<?xml version="1.0" encoding="utf-8"?>
<device xmlns:xs="http://www.w3.org/2001/XMLSchema-instance" schemaVersion="1.3" xs:noNamespaceSchemaLocation="CMSIS-SVD.xsd">
    <vendor>Renesas Electronics Corporation</vendor>
    <vendorID>Renesas</vendorID>
    <name>R7FA8D1BH</name>
    <series>RA8</series>
    <version>1.20.02</version>
    <description>Arm Cortex-M85 based Microcontroller RA8M1group</description>
    <licenseText>This software is supplied by Renesas Electronics Corporation and is only intended for \n
use with Renesas products. No other uses are authorized. This software is owned by \n
Renesas Electronics Corporation and is protected under all applicable laws, including \n
copyright laws. \n
\n
THIS SOFTWARE IS PROVIDED "AS IS" AND RENESAS MAKES NO WARRANTIES REGARDING \n
THIS SOFTWARE, WHETHER EXPRESS, IMPLIED OR STATUTORY, INCLUDING BUT NOT LIMITED TO \n
WARRANTIES OF MERCHANTABILITY, FITNESS FOR A PARTICULAR PURPOSE AND NON-INFRINGEMENT. \n
ALL SUCH WARRANTIES ARE EXPRESSLY DISCLAIMED. TO THE MAXIMUM EXTENT PERMITTED NOT \n
PROHIBITED BY LAW, NEITHER RENESAS ELECTRONICS CORPORATION NOR ANY OF ITS AFFILIATED \n
COMPANIES SHALL BE LIABLE FOR ANY DIRECT, INDIRECT, SPECIAL, INCIDENTAL OR CONSEQUENTIAL \n
DAMAGES FOR ANY REASON RELATED TO THIS SOFTWARE, EVEN IF RENESAS OR ITS AFFILIATES HAVE \n
BEEN ADVISED OF THE POSSIBILITY OF SUCH DAMAGES. \n
\n
Renesas reserves the right, without notice, to make changes to this software and to \n
discontinue the availability of this software. By using this software, you agree to \n
the additional terms and conditions found by accessing the following link: \n
http://www.renesas.com/disclaimer \n
\n</licenseText>
    <cpu>
        <name>CM85</name>
        <revision>r0p2</revision>
        <endian>little</endian>
        <mpuPresent>true</mpuPresent>
        <fpuPresent>true</fpuPresent>
        <vtorPresent>true</vtorPresent>
        <nvicPrioBits>4</nvicPrioBits>
        <vendorSystickConfig>false</vendorSystickConfig>
        <deviceNumInterrupts>96</deviceNumInterrupts>
    </cpu>
    <headerSystemFilename>system_RA8</headerSystemFilename>
    <addressUnitBits>8</addressUnitBits>
    <width>32</width>
    <size>32</size>
    <access>read-write</access>
    <resetValue>0</resetValue>
    <resetMask>0xffffffff</resetMask>
    <peripherals>
        <peripheral>
            <name>RMPU</name>
            <description>Renesas Memory Protection Unit</description>
            <baseAddress>0x40000000</baseAddress>
            <addressBlock>
                <offset>0x00</offset>
                <size>2</size>
                <usage>registers</usage>
            </addressBlock>
            <addressBlock>
                <offset>0x04</offset>
                <size>2</size>
                <usage>registers</usage>
            </addressBlock>
            <addressBlock>
                <offset>0x100</offset>
                <size>2</size>
                <usage>registers</usage>
            </addressBlock>
            <addressBlock>
                <offset>0x104</offset>
                <size>2</size>
                <usage>registers</usage>
            </addressBlock>
            <addressBlock>
                <offset>0x10C</offset>
                <size>2</size>
                <usage>registers</usage>
            </addressBlock>
            <addressBlock>
                <offset>0x200</offset>
                <size>136</size>
                <usage>registers</usage>
            </addressBlock>
            <addressBlock>
                <offset>0x500</offset>
                <size>2</size>
                <usage>registers</usage>
            </addressBlock>
            <addressBlock>
                <offset>0x504</offset>
                <size>2</size>
                <usage>registers</usage>
            </addressBlock>
            <addressBlock>
                <offset>0x508</offset>
                <size>2</size>
                <usage>registers</usage>
            </addressBlock>
            <addressBlock>
                <offset>0x600</offset>
                <size>72</size>
                <usage>registers</usage>
            </addressBlock>
            <addressBlock>
                <offset>0x700</offset>
                <size>2</size>
                <usage>registers</usage>
            </addressBlock>
            <addressBlock>
                <offset>0x704</offset>
                <size>2</size>
                <usage>registers</usage>
            </addressBlock>
            <addressBlock>
                <offset>0x708</offset>
                <size>2</size>
                <usage>registers</usage>
            </addressBlock>
            <addressBlock>
                <offset>0x800</offset>
                <size>40</size>
                <usage>registers</usage>
            </addressBlock>
            <addressBlock>
                <offset>0x900</offset>
                <size>2</size>
                <usage>registers</usage>
            </addressBlock>
            <addressBlock>
                <offset>0x904</offset>
                <size>2</size>
                <usage>registers</usage>
            </addressBlock>
            <addressBlock>
                <offset>0x908</offset>
                <size>2</size>
                <usage>registers</usage>
            </addressBlock>
            <addressBlock>
                <offset>0xA00</offset>
                <size>56</size>
                <usage>registers</usage>
            </addressBlock>
            <addressBlock>
                <offset>0xB00</offset>
                <size>2</size>
                <usage>registers</usage>
            </addressBlock>
            <addressBlock>
                <offset>0xB04</offset>
                <size>2</size>
                <usage>registers</usage>
            </addressBlock>
            <addressBlock>
                <offset>0xB08</offset>
                <size>2</size>
                <usage>registers</usage>
            </addressBlock>
            <addressBlock>
                <offset>0xC00</offset>
                <size>2</size>
                <usage>registers</usage>
            </addressBlock>
            <addressBlock>
                <offset>0xC04</offset>
                <size>8</size>
                <usage>registers</usage>
            </addressBlock>
            <addressBlock>
                <offset>0xD00</offset>
                <size>2</size>
                <usage>registers</usage>
            </addressBlock>
            <addressBlock>
                <offset>0xD04</offset>
                <size>2</size>
                <usage>registers</usage>
            </addressBlock>
            <addressBlock>
                <offset>0xD08</offset>
                <size>2</size>
                <usage>registers</usage>
            </addressBlock>
            <addressBlock>
                <offset>0xE00</offset>
                <size>40</size>
                <usage>registers</usage>
            </addressBlock>
            <registers>
                <register>
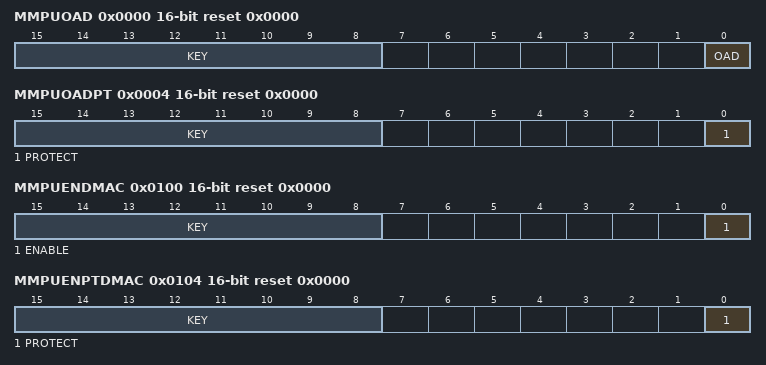
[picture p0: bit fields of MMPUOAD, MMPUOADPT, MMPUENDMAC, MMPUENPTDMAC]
                    <name>MMPUOAD</name>
                    <description>MMPU Operation After Detection Register</description>
                    <addressOffset>0x0000</addressOffset>
                    <size>16</size>
                    <access>read-write</access>
                    <resetValue>0x0000</resetValue>
                    <resetMask>0xffff</resetMask>
                    <fields>
                        <field>
                            <name>OAD</name>
                            <description>Operation after detection</description>
                            <lsb>0</lsb>
                            <msb>0</msb>
                            <access>read-write</access>
                            <enumeratedValues>
                                <enumeratedValue>
                                    <name>0</name>
                                    <description>NMI</description>
                                    <value>#0</value>
                                </enumeratedValue>
                                <enumeratedValue>
                                    <name>1</name>
                                    <description>Reset</description>
                                    <value>#1</value>
                                </enumeratedValue>
                            </enumeratedValues>
                        </field>
                        <field>
                            <name>KEY</name>
                            <description>Key Code</description>
                            <lsb>8</lsb>
                            <msb>15</msb>
                            <access>read-write</access>
                        </field>
                    </fields>
                </register>
                <register>
                    <name>MMPUOADPT</name>
                    <description>MMPU Operation After Detection Protect Register</description>
                    <addressOffset>0x0004</addressOffset>
                    <size>16</size>
                    <access>read-write</access>
                    <resetValue>0x0000</resetValue>
                    <resetMask>0xffff</resetMask>
                    <fields>
                        <field>
                            <name>PROTECT</name>
                            <description>Protection of register</description>
                            <lsb>0</lsb>
                            <msb>0</msb>
                            <access>read-write</access>
                            <enumeratedValues>
                                <enumeratedValue>
                                    <name>0</name>
                                    <description>MMPUOAD register writing is possible.</description>
                                    <value>#0</value>
                                </enumeratedValue>
                                <enumeratedValue>
                                    <name>1</name>
                                    <description>MMPUOAD register writing is protected. Read is possible.</description>
                                    <value>#1</value>
                                </enumeratedValue>
                            </enumeratedValues>
                        </field>
                        <field>
                            <name>KEY</name>
                            <description>Key Code</description>
                            <lsb>8</lsb>
                            <msb>15</msb>
                            <access>write-only</access>
                        </field>
                    </fields>
                </register>
                <register>
                    <name>MMPUENDMAC</name>
                    <description>MMPU Enable Register for DMAC</description>
                    <addressOffset>0x0100</addressOffset>
                    <size>16</size>
                    <access>read-write</access>
                    <resetValue>0x0000</resetValue>
                    <resetMask>0xffff</resetMask>
                    <fields>
                        <field>
                            <name>ENABLE</name>
                            <description>Bus master MPU of DMAC Enable</description>
                            <lsb>0</lsb>
                            <msb>0</msb>
                            <access>read-write</access>
                            <enumeratedValues>
                                <enumeratedValue>
                                    <name>0</name>
                                    <description>Bus master MPU of DMAC is disabled.</description>
                                    <value>#0</value>
                                </enumeratedValue>
                                <enumeratedValue>
                                    <name>1</name>
                                    <description>Bus master MPU of DMAC is enabled.</description>
                                    <value>#1</value>
                                </enumeratedValue>
                            </enumeratedValues>
                        </field>
                        <field>
                            <name>KEY</name>
                            <description>Key Code</description>
                            <lsb>8</lsb>
                            <msb>15</msb>
                            <access>write-only</access>
                        </field>
                    </fields>
                </register>
                <register>
                    <name>MMPUENPTDMAC</name>
                    <description>MMPU Enable Protect Register for DMAC</description>
                    <addressOffset>0x0104</addressOffset>
                    <size>16</size>
                    <access>read-write</access>
                    <resetValue>0x0000</resetValue>
                    <resetMask>0xffff</resetMask>
                    <fields>
                        <field>
                            <name>PROTECT</name>
                            <description>Protection of register</description>
                            <lsb>0</lsb>
                            <msb>0</msb>
                            <access>read-write</access>
                            <enumeratedValues>
                                <enumeratedValue>
                                    <name>0</name>
                                    <description>MMPUENDMAC register write is possible.</description>
                                    <value>#0</value>
                                </enumeratedValue>
                                <enumeratedValue>
                                    <name>1</name>
                                    <description>MMPUENDMAC register write is protected. Read is possible.</description>
                                    <value>#1</value>
                                </enumeratedValue>
                            </enumeratedValues>
                        </field>
                        <field>
                            <name>KEY</name>
                            <description>Key Code</description>
                            <lsb>8</lsb>
                            <msb>15</msb>
                            <access>write-only</access>
                        </field>
                    </fields>
                </register>
                <register>
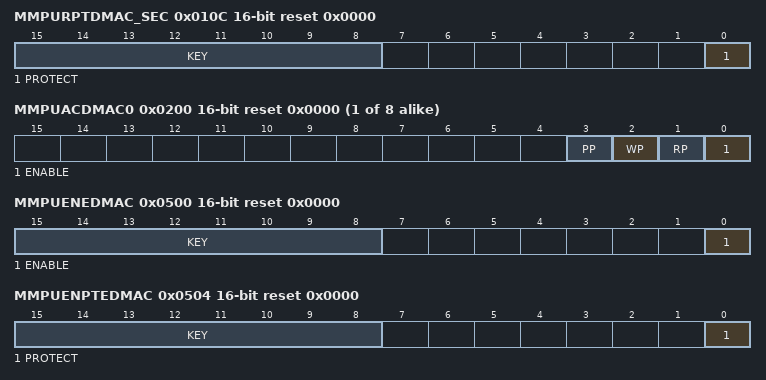
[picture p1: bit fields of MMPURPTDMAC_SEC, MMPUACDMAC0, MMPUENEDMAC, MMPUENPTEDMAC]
                    <name>MMPURPTDMAC_SEC</name>
                    <description>MMPU Regions Protect register for DMAC Secure</description>
                    <addressOffset>0x010C</addressOffset>
                    <size>16</size>
                    <access>read-write</access>
                    <resetValue>0x0000</resetValue>
                    <resetMask>0xffff</resetMask>
                    <fields>
                        <field>
                            <name>PROTECT</name>
                            <description>Protection of register</description>
                            <lsb>0</lsb>
                            <msb>0</msb>
                            <access>read-write</access>
                            <enumeratedValues>
                                <enumeratedValue>
                                    <name>0</name>
                                    <description>Bus master MPU register for DMAC Secure write is possible.</description>
                                    <value>#0</value>
                                </enumeratedValue>
                                <enumeratedValue>
                                    <name>1</name>
                                    <description>Bus master MPU register for DMAC Secure write is protected. Read is possible.</description>
                                    <value>#1</value>
                                </enumeratedValue>
                            </enumeratedValues>
                        </field>
                        <field>
                            <name>KEY</name>
                            <description>Key Code</description>
                            <lsb>8</lsb>
                            <msb>15</msb>
                            <access>write-only</access>
                        </field>
                    </fields>
                </register>
                <register>
                    <dim>8</dim>
                    <dimIncrement>0x010</dimIncrement>
                    <dimIndex>0-7</dimIndex>
                    <name>MMPUACDMAC%s</name>
                    <description>MMPU Access Control Register for DMAC (n = 0 to 7)</description>
                    <addressOffset>0x0200</addressOffset>
                    <size>16</size>
                    <access>read-write</access>
                    <resetValue>0x0000</resetValue>
                    <resetMask>0xffff</resetMask>
                    <fields>
                        <field>
                            <name>ENABLE</name>
                            <description>Region Enable</description>
                            <lsb>0</lsb>
                            <msb>0</msb>
                            <access>read-write</access>
                            <enumeratedValues>
                                <enumeratedValue>
                                    <name>0</name>
                                    <description>DMAC region n unit is disabled.</description>
                                    <value>#0</value>
                                </enumeratedValue>
                                <enumeratedValue>
                                    <name>1</name>
                                    <description>DMAC region n unit is enabled.</description>
                                    <value>#1</value>
                                </enumeratedValue>
                            </enumeratedValues>
                        </field>
                        <field>
                            <name>RP</name>
                            <description>Read protection</description>
                            <lsb>1</lsb>
                            <msb>1</msb>
                            <access>read-write</access>
                            <enumeratedValues>
                                <enumeratedValue>
                                    <name>0</name>
                                    <description>Read permission</description>
                                    <value>#0</value>
                                </enumeratedValue>
                                <enumeratedValue>
                                    <name>1</name>
                                    <description>Read protection</description>
                                    <value>#1</value>
                                </enumeratedValue>
                            </enumeratedValues>
                        </field>
                        <field>
                            <name>WP</name>
                            <description>Write protection</description>
                            <lsb>2</lsb>
                            <msb>2</msb>
                            <access>read-write</access>
                            <enumeratedValues>
                                <enumeratedValue>
                                    <name>0</name>
                                    <description>Write permission</description>
                                    <value>#0</value>
                                </enumeratedValue>
                                <enumeratedValue>
                                    <name>1</name>
                                    <description>Write protection</description>
                                    <value>#1</value>
                                </enumeratedValue>
                            </enumeratedValues>
                        </field>
                        <field>
                            <name>PP</name>
                            <description>Privilege protection</description>
                            <lsb>3</lsb>
                            <msb>3</msb>
                            <access>read-write</access>
                            <enumeratedValues>
                                <enumeratedValue>
                                    <name>0</name>
                                    <description>Unprivileged access permission</description>
                                    <value>#0</value>
                                </enumeratedValue>
                                <enumeratedValue>
                                    <name>1</name>
                                    <description>Unprivileged access protection</description>
                                    <value>#1</value>
                                </enumeratedValue>
                            </enumeratedValues>
                        </field>
                    </fields>
                </register>
                <register>
                    <dim>8</dim>
                    <dimIncrement>0x010</dimIncrement>
                    <dimIndex>0-7</dimIndex>
                    <name>MMPUSDMAC%s</name>
                    <description>MMPU Start Address Register for DMAC (n = 0 to 7)</description>
                    <addressOffset>0x0204</addressOffset>
                    <size>32</size>
                    <access>read-write</access>
                    <resetValue>0x00000000</resetValue>
                    <resetMask>0x0000001f</resetMask>
                </register>
                <register>
                    <dim>8</dim>
                    <dimIncrement>0x010</dimIncrement>
                    <dimIndex>0-7</dimIndex>
                    <name>MMPUEDMAC%s</name>
                    <description>MMPU End Address Register for DMAC (n = 0 to 7)</description>
                    <addressOffset>0x0208</addressOffset>
                    <size>32</size>
                    <access>read-write</access>
                    <resetValue>0x0000001f</resetValue>
                    <resetMask>0x0000001f</resetMask>
                </register>
                <register>
                    <name>MMPUENEDMAC</name>
                    <description>MMPU Enable Register for EDMAC</description>
                    <addressOffset>0x0500</addressOffset>
                    <size>16</size>
                    <access>read-write</access>
                    <resetValue>0x0000</resetValue>
                    <resetMask>0xffff</resetMask>
                    <fields>
                        <field>
                            <name>ENABLE</name>
                            <description>Bus master MPU of EDMAC Enable</description>
                            <lsb>0</lsb>
                            <msb>0</msb>
                            <access>read-write</access>
                            <enumeratedValues>
                                <enumeratedValue>
                                    <name>0</name>
                                    <description>Bus master MPU of EDMAC is disabled.</description>
                                    <value>#0</value>
                                </enumeratedValue>
                                <enumeratedValue>
                                    <name>1</name>
                                    <description>Bus master MPU of EDMAC is enabled.</description>
                                    <value>#1</value>
                                </enumeratedValue>
                            </enumeratedValues>
                        </field>
                        <field>
                            <name>KEY</name>
                            <description>Key Code</description>
                            <lsb>8</lsb>
                            <msb>15</msb>
                            <access>write-only</access>
                        </field>
                    </fields>
                </register>
                <register>
                    <name>MMPUENPTEDMAC</name>
                    <description>MMPU Enable Protect Register for EDMAC</description>
                    <addressOffset>0x0504</addressOffset>
                    <size>16</size>
                    <access>read-write</access>
                    <resetValue>0x0000</resetValue>
                    <resetMask>0xffff</resetMask>
                    <fields>
                        <field>
                            <name>PROTECT</name>
                            <description>Protection of register</description>
                            <lsb>0</lsb>
                            <msb>0</msb>
                            <access>read-write</access>
                            <enumeratedValues>
                                <enumeratedValue>
                                    <name>0</name>
                                    <description>MMPUENEDMAC register write is possible.</description>
                                    <value>#0</value>
                                </enumeratedValue>
                                <enumeratedValue>
                                    <name>1</name>
                                    <description>MMPUENEDMAC register write is protected. Read is possible.</description>
                                    <value>#1</value>
                                </enumeratedValue>
                            </enumeratedValues>
                        </field>
                        <field>
                            <name>KEY</name>
                            <description>Key Code</description>
                            <lsb>8</lsb>
                            <msb>15</msb>
                            <access>write-only</access>
                        </field>
                    </fields>
                </register>
                <register>
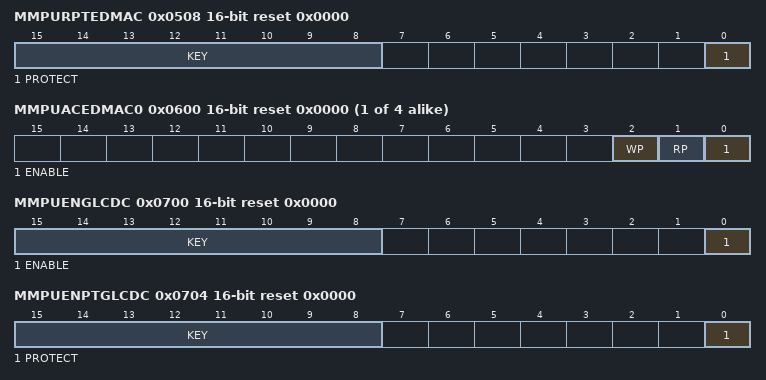
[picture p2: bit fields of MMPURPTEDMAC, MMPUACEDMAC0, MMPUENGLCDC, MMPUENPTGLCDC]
                    <name>MMPURPTEDMAC</name>
                    <description>MMPU Regions Protect Register for EDMAC</description>
                    <addressOffset>0x0508</addressOffset>
                    <size>16</size>
                    <access>read-write</access>
                    <resetValue>0x0000</resetValue>
                    <resetMask>0xffff</resetMask>
                    <fields>
                        <field>
                            <name>PROTECT</name>
                            <description>Protection of register</description>
                            <lsb>0</lsb>
                            <msb>0</msb>
                            <access>read-write</access>
                            <enumeratedValues>
                                <enumeratedValue>
                                    <name>0</name>
                                    <description>Bus master MPU register for EDMAC write is possible.</description>
                                    <value>#0</value>
                                </enumeratedValue>
                                <enumeratedValue>
                                    <name>1</name>
                                    <description>Bus master MPU register for EDMAC write is protected. Read is possible.</description>
                                    <value>#1</value>
                                </enumeratedValue>
                            </enumeratedValues>
                        </field>
                        <field>
                            <name>KEY</name>
                            <description>Key Code</description>
                            <lsb>8</lsb>
                            <msb>15</msb>
                            <access>write-only</access>
                        </field>
                    </fields>
                </register>
                <register>
                    <dim>4</dim>
                    <dimIncrement>0x010</dimIncrement>
                    <dimIndex>0-3</dimIndex>
                    <name>MMPUACEDMAC%s</name>
                    <description>MMPU Access Control Register for EDMAC (n = 0 to 3)</description>
                    <addressOffset>0x0600</addressOffset>
                    <size>16</size>
                    <access>read-write</access>
                    <resetValue>0x0000</resetValue>
                    <resetMask>0xffff</resetMask>
                    <fields>
                        <field>
                            <name>ENABLE</name>
                            <description>Region Enable</description>
                            <lsb>0</lsb>
                            <msb>0</msb>
                            <access>read-write</access>
                            <enumeratedValues>
                                <enumeratedValue>
                                    <name>0</name>
                                    <description>EDMAC region n unit is disabled.</description>
                                    <value>#0</value>
                                </enumeratedValue>
                                <enumeratedValue>
                                    <name>1</name>
                                    <description>EDMAC region n unit is enabled.</description>
                                    <value>#1</value>
                                </enumeratedValue>
                            </enumeratedValues>
                        </field>
                        <field>
                            <name>RP</name>
                            <description>Read protection</description>
                            <lsb>1</lsb>
                            <msb>1</msb>
                            <access>read-write</access>
                            <enumeratedValues>
                                <enumeratedValue>
                                    <name>0</name>
                                    <description>Read permission</description>
                                    <value>#0</value>
                                </enumeratedValue>
                                <enumeratedValue>
                                    <name>1</name>
                                    <description>Read protection</description>
                                    <value>#1</value>
                                </enumeratedValue>
                            </enumeratedValues>
                        </field>
                        <field>
                            <name>WP</name>
                            <description>Write protection</description>
                            <lsb>2</lsb>
                            <msb>2</msb>
                            <access>read-write</access>
                            <enumeratedValues>
                                <enumeratedValue>
                                    <name>0</name>
                                    <description>Write permission</description>
                                    <value>#0</value>
                                </enumeratedValue>
                                <enumeratedValue>
                                    <name>1</name>
                                    <description>Write protection</description>
                                    <value>#1</value>
                                </enumeratedValue>
                            </enumeratedValues>
                        </field>
                    </fields>
                </register>
                <register>
                    <dim>4</dim>
                    <dimIncrement>0x010</dimIncrement>
                    <dimIndex>0-3</dimIndex>
                    <name>MMPUSEDMAC%s</name>
                    <description>MMPU Start Address Register for EDMAC (n = 0 to 3)</description>
                    <addressOffset>0x0604</addressOffset>
                    <size>32</size>
                    <access>read-write</access>
                    <resetValue>0x00000000</resetValue>
                    <resetMask>0x0000001f</resetMask>
                </register>
                <register>
                    <dim>4</dim>
                    <dimIncrement>0x010</dimIncrement>
                    <dimIndex>0-3</dimIndex>
                    <name>MMPUEEDMAC%s</name>
                    <description>MMPU End Address Register for EDMAC (n = 0 to 3)</description>
                    <addressOffset>0x0608</addressOffset>
                    <size>32</size>
                    <access>read-write</access>
                    <resetValue>0x0000001f</resetValue>
                    <resetMask>0x0000001f</resetMask>
                </register>
                <register>
                    <name>MMPUENGLCDC</name>
                    <description>MMPU Enable Register for GLCDC</description>
                    <addressOffset>0x0700</addressOffset>
                    <size>16</size>
                    <access>read-write</access>
                    <resetValue>0x0000</resetValue>
                    <resetMask>0xffff</resetMask>
                    <fields>
                        <field>
                            <name>ENABLE</name>
                            <description>Bus master MPU of GLCDC Enable</description>
                            <lsb>0</lsb>
                            <msb>0</msb>
                            <access>read-write</access>
                            <enumeratedValues>
                                <enumeratedValue>
                                    <name>0</name>
                                    <description>Bus master MPU of GLCDC is disabled.</description>
                                    <value>#0</value>
                                </enumeratedValue>
                                <enumeratedValue>
                                    <name>1</name>
                                    <description>Bus master MPU of GLCDC is enabled.</description>
                                    <value>#1</value>
                                </enumeratedValue>
                            </enumeratedValues>
                        </field>
                        <field>
                            <name>KEY</name>
                            <description>Key Code</description>
                            <lsb>8</lsb>
                            <msb>15</msb>
                            <access>write-only</access>
                        </field>
                    </fields>
                </register>
                <register>
                    <name>MMPUENPTGLCDC</name>
                    <description>MMPU Enable Protect Register for GLCDC</description>
                    <addressOffset>0x0704</addressOffset>
                    <size>16</size>
                    <access>read-write</access>
                    <resetValue>0x0000</resetValue>
                    <resetMask>0xffff</resetMask>
                    <fields>
                        <field>
                            <name>PROTECT</name>
                            <description>Protection of register</description>
                            <lsb>0</lsb>
                            <msb>0</msb>
                            <access>read-write</access>
                            <enumeratedValues>
                                <enumeratedValue>
                                    <name>0</name>
                                    <description>MMPUENGLCDC register write is possible.</description>
                                    <value>#0</value>
                                </enumeratedValue>
                                <enumeratedValue>
                                    <name>1</name>
                                    <description>MMPUENGLCDC register write is protected. Read is possible.</description>
                                    <value>#1</value>
                                </enumeratedValue>
                            </enumeratedValues>
                        </field>
                        <field>
                            <name>KEY</name>
                            <description>Key Code</description>
                            <lsb>8</lsb>
                            <msb>15</msb>
                            <access>write-only</access>
                        </field>
                    </fields>
                </register>
                <register>
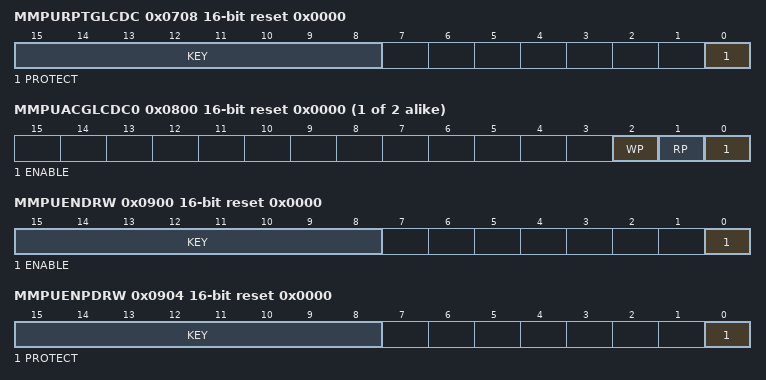
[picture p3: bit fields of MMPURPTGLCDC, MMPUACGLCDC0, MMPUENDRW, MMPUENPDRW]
                    <name>MMPURPTGLCDC</name>
                    <description>MMPU Regions Protect Register for GLCDC</description>
                    <addressOffset>0x0708</addressOffset>
                    <size>16</size>
                    <access>read-write</access>
                    <resetValue>0x0000</resetValue>
                    <resetMask>0xffff</resetMask>
                    <fields>
                        <field>
                            <name>PROTECT</name>
                            <description>Protection of register</description>
                            <lsb>0</lsb>
                            <msb>0</msb>
                            <access>read-write</access>
                            <enumeratedValues>
                                <enumeratedValue>
                                    <name>0</name>
                                    <description>Bus master MPU register for GLCDC write is possible.</description>
                                    <value>#0</value>
                                </enumeratedValue>
                                <enumeratedValue>
                                    <name>1</name>
                                    <description>Bus master MPU register for GLCDC write is protected. Read is possible.</description>
                                    <value>#1</value>
                                </enumeratedValue>
                            </enumeratedValues>
                        </field>
                        <field>
                            <name>KEY</name>
                            <description>Key Code</description>
                            <lsb>8</lsb>
                            <msb>15</msb>
                            <access>write-only</access>
                        </field>
                    </fields>
                </register>
                <register>
                    <dim>2</dim>
                    <dimIncrement>0x010</dimIncrement>
                    <dimIndex>0-1</dimIndex>
                    <name>MMPUACGLCDC%s</name>
                    <description>MMPU Access Control Register for GLCDC (n = 0, 1)</description>
                    <addressOffset>0x0800</addressOffset>
                    <size>16</size>
                    <access>read-write</access>
                    <resetValue>0x0000</resetValue>
                    <resetMask>0xffff</resetMask>
                    <fields>
                        <field>
                            <name>ENABLE</name>
                            <description>Region Enable</description>
                            <lsb>0</lsb>
                            <msb>0</msb>
                            <access>read-write</access>
                            <enumeratedValues>
                                <enumeratedValue>
                                    <name>0</name>
                                    <description>GLCDC region n unit is disabled.</description>
                                    <value>#0</value>
                                </enumeratedValue>
                                <enumeratedValue>
                                    <name>1</name>
                                    <description>GLCDC region n unit is enabled.</description>
                                    <value>#1</value>
                                </enumeratedValue>
                            </enumeratedValues>
                        </field>
                        <field>
                            <name>RP</name>
                            <description>Read protection</description>
                            <lsb>1</lsb>
                            <msb>1</msb>
                            <access>read-write</access>
                            <enumeratedValues>
                                <enumeratedValue>
                                    <name>0</name>
                                    <description>Read permission</description>
                                    <value>#0</value>
                                </enumeratedValue>
                                <enumeratedValue>
                                    <name>1</name>
                                    <description>Read protection</description>
                                    <value>#1</value>
                                </enumeratedValue>
                            </enumeratedValues>
                        </field>
                        <field>
                            <name>WP</name>
                            <description>Write protection</description>
                            <lsb>2</lsb>
                            <msb>2</msb>
                            <access>read-write</access>
                            <enumeratedValues>
                                <enumeratedValue>
                                    <name>0</name>
                                    <description>Write permission</description>
                                    <value>#0</value>
                                </enumeratedValue>
                                <enumeratedValue>
                                    <name>1</name>
                                    <description>Write protection</description>
                                    <value>#1</value>
                                </enumeratedValue>
                            </enumeratedValues>
                        </field>
                    </fields>
                </register>
                <register>
                    <dim>2</dim>
                    <dimIncrement>0x010</dimIncrement>
                    <dimIndex>0-1</dimIndex>
                    <name>MMPUSGLCDC%s</name>
                    <description>MMPU Start Address Register for GLCDC (n = 0, 1)</description>
                    <addressOffset>0x0804</addressOffset>
                    <size>32</size>
                    <access>read-write</access>
                    <resetValue>0x00000000</resetValue>
                    <resetMask>0x000001ff</resetMask>
                </register>
                <register>
                    <dim>2</dim>
                    <dimIncrement>0x010</dimIncrement>
                    <dimIndex>0-1</dimIndex>
                    <name>MMPUEGLCDC%s</name>
                    <description>MMPU End Address Register for GLCDC (n = 0 to 1)</description>
                    <addressOffset>0x0808</addressOffset>
                    <size>32</size>
                    <access>read-write</access>
                    <resetValue>0x000003ff</resetValue>
                    <resetMask>0x000003ff</resetMask>
                </register>
                <register>
                    <name>MMPUENDRW</name>
                    <description>MMPU Enable Register for DRW</description>
                    <addressOffset>0x0900</addressOffset>
                    <size>16</size>
                    <access>read-write</access>
                    <resetValue>0x0000</resetValue>
                    <resetMask>0xffff</resetMask>
                    <fields>
                        <field>
                            <name>ENABLE</name>
                            <description>Bus master MPU of DRW Enable</description>
                            <lsb>0</lsb>
                            <msb>0</msb>
                            <access>read-write</access>
                            <enumeratedValues>
                                <enumeratedValue>
                                    <name>0</name>
                                    <description>Bus master MPU of DRW is disabled.</description>
                                    <value>#0</value>
                                </enumeratedValue>
                                <enumeratedValue>
                                    <name>1</name>
                                    <description>Bus master MPU of DRW is enabled.</description>
                                    <value>#1</value>
                                </enumeratedValue>
                            </enumeratedValues>
                        </field>
                        <field>
                            <name>KEY</name>
                            <description>Key Code</description>
                            <lsb>8</lsb>
                            <msb>15</msb>
                            <access>write-only</access>
                        </field>
                    </fields>
                </register>
                <register>
                    <name>MMPUENPDRW</name>
                    <description>MMPU Enable Protect Register for DRW</description>
                    <addressOffset>0x0904</addressOffset>
                    <size>16</size>
                    <access>read-write</access>
                    <resetValue>0x0000</resetValue>
                    <resetMask>0xffff</resetMask>
                    <fields>
                        <field>
                            <name>PROTECT</name>
                            <description>Protection of register</description>
                            <lsb>0</lsb>
                            <msb>0</msb>
                            <access>read-write</access>
                            <enumeratedValues>
                                <enumeratedValue>
                                    <name>0</name>
                                    <description>MMPUENDRW register write is possible.</description>
                                    <value>#0</value>
                                </enumeratedValue>
                                <enumeratedValue>
                                    <name>1</name>
                                    <description>MMPUENDRW register write is protected. Read is possible.</description>
                                    <value>#1</value>
                                </enumeratedValue>
                            </enumeratedValues>
                        </field>
                        <field>
                            <name>KEY</name>
                            <description>Key Code</description>
                            <lsb>8</lsb>
                            <msb>15</msb>
                            <access>write-only</access>
                        </field>
                    </fields>
                </register>
                <register>
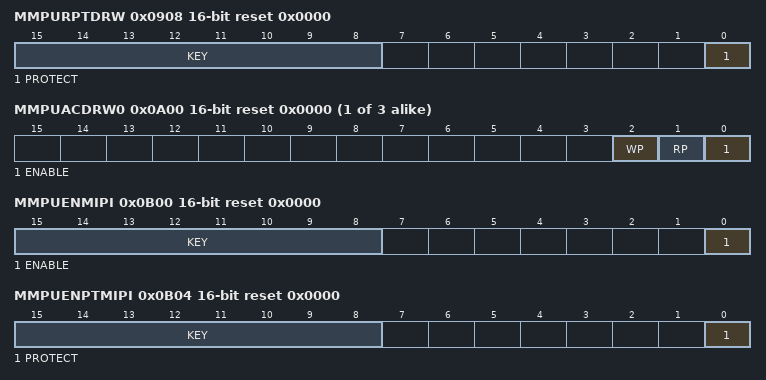
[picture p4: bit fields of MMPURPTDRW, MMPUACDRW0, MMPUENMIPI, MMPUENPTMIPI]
                    <name>MMPURPTDRW</name>
                    <description>MMPU Regions Protect Register for DRW</description>
                    <addressOffset>0x0908</addressOffset>
                    <size>16</size>
                    <access>read-write</access>
                    <resetValue>0x0000</resetValue>
                    <resetMask>0xffff</resetMask>
                    <fields>
                        <field>
                            <name>PROTECT</name>
                            <description>Protection of register</description>
                            <lsb>0</lsb>
                            <msb>0</msb>
                            <access>read-write</access>
                            <enumeratedValues>
                                <enumeratedValue>
                                    <name>0</name>
                                    <description>Bus master MPU register for DRW write is possible.</description>
                                    <value>#0</value>
                                </enumeratedValue>
                                <enumeratedValue>
                                    <name>1</name>
                                    <description>Bus master MPU register for DRW write is protected. Read is possible.</description>
                                    <value>#1</value>
                                </enumeratedValue>
                            </enumeratedValues>
                        </field>
                        <field>
                            <name>KEY</name>
                            <description>Key Code</description>
                            <lsb>8</lsb>
                            <msb>15</msb>
                            <access>write-only</access>
                        </field>
                    </fields>
                </register>
                <register>
                    <dim>3</dim>
                    <dimIncrement>0x010</dimIncrement>
                    <dimIndex>0-2</dimIndex>
                    <name>MMPUACDRW%s</name>
                    <description>MMPU Access Control Register for DRW (n = 0 to 2)</description>
                    <addressOffset>0x0A00</addressOffset>
                    <size>16</size>
                    <access>read-write</access>
                    <resetValue>0x0000</resetValue>
                    <resetMask>0xffff</resetMask>
                    <fields>
                        <field>
                            <name>ENABLE</name>
                            <description>Region Enable</description>
                            <lsb>0</lsb>
                            <msb>0</msb>
                            <access>read-write</access>
                            <enumeratedValues>
                                <enumeratedValue>
                                    <name>0</name>
                                    <description>DRW region n unit is disabled.</description>
                                    <value>#0</value>
                                </enumeratedValue>
                                <enumeratedValue>
                                    <name>1</name>
                                    <description>DRW region n unit is enabled.</description>
                                    <value>#1</value>
                                </enumeratedValue>
                            </enumeratedValues>
                        </field>
                        <field>
                            <name>RP</name>
                            <description>Read protection</description>
                            <lsb>1</lsb>
                            <msb>1</msb>
                            <access>read-write</access>
                            <enumeratedValues>
                                <enumeratedValue>
                                    <name>0</name>
                                    <description>Read permission</description>
                                    <value>#0</value>
                                </enumeratedValue>
                                <enumeratedValue>
                                    <name>1</name>
                                    <description>Read protection</description>
                                    <value>#1</value>
                                </enumeratedValue>
                            </enumeratedValues>
                        </field>
                        <field>
                            <name>WP</name>
                            <description>Write protection</description>
                            <lsb>2</lsb>
                            <msb>2</msb>
                            <access>read-write</access>
                            <enumeratedValues>
                                <enumeratedValue>
                                    <name>0</name>
                                    <description>Write permission</description>
                                    <value>#0</value>
                                </enumeratedValue>
                                <enumeratedValue>
                                    <name>1</name>
                                    <description>Write protection</description>
                                    <value>#1</value>
                                </enumeratedValue>
                            </enumeratedValues>
                        </field>
                    </fields>
                </register>
                <register>
                    <dim>3</dim>
                    <dimIncrement>0x010</dimIncrement>
                    <dimIndex>0-2</dimIndex>
                    <name>MMPUSDRW%s</name>
                    <description>MMPU Start Address Register for DRW (n = 0 to 2)</description>
                    <addressOffset>0x0A04</addressOffset>
                    <size>32</size>
                    <access>read-write</access>
                    <resetValue>0x00000000</resetValue>
                    <resetMask>0x000003ff</resetMask>
                </register>
                <register>
                    <dim>3</dim>
                    <dimIncrement>0x010</dimIncrement>
                    <dimIndex>0-2</dimIndex>
                    <name>MMPUEDRW%s</name>
                    <description>MMPU End Address Register for DRW (n = 0 to 2)</description>
                    <addressOffset>0x0A08</addressOffset>
                    <size>32</size>
                    <access>read-write</access>
                    <resetValue>0x000003ff</resetValue>
                    <resetMask>0x000003ff</resetMask>
                </register>
                <register>
                    <name>MMPUENMIPI</name>
                    <description>MMPU Enable Register for MIPI DSI</description>
                    <addressOffset>0x0B00</addressOffset>
                    <size>16</size>
                    <access>read-write</access>
                    <resetValue>0x0000</resetValue>
                    <resetMask>0xffff</resetMask>
                    <fields>
                        <field>
                            <name>ENABLE</name>
                            <description>Bus master MPU of MIPI DSI Enable</description>
                            <lsb>0</lsb>
                            <msb>0</msb>
                            <access>read-write</access>
                            <enumeratedValues>
                                <enumeratedValue>
                                    <name>0</name>
                                    <description>Bus master MPU of MIPI DSI is disabled.</description>
                                    <value>#0</value>
                                </enumeratedValue>
                                <enumeratedValue>
                                    <name>1</name>
                                    <description>Bus master MPU of MIPI DSI is enabled.</description>
                                    <value>#1</value>
                                </enumeratedValue>
                            </enumeratedValues>
                        </field>
                        <field>
                            <name>KEY</name>
                            <description>Key Code</description>
                            <lsb>8</lsb>
                            <msb>15</msb>
                            <access>write-only</access>
                        </field>
                    </fields>
                </register>
                <register>
                    <name>MMPUENPTMIPI</name>
                    <description>MMPU Enable Protect Register for MIPI DSI</description>
                    <addressOffset>0x0B04</addressOffset>
                    <size>16</size>
                    <access>read-write</access>
                    <resetValue>0x0000</resetValue>
                    <resetMask>0xffff</resetMask>
                    <fields>
                        <field>
                            <name>PROTECT</name>
                            <description>Protection of register</description>
                            <lsb>0</lsb>
                            <msb>0</msb>
                            <access>read-write</access>
                            <enumeratedValues>
                                <enumeratedValue>
                                    <name>0</name>
                                    <description>MMPUENMIPI register write is possible.</description>
                                    <value>#0</value>
                                </enumeratedValue>
                                <enumeratedValue>
                                    <name>1</name>
                                    <description>MMPUENMIPI register write is protected. Read is possible.</description>
                                    <value>#1</value>
                                </enumeratedValue>
                            </enumeratedValues>
                        </field>
                        <field>
                            <name>KEY</name>
                            <description>Key Code</description>
                            <lsb>8</lsb>
                            <msb>15</msb>
                            <access>write-only</access>
                        </field>
                    </fields>
                </register>
                <register>
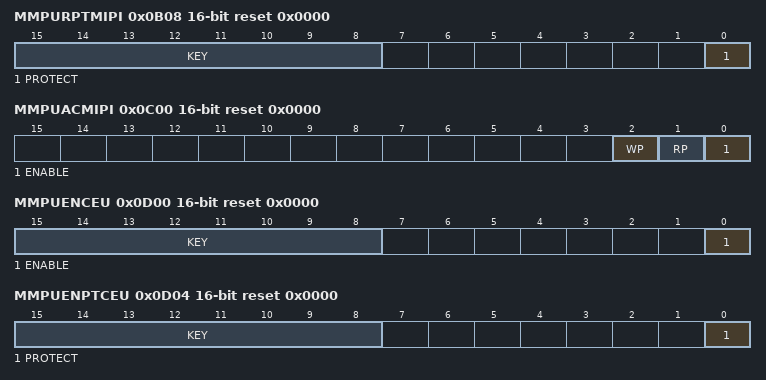
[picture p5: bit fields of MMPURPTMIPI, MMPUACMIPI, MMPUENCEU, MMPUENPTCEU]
                    <name>MMPURPTMIPI</name>
                    <description>MMPU Regions Protect Register for MIPI DSI</description>
                    <addressOffset>0x0B08</addressOffset>
                    <size>16</size>
                    <access>read-write</access>
                    <resetValue>0x0000</resetValue>
                    <resetMask>0xffff</resetMask>
                    <fields>
                        <field>
                            <name>PROTECT</name>
                            <description>Protection of register</description>
                            <lsb>0</lsb>
                            <msb>0</msb>
                            <access>read-write</access>
                            <enumeratedValues>
                                <enumeratedValue>
                                    <name>0</name>
                                    <description>Bus master MPU register for MIPI DSI write is possible.</description>
                                    <value>#0</value>
                                </enumeratedValue>
                                <enumeratedValue>
                                    <name>1</name>
                                    <description>Bus master MPU register for MIPI DSI write is protected. Read is possible.</description>
                                    <value>#1</value>
                                </enumeratedValue>
                            </enumeratedValues>
                        </field>
                        <field>
                            <name>KEY</name>
                            <description>Key Code</description>
                            <lsb>8</lsb>
                            <msb>15</msb>
                            <access>write-only</access>
                        </field>
                    </fields>
                </register>
                <register>
                    <name>MMPUACMIPI</name>
                    <description>MMPU Access Control Register for MIPI DSI</description>
                    <addressOffset>0x0C00</addressOffset>
                    <size>16</size>
                    <access>read-write</access>
                    <resetValue>0x0000</resetValue>
                    <resetMask>0xffff</resetMask>
                    <fields>
                        <field>
                            <name>ENABLE</name>
                            <description>Region Enable</description>
                            <lsb>0</lsb>
                            <msb>0</msb>
                            <access>read-write</access>
                            <enumeratedValues>
                                <enumeratedValue>
                                    <name>0</name>
                                    <description>MIPI DSI region unit is disabled.</description>
                                    <value>#0</value>
                                </enumeratedValue>
                                <enumeratedValue>
                                    <name>1</name>
                                    <description>MIPI DSI region unit is enabled.</description>
                                    <value>#1</value>
                                </enumeratedValue>
                            </enumeratedValues>
                        </field>
                        <field>
                            <name>RP</name>
                            <description>Read protection</description>
                            <lsb>1</lsb>
                            <msb>1</msb>
                            <access>read-write</access>
                            <enumeratedValues>
                                <enumeratedValue>
                                    <name>0</name>
                                    <description>Read permission</description>
                                    <value>#0</value>
                                </enumeratedValue>
                                <enumeratedValue>
                                    <name>1</name>
                                    <description>Read protection</description>
                                    <value>#1</value>
                                </enumeratedValue>
                            </enumeratedValues>
                        </field>
                        <field>
                            <name>WP</name>
                            <description>Write protection</description>
                            <lsb>2</lsb>
                            <msb>2</msb>
                            <access>read-write</access>
                            <enumeratedValues>
                                <enumeratedValue>
                                    <name>0</name>
                                    <description>Write permission</description>
                                    <value>#0</value>
                                </enumeratedValue>
                                <enumeratedValue>
                                    <name>1</name>
                                    <description>Write protection</description>
                                    <value>#1</value>
                                </enumeratedValue>
                            </enumeratedValues>
                        </field>
                    </fields>
                </register>
                <register>
                    <name>MMPUSMIPI</name>
                    <description>MMPU Start Address Register for MIPI DSI</description>
                    <addressOffset>0x0C04</addressOffset>
                    <size>32</size>
                    <access>read-write</access>
                    <resetValue>0x00000000</resetValue>
                    <resetMask>0x00000fff</resetMask>
                </register>
                <register>
                    <name>MMPUEMIPI</name>
                    <description>MMPU End Address Register for MIPI DSI</description>
                    <addressOffset>0x0C08</addressOffset>
                    <size>32</size>
                    <access>read-write</access>
                    <resetValue>0x00000fff</resetValue>
                    <resetMask>0x00000fff</resetMask>
                </register>
                <register>
                    <name>MMPUENCEU</name>
                    <description>MMPU Enable Register for CEU</description>
                    <addressOffset>0x0D00</addressOffset>
                    <size>16</size>
                    <access>read-write</access>
                    <resetValue>0x0000</resetValue>
                    <resetMask>0xffff</resetMask>
                    <fields>
                        <field>
                            <name>ENABLE</name>
                            <description>Bus master MPU of CEU Enable</description>
                            <lsb>0</lsb>
                            <msb>0</msb>
                            <access>read-write</access>
                            <enumeratedValues>
                                <enumeratedValue>
                                    <name>0</name>
                                    <description>Bus master MPU of CEU is disabled.</description>
                                    <value>#0</value>
                                </enumeratedValue>
                                <enumeratedValue>
                                    <name>1</name>
                                    <description>Bus master MPU of CEU is enabled.</description>
                                    <value>#1</value>
                                </enumeratedValue>
                            </enumeratedValues>
                        </field>
                        <field>
                            <name>KEY</name>
                            <description>Key Code</description>
                            <lsb>8</lsb>
                            <msb>15</msb>
                            <access>write-only</access>
                        </field>
                    </fields>
                </register>
                <register>
                    <name>MMPUENPTCEU</name>
                    <description>MMPU Enable Protect Register for CEU</description>
                    <addressOffset>0x0D04</addressOffset>
                    <size>16</size>
                    <access>read-write</access>
                    <resetValue>0x0000</resetValue>
                    <resetMask>0xffff</resetMask>
                    <fields>
                        <field>
                            <name>PROTECT</name>
                            <description>Protection of register</description>
                            <lsb>0</lsb>
                            <msb>0</msb>
                            <access>read-write</access>
                            <enumeratedValues>
                                <enumeratedValue>
                                    <name>0</name>
                                    <description>MMPUENCEU register write is possible.</description>
                                    <value>#0</value>
                                </enumeratedValue>
                                <enumeratedValue>
                                    <name>1</name>
                                    <description>MMPUENCEU register write is protected. Read is possible.</description>
                                    <value>#1</value>
                                </enumeratedValue>
                            </enumeratedValues>
                        </field>
                        <field>
                            <name>KEY</name>
                            <description>Key Code</description>
                            <lsb>8</lsb>
                            <msb>15</msb>
                            <access>write-only</access>
                        </field>
                    </fields>
                </register>
                <register>
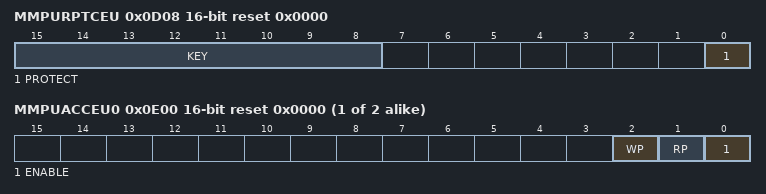
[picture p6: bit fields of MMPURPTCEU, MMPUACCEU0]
                    <name>MMPURPTCEU</name>
                    <description>MMPU Regions Protect Register for CEU</description>
                    <addressOffset>0x0D08</addressOffset>
                    <size>16</size>
                    <access>read-write</access>
                    <resetValue>0x0000</resetValue>
                    <resetMask>0xffff</resetMask>
                    <fields>
                        <field>
                            <name>PROTECT</name>
                            <description>Protection of register</description>
                            <lsb>0</lsb>
                            <msb>0</msb>
                            <access>read-write</access>
                            <enumeratedValues>
                                <enumeratedValue>
                                    <name>0</name>
                                    <description>Bus master MPU register for CEU write is possible.</description>
                                    <value>#0</value>
                                </enumeratedValue>
                                <enumeratedValue>
                                    <name>1</name>
                                    <description>Bus master MPU register for CEU write is protected. Read is possible.</description>
                                    <value>#1</value>
                                </enumeratedValue>
                            </enumeratedValues>
                        </field>
                        <field>
                            <name>KEY</name>
                            <description>Key Code</description>
                            <lsb>8</lsb>
                            <msb>15</msb>
                            <access>write-only</access>
                        </field>
                    </fields>
                </register>
                <register>
                    <dim>2</dim>
                    <dimIncrement>0x010</dimIncrement>
                    <dimIndex>0-1</dimIndex>
                    <name>MMPUACCEU%s</name>
                    <description>MMPU Access Control Register for CEU (n = 0, 1)</description>
                    <addressOffset>0x0E00</addressOffset>
                    <size>16</size>
                    <access>read-write</access>
                    <resetValue>0x0000</resetValue>
                    <resetMask>0xffff</resetMask>
                    <fields>
                        <field>
                            <name>ENABLE</name>
                            <description>Region Enable</description>
                            <lsb>0</lsb>
                            <msb>0</msb>
                            <access>read-write</access>
                            <enumeratedValues>
                                <enumeratedValue>
                                    <name>0</name>
                                    <description>CEU region n unit is disabled.</description>
                                    <value>#0</value>
                                </enumeratedValue>
                                <enumeratedValue>
                                    <name>1</name>
                                    <description>CEU region n unit is enabled.</description>
                                    <value>#1</value>
                                </enumeratedValue>
                            </enumeratedValues>
                        </field>
                        <field>
                            <name>RP</name>
                            <description>Read protection</description>
                            <lsb>1</lsb>
                            <msb>1</msb>
                            <access>read-write</access>
                            <enumeratedValues>
                                <enumeratedValue>
                                    <name>0</name>
                                    <description>Read permission</description>
                                    <value>#0</value>
                                </enumeratedValue>
                                <enumeratedValue>
                                    <name>1</name>
                                    <description>Read protection</description>
                                    <value>#1</value>
                                </enumeratedValue>
                            </enumeratedValues>
                        </field>
                        <field>
                            <name>WP</name>
                            <description>Write protection</description>
                            <lsb>2</lsb>
                            <msb>2</msb>
                            <access>read-write</access>
                            <enumeratedValues>
                                <enumeratedValue>
                                    <name>0</name>
                                    <description>Write permission</description>
                                    <value>#0</value>
                                </enumeratedValue>
                                <enumeratedValue>
                                    <name>1</name>
                                    <description>Write protection</description>
                                    <value>#1</value>
                                </enumeratedValue>
                            </enumeratedValues>
                        </field>
                    </fields>
                </register>
                <register>
                    <dim>2</dim>
                    <dimIncrement>0x010</dimIncrement>
                    <dimIndex>0-1</dimIndex>
                    <name>MMPUSCEU%s</name>
                    <description>MMPU Start Address Register for CEU (n = 0 to 1)</description>
                    <addressOffset>0x0E04</addressOffset>
                    <size>32</size>
                    <access>read-write</access>
                    <resetValue>0x00000000</resetValue>
                    <resetMask>0x00000fff</resetMask>
                </register>
                <register>
                    <dim>2</dim>
                    <dimIncrement>0x010</dimIncrement>
                    <dimIndex>0-1</dimIndex>
                    <name>MMPUECEU%s</name>
                    <description>MMPU End Address Register for CEU (n = 0 to 1)</description>
                    <addressOffset>0x0E08</addressOffset>
                    <size>32</size>
                    <access>read-write</access>
                    <resetValue>0x00000fff</resetValue>
                    <resetMask>0x00000fff</resetMask>
                </register>
            </registers>
        </peripheral>
        <peripheral>
            <name>SRAM</name>
            <description>SRAM Control</description>
            <baseAddress>0x40002000</baseAddress>
            <addressBlock>
                <offset>0x00</offset>
                <size>2</size>
                <usage>registers</usage>
            </addressBlock>
            <addressBlock>
                <offset>0x08</offset>
                <size>1</size>
                <usage>registers</usage>
            </addressBlock>
            <addressBlock>
                <offset>0x10</offset>
                <size>1</size>
                <usage>registers</usage>
            </addressBlock>
            <addressBlock>
                <offset>0x14</offset>
                <size>1</size>
                <usage>registers</usage>
            </addressBlock>
            <addressBlock>
                <offset>0x30</offset>
                <size>1</size>
                <usage>registers</usage>
            </addressBlock>
            <addressBlock>
                <offset>0x40</offset>
                <size>2</size>
                <usage>registers</usage>
            </addressBlock>
            <addressBlock>
                <offset>0x48</offset>
                <size>2</size>
                <usage>registers</usage>
            </addressBlock>
            <addressBlock>
                <offset>0x50</offset>
                <size>12</size>
                <usage>registers</usage>
            </addressBlock>
            <addressBlock>
                <offset>0x110</offset>
                <size>1</size>
                <usage>registers</usage>
            </addressBlock>
            <addressBlock>
                <offset>0x150</offset>
                <size>4</size>
                <usage>registers</usage>
            </addressBlock>
            <registers>
                <register>
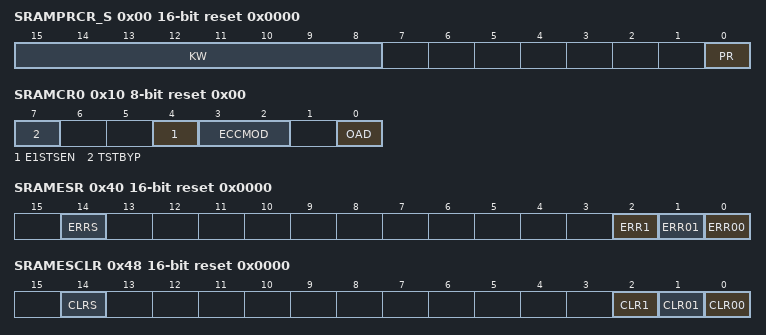
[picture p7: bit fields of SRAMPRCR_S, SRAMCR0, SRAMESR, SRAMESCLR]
                    <name>SRAMPRCR_S</name>
                    <description>SRAM Protection Control Register for Secure</description>
                    <addressOffset>0x00</addressOffset>
                    <size>16</size>
                    <access>read-write</access>
                    <resetValue>0x0000</resetValue>
                    <resetMask>0xffff</resetMask>
                    <fields>
                        <field>
                            <name>PR</name>
                            <description>Register Write Control</description>
                            <lsb>0</lsb>
                            <msb>0</msb>
                            <access>read-write</access>
                            <enumeratedValues>
                                <enumeratedValue>
                                    <name>0</name>
                                    <description>Writing to registers are disabled</description>
                                    <value>#0</value>
                                </enumeratedValue>
                                <enumeratedValue>
                                    <name>1</name>
                                    <description>Writing to registers are enabled</description>
                                    <value>#1</value>
                                </enumeratedValue>
                            </enumeratedValues>
                        </field>
                        <field>
                            <name>KW</name>
                            <description>Write Key Code</description>
                            <lsb>8</lsb>
                            <msb>15</msb>
                            <access>read-write</access>
                        </field>
                    </fields>
                </register>
                <register>
                    <name>SRAMWTSC</name>
                    <description>SRAM Wait State Control Register</description>
                    <addressOffset>0x08</addressOffset>
                    <size>8</size>
                    <access>read-write</access>
                    <resetValue>0x01</resetValue>
                    <resetMask>0xff</resetMask>
                    <fields>
                        <field>
                            <name>WTEN</name>
                            <description>SRAM Wait Enable</description>
                            <lsb>0</lsb>
                            <msb>0</msb>
                            <access>read-write</access>
                            <enumeratedValues>
                                <enumeratedValue>
                                    <name>0</name>
                                    <description>No wait</description>
                                    <value>#0</value>
                                </enumeratedValue>
                                <enumeratedValue>
                                    <name>1</name>
                                    <description>Add wait state in read access cycle to SRAMs</description>
                                    <value>#1</value>
                                </enumeratedValue>
                            </enumeratedValues>
                        </field>
                    </fields>
                </register>
                <register>
                    <name>SRAMCR0</name>
                    <description>SRAM Control Register 0</description>
                    <addressOffset>0x10</addressOffset>
                    <size>8</size>
                    <access>read-write</access>
                    <resetValue>0x00</resetValue>
                    <resetMask>0xff</resetMask>
                    <fields>
                        <field>
                            <name>OAD</name>
                            <description>Operation after Detection for ECC Error Detection</description>
                            <lsb>0</lsb>
                            <msb>0</msb>
                            <access>read-write</access>
                            <enumeratedValues>
                                <enumeratedValue>
                                    <name>0</name>
                                    <description>Non-maskable interrupt</description>
                                    <value>#0</value>
                                </enumeratedValue>
                                <enumeratedValue>
                                    <name>1</name>
                                    <description>Reset.</description>
                                    <value>#1</value>
                                </enumeratedValue>
                            </enumeratedValues>
                        </field>
                        <field>
                            <name>ECCMOD</name>
                            <description>ECC Operating Mode Select</description>
                            <lsb>2</lsb>
                            <msb>3</msb>
                            <access>read-write</access>
                            <enumeratedValues>
                                <enumeratedValue>
                                    <name>00</name>
                                    <description>Disable ECC function</description>
                                    <value>#00</value>
                                </enumeratedValue>
                                <enumeratedValue>
                                    <name>01</name>
                                    <description>Setting prohibited</description>
                                    <value>#01</value>
                                </enumeratedValue>
                                <enumeratedValue>
                                    <name>10</name>
                                    <description>Enable ECC function without error checking</description>
                                    <value>#10</value>
                                </enumeratedValue>
                                <enumeratedValue>
                                    <name>11</name>
                                    <description>Enable ECC function with error checking</description>
                                    <value>#11</value>
                                </enumeratedValue>
                            </enumeratedValues>
                        </field>
                        <field>
                            <name>E1STSEN</name>
                            <description>ECC 1-Bit Error Information Update Enable</description>
                            <lsb>4</lsb>
                            <msb>4</msb>
                            <access>read-write</access>
                            <enumeratedValues>
                                <enumeratedValue>
                                    <name>0</name>
                                    <description>Disable updating of 1-bit ECC error information</description>
                                    <value>#0</value>
                                </enumeratedValue>
                                <enumeratedValue>
                                    <name>1</name>
                                    <description>Enable updating of 1-bit ECC error information</description>
                                    <value>#1</value>
                                </enumeratedValue>
                            </enumeratedValues>
                        </field>
                        <field>
                            <name>TSTBYP</name>
                            <description>ECC Bypass Select</description>
                            <lsb>7</lsb>
                            <msb>7</msb>
                            <access>read-write</access>
                            <enumeratedValues>
                                <enumeratedValue>
                                    <name>0</name>
                                    <description>Disable ECC bypass</description>
                                    <value>#0</value>
                                </enumeratedValue>
                                <enumeratedValue>
                                    <name>1</name>
                                    <description>Enable ECC bypass</description>
                                    <value>#1</value>
                                </enumeratedValue>
                            </enumeratedValues>
                        </field>
                    </fields>
                </register>
                <register>
                    <name>SRAMCR1</name>
                    <description>SRAM Control Register 1</description>
                    <addressOffset>0x14</addressOffset>
                    <size>8</size>
                    <access>read-write</access>
                    <resetValue>0x00</resetValue>
                    <resetMask>0xff</resetMask>
                    <fields>
                        <field>
                            <name>OAD</name>
                            <description>Operation after Detection for Parity Error Detection</description>
                            <lsb>0</lsb>
                            <msb>0</msb>
                            <access>read-write</access>
                            <enumeratedValues>
                                <enumeratedValue>
                                    <name>0</name>
                                    <description>Non-maskable interrupt</description>
                                    <value>#0</value>
                                </enumeratedValue>
                                <enumeratedValue>
                                    <name>1</name>
                                    <description>Reset.</description>
                                    <value>#1</value>
                                </enumeratedValue>
                            </enumeratedValues>
                        </field>
                    </fields>
                </register>
                <register>
                    <name>SRAMECCRGN0</name>
                    <description>SRAM0 ECC Region Control Register</description>
                    <addressOffset>0x30</addressOffset>
                    <size>8</size>
                    <access>read-write</access>
                    <resetValue>0xff</resetValue>
                    <resetMask>0xff</resetMask>
                    <fields>
                        <field>
                            <name>ECCRGN</name>
                            <description>ECC Region Control</description>
                            <lsb>0</lsb>
                            <msb>1</msb>
                            <access>read-write</access>
                            <enumeratedValues>
                                <enumeratedValue>
                                    <name>00</name>
                                    <description>No ECC Region</description>
                                    <value>#00</value>
                                </enumeratedValue>
                                <enumeratedValue>
                                    <name>01</name>
                                    <description>0x2200_0000 – 0x2201_FFFF / 0x3200_0000 – 0x3201_FFFF (128 KB)</description>
                                    <value>#01</value>
                                </enumeratedValue>
                                <enumeratedValue>
                                    <name>10</name>
                                    <description>0x2200_0000 – 0x2203_FFFF / 0x3200_0000 – 0x3203_FFFF (256 KB)</description>
                                    <value>#10</value>
                                </enumeratedValue>
                                <enumeratedValue>
                                    <name>11</name>
                                    <description>0x2200_0000 – 0x2205_FFFF / 0x3200_0000 – 0x3205_FFFF (384 KB)</description>
                                    <value>#11</value>
                                </enumeratedValue>
                            </enumeratedValues>
                        </field>
                    </fields>
                </register>
                <register>
                    <name>SRAMESR</name>
                    <description>SRAM Error Status Register</description>
                    <addressOffset>0x40</addressOffset>
                    <size>16</size>
                    <access>read-only</access>
                    <resetValue>0x0000</resetValue>
                    <resetMask>0xffff</resetMask>
                    <fields>
                        <field>
                            <name>ERR00</name>
                            <description>SRAM0 1-bit ECC Error Status</description>
                            <lsb>0</lsb>
                            <msb>0</msb>
                            <access>read-only</access>
                            <enumeratedValues>
                                <enumeratedValue>
                                    <name>0</name>
                                    <description>1-bit ECC error has not occurred.</description>
                                    <value>#0</value>
                                </enumeratedValue>
                                <enumeratedValue>
                                    <name>1</name>
                                    <description>1-bit ECC error has occurred.</description>
                                    <value>#1</value>
                                </enumeratedValue>
                            </enumeratedValues>
                        </field>
                        <field>
                            <name>ERR01</name>
                            <description>SRAM0 2-bit ECC Error Status</description>
                            <lsb>1</lsb>
                            <msb>1</msb>
                            <access>read-only</access>
                            <enumeratedValues>
                                <enumeratedValue>
                                    <name>0</name>
                                    <description>2-bit ECC error has not occurred.</description>
                                    <value>#0</value>
                                </enumeratedValue>
                                <enumeratedValue>
                                    <name>1</name>
                                    <description>2-bit ECC error has occurred.</description>
                                    <value>#1</value>
                                </enumeratedValue>
                            </enumeratedValues>
                        </field>
                        <field>
                            <name>ERR1</name>
                            <description>SRAM1 Parity Error Status</description>
                            <lsb>2</lsb>
                            <msb>2</msb>
                            <access>read-only</access>
                            <enumeratedValues>
                                <enumeratedValue>
                                    <name>0</name>
                                    <description>Parity error has not occurred.</description>
                                    <value>#0</value>
                                </enumeratedValue>
                                <enumeratedValue>
                                    <name>1</name>
                                    <description>Parity error has occurred.</description>
                                    <value>#1</value>
                                </enumeratedValue>
                            </enumeratedValues>
                        </field>
                        <field>
                            <name>ERRS</name>
                            <description>Standby SRAM Parity Error status</description>
                            <lsb>14</lsb>
                            <msb>14</msb>
                            <access>read-only</access>
                            <enumeratedValues>
                                <enumeratedValue>
                                    <name>0</name>
                                    <description>Parity error has not occurred.</description>
                                    <value>#0</value>
                                </enumeratedValue>
                                <enumeratedValue>
                                    <name>1</name>
                                    <description>Parity error has occurred.</description>
                                    <value>#1</value>
                                </enumeratedValue>
                            </enumeratedValues>
                        </field>
                    </fields>
                </register>
                <register>
                    <name>SRAMESCLR</name>
                    <description>SRAM Error Status Clear Register</description>
                    <addressOffset>0x48</addressOffset>
                    <size>16</size>
                    <access>read-write</access>
                    <resetValue>0x0000</resetValue>
                    <resetMask>0xffff</resetMask>
                    <fields>
                        <field>
                            <name>CLR00</name>
                            <description>SRAM0 1-bit ECC Error Status Clear</description>
                            <lsb>0</lsb>
                            <msb>0</msb>
                            <access>read-write</access>
                            <enumeratedValues>
                                <enumeratedValue>
                                    <name>1</name>
                                    <description>Clear 1-bit ECC error.</description>
                                    <value>#1</value>
                                </enumeratedValue>
                            </enumeratedValues>
                        </field>
                        <field>
                            <name>CLR01</name>
                            <description>SRAM0 2-bit ECC Error Status Clear</description>
                            <lsb>1</lsb>
                            <msb>1</msb>
                            <access>read-write</access>
                            <enumeratedValues>
                                <enumeratedValue>
                                    <name>1</name>
                                    <description>Clear 2-bit ECC error.</description>
                                    <value>#1</value>
                                </enumeratedValue>
                            </enumeratedValues>
                        </field>
                        <field>
                            <name>CLR1</name>
                            <description>SRAM1 Parity Error Status Clear</description>
                            <lsb>2</lsb>
                            <msb>2</msb>
                            <access>read-write</access>
                            <enumeratedValues>
                                <enumeratedValue>
                                    <name>1</name>
                                    <description>Clear Parity error.</description>
                                    <value>#1</value>
                                </enumeratedValue>
                            </enumeratedValues>
                        </field>
                        <field>
                            <name>CLRS</name>
                            <description>Standby SRAM Parity Error Status Clear</description>
                            <lsb>14</lsb>
                            <msb>14</msb>
                            <access>read-write</access>
                            <enumeratedValues>
                                <enumeratedValue>
                                    <name>1</name>
                                    <description>Clear Parity error.</description>
                                    <value>#1</value>
                                </enumeratedValue>
                            </enumeratedValues>
                        </field>
                    </fields>
                </register>
                <register>
                    <dim>3</dim>
                    <dimIncrement>0x04</dimIncrement>
                    <dimIndex>0-2</dimIndex>
                    <name>SRAMEAR%s</name>
                    <description>SRAM Error Address Register (n = 0 to 2)</description>
                    <addressOffset>0x50</addressOffset>
                    <size>32</size>
                    <access>read-only</access>
                    <resetValue>0x00000000</resetValue>
                    <resetMask>0xffffffff</resetMask>
                </register>
                <register>
                    <name>STBRAMCR</name>
                    <description>Standby SRAM Control Register</description>
                    <addressOffset>0x110</addressOffset>
                    <size>8</size>
                    <access>read-write</access>
                    <resetValue>0x00</resetValue>
                    <resetMask>0xff</resetMask>
                    <fields>
                        <field>
                            <name>OAD</name>
                            <description>Operation after detection</description>
                            <lsb>0</lsb>
                            <msb>0</msb>
                            <access>read-write</access>
                            <enumeratedValues>
                                <enumeratedValue>
                                    <name>0</name>
                                    <description>Non-maskable interrupt.</description>
                                    <value>#0</value>
                                </enumeratedValue>
                                <enumeratedValue>
                                    <name>1</name>
                                    <description>Reset.</description>
                                    <value>#1</value>
                                </enumeratedValue>
                            </enumeratedValues>
                        </field>
                    </fields>
                </register>
                <register>
                    <name>STBRAMEAR</name>
                    <description>Standby SRAM Error Address Register</description>
                    <addressOffset>0x150</addressOffset>
                    <size>32</size>
                    <access>read-only</access>
                    <resetValue>0x00000000</resetValue>
                    <resetMask>0xffffffff</resetMask>
                </register>
            </registers>
        </peripheral>
        <peripheral>
            <name>BUS</name>
            <description>Bus Control</description>
            <baseAddress>0x40003000</baseAddress>
            <addressBlock>
                <offset>0x02</offset>
                <size>134</size>
                <usage>registers</usage>
            </addressBlock>
            <addressBlock>
                <offset>0x802</offset>
                <size>2</size>
                <usage>registers</usage>
            </addressBlock>
            <addressBlock>
                <offset>0x80A</offset>
                <size>128</size>
                <usage>registers</usage>
            </addressBlock>
            <addressBlock>
                <offset>0xC00</offset>
                <size>3</size>
                <usage>registers</usage>
            </addressBlock>
            <addressBlock>
                <offset>0xC10</offset>
                <size>1</size>
                <usage>registers</usage>
            </addressBlock>
            <addressBlock>
                <offset>0xC14</offset>
                <size>3</size>
                <usage>registers</usage>
            </addressBlock>
            <addressBlock>
                <offset>0xC20</offset>
                <size>1</size>
                <usage>registers</usage>
            </addressBlock>
            <addressBlock>
                <offset>0xC24</offset>
                <size>2</size>
                <usage>registers</usage>
            </addressBlock>
            <addressBlock>
                <offset>0xC40</offset>
                <size>1</size>
                <usage>registers</usage>
            </addressBlock>
            <addressBlock>
                <offset>0xC44</offset>
                <size>6</size>
                <usage>registers</usage>
            </addressBlock>
            <addressBlock>
                <offset>0xC50</offset>
                <size>1</size>
                <usage>registers</usage>
            </addressBlock>
            <addressBlock>
                <offset>0x1000</offset>
                <size>2</size>
                <usage>registers</usage>
            </addressBlock>
            <addressBlock>
                <offset>0x1004</offset>
                <size>2</size>
                <usage>registers</usage>
            </addressBlock>
            <addressBlock>
                <offset>0x1010</offset>
                <size>2</size>
                <usage>registers</usage>
            </addressBlock>
            <addressBlock>
                <offset>0x1014</offset>
                <size>2</size>
                <usage>registers</usage>
            </addressBlock>
            <addressBlock>
                <offset>0x1100</offset>
                <size>4</size>
                <usage>registers</usage>
            </addressBlock>
            <addressBlock>
                <offset>0x1200</offset>
                <size>4</size>
                <usage>registers</usage>
            </addressBlock>
            <addressBlock>
                <offset>0x1210</offset>
                <size>4</size>
                <usage>registers</usage>
            </addressBlock>
            <addressBlock>
                <offset>0x1218</offset>
                <size>4</size>
                <usage>registers</usage>
            </addressBlock>
            <addressBlock>
                <offset>0x1220</offset>
                <size>4</size>
                <usage>registers</usage>
            </addressBlock>
            <addressBlock>
                <offset>0x1248</offset>
                <size>4</size>
                <usage>registers</usage>
            </addressBlock>
            <addressBlock>
                <offset>0x1250</offset>
                <size>4</size>
                <usage>registers</usage>
            </addressBlock>
            <addressBlock>
                <offset>0x1258</offset>
                <size>4</size>
                <usage>registers</usage>
            </addressBlock>
            <addressBlock>
                <offset>0x1260</offset>
                <size>4</size>
                <usage>registers</usage>
            </addressBlock>
            <addressBlock>
                <offset>0x1268</offset>
                <size>4</size>
                <usage>registers</usage>
            </addressBlock>
            <addressBlock>
                <offset>0x1270</offset>
                <size>4</size>
                <usage>registers</usage>
            </addressBlock>
            <addressBlock>
                <offset>0x1278</offset>
                <size>4</size>
                <usage>registers</usage>
            </addressBlock>
            <addressBlock>
                <offset>0x1300</offset>
                <size>4</size>
                <usage>registers</usage>
            </addressBlock>
            <addressBlock>
                <offset>0x1800</offset>
                <size>100</size>
                <usage>registers</usage>
            </addressBlock>
            <addressBlock>
                <offset>0x1900</offset>
                <size>100</size>
                <usage>registers</usage>
            </addressBlock>
            <addressBlock>
                <offset>0x1A00</offset>
                <size>200</size>
                <usage>registers</usage>
            </addressBlock>
            <addressBlock>
                <offset>0x1B00</offset>
                <size>4</size>
                <usage>registers</usage>
            </addressBlock>
            <addressBlock>
                <offset>0x1B08</offset>
                <size>4</size>
                <usage>registers</usage>
            </addressBlock>
            <addressBlock>
                <offset>0x1B20</offset>
                <size>4</size>
                <usage>registers</usage>
            </addressBlock>
            <addressBlock>
                <offset>0x1B28</offset>
                <size>4</size>
                <usage>registers</usage>
            </addressBlock>
            <registers>
                <register>
                    <dim>8</dim>
                    <dimIncrement>0x10</dimIncrement>
                    <dimIndex>0-7</dimIndex>
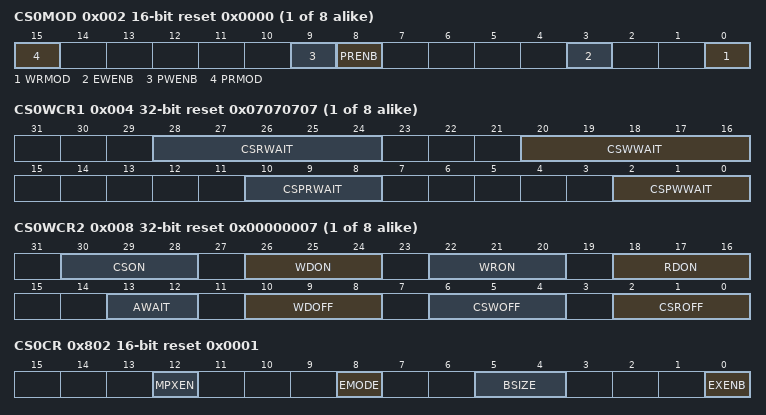
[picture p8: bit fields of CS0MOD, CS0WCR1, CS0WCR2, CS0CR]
                    <name>CS%sMOD</name>
                    <description>CS%s Mode Register (n = 0 to 7)</description>
                    <addressOffset>0x002</addressOffset>
                    <size>16</size>
                    <access>read-write</access>
                    <resetValue>0x0000</resetValue>
                    <resetMask>0xffff</resetMask>
                    <fields>
                        <field>
                            <name>WRMOD</name>
                            <description>Write Access Mode Select</description>
                            <lsb>0</lsb>
                            <msb>0</msb>
                            <access>read-write</access>
                            <enumeratedValues>
                                <enumeratedValue>
                                    <name>0</name>
                                    <description>Byte strobe mode</description>
                                    <value>#0</value>
                                </enumeratedValue>
                                <enumeratedValue>
                                    <name>1</name>
                                    <description>Single-write strobe mode</description>
                                    <value>#1</value>
                                </enumeratedValue>
                            </enumeratedValues>
                        </field>
                        <field>
                            <name>EWENB</name>
                            <description>External Wait Enable</description>
                            <lsb>3</lsb>
                            <msb>3</msb>
                            <access>read-write</access>
                            <enumeratedValues>
                                <enumeratedValue>
                                    <name>0</name>
                                    <description>Disabled</description>
                                    <value>#0</value>
                                </enumeratedValue>
                                <enumeratedValue>
                                    <name>1</name>
                                    <description>Enabled</description>
                                    <value>#1</value>
                                </enumeratedValue>
                            </enumeratedValues>
                        </field>
                        <field>
                            <name>PRENB</name>
                            <description>Page Read Access Enable</description>
                            <lsb>8</lsb>
                            <msb>8</msb>
                            <access>read-write</access>
                            <enumeratedValues>
                                <enumeratedValue>
                                    <name>0</name>
                                    <description>Disabled</description>
                                    <value>#0</value>
                                </enumeratedValue>
                                <enumeratedValue>
                                    <name>1</name>
                                    <description>Enabled</description>
                                    <value>#1</value>
                                </enumeratedValue>
                            </enumeratedValues>
                        </field>
                        <field>
                            <name>PWENB</name>
                            <description>Page Write Access Enable</description>
                            <lsb>9</lsb>
                            <msb>9</msb>
                            <access>read-write</access>
                            <enumeratedValues>
                                <enumeratedValue>
                                    <name>0</name>
                                    <description>Disabled</description>
                                    <value>#0</value>
                                </enumeratedValue>
                                <enumeratedValue>
                                    <name>1</name>
                                    <description>Enabled</description>
                                    <value>#1</value>
                                </enumeratedValue>
                            </enumeratedValues>
                        </field>
                        <field>
                            <name>PRMOD</name>
                            <description>Page Read Access Mode Select</description>
                            <lsb>15</lsb>
                            <msb>15</msb>
                            <access>read-write</access>
                            <enumeratedValues>
                                <enumeratedValue>
                                    <name>0</name>
                                    <description>Normal access compatible mode</description>
                                    <value>#0</value>
                                </enumeratedValue>
                                <enumeratedValue>
                                    <name>1</name>
                                    <description>External data read continuous assertion mode</description>
                                    <value>#1</value>
                                </enumeratedValue>
                            </enumeratedValues>
                        </field>
                    </fields>
                </register>
                <register>
                    <dim>8</dim>
                    <dimIncrement>0x10</dimIncrement>
                    <dimIndex>0-7</dimIndex>
                    <name>CS%sWCR1</name>
                    <description>CS%s Wait Control Register 1 (n = 0 to 7)</description>
                    <addressOffset>0x004</addressOffset>
                    <size>32</size>
                    <access>read-write</access>
                    <resetValue>0x07070707</resetValue>
                    <resetMask>0xffffffff</resetMask>
                    <fields>
                        <field>
                            <name>CSPWWAIT</name>
                            <description>Page Write Cycle Wait Select</description>
                            <lsb>0</lsb>
                            <msb>2</msb>
                            <access>read-write</access>
                        </field>
                        <field>
                            <name>CSPRWAIT</name>
                            <description>Page Read Cycle Wait Select</description>
                            <lsb>8</lsb>
                            <msb>10</msb>
                            <access>read-write</access>
                        </field>
                        <field>
                            <name>CSWWAIT</name>
                            <description>Normal Write Cycle Wait Select</description>
                            <lsb>16</lsb>
                            <msb>20</msb>
                            <access>read-write</access>
                        </field>
                        <field>
                            <name>CSRWAIT</name>
                            <description>Normal Read Cycle Wait Select</description>
                            <lsb>24</lsb>
                            <msb>28</msb>
                            <access>read-write</access>
                        </field>
                    </fields>
                </register>
                <register>
                    <dim>8</dim>
                    <dimIncrement>0x10</dimIncrement>
                    <dimIndex>0-7</dimIndex>
                    <name>CS%sWCR2</name>
                    <description>CS%s Wait Control Register 2 (n = 0 to 7)</description>
                    <addressOffset>0x008</addressOffset>
                    <size>32</size>
                    <access>read-write</access>
                    <resetValue>0x00000007</resetValue>
                    <resetMask>0xffffffff</resetMask>
                    <fields>
                        <field>
                            <name>CSROFF</name>
                            <description>Read Access CS Extension Cycle Select</description>
                            <lsb>0</lsb>
                            <msb>2</msb>
                            <access>read-write</access>
                        </field>
                        <field>
                            <name>CSWOFF</name>
                            <description>Write Access CS Extension Cycle Select</description>
                            <lsb>4</lsb>
                            <msb>6</msb>
                            <access>read-write</access>
                        </field>
                        <field>
                            <name>WDOFF</name>
                            <description>Write Data Output Extension Cycle Select</description>
                            <lsb>8</lsb>
                            <msb>10</msb>
                            <access>read-write</access>
                        </field>
                        <field>
                            <name>AWAIT</name>
                            <description>Address Cycle Wait Select</description>
                            <lsb>12</lsb>
                            <msb>13</msb>
                            <access>read-write</access>
                        </field>
                        <field>
                            <name>RDON</name>
                            <description>RD Assert Wait Select</description>
                            <lsb>16</lsb>
                            <msb>18</msb>
                            <access>read-write</access>
                        </field>
                        <field>
                            <name>WRON</name>
                            <description>WR Assert Wait Select</description>
                            <lsb>20</lsb>
                            <msb>22</msb>
                            <access>read-write</access>
                        </field>
                        <field>
                            <name>WDON</name>
                            <description>Write Data Output Wait Select</description>
                            <lsb>24</lsb>
                            <msb>26</msb>
                            <access>read-write</access>
                        </field>
                        <field>
                            <name>CSON</name>
                            <description>CS Assert Wait Select</description>
                            <lsb>28</lsb>
                            <msb>30</msb>
                            <access>read-write</access>
                        </field>
                    </fields>
                </register>
                <register>
                    <name>CS0CR</name>
                    <description>CS0 Control Register</description>
                    <addressOffset>0x802</addressOffset>
                    <size>16</size>
                    <access>read-write</access>
                    <resetValue>0x0001</resetValue>
                    <resetMask>0xffff</resetMask>
                    <fields>
                        <field>
                            <name>EXENB</name>
                            <description>Operation Enable</description>
                            <lsb>0</lsb>
                            <msb>0</msb>
                            <access>read-write</access>
                            <enumeratedValues>
                                <enumeratedValue>
                                    <name>0</name>
                                    <description>Disable operation</description>
                                    <value>#0</value>
                                </enumeratedValue>
                                <enumeratedValue>
                                    <name>1</name>
                                    <description>Enable operation</description>
                                    <value>#1</value>
                                </enumeratedValue>
                            </enumeratedValues>
                        </field>
                        <field>
                            <name>BSIZE</name>
                            <description>External Bus Width Select</description>
                            <lsb>4</lsb>
                            <msb>5</msb>
                            <access>read-write</access>
                            <enumeratedValues>
                                <enumeratedValue>
                                    <name>00</name>
                                    <description>16-bit bus space</description>
                                    <value>#00</value>
                                </enumeratedValue>
                                <enumeratedValue>
                                    <name>01</name>
                                    <description>32-bit bus space</description>
                                    <value>#01</value>
                                </enumeratedValue>
                                <enumeratedValue>
                                    <name>10</name>
                                    <description>8-bit bus space</description>
                                    <value>#10</value>
                                </enumeratedValue>
                                <enumeratedValue>
                                    <name>Others</name>
                                    <description>Setting prohibited</description>
                                    <isDefault>true</isDefault>
                                </enumeratedValue>
                            </enumeratedValues>
                        </field>
                        <field>
                            <name>EMODE</name>
                            <description>Endian Mode</description>
                            <lsb>8</lsb>
                            <msb>8</msb>
                            <access>read-write</access>
                            <enumeratedValues>
                                <enumeratedValue>
                                    <name>0</name>
                                    <description>Little endian</description>
                                    <value>#0</value>
                                </enumeratedValue>
                                <enumeratedValue>
                                    <name>1</name>
                                    <description>Big endian</description>
                                    <value>#1</value>
                                </enumeratedValue>
                            </enumeratedValues>
                        </field>
                        <field>
                            <name>MPXEN</name>
                            <description>Address/Data Multiplexed I/O Interface Select</description>
                            <lsb>12</lsb>
                            <msb>12</msb>
                            <access>read-write</access>
                            <enumeratedValues>
                                <enumeratedValue>
                                    <name>0</name>
                                    <description>Separate bus interface is selected for area n.</description>
                                    <value>#0</value>
                                </enumeratedValue>
                                <enumeratedValue>
                                    <name>1</name>
                                    <description>Address/data multiplexed I/O interface is selected for area n.</description>
                                    <value>#1</value>
                                </enumeratedValue>
                            </enumeratedValues>
                        </field>
                    </fields>
                </register>
                <register>
                    <dim>8</dim>
                    <dimIncrement>0x10</dimIncrement>
                    <dimIndex>0-7</dimIndex>
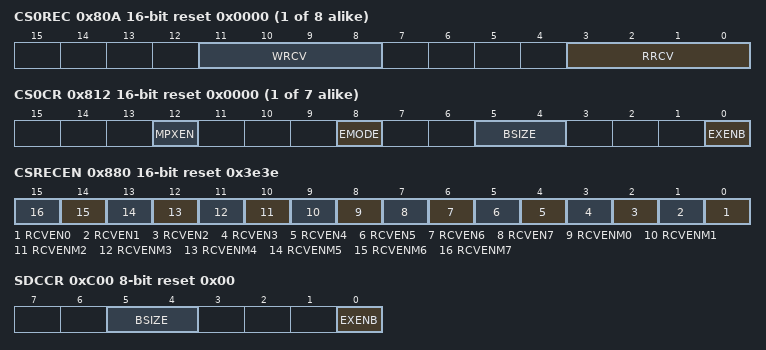
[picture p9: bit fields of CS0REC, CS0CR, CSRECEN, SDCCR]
                    <name>CS%sREC</name>
                    <description>CS%s Recovery Cycle Register (n = 0 to 7)</description>
                    <addressOffset>0x80A</addressOffset>
                    <size>16</size>
                    <access>read-write</access>
                    <resetValue>0x0000</resetValue>
                    <resetMask>0xffff</resetMask>
                    <fields>
                        <field>
                            <name>RRCV</name>
                            <description>Read Recovery</description>
                            <lsb>0</lsb>
                            <msb>3</msb>
                            <access>read-write</access>
                        </field>
                        <field>
                            <name>WRCV</name>
                            <description>Write Recovery</description>
                            <lsb>8</lsb>
                            <msb>11</msb>
                            <access>read-write</access>
                        </field>
                    </fields>
                </register>
                <register>
                    <dim>7</dim>
                    <dimIncrement>0x10</dimIncrement>
                    <dimIndex>1-7</dimIndex>
                    <name>CS%sCR</name>
                    <description>CS%s Control Register</description>
                    <addressOffset>0x812</addressOffset>
                    <size>16</size>
                    <access>read-write</access>
                    <resetValue>0x0000</resetValue>
                    <resetMask>0xffff</resetMask>
                    <fields>
                        <field>
                            <name>EXENB</name>
                            <description>Operation Enable</description>
                            <lsb>0</lsb>
                            <msb>0</msb>
                            <access>read-write</access>
                            <enumeratedValues>
                                <enumeratedValue>
                                    <name>0</name>
                                    <description>Disable operation</description>
                                    <value>#0</value>
                                </enumeratedValue>
                                <enumeratedValue>
                                    <name>1</name>
                                    <description>Enable operation</description>
                                    <value>#1</value>
                                </enumeratedValue>
                            </enumeratedValues>
                        </field>
                        <field>
                            <name>BSIZE</name>
                            <description>External Bus Width Select</description>
                            <lsb>4</lsb>
                            <msb>5</msb>
                            <access>read-write</access>
                            <enumeratedValues>
                                <enumeratedValue>
                                    <name>00</name>
                                    <description>16-bit bus space</description>
                                    <value>#00</value>
                                </enumeratedValue>
                                <enumeratedValue>
                                    <name>01</name>
                                    <description>32-bit bus space</description>
                                    <value>#01</value>
                                </enumeratedValue>
                                <enumeratedValue>
                                    <name>10</name>
                                    <description>8-bit bus space</description>
                                    <value>#10</value>
                                </enumeratedValue>
                                <enumeratedValue>
                                    <name>Others</name>
                                    <description>Setting prohibited</description>
                                    <isDefault>true</isDefault>
                                </enumeratedValue>
                            </enumeratedValues>
                        </field>
                        <field>
                            <name>EMODE</name>
                            <description>Endian Mode</description>
                            <lsb>8</lsb>
                            <msb>8</msb>
                            <access>read-write</access>
                            <enumeratedValues>
                                <enumeratedValue>
                                    <name>0</name>
                                    <description>Little endian</description>
                                    <value>#0</value>
                                </enumeratedValue>
                                <enumeratedValue>
                                    <name>1</name>
                                    <description>Big endian</description>
                                    <value>#1</value>
                                </enumeratedValue>
                            </enumeratedValues>
                        </field>
                        <field>
                            <name>MPXEN</name>
                            <description>Address/Data Multiplexed I/O Interface Select</description>
                            <lsb>12</lsb>
                            <msb>12</msb>
                            <access>read-write</access>
                            <enumeratedValues>
                                <enumeratedValue>
                                    <name>0</name>
                                    <description>Separate bus interface is selected for area n.</description>
                                    <value>#0</value>
                                </enumeratedValue>
                                <enumeratedValue>
                                    <name>1</name>
                                    <description>Address/data multiplexed I/O interface is selected for area n.</description>
                                    <value>#1</value>
                                </enumeratedValue>
                            </enumeratedValues>
                        </field>
                    </fields>
                </register>
                <register>
                    <name>CSRECEN</name>
                    <description>CS Recovery Cycle Insertion Enable Register</description>
                    <addressOffset>0x880</addressOffset>
                    <size>16</size>
                    <access>read-write</access>
                    <resetValue>0x3e3e</resetValue>
                    <resetMask>0xffff</resetMask>
                    <fields>
                        <field>
                            <name>RCVEN0</name>
                            <description>Separate Bus Recovery Cycle Insertion Enable 0</description>
                            <lsb>0</lsb>
                            <msb>0</msb>
                            <access>read-write</access>
                            <enumeratedValues>
                                <enumeratedValue>
                                    <name>0</name>
                                    <description>Disabled</description>
                                    <value>#0</value>
                                </enumeratedValue>
                                <enumeratedValue>
                                    <name>1</name>
                                    <description>Enabled</description>
                                    <value>#1</value>
                                </enumeratedValue>
                            </enumeratedValues>
                        </field>
                        <field>
                            <name>RCVEN1</name>
                            <description>Separate Bus Recovery Cycle Insertion Enable 1</description>
                            <lsb>1</lsb>
                            <msb>1</msb>
                            <access>read-write</access>
                            <enumeratedValues>
                                <enumeratedValue>
                                    <name>0</name>
                                    <description>Disabled</description>
                                    <value>#0</value>
                                </enumeratedValue>
                                <enumeratedValue>
                                    <name>1</name>
                                    <description>Enabled</description>
                                    <value>#1</value>
                                </enumeratedValue>
                            </enumeratedValues>
                        </field>
                        <field>
                            <name>RCVEN2</name>
                            <description>Separate Bus Recovery Cycle Insertion Enable 2</description>
                            <lsb>2</lsb>
                            <msb>2</msb>
                            <access>read-write</access>
                            <enumeratedValues>
                                <enumeratedValue>
                                    <name>0</name>
                                    <description>Disabled</description>
                                    <value>#0</value>
                                </enumeratedValue>
                                <enumeratedValue>
                                    <name>1</name>
                                    <description>Enabled</description>
                                    <value>#1</value>
                                </enumeratedValue>
                            </enumeratedValues>
                        </field>
                        <field>
                            <name>RCVEN3</name>
                            <description>Separate Bus Recovery Cycle Insertion Enable 3</description>
                            <lsb>3</lsb>
                            <msb>3</msb>
                            <access>read-write</access>
                            <enumeratedValues>
                                <enumeratedValue>
                                    <name>0</name>
                                    <description>Disabled</description>
                                    <value>#0</value>
                                </enumeratedValue>
                                <enumeratedValue>
                                    <name>1</name>
                                    <description>Enabled</description>
                                    <value>#1</value>
                                </enumeratedValue>
                            </enumeratedValues>
                        </field>
                        <field>
                            <name>RCVEN4</name>
                            <description>Separate Bus Recovery Cycle Insertion Enable 4</description>
                            <lsb>4</lsb>
                            <msb>4</msb>
                            <access>read-write</access>
                            <enumeratedValues>
                                <enumeratedValue>
                                    <name>0</name>
                                    <description>Disabled</description>
                                    <value>#0</value>
                                </enumeratedValue>
                                <enumeratedValue>
                                    <name>1</name>
                                    <description>Enabled</description>
                                    <value>#1</value>
                                </enumeratedValue>
                            </enumeratedValues>
                        </field>
                        <field>
                            <name>RCVEN5</name>
                            <description>Separate Bus Recovery Cycle Insertion Enable 5</description>
                            <lsb>5</lsb>
                            <msb>5</msb>
                            <access>read-write</access>
                            <enumeratedValues>
                                <enumeratedValue>
                                    <name>0</name>
                                    <description>Disabled</description>
                                    <value>#0</value>
                                </enumeratedValue>
                                <enumeratedValue>
                                    <name>1</name>
                                    <description>Enabled</description>
                                    <value>#1</value>
                                </enumeratedValue>
                            </enumeratedValues>
                        </field>
                        <field>
                            <name>RCVEN6</name>
                            <description>Separate Bus Recovery Cycle Insertion Enable 6</description>
                            <lsb>6</lsb>
                            <msb>6</msb>
                            <access>read-write</access>
                            <enumeratedValues>
                                <enumeratedValue>
                                    <name>0</name>
                                    <description>Disabled</description>
                                    <value>#0</value>
                                </enumeratedValue>
                                <enumeratedValue>
                                    <name>1</name>
                                    <description>Enabled</description>
                                    <value>#1</value>
                                </enumeratedValue>
                            </enumeratedValues>
                        </field>
                        <field>
                            <name>RCVEN7</name>
                            <description>Separate Bus Recovery Cycle Insertion Enable 7</description>
                            <lsb>7</lsb>
                            <msb>7</msb>
                            <access>read-write</access>
                            <enumeratedValues>
                                <enumeratedValue>
                                    <name>0</name>
                                    <description>Disabled</description>
                                    <value>#0</value>
                                </enumeratedValue>
                                <enumeratedValue>
                                    <name>1</name>
                                    <description>Enabled</description>
                                    <value>#1</value>
                                </enumeratedValue>
                            </enumeratedValues>
                        </field>
                        <field>
                            <name>RCVENM0</name>
                            <description>Multiplexed Bus Recovery Cycle Insertion Enable 0</description>
                            <lsb>8</lsb>
                            <msb>8</msb>
                            <access>read-write</access>
                            <enumeratedValues>
                                <enumeratedValue>
                                    <name>0</name>
                                    <description>Disabled</description>
                                    <value>#0</value>
                                </enumeratedValue>
                                <enumeratedValue>
                                    <name>1</name>
                                    <description>Enabled</description>
                                    <value>#1</value>
                                </enumeratedValue>
                            </enumeratedValues>
                        </field>
                        <field>
                            <name>RCVENM1</name>
                            <description>Multiplexed Bus Recovery Cycle Insertion Enable 1</description>
                            <lsb>9</lsb>
                            <msb>9</msb>
                            <access>read-write</access>
                            <enumeratedValues>
                                <enumeratedValue>
                                    <name>0</name>
                                    <description>Disabled</description>
                                    <value>#0</value>
                                </enumeratedValue>
                                <enumeratedValue>
                                    <name>1</name>
                                    <description>Enabled</description>
                                    <value>#1</value>
                                </enumeratedValue>
                            </enumeratedValues>
                        </field>
                        <field>
                            <name>RCVENM2</name>
                            <description>Multiplexed Bus Recovery Cycle Insertion Enable 2</description>
                            <lsb>10</lsb>
                            <msb>10</msb>
                            <access>read-write</access>
                            <enumeratedValues>
                                <enumeratedValue>
                                    <name>0</name>
                                    <description>Disabled</description>
                                    <value>#0</value>
                                </enumeratedValue>
                                <enumeratedValue>
                                    <name>1</name>
                                    <description>Enabled</description>
                                    <value>#1</value>
                                </enumeratedValue>
                            </enumeratedValues>
                        </field>
                        <field>
                            <name>RCVENM3</name>
                            <description>Multiplexed Bus Recovery Cycle Insertion Enable 3</description>
                            <lsb>11</lsb>
                            <msb>11</msb>
                            <access>read-write</access>
                            <enumeratedValues>
                                <enumeratedValue>
                                    <name>0</name>
                                    <description>Disabled</description>
                                    <value>#0</value>
                                </enumeratedValue>
                                <enumeratedValue>
                                    <name>1</name>
                                    <description>Enabled</description>
                                    <value>#1</value>
                                </enumeratedValue>
                            </enumeratedValues>
                        </field>
                        <field>
                            <name>RCVENM4</name>
                            <description>Multiplexed Bus Recovery Cycle Insertion Enable 4</description>
                            <lsb>12</lsb>
                            <msb>12</msb>
                            <access>read-write</access>
                            <enumeratedValues>
                                <enumeratedValue>
                                    <name>0</name>
                                    <description>Disabled</description>
                                    <value>#0</value>
                                </enumeratedValue>
                                <enumeratedValue>
                                    <name>1</name>
                                    <description>Enabled</description>
                                    <value>#1</value>
                                </enumeratedValue>
                            </enumeratedValues>
                        </field>
                        <field>
                            <name>RCVENM5</name>
                            <description>Multiplexed Bus Recovery Cycle Insertion Enable 5</description>
                            <lsb>13</lsb>
                            <msb>13</msb>
                            <access>read-write</access>
                            <enumeratedValues>
                                <enumeratedValue>
                                    <name>0</name>
                                    <description>Disabled</description>
                                    <value>#0</value>
                                </enumeratedValue>
                                <enumeratedValue>
                                    <name>1</name>
                                    <description>Enabled</description>
                                    <value>#1</value>
                                </enumeratedValue>
                            </enumeratedValues>
                        </field>
                        <field>
                            <name>RCVENM6</name>
                            <description>Multiplexed Bus Recovery Cycle Insertion Enable 6</description>
                            <lsb>14</lsb>
                            <msb>14</msb>
                            <access>read-write</access>
                            <enumeratedValues>
                                <enumeratedValue>
                                    <name>0</name>
                                    <description>Disabled</description>
                                    <value>#0</value>
                                </enumeratedValue>
                                <enumeratedValue>
                                    <name>1</name>
                                    <description>Enabled</description>
                                    <value>#1</value>
                                </enumeratedValue>
                            </enumeratedValues>
                        </field>
                        <field>
                            <name>RCVENM7</name>
                            <description>Multiplexed Bus Recovery Cycle Insertion Enable 7</description>
                            <lsb>15</lsb>
                            <msb>15</msb>
                            <access>read-write</access>
                            <enumeratedValues>
                                <enumeratedValue>
                                    <name>0</name>
                                    <description>Disabled</description>
                                    <value>#0</value>
                                </enumeratedValue>
                                <enumeratedValue>
                                    <name>1</name>
                                    <description>Enabled</description>
                                    <value>#1</value>
                                </enumeratedValue>
                            </enumeratedValues>
                        </field>
                    </fields>
                </register>
                <register>
                    <name>SDCCR</name>
                    <description>SDC Control Register</description>
                    <addressOffset>0xC00</addressOffset>
                    <size>8</size>
                    <access>read-write</access>
                    <resetValue>0x00</resetValue>
                    <resetMask>0xff</resetMask>
                    <fields>
                        <field>
                            <name>EXENB</name>
                            <description>Operation Enable</description>
                            <lsb>0</lsb>
                            <msb>0</msb>
                            <access>read-write</access>
                            <enumeratedValues>
                                <enumeratedValue>
                                    <name>0</name>
                                    <description>Disable</description>
                                    <value>#0</value>
                                </enumeratedValue>
                                <enumeratedValue>
                                    <name>1</name>
                                    <description>Enable</description>
                                    <value>#1</value>
                                </enumeratedValue>
                            </enumeratedValues>
                        </field>
                        <field>
                            <name>BSIZE</name>
                            <description>SDRAM Bus Width Select</description>
                            <lsb>4</lsb>
                            <msb>5</msb>
                            <access>read-write</access>
                            <enumeratedValues>
                                <enumeratedValue>
                                    <name>00</name>
                                    <description>16-bit bus space</description>
                                    <value>#00</value>
                                </enumeratedValue>
                                <enumeratedValue>
                                    <name>01</name>
                                    <description>32-bit bus space</description>
                                    <value>#01</value>
                                </enumeratedValue>
                                <enumeratedValue>
                                    <name>10</name>
                                    <description>8-bit bus space</description>
                                    <value>#10</value>
                                </enumeratedValue>
                                <enumeratedValue>
                                    <name>Others</name>
                                    <description>Setting prohibited</description>
                                    <isDefault>true</isDefault>
                                </enumeratedValue>
                            </enumeratedValues>
                        </field>
                    </fields>
                </register>
                <register>
                    <name>SDCMOD</name>
                    <description>SDC Mode Register</description>
                    <addressOffset>0xC01</addressOffset>
                    <size>8</size>
                    <access>read-write</access>
                    <resetValue>0x00</resetValue>
                    <resetMask>0xff</resetMask>
                    <fields>
                        <field>
                            <name>EMODE</name>
                            <description>Endian Mode</description>
                            <lsb>0</lsb>
                            <msb>0</msb>
                            <access>read-write</access>
                            <enumeratedValues>
                                <enumeratedValue>
                                    <name>0</name>
                                    <description>Endian order of SDRAM address space is the same as the endian order of the operating mode.</description>
                                    <value>#0</value>
                                </enumeratedValue>
                                <enumeratedValue>
                                    <name>1</name>
                                    <description>Endian order of SDRAM address space is not the endian order of the operating mode.</description>
                                    <value>#1</value>
                                </enumeratedValue>
                            </enumeratedValues>
                        </field>
                    </fields>
                </register>
                <register>
                    <name>SDAMOD</name>
                    <description>SDRAM Access Mode Register</description>
                    <addressOffset>0xC02</addressOffset>
                    <size>8</size>
                    <access>read-write</access>
                    <resetValue>0x00</resetValue>
                    <resetMask>0xff</resetMask>
                    <fields>
                        <field>
                            <name>BE</name>
                            <description>Continuous Access Enable</description>
                            <lsb>0</lsb>
                            <msb>0</msb>
                            <access>read-write</access>
                            <enumeratedValues>
                                <enumeratedValue>
                                    <name>0</name>
                                    <description>Continuous access is disabled</description>
                                    <value>#0</value>
                                </enumeratedValue>
                                <enumeratedValue>
                                    <name>1</name>
                                    <description>Continuous access is enabled</description>
                                    <value>#1</value>
                                </enumeratedValue>
                            </enumeratedValues>
                        </field>
                    </fields>
                </register>
                <register>
                    <name>SDSELF</name>
                    <description>SDRAM Self-Refresh Control Register</description>
                    <addressOffset>0xC10</addressOffset>
                    <size>8</size>
                    <access>read-write</access>
                    <resetValue>0x00</resetValue>
                    <resetMask>0xff</resetMask>
                    <fields>
                        <field>
                            <name>SFEN</name>
                            <description>SDRAM Self-Refresh Enable</description>
                            <lsb>0</lsb>
                            <msb>0</msb>
                            <access>read-write</access>
                            <enumeratedValues>
                                <enumeratedValue>
                                    <name>0</name>
                                    <description>Disable</description>
                                    <value>#0</value>
                                </enumeratedValue>
                                <enumeratedValue>
                                    <name>1</name>
                                    <description>Enable</description>
                                    <value>#1</value>
                                </enumeratedValue>
                            </enumeratedValues>
                        </field>
                    </fields>
                </register>
                <register>
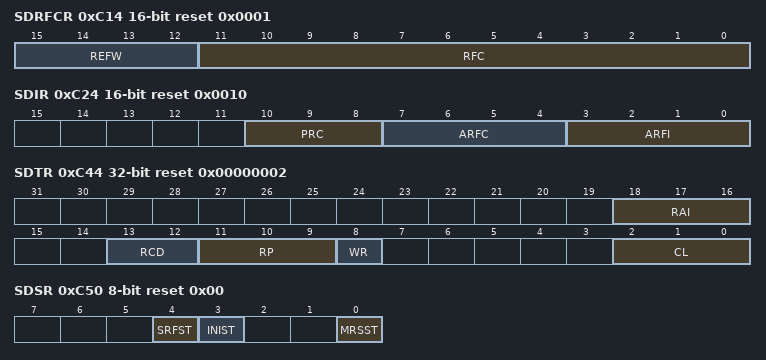
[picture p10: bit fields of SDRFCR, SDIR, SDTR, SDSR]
                    <name>SDRFCR</name>
                    <description>SDRAM Refresh Control Register</description>
                    <addressOffset>0xC14</addressOffset>
                    <size>16</size>
                    <access>read-write</access>
                    <resetValue>0x0001</resetValue>
                    <resetMask>0xffff</resetMask>
                    <fields>
                        <field>
                            <name>RFC</name>
                            <description>Auto-Refresh Request Interval Setting</description>
                            <lsb>0</lsb>
                            <msb>11</msb>
                            <access>read-write</access>
                        </field>
                        <field>
                            <name>REFW</name>
                            <description>Auto-Refresh Cycle/Self-Refresh Clearing Cycle Count Setting</description>
                            <lsb>12</lsb>
                            <msb>15</msb>
                            <access>read-write</access>
                        </field>
                    </fields>
                </register>
                <register>
                    <name>SDRFEN</name>
                    <description>SDRAM Auto-Refresh Control Register</description>
                    <addressOffset>0xC16</addressOffset>
                    <size>8</size>
                    <access>read-write</access>
                    <resetValue>0x00</resetValue>
                    <resetMask>0xff</resetMask>
                    <fields>
                        <field>
                            <name>RFEN</name>
                            <description>Auto-Refresh Operation Enable</description>
                            <lsb>0</lsb>
                            <msb>0</msb>
                            <access>read-write</access>
                            <enumeratedValues>
                                <enumeratedValue>
                                    <name>0</name>
                                    <description>Disable</description>
                                    <value>#0</value>
                                </enumeratedValue>
                                <enumeratedValue>
                                    <name>1</name>
                                    <description>Enable</description>
                                    <value>#1</value>
                                </enumeratedValue>
                            </enumeratedValues>
                        </field>
                    </fields>
                </register>
                <register>
                    <name>SDICR</name>
                    <description>SDRAM Initialization Sequence Control Register</description>
                    <addressOffset>0xC20</addressOffset>
                    <size>8</size>
                    <access>read-write</access>
                    <resetValue>0x00</resetValue>
                    <resetMask>0xff</resetMask>
                    <fields>
                        <field>
                            <name>INIRQ</name>
                            <description>Initialization Sequence Start</description>
                            <lsb>0</lsb>
                            <msb>0</msb>
                            <access>read-write</access>
                            <enumeratedValues>
                                <enumeratedValue>
                                    <name>0</name>
                                    <description>Invalid</description>
                                    <value>#0</value>
                                </enumeratedValue>
                                <enumeratedValue>
                                    <name>1</name>
                                    <description>Start initialization sequence</description>
                                    <value>#1</value>
                                </enumeratedValue>
                            </enumeratedValues>
                        </field>
                    </fields>
                </register>
                <register>
                    <name>SDIR</name>
                    <description>SDRAM Initialization Register</description>
                    <addressOffset>0xC24</addressOffset>
                    <size>16</size>
                    <access>read-write</access>
                    <resetValue>0x0010</resetValue>
                    <resetMask>0xffff</resetMask>
                    <fields>
                        <field>
                            <name>ARFI</name>
                            <description>Initialization Auto-Refresh Interval</description>
                            <lsb>0</lsb>
                            <msb>3</msb>
                            <access>read-write</access>
                        </field>
                        <field>
                            <name>ARFC</name>
                            <description>Initialization Auto-Refresh Count</description>
                            <lsb>4</lsb>
                            <msb>7</msb>
                            <access>read-write</access>
                        </field>
                        <field>
                            <name>PRC</name>
                            <description>Initialization Precharge Cycle Count</description>
                            <lsb>8</lsb>
                            <msb>10</msb>
                            <access>read-write</access>
                        </field>
                    </fields>
                </register>
                <register>
                    <name>SDADR</name>
                    <description>SDRAM Address Register</description>
                    <addressOffset>0xC40</addressOffset>
                    <size>8</size>
                    <access>read-write</access>
                    <resetValue>0x00</resetValue>
                    <resetMask>0xff</resetMask>
                    <fields>
                        <field>
                            <name>MXC</name>
                            <description>Address Multiplex Select</description>
                            <lsb>0</lsb>
                            <msb>1</msb>
                            <access>read-write</access>
                            <enumeratedValues>
                                <enumeratedValue>
                                    <name>00</name>
                                    <description>8-bit shift</description>
                                    <value>#00</value>
                                </enumeratedValue>
                                <enumeratedValue>
                                    <name>01</name>
                                    <description>9-bit shift</description>
                                    <value>#01</value>
                                </enumeratedValue>
                                <enumeratedValue>
                                    <name>10</name>
                                    <description>10-bit shift</description>
                                    <value>#10</value>
                                </enumeratedValue>
                                <enumeratedValue>
                                    <name>11</name>
                                    <description>11-bit shift</description>
                                    <value>#11</value>
                                </enumeratedValue>
                            </enumeratedValues>
                        </field>
                    </fields>
                </register>
                <register>
                    <name>SDTR</name>
                    <description>SDRAM Timing Register</description>
                    <addressOffset>0xC44</addressOffset>
                    <size>32</size>
                    <access>read-write</access>
                    <resetValue>0x00000002</resetValue>
                    <resetMask>0xffffffff</resetMask>
                    <fields>
                        <field>
                            <name>CL</name>
                            <description>SDRAMC Column Latency</description>
                            <lsb>0</lsb>
                            <msb>2</msb>
                            <access>read-write</access>
                        </field>
                        <field>
                            <name>WR</name>
                            <description>Write Recovery Interval</description>
                            <lsb>8</lsb>
                            <msb>8</msb>
                            <access>read-write</access>
                            <enumeratedValues>
                                <enumeratedValue>
                                    <name>0</name>
                                    <description>1 cycle</description>
                                    <value>#0</value>
                                </enumeratedValue>
                                <enumeratedValue>
                                    <name>1</name>
                                    <description>2 cycles</description>
                                    <value>#1</value>
                                </enumeratedValue>
                            </enumeratedValues>
                        </field>
                        <field>
                            <name>RP</name>
                            <description>Row Precharge Interval</description>
                            <lsb>9</lsb>
                            <msb>11</msb>
                            <access>read-write</access>
                        </field>
                        <field>
                            <name>RCD</name>
                            <description>Row Column Latency</description>
                            <lsb>12</lsb>
                            <msb>13</msb>
                            <access>read-write</access>
                            <enumeratedValues>
                                <enumeratedValue>
                                    <name>00</name>
                                    <description>1 cycle</description>
                                    <value>#00</value>
                                </enumeratedValue>
                                <enumeratedValue>
                                    <name>01</name>
                                    <description>2 cycles</description>
                                    <value>#01</value>
                                </enumeratedValue>
                                <enumeratedValue>
                                    <name>10</name>
                                    <description>3 cycles</description>
                                    <value>#10</value>
                                </enumeratedValue>
                                <enumeratedValue>
                                    <name>11</name>
                                    <description>4 cycles</description>
                                    <value>#11</value>
                                </enumeratedValue>
                            </enumeratedValues>
                        </field>
                        <field>
                            <name>RAI</name>
                            <description>Row Active Interval</description>
                            <lsb>16</lsb>
                            <msb>18</msb>
                            <access>read-write</access>
                        </field>
                    </fields>
                </register>
                <register>
                    <name>SDMOD</name>
                    <description>SDRAM Mode Register</description>
                    <addressOffset>0xC48</addressOffset>
                    <size>16</size>
                    <access>read-write</access>
                    <resetValue>0x0000</resetValue>
                    <resetMask>0xffff</resetMask>
                    <fields>
                        <field>
                            <name>MR</name>
                            <description>Mode Register Setting</description>
                            <lsb>0</lsb>
                            <msb>14</msb>
                            <access>read-write</access>
                        </field>
                    </fields>
                </register>
                <register>
                    <name>SDSR</name>
                    <description>SDRAM Status Register</description>
                    <addressOffset>0xC50</addressOffset>
                    <size>8</size>
                    <access>read-only</access>
                    <resetValue>0x00</resetValue>
                    <resetMask>0xff</resetMask>
                    <fields>
                        <field>
                            <name>MRSST</name>
                            <description>Mode Register Setting Status</description>
                            <lsb>0</lsb>
                            <msb>0</msb>
                            <access>read-only</access>
                            <enumeratedValues>
                                <enumeratedValue>
                                    <name>0</name>
                                    <description>Mode register setting not in progress</description>
                                    <value>#0</value>
                                </enumeratedValue>
                                <enumeratedValue>
                                    <name>1</name>
                                    <description>Mode register setting in progress</description>
                                    <value>#1</value>
                                </enumeratedValue>
                            </enumeratedValues>
                        </field>
                        <field>
                            <name>INIST</name>
                            <description>Initialization Status</description>
                            <lsb>3</lsb>
                            <msb>3</msb>
                            <access>read-only</access>
                            <enumeratedValues>
                                <enumeratedValue>
                                    <name>0</name>
                                    <description>Initialization sequence not in progress</description>
                                    <value>#0</value>
                                </enumeratedValue>
                                <enumeratedValue>
                                    <name>1</name>
                                    <description>Initialization sequence in progress</description>
                                    <value>#1</value>
                                </enumeratedValue>
                            </enumeratedValues>
                        </field>
                        <field>
                            <name>SRFST</name>
                            <description>Self-Refresh Transition/Recovery Status</description>
                            <lsb>4</lsb>
                            <msb>4</msb>
                            <access>read-only</access>
                            <enumeratedValues>
                                <enumeratedValue>
                                    <name>0</name>
                                    <description>Transition/recovery not in progress</description>
                                    <value>#0</value>
                                </enumeratedValue>
                                <enumeratedValue>
                                    <name>1</name>
                                    <description>Transition/recovery in progress</description>
                                    <value>#1</value>
                                </enumeratedValue>
                            </enumeratedValues>
                        </field>
                    </fields>
                </register>
                <register>
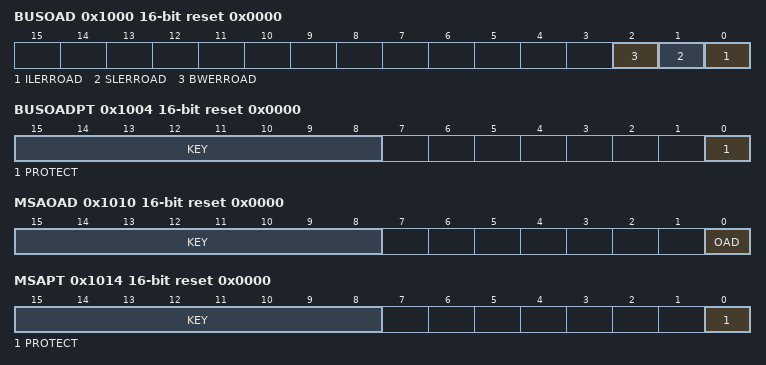
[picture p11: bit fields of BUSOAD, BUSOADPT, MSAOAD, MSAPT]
                    <name>BUSOAD</name>
                    <description>BUS Operation After Detection Register</description>
                    <addressOffset>0x1000</addressOffset>
                    <size>16</size>
                    <access>read-write</access>
                    <resetValue>0x0000</resetValue>
                    <resetMask>0xffff</resetMask>
                    <fields>
                        <field>
                            <name>ILERROAD</name>
                            <description>Illegal address access error operation after detection</description>
                            <lsb>0</lsb>
                            <msb>0</msb>
                            <access>read-write</access>
                        </field>
                        <field>
                            <name>SLERROAD</name>
                            <description>Slave bus error operation after detection</description>
                            <lsb>1</lsb>
                            <msb>1</msb>
                            <access>read-write</access>
                        </field>
                        <field>
                            <name>BWERROAD</name>
                            <description>Bufferable write error operation after detection</description>
                            <lsb>2</lsb>
                            <msb>2</msb>
                            <access>read-write</access>
                        </field>
                    </fields>
                </register>
                <register>
                    <name>BUSOADPT</name>
                    <description>BUS Operation After Detection Protect Register</description>
                    <addressOffset>0x1004</addressOffset>
                    <size>16</size>
                    <access>read-write</access>
                    <resetValue>0x0000</resetValue>
                    <resetMask>0xffff</resetMask>
                    <fields>
                        <field>
                            <name>PROTECT</name>
                            <description>Protection of register</description>
                            <lsb>0</lsb>
                            <msb>0</msb>
                            <access>read-write</access>
                            <enumeratedValues>
                                <enumeratedValue>
                                    <name>0</name>
                                    <description>BUSOAD register writing is possible.</description>
                                    <value>#0</value>
                                </enumeratedValue>
                                <enumeratedValue>
                                    <name>1</name>
                                    <description>BUSOAD register writing is protected. Read is possible.</description>
                                    <value>#1</value>
                                </enumeratedValue>
                            </enumeratedValues>
                        </field>
                        <field>
                            <name>KEY</name>
                            <description>Key code</description>
                            <lsb>8</lsb>
                            <msb>15</msb>
                            <access>write-only</access>
                        </field>
                    </fields>
                </register>
                <register>
                    <name>MSAOAD</name>
                    <description>Master Security Attribution Operation After Detection Register</description>
                    <addressOffset>0x1010</addressOffset>
                    <size>16</size>
                    <access>read-write</access>
                    <resetValue>0x0000</resetValue>
                    <resetMask>0xffff</resetMask>
                    <fields>
                        <field>
                            <name>OAD</name>
                            <description>Operation after detection</description>
                            <lsb>0</lsb>
                            <msb>0</msb>
                            <access>read-write</access>
                            <enumeratedValues>
                                <enumeratedValue>
                                    <name>0</name>
                                    <description>NMI</description>
                                    <value>#0</value>
                                </enumeratedValue>
                                <enumeratedValue>
                                    <name>1</name>
                                    <description>Reset</description>
                                    <value>#1</value>
                                </enumeratedValue>
                            </enumeratedValues>
                        </field>
                        <field>
                            <name>KEY</name>
                            <description>Key Code</description>
                            <lsb>8</lsb>
                            <msb>15</msb>
                            <access>write-only</access>
                        </field>
                    </fields>
                </register>
                <register>
                    <name>MSAPT</name>
                    <description>Master Security Attribution Protect Register</description>
                    <addressOffset>0x1014</addressOffset>
                    <size>16</size>
                    <access>read-write</access>
                    <resetValue>0x0000</resetValue>
                    <resetMask>0xffff</resetMask>
                    <fields>
                        <field>
                            <name>PROTECT</name>
                            <description>Protection of register</description>
                            <lsb>0</lsb>
                            <msb>0</msb>
                            <access>read-write</access>
                            <enumeratedValues>
                                <enumeratedValue>
                                    <name>0</name>
                                    <description>MSAOAD register writing is possible.</description>
                                    <value>#0</value>
                                </enumeratedValue>
                                <enumeratedValue>
                                    <name>1</name>
                                    <description>MSAOAD register writing is protected. Read is possible.</description>
                                    <value>#1</value>
                                </enumeratedValue>
                            </enumeratedValues>
                        </field>
                        <field>
                            <name>KEY</name>
                            <description>Key Code</description>
                            <lsb>8</lsb>
                            <msb>15</msb>
                            <access>write-only</access>
                        </field>
                    </fields>
                </register>
                <register>
                    <name>BUSMABT</name>
                    <description>Bus Master Arbitration Control Register</description>
                    <addressOffset>0x1100</addressOffset>
                    <size>32</size>
                    <access>read-write</access>
                    <resetValue>0x00000000</resetValue>
                    <resetMask>0xffffffff</resetMask>
                    <fields>
                        <field>
                            <name>ARBS</name>
                            <description>Arbitration Select for GDSSBI</description>
                            <lsb>0</lsb>
                            <msb>0</msb>
                            <access>read-write</access>
                            <enumeratedValues>
                                <enumeratedValue>
                                    <name>0</name>
                                    <description>Fixed priority</description>
                                    <value>#0</value>
                                </enumeratedValue>
                                <enumeratedValue>
                                    <name>1</name>
                                    <description>Round-robin</description>
                                    <value>#1</value>
                                </enumeratedValue>
                            </enumeratedValues>
                        </field>
                    </fields>
                </register>
                <register>
                    <name>BUSSABT1FHBI</name>
                    <description>Bus Slave Arbitration Control Register 1(x = FHBI, S0BI, S1BI)</description>
                    <addressOffset>0x1200</addressOffset>
                    <size>32</size>
                    <access>read-write</access>
                    <resetValue>0x00000000</resetValue>
                    <resetMask>0xffffffff</resetMask>
                    <fields>
                        <field>
                            <name>ARBS</name>
                            <description>Arbitration Select for &lt;slave&gt;</description>
                            <lsb>0</lsb>
                            <msb>1</msb>
                            <access>read-write</access>
                            <enumeratedValues>
                                <enumeratedValue>
                                    <name>00</name>
                                    <description>Fixed priority</description>
                                    <value>#00</value>
                                </enumeratedValue>
                                <enumeratedValue>
                                    <name>01</name>
                                    <description>Setting prohibited</description>
                                    <value>#01</value>
                                </enumeratedValue>
                                <enumeratedValue>
                                    <name>10</name>
                                    <description>Combination of round-robin and fixed priority</description>
                                    <value>#10</value>
                                </enumeratedValue>
                                <enumeratedValue>
                                    <name>11</name>
                                    <description>Round-robin</description>
                                    <value>#11</value>
                                </enumeratedValue>
                            </enumeratedValues>
                        </field>
                    </fields>
                </register>
                <register>
                    <name>BUSSABT0FLBI</name>
                    <description>Bus Slave Arbitration Control Register 0</description>
                    <addressOffset>0x1210</addressOffset>
                    <size>32</size>
                    <access>read-write</access>
                    <resetValue>0x00000000</resetValue>
                    <resetMask>0xffffffff</resetMask>
                    <fields>
                        <field>
                            <name>ARBS</name>
                            <description>Arbitration Select for &lt;slave&gt;</description>
                            <lsb>0</lsb>
                            <msb>0</msb>
                            <access>read-write</access>
                            <enumeratedValues>
                                <enumeratedValue>
                                    <name>0</name>
                                    <description>Fixed priority</description>
                                    <value>#0</value>
                                </enumeratedValue>
                                <enumeratedValue>
                                    <name>1</name>
                                    <description>Round-robin</description>
                                    <value>#1</value>
                                </enumeratedValue>
                            </enumeratedValues>
                        </field>
                    </fields>
                </register>
                <register>
                    <name>BUSSABT1S0BI</name>
                    <description>Bus Slave Arbitration Control Register 1(x = FHBI, S0BI, S1BI)</description>
                    <addressOffset>0x1218</addressOffset>
                    <size>32</size>
                    <access>read-write</access>
                    <resetValue>0x00000000</resetValue>
                    <resetMask>0xffffffff</resetMask>
                    <fields>
                        <field>
                            <name>ARBS</name>
                            <description>Arbitration Select for &lt;slave&gt;</description>
                            <lsb>0</lsb>
                            <msb>1</msb>
                            <access>read-write</access>
                            <enumeratedValues>
                                <enumeratedValue>
                                    <name>00</name>
                                    <description>Fixed priority</description>
                                    <value>#00</value>
                                </enumeratedValue>
                                <enumeratedValue>
                                    <name>01</name>
                                    <description>Setting prohibited</description>
                                    <value>#01</value>
                                </enumeratedValue>
                                <enumeratedValue>
                                    <name>10</name>
                                    <description>Combination of round-robin and fixed priority</description>
                                    <value>#10</value>
                                </enumeratedValue>
                                <enumeratedValue>
                                    <name>11</name>
                                    <description>Round-robin</description>
                                    <value>#11</value>
                                </enumeratedValue>
                            </enumeratedValues>
                        </field>
                    </fields>
                </register>
                <register>
                    <name>BUSSABT1S1BI</name>
                    <description>Bus Slave Arbitration Control Register 1(x = FHBI, S0BI, S1BI)</description>
                    <addressOffset>0x1220</addressOffset>
                    <size>32</size>
                    <access>read-write</access>
                    <resetValue>0x00000000</resetValue>
                    <resetMask>0xffffffff</resetMask>
                    <fields>
                        <field>
                            <name>ARBS</name>
                            <description>Arbitration Select for &lt;slave&gt;</description>
                            <lsb>0</lsb>
                            <msb>1</msb>
                            <access>read-write</access>
                            <enumeratedValues>
                                <enumeratedValue>
                                    <name>00</name>
                                    <description>Fixed priority</description>
                                    <value>#00</value>
                                </enumeratedValue>
                                <enumeratedValue>
                                    <name>01</name>
                                    <description>Setting prohibited</description>
                                    <value>#01</value>
                                </enumeratedValue>
                                <enumeratedValue>
                                    <name>10</name>
                                    <description>Combination of round-robin and fixed priority</description>
                                    <value>#10</value>
                                </enumeratedValue>
                                <enumeratedValue>
                                    <name>11</name>
                                    <description>Round-robin</description>
                                    <value>#11</value>
                                </enumeratedValue>
                            </enumeratedValues>
                        </field>
                    </fields>
                </register>
                <register>
                    <name>BUSSABT0STBYSBI</name>
                    <description>Bus Slave Arbitration Control Register 0</description>
                    <addressOffset>0x1248</addressOffset>
                    <size>32</size>
                    <access>read-write</access>
                    <resetValue>0x00000000</resetValue>
                    <resetMask>0xffffffff</resetMask>
                    <fields>
                        <field>
                            <name>ARBS</name>
                            <description>Arbitration Select for &lt;slave&gt;</description>
                            <lsb>0</lsb>
                            <msb>0</msb>
                            <access>read-write</access>
                            <enumeratedValues>
                                <enumeratedValue>
                                    <name>0</name>
                                    <description>Fixed priority</description>
                                    <value>#0</value>
                                </enumeratedValue>
                                <enumeratedValue>
                                    <name>1</name>
                                    <description>Round-robin</description>
                                    <value>#1</value>
                                </enumeratedValue>
                            </enumeratedValues>
                        </field>
                    </fields>
                </register>
                <register>
                    <name>BUSSABT0ECBI</name>
                    <description>Bus Slave Arbitration Control Register 0</description>
                    <addressOffset>0x1250</addressOffset>
                    <size>32</size>
                    <access>read-write</access>
                    <resetValue>0x00000000</resetValue>
                    <resetMask>0xffffffff</resetMask>
                    <fields>
                        <field>
                            <name>ARBS</name>
                            <description>Arbitration Select for &lt;slave&gt;</description>
                            <lsb>0</lsb>
                            <msb>0</msb>
                            <access>read-write</access>
                            <enumeratedValues>
                                <enumeratedValue>
                                    <name>0</name>
                                    <description>Fixed priority</description>
                                    <value>#0</value>
                                </enumeratedValue>
                                <enumeratedValue>
                                    <name>1</name>
                                    <description>Round-robin</description>
                                    <value>#1</value>
                                </enumeratedValue>
                            </enumeratedValues>
                        </field>
                    </fields>
                </register>
                <register>
                    <name>BUSSABT0EOBI</name>
                    <description>Bus Slave Arbitration Control Register 0</description>
                    <addressOffset>0x1258</addressOffset>
                    <size>32</size>
                    <access>read-write</access>
                    <resetValue>0x00000000</resetValue>
                    <resetMask>0xffffffff</resetMask>
                    <fields>
                        <field>
                            <name>ARBS</name>
                            <description>Arbitration Select for &lt;slave&gt;</description>
                            <lsb>0</lsb>
                            <msb>0</msb>
                            <access>read-write</access>
                            <enumeratedValues>
                                <enumeratedValue>
                                    <name>0</name>
                                    <description>Fixed priority</description>
                                    <value>#0</value>
                                </enumeratedValue>
                                <enumeratedValue>
                                    <name>1</name>
                                    <description>Round-robin</description>
                                    <value>#1</value>
                                </enumeratedValue>
                            </enumeratedValues>
                        </field>
                    </fields>
                </register>
                <register>
                    <name>BUSSABT0PBBI</name>
                    <description>Bus Slave Arbitration Control Register 0</description>
                    <addressOffset>0x1260</addressOffset>
                    <size>32</size>
                    <access>read-write</access>
                    <resetValue>0x00000000</resetValue>
                    <resetMask>0xffffffff</resetMask>
                    <fields>
                        <field>
                            <name>ARBS</name>
                            <description>Arbitration Select for &lt;slave&gt;</description>
                            <lsb>0</lsb>
                            <msb>0</msb>
                            <access>read-write</access>
                            <enumeratedValues>
                                <enumeratedValue>
                                    <name>0</name>
                                    <description>Fixed priority</description>
                                    <value>#0</value>
                                </enumeratedValue>
                                <enumeratedValue>
                                    <name>1</name>
                                    <description>Round-robin</description>
                                    <value>#1</value>
                                </enumeratedValue>
                            </enumeratedValues>
                        </field>
                    </fields>
                </register>
                <register>
                    <name>BUSSABT0PABI</name>
                    <description>Bus Slave Arbitration Control Register 0</description>
                    <addressOffset>0x1268</addressOffset>
                    <size>32</size>
                    <access>read-write</access>
                    <resetValue>0x00000000</resetValue>
                    <resetMask>0xffffffff</resetMask>
                    <fields>
                        <field>
                            <name>ARBS</name>
                            <description>Arbitration Select for &lt;slave&gt;</description>
                            <lsb>0</lsb>
                            <msb>0</msb>
                            <access>read-write</access>
                            <enumeratedValues>
                                <enumeratedValue>
                                    <name>0</name>
                                    <description>Fixed priority</description>
                                    <value>#0</value>
                                </enumeratedValue>
                                <enumeratedValue>
                                    <name>1</name>
                                    <description>Round-robin</description>
                                    <value>#1</value>
                                </enumeratedValue>
                            </enumeratedValues>
                        </field>
                    </fields>
                </register>
                <register>
                    <name>BUSSABT0PIBI</name>
                    <description>Bus Slave Arbitration Control Register 0</description>
                    <addressOffset>0x1270</addressOffset>
                    <size>32</size>
                    <access>read-write</access>
                    <resetValue>0x00000000</resetValue>
                    <resetMask>0xffffffff</resetMask>
                    <fields>
                        <field>
                            <name>ARBS</name>
                            <description>Arbitration Select for &lt;slave&gt;</description>
                            <lsb>0</lsb>
                            <msb>0</msb>
                            <access>read-write</access>
                            <enumeratedValues>
                                <enumeratedValue>
                                    <name>0</name>
                                    <description>Fixed priority</description>
                                    <value>#0</value>
                                </enumeratedValue>
                                <enumeratedValue>
                                    <name>1</name>
                                    <description>Round-robin</description>
                                    <value>#1</value>
                                </enumeratedValue>
                            </enumeratedValues>
                        </field>
                    </fields>
                </register>
                <register>
                    <name>BUSSABT0PSBI</name>
                    <description>Bus Slave Arbitration Control Register 0</description>
                    <addressOffset>0x1278</addressOffset>
                    <size>32</size>
                    <access>read-write</access>
                    <resetValue>0x00000000</resetValue>
                    <resetMask>0xffffffff</resetMask>
                    <fields>
                        <field>
                            <name>ARBS</name>
                            <description>Arbitration Select for &lt;slave&gt;</description>
                            <lsb>0</lsb>
                            <msb>0</msb>
                            <access>read-write</access>
                            <enumeratedValues>
                                <enumeratedValue>
                                    <name>0</name>
                                    <description>Fixed priority</description>
                                    <value>#0</value>
                                </enumeratedValue>
                                <enumeratedValue>
                                    <name>1</name>
                                    <description>Round-robin</description>
                                    <value>#1</value>
                                </enumeratedValue>
                            </enumeratedValues>
                        </field>
                    </fields>
                </register>
                <register>
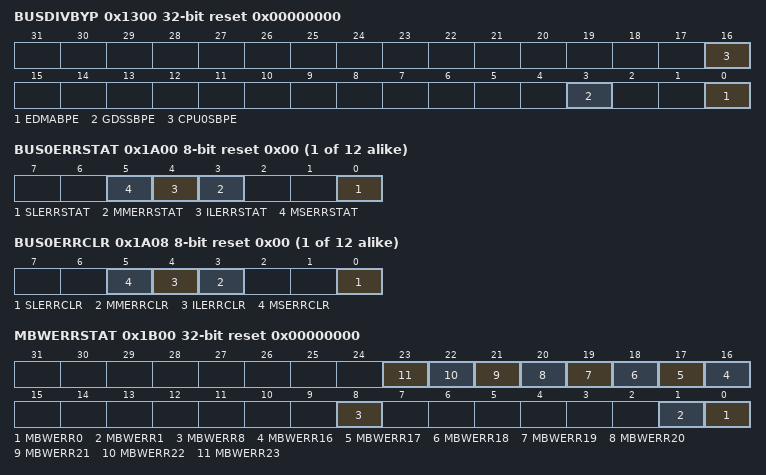
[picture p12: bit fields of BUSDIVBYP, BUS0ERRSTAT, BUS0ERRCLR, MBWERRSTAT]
                    <name>BUSDIVBYP</name>
                    <description>Bus Divider Bypass Register</description>
                    <addressOffset>0x1300</addressOffset>
                    <size>32</size>
                    <access>read-write</access>
                    <resetValue>0x00000000</resetValue>
                    <resetMask>0xffffffff</resetMask>
                    <fields>
                        <field>
                            <name>EDMABPE</name>
                            <description>Divider for EDMACBI bypass enable</description>
                            <lsb>0</lsb>
                            <msb>0</msb>
                            <access>read-write</access>
                            <enumeratedValues>
                                <enumeratedValue>
                                    <name>0</name>
                                    <description>Disable</description>
                                    <value>#0</value>
                                </enumeratedValue>
                                <enumeratedValue>
                                    <name>1</name>
                                    <description>Enable</description>
                                    <value>#1</value>
                                </enumeratedValue>
                            </enumeratedValues>
                        </field>
                        <field>
                            <name>GDSSBPE</name>
                            <description>Divider for GDSSBI bypass enable</description>
                            <lsb>3</lsb>
                            <msb>3</msb>
                            <access>read-write</access>
                            <enumeratedValues>
                                <enumeratedValue>
                                    <name>0</name>
                                    <description>Disable</description>
                                    <value>#0</value>
                                </enumeratedValue>
                                <enumeratedValue>
                                    <name>1</name>
                                    <description>Enable</description>
                                    <value>#1</value>
                                </enumeratedValue>
                            </enumeratedValues>
                        </field>
                        <field>
                            <name>CPU0SBPE</name>
                            <description>Divider for CPUSAHBI bypass enable</description>
                            <lsb>16</lsb>
                            <msb>16</msb>
                            <access>read-write</access>
                            <enumeratedValues>
                                <enumeratedValue>
                                    <name>0</name>
                                    <description>Disable</description>
                                    <value>#0</value>
                                </enumeratedValue>
                                <enumeratedValue>
                                    <name>1</name>
                                    <description>Enable</description>
                                    <value>#1</value>
                                </enumeratedValue>
                            </enumeratedValues>
                        </field>
                    </fields>
                </register>
                <register>
                    <dim>6</dim>
                    <dimIncrement>0x10</dimIncrement>
                    <dimIndex>4-9</dimIndex>
                    <name>BUS%sERRADD</name>
                    <description>BUS Error Address Register (n = 4 to 9 )</description>
                    <addressOffset>0x1800</addressOffset>
                    <size>32</size>
                    <access>read-only</access>
                    <resetValue>0x00000000</resetValue>
                    <resetMask>0xffffffff</resetMask>
                    <fields>
                        <field>
                            <name>BERAD</name>
                            <description>Bus Error Address</description>
                            <lsb>0</lsb>
                            <msb>31</msb>
                            <access>read-only</access>
                        </field>
                    </fields>
                </register>
                <register>
                    <dim>6</dim>
                    <dimIncrement>0x10</dimIncrement>
                    <dimIndex>4-9</dimIndex>
                    <name>BUS%sERRRW</name>
                    <description>BUS Error Read Write (n = 4 to 9)</description>
                    <addressOffset>0x1804</addressOffset>
                    <size>8</size>
                    <access>read-only</access>
                    <resetValue>0x00</resetValue>
                    <resetMask>0xff</resetMask>
                    <fields>
                        <field>
                            <name>RWSTAT</name>
                            <description>Error access Read/Write Status</description>
                            <lsb>0</lsb>
                            <msb>0</msb>
                            <access>read-only</access>
                            <enumeratedValues>
                                <enumeratedValue>
                                    <name>0</name>
                                    <description>Read access</description>
                                    <value>#0</value>
                                </enumeratedValue>
                                <enumeratedValue>
                                    <name>1</name>
                                    <description>Write access</description>
                                    <value>#1</value>
                                </enumeratedValue>
                            </enumeratedValues>
                        </field>
                    </fields>
                </register>
                <register>
                    <dim>6</dim>
                    <dimIncrement>0x10</dimIncrement>
                    <dimIndex>4-9</dimIndex>
                    <name>BMSA%sERRADD</name>
                    <description>Bus Master Security Attribution Unit Error Address (n = 4 to 9)</description>
                    <addressOffset>0x1900</addressOffset>
                    <size>32</size>
                    <access>read-only</access>
                    <resetValue>0x00000000</resetValue>
                    <resetMask>0xffffffff</resetMask>
                    <fields>
                        <field>
                            <name>MSERAD</name>
                            <description>Bus Master Security Attribution Unit Error Address</description>
                            <lsb>0</lsb>
                            <msb>31</msb>
                            <access>read-only</access>
                        </field>
                    </fields>
                </register>
                <register>
                    <dim>6</dim>
                    <dimIncrement>0x10</dimIncrement>
                    <dimIndex>4-9</dimIndex>
                    <name>BMSA%sERRRW</name>
                    <description>BUS Master Security Attribution Unit Error Read Write (n = 4 to 9)</description>
                    <addressOffset>0x1904</addressOffset>
                    <size>8</size>
                    <access>read-only</access>
                    <resetValue>0x00</resetValue>
                    <resetMask>0xff</resetMask>
                    <fields>
                        <field>
                            <name>MSARWSTAT</name>
                            <description>Master Security Attribution Unit error access Read/Write Status</description>
                            <lsb>0</lsb>
                            <msb>0</msb>
                            <access>read-only</access>
                            <enumeratedValues>
                                <enumeratedValue>
                                    <name>0</name>
                                    <description>Read access</description>
                                    <value>#0</value>
                                </enumeratedValue>
                                <enumeratedValue>
                                    <name>1</name>
                                    <description>Write access</description>
                                    <value>#1</value>
                                </enumeratedValue>
                            </enumeratedValues>
                        </field>
                    </fields>
                </register>
                <register>
                    <dim>12</dim>
                    <dimIncrement>0x10</dimIncrement>
                    <dimIndex>1-12</dimIndex>
                    <name>BUS%sERRSTAT</name>
                    <description>BUS Error Status Register</description>
                    <addressOffset>0x1A00</addressOffset>
                    <size>8</size>
                    <access>read-only</access>
                    <resetValue>0x00</resetValue>
                    <resetMask>0xff</resetMask>
                    <fields>
                        <field>
                            <name>SLERRSTAT</name>
                            <description>Slave Bus Error Status</description>
                            <lsb>0</lsb>
                            <msb>0</msb>
                            <access>read-only</access>
                            <enumeratedValues>
                                <enumeratedValue>
                                    <name>0</name>
                                    <description>No error occurred</description>
                                    <value>#0</value>
                                </enumeratedValue>
                                <enumeratedValue>
                                    <name>1</name>
                                    <description>Error occurred</description>
                                    <value>#1</value>
                                </enumeratedValue>
                            </enumeratedValues>
                        </field>
                        <field>
                            <name>MMERRSTAT</name>
                            <description>Master MPU Error Status</description>
                            <lsb>3</lsb>
                            <msb>3</msb>
                            <access>read-only</access>
                            <enumeratedValues>
                                <enumeratedValue>
                                    <name>0</name>
                                    <description>No error occurred</description>
                                    <value>#0</value>
                                </enumeratedValue>
                                <enumeratedValue>
                                    <name>1</name>
                                    <description>Error occurred</description>
                                    <value>#1</value>
                                </enumeratedValue>
                            </enumeratedValues>
                        </field>
                        <field>
                            <name>ILERRSTAT</name>
                            <description>Illegal Address Access Error Status</description>
                            <lsb>4</lsb>
                            <msb>4</msb>
                            <access>read-only</access>
                            <enumeratedValues>
                                <enumeratedValue>
                                    <name>0</name>
                                    <description>No error occurred</description>
                                    <value>#0</value>
                                </enumeratedValue>
                                <enumeratedValue>
                                    <name>1</name>
                                    <description>Error occurred</description>
                                    <value>#1</value>
                                </enumeratedValue>
                            </enumeratedValues>
                        </field>
                        <field>
                            <name>MSERRSTAT</name>
                            <description>Master Security Attribution Unit Error Status</description>
                            <lsb>5</lsb>
                            <msb>5</msb>
                            <access>read-only</access>
                            <enumeratedValues>
                                <enumeratedValue>
                                    <name>0</name>
                                    <description>No error occurred</description>
                                    <value>#0</value>
                                </enumeratedValue>
                                <enumeratedValue>
                                    <name>1</name>
                                    <description>Error occurred</description>
                                    <value>#1</value>
                                </enumeratedValue>
                            </enumeratedValues>
                        </field>
                    </fields>
                </register>
                <register>
                    <dim>12</dim>
                    <dimIncrement>0x10</dimIncrement>
                    <dimIndex>1-12</dimIndex>
                    <name>BUS%sERRCLR</name>
                    <description>BUS Error Clear Register</description>
                    <addressOffset>0x1A08</addressOffset>
                    <size>8</size>
                    <access>read-write</access>
                    <resetValue>0x00</resetValue>
                    <resetMask>0xff</resetMask>
                    <fields>
                        <field>
                            <name>SLERRCLR</name>
                            <description>Slave Bus Error Clear</description>
                            <lsb>0</lsb>
                            <msb>0</msb>
                            <access>read-write</access>
                        </field>
                        <field>
                            <name>MMERRCLR</name>
                            <description>Master MPU Error Clear</description>
                            <lsb>3</lsb>
                            <msb>3</msb>
                            <access>read-write</access>
                        </field>
                        <field>
                            <name>ILERRCLR</name>
                            <description>Illegal Address Access Error Clear</description>
                            <lsb>4</lsb>
                            <msb>4</msb>
                            <access>read-write</access>
                        </field>
                        <field>
                            <name>MSERRCLR</name>
                            <description>Master Security Attribution Unit Error Clear</description>
                            <lsb>5</lsb>
                            <msb>5</msb>
                            <access>read-write</access>
                        </field>
                    </fields>
                </register>
                <register>
                    <name>MBWERRSTAT</name>
                    <description>Master Bufferable Write Error Status Register</description>
                    <addressOffset>0x1B00</addressOffset>
                    <size>32</size>
                    <access>read-only</access>
                    <resetValue>0x00000000</resetValue>
                    <resetMask>0xffffffff</resetMask>
                    <fields>
                        <field>
                            <name>MBWERR0</name>
                            <description>Master Bufferable Write Error</description>
                            <lsb>0</lsb>
                            <msb>0</msb>
                            <access>read-only</access>
                            <enumeratedValues>
                                <enumeratedValue>
                                    <name>0</name>
                                    <description>No bufferable write error in Master #0</description>
                                    <value>#0</value>
                                </enumeratedValue>
                                <enumeratedValue>
                                    <name>1</name>
                                    <description>Bufferable write error occurs in Master #0</description>
                                    <value>#1</value>
                                </enumeratedValue>
                            </enumeratedValues>
                        </field>
                        <field>
                            <name>MBWERR1</name>
                            <description>Master Bufferable Write Error</description>
                            <lsb>1</lsb>
                            <msb>1</msb>
                            <access>read-only</access>
                            <enumeratedValues>
                                <enumeratedValue>
                                    <name>0</name>
                                    <description>No bufferable write error in Master #1</description>
                                    <value>#0</value>
                                </enumeratedValue>
                                <enumeratedValue>
                                    <name>1</name>
                                    <description>Bufferable write error occurs in Master #1</description>
                                    <value>#1</value>
                                </enumeratedValue>
                            </enumeratedValues>
                        </field>
                        <field>
                            <name>MBWERR8</name>
                            <description>Master Bufferable Write Error</description>
                            <lsb>8</lsb>
                            <msb>8</msb>
                            <access>read-only</access>
                            <enumeratedValues>
                                <enumeratedValue>
                                    <name>0</name>
                                    <description>No bufferable write error in Master #8</description>
                                    <value>#0</value>
                                </enumeratedValue>
                                <enumeratedValue>
                                    <name>1</name>
                                    <description>Bufferable write error occurs in Master #8</description>
                                    <value>#1</value>
                                </enumeratedValue>
                            </enumeratedValues>
                        </field>
                        <field>
                            <name>MBWERR16</name>
                            <description>Master Bufferable Write Error</description>
                            <lsb>16</lsb>
                            <msb>16</msb>
                            <access>read-only</access>
                            <enumeratedValues>
                                <enumeratedValue>
                                    <name>0</name>
                                    <description>No bufferable write error in Master #16</description>
                                    <value>#0</value>
                                </enumeratedValue>
                                <enumeratedValue>
                                    <name>1</name>
                                    <description>Bufferable write error occurs in Master #16</description>
                                    <value>#1</value>
                                </enumeratedValue>
                            </enumeratedValues>
                        </field>
                        <field>
                            <name>MBWERR17</name>
                            <description>Master Bufferable Write Error</description>
                            <lsb>17</lsb>
                            <msb>17</msb>
                            <access>read-only</access>
                            <enumeratedValues>
                                <enumeratedValue>
                                    <name>0</name>
                                    <description>No bufferable write error in Master #17</description>
                                    <value>#0</value>
                                </enumeratedValue>
                                <enumeratedValue>
                                    <name>1</name>
                                    <description>Bufferable write error occurs in Master #17</description>
                                    <value>#1</value>
                                </enumeratedValue>
                            </enumeratedValues>
                        </field>
                        <field>
                            <name>MBWERR18</name>
                            <description>Master Bufferable Write Error</description>
                            <lsb>18</lsb>
                            <msb>18</msb>
                            <access>read-only</access>
                            <enumeratedValues>
                                <enumeratedValue>
                                    <name>0</name>
                                    <description>No bufferable write error in Master #18</description>
                                    <value>#0</value>
                                </enumeratedValue>
                                <enumeratedValue>
                                    <name>1</name>
                                    <description>Bufferable write error occurs in Master #18</description>
                                    <value>#1</value>
                                </enumeratedValue>
                            </enumeratedValues>
                        </field>
                        <field>
                            <name>MBWERR19</name>
                            <description>Master Bufferable Write Error</description>
                            <lsb>19</lsb>
                            <msb>19</msb>
                            <access>read-only</access>
                            <enumeratedValues>
                                <enumeratedValue>
                                    <name>0</name>
                                    <description>No bufferable write error in Master #19</description>
                                    <value>#0</value>
                                </enumeratedValue>
                                <enumeratedValue>
                                    <name>1</name>
                                    <description>Bufferable write error occurs in Master #19</description>
                                    <value>#1</value>
                                </enumeratedValue>
                            </enumeratedValues>
                        </field>
                        <field>
                            <name>MBWERR20</name>
                            <description>Master Bufferable Write Error</description>
                            <lsb>20</lsb>
                            <msb>20</msb>
                            <access>read-only</access>
                            <enumeratedValues>
                                <enumeratedValue>
                                    <name>0</name>
                                    <description>No bufferable write error in Master #20</description>
                                    <value>#0</value>
                                </enumeratedValue>
                                <enumeratedValue>
                                    <name>1</name>
                                    <description>Bufferable write error occurs in Master #20</description>
                                    <value>#1</value>
                                </enumeratedValue>
                            </enumeratedValues>
                        </field>
                        <field>
                            <name>MBWERR21</name>
                            <description>Master Bufferable Write Error</description>
                            <lsb>21</lsb>
                            <msb>21</msb>
                            <access>read-only</access>
                            <enumeratedValues>
                                <enumeratedValue>
                                    <name>0</name>
                                    <description>No bufferable write error in Master #21</description>
                                    <value>#0</value>
                                </enumeratedValue>
                                <enumeratedValue>
                                    <name>1</name>
                                    <description>Bufferable write error occurs in Master #21</description>
                                    <value>#1</value>
                                </enumeratedValue>
                            </enumeratedValues>
                        </field>
                        <field>
                            <name>MBWERR22</name>
                            <description>Master Bufferable Write Error</description>
                            <lsb>22</lsb>
                            <msb>22</msb>
                            <access>read-only</access>
                            <enumeratedValues>
                                <enumeratedValue>
                                    <name>0</name>
                                    <description>No bufferable write error in Master #22</description>
                                    <value>#0</value>
                                </enumeratedValue>
                                <enumeratedValue>
                                    <name>1</name>
                                    <description>Bufferable write error occurs in Master #22</description>
                                    <value>#1</value>
                                </enumeratedValue>
                            </enumeratedValues>
                        </field>
                        <field>
                            <name>MBWERR23</name>
                            <description>Master Bufferable Write Error</description>
                            <lsb>23</lsb>
                            <msb>23</msb>
                            <access>read-only</access>
                            <enumeratedValues>
                                <enumeratedValue>
                                    <name>0</name>
                                    <description>No bufferable write error in Master #23</description>
                                    <value>#0</value>
                                </enumeratedValue>
                                <enumeratedValue>
                                    <name>1</name>
                                    <description>Bufferable write error occurs in Master #23</description>
                                    <value>#1</value>
                                </enumeratedValue>
                            </enumeratedValues>
                        </field>
                    </fields>
                </register>
                <register>
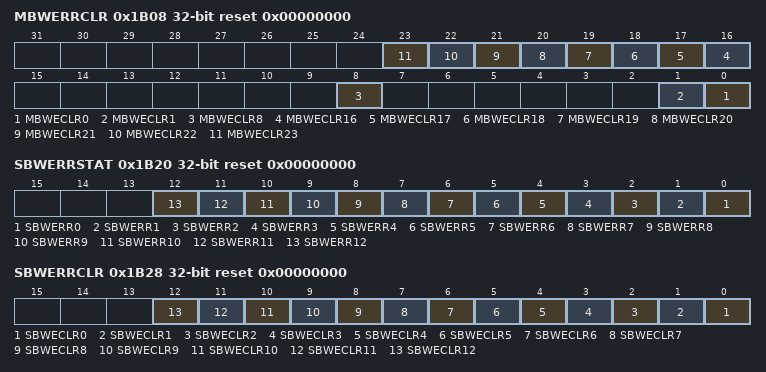
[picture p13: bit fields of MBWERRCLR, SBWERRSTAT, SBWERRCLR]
                    <name>MBWERRCLR</name>
                    <description>Master Bufferable Write Error Clear Register</description>
                    <addressOffset>0x1B08</addressOffset>
                    <size>32</size>
                    <access>read-write</access>
                    <resetValue>0x00000000</resetValue>
                    <resetMask>0xffffffff</resetMask>
                    <fields>
                        <field>
                            <name>MBWECLR0</name>
                            <description>Master Bufferable Write Error Clear</description>
                            <lsb>0</lsb>
                            <msb>0</msb>
                            <access>read-write</access>
                        </field>
                        <field>
                            <name>MBWECLR1</name>
                            <description>Master Bufferable Write Error Clear</description>
                            <lsb>1</lsb>
                            <msb>1</msb>
                            <access>read-write</access>
                        </field>
                        <field>
                            <name>MBWECLR8</name>
                            <description>Master Bufferable Write Error Clear</description>
                            <lsb>8</lsb>
                            <msb>8</msb>
                            <access>read-write</access>
                        </field>
                        <field>
                            <name>MBWECLR16</name>
                            <description>Master Bufferable Write Error Clear</description>
                            <lsb>16</lsb>
                            <msb>16</msb>
                            <access>read-write</access>
                        </field>
                        <field>
                            <name>MBWECLR17</name>
                            <description>Master Bufferable Write Error Clear</description>
                            <lsb>17</lsb>
                            <msb>17</msb>
                            <access>read-write</access>
                        </field>
                        <field>
                            <name>MBWECLR18</name>
                            <description>Master Bufferable Write Error Clear</description>
                            <lsb>18</lsb>
                            <msb>18</msb>
                            <access>read-write</access>
                        </field>
                        <field>
                            <name>MBWECLR19</name>
                            <description>Master Bufferable Write Error Clear</description>
                            <lsb>19</lsb>
                            <msb>19</msb>
                            <access>read-write</access>
                        </field>
                        <field>
                            <name>MBWECLR20</name>
                            <description>Master Bufferable Write Error Clear</description>
                            <lsb>20</lsb>
                            <msb>20</msb>
                            <access>read-write</access>
                        </field>
                        <field>
                            <name>MBWECLR21</name>
                            <description>Master Bufferable Write Error Clear</description>
                            <lsb>21</lsb>
                            <msb>21</msb>
                            <access>read-write</access>
                        </field>
                        <field>
                            <name>MBWECLR22</name>
                            <description>Master Bufferable Write Error Clear</description>
                            <lsb>22</lsb>
                            <msb>22</msb>
                            <access>read-write</access>
                        </field>
                        <field>
                            <name>MBWECLR23</name>
                            <description>Master Bufferable Write Error Clear</description>
                            <lsb>23</lsb>
                            <msb>23</msb>
                            <access>read-write</access>
                        </field>
                    </fields>
                </register>
                <register>
                    <name>SBWERRSTAT</name>
                    <description>Slave Bufferable Write Error Status Register</description>
                    <addressOffset>0x1B20</addressOffset>
                    <size>32</size>
                    <access>read-only</access>
                    <resetValue>0x00000000</resetValue>
                    <resetMask>0xffffffff</resetMask>
                    <fields>
                        <field>
                            <name>SBWERR0</name>
                            <description>Slave Bufferable Write Error</description>
                            <lsb>0</lsb>
                            <msb>0</msb>
                            <access>read-only</access>
                            <enumeratedValues>
                                <enumeratedValue>
                                    <name>0</name>
                                    <description>No bufferable write error in Slave #0</description>
                                    <value>#0</value>
                                </enumeratedValue>
                                <enumeratedValue>
                                    <name>1</name>
                                    <description>Bufferable write error occurs in Slave #0</description>
                                    <value>#1</value>
                                </enumeratedValue>
                            </enumeratedValues>
                        </field>
                        <field>
                            <name>SBWERR1</name>
                            <description>Slave Bufferable Write Error</description>
                            <lsb>1</lsb>
                            <msb>1</msb>
                            <access>read-only</access>
                            <enumeratedValues>
                                <enumeratedValue>
                                    <name>0</name>
                                    <description>No bufferable write error in Slave #1</description>
                                    <value>#0</value>
                                </enumeratedValue>
                                <enumeratedValue>
                                    <name>1</name>
                                    <description>Bufferable write error occurs in Slave #1</description>
                                    <value>#1</value>
                                </enumeratedValue>
                            </enumeratedValues>
                        </field>
                        <field>
                            <name>SBWERR2</name>
                            <description>Slave Bufferable Write Error</description>
                            <lsb>2</lsb>
                            <msb>2</msb>
                            <access>read-only</access>
                            <enumeratedValues>
                                <enumeratedValue>
                                    <name>0</name>
                                    <description>No bufferable write error in Slave #2</description>
                                    <value>#0</value>
                                </enumeratedValue>
                                <enumeratedValue>
                                    <name>1</name>
                                    <description>Bufferable write error occurs in Slave #2</description>
                                    <value>#1</value>
                                </enumeratedValue>
                            </enumeratedValues>
                        </field>
                        <field>
                            <name>SBWERR3</name>
                            <description>Slave Bufferable Write Error</description>
                            <lsb>3</lsb>
                            <msb>3</msb>
                            <access>read-only</access>
                            <enumeratedValues>
                                <enumeratedValue>
                                    <name>0</name>
                                    <description>No bufferable write error in Slave #3</description>
                                    <value>#0</value>
                                </enumeratedValue>
                                <enumeratedValue>
                                    <name>1</name>
                                    <description>Bufferable write error occurs in Slave #3</description>
                                    <value>#1</value>
                                </enumeratedValue>
                            </enumeratedValues>
                        </field>
                        <field>
                            <name>SBWERR4</name>
                            <description>Slave Bufferable Write Error</description>
                            <lsb>4</lsb>
                            <msb>4</msb>
                            <access>read-only</access>
                            <enumeratedValues>
                                <enumeratedValue>
                                    <name>0</name>
                                    <description>No bufferable write error in Slave #4</description>
                                    <value>#0</value>
                                </enumeratedValue>
                                <enumeratedValue>
                                    <name>1</name>
                                    <description>Bufferable write error occurs in Slave #4</description>
                                    <value>#1</value>
                                </enumeratedValue>
                            </enumeratedValues>
                        </field>
                        <field>
                            <name>SBWERR5</name>
                            <description>Slave Bufferable Write Error</description>
                            <lsb>5</lsb>
                            <msb>5</msb>
                            <access>read-only</access>
                            <enumeratedValues>
                                <enumeratedValue>
                                    <name>0</name>
                                    <description>No bufferable write error in Slave #5</description>
                                    <value>#0</value>
                                </enumeratedValue>
                                <enumeratedValue>
                                    <name>1</name>
                                    <description>Bufferable write error occurs in Slave #5</description>
                                    <value>#1</value>
                                </enumeratedValue>
                            </enumeratedValues>
                        </field>
                        <field>
                            <name>SBWERR6</name>
                            <description>Slave Bufferable Write Error</description>
                            <lsb>6</lsb>
                            <msb>6</msb>
                            <access>read-only</access>
                            <enumeratedValues>
                                <enumeratedValue>
                                    <name>0</name>
                                    <description>No bufferable write error in Slave #6</description>
                                    <value>#0</value>
                                </enumeratedValue>
                                <enumeratedValue>
                                    <name>1</name>
                                    <description>Bufferable write error occurs in Slave #6</description>
                                    <value>#1</value>
                                </enumeratedValue>
                            </enumeratedValues>
                        </field>
                        <field>
                            <name>SBWERR7</name>
                            <description>Slave Bufferable Write Error</description>
                            <lsb>7</lsb>
                            <msb>7</msb>
                            <access>read-only</access>
                            <enumeratedValues>
                                <enumeratedValue>
                                    <name>0</name>
                                    <description>No bufferable write error in Slave #7</description>
                                    <value>#0</value>
                                </enumeratedValue>
                                <enumeratedValue>
                                    <name>1</name>
                                    <description>Bufferable write error occurs in Slave #7</description>
                                    <value>#1</value>
                                </enumeratedValue>
                            </enumeratedValues>
                        </field>
                        <field>
                            <name>SBWERR8</name>
                            <description>Slave Bufferable Write Error</description>
                            <lsb>8</lsb>
                            <msb>8</msb>
                            <access>read-only</access>
                            <enumeratedValues>
                                <enumeratedValue>
                                    <name>0</name>
                                    <description>No bufferable write error in Slave #8</description>
                                    <value>#0</value>
                                </enumeratedValue>
                                <enumeratedValue>
                                    <name>1</name>
                                    <description>Bufferable write error occurs in Slave #8</description>
                                    <value>#1</value>
                                </enumeratedValue>
                            </enumeratedValues>
                        </field>
                        <field>
                            <name>SBWERR9</name>
                            <description>Slave Bufferable Write Error</description>
                            <lsb>9</lsb>
                            <msb>9</msb>
                            <access>read-only</access>
                            <enumeratedValues>
                                <enumeratedValue>
                                    <name>0</name>
                                    <description>No bufferable write error in Slave #9</description>
                                    <value>#0</value>
                                </enumeratedValue>
                                <enumeratedValue>
                                    <name>1</name>
                                    <description>Bufferable write error occurs in Slave #9</description>
                                    <value>#1</value>
                                </enumeratedValue>
                            </enumeratedValues>
                        </field>
                        <field>
                            <name>SBWERR10</name>
                            <description>Slave Bufferable Write Error</description>
                            <lsb>10</lsb>
                            <msb>10</msb>
                            <access>read-only</access>
                            <enumeratedValues>
                                <enumeratedValue>
                                    <name>0</name>
                                    <description>No bufferable write error in Slave #10</description>
                                    <value>#0</value>
                                </enumeratedValue>
                                <enumeratedValue>
                                    <name>1</name>
                                    <description>Bufferable write error occurs in Slave #10</description>
                                    <value>#1</value>
                                </enumeratedValue>
                            </enumeratedValues>
                        </field>
                        <field>
                            <name>SBWERR11</name>
                            <description>Slave Bufferable Write Error</description>
                            <lsb>11</lsb>
                            <msb>11</msb>
                            <access>read-only</access>
                            <enumeratedValues>
                                <enumeratedValue>
                                    <name>0</name>
                                    <description>No bufferable write error in Slave #11</description>
                                    <value>#0</value>
                                </enumeratedValue>
                                <enumeratedValue>
                                    <name>1</name>
                                    <description>Bufferable write error occurs in Slave #11</description>
                                    <value>#1</value>
                                </enumeratedValue>
                            </enumeratedValues>
                        </field>
                        <field>
                            <name>SBWERR12</name>
                            <description>Slave Bufferable Write Error</description>
                            <lsb>12</lsb>
                            <msb>12</msb>
                            <access>read-only</access>
                            <enumeratedValues>
                                <enumeratedValue>
                                    <name>0</name>
                                    <description>No bufferable write error in Slave #12</description>
                                    <value>#0</value>
                                </enumeratedValue>
                                <enumeratedValue>
                                    <name>1</name>
                                    <description>Bufferable write error occurs in Slave #12</description>
                                    <value>#1</value>
                                </enumeratedValue>
                            </enumeratedValues>
                        </field>
                    </fields>
                </register>
                <register>
                    <name>SBWERRCLR</name>
                    <description>Slave Bufferable Write Error Clear Register</description>
                    <addressOffset>0x1B28</addressOffset>
                    <size>32</size>
                    <access>read-write</access>
                    <resetValue>0x00000000</resetValue>
                    <resetMask>0xffffffff</resetMask>
                    <fields>
                        <field>
                            <name>SBWECLR0</name>
                            <description>Slave Bufferable Write Error Clear</description>
                            <lsb>0</lsb>
                            <msb>0</msb>
                            <access>read-write</access>
                        </field>
                        <field>
                            <name>SBWECLR1</name>
                            <description>Slave Bufferable Write Error Clear</description>
                            <lsb>1</lsb>
                            <msb>1</msb>
                            <access>read-write</access>
                        </field>
                        <field>
                            <name>SBWECLR2</name>
                            <description>Slave Bufferable Write Error Clear</description>
                            <lsb>2</lsb>
                            <msb>2</msb>
                            <access>read-write</access>
                        </field>
                        <field>
                            <name>SBWECLR3</name>
                            <description>Slave Bufferable Write Error Clear</description>
                            <lsb>3</lsb>
                            <msb>3</msb>
                            <access>read-write</access>
                        </field>
                        <field>
                            <name>SBWECLR4</name>
                            <description>Slave Bufferable Write Error Clear</description>
                            <lsb>4</lsb>
                            <msb>4</msb>
                            <access>read-write</access>
                        </field>
                        <field>
                            <name>SBWECLR5</name>
                            <description>Slave Bufferable Write Error Clear</description>
                            <lsb>5</lsb>
                            <msb>5</msb>
                            <access>read-write</access>
                        </field>
                        <field>
                            <name>SBWECLR6</name>
                            <description>Slave Bufferable Write Error Clear</description>
                            <lsb>6</lsb>
                            <msb>6</msb>
                            <access>read-write</access>
                        </field>
                        <field>
                            <name>SBWECLR7</name>
                            <description>Slave Bufferable Write Error Clear</description>
                            <lsb>7</lsb>
                            <msb>7</msb>
                            <access>read-write</access>
                        </field>
                        <field>
                            <name>SBWECLR8</name>
                            <description>Slave Bufferable Write Error Clear</description>
                            <lsb>8</lsb>
                            <msb>8</msb>
                            <access>read-write</access>
                        </field>
                        <field>
                            <name>SBWECLR9</name>
                            <description>Slave Bufferable Write Error Clear</description>
                            <lsb>9</lsb>
                            <msb>9</msb>
                            <access>read-write</access>
                        </field>
                        <field>
                            <name>SBWECLR10</name>
                            <description>Slave Bufferable Write Error Clear</description>
                            <lsb>10</lsb>
                            <msb>10</msb>
                            <access>read-write</access>
                        </field>
                        <field>
                            <name>SBWECLR11</name>
                            <description>Slave Bufferable Write Error Clear</description>
                            <lsb>11</lsb>
                            <msb>11</msb>
                            <access>read-write</access>
                        </field>
                        <field>
                            <name>SBWECLR12</name>
                            <description>Slave Bufferable Write Error Clear</description>
                            <lsb>12</lsb>
                            <msb>12</msb>
                            <access>read-write</access>
                        </field>
                    </fields>
                </register>
            </registers>
        </peripheral>
        <peripheral>
            <name>ICU_COMMON</name>
            <description>Interrupt Controller</description>
            <baseAddress>0x40006000</baseAddress>
            <addressBlock>
                <offset>0x00</offset>
                <size>17</size>
                <usage>registers</usage>
            </addressBlock>
            <registers>
                <register>
                    <dim>16</dim>
                    <dimIncrement>0x1</dimIncrement>
                    <dimIndex>0-15</dimIndex>
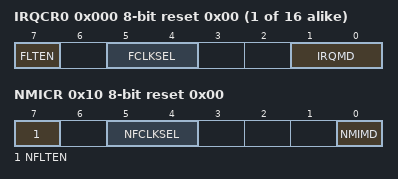
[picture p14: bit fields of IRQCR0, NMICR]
                    <name>IRQCR%s</name>
                    <description>IRQ Control Register %s</description>
                    <addressOffset>0x000</addressOffset>
                    <size>8</size>
                    <access>read-write</access>
                    <resetValue>0x00</resetValue>
                    <resetMask>0xff</resetMask>
                    <fields>
                        <field>
                            <name>IRQMD</name>
                            <description>IRQi Detection Sense Select</description>
                            <lsb>0</lsb>
                            <msb>1</msb>
                            <access>read-write</access>
                            <enumeratedValues>
                                <enumeratedValue>
                                    <name>00</name>
                                    <description>Falling edge</description>
                                    <value>#00</value>
                                </enumeratedValue>
                                <enumeratedValue>
                                    <name>01</name>
                                    <description>Rising edge</description>
                                    <value>#01</value>
                                </enumeratedValue>
                                <enumeratedValue>
                                    <name>10</name>
                                    <description>Rising and falling edges</description>
                                    <value>#10</value>
                                </enumeratedValue>
                                <enumeratedValue>
                                    <name>11</name>
                                    <description>Low level</description>
                                    <value>#11</value>
                                </enumeratedValue>
                            </enumeratedValues>
                        </field>
                        <field>
                            <name>FCLKSEL</name>
                            <description>IRQi Digital Filter Sampling Clock Select</description>
                            <lsb>4</lsb>
                            <msb>5</msb>
                            <access>read-write</access>
                            <enumeratedValues>
                                <enumeratedValue>
                                    <name>00</name>
                                    <description>PCLKB</description>
                                    <value>#00</value>
                                </enumeratedValue>
                                <enumeratedValue>
                                    <name>01</name>
                                    <description>PCLKB/8</description>
                                    <value>#01</value>
                                </enumeratedValue>
                                <enumeratedValue>
                                    <name>10</name>
                                    <description>PCLKB/32</description>
                                    <value>#10</value>
                                </enumeratedValue>
                                <enumeratedValue>
                                    <name>11</name>
                                    <description>PCLKB/64</description>
                                    <value>#11</value>
                                </enumeratedValue>
                            </enumeratedValues>
                        </field>
                        <field>
                            <name>FLTEN</name>
                            <description>IRQi Digital Filter Enable</description>
                            <lsb>7</lsb>
                            <msb>7</msb>
                            <access>read-write</access>
                            <enumeratedValues>
                                <enumeratedValue>
                                    <name>0</name>
                                    <description>Digital filter is disabled</description>
                                    <value>#0</value>
                                </enumeratedValue>
                                <enumeratedValue>
                                    <name>1</name>
                                    <description>Digital filter is enabled.</description>
                                    <value>#1</value>
                                </enumeratedValue>
                            </enumeratedValues>
                        </field>
                    </fields>
                </register>
                <register>
                    <name>NMICR</name>
                    <description>NMI Pin Interrupt Control Register</description>
                    <addressOffset>0x10</addressOffset>
                    <size>8</size>
                    <access>read-write</access>
                    <resetValue>0x00</resetValue>
                    <resetMask>0xff</resetMask>
                    <fields>
                        <field>
                            <name>NMIMD</name>
                            <description>NMI Detection Set</description>
                            <lsb>0</lsb>
                            <msb>0</msb>
                            <access>read-write</access>
                            <enumeratedValues>
                                <enumeratedValue>
                                    <name>0</name>
                                    <description>Falling edge</description>
                                    <value>#0</value>
                                </enumeratedValue>
                                <enumeratedValue>
                                    <name>1</name>
                                    <description>Rising edge</description>
                                    <value>#1</value>
                                </enumeratedValue>
                            </enumeratedValues>
                        </field>
                        <field>
                            <name>NFCLKSEL</name>
                            <description>NMI Digital Filter Sampling Clock Select</description>
                            <lsb>4</lsb>
                            <msb>5</msb>
                            <access>read-write</access>
                            <enumeratedValues>
                                <enumeratedValue>
                                    <name>00</name>
                                    <description>PCLKB</description>
                                    <value>#00</value>
                                </enumeratedValue>
                                <enumeratedValue>
                                    <name>01</name>
                                    <description>PCLKB/8</description>
                                    <value>#01</value>
                                </enumeratedValue>
                                <enumeratedValue>
                                    <name>10</name>
                                    <description>PCLKB/32</description>
                                    <value>#10</value>
                                </enumeratedValue>
                                <enumeratedValue>
                                    <name>11</name>
                                    <description>PCLKB/64</description>
                                    <value>#11</value>
                                </enumeratedValue>
                            </enumeratedValues>
                        </field>
                        <field>
                            <name>NFLTEN</name>
                            <description>NMI Digital Filter Enable</description>
                            <lsb>7</lsb>
                            <msb>7</msb>
                            <access>read-write</access>
                            <enumeratedValues>
                                <enumeratedValue>
                                    <name>0</name>
                                    <description>Disabled</description>
                                    <value>#0</value>
                                </enumeratedValue>
                                <enumeratedValue>
                                    <name>1</name>
                                    <description>Enabled</description>
                                    <value>#1</value>
                                </enumeratedValue>
                            </enumeratedValues>
                        </field>
                    </fields>
                </register>
            </registers>
        </peripheral>
        <peripheral>
            <name>CPSCU</name>
            <description>CPU System Security Control Unit</description>
            <baseAddress>0x40008000</baseAddress>
            <addressBlock>
                <offset>0x10</offset>
                <size>4</size>
                <usage>registers</usage>
            </addressBlock>
            <addressBlock>
                <offset>0x30</offset>
                <size>8</size>
                <usage>registers</usage>
            </addressBlock>
            <addressBlock>
                <offset>0x40</offset>
                <size>8</size>
                <usage>registers</usage>
            </addressBlock>
            <addressBlock>
                <offset>0x50</offset>
                <size>8</size>
                <usage>registers</usage>
            </addressBlock>
            <addressBlock>
                <offset>0x70</offset>
                <size>12</size>
                <usage>registers</usage>
            </addressBlock>
            <addressBlock>
                <offset>0x100</offset>
                <size>8</size>
                <usage>registers</usage>
            </addressBlock>
            <addressBlock>
                <offset>0x110</offset>
                <size>8</size>
                <usage>registers</usage>
            </addressBlock>
            <addressBlock>
                <offset>0x130</offset>
                <size>8</size>
                <usage>registers</usage>
            </addressBlock>
            <addressBlock>
                <offset>0x170</offset>
                <size>4</size>
                <usage>registers</usage>
            </addressBlock>
            <addressBlock>
                <offset>0x180</offset>
                <size>4</size>
                <usage>registers</usage>
            </addressBlock>
            <addressBlock>
                <offset>0x1A0</offset>
                <size>4</size>
                <usage>registers</usage>
            </addressBlock>
            <addressBlock>
                <offset>0x1F0</offset>
                <size>4</size>
                <usage>registers</usage>
            </addressBlock>
            <addressBlock>
                <offset>0x400</offset>
                <size>8</size>
                <usage>registers</usage>
            </addressBlock>
            <addressBlock>
                <offset>0x420</offset>
                <size>4</size>
                <usage>registers</usage>
            </addressBlock>
            <addressBlock>
                <offset>0x494</offset>
                <size>4</size>
                <usage>registers</usage>
            </addressBlock>
            <addressBlock>
                <offset>0x600</offset>
                <size>4</size>
                <usage>registers</usage>
            </addressBlock>
            <registers>
                <register>
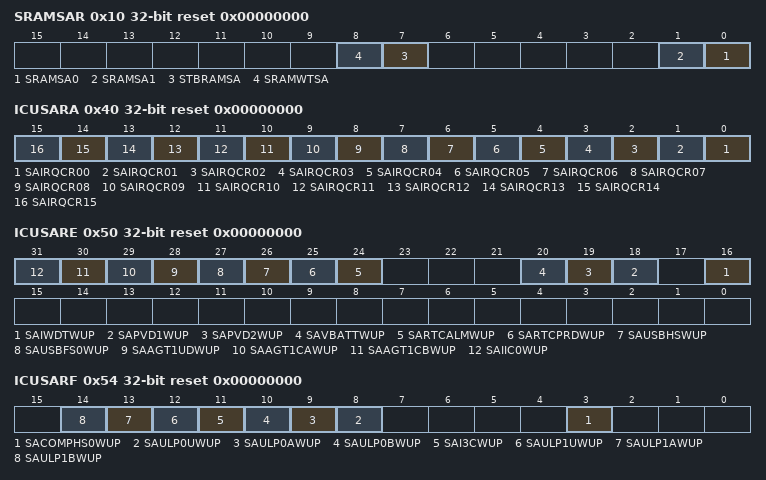
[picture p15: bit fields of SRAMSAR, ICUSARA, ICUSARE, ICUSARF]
                    <name>SRAMSAR</name>
                    <description>SRAM Security Attribution Register</description>
                    <addressOffset>0x10</addressOffset>
                    <size>32</size>
                    <access>read-write</access>
                    <resetValue>0x00000000</resetValue>
                    <resetMask>0xffffffff</resetMask>
                    <fields>
                        <field>
                            <name>SRAMSA0</name>
                            <description>SRAM0 Register Security Attribution</description>
                            <lsb>0</lsb>
                            <msb>0</msb>
                            <access>read-write</access>
                            <enumeratedValues>
                                <enumeratedValue>
                                    <name>0</name>
                                    <description>Secure</description>
                                    <value>#0</value>
                                </enumeratedValue>
                                <enumeratedValue>
                                    <name>1</name>
                                    <description>Non-secure</description>
                                    <value>#1</value>
                                </enumeratedValue>
                            </enumeratedValues>
                        </field>
                        <field>
                            <name>SRAMSA1</name>
                            <description>SRAM1 Register Security Attribution</description>
                            <lsb>1</lsb>
                            <msb>1</msb>
                            <access>read-write</access>
                            <enumeratedValues>
                                <enumeratedValue>
                                    <name>0</name>
                                    <description>Secure</description>
                                    <value>#0</value>
                                </enumeratedValue>
                                <enumeratedValue>
                                    <name>1</name>
                                    <description>Non-secure</description>
                                    <value>#1</value>
                                </enumeratedValue>
                            </enumeratedValues>
                        </field>
                        <field>
                            <name>STBRAMSA</name>
                            <description>Standby SRAM Register Security Attribution</description>
                            <lsb>7</lsb>
                            <msb>7</msb>
                            <access>read-write</access>
                            <enumeratedValues>
                                <enumeratedValue>
                                    <name>0</name>
                                    <description>Secure</description>
                                    <value>#0</value>
                                </enumeratedValue>
                                <enumeratedValue>
                                    <name>1</name>
                                    <description>Non-secure</description>
                                    <value>#1</value>
                                </enumeratedValue>
                            </enumeratedValues>
                        </field>
                        <field>
                            <name>SRAMWTSA</name>
                            <description>SRAMWTSC Security Attribution</description>
                            <lsb>8</lsb>
                            <msb>8</msb>
                            <access>read-write</access>
                            <enumeratedValues>
                                <enumeratedValue>
                                    <name>0</name>
                                    <description>Secure</description>
                                    <value>#0</value>
                                </enumeratedValue>
                                <enumeratedValue>
                                    <name>1</name>
                                    <description>Non-secure</description>
                                    <value>#1</value>
                                </enumeratedValue>
                            </enumeratedValues>
                        </field>
                    </fields>
                </register>
                <register>
                    <name>DTCSAR</name>
                    <description>DTC Controller Security Attribution Register</description>
                    <addressOffset>0x30</addressOffset>
                    <size>32</size>
                    <access>read-write</access>
                    <resetValue>0x00000000</resetValue>
                    <resetMask>0xffffffff</resetMask>
                    <fields>
                        <field>
                            <name>DTCSTSA</name>
                            <description>DTC Security Attribution</description>
                            <lsb>0</lsb>
                            <msb>0</msb>
                            <access>read-write</access>
                            <enumeratedValues>
                                <enumeratedValue>
                                    <name>0</name>
                                    <description>Secure.</description>
                                    <value>#0</value>
                                </enumeratedValue>
                                <enumeratedValue>
                                    <name>1</name>
                                    <description>Non-secure.</description>
                                    <value>#1</value>
                                </enumeratedValue>
                            </enumeratedValues>
                        </field>
                    </fields>
                </register>
                <register>
                    <name>DMACSAR</name>
                    <description>DMAC Controller Security Attribution Register</description>
                    <addressOffset>0x34</addressOffset>
                    <size>32</size>
                    <access>read-write</access>
                    <resetValue>0x00000000</resetValue>
                    <resetMask>0xffffffff</resetMask>
                    <fields>
                        <field>
                            <name>DMASTSA</name>
                            <description>DMAST Security Attribution</description>
                            <lsb>0</lsb>
                            <msb>0</msb>
                            <access>read-write</access>
                            <enumeratedValues>
                                <enumeratedValue>
                                    <name>0</name>
                                    <description>Secure</description>
                                    <value>#0</value>
                                </enumeratedValue>
                                <enumeratedValue>
                                    <name>1</name>
                                    <description>Non-secure</description>
                                    <value>#1</value>
                                </enumeratedValue>
                            </enumeratedValues>
                        </field>
                    </fields>
                </register>
                <register>
                    <name>ICUSARA</name>
                    <description>Interrupt Controller Unit Security Attribution Register A</description>
                    <addressOffset>0x40</addressOffset>
                    <size>32</size>
                    <access>read-write</access>
                    <resetValue>0x00000000</resetValue>
                    <resetMask>0xffffffff</resetMask>
                    <fields>
                        <field>
                            <name>SAIRQCR00</name>
                            <description>Security attributes of registers for the IRQCRn register</description>
                            <lsb>0</lsb>
                            <msb>0</msb>
                            <access>read-write</access>
                            <enumeratedValues>
                                <enumeratedValue>
                                    <name>0</name>
                                    <description>Secure</description>
                                    <value>#0</value>
                                </enumeratedValue>
                                <enumeratedValue>
                                    <name>1</name>
                                    <description>Non-secure</description>
                                    <value>#1</value>
                                </enumeratedValue>
                            </enumeratedValues>
                        </field>
                        <field>
                            <name>SAIRQCR01</name>
                            <description>Security attributes of registers for the IRQCRn register</description>
                            <lsb>1</lsb>
                            <msb>1</msb>
                            <access>read-write</access>
                            <enumeratedValues>
                                <enumeratedValue>
                                    <name>0</name>
                                    <description>Secure</description>
                                    <value>#0</value>
                                </enumeratedValue>
                                <enumeratedValue>
                                    <name>1</name>
                                    <description>Non-secure</description>
                                    <value>#1</value>
                                </enumeratedValue>
                            </enumeratedValues>
                        </field>
                        <field>
                            <name>SAIRQCR02</name>
                            <description>Security attributes of registers for the IRQCRn register</description>
                            <lsb>2</lsb>
                            <msb>2</msb>
                            <access>read-write</access>
                            <enumeratedValues>
                                <enumeratedValue>
                                    <name>0</name>
                                    <description>Secure</description>
                                    <value>#0</value>
                                </enumeratedValue>
                                <enumeratedValue>
                                    <name>1</name>
                                    <description>Non-secure</description>
                                    <value>#1</value>
                                </enumeratedValue>
                            </enumeratedValues>
                        </field>
                        <field>
                            <name>SAIRQCR03</name>
                            <description>Security attributes of registers for the IRQCRn register</description>
                            <lsb>3</lsb>
                            <msb>3</msb>
                            <access>read-write</access>
                            <enumeratedValues>
                                <enumeratedValue>
                                    <name>0</name>
                                    <description>Secure</description>
                                    <value>#0</value>
                                </enumeratedValue>
                                <enumeratedValue>
                                    <name>1</name>
                                    <description>Non-secure</description>
                                    <value>#1</value>
                                </enumeratedValue>
                            </enumeratedValues>
                        </field>
                        <field>
                            <name>SAIRQCR04</name>
                            <description>Security attributes of registers for the IRQCRn register</description>
                            <lsb>4</lsb>
                            <msb>4</msb>
                            <access>read-write</access>
                            <enumeratedValues>
                                <enumeratedValue>
                                    <name>0</name>
                                    <description>Secure</description>
                                    <value>#0</value>
                                </enumeratedValue>
                                <enumeratedValue>
                                    <name>1</name>
                                    <description>Non-secure</description>
                                    <value>#1</value>
                                </enumeratedValue>
                            </enumeratedValues>
                        </field>
                        <field>
                            <name>SAIRQCR05</name>
                            <description>Security attributes of registers for the IRQCRn register</description>
                            <lsb>5</lsb>
                            <msb>5</msb>
                            <access>read-write</access>
                            <enumeratedValues>
                                <enumeratedValue>
                                    <name>0</name>
                                    <description>Secure</description>
                                    <value>#0</value>
                                </enumeratedValue>
                                <enumeratedValue>
                                    <name>1</name>
                                    <description>Non-secure</description>
                                    <value>#1</value>
                                </enumeratedValue>
                            </enumeratedValues>
                        </field>
                        <field>
                            <name>SAIRQCR06</name>
                            <description>Security attributes of registers for the IRQCRn register</description>
                            <lsb>6</lsb>
                            <msb>6</msb>
                            <access>read-write</access>
                            <enumeratedValues>
                                <enumeratedValue>
                                    <name>0</name>
                                    <description>Secure</description>
                                    <value>#0</value>
                                </enumeratedValue>
                                <enumeratedValue>
                                    <name>1</name>
                                    <description>Non-secure</description>
                                    <value>#1</value>
                                </enumeratedValue>
                            </enumeratedValues>
                        </field>
                        <field>
                            <name>SAIRQCR07</name>
                            <description>Security attributes of registers for the IRQCRn register</description>
                            <lsb>7</lsb>
                            <msb>7</msb>
                            <access>read-write</access>
                            <enumeratedValues>
                                <enumeratedValue>
                                    <name>0</name>
                                    <description>Secure</description>
                                    <value>#0</value>
                                </enumeratedValue>
                                <enumeratedValue>
                                    <name>1</name>
                                    <description>Non-secure</description>
                                    <value>#1</value>
                                </enumeratedValue>
                            </enumeratedValues>
                        </field>
                        <field>
                            <name>SAIRQCR08</name>
                            <description>Security attributes of registers for the IRQCRn register</description>
                            <lsb>8</lsb>
                            <msb>8</msb>
                            <access>read-write</access>
                            <enumeratedValues>
                                <enumeratedValue>
                                    <name>0</name>
                                    <description>Secure</description>
                                    <value>#0</value>
                                </enumeratedValue>
                                <enumeratedValue>
                                    <name>1</name>
                                    <description>Non-secure</description>
                                    <value>#1</value>
                                </enumeratedValue>
                            </enumeratedValues>
                        </field>
                        <field>
                            <name>SAIRQCR09</name>
                            <description>Security attributes of registers for the IRQCRn register</description>
                            <lsb>9</lsb>
                            <msb>9</msb>
                            <access>read-write</access>
                            <enumeratedValues>
                                <enumeratedValue>
                                    <name>0</name>
                                    <description>Secure</description>
                                    <value>#0</value>
                                </enumeratedValue>
                                <enumeratedValue>
                                    <name>1</name>
                                    <description>Non-secure</description>
                                    <value>#1</value>
                                </enumeratedValue>
                            </enumeratedValues>
                        </field>
                        <field>
                            <name>SAIRQCR10</name>
                            <description>Security attributes of registers for the IRQCRn register</description>
                            <lsb>10</lsb>
                            <msb>10</msb>
                            <access>read-write</access>
                            <enumeratedValues>
                                <enumeratedValue>
                                    <name>0</name>
                                    <description>Secure</description>
                                    <value>#0</value>
                                </enumeratedValue>
                                <enumeratedValue>
                                    <name>1</name>
                                    <description>Non-secure</description>
                                    <value>#1</value>
                                </enumeratedValue>
                            </enumeratedValues>
                        </field>
                        <field>
                            <name>SAIRQCR11</name>
                            <description>Security attributes of registers for the IRQCRn register</description>
                            <lsb>11</lsb>
                            <msb>11</msb>
                            <access>read-write</access>
                            <enumeratedValues>
                                <enumeratedValue>
                                    <name>0</name>
                                    <description>Secure</description>
                                    <value>#0</value>
                                </enumeratedValue>
                                <enumeratedValue>
                                    <name>1</name>
                                    <description>Non-secure</description>
                                    <value>#1</value>
                                </enumeratedValue>
                            </enumeratedValues>
                        </field>
                        <field>
                            <name>SAIRQCR12</name>
                            <description>Security attributes of registers for the IRQCRn register</description>
                            <lsb>12</lsb>
                            <msb>12</msb>
                            <access>read-write</access>
                            <enumeratedValues>
                                <enumeratedValue>
                                    <name>0</name>
                                    <description>Secure</description>
                                    <value>#0</value>
                                </enumeratedValue>
                                <enumeratedValue>
                                    <name>1</name>
                                    <description>Non-secure</description>
                                    <value>#1</value>
                                </enumeratedValue>
                            </enumeratedValues>
                        </field>
                        <field>
                            <name>SAIRQCR13</name>
                            <description>Security attributes of registers for the IRQCRn register</description>
                            <lsb>13</lsb>
                            <msb>13</msb>
                            <access>read-write</access>
                            <enumeratedValues>
                                <enumeratedValue>
                                    <name>0</name>
                                    <description>Secure</description>
                                    <value>#0</value>
                                </enumeratedValue>
                                <enumeratedValue>
                                    <name>1</name>
                                    <description>Non-secure</description>
                                    <value>#1</value>
                                </enumeratedValue>
                            </enumeratedValues>
                        </field>
                        <field>
                            <name>SAIRQCR14</name>
                            <description>Security attributes of registers for the IRQCRn register</description>
                            <lsb>14</lsb>
                            <msb>14</msb>
                            <access>read-write</access>
                            <enumeratedValues>
                                <enumeratedValue>
                                    <name>0</name>
                                    <description>Secure</description>
                                    <value>#0</value>
                                </enumeratedValue>
                                <enumeratedValue>
                                    <name>1</name>
                                    <description>Non-secure</description>
                                    <value>#1</value>
                                </enumeratedValue>
                            </enumeratedValues>
                        </field>
                        <field>
                            <name>SAIRQCR15</name>
                            <description>Security attributes of registers for the IRQCRn register</description>
                            <lsb>15</lsb>
                            <msb>15</msb>
                            <access>read-write</access>
                            <enumeratedValues>
                                <enumeratedValue>
                                    <name>0</name>
                                    <description>Secure</description>
                                    <value>#0</value>
                                </enumeratedValue>
                                <enumeratedValue>
                                    <name>1</name>
                                    <description>Non-secure</description>
                                    <value>#1</value>
                                </enumeratedValue>
                            </enumeratedValues>
                        </field>
                    </fields>
                </register>
                <register>
                    <name>ICUSARB</name>
                    <description>Interrupt Controller Unit Security Attribution Register B</description>
                    <addressOffset>0x44</addressOffset>
                    <size>32</size>
                    <access>read-write</access>
                    <resetValue>0x00000000</resetValue>
                    <resetMask>0xffffffff</resetMask>
                    <fields>
                        <field>
                            <name>SANMI</name>
                            <description>Security attributes of registers for nonmaskable interrupt</description>
                            <lsb>0</lsb>
                            <msb>0</msb>
                            <access>read-write</access>
                            <enumeratedValues>
                                <enumeratedValue>
                                    <name>0</name>
                                    <description>Secure</description>
                                    <value>#0</value>
                                </enumeratedValue>
                                <enumeratedValue>
                                    <name>1</name>
                                    <description>Non-secure</description>
                                    <value>#1</value>
                                </enumeratedValue>
                            </enumeratedValues>
                        </field>
                    </fields>
                </register>
                <register>
                    <name>ICUSARE</name>
                    <description>Interrupt Controller Unit Security Attribution Register E</description>
                    <addressOffset>0x50</addressOffset>
                    <size>32</size>
                    <access>read-write</access>
                    <resetValue>0x00000000</resetValue>
                    <resetMask>0xffffffff</resetMask>
                    <fields>
                        <field>
                            <name>SAIWDTWUP</name>
                            <description>Security attributes of registers for WUPEN0.b16</description>
                            <lsb>16</lsb>
                            <msb>16</msb>
                            <access>read-write</access>
                            <enumeratedValues>
                                <enumeratedValue>
                                    <name>0</name>
                                    <description>Secure</description>
                                    <value>#0</value>
                                </enumeratedValue>
                                <enumeratedValue>
                                    <name>1</name>
                                    <description>Non-secure</description>
                                    <value>#1</value>
                                </enumeratedValue>
                            </enumeratedValues>
                        </field>
                        <field>
                            <name>SAPVD1WUP</name>
                            <description>Security attributes of registers for WUPEN0.b18</description>
                            <lsb>18</lsb>
                            <msb>18</msb>
                            <access>read-write</access>
                            <enumeratedValues>
                                <enumeratedValue>
                                    <name>0</name>
                                    <description>Secure</description>
                                    <value>#0</value>
                                </enumeratedValue>
                                <enumeratedValue>
                                    <name>1</name>
                                    <description>Non-secure</description>
                                    <value>#1</value>
                                </enumeratedValue>
                            </enumeratedValues>
                        </field>
                        <field>
                            <name>SAPVD2WUP</name>
                            <description>Security attributes of registers for WUPEN0.b19</description>
                            <lsb>19</lsb>
                            <msb>19</msb>
                            <access>read-write</access>
                            <enumeratedValues>
                                <enumeratedValue>
                                    <name>0</name>
                                    <description>Secure</description>
                                    <value>#0</value>
                                </enumeratedValue>
                                <enumeratedValue>
                                    <name>1</name>
                                    <description>Non-secure</description>
                                    <value>#1</value>
                                </enumeratedValue>
                            </enumeratedValues>
                        </field>
                        <field>
                            <name>SAVBATTWUP</name>
                            <description>Security attributes of registers for WUPEN0.b20</description>
                            <lsb>20</lsb>
                            <msb>20</msb>
                            <access>read-write</access>
                            <enumeratedValues>
                                <enumeratedValue>
                                    <name>0</name>
                                    <description>Secure</description>
                                    <value>#0</value>
                                </enumeratedValue>
                                <enumeratedValue>
                                    <name>1</name>
                                    <description>Non-secure</description>
                                    <value>#1</value>
                                </enumeratedValue>
                            </enumeratedValues>
                        </field>
                        <field>
                            <name>SARTCALMWUP</name>
                            <description>Security attributes of registers for WUPEN0.b24</description>
                            <lsb>24</lsb>
                            <msb>24</msb>
                            <access>read-write</access>
                            <enumeratedValues>
                                <enumeratedValue>
                                    <name>0</name>
                                    <description>Secure</description>
                                    <value>#0</value>
                                </enumeratedValue>
                                <enumeratedValue>
                                    <name>1</name>
                                    <description>Non-secure</description>
                                    <value>#1</value>
                                </enumeratedValue>
                            </enumeratedValues>
                        </field>
                        <field>
                            <name>SARTCPRDWUP</name>
                            <description>Security attributes of registers for WUPEN0.b25</description>
                            <lsb>25</lsb>
                            <msb>25</msb>
                            <access>read-write</access>
                            <enumeratedValues>
                                <enumeratedValue>
                                    <name>0</name>
                                    <description>Secure</description>
                                    <value>#0</value>
                                </enumeratedValue>
                                <enumeratedValue>
                                    <name>1</name>
                                    <description>Non-secure</description>
                                    <value>#1</value>
                                </enumeratedValue>
                            </enumeratedValues>
                        </field>
                        <field>
                            <name>SAUSBHSWUP</name>
                            <description>Security attributes of registers for WUPEN0.b26</description>
                            <lsb>26</lsb>
                            <msb>26</msb>
                            <access>read-write</access>
                            <enumeratedValues>
                                <enumeratedValue>
                                    <name>0</name>
                                    <description>Secure</description>
                                    <value>#0</value>
                                </enumeratedValue>
                                <enumeratedValue>
                                    <name>1</name>
                                    <description>Non-secure</description>
                                    <value>#1</value>
                                </enumeratedValue>
                            </enumeratedValues>
                        </field>
                        <field>
                            <name>SAUSBFS0WUP</name>
                            <description>Security attributes of registers for WUPEN0.b27</description>
                            <lsb>27</lsb>
                            <msb>27</msb>
                            <access>read-write</access>
                            <enumeratedValues>
                                <enumeratedValue>
                                    <name>0</name>
                                    <description>Secure</description>
                                    <value>#0</value>
                                </enumeratedValue>
                                <enumeratedValue>
                                    <name>1</name>
                                    <description>Non-secure</description>
                                    <value>#1</value>
                                </enumeratedValue>
                            </enumeratedValues>
                        </field>
                        <field>
                            <name>SAAGT1UDWUP</name>
                            <description>Security attributes of registers for WUPEN0.b28</description>
                            <lsb>28</lsb>
                            <msb>28</msb>
                            <access>read-write</access>
                            <enumeratedValues>
                                <enumeratedValue>
                                    <name>0</name>
                                    <description>Secure</description>
                                    <value>#0</value>
                                </enumeratedValue>
                                <enumeratedValue>
                                    <name>1</name>
                                    <description>Non-secure</description>
                                    <value>#1</value>
                                </enumeratedValue>
                            </enumeratedValues>
                        </field>
                        <field>
                            <name>SAAGT1CAWUP</name>
                            <description>Security attributes of registers for WUPEN0.b29</description>
                            <lsb>29</lsb>
                            <msb>29</msb>
                            <access>read-write</access>
                            <enumeratedValues>
                                <enumeratedValue>
                                    <name>0</name>
                                    <description>Secure</description>
                                    <value>#0</value>
                                </enumeratedValue>
                                <enumeratedValue>
                                    <name>1</name>
                                    <description>Non-secure</description>
                                    <value>#1</value>
                                </enumeratedValue>
                            </enumeratedValues>
                        </field>
                        <field>
                            <name>SAAGT1CBWUP</name>
                            <description>Security attributes of registers for WUPEN0.b30</description>
                            <lsb>30</lsb>
                            <msb>30</msb>
                            <access>read-write</access>
                            <enumeratedValues>
                                <enumeratedValue>
                                    <name>0</name>
                                    <description>Secure</description>
                                    <value>#0</value>
                                </enumeratedValue>
                                <enumeratedValue>
                                    <name>1</name>
                                    <description>Non-secure</description>
                                    <value>#1</value>
                                </enumeratedValue>
                            </enumeratedValues>
                        </field>
                        <field>
                            <name>SAIIC0WUP</name>
                            <description>Security attributes of registers for WUPEN0.b31</description>
                            <lsb>31</lsb>
                            <msb>31</msb>
                            <access>read-write</access>
                            <enumeratedValues>
                                <enumeratedValue>
                                    <name>0</name>
                                    <description>Secure</description>
                                    <value>#0</value>
                                </enumeratedValue>
                                <enumeratedValue>
                                    <name>1</name>
                                    <description>Non-secure</description>
                                    <value>#1</value>
                                </enumeratedValue>
                            </enumeratedValues>
                        </field>
                    </fields>
                </register>
                <register>
                    <name>ICUSARF</name>
                    <description>Interrupt Controller Unit Security Attribution Register F</description>
                    <addressOffset>0x54</addressOffset>
                    <size>32</size>
                    <access>read-write</access>
                    <resetValue>0x00000000</resetValue>
                    <resetMask>0xffffffff</resetMask>
                    <fields>
                        <field>
                            <name>SACOMPHS0WUP</name>
                            <description>Security attributes of registers for WUPEN1.b3</description>
                            <lsb>3</lsb>
                            <msb>3</msb>
                            <access>read-write</access>
                            <enumeratedValues>
                                <enumeratedValue>
                                    <name>0</name>
                                    <description>Secure</description>
                                    <value>#0</value>
                                </enumeratedValue>
                                <enumeratedValue>
                                    <name>1</name>
                                    <description>Non-secure</description>
                                    <value>#1</value>
                                </enumeratedValue>
                            </enumeratedValues>
                        </field>
                        <field>
                            <name>SAULP0UWUP</name>
                            <description>Security attributes of registers for WUPEN1.b8</description>
                            <lsb>8</lsb>
                            <msb>8</msb>
                            <access>read-write</access>
                            <enumeratedValues>
                                <enumeratedValue>
                                    <name>0</name>
                                    <description>Secure</description>
                                    <value>#0</value>
                                </enumeratedValue>
                                <enumeratedValue>
                                    <name>1</name>
                                    <description>Non-secure</description>
                                    <value>#1</value>
                                </enumeratedValue>
                            </enumeratedValues>
                        </field>
                        <field>
                            <name>SAULP0AWUP</name>
                            <description>Security attributes of registers for WUPEN1.b9</description>
                            <lsb>9</lsb>
                            <msb>9</msb>
                            <access>read-write</access>
                            <enumeratedValues>
                                <enumeratedValue>
                                    <name>0</name>
                                    <description>Secure</description>
                                    <value>#0</value>
                                </enumeratedValue>
                                <enumeratedValue>
                                    <name>1</name>
                                    <description>Non-secure</description>
                                    <value>#1</value>
                                </enumeratedValue>
                            </enumeratedValues>
                        </field>
                        <field>
                            <name>SAULP0BWUP</name>
                            <description>Security attributes of registers for WUPEN1.b10</description>
                            <lsb>10</lsb>
                            <msb>10</msb>
                            <access>read-write</access>
                            <enumeratedValues>
                                <enumeratedValue>
                                    <name>0</name>
                                    <description>Secure</description>
                                    <value>#0</value>
                                </enumeratedValue>
                                <enumeratedValue>
                                    <name>1</name>
                                    <description>Non-secure</description>
                                    <value>#1</value>
                                </enumeratedValue>
                            </enumeratedValues>
                        </field>
                        <field>
                            <name>SAI3CWUP</name>
                            <description>Security attributes of registers for WUPEN1.b11</description>
                            <lsb>11</lsb>
                            <msb>11</msb>
                            <access>read-write</access>
                            <enumeratedValues>
                                <enumeratedValue>
                                    <name>0</name>
                                    <description>Secure</description>
                                    <value>#0</value>
                                </enumeratedValue>
                                <enumeratedValue>
                                    <name>1</name>
                                    <description>Non-secure</description>
                                    <value>#1</value>
                                </enumeratedValue>
                            </enumeratedValues>
                        </field>
                        <field>
                            <name>SAULP1UWUP</name>
                            <description>Security attributes of registers for WUPEN1.b12</description>
                            <lsb>12</lsb>
                            <msb>12</msb>
                            <access>read-write</access>
                            <enumeratedValues>
                                <enumeratedValue>
                                    <name>0</name>
                                    <description>Secure</description>
                                    <value>#0</value>
                                </enumeratedValue>
                                <enumeratedValue>
                                    <name>1</name>
                                    <description>Non-secure</description>
                                    <value>#1</value>
                                </enumeratedValue>
                            </enumeratedValues>
                        </field>
                        <field>
                            <name>SAULP1AWUP</name>
                            <description>Security attributes of registers for WUPEN1.b13</description>
                            <lsb>13</lsb>
                            <msb>13</msb>
                            <access>read-write</access>
                            <enumeratedValues>
                                <enumeratedValue>
                                    <name>0</name>
                                    <description>Secure</description>
                                    <value>#0</value>
                                </enumeratedValue>
                                <enumeratedValue>
                                    <name>1</name>
                                    <description>Non-secure</description>
                                    <value>#1</value>
                                </enumeratedValue>
                            </enumeratedValues>
                        </field>
                        <field>
                            <name>SAULP1BWUP</name>
                            <description>Security attributes of registers for WUPEN1.b14</description>
                            <lsb>14</lsb>
                            <msb>14</msb>
                            <access>read-write</access>
                            <enumeratedValues>
                                <enumeratedValue>
                                    <name>0</name>
                                    <description>Secure</description>
                                    <value>#0</value>
                                </enumeratedValue>
                                <enumeratedValue>
                                    <name>1</name>
                                    <description>Non-secure</description>
                                    <value>#1</value>
                                </enumeratedValue>
                            </enumeratedValues>
                        </field>
                    </fields>
                </register>
                <register>
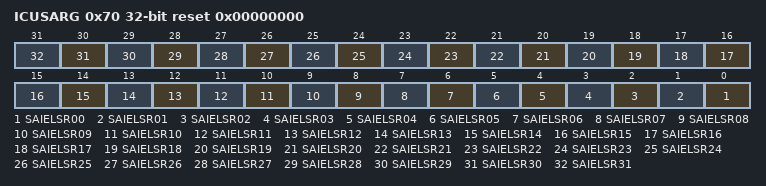
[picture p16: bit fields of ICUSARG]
                    <name>ICUSARG</name>
                    <description>Interrupt Controller Unit Security Attribution Register G</description>
                    <addressOffset>0x70</addressOffset>
                    <size>32</size>
                    <access>read-write</access>
                    <resetValue>0x00000000</resetValue>
                    <resetMask>0xffffffff</resetMask>
                    <fields>
                        <field>
                            <name>SAIELSR00</name>
                            <description>Security attributes of registers for IELSR31 to IELSR0</description>
                            <lsb>0</lsb>
                            <msb>0</msb>
                            <access>read-write</access>
                            <enumeratedValues>
                                <enumeratedValue>
                                    <name>0</name>
                                    <description>Secure</description>
                                    <value>#0</value>
                                </enumeratedValue>
                                <enumeratedValue>
                                    <name>1</name>
                                    <description>Non-secure</description>
                                    <value>#1</value>
                                </enumeratedValue>
                            </enumeratedValues>
                        </field>
                        <field>
                            <name>SAIELSR01</name>
                            <description>Security attributes of registers for IELSR31 to IELSR0</description>
                            <lsb>1</lsb>
                            <msb>1</msb>
                            <access>read-write</access>
                            <enumeratedValues>
                                <enumeratedValue>
                                    <name>0</name>
                                    <description>Secure</description>
                                    <value>#0</value>
                                </enumeratedValue>
                                <enumeratedValue>
                                    <name>1</name>
                                    <description>Non-secure</description>
                                    <value>#1</value>
                                </enumeratedValue>
                            </enumeratedValues>
                        </field>
                        <field>
                            <name>SAIELSR02</name>
                            <description>Security attributes of registers for IELSR31 to IELSR0</description>
                            <lsb>2</lsb>
                            <msb>2</msb>
                            <access>read-write</access>
                            <enumeratedValues>
                                <enumeratedValue>
                                    <name>0</name>
                                    <description>Secure</description>
                                    <value>#0</value>
                                </enumeratedValue>
                                <enumeratedValue>
                                    <name>1</name>
                                    <description>Non-secure</description>
                                    <value>#1</value>
                                </enumeratedValue>
                            </enumeratedValues>
                        </field>
                        <field>
                            <name>SAIELSR03</name>
                            <description>Security attributes of registers for IELSR31 to IELSR0</description>
                            <lsb>3</lsb>
                            <msb>3</msb>
                            <access>read-write</access>
                            <enumeratedValues>
                                <enumeratedValue>
                                    <name>0</name>
                                    <description>Secure</description>
                                    <value>#0</value>
                                </enumeratedValue>
                                <enumeratedValue>
                                    <name>1</name>
                                    <description>Non-secure</description>
                                    <value>#1</value>
                                </enumeratedValue>
                            </enumeratedValues>
                        </field>
                        <field>
                            <name>SAIELSR04</name>
                            <description>Security attributes of registers for IELSR31 to IELSR0</description>
                            <lsb>4</lsb>
                            <msb>4</msb>
                            <access>read-write</access>
                            <enumeratedValues>
                                <enumeratedValue>
                                    <name>0</name>
                                    <description>Secure</description>
                                    <value>#0</value>
                                </enumeratedValue>
                                <enumeratedValue>
                                    <name>1</name>
                                    <description>Non-secure</description>
                                    <value>#1</value>
                                </enumeratedValue>
                            </enumeratedValues>
                        </field>
                        <field>
                            <name>SAIELSR05</name>
                            <description>Security attributes of registers for IELSR31 to IELSR0</description>
                            <lsb>5</lsb>
                            <msb>5</msb>
                            <access>read-write</access>
                            <enumeratedValues>
                                <enumeratedValue>
                                    <name>0</name>
                                    <description>Secure</description>
                                    <value>#0</value>
                                </enumeratedValue>
                                <enumeratedValue>
                                    <name>1</name>
                                    <description>Non-secure</description>
                                    <value>#1</value>
                                </enumeratedValue>
                            </enumeratedValues>
                        </field>
                        <field>
                            <name>SAIELSR06</name>
                            <description>Security attributes of registers for IELSR31 to IELSR0</description>
                            <lsb>6</lsb>
                            <msb>6</msb>
                            <access>read-write</access>
                            <enumeratedValues>
                                <enumeratedValue>
                                    <name>0</name>
                                    <description>Secure</description>
                                    <value>#0</value>
                                </enumeratedValue>
                                <enumeratedValue>
                                    <name>1</name>
                                    <description>Non-secure</description>
                                    <value>#1</value>
                                </enumeratedValue>
                            </enumeratedValues>
                        </field>
                        <field>
                            <name>SAIELSR07</name>
                            <description>Security attributes of registers for IELSR31 to IELSR0</description>
                            <lsb>7</lsb>
                            <msb>7</msb>
                            <access>read-write</access>
                            <enumeratedValues>
                                <enumeratedValue>
                                    <name>0</name>
                                    <description>Secure</description>
                                    <value>#0</value>
                                </enumeratedValue>
                                <enumeratedValue>
                                    <name>1</name>
                                    <description>Non-secure</description>
                                    <value>#1</value>
                                </enumeratedValue>
                            </enumeratedValues>
                        </field>
                        <field>
                            <name>SAIELSR08</name>
                            <description>Security attributes of registers for IELSR31 to IELSR0</description>
                            <lsb>8</lsb>
                            <msb>8</msb>
                            <access>read-write</access>
                            <enumeratedValues>
                                <enumeratedValue>
                                    <name>0</name>
                                    <description>Secure</description>
                                    <value>#0</value>
                                </enumeratedValue>
                                <enumeratedValue>
                                    <name>1</name>
                                    <description>Non-secure</description>
                                    <value>#1</value>
                                </enumeratedValue>
                            </enumeratedValues>
                        </field>
                        <field>
                            <name>SAIELSR09</name>
                            <description>Security attributes of registers for IELSR31 to IELSR0</description>
                            <lsb>9</lsb>
                            <msb>9</msb>
                            <access>read-write</access>
                            <enumeratedValues>
                                <enumeratedValue>
                                    <name>0</name>
                                    <description>Secure</description>
                                    <value>#0</value>
                                </enumeratedValue>
                                <enumeratedValue>
                                    <name>1</name>
                                    <description>Non-secure</description>
                                    <value>#1</value>
                                </enumeratedValue>
                            </enumeratedValues>
                        </field>
                        <field>
                            <name>SAIELSR10</name>
                            <description>Security attributes of registers for IELSR31 to IELSR0</description>
                            <lsb>10</lsb>
                            <msb>10</msb>
                            <access>read-write</access>
                            <enumeratedValues>
                                <enumeratedValue>
                                    <name>0</name>
                                    <description>Secure</description>
                                    <value>#0</value>
                                </enumeratedValue>
                                <enumeratedValue>
                                    <name>1</name>
                                    <description>Non-secure</description>
                                    <value>#1</value>
                                </enumeratedValue>
                            </enumeratedValues>
                        </field>
                        <field>
                            <name>SAIELSR11</name>
                            <description>Security attributes of registers for IELSR31 to IELSR0</description>
                            <lsb>11</lsb>
                            <msb>11</msb>
                            <access>read-write</access>
                            <enumeratedValues>
                                <enumeratedValue>
                                    <name>0</name>
                                    <description>Secure</description>
                                    <value>#0</value>
                                </enumeratedValue>
                                <enumeratedValue>
                                    <name>1</name>
                                    <description>Non-secure</description>
                                    <value>#1</value>
                                </enumeratedValue>
                            </enumeratedValues>
                        </field>
                        <field>
                            <name>SAIELSR12</name>
                            <description>Security attributes of registers for IELSR31 to IELSR0</description>
                            <lsb>12</lsb>
                            <msb>12</msb>
                            <access>read-write</access>
                            <enumeratedValues>
                                <enumeratedValue>
                                    <name>0</name>
                                    <description>Secure</description>
                                    <value>#0</value>
                                </enumeratedValue>
                                <enumeratedValue>
                                    <name>1</name>
                                    <description>Non-secure</description>
                                    <value>#1</value>
                                </enumeratedValue>
                            </enumeratedValues>
                        </field>
                        <field>
                            <name>SAIELSR13</name>
                            <description>Security attributes of registers for IELSR31 to IELSR0</description>
                            <lsb>13</lsb>
                            <msb>13</msb>
                            <access>read-write</access>
                            <enumeratedValues>
                                <enumeratedValue>
                                    <name>0</name>
                                    <description>Secure</description>
                                    <value>#0</value>
                                </enumeratedValue>
                                <enumeratedValue>
                                    <name>1</name>
                                    <description>Non-secure</description>
                                    <value>#1</value>
                                </enumeratedValue>
                            </enumeratedValues>
                        </field>
                        <field>
                            <name>SAIELSR14</name>
                            <description>Security attributes of registers for IELSR31 to IELSR0</description>
                            <lsb>14</lsb>
                            <msb>14</msb>
                            <access>read-write</access>
                            <enumeratedValues>
                                <enumeratedValue>
                                    <name>0</name>
                                    <description>Secure</description>
                                    <value>#0</value>
                                </enumeratedValue>
                                <enumeratedValue>
                                    <name>1</name>
                                    <description>Non-secure</description>
                                    <value>#1</value>
                                </enumeratedValue>
                            </enumeratedValues>
                        </field>
                        <field>
                            <name>SAIELSR15</name>
                            <description>Security attributes of registers for IELSR31 to IELSR0</description>
                            <lsb>15</lsb>
                            <msb>15</msb>
                            <access>read-write</access>
                            <enumeratedValues>
                                <enumeratedValue>
                                    <name>0</name>
                                    <description>Secure</description>
                                    <value>#0</value>
                                </enumeratedValue>
                                <enumeratedValue>
                                    <name>1</name>
                                    <description>Non-secure</description>
                                    <value>#1</value>
                                </enumeratedValue>
                            </enumeratedValues>
                        </field>
                        <field>
                            <name>SAIELSR16</name>
                            <description>Security attributes of registers for IELSR31 to IELSR0</description>
                            <lsb>16</lsb>
                            <msb>16</msb>
                            <access>read-write</access>
                            <enumeratedValues>
                                <enumeratedValue>
                                    <name>0</name>
                                    <description>Secure</description>
                                    <value>#0</value>
                                </enumeratedValue>
                                <enumeratedValue>
                                    <name>1</name>
                                    <description>Non-secure</description>
                                    <value>#1</value>
                                </enumeratedValue>
                            </enumeratedValues>
                        </field>
                        <field>
                            <name>SAIELSR17</name>
                            <description>Security attributes of registers for IELSR31 to IELSR0</description>
                            <lsb>17</lsb>
                            <msb>17</msb>
                            <access>read-write</access>
                            <enumeratedValues>
                                <enumeratedValue>
                                    <name>0</name>
                                    <description>Secure</description>
                                    <value>#0</value>
                                </enumeratedValue>
                                <enumeratedValue>
                                    <name>1</name>
                                    <description>Non-secure</description>
                                    <value>#1</value>
                                </enumeratedValue>
                            </enumeratedValues>
                        </field>
                        <field>
                            <name>SAIELSR18</name>
                            <description>Security attributes of registers for IELSR31 to IELSR0</description>
                            <lsb>18</lsb>
                            <msb>18</msb>
                            <access>read-write</access>
                            <enumeratedValues>
                                <enumeratedValue>
                                    <name>0</name>
                                    <description>Secure</description>
                                    <value>#0</value>
                                </enumeratedValue>
                                <enumeratedValue>
                                    <name>1</name>
                                    <description>Non-secure</description>
                                    <value>#1</value>
                                </enumeratedValue>
                            </enumeratedValues>
                        </field>
                        <field>
                            <name>SAIELSR19</name>
                            <description>Security attributes of registers for IELSR31 to IELSR0</description>
                            <lsb>19</lsb>
                            <msb>19</msb>
                            <access>read-write</access>
                            <enumeratedValues>
                                <enumeratedValue>
                                    <name>0</name>
                                    <description>Secure</description>
                                    <value>#0</value>
                                </enumeratedValue>
                                <enumeratedValue>
                                    <name>1</name>
                                    <description>Non-secure</description>
                                    <value>#1</value>
                                </enumeratedValue>
                            </enumeratedValues>
                        </field>
                        <field>
                            <name>SAIELSR20</name>
                            <description>Security attributes of registers for IELSR31 to IELSR0</description>
                            <lsb>20</lsb>
                            <msb>20</msb>
                            <access>read-write</access>
                            <enumeratedValues>
                                <enumeratedValue>
                                    <name>0</name>
                                    <description>Secure</description>
                                    <value>#0</value>
                                </enumeratedValue>
                                <enumeratedValue>
                                    <name>1</name>
                                    <description>Non-secure</description>
                                    <value>#1</value>
                                </enumeratedValue>
                            </enumeratedValues>
                        </field>
                        <field>
                            <name>SAIELSR21</name>
                            <description>Security attributes of registers for IELSR31 to IELSR0</description>
                            <lsb>21</lsb>
                            <msb>21</msb>
                            <access>read-write</access>
                            <enumeratedValues>
                                <enumeratedValue>
                                    <name>0</name>
                                    <description>Secure</description>
                                    <value>#0</value>
                                </enumeratedValue>
                                <enumeratedValue>
                                    <name>1</name>
                                    <description>Non-secure</description>
                                    <value>#1</value>
                                </enumeratedValue>
                            </enumeratedValues>
                        </field>
                        <field>
                            <name>SAIELSR22</name>
                            <description>Security attributes of registers for IELSR31 to IELSR0</description>
                            <lsb>22</lsb>
                            <msb>22</msb>
                            <access>read-write</access>
                            <enumeratedValues>
                                <enumeratedValue>
                                    <name>0</name>
                                    <description>Secure</description>
                                    <value>#0</value>
                                </enumeratedValue>
                                <enumeratedValue>
                                    <name>1</name>
                                    <description>Non-secure</description>
                                    <value>#1</value>
                                </enumeratedValue>
                            </enumeratedValues>
                        </field>
                        <field>
                            <name>SAIELSR23</name>
                            <description>Security attributes of registers for IELSR31 to IELSR0</description>
                            <lsb>23</lsb>
                            <msb>23</msb>
                            <access>read-write</access>
                            <enumeratedValues>
                                <enumeratedValue>
                                    <name>0</name>
                                    <description>Secure</description>
                                    <value>#0</value>
                                </enumeratedValue>
                                <enumeratedValue>
                                    <name>1</name>
                                    <description>Non-secure</description>
                                    <value>#1</value>
                                </enumeratedValue>
                            </enumeratedValues>
                        </field>
                        <field>
                            <name>SAIELSR24</name>
                            <description>Security attributes of registers for IELSR31 to IELSR0</description>
                            <lsb>24</lsb>
                            <msb>24</msb>
                            <access>read-write</access>
                            <enumeratedValues>
                                <enumeratedValue>
                                    <name>0</name>
                                    <description>Secure</description>
                                    <value>#0</value>
                                </enumeratedValue>
                                <enumeratedValue>
                                    <name>1</name>
                                    <description>Non-secure</description>
                                    <value>#1</value>
                                </enumeratedValue>
                            </enumeratedValues>
                        </field>
                        <field>
                            <name>SAIELSR25</name>
                            <description>Security attributes of registers for IELSR31 to IELSR0</description>
                            <lsb>25</lsb>
                            <msb>25</msb>
                            <access>read-write</access>
                            <enumeratedValues>
                                <enumeratedValue>
                                    <name>0</name>
                                    <description>Secure</description>
                                    <value>#0</value>
                                </enumeratedValue>
                                <enumeratedValue>
                                    <name>1</name>
                                    <description>Non-secure</description>
                                    <value>#1</value>
                                </enumeratedValue>
                            </enumeratedValues>
                        </field>
                        <field>
                            <name>SAIELSR26</name>
                            <description>Security attributes of registers for IELSR31 to IELSR0</description>
                            <lsb>26</lsb>
                            <msb>26</msb>
                            <access>read-write</access>
                            <enumeratedValues>
                                <enumeratedValue>
                                    <name>0</name>
                                    <description>Secure</description>
                                    <value>#0</value>
                                </enumeratedValue>
                                <enumeratedValue>
                                    <name>1</name>
                                    <description>Non-secure</description>
                                    <value>#1</value>
                                </enumeratedValue>
                            </enumeratedValues>
                        </field>
                        <field>
                            <name>SAIELSR27</name>
                            <description>Security attributes of registers for IELSR31 to IELSR0</description>
                            <lsb>27</lsb>
                            <msb>27</msb>
                            <access>read-write</access>
                            <enumeratedValues>
                                <enumeratedValue>
                                    <name>0</name>
                                    <description>Secure</description>
                                    <value>#0</value>
                                </enumeratedValue>
                                <enumeratedValue>
                                    <name>1</name>
                                    <description>Non-secure</description>
                                    <value>#1</value>
                                </enumeratedValue>
                            </enumeratedValues>
                        </field>
                        <field>
                            <name>SAIELSR28</name>
                            <description>Security attributes of registers for IELSR31 to IELSR0</description>
                            <lsb>28</lsb>
                            <msb>28</msb>
                            <access>read-write</access>
                            <enumeratedValues>
                                <enumeratedValue>
                                    <name>0</name>
                                    <description>Secure</description>
                                    <value>#0</value>
                                </enumeratedValue>
                                <enumeratedValue>
                                    <name>1</name>
                                    <description>Non-secure</description>
                                    <value>#1</value>
                                </enumeratedValue>
                            </enumeratedValues>
                        </field>
                        <field>
                            <name>SAIELSR29</name>
                            <description>Security attributes of registers for IELSR31 to IELSR0</description>
                            <lsb>29</lsb>
                            <msb>29</msb>
                            <access>read-write</access>
                            <enumeratedValues>
                                <enumeratedValue>
                                    <name>0</name>
                                    <description>Secure</description>
                                    <value>#0</value>
                                </enumeratedValue>
                                <enumeratedValue>
                                    <name>1</name>
                                    <description>Non-secure</description>
                                    <value>#1</value>
                                </enumeratedValue>
                            </enumeratedValues>
                        </field>
                        <field>
                            <name>SAIELSR30</name>
                            <description>Security attributes of registers for IELSR31 to IELSR0</description>
                            <lsb>30</lsb>
                            <msb>30</msb>
                            <access>read-write</access>
                            <enumeratedValues>
                                <enumeratedValue>
                                    <name>0</name>
                                    <description>Secure</description>
                                    <value>#0</value>
                                </enumeratedValue>
                                <enumeratedValue>
                                    <name>1</name>
                                    <description>Non-secure</description>
                                    <value>#1</value>
                                </enumeratedValue>
                            </enumeratedValues>
                        </field>
                        <field>
                            <name>SAIELSR31</name>
                            <description>Security attributes of registers for IELSR31 to IELSR0</description>
                            <lsb>31</lsb>
                            <msb>31</msb>
                            <access>read-write</access>
                            <enumeratedValues>
                                <enumeratedValue>
                                    <name>0</name>
                                    <description>Secure</description>
                                    <value>#0</value>
                                </enumeratedValue>
                                <enumeratedValue>
                                    <name>1</name>
                                    <description>Non-secure</description>
                                    <value>#1</value>
                                </enumeratedValue>
                            </enumeratedValues>
                        </field>
                    </fields>
                </register>
                <register>
                    <name>ICUSARH</name>
                    <description>Interrupt Controller Unit Security Attribution Register H</description>
                    <addressOffset>0x74</addressOffset>
                    <size>32</size>
                    <access>read-write</access>
                    <resetValue>0x00000000</resetValue>
                    <resetMask>0xffffffff</resetMask>
                    <fields>
                        <field>
                            <name>SAIELSR32</name>
                            <description>Security attributes of registers for IELSR63 to IELSR32</description>
                            <lsb>0</lsb>
                            <msb>0</msb>
                            <access>read-write</access>
                            <enumeratedValues>
                                <enumeratedValue>
                                    <name>0</name>
                                    <description>Secure</description>
                                    <value>#0</value>
                                </enumeratedValue>
                                <enumeratedValue>
                                    <name>1</name>
                                    <description>Non-secure</description>
                                    <value>#1</value>
                                </enumeratedValue>
                            </enumeratedValues>
                        </field>
                        <field>
                            <name>SAIELSR33</name>
                            <description>Security attributes of registers for IELSR63 to IELSR32</description>
                            <lsb>1</lsb>
                            <msb>1</msb>
                            <access>read-write</access>
                            <enumeratedValues>
                                <enumeratedValue>
                                    <name>0</name>
                                    <description>Secure</description>
                                    <value>#0</value>
                                </enumeratedValue>
                                <enumeratedValue>
                                    <name>1</name>
                                    <description>Non-secure</description>
                                    <value>#1</value>
                                </enumeratedValue>
                            </enumeratedValues>
                        </field>
                        <field>
                            <name>SAIELSR34</name>
                            <description>Security attributes of registers for IELSR63 to IELSR32</description>
                            <lsb>2</lsb>
                            <msb>2</msb>
                            <access>read-write</access>
                            <enumeratedValues>
                                <enumeratedValue>
                                    <name>0</name>
                                    <description>Secure</description>
                                    <value>#0</value>
                                </enumeratedValue>
                                <enumeratedValue>
                                    <name>1</name>
                                    <description>Non-secure</description>
                                    <value>#1</value>
                                </enumeratedValue>
                            </enumeratedValues>
                        </field>
                        <field>
                            <name>SAIELSR35</name>
                            <description>Security attributes of registers for IELSR63 to IELSR32</description>
                            <lsb>3</lsb>
                            <msb>3</msb>
                            <access>read-write</access>
                            <enumeratedValues>
                                <enumeratedValue>
                                    <name>0</name>
                                    <description>Secure</description>
                                    <value>#0</value>
                                </enumeratedValue>
                                <enumeratedValue>
                                    <name>1</name>
                                    <description>Non-secure</description>
                                    <value>#1</value>
                                </enumeratedValue>
                            </enumeratedValues>
                        </field>
                        <field>
                            <name>SAIELSR36</name>
                            <description>Security attributes of registers for IELSR63 to IELSR32</description>
                            <lsb>4</lsb>
                            <msb>4</msb>
                            <access>read-write</access>
                            <enumeratedValues>
                                <enumeratedValue>
                                    <name>0</name>
                                    <description>Secure</description>
                                    <value>#0</value>
                                </enumeratedValue>
                                <enumeratedValue>
                                    <name>1</name>
                                    <description>Non-secure</description>
                                    <value>#1</value>
                                </enumeratedValue>
                            </enumeratedValues>
                        </field>
                        <field>
                            <name>SAIELSR37</name>
                            <description>Security attributes of registers for IELSR63 to IELSR32</description>
                            <lsb>5</lsb>
                            <msb>5</msb>
                            <access>read-write</access>
                            <enumeratedValues>
                                <enumeratedValue>
                                    <name>0</name>
                                    <description>Secure</description>
                                    <value>#0</value>
                                </enumeratedValue>
                                <enumeratedValue>
                                    <name>1</name>
                                    <description>Non-secure</description>
                                    <value>#1</value>
                                </enumeratedValue>
                            </enumeratedValues>
                        </field>
                        <field>
                            <name>SAIELSR38</name>
                            <description>Security attributes of registers for IELSR63 to IELSR32</description>
                            <lsb>6</lsb>
                            <msb>6</msb>
                            <access>read-write</access>
                            <enumeratedValues>
                                <enumeratedValue>
                                    <name>0</name>
                                    <description>Secure</description>
                                    <value>#0</value>
                                </enumeratedValue>
                                <enumeratedValue>
                                    <name>1</name>
                                    <description>Non-secure</description>
                                    <value>#1</value>
                                </enumeratedValue>
                            </enumeratedValues>
                        </field>
                        <field>
                            <name>SAIELSR39</name>
                            <description>Security attributes of registers for IELSR63 to IELSR32</description>
                            <lsb>7</lsb>
                            <msb>7</msb>
                            <access>read-write</access>
                            <enumeratedValues>
                                <enumeratedValue>
                                    <name>0</name>
                                    <description>Secure</description>
                                    <value>#0</value>
                                </enumeratedValue>
                                <enumeratedValue>
                                    <name>1</name>
                                    <description>Non-secure</description>
                                    <value>#1</value>
                                </enumeratedValue>
                            </enumeratedValues>
                        </field>
                        <field>
                            <name>SAIELSR40</name>
                            <description>Security attributes of registers for IELSR63 to IELSR32</description>
                            <lsb>8</lsb>
                            <msb>8</msb>
                            <access>read-write</access>
                            <enumeratedValues>
                                <enumeratedValue>
                                    <name>0</name>
                                    <description>Secure</description>
                                    <value>#0</value>
                                </enumeratedValue>
                                <enumeratedValue>
                                    <name>1</name>
                                    <description>Non-secure</description>
                                    <value>#1</value>
                                </enumeratedValue>
                            </enumeratedValues>
                        </field>
                        <field>
                            <name>SAIELSR41</name>
                            <description>Security attributes of registers for IELSR63 to IELSR32</description>
                            <lsb>9</lsb>
                            <msb>9</msb>
                            <access>read-write</access>
                            <enumeratedValues>
                                <enumeratedValue>
                                    <name>0</name>
                                    <description>Secure</description>
                                    <value>#0</value>
                                </enumeratedValue>
                                <enumeratedValue>
                                    <name>1</name>
                                    <description>Non-secure</description>
                                    <value>#1</value>
                                </enumeratedValue>
                            </enumeratedValues>
                        </field>
                        <field>
                            <name>SAIELSR42</name>
                            <description>Security attributes of registers for IELSR63 to IELSR32</description>
                            <lsb>10</lsb>
                            <msb>10</msb>
                            <access>read-write</access>
                            <enumeratedValues>
                                <enumeratedValue>
                                    <name>0</name>
                                    <description>Secure</description>
                                    <value>#0</value>
                                </enumeratedValue>
                                <enumeratedValue>
                                    <name>1</name>
                                    <description>Non-secure</description>
                                    <value>#1</value>
                                </enumeratedValue>
                            </enumeratedValues>
                        </field>
                        <field>
                            <name>SAIELSR43</name>
                            <description>Security attributes of registers for IELSR63 to IELSR32</description>
                            <lsb>11</lsb>
                            <msb>11</msb>
                            <access>read-write</access>
                            <enumeratedValues>
                                <enumeratedValue>
                                    <name>0</name>
                                    <description>Secure</description>
                                    <value>#0</value>
                                </enumeratedValue>
                                <enumeratedValue>
                                    <name>1</name>
                                    <description>Non-secure</description>
                                    <value>#1</value>
                                </enumeratedValue>
                            </enumeratedValues>
                        </field>
                        <field>
                            <name>SAIELSR44</name>
                            <description>Security attributes of registers for IELSR63 to IELSR32</description>
                            <lsb>12</lsb>
                            <msb>12</msb>
                            <access>read-write</access>
                            <enumeratedValues>
                                <enumeratedValue>
                                    <name>0</name>
                                    <description>Secure</description>
                                    <value>#0</value>
                                </enumeratedValue>
                                <enumeratedValue>
                                    <name>1</name>
                                    <description>Non-secure</description>
                                    <value>#1</value>
                                </enumeratedValue>
                            </enumeratedValues>
                        </field>
                        <field>
                            <name>SAIELSR45</name>
                            <description>Security attributes of registers for IELSR63 to IELSR32</description>
                            <lsb>13</lsb>
                            <msb>13</msb>
                            <access>read-write</access>
                            <enumeratedValues>
                                <enumeratedValue>
                                    <name>0</name>
                                    <description>Secure</description>
                                    <value>#0</value>
                                </enumeratedValue>
                                <enumeratedValue>
                                    <name>1</name>
                                    <description>Non-secure</description>
                                    <value>#1</value>
                                </enumeratedValue>
                            </enumeratedValues>
                        </field>
                        <field>
                            <name>SAIELSR46</name>
                            <description>Security attributes of registers for IELSR63 to IELSR32</description>
                            <lsb>14</lsb>
                            <msb>14</msb>
                            <access>read-write</access>
                            <enumeratedValues>
                                <enumeratedValue>
                                    <name>0</name>
                                    <description>Secure</description>
                                    <value>#0</value>
                                </enumeratedValue>
                                <enumeratedValue>
                                    <name>1</name>
                                    <description>Non-secure</description>
                                    <value>#1</value>
                                </enumeratedValue>
                            </enumeratedValues>
                        </field>
                        <field>
                            <name>SAIELSR47</name>
                            <description>Security attributes of registers for IELSR63 to IELSR32</description>
                            <lsb>15</lsb>
                            <msb>15</msb>
                            <access>read-write</access>
                            <enumeratedValues>
                                <enumeratedValue>
                                    <name>0</name>
                                    <description>Secure</description>
                                    <value>#0</value>
                                </enumeratedValue>
                                <enumeratedValue>
                                    <name>1</name>
                                    <description>Non-secure</description>
                                    <value>#1</value>
                                </enumeratedValue>
                            </enumeratedValues>
                        </field>
                        <field>
                            <name>SAIELSR48</name>
                            <description>Security attributes of registers for IELSR63 to IELSR32</description>
                            <lsb>16</lsb>
                            <msb>16</msb>
                            <access>read-write</access>
                            <enumeratedValues>
                                <enumeratedValue>
                                    <name>0</name>
                                    <description>Secure</description>
                                    <value>#0</value>
                                </enumeratedValue>
                                <enumeratedValue>
                                    <name>1</name>
                                    <description>Non-secure</description>
                                    <value>#1</value>
                                </enumeratedValue>
                            </enumeratedValues>
                        </field>
                        <field>
                            <name>SAIELSR49</name>
                            <description>Security attributes of registers for IELSR63 to IELSR32</description>
                            <lsb>17</lsb>
                            <msb>17</msb>
                            <access>read-write</access>
                            <enumeratedValues>
                                <enumeratedValue>
                                    <name>0</name>
                                    <description>Secure</description>
                                    <value>#0</value>
                                </enumeratedValue>
                                <enumeratedValue>
                                    <name>1</name>
                                    <description>Non-secure</description>
                                    <value>#1</value>
                                </enumeratedValue>
                            </enumeratedValues>
                        </field>
                        <field>
                            <name>SAIELSR50</name>
                            <description>Security attributes of registers for IELSR63 to IELSR32</description>
                            <lsb>18</lsb>
                            <msb>18</msb>
                            <access>read-write</access>
                            <enumeratedValues>
                                <enumeratedValue>
                                    <name>0</name>
                                    <description>Secure</description>
                                    <value>#0</value>
                                </enumeratedValue>
                                <enumeratedValue>
                                    <name>1</name>
                                    <description>Non-secure</description>
                                    <value>#1</value>
                                </enumeratedValue>
                            </enumeratedValues>
                        </field>
                        <field>
                            <name>SAIELSR51</name>
                            <description>Security attributes of registers for IELSR63 to IELSR32</description>
                            <lsb>19</lsb>
                            <msb>19</msb>
                            <access>read-write</access>
                            <enumeratedValues>
                                <enumeratedValue>
                                    <name>0</name>
                                    <description>Secure</description>
                                    <value>#0</value>
                                </enumeratedValue>
                                <enumeratedValue>
                                    <name>1</name>
                                    <description>Non-secure</description>
                                    <value>#1</value>
                                </enumeratedValue>
                            </enumeratedValues>
                        </field>
                        <field>
                            <name>SAIELSR52</name>
                            <description>Security attributes of registers for IELSR63 to IELSR32</description>
                            <lsb>20</lsb>
                            <msb>20</msb>
                            <access>read-write</access>
                            <enumeratedValues>
                                <enumeratedValue>
                                    <name>0</name>
                                    <description>Secure</description>
                                    <value>#0</value>
                                </enumeratedValue>
                                <enumeratedValue>
                                    <name>1</name>
                                    <description>Non-secure</description>
                                    <value>#1</value>
                                </enumeratedValue>
                            </enumeratedValues>
                        </field>
                        <field>
                            <name>SAIELSR53</name>
                            <description>Security attributes of registers for IELSR63 to IELSR32</description>
                            <lsb>21</lsb>
                            <msb>21</msb>
                            <access>read-write</access>
                            <enumeratedValues>
                                <enumeratedValue>
                                    <name>0</name>
                                    <description>Secure</description>
                                    <value>#0</value>
                                </enumeratedValue>
                                <enumeratedValue>
                                    <name>1</name>
                                    <description>Non-secure</description>
                                    <value>#1</value>
                                </enumeratedValue>
                            </enumeratedValues>
                        </field>
                        <field>
                            <name>SAIELSR54</name>
                            <description>Security attributes of registers for IELSR63 to IELSR32</description>
                            <lsb>22</lsb>
                            <msb>22</msb>
                            <access>read-write</access>
                            <enumeratedValues>
                                <enumeratedValue>
                                    <name>0</name>
                                    <description>Secure</description>
                                    <value>#0</value>
                                </enumeratedValue>
                                <enumeratedValue>
                                    <name>1</name>
                                    <description>Non-secure</description>
                                    <value>#1</value>
                                </enumeratedValue>
                            </enumeratedValues>
                        </field>
                        <field>
                            <name>SAIELSR55</name>
                            <description>Security attributes of registers for IELSR63 to IELSR32</description>
                            <lsb>23</lsb>
                            <msb>23</msb>
                            <access>read-write</access>
                            <enumeratedValues>
                                <enumeratedValue>
                                    <name>0</name>
                                    <description>Secure</description>
                                    <value>#0</value>
                                </enumeratedValue>
                                <enumeratedValue>
                                    <name>1</name>
                                    <description>Non-secure</description>
                                    <value>#1</value>
                                </enumeratedValue>
                            </enumeratedValues>
                        </field>
                        <field>
                            <name>SAIELSR56</name>
                            <description>Security attributes of registers for IELSR63 to IELSR32</description>
                            <lsb>24</lsb>
                            <msb>24</msb>
                            <access>read-write</access>
                            <enumeratedValues>
                                <enumeratedValue>
                                    <name>0</name>
                                    <description>Secure</description>
                                    <value>#0</value>
                                </enumeratedValue>
                                <enumeratedValue>
                                    <name>1</name>
                                    <description>Non-secure</description>
                                    <value>#1</value>
                                </enumeratedValue>
                            </enumeratedValues>
                        </field>
                        <field>
                            <name>SAIELSR57</name>
                            <description>Security attributes of registers for IELSR63 to IELSR32</description>
                            <lsb>25</lsb>
                            <msb>25</msb>
                            <access>read-write</access>
                            <enumeratedValues>
                                <enumeratedValue>
                                    <name>0</name>
                                    <description>Secure</description>
                                    <value>#0</value>
                                </enumeratedValue>
                                <enumeratedValue>
                                    <name>1</name>
                                    <description>Non-secure</description>
                                    <value>#1</value>
                                </enumeratedValue>
                            </enumeratedValues>
                        </field>
                        <field>
                            <name>SAIELSR58</name>
                            <description>Security attributes of registers for IELSR63 to IELSR32</description>
                            <lsb>26</lsb>
                            <msb>26</msb>
                            <access>read-write</access>
                            <enumeratedValues>
                                <enumeratedValue>
                                    <name>0</name>
                                    <description>Secure</description>
                                    <value>#0</value>
                                </enumeratedValue>
                                <enumeratedValue>
                                    <name>1</name>
                                    <description>Non-secure</description>
                                    <value>#1</value>
                                </enumeratedValue>
                            </enumeratedValues>
                        </field>
                        <field>
                            <name>SAIELSR59</name>
                            <description>Security attributes of registers for IELSR63 to IELSR32</description>
                            <lsb>27</lsb>
                            <msb>27</msb>
                            <access>read-write</access>
                            <enumeratedValues>
                                <enumeratedValue>
                                    <name>0</name>
                                    <description>Secure</description>
                                    <value>#0</value>
                                </enumeratedValue>
                                <enumeratedValue>
                                    <name>1</name>
                                    <description>Non-secure</description>
                                    <value>#1</value>
                                </enumeratedValue>
                            </enumeratedValues>
                        </field>
                        <field>
                            <name>SAIELSR60</name>
                            <description>Security attributes of registers for IELSR63 to IELSR32</description>
                            <lsb>28</lsb>
                            <msb>28</msb>
                            <access>read-write</access>
                            <enumeratedValues>
                                <enumeratedValue>
                                    <name>0</name>
                                    <description>Secure</description>
                                    <value>#0</value>
                                </enumeratedValue>
                                <enumeratedValue>
                                    <name>1</name>
                                    <description>Non-secure</description>
                                    <value>#1</value>
                                </enumeratedValue>
                            </enumeratedValues>
                        </field>
                        <field>
                            <name>SAIELSR61</name>
                            <description>Security attributes of registers for IELSR63 to IELSR32</description>
                            <lsb>29</lsb>
                            <msb>29</msb>
                            <access>read-write</access>
                            <enumeratedValues>
                                <enumeratedValue>
                                    <name>0</name>
                                    <description>Secure</description>
                                    <value>#0</value>
                                </enumeratedValue>
                                <enumeratedValue>
                                    <name>1</name>
                                    <description>Non-secure</description>
                                    <value>#1</value>
                                </enumeratedValue>
                            </enumeratedValues>
                        </field>
                        <field>
                            <name>SAIELSR62</name>
                            <description>Security attributes of registers for IELSR63 to IELSR32</description>
                            <lsb>30</lsb>
                            <msb>30</msb>
                            <access>read-write</access>
                            <enumeratedValues>
                                <enumeratedValue>
                                    <name>0</name>
                                    <description>Secure</description>
                                    <value>#0</value>
                                </enumeratedValue>
                                <enumeratedValue>
                                    <name>1</name>
                                    <description>Non-secure</description>
                                    <value>#1</value>
                                </enumeratedValue>
                            </enumeratedValues>
                        </field>
                        <field>
                            <name>SAIELSR63</name>
                            <description>Security attributes of registers for IELSR63 to IELSR32</description>
                            <lsb>31</lsb>
                            <msb>31</msb>
                            <access>read-write</access>
                            <enumeratedValues>
                                <enumeratedValue>
                                    <name>0</name>
                                    <description>Secure</description>
                                    <value>#0</value>
                                </enumeratedValue>
                                <enumeratedValue>
                                    <name>1</name>
                                    <description>Non-secure</description>
                                    <value>#1</value>
                                </enumeratedValue>
                            </enumeratedValues>
                        </field>
                    </fields>
                </register>
                <register>
                    <name>ICUSARI</name>
                    <description>Interrupt Controller Unit Security Attribution Register I</description>
                    <addressOffset>0x78</addressOffset>
                    <size>32</size>
                    <access>read-write</access>
                    <resetValue>0x00000000</resetValue>
                    <resetMask>0xffffffff</resetMask>
                    <fields>
                        <field>
                            <name>SAIELSR64</name>
                            <description>Security attributes of registers for IELSR95 to IELSR64</description>
                            <lsb>0</lsb>
                            <msb>0</msb>
                            <access>read-write</access>
                            <enumeratedValues>
                                <enumeratedValue>
                                    <name>0</name>
                                    <description>Secure</description>
                                    <value>#0</value>
                                </enumeratedValue>
                                <enumeratedValue>
                                    <name>1</name>
                                    <description>Non-secure</description>
                                    <value>#1</value>
                                </enumeratedValue>
                            </enumeratedValues>
                        </field>
                        <field>
                            <name>SAIELSR65</name>
                            <description>Security attributes of registers for IELSR95 to IELSR64</description>
                            <lsb>1</lsb>
                            <msb>1</msb>
                            <access>read-write</access>
                            <enumeratedValues>
                                <enumeratedValue>
                                    <name>0</name>
                                    <description>Secure</description>
                                    <value>#0</value>
                                </enumeratedValue>
                                <enumeratedValue>
                                    <name>1</name>
                                    <description>Non-secure</description>
                                    <value>#1</value>
                                </enumeratedValue>
                            </enumeratedValues>
                        </field>
                        <field>
                            <name>SAIELSR66</name>
                            <description>Security attributes of registers for IELSR95 to IELSR64</description>
                            <lsb>2</lsb>
                            <msb>2</msb>
                            <access>read-write</access>
                            <enumeratedValues>
                                <enumeratedValue>
                                    <name>0</name>
                                    <description>Secure</description>
                                    <value>#0</value>
                                </enumeratedValue>
                                <enumeratedValue>
                                    <name>1</name>
                                    <description>Non-secure</description>
                                    <value>#1</value>
                                </enumeratedValue>
                            </enumeratedValues>
                        </field>
                        <field>
                            <name>SAIELSR67</name>
                            <description>Security attributes of registers for IELSR95 to IELSR64</description>
                            <lsb>3</lsb>
                            <msb>3</msb>
                            <access>read-write</access>
                            <enumeratedValues>
                                <enumeratedValue>
                                    <name>0</name>
                                    <description>Secure</description>
                                    <value>#0</value>
                                </enumeratedValue>
                                <enumeratedValue>
                                    <name>1</name>
                                    <description>Non-secure</description>
                                    <value>#1</value>
                                </enumeratedValue>
                            </enumeratedValues>
                        </field>
                        <field>
                            <name>SAIELSR68</name>
                            <description>Security attributes of registers for IELSR95 to IELSR64</description>
                            <lsb>4</lsb>
                            <msb>4</msb>
                            <access>read-write</access>
                            <enumeratedValues>
                                <enumeratedValue>
                                    <name>0</name>
                                    <description>Secure</description>
                                    <value>#0</value>
                                </enumeratedValue>
                                <enumeratedValue>
                                    <name>1</name>
                                    <description>Non-secure</description>
                                    <value>#1</value>
                                </enumeratedValue>
                            </enumeratedValues>
                        </field>
                        <field>
                            <name>SAIELSR69</name>
                            <description>Security attributes of registers for IELSR95 to IELSR64</description>
                            <lsb>5</lsb>
                            <msb>5</msb>
                            <access>read-write</access>
                            <enumeratedValues>
                                <enumeratedValue>
                                    <name>0</name>
                                    <description>Secure</description>
                                    <value>#0</value>
                                </enumeratedValue>
                                <enumeratedValue>
                                    <name>1</name>
                                    <description>Non-secure</description>
                                    <value>#1</value>
                                </enumeratedValue>
                            </enumeratedValues>
                        </field>
                        <field>
                            <name>SAIELSR70</name>
                            <description>Security attributes of registers for IELSR95 to IELSR64</description>
                            <lsb>6</lsb>
                            <msb>6</msb>
                            <access>read-write</access>
                            <enumeratedValues>
                                <enumeratedValue>
                                    <name>0</name>
                                    <description>Secure</description>
                                    <value>#0</value>
                                </enumeratedValue>
                                <enumeratedValue>
                                    <name>1</name>
                                    <description>Non-secure</description>
                                    <value>#1</value>
                                </enumeratedValue>
                            </enumeratedValues>
                        </field>
                        <field>
                            <name>SAIELSR71</name>
                            <description>Security attributes of registers for IELSR95 to IELSR64</description>
                            <lsb>7</lsb>
                            <msb>7</msb>
                            <access>read-write</access>
                            <enumeratedValues>
                                <enumeratedValue>
                                    <name>0</name>
                                    <description>Secure</description>
                                    <value>#0</value>
                                </enumeratedValue>
                                <enumeratedValue>
                                    <name>1</name>
                                    <description>Non-secure</description>
                                    <value>#1</value>
                                </enumeratedValue>
                            </enumeratedValues>
                        </field>
                        <field>
                            <name>SAIELSR72</name>
                            <description>Security attributes of registers for IELSR95 to IELSR64</description>
                            <lsb>8</lsb>
                            <msb>8</msb>
                            <access>read-write</access>
                            <enumeratedValues>
                                <enumeratedValue>
                                    <name>0</name>
                                    <description>Secure</description>
                                    <value>#0</value>
                                </enumeratedValue>
                                <enumeratedValue>
                                    <name>1</name>
                                    <description>Non-secure</description>
                                    <value>#1</value>
                                </enumeratedValue>
                            </enumeratedValues>
                        </field>
                        <field>
                            <name>SAIELSR73</name>
                            <description>Security attributes of registers for IELSR95 to IELSR64</description>
                            <lsb>9</lsb>
                            <msb>9</msb>
                            <access>read-write</access>
                            <enumeratedValues>
                                <enumeratedValue>
                                    <name>0</name>
                                    <description>Secure</description>
                                    <value>#0</value>
                                </enumeratedValue>
                                <enumeratedValue>
                                    <name>1</name>
                                    <description>Non-secure</description>
                                    <value>#1</value>
                                </enumeratedValue>
                            </enumeratedValues>
                        </field>
                        <field>
                            <name>SAIELSR74</name>
                            <description>Security attributes of registers for IELSR95 to IELSR64</description>
                            <lsb>10</lsb>
                            <msb>10</msb>
                            <access>read-write</access>
                            <enumeratedValues>
                                <enumeratedValue>
                                    <name>0</name>
                                    <description>Secure</description>
                                    <value>#0</value>
                                </enumeratedValue>
                                <enumeratedValue>
                                    <name>1</name>
                                    <description>Non-secure</description>
                                    <value>#1</value>
                                </enumeratedValue>
                            </enumeratedValues>
                        </field>
                        <field>
                            <name>SAIELSR75</name>
                            <description>Security attributes of registers for IELSR95 to IELSR64</description>
                            <lsb>11</lsb>
                            <msb>11</msb>
                            <access>read-write</access>
                            <enumeratedValues>
                                <enumeratedValue>
                                    <name>0</name>
                                    <description>Secure</description>
                                    <value>#0</value>
                                </enumeratedValue>
                                <enumeratedValue>
                                    <name>1</name>
                                    <description>Non-secure</description>
                                    <value>#1</value>
                                </enumeratedValue>
                            </enumeratedValues>
                        </field>
                        <field>
                            <name>SAIELSR76</name>
                            <description>Security attributes of registers for IELSR95 to IELSR64</description>
                            <lsb>12</lsb>
                            <msb>12</msb>
                            <access>read-write</access>
                            <enumeratedValues>
                                <enumeratedValue>
                                    <name>0</name>
                                    <description>Secure</description>
                                    <value>#0</value>
                                </enumeratedValue>
                                <enumeratedValue>
                                    <name>1</name>
                                    <description>Non-secure</description>
                                    <value>#1</value>
                                </enumeratedValue>
                            </enumeratedValues>
                        </field>
                        <field>
                            <name>SAIELSR77</name>
                            <description>Security attributes of registers for IELSR95 to IELSR64</description>
                            <lsb>13</lsb>
                            <msb>13</msb>
                            <access>read-write</access>
                            <enumeratedValues>
                                <enumeratedValue>
                                    <name>0</name>
                                    <description>Secure</description>
                                    <value>#0</value>
                                </enumeratedValue>
                                <enumeratedValue>
                                    <name>1</name>
                                    <description>Non-secure</description>
                                    <value>#1</value>
                                </enumeratedValue>
                            </enumeratedValues>
                        </field>
                        <field>
                            <name>SAIELSR78</name>
                            <description>Security attributes of registers for IELSR95 to IELSR64</description>
                            <lsb>14</lsb>
                            <msb>14</msb>
                            <access>read-write</access>
                            <enumeratedValues>
                                <enumeratedValue>
                                    <name>0</name>
                                    <description>Secure</description>
                                    <value>#0</value>
                                </enumeratedValue>
                                <enumeratedValue>
                                    <name>1</name>
                                    <description>Non-secure</description>
                                    <value>#1</value>
                                </enumeratedValue>
                            </enumeratedValues>
                        </field>
                        <field>
                            <name>SAIELSR79</name>
                            <description>Security attributes of registers for IELSR95 to IELSR64</description>
                            <lsb>15</lsb>
                            <msb>15</msb>
                            <access>read-write</access>
                            <enumeratedValues>
                                <enumeratedValue>
                                    <name>0</name>
                                    <description>Secure</description>
                                    <value>#0</value>
                                </enumeratedValue>
                                <enumeratedValue>
                                    <name>1</name>
                                    <description>Non-secure</description>
                                    <value>#1</value>
                                </enumeratedValue>
                            </enumeratedValues>
                        </field>
                        <field>
                            <name>SAIELSR80</name>
                            <description>Security attributes of registers for IELSR95 to IELSR64</description>
                            <lsb>16</lsb>
                            <msb>16</msb>
                            <access>read-write</access>
                            <enumeratedValues>
                                <enumeratedValue>
                                    <name>0</name>
                                    <description>Secure</description>
                                    <value>#0</value>
                                </enumeratedValue>
                                <enumeratedValue>
                                    <name>1</name>
                                    <description>Non-secure</description>
                                    <value>#1</value>
                                </enumeratedValue>
                            </enumeratedValues>
                        </field>
                        <field>
                            <name>SAIELSR81</name>
                            <description>Security attributes of registers for IELSR95 to IELSR64</description>
                            <lsb>17</lsb>
                            <msb>17</msb>
                            <access>read-write</access>
                            <enumeratedValues>
                                <enumeratedValue>
                                    <name>0</name>
                                    <description>Secure</description>
                                    <value>#0</value>
                                </enumeratedValue>
                                <enumeratedValue>
                                    <name>1</name>
                                    <description>Non-secure</description>
                                    <value>#1</value>
                                </enumeratedValue>
                            </enumeratedValues>
                        </field>
                        <field>
                            <name>SAIELSR82</name>
                            <description>Security attributes of registers for IELSR95 to IELSR64</description>
                            <lsb>18</lsb>
                            <msb>18</msb>
                            <access>read-write</access>
                            <enumeratedValues>
                                <enumeratedValue>
                                    <name>0</name>
                                    <description>Secure</description>
                                    <value>#0</value>
                                </enumeratedValue>
                                <enumeratedValue>
                                    <name>1</name>
                                    <description>Non-secure</description>
                                    <value>#1</value>
                                </enumeratedValue>
                            </enumeratedValues>
                        </field>
                        <field>
                            <name>SAIELSR83</name>
                            <description>Security attributes of registers for IELSR95 to IELSR64</description>
                            <lsb>19</lsb>
                            <msb>19</msb>
                            <access>read-write</access>
                            <enumeratedValues>
                                <enumeratedValue>
                                    <name>0</name>
                                    <description>Secure</description>
                                    <value>#0</value>
                                </enumeratedValue>
                                <enumeratedValue>
                                    <name>1</name>
                                    <description>Non-secure</description>
                                    <value>#1</value>
                                </enumeratedValue>
                            </enumeratedValues>
                        </field>
                        <field>
                            <name>SAIELSR84</name>
                            <description>Security attributes of registers for IELSR95 to IELSR64</description>
                            <lsb>20</lsb>
                            <msb>20</msb>
                            <access>read-write</access>
                            <enumeratedValues>
                                <enumeratedValue>
                                    <name>0</name>
                                    <description>Secure</description>
                                    <value>#0</value>
                                </enumeratedValue>
                                <enumeratedValue>
                                    <name>1</name>
                                    <description>Non-secure</description>
                                    <value>#1</value>
                                </enumeratedValue>
                            </enumeratedValues>
                        </field>
                        <field>
                            <name>SAIELSR85</name>
                            <description>Security attributes of registers for IELSR95 to IELSR64</description>
                            <lsb>21</lsb>
                            <msb>21</msb>
                            <access>read-write</access>
                            <enumeratedValues>
                                <enumeratedValue>
                                    <name>0</name>
                                    <description>Secure</description>
                                    <value>#0</value>
                                </enumeratedValue>
                                <enumeratedValue>
                                    <name>1</name>
                                    <description>Non-secure</description>
                                    <value>#1</value>
                                </enumeratedValue>
                            </enumeratedValues>
                        </field>
                        <field>
                            <name>SAIELSR86</name>
                            <description>Security attributes of registers for IELSR95 to IELSR64</description>
                            <lsb>22</lsb>
                            <msb>22</msb>
                            <access>read-write</access>
                            <enumeratedValues>
                                <enumeratedValue>
                                    <name>0</name>
                                    <description>Secure</description>
                                    <value>#0</value>
                                </enumeratedValue>
                                <enumeratedValue>
                                    <name>1</name>
                                    <description>Non-secure</description>
                                    <value>#1</value>
                                </enumeratedValue>
                            </enumeratedValues>
                        </field>
                        <field>
                            <name>SAIELSR87</name>
                            <description>Security attributes of registers for IELSR95 to IELSR64</description>
                            <lsb>23</lsb>
                            <msb>23</msb>
                            <access>read-write</access>
                            <enumeratedValues>
                                <enumeratedValue>
                                    <name>0</name>
                                    <description>Secure</description>
                                    <value>#0</value>
                                </enumeratedValue>
                                <enumeratedValue>
                                    <name>1</name>
                                    <description>Non-secure</description>
                                    <value>#1</value>
                                </enumeratedValue>
                            </enumeratedValues>
                        </field>
                        <field>
                            <name>SAIELSR88</name>
                            <description>Security attributes of registers for IELSR95 to IELSR64</description>
                            <lsb>24</lsb>
                            <msb>24</msb>
                            <access>read-write</access>
                            <enumeratedValues>
                                <enumeratedValue>
                                    <name>0</name>
                                    <description>Secure</description>
                                    <value>#0</value>
                                </enumeratedValue>
                                <enumeratedValue>
                                    <name>1</name>
                                    <description>Non-secure</description>
                                    <value>#1</value>
                                </enumeratedValue>
                            </enumeratedValues>
                        </field>
                        <field>
                            <name>SAIELSR89</name>
                            <description>Security attributes of registers for IELSR95 to IELSR64</description>
                            <lsb>25</lsb>
                            <msb>25</msb>
                            <access>read-write</access>
                            <enumeratedValues>
                                <enumeratedValue>
                                    <name>0</name>
                                    <description>Secure</description>
                                    <value>#0</value>
                                </enumeratedValue>
                                <enumeratedValue>
                                    <name>1</name>
                                    <description>Non-secure</description>
                                    <value>#1</value>
                                </enumeratedValue>
                            </enumeratedValues>
                        </field>
                        <field>
                            <name>SAIELSR90</name>
                            <description>Security attributes of registers for IELSR95 to IELSR64</description>
                            <lsb>26</lsb>
                            <msb>26</msb>
                            <access>read-write</access>
                            <enumeratedValues>
                                <enumeratedValue>
                                    <name>0</name>
                                    <description>Secure</description>
                                    <value>#0</value>
                                </enumeratedValue>
                                <enumeratedValue>
                                    <name>1</name>
                                    <description>Non-secure</description>
                                    <value>#1</value>
                                </enumeratedValue>
                            </enumeratedValues>
                        </field>
                        <field>
                            <name>SAIELSR91</name>
                            <description>Security attributes of registers for IELSR95 to IELSR64</description>
                            <lsb>27</lsb>
                            <msb>27</msb>
                            <access>read-write</access>
                            <enumeratedValues>
                                <enumeratedValue>
                                    <name>0</name>
                                    <description>Secure</description>
                                    <value>#0</value>
                                </enumeratedValue>
                                <enumeratedValue>
                                    <name>1</name>
                                    <description>Non-secure</description>
                                    <value>#1</value>
                                </enumeratedValue>
                            </enumeratedValues>
                        </field>
                        <field>
                            <name>SAIELSR92</name>
                            <description>Security attributes of registers for IELSR95 to IELSR64</description>
                            <lsb>28</lsb>
                            <msb>28</msb>
                            <access>read-write</access>
                            <enumeratedValues>
                                <enumeratedValue>
                                    <name>0</name>
                                    <description>Secure</description>
                                    <value>#0</value>
                                </enumeratedValue>
                                <enumeratedValue>
                                    <name>1</name>
                                    <description>Non-secure</description>
                                    <value>#1</value>
                                </enumeratedValue>
                            </enumeratedValues>
                        </field>
                        <field>
                            <name>SAIELSR93</name>
                            <description>Security attributes of registers for IELSR95 to IELSR64</description>
                            <lsb>29</lsb>
                            <msb>29</msb>
                            <access>read-write</access>
                            <enumeratedValues>
                                <enumeratedValue>
                                    <name>0</name>
                                    <description>Secure</description>
                                    <value>#0</value>
                                </enumeratedValue>
                                <enumeratedValue>
                                    <name>1</name>
                                    <description>Non-secure</description>
                                    <value>#1</value>
                                </enumeratedValue>
                            </enumeratedValues>
                        </field>
                        <field>
                            <name>SAIELSR94</name>
                            <description>Security attributes of registers for IELSR95 to IELSR64</description>
                            <lsb>30</lsb>
                            <msb>30</msb>
                            <access>read-write</access>
                            <enumeratedValues>
                                <enumeratedValue>
                                    <name>0</name>
                                    <description>Secure</description>
                                    <value>#0</value>
                                </enumeratedValue>
                                <enumeratedValue>
                                    <name>1</name>
                                    <description>Non-secure</description>
                                    <value>#1</value>
                                </enumeratedValue>
                            </enumeratedValues>
                        </field>
                        <field>
                            <name>SAIELSR95</name>
                            <description>Security attributes of registers for IELSR95 to IELSR64</description>
                            <lsb>31</lsb>
                            <msb>31</msb>
                            <access>read-write</access>
                            <enumeratedValues>
                                <enumeratedValue>
                                    <name>0</name>
                                    <description>Secure</description>
                                    <value>#0</value>
                                </enumeratedValue>
                                <enumeratedValue>
                                    <name>1</name>
                                    <description>Non-secure</description>
                                    <value>#1</value>
                                </enumeratedValue>
                            </enumeratedValues>
                        </field>
                    </fields>
                </register>
                <register>
                    <name>BUSSARA</name>
                    <description>Bus Security Attribution Register A</description>
                    <addressOffset>0x100</addressOffset>
                    <size>32</size>
                    <access>read-write</access>
                    <resetValue>0x00000000</resetValue>
                    <resetMask>0xffffffff</resetMask>
                    <fields>
                        <field>
                            <name>BUSSA0</name>
                            <description>Bus Security Attribution A0</description>
                            <lsb>0</lsb>
                            <msb>0</msb>
                            <access>read-write</access>
                            <enumeratedValues>
                                <enumeratedValue>
                                    <name>0</name>
                                    <description>Secure</description>
                                    <value>#0</value>
                                </enumeratedValue>
                                <enumeratedValue>
                                    <name>1</name>
                                    <description>Non-secure</description>
                                    <value>#1</value>
                                </enumeratedValue>
                            </enumeratedValues>
                        </field>
                    </fields>
                </register>
                <register>
                    <name>BUSSARB</name>
                    <description>Bus Security Attribution Register B</description>
                    <addressOffset>0x104</addressOffset>
                    <size>32</size>
                    <access>read-write</access>
                    <resetValue>0x00000000</resetValue>
                    <resetMask>0xffffffff</resetMask>
                    <fields>
                        <field>
                            <name>BUSSB0</name>
                            <description>Bus Security Attribution B0</description>
                            <lsb>0</lsb>
                            <msb>0</msb>
                            <access>read-write</access>
                            <enumeratedValues>
                                <enumeratedValue>
                                    <name>0</name>
                                    <description>Secure</description>
                                    <value>#0</value>
                                </enumeratedValue>
                                <enumeratedValue>
                                    <name>1</name>
                                    <description>Non-secure</description>
                                    <value>#1</value>
                                </enumeratedValue>
                            </enumeratedValues>
                        </field>
                    </fields>
                </register>
                <register>
                    <name>BUSSARC</name>
                    <description>Bus Security Attribution Register C</description>
                    <addressOffset>0x110</addressOffset>
                    <size>32</size>
                    <access>read-write</access>
                    <resetValue>0x00000000</resetValue>
                    <resetMask>0xffffffff</resetMask>
                    <fields>
                        <field>
                            <name>BUSSC0</name>
                            <description>Bus Security Attribution C0</description>
                            <lsb>0</lsb>
                            <msb>0</msb>
                            <access>read-write</access>
                            <enumeratedValues>
                                <enumeratedValue>
                                    <name>0</name>
                                    <description>Secure</description>
                                    <value>#0</value>
                                </enumeratedValue>
                                <enumeratedValue>
                                    <name>1</name>
                                    <description>Non-secure</description>
                                    <value>#1</value>
                                </enumeratedValue>
                            </enumeratedValues>
                        </field>
                    </fields>
                </register>
                <register>
                    <name>BUSPARC</name>
                    <description>Bus Privileged Attribution Register C</description>
                    <addressOffset>0x114</addressOffset>
                    <size>32</size>
                    <access>read-write</access>
                    <resetValue>0xffffffff</resetValue>
                    <resetMask>0xffffffff</resetMask>
                    <fields>
                        <field>
                            <name>BUSPA0</name>
                            <description>External bus controller privilege attribution</description>
                            <lsb>0</lsb>
                            <msb>0</msb>
                            <access>read-write</access>
                            <enumeratedValues>
                                <enumeratedValue>
                                    <name>0</name>
                                    <description>Privileged</description>
                                    <value>#0</value>
                                </enumeratedValue>
                                <enumeratedValue>
                                    <name>1</name>
                                    <description>Unprivileged </description>
                                    <value>#1</value>
                                </enumeratedValue>
                            </enumeratedValues>
                        </field>
                    </fields>
                </register>
                <register>
                    <name>MMPUSARA</name>
                    <description>Master Memory Protection Unit Security Attribution Register A</description>
                    <addressOffset>0x130</addressOffset>
                    <size>32</size>
                    <access>read-write</access>
                    <resetValue>0x00000000</resetValue>
                    <resetMask>0xffffffff</resetMask>
                    <fields>
                        <field>
                            <name>MMPUASAn</name>
                            <description>MMPUA Security Attribution n (n = 0 to 7)</description>
                            <lsb>0</lsb>
                            <msb>7</msb>
                            <access>read-write</access>
                            <enumeratedValues>
                                <enumeratedValue>
                                    <name>0</name>
                                    <description>Secure</description>
                                    <value>#0</value>
                                </enumeratedValue>
                                <enumeratedValue>
                                    <name>1</name>
                                    <description>Non-secure</description>
                                    <value>#1</value>
                                </enumeratedValue>
                            </enumeratedValues>
                        </field>
                    </fields>
                </register>
                <register>
                    <name>MMPUSARB</name>
                    <description>Master Memory Protection Unit Security Attribution Register B</description>
                    <addressOffset>0x134</addressOffset>
                    <size>32</size>
                    <access>read-write</access>
                    <resetValue>0x00000000</resetValue>
                    <resetMask>0xffffffff</resetMask>
                    <fields>
                        <field>
                            <name>MMPUBSA0</name>
                            <description>MMPUB Security Attribution 0</description>
                            <lsb>0</lsb>
                            <msb>0</msb>
                            <access>read-write</access>
                            <enumeratedValues>
                                <enumeratedValue>
                                    <name>0</name>
                                    <description>Secure</description>
                                    <value>#0</value>
                                </enumeratedValue>
                                <enumeratedValue>
                                    <name>1</name>
                                    <description>Non-secure</description>
                                    <value>#1</value>
                                </enumeratedValue>
                            </enumeratedValues>
                        </field>
                        <field>
                            <name>MMPUBSA8</name>
                            <description>MMPUB Security Attribution 8</description>
                            <lsb>8</lsb>
                            <msb>8</msb>
                            <access>read-write</access>
                            <enumeratedValues>
                                <enumeratedValue>
                                    <name>0</name>
                                    <description>Secure</description>
                                    <value>#0</value>
                                </enumeratedValue>
                                <enumeratedValue>
                                    <name>1</name>
                                    <description>Non-secure</description>
                                    <value>#1</value>
                                </enumeratedValue>
                            </enumeratedValues>
                        </field>
                    </fields>
                </register>
                <register>
                    <name>CPUSAR</name>
                    <description>CPU Security Attribution Register</description>
                    <addressOffset>0x170</addressOffset>
                    <size>32</size>
                    <access>read-write</access>
                    <resetValue>0x00000000</resetValue>
                    <resetMask>0xffffffff</resetMask>
                    <fields>
                        <field>
                            <name>CPUSA0</name>
                            <description>CPU Control Registers Security Attribution</description>
                            <lsb>0</lsb>
                            <msb>0</msb>
                            <access>read-write</access>
                            <enumeratedValues>
                                <enumeratedValue>
                                    <name>0</name>
                                    <description>Secure</description>
                                    <value>#0</value>
                                </enumeratedValue>
                                <enumeratedValue>
                                    <name>1</name>
                                    <description>Non-secure</description>
                                    <value>#1</value>
                                </enumeratedValue>
                            </enumeratedValues>
                        </field>
                    </fields>
                </register>
                <register>
                    <name>DEBUGSAR</name>
                    <description>Debug Security Attribution Register</description>
                    <addressOffset>0x180</addressOffset>
                    <size>32</size>
                    <access>read-write</access>
                    <resetValue>0x00000000</resetValue>
                    <resetMask>0xffffffff</resetMask>
                    <fields>
                        <field>
                            <name>DBGSA0</name>
                            <description>Debug Resources Security Attribution 0</description>
                            <lsb>0</lsb>
                            <msb>0</msb>
                            <access>read-write</access>
                            <enumeratedValues>
                                <enumeratedValue>
                                    <name>0</name>
                                    <description>Secure</description>
                                    <value>#0</value>
                                </enumeratedValue>
                                <enumeratedValue>
                                    <name>1</name>
                                    <description>Non-secure</description>
                                    <value>#1</value>
                                </enumeratedValue>
                            </enumeratedValues>
                        </field>
                    </fields>
                </register>
                <register>
                    <name>DMACCHSAR</name>
                    <description>DMA channel Security Attribution Register</description>
                    <addressOffset>0x1A0</addressOffset>
                    <size>32</size>
                    <access>read-write</access>
                    <resetValue>0x00000000</resetValue>
                    <resetMask>0xffffffff</resetMask>
                    <fields>
                        <field>
                            <name>SADMAC0</name>
                            <description>Security attributes of output and registers for DMAC channel</description>
                            <lsb>0</lsb>
                            <msb>0</msb>
                            <access>read-write</access>
                            <enumeratedValues>
                                <enumeratedValue>
                                    <name>0</name>
                                    <description>Secure</description>
                                    <value>#0</value>
                                </enumeratedValue>
                                <enumeratedValue>
                                    <name>1</name>
                                    <description>Non-secure</description>
                                    <value>#1</value>
                                </enumeratedValue>
                            </enumeratedValues>
                        </field>
                        <field>
                            <name>SADMAC1</name>
                            <description>Security attributes of output and registers for DMAC channel</description>
                            <lsb>1</lsb>
                            <msb>1</msb>
                            <access>read-write</access>
                            <enumeratedValues>
                                <enumeratedValue>
                                    <name>0</name>
                                    <description>Secure</description>
                                    <value>#0</value>
                                </enumeratedValue>
                                <enumeratedValue>
                                    <name>1</name>
                                    <description>Non-secure</description>
                                    <value>#1</value>
                                </enumeratedValue>
                            </enumeratedValues>
                        </field>
                        <field>
                            <name>SADMAC2</name>
                            <description>Security attributes of output and registers for DMAC channel</description>
                            <lsb>2</lsb>
                            <msb>2</msb>
                            <access>read-write</access>
                            <enumeratedValues>
                                <enumeratedValue>
                                    <name>0</name>
                                    <description>Secure</description>
                                    <value>#0</value>
                                </enumeratedValue>
                                <enumeratedValue>
                                    <name>1</name>
                                    <description>Non-secure</description>
                                    <value>#1</value>
                                </enumeratedValue>
                            </enumeratedValues>
                        </field>
                        <field>
                            <name>SADMAC3</name>
                            <description>Security attributes of output and registers for DMAC channel</description>
                            <lsb>3</lsb>
                            <msb>3</msb>
                            <access>read-write</access>
                            <enumeratedValues>
                                <enumeratedValue>
                                    <name>0</name>
                                    <description>Secure</description>
                                    <value>#0</value>
                                </enumeratedValue>
                                <enumeratedValue>
                                    <name>1</name>
                                    <description>Non-secure</description>
                                    <value>#1</value>
                                </enumeratedValue>
                            </enumeratedValues>
                        </field>
                        <field>
                            <name>SADMAC4</name>
                            <description>Security attributes of output and registers for DMAC channel</description>
                            <lsb>4</lsb>
                            <msb>4</msb>
                            <access>read-write</access>
                            <enumeratedValues>
                                <enumeratedValue>
                                    <name>0</name>
                                    <description>Secure</description>
                                    <value>#0</value>
                                </enumeratedValue>
                                <enumeratedValue>
                                    <name>1</name>
                                    <description>Non-secure</description>
                                    <value>#1</value>
                                </enumeratedValue>
                            </enumeratedValues>
                        </field>
                        <field>
                            <name>SADMAC5</name>
                            <description>Security attributes of output and registers for DMAC channel</description>
                            <lsb>5</lsb>
                            <msb>5</msb>
                            <access>read-write</access>
                            <enumeratedValues>
                                <enumeratedValue>
                                    <name>0</name>
                                    <description>Secure</description>
                                    <value>#0</value>
                                </enumeratedValue>
                                <enumeratedValue>
                                    <name>1</name>
                                    <description>Non-secure</description>
                                    <value>#1</value>
                                </enumeratedValue>
                            </enumeratedValues>
                        </field>
                        <field>
                            <name>SADMAC6</name>
                            <description>Security attributes of output and registers for DMAC channel</description>
                            <lsb>6</lsb>
                            <msb>6</msb>
                            <access>read-write</access>
                            <enumeratedValues>
                                <enumeratedValue>
                                    <name>0</name>
                                    <description>Secure</description>
                                    <value>#0</value>
                                </enumeratedValue>
                                <enumeratedValue>
                                    <name>1</name>
                                    <description>Non-secure</description>
                                    <value>#1</value>
                                </enumeratedValue>
                            </enumeratedValues>
                        </field>
                        <field>
                            <name>SADMAC7</name>
                            <description>Security attributes of output and registers for DMAC channel</description>
                            <lsb>7</lsb>
                            <msb>7</msb>
                            <access>read-write</access>
                            <enumeratedValues>
                                <enumeratedValue>
                                    <name>0</name>
                                    <description>Secure</description>
                                    <value>#0</value>
                                </enumeratedValue>
                                <enumeratedValue>
                                    <name>1</name>
                                    <description>Non-secure</description>
                                    <value>#1</value>
                                </enumeratedValue>
                            </enumeratedValues>
                        </field>
                    </fields>
                </register>
                <register>
                    <name>DMACCHPAR</name>
                    <description>DMA channel Privilege Attribution Register</description>
                    <addressOffset>0x1F0</addressOffset>
                    <size>32</size>
                    <access>read-write</access>
                    <resetValue>0xffffffff</resetValue>
                    <resetMask>0xffffffff</resetMask>
                    <fields>
                        <field>
                            <name>PADMAC0</name>
                            <description>Privilege attributes of outputs and registers for DMAC channel</description>
                            <lsb>0</lsb>
                            <msb>0</msb>
                            <access>read-write</access>
                            <enumeratedValues>
                                <enumeratedValue>
                                    <name>0</name>
                                    <description>Privileged.</description>
                                    <value>#0</value>
                                </enumeratedValue>
                                <enumeratedValue>
                                    <name>1</name>
                                    <description>Unprivileged.</description>
                                    <value>#1</value>
                                </enumeratedValue>
                            </enumeratedValues>
                        </field>
                        <field>
                            <name>PADMAC1</name>
                            <description>Privilege attributes of outputs and registers for DMAC channel</description>
                            <lsb>1</lsb>
                            <msb>1</msb>
                            <access>read-write</access>
                            <enumeratedValues>
                                <enumeratedValue>
                                    <name>0</name>
                                    <description>Privileged.</description>
                                    <value>#0</value>
                                </enumeratedValue>
                                <enumeratedValue>
                                    <name>1</name>
                                    <description>Unprivileged.</description>
                                    <value>#1</value>
                                </enumeratedValue>
                            </enumeratedValues>
                        </field>
                        <field>
                            <name>PADMAC2</name>
                            <description>Privilege attributes of outputs and registers for DMAC channel</description>
                            <lsb>2</lsb>
                            <msb>2</msb>
                            <access>read-write</access>
                            <enumeratedValues>
                                <enumeratedValue>
                                    <name>0</name>
                                    <description>Privileged.</description>
                                    <value>#0</value>
                                </enumeratedValue>
                                <enumeratedValue>
                                    <name>1</name>
                                    <description>Unprivileged.</description>
                                    <value>#1</value>
                                </enumeratedValue>
                            </enumeratedValues>
                        </field>
                        <field>
                            <name>PADMAC3</name>
                            <description>Privilege attributes of outputs and registers for DMAC channel</description>
                            <lsb>3</lsb>
                            <msb>3</msb>
                            <access>read-write</access>
                            <enumeratedValues>
                                <enumeratedValue>
                                    <name>0</name>
                                    <description>Privileged.</description>
                                    <value>#0</value>
                                </enumeratedValue>
                                <enumeratedValue>
                                    <name>1</name>
                                    <description>Unprivileged.</description>
                                    <value>#1</value>
                                </enumeratedValue>
                            </enumeratedValues>
                        </field>
                        <field>
                            <name>PADMAC4</name>
                            <description>Privilege attributes of outputs and registers for DMAC channel</description>
                            <lsb>4</lsb>
                            <msb>4</msb>
                            <access>read-write</access>
                            <enumeratedValues>
                                <enumeratedValue>
                                    <name>0</name>
                                    <description>Privileged.</description>
                                    <value>#0</value>
                                </enumeratedValue>
                                <enumeratedValue>
                                    <name>1</name>
                                    <description>Unprivileged.</description>
                                    <value>#1</value>
                                </enumeratedValue>
                            </enumeratedValues>
                        </field>
                        <field>
                            <name>PADMAC5</name>
                            <description>Privilege attributes of outputs and registers for DMAC channel</description>
                            <lsb>5</lsb>
                            <msb>5</msb>
                            <access>read-write</access>
                            <enumeratedValues>
                                <enumeratedValue>
                                    <name>0</name>
                                    <description>Privileged.</description>
                                    <value>#0</value>
                                </enumeratedValue>
                                <enumeratedValue>
                                    <name>1</name>
                                    <description>Unprivileged.</description>
                                    <value>#1</value>
                                </enumeratedValue>
                            </enumeratedValues>
                        </field>
                        <field>
                            <name>PADMAC6</name>
                            <description>Privilege attributes of outputs and registers for DMAC channel</description>
                            <lsb>6</lsb>
                            <msb>6</msb>
                            <access>read-write</access>
                            <enumeratedValues>
                                <enumeratedValue>
                                    <name>0</name>
                                    <description>Privileged.</description>
                                    <value>#0</value>
                                </enumeratedValue>
                                <enumeratedValue>
                                    <name>1</name>
                                    <description>Unprivileged.</description>
                                    <value>#1</value>
                                </enumeratedValue>
                            </enumeratedValues>
                        </field>
                        <field>
                            <name>PADMAC7</name>
                            <description>Privilege attributes of outputs and registers for DMAC channel</description>
                            <lsb>7</lsb>
                            <msb>7</msb>
                            <access>read-write</access>
                            <enumeratedValues>
                                <enumeratedValue>
                                    <name>0</name>
                                    <description>Privileged.</description>
                                    <value>#0</value>
                                </enumeratedValue>
                                <enumeratedValue>
                                    <name>1</name>
                                    <description>Unprivileged.</description>
                                    <value>#1</value>
                                </enumeratedValue>
                            </enumeratedValues>
                        </field>
                    </fields>
                </register>
                <register>
                    <dim>2</dim>
                    <dimIncrement>0x04</dimIncrement>
                    <dimIndex>0-1</dimIndex>
                    <name>SRAMSABAR%s</name>
                    <description>SRAM Security Attribute Boundary Address Register (n = 0, 1)</description>
                    <addressOffset>0x400</addressOffset>
                    <size>32</size>
                    <access>read-write</access>
                    <resetValue>0x001fe000</resetValue>
                    <resetMask>0xffffffff</resetMask>
                </register>
                <register>
                    <name>STBRAMSABAR</name>
                    <description>Standby SRAM Security Attribute Boundary Address Register</description>
                    <addressOffset>0x420</addressOffset>
                    <size>32</size>
                    <access>read-write</access>
                    <resetValue>0x00007f80</resetValue>
                    <resetMask>0xffffffff</resetMask>
                </register>
                <register>
                    <name>STBRAMPABAR_S</name>
                    <description>Standby SRAM Privilege Attribute Boundary Address Register for Secure</description>
                    <addressOffset>0x494</addressOffset>
                    <size>32</size>
                    <access>read-write</access>
                    <resetValue>0x00000000</resetValue>
                    <resetMask>0xffffffff</resetMask>
                </register>
                <register>
                    <name>TEVTRCR</name>
                    <description>Trusted Event Route Control Register</description>
                    <addressOffset>0x600</addressOffset>
                    <size>32</size>
                    <access>read-write</access>
                    <resetValue>0x00000000</resetValue>
                    <resetMask>0xffffffff</resetMask>
                    <fields>
                        <field>
                            <name>TEVTE</name>
                            <description>Trusted Event Route Control Register for IELSRn, DELSRn and ELCSRn</description>
                            <lsb>0</lsb>
                            <msb>0</msb>
                            <access>read-write</access>
                            <enumeratedValues>
                                <enumeratedValue>
                                    <name>0</name>
                                    <description>Disable</description>
                                    <value>#0</value>
                                </enumeratedValue>
                                <enumeratedValue>
                                    <name>1</name>
                                    <description>Enable</description>
                                    <value>#1</value>
                                </enumeratedValue>
                            </enumeratedValues>
                        </field>
                    </fields>
                </register>
            </registers>
        </peripheral>
        <peripheral>
            <name>DMAC00</name>
            <description>Direct memory access controller 0</description>
            <baseAddress>0x4000A000</baseAddress>
            <addressBlock>
                <offset>0x00</offset>
                <size>18</size>
                <usage>registers</usage>
            </addressBlock>
            <addressBlock>
                <offset>0x13</offset>
                <size>3</size>
                <usage>registers</usage>
            </addressBlock>
            <addressBlock>
                <offset>0x18</offset>
                <size>7</size>
                <usage>registers</usage>
            </addressBlock>
            <addressBlock>
                <offset>0x20</offset>
                <size>17</size>
                <usage>registers</usage>
            </addressBlock>
            <registers>
                <register>
                    <name>DMSAR</name>
                    <description>DMA Source Address Register</description>
                    <addressOffset>0x00</addressOffset>
                    <size>32</size>
                    <access>read-write</access>
                    <resetValue>0x00000000</resetValue>
                    <resetMask>0xffffffff</resetMask>
                </register>
                <register>
                    <name>DMDAR</name>
                    <description>DMA Destination Address Register</description>
                    <addressOffset>0x04</addressOffset>
                    <size>32</size>
                    <access>read-write</access>
                    <resetValue>0x00000000</resetValue>
                    <resetMask>0xffffffff</resetMask>
                </register>
                <register>
                    <name>DMCRA</name>
                    <description>DMA Transfer Count Register</description>
                    <addressOffset>0x08</addressOffset>
                    <size>32</size>
                    <access>read-write</access>
                    <resetValue>0x00000000</resetValue>
                    <resetMask>0xffffffff</resetMask>
                    <fields>
                        <field>
                            <name>DMCRAL</name>
                            <description>Lower bits of transfer count</description>
                            <lsb>0</lsb>
                            <msb>15</msb>
                            <access>read-write</access>
                        </field>
                        <field>
                            <name>DMCRAH</name>
                            <description>Upper bits of transfer count</description>
                            <lsb>16</lsb>
                            <msb>25</msb>
                            <access>read-write</access>
                        </field>
                    </fields>
                </register>
                <register>
                    <name>DMCRB</name>
                    <description>DMA Block Transfer Count Register</description>
                    <addressOffset>0x0C</addressOffset>
                    <size>32</size>
                    <access>read-write</access>
                    <resetValue>0x00000000</resetValue>
                    <resetMask>0xffffffff</resetMask>
                    <fields>
                        <field>
                            <name>DMCRBL</name>
                            <description>Functions as a number of block, repeat or repeat-block transfer counter.</description>
                            <lsb>0</lsb>
                            <msb>15</msb>
                            <access>read-write</access>
                        </field>
                        <field>
                            <name>DMCRBH</name>
                            <description>Specifies the number of block, repeat or repeat-block transfer operations.</description>
                            <lsb>16</lsb>
                            <msb>31</msb>
                            <access>read-write</access>
                        </field>
                    </fields>
                </register>
                <register>
                    <name>DMTMD</name>
                    <description>DMA Transfer Mode Register</description>
                    <addressOffset>0x10</addressOffset>
                    <size>16</size>
                    <access>read-write</access>
                    <resetValue>0x0000</resetValue>
                    <resetMask>0xffff</resetMask>
                    <fields>
                        <field>
                            <name>DCTG</name>
                            <description>Transfer Request Source Select</description>
                            <lsb>0</lsb>
                            <msb>1</msb>
                            <access>read-write</access>
                            <enumeratedValues>
                                <enumeratedValue>
                                    <name>00</name>
                                    <description>Software request</description>
                                    <value>#00</value>
                                </enumeratedValue>
                                <enumeratedValue>
                                    <name>01</name>
                                    <description>Hardware request</description>
                                    <value>#01</value>
                                </enumeratedValue>
                                <enumeratedValue>
                                    <name>10</name>
                                    <description>Setting prohibited</description>
                                    <value>#10</value>
                                </enumeratedValue>
                                <enumeratedValue>
                                    <name>11</name>
                                    <description>Setting prohibited</description>
                                    <value>#11</value>
                                </enumeratedValue>
                            </enumeratedValues>
                        </field>
                        <field>
                            <name>SZ</name>
                            <description>Transfer Data Size Select</description>
                            <lsb>8</lsb>
                            <msb>9</msb>
                            <access>read-write</access>
                            <enumeratedValues>
                                <enumeratedValue>
                                    <name>00</name>
                                    <description>8 bits</description>
                                    <value>#00</value>
                                </enumeratedValue>
                                <enumeratedValue>
                                    <name>01</name>
                                    <description>16 bits</description>
                                    <value>#01</value>
                                </enumeratedValue>
                                <enumeratedValue>
                                    <name>10</name>
                                    <description>32 bits</description>
                                    <value>#10</value>
                                </enumeratedValue>
                                <enumeratedValue>
                                    <name>11</name>
                                    <description>Setting prohibited</description>
                                    <value>#11</value>
                                </enumeratedValue>
                            </enumeratedValues>
                        </field>
                        <field>
                            <name>TKP</name>
                            <description>Transfer Keeping</description>
                            <lsb>10</lsb>
                            <msb>10</msb>
                            <access>read-write</access>
                            <enumeratedValues>
                                <enumeratedValue>
                                    <name>0</name>
                                    <description>Transfer is stopped by completion of specified total number of transfer operations.</description>
                                    <value>#0</value>
                                </enumeratedValue>
                                <enumeratedValue>
                                    <name>1</name>
                                    <description>Transfer is not stopped by completion of specified total number of transfer operations (free-running).</description>
                                    <value>#1</value>
                                </enumeratedValue>
                            </enumeratedValues>
                        </field>
                        <field>
                            <name>DTS</name>
                            <description>Repeat Area Select</description>
                            <lsb>12</lsb>
                            <msb>13</msb>
                            <access>read-write</access>
                            <enumeratedValues>
                                <enumeratedValue>
                                    <name>00</name>
                                    <description>The destination is specified as the repeat area or block area.</description>
                                    <value>#00</value>
                                </enumeratedValue>
                                <enumeratedValue>
                                    <name>01</name>
                                    <description>The source is specified as the repeat area or block area.</description>
                                    <value>#01</value>
                                </enumeratedValue>
                                <enumeratedValue>
                                    <name>10</name>
                                    <description>The repeat area or block area is not specified.</description>
                                    <value>#10</value>
                                </enumeratedValue>
                                <enumeratedValue>
                                    <name>11</name>
                                    <description>Setting prohibited.</description>
                                    <value>#11</value>
                                </enumeratedValue>
                            </enumeratedValues>
                        </field>
                        <field>
                            <name>MD</name>
                            <description>Transfer Mode Select</description>
                            <lsb>14</lsb>
                            <msb>15</msb>
                            <access>read-write</access>
                            <enumeratedValues>
                                <enumeratedValue>
                                    <name>00</name>
                                    <description>Normal transfer</description>
                                    <value>#00</value>
                                </enumeratedValue>
                                <enumeratedValue>
                                    <name>01</name>
                                    <description>Repeat transfer</description>
                                    <value>#01</value>
                                </enumeratedValue>
                                <enumeratedValue>
                                    <name>10</name>
                                    <description>Block transfer</description>
                                    <value>#10</value>
                                </enumeratedValue>
                                <enumeratedValue>
                                    <name>11</name>
                                    <description>Repeat-block transfer</description>
                                    <value>#11</value>
                                </enumeratedValue>
                            </enumeratedValues>
                        </field>
                    </fields>
                </register>
                <register>
                    <name>DMINT</name>
                    <description>DMA Interrupt Setting Register</description>
                    <addressOffset>0x13</addressOffset>
                    <size>8</size>
                    <access>read-write</access>
                    <resetValue>0x00</resetValue>
                    <resetMask>0xff</resetMask>
                    <fields>
                        <field>
                            <name>DARIE</name>
                            <description>Destination Address Extended Repeat Area Overflow Interrupt Enable</description>
                            <lsb>0</lsb>
                            <msb>0</msb>
                            <access>read-write</access>
                            <enumeratedValues>
                                <enumeratedValue>
                                    <name>0</name>
                                    <description>Disables an interrupt request for an extended repeat area overflow on the destination address.</description>
                                    <value>#0</value>
                                </enumeratedValue>
                                <enumeratedValue>
                                    <name>1</name>
                                    <description>Enables an interrupt request for an extended repeat area overflow on the destination address.</description>
                                    <value>#1</value>
                                </enumeratedValue>
                            </enumeratedValues>
                        </field>
                        <field>
                            <name>SARIE</name>
                            <description>Source Address Extended Repeat Area Overflow Interrupt Enable</description>
                            <lsb>1</lsb>
                            <msb>1</msb>
                            <access>read-write</access>
                            <enumeratedValues>
                                <enumeratedValue>
                                    <name>0</name>
                                    <description>Disables an interrupt request for an extended repeat area overflow on the source address.</description>
                                    <value>#0</value>
                                </enumeratedValue>
                                <enumeratedValue>
                                    <name>1</name>
                                    <description>Enables an interrupt request for an extended repeat area overflow on the source address.</description>
                                    <value>#1</value>
                                </enumeratedValue>
                            </enumeratedValues>
                        </field>
                        <field>
                            <name>RPTIE</name>
                            <description>Repeat Size End Interrupt Enable</description>
                            <lsb>2</lsb>
                            <msb>2</msb>
                            <access>read-write</access>
                            <enumeratedValues>
                                <enumeratedValue>
                                    <name>0</name>
                                    <description>Disables the repeat size end interrupt request.</description>
                                    <value>#0</value>
                                </enumeratedValue>
                                <enumeratedValue>
                                    <name>1</name>
                                    <description>Enables the repeat size end interrupt request.</description>
                                    <value>#1</value>
                                </enumeratedValue>
                            </enumeratedValues>
                        </field>
                        <field>
                            <name>ESIE</name>
                            <description>Transfer Escape End Interrupt Enable</description>
                            <lsb>3</lsb>
                            <msb>3</msb>
                            <access>read-write</access>
                            <enumeratedValues>
                                <enumeratedValue>
                                    <name>0</name>
                                    <description>Disables the transfer escape end interrupt request.</description>
                                    <value>#0</value>
                                </enumeratedValue>
                                <enumeratedValue>
                                    <name>1</name>
                                    <description>Enables the transfer escape end interrupt request.</description>
                                    <value>#1</value>
                                </enumeratedValue>
                            </enumeratedValues>
                        </field>
                        <field>
                            <name>DTIE</name>
                            <description>Transfer End Interrupt Enable</description>
                            <lsb>4</lsb>
                            <msb>4</msb>
                            <access>read-write</access>
                            <enumeratedValues>
                                <enumeratedValue>
                                    <name>0</name>
                                    <description>Disables the transfer end interrupt request.</description>
                                    <value>#0</value>
                                </enumeratedValue>
                                <enumeratedValue>
                                    <name>1</name>
                                    <description>Enables the transfer end interrupt request.</description>
                                    <value>#1</value>
                                </enumeratedValue>
                            </enumeratedValues>
                        </field>
                    </fields>
                </register>
                <register>
                    <name>DMAMD</name>
                    <description>DMA Address Mode Register</description>
                    <addressOffset>0x14</addressOffset>
                    <size>16</size>
                    <access>read-write</access>
                    <resetValue>0x0000</resetValue>
                    <resetMask>0xffff</resetMask>
                    <fields>
                        <field>
                            <name>DARA</name>
                            <description>Destination Address Extended Repeat Area</description>
                            <lsb>0</lsb>
                            <msb>4</msb>
                            <access>read-write</access>
                        </field>
                        <field>
                            <name>DADR</name>
                            <description>Destination Address Update Select After Reload</description>
                            <lsb>5</lsb>
                            <msb>5</msb>
                            <access>read-write</access>
                            <enumeratedValues>
                                <enumeratedValue>
                                    <name>0</name>
                                    <description>Only reloading.</description>
                                    <value>#0</value>
                                </enumeratedValue>
                                <enumeratedValue>
                                    <name>1</name>
                                    <description>Add index after reloading.</description>
                                    <value>#1</value>
                                </enumeratedValue>
                            </enumeratedValues>
                        </field>
                        <field>
                            <name>DM</name>
                            <description>Destination Address Update Mode</description>
                            <lsb>6</lsb>
                            <msb>7</msb>
                            <access>read-write</access>
                            <enumeratedValues>
                                <enumeratedValue>
                                    <name>00</name>
                                    <description>Destination address is fixed.</description>
                                    <value>#00</value>
                                </enumeratedValue>
                                <enumeratedValue>
                                    <name>01</name>
                                    <description>Offset addition.</description>
                                    <value>#01</value>
                                </enumeratedValue>
                                <enumeratedValue>
                                    <name>10</name>
                                    <description>Destination address is incremented.</description>
                                    <value>#10</value>
                                </enumeratedValue>
                                <enumeratedValue>
                                    <name>11</name>
                                    <description>Destination address is decremented.</description>
                                    <value>#11</value>
                                </enumeratedValue>
                            </enumeratedValues>
                        </field>
                        <field>
                            <name>SARA</name>
                            <description>Source Address Extended Repeat Area</description>
                            <lsb>8</lsb>
                            <msb>12</msb>
                            <access>read-write</access>
                        </field>
                        <field>
                            <name>SADR</name>
                            <description>Source Address Update Select After Reload</description>
                            <lsb>13</lsb>
                            <msb>13</msb>
                            <access>read-write</access>
                            <enumeratedValues>
                                <enumeratedValue>
                                    <name>0</name>
                                    <description>Only reloading.</description>
                                    <value>#0</value>
                                </enumeratedValue>
                                <enumeratedValue>
                                    <name>1</name>
                                    <description>Add index after reloading.</description>
                                    <value>#1</value>
                                </enumeratedValue>
                            </enumeratedValues>
                        </field>
                        <field>
                            <name>SM</name>
                            <description>Source Address Update Mode</description>
                            <lsb>14</lsb>
                            <msb>15</msb>
                            <access>read-write</access>
                            <enumeratedValues>
                                <enumeratedValue>
                                    <name>00</name>
                                    <description>Source address is fixed.</description>
                                    <value>#00</value>
                                </enumeratedValue>
                                <enumeratedValue>
                                    <name>01</name>
                                    <description>Offset addition.</description>
                                    <value>#01</value>
                                </enumeratedValue>
                                <enumeratedValue>
                                    <name>10</name>
                                    <description>Source address is incremented.</description>
                                    <value>#10</value>
                                </enumeratedValue>
                                <enumeratedValue>
                                    <name>11</name>
                                    <description>Source address is decremented.</description>
                                    <value>#11</value>
                                </enumeratedValue>
                            </enumeratedValues>
                        </field>
                    </fields>
                </register>
                <register>
                    <name>DMOFR</name>
                    <description>DMA Offset Register</description>
                    <addressOffset>0x18</addressOffset>
                    <size>32</size>
                    <access>read-write</access>
                    <resetValue>0x00000000</resetValue>
                    <resetMask>0xffffffff</resetMask>
                </register>
                <register>
                    <name>DMCNT</name>
                    <description>DMA Transfer Enable Register</description>
                    <addressOffset>0x1C</addressOffset>
                    <size>8</size>
                    <access>read-write</access>
                    <resetValue>0x00</resetValue>
                    <resetMask>0xff</resetMask>
                    <fields>
                        <field>
                            <name>DTE</name>
                            <description>DMA Transfer Enable</description>
                            <lsb>0</lsb>
                            <msb>0</msb>
                            <access>read-write</access>
                            <enumeratedValues>
                                <enumeratedValue>
                                    <name>0</name>
                                    <description>Disables DMA transfer.</description>
                                    <value>#0</value>
                                </enumeratedValue>
                                <enumeratedValue>
                                    <name>1</name>
                                    <description>Enables DMA transfer.</description>
                                    <value>#1</value>
                                </enumeratedValue>
                            </enumeratedValues>
                        </field>
                    </fields>
                </register>
                <register>
                    <name>DMREQ</name>
                    <description>DMA Software Start Register</description>
                    <addressOffset>0x1D</addressOffset>
                    <size>8</size>
                    <access>read-write</access>
                    <resetValue>0x00</resetValue>
                    <resetMask>0xff</resetMask>
                    <fields>
                        <field>
                            <name>SWREQ</name>
                            <description>DMA Software Start</description>
                            <lsb>0</lsb>
                            <msb>0</msb>
                            <access>read-write</access>
                            <enumeratedValues>
                                <enumeratedValue>
                                    <name>0</name>
                                    <description>DMA transfer is not requested.</description>
                                    <value>#0</value>
                                </enumeratedValue>
                                <enumeratedValue>
                                    <name>1</name>
                                    <description>DMA transfer is requested.</description>
                                    <value>#1</value>
                                </enumeratedValue>
                            </enumeratedValues>
                        </field>
                        <field>
                            <name>CLRS</name>
                            <description>DMA Software Start Bit Auto Clear Select</description>
                            <lsb>4</lsb>
                            <msb>4</msb>
                            <access>read-write</access>
                            <enumeratedValues>
                                <enumeratedValue>
                                    <name>0</name>
                                    <description>SWREQ bit is cleared after DMA transfer is started by software.</description>
                                    <value>#0</value>
                                </enumeratedValue>
                                <enumeratedValue>
                                    <name>1</name>
                                    <description>SWREQ bit is not cleared after DMA transfer is started by software.</description>
                                    <value>#1</value>
                                </enumeratedValue>
                            </enumeratedValues>
                        </field>
                    </fields>
                </register>
                <register>
                    <name>DMSTS</name>
                    <description>DMA Status Register</description>
                    <addressOffset>0x1E</addressOffset>
                    <size>8</size>
                    <access>read-write</access>
                    <resetValue>0x00</resetValue>
                    <resetMask>0xff</resetMask>
                    <fields>
                        <field>
                            <name>ESIF</name>
                            <description>Transfer Escape End Interrupt Flag</description>
                            <lsb>0</lsb>
                            <msb>0</msb>
                            <access>read-write</access>
                            <enumeratedValues>
                                <enumeratedValue>
                                    <name>0</name>
                                    <description>A transfer escape end interrupt has not been generated.</description>
                                    <value>#0</value>
                                </enumeratedValue>
                                <enumeratedValue>
                                    <name>1</name>
                                    <description>A transfer escape end interrupt has been generated.</description>
                                    <value>#1</value>
                                </enumeratedValue>
                            </enumeratedValues>
                        </field>
                        <field>
                            <name>DTIF</name>
                            <description>Transfer End Interrupt Flag</description>
                            <lsb>4</lsb>
                            <msb>4</msb>
                            <access>read-write</access>
                            <enumeratedValues>
                                <enumeratedValue>
                                    <name>0</name>
                                    <description>A transfer end interrupt has not been generated.</description>
                                    <value>#0</value>
                                </enumeratedValue>
                                <enumeratedValue>
                                    <name>1</name>
                                    <description>A transfer end interrupt has been generated.</description>
                                    <value>#1</value>
                                </enumeratedValue>
                            </enumeratedValues>
                        </field>
                        <field>
                            <name>ACT</name>
                            <description>DMAC Active Flag</description>
                            <lsb>7</lsb>
                            <msb>7</msb>
                            <access>read-only</access>
                            <enumeratedValues>
                                <enumeratedValue>
                                    <name>0</name>
                                    <description>DMAC is in the idle state.</description>
                                    <value>#0</value>
                                </enumeratedValue>
                                <enumeratedValue>
                                    <name>1</name>
                                    <description>DMAC is operating.</description>
                                    <value>#1</value>
                                </enumeratedValue>
                            </enumeratedValues>
                        </field>
                    </fields>
                </register>
                <register>
                    <name>DMSRR</name>
                    <description>DMA Source Reload Address Register</description>
                    <addressOffset>0x20</addressOffset>
                    <size>32</size>
                    <access>read-write</access>
                    <resetValue>0x00000000</resetValue>
                    <resetMask>0xffffffff</resetMask>
                </register>
                <register>
                    <name>DMDRR</name>
                    <description>DMA Destination Reload Address Register</description>
                    <addressOffset>0x24</addressOffset>
                    <size>32</size>
                    <access>read-write</access>
                    <resetValue>0x00000000</resetValue>
                    <resetMask>0xffffffff</resetMask>
                </register>
                <register>
                    <name>DMSBS</name>
                    <description>DMA Source Buffer Size Register</description>
                    <addressOffset>0x28</addressOffset>
                    <size>32</size>
                    <access>read-write</access>
                    <resetValue>0x00000000</resetValue>
                    <resetMask>0xffffffff</resetMask>
                    <fields>
                        <field>
                            <name>DMSBSL</name>
                            <description>Functions as data transfer counter in repeat-block transfer mode</description>
                            <lsb>0</lsb>
                            <msb>15</msb>
                            <access>read-write</access>
                        </field>
                        <field>
                            <name>DMSBSH</name>
                            <description>Specifies the repeat-area size in repeat-block transfer mode</description>
                            <lsb>16</lsb>
                            <msb>31</msb>
                            <access>read-write</access>
                        </field>
                    </fields>
                </register>
                <register>
                    <name>DMDBS</name>
                    <description>DMA Destination Buffer Size Register</description>
                    <addressOffset>0x2C</addressOffset>
                    <size>32</size>
                    <access>read-write</access>
                    <resetValue>0x00000000</resetValue>
                    <resetMask>0xffffffff</resetMask>
                    <fields>
                        <field>
                            <name>DMDBSL</name>
                            <description>Functions as data transfer counter in repeat-block transfer mode.</description>
                            <lsb>0</lsb>
                            <msb>15</msb>
                            <access>read-write</access>
                        </field>
                        <field>
                            <name>DMDBSH</name>
                            <description>Specifies the repeat-area size in repeat-block transfer mode.</description>
                            <lsb>16</lsb>
                            <msb>31</msb>
                            <access>read-write</access>
                        </field>
                    </fields>
                </register>
                <register>
                    <name>DMBWR</name>
                    <description>DMA Bufferable Write Enable Register</description>
                    <addressOffset>0x30</addressOffset>
                    <size>8</size>
                    <access>read-write</access>
                    <resetValue>0x00</resetValue>
                    <resetMask>0xff</resetMask>
                    <fields>
                        <field>
                            <name>BWE</name>
                            <description>Bufferable Write Enable</description>
                            <lsb>0</lsb>
                            <msb>0</msb>
                            <access>read-write</access>
                            <enumeratedValues>
                                <enumeratedValue>
                                    <name>0</name>
                                    <description>Disables Bufferable Write</description>
                                    <value>#0</value>
                                </enumeratedValue>
                                <enumeratedValue>
                                    <name>1</name>
                                    <description>Enables Bufferable Write</description>
                                    <value>#1</value>
                                </enumeratedValue>
                            </enumeratedValues>
                        </field>
                    </fields>
                </register>
            </registers>
        </peripheral>
        <peripheral derivedFrom="DMAC00">
            <name>DMAC01</name>
            <description>Direct memory access controller 1</description>
            <baseAddress>0x4000A040</baseAddress>
        </peripheral>
        <peripheral derivedFrom="DMAC00">
            <name>DMAC02</name>
            <description>Direct memory access controller 2</description>
            <baseAddress>0x4000A080</baseAddress>
        </peripheral>
        <peripheral derivedFrom="DMAC00">
            <name>DMAC03</name>
            <description>Direct memory access controller 3</description>
            <baseAddress>0x4000A0C0</baseAddress>
        </peripheral>
        <peripheral derivedFrom="DMAC00">
            <name>DMAC04</name>
            <description>Direct memory access controller 4</description>
            <baseAddress>0x4000A100</baseAddress>
        </peripheral>
        <peripheral derivedFrom="DMAC00">
            <name>DMAC05</name>
            <description>Direct memory access controller 5</description>
            <baseAddress>0x4000A140</baseAddress>
        </peripheral>
        <peripheral derivedFrom="DMAC00">
            <name>DMAC06</name>
            <description>Direct memory access controller 6</description>
            <baseAddress>0x4000A180</baseAddress>
        </peripheral>
        <peripheral derivedFrom="DMAC00">
            <name>DMAC07</name>
            <description>Direct memory access controller 7</description>
            <baseAddress>0x4000A1C0</baseAddress>
        </peripheral>
        <peripheral>
            <name>DMA0</name>
            <description>DMAC Module Activation</description>
            <baseAddress>0x4000A800</baseAddress>
            <addressBlock>
                <offset>0x00</offset>
                <size>1</size>
                <usage>registers</usage>
            </addressBlock>
            <addressBlock>
                <offset>0x40</offset>
                <size>4</size>
                <usage>registers</usage>
            </addressBlock>
            <addressBlock>
                <offset>0x80</offset>
                <size>32</size>
                <usage>registers</usage>
            </addressBlock>
            <registers>
                <register>
                    <name>DMAST</name>
                    <description>DMA Module Activation Register</description>
                    <addressOffset>0x00</addressOffset>
                    <size>8</size>
                    <access>read-write</access>
                    <resetValue>0x00</resetValue>
                    <resetMask>0xff</resetMask>
                    <fields>
                        <field>
                            <name>DMST</name>
                            <description>DMAC Operation Enable</description>
                            <lsb>0</lsb>
                            <msb>0</msb>
                            <access>read-write</access>
                            <enumeratedValues>
                                <enumeratedValue>
                                    <name>0</name>
                                    <description>DMAC activation is disabled.</description>
                                    <value>#0</value>
                                </enumeratedValue>
                                <enumeratedValue>
                                    <name>1</name>
                                    <description>DMAC activation is enabled.</description>
                                    <value>#1</value>
                                </enumeratedValue>
                            </enumeratedValues>
                        </field>
                    </fields>
                </register>
                <register>
                    <name>DMECHR</name>
                    <description>DMAC Error Channel Register</description>
                    <addressOffset>0x40</addressOffset>
                    <size>32</size>
                    <access>read-write</access>
                    <resetValue>0x00000000</resetValue>
                    <resetMask>0xffffffff</resetMask>
                    <fields>
                        <field>
                            <name>DMECH</name>
                            <description>DMAC Error channel</description>
                            <lsb>0</lsb>
                            <msb>2</msb>
                            <access>read-only</access>
                        </field>
                        <field>
                            <name>DMECHSAM</name>
                            <description>DMAC Error channel Security Attribution Monitor</description>
                            <lsb>8</lsb>
                            <msb>8</msb>
                            <access>read-only</access>
                            <enumeratedValues>
                                <enumeratedValue>
                                    <name>0</name>
                                    <description>secure channel</description>
                                    <value>#0</value>
                                </enumeratedValue>
                                <enumeratedValue>
                                    <name>1</name>
                                    <description>non-secure channel</description>
                                    <value>#1</value>
                                </enumeratedValue>
                            </enumeratedValues>
                        </field>
                        <field>
                            <name>DMESTA</name>
                            <description>DMAC Error Status</description>
                            <lsb>16</lsb>
                            <msb>16</msb>
                            <access>read-write</access>
                            <enumeratedValues>
                                <enumeratedValue>
                                    <name>0</name>
                                    <description>No DMA transfer error occurred</description>
                                    <value>#0</value>
                                </enumeratedValue>
                                <enumeratedValue>
                                    <name>1</name>
                                    <description>DMA transfer error occurred</description>
                                    <value>#1</value>
                                </enumeratedValue>
                            </enumeratedValues>
                        </field>
                    </fields>
                </register>
                <register>
                    <dim>8</dim>
                    <dimIncrement>0x04</dimIncrement>
                    <dimIndex>0-7</dimIndex>
                    <name>DELSR%s</name>
                    <description>DMAC Event Link Setting Register %s</description>
                    <addressOffset>0x080</addressOffset>
                    <size>32</size>
                    <access>read-write</access>
                    <resetValue>0x00000000</resetValue>
                    <resetMask>0xffffffff</resetMask>
                    <fields>
                        <field>
                            <name>DELS</name>
                            <description>DMAC Event Link Select</description>
                            <lsb>0</lsb>
                            <msb>8</msb>
                            <access>read-write</access>
                            <enumeratedValues>
                                <enumeratedValue>
                                    <name>0x00</name>
                                    <description>Disable interrupts to the associated DMAC module</description>
                                    <value>0x00</value>
                                </enumeratedValue>
                                <enumeratedValue>
                                    <name>Others</name>
                                    <description>Event signal number to be linked. For details, see Table x.x Event table.</description>
                                    <isDefault>true</isDefault>
                                </enumeratedValue>
                            </enumeratedValues>
                        </field>
                        <field>
                            <name>IR</name>
                            <description>DMAC Activation Request Status flag</description>
                            <lsb>16</lsb>
                            <msb>16</msb>
                            <access>read-write</access>
                            <enumeratedValues>
                                <enumeratedValue>
                                    <name>0</name>
                                    <description>No DMAC activation request occurred.</description>
                                    <value>#0</value>
                                </enumeratedValue>
                                <enumeratedValue>
                                    <name>1</name>
                                    <description>DMAC activation request occurred.</description>
                                    <value>#1</value>
                                </enumeratedValue>
                            </enumeratedValues>
                        </field>
                    </fields>
                </register>
            </registers>
        </peripheral>
        <peripheral>
            <name>DTC0</name>
            <description>Data Transfer Controller</description>
            <baseAddress>0x4000AC00</baseAddress>
            <addressBlock>
                <offset>0x0C</offset>
                <size>1</size>
                <usage>registers</usage>
            </addressBlock>
            <addressBlock>
                <offset>0x0E</offset>
                <size>3</size>
                <usage>registers</usage>
            </addressBlock>
            <addressBlock>
                <offset>0x14</offset>
                <size>4</size>
                <usage>registers</usage>
            </addressBlock>
            <addressBlock>
                <offset>0x20</offset>
                <size>4</size>
                <usage>registers</usage>
            </addressBlock>
            <registers>
                <register>
                    <name>DTCST</name>
                    <description>DTC Module Start Register</description>
                    <addressOffset>0x0C</addressOffset>
                    <size>8</size>
                    <access>read-write</access>
                    <resetValue>0x00</resetValue>
                    <resetMask>0xff</resetMask>
                    <fields>
                        <field>
                            <name>DTCST</name>
                            <description>DTC Module Start</description>
                            <lsb>0</lsb>
                            <msb>0</msb>
                            <access>read-write</access>
                            <enumeratedValues>
                                <enumeratedValue>
                                    <name>0</name>
                                    <description>DTC module stopped</description>
                                    <value>#0</value>
                                </enumeratedValue>
                                <enumeratedValue>
                                    <name>1</name>
                                    <description>DTC module started</description>
                                    <value>#1</value>
                                </enumeratedValue>
                            </enumeratedValues>
                        </field>
                    </fields>
                </register>
                <register>
                    <name>DTCSTS</name>
                    <description>DTC Status Register</description>
                    <addressOffset>0x0E</addressOffset>
                    <size>16</size>
                    <access>read-only</access>
                    <resetValue>0x0000</resetValue>
                    <resetMask>0xffff</resetMask>
                    <fields>
                        <field>
                            <name>VECN</name>
                            <description>DTC-Activating Vector Number Monitoring</description>
                            <lsb>0</lsb>
                            <msb>7</msb>
                            <access>read-only</access>
                        </field>
                        <field>
                            <name>ACT</name>
                            <description>DTC Active Flag</description>
                            <lsb>15</lsb>
                            <msb>15</msb>
                            <access>read-only</access>
                            <enumeratedValues>
                                <enumeratedValue>
                                    <name>0</name>
                                    <description>DTC transfer operation is not in progress.</description>
                                    <value>#0</value>
                                </enumeratedValue>
                                <enumeratedValue>
                                    <name>1</name>
                                    <description>DTC transfer operation is in progress.</description>
                                    <value>#1</value>
                                </enumeratedValue>
                            </enumeratedValues>
                        </field>
                    </fields>
                </register>
                <register>
                    <name>DTCCR_SEC</name>
                    <description>DTC Control Register for Secure Region</description>
                    <addressOffset>0x10</addressOffset>
                    <size>8</size>
                    <access>read-write</access>
                    <resetValue>0x08</resetValue>
                    <resetMask>0xff</resetMask>
                    <fields>
                        <field>
                            <name>RRSS</name>
                            <description>DTC Transfer Information Read Skip Enable for Secure</description>
                            <lsb>4</lsb>
                            <msb>4</msb>
                            <access>read-write</access>
                            <enumeratedValues>
                                <enumeratedValue>
                                    <name>0</name>
                                    <description>Transfer information read is not skipped.</description>
                                    <value>#0</value>
                                </enumeratedValue>
                                <enumeratedValue>
                                    <name>1</name>
                                    <description>Transfer information read is skipped when vector numbers match.</description>
                                    <value>#1</value>
                                </enumeratedValue>
                            </enumeratedValues>
                        </field>
                    </fields>
                </register>
                <register>
                    <name>DTCVBR_SEC</name>
                    <description>DTC Vector Base Register for Secure Region</description>
                    <addressOffset>0x14</addressOffset>
                    <size>32</size>
                    <access>read-write</access>
                    <resetValue>0x00000000</resetValue>
                    <resetMask>0xffffffff</resetMask>
                </register>
                <register>
                    <name>DTEVR</name>
                    <description>DTC Error Vector Register</description>
                    <addressOffset>0x20</addressOffset>
                    <size>32</size>
                    <access>read-write</access>
                    <resetValue>0x00000000</resetValue>
                    <resetMask>0xffffffff</resetMask>
                    <fields>
                        <field>
                            <name>DTEV</name>
                            <description>DTC Error Vector Number</description>
                            <lsb>0</lsb>
                            <msb>7</msb>
                            <access>read-only</access>
                        </field>
                        <field>
                            <name>DTEVSAM</name>
                            <description>DTC Error Vector Number SA Monitor</description>
                            <lsb>8</lsb>
                            <msb>8</msb>
                            <access>read-only</access>
                            <enumeratedValues>
                                <enumeratedValue>
                                    <name>0</name>
                                    <description>Secure vector number</description>
                                    <value>#0</value>
                                </enumeratedValue>
                                <enumeratedValue>
                                    <name>1</name>
                                    <description>Non-secure vector number</description>
                                    <value>#1</value>
                                </enumeratedValue>
                            </enumeratedValues>
                        </field>
                        <field>
                            <name>DTESTA</name>
                            <description>DTC Error Status Flag</description>
                            <lsb>16</lsb>
                            <msb>16</msb>
                            <access>read-write</access>
                            <enumeratedValues>
                                <enumeratedValue>
                                    <name>0</name>
                                    <description>No DTC transfer error occurred</description>
                                    <value>#0</value>
                                </enumeratedValue>
                                <enumeratedValue>
                                    <name>1</name>
                                    <description>DTC transfer error occurred</description>
                                    <value>#1</value>
                                </enumeratedValue>
                            </enumeratedValues>
                        </field>
                    </fields>
                </register>
            </registers>
        </peripheral>
        <peripheral>
            <name>ICU</name>
            <description>Interrupt Controller</description>
            <baseAddress>0x4000C000</baseAddress>
            <addressBlock>
                <offset>0x100</offset>
                <size>2</size>
                <usage>registers</usage>
            </addressBlock>
            <addressBlock>
                <offset>0x110</offset>
                <size>2</size>
                <usage>registers</usage>
            </addressBlock>
            <addressBlock>
                <offset>0x120</offset>
                <size>2</size>
                <usage>registers</usage>
            </addressBlock>
            <addressBlock>
                <offset>0x1A0</offset>
                <size>8</size>
                <usage>registers</usage>
            </addressBlock>
            <addressBlock>
                <offset>0x300</offset>
                <size>384</size>
                <usage>registers</usage>
            </addressBlock>
            <interrupt>
                <name>IEL0</name>
                <description>ICU Interrupt 0</description>
                <value>0</value>
            </interrupt>
            <interrupt>
                <name>IEL1</name>
                <description>ICU Interrupt 1</description>
                <value>1</value>
            </interrupt>
            <interrupt>
                <name>IEL2</name>
                <description>ICU Interrupt 2</description>
                <value>2</value>
            </interrupt>
            <interrupt>
                <name>IEL3</name>
                <description>ICU Interrupt 3</description>
                <value>3</value>
            </interrupt>
            <interrupt>
                <name>IEL4</name>
                <description>ICU Interrupt 4</description>
                <value>4</value>
            </interrupt>
            <interrupt>
                <name>IEL5</name>
                <description>ICU Interrupt 5</description>
                <value>5</value>
            </interrupt>
            <interrupt>
                <name>IEL6</name>
                <description>ICU Interrupt 6</description>
                <value>6</value>
            </interrupt>
            <interrupt>
                <name>IEL7</name>
                <description>ICU Interrupt 7</description>
                <value>7</value>
            </interrupt>
            <interrupt>
                <name>IEL8</name>
                <description>ICU Interrupt 8</description>
                <value>8</value>
            </interrupt>
            <interrupt>
                <name>IEL9</name>
                <description>ICU Interrupt 9</description>
                <value>9</value>
            </interrupt>
            <interrupt>
                <name>IEL10</name>
                <description>ICU Interrupt 10</description>
                <value>10</value>
            </interrupt>
            <interrupt>
                <name>IEL11</name>
                <description>ICU Interrupt 11</description>
                <value>11</value>
            </interrupt>
            <interrupt>
                <name>IEL12</name>
                <description>ICU Interrupt 12</description>
                <value>12</value>
            </interrupt>
            <interrupt>
                <name>IEL13</name>
                <description>ICU Interrupt 13</description>
                <value>13</value>
            </interrupt>
            <interrupt>
                <name>IEL14</name>
                <description>ICU Interrupt 14</description>
                <value>14</value>
            </interrupt>
            <interrupt>
                <name>IEL15</name>
                <description>ICU Interrupt 15</description>
                <value>15</value>
            </interrupt>
            <interrupt>
                <name>IEL16</name>
                <description>ICU Interrupt 16</description>
                <value>16</value>
            </interrupt>
            <interrupt>
                <name>IEL17</name>
                <description>ICU Interrupt 17</description>
                <value>17</value>
            </interrupt>
            <interrupt>
                <name>IEL18</name>
                <description>ICU Interrupt 18</description>
                <value>18</value>
            </interrupt>
            <interrupt>
                <name>IEL19</name>
                <description>ICU Interrupt 19</description>
                <value>19</value>
            </interrupt>
            <interrupt>
                <name>IEL20</name>
                <description>ICU Interrupt 20</description>
                <value>20</value>
            </interrupt>
            <interrupt>
                <name>IEL21</name>
                <description>ICU Interrupt 21</description>
                <value>21</value>
            </interrupt>
            <interrupt>
                <name>IEL22</name>
                <description>ICU Interrupt 22</description>
                <value>22</value>
            </interrupt>
            <interrupt>
                <name>IEL23</name>
                <description>ICU Interrupt 23</description>
                <value>23</value>
            </interrupt>
            <interrupt>
                <name>IEL24</name>
                <description>ICU Interrupt 24</description>
                <value>24</value>
            </interrupt>
            <interrupt>
                <name>IEL25</name>
                <description>ICU Interrupt 25</description>
                <value>25</value>
            </interrupt>
            <interrupt>
                <name>IEL26</name>
                <description>ICU Interrupt 26</description>
                <value>26</value>
            </interrupt>
            <interrupt>
                <name>IEL27</name>
                <description>ICU Interrupt 27</description>
                <value>27</value>
            </interrupt>
            <interrupt>
                <name>IEL28</name>
                <description>ICU Interrupt 28</description>
                <value>28</value>
            </interrupt>
            <interrupt>
                <name>IEL29</name>
                <description>ICU Interrupt 29</description>
                <value>29</value>
            </interrupt>
            <interrupt>
                <name>IEL30</name>
                <description>ICU Interrupt 30</description>
                <value>30</value>
            </interrupt>
            <interrupt>
                <name>IEL31</name>
                <description>ICU Interrupt 31</description>
                <value>31</value>
            </interrupt>
            <interrupt>
                <name>IEL32</name>
                <description>ICU Interrupt 32</description>
                <value>32</value>
            </interrupt>
            <interrupt>
                <name>IEL33</name>
                <description>ICU Interrupt 33</description>
                <value>33</value>
            </interrupt>
            <interrupt>
                <name>IEL34</name>
                <description>ICU Interrupt 34</description>
                <value>34</value>
            </interrupt>
            <interrupt>
                <name>IEL35</name>
                <description>ICU Interrupt 35</description>
                <value>35</value>
            </interrupt>
            <interrupt>
                <name>IEL36</name>
                <description>ICU Interrupt 36</description>
                <value>36</value>
            </interrupt>
            <interrupt>
                <name>IEL37</name>
                <description>ICU Interrupt 37</description>
                <value>37</value>
            </interrupt>
            <interrupt>
                <name>IEL38</name>
                <description>ICU Interrupt 38</description>
                <value>38</value>
            </interrupt>
            <interrupt>
                <name>IEL39</name>
                <description>ICU Interrupt 39</description>
                <value>39</value>
            </interrupt>
            <interrupt>
                <name>IEL40</name>
                <description>ICU Interrupt 40</description>
                <value>40</value>
            </interrupt>
            <interrupt>
                <name>IEL41</name>
                <description>ICU Interrupt 41</description>
                <value>41</value>
            </interrupt>
            <interrupt>
                <name>IEL42</name>
                <description>ICU Interrupt 42</description>
                <value>42</value>
            </interrupt>
            <interrupt>
                <name>IEL43</name>
                <description>ICU Interrupt 43</description>
                <value>43</value>
            </interrupt>
            <interrupt>
                <name>IEL44</name>
                <description>ICU Interrupt 44</description>
                <value>44</value>
            </interrupt>
            <interrupt>
                <name>IEL45</name>
                <description>ICU Interrupt 45</description>
                <value>45</value>
            </interrupt>
            <interrupt>
                <name>IEL46</name>
                <description>ICU Interrupt 46</description>
                <value>46</value>
            </interrupt>
            <interrupt>
                <name>IEL47</name>
                <description>ICU Interrupt 47</description>
                <value>47</value>
            </interrupt>
            <interrupt>
                <name>IEL48</name>
                <description>ICU Interrupt 48</description>
                <value>48</value>
            </interrupt>
            <interrupt>
                <name>IEL49</name>
                <description>ICU Interrupt 49</description>
                <value>49</value>
            </interrupt>
            <interrupt>
                <name>IEL50</name>
                <description>ICU Interrupt 50</description>
                <value>50</value>
            </interrupt>
            <interrupt>
                <name>IEL51</name>
                <description>ICU Interrupt 51</description>
                <value>51</value>
            </interrupt>
            <interrupt>
                <name>IEL52</name>
                <description>ICU Interrupt 52</description>
                <value>52</value>
            </interrupt>
            <interrupt>
                <name>IEL53</name>
                <description>ICU Interrupt 53</description>
                <value>53</value>
            </interrupt>
            <interrupt>
                <name>IEL54</name>
                <description>ICU Interrupt 54</description>
                <value>54</value>
            </interrupt>
            <interrupt>
                <name>IEL55</name>
                <description>ICU Interrupt 55</description>
                <value>55</value>
            </interrupt>
            <interrupt>
                <name>IEL56</name>
                <description>ICU Interrupt 56</description>
                <value>56</value>
            </interrupt>
            <interrupt>
                <name>IEL57</name>
                <description>ICU Interrupt 57</description>
                <value>57</value>
            </interrupt>
            <interrupt>
                <name>IEL58</name>
                <description>ICU Interrupt 58</description>
                <value>58</value>
            </interrupt>
            <interrupt>
                <name>IEL59</name>
                <description>ICU Interrupt 59</description>
                <value>59</value>
            </interrupt>
            <interrupt>
                <name>IEL60</name>
                <description>ICU Interrupt 60</description>
                <value>60</value>
            </interrupt>
            <interrupt>
                <name>IEL61</name>
                <description>ICU Interrupt 61</description>
                <value>61</value>
            </interrupt>
            <interrupt>
                <name>IEL62</name>
                <description>ICU Interrupt 62</description>
                <value>62</value>
            </interrupt>
            <interrupt>
                <name>IEL63</name>
                <description>ICU Interrupt 63</description>
                <value>63</value>
            </interrupt>
            <interrupt>
                <name>IEL64</name>
                <description>ICU Interrupt 64</description>
                <value>64</value>
            </interrupt>
            <interrupt>
                <name>IEL65</name>
                <description>ICU Interrupt 65</description>
                <value>65</value>
            </interrupt>
            <interrupt>
                <name>IEL66</name>
                <description>ICU Interrupt 66</description>
                <value>66</value>
            </interrupt>
            <interrupt>
                <name>IEL67</name>
                <description>ICU Interrupt 67</description>
                <value>67</value>
            </interrupt>
            <interrupt>
                <name>IEL68</name>
                <description>ICU Interrupt 68</description>
                <value>68</value>
            </interrupt>
            <interrupt>
                <name>IEL69</name>
                <description>ICU Interrupt 69</description>
                <value>69</value>
            </interrupt>
            <interrupt>
                <name>IEL70</name>
                <description>ICU Interrupt 70</description>
                <value>70</value>
            </interrupt>
            <interrupt>
                <name>IEL71</name>
                <description>ICU Interrupt 71</description>
                <value>71</value>
            </interrupt>
            <interrupt>
                <name>IEL72</name>
                <description>ICU Interrupt 72</description>
                <value>72</value>
            </interrupt>
            <interrupt>
                <name>IEL73</name>
                <description>ICU Interrupt 73</description>
                <value>73</value>
            </interrupt>
            <interrupt>
                <name>IEL74</name>
                <description>ICU Interrupt 74</description>
                <value>74</value>
            </interrupt>
            <interrupt>
                <name>IEL75</name>
                <description>ICU Interrupt 75</description>
                <value>75</value>
            </interrupt>
            <interrupt>
                <name>IEL76</name>
                <description>ICU Interrupt 76</description>
                <value>76</value>
            </interrupt>
            <interrupt>
                <name>IEL77</name>
                <description>ICU Interrupt 77</description>
                <value>77</value>
            </interrupt>
            <interrupt>
                <name>IEL78</name>
                <description>ICU Interrupt 78</description>
                <value>78</value>
            </interrupt>
            <interrupt>
                <name>IEL79</name>
                <description>ICU Interrupt 79</description>
                <value>79</value>
            </interrupt>
            <interrupt>
                <name>IEL80</name>
                <description>ICU Interrupt 80</description>
                <value>80</value>
            </interrupt>
            <interrupt>
                <name>IEL81</name>
                <description>ICU Interrupt 81</description>
                <value>81</value>
            </interrupt>
            <interrupt>
                <name>IEL82</name>
                <description>ICU Interrupt 82</description>
                <value>82</value>
            </interrupt>
            <interrupt>
                <name>IEL83</name>
                <description>ICU Interrupt 83</description>
                <value>83</value>
            </interrupt>
            <interrupt>
                <name>IEL84</name>
                <description>ICU Interrupt 84</description>
                <value>84</value>
            </interrupt>
            <interrupt>
                <name>IEL85</name>
                <description>ICU Interrupt 85</description>
                <value>85</value>
            </interrupt>
            <interrupt>
                <name>IEL86</name>
                <description>ICU Interrupt 86</description>
                <value>86</value>
            </interrupt>
            <interrupt>
                <name>IEL87</name>
                <description>ICU Interrupt 87</description>
                <value>87</value>
            </interrupt>
            <interrupt>
                <name>IEL88</name>
                <description>ICU Interrupt 88</description>
                <value>88</value>
            </interrupt>
            <interrupt>
                <name>IEL89</name>
                <description>ICU Interrupt 89</description>
                <value>89</value>
            </interrupt>
            <interrupt>
                <name>IEL90</name>
                <description>ICU Interrupt 90</description>
                <value>90</value>
            </interrupt>
            <interrupt>
                <name>IEL91</name>
                <description>ICU Interrupt 91</description>
                <value>91</value>
            </interrupt>
            <interrupt>
                <name>IEL92</name>
                <description>ICU Interrupt 92</description>
                <value>92</value>
            </interrupt>
            <interrupt>
                <name>IEL93</name>
                <description>ICU Interrupt 93</description>
                <value>93</value>
            </interrupt>
            <interrupt>
                <name>IEL94</name>
                <description>ICU Interrupt 94</description>
                <value>94</value>
            </interrupt>
            <interrupt>
                <name>IEL95</name>
                <description>ICU Interrupt 95</description>
                <value>95</value>
            </interrupt>
            <registers>
                <register>
                    <name>NMIER</name>
                    <description>Non-Maskable Interrupt Enable Register</description>
                    <addressOffset>0x100</addressOffset>
                    <size>16</size>
                    <access>read-write</access>
                    <resetValue>0x0000</resetValue>
                    <resetMask>0xffff</resetMask>
                    <fields>
                        <field>
                            <name>IWDTEN</name>
                            <description>IWDT Underflow/Refresh Error Interrupt Enable</description>
                            <lsb>0</lsb>
                            <msb>0</msb>
                            <access>read-write</access>
                            <enumeratedValues>
                                <enumeratedValue>
                                    <name>0</name>
                                    <description>Disabled</description>
                                    <value>#0</value>
                                </enumeratedValue>
                                <enumeratedValue>
                                    <name>1</name>
                                    <description>Enabled</description>
                                    <value>#1</value>
                                </enumeratedValue>
                            </enumeratedValues>
                        </field>
                        <field>
                            <name>WDTEN</name>
                            <description>WDT Underflow/Refresh Error Interrupt Enable</description>
                            <lsb>1</lsb>
                            <msb>1</msb>
                            <access>read-write</access>
                            <enumeratedValues>
                                <enumeratedValue>
                                    <name>0</name>
                                    <description>Disabled</description>
                                    <value>#0</value>
                                </enumeratedValue>
                                <enumeratedValue>
                                    <name>1</name>
                                    <description>Enabled</description>
                                    <value>#1</value>
                                </enumeratedValue>
                            </enumeratedValues>
                        </field>
                        <field>
                            <name>PVD1EN</name>
                            <description>Voltage monitor 1 Interrupt Enable</description>
                            <lsb>2</lsb>
                            <msb>2</msb>
                            <access>read-write</access>
                            <enumeratedValues>
                                <enumeratedValue>
                                    <name>0</name>
                                    <description>Disabled</description>
                                    <value>#0</value>
                                </enumeratedValue>
                                <enumeratedValue>
                                    <name>1</name>
                                    <description>Enabled</description>
                                    <value>#1</value>
                                </enumeratedValue>
                            </enumeratedValues>
                        </field>
                        <field>
                            <name>PVD2EN</name>
                            <description>Voltage monitor 2 Interrupt Enable</description>
                            <lsb>3</lsb>
                            <msb>3</msb>
                            <access>read-write</access>
                            <enumeratedValues>
                                <enumeratedValue>
                                    <name>0</name>
                                    <description>Disabled</description>
                                    <value>#0</value>
                                </enumeratedValue>
                                <enumeratedValue>
                                    <name>1</name>
                                    <description>Enabled</description>
                                    <value>#1</value>
                                </enumeratedValue>
                            </enumeratedValues>
                        </field>
                        <field>
                            <name>OSTEN</name>
                            <description>Main Clock Oscillation Stop Detection Interrupt Enable</description>
                            <lsb>6</lsb>
                            <msb>6</msb>
                            <access>read-write</access>
                            <enumeratedValues>
                                <enumeratedValue>
                                    <name>0</name>
                                    <description>Disabled</description>
                                    <value>#0</value>
                                </enumeratedValue>
                                <enumeratedValue>
                                    <name>1</name>
                                    <description>Enabled</description>
                                    <value>#1</value>
                                </enumeratedValue>
                            </enumeratedValues>
                        </field>
                        <field>
                            <name>NMIEN</name>
                            <description>NMI Pin Interrupt Enable</description>
                            <lsb>7</lsb>
                            <msb>7</msb>
                            <access>read-write</access>
                            <enumeratedValues>
                                <enumeratedValue>
                                    <name>0</name>
                                    <description>Disabled</description>
                                    <value>#0</value>
                                </enumeratedValue>
                                <enumeratedValue>
                                    <name>1</name>
                                    <description>Enabled</description>
                                    <value>#1</value>
                                </enumeratedValue>
                            </enumeratedValues>
                        </field>
                        <field>
                            <name>BUSEN</name>
                            <lsb>12</lsb>
                            <msb>12</msb>
                            <access>read-write</access>
                            <enumeratedValues>
                                <enumeratedValue>
                                    <name>0</name>
                                    <description>Disabled</description>
                                    <value>#0</value>
                                </enumeratedValue>
                                <enumeratedValue>
                                    <name>1</name>
                                    <description>Enabled</description>
                                    <value>#1</value>
                                </enumeratedValue>
                            </enumeratedValues>
                        </field>
                        <field>
                            <name>CMEN</name>
                            <lsb>13</lsb>
                            <msb>13</msb>
                            <access>read-write</access>
                            <enumeratedValues>
                                <enumeratedValue>
                                    <name>0</name>
                                    <description>Disabled</description>
                                    <value>#0</value>
                                </enumeratedValue>
                                <enumeratedValue>
                                    <name>1</name>
                                    <description>Enabled</description>
                                    <value>#1</value>
                                </enumeratedValue>
                            </enumeratedValues>
                        </field>
                        <field>
                            <name>LUEN</name>
                            <lsb>15</lsb>
                            <msb>15</msb>
                            <access>read-write</access>
                            <enumeratedValues>
                                <enumeratedValue>
                                    <name>0</name>
                                    <description>Disabled</description>
                                    <value>#0</value>
                                </enumeratedValue>
                                <enumeratedValue>
                                    <name>1</name>
                                    <description>Enabled</description>
                                    <value>#1</value>
                                </enumeratedValue>
                            </enumeratedValues>
                        </field>
                    </fields>
                </register>
                <register>
                    <name>NMICLR</name>
                    <description>Non-Maskable Interrupt Status Clear Register</description>
                    <addressOffset>0x110</addressOffset>
                    <size>16</size>
                    <access>read-write</access>
                    <resetValue>0x0000</resetValue>
                    <resetMask>0xffff</resetMask>
                    <fields>
                        <field>
                            <name>IWDTCLR</name>
                            <description>IWDT Underflow/Refresh Error Interrupt Status Flag Clear</description>
                            <lsb>0</lsb>
                            <msb>0</msb>
                            <access>read-write</access>
                            <enumeratedValues>
                                <enumeratedValue>
                                    <name>0</name>
                                    <description>No effect</description>
                                    <value>#0</value>
                                </enumeratedValue>
                                <enumeratedValue>
                                    <name>1</name>
                                    <description>Clear the NMISR.IWDTST flag</description>
                                    <value>#1</value>
                                </enumeratedValue>
                            </enumeratedValues>
                        </field>
                        <field>
                            <name>WDTCLR</name>
                            <description>WDT Underflow/Refresh Error Interrupt Status Flag Clear</description>
                            <lsb>1</lsb>
                            <msb>1</msb>
                            <access>read-write</access>
                            <enumeratedValues>
                                <enumeratedValue>
                                    <name>0</name>
                                    <description>No effect</description>
                                    <value>#0</value>
                                </enumeratedValue>
                                <enumeratedValue>
                                    <name>1</name>
                                    <description>Clear the NMISR.WDTST flag</description>
                                    <value>#1</value>
                                </enumeratedValue>
                            </enumeratedValues>
                        </field>
                        <field>
                            <name>PVD1CLR</name>
                            <description>Voltage Monitor 1 Interrupt Status Flag Clear</description>
                            <lsb>2</lsb>
                            <msb>2</msb>
                            <access>read-write</access>
                            <enumeratedValues>
                                <enumeratedValue>
                                    <name>0</name>
                                    <description>No effect</description>
                                    <value>#0</value>
                                </enumeratedValue>
                                <enumeratedValue>
                                    <name>1</name>
                                    <description>Clear the NMISR.PVD1ST flag</description>
                                    <value>#1</value>
                                </enumeratedValue>
                            </enumeratedValues>
                        </field>
                        <field>
                            <name>PVD2CLR</name>
                            <description>Voltage Monitor 2 Interrupt Status Flag Clear</description>
                            <lsb>3</lsb>
                            <msb>3</msb>
                            <access>read-write</access>
                            <enumeratedValues>
                                <enumeratedValue>
                                    <name>0</name>
                                    <description>No effect</description>
                                    <value>#0</value>
                                </enumeratedValue>
                                <enumeratedValue>
                                    <name>1</name>
                                    <description>Clear the NMISR.PVD2ST flag.</description>
                                    <value>#1</value>
                                </enumeratedValue>
                            </enumeratedValues>
                        </field>
                        <field>
                            <name>OSTCLR</name>
                            <description>Oscillation Stop Detection Interrupt Status Flag Clear</description>
                            <lsb>6</lsb>
                            <msb>6</msb>
                            <access>read-write</access>
                            <enumeratedValues>
                                <enumeratedValue>
                                    <name>0</name>
                                    <description>No effect</description>
                                    <value>#0</value>
                                </enumeratedValue>
                                <enumeratedValue>
                                    <name>1</name>
                                    <description>Clear the NMISR.OSTST flag</description>
                                    <value>#1</value>
                                </enumeratedValue>
                            </enumeratedValues>
                        </field>
                        <field>
                            <name>NMICLR</name>
                            <description>NMI Pin Interrupt Status Flag Clear</description>
                            <lsb>7</lsb>
                            <msb>7</msb>
                            <access>read-write</access>
                            <enumeratedValues>
                                <enumeratedValue>
                                    <name>0</name>
                                    <description>No effect</description>
                                    <value>#0</value>
                                </enumeratedValue>
                                <enumeratedValue>
                                    <name>1</name>
                                    <description>Clear the NMISR.NMIST flag</description>
                                    <value>#1</value>
                                </enumeratedValue>
                            </enumeratedValues>
                        </field>
                        <field>
                            <name>BUSCLR</name>
                            <lsb>12</lsb>
                            <msb>12</msb>
                            <access>read-write</access>
                            <enumeratedValues>
                                <enumeratedValue>
                                    <name>0</name>
                                    <description>No effect</description>
                                    <value>#0</value>
                                </enumeratedValue>
                                <enumeratedValue>
                                    <name>1</name>
                                    <description>Clear the NMISR.BUSST flag</description>
                                    <value>#1</value>
                                </enumeratedValue>
                            </enumeratedValues>
                        </field>
                        <field>
                            <name>CMCLR</name>
                            <lsb>13</lsb>
                            <msb>13</msb>
                            <access>read-write</access>
                            <enumeratedValues>
                                <enumeratedValue>
                                    <name>0</name>
                                    <description>No effect</description>
                                    <value>#0</value>
                                </enumeratedValue>
                                <enumeratedValue>
                                    <name>1</name>
                                    <description>Clear the NMISR.CMST flag</description>
                                    <value>#1</value>
                                </enumeratedValue>
                            </enumeratedValues>
                        </field>
                        <field>
                            <name>LUCLR</name>
                            <lsb>15</lsb>
                            <msb>15</msb>
                            <access>read-write</access>
                            <enumeratedValues>
                                <enumeratedValue>
                                    <name>0</name>
                                    <description>No effect</description>
                                    <value>#0</value>
                                </enumeratedValue>
                                <enumeratedValue>
                                    <name>1</name>
                                    <description>Clear the NMISR.LUST flag</description>
                                    <value>#1</value>
                                </enumeratedValue>
                            </enumeratedValues>
                        </field>
                    </fields>
                </register>
                <register>
                    <name>NMISR</name>
                    <description>Non-Maskable Interrupt Status Register</description>
                    <addressOffset>0x120</addressOffset>
                    <size>16</size>
                    <access>read-only</access>
                    <resetValue>0x0000</resetValue>
                    <resetMask>0xffff</resetMask>
                    <fields>
                        <field>
                            <name>IWDTST</name>
                            <description>IWDT Underflow/Refresh Error Interrupt Status Flag</description>
                            <lsb>0</lsb>
                            <msb>0</msb>
                            <access>read-only</access>
                            <enumeratedValues>
                                <enumeratedValue>
                                    <name>0</name>
                                    <description>Interrupt not requested</description>
                                    <value>#0</value>
                                </enumeratedValue>
                                <enumeratedValue>
                                    <name>1</name>
                                    <description>Interrupt requested</description>
                                    <value>#1</value>
                                </enumeratedValue>
                            </enumeratedValues>
                        </field>
                        <field>
                            <name>WDTST</name>
                            <description>WDT Underflow/Refresh Error Interrupt Status Flag</description>
                            <lsb>1</lsb>
                            <msb>1</msb>
                            <access>read-only</access>
                            <enumeratedValues>
                                <enumeratedValue>
                                    <name>0</name>
                                    <description>Interrupt not requested</description>
                                    <value>#0</value>
                                </enumeratedValue>
                                <enumeratedValue>
                                    <name>1</name>
                                    <description>Interrupt requested</description>
                                    <value>#1</value>
                                </enumeratedValue>
                            </enumeratedValues>
                        </field>
                        <field>
                            <name>PVD1ST</name>
                            <description>Voltage Monitor 1 Interrupt Status Flag</description>
                            <lsb>2</lsb>
                            <msb>2</msb>
                            <access>read-only</access>
                            <enumeratedValues>
                                <enumeratedValue>
                                    <name>0</name>
                                    <description>Interrupt not requested</description>
                                    <value>#0</value>
                                </enumeratedValue>
                                <enumeratedValue>
                                    <name>1</name>
                                    <description>Interrupt requested</description>
                                    <value>#1</value>
                                </enumeratedValue>
                            </enumeratedValues>
                        </field>
                        <field>
                            <name>PVD2ST</name>
                            <description>Voltage Monitor 2 Interrupt Status Flag</description>
                            <lsb>3</lsb>
                            <msb>3</msb>
                            <access>read-only</access>
                            <enumeratedValues>
                                <enumeratedValue>
                                    <name>0</name>
                                    <description>Interrupt not requested</description>
                                    <value>#0</value>
                                </enumeratedValue>
                                <enumeratedValue>
                                    <name>1</name>
                                    <description>Interrupt requested</description>
                                    <value>#1</value>
                                </enumeratedValue>
                            </enumeratedValues>
                        </field>
                        <field>
                            <name>OSTST</name>
                            <description>Main Clock Oscillation Stop Detection Interrupt Status Flag</description>
                            <lsb>6</lsb>
                            <msb>6</msb>
                            <access>read-only</access>
                            <enumeratedValues>
                                <enumeratedValue>
                                    <name>0</name>
                                    <description>Interrupt not requested for main clock oscillation stop</description>
                                    <value>#0</value>
                                </enumeratedValue>
                                <enumeratedValue>
                                    <name>1</name>
                                    <description>Interrupt requested for main clock oscillation stop</description>
                                    <value>#1</value>
                                </enumeratedValue>
                            </enumeratedValues>
                        </field>
                        <field>
                            <name>NMIST</name>
                            <description>NMI Pin Interrupt Status Flag</description>
                            <lsb>7</lsb>
                            <msb>7</msb>
                            <access>read-only</access>
                            <enumeratedValues>
                                <enumeratedValue>
                                    <name>0</name>
                                    <description>Interrupt not requested</description>
                                    <value>#0</value>
                                </enumeratedValue>
                                <enumeratedValue>
                                    <name>1</name>
                                    <description>Interrupt requested</description>
                                    <value>#1</value>
                                </enumeratedValue>
                            </enumeratedValues>
                        </field>
                        <field>
                            <name>BUSST</name>
                            <description>Bus Error Interrupt Status Flag</description>
                            <lsb>12</lsb>
                            <msb>12</msb>
                            <access>read-only</access>
                            <enumeratedValues>
                                <enumeratedValue>
                                    <name>0</name>
                                    <description>Interrupt not requested</description>
                                    <value>#0</value>
                                </enumeratedValue>
                                <enumeratedValue>
                                    <name>1</name>
                                    <description>Interrupt requested</description>
                                    <value>#1</value>
                                </enumeratedValue>
                            </enumeratedValues>
                        </field>
                        <field>
                            <name>CMST</name>
                            <lsb>13</lsb>
                            <msb>13</msb>
                            <access>read-only</access>
                            <enumeratedValues>
                                <enumeratedValue>
                                    <name>0</name>
                                    <description>Interrupt not requested</description>
                                    <value>#0</value>
                                </enumeratedValue>
                                <enumeratedValue>
                                    <name>1</name>
                                    <description>Interrupt requested</description>
                                    <value>#1</value>
                                </enumeratedValue>
                            </enumeratedValues>
                        </field>
                        <field>
                            <name>LUST</name>
                            <lsb>15</lsb>
                            <msb>15</msb>
                            <access>read-only</access>
                            <enumeratedValues>
                                <enumeratedValue>
                                    <name>0</name>
                                    <description>Interrupt not requested</description>
                                    <value>#0</value>
                                </enumeratedValue>
                                <enumeratedValue>
                                    <name>1</name>
                                    <description>Interrupt requested</description>
                                    <value>#1</value>
                                </enumeratedValue>
                            </enumeratedValues>
                        </field>
                    </fields>
                </register>
                <register>
                    <name>WUPEN0</name>
                    <description>Wake Up Interrupt Enable Register 0</description>
                    <addressOffset>0x1A0</addressOffset>
                    <size>32</size>
                    <access>read-write</access>
                    <resetValue>0x00000000</resetValue>
                    <resetMask>0xffffffff</resetMask>
                    <fields>
                        <field>
                            <name>IRQWUPEN</name>
                            <lsb>0</lsb>
                            <msb>15</msb>
                            <access>read-write</access>
                            <enumeratedValues>
                                <enumeratedValue>
                                    <name>0</name>
                                    <description>Deep Sleep/Software Standby Mode returns by IRQn interrupt is disabled .</description>
                                    <value>#0</value>
                                </enumeratedValue>
                                <enumeratedValue>
                                    <name>1</name>
                                    <description>Deep Sleep/Software Standby Mode returns by IRQn interrupt is enabled</description>
                                    <value>#1</value>
                                </enumeratedValue>
                            </enumeratedValues>
                        </field>
                        <field>
                            <name>IWDTWUPEN</name>
                            <description>IWDT Interrupt Deep Sleep/Software Standby Mode Returns Enable</description>
                            <lsb>16</lsb>
                            <msb>16</msb>
                            <access>read-write</access>
                            <enumeratedValues>
                                <enumeratedValue>
                                    <name>0</name>
                                    <description>Deep Sleep/Software Standby Mode returns by IWDT interrupt is disabled</description>
                                    <value>#0</value>
                                </enumeratedValue>
                                <enumeratedValue>
                                    <name>1</name>
                                    <description>Deep Sleep/Software Standby Mode returns by IWDT interrupt is enabled</description>
                                    <value>#1</value>
                                </enumeratedValue>
                            </enumeratedValues>
                        </field>
                        <field>
                            <name>PVD1WUPEN</name>
                            <description>PVD1 Interrupt Deep Sleep/Software Standby Mode Returns Enable</description>
                            <lsb>18</lsb>
                            <msb>18</msb>
                            <access>read-write</access>
                            <enumeratedValues>
                                <enumeratedValue>
                                    <name>0</name>
                                    <description>Deep Sleep/Software Standby Mode returns by PVD1 interrupt is disabled</description>
                                    <value>#0</value>
                                </enumeratedValue>
                                <enumeratedValue>
                                    <name>1</name>
                                    <description>Deep Sleep/Software Standby Mode returns by PVD1 interrupt is enabled</description>
                                    <value>#1</value>
                                </enumeratedValue>
                            </enumeratedValues>
                        </field>
                        <field>
                            <name>PVD2WUPEN</name>
                            <description>PVD2 Interrupt Deep Sleep/Software Standby Mode Returns Enable</description>
                            <lsb>19</lsb>
                            <msb>19</msb>
                            <access>read-write</access>
                            <enumeratedValues>
                                <enumeratedValue>
                                    <name>0</name>
                                    <description>Deep Sleep/Software Standby Mode returns by PVD2 interrupt is disabled</description>
                                    <value>#0</value>
                                </enumeratedValue>
                                <enumeratedValue>
                                    <name>1</name>
                                    <description>Deep Sleep/Software Standby Mode returns by PVD2 interrupt is enabled</description>
                                    <value>#1</value>
                                </enumeratedValue>
                            </enumeratedValues>
                        </field>
                        <field>
                            <name>VBATTWUPEN</name>
                            <description>VBATT Monitor Interrupt Deep Sleep/Software Standby Mode Returns Enable</description>
                            <lsb>20</lsb>
                            <msb>20</msb>
                            <access>read-write</access>
                            <enumeratedValues>
                                <enumeratedValue>
                                    <name>0</name>
                                    <description>Deep Sleep/Software Standby Mode returns by VBATT monitor interrupt is disabled</description>
                                    <value>#0</value>
                                </enumeratedValue>
                                <enumeratedValue>
                                    <name>1</name>
                                    <description>Deep Sleep/Software Standby Mode returns by VBATT monitor interrupt is enabled</description>
                                    <value>#1</value>
                                </enumeratedValue>
                            </enumeratedValues>
                        </field>
                        <field>
                            <name>RTCALMWUPEN</name>
                            <description>RTC Alarm Interrupt Deep Sleep/Software Standby Mode Returns Enable</description>
                            <lsb>24</lsb>
                            <msb>24</msb>
                            <access>read-write</access>
                            <enumeratedValues>
                                <enumeratedValue>
                                    <name>0</name>
                                    <description>Deep Sleep/Software Standby Mode returns by RTC alarm interrupt is disabled</description>
                                    <value>#0</value>
                                </enumeratedValue>
                                <enumeratedValue>
                                    <name>1</name>
                                    <description>Deep Sleep/Software Standby Mode returns by RTC alarm interrupt is enabled</description>
                                    <value>#1</value>
                                </enumeratedValue>
                            </enumeratedValues>
                        </field>
                        <field>
                            <name>RTCPRDWUPEN</name>
                            <description>RTC Period Interrupt Deep Sleep/Software Standby Mode Returns Enable</description>
                            <lsb>25</lsb>
                            <msb>25</msb>
                            <access>read-write</access>
                            <enumeratedValues>
                                <enumeratedValue>
                                    <name>0</name>
                                    <description>Deep Sleep/Software Standby Mode returns by RTC period interrupt is disabled</description>
                                    <value>#0</value>
                                </enumeratedValue>
                                <enumeratedValue>
                                    <name>1</name>
                                    <description>Deep Sleep/Software Standby Mode returns by RTC period interrupt is enabled</description>
                                    <value>#1</value>
                                </enumeratedValue>
                            </enumeratedValues>
                        </field>
                        <field>
                            <name>USBHSWUPEN</name>
                            <description>USBHS Interrupt Deep Sleep/Software Standby Mode Returns Enable</description>
                            <lsb>26</lsb>
                            <msb>26</msb>
                            <access>read-write</access>
                            <enumeratedValues>
                                <enumeratedValue>
                                    <name>0</name>
                                    <description>Deep Sleep/Software Standby Mode returns by USBHS interrupt is disabled</description>
                                    <value>#0</value>
                                </enumeratedValue>
                                <enumeratedValue>
                                    <name>1</name>
                                    <description>Deep Sleep/Software Standby Mode returns by USBHS interrupt is enabled</description>
                                    <value>#1</value>
                                </enumeratedValue>
                            </enumeratedValues>
                        </field>
                        <field>
                            <name>USBFS0WUPEN</name>
                            <description>USBFS Interrupt Deep Sleep/Software Standby Mode Returns Enable</description>
                            <lsb>27</lsb>
                            <msb>27</msb>
                            <access>read-write</access>
                            <enumeratedValues>
                                <enumeratedValue>
                                    <name>0</name>
                                    <description>Deep Sleep/Software Standby Mode returns by USBFS interrupt is disabled</description>
                                    <value>#0</value>
                                </enumeratedValue>
                                <enumeratedValue>
                                    <name>1</name>
                                    <description>Deep Sleep/Software Standby Mode returns by USBFS interrupt is enabled</description>
                                    <value>#1</value>
                                </enumeratedValue>
                            </enumeratedValues>
                        </field>
                        <field>
                            <name>AGT1UDWUPEN</name>
                            <description>AGT1 Underflow Interrupt Deep Sleep/Software Standby Mode Returns Enable</description>
                            <lsb>28</lsb>
                            <msb>28</msb>
                            <access>read-write</access>
                            <enumeratedValues>
                                <enumeratedValue>
                                    <name>0</name>
                                    <description>Deep Sleep/Software Standby Mode returns by AGT1 underflow interrupt is disabled</description>
                                    <value>#0</value>
                                </enumeratedValue>
                                <enumeratedValue>
                                    <name>1</name>
                                    <description>Deep Sleep/Software Standby Mode returns by AGT1 underflow interrupt is enabled</description>
                                    <value>#1</value>
                                </enumeratedValue>
                            </enumeratedValues>
                        </field>
                        <field>
                            <name>AGT1CAWUPEN</name>
                            <description>AGT1 Compare Match A Interrupt Deep Sleep/Software Standby Mode Returns Enable</description>
                            <lsb>29</lsb>
                            <msb>29</msb>
                            <access>read-write</access>
                            <enumeratedValues>
                                <enumeratedValue>
                                    <name>0</name>
                                    <description>Deep Sleep/Software Standby Mode returns by AGT1 compare match A interrupt is disabled</description>
                                    <value>#0</value>
                                </enumeratedValue>
                                <enumeratedValue>
                                    <name>1</name>
                                    <description>Deep Sleep/Software Standby Mode returns by AGT1 compare match A interrupt is enabled</description>
                                    <value>#1</value>
                                </enumeratedValue>
                            </enumeratedValues>
                        </field>
                        <field>
                            <name>AGT1CBWUPEN</name>
                            <description>AGT1 Compare Match B Interrupt Deep Sleep/Software Standby Mode Returns Enable</description>
                            <lsb>30</lsb>
                            <msb>30</msb>
                            <access>read-write</access>
                            <enumeratedValues>
                                <enumeratedValue>
                                    <name>0</name>
                                    <description>Deep Sleep/Software Standby Mode returns by AGT1 compare match B interrupt is disabled</description>
                                    <value>#0</value>
                                </enumeratedValue>
                                <enumeratedValue>
                                    <name>1</name>
                                    <description>Deep Sleep/Software Standby Mode returns by AGT1 compare match B interrupt is enabled</description>
                                    <value>#1</value>
                                </enumeratedValue>
                            </enumeratedValues>
                        </field>
                        <field>
                            <name>IIC0WUPEN</name>
                            <description>IIC0 Address Match Interrupt Deep Sleep/Software Standby Mode Returns Enable</description>
                            <lsb>31</lsb>
                            <msb>31</msb>
                            <access>read-write</access>
                            <enumeratedValues>
                                <enumeratedValue>
                                    <name>0</name>
                                    <description>Deep Sleep/Software Standby Mode returns by IIC0 address match A interrupt is disabled</description>
                                    <value>#0</value>
                                </enumeratedValue>
                                <enumeratedValue>
                                    <name>1</name>
                                    <description>Deep Sleep/Software Standby Mode returns by IIC0 address match A interrupt is enabled</description>
                                    <value>#1</value>
                                </enumeratedValue>
                            </enumeratedValues>
                        </field>
                    </fields>
                </register>
                <register>
                    <name>WUPEN1</name>
                    <description>Wake Up interrupt enable register 1</description>
                    <addressOffset>0x1A4</addressOffset>
                    <size>32</size>
                    <access>read-write</access>
                    <resetValue>0x00000000</resetValue>
                    <resetMask>0xffffffff</resetMask>
                    <fields>
                        <field>
                            <name>COMPHS0WUPEN</name>
                            <description>Comparator-HS0 Interrupt Deep Sleep/Software Standby Mode returns Enable bit</description>
                            <lsb>3</lsb>
                            <msb>3</msb>
                            <access>read-write</access>
                            <enumeratedValues>
                                <enumeratedValue>
                                    <name>0</name>
                                    <description>Deep Sleep/Software Standby returns by Comparator-HS0 interrupt is disabled.</description>
                                    <value>#0</value>
                                </enumeratedValue>
                                <enumeratedValue>
                                    <name>1</name>
                                    <description>Deep Sleep/Software Standby returns by ULPT0 Underflow interrupt is enabled.</description>
                                    <value>#1</value>
                                </enumeratedValue>
                            </enumeratedValues>
                        </field>
                        <field>
                            <name>ULP0UWUPEN</name>
                            <description>ULPT0 Underflow Interrupt Deep Sleep/Software Standby Mode returns Enable bit</description>
                            <lsb>8</lsb>
                            <msb>8</msb>
                            <access>read-write</access>
                            <enumeratedValues>
                                <enumeratedValue>
                                    <name>0</name>
                                    <description>Deep Sleep/Software Standby returns by ULPT0 interrupt is disabled.</description>
                                    <value>#0</value>
                                </enumeratedValue>
                                <enumeratedValue>
                                    <name>1</name>
                                    <description>Deep Sleep/Software Standby returns by ULPT0 Underflow interrupt is enabled.</description>
                                    <value>#1</value>
                                </enumeratedValue>
                            </enumeratedValues>
                        </field>
                        <field>
                            <name>ULP0AWUPEN</name>
                            <description>ULPT0 Compare Match A Interrupt Deep Sleep/Software Standby Mode returns Enable bit</description>
                            <lsb>9</lsb>
                            <msb>9</msb>
                            <access>read-write</access>
                            <enumeratedValues>
                                <enumeratedValue>
                                    <name>0</name>
                                    <description>Deep Sleep/Software Standby returns by ULPT0 Compare match A interrupt is disabled.</description>
                                    <value>#0</value>
                                </enumeratedValue>
                                <enumeratedValue>
                                    <name>1</name>
                                    <description>Deep Sleep/Software Standby returns by ULPT0 Compare match A interrupt is enabled.</description>
                                    <value>#1</value>
                                </enumeratedValue>
                            </enumeratedValues>
                        </field>
                        <field>
                            <name>ULP0BWUPEN</name>
                            <description>ULPT0 Compare Match B Interrupt Deep Sleep/Software Standby Mode returns Enable bit</description>
                            <lsb>10</lsb>
                            <msb>10</msb>
                            <access>read-write</access>
                            <enumeratedValues>
                                <enumeratedValue>
                                    <name>0</name>
                                    <description>Deep Sleep/Software Standby returns by ULPT0 Compare match B interrupt is disabled.</description>
                                    <value>#0</value>
                                </enumeratedValue>
                                <enumeratedValue>
                                    <name>1</name>
                                    <description>Deep Sleep/Software Standby returns by ULPT0 Compare match B interrupt is enabled.</description>
                                    <value>#1</value>
                                </enumeratedValue>
                            </enumeratedValues>
                        </field>
                        <field>
                            <name>I3CWUPEN</name>
                            <description>I3C Wakeup Condition Detection Interrupt Deep Sleep/Software Standby Mode returns Enable bit</description>
                            <lsb>11</lsb>
                            <msb>11</msb>
                            <access>read-write</access>
                            <enumeratedValues>
                                <enumeratedValue>
                                    <name>0</name>
                                    <description>Deep Sleep/Software Standby returns by I3C wake up interrupt is disabled.</description>
                                    <value>#0</value>
                                </enumeratedValue>
                                <enumeratedValue>
                                    <name>1</name>
                                    <description>Deep Sleep/Software Standby returns by I3C wake up interrupt is enabled.</description>
                                    <value>#1</value>
                                </enumeratedValue>
                            </enumeratedValues>
                        </field>
                        <field>
                            <name>ULP1UWUPEN</name>
                            <description>ULPT1 Underflow Interrupt Deep Sleep/Software Standby Mode returns Enable bit</description>
                            <lsb>12</lsb>
                            <msb>12</msb>
                            <access>read-write</access>
                            <enumeratedValues>
                                <enumeratedValue>
                                    <name>0</name>
                                    <description>Deep Sleep/Software Standby returns by ULPT1 Underflow interrupt is disabled.</description>
                                    <value>#0</value>
                                </enumeratedValue>
                                <enumeratedValue>
                                    <name>1</name>
                                    <description>Deep Sleep/Software Standby returns by ULPT1 Underflow interrupt is enabled</description>
                                    <value>#1</value>
                                </enumeratedValue>
                            </enumeratedValues>
                        </field>
                        <field>
                            <name>ULP1AWUPEN</name>
                            <description>ULPT1 Compare Match A Interrupt Deep Sleep/Software Standby Mode returns Enable bit</description>
                            <lsb>13</lsb>
                            <msb>13</msb>
                            <access>read-write</access>
                            <enumeratedValues>
                                <enumeratedValue>
                                    <name>0</name>
                                    <description>Deep Sleep/Software Standby returns by ULPT1 Compare match A interrupt is disabled.</description>
                                    <value>#0</value>
                                </enumeratedValue>
                                <enumeratedValue>
                                    <name>1</name>
                                    <description>Deep Sleep/Software Standby returns by ULPT1 Compare match A interrupt is enabled.</description>
                                    <value>#1</value>
                                </enumeratedValue>
                            </enumeratedValues>
                        </field>
                        <field>
                            <name>ULP1BWUPEN</name>
                            <description>ULPT1 Compare Match B Interrupt Deep Sleep/Software Standby Mode returns Enable bit</description>
                            <lsb>14</lsb>
                            <msb>14</msb>
                            <access>read-write</access>
                            <enumeratedValues>
                                <enumeratedValue>
                                    <name>0</name>
                                    <description>Deep Sleep/Software Standby returns by ULPT1 Compare match B interrupt is disabled.</description>
                                    <value>#0</value>
                                </enumeratedValue>
                                <enumeratedValue>
                                    <name>1</name>
                                    <description>Deep Sleep/Software Standby returns by ULPT1 Compare match B interrupt is enabled.</description>
                                    <value>#1</value>
                                </enumeratedValue>
                            </enumeratedValues>
                        </field>
                    </fields>
                </register>
                <register>
                    <dim>96</dim>
                    <dimIncrement>0x4</dimIncrement>
                    <dimIndex>0-95</dimIndex>
                    <name>IELSR%s</name>
                    <description>ICU Event Link Setting Register %s</description>
                    <addressOffset>0x300</addressOffset>
                    <size>32</size>
                    <access>read-write</access>
                    <resetValue>0x00000000</resetValue>
                    <resetMask>0xffffffff</resetMask>
                </register>
            </registers>
        </peripheral>
        <peripheral>
            <name>CPU_CTRL</name>
            <description>CPU(SFR)</description>
            <baseAddress>0x4000F000</baseAddress>
            <addressBlock>
                <offset>0x30</offset>
                <size>1</size>
                <usage>registers</usage>
            </addressBlock>
            <addressBlock>
                <offset>0x400</offset>
                <size>1</size>
                <usage>registers</usage>
            </addressBlock>
            <addressBlock>
                <offset>0x840</offset>
                <size>2</size>
                <usage>registers</usage>
            </addressBlock>
            <registers>
                <register>
                    <name>CPULCKUPCR</name>
                    <description>CPU Lockup Control Register</description>
                    <addressOffset>0x030</addressOffset>
                    <size>8</size>
                    <access>read-write</access>
                    <resetValue>0x00</resetValue>
                    <resetMask>0xff</resetMask>
                    <fields>
                        <field>
                            <name>OAD</name>
                            <description>Operation after detection of CPU lockup</description>
                            <lsb>0</lsb>
                            <msb>0</msb>
                            <access>read-write</access>
                            <enumeratedValues>
                                <enumeratedValue>
                                    <name>0</name>
                                    <description>Non-maskable Interrupt</description>
                                    <value>#0</value>
                                </enumeratedValue>
                                <enumeratedValue>
                                    <name>1</name>
                                    <description>CPU Lockup reset</description>
                                    <value>#1</value>
                                </enumeratedValue>
                            </enumeratedValues>
                        </field>
                    </fields>
                </register>
                <register>
                    <name>CPULOCKCR</name>
                    <description>CPU Function Lock Control Register</description>
                    <addressOffset>0x400</addressOffset>
                    <size>8</size>
                    <access>read-write</access>
                    <resetValue>0x00</resetValue>
                    <resetMask>0xff</resetMask>
                    <fields>
                        <field>
                            <name>LCKSVTAIR</name>
                            <description>Disable writes to the following secure registers from software or from a debug agent that is connected to the processor:</description>
                            <lsb>0</lsb>
                            <msb>0</msb>
                            <access>read-write</access>
                        </field>
                        <field>
                            <name>LCKSMPU</name>
                            <description>Disable writes to registers that are associated with the Secure MPU region from software or from a debug agent connected to the processor:</description>
                            <lsb>1</lsb>
                            <msb>1</msb>
                            <access>read-write</access>
                        </field>
                        <field>
                            <name>LCKSAU</name>
                            <description>Disable writes to registers that are associated with the SAU region from software or from a debug agent connected to the processor:</description>
                            <lsb>2</lsb>
                            <msb>2</msb>
                            <access>read-write</access>
                        </field>
                        <field>
                            <name>LCKITGU</name>
                            <description>Disable writes to registers that are associated with the ITCM interface security gating from software or from a debug agent connected to the processor:</description>
                            <lsb>3</lsb>
                            <msb>3</msb>
                            <access>read-write</access>
                        </field>
                        <field>
                            <name>LCKDTGU</name>
                            <description>Disable writes to registers that are associated with the DTCM interface security gating from software or from a debug agent connected to the processor:</description>
                            <lsb>4</lsb>
                            <msb>4</msb>
                            <access>read-write</access>
                        </field>
                        <field>
                            <name>LCKDCAIC</name>
                            <lsb>5</lsb>
                            <msb>5</msb>
                            <access>read-write</access>
                        </field>
                    </fields>
                </register>
                <register>
                    <name>CPUCRPT</name>
                    <description>CPU Control Register Protection Register</description>
                    <addressOffset>0x840</addressOffset>
                    <size>16</size>
                    <access>read-write</access>
                    <resetValue>0x0000</resetValue>
                    <resetMask>0xffff</resetMask>
                    <fields>
                        <field>
                            <name>PROTECT</name>
                            <description>Protection of register</description>
                            <lsb>0</lsb>
                            <msb>0</msb>
                            <access>read-write</access>
                            <enumeratedValues>
                                <enumeratedValue>
                                    <name>0</name>
                                    <description>Writing to CPULCKUPCR register is permitted.</description>
                                    <value>#0</value>
                                </enumeratedValue>
                                <enumeratedValue>
                                    <name>1</name>
                                    <description>Writing to CPULCKUPCR register is not permitted. Read access is permitted.</description>
                                    <value>#1</value>
                                </enumeratedValue>
                            </enumeratedValues>
                        </field>
                        <field>
                            <name>KEY</name>
                            <description>The KEY[7:0] bits enable or disable writing to the PROTECT bit.</description>
                            <lsb>8</lsb>
                            <msb>15</msb>
                            <access>write-only</access>
                        </field>
                    </fields>
                </register>
            </registers>
        </peripheral>
        <peripheral>
            <name>OCD_CPU</name>
            <description>OCD Function</description>
            <baseAddress>0x40011000</baseAddress>
            <addressBlock>
                <offset>0x04</offset>
                <size>4</size>
                <usage>registers</usage>
            </addressBlock>
            <addressBlock>
                <offset>0x100</offset>
                <size>4</size>
                <usage>registers</usage>
            </addressBlock>
            <addressBlock>
                <offset>0x120</offset>
                <size>4</size>
                <usage>registers</usage>
            </addressBlock>
            <addressBlock>
                <offset>0x130</offset>
                <size>4</size>
                <usage>registers</usage>
            </addressBlock>
            <addressBlock>
                <offset>0x140</offset>
                <size>4</size>
                <usage>registers</usage>
            </addressBlock>
            <addressBlock>
                <offset>0x150</offset>
                <size>4</size>
                <usage>registers</usage>
            </addressBlock>
            <addressBlock>
                <offset>0x300</offset>
                <size>4</size>
                <usage>registers</usage>
            </addressBlock>
            <registers>
                <register>
                    <name>MCUCTRL</name>
                    <description>MCU Control Register</description>
                    <addressOffset>0x004</addressOffset>
                    <size>32</size>
                    <access>read-write</access>
                    <resetValue>0x00000000</resetValue>
                    <resetMask>0xffffffff</resetMask>
                    <fields>
                        <field>
                            <name>EDBGRQ</name>
                            <description>External Debug Request. Writing 1 to the bit causes a CPU Halt or Debug Monitor exception request.</description>
                            <lsb>0</lsb>
                            <msb>0</msb>
                            <access>read-write</access>
                            <enumeratedValues>
                                <enumeratedValue>
                                    <name>0</name>
                                    <description>Debug event is not requested</description>
                                    <value>#0</value>
                                </enumeratedValue>
                                <enumeratedValue>
                                    <name>1</name>
                                    <description>Debug event is requested</description>
                                    <value>#1</value>
                                </enumeratedValue>
                            </enumeratedValues>
                        </field>
                        <field>
                            <name>CPUWAIT</name>
                            <lsb>16</lsb>
                            <msb>16</msb>
                            <access>read-write</access>
                            <enumeratedValues>
                                <enumeratedValue>
                                    <name>0</name>
                                    <description>Deassert CPUWAIT CPU starts boot-up sequence and instruction execution out of Reset. </description>
                                    <value>#0</value>
                                </enumeratedValue>
                                <enumeratedValue>
                                    <name>1</name>
                                    <description>Assert CPUWAIT CPU is forced into a quiescent state out of Reset. </description>
                                    <value>#1</value>
                                </enumeratedValue>
                            </enumeratedValues>
                        </field>
                    </fields>
                </register>
                <register>
                    <name>JBMDR</name>
                    <description>JTAG Boot Mode Entry Register</description>
                    <addressOffset>0x100</addressOffset>
                    <size>32</size>
                    <access>read-write</access>
                    <resetValue>0x00000000</resetValue>
                    <resetMask>0xffffffff</resetMask>
                    <fields>
                        <field>
                            <name>KEY</name>
                            <description>Mode entry key</description>
                            <lsb>0</lsb>
                            <msb>7</msb>
                            <access>read-write</access>
                        </field>
                    </fields>
                </register>
                <register>
                    <name>JBRDR</name>
                    <description>JTAG Boot Receive Data Register</description>
                    <addressOffset>0x120</addressOffset>
                    <size>32</size>
                    <access>read-write</access>
                    <resetValue>0x00000000</resetValue>
                    <resetMask>0xffffffff</resetMask>
                    <fields>
                        <field>
                            <name>RDAT</name>
                            <description>Received data register</description>
                            <lsb>0</lsb>
                            <msb>31</msb>
                            <access>read-write</access>
                        </field>
                    </fields>
                </register>
                <register>
                    <name>JBTDR</name>
                    <description>JTAG Boot Transmit Data Register</description>
                    <addressOffset>0x130</addressOffset>
                    <size>32</size>
                    <access>read-write</access>
                    <resetValue>0x00000000</resetValue>
                    <resetMask>0xffffffff</resetMask>
                    <fields>
                        <field>
                            <name>TDAT</name>
                            <description>Transmitted data register</description>
                            <lsb>0</lsb>
                            <msb>31</msb>
                            <access>read-write</access>
                        </field>
                    </fields>
                </register>
                <register>
                    <name>JBSTR</name>
                    <description>JTAG Boot Status Register</description>
                    <addressOffset>0x140</addressOffset>
                    <size>32</size>
                    <access>read-write</access>
                    <resetValue>0x00000002</resetValue>
                    <resetMask>0xffffffff</resetMask>
                    <fields>
                        <field>
                            <name>RDF</name>
                            <description>Receive buffer full</description>
                            <lsb>0</lsb>
                            <msb>0</msb>
                            <access>read-write</access>
                            <enumeratedValues>
                                <enumeratedValue>
                                    <name>0</name>
                                    <description>No receiving data</description>
                                    <value>#0</value>
                                </enumeratedValue>
                                <enumeratedValue>
                                    <name>1</name>
                                    <description>There is receiving data</description>
                                    <value>#1</value>
                                </enumeratedValue>
                            </enumeratedValues>
                        </field>
                        <field>
                            <name>TDE</name>
                            <description>Transmit data empty</description>
                            <lsb>1</lsb>
                            <msb>1</msb>
                            <access>read-write</access>
                            <enumeratedValues>
                                <enumeratedValue>
                                    <name>0</name>
                                    <description>There is data transmission</description>
                                    <value>#0</value>
                                </enumeratedValue>
                                <enumeratedValue>
                                    <name>1</name>
                                    <description>No data transmission</description>
                                    <value>#1</value>
                                </enumeratedValue>
                            </enumeratedValues>
                        </field>
                    </fields>
                </register>
                <register>
                    <name>JBICR</name>
                    <description>JTAG Boot Interrupt Control Register</description>
                    <addressOffset>0x150</addressOffset>
                    <size>32</size>
                    <access>read-write</access>
                    <resetValue>0x00000000</resetValue>
                    <resetMask>0xffffffff</resetMask>
                    <fields>
                        <field>
                            <name>RDFIE</name>
                            <description>Receive buffer full interrupt enabled</description>
                            <lsb>0</lsb>
                            <msb>0</msb>
                            <access>read-write</access>
                            <enumeratedValues>
                                <enumeratedValue>
                                    <name>0</name>
                                    <description>Interrupt request disabled by RDF = 1</description>
                                    <value>#0</value>
                                </enumeratedValue>
                                <enumeratedValue>
                                    <name>1</name>
                                    <description>Enable interrupt request by RDF = 1</description>
                                    <value>#1</value>
                                </enumeratedValue>
                            </enumeratedValues>
                        </field>
                    </fields>
                </register>
                <register>
                    <name>FSBLSTATM</name>
                    <description>First Stage Boot Loader Status Monitor Register</description>
                    <addressOffset>0x300</addressOffset>
                    <size>32</size>
                    <access>read-only</access>
                    <resetValue>0x00000000</resetValue>
                    <resetMask>0xffffffff</resetMask>
                    <fields>
                        <field>
                            <name>CS</name>
                            <description>FSBL completion status</description>
                            <lsb>0</lsb>
                            <msb>0</msb>
                            <access>read-only</access>
                            <enumeratedValues>
                                <enumeratedValue>
                                    <name>0</name>
                                    <description>FSBL is not complete </description>
                                    <value>#0</value>
                                </enumeratedValue>
                                <enumeratedValue>
                                    <name>1</name>
                                    <description>FSBL is complete</description>
                                    <value>#1</value>
                                </enumeratedValue>
                            </enumeratedValues>
                        </field>
                        <field>
                            <name>RS</name>
                            <description>FSBL result status</description>
                            <lsb>1</lsb>
                            <msb>1</msb>
                            <access>read-only</access>
                            <enumeratedValues>
                                <enumeratedValue>
                                    <name>0</name>
                                    <description>FSBL failed</description>
                                    <value>#0</value>
                                </enumeratedValue>
                                <enumeratedValue>
                                    <name>1</name>
                                    <description>FSBL passed</description>
                                    <value>#1</value>
                                </enumeratedValue>
                            </enumeratedValues>
                        </field>
                    </fields>
                </register>
            </registers>
        </peripheral>
        <peripheral>
            <name>CPU_DBG</name>
            <description>Debug Function</description>
            <baseAddress>0x4001B000</baseAddress>
            <addressBlock>
                <offset>0x00</offset>
                <size>4</size>
                <usage>registers</usage>
            </addressBlock>
            <addressBlock>
                <offset>0x10</offset>
                <size>4</size>
                <usage>registers</usage>
            </addressBlock>
            <addressBlock>
                <offset>0x20</offset>
                <size>8</size>
                <usage>registers</usage>
            </addressBlock>
            <addressBlock>
                <offset>0x30</offset>
                <size>4</size>
                <usage>registers</usage>
            </addressBlock>
            <addressBlock>
                <offset>0x40</offset>
                <size>4</size>
                <usage>registers</usage>
            </addressBlock>
            <addressBlock>
                <offset>0x300</offset>
                <size>4</size>
                <usage>registers</usage>
            </addressBlock>
            <addressBlock>
                <offset>0x310</offset>
                <size>4</size>
                <usage>registers</usage>
            </addressBlock>
            <registers>
                <register>
                    <name>DBGSTR</name>
                    <description>Debug Status Register</description>
                    <addressOffset>0x000</addressOffset>
                    <size>32</size>
                    <access>read-only</access>
                    <resetValue>0x00000000</resetValue>
                    <resetMask>0xcfffffff</resetMask>
                    <fields>
                        <field>
                            <name>CDBGPWRUPREQ</name>
                            <description>Debug power-up request</description>
                            <lsb>28</lsb>
                            <msb>28</msb>
                            <access>read-only</access>
                            <enumeratedValues>
                                <enumeratedValue>
                                    <name>0</name>
                                    <description>OCD is not requesting debug power-up</description>
                                    <value>#0</value>
                                </enumeratedValue>
                                <enumeratedValue>
                                    <name>1</name>
                                    <description>OCD is requesting debug power-up</description>
                                    <value>#1</value>
                                </enumeratedValue>
                            </enumeratedValues>
                        </field>
                        <field>
                            <name>CDBGPWRUPACK</name>
                            <description>Debug power-up acknowledge</description>
                            <lsb>29</lsb>
                            <msb>29</msb>
                            <access>read-only</access>
                            <enumeratedValues>
                                <enumeratedValue>
                                    <name>0</name>
                                    <description>Debug power-up request is not acknowledged</description>
                                    <value>#0</value>
                                </enumeratedValue>
                                <enumeratedValue>
                                    <name>1</name>
                                    <description>Debug power-up request is acknowledged</description>
                                    <value>#1</value>
                                </enumeratedValue>
                            </enumeratedValues>
                        </field>
                    </fields>
                </register>
                <register>
                    <name>DBGSTOPCR</name>
                    <description>Debug Stop Control Register</description>
                    <addressOffset>0x010</addressOffset>
                    <size>32</size>
                    <access>read-write</access>
                    <resetValue>0x00000003</resetValue>
                    <resetMask>0xffffffff</resetMask>
                    <fields>
                        <field>
                            <name>DBGSTOP_IWDT</name>
                            <description>Mask bit for IWDT reset/interrupt in the OCD run mode</description>
                            <lsb>0</lsb>
                            <msb>0</msb>
                            <access>read-write</access>
                            <enumeratedValues>
                                <enumeratedValue>
                                    <name>0</name>
                                    <description>Enable IWDT reset/interrupt</description>
                                    <value>#0</value>
                                </enumeratedValue>
                                <enumeratedValue>
                                    <name>1</name>
                                    <description>Mask IWDT reset/interrupt and stop IWDT counter</description>
                                    <value>#1</value>
                                </enumeratedValue>
                            </enumeratedValues>
                        </field>
                        <field>
                            <name>DBGSTOP_WDT0</name>
                            <description>Mask bit for WDT reset/interrupt in the OCD run mode</description>
                            <lsb>1</lsb>
                            <msb>1</msb>
                            <access>read-write</access>
                            <enumeratedValues>
                                <enumeratedValue>
                                    <name>0</name>
                                    <description>Enable WDT reset/interrupt</description>
                                    <value>#0</value>
                                </enumeratedValue>
                                <enumeratedValue>
                                    <name>1</name>
                                    <description>Mask WDT reset/interrupt and stop WDT counter</description>
                                    <value>#1</value>
                                </enumeratedValue>
                            </enumeratedValues>
                        </field>
                        <field>
                            <name>DBGSTOP_PVD</name>
                            <description>Mask bit for PVDn (n = 1, 2) reset/interrupt</description>
                            <lsb>17</lsb>
                            <msb>17</msb>
                            <access>read-write</access>
                            <enumeratedValues>
                                <enumeratedValue>
                                    <name>0</name>
                                    <description>Enable PVDn (n = 1, 2) reset/interrupt</description>
                                    <value>#0</value>
                                </enumeratedValue>
                                <enumeratedValue>
                                    <name>1</name>
                                    <description>Mask PVDn (n = 1, 2) reset/interrupt</description>
                                    <value>#1</value>
                                </enumeratedValue>
                            </enumeratedValues>
                        </field>
                        <field>
                            <name>DBGSTOP_RER</name>
                            <lsb>24</lsb>
                            <msb>24</msb>
                            <access>read-write</access>
                            <enumeratedValues>
                                <enumeratedValue>
                                    <name>0</name>
                                    <description>Enable SRAM parity/ECC error reset/interrupt</description>
                                    <value>#0</value>
                                </enumeratedValue>
                                <enumeratedValue>
                                    <name>1</name>
                                    <description>Mask SRAM parity/ECC error reset/interrupt</description>
                                    <value>#1</value>
                                </enumeratedValue>
                            </enumeratedValues>
                        </field>
                    </fields>
                </register>
                <register>
                    <name>DBGAUTH0</name>
                    <description>Debug Authentication Control Register 0</description>
                    <addressOffset>0x020</addressOffset>
                    <size>32</size>
                    <access>read-write</access>
                    <resetValue>0x00010000</resetValue>
                    <resetMask>0x7fffffff</resetMask>
                    <fields>
                        <field>
                            <name>DBGEN0</name>
                            <description>CPU invasive debug enable</description>
                            <lsb>0</lsb>
                            <msb>0</msb>
                            <access>read-write</access>
                            <enumeratedValues>
                                <enumeratedValue>
                                    <name>0</name>
                                    <description>Disabled</description>
                                    <value>#0</value>
                                </enumeratedValue>
                                <enumeratedValue>
                                    <name>1</name>
                                    <description>Enabled</description>
                                    <value>#1</value>
                                </enumeratedValue>
                            </enumeratedValues>
                        </field>
                        <field>
                            <name>NIDEN0</name>
                            <description>CPU non-invasive debug enable</description>
                            <lsb>4</lsb>
                            <msb>4</msb>
                            <access>read-write</access>
                            <enumeratedValues>
                                <enumeratedValue>
                                    <name>0</name>
                                    <description>Disabled</description>
                                    <value>#0</value>
                                </enumeratedValue>
                                <enumeratedValue>
                                    <name>1</name>
                                    <description>Enabled</description>
                                    <value>#1</value>
                                </enumeratedValue>
                            </enumeratedValues>
                        </field>
                        <field>
                            <name>DBGENAP</name>
                            <description>CPU AHB-AP (AP0) debug enable</description>
                            <lsb>8</lsb>
                            <msb>8</msb>
                            <access>read-write</access>
                            <enumeratedValues>
                                <enumeratedValue>
                                    <name>0</name>
                                    <description>Disabled</description>
                                    <value>#0</value>
                                </enumeratedValue>
                                <enumeratedValue>
                                    <name>1</name>
                                    <description>Enabled</description>
                                    <value>#1</value>
                                </enumeratedValue>
                            </enumeratedValues>
                        </field>
                        <field>
                            <name>DEVICEEN</name>
                            <description>APB-AP (AP1) authentication</description>
                            <lsb>16</lsb>
                            <msb>16</msb>
                            <access>read-write</access>
                            <enumeratedValues>
                                <enumeratedValue>
                                    <name>0</name>
                                    <description>Disabled</description>
                                    <value>#0</value>
                                </enumeratedValue>
                                <enumeratedValue>
                                    <name>1</name>
                                    <description>Enabled</description>
                                    <value>#1</value>
                                </enumeratedValue>
                            </enumeratedValues>
                        </field>
                        <field>
                            <name>SWDBG</name>
                            <description>Software control of debug function</description>
                            <lsb>31</lsb>
                            <msb>31</msb>
                            <access>read-write</access>
                            <enumeratedValues>
                                <enumeratedValue>
                                    <name>0</name>
                                    <description>Disabled</description>
                                    <value>#0</value>
                                </enumeratedValue>
                                <enumeratedValue>
                                    <name>1</name>
                                    <description>Enabled</description>
                                    <value>#1</value>
                                </enumeratedValue>
                            </enumeratedValues>
                        </field>
                    </fields>
                </register>
                <register>
                    <name>DBGAUTH1</name>
                    <description>Debug Authentication Control Register 1</description>
                    <addressOffset>0x024</addressOffset>
                    <size>32</size>
                    <access>read-write</access>
                    <resetValue>0x00000000</resetValue>
                    <resetMask>0xffffffff</resetMask>
                    <fields>
                        <field>
                            <name>SPIDENAP</name>
                            <description>CPU AHB-AP (AP0) debug enable</description>
                            <lsb>8</lsb>
                            <msb>8</msb>
                            <access>read-write</access>
                            <enumeratedValues>
                                <enumeratedValue>
                                    <name>0</name>
                                    <description>Disabled</description>
                                    <value>#0</value>
                                </enumeratedValue>
                                <enumeratedValue>
                                    <name>1</name>
                                    <description>Enabled</description>
                                    <value>#1</value>
                                </enumeratedValue>
                            </enumeratedValues>
                        </field>
                    </fields>
                </register>
                <register>
                    <name>TRPORTCR</name>
                    <description>Trace Port Control Register</description>
                    <addressOffset>0x030</addressOffset>
                    <size>32</size>
                    <access>read-write</access>
                    <resetValue>0x00000004</resetValue>
                    <resetMask>0xffffffff</resetMask>
                    <fields>
                        <field>
                            <name>OE</name>
                            <description>Data Out Enable bit indicates whether Trace Clock, Trace Data, and SWO outputs are enabled.</description>
                            <lsb>0</lsb>
                            <msb>0</msb>
                            <access>read-write</access>
                            <enumeratedValues>
                                <enumeratedValue>
                                    <name>0</name>
                                    <description>Output disabled</description>
                                    <value>#0</value>
                                </enumeratedValue>
                                <enumeratedValue>
                                    <name>1</name>
                                    <description>Output enabled</description>
                                    <value>#1</value>
                                </enumeratedValue>
                            </enumeratedValues>
                        </field>
                        <field>
                            <name>DRV</name>
                            <description>Port Drive Capability Control indicates trace port buffer speed:</description>
                            <lsb>2</lsb>
                            <msb>3</msb>
                            <access>read-write</access>
                            <enumeratedValues>
                                <enumeratedValue>
                                    <name>00</name>
                                    <description>Low-drive</description>
                                    <value>#00</value>
                                </enumeratedValue>
                                <enumeratedValue>
                                    <name>01</name>
                                    <description>Middle-drive</description>
                                    <value>#01</value>
                                </enumeratedValue>
                                <enumeratedValue>
                                    <name>10</name>
                                    <description>High-speed high-drive</description>
                                    <value>#10</value>
                                </enumeratedValue>
                                <enumeratedValue>
                                    <name>11</name>
                                    <description>High-drive</description>
                                    <value>#11</value>
                                </enumeratedValue>
                            </enumeratedValues>
                        </field>
                    </fields>
                </register>
                <register>
                    <name>CACHEDBGCR</name>
                    <description>Cache Debug Control Register</description>
                    <addressOffset>0x040</addressOffset>
                    <size>32</size>
                    <access>read-write</access>
                    <resetValue>0x00000000</resetValue>
                    <resetMask>0xffffffff</resetMask>
                    <fields>
                        <field>
                            <name>L1RSTDIS</name>
                            <description>Disable L1 cache automatic invalidation</description>
                            <lsb>0</lsb>
                            <msb>0</msb>
                            <access>read-write</access>
                            <enumeratedValues>
                                <enumeratedValue>
                                    <name>0</name>
                                    <description>Enable automatic invalidation of the L1 cache</description>
                                    <value>#0</value>
                                </enumeratedValue>
                                <enumeratedValue>
                                    <name>1</name>
                                    <description>Disable automatic invalidation of the L1 cache</description>
                                    <value>#1</value>
                                </enumeratedValue>
                            </enumeratedValues>
                        </field>
                    </fields>
                </register>
                <register>
                    <name>DBGMOCOEN</name>
                    <description>MOCO Enable Request Register for Debug</description>
                    <addressOffset>0x300</addressOffset>
                    <size>32</size>
                    <access>read-write</access>
                    <resetValue>0x00000000</resetValue>
                    <resetMask>0xffffffff</resetMask>
                    <fields>
                        <field>
                            <name>MOCOEN</name>
                            <description>MOCO enable request</description>
                            <lsb>0</lsb>
                            <msb>0</msb>
                            <access>read-write</access>
                            <enumeratedValues>
                                <enumeratedValue>
                                    <name>0</name>
                                    <description>No request MOCO enable</description>
                                    <value>#0</value>
                                </enumeratedValue>
                                <enumeratedValue>
                                    <name>1</name>
                                    <description>Request MOCO enable</description>
                                    <value>#1</value>
                                </enumeratedValue>
                            </enumeratedValues>
                        </field>
                    </fields>
                </register>
                <register>
                    <name>DBGFCLKSEL</name>
                    <description>Flash Sequencer Clock Select Register for Debug</description>
                    <addressOffset>0x310</addressOffset>
                    <size>32</size>
                    <access>read-write</access>
                    <resetValue>0x00000000</resetValue>
                    <resetMask>0xffffffff</resetMask>
                    <fields>
                        <field>
                            <name>FCLKSEL</name>
                            <description>Flash sequencer clock select</description>
                            <lsb>0</lsb>
                            <msb>0</msb>
                            <access>read-write</access>
                            <enumeratedValues>
                                <enumeratedValue>
                                    <name>0</name>
                                    <description>FCLK</description>
                                    <value>#0</value>
                                </enumeratedValue>
                                <enumeratedValue>
                                    <name>1</name>
                                    <description>MOCO</description>
                                    <value>#1</value>
                                </enumeratedValue>
                            </enumeratedValues>
                        </field>
                    </fields>
                </register>
            </registers>
        </peripheral>
        <peripheral>
            <name>FCACHE</name>
            <description>SYSTEM/FLASH</description>
            <baseAddress>0x4001C100</baseAddress>
            <addressBlock>
                <offset>0x00</offset>
                <size>2</size>
                <usage>registers</usage>
            </addressBlock>
            <addressBlock>
                <offset>0x04</offset>
                <size>2</size>
                <usage>registers</usage>
            </addressBlock>
            <addressBlock>
                <offset>0x1C</offset>
                <size>1</size>
                <usage>registers</usage>
            </addressBlock>
            <addressBlock>
                <offset>0x40</offset>
                <size>2</size>
                <usage>registers</usage>
            </addressBlock>
            <registers>
                <register>
                    <name>FCACHEE</name>
                    <description>Flash Cache Enable Register</description>
                    <addressOffset>0x000</addressOffset>
                    <size>16</size>
                    <access>read-write</access>
                    <resetValue>0x0000</resetValue>
                    <resetMask>0xffff</resetMask>
                    <fields>
                        <field>
                            <name>FCACHEEN</name>
                            <description>Flash Cache Enable</description>
                            <lsb>0</lsb>
                            <msb>0</msb>
                            <access>read-write</access>
                            <enumeratedValues>
                                <enumeratedValue>
                                    <name>0</name>
                                    <description>FCACHE is disabled</description>
                                    <value>#0</value>
                                </enumeratedValue>
                                <enumeratedValue>
                                    <name>1</name>
                                    <description>FCACHE is enabled</description>
                                    <value>#1</value>
                                </enumeratedValue>
                            </enumeratedValues>
                        </field>
                    </fields>
                </register>
                <register>
                    <name>FCACHEIV</name>
                    <description>Flash Cache Invalidate Register</description>
                    <addressOffset>0x004</addressOffset>
                    <size>16</size>
                    <access>read-write</access>
                    <resetValue>0x0000</resetValue>
                    <resetMask>0xffff</resetMask>
                    <fields>
                        <field>
                            <name>FCACHEIV</name>
                            <description>Flash Cache Invalidate</description>
                            <lsb>0</lsb>
                            <msb>0</msb>
                            <access>read-write</access>
                            <enumeratedValues>
                                <enumeratedValue>
                                    <name>0</name>
                                    <description>Read: Do not invalidate. Write: The setting is ignored. </description>
                                    <value>#0</value>
                                </enumeratedValue>
                                <enumeratedValue>
                                    <name>1</name>
                                    <description>Invalidate FCACHE is invalidated. </description>
                                    <value>#1</value>
                                </enumeratedValue>
                            </enumeratedValues>
                        </field>
                    </fields>
                </register>
                <register>
                    <name>FLWT</name>
                    <description>Flash Wait Cycle Register</description>
                    <addressOffset>0x01C</addressOffset>
                    <size>8</size>
                    <access>read-write</access>
                    <resetValue>0x00</resetValue>
                    <resetMask>0xff</resetMask>
                    <fields>
                        <field>
                            <name>FLWT</name>
                            <description>Flash Wait Cycle</description>
                            <lsb>0</lsb>
                            <msb>2</msb>
                            <access>read-write</access>
                        </field>
                    </fields>
                </register>
                <register>
                    <name>FSAR</name>
                    <description>Flash Security Attribution Register</description>
                    <addressOffset>0x040</addressOffset>
                    <size>16</size>
                    <access>read-write</access>
                    <resetValue>0x0000</resetValue>
                    <resetMask>0xffff</resetMask>
                    <fields>
                        <field>
                            <name>FLWTSA</name>
                            <description>FLWT Security Attribution</description>
                            <lsb>0</lsb>
                            <msb>0</msb>
                            <access>read-write</access>
                            <enumeratedValues>
                                <enumeratedValue>
                                    <name>0</name>
                                    <description>Secure</description>
                                    <value>#0</value>
                                </enumeratedValue>
                                <enumeratedValue>
                                    <name>1</name>
                                    <description>Non-secure</description>
                                    <value>#1</value>
                                </enumeratedValue>
                            </enumeratedValues>
                        </field>
                        <field>
                            <name>FCACHESA</name>
                            <description>FCHACHEEN Security Attribution</description>
                            <lsb>1</lsb>
                            <msb>1</msb>
                            <access>read-write</access>
                            <enumeratedValues>
                                <enumeratedValue>
                                    <name>0</name>
                                    <description>Secure</description>
                                    <value>#0</value>
                                </enumeratedValue>
                                <enumeratedValue>
                                    <name>1</name>
                                    <description>Non-secure</description>
                                    <value>#1</value>
                                </enumeratedValue>
                            </enumeratedValues>
                        </field>
                        <field>
                            <name>FCKMHZSA</name>
                            <description>FCKMHZ Security Attribution</description>
                            <lsb>8</lsb>
                            <msb>8</msb>
                            <access>read-write</access>
                            <enumeratedValues>
                                <enumeratedValue>
                                    <name>0</name>
                                    <description>Secure</description>
                                    <value>#0</value>
                                </enumeratedValue>
                                <enumeratedValue>
                                    <name>1</name>
                                    <description>Non-secure</description>
                                    <value>#1</value>
                                </enumeratedValue>
                            </enumeratedValues>
                        </field>
                        <field>
                            <name>FACICMISA</name>
                            <description>FACI command Issuing Security Attribution</description>
                            <lsb>9</lsb>
                            <msb>9</msb>
                            <access>read-write</access>
                            <enumeratedValues>
                                <enumeratedValue>
                                    <name>0</name>
                                    <description>Secure</description>
                                    <value>#0</value>
                                </enumeratedValue>
                                <enumeratedValue>
                                    <name>1</name>
                                    <description>Non-secure</description>
                                    <value>#1</value>
                                </enumeratedValue>
                            </enumeratedValues>
                        </field>
                        <field>
                            <name>FACICMRSA</name>
                            <description>FACI command Registers Security Attribution</description>
                            <lsb>10</lsb>
                            <msb>10</msb>
                            <access>read-write</access>
                            <enumeratedValues>
                                <enumeratedValue>
                                    <name>0</name>
                                    <description>Secure</description>
                                    <value>#0</value>
                                </enumeratedValue>
                                <enumeratedValue>
                                    <name>1</name>
                                    <description>Non-secure</description>
                                    <value>#1</value>
                                </enumeratedValue>
                            </enumeratedValues>
                        </field>
                    </fields>
                </register>
            </registers>
        </peripheral>
        <peripheral>
            <name>SYSC</name>
            <description>System Control</description>
            <baseAddress>0x4001E000</baseAddress>
            <addressBlock>
                <offset>0x0C</offset>
                <size>1</size>
                <usage>registers</usage>
            </addressBlock>
            <addressBlock>
                <offset>0x20</offset>
                <size>5</size>
                <usage>registers</usage>
            </addressBlock>
            <addressBlock>
                <offset>0x26</offset>
                <size>1</size>
                <usage>registers</usage>
            </addressBlock>
            <addressBlock>
                <offset>0x28</offset>
                <size>3</size>
                <usage>registers</usage>
            </addressBlock>
            <addressBlock>
                <offset>0x30</offset>
                <size>1</size>
                <usage>registers</usage>
            </addressBlock>
            <addressBlock>
                <offset>0x32</offset>
                <size>1</size>
                <usage>registers</usage>
            </addressBlock>
            <addressBlock>
                <offset>0x36</offset>
                <size>7</size>
                <usage>registers</usage>
            </addressBlock>
            <addressBlock>
                <offset>0x3E</offset>
                <size>4</size>
                <usage>registers</usage>
            </addressBlock>
            <addressBlock>
                <offset>0x43</offset>
                <size>1</size>
                <usage>registers</usage>
            </addressBlock>
            <addressBlock>
                <offset>0x48</offset>
                <size>3</size>
                <usage>registers</usage>
            </addressBlock>
            <addressBlock>
                <offset>0x4C</offset>
                <size>4</size>
                <usage>registers</usage>
            </addressBlock>
            <addressBlock>
                <offset>0x52</offset>
                <size>6</size>
                <usage>registers</usage>
            </addressBlock>
            <addressBlock>
                <offset>0x5E</offset>
                <size>2</size>
                <usage>registers</usage>
            </addressBlock>
            <addressBlock>
                <offset>0x61</offset>
                <size>2</size>
                <usage>registers</usage>
            </addressBlock>
            <addressBlock>
                <offset>0x6C</offset>
                <size>5</size>
                <usage>registers</usage>
            </addressBlock>
            <addressBlock>
                <offset>0x74</offset>
                <size>5</size>
                <usage>registers</usage>
            </addressBlock>
            <addressBlock>
                <offset>0x7C</offset>
                <size>2</size>
                <usage>registers</usage>
            </addressBlock>
            <addressBlock>
                <offset>0xA0</offset>
                <size>1</size>
                <usage>registers</usage>
            </addressBlock>
            <addressBlock>
                <offset>0xA2</offset>
                <size>1</size>
                <usage>registers</usage>
            </addressBlock>
            <addressBlock>
                <offset>0xC0</offset>
                <size>4</size>
                <usage>registers</usage>
            </addressBlock>
            <addressBlock>
                <offset>0xCC</offset>
                <size>1</size>
                <usage>registers</usage>
            </addressBlock>
            <addressBlock>
                <offset>0xE0</offset>
                <size>5</size>
                <usage>registers</usage>
            </addressBlock>
            <addressBlock>
                <offset>0x110</offset>
                <size>1</size>
                <usage>registers</usage>
            </addressBlock>
            <addressBlock>
                <offset>0x140</offset>
                <size>3</size>
                <usage>registers</usage>
            </addressBlock>
            <addressBlock>
                <offset>0x3B0</offset>
                <size>2</size>
                <usage>registers</usage>
            </addressBlock>
            <addressBlock>
                <offset>0x3B4</offset>
                <size>2</size>
                <usage>registers</usage>
            </addressBlock>
            <addressBlock>
                <offset>0x3C0</offset>
                <size>20</size>
                <usage>registers</usage>
            </addressBlock>
            <addressBlock>
                <offset>0x3D8</offset>
                <size>4</size>
                <usage>registers</usage>
            </addressBlock>
            <addressBlock>
                <offset>0x3E0</offset>
                <size>8</size>
                <usage>registers</usage>
            </addressBlock>
            <addressBlock>
                <offset>0x3FA</offset>
                <size>2</size>
                <usage>registers</usage>
            </addressBlock>
            <addressBlock>
                <offset>0x400</offset>
                <size>1</size>
                <usage>registers</usage>
            </addressBlock>
            <addressBlock>
                <offset>0x402</offset>
                <size>1</size>
                <usage>registers</usage>
            </addressBlock>
            <addressBlock>
                <offset>0xA00</offset>
                <size>1</size>
                <usage>registers</usage>
            </addressBlock>
            <addressBlock>
                <offset>0xA04</offset>
                <size>1</size>
                <usage>registers</usage>
            </addressBlock>
            <addressBlock>
                <offset>0xA08</offset>
                <size>1</size>
                <usage>registers</usage>
            </addressBlock>
            <addressBlock>
                <offset>0xA0C</offset>
                <size>1</size>
                <usage>registers</usage>
            </addressBlock>
            <addressBlock>
                <offset>0xA10</offset>
                <size>1</size>
                <usage>registers</usage>
            </addressBlock>
            <addressBlock>
                <offset>0xA14</offset>
                <size>1</size>
                <usage>registers</usage>
            </addressBlock>
            <addressBlock>
                <offset>0xA18</offset>
                <size>1</size>
                <usage>registers</usage>
            </addressBlock>
            <addressBlock>
                <offset>0xA1C</offset>
                <size>1</size>
                <usage>registers</usage>
            </addressBlock>
            <addressBlock>
                <offset>0xA20</offset>
                <size>1</size>
                <usage>registers</usage>
            </addressBlock>
            <addressBlock>
                <offset>0xA24</offset>
                <size>1</size>
                <usage>registers</usage>
            </addressBlock>
            <addressBlock>
                <offset>0xA28</offset>
                <size>1</size>
                <usage>registers</usage>
            </addressBlock>
            <addressBlock>
                <offset>0xA2C</offset>
                <size>1</size>
                <usage>registers</usage>
            </addressBlock>
            <addressBlock>
                <offset>0xA30</offset>
                <size>1</size>
                <usage>registers</usage>
            </addressBlock>
            <addressBlock>
                <offset>0xA38</offset>
                <size>1</size>
                <usage>registers</usage>
            </addressBlock>
            <addressBlock>
                <offset>0xA40</offset>
                <size>1</size>
                <usage>registers</usage>
            </addressBlock>
            <addressBlock>
                <offset>0xA44</offset>
                <size>1</size>
                <usage>registers</usage>
            </addressBlock>
            <addressBlock>
                <offset>0xA50</offset>
                <size>1</size>
                <usage>registers</usage>
            </addressBlock>
            <addressBlock>
                <offset>0xA54</offset>
                <size>1</size>
                <usage>registers</usage>
            </addressBlock>
            <addressBlock>
                <offset>0xA58</offset>
                <size>8</size>
                <usage>registers</usage>
            </addressBlock>
            <addressBlock>
                <offset>0xA70</offset>
                <size>8</size>
                <usage>registers</usage>
            </addressBlock>
            <addressBlock>
                <offset>0xA84</offset>
                <size>1</size>
                <usage>registers</usage>
            </addressBlock>
            <addressBlock>
                <offset>0xA88</offset>
                <size>1</size>
                <usage>registers</usage>
            </addressBlock>
            <addressBlock>
                <offset>0xA90</offset>
                <size>1</size>
                <usage>registers</usage>
            </addressBlock>
            <addressBlock>
                <offset>0xA98</offset>
                <size>1</size>
                <usage>registers</usage>
            </addressBlock>
            <addressBlock>
                <offset>0xAB0</offset>
                <size>1</size>
                <usage>registers</usage>
            </addressBlock>
            <addressBlock>
                <offset>0xAD0</offset>
                <size>1</size>
                <usage>registers</usage>
            </addressBlock>
            <addressBlock>
                <offset>0xAD8</offset>
                <size>1</size>
                <usage>registers</usage>
            </addressBlock>
            <addressBlock>
                <offset>0xB04</offset>
                <size>1</size>
                <usage>registers</usage>
            </addressBlock>
            <addressBlock>
                <offset>0xB08</offset>
                <size>1</size>
                <usage>registers</usage>
            </addressBlock>
            <addressBlock>
                <offset>0xB0C</offset>
                <size>1</size>
                <usage>registers</usage>
            </addressBlock>
            <addressBlock>
                <offset>0xB20</offset>
                <size>8</size>
                <usage>registers</usage>
            </addressBlock>
            <addressBlock>
                <offset>0xC00</offset>
                <size>2</size>
                <usage>registers</usage>
            </addressBlock>
            <addressBlock>
                <offset>0xC40</offset>
                <size>1</size>
                <usage>registers</usage>
            </addressBlock>
            <addressBlock>
                <offset>0xC45</offset>
                <size>2</size>
                <usage>registers</usage>
            </addressBlock>
            <addressBlock>
                <offset>0xC48</offset>
                <size>3</size>
                <usage>registers</usage>
            </addressBlock>
            <addressBlock>
                <offset>0xC4C</offset>
                <size>3</size>
                <usage>registers</usage>
            </addressBlock>
            <addressBlock>
                <offset>0xD00</offset>
                <size>128</size>
                <usage>registers</usage>
            </addressBlock>
            <registers>
                <register>
                    <name>SBYCR</name>
                    <description>Standby Control Register</description>
                    <addressOffset>0x00C</addressOffset>
                    <size>8</size>
                    <access>read-write</access>
                    <resetValue>0x40</resetValue>
                    <resetMask>0xff</resetMask>
                    <fields>
                        <field>
                            <name>OPE</name>
                            <description>Output Port Enable</description>
                            <lsb>6</lsb>
                            <msb>6</msb>
                            <access>read-write</access>
                            <enumeratedValues>
                                <enumeratedValue>
                                    <name>0</name>
                                    <description>In Software Standby mode or Deep Software Standby mode, set the address bus and other bus control signal to the high-impedance state. </description>
                                    <value>#0</value>
                                </enumeratedValue>
                                <enumeratedValue>
                                    <name>1</name>
                                    <description>In Software Standby mode or Deep Software Standby mode, address bus and other bus control signal retain the output state. </description>
                                    <value>#1</value>
                                </enumeratedValue>
                            </enumeratedValues>
                        </field>
                    </fields>
                </register>
                <register>
                    <name>SCKDIVCR</name>
                    <description>System Clock Division Control Register</description>
                    <addressOffset>0x020</addressOffset>
                    <size>32</size>
                    <access>read-write</access>
                    <resetValue>0x00000000</resetValue>
                    <resetMask>0xffffffff</resetMask>
                    <fields>
                        <field>
                            <name>PCKD</name>
                            <description>Peripheral Module Clock D (PCLKD) Select</description>
                            <lsb>0</lsb>
                            <msb>3</msb>
                            <access>read-write</access>
                            <enumeratedValues>
                                <enumeratedValue>
                                    <name>0000</name>
                                    <description>x 1/1</description>
                                    <value>#0000</value>
                                </enumeratedValue>
                                <enumeratedValue>
                                    <name>0001</name>
                                    <description>x 1/2</description>
                                    <value>#0001</value>
                                </enumeratedValue>
                                <enumeratedValue>
                                    <name>0010</name>
                                    <description>x 1/4</description>
                                    <value>#0010</value>
                                </enumeratedValue>
                                <enumeratedValue>
                                    <name>0011</name>
                                    <description>x 1/8</description>
                                    <value>#0011</value>
                                </enumeratedValue>
                                <enumeratedValue>
                                    <name>0100</name>
                                    <description>x 1/16</description>
                                    <value>#0100</value>
                                </enumeratedValue>
                                <enumeratedValue>
                                    <name>0101</name>
                                    <description>x 1/32</description>
                                    <value>#0101</value>
                                </enumeratedValue>
                                <enumeratedValue>
                                    <name>0110</name>
                                    <description>x 1/64</description>
                                    <value>#0110</value>
                                </enumeratedValue>
                                <enumeratedValue>
                                    <name>1000</name>
                                    <description>x 1/3</description>
                                    <value>#1000</value>
                                </enumeratedValue>
                                <enumeratedValue>
                                    <name>1001</name>
                                    <description>x 1/6</description>
                                    <value>#1001</value>
                                </enumeratedValue>
                                <enumeratedValue>
                                    <name>1010</name>
                                    <description>x 1/12</description>
                                    <value>#1010</value>
                                </enumeratedValue>
                                <enumeratedValue>
                                    <name>Others</name>
                                    <description>Setting prohibited.</description>
                                    <isDefault>true</isDefault>
                                </enumeratedValue>
                            </enumeratedValues>
                        </field>
                        <field>
                            <name>PCKC</name>
                            <description>Peripheral Module Clock C (PCLKC) Select</description>
                            <lsb>4</lsb>
                            <msb>7</msb>
                            <access>read-write</access>
                            <enumeratedValues>
                                <enumeratedValue>
                                    <name>0000</name>
                                    <description>x 1/1</description>
                                    <value>#0000</value>
                                </enumeratedValue>
                                <enumeratedValue>
                                    <name>0001</name>
                                    <description>x 1/2</description>
                                    <value>#0001</value>
                                </enumeratedValue>
                                <enumeratedValue>
                                    <name>0010</name>
                                    <description>x 1/4</description>
                                    <value>#0010</value>
                                </enumeratedValue>
                                <enumeratedValue>
                                    <name>0011</name>
                                    <description>x 1/8</description>
                                    <value>#0011</value>
                                </enumeratedValue>
                                <enumeratedValue>
                                    <name>0100</name>
                                    <description>x 1/16</description>
                                    <value>#0100</value>
                                </enumeratedValue>
                                <enumeratedValue>
                                    <name>0101</name>
                                    <description>x 1/32</description>
                                    <value>#0101</value>
                                </enumeratedValue>
                                <enumeratedValue>
                                    <name>0110</name>
                                    <description>x 1/64</description>
                                    <value>#0110</value>
                                </enumeratedValue>
                                <enumeratedValue>
                                    <name>1000</name>
                                    <description>x 1/3</description>
                                    <value>#1000</value>
                                </enumeratedValue>
                                <enumeratedValue>
                                    <name>1001</name>
                                    <description>x 1/6</description>
                                    <value>#1001</value>
                                </enumeratedValue>
                                <enumeratedValue>
                                    <name>1010</name>
                                    <description>x 1/12</description>
                                    <value>#1010</value>
                                </enumeratedValue>
                                <enumeratedValue>
                                    <name>Others</name>
                                    <description>Setting prohibited.</description>
                                    <isDefault>true</isDefault>
                                </enumeratedValue>
                            </enumeratedValues>
                        </field>
                        <field>
                            <name>PCKB</name>
                            <description>Peripheral Module Clock B (PCLKB) Select</description>
                            <lsb>8</lsb>
                            <msb>11</msb>
                            <access>read-write</access>
                            <enumeratedValues>
                                <enumeratedValue>
                                    <name>0000</name>
                                    <description>x 1/1</description>
                                    <value>#0000</value>
                                </enumeratedValue>
                                <enumeratedValue>
                                    <name>0001</name>
                                    <description>x 1/2</description>
                                    <value>#0001</value>
                                </enumeratedValue>
                                <enumeratedValue>
                                    <name>0010</name>
                                    <description>x 1/4</description>
                                    <value>#0010</value>
                                </enumeratedValue>
                                <enumeratedValue>
                                    <name>0011</name>
                                    <description>x 1/8</description>
                                    <value>#0011</value>
                                </enumeratedValue>
                                <enumeratedValue>
                                    <name>0100</name>
                                    <description>x 1/16</description>
                                    <value>#0100</value>
                                </enumeratedValue>
                                <enumeratedValue>
                                    <name>0101</name>
                                    <description>x 1/32</description>
                                    <value>#0101</value>
                                </enumeratedValue>
                                <enumeratedValue>
                                    <name>0110</name>
                                    <description>x 1/64</description>
                                    <value>#0110</value>
                                </enumeratedValue>
                                <enumeratedValue>
                                    <name>1000</name>
                                    <description>x 1/3</description>
                                    <value>#1000</value>
                                </enumeratedValue>
                                <enumeratedValue>
                                    <name>1001</name>
                                    <description>x 1/6</description>
                                    <value>#1001</value>
                                </enumeratedValue>
                                <enumeratedValue>
                                    <name>1010</name>
                                    <description>x 1/12</description>
                                    <value>#1010</value>
                                </enumeratedValue>
                                <enumeratedValue>
                                    <name>Others</name>
                                    <description>Setting prohibited.</description>
                                    <isDefault>true</isDefault>
                                </enumeratedValue>
                            </enumeratedValues>
                        </field>
                        <field>
                            <name>PCKA</name>
                            <description>Peripheral Module Clock A (PCLKA) Select</description>
                            <lsb>12</lsb>
                            <msb>15</msb>
                            <access>read-write</access>
                            <enumeratedValues>
                                <enumeratedValue>
                                    <name>0000</name>
                                    <description>x 1/1</description>
                                    <value>#0000</value>
                                </enumeratedValue>
                                <enumeratedValue>
                                    <name>0001</name>
                                    <description>x 1/2</description>
                                    <value>#0001</value>
                                </enumeratedValue>
                                <enumeratedValue>
                                    <name>0010</name>
                                    <description>x 1/4</description>
                                    <value>#0010</value>
                                </enumeratedValue>
                                <enumeratedValue>
                                    <name>0011</name>
                                    <description>x 1/8</description>
                                    <value>#0011</value>
                                </enumeratedValue>
                                <enumeratedValue>
                                    <name>0100</name>
                                    <description>x 1/16</description>
                                    <value>#0100</value>
                                </enumeratedValue>
                                <enumeratedValue>
                                    <name>0101</name>
                                    <description>x 1/32</description>
                                    <value>#0101</value>
                                </enumeratedValue>
                                <enumeratedValue>
                                    <name>0110</name>
                                    <description>x 1/64</description>
                                    <value>#0110</value>
                                </enumeratedValue>
                                <enumeratedValue>
                                    <name>1000</name>
                                    <description>x 1/3</description>
                                    <value>#1000</value>
                                </enumeratedValue>
                                <enumeratedValue>
                                    <name>1001</name>
                                    <description>x 1/6</description>
                                    <value>#1001</value>
                                </enumeratedValue>
                                <enumeratedValue>
                                    <name>1010</name>
                                    <description>x 1/12</description>
                                    <value>#1010</value>
                                </enumeratedValue>
                                <enumeratedValue>
                                    <name>Others</name>
                                    <description>Setting prohibited.</description>
                                    <isDefault>true</isDefault>
                                </enumeratedValue>
                            </enumeratedValues>
                        </field>
                        <field>
                            <name>BCK</name>
                            <description>External Bus Clock (BCLK) Select</description>
                            <lsb>16</lsb>
                            <msb>19</msb>
                            <access>read-write</access>
                            <enumeratedValues>
                                <enumeratedValue>
                                    <name>0000</name>
                                    <description>x 1/1</description>
                                    <value>#0000</value>
                                </enumeratedValue>
                                <enumeratedValue>
                                    <name>0001</name>
                                    <description>x 1/2</description>
                                    <value>#0001</value>
                                </enumeratedValue>
                                <enumeratedValue>
                                    <name>0010</name>
                                    <description>x 1/4</description>
                                    <value>#0010</value>
                                </enumeratedValue>
                                <enumeratedValue>
                                    <name>0011</name>
                                    <description>x 1/8</description>
                                    <value>#0011</value>
                                </enumeratedValue>
                                <enumeratedValue>
                                    <name>0100</name>
                                    <description>x 1/16</description>
                                    <value>#0100</value>
                                </enumeratedValue>
                                <enumeratedValue>
                                    <name>0101</name>
                                    <description>x 1/32</description>
                                    <value>#0101</value>
                                </enumeratedValue>
                                <enumeratedValue>
                                    <name>0110</name>
                                    <description>x 1/64</description>
                                    <value>#0110</value>
                                </enumeratedValue>
                                <enumeratedValue>
                                    <name>1000</name>
                                    <description>x 1/3</description>
                                    <value>#1000</value>
                                </enumeratedValue>
                                <enumeratedValue>
                                    <name>1001</name>
                                    <description>x 1/6</description>
                                    <value>#1001</value>
                                </enumeratedValue>
                                <enumeratedValue>
                                    <name>1010</name>
                                    <description>x 1/12</description>
                                    <value>#1010</value>
                                </enumeratedValue>
                                <enumeratedValue>
                                    <name>Others</name>
                                    <description>Settings prohibited</description>
                                    <isDefault>true</isDefault>
                                </enumeratedValue>
                            </enumeratedValues>
                        </field>
                        <field>
                            <name>ICK</name>
                            <description>System Clock (ICLK) Select</description>
                            <lsb>24</lsb>
                            <msb>27</msb>
                            <access>read-write</access>
                            <enumeratedValues>
                                <enumeratedValue>
                                    <name>0000</name>
                                    <description>x 1/1</description>
                                    <value>#0000</value>
                                </enumeratedValue>
                                <enumeratedValue>
                                    <name>0001</name>
                                    <description>x 1/2</description>
                                    <value>#0001</value>
                                </enumeratedValue>
                                <enumeratedValue>
                                    <name>0010</name>
                                    <description>x 1/4</description>
                                    <value>#0010</value>
                                </enumeratedValue>
                                <enumeratedValue>
                                    <name>0011</name>
                                    <description>x 1/8</description>
                                    <value>#0011</value>
                                </enumeratedValue>
                                <enumeratedValue>
                                    <name>0100</name>
                                    <description>x 1/16</description>
                                    <value>#0100</value>
                                </enumeratedValue>
                                <enumeratedValue>
                                    <name>0101</name>
                                    <description>x 1/32</description>
                                    <value>#0101</value>
                                </enumeratedValue>
                                <enumeratedValue>
                                    <name>0110</name>
                                    <description>x 1/64</description>
                                    <value>#0110</value>
                                </enumeratedValue>
                                <enumeratedValue>
                                    <name>1000</name>
                                    <description>x 1/3</description>
                                    <value>#1000</value>
                                </enumeratedValue>
                                <enumeratedValue>
                                    <name>1001</name>
                                    <description>x 1/6</description>
                                    <value>#1001</value>
                                </enumeratedValue>
                                <enumeratedValue>
                                    <name>1010</name>
                                    <description>x 1/12</description>
                                    <value>#1010</value>
                                </enumeratedValue>
                                <enumeratedValue>
                                    <name>Others</name>
                                    <description>Setting prohibited.</description>
                                    <isDefault>true</isDefault>
                                </enumeratedValue>
                            </enumeratedValues>
                        </field>
                        <field>
                            <name>FCK</name>
                            <description>FlashIF Clock (FCLK) Select</description>
                            <lsb>28</lsb>
                            <msb>31</msb>
                            <access>read-write</access>
                            <enumeratedValues>
                                <enumeratedValue>
                                    <name>0000</name>
                                    <description>x 1/1</description>
                                    <value>#0000</value>
                                </enumeratedValue>
                                <enumeratedValue>
                                    <name>0001</name>
                                    <description>x 1/2</description>
                                    <value>#0001</value>
                                </enumeratedValue>
                                <enumeratedValue>
                                    <name>0010</name>
                                    <description>x 1/4</description>
                                    <value>#0010</value>
                                </enumeratedValue>
                                <enumeratedValue>
                                    <name>0011</name>
                                    <description>x 1/8</description>
                                    <value>#0011</value>
                                </enumeratedValue>
                                <enumeratedValue>
                                    <name>0100</name>
                                    <description>x 1/16</description>
                                    <value>#0100</value>
                                </enumeratedValue>
                                <enumeratedValue>
                                    <name>0101</name>
                                    <description>x 1/32</description>
                                    <value>#0101</value>
                                </enumeratedValue>
                                <enumeratedValue>
                                    <name>0110</name>
                                    <description>x 1/64</description>
                                    <value>#0110</value>
                                </enumeratedValue>
                                <enumeratedValue>
                                    <name>1000</name>
                                    <description>x 1/3</description>
                                    <value>#1000</value>
                                </enumeratedValue>
                                <enumeratedValue>
                                    <name>1001</name>
                                    <description>x 1/6</description>
                                    <value>#1001</value>
                                </enumeratedValue>
                                <enumeratedValue>
                                    <name>1010</name>
                                    <description>x 1/12</description>
                                    <value>#1010</value>
                                </enumeratedValue>
                                <enumeratedValue>
                                    <name>Others</name>
                                    <description>Setting prohibited.</description>
                                    <isDefault>true</isDefault>
                                </enumeratedValue>
                            </enumeratedValues>
                        </field>
                    </fields>
                </register>
                <register>
                    <name>SCKDIVCR2</name>
                    <description>System Clock Division Control Register 2</description>
                    <addressOffset>0x24</addressOffset>
                    <size>8</size>
                    <access>read-write</access>
                    <resetValue>0x00</resetValue>
                    <resetMask>0xff</resetMask>
                    <fields>
                        <field>
                            <name>CPUCK</name>
                            <description>CPU Clock (CPUCLK) Select</description>
                            <lsb>0</lsb>
                            <msb>3</msb>
                            <access>read-write</access>
                            <enumeratedValues>
                                <enumeratedValue>
                                    <name>0000</name>
                                    <description>x 1/1</description>
                                    <value>#0000</value>
                                </enumeratedValue>
                                <enumeratedValue>
                                    <name>0001</name>
                                    <description>x 1/2</description>
                                    <value>#0001</value>
                                </enumeratedValue>
                                <enumeratedValue>
                                    <name>0010</name>
                                    <description>x 1/4</description>
                                    <value>#0010</value>
                                </enumeratedValue>
                                <enumeratedValue>
                                    <name>0011</name>
                                    <description>x 1/8</description>
                                    <value>#0011</value>
                                </enumeratedValue>
                                <enumeratedValue>
                                    <name>0100</name>
                                    <description>x 1/16</description>
                                    <value>#0100</value>
                                </enumeratedValue>
                                <enumeratedValue>
                                    <name>0101</name>
                                    <description>x 1/32</description>
                                    <value>#0101</value>
                                </enumeratedValue>
                                <enumeratedValue>
                                    <name>0110</name>
                                    <description>x 1/64</description>
                                    <value>#0110</value>
                                </enumeratedValue>
                                <enumeratedValue>
                                    <name>1000</name>
                                    <description>x 1/3</description>
                                    <value>#1000</value>
                                </enumeratedValue>
                                <enumeratedValue>
                                    <name>1001</name>
                                    <description>x 1/6</description>
                                    <value>#1001</value>
                                </enumeratedValue>
                                <enumeratedValue>
                                    <name>1010</name>
                                    <description>x 1/12</description>
                                    <value>#1010</value>
                                </enumeratedValue>
                                <enumeratedValue>
                                    <name>Others</name>
                                    <description>Setting prohibited.</description>
                                    <isDefault>true</isDefault>
                                </enumeratedValue>
                            </enumeratedValues>
                        </field>
                    </fields>
                </register>
                <register>
                    <name>SCKSCR</name>
                    <description>System Clock Source Control Register</description>
                    <addressOffset>0x026</addressOffset>
                    <size>8</size>
                    <access>read-write</access>
                    <resetValue>0x01</resetValue>
                    <resetMask>0xff</resetMask>
                    <fields>
                        <field>
                            <name>CKSEL</name>
                            <description>Clock Source Select</description>
                            <lsb>0</lsb>
                            <msb>2</msb>
                            <access>read-write</access>
                            <enumeratedValues>
                                <enumeratedValue>
                                    <name>000</name>
                                    <description>HOCO</description>
                                    <value>#000</value>
                                </enumeratedValue>
                                <enumeratedValue>
                                    <name>001</name>
                                    <description>MOCO (Value after reset)</description>
                                    <value>#001</value>
                                </enumeratedValue>
                                <enumeratedValue>
                                    <name>010</name>
                                    <description>Setting prohibited</description>
                                    <value>#010</value>
                                </enumeratedValue>
                                <enumeratedValue>
                                    <name>011</name>
                                    <description>Main clock oscillator (MOSC)</description>
                                    <value>#011</value>
                                </enumeratedValue>
                                <enumeratedValue>
                                    <name>100</name>
                                    <description>Sub-clock oscillator (SOSC)</description>
                                    <value>#100</value>
                                </enumeratedValue>
                                <enumeratedValue>
                                    <name>101</name>
                                    <description>PLL1 output clock P (PLL1P)</description>
                                    <value>#101</value>
                                </enumeratedValue>
                                <enumeratedValue>
                                    <name>110</name>
                                    <description>Setting prohibited</description>
                                    <value>#110</value>
                                </enumeratedValue>
                                <enumeratedValue>
                                    <name>111</name>
                                    <description>Setting prohibited</description>
                                    <value>#111</value>
                                </enumeratedValue>
                            </enumeratedValues>
                        </field>
                    </fields>
                </register>
                <register>
                    <name>PLLCCR</name>
                    <description>PLL Clock Control Register</description>
                    <addressOffset>0x028</addressOffset>
                    <size>16</size>
                    <access>read-write</access>
                    <resetValue>0x1900</resetValue>
                    <resetMask>0xffff</resetMask>
                    <fields>
                        <field>
                            <name>PLIDIV</name>
                            <description>PLL1 Input Frequency Division Ratio Select</description>
                            <lsb>0</lsb>
                            <msb>1</msb>
                            <access>read-write</access>
                            <enumeratedValues>
                                <enumeratedValue>
                                    <name>00</name>
                                    <description>1/1</description>
                                    <value>#00</value>
                                </enumeratedValue>
                                <enumeratedValue>
                                    <name>01</name>
                                    <description>1/2</description>
                                    <value>#01</value>
                                </enumeratedValue>
                                <enumeratedValue>
                                    <name>10</name>
                                    <description>1/3</description>
                                    <value>#10</value>
                                </enumeratedValue>
                                <enumeratedValue>
                                    <name>11</name>
                                    <description>1/4</description>
                                    <value>#11</value>
                                </enumeratedValue>
                            </enumeratedValues>
                        </field>
                        <field>
                            <name>PLSRCSEL</name>
                            <description>PLL1 Clock Source Select</description>
                            <lsb>4</lsb>
                            <msb>4</msb>
                            <access>read-write</access>
                            <enumeratedValues>
                                <enumeratedValue>
                                    <name>0</name>
                                    <description>Main clock oscillator</description>
                                    <value>#0</value>
                                </enumeratedValue>
                                <enumeratedValue>
                                    <name>1</name>
                                    <description>HOCO</description>
                                    <value>#1</value>
                                </enumeratedValue>
                            </enumeratedValues>
                        </field>
                        <field>
                            <name>PLLMULNF</name>
                            <description>PLL1 Frequency Multiplication Fractional Factor Select</description>
                            <lsb>6</lsb>
                            <msb>7</msb>
                            <access>read-write</access>
                            <enumeratedValues>
                                <enumeratedValue>
                                    <name>00</name>
                                    <description>0.00 (Value after reset)</description>
                                    <value>#00</value>
                                </enumeratedValue>
                                <enumeratedValue>
                                    <name>01</name>
                                    <description>0.33 (1/3)</description>
                                    <value>#01</value>
                                </enumeratedValue>
                                <enumeratedValue>
                                    <name>10</name>
                                    <description>0.66 (2/3)</description>
                                    <value>#10</value>
                                </enumeratedValue>
                                <enumeratedValue>
                                    <name>11</name>
                                    <description>0.50 (1/2)</description>
                                    <value>#11</value>
                                </enumeratedValue>
                            </enumeratedValues>
                        </field>
                        <field>
                            <name>PLLMUL</name>
                            <description>PLL1 Frequency Multiplication Factor Select</description>
                            <lsb>8</lsb>
                            <msb>15</msb>
                            <access>read-write</access>
                            <writeConstraint>
                                <range>
                                    <minimum>0x13</minimum>
                                    <maximum>0x3B</maximum>
                                </range>
                            </writeConstraint>
                        </field>
                    </fields>
                </register>
                <register>
                    <name>PLLCR</name>
                    <description>PLL Control Register</description>
                    <addressOffset>0x02A</addressOffset>
                    <size>8</size>
                    <access>read-write</access>
                    <resetValue>0x01</resetValue>
                    <resetMask>0xff</resetMask>
                    <fields>
                        <field>
                            <name>PLLSTP</name>
                            <description>PLL1 Stop Control</description>
                            <lsb>0</lsb>
                            <msb>0</msb>
                            <access>read-write</access>
                            <enumeratedValues>
                                <enumeratedValue>
                                    <name>0</name>
                                    <description>PLL1 is operating</description>
                                    <value>#0</value>
                                </enumeratedValue>
                                <enumeratedValue>
                                    <name>1</name>
                                    <description>PLL1 is stopped</description>
                                    <value>#1</value>
                                </enumeratedValue>
                            </enumeratedValues>
                        </field>
                    </fields>
                </register>
                <register>
                    <name>BCKCR</name>
                    <description>External Bus Clock Control Register</description>
                    <addressOffset>0x030</addressOffset>
                    <size>8</size>
                    <access>read-write</access>
                    <resetValue>0x00</resetValue>
                    <resetMask>0xff</resetMask>
                    <fields>
                        <field>
                            <name>BCLKDIV</name>
                            <description>BCLK Pin Output Select</description>
                            <lsb>0</lsb>
                            <msb>0</msb>
                            <access>read-write</access>
                            <enumeratedValues>
                                <enumeratedValue>
                                    <name>0</name>
                                    <description>BCLK</description>
                                    <value>#0</value>
                                </enumeratedValue>
                                <enumeratedValue>
                                    <name>1</name>
                                    <description>BCLK/2</description>
                                    <value>#1</value>
                                </enumeratedValue>
                            </enumeratedValues>
                        </field>
                    </fields>
                </register>
                <register>
                    <name>MOSCCR</name>
                    <description>Main Clock Oscillator Control Register</description>
                    <addressOffset>0x032</addressOffset>
                    <size>8</size>
                    <access>read-write</access>
                    <resetValue>0x01</resetValue>
                    <resetMask>0xff</resetMask>
                    <fields>
                        <field>
                            <name>MOSTP</name>
                            <description>Main Clock Oscillator Stop</description>
                            <lsb>0</lsb>
                            <msb>0</msb>
                            <access>read-write</access>
                            <enumeratedValues>
                                <enumeratedValue>
                                    <name>0</name>
                                    <description>Operate the main clock oscillator</description>
                                    <value>#0</value>
                                </enumeratedValue>
                                <enumeratedValue>
                                    <name>1</name>
                                    <description>Stop the main clock oscillator</description>
                                    <value>#1</value>
                                </enumeratedValue>
                            </enumeratedValues>
                        </field>
                    </fields>
                </register>
                <register>
                    <name>HOCOCR</name>
                    <description>High-Speed On-Chip Oscillator Control Register</description>
                    <addressOffset>0x036</addressOffset>
                    <size>8</size>
                    <access>read-write</access>
                    <resetValue>0x00</resetValue>
                    <resetMask>0xfe</resetMask>
                    <fields>
                        <field>
                            <name>HCSTP</name>
                            <description>HOCO Stop</description>
                            <lsb>0</lsb>
                            <msb>0</msb>
                            <access>read-write</access>
                            <enumeratedValues>
                                <enumeratedValue>
                                    <name>0</name>
                                    <description>Operate the HOCO clock </description>
                                    <value>#0</value>
                                </enumeratedValue>
                                <enumeratedValue>
                                    <name>1</name>
                                    <description>Stop the HOCO clock</description>
                                    <value>#1</value>
                                </enumeratedValue>
                            </enumeratedValues>
                        </field>
                    </fields>
                </register>
                <register>
                    <name>HOCOCR2</name>
                    <description>High-Speed On-Chip Oscillator Control Register2</description>
                    <addressOffset>0x037</addressOffset>
                    <size>8</size>
                    <access>read-write</access>
                    <resetValue>0x00</resetValue>
                    <resetMask>0xf8</resetMask>
                    <fields>
                        <field>
                            <name>HCFRQ0</name>
                            <description>HOCO Frequency Setting 0</description>
                            <lsb>0</lsb>
                            <msb>2</msb>
                            <access>read-write</access>
                            <enumeratedValues>
                                <enumeratedValue>
                                    <name>000</name>
                                    <description>16MHz</description>
                                    <value>#000</value>
                                </enumeratedValue>
                                <enumeratedValue>
                                    <name>001</name>
                                    <description>18MHz</description>
                                    <value>#001</value>
                                </enumeratedValue>
                                <enumeratedValue>
                                    <name>010</name>
                                    <description>20MHz</description>
                                    <value>#010</value>
                                </enumeratedValue>
                                <enumeratedValue>
                                    <name>100</name>
                                    <description>32MHz</description>
                                    <value>#100</value>
                                </enumeratedValue>
                                <enumeratedValue>
                                    <name>111</name>
                                    <description>48MHz</description>
                                    <value>#111</value>
                                </enumeratedValue>
                            </enumeratedValues>
                        </field>
                    </fields>
                </register>
                <register>
                    <name>MOCOCR</name>
                    <description>Middle-Speed On-Chip Oscillator Control Register</description>
                    <addressOffset>0x038</addressOffset>
                    <size>8</size>
                    <access>read-write</access>
                    <resetValue>0x00</resetValue>
                    <resetMask>0xff</resetMask>
                    <fields>
                        <field>
                            <name>MCSTP</name>
                            <description>MOCO Stop</description>
                            <lsb>0</lsb>
                            <msb>0</msb>
                            <access>read-write</access>
                            <enumeratedValues>
                                <enumeratedValue>
                                    <name>0</name>
                                    <description>MOCO clock is operating</description>
                                    <value>#0</value>
                                </enumeratedValue>
                                <enumeratedValue>
                                    <name>1</name>
                                    <description>MOCO clock is stopped</description>
                                    <value>#1</value>
                                </enumeratedValue>
                            </enumeratedValues>
                        </field>
                    </fields>
                </register>
                <register>
                    <name>FLLCR1</name>
                    <description>FLL Control Register1</description>
                    <addressOffset>0x039</addressOffset>
                    <size>8</size>
                    <access>read-write</access>
                    <resetValue>0x00</resetValue>
                    <resetMask>0xff</resetMask>
                    <fields>
                        <field>
                            <name>FLLEN</name>
                            <description>FLL Enable</description>
                            <lsb>0</lsb>
                            <msb>0</msb>
                            <access>read-write</access>
                            <enumeratedValues>
                                <enumeratedValue>
                                    <name>0</name>
                                    <description>FLL function is disabled</description>
                                    <value>#0</value>
                                </enumeratedValue>
                                <enumeratedValue>
                                    <name>1</name>
                                    <description>FLL function is enabled.</description>
                                    <value>#1</value>
                                </enumeratedValue>
                            </enumeratedValues>
                        </field>
                    </fields>
                </register>
                <register>
                    <name>FLLCR2</name>
                    <description>FLL Control Register2</description>
                    <addressOffset>0x03A</addressOffset>
                    <size>16</size>
                    <access>read-write</access>
                    <resetValue>0x0000</resetValue>
                    <resetMask>0xffff</resetMask>
                    <fields>
                        <field>
                            <name>FLLCNTL</name>
                            <description>FLL Multiplication Control</description>
                            <lsb>0</lsb>
                            <msb>10</msb>
                            <access>read-write</access>
                        </field>
                    </fields>
                </register>
                <register>
                    <name>OSCSF</name>
                    <description>Oscillation Stabilization Flag Register</description>
                    <addressOffset>0x03C</addressOffset>
                    <size>8</size>
                    <access>read-only</access>
                    <resetValue>0x00</resetValue>
                    <resetMask>0xfe</resetMask>
                    <fields>
                        <field>
                            <name>HOCOSF</name>
                            <description>HOCO Clock Oscillation Stabilization Flag</description>
                            <lsb>0</lsb>
                            <msb>0</msb>
                            <access>read-only</access>
                            <enumeratedValues>
                                <enumeratedValue>
                                    <name>0</name>
                                    <description>The HOCO clock is stopped or is not yet stable</description>
                                    <value>#0</value>
                                </enumeratedValue>
                                <enumeratedValue>
                                    <name>1</name>
                                    <description>The HOCO clock is stable, so is available for use as the system clock source</description>
                                    <value>#1</value>
                                </enumeratedValue>
                            </enumeratedValues>
                        </field>
                        <field>
                            <name>MOSCSF</name>
                            <description>Main Clock Oscillation Stabilization Flag</description>
                            <lsb>3</lsb>
                            <msb>3</msb>
                            <access>read-only</access>
                            <enumeratedValues>
                                <enumeratedValue>
                                    <name>0</name>
                                    <description>The main clock oscillator is stopped or is not yet stable</description>
                                    <value>#0</value>
                                </enumeratedValue>
                                <enumeratedValue>
                                    <name>1</name>
                                    <description>The main clock oscillator is stable, so is available for use as the system clock source</description>
                                    <value>#1</value>
                                </enumeratedValue>
                            </enumeratedValues>
                        </field>
                        <field>
                            <name>PLLSF</name>
                            <description>PLL1 Clock Oscillation Stabilization Flag</description>
                            <lsb>5</lsb>
                            <msb>5</msb>
                            <access>read-only</access>
                            <enumeratedValues>
                                <enumeratedValue>
                                    <name>0</name>
                                    <description>The PLL1 clock is stopped or is not yet stable.</description>
                                    <value>#0</value>
                                </enumeratedValue>
                                <enumeratedValue>
                                    <name>1</name>
                                    <description>The PLL1 clock is stable, so is available for use as the system clock source</description>
                                    <value>#1</value>
                                </enumeratedValue>
                            </enumeratedValues>
                        </field>
                        <field>
                            <name>PLL2SF</name>
                            <description>PLL2 Clock Oscillation Stabilization Flag</description>
                            <lsb>6</lsb>
                            <msb>6</msb>
                            <access>read-only</access>
                            <enumeratedValues>
                                <enumeratedValue>
                                    <name>0</name>
                                    <description>The PLL2 clock is stopped or is not yet stable.</description>
                                    <value>#0</value>
                                </enumeratedValue>
                                <enumeratedValue>
                                    <name>1</name>
                                    <description>The PLL2 clock is stable</description>
                                    <value>#1</value>
                                </enumeratedValue>
                            </enumeratedValues>
                        </field>
                    </fields>
                </register>
                <register>
                    <name>CKOCR</name>
                    <description>Clock Out Control Register</description>
                    <addressOffset>0x03E</addressOffset>
                    <size>8</size>
                    <access>read-write</access>
                    <resetValue>0x01</resetValue>
                    <resetMask>0xff</resetMask>
                    <fields>
                        <field>
                            <name>CKOSEL</name>
                            <description>Clock Out Source Select</description>
                            <lsb>0</lsb>
                            <msb>2</msb>
                            <access>read-write</access>
                            <enumeratedValues>
                                <enumeratedValue>
                                    <name>000</name>
                                    <description>HOCO</description>
                                    <value>#000</value>
                                </enumeratedValue>
                                <enumeratedValue>
                                    <name>001</name>
                                    <description>MOCO (Value after reset)</description>
                                    <value>#001</value>
                                </enumeratedValue>
                                <enumeratedValue>
                                    <name>010</name>
                                    <description>LOCO</description>
                                    <value>#010</value>
                                </enumeratedValue>
                                <enumeratedValue>
                                    <name>011</name>
                                    <description>MOSC</description>
                                    <value>#011</value>
                                </enumeratedValue>
                                <enumeratedValue>
                                    <name>100</name>
                                    <description>SOSC</description>
                                    <value>#100</value>
                                </enumeratedValue>
                                <enumeratedValue>
                                    <name>Others</name>
                                    <description>Setting prohibited</description>
                                    <isDefault>true</isDefault>
                                </enumeratedValue>
                            </enumeratedValues>
                        </field>
                        <field>
                            <name>CKODIV</name>
                            <description>Clock Output Frequency Division Ratio</description>
                            <lsb>4</lsb>
                            <msb>6</msb>
                            <access>read-write</access>
                            <enumeratedValues>
                                <enumeratedValue>
                                    <name>000</name>
                                    <description>x 1/1</description>
                                    <value>#000</value>
                                </enumeratedValue>
                                <enumeratedValue>
                                    <name>001</name>
                                    <description>x 1/2</description>
                                    <value>#001</value>
                                </enumeratedValue>
                                <enumeratedValue>
                                    <name>010</name>
                                    <description>x 1/4</description>
                                    <value>#010</value>
                                </enumeratedValue>
                                <enumeratedValue>
                                    <name>011</name>
                                    <description>x 1/8</description>
                                    <value>#011</value>
                                </enumeratedValue>
                                <enumeratedValue>
                                    <name>100</name>
                                    <description>x 1/16</description>
                                    <value>#100</value>
                                </enumeratedValue>
                                <enumeratedValue>
                                    <name>101</name>
                                    <description>x 1/32</description>
                                    <value>#101</value>
                                </enumeratedValue>
                                <enumeratedValue>
                                    <name>110</name>
                                    <description>x 1/64</description>
                                    <value>#110</value>
                                </enumeratedValue>
                                <enumeratedValue>
                                    <name>111</name>
                                    <description>x 1/128</description>
                                    <value>#111</value>
                                </enumeratedValue>
                            </enumeratedValues>
                        </field>
                        <field>
                            <name>CKOEN</name>
                            <description>Clock Out Enable</description>
                            <lsb>7</lsb>
                            <msb>7</msb>
                            <access>read-write</access>
                            <enumeratedValues>
                                <enumeratedValue>
                                    <name>0</name>
                                    <description>Disable clock out</description>
                                    <value>#0</value>
                                </enumeratedValue>
                                <enumeratedValue>
                                    <name>1</name>
                                    <description>Enable clock out</description>
                                    <value>#1</value>
                                </enumeratedValue>
                            </enumeratedValues>
                        </field>
                    </fields>
                </register>
                <register>
                    <name>TRCKCR</name>
                    <description>Trace Clock Control Register</description>
                    <addressOffset>0x03F</addressOffset>
                    <size>8</size>
                    <access>read-write</access>
                    <resetValue>0x02</resetValue>
                    <resetMask>0xff</resetMask>
                    <fields>
                        <field>
                            <name>TRCK</name>
                            <description>Trace Clock operating frequency select</description>
                            <lsb>0</lsb>
                            <msb>3</msb>
                            <access>read-write</access>
                            <enumeratedValues>
                                <enumeratedValue>
                                    <name>0000</name>
                                    <description>1/1</description>
                                    <value>#0000</value>
                                </enumeratedValue>
                                <enumeratedValue>
                                    <name>0001</name>
                                    <description>1/2</description>
                                    <value>#0001</value>
                                </enumeratedValue>
                                <enumeratedValue>
                                    <name>0010</name>
                                    <description>1/4 (Value after reset)</description>
                                    <value>#0010</value>
                                </enumeratedValue>
                                <enumeratedValue>
                                    <name>0011</name>
                                    <description>1/8</description>
                                    <value>#0011</value>
                                </enumeratedValue>
                                <enumeratedValue>
                                    <name>0100</name>
                                    <description>1/16</description>
                                    <value>#0100</value>
                                </enumeratedValue>
                                <enumeratedValue>
                                    <name>0101</name>
                                    <description>1/32</description>
                                    <value>#0101</value>
                                </enumeratedValue>
                                <enumeratedValue>
                                    <name>0110</name>
                                    <description>1/64</description>
                                    <value>#0110</value>
                                </enumeratedValue>
                                <enumeratedValue>
                                    <name>0111</name>
                                    <description>1/128</description>
                                    <value>#0111</value>
                                </enumeratedValue>
                                <enumeratedValue>
                                    <name>1000</name>
                                    <description>1/256</description>
                                    <value>#1000</value>
                                </enumeratedValue>
                                <enumeratedValue>
                                    <name>1001</name>
                                    <description>1/3</description>
                                    <value>#1001</value>
                                </enumeratedValue>
                                <enumeratedValue>
                                    <name>1010</name>
                                    <description>1/6</description>
                                    <value>#1010</value>
                                </enumeratedValue>
                                <enumeratedValue>
                                    <name>1011</name>
                                    <description>1/12</description>
                                    <value>#1011</value>
                                </enumeratedValue>
                                <enumeratedValue>
                                    <name>Others</name>
                                    <description>Setting prohibited</description>
                                    <isDefault>true</isDefault>
                                </enumeratedValue>
                            </enumeratedValues>
                        </field>
                        <field>
                            <name>TRCKSEL</name>
                            <description>Trace Clock source select</description>
                            <lsb>4</lsb>
                            <msb>4</msb>
                            <access>read-write</access>
                            <enumeratedValues>
                                <enumeratedValue>
                                    <name>0</name>
                                    <description>System clock source (Value after reset) </description>
                                    <value>#0</value>
                                </enumeratedValue>
                                <enumeratedValue>
                                    <name>1</name>
                                    <description>HOCO (oscillation in debug mode)</description>
                                    <value>#1</value>
                                </enumeratedValue>
                            </enumeratedValues>
                        </field>
                        <field>
                            <name>TRCKEN</name>
                            <description>Trace Clock operating Enable</description>
                            <lsb>7</lsb>
                            <msb>7</msb>
                            <access>read-write</access>
                            <enumeratedValues>
                                <enumeratedValue>
                                    <name>0</name>
                                    <description>Stop</description>
                                    <value>#0</value>
                                </enumeratedValue>
                                <enumeratedValue>
                                    <name>1</name>
                                    <description>Operation enable</description>
                                    <value>#1</value>
                                </enumeratedValue>
                            </enumeratedValues>
                        </field>
                    </fields>
                </register>
                <register>
                    <name>OSTDCR</name>
                    <description>Oscillation Stop Detection Control Register</description>
                    <addressOffset>0x040</addressOffset>
                    <size>8</size>
                    <access>read-write</access>
                    <resetValue>0x00</resetValue>
                    <resetMask>0xff</resetMask>
                    <fields>
                        <field>
                            <name>OSTDIE</name>
                            <description>Oscillation Stop Detection Interrupt Enable</description>
                            <lsb>0</lsb>
                            <msb>0</msb>
                            <access>read-write</access>
                            <enumeratedValues>
                                <enumeratedValue>
                                    <name>0</name>
                                    <description>Disable oscillation stop detection interrupt (do not notify the POEG)</description>
                                    <value>#0</value>
                                </enumeratedValue>
                                <enumeratedValue>
                                    <name>1</name>
                                    <description>Enable oscillation stop detection interrupt (notify the POEG)</description>
                                    <value>#1</value>
                                </enumeratedValue>
                            </enumeratedValues>
                        </field>
                        <field>
                            <name>OSTDE</name>
                            <description>Oscillation Stop Detection Function Enable</description>
                            <lsb>7</lsb>
                            <msb>7</msb>
                            <access>read-write</access>
                            <enumeratedValues>
                                <enumeratedValue>
                                    <name>0</name>
                                    <description>Disable oscillation stop detection function</description>
                                    <value>#0</value>
                                </enumeratedValue>
                                <enumeratedValue>
                                    <name>1</name>
                                    <description>Enable oscillation stop detection function</description>
                                    <value>#1</value>
                                </enumeratedValue>
                            </enumeratedValues>
                        </field>
                    </fields>
                </register>
                <register>
                    <name>OSTDSR</name>
                    <description>Oscillation Stop Detection Status Register</description>
                    <addressOffset>0x041</addressOffset>
                    <size>8</size>
                    <access>read-write</access>
                    <resetValue>0x00</resetValue>
                    <resetMask>0xff</resetMask>
                    <fields>
                        <field>
                            <name>OSTDF</name>
                            <description>Oscillation Stop Detection Flag</description>
                            <lsb>0</lsb>
                            <msb>0</msb>
                            <access>read-write</access>
                            <enumeratedValues>
                                <enumeratedValue>
                                    <name>0</name>
                                    <description>Main clock oscillation stop not detected</description>
                                    <value>#0</value>
                                </enumeratedValue>
                                <enumeratedValue>
                                    <name>1</name>
                                    <description>Main clock oscillation stop detected</description>
                                    <value>#1</value>
                                </enumeratedValue>
                            </enumeratedValues>
                        </field>
                    </fields>
                </register>
                <register>
                    <name>OSCMONR</name>
                    <description>Oscillator Monitor Register</description>
                    <addressOffset>0x43</addressOffset>
                    <size>8</size>
                    <access>read-write</access>
                    <resetValue>0x00</resetValue>
                    <resetMask>0xff</resetMask>
                    <fields>
                        <field>
                            <name>MOCOMON</name>
                            <description>MOCO operation monitor</description>
                            <lsb>1</lsb>
                            <msb>1</msb>
                            <access>read-only</access>
                            <enumeratedValues>
                                <enumeratedValue>
                                    <name>0</name>
                                    <description>MOCO is set to operate.</description>
                                    <value>#0</value>
                                </enumeratedValue>
                                <enumeratedValue>
                                    <name>1</name>
                                    <description>MOCO is set to stop.</description>
                                    <value>#1</value>
                                </enumeratedValue>
                            </enumeratedValues>
                        </field>
                        <field>
                            <name>LOCOMON</name>
                            <description>LOCO operation monitor</description>
                            <lsb>2</lsb>
                            <msb>2</msb>
                            <access>read-only</access>
                            <enumeratedValues>
                                <enumeratedValue>
                                    <name>0</name>
                                    <description>LOCO is set to operate.</description>
                                    <value>#0</value>
                                </enumeratedValue>
                                <enumeratedValue>
                                    <name>1</name>
                                    <description>LOCO is set to stop.</description>
                                    <value>#1</value>
                                </enumeratedValue>
                            </enumeratedValues>
                        </field>
                    </fields>
                </register>
                <register>
                    <name>PLL2CCR</name>
                    <description>PLL2 Clock Control Register</description>
                    <addressOffset>0x048</addressOffset>
                    <size>16</size>
                    <access>read-write</access>
                    <resetValue>0x1900</resetValue>
                    <resetMask>0xffff</resetMask>
                    <fields>
                        <field>
                            <name>PL2IDIV</name>
                            <description>PLL2 Input Frequency Division Ratio Select</description>
                            <lsb>0</lsb>
                            <msb>1</msb>
                            <access>read-write</access>
                            <enumeratedValues>
                                <enumeratedValue>
                                    <name>00</name>
                                    <description>1/1 (Value after reset)</description>
                                    <value>#00</value>
                                </enumeratedValue>
                                <enumeratedValue>
                                    <name>01</name>
                                    <description>1/2</description>
                                    <value>#01</value>
                                </enumeratedValue>
                                <enumeratedValue>
                                    <name>10</name>
                                    <description>1/3</description>
                                    <value>#10</value>
                                </enumeratedValue>
                                <enumeratedValue>
                                    <name>11</name>
                                    <description>1/4</description>
                                    <value>#11</value>
                                </enumeratedValue>
                            </enumeratedValues>
                        </field>
                        <field>
                            <name>PL2SRCSEL</name>
                            <description>PLL2 Clock Source Select</description>
                            <lsb>4</lsb>
                            <msb>4</msb>
                            <access>read-write</access>
                            <enumeratedValues>
                                <enumeratedValue>
                                    <name>0</name>
                                    <description>Main clock oscillator</description>
                                    <value>#0</value>
                                </enumeratedValue>
                                <enumeratedValue>
                                    <name>1</name>
                                    <description>HOCO</description>
                                    <value>#1</value>
                                </enumeratedValue>
                            </enumeratedValues>
                        </field>
                        <field>
                            <name>PLL2MULNF</name>
                            <description>PLL2 Frequency Multiplication Fractional Factor Select</description>
                            <lsb>6</lsb>
                            <msb>7</msb>
                            <access>read-write</access>
                            <enumeratedValues>
                                <enumeratedValue>
                                    <name>00</name>
                                    <description>0.00 (Value after reset)</description>
                                    <value>#00</value>
                                </enumeratedValue>
                                <enumeratedValue>
                                    <name>01</name>
                                    <description>0.33 (1/3)</description>
                                    <value>#01</value>
                                </enumeratedValue>
                                <enumeratedValue>
                                    <name>10</name>
                                    <description>0.66 (2/3)</description>
                                    <value>#10</value>
                                </enumeratedValue>
                                <enumeratedValue>
                                    <name>11</name>
                                    <description>0.50 (1/2)</description>
                                    <value>#11</value>
                                </enumeratedValue>
                            </enumeratedValues>
                        </field>
                        <field>
                            <name>PLL2MUL</name>
                            <description>PLL2 Frequency Multiplication Factor Select</description>
                            <lsb>8</lsb>
                            <msb>15</msb>
                            <access>read-write</access>
                        </field>
                    </fields>
                </register>
                <register>
                    <name>PLL2CR</name>
                    <description>PLL2 Control Register</description>
                    <addressOffset>0x04A</addressOffset>
                    <size>8</size>
                    <access>read-write</access>
                    <resetValue>0x01</resetValue>
                    <resetMask>0xff</resetMask>
                    <fields>
                        <field>
                            <name>PLL2STP</name>
                            <description>PLL2 Stop Control</description>
                            <lsb>0</lsb>
                            <msb>0</msb>
                            <access>read-write</access>
                            <enumeratedValues>
                                <enumeratedValue>
                                    <name>0</name>
                                    <description>PLL2 is operating</description>
                                    <value>#0</value>
                                </enumeratedValue>
                                <enumeratedValue>
                                    <name>1</name>
                                    <description>PLL2 is stopped</description>
                                    <value>#1</value>
                                </enumeratedValue>
                            </enumeratedValues>
                        </field>
                    </fields>
                </register>
                <register>
                    <name>PLLCCR2</name>
                    <description>PLL Clock Control Register 2</description>
                    <addressOffset>0x4C</addressOffset>
                    <size>16</size>
                    <access>read-write</access>
                    <resetValue>0x0555</resetValue>
                    <resetMask>0xffff</resetMask>
                    <fields>
                        <field>
                            <name>PLODIVP</name>
                            <description>PLL1 Output Frequency Division Ratio Select for output clock P</description>
                            <lsb>0</lsb>
                            <msb>3</msb>
                            <access>read-write</access>
                            <enumeratedValues>
                                <enumeratedValue>
                                    <name>0001</name>
                                    <description>× 1/2</description>
                                    <value>#0001</value>
                                </enumeratedValue>
                                <enumeratedValue>
                                    <name>0011</name>
                                    <description>× 1/4</description>
                                    <value>#0011</value>
                                </enumeratedValue>
                                <enumeratedValue>
                                    <name>0101</name>
                                    <description>× 1/6 (Value after reset)</description>
                                    <value>#0101</value>
                                </enumeratedValue>
                                <enumeratedValue>
                                    <name>0111</name>
                                    <description>× 1/8</description>
                                    <value>#0111</value>
                                </enumeratedValue>
                                <enumeratedValue>
                                    <name>1111</name>
                                    <description>× 1/16</description>
                                    <value>#1111</value>
                                </enumeratedValue>
                                <enumeratedValue>
                                    <name>Others</name>
                                    <description>Setting prohibited.</description>
                                    <isDefault>true</isDefault>
                                </enumeratedValue>
                            </enumeratedValues>
                        </field>
                        <field>
                            <name>PLODIVQ</name>
                            <description>PLL1 Output Frequency Division Ratio Select for output clock Q</description>
                            <lsb>4</lsb>
                            <msb>7</msb>
                            <access>read-write</access>
                            <enumeratedValues>
                                <enumeratedValue>
                                    <name>0001</name>
                                    <description>× 1/2</description>
                                    <value>#0001</value>
                                </enumeratedValue>
                                <enumeratedValue>
                                    <name>0010</name>
                                    <description>× 1/3</description>
                                    <value>#0010</value>
                                </enumeratedValue>
                                <enumeratedValue>
                                    <name>0011</name>
                                    <description>× 1/4</description>
                                    <value>#0011</value>
                                </enumeratedValue>
                                <enumeratedValue>
                                    <name>0100</name>
                                    <description>× 1/5</description>
                                    <value>#0100</value>
                                </enumeratedValue>
                                <enumeratedValue>
                                    <name>0101</name>
                                    <description>× 1/6 (Value after reset)</description>
                                    <value>#0101</value>
                                </enumeratedValue>
                                <enumeratedValue>
                                    <name>0111</name>
                                    <description>× 1/8</description>
                                    <value>#0111</value>
                                </enumeratedValue>
                                <enumeratedValue>
                                    <name>1000</name>
                                    <description>× 1/9</description>
                                    <value>#1000</value>
                                </enumeratedValue>
                                <enumeratedValue>
                                    <name>Others</name>
                                    <description>Setting prohibited.</description>
                                    <isDefault>true</isDefault>
                                </enumeratedValue>
                            </enumeratedValues>
                        </field>
                        <field>
                            <name>PLODIVR</name>
                            <description>PLL1 Output Frequency Division Ratio Select for output clock R</description>
                            <lsb>8</lsb>
                            <msb>11</msb>
                            <access>read-write</access>
                            <enumeratedValues>
                                <enumeratedValue>
                                    <name>0001</name>
                                    <description>× 1/2</description>
                                    <value>#0001</value>
                                </enumeratedValue>
                                <enumeratedValue>
                                    <name>0010</name>
                                    <description>× 1/3</description>
                                    <value>#0010</value>
                                </enumeratedValue>
                                <enumeratedValue>
                                    <name>0011</name>
                                    <description>× 1/4</description>
                                    <value>#0011</value>
                                </enumeratedValue>
                                <enumeratedValue>
                                    <name>0100</name>
                                    <description>× 1/5</description>
                                    <value>#0100</value>
                                </enumeratedValue>
                                <enumeratedValue>
                                    <name>0101</name>
                                    <description>× 1/6 (Value after reset)</description>
                                    <value>#0101</value>
                                </enumeratedValue>
                                <enumeratedValue>
                                    <name>0111</name>
                                    <description>× 1/8</description>
                                    <value>#0111</value>
                                </enumeratedValue>
                                <enumeratedValue>
                                    <name>1000</name>
                                    <description>× 1/9</description>
                                    <value>#1000</value>
                                </enumeratedValue>
                                <enumeratedValue>
                                    <name>Others</name>
                                    <description>Setting prohibited.</description>
                                    <isDefault>true</isDefault>
                                </enumeratedValue>
                            </enumeratedValues>
                        </field>
                    </fields>
                </register>
                <register>
                    <name>PLL2CCR2</name>
                    <description>PLL2 Clock Control Register 2</description>
                    <addressOffset>0x4E</addressOffset>
                    <size>16</size>
                    <access>read-write</access>
                    <resetValue>0x0555</resetValue>
                    <resetMask>0xffff</resetMask>
                    <fields>
                        <field>
                            <name>PL2ODIVP</name>
                            <description>PLL2 Output Frequency Division Ratio Select for output clock P</description>
                            <lsb>0</lsb>
                            <msb>3</msb>
                            <access>read-write</access>
                            <enumeratedValues>
                                <enumeratedValue>
                                    <name>0001</name>
                                    <description>× 1/2</description>
                                    <value>#0001</value>
                                </enumeratedValue>
                                <enumeratedValue>
                                    <name>0011</name>
                                    <description>× 1/4</description>
                                    <value>#0011</value>
                                </enumeratedValue>
                                <enumeratedValue>
                                    <name>0101</name>
                                    <description>× 1/6 (Value after reset)</description>
                                    <value>#0101</value>
                                </enumeratedValue>
                                <enumeratedValue>
                                    <name>0111</name>
                                    <description>× 1/8</description>
                                    <value>#0111</value>
                                </enumeratedValue>
                                <enumeratedValue>
                                    <name>1111</name>
                                    <description>× 1/16</description>
                                    <value>#1111</value>
                                </enumeratedValue>
                                <enumeratedValue>
                                    <name>Others</name>
                                    <description>Setting prohibited.</description>
                                    <isDefault>true</isDefault>
                                </enumeratedValue>
                            </enumeratedValues>
                        </field>
                        <field>
                            <name>PL2ODIVQ</name>
                            <description>PLL2 Output Frequency Division Ratio Select for output clock Q</description>
                            <lsb>4</lsb>
                            <msb>7</msb>
                            <access>read-write</access>
                            <enumeratedValues>
                                <enumeratedValue>
                                    <name>0001</name>
                                    <description>× 1/2</description>
                                    <value>#0001</value>
                                </enumeratedValue>
                                <enumeratedValue>
                                    <name>0010</name>
                                    <description>× 1/3</description>
                                    <value>#0010</value>
                                </enumeratedValue>
                                <enumeratedValue>
                                    <name>0011</name>
                                    <description>× 1/4</description>
                                    <value>#0011</value>
                                </enumeratedValue>
                                <enumeratedValue>
                                    <name>0100</name>
                                    <description>× 1/5</description>
                                    <value>#0100</value>
                                </enumeratedValue>
                                <enumeratedValue>
                                    <name>0101</name>
                                    <description>× 1/6 (Value after reset)</description>
                                    <value>#0101</value>
                                </enumeratedValue>
                                <enumeratedValue>
                                    <name>0111</name>
                                    <description>× 1/8</description>
                                    <value>#0111</value>
                                </enumeratedValue>
                                <enumeratedValue>
                                    <name>1000</name>
                                    <description>× 1/9</description>
                                    <value>#1000</value>
                                </enumeratedValue>
                                <enumeratedValue>
                                    <name>Others</name>
                                    <description>Setting prohibited.</description>
                                    <isDefault>true</isDefault>
                                </enumeratedValue>
                            </enumeratedValues>
                        </field>
                        <field>
                            <name>PL2ODIVR</name>
                            <description>PLL2 Output Frequency Division Ratio Select for output clock R</description>
                            <lsb>8</lsb>
                            <msb>11</msb>
                            <access>read-write</access>
                            <enumeratedValues>
                                <enumeratedValue>
                                    <name>0001</name>
                                    <description>× 1/2</description>
                                    <value>#0001</value>
                                </enumeratedValue>
                                <enumeratedValue>
                                    <name>0010</name>
                                    <description>× 1/3</description>
                                    <value>#0010</value>
                                </enumeratedValue>
                                <enumeratedValue>
                                    <name>0011</name>
                                    <description>× 1/4</description>
                                    <value>#0011</value>
                                </enumeratedValue>
                                <enumeratedValue>
                                    <name>0100</name>
                                    <description>× 1/5</description>
                                    <value>#0100</value>
                                </enumeratedValue>
                                <enumeratedValue>
                                    <name>0101</name>
                                    <description>× 1/6 (Value after reset)</description>
                                    <value>#0101</value>
                                </enumeratedValue>
                                <enumeratedValue>
                                    <name>0111</name>
                                    <description>× 1/8</description>
                                    <value>#0111</value>
                                </enumeratedValue>
                                <enumeratedValue>
                                    <name>1000</name>
                                    <description>× 1/9</description>
                                    <value>#1000</value>
                                </enumeratedValue>
                                <enumeratedValue>
                                    <name>Others</name>
                                    <description>Setting prohibited.</description>
                                    <isDefault>true</isDefault>
                                </enumeratedValue>
                            </enumeratedValues>
                        </field>
                    </fields>
                </register>
                <register>
                    <name>EBCKOCR</name>
                    <description>External Bus Clock Output Control Register</description>
                    <addressOffset>0x052</addressOffset>
                    <size>8</size>
                    <access>read-write</access>
                    <resetValue>0x00</resetValue>
                    <resetMask>0xff</resetMask>
                    <fields>
                        <field>
                            <name>EBCKOEN</name>
                            <description>EBCLK Pin Output Control</description>
                            <lsb>0</lsb>
                            <msb>0</msb>
                            <access>read-write</access>
                            <enumeratedValues>
                                <enumeratedValue>
                                    <name>0</name>
                                    <description>EBCLK pin output is disabled (fixed high)</description>
                                    <value>#0</value>
                                </enumeratedValue>
                                <enumeratedValue>
                                    <name>1</name>
                                    <description>EBCLK pin output is enabled.</description>
                                    <value>#1</value>
                                </enumeratedValue>
                            </enumeratedValues>
                        </field>
                    </fields>
                </register>
                <register>
                    <name>SDCKOCR</name>
                    <description>SDRAM Clock Output Control Register</description>
                    <addressOffset>0x053</addressOffset>
                    <size>8</size>
                    <access>read-write</access>
                    <resetValue>0x00</resetValue>
                    <resetMask>0xff</resetMask>
                    <fields>
                        <field>
                            <name>SDCKOEN</name>
                            <description>SDCLK Pin Output Control</description>
                            <lsb>0</lsb>
                            <msb>0</msb>
                            <access>read-write</access>
                            <enumeratedValues>
                                <enumeratedValue>
                                    <name>0</name>
                                    <description>SDCLK pin output is disabled. (Fixed high)</description>
                                    <value>#0</value>
                                </enumeratedValue>
                                <enumeratedValue>
                                    <name>1</name>
                                    <description>SDCLK pin output is enabled.</description>
                                    <value>#1</value>
                                </enumeratedValue>
                            </enumeratedValues>
                        </field>
                    </fields>
                </register>
                <register>
                    <name>SCICKDIVCR</name>
                    <description>SCI clock Division control register</description>
                    <addressOffset>0x054</addressOffset>
                    <size>8</size>
                    <access>read-write</access>
                    <resetValue>0x00</resetValue>
                    <resetMask>0xff</resetMask>
                    <fields>
                        <field>
                            <name>SCICKDIV</name>
                            <description>SCI clock (SCICLK) Division Select</description>
                            <lsb>0</lsb>
                            <msb>2</msb>
                            <access>read-write</access>
                            <enumeratedValues>
                                <enumeratedValue>
                                    <name>000</name>
                                    <description>1/1 (Value after reset)</description>
                                    <value>#000</value>
                                </enumeratedValue>
                                <enumeratedValue>
                                    <name>001</name>
                                    <description>1/2</description>
                                    <value>#001</value>
                                </enumeratedValue>
                                <enumeratedValue>
                                    <name>010</name>
                                    <description>1/4</description>
                                    <value>#010</value>
                                </enumeratedValue>
                                <enumeratedValue>
                                    <name>011</name>
                                    <description>1/6</description>
                                    <value>#011</value>
                                </enumeratedValue>
                                <enumeratedValue>
                                    <name>100</name>
                                    <description>1/8</description>
                                    <value>#100</value>
                                </enumeratedValue>
                                <enumeratedValue>
                                    <name>101</name>
                                    <description>1/3</description>
                                    <value>#101</value>
                                </enumeratedValue>
                                <enumeratedValue>
                                    <name>110</name>
                                    <description>1/5</description>
                                    <value>#110</value>
                                </enumeratedValue>
                                <enumeratedValue>
                                    <name>Others</name>
                                    <description>Setting prohibited.</description>
                                    <isDefault>true</isDefault>
                                </enumeratedValue>
                            </enumeratedValues>
                        </field>
                    </fields>
                </register>
                <register>
                    <name>SCICKCR</name>
                    <description>SCI clock control register</description>
                    <addressOffset>0x055</addressOffset>
                    <size>8</size>
                    <access>read-write</access>
                    <resetValue>0x01</resetValue>
                    <resetMask>0xff</resetMask>
                    <fields>
                        <field>
                            <name>SCICKSEL</name>
                            <description>SCI clock (SCICLK) Source Select</description>
                            <lsb>0</lsb>
                            <msb>3</msb>
                            <access>read-write</access>
                            <enumeratedValues>
                                <enumeratedValue>
                                    <name>0000</name>
                                    <description>HOCO</description>
                                    <value>#0000</value>
                                </enumeratedValue>
                                <enumeratedValue>
                                    <name>0001</name>
                                    <description>MOCO (Value after reset)</description>
                                    <value>#0001</value>
                                </enumeratedValue>
                                <enumeratedValue>
                                    <name>0010</name>
                                    <description>LOCO</description>
                                    <value>#0010</value>
                                </enumeratedValue>
                                <enumeratedValue>
                                    <name>0011</name>
                                    <description>Main clock oscillator</description>
                                    <value>#0011</value>
                                </enumeratedValue>
                                <enumeratedValue>
                                    <name>0100</name>
                                    <description>Sub-clock oscillator</description>
                                    <value>#0100</value>
                                </enumeratedValue>
                                <enumeratedValue>
                                    <name>0101</name>
                                    <description>PLL1P</description>
                                    <value>#0101</value>
                                </enumeratedValue>
                                <enumeratedValue>
                                    <name>0110</name>
                                    <description>PLL2P</description>
                                    <value>#0110</value>
                                </enumeratedValue>
                                <enumeratedValue>
                                    <name>0111</name>
                                    <description>PLL1Q</description>
                                    <value>#0111</value>
                                </enumeratedValue>
                                <enumeratedValue>
                                    <name>1000</name>
                                    <description>PLL1R</description>
                                    <value>#1000</value>
                                </enumeratedValue>
                                <enumeratedValue>
                                    <name>1001</name>
                                    <description>PLL2Q</description>
                                    <value>#1001</value>
                                </enumeratedValue>
                                <enumeratedValue>
                                    <name>1010</name>
                                    <description>PLL2R</description>
                                    <value>#1010</value>
                                </enumeratedValue>
                                <enumeratedValue>
                                    <name>Others</name>
                                    <description>Setting prohibited.</description>
                                    <isDefault>true</isDefault>
                                </enumeratedValue>
                            </enumeratedValues>
                        </field>
                        <field>
                            <name>SCICKSREQ</name>
                            <description>SCI clock (SCICLK) Switching Request</description>
                            <lsb>6</lsb>
                            <msb>6</msb>
                            <access>read-write</access>
                            <enumeratedValues>
                                <enumeratedValue>
                                    <name>0</name>
                                    <description>No request</description>
                                    <value>#0</value>
                                </enumeratedValue>
                                <enumeratedValue>
                                    <name>1</name>
                                    <description>Request switching</description>
                                    <value>#1</value>
                                </enumeratedValue>
                            </enumeratedValues>
                        </field>
                        <field>
                            <name>SCICKSRDY</name>
                            <description>SCI clock (SCICLK) Switching Ready state flag</description>
                            <lsb>7</lsb>
                            <msb>7</msb>
                            <access>read-only</access>
                            <enumeratedValues>
                                <enumeratedValue>
                                    <name>0</name>
                                    <description>Impossible to Switch</description>
                                    <value>#0</value>
                                </enumeratedValue>
                                <enumeratedValue>
                                    <name>1</name>
                                    <description>Possible to Switch</description>
                                    <value>#1</value>
                                </enumeratedValue>
                            </enumeratedValues>
                        </field>
                    </fields>
                </register>
                <register>
                    <name>SPICKDIVCR</name>
                    <description>SPI clock Division control register</description>
                    <addressOffset>0x056</addressOffset>
                    <size>8</size>
                    <access>read-write</access>
                    <resetValue>0x00</resetValue>
                    <resetMask>0xff</resetMask>
                    <fields>
                        <field>
                            <name>SPICKDIV</name>
                            <description>SPI clock (SPICLK) Division Select</description>
                            <lsb>0</lsb>
                            <msb>2</msb>
                            <access>read-write</access>
                            <enumeratedValues>
                                <enumeratedValue>
                                    <name>000</name>
                                    <description>1/1 (Value after reset)</description>
                                    <value>#000</value>
                                </enumeratedValue>
                                <enumeratedValue>
                                    <name>001</name>
                                    <description>1/2</description>
                                    <value>#001</value>
                                </enumeratedValue>
                                <enumeratedValue>
                                    <name>010</name>
                                    <description>1/4</description>
                                    <value>#010</value>
                                </enumeratedValue>
                                <enumeratedValue>
                                    <name>011</name>
                                    <description>1/6</description>
                                    <value>#011</value>
                                </enumeratedValue>
                                <enumeratedValue>
                                    <name>100</name>
                                    <description>1/8</description>
                                    <value>#100</value>
                                </enumeratedValue>
                                <enumeratedValue>
                                    <name>101</name>
                                    <description>1/3</description>
                                    <value>#101</value>
                                </enumeratedValue>
                                <enumeratedValue>
                                    <name>110</name>
                                    <description>1/5</description>
                                    <value>#110</value>
                                </enumeratedValue>
                                <enumeratedValue>
                                    <name>Others</name>
                                    <description>Setting prohibited.</description>
                                    <isDefault>true</isDefault>
                                </enumeratedValue>
                            </enumeratedValues>
                        </field>
                    </fields>
                </register>
                <register>
                    <name>SPICKCR</name>
                    <description>SPI clock control register</description>
                    <addressOffset>0x057</addressOffset>
                    <size>8</size>
                    <access>read-write</access>
                    <resetValue>0x00</resetValue>
                    <resetMask>0xff</resetMask>
                    <fields>
                        <field>
                            <name>SPICKSEL</name>
                            <description>SPI clock (SPICLK) Source Select</description>
                            <lsb>0</lsb>
                            <msb>3</msb>
                            <access>read-write</access>
                            <enumeratedValues>
                                <enumeratedValue>
                                    <name>0000</name>
                                    <description>HOCO</description>
                                    <value>#0000</value>
                                </enumeratedValue>
                                <enumeratedValue>
                                    <name>0001</name>
                                    <description>MOCO (Value after reset)</description>
                                    <value>#0001</value>
                                </enumeratedValue>
                                <enumeratedValue>
                                    <name>0010</name>
                                    <description>LOCO</description>
                                    <value>#0010</value>
                                </enumeratedValue>
                                <enumeratedValue>
                                    <name>0011</name>
                                    <description>Main clock oscillator</description>
                                    <value>#0011</value>
                                </enumeratedValue>
                                <enumeratedValue>
                                    <name>0100</name>
                                    <description>Sub-clock oscillator</description>
                                    <value>#0100</value>
                                </enumeratedValue>
                                <enumeratedValue>
                                    <name>0101</name>
                                    <description>PLL1P</description>
                                    <value>#0101</value>
                                </enumeratedValue>
                                <enumeratedValue>
                                    <name>0110</name>
                                    <description>PLL2P</description>
                                    <value>#0110</value>
                                </enumeratedValue>
                                <enumeratedValue>
                                    <name>0111</name>
                                    <description>PLL1Q</description>
                                    <value>#0111</value>
                                </enumeratedValue>
                                <enumeratedValue>
                                    <name>1000</name>
                                    <description>PLL1R</description>
                                    <value>#1000</value>
                                </enumeratedValue>
                                <enumeratedValue>
                                    <name>1001</name>
                                    <description>PLL2Q</description>
                                    <value>#1001</value>
                                </enumeratedValue>
                                <enumeratedValue>
                                    <name>1010</name>
                                    <description>PLL2R</description>
                                    <value>#1010</value>
                                </enumeratedValue>
                                <enumeratedValue>
                                    <name>Others</name>
                                    <description>Setting prohibited.</description>
                                    <isDefault>true</isDefault>
                                </enumeratedValue>
                            </enumeratedValues>
                        </field>
                        <field>
                            <name>SPICKSREQ</name>
                            <description>SPI clock (SPICLK) Switching Request</description>
                            <lsb>6</lsb>
                            <msb>6</msb>
                            <access>read-write</access>
                            <enumeratedValues>
                                <enumeratedValue>
                                    <name>0</name>
                                    <description>No request</description>
                                    <value>#0</value>
                                </enumeratedValue>
                                <enumeratedValue>
                                    <name>1</name>
                                    <description>Request switching</description>
                                    <value>#1</value>
                                </enumeratedValue>
                            </enumeratedValues>
                        </field>
                        <field>
                            <name>SPICKSRDY</name>
                            <description>SPI clock (SPICLK) Switching Ready state flag</description>
                            <lsb>7</lsb>
                            <msb>7</msb>
                            <access>read-only</access>
                            <enumeratedValues>
                                <enumeratedValue>
                                    <name>0</name>
                                    <description>Impossible to Switch</description>
                                    <value>#0</value>
                                </enumeratedValue>
                                <enumeratedValue>
                                    <name>1</name>
                                    <description>Possible to Switch</description>
                                    <value>#1</value>
                                </enumeratedValue>
                            </enumeratedValues>
                        </field>
                    </fields>
                </register>
                <register>
                    <name>LCDCKDIVCR</name>
                    <description>LCD clock Division control register</description>
                    <addressOffset>0x05E</addressOffset>
                    <size>8</size>
                    <access>read-write</access>
                    <resetValue>0x00</resetValue>
                    <resetMask>0xff</resetMask>
                    <fields>
                        <field>
                            <name>LCDCKDIV</name>
                            <description>LCD clock (LCDCLK) Division Select</description>
                            <lsb>0</lsb>
                            <msb>2</msb>
                            <access>read-write</access>
                            <enumeratedValues>
                                <enumeratedValue>
                                    <name>000</name>
                                    <description>1/1</description>
                                    <value>#000</value>
                                </enumeratedValue>
                                <enumeratedValue>
                                    <name>001</name>
                                    <description>1/2</description>
                                    <value>#001</value>
                                </enumeratedValue>
                                <enumeratedValue>
                                    <name>010</name>
                                    <description>1/4</description>
                                    <value>#010</value>
                                </enumeratedValue>
                                <enumeratedValue>
                                    <name>011</name>
                                    <description>1/6</description>
                                    <value>#011</value>
                                </enumeratedValue>
                                <enumeratedValue>
                                    <name>100</name>
                                    <description>1/8</description>
                                    <value>#100</value>
                                </enumeratedValue>
                                <enumeratedValue>
                                    <name>101</name>
                                    <description>1/3</description>
                                    <value>#101</value>
                                </enumeratedValue>
                                <enumeratedValue>
                                    <name>110</name>
                                    <description>1/5</description>
                                    <value>#110</value>
                                </enumeratedValue>
                                <enumeratedValue>
                                    <name>Others</name>
                                    <description>Setting prohibited.</description>
                                    <isDefault>true</isDefault>
                                </enumeratedValue>
                            </enumeratedValues>
                        </field>
                    </fields>
                </register>
                <register>
                    <name>LCDCKCR</name>
                    <description>LCD clock control register</description>
                    <addressOffset>0x05F</addressOffset>
                    <size>8</size>
                    <access>read-write</access>
                    <resetValue>0x01</resetValue>
                    <resetMask>0xff</resetMask>
                    <fields>
                        <field>
                            <name>LCDCKSEL</name>
                            <description>LCD clock (LCDCLK) Source Select</description>
                            <lsb>0</lsb>
                            <msb>3</msb>
                            <access>read-write</access>
                            <enumeratedValues>
                                <enumeratedValue>
                                    <name>0001</name>
                                    <description>MOCO (Value after reset)</description>
                                    <value>#0001</value>
                                </enumeratedValue>
                                <enumeratedValue>
                                    <name>0101</name>
                                    <description>PLL1P</description>
                                    <value>#0101</value>
                                </enumeratedValue>
                                <enumeratedValue>
                                    <name>0110</name>
                                    <description>PLL2P</description>
                                    <value>#0110</value>
                                </enumeratedValue>
                                <enumeratedValue>
                                    <name>0111</name>
                                    <description>PLL1Q</description>
                                    <value>#0111</value>
                                </enumeratedValue>
                                <enumeratedValue>
                                    <name>1000</name>
                                    <description>PLL1R</description>
                                    <value>#1000</value>
                                </enumeratedValue>
                                <enumeratedValue>
                                    <name>1001</name>
                                    <description>PLL2Q</description>
                                    <value>#1001</value>
                                </enumeratedValue>
                                <enumeratedValue>
                                    <name>1010</name>
                                    <description>PLL2R</description>
                                    <value>#1010</value>
                                </enumeratedValue>
                                <enumeratedValue>
                                    <name>Others</name>
                                    <description>Setting prohibited.</description>
                                    <isDefault>true</isDefault>
                                </enumeratedValue>
                            </enumeratedValues>
                        </field>
                        <field>
                            <name>LCDCKSREQ</name>
                            <description>LCD clock (LCDCLK) Switching Request</description>
                            <lsb>6</lsb>
                            <msb>6</msb>
                            <access>read-write</access>
                            <enumeratedValues>
                                <enumeratedValue>
                                    <name>0</name>
                                    <description>No request</description>
                                    <value>#0</value>
                                </enumeratedValue>
                                <enumeratedValue>
                                    <name>1</name>
                                    <description>Request switching</description>
                                    <value>#1</value>
                                </enumeratedValue>
                            </enumeratedValues>
                        </field>
                        <field>
                            <name>LCDCKSRDY</name>
                            <description>LCD clock (LCDCLK) Switching Ready state flag</description>
                            <lsb>7</lsb>
                            <msb>7</msb>
                            <access>read-only</access>
                            <enumeratedValues>
                                <enumeratedValue>
                                    <name>0</name>
                                    <description>Impossible to Switch</description>
                                    <value>#0</value>
                                </enumeratedValue>
                                <enumeratedValue>
                                    <name>1</name>
                                    <description>Possible to Switch</description>
                                    <value>#1</value>
                                </enumeratedValue>
                            </enumeratedValues>
                        </field>
                    </fields>
                </register>
                <register>
                    <name>MOCOUTCR</name>
                    <description>MOCO User Trimming Control Register</description>
                    <addressOffset>0x061</addressOffset>
                    <size>8</size>
                    <access>read-write</access>
                    <resetValue>0x00</resetValue>
                    <resetMask>0xff</resetMask>
                    <fields>
                        <field>
                            <name>MOCOUTRM</name>
                            <description>MOCO User Trimming</description>
                            <lsb>0</lsb>
                            <msb>7</msb>
                            <access>read-write</access>
                        </field>
                    </fields>
                </register>
                <register>
                    <name>HOCOUTCR</name>
                    <description>HOCO User Trimming Control Register</description>
                    <addressOffset>0x062</addressOffset>
                    <size>8</size>
                    <access>read-write</access>
                    <resetValue>0x00</resetValue>
                    <resetMask>0xff</resetMask>
                    <fields>
                        <field>
                            <name>HOCOUTRM</name>
                            <description>HOCO User Trimming</description>
                            <lsb>0</lsb>
                            <msb>7</msb>
                            <access>read-write</access>
                        </field>
                    </fields>
                </register>
                <register>
                    <name>USBCKDIVCR</name>
                    <description>USB Clock Division Control Register</description>
                    <addressOffset>0x06C</addressOffset>
                    <size>8</size>
                    <access>read-write</access>
                    <resetValue>0x00</resetValue>
                    <resetMask>0xff</resetMask>
                    <fields>
                        <field>
                            <name>USBCKDIV</name>
                            <description>USB Clock (USBCLK) Division Select</description>
                            <lsb>0</lsb>
                            <msb>2</msb>
                            <access>read-write</access>
                            <enumeratedValues>
                                <enumeratedValue>
                                    <name>000</name>
                                    <description>1/1</description>
                                    <value>#000</value>
                                </enumeratedValue>
                                <enumeratedValue>
                                    <name>001</name>
                                    <description>1/2</description>
                                    <value>#001</value>
                                </enumeratedValue>
                                <enumeratedValue>
                                    <name>010</name>
                                    <description>1/4</description>
                                    <value>#010</value>
                                </enumeratedValue>
                                <enumeratedValue>
                                    <name>011</name>
                                    <description>1/6</description>
                                    <value>#011</value>
                                </enumeratedValue>
                                <enumeratedValue>
                                    <name>100</name>
                                    <description>1/8</description>
                                    <value>#100</value>
                                </enumeratedValue>
                                <enumeratedValue>
                                    <name>101</name>
                                    <description>1/3</description>
                                    <value>#101</value>
                                </enumeratedValue>
                                <enumeratedValue>
                                    <name>110</name>
                                    <description>1/5</description>
                                    <value>#110</value>
                                </enumeratedValue>
                                <enumeratedValue>
                                    <name>Others</name>
                                    <description>Setting prohibited.</description>
                                    <isDefault>true</isDefault>
                                </enumeratedValue>
                            </enumeratedValues>
                        </field>
                    </fields>
                </register>
                <register>
                    <name>OCTACKDIVCR</name>
                    <description>Octal-SPI Clock Division Control Register</description>
                    <addressOffset>0x06D</addressOffset>
                    <size>8</size>
                    <access>read-write</access>
                    <resetValue>0x00</resetValue>
                    <resetMask>0xff</resetMask>
                    <fields>
                        <field>
                            <name>OCTACKDIV</name>
                            <description>Octal-SPI Clock (OCTACLK) Division Select</description>
                            <lsb>0</lsb>
                            <msb>2</msb>
                            <access>read-write</access>
                            <enumeratedValues>
                                <enumeratedValue>
                                    <name>000</name>
                                    <description>1/1 (Value after reset)</description>
                                    <value>#000</value>
                                </enumeratedValue>
                                <enumeratedValue>
                                    <name>001</name>
                                    <description>1/2</description>
                                    <value>#001</value>
                                </enumeratedValue>
                                <enumeratedValue>
                                    <name>010</name>
                                    <description>1/4</description>
                                    <value>#010</value>
                                </enumeratedValue>
                                <enumeratedValue>
                                    <name>011</name>
                                    <description>1/6</description>
                                    <value>#011</value>
                                </enumeratedValue>
                                <enumeratedValue>
                                    <name>100</name>
                                    <description>1/8</description>
                                    <value>#100</value>
                                </enumeratedValue>
                                <enumeratedValue>
                                    <name>101</name>
                                    <description>1/3</description>
                                    <value>#101</value>
                                </enumeratedValue>
                                <enumeratedValue>
                                    <name>110</name>
                                    <description>1/5</description>
                                    <value>#110</value>
                                </enumeratedValue>
                                <enumeratedValue>
                                    <name>Others</name>
                                    <description>Setting prohibited.</description>
                                    <isDefault>true</isDefault>
                                </enumeratedValue>
                            </enumeratedValues>
                        </field>
                    </fields>
                </register>
                <register>
                    <name>CANFDCKDIVCR</name>
                    <description>CANFD Core Clock Division Control Register</description>
                    <addressOffset>0x06E</addressOffset>
                    <size>8</size>
                    <access>read-write</access>
                    <resetValue>0x00</resetValue>
                    <resetMask>0xff</resetMask>
                    <fields>
                        <field>
                            <name>CANFDCKDIV</name>
                            <description>CANFD core clock (CANFDCLK) Division Select</description>
                            <lsb>0</lsb>
                            <msb>2</msb>
                            <access>read-write</access>
                            <enumeratedValues>
                                <enumeratedValue>
                                    <name>000</name>
                                    <description>1/1 (Value after reset)</description>
                                    <value>#000</value>
                                </enumeratedValue>
                                <enumeratedValue>
                                    <name>001</name>
                                    <description>1/2</description>
                                    <value>#001</value>
                                </enumeratedValue>
                                <enumeratedValue>
                                    <name>010</name>
                                    <description>1/4</description>
                                    <value>#010</value>
                                </enumeratedValue>
                                <enumeratedValue>
                                    <name>011</name>
                                    <description>1/6</description>
                                    <value>#011</value>
                                </enumeratedValue>
                                <enumeratedValue>
                                    <name>100</name>
                                    <description>1/8</description>
                                    <value>#100</value>
                                </enumeratedValue>
                                <enumeratedValue>
                                    <name>101</name>
                                    <description>1/3</description>
                                    <value>#101</value>
                                </enumeratedValue>
                                <enumeratedValue>
                                    <name>110</name>
                                    <description>1/5</description>
                                    <value>#110</value>
                                </enumeratedValue>
                                <enumeratedValue>
                                    <name>Others</name>
                                    <description>Setting prohibited</description>
                                    <isDefault>true</isDefault>
                                </enumeratedValue>
                            </enumeratedValues>
                        </field>
                    </fields>
                </register>
                <register>
                    <name>USB60CKDIVCR</name>
                    <description>USB60 clock Division control register</description>
                    <addressOffset>0x06F</addressOffset>
                    <size>8</size>
                    <access>read-write</access>
                    <resetValue>0x00</resetValue>
                    <resetMask>0xff</resetMask>
                    <fields>
                        <field>
                            <name>USB60CKDIV</name>
                            <description>USB clock (USB60CLK) Division Select</description>
                            <lsb>0</lsb>
                            <msb>2</msb>
                            <access>read-write</access>
                            <enumeratedValues>
                                <enumeratedValue>
                                    <name>000</name>
                                    <description>1/1(Value after reset)</description>
                                    <value>#000</value>
                                </enumeratedValue>
                                <enumeratedValue>
                                    <name>001</name>
                                    <description>1/2</description>
                                    <value>#001</value>
                                </enumeratedValue>
                                <enumeratedValue>
                                    <name>010</name>
                                    <description>1/4</description>
                                    <value>#010</value>
                                </enumeratedValue>
                                <enumeratedValue>
                                    <name>011</name>
                                    <description>1/6</description>
                                    <value>#011</value>
                                </enumeratedValue>
                                <enumeratedValue>
                                    <name>100</name>
                                    <description>1/8</description>
                                    <value>#100</value>
                                </enumeratedValue>
                                <enumeratedValue>
                                    <name>101</name>
                                    <description>1/3</description>
                                    <value>#101</value>
                                </enumeratedValue>
                                <enumeratedValue>
                                    <name>110</name>
                                    <description>1/5</description>
                                    <value>#110</value>
                                </enumeratedValue>
                                <enumeratedValue>
                                    <name>Others</name>
                                    <description>Setting prohibited.</description>
                                    <isDefault>true</isDefault>
                                </enumeratedValue>
                            </enumeratedValues>
                        </field>
                    </fields>
                </register>
                <register>
                    <name>I3CCKDIVCR</name>
                    <description>I3C clock Division control register</description>
                    <addressOffset>0x070</addressOffset>
                    <size>8</size>
                    <access>read-write</access>
                    <resetValue>0x00</resetValue>
                    <resetMask>0xff</resetMask>
                    <fields>
                        <field>
                            <name>I3CCKDIV</name>
                            <description>I3C clock (I3CCLK) Division Select</description>
                            <lsb>0</lsb>
                            <msb>2</msb>
                            <access>read-write</access>
                            <enumeratedValues>
                                <enumeratedValue>
                                    <name>000</name>
                                    <description>1/1 (Value after reset)</description>
                                    <value>#000</value>
                                </enumeratedValue>
                                <enumeratedValue>
                                    <name>001</name>
                                    <description>1/2</description>
                                    <value>#001</value>
                                </enumeratedValue>
                                <enumeratedValue>
                                    <name>010</name>
                                    <description>1/4</description>
                                    <value>#010</value>
                                </enumeratedValue>
                                <enumeratedValue>
                                    <name>011</name>
                                    <description>1/6</description>
                                    <value>#011</value>
                                </enumeratedValue>
                                <enumeratedValue>
                                    <name>100</name>
                                    <description>1/8</description>
                                    <value>#100</value>
                                </enumeratedValue>
                                <enumeratedValue>
                                    <name>101</name>
                                    <description>1/3</description>
                                    <value>#101</value>
                                </enumeratedValue>
                                <enumeratedValue>
                                    <name>110</name>
                                    <description>1/5</description>
                                    <value>#110</value>
                                </enumeratedValue>
                                <enumeratedValue>
                                    <name>Others</name>
                                    <description>Setting prohibited.</description>
                                    <isDefault>true</isDefault>
                                </enumeratedValue>
                            </enumeratedValues>
                        </field>
                    </fields>
                </register>
                <register>
                    <name>USBCKCR</name>
                    <description>USB Clock Control Register</description>
                    <addressOffset>0x074</addressOffset>
                    <size>8</size>
                    <access>read-write</access>
                    <resetValue>0x01</resetValue>
                    <resetMask>0xff</resetMask>
                    <fields>
                        <field>
                            <name>USBCKSEL</name>
                            <description>USB Clock (USBCLK) Source Select</description>
                            <lsb>0</lsb>
                            <msb>3</msb>
                            <access>read-write</access>
                            <enumeratedValues>
                                <enumeratedValue>
                                    <name>0000</name>
                                    <description>HOCO</description>
                                    <value>#0000</value>
                                </enumeratedValue>
                                <enumeratedValue>
                                    <name>0001</name>
                                    <description>MOCO (Value after reset)</description>
                                    <value>#0001</value>
                                </enumeratedValue>
                                <enumeratedValue>
                                    <name>0011</name>
                                    <description>Main clock oscillator</description>
                                    <value>#0011</value>
                                </enumeratedValue>
                                <enumeratedValue>
                                    <name>0101</name>
                                    <description>PLL1P</description>
                                    <value>#0101</value>
                                </enumeratedValue>
                                <enumeratedValue>
                                    <name>0110</name>
                                    <description>PLL2P</description>
                                    <value>#0110</value>
                                </enumeratedValue>
                                <enumeratedValue>
                                    <name>0111</name>
                                    <description>PLL1Q</description>
                                    <value>#0111</value>
                                </enumeratedValue>
                                <enumeratedValue>
                                    <name>1000</name>
                                    <description>PLL1R</description>
                                    <value>#1000</value>
                                </enumeratedValue>
                                <enumeratedValue>
                                    <name>1001</name>
                                    <description>PLL2Q</description>
                                    <value>#1001</value>
                                </enumeratedValue>
                                <enumeratedValue>
                                    <name>1010</name>
                                    <description>PLL2R</description>
                                    <value>#1010</value>
                                </enumeratedValue>
                                <enumeratedValue>
                                    <name>Others</name>
                                    <description>Setting prohibited.</description>
                                    <isDefault>true</isDefault>
                                </enumeratedValue>
                            </enumeratedValues>
                        </field>
                        <field>
                            <name>USBCKSREQ</name>
                            <description>USB Clock (USBCLK) Switching Request</description>
                            <lsb>6</lsb>
                            <msb>6</msb>
                            <access>read-write</access>
                            <enumeratedValues>
                                <enumeratedValue>
                                    <name>0</name>
                                    <description>No request</description>
                                    <value>#0</value>
                                </enumeratedValue>
                                <enumeratedValue>
                                    <name>1</name>
                                    <description>Request switching.</description>
                                    <value>#1</value>
                                </enumeratedValue>
                            </enumeratedValues>
                        </field>
                        <field>
                            <name>USBCKSRDY</name>
                            <description>USB Clock (USBCLK) Switching Ready state flag</description>
                            <lsb>7</lsb>
                            <msb>7</msb>
                            <access>read-only</access>
                            <enumeratedValues>
                                <enumeratedValue>
                                    <name>0</name>
                                    <description>Impossible to Switch</description>
                                    <value>#0</value>
                                </enumeratedValue>
                                <enumeratedValue>
                                    <name>1</name>
                                    <description>Possible to Switch</description>
                                    <value>#1</value>
                                </enumeratedValue>
                            </enumeratedValues>
                        </field>
                    </fields>
                </register>
                <register>
                    <name>OCTACKCR</name>
                    <description>Octal-SPI Clock Control Register</description>
                    <addressOffset>0x075</addressOffset>
                    <size>8</size>
                    <access>read-write</access>
                    <resetValue>0x01</resetValue>
                    <resetMask>0xff</resetMask>
                    <fields>
                        <field>
                            <name>OCTACKSEL</name>
                            <description>Octal-SPI Clock (OCTACLK) Source Select</description>
                            <lsb>0</lsb>
                            <msb>3</msb>
                            <access>read-write</access>
                            <enumeratedValues>
                                <enumeratedValue>
                                    <name>0000</name>
                                    <description>HOCO</description>
                                    <value>#0000</value>
                                </enumeratedValue>
                                <enumeratedValue>
                                    <name>0001</name>
                                    <description>MOCO (Value after reset)</description>
                                    <value>#0001</value>
                                </enumeratedValue>
                                <enumeratedValue>
                                    <name>0010</name>
                                    <description>LOCO</description>
                                    <value>#0010</value>
                                </enumeratedValue>
                                <enumeratedValue>
                                    <name>0011</name>
                                    <description>Main clock oscillator</description>
                                    <value>#0011</value>
                                </enumeratedValue>
                                <enumeratedValue>
                                    <name>0100</name>
                                    <description>Sub-clock oscillator</description>
                                    <value>#0100</value>
                                </enumeratedValue>
                                <enumeratedValue>
                                    <name>0101</name>
                                    <description>PLL1P</description>
                                    <value>#0101</value>
                                </enumeratedValue>
                                <enumeratedValue>
                                    <name>0110</name>
                                    <description>PLL2P</description>
                                    <value>#0110</value>
                                </enumeratedValue>
                                <enumeratedValue>
                                    <name>0111</name>
                                    <description>PLL1Q</description>
                                    <value>#0111</value>
                                </enumeratedValue>
                                <enumeratedValue>
                                    <name>1000</name>
                                    <description>PLL1R</description>
                                    <value>#1000</value>
                                </enumeratedValue>
                                <enumeratedValue>
                                    <name>1001</name>
                                    <description>PLL2Q</description>
                                    <value>#1001</value>
                                </enumeratedValue>
                                <enumeratedValue>
                                    <name>1010</name>
                                    <description>PLL2R</description>
                                    <value>#1010</value>
                                </enumeratedValue>
                                <enumeratedValue>
                                    <name>Others</name>
                                    <description>Setting prohibited.</description>
                                    <isDefault>true</isDefault>
                                </enumeratedValue>
                            </enumeratedValues>
                        </field>
                        <field>
                            <name>OCTACKSREQ</name>
                            <description>Octal-SPI Clock (OCTACLK) Switching Request</description>
                            <lsb>6</lsb>
                            <msb>6</msb>
                            <access>read-write</access>
                            <enumeratedValues>
                                <enumeratedValue>
                                    <name>0</name>
                                    <description>No request</description>
                                    <value>#0</value>
                                </enumeratedValue>
                                <enumeratedValue>
                                    <name>1</name>
                                    <description>Request switching.</description>
                                    <value>#1</value>
                                </enumeratedValue>
                            </enumeratedValues>
                        </field>
                        <field>
                            <name>OCTACKSRDY</name>
                            <description>Octal-SPI Clock (OCTACLK) Switching Ready state flag</description>
                            <lsb>7</lsb>
                            <msb>7</msb>
                            <access>read-only</access>
                            <enumeratedValues>
                                <enumeratedValue>
                                    <name>0</name>
                                    <description>Impossible to Switch</description>
                                    <value>#0</value>
                                </enumeratedValue>
                                <enumeratedValue>
                                    <name>1</name>
                                    <description>Possible to Switch</description>
                                    <value>#1</value>
                                </enumeratedValue>
                            </enumeratedValues>
                        </field>
                    </fields>
                </register>
                <register>
                    <name>CANFDCKCR</name>
                    <description>CANFD Core Clock Control Register</description>
                    <addressOffset>0x076</addressOffset>
                    <size>8</size>
                    <access>read-write</access>
                    <resetValue>0x01</resetValue>
                    <resetMask>0xff</resetMask>
                    <fields>
                        <field>
                            <name>CANFDCKSEL</name>
                            <description>CANFD Core Clock (CANFDCLK) Source Select</description>
                            <lsb>0</lsb>
                            <msb>3</msb>
                            <access>read-write</access>
                            <enumeratedValues>
                                <enumeratedValue>
                                    <name>0000</name>
                                    <description>HOCO</description>
                                    <value>#0000</value>
                                </enumeratedValue>
                                <enumeratedValue>
                                    <name>0001</name>
                                    <description>MOCO (Value after reset)</description>
                                    <value>#0001</value>
                                </enumeratedValue>
                                <enumeratedValue>
                                    <name>0010</name>
                                    <description>LOCO</description>
                                    <value>#0010</value>
                                </enumeratedValue>
                                <enumeratedValue>
                                    <name>0011</name>
                                    <description>Main clock oscillator</description>
                                    <value>#0011</value>
                                </enumeratedValue>
                                <enumeratedValue>
                                    <name>0100</name>
                                    <description>Sub-clock oscillator</description>
                                    <value>#0100</value>
                                </enumeratedValue>
                                <enumeratedValue>
                                    <name>0101</name>
                                    <description>PLL1P</description>
                                    <value>#0101</value>
                                </enumeratedValue>
                                <enumeratedValue>
                                    <name>0110</name>
                                    <description>PLL2P</description>
                                    <value>#0110</value>
                                </enumeratedValue>
                                <enumeratedValue>
                                    <name>0111</name>
                                    <description>PLL1Q</description>
                                    <value>#0111</value>
                                </enumeratedValue>
                                <enumeratedValue>
                                    <name>1000</name>
                                    <description>PLL1R</description>
                                    <value>#1000</value>
                                </enumeratedValue>
                                <enumeratedValue>
                                    <name>1001</name>
                                    <description>PLL2Q</description>
                                    <value>#1001</value>
                                </enumeratedValue>
                                <enumeratedValue>
                                    <name>1010</name>
                                    <description>PLL2R</description>
                                    <value>#1010</value>
                                </enumeratedValue>
                                <enumeratedValue>
                                    <name>Others</name>
                                    <description>Setting prohibited.</description>
                                    <isDefault>true</isDefault>
                                </enumeratedValue>
                            </enumeratedValues>
                        </field>
                        <field>
                            <name>CANFDCKSREQ</name>
                            <description>CANFD Core Clock (CANFDCLK) Switching Request</description>
                            <lsb>6</lsb>
                            <msb>6</msb>
                            <access>read-write</access>
                            <enumeratedValues>
                                <enumeratedValue>
                                    <name>0</name>
                                    <description>No request</description>
                                    <value>#0</value>
                                </enumeratedValue>
                                <enumeratedValue>
                                    <name>1</name>
                                    <description>Request switching</description>
                                    <value>#1</value>
                                </enumeratedValue>
                            </enumeratedValues>
                        </field>
                    </fields>
                </register>
                <register>
                    <name>USB60CKCR</name>
                    <description>USB60 Clock Control Register</description>
                    <addressOffset>0x077</addressOffset>
                    <size>8</size>
                    <access>read-write</access>
                    <resetValue>0x01</resetValue>
                    <resetMask>0xff</resetMask>
                    <fields>
                        <field>
                            <name>USB60CKSEL</name>
                            <description>USB60 Clock (USB60CK) Source Select</description>
                            <lsb>0</lsb>
                            <msb>3</msb>
                            <access>read-write</access>
                            <enumeratedValues>
                                <enumeratedValue>
                                    <name>0000</name>
                                    <description>HOCO</description>
                                    <value>#0000</value>
                                </enumeratedValue>
                                <enumeratedValue>
                                    <name>0001</name>
                                    <description>MOCO (Value after reset)</description>
                                    <value>#0001</value>
                                </enumeratedValue>
                                <enumeratedValue>
                                    <name>0011</name>
                                    <description>Main clock oscillator</description>
                                    <value>#0011</value>
                                </enumeratedValue>
                                <enumeratedValue>
                                    <name>0101</name>
                                    <description>PLL1P</description>
                                    <value>#0101</value>
                                </enumeratedValue>
                                <enumeratedValue>
                                    <name>0110</name>
                                    <description>PLL2P</description>
                                    <value>#0110</value>
                                </enumeratedValue>
                                <enumeratedValue>
                                    <name>0111</name>
                                    <description>PLL1Q</description>
                                    <value>#0111</value>
                                </enumeratedValue>
                                <enumeratedValue>
                                    <name>1000</name>
                                    <description>PLL1R</description>
                                    <value>#1000</value>
                                </enumeratedValue>
                                <enumeratedValue>
                                    <name>1001</name>
                                    <description>PLL2Q</description>
                                    <value>#1001</value>
                                </enumeratedValue>
                                <enumeratedValue>
                                    <name>1010</name>
                                    <description>PLL2R</description>
                                    <value>#1010</value>
                                </enumeratedValue>
                                <enumeratedValue>
                                    <name>Others</name>
                                    <description>Setting prohibited.</description>
                                    <isDefault>true</isDefault>
                                </enumeratedValue>
                            </enumeratedValues>
                        </field>
                        <field>
                            <name>USB60CKSREQ</name>
                            <description>USB60 Clock (USB60CK) Switching Request</description>
                            <lsb>6</lsb>
                            <msb>6</msb>
                            <access>read-write</access>
                            <enumeratedValues>
                                <enumeratedValue>
                                    <name>0</name>
                                    <description>No request</description>
                                    <value>#0</value>
                                </enumeratedValue>
                                <enumeratedValue>
                                    <name>1</name>
                                    <description>Request switching</description>
                                    <value>#1</value>
                                </enumeratedValue>
                            </enumeratedValues>
                        </field>
                    </fields>
                </register>
                <register>
                    <name>I3CCKCR</name>
                    <description>I3C clock control register</description>
                    <addressOffset>0x078</addressOffset>
                    <size>8</size>
                    <access>read-write</access>
                    <resetValue>0x01</resetValue>
                    <resetMask>0xff</resetMask>
                    <fields>
                        <field>
                            <name>I3CCKSEL</name>
                            <description>I3C clock (I3CCLK) Source Select</description>
                            <lsb>0</lsb>
                            <msb>3</msb>
                            <access>read-write</access>
                            <enumeratedValues>
                                <enumeratedValue>
                                    <name>0001</name>
                                    <description>MOCO (Value after reset)</description>
                                    <value>#0001</value>
                                </enumeratedValue>
                                <enumeratedValue>
                                    <name>0101</name>
                                    <description>PLL1P</description>
                                    <value>#0101</value>
                                </enumeratedValue>
                                <enumeratedValue>
                                    <name>0110</name>
                                    <description>PLL2P</description>
                                    <value>#0110</value>
                                </enumeratedValue>
                                <enumeratedValue>
                                    <name>0111</name>
                                    <description>PLL1Q</description>
                                    <value>#0111</value>
                                </enumeratedValue>
                                <enumeratedValue>
                                    <name>1000</name>
                                    <description>PLL1R</description>
                                    <value>#1000</value>
                                </enumeratedValue>
                                <enumeratedValue>
                                    <name>1001</name>
                                    <description>PLL2Q</description>
                                    <value>#1001</value>
                                </enumeratedValue>
                                <enumeratedValue>
                                    <name>1010</name>
                                    <description>PLL2R</description>
                                    <value>#1010</value>
                                </enumeratedValue>
                            </enumeratedValues>
                        </field>
                        <field>
                            <name>I3CCKSREQ</name>
                            <description>I3C clock (I3CCLK) Switching Request</description>
                            <lsb>6</lsb>
                            <msb>6</msb>
                            <access>read-write</access>
                            <enumeratedValues>
                                <enumeratedValue>
                                    <name>0</name>
                                    <description>No request</description>
                                    <value>#0</value>
                                </enumeratedValue>
                                <enumeratedValue>
                                    <name>1</name>
                                    <description>Request switching</description>
                                    <value>#1</value>
                                </enumeratedValue>
                            </enumeratedValues>
                        </field>
                        <field>
                            <name>I3CCKSRDY</name>
                            <description>I3C clock (I3CCLK) Switching Ready state flag</description>
                            <lsb>7</lsb>
                            <msb>7</msb>
                            <access>read-only</access>
                            <enumeratedValues>
                                <enumeratedValue>
                                    <name>0</name>
                                    <description>Impossible to Switch</description>
                                    <value>#0</value>
                                </enumeratedValue>
                                <enumeratedValue>
                                    <name>1</name>
                                    <description>Possible to Switch</description>
                                    <value>#1</value>
                                </enumeratedValue>
                            </enumeratedValues>
                        </field>
                    </fields>
                </register>
                <register>
                    <name>MOSCSCR</name>
                    <description>Main Clock Oscillator Standby Control Register</description>
                    <addressOffset>0x07C</addressOffset>
                    <size>8</size>
                    <access>read-write</access>
                    <resetValue>0x00</resetValue>
                    <resetMask>0xff</resetMask>
                    <fields>
                        <field>
                            <name>MOSCSOKP</name>
                            <description>Main Clock Oscillator Standby Oscillation Keep select</description>
                            <lsb>0</lsb>
                            <msb>0</msb>
                            <access>read-write</access>
                            <enumeratedValues>
                                <enumeratedValue>
                                    <name>0</name>
                                    <description>Disable</description>
                                    <value>#0</value>
                                </enumeratedValue>
                                <enumeratedValue>
                                    <name>1</name>
                                    <description>Enable</description>
                                    <value>#1</value>
                                </enumeratedValue>
                            </enumeratedValues>
                        </field>
                    </fields>
                </register>
                <register>
                    <name>HOCOSCR</name>
                    <description>High-Speed On-Chip Oscillator Standby Control Register</description>
                    <addressOffset>0x07D</addressOffset>
                    <size>8</size>
                    <access>read-write</access>
                    <resetValue>0x00</resetValue>
                    <resetMask>0xff</resetMask>
                    <fields>
                        <field>
                            <name>HOCOSOKP</name>
                            <description>HOCO Standby Oscillation Keep select.</description>
                            <lsb>0</lsb>
                            <msb>0</msb>
                            <access>read-write</access>
                            <enumeratedValues>
                                <enumeratedValue>
                                    <name>0</name>
                                    <description>Disable</description>
                                    <value>#0</value>
                                </enumeratedValue>
                                <enumeratedValue>
                                    <name>1</name>
                                    <description>Enable</description>
                                    <value>#1</value>
                                </enumeratedValue>
                            </enumeratedValues>
                        </field>
                    </fields>
                </register>
                <register>
                    <name>OPCCR</name>
                    <description>Operating Power Control Register</description>
                    <addressOffset>0x0A0</addressOffset>
                    <size>8</size>
                    <access>read-write</access>
                    <resetValue>0x00</resetValue>
                    <resetMask>0xff</resetMask>
                    <fields>
                        <field>
                            <name>OPCM</name>
                            <description>Operating Power Control Mode Select</description>
                            <lsb>0</lsb>
                            <msb>1</msb>
                            <access>read-write</access>
                            <enumeratedValues>
                                <enumeratedValue>
                                    <name>00</name>
                                    <description>High-speed mode</description>
                                    <value>#00</value>
                                </enumeratedValue>
                                <enumeratedValue>
                                    <name>01</name>
                                    <description>Setting prohibited</description>
                                    <value>#01</value>
                                </enumeratedValue>
                                <enumeratedValue>
                                    <name>10</name>
                                    <description>Setting prohibited</description>
                                    <value>#10</value>
                                </enumeratedValue>
                                <enumeratedValue>
                                    <name>11</name>
                                    <description>Low-speed mode</description>
                                    <value>#11</value>
                                </enumeratedValue>
                            </enumeratedValues>
                        </field>
                        <field>
                            <name>OPCMTSF</name>
                            <description>Operating Power Control Mode Transition Status Flag</description>
                            <lsb>4</lsb>
                            <msb>4</msb>
                            <access>read-only</access>
                            <enumeratedValues>
                                <enumeratedValue>
                                    <name>0</name>
                                    <description>Transition completed</description>
                                    <value>#0</value>
                                </enumeratedValue>
                                <enumeratedValue>
                                    <name>1</name>
                                    <description>During transition</description>
                                    <value>#1</value>
                                </enumeratedValue>
                            </enumeratedValues>
                        </field>
                    </fields>
                </register>
                <register>
                    <name>MOSCWTCR</name>
                    <description>Main Clock Oscillator Wait Control Register</description>
                    <addressOffset>0x0A2</addressOffset>
                    <size>8</size>
                    <access>read-write</access>
                    <resetValue>0x05</resetValue>
                    <resetMask>0xff</resetMask>
                    <fields>
                        <field>
                            <name>MSTS</name>
                            <description>Main Clock Oscillator Wait Time Setting</description>
                            <lsb>0</lsb>
                            <msb>3</msb>
                            <access>read-write</access>
                            <enumeratedValues>
                                <enumeratedValue>
                                    <name>0x0</name>
                                    <description>Wait time = 3 cycles (11.4 us)</description>
                                    <value>0x0</value>
                                </enumeratedValue>
                                <enumeratedValue>
                                    <name>0x1</name>
                                    <description>Wait time = 35 cycles (133.5 us)</description>
                                    <value>0x1</value>
                                </enumeratedValue>
                                <enumeratedValue>
                                    <name>0x2</name>
                                    <description>Wait time = 67 cycles (255.6 us)</description>
                                    <value>0x2</value>
                                </enumeratedValue>
                                <enumeratedValue>
                                    <name>0x3</name>
                                    <description>Wait time = 131 cycles (499.7 us)</description>
                                    <value>0x3</value>
                                </enumeratedValue>
                                <enumeratedValue>
                                    <name>0x4</name>
                                    <description>Wait time = 259 cycles (988.0 us)</description>
                                    <value>0x4</value>
                                </enumeratedValue>
                                <enumeratedValue>
                                    <name>0x5</name>
                                    <description>Wait time = 547 cycles (2086.6 us)</description>
                                    <value>0x5</value>
                                </enumeratedValue>
                                <enumeratedValue>
                                    <name>0x6</name>
                                    <description>Wait time = 1059 cycles (4039.8 us)</description>
                                    <value>0x6</value>
                                </enumeratedValue>
                                <enumeratedValue>
                                    <name>0x7</name>
                                    <description>Wait time = 2147 cycles (8190.2 us)</description>
                                    <value>0x7</value>
                                </enumeratedValue>
                                <enumeratedValue>
                                    <name>0x8</name>
                                    <description>Wait time = 4291 cycles (16368.9 us)</description>
                                    <value>0x8</value>
                                </enumeratedValue>
                                <enumeratedValue>
                                    <name>0x9</name>
                                    <description>Wait time = 8163 cycles (31139.4 us)</description>
                                    <value>0x9</value>
                                </enumeratedValue>
                                <enumeratedValue>
                                    <name>Others</name>
                                    <description>Setting prohibited</description>
                                    <isDefault>true</isDefault>
                                </enumeratedValue>
                            </enumeratedValues>
                        </field>
                    </fields>
                </register>
                <register>
                    <name>RSTSR1</name>
                    <description>Reset Status Register 1</description>
                    <addressOffset>0x0C0</addressOffset>
                    <size>32</size>
                    <access>read-write</access>
                    <resetValue>0x00000000</resetValue>
                    <resetMask>0xffffbbe8</resetMask>
                    <fields>
                        <field>
                            <name>IWDTRF</name>
                            <description>Independent Watchdog Timer Reset Detect Flag</description>
                            <lsb>0</lsb>
                            <msb>0</msb>
                            <access>read-write</access>
                            <enumeratedValues>
                                <enumeratedValue>
                                    <name>0</name>
                                    <description>Independent watchdog timer reset not detected</description>
                                    <value>#0</value>
                                </enumeratedValue>
                                <enumeratedValue>
                                    <name>1</name>
                                    <description>Independent watchdog timer reset detected</description>
                                    <value>#1</value>
                                </enumeratedValue>
                            </enumeratedValues>
                        </field>
                        <field>
                            <name>WDT0RF</name>
                            <description>Watchdog Timer Reset Detect Flag</description>
                            <lsb>1</lsb>
                            <msb>1</msb>
                            <access>read-write</access>
                            <enumeratedValues>
                                <enumeratedValue>
                                    <name>0</name>
                                    <description>Watchdog timer reset not detected</description>
                                    <value>#0</value>
                                </enumeratedValue>
                                <enumeratedValue>
                                    <name>1</name>
                                    <description>Watchdog timer reset detected</description>
                                    <value>#1</value>
                                </enumeratedValue>
                            </enumeratedValues>
                        </field>
                        <field>
                            <name>SWRF</name>
                            <description>Software Reset Detect Flag</description>
                            <lsb>2</lsb>
                            <msb>2</msb>
                            <access>read-write</access>
                            <enumeratedValues>
                                <enumeratedValue>
                                    <name>0</name>
                                    <description>Software reset not detected</description>
                                    <value>#0</value>
                                </enumeratedValue>
                                <enumeratedValue>
                                    <name>1</name>
                                    <description>Software reset detected</description>
                                    <value>#1</value>
                                </enumeratedValue>
                            </enumeratedValues>
                        </field>
                        <field>
                            <name>CLU0RF</name>
                            <description>CPU Lockup Reset Detect Flag</description>
                            <lsb>4</lsb>
                            <msb>4</msb>
                            <access>read-write</access>
                            <enumeratedValues>
                                <enumeratedValue>
                                    <name>0</name>
                                    <description>CPU Lockup reset not detected</description>
                                    <value>#0</value>
                                </enumeratedValue>
                                <enumeratedValue>
                                    <name>1</name>
                                    <description>CPU Lockup reset detected</description>
                                    <value>#1</value>
                                </enumeratedValue>
                            </enumeratedValues>
                        </field>
                        <field>
                            <name>BUSRF</name>
                            <description>Bus Error Reset Detect Flag</description>
                            <lsb>10</lsb>
                            <msb>10</msb>
                            <access>read-write</access>
                            <enumeratedValues>
                                <enumeratedValue>
                                    <name>0</name>
                                    <description>Bus error reset not detected</description>
                                    <value>#0</value>
                                </enumeratedValue>
                                <enumeratedValue>
                                    <name>1</name>
                                    <description>Bus error reset detected</description>
                                    <value>#1</value>
                                </enumeratedValue>
                            </enumeratedValues>
                        </field>
                        <field>
                            <name>CMRF</name>
                            <description>Common Memory Error Reset Detect Flag</description>
                            <lsb>14</lsb>
                            <msb>14</msb>
                            <access>read-write</access>
                            <enumeratedValues>
                                <enumeratedValue>
                                    <name>0</name>
                                    <description>Common memory error reset not detected</description>
                                    <value>#0</value>
                                </enumeratedValue>
                                <enumeratedValue>
                                    <name>1</name>
                                    <description>Common memory error reset detected</description>
                                    <value>#1</value>
                                </enumeratedValue>
                            </enumeratedValues>
                        </field>
                    </fields>
                </register>
                <register>
                    <name>SYRACCR</name>
                    <description>System Register Access Control Register</description>
                    <addressOffset>0xCC</addressOffset>
                    <size>8</size>
                    <access>read-only</access>
                    <resetValue>0x00</resetValue>
                    <resetMask>0xff</resetMask>
                    <fields>
                        <field>
                            <name>BUSY</name>
                            <description>Access Ready monitor</description>
                            <lsb>0</lsb>
                            <msb>0</msb>
                            <access>read-only</access>
                            <enumeratedValues>
                                <enumeratedValue>
                                    <name>0</name>
                                    <description>Ready to read/write access</description>
                                    <value>#0</value>
                                </enumeratedValue>
                                <enumeratedValue>
                                    <name>1</name>
                                    <description>Writing in progress</description>
                                    <value>#1</value>
                                </enumeratedValue>
                            </enumeratedValues>
                        </field>
                    </fields>
                </register>
                <register>
                    <dim>2</dim>
                    <dimIncrement>0x2</dimIncrement>
                    <dimIndex>1-2</dimIndex>
                    <name>PVD%sCR1</name>
                    <description>Voltage Monitor %s Circuit Control Register 1</description>
                    <addressOffset>0x0E0</addressOffset>
                    <size>8</size>
                    <access>read-write</access>
                    <resetValue>0x01</resetValue>
                    <resetMask>0xff</resetMask>
                    <fields>
                        <field>
                            <name>IDTSEL</name>
                            <description>Voltage Monitor m Interrupt Generation Condition Select</description>
                            <lsb>0</lsb>
                            <msb>1</msb>
                            <access>read-write</access>
                        </field>
                        <field>
                            <name>IRQSEL</name>
                            <description>Voltage Monitor m Interrupt Type Select</description>
                            <lsb>2</lsb>
                            <msb>2</msb>
                            <access>read-write</access>
                            <enumeratedValues>
                                <enumeratedValue>
                                    <name>0</name>
                                    <description>Non-maskable interrupt</description>
                                    <value>#0</value>
                                </enumeratedValue>
                                <enumeratedValue>
                                    <name>1</name>
                                    <description>Maskable interrupt</description>
                                    <value>#1</value>
                                </enumeratedValue>
                            </enumeratedValues>
                        </field>
                    </fields>
                </register>
                <register>
                    <dim>2</dim>
                    <dimIncrement>0x2</dimIncrement>
                    <dimIndex>1-2</dimIndex>
                    <name>PVD%sSR</name>
                    <description>Voltage Monitor %s Circuit Status Register</description>
                    <addressOffset>0x0E1</addressOffset>
                    <size>8</size>
                    <access>read-write</access>
                    <resetValue>0x02</resetValue>
                    <resetMask>0xff</resetMask>
                    <fields>
                        <field>
                            <name>DET</name>
                            <description>Voltage Monitor m Voltage Change Detection Flag</description>
                            <lsb>0</lsb>
                            <msb>0</msb>
                            <access>read-write</access>
                        </field>
                        <field>
                            <name>MON</name>
                            <description>Voltage Monitor 1 Signal Monitor Flag</description>
                            <lsb>1</lsb>
                            <msb>1</msb>
                            <access>read-write</access>
                        </field>
                    </fields>
                </register>
                <register>
                    <name>PDCTRGD</name>
                    <description>Graphics Power Domain Control Register</description>
                    <addressOffset>0x110</addressOffset>
                    <size>8</size>
                    <access>read-write</access>
                    <resetValue>0x81</resetValue>
                    <resetMask>0xff</resetMask>
                    <fields>
                        <field>
                            <name>PDDE</name>
                            <description>Power control enable</description>
                            <lsb>0</lsb>
                            <msb>0</msb>
                            <access>read-write</access>
                            <enumeratedValues>
                                <enumeratedValue>
                                    <name>0</name>
                                    <description>Power on the target domain </description>
                                    <value>#0</value>
                                </enumeratedValue>
                                <enumeratedValue>
                                    <name>1</name>
                                    <description>Power off the target domain </description>
                                    <value>#1</value>
                                </enumeratedValue>
                            </enumeratedValues>
                        </field>
                        <field>
                            <name>PDCSF</name>
                            <description>Power control status flag</description>
                            <lsb>6</lsb>
                            <msb>6</msb>
                            <access>read-only</access>
                            <enumeratedValues>
                                <enumeratedValue>
                                    <name>0</name>
                                    <description>Power gating control is not executed (idle)</description>
                                    <value>#0</value>
                                </enumeratedValue>
                                <enumeratedValue>
                                    <name>1</name>
                                    <description>Power gating control is in progress</description>
                                    <value>#1</value>
                                </enumeratedValue>
                            </enumeratedValues>
                        </field>
                        <field>
                            <name>PDPGSF</name>
                            <description>Power gating status flag</description>
                            <lsb>7</lsb>
                            <msb>7</msb>
                            <access>read-only</access>
                            <enumeratedValues>
                                <enumeratedValue>
                                    <name>0</name>
                                    <description>Target domain is power on (not gating) </description>
                                    <value>#0</value>
                                </enumeratedValue>
                                <enumeratedValue>
                                    <name>1</name>
                                    <description>Target domain is power off (during Gating) </description>
                                    <value>#1</value>
                                </enumeratedValue>
                            </enumeratedValues>
                        </field>
                    </fields>
                </register>
                <register>
                    <name>PDRAMSCR0</name>
                    <description>SRAM Power Domain Standby Control Register 0</description>
                    <addressOffset>0x140</addressOffset>
                    <size>16</size>
                    <access>read-write</access>
                    <resetValue>0x7fff</resetValue>
                    <resetMask>0xffff</resetMask>
                    <fields>
                        <field>
                            <name>RKEEP0</name>
                            <description>RAM Retention</description>
                            <lsb>0</lsb>
                            <msb>0</msb>
                            <access>read-write</access>
                            <enumeratedValues>
                                <enumeratedValue>
                                    <name>0</name>
                                    <description>When entering the Software Standby mode, the contents of the target RAM are not kept.</description>
                                    <value>#0</value>
                                </enumeratedValue>
                                <enumeratedValue>
                                    <name>1</name>
                                    <description>When entering the Software Standby mode, the contents of the target RAM are kept.</description>
                                    <value>#1</value>
                                </enumeratedValue>
                            </enumeratedValues>
                        </field>
                        <field>
                            <name>RKEEP1</name>
                            <description>RAM Retention</description>
                            <lsb>1</lsb>
                            <msb>1</msb>
                            <access>read-write</access>
                            <enumeratedValues>
                                <enumeratedValue>
                                    <name>0</name>
                                    <description>When entering the Software Standby mode, the contents of the target RAM are not kept.</description>
                                    <value>#0</value>
                                </enumeratedValue>
                                <enumeratedValue>
                                    <name>1</name>
                                    <description>When entering the Software Standby mode, the contents of the target RAM are kept.</description>
                                    <value>#1</value>
                                </enumeratedValue>
                            </enumeratedValues>
                        </field>
                        <field>
                            <name>RKEEP2</name>
                            <description>RAM Retention</description>
                            <lsb>2</lsb>
                            <msb>2</msb>
                            <access>read-write</access>
                            <enumeratedValues>
                                <enumeratedValue>
                                    <name>0</name>
                                    <description>When entering the Software Standby mode, the contents of the target RAM are not kept.</description>
                                    <value>#0</value>
                                </enumeratedValue>
                                <enumeratedValue>
                                    <name>1</name>
                                    <description>When entering the Software Standby mode, the contents of the target RAM are kept.</description>
                                    <value>#1</value>
                                </enumeratedValue>
                            </enumeratedValues>
                        </field>
                        <field>
                            <name>RKEEP3</name>
                            <description>RAM Retention</description>
                            <lsb>3</lsb>
                            <msb>3</msb>
                            <access>read-write</access>
                            <enumeratedValues>
                                <enumeratedValue>
                                    <name>0</name>
                                    <description>When entering the Software Standby mode, the contents of the target RAM are not kept.</description>
                                    <value>#0</value>
                                </enumeratedValue>
                                <enumeratedValue>
                                    <name>1</name>
                                    <description>When entering the Software Standby mode, the contents of the target RAM are kept.</description>
                                    <value>#1</value>
                                </enumeratedValue>
                            </enumeratedValues>
                        </field>
                        <field>
                            <name>RKEEP4</name>
                            <description>RAM Retention</description>
                            <lsb>4</lsb>
                            <msb>4</msb>
                            <access>read-write</access>
                            <enumeratedValues>
                                <enumeratedValue>
                                    <name>0</name>
                                    <description>When entering the Software Standby mode, the contents of the target RAM are not kept.</description>
                                    <value>#0</value>
                                </enumeratedValue>
                                <enumeratedValue>
                                    <name>1</name>
                                    <description>When entering the Software Standby mode, the contents of the target RAM are kept.</description>
                                    <value>#1</value>
                                </enumeratedValue>
                            </enumeratedValues>
                        </field>
                        <field>
                            <name>RKEEP5</name>
                            <description>RAM Retention</description>
                            <lsb>5</lsb>
                            <msb>5</msb>
                            <access>read-write</access>
                            <enumeratedValues>
                                <enumeratedValue>
                                    <name>0</name>
                                    <description>When entering the Software Standby mode, the contents of the target RAM are not kept.</description>
                                    <value>#0</value>
                                </enumeratedValue>
                                <enumeratedValue>
                                    <name>1</name>
                                    <description>When entering the Software Standby mode, the contents of the target RAM are kept.</description>
                                    <value>#1</value>
                                </enumeratedValue>
                            </enumeratedValues>
                        </field>
                        <field>
                            <name>RKEEP6</name>
                            <description>RAM Retention</description>
                            <lsb>6</lsb>
                            <msb>6</msb>
                            <access>read-write</access>
                            <enumeratedValues>
                                <enumeratedValue>
                                    <name>0</name>
                                    <description>When entering the Software Standby mode, the contents of the target RAM are not kept.</description>
                                    <value>#0</value>
                                </enumeratedValue>
                                <enumeratedValue>
                                    <name>1</name>
                                    <description>When entering the Software Standby mode, the contents of the target RAM are kept.</description>
                                    <value>#1</value>
                                </enumeratedValue>
                            </enumeratedValues>
                        </field>
                    </fields>
                </register>
                <register>
                    <name>PDRAMSCR1</name>
                    <description>SRAM Power Domain Standby Control Register 1</description>
                    <addressOffset>0x142</addressOffset>
                    <size>8</size>
                    <access>read-write</access>
                    <resetValue>0x03</resetValue>
                    <resetMask>0xff</resetMask>
                    <fields>
                        <field>
                            <name>RKEEP0</name>
                            <description>RAM Retention</description>
                            <lsb>0</lsb>
                            <msb>0</msb>
                            <access>read-write</access>
                            <enumeratedValues>
                                <enumeratedValue>
                                    <name>0</name>
                                    <description>When entering the CPU Deep Sleep and Software Standby mode, the contents of the target RAM are not kept.</description>
                                    <value>#0</value>
                                </enumeratedValue>
                                <enumeratedValue>
                                    <name>1</name>
                                    <description>When entering the CPU Deep Sleep and Software Standby mode, the contents of the target RAM are kept.</description>
                                    <value>#1</value>
                                </enumeratedValue>
                            </enumeratedValues>
                        </field>
                    </fields>
                </register>
                <register>
                    <name>VBRSABAR</name>
                    <description>VBATT Backup Register Security Attribute Boundary Address Register</description>
                    <addressOffset>0x3B0</addressOffset>
                    <size>16</size>
                    <access>read-write</access>
                    <resetValue>0xffe0</resetValue>
                    <resetMask>0xffff</resetMask>
                    <fields>
                        <field>
                            <name>SABA</name>
                            <description>Boundary address between secure and non-secure</description>
                            <lsb>0</lsb>
                            <msb>15</msb>
                            <access>read-write</access>
                        </field>
                    </fields>
                </register>
                <register>
                    <name>VBRPABARS</name>
                    <description>VBATT Backup Register Privilege Attribute Boundary Address Register for Secure Region</description>
                    <addressOffset>0x3B4</addressOffset>
                    <size>16</size>
                    <access>read-write</access>
                    <resetValue>0x0000</resetValue>
                    <resetMask>0xffff</resetMask>
                    <fields>
                        <field>
                            <name>PABAS</name>
                            <description>Boundary address between privileged and unprivileged.</description>
                            <lsb>0</lsb>
                            <msb>15</msb>
                            <access>read-write</access>
                        </field>
                    </fields>
                </register>
                <register>
                    <name>CGFSAR</name>
                    <description>Clock Generation Function Security Attribute Register</description>
                    <addressOffset>0x3C0</addressOffset>
                    <size>32</size>
                    <access>read-write</access>
                    <resetValue>0x00000000</resetValue>
                    <resetMask>0xffffffff</resetMask>
                    <fields>
                        <field>
                            <name>NONSEC00</name>
                            <description>Non Secure Attribute bit 00</description>
                            <lsb>0</lsb>
                            <msb>0</msb>
                            <access>read-write</access>
                            <enumeratedValues>
                                <enumeratedValue>
                                    <name>0</name>
                                    <description>Secure</description>
                                    <value>#0</value>
                                </enumeratedValue>
                                <enumeratedValue>
                                    <name>1</name>
                                    <description>Non Secure</description>
                                    <value>#1</value>
                                </enumeratedValue>
                            </enumeratedValues>
                        </field>
                        <field>
                            <name>NONSEC02</name>
                            <description>Non Secure Attribute bit 02</description>
                            <lsb>2</lsb>
                            <msb>2</msb>
                            <access>read-write</access>
                            <enumeratedValues>
                                <enumeratedValue>
                                    <name>0</name>
                                    <description>Secure</description>
                                    <value>#0</value>
                                </enumeratedValue>
                                <enumeratedValue>
                                    <name>1</name>
                                    <description>Non Secure</description>
                                    <value>#1</value>
                                </enumeratedValue>
                            </enumeratedValues>
                        </field>
                        <field>
                            <name>NONSEC03</name>
                            <description>Non Secure Attribute bit 03</description>
                            <lsb>3</lsb>
                            <msb>3</msb>
                            <access>read-write</access>
                            <enumeratedValues>
                                <enumeratedValue>
                                    <name>0</name>
                                    <description>Secure</description>
                                    <value>#0</value>
                                </enumeratedValue>
                                <enumeratedValue>
                                    <name>1</name>
                                    <description>Non Secure</description>
                                    <value>#1</value>
                                </enumeratedValue>
                            </enumeratedValues>
                        </field>
                        <field>
                            <name>NONSEC04</name>
                            <description>Non Secure Attribute bit 04</description>
                            <lsb>4</lsb>
                            <msb>4</msb>
                            <access>read-write</access>
                            <enumeratedValues>
                                <enumeratedValue>
                                    <name>0</name>
                                    <description>Secure</description>
                                    <value>#0</value>
                                </enumeratedValue>
                                <enumeratedValue>
                                    <name>1</name>
                                    <description>Non Secure</description>
                                    <value>#1</value>
                                </enumeratedValue>
                            </enumeratedValues>
                        </field>
                        <field>
                            <name>NONSEC05</name>
                            <description>Non Secure Attribute bit 05</description>
                            <lsb>5</lsb>
                            <msb>5</msb>
                            <access>read-write</access>
                            <enumeratedValues>
                                <enumeratedValue>
                                    <name>0</name>
                                    <description>Secure</description>
                                    <value>#0</value>
                                </enumeratedValue>
                                <enumeratedValue>
                                    <name>1</name>
                                    <description>Non Secure</description>
                                    <value>#1</value>
                                </enumeratedValue>
                            </enumeratedValues>
                        </field>
                        <field>
                            <name>NONSEC06</name>
                            <description>Non Secure Attribute bit 06</description>
                            <lsb>6</lsb>
                            <msb>6</msb>
                            <access>read-write</access>
                            <enumeratedValues>
                                <enumeratedValue>
                                    <name>0</name>
                                    <description>Secure</description>
                                    <value>#0</value>
                                </enumeratedValue>
                                <enumeratedValue>
                                    <name>1</name>
                                    <description>Non Secure</description>
                                    <value>#1</value>
                                </enumeratedValue>
                            </enumeratedValues>
                        </field>
                        <field>
                            <name>NONSEC07</name>
                            <description>Non Secure Attribute bit 07</description>
                            <lsb>7</lsb>
                            <msb>7</msb>
                            <access>read-write</access>
                            <enumeratedValues>
                                <enumeratedValue>
                                    <name>0</name>
                                    <description>Secure</description>
                                    <value>#0</value>
                                </enumeratedValue>
                                <enumeratedValue>
                                    <name>1</name>
                                    <description>Non Secure</description>
                                    <value>#1</value>
                                </enumeratedValue>
                            </enumeratedValues>
                        </field>
                        <field>
                            <name>NONSEC08</name>
                            <description>Non Secure Attribute bit 08</description>
                            <lsb>8</lsb>
                            <msb>8</msb>
                            <access>read-write</access>
                            <enumeratedValues>
                                <enumeratedValue>
                                    <name>0</name>
                                    <description>Secure</description>
                                    <value>#0</value>
                                </enumeratedValue>
                                <enumeratedValue>
                                    <name>1</name>
                                    <description>Non Secure</description>
                                    <value>#1</value>
                                </enumeratedValue>
                            </enumeratedValues>
                        </field>
                        <field>
                            <name>NONSEC09</name>
                            <description>Non Secure Attribute bit 09</description>
                            <lsb>9</lsb>
                            <msb>9</msb>
                            <access>read-write</access>
                            <enumeratedValues>
                                <enumeratedValue>
                                    <name>0</name>
                                    <description>Secure</description>
                                    <value>#0</value>
                                </enumeratedValue>
                                <enumeratedValue>
                                    <name>1</name>
                                    <description>Non Secure</description>
                                    <value>#1</value>
                                </enumeratedValue>
                            </enumeratedValues>
                        </field>
                        <field>
                            <name>NONSEC11</name>
                            <description>Non Secure Attribute bit 11</description>
                            <lsb>11</lsb>
                            <msb>11</msb>
                            <access>read-write</access>
                            <enumeratedValues>
                                <enumeratedValue>
                                    <name>0</name>
                                    <description>Secure</description>
                                    <value>#0</value>
                                </enumeratedValue>
                                <enumeratedValue>
                                    <name>1</name>
                                    <description>Non Secure</description>
                                    <value>#1</value>
                                </enumeratedValue>
                            </enumeratedValues>
                        </field>
                        <field>
                            <name>NONSEC12</name>
                            <description>Non Secure Attribute bit 12</description>
                            <lsb>12</lsb>
                            <msb>12</msb>
                            <access>read-write</access>
                            <enumeratedValues>
                                <enumeratedValue>
                                    <name>0</name>
                                    <description>Secure</description>
                                    <value>#0</value>
                                </enumeratedValue>
                                <enumeratedValue>
                                    <name>1</name>
                                    <description>Non Secure</description>
                                    <value>#1</value>
                                </enumeratedValue>
                            </enumeratedValues>
                        </field>
                        <field>
                            <name>NONSEC13</name>
                            <description>Non Secure Attribute bit 13</description>
                            <lsb>13</lsb>
                            <msb>13</msb>
                            <access>read-write</access>
                            <enumeratedValues>
                                <enumeratedValue>
                                    <name>0</name>
                                    <description>Secure</description>
                                    <value>#0</value>
                                </enumeratedValue>
                                <enumeratedValue>
                                    <name>1</name>
                                    <description>Non Secure</description>
                                    <value>#1</value>
                                </enumeratedValue>
                            </enumeratedValues>
                        </field>
                        <field>
                            <name>NONSEC16</name>
                            <description>Non Secure Attribute bit 16</description>
                            <lsb>16</lsb>
                            <msb>16</msb>
                            <access>read-write</access>
                            <enumeratedValues>
                                <enumeratedValue>
                                    <name>0</name>
                                    <description>Secure</description>
                                    <value>#0</value>
                                </enumeratedValue>
                                <enumeratedValue>
                                    <name>1</name>
                                    <description>Non Secure</description>
                                    <value>#1</value>
                                </enumeratedValue>
                            </enumeratedValues>
                        </field>
                        <field>
                            <name>NONSEC17</name>
                            <description>Non Secure Attribute bit 17</description>
                            <lsb>17</lsb>
                            <msb>17</msb>
                            <access>read-write</access>
                            <enumeratedValues>
                                <enumeratedValue>
                                    <name>0</name>
                                    <description>Secure</description>
                                    <value>#0</value>
                                </enumeratedValue>
                                <enumeratedValue>
                                    <name>1</name>
                                    <description>Non Secure</description>
                                    <value>#1</value>
                                </enumeratedValue>
                            </enumeratedValues>
                        </field>
                        <field>
                            <name>NONSEC18</name>
                            <description>Non Secure Attribute bit 18</description>
                            <lsb>18</lsb>
                            <msb>18</msb>
                            <access>read-write</access>
                            <enumeratedValues>
                                <enumeratedValue>
                                    <name>0</name>
                                    <description>Secure</description>
                                    <value>#0</value>
                                </enumeratedValue>
                                <enumeratedValue>
                                    <name>1</name>
                                    <description>Non Secure</description>
                                    <value>#1</value>
                                </enumeratedValue>
                            </enumeratedValues>
                        </field>
                        <field>
                            <name>NONSEC19</name>
                            <description>Non Secure Attribute bit 19</description>
                            <lsb>19</lsb>
                            <msb>19</msb>
                            <access>read-write</access>
                            <enumeratedValues>
                                <enumeratedValue>
                                    <name>0</name>
                                    <description>Secure</description>
                                    <value>#0</value>
                                </enumeratedValue>
                                <enumeratedValue>
                                    <name>1</name>
                                    <description>Non Secure</description>
                                    <value>#1</value>
                                </enumeratedValue>
                            </enumeratedValues>
                        </field>
                        <field>
                            <name>NONSEC20</name>
                            <description>Non Secure Attribute bit 20</description>
                            <lsb>20</lsb>
                            <msb>20</msb>
                            <access>read-write</access>
                            <enumeratedValues>
                                <enumeratedValue>
                                    <name>0</name>
                                    <description>Secure</description>
                                    <value>#0</value>
                                </enumeratedValue>
                                <enumeratedValue>
                                    <name>1</name>
                                    <description>Non Secure</description>
                                    <value>#1</value>
                                </enumeratedValue>
                            </enumeratedValues>
                        </field>
                        <field>
                            <name>NONSEC21</name>
                            <description>Non Secure Attribute bit 21</description>
                            <lsb>21</lsb>
                            <msb>21</msb>
                            <access>read-write</access>
                            <enumeratedValues>
                                <enumeratedValue>
                                    <name>0</name>
                                    <description>Secure</description>
                                    <value>#0</value>
                                </enumeratedValue>
                                <enumeratedValue>
                                    <name>1</name>
                                    <description>Non Secure</description>
                                    <value>#1</value>
                                </enumeratedValue>
                            </enumeratedValues>
                        </field>
                        <field>
                            <name>NONSEC22</name>
                            <description>Non Secure Attribute bit 22</description>
                            <lsb>22</lsb>
                            <msb>22</msb>
                            <access>read-write</access>
                            <enumeratedValues>
                                <enumeratedValue>
                                    <name>0</name>
                                    <description>Secure</description>
                                    <value>#0</value>
                                </enumeratedValue>
                                <enumeratedValue>
                                    <name>1</name>
                                    <description>Non Secure</description>
                                    <value>#1</value>
                                </enumeratedValue>
                            </enumeratedValues>
                        </field>
                        <field>
                            <name>NONSEC26</name>
                            <description>Non Secure Attribute bit 26</description>
                            <lsb>26</lsb>
                            <msb>26</msb>
                            <access>read-write</access>
                            <enumeratedValues>
                                <enumeratedValue>
                                    <name>0</name>
                                    <description>Secure</description>
                                    <value>#0</value>
                                </enumeratedValue>
                                <enumeratedValue>
                                    <name>1</name>
                                    <description>Non Secure</description>
                                    <value>#1</value>
                                </enumeratedValue>
                            </enumeratedValues>
                        </field>
                    </fields>
                </register>
                <register>
                    <name>RSTSAR</name>
                    <description>Reset Security Attribution Register</description>
                    <addressOffset>0x3C4</addressOffset>
                    <size>32</size>
                    <access>read-write</access>
                    <resetValue>0x00000000</resetValue>
                    <resetMask>0xffffffff</resetMask>
                    <fields>
                        <field>
                            <name>NONSEC0</name>
                            <description>Non-secure Attribute bit 0</description>
                            <lsb>0</lsb>
                            <msb>0</msb>
                            <access>read-write</access>
                            <enumeratedValues>
                                <enumeratedValue>
                                    <name>0</name>
                                    <description>Secure</description>
                                    <value>#0</value>
                                </enumeratedValue>
                                <enumeratedValue>
                                    <name>1</name>
                                    <description>Non-secure</description>
                                    <value>#1</value>
                                </enumeratedValue>
                            </enumeratedValues>
                        </field>
                        <field>
                            <name>NONSEC1</name>
                            <description>Non-secure Attribute bit 1</description>
                            <lsb>1</lsb>
                            <msb>1</msb>
                            <access>read-write</access>
                            <enumeratedValues>
                                <enumeratedValue>
                                    <name>0</name>
                                    <description>Secure</description>
                                    <value>#0</value>
                                </enumeratedValue>
                                <enumeratedValue>
                                    <name>1</name>
                                    <description>Non-secure</description>
                                    <value>#1</value>
                                </enumeratedValue>
                            </enumeratedValues>
                        </field>
                        <field>
                            <name>NONSEC2</name>
                            <description>Non-secure Attribute bit 2</description>
                            <lsb>2</lsb>
                            <msb>2</msb>
                            <access>read-write</access>
                            <enumeratedValues>
                                <enumeratedValue>
                                    <name>0</name>
                                    <description>Secure</description>
                                    <value>#0</value>
                                </enumeratedValue>
                                <enumeratedValue>
                                    <name>1</name>
                                    <description>Non-secure</description>
                                    <value>#1</value>
                                </enumeratedValue>
                            </enumeratedValues>
                        </field>
                    </fields>
                </register>
                <register>
                    <name>LPMSAR</name>
                    <description>Low Power Mode Security Attribution Register</description>
                    <addressOffset>0x3C8</addressOffset>
                    <size>32</size>
                    <access>read-write</access>
                    <resetValue>0x00000000</resetValue>
                    <resetMask>0xffffffff</resetMask>
                    <fields>
                        <field>
                            <name>NONSEC0</name>
                            <description>Non-secure Attribute bit 0</description>
                            <lsb>0</lsb>
                            <msb>0</msb>
                            <access>read-write</access>
                            <enumeratedValues>
                                <enumeratedValue>
                                    <name>0</name>
                                    <description>Secure</description>
                                    <value>#0</value>
                                </enumeratedValue>
                                <enumeratedValue>
                                    <name>1</name>
                                    <description>Non-secure</description>
                                    <value>#1</value>
                                </enumeratedValue>
                            </enumeratedValues>
                        </field>
                        <field>
                            <name>NONSEC1</name>
                            <description>Non-secure Attribute bit 1</description>
                            <lsb>1</lsb>
                            <msb>1</msb>
                            <access>read-write</access>
                            <enumeratedValues>
                                <enumeratedValue>
                                    <name>0</name>
                                    <description>Secure</description>
                                    <value>#0</value>
                                </enumeratedValue>
                                <enumeratedValue>
                                    <name>1</name>
                                    <description>Non-secure</description>
                                    <value>#1</value>
                                </enumeratedValue>
                            </enumeratedValues>
                        </field>
                        <field>
                            <name>NONSEC2</name>
                            <description>Non-secure Attribute bit 2</description>
                            <lsb>2</lsb>
                            <msb>2</msb>
                            <access>read-write</access>
                            <enumeratedValues>
                                <enumeratedValue>
                                    <name>0</name>
                                    <description>Secure</description>
                                    <value>#0</value>
                                </enumeratedValue>
                                <enumeratedValue>
                                    <name>1</name>
                                    <description>Non-secure</description>
                                    <value>#1</value>
                                </enumeratedValue>
                            </enumeratedValues>
                        </field>
                        <field>
                            <name>NONSEC8</name>
                            <description>Non-secure Attribute bit 8</description>
                            <lsb>8</lsb>
                            <msb>8</msb>
                            <access>read-write</access>
                            <enumeratedValues>
                                <enumeratedValue>
                                    <name>0</name>
                                    <description>Secure</description>
                                    <value>#0</value>
                                </enumeratedValue>
                                <enumeratedValue>
                                    <name>1</name>
                                    <description>Non-secure</description>
                                    <value>#1</value>
                                </enumeratedValue>
                            </enumeratedValues>
                        </field>
                        <field>
                            <name>NONSEC17</name>
                            <description>Non-secure Attribute bit 17</description>
                            <lsb>17</lsb>
                            <msb>17</msb>
                            <access>read-write</access>
                            <enumeratedValues>
                                <enumeratedValue>
                                    <name>0</name>
                                    <description>Secure</description>
                                    <value>#0</value>
                                </enumeratedValue>
                                <enumeratedValue>
                                    <name>1</name>
                                    <description>Non-secure</description>
                                    <value>#1</value>
                                </enumeratedValue>
                            </enumeratedValues>
                        </field>
                        <field>
                            <name>NONSEC18</name>
                            <description>Non-secure Attribute bit 18</description>
                            <lsb>18</lsb>
                            <msb>18</msb>
                            <access>read-write</access>
                            <enumeratedValues>
                                <enumeratedValue>
                                    <name>0</name>
                                    <description>Secure</description>
                                    <value>#0</value>
                                </enumeratedValue>
                                <enumeratedValue>
                                    <name>1</name>
                                    <description>Non-secure</description>
                                    <value>#1</value>
                                </enumeratedValue>
                            </enumeratedValues>
                        </field>
                        <field>
                            <name>NONSEC19</name>
                            <description>Non-secure Attribute bit 19</description>
                            <lsb>19</lsb>
                            <msb>19</msb>
                            <access>read-write</access>
                            <enumeratedValues>
                                <enumeratedValue>
                                    <name>0</name>
                                    <description>Secure</description>
                                    <value>#0</value>
                                </enumeratedValue>
                                <enumeratedValue>
                                    <name>1</name>
                                    <description>Non-secure</description>
                                    <value>#1</value>
                                </enumeratedValue>
                            </enumeratedValues>
                        </field>
                        <field>
                            <name>NONSEC21</name>
                            <description>Non-secure Attribute bit 21</description>
                            <lsb>21</lsb>
                            <msb>21</msb>
                            <access>read-write</access>
                            <enumeratedValues>
                                <enumeratedValue>
                                    <name>0</name>
                                    <description>Secure</description>
                                    <value>#0</value>
                                </enumeratedValue>
                                <enumeratedValue>
                                    <name>1</name>
                                    <description>Non-secure</description>
                                    <value>#1</value>
                                </enumeratedValue>
                            </enumeratedValues>
                        </field>
                    </fields>
                </register>
                <register>
                    <name>PVDSAR</name>
                    <description>Programable Voltage Detection Security Attribution Register</description>
                    <addressOffset>0x3CC</addressOffset>
                    <size>32</size>
                    <access>read-write</access>
                    <resetValue>0x00000000</resetValue>
                    <resetMask>0xffffffff</resetMask>
                    <fields>
                        <field>
                            <name>NONSEC0</name>
                            <description>Non Secure Attribute bit 0</description>
                            <lsb>0</lsb>
                            <msb>0</msb>
                            <access>read-write</access>
                            <enumeratedValues>
                                <enumeratedValue>
                                    <name>0</name>
                                    <description>Secure</description>
                                    <value>#0</value>
                                </enumeratedValue>
                                <enumeratedValue>
                                    <name>1</name>
                                    <description>Non Secure</description>
                                    <value>#1</value>
                                </enumeratedValue>
                            </enumeratedValues>
                        </field>
                        <field>
                            <name>NONSEC1</name>
                            <description>Non Secure Attribute bit 1</description>
                            <lsb>1</lsb>
                            <msb>1</msb>
                            <access>read-write</access>
                            <enumeratedValues>
                                <enumeratedValue>
                                    <name>0</name>
                                    <description>Secure</description>
                                    <value>#0</value>
                                </enumeratedValue>
                                <enumeratedValue>
                                    <name>1</name>
                                    <description>Non Secure</description>
                                    <value>#1</value>
                                </enumeratedValue>
                            </enumeratedValues>
                        </field>
                    </fields>
                </register>
                <register>
                    <name>BBFSAR</name>
                    <description>Battery Backup Function Security Attribute Register</description>
                    <addressOffset>0x3D0</addressOffset>
                    <size>32</size>
                    <access>read-write</access>
                    <resetValue>0x00000000</resetValue>
                    <resetMask>0xffffffff</resetMask>
                    <fields>
                        <field>
                            <name>NONSEC0</name>
                            <description>Non Secure Attribute bit 0</description>
                            <lsb>0</lsb>
                            <msb>0</msb>
                            <access>read-write</access>
                            <enumeratedValues>
                                <enumeratedValue>
                                    <name>0</name>
                                    <description>Secure</description>
                                    <value>#0</value>
                                </enumeratedValue>
                                <enumeratedValue>
                                    <name>1</name>
                                    <description>Non Secure</description>
                                    <value>#1</value>
                                </enumeratedValue>
                            </enumeratedValues>
                        </field>
                        <field>
                            <name>NONSEC1</name>
                            <description>Non Secure Attribute bit 1</description>
                            <lsb>1</lsb>
                            <msb>1</msb>
                            <access>read-write</access>
                            <enumeratedValues>
                                <enumeratedValue>
                                    <name>0</name>
                                    <description>Secure</description>
                                    <value>#0</value>
                                </enumeratedValue>
                                <enumeratedValue>
                                    <name>1</name>
                                    <description>Non Secure</description>
                                    <value>#1</value>
                                </enumeratedValue>
                            </enumeratedValues>
                        </field>
                        <field>
                            <name>NONSEC2</name>
                            <description>Non Secure Attribute bit 2</description>
                            <lsb>2</lsb>
                            <msb>2</msb>
                            <access>read-write</access>
                            <enumeratedValues>
                                <enumeratedValue>
                                    <name>0</name>
                                    <description>Secure</description>
                                    <value>#0</value>
                                </enumeratedValue>
                                <enumeratedValue>
                                    <name>1</name>
                                    <description>Non Secure</description>
                                    <value>#1</value>
                                </enumeratedValue>
                            </enumeratedValues>
                        </field>
                        <field>
                            <name>NONSEC3</name>
                            <description>Non Secure Attribute bit 3</description>
                            <lsb>3</lsb>
                            <msb>3</msb>
                            <access>read-write</access>
                            <enumeratedValues>
                                <enumeratedValue>
                                    <name>0</name>
                                    <description>Secure</description>
                                    <value>#0</value>
                                </enumeratedValue>
                                <enumeratedValue>
                                    <name>1</name>
                                    <description>Non Secure</description>
                                    <value>#1</value>
                                </enumeratedValue>
                            </enumeratedValues>
                        </field>
                        <field>
                            <name>NONSEC4</name>
                            <description>Non Secure Attribute bit 4</description>
                            <lsb>4</lsb>
                            <msb>4</msb>
                            <access>read-write</access>
                            <enumeratedValues>
                                <enumeratedValue>
                                    <name>0</name>
                                    <description>Secure</description>
                                    <value>#0</value>
                                </enumeratedValue>
                                <enumeratedValue>
                                    <name>1</name>
                                    <description>Non Secure</description>
                                    <value>#1</value>
                                </enumeratedValue>
                            </enumeratedValues>
                        </field>
                    </fields>
                </register>
                <register>
                    <name>PGCSAR</name>
                    <description>Power Gating Control Security Attribution Register</description>
                    <addressOffset>0x3D8</addressOffset>
                    <size>32</size>
                    <access>read-write</access>
                    <resetValue>0x00000000</resetValue>
                    <resetMask>0xffffffff</resetMask>
                    <fields>
                        <field>
                            <name>NONSEC1</name>
                            <description>Non-secure Attribute bit 1</description>
                            <lsb>1</lsb>
                            <msb>1</msb>
                            <access>read-write</access>
                            <enumeratedValues>
                                <enumeratedValue>
                                    <name>0</name>
                                    <description>Secure</description>
                                    <value>#0</value>
                                </enumeratedValue>
                                <enumeratedValue>
                                    <name>1</name>
                                    <description>Non-secure</description>
                                    <value>#1</value>
                                </enumeratedValue>
                            </enumeratedValues>
                        </field>
                    </fields>
                </register>
                <register>
                    <name>DPFSAR</name>
                    <description>Deep Software Standby Interrupt Factor Security Attribution Register</description>
                    <addressOffset>0x3E0</addressOffset>
                    <size>32</size>
                    <access>read-write</access>
                    <resetValue>0x00000000</resetValue>
                    <resetMask>0xffffffff</resetMask>
                    <fields>
                        <field>
                            <name>DPFSA0</name>
                            <description>Deep Software Standby Interrupt Factor Security Attribute bit n (n = 0 to 7)</description>
                            <lsb>0</lsb>
                            <msb>0</msb>
                            <access>read-write</access>
                            <enumeratedValues>
                                <enumeratedValue>
                                    <name>0</name>
                                    <description>Secure</description>
                                    <value>#0</value>
                                </enumeratedValue>
                                <enumeratedValue>
                                    <name>1</name>
                                    <description>Non-secure</description>
                                    <value>#1</value>
                                </enumeratedValue>
                            </enumeratedValues>
                        </field>
                        <field>
                            <name>DPFSA1</name>
                            <description>Deep Software Standby Interrupt Factor Security Attribute bit n (n = 0 to 7)</description>
                            <lsb>1</lsb>
                            <msb>1</msb>
                            <access>read-write</access>
                            <enumeratedValues>
                                <enumeratedValue>
                                    <name>0</name>
                                    <description>Secure</description>
                                    <value>#0</value>
                                </enumeratedValue>
                                <enumeratedValue>
                                    <name>1</name>
                                    <description>Non-secure</description>
                                    <value>#1</value>
                                </enumeratedValue>
                            </enumeratedValues>
                        </field>
                        <field>
                            <name>DPFSA2</name>
                            <description>Deep Software Standby Interrupt Factor Security Attribute bit n (n = 0 to 7)</description>
                            <lsb>2</lsb>
                            <msb>2</msb>
                            <access>read-write</access>
                            <enumeratedValues>
                                <enumeratedValue>
                                    <name>0</name>
                                    <description>Secure</description>
                                    <value>#0</value>
                                </enumeratedValue>
                                <enumeratedValue>
                                    <name>1</name>
                                    <description>Non-secure</description>
                                    <value>#1</value>
                                </enumeratedValue>
                            </enumeratedValues>
                        </field>
                        <field>
                            <name>DPFSA3</name>
                            <description>Deep Software Standby Interrupt Factor Security Attribute bit n (n = 0 to 7)</description>
                            <lsb>3</lsb>
                            <msb>3</msb>
                            <access>read-write</access>
                            <enumeratedValues>
                                <enumeratedValue>
                                    <name>0</name>
                                    <description>Secure</description>
                                    <value>#0</value>
                                </enumeratedValue>
                                <enumeratedValue>
                                    <name>1</name>
                                    <description>Non-secure</description>
                                    <value>#1</value>
                                </enumeratedValue>
                            </enumeratedValues>
                        </field>
                        <field>
                            <name>DPFSA4</name>
                            <description>Deep Software Standby Interrupt Factor Security Attribute bit n (n = 0 to 7)</description>
                            <lsb>4</lsb>
                            <msb>4</msb>
                            <access>read-write</access>
                            <enumeratedValues>
                                <enumeratedValue>
                                    <name>0</name>
                                    <description>Secure</description>
                                    <value>#0</value>
                                </enumeratedValue>
                                <enumeratedValue>
                                    <name>1</name>
                                    <description>Non-secure</description>
                                    <value>#1</value>
                                </enumeratedValue>
                            </enumeratedValues>
                        </field>
                        <field>
                            <name>DPFSA5</name>
                            <description>Deep Software Standby Interrupt Factor Security Attribute bit n (n = 0 to 7)</description>
                            <lsb>5</lsb>
                            <msb>5</msb>
                            <access>read-write</access>
                            <enumeratedValues>
                                <enumeratedValue>
                                    <name>0</name>
                                    <description>Secure</description>
                                    <value>#0</value>
                                </enumeratedValue>
                                <enumeratedValue>
                                    <name>1</name>
                                    <description>Non-secure</description>
                                    <value>#1</value>
                                </enumeratedValue>
                            </enumeratedValues>
                        </field>
                        <field>
                            <name>DPFSA6</name>
                            <description>Deep Software Standby Interrupt Factor Security Attribute bit n (n = 0 to 7)</description>
                            <lsb>6</lsb>
                            <msb>6</msb>
                            <access>read-write</access>
                            <enumeratedValues>
                                <enumeratedValue>
                                    <name>0</name>
                                    <description>Secure</description>
                                    <value>#0</value>
                                </enumeratedValue>
                                <enumeratedValue>
                                    <name>1</name>
                                    <description>Non-secure</description>
                                    <value>#1</value>
                                </enumeratedValue>
                            </enumeratedValues>
                        </field>
                        <field>
                            <name>DPFSA7</name>
                            <description>Deep Software Standby Interrupt Factor Security Attribute bit n (n = 0 to 7)</description>
                            <lsb>7</lsb>
                            <msb>7</msb>
                            <access>read-write</access>
                            <enumeratedValues>
                                <enumeratedValue>
                                    <name>0</name>
                                    <description>Secure</description>
                                    <value>#0</value>
                                </enumeratedValue>
                                <enumeratedValue>
                                    <name>1</name>
                                    <description>Non-secure</description>
                                    <value>#1</value>
                                </enumeratedValue>
                            </enumeratedValues>
                        </field>
                        <field>
                            <name>DPFSA08</name>
                            <description>Deep Software Standby Interrupt Factor Security Attribute bit n (n = 8 to 15)</description>
                            <lsb>8</lsb>
                            <msb>8</msb>
                            <access>read-write</access>
                            <enumeratedValues>
                                <enumeratedValue>
                                    <name>0</name>
                                    <description>Secure</description>
                                    <value>#0</value>
                                </enumeratedValue>
                                <enumeratedValue>
                                    <name>1</name>
                                    <description>Non-secure</description>
                                    <value>#1</value>
                                </enumeratedValue>
                            </enumeratedValues>
                        </field>
                        <field>
                            <name>DPFSA09</name>
                            <description>Deep Software Standby Interrupt Factor Security Attribute bit n (n = 8 to 15)</description>
                            <lsb>9</lsb>
                            <msb>9</msb>
                            <access>read-write</access>
                            <enumeratedValues>
                                <enumeratedValue>
                                    <name>0</name>
                                    <description>Secure</description>
                                    <value>#0</value>
                                </enumeratedValue>
                                <enumeratedValue>
                                    <name>1</name>
                                    <description>Non-secure</description>
                                    <value>#1</value>
                                </enumeratedValue>
                            </enumeratedValues>
                        </field>
                        <field>
                            <name>DPFSA10</name>
                            <description>Deep Software Standby Interrupt Factor Security Attribute bit n (n = 8 to 15)</description>
                            <lsb>10</lsb>
                            <msb>10</msb>
                            <access>read-write</access>
                            <enumeratedValues>
                                <enumeratedValue>
                                    <name>0</name>
                                    <description>Secure</description>
                                    <value>#0</value>
                                </enumeratedValue>
                                <enumeratedValue>
                                    <name>1</name>
                                    <description>Non-secure</description>
                                    <value>#1</value>
                                </enumeratedValue>
                            </enumeratedValues>
                        </field>
                        <field>
                            <name>DPFSA11</name>
                            <description>Deep Software Standby Interrupt Factor Security Attribute bit n (n = 8 to 15)</description>
                            <lsb>11</lsb>
                            <msb>11</msb>
                            <access>read-write</access>
                            <enumeratedValues>
                                <enumeratedValue>
                                    <name>0</name>
                                    <description>Secure</description>
                                    <value>#0</value>
                                </enumeratedValue>
                                <enumeratedValue>
                                    <name>1</name>
                                    <description>Non-secure</description>
                                    <value>#1</value>
                                </enumeratedValue>
                            </enumeratedValues>
                        </field>
                        <field>
                            <name>DPFSA12</name>
                            <description>Deep Software Standby Interrupt Factor Security Attribute bit n (n = 8 to 15)</description>
                            <lsb>12</lsb>
                            <msb>12</msb>
                            <access>read-write</access>
                            <enumeratedValues>
                                <enumeratedValue>
                                    <name>0</name>
                                    <description>Secure</description>
                                    <value>#0</value>
                                </enumeratedValue>
                                <enumeratedValue>
                                    <name>1</name>
                                    <description>Non-secure</description>
                                    <value>#1</value>
                                </enumeratedValue>
                            </enumeratedValues>
                        </field>
                        <field>
                            <name>DPFSA13</name>
                            <description>Deep Software Standby Interrupt Factor Security Attribute bit n (n = 8 to 15)</description>
                            <lsb>13</lsb>
                            <msb>13</msb>
                            <access>read-write</access>
                            <enumeratedValues>
                                <enumeratedValue>
                                    <name>0</name>
                                    <description>Secure</description>
                                    <value>#0</value>
                                </enumeratedValue>
                                <enumeratedValue>
                                    <name>1</name>
                                    <description>Non-secure</description>
                                    <value>#1</value>
                                </enumeratedValue>
                            </enumeratedValues>
                        </field>
                        <field>
                            <name>DPFSA14</name>
                            <description>Deep Software Standby Interrupt Factor Security Attribute bit n (n = 8 to 15)</description>
                            <lsb>14</lsb>
                            <msb>14</msb>
                            <access>read-write</access>
                            <enumeratedValues>
                                <enumeratedValue>
                                    <name>0</name>
                                    <description>Secure</description>
                                    <value>#0</value>
                                </enumeratedValue>
                                <enumeratedValue>
                                    <name>1</name>
                                    <description>Non-secure</description>
                                    <value>#1</value>
                                </enumeratedValue>
                            </enumeratedValues>
                        </field>
                        <field>
                            <name>DPFSA15</name>
                            <description>Deep Software Standby Interrupt Factor Security Attribute bit n (n = 8 to 15)</description>
                            <lsb>15</lsb>
                            <msb>15</msb>
                            <access>read-write</access>
                            <enumeratedValues>
                                <enumeratedValue>
                                    <name>0</name>
                                    <description>Secure</description>
                                    <value>#0</value>
                                </enumeratedValue>
                                <enumeratedValue>
                                    <name>1</name>
                                    <description>Non-secure</description>
                                    <value>#1</value>
                                </enumeratedValue>
                            </enumeratedValues>
                        </field>
                        <field>
                            <name>DPFSA16</name>
                            <description>Deep Software Standby Interrupt Factor Security Attribute bit 16</description>
                            <lsb>16</lsb>
                            <msb>16</msb>
                            <access>read-write</access>
                            <enumeratedValues>
                                <enumeratedValue>
                                    <name>0</name>
                                    <description>Secure</description>
                                    <value>#0</value>
                                </enumeratedValue>
                                <enumeratedValue>
                                    <name>1</name>
                                    <description>Non-secure</description>
                                    <value>#1</value>
                                </enumeratedValue>
                            </enumeratedValues>
                        </field>
                        <field>
                            <name>DPFSA17</name>
                            <description>Deep Software Standby Interrupt Factor Security Attribute bit 17</description>
                            <lsb>17</lsb>
                            <msb>17</msb>
                            <access>read-write</access>
                            <enumeratedValues>
                                <enumeratedValue>
                                    <name>0</name>
                                    <description>Secure</description>
                                    <value>#0</value>
                                </enumeratedValue>
                                <enumeratedValue>
                                    <name>1</name>
                                    <description>Non-secure</description>
                                    <value>#1</value>
                                </enumeratedValue>
                            </enumeratedValues>
                        </field>
                        <field>
                            <name>DPFSA18</name>
                            <description>Deep Software Standby Interrupt Factor Security Attribute bit 18</description>
                            <lsb>18</lsb>
                            <msb>18</msb>
                            <access>read-write</access>
                            <enumeratedValues>
                                <enumeratedValue>
                                    <name>0</name>
                                    <description>Secure</description>
                                    <value>#0</value>
                                </enumeratedValue>
                                <enumeratedValue>
                                    <name>1</name>
                                    <description>Non-secure</description>
                                    <value>#1</value>
                                </enumeratedValue>
                            </enumeratedValues>
                        </field>
                        <field>
                            <name>DPFSA19</name>
                            <description>Deep Software Standby Interrupt Factor Security Attribute bit 19</description>
                            <lsb>19</lsb>
                            <msb>19</msb>
                            <access>read-write</access>
                            <enumeratedValues>
                                <enumeratedValue>
                                    <name>0</name>
                                    <description>Secure</description>
                                    <value>#0</value>
                                </enumeratedValue>
                                <enumeratedValue>
                                    <name>1</name>
                                    <description>Non-secure</description>
                                    <value>#1</value>
                                </enumeratedValue>
                            </enumeratedValues>
                        </field>
                        <field>
                            <name>DPFSA20</name>
                            <description>Deep Software Standby Interrupt Factor Security Attribute bit 20</description>
                            <lsb>20</lsb>
                            <msb>20</msb>
                            <access>read-write</access>
                            <enumeratedValues>
                                <enumeratedValue>
                                    <name>0</name>
                                    <description>Secure</description>
                                    <value>#0</value>
                                </enumeratedValue>
                                <enumeratedValue>
                                    <name>1</name>
                                    <description>Non-secure</description>
                                    <value>#1</value>
                                </enumeratedValue>
                            </enumeratedValues>
                        </field>
                        <field>
                            <name>DPFSA24</name>
                            <description>Deep Software Standby Interrupt Factor Security Attribute bit 24</description>
                            <lsb>24</lsb>
                            <msb>24</msb>
                            <access>read-write</access>
                            <enumeratedValues>
                                <enumeratedValue>
                                    <name>0</name>
                                    <description>Secure</description>
                                    <value>#0</value>
                                </enumeratedValue>
                                <enumeratedValue>
                                    <name>1</name>
                                    <description>Non-secure</description>
                                    <value>#1</value>
                                </enumeratedValue>
                            </enumeratedValues>
                        </field>
                        <field>
                            <name>DPFSA25</name>
                            <description>Deep Software Standby Interrupt Factor Security Attribute bit 25</description>
                            <lsb>25</lsb>
                            <msb>25</msb>
                            <access>read-write</access>
                            <enumeratedValues>
                                <enumeratedValue>
                                    <name>0</name>
                                    <description>Secure</description>
                                    <value>#0</value>
                                </enumeratedValue>
                                <enumeratedValue>
                                    <name>1</name>
                                    <description>Non-secure</description>
                                    <value>#1</value>
                                </enumeratedValue>
                            </enumeratedValues>
                        </field>
                        <field>
                            <name>DPFSA26</name>
                            <description>Deep Software Standby Interrupt Factor Security Attribute bit 26</description>
                            <lsb>26</lsb>
                            <msb>26</msb>
                            <access>read-write</access>
                            <enumeratedValues>
                                <enumeratedValue>
                                    <name>0</name>
                                    <description>Secure</description>
                                    <value>#0</value>
                                </enumeratedValue>
                                <enumeratedValue>
                                    <name>1</name>
                                    <description>Non-secure</description>
                                    <value>#1</value>
                                </enumeratedValue>
                            </enumeratedValues>
                        </field>
                        <field>
                            <name>DPFSA27</name>
                            <description>Deep Software Standby Interrupt Factor Security Attribute bit 27</description>
                            <lsb>27</lsb>
                            <msb>27</msb>
                            <access>read-write</access>
                            <enumeratedValues>
                                <enumeratedValue>
                                    <name>0</name>
                                    <description>Secure</description>
                                    <value>#0</value>
                                </enumeratedValue>
                                <enumeratedValue>
                                    <name>1</name>
                                    <description>Non-secure</description>
                                    <value>#1</value>
                                </enumeratedValue>
                            </enumeratedValues>
                        </field>
                        <field>
                            <name>DPFSA29</name>
                            <description>Deep Software Standby Interrupt Factor Security Attribute bit 29</description>
                            <lsb>29</lsb>
                            <msb>29</msb>
                            <access>read-write</access>
                            <enumeratedValues>
                                <enumeratedValue>
                                    <name>0</name>
                                    <description>Secure</description>
                                    <value>#0</value>
                                </enumeratedValue>
                                <enumeratedValue>
                                    <name>1</name>
                                    <description>Non-secure</description>
                                    <value>#1</value>
                                </enumeratedValue>
                            </enumeratedValues>
                        </field>
                        <field>
                            <name>DPFSA31</name>
                            <description>Deep Software Standby Interrupt Factor Security Attribute bit 31</description>
                            <lsb>31</lsb>
                            <msb>31</msb>
                            <access>read-write</access>
                            <enumeratedValues>
                                <enumeratedValue>
                                    <name>0</name>
                                    <description>Secure</description>
                                    <value>#0</value>
                                </enumeratedValue>
                                <enumeratedValue>
                                    <name>1</name>
                                    <description>Non-secure</description>
                                    <value>#1</value>
                                </enumeratedValue>
                            </enumeratedValues>
                        </field>
                    </fields>
                </register>
                <register>
                    <name>RSCSAR</name>
                    <description>RAM Standby Control Security Attribution Register</description>
                    <addressOffset>0x3E4</addressOffset>
                    <size>32</size>
                    <access>read-write</access>
                    <resetValue>0x00000000</resetValue>
                    <resetMask>0xffffffff</resetMask>
                    <fields>
                        <field>
                            <name>RSCSA0</name>
                            <description>RAM Standby Control Security Attribute bit n (n = 0 to 6)</description>
                            <lsb>0</lsb>
                            <msb>0</msb>
                            <access>read-write</access>
                            <enumeratedValues>
                                <enumeratedValue>
                                    <name>0</name>
                                    <description>Secure</description>
                                    <value>#0</value>
                                </enumeratedValue>
                                <enumeratedValue>
                                    <name>1</name>
                                    <description>Non-secure</description>
                                    <value>#1</value>
                                </enumeratedValue>
                            </enumeratedValues>
                        </field>
                        <field>
                            <name>RSCSA1</name>
                            <description>RAM Standby Control Security Attribute bit n (n = 0 to 6)</description>
                            <lsb>1</lsb>
                            <msb>1</msb>
                            <access>read-write</access>
                            <enumeratedValues>
                                <enumeratedValue>
                                    <name>0</name>
                                    <description>Secure</description>
                                    <value>#0</value>
                                </enumeratedValue>
                                <enumeratedValue>
                                    <name>1</name>
                                    <description>Non-secure</description>
                                    <value>#1</value>
                                </enumeratedValue>
                            </enumeratedValues>
                        </field>
                        <field>
                            <name>RSCSA2</name>
                            <description>RAM Standby Control Security Attribute bit n (n = 0 to 6)</description>
                            <lsb>2</lsb>
                            <msb>2</msb>
                            <access>read-write</access>
                            <enumeratedValues>
                                <enumeratedValue>
                                    <name>0</name>
                                    <description>Secure</description>
                                    <value>#0</value>
                                </enumeratedValue>
                                <enumeratedValue>
                                    <name>1</name>
                                    <description>Non-secure</description>
                                    <value>#1</value>
                                </enumeratedValue>
                            </enumeratedValues>
                        </field>
                        <field>
                            <name>RSCSA3</name>
                            <description>RAM Standby Control Security Attribute bit n (n = 0 to 6)</description>
                            <lsb>3</lsb>
                            <msb>3</msb>
                            <access>read-write</access>
                            <enumeratedValues>
                                <enumeratedValue>
                                    <name>0</name>
                                    <description>Secure</description>
                                    <value>#0</value>
                                </enumeratedValue>
                                <enumeratedValue>
                                    <name>1</name>
                                    <description>Non-secure</description>
                                    <value>#1</value>
                                </enumeratedValue>
                            </enumeratedValues>
                        </field>
                        <field>
                            <name>RSCSA4</name>
                            <description>RAM Standby Control Security Attribute bit n (n = 0 to 6)</description>
                            <lsb>4</lsb>
                            <msb>4</msb>
                            <access>read-write</access>
                            <enumeratedValues>
                                <enumeratedValue>
                                    <name>0</name>
                                    <description>Secure</description>
                                    <value>#0</value>
                                </enumeratedValue>
                                <enumeratedValue>
                                    <name>1</name>
                                    <description>Non-secure</description>
                                    <value>#1</value>
                                </enumeratedValue>
                            </enumeratedValues>
                        </field>
                        <field>
                            <name>RSCSA5</name>
                            <description>RAM Standby Control Security Attribute bit n (n = 0 to 6)</description>
                            <lsb>5</lsb>
                            <msb>5</msb>
                            <access>read-write</access>
                            <enumeratedValues>
                                <enumeratedValue>
                                    <name>0</name>
                                    <description>Secure</description>
                                    <value>#0</value>
                                </enumeratedValue>
                                <enumeratedValue>
                                    <name>1</name>
                                    <description>Non-secure</description>
                                    <value>#1</value>
                                </enumeratedValue>
                            </enumeratedValues>
                        </field>
                        <field>
                            <name>RSCSA6</name>
                            <description>RAM Standby Control Security Attribute bit n (n = 0 to 6)</description>
                            <lsb>6</lsb>
                            <msb>6</msb>
                            <access>read-write</access>
                            <enumeratedValues>
                                <enumeratedValue>
                                    <name>0</name>
                                    <description>Secure</description>
                                    <value>#0</value>
                                </enumeratedValue>
                                <enumeratedValue>
                                    <name>1</name>
                                    <description>Non-secure</description>
                                    <value>#1</value>
                                </enumeratedValue>
                            </enumeratedValues>
                        </field>
                        <field>
                            <name>RSCSA16</name>
                            <description>RAM Standby Control Security Attribute bit n (n = 16)</description>
                            <lsb>16</lsb>
                            <msb>16</msb>
                            <access>read-write</access>
                            <enumeratedValues>
                                <enumeratedValue>
                                    <name>0</name>
                                    <description>Secure</description>
                                    <value>#0</value>
                                </enumeratedValue>
                                <enumeratedValue>
                                    <name>1</name>
                                    <description>Non-secure</description>
                                    <value>#1</value>
                                </enumeratedValue>
                            </enumeratedValues>
                        </field>
                    </fields>
                </register>
                <register>
                    <name>PRCR_S</name>
                    <description>Protect Register for Secure (PRCR_S)</description>
                    <addressOffset>0x3FA</addressOffset>
                    <size>16</size>
                    <access>read-write</access>
                    <resetValue>0x0000</resetValue>
                    <resetMask>0xffff</resetMask>
                    <fields>
                        <field>
                            <name>PRC0</name>
                            <description>Enable writing to the registers related to the clock generation circuit</description>
                            <lsb>0</lsb>
                            <msb>0</msb>
                            <access>read-write</access>
                            <enumeratedValues>
                                <enumeratedValue>
                                    <name>0</name>
                                    <description>Disable writes</description>
                                    <value>#0</value>
                                </enumeratedValue>
                                <enumeratedValue>
                                    <name>1</name>
                                    <description>Enable writes</description>
                                    <value>#1</value>
                                </enumeratedValue>
                            </enumeratedValues>
                        </field>
                        <field>
                            <name>PRC1</name>
                            <description>Enable writing to the registers related to the low power modes, and the battery backup function</description>
                            <lsb>1</lsb>
                            <msb>1</msb>
                            <access>read-write</access>
                            <enumeratedValues>
                                <enumeratedValue>
                                    <name>0</name>
                                    <description>Disable writes</description>
                                    <value>#0</value>
                                </enumeratedValue>
                                <enumeratedValue>
                                    <name>1</name>
                                    <description>Enable writes</description>
                                    <value>#1</value>
                                </enumeratedValue>
                            </enumeratedValues>
                        </field>
                        <field>
                            <name>PRC3</name>
                            <description>Enable writing to the registers related to the PVD</description>
                            <lsb>3</lsb>
                            <msb>3</msb>
                            <access>read-write</access>
                            <enumeratedValues>
                                <enumeratedValue>
                                    <name>0</name>
                                    <description>Disable writes</description>
                                    <value>#0</value>
                                </enumeratedValue>
                                <enumeratedValue>
                                    <name>1</name>
                                    <description>Enable writes</description>
                                    <value>#1</value>
                                </enumeratedValue>
                            </enumeratedValues>
                        </field>
                        <field>
                            <name>PRC4</name>
                            <lsb>4</lsb>
                            <msb>4</msb>
                            <access>read-write</access>
                            <enumeratedValues>
                                <enumeratedValue>
                                    <name>0</name>
                                    <description>Disable writes</description>
                                    <value>#0</value>
                                </enumeratedValue>
                                <enumeratedValue>
                                    <name>1</name>
                                    <description>Enable writes</description>
                                    <value>#1</value>
                                </enumeratedValue>
                            </enumeratedValues>
                        </field>
                        <field>
                            <name>PRC5</name>
                            <lsb>5</lsb>
                            <msb>5</msb>
                            <access>read-write</access>
                            <enumeratedValues>
                                <enumeratedValue>
                                    <name>0</name>
                                    <description>Disable writes</description>
                                    <value>#0</value>
                                </enumeratedValue>
                                <enumeratedValue>
                                    <name>1</name>
                                    <description>Enable writes</description>
                                    <value>#1</value>
                                </enumeratedValue>
                            </enumeratedValues>
                        </field>
                        <field>
                            <name>PRKEY</name>
                            <description>0xA5: Enables writing to the PRCR_S register.</description>
                            <lsb>8</lsb>
                            <msb>15</msb>
                            <access>write-only</access>
                        </field>
                    </fields>
                </register>
                <register>
                    <name>LOCOCR</name>
                    <description>Low-Speed On-Chip Oscillator Control Register</description>
                    <addressOffset>0x400</addressOffset>
                    <size>8</size>
                    <access>read-write</access>
                    <resetValue>0x00</resetValue>
                    <resetMask>0xff</resetMask>
                    <fields>
                        <field>
                            <name>LCSTP</name>
                            <description>LOCO Stop</description>
                            <lsb>0</lsb>
                            <msb>0</msb>
                            <access>read-write</access>
                            <enumeratedValues>
                                <enumeratedValue>
                                    <name>0</name>
                                    <description>Operate the LOCO clock</description>
                                    <value>#0</value>
                                </enumeratedValue>
                                <enumeratedValue>
                                    <name>1</name>
                                    <description>Stop the LOCO clock</description>
                                    <value>#1</value>
                                </enumeratedValue>
                            </enumeratedValues>
                        </field>
                    </fields>
                </register>
                <register>
                    <name>LOCOUTCR</name>
                    <description>LOCO User Trimming Control Register</description>
                    <addressOffset>0x402</addressOffset>
                    <size>8</size>
                    <access>read-write</access>
                    <resetValue>0x00</resetValue>
                    <resetMask>0xff</resetMask>
                    <fields>
                        <field>
                            <name>LOCOUTRM</name>
                            <description>LOCO User Trimming</description>
                            <lsb>0</lsb>
                            <msb>7</msb>
                            <access>read-write</access>
                        </field>
                    </fields>
                </register>
                <register>
                    <name>DPSBYCR</name>
                    <description>Deep Software Standby Control Register</description>
                    <addressOffset>0xA00</addressOffset>
                    <size>8</size>
                    <access>read-write</access>
                    <resetValue>0x10</resetValue>
                    <resetMask>0xff</resetMask>
                    <fields>
                        <field>
                            <name>DCSSMODE</name>
                            <lsb>2</lsb>
                            <msb>2</msb>
                            <access>read-write</access>
                            <enumeratedValues>
                                <enumeratedValue>
                                    <name>0</name>
                                    <description>When the Deep Software Standby mode is canceled, the time required to recover is the standard time.</description>
                                    <value>#0</value>
                                </enumeratedValue>
                                <enumeratedValue>
                                    <name>1</name>
                                    <description>When the Deep Software Standby mode is canceled, the time required to recover is shortened.</description>
                                    <value>#1</value>
                                </enumeratedValue>
                            </enumeratedValues>
                        </field>
                        <field>
                            <name>SRKEEP</name>
                            <description>Standby SRAM Retention</description>
                            <lsb>4</lsb>
                            <msb>4</msb>
                            <access>read-write</access>
                            <enumeratedValues>
                                <enumeratedValue>
                                    <name>0</name>
                                    <description>When entering the Software Standby mode or the Deep Software Standby mode 1, the contents of Standby SRAM are not kept.</description>
                                    <value>#0</value>
                                </enumeratedValue>
                                <enumeratedValue>
                                    <name>1</name>
                                    <description>When entering the Software Standby mode or the Deep Software Standby mode 1, the contents of Standby SRAM are kept.</description>
                                    <value>#1</value>
                                </enumeratedValue>
                            </enumeratedValues>
                        </field>
                        <field>
                            <name>IOKEEP</name>
                            <description>I/O Port Rentention</description>
                            <lsb>6</lsb>
                            <msb>6</msb>
                            <access>read-write</access>
                            <enumeratedValues>
                                <enumeratedValue>
                                    <name>0</name>
                                    <description>When the Deep Software Standby mode is canceled, the I/O ports are in the reset state.</description>
                                    <value>#0</value>
                                </enumeratedValue>
                                <enumeratedValue>
                                    <name>1</name>
                                    <description>When the Deep Software Standby mode is canceled, the I/O ports are in the same state as in the Deep Software Standby mode.</description>
                                    <value>#1</value>
                                </enumeratedValue>
                            </enumeratedValues>
                        </field>
                    </fields>
                </register>
                <register>
                    <name>DPSWCR</name>
                    <description>Deep Software Standby Wait Control Register</description>
                    <addressOffset>0xA04</addressOffset>
                    <size>8</size>
                    <access>read-write</access>
                    <resetValue>0x0b</resetValue>
                    <resetMask>0xff</resetMask>
                    <fields>
                        <field>
                            <name>WTSTS</name>
                            <description>Deep Software Wait Standby Time Setting Bit</description>
                            <lsb>0</lsb>
                            <msb>7</msb>
                            <access>read-write</access>
                            <enumeratedValues>
                                <enumeratedValue>
                                    <name>0x0B</name>
                                    <description>Wait cycle for fast recovery</description>
                                    <value>0x0b</value>
                                </enumeratedValue>
                                <enumeratedValue>
                                    <name>0x9A</name>
                                    <description>Wait cycle for slow recovery</description>
                                    <value>0x9a</value>
                                </enumeratedValue>
                                <enumeratedValue>
                                    <name>Others</name>
                                    <description>Setting prohibited</description>
                                    <isDefault>true</isDefault>
                                </enumeratedValue>
                            </enumeratedValues>
                        </field>
                    </fields>
                </register>
                <register>
                    <name>DPSIER0</name>
                    <description>Deep Software Standby Interrupt Enable Register 0</description>
                    <addressOffset>0xA08</addressOffset>
                    <size>8</size>
                    <access>read-write</access>
                    <resetValue>0x00</resetValue>
                    <resetMask>0xff</resetMask>
                    <fields>
                        <field>
                            <name>DIRQ0E</name>
                            <description>IRQ0-DS Pin Enable</description>
                            <lsb>0</lsb>
                            <msb>0</msb>
                            <access>read-write</access>
                            <enumeratedValues>
                                <enumeratedValue>
                                    <name>0</name>
                                    <description>Canceling Deep Software Standby mode is disabled</description>
                                    <value>#0</value>
                                </enumeratedValue>
                                <enumeratedValue>
                                    <name>1</name>
                                    <description>Canceling Deep Software Standby mode is enabled</description>
                                    <value>#1</value>
                                </enumeratedValue>
                            </enumeratedValues>
                        </field>
                        <field>
                            <name>DIRQ1E</name>
                            <description>IRQ1-DS Pin Enable</description>
                            <lsb>1</lsb>
                            <msb>1</msb>
                            <access>read-write</access>
                            <enumeratedValues>
                                <enumeratedValue>
                                    <name>0</name>
                                    <description>Canceling Deep Software Standby mode is disabled</description>
                                    <value>#0</value>
                                </enumeratedValue>
                                <enumeratedValue>
                                    <name>1</name>
                                    <description>Canceling Deep Software Standby mode is enabled</description>
                                    <value>#1</value>
                                </enumeratedValue>
                            </enumeratedValues>
                        </field>
                        <field>
                            <name>DIRQ2E</name>
                            <description>IRQ2-DS Pin Enable</description>
                            <lsb>2</lsb>
                            <msb>2</msb>
                            <access>read-write</access>
                            <enumeratedValues>
                                <enumeratedValue>
                                    <name>0</name>
                                    <description>Canceling Deep Software Standby mode is disabled</description>
                                    <value>#0</value>
                                </enumeratedValue>
                                <enumeratedValue>
                                    <name>1</name>
                                    <description>Canceling Deep Software Standby mode is enabled</description>
                                    <value>#1</value>
                                </enumeratedValue>
                            </enumeratedValues>
                        </field>
                        <field>
                            <name>DIRQ3E</name>
                            <description>IRQ3-DS Pin Enable</description>
                            <lsb>3</lsb>
                            <msb>3</msb>
                            <access>read-write</access>
                            <enumeratedValues>
                                <enumeratedValue>
                                    <name>0</name>
                                    <description>Canceling Deep Software Standby mode is disabled</description>
                                    <value>#0</value>
                                </enumeratedValue>
                                <enumeratedValue>
                                    <name>1</name>
                                    <description>Canceling Deep Software Standby mode is enabled</description>
                                    <value>#1</value>
                                </enumeratedValue>
                            </enumeratedValues>
                        </field>
                        <field>
                            <name>DIRQ4E</name>
                            <description>IRQ4-DS Pin Enable</description>
                            <lsb>4</lsb>
                            <msb>4</msb>
                            <access>read-write</access>
                            <enumeratedValues>
                                <enumeratedValue>
                                    <name>0</name>
                                    <description>Canceling Deep Software Standby mode is disabled</description>
                                    <value>#0</value>
                                </enumeratedValue>
                                <enumeratedValue>
                                    <name>1</name>
                                    <description>Canceling Deep Software Standby mode is enabled</description>
                                    <value>#1</value>
                                </enumeratedValue>
                            </enumeratedValues>
                        </field>
                        <field>
                            <name>DIRQ5E</name>
                            <description>IRQ5-DS Pin Enable</description>
                            <lsb>5</lsb>
                            <msb>5</msb>
                            <access>read-write</access>
                            <enumeratedValues>
                                <enumeratedValue>
                                    <name>0</name>
                                    <description>Canceling Deep Software Standby mode is disabled</description>
                                    <value>#0</value>
                                </enumeratedValue>
                                <enumeratedValue>
                                    <name>1</name>
                                    <description>Canceling Deep Software Standby mode is enabled</description>
                                    <value>#1</value>
                                </enumeratedValue>
                            </enumeratedValues>
                        </field>
                        <field>
                            <name>DIRQ6E</name>
                            <description>IRQ6-DS Pin Enable</description>
                            <lsb>6</lsb>
                            <msb>6</msb>
                            <access>read-write</access>
                            <enumeratedValues>
                                <enumeratedValue>
                                    <name>0</name>
                                    <description>Canceling Deep Software Standby mode is disabled</description>
                                    <value>#0</value>
                                </enumeratedValue>
                                <enumeratedValue>
                                    <name>1</name>
                                    <description>Canceling Deep Software Standby mode is enabled</description>
                                    <value>#1</value>
                                </enumeratedValue>
                            </enumeratedValues>
                        </field>
                        <field>
                            <name>DIRQ7E</name>
                            <description>IRQ7-DS Pin Enable</description>
                            <lsb>7</lsb>
                            <msb>7</msb>
                            <access>read-write</access>
                            <enumeratedValues>
                                <enumeratedValue>
                                    <name>0</name>
                                    <description>Canceling Deep Software Standby mode is disabled</description>
                                    <value>#0</value>
                                </enumeratedValue>
                                <enumeratedValue>
                                    <name>1</name>
                                    <description>Canceling Deep Software Standby mode is enabled</description>
                                    <value>#1</value>
                                </enumeratedValue>
                            </enumeratedValues>
                        </field>
                    </fields>
                </register>
                <register>
                    <name>DPSIER1</name>
                    <description>Deep Software Standby Interrupt Enable Register 1</description>
                    <addressOffset>0xA0C</addressOffset>
                    <size>8</size>
                    <access>read-write</access>
                    <resetValue>0x00</resetValue>
                    <resetMask>0xff</resetMask>
                    <fields>
                        <field>
                            <name>DIRQ8E</name>
                            <description>IRQ8-DS Pin Enable</description>
                            <lsb>0</lsb>
                            <msb>0</msb>
                            <access>read-write</access>
                            <enumeratedValues>
                                <enumeratedValue>
                                    <name>0</name>
                                    <description>Canceling Deep Software Standby mode is disabled</description>
                                    <value>#0</value>
                                </enumeratedValue>
                                <enumeratedValue>
                                    <name>1</name>
                                    <description>Canceling Deep Software Standby mode is enabled</description>
                                    <value>#1</value>
                                </enumeratedValue>
                            </enumeratedValues>
                        </field>
                        <field>
                            <name>DIRQ9E</name>
                            <description>IRQ9-DS Pin Enable</description>
                            <lsb>1</lsb>
                            <msb>1</msb>
                            <access>read-write</access>
                            <enumeratedValues>
                                <enumeratedValue>
                                    <name>0</name>
                                    <description>Canceling Deep Software Standby mode is disabled</description>
                                    <value>#0</value>
                                </enumeratedValue>
                                <enumeratedValue>
                                    <name>1</name>
                                    <description>Canceling Deep Software Standby mode is enabled</description>
                                    <value>#1</value>
                                </enumeratedValue>
                            </enumeratedValues>
                        </field>
                        <field>
                            <name>DIRQ10E</name>
                            <description>IRQ10-DS Pin Enable</description>
                            <lsb>2</lsb>
                            <msb>2</msb>
                            <access>read-write</access>
                            <enumeratedValues>
                                <enumeratedValue>
                                    <name>0</name>
                                    <description>Canceling Deep Software Standby mode is disabled</description>
                                    <value>#0</value>
                                </enumeratedValue>
                                <enumeratedValue>
                                    <name>1</name>
                                    <description>Canceling Deep Software Standby mode is enabled</description>
                                    <value>#1</value>
                                </enumeratedValue>
                            </enumeratedValues>
                        </field>
                        <field>
                            <name>DIRQ11E</name>
                            <description>IRQ11-DS Pin Enable</description>
                            <lsb>3</lsb>
                            <msb>3</msb>
                            <access>read-write</access>
                            <enumeratedValues>
                                <enumeratedValue>
                                    <name>0</name>
                                    <description>Canceling Deep Software Standby mode is disabled</description>
                                    <value>#0</value>
                                </enumeratedValue>
                                <enumeratedValue>
                                    <name>1</name>
                                    <description>Canceling Deep Software Standby mode is enabled</description>
                                    <value>#1</value>
                                </enumeratedValue>
                            </enumeratedValues>
                        </field>
                        <field>
                            <name>DIRQ12E</name>
                            <description>IRQ12-DS Pin Enable</description>
                            <lsb>4</lsb>
                            <msb>4</msb>
                            <access>read-write</access>
                            <enumeratedValues>
                                <enumeratedValue>
                                    <name>0</name>
                                    <description>Canceling Deep Software Standby mode is disabled</description>
                                    <value>#0</value>
                                </enumeratedValue>
                                <enumeratedValue>
                                    <name>1</name>
                                    <description>Canceling Deep Software Standby mode is enabled</description>
                                    <value>#1</value>
                                </enumeratedValue>
                            </enumeratedValues>
                        </field>
                        <field>
                            <name>DIRQ13E</name>
                            <description>IRQ13-DS Pin Enable</description>
                            <lsb>5</lsb>
                            <msb>5</msb>
                            <access>read-write</access>
                            <enumeratedValues>
                                <enumeratedValue>
                                    <name>0</name>
                                    <description>Canceling Deep Software Standby mode is disabled</description>
                                    <value>#0</value>
                                </enumeratedValue>
                                <enumeratedValue>
                                    <name>1</name>
                                    <description>Canceling Deep Software Standby mode is enabled</description>
                                    <value>#1</value>
                                </enumeratedValue>
                            </enumeratedValues>
                        </field>
                        <field>
                            <name>DIRQ14E</name>
                            <description>IRQ14-DS Pin Enable</description>
                            <lsb>6</lsb>
                            <msb>6</msb>
                            <access>read-write</access>
                            <enumeratedValues>
                                <enumeratedValue>
                                    <name>0</name>
                                    <description>Canceling Deep Software Standby mode is disabled</description>
                                    <value>#0</value>
                                </enumeratedValue>
                                <enumeratedValue>
                                    <name>1</name>
                                    <description>Canceling Deep Software Standby mode is enabled</description>
                                    <value>#1</value>
                                </enumeratedValue>
                            </enumeratedValues>
                        </field>
                        <field>
                            <name>DIRQ15E</name>
                            <description>IRQ15-DS Pin Enable</description>
                            <lsb>7</lsb>
                            <msb>7</msb>
                            <access>read-write</access>
                            <enumeratedValues>
                                <enumeratedValue>
                                    <name>0</name>
                                    <description>Canceling Deep Software Standby mode is disabled</description>
                                    <value>#0</value>
                                </enumeratedValue>
                                <enumeratedValue>
                                    <name>1</name>
                                    <description>Canceling Deep Software Standby mode is enabled</description>
                                    <value>#1</value>
                                </enumeratedValue>
                            </enumeratedValues>
                        </field>
                    </fields>
                </register>
                <register>
                    <name>DPSIER2</name>
                    <description>Deep Software Standby Interrupt Enable Register 2</description>
                    <addressOffset>0xA10</addressOffset>
                    <size>8</size>
                    <access>read-write</access>
                    <resetValue>0x00</resetValue>
                    <resetMask>0xff</resetMask>
                    <fields>
                        <field>
                            <name>DPVD1IE</name>
                            <description>PVD1 Deep Software Standby Cancel Signal Enable</description>
                            <lsb>0</lsb>
                            <msb>0</msb>
                            <access>read-write</access>
                            <enumeratedValues>
                                <enumeratedValue>
                                    <name>0</name>
                                    <description>Canceling Deep Software Standby mode is disabled</description>
                                    <value>#0</value>
                                </enumeratedValue>
                                <enumeratedValue>
                                    <name>1</name>
                                    <description>Canceling Deep Software Standby mode is enabled</description>
                                    <value>#1</value>
                                </enumeratedValue>
                            </enumeratedValues>
                        </field>
                        <field>
                            <name>DPVD2IE</name>
                            <description>PVD2 Deep Software Standby Cancel Signal Enable</description>
                            <lsb>1</lsb>
                            <msb>1</msb>
                            <access>read-write</access>
                            <enumeratedValues>
                                <enumeratedValue>
                                    <name>0</name>
                                    <description>Canceling Deep Software Standby mode is disabled</description>
                                    <value>#0</value>
                                </enumeratedValue>
                                <enumeratedValue>
                                    <name>1</name>
                                    <description>Canceling Deep Software Standby mode is enabled</description>
                                    <value>#1</value>
                                </enumeratedValue>
                            </enumeratedValues>
                        </field>
                        <field>
                            <name>DRTCIIE</name>
                            <description>RTC Interval interrupt Deep Software Standby Cancel Signal Enable</description>
                            <lsb>2</lsb>
                            <msb>2</msb>
                            <access>read-write</access>
                            <enumeratedValues>
                                <enumeratedValue>
                                    <name>0</name>
                                    <description>Canceling Deep Software Standby mode is disabled</description>
                                    <value>#0</value>
                                </enumeratedValue>
                                <enumeratedValue>
                                    <name>1</name>
                                    <description>Canceling Deep Software Standby mode is enabled</description>
                                    <value>#1</value>
                                </enumeratedValue>
                            </enumeratedValues>
                        </field>
                        <field>
                            <name>DRTCAIE</name>
                            <description>RTC Alarm interrupt Deep Software Standby Cancel Signal Enable</description>
                            <lsb>3</lsb>
                            <msb>3</msb>
                            <access>read-write</access>
                            <enumeratedValues>
                                <enumeratedValue>
                                    <name>0</name>
                                    <description>Canceling Deep Software Standby mode is disabled</description>
                                    <value>#0</value>
                                </enumeratedValue>
                                <enumeratedValue>
                                    <name>1</name>
                                    <description>Canceling Deep Software Standby mode is enabled</description>
                                    <value>#1</value>
                                </enumeratedValue>
                            </enumeratedValues>
                        </field>
                        <field>
                            <name>DNMIE</name>
                            <description>NMI Pin Deep Software Standby Cancel Signal Enable</description>
                            <lsb>4</lsb>
                            <msb>4</msb>
                            <access>read-write</access>
                            <enumeratedValues>
                                <enumeratedValue>
                                    <name>0</name>
                                    <description>Canceling Deep Software Standby mode is disabled</description>
                                    <value>#0</value>
                                </enumeratedValue>
                                <enumeratedValue>
                                    <name>1</name>
                                    <description>Canceling Deep Software Standby mode is enabled</description>
                                    <value>#1</value>
                                </enumeratedValue>
                            </enumeratedValues>
                        </field>
                    </fields>
                </register>
                <register>
                    <name>DPSIER3</name>
                    <description>Deep Software Standby Interrupt Enable Register 3</description>
                    <addressOffset>0xA14</addressOffset>
                    <size>8</size>
                    <access>read-write</access>
                    <resetValue>0x00</resetValue>
                    <resetMask>0xff</resetMask>
                    <fields>
                        <field>
                            <name>DUSBFSIE</name>
                            <description>USBFS Suspend/Resume Deep Software Standby Cancel Signal Enable</description>
                            <lsb>0</lsb>
                            <msb>0</msb>
                            <access>read-write</access>
                            <enumeratedValues>
                                <enumeratedValue>
                                    <name>0</name>
                                    <description>Canceling Deep Software Standby mode is disabled</description>
                                    <value>#0</value>
                                </enumeratedValue>
                                <enumeratedValue>
                                    <name>1</name>
                                    <description>Canceling Deep Software Standby mode is enabled</description>
                                    <value>#1</value>
                                </enumeratedValue>
                            </enumeratedValues>
                        </field>
                        <field>
                            <name>DUSBHSIE</name>
                            <description>USBHS Suspend/Resume Deep Software Standby Cancel Signal Enable</description>
                            <lsb>1</lsb>
                            <msb>1</msb>
                            <access>read-write</access>
                            <enumeratedValues>
                                <enumeratedValue>
                                    <name>0</name>
                                    <description>Canceling Deep Software Standby mode is disabled</description>
                                    <value>#0</value>
                                </enumeratedValue>
                                <enumeratedValue>
                                    <name>1</name>
                                    <description>Canceling Deep Software Standby mode is enabled</description>
                                    <value>#1</value>
                                </enumeratedValue>
                            </enumeratedValues>
                        </field>
                        <field>
                            <name>DULPT0IE</name>
                            <description>ULPT0 Overflow Deep Software Standby Cancel Signal Enable</description>
                            <lsb>2</lsb>
                            <msb>2</msb>
                            <access>read-write</access>
                            <enumeratedValues>
                                <enumeratedValue>
                                    <name>0</name>
                                    <description>Canceling Deep Software Standby mode is disabled</description>
                                    <value>#0</value>
                                </enumeratedValue>
                                <enumeratedValue>
                                    <name>1</name>
                                    <description>Canceling Deep Software Standby mode is enabled</description>
                                    <value>#1</value>
                                </enumeratedValue>
                            </enumeratedValues>
                        </field>
                        <field>
                            <name>DULPT1IE</name>
                            <description>ULPT1 Overflow Deep Software Standby Cancel Signal Enable</description>
                            <lsb>3</lsb>
                            <msb>3</msb>
                            <access>read-write</access>
                            <enumeratedValues>
                                <enumeratedValue>
                                    <name>0</name>
                                    <description>Canceling Deep Software Standby mode is disabled</description>
                                    <value>#0</value>
                                </enumeratedValue>
                                <enumeratedValue>
                                    <name>1</name>
                                    <description>Canceling Deep Software Standby mode is enabled</description>
                                    <value>#1</value>
                                </enumeratedValue>
                            </enumeratedValues>
                        </field>
                        <field>
                            <name>DIWDTIE</name>
                            <description>IWDT Underflow Deep Software Standby Cancel Signal Enable</description>
                            <lsb>5</lsb>
                            <msb>5</msb>
                            <access>read-write</access>
                            <enumeratedValues>
                                <enumeratedValue>
                                    <name>0</name>
                                    <description>Canceling Deep Software Standby mode is disabled</description>
                                    <value>#0</value>
                                </enumeratedValue>
                                <enumeratedValue>
                                    <name>1</name>
                                    <description>Canceling Deep Software Standby mode is enabled</description>
                                    <value>#1</value>
                                </enumeratedValue>
                            </enumeratedValues>
                        </field>
                        <field>
                            <name>DVBATTADIE</name>
                            <description>VBATT Tamper Detection Deep Software Standby Cancel Signal Enable</description>
                            <lsb>7</lsb>
                            <msb>7</msb>
                            <access>read-write</access>
                            <enumeratedValues>
                                <enumeratedValue>
                                    <name>0</name>
                                    <description>Canceling Deep Software Standby mode is disabled</description>
                                    <value>#0</value>
                                </enumeratedValue>
                                <enumeratedValue>
                                    <name>1</name>
                                    <description>Canceling Deep Software Standby mode is enabled</description>
                                    <value>#1</value>
                                </enumeratedValue>
                            </enumeratedValues>
                        </field>
                    </fields>
                </register>
                <register>
                    <name>DPSIFR0</name>
                    <description>Deep Software Standby Interrupt Flag Register 0</description>
                    <addressOffset>0xA18</addressOffset>
                    <size>8</size>
                    <access>read-write</access>
                    <resetValue>0x00</resetValue>
                    <resetMask>0xff</resetMask>
                    <fields>
                        <field>
                            <name>DIRQ0F</name>
                            <description>IRQ0-DS Pin Deep Software Standby Cancel Flag</description>
                            <lsb>0</lsb>
                            <msb>0</msb>
                            <access>read-write</access>
                            <enumeratedValues>
                                <enumeratedValue>
                                    <name>0</name>
                                    <description>The cancel request is not generated</description>
                                    <value>#0</value>
                                </enumeratedValue>
                                <enumeratedValue>
                                    <name>1</name>
                                    <description>The cancel request is generated</description>
                                    <value>#1</value>
                                </enumeratedValue>
                            </enumeratedValues>
                        </field>
                        <field>
                            <name>DIRQ1F</name>
                            <description>IRQ1-DS Pin Deep Software Standby Cancel Flag</description>
                            <lsb>1</lsb>
                            <msb>1</msb>
                            <access>read-write</access>
                            <enumeratedValues>
                                <enumeratedValue>
                                    <name>0</name>
                                    <description>The cancel request is not generated</description>
                                    <value>#0</value>
                                </enumeratedValue>
                                <enumeratedValue>
                                    <name>1</name>
                                    <description>The cancel request is generated</description>
                                    <value>#1</value>
                                </enumeratedValue>
                            </enumeratedValues>
                        </field>
                        <field>
                            <name>DIRQ2F</name>
                            <description>IRQ2-DS Pin Deep Software Standby Cancel Flag</description>
                            <lsb>2</lsb>
                            <msb>2</msb>
                            <access>read-write</access>
                            <enumeratedValues>
                                <enumeratedValue>
                                    <name>0</name>
                                    <description>The cancel request is not generated</description>
                                    <value>#0</value>
                                </enumeratedValue>
                                <enumeratedValue>
                                    <name>1</name>
                                    <description>The cancel request is generated</description>
                                    <value>#1</value>
                                </enumeratedValue>
                            </enumeratedValues>
                        </field>
                        <field>
                            <name>DIRQ3F</name>
                            <description>IRQ3-DS Pin Deep Software Standby Cancel Flag</description>
                            <lsb>3</lsb>
                            <msb>3</msb>
                            <access>read-write</access>
                            <enumeratedValues>
                                <enumeratedValue>
                                    <name>0</name>
                                    <description>The cancel request is not generated</description>
                                    <value>#0</value>
                                </enumeratedValue>
                                <enumeratedValue>
                                    <name>1</name>
                                    <description>The cancel request is generated</description>
                                    <value>#1</value>
                                </enumeratedValue>
                            </enumeratedValues>
                        </field>
                        <field>
                            <name>DIRQ4F</name>
                            <description>IRQ4-DS Pin Deep Software Standby Cancel Flag</description>
                            <lsb>4</lsb>
                            <msb>4</msb>
                            <access>read-write</access>
                            <enumeratedValues>
                                <enumeratedValue>
                                    <name>0</name>
                                    <description>The cancel request is not generated</description>
                                    <value>#0</value>
                                </enumeratedValue>
                                <enumeratedValue>
                                    <name>1</name>
                                    <description>The cancel request is generated</description>
                                    <value>#1</value>
                                </enumeratedValue>
                            </enumeratedValues>
                        </field>
                        <field>
                            <name>DIRQ5F</name>
                            <description>IRQ5-DS Pin Deep Software Standby Cancel Flag</description>
                            <lsb>5</lsb>
                            <msb>5</msb>
                            <access>read-write</access>
                            <enumeratedValues>
                                <enumeratedValue>
                                    <name>0</name>
                                    <description>The cancel request is not generated</description>
                                    <value>#0</value>
                                </enumeratedValue>
                                <enumeratedValue>
                                    <name>1</name>
                                    <description>The cancel request is generated</description>
                                    <value>#1</value>
                                </enumeratedValue>
                            </enumeratedValues>
                        </field>
                        <field>
                            <name>DIRQ6F</name>
                            <description>IRQ6-DS Pin Deep Software Standby Cancel Flag</description>
                            <lsb>6</lsb>
                            <msb>6</msb>
                            <access>read-write</access>
                            <enumeratedValues>
                                <enumeratedValue>
                                    <name>0</name>
                                    <description>The cancel request is not generated</description>
                                    <value>#0</value>
                                </enumeratedValue>
                                <enumeratedValue>
                                    <name>1</name>
                                    <description>The cancel request is generated</description>
                                    <value>#1</value>
                                </enumeratedValue>
                            </enumeratedValues>
                        </field>
                        <field>
                            <name>DIRQ7F</name>
                            <description>IRQ7-DS Pin Deep Software Standby Cancel Flag</description>
                            <lsb>7</lsb>
                            <msb>7</msb>
                            <access>read-write</access>
                            <enumeratedValues>
                                <enumeratedValue>
                                    <name>0</name>
                                    <description>The cancel request is not generated</description>
                                    <value>#0</value>
                                </enumeratedValue>
                                <enumeratedValue>
                                    <name>1</name>
                                    <description>The cancel request is generated</description>
                                    <value>#1</value>
                                </enumeratedValue>
                            </enumeratedValues>
                        </field>
                    </fields>
                </register>
                <register>
                    <name>DPSIFR1</name>
                    <description>Deep Software Standby Interrupt Flag Register 1</description>
                    <addressOffset>0xA1C</addressOffset>
                    <size>8</size>
                    <access>read-write</access>
                    <resetValue>0x00</resetValue>
                    <resetMask>0xff</resetMask>
                    <fields>
                        <field>
                            <name>DIRQ8F</name>
                            <description>IRQ8-DS Pin Deep Software Standby Cancel Flag</description>
                            <lsb>0</lsb>
                            <msb>0</msb>
                            <access>read-write</access>
                            <enumeratedValues>
                                <enumeratedValue>
                                    <name>0</name>
                                    <description>The cancel request is not generated</description>
                                    <value>#0</value>
                                </enumeratedValue>
                                <enumeratedValue>
                                    <name>1</name>
                                    <description>The cancel request is generated</description>
                                    <value>#1</value>
                                </enumeratedValue>
                            </enumeratedValues>
                        </field>
                        <field>
                            <name>DIRQ9F</name>
                            <description>IRQ9-DS Pin Deep Software Standby Cancel Flag</description>
                            <lsb>1</lsb>
                            <msb>1</msb>
                            <access>read-write</access>
                            <enumeratedValues>
                                <enumeratedValue>
                                    <name>0</name>
                                    <description>The cancel request is not generated</description>
                                    <value>#0</value>
                                </enumeratedValue>
                                <enumeratedValue>
                                    <name>1</name>
                                    <description>The cancel request is generated</description>
                                    <value>#1</value>
                                </enumeratedValue>
                            </enumeratedValues>
                        </field>
                        <field>
                            <name>DIRQ10F</name>
                            <description>IRQ10-DS Pin Deep Software Standby Cancel Flag</description>
                            <lsb>2</lsb>
                            <msb>2</msb>
                            <access>read-write</access>
                            <enumeratedValues>
                                <enumeratedValue>
                                    <name>0</name>
                                    <description>The cancel request is not generated</description>
                                    <value>#0</value>
                                </enumeratedValue>
                                <enumeratedValue>
                                    <name>1</name>
                                    <description>The cancel request is generated</description>
                                    <value>#1</value>
                                </enumeratedValue>
                            </enumeratedValues>
                        </field>
                        <field>
                            <name>DIRQ11F</name>
                            <description>IRQ11-DS Pin Deep Software Standby Cancel Flag</description>
                            <lsb>3</lsb>
                            <msb>3</msb>
                            <access>read-write</access>
                            <enumeratedValues>
                                <enumeratedValue>
                                    <name>0</name>
                                    <description>The cancel request is not generated</description>
                                    <value>#0</value>
                                </enumeratedValue>
                                <enumeratedValue>
                                    <name>1</name>
                                    <description>The cancel request is generated</description>
                                    <value>#1</value>
                                </enumeratedValue>
                            </enumeratedValues>
                        </field>
                        <field>
                            <name>DIRQ12F</name>
                            <description>IRQ12-DS Pin Deep Software Standby Cancel Flag</description>
                            <lsb>4</lsb>
                            <msb>4</msb>
                            <access>read-write</access>
                            <enumeratedValues>
                                <enumeratedValue>
                                    <name>0</name>
                                    <description>The cancel request is not generated</description>
                                    <value>#0</value>
                                </enumeratedValue>
                                <enumeratedValue>
                                    <name>1</name>
                                    <description>The cancel request is generated</description>
                                    <value>#1</value>
                                </enumeratedValue>
                            </enumeratedValues>
                        </field>
                        <field>
                            <name>DIRQ13F</name>
                            <description>IRQ13-DS Pin Deep Software Standby Cancel Flag</description>
                            <lsb>5</lsb>
                            <msb>5</msb>
                            <access>read-write</access>
                            <enumeratedValues>
                                <enumeratedValue>
                                    <name>0</name>
                                    <description>The cancel request is not generated</description>
                                    <value>#0</value>
                                </enumeratedValue>
                                <enumeratedValue>
                                    <name>1</name>
                                    <description>The cancel request is generated</description>
                                    <value>#1</value>
                                </enumeratedValue>
                            </enumeratedValues>
                        </field>
                        <field>
                            <name>DIRQ14F</name>
                            <description>IRQ14-DS Pin Deep Software Standby Cancel Flag</description>
                            <lsb>6</lsb>
                            <msb>6</msb>
                            <access>read-write</access>
                            <enumeratedValues>
                                <enumeratedValue>
                                    <name>0</name>
                                    <description>The cancel request is not generated</description>
                                    <value>#0</value>
                                </enumeratedValue>
                                <enumeratedValue>
                                    <name>1</name>
                                    <description>The cancel request is generated</description>
                                    <value>#1</value>
                                </enumeratedValue>
                            </enumeratedValues>
                        </field>
                        <field>
                            <name>DIRQ15F</name>
                            <description>IRQ15-DS Pin Deep Software Standby Cancel Flag</description>
                            <lsb>7</lsb>
                            <msb>7</msb>
                            <access>read-write</access>
                            <enumeratedValues>
                                <enumeratedValue>
                                    <name>0</name>
                                    <description>The cancel request is not generated</description>
                                    <value>#0</value>
                                </enumeratedValue>
                                <enumeratedValue>
                                    <name>1</name>
                                    <description>The cancel request is generated</description>
                                    <value>#1</value>
                                </enumeratedValue>
                            </enumeratedValues>
                        </field>
                    </fields>
                </register>
                <register>
                    <name>DPSIFR2</name>
                    <description>Deep Software Standby Interrupt Flag Register 2</description>
                    <addressOffset>0xA20</addressOffset>
                    <size>8</size>
                    <access>read-write</access>
                    <resetValue>0x00</resetValue>
                    <resetMask>0xff</resetMask>
                    <fields>
                        <field>
                            <name>DPVD1IF</name>
                            <description>PVD1 Deep Software Standby Cancel Flag</description>
                            <lsb>0</lsb>
                            <msb>0</msb>
                            <access>read-write</access>
                            <enumeratedValues>
                                <enumeratedValue>
                                    <name>0</name>
                                    <description>The cancel request is not generated</description>
                                    <value>#0</value>
                                </enumeratedValue>
                                <enumeratedValue>
                                    <name>1</name>
                                    <description>The cancel request is generated</description>
                                    <value>#1</value>
                                </enumeratedValue>
                            </enumeratedValues>
                        </field>
                        <field>
                            <name>DPVD2IF</name>
                            <description>PVD2 Deep Software Standby Cancel Flag</description>
                            <lsb>1</lsb>
                            <msb>1</msb>
                            <access>read-write</access>
                            <enumeratedValues>
                                <enumeratedValue>
                                    <name>0</name>
                                    <description>The cancel request is not generated</description>
                                    <value>#0</value>
                                </enumeratedValue>
                                <enumeratedValue>
                                    <name>1</name>
                                    <description>The cancel request is generated</description>
                                    <value>#1</value>
                                </enumeratedValue>
                            </enumeratedValues>
                        </field>
                        <field>
                            <name>DRTCIIF</name>
                            <description>RTC Interval Interrupt Deep Software Standby Cancel Flag</description>
                            <lsb>2</lsb>
                            <msb>2</msb>
                            <access>read-write</access>
                            <enumeratedValues>
                                <enumeratedValue>
                                    <name>0</name>
                                    <description>The cancel request is not generated</description>
                                    <value>#0</value>
                                </enumeratedValue>
                                <enumeratedValue>
                                    <name>1</name>
                                    <description>The cancel request is generated</description>
                                    <value>#1</value>
                                </enumeratedValue>
                            </enumeratedValues>
                        </field>
                        <field>
                            <name>DRTCAIF</name>
                            <description>RTC Alarm Interrupt Deep Software Standby Cancel Flag</description>
                            <lsb>3</lsb>
                            <msb>3</msb>
                            <access>read-write</access>
                            <enumeratedValues>
                                <enumeratedValue>
                                    <name>0</name>
                                    <description>The cancel request is not generated</description>
                                    <value>#0</value>
                                </enumeratedValue>
                                <enumeratedValue>
                                    <name>1</name>
                                    <description>The cancel request is generated</description>
                                    <value>#1</value>
                                </enumeratedValue>
                            </enumeratedValues>
                        </field>
                        <field>
                            <name>DNMIF</name>
                            <description>NMI Pin Deep Software Standby Cancel Flag</description>
                            <lsb>4</lsb>
                            <msb>4</msb>
                            <access>read-write</access>
                            <enumeratedValues>
                                <enumeratedValue>
                                    <name>0</name>
                                    <description>The cancel request is not generated</description>
                                    <value>#0</value>
                                </enumeratedValue>
                                <enumeratedValue>
                                    <name>1</name>
                                    <description>The cancel request is generated</description>
                                    <value>#1</value>
                                </enumeratedValue>
                            </enumeratedValues>
                        </field>
                    </fields>
                </register>
                <register>
                    <name>DPSIFR3</name>
                    <description>Deep Software Standby Interrupt Flag Register 3</description>
                    <addressOffset>0xA24</addressOffset>
                    <size>8</size>
                    <access>read-write</access>
                    <resetValue>0x00</resetValue>
                    <resetMask>0xff</resetMask>
                    <fields>
                        <field>
                            <name>DUSBFSIF</name>
                            <description>USBFS Suspend/Resume Deep Software Standby Cancel Flag</description>
                            <lsb>0</lsb>
                            <msb>0</msb>
                            <access>read-write</access>
                            <enumeratedValues>
                                <enumeratedValue>
                                    <name>0</name>
                                    <description>The cancel request is not generated</description>
                                    <value>#0</value>
                                </enumeratedValue>
                                <enumeratedValue>
                                    <name>1</name>
                                    <description>The cancel request is generated</description>
                                    <value>#1</value>
                                </enumeratedValue>
                            </enumeratedValues>
                        </field>
                        <field>
                            <name>DUSBHSIF</name>
                            <description>USBHS Suspend/Resume Deep Software Standby Cancel Flag</description>
                            <lsb>1</lsb>
                            <msb>1</msb>
                            <access>read-write</access>
                            <enumeratedValues>
                                <enumeratedValue>
                                    <name>0</name>
                                    <description>The cancel request is not generated</description>
                                    <value>#0</value>
                                </enumeratedValue>
                                <enumeratedValue>
                                    <name>1</name>
                                    <description>The cancel request is generated</description>
                                    <value>#1</value>
                                </enumeratedValue>
                            </enumeratedValues>
                        </field>
                        <field>
                            <name>DULPT0IF</name>
                            <description>ULPT0 Overflow Deep Software Standby Cancel Flag</description>
                            <lsb>2</lsb>
                            <msb>2</msb>
                            <access>read-write</access>
                            <enumeratedValues>
                                <enumeratedValue>
                                    <name>0</name>
                                    <description>The cancel request is not generated</description>
                                    <value>#0</value>
                                </enumeratedValue>
                                <enumeratedValue>
                                    <name>1</name>
                                    <description>The cancel request is generated</description>
                                    <value>#1</value>
                                </enumeratedValue>
                            </enumeratedValues>
                        </field>
                        <field>
                            <name>DULPT1IF</name>
                            <description>ULPT1 Overflow Deep Software Standby Cancel Flag</description>
                            <lsb>3</lsb>
                            <msb>3</msb>
                            <access>read-write</access>
                            <enumeratedValues>
                                <enumeratedValue>
                                    <name>0</name>
                                    <description>The cancel request is not generated</description>
                                    <value>#0</value>
                                </enumeratedValue>
                                <enumeratedValue>
                                    <name>1</name>
                                    <description>The cancel request is generated</description>
                                    <value>#1</value>
                                </enumeratedValue>
                            </enumeratedValues>
                        </field>
                        <field>
                            <name>DIWDTIF</name>
                            <description>IWDT Underflow Deep Software Standby Cancel Flag</description>
                            <lsb>5</lsb>
                            <msb>5</msb>
                            <access>read-write</access>
                            <enumeratedValues>
                                <enumeratedValue>
                                    <name>0</name>
                                    <description>The cancel request is not generated</description>
                                    <value>#0</value>
                                </enumeratedValue>
                                <enumeratedValue>
                                    <name>1</name>
                                    <description>The cancel request is generated</description>
                                    <value>#1</value>
                                </enumeratedValue>
                            </enumeratedValues>
                        </field>
                        <field>
                            <name>DVBATTADIF</name>
                            <description>VBATT Tamper Detection Deep Software Standby Cancel Flag</description>
                            <lsb>7</lsb>
                            <msb>7</msb>
                            <access>read-write</access>
                            <enumeratedValues>
                                <enumeratedValue>
                                    <name>0</name>
                                    <description>The cancel request is not generated</description>
                                    <value>#0</value>
                                </enumeratedValue>
                                <enumeratedValue>
                                    <name>1</name>
                                    <description>The cancel request is generated</description>
                                    <value>#1</value>
                                </enumeratedValue>
                            </enumeratedValues>
                        </field>
                    </fields>
                </register>
                <register>
                    <name>DPSIEGR0</name>
                    <description>Deep Software Standby Interrupt Edge Register 0</description>
                    <addressOffset>0xA28</addressOffset>
                    <size>8</size>
                    <access>read-write</access>
                    <resetValue>0x00</resetValue>
                    <resetMask>0xff</resetMask>
                    <fields>
                        <field>
                            <name>DIRQ0EG</name>
                            <description>IRQ0-DS Pin Edge Select</description>
                            <lsb>0</lsb>
                            <msb>0</msb>
                            <access>read-write</access>
                            <enumeratedValues>
                                <enumeratedValue>
                                    <name>0</name>
                                    <description>A cancel request is generated at a falling edge</description>
                                    <value>#0</value>
                                </enumeratedValue>
                                <enumeratedValue>
                                    <name>1</name>
                                    <description>A cancel request is generated at a rising edge</description>
                                    <value>#1</value>
                                </enumeratedValue>
                            </enumeratedValues>
                        </field>
                        <field>
                            <name>DIRQ1EG</name>
                            <description>IRQ1-DS Pin Edge Select</description>
                            <lsb>1</lsb>
                            <msb>1</msb>
                            <access>read-write</access>
                            <enumeratedValues>
                                <enumeratedValue>
                                    <name>0</name>
                                    <description>A cancel request is generated at a falling edge</description>
                                    <value>#0</value>
                                </enumeratedValue>
                                <enumeratedValue>
                                    <name>1</name>
                                    <description>A cancel request is generated at a rising edge</description>
                                    <value>#1</value>
                                </enumeratedValue>
                            </enumeratedValues>
                        </field>
                        <field>
                            <name>DIRQ2EG</name>
                            <description>IRQ2-DS Pin Edge Select</description>
                            <lsb>2</lsb>
                            <msb>2</msb>
                            <access>read-write</access>
                            <enumeratedValues>
                                <enumeratedValue>
                                    <name>0</name>
                                    <description>A cancel request is generated at a falling edge</description>
                                    <value>#0</value>
                                </enumeratedValue>
                                <enumeratedValue>
                                    <name>1</name>
                                    <description>A cancel request is generated at a rising edge</description>
                                    <value>#1</value>
                                </enumeratedValue>
                            </enumeratedValues>
                        </field>
                        <field>
                            <name>DIRQ3EG</name>
                            <description>IRQ3-DS Pin Edge Select</description>
                            <lsb>3</lsb>
                            <msb>3</msb>
                            <access>read-write</access>
                            <enumeratedValues>
                                <enumeratedValue>
                                    <name>0</name>
                                    <description>A cancel request is generated at a falling edge</description>
                                    <value>#0</value>
                                </enumeratedValue>
                                <enumeratedValue>
                                    <name>1</name>
                                    <description>A cancel request is generated at a rising edge</description>
                                    <value>#1</value>
                                </enumeratedValue>
                            </enumeratedValues>
                        </field>
                        <field>
                            <name>DIRQ4EG</name>
                            <description>IRQ4-DS Pin Edge Select</description>
                            <lsb>4</lsb>
                            <msb>4</msb>
                            <access>read-write</access>
                            <enumeratedValues>
                                <enumeratedValue>
                                    <name>0</name>
                                    <description>A cancel request is generated at a falling edge</description>
                                    <value>#0</value>
                                </enumeratedValue>
                                <enumeratedValue>
                                    <name>1</name>
                                    <description>A cancel request is generated at a rising edge</description>
                                    <value>#1</value>
                                </enumeratedValue>
                            </enumeratedValues>
                        </field>
                        <field>
                            <name>DIRQ5EG</name>
                            <description>Unexpected Packet Error Interrupt Flag</description>
                            <lsb>18</lsb>
                            <msb>18</msb>
                            <access>read-only</access>
                            <enumeratedValues>
                                <enumeratedValue>
                                    <name>0</name>
                                    <description>No error</description>
                                    <value>#0</value>
                                </enumeratedValue>
                                <enumeratedValue>
                                    <name>1</name>
                                    <description>Unexpected packet received</description>
                                    <value>#1</value>
                                </enumeratedValue>
                            </enumeratedValues>
                        </field>
                        <field>
                            <name>WCERR</name>
                            <description>Word Count Error Interrupt Flag</description>
                            <lsb>20</lsb>
                            <msb>20</msb>
                            <access>read-only</access>
                            <enumeratedValues>
                                <enumeratedValue>
                                    <name>0</name>
                                    <description>No error detected</description>
                                    <value>#0</value>
                                </enumeratedValue>
                                <enumeratedValue>
                                    <name>1</name>
                                    <description>The length of the received packet is shorter than the WC indicated in the packet header.</description>
                                    <value>#1</value>
                                </enumeratedValue>
                            </enumeratedValues>
                        </field>
                        <field>
                            <name>CRCERR</name>
                            <description>CRC Error Interrupt Flag</description>
                            <lsb>21</lsb>
                            <msb>21</msb>
                            <access>read-only</access>
                            <enumeratedValues>
                                <enumeratedValue>
                                    <name>0</name>
                                    <description>No error detected</description>
                                    <value>#0</value>
                                </enumeratedValue>
                                <enumeratedValue>
                                    <name>1</name>
                                    <description>CRC error detected</description>
                                    <value>#1</value>
                                </enumeratedValue>
                            </enumeratedValues>
                        </field>
                        <field>
                            <name>IBERR</name>
                            <description>Internal Bus Error Interrupt Flag</description>
                            <lsb>22</lsb>
                            <msb>22</msb>
                            <access>read-only</access>
                            <enumeratedValues>
                                <enumeratedValue>
                                    <name>0</name>
                                    <description>No error detected</description>
                                    <value>#0</value>
                                </enumeratedValue>
                                <enumeratedValue>
                                    <name>1</name>
                                    <description>Internal AXI bus write failed</description>
                                    <value>#1</value>
                                </enumeratedValue>
                            </enumeratedValues>
                        </field>
                        <field>
                            <name>RXOVFERR</name>
                            <description>Receive Buffer Overflow Error Interrupt Flag</description>
                            <lsb>23</lsb>
                            <msb>23</msb>
                            <access>read-only</access>
                            <enumeratedValues>
                                <enumeratedValue>
                                    <name>0</name>
                                    <description>No error detected</description>
                                    <value>#0</value>
                                </enumeratedValue>
                                <enumeratedValue>
                                    <name>1</name>
                                    <description>A buffer overflow error detected on receiving long packets</description>
                                    <value>#1</value>
                                </enumeratedValue>
                            </enumeratedValues>
                        </field>
                        <field>
                            <name>PRTOERR</name>
                            <description>Peripheral Response Timeout Error Interrupt Flag</description>
                            <lsb>24</lsb>
                            <msb>24</msb>
                            <access>read-only</access>
                            <enumeratedValues>
                                <enumeratedValue>
                                    <name>0</name>
                                    <description>No error occurred</description>
                                    <value>#0</value>
                                </enumeratedValue>
                                <enumeratedValue>
                                    <name>1</name>
                                    <description>Peripheral response timeout occurred</description>
                                    <value>#1</value>
                                </enumeratedValue>
                            </enumeratedValues>
                        </field>
                        <field>
                            <name>NORESERR</name>
                            <description>No Response Error Interrupt Flag</description>
                            <lsb>25</lsb>
                            <msb>25</msb>
                            <access>read-only</access>
                            <enumeratedValues>
                                <enumeratedValue>
                                    <name>0</name>
                                    <description>No error occurred</description>
                                    <value>#0</value>
                                </enumeratedValue>
                                <enumeratedValue>
                                    <name>1</name>
                                    <description>No triggers or packets returned during BTA period</description>
                                    <value>#1</value>
                                </enumeratedValue>
                            </enumeratedValues>
                        </field>
                        <field>
                            <name>RSIZEERR</name>
                            <description>Return Packet Size Error Interrupt Flag</description>
                            <lsb>26</lsb>
                            <msb>26</msb>
                            <access>read-only</access>
                            <enumeratedValues>
                                <enumeratedValue>
                                    <name>0</name>
                                    <description>No error detected</description>
                                    <value>#0</value>
                                </enumeratedValue>
                                <enumeratedValue>
                                    <name>1</name>
                                    <description>Oversize error in a received long packet detected</description>
                                    <value>#1</value>
                                </enumeratedValue>
                            </enumeratedValues>
                        </field>
                        <field>
                            <name>ECCERRS</name>
                            <description>Single Bit ECC Error Interrupt Flag</description>
                            <lsb>28</lsb>
                            <msb>28</msb>
                            <access>read-only</access>
                            <enumeratedValues>
                                <enumeratedValue>
                                    <name>0</name>
                                    <description>No error detected</description>
                                    <value>#0</value>
                                </enumeratedValue>
                                <enumeratedValue>
                                    <name>1</name>
                                    <description>A single-bit ECC error detected</description>
                                    <value>#1</value>
                                </enumeratedValue>
                            </enumeratedValues>
                        </field>
                        <field>
                            <name>RXAKE</name>
                            <description>Acknowledge and Error Report Receive Interrupt Flag</description>
                            <lsb>30</lsb>
                            <msb>30</msb>
                            <access>read-only</access>
                            <enumeratedValues>
                                <enumeratedValue>
                                    <name>0</name>
                                    <description>No received</description>
                                    <value>#0</value>
                                </enumeratedValue>
                                <enumeratedValue>
                                    <name>1</name>
                                    <description>An Acknowledge and Error Report packet received</description>
                                    <value>#1</value>
                                </enumeratedValue>
                            </enumeratedValues>
                        </field>
                    </fields>
                </register>
                <register>
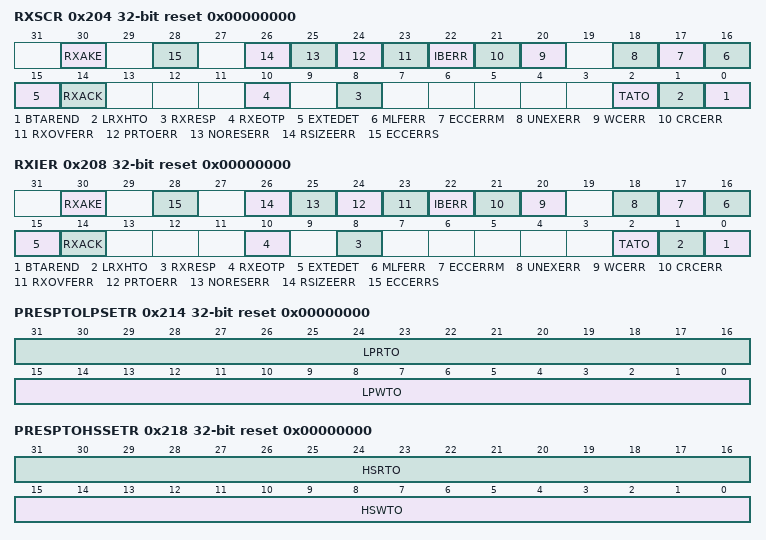
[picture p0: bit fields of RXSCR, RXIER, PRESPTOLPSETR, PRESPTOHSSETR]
                    <name>RXSCR</name>
                    <description>Receive Status Clear Register</description>
                    <addressOffset>0x204</addressOffset>
                    <size>32</size>
                    <access>write-only</access>
                    <resetValue>0x00000000</resetValue>
                    <resetMask>0xffffffff</resetMask>
                    <fields>
                        <field>
                            <name>BTAREND</name>
                            <description>BTA Request End Interrupt Flag Clear</description>
                            <lsb>0</lsb>
                            <msb>0</msb>
                            <access>write-only</access>
                            <enumeratedValues>
                                <enumeratedValue>
                                    <name>0</name>
                                    <description>No operation</description>
                                    <value>#0</value>
                                </enumeratedValue>
                                <enumeratedValue>
                                    <name>1</name>
                                    <description>Clear the RXSR.BTAREND flag</description>
                                    <value>#1</value>
                                </enumeratedValue>
                            </enumeratedValues>
                        </field>
                        <field>
                            <name>LRXHTO</name>
                            <description>LP-RX Host Processor Timeout Interrupt Flag Clear</description>
                            <lsb>1</lsb>
                            <msb>1</msb>
                            <access>write-only</access>
                            <enumeratedValues>
                                <enumeratedValue>
                                    <name>0</name>
                                    <description>No operation</description>
                                    <value>#0</value>
                                </enumeratedValue>
                                <enumeratedValue>
                                    <name>1</name>
                                    <description>Clear the RXSR.LRXHTO flag</description>
                                    <value>#1</value>
                                </enumeratedValue>
                            </enumeratedValues>
                        </field>
                        <field>
                            <name>TATO</name>
                            <description>Turnaround Acknowledge Timeout Interrupt Flag Clear</description>
                            <lsb>2</lsb>
                            <msb>2</msb>
                            <access>write-only</access>
                            <enumeratedValues>
                                <enumeratedValue>
                                    <name>0</name>
                                    <description>No operation</description>
                                    <value>#0</value>
                                </enumeratedValue>
                                <enumeratedValue>
                                    <name>1</name>
                                    <description>Clear the RXSR.TATO flag</description>
                                    <value>#1</value>
                                </enumeratedValue>
                            </enumeratedValues>
                        </field>
                        <field>
                            <name>RXRESP</name>
                            <description>Response Packet Receive Interrupt Flag Clear</description>
                            <lsb>8</lsb>
                            <msb>8</msb>
                            <access>write-only</access>
                            <enumeratedValues>
                                <enumeratedValue>
                                    <name>0</name>
                                    <description>No operation</description>
                                    <value>#0</value>
                                </enumeratedValue>
                                <enumeratedValue>
                                    <name>1</name>
                                    <description>Clear the RXSR.RXRESP flag</description>
                                    <value>#1</value>
                                </enumeratedValue>
                            </enumeratedValues>
                        </field>
                        <field>
                            <name>RXEOTP</name>
                            <description>EoTp Receive Interrupt Flag Clear</description>
                            <lsb>10</lsb>
                            <msb>10</msb>
                            <access>write-only</access>
                            <enumeratedValues>
                                <enumeratedValue>
                                    <name>0</name>
                                    <description>No operation</description>
                                    <value>#0</value>
                                </enumeratedValue>
                                <enumeratedValue>
                                    <name>1</name>
                                    <description>Clear the RXSR.RXEOTP flag</description>
                                    <value>#1</value>
                                </enumeratedValue>
                            </enumeratedValues>
                        </field>
                        <field>
                            <name>RXACK</name>
                            <description>ACK Trigger Receive Interrupt Flag Clear</description>
                            <lsb>14</lsb>
                            <msb>14</msb>
                            <access>write-only</access>
                            <enumeratedValues>
                                <enumeratedValue>
                                    <name>0</name>
                                    <description>No operation</description>
                                    <value>#0</value>
                                </enumeratedValue>
                                <enumeratedValue>
                                    <name>1</name>
                                    <description>Clear the RXSR.RXACK flag</description>
                                    <value>#1</value>
                                </enumeratedValue>
                            </enumeratedValues>
                        </field>
                        <field>
                            <name>EXTEDET</name>
                            <description>External Tearing Effect Detect Interrupt Flag Clear</description>
                            <lsb>15</lsb>
                            <msb>15</msb>
                            <access>write-only</access>
                            <enumeratedValues>
                                <enumeratedValue>
                                    <name>0</name>
                                    <description>No operation</description>
                                    <value>#0</value>
                                </enumeratedValue>
                                <enumeratedValue>
                                    <name>1</name>
                                    <description>Clear the RXSR.EXTEDET flag</description>
                                    <value>#1</value>
                                </enumeratedValue>
                            </enumeratedValues>
                        </field>
                        <field>
                            <name>MLFERR</name>
                            <description>Malform Error Interrupt Flag Clear</description>
                            <lsb>16</lsb>
                            <msb>16</msb>
                            <access>write-only</access>
                            <enumeratedValues>
                                <enumeratedValue>
                                    <name>0</name>
                                    <description>No operation</description>
                                    <value>#0</value>
                                </enumeratedValue>
                                <enumeratedValue>
                                    <name>1</name>
                                    <description>Clear the RXSR.MLFERR flag</description>
                                    <value>#1</value>
                                </enumeratedValue>
                            </enumeratedValues>
                        </field>
                        <field>
                            <name>ECCERRM</name>
                            <description>Multi Bit ECC Error Interrupt Flag Clear</description>
                            <lsb>17</lsb>
                            <msb>17</msb>
                            <access>write-only</access>
                            <enumeratedValues>
                                <enumeratedValue>
                                    <name>0</name>
                                    <description>No operation</description>
                                    <value>#0</value>
                                </enumeratedValue>
                                <enumeratedValue>
                                    <name>1</name>
                                    <description>Clear the RXSR.ECCERRM flag</description>
                                    <value>#1</value>
                                </enumeratedValue>
                            </enumeratedValues>
                        </field>
                        <field>
                            <name>UNEXERR</name>
                            <description>Unexpected Packet Error Interrupt Flag Clear</description>
                            <lsb>18</lsb>
                            <msb>18</msb>
                            <access>write-only</access>
                            <enumeratedValues>
                                <enumeratedValue>
                                    <name>0</name>
                                    <description>No operation</description>
                                    <value>#0</value>
                                </enumeratedValue>
                                <enumeratedValue>
                                    <name>1</name>
                                    <description>Clear the RXSR.UNEXERR flag</description>
                                    <value>#1</value>
                                </enumeratedValue>
                            </enumeratedValues>
                        </field>
                        <field>
                            <name>WCERR</name>
                            <description>Word Count Error Interrupt Flag Clear</description>
                            <lsb>20</lsb>
                            <msb>20</msb>
                            <access>write-only</access>
                            <enumeratedValues>
                                <enumeratedValue>
                                    <name>0</name>
                                    <description>No operation</description>
                                    <value>#0</value>
                                </enumeratedValue>
                                <enumeratedValue>
                                    <name>1</name>
                                    <description>Clear the RXSR.WCERR flag</description>
                                    <value>#1</value>
                                </enumeratedValue>
                            </enumeratedValues>
                        </field>
                        <field>
                            <name>CRCERR</name>
                            <description>CRC Error Interrupt Flag Clear</description>
                            <lsb>21</lsb>
                            <msb>21</msb>
                            <access>write-only</access>
                            <enumeratedValues>
                                <enumeratedValue>
                                    <name>0</name>
                                    <description>No operation</description>
                                    <value>#0</value>
                                </enumeratedValue>
                                <enumeratedValue>
                                    <name>1</name>
                                    <description>Clear the RXSR.CRCERR flag</description>
                                    <value>#1</value>
                                </enumeratedValue>
                            </enumeratedValues>
                        </field>
                        <field>
                            <name>IBERR</name>
                            <description>Internal Bus Error Interrupt Flag Clear</description>
                            <lsb>22</lsb>
                            <msb>22</msb>
                            <access>write-only</access>
                            <enumeratedValues>
                                <enumeratedValue>
                                    <name>0</name>
                                    <description>No operation</description>
                                    <value>#0</value>
                                </enumeratedValue>
                                <enumeratedValue>
                                    <name>1</name>
                                    <description>Clear the RXSR.IBERR flag</description>
                                    <value>#1</value>
                                </enumeratedValue>
                            </enumeratedValues>
                        </field>
                        <field>
                            <name>RXOVFERR</name>
                            <description>Receive Buffer Overflow Error Interrupt Flag Clear</description>
                            <lsb>23</lsb>
                            <msb>23</msb>
                            <access>write-only</access>
                            <enumeratedValues>
                                <enumeratedValue>
                                    <name>0</name>
                                    <description>No operation</description>
                                    <value>#0</value>
                                </enumeratedValue>
                                <enumeratedValue>
                                    <name>1</name>
                                    <description>Clear the RXSR.RXOVFERR flag</description>
                                    <value>#1</value>
                                </enumeratedValue>
                            </enumeratedValues>
                        </field>
                        <field>
                            <name>PRTOERR</name>
                            <description>Peripheral Response Timeout Error Interrupt Flag Clear</description>
                            <lsb>24</lsb>
                            <msb>24</msb>
                            <access>write-only</access>
                            <enumeratedValues>
                                <enumeratedValue>
                                    <name>0</name>
                                    <description>No operation</description>
                                    <value>#0</value>
                                </enumeratedValue>
                                <enumeratedValue>
                                    <name>1</name>
                                    <description>Clear the RXSR.PRTOERR flag</description>
                                    <value>#1</value>
                                </enumeratedValue>
                            </enumeratedValues>
                        </field>
                        <field>
                            <name>NORESERR</name>
                            <description>No Response Error Interrupt Flag Clear</description>
                            <lsb>25</lsb>
                            <msb>25</msb>
                            <access>write-only</access>
                            <enumeratedValues>
                                <enumeratedValue>
                                    <name>0</name>
                                    <description>No operation</description>
                                    <value>#0</value>
                                </enumeratedValue>
                                <enumeratedValue>
                                    <name>1</name>
                                    <description>Clear the RXSR.NORESERR flag</description>
                                    <value>#1</value>
                                </enumeratedValue>
                            </enumeratedValues>
                        </field>
                        <field>
                            <name>RSIZEERR</name>
                            <description>Return Packet Size Error Interrupt Flag Clear</description>
                            <lsb>26</lsb>
                            <msb>26</msb>
                            <access>write-only</access>
                            <enumeratedValues>
                                <enumeratedValue>
                                    <name>0</name>
                                    <description>No operation </description>
                                    <value>#0</value>
                                </enumeratedValue>
                                <enumeratedValue>
                                    <name>1</name>
                                    <description>Clear the RXSR.RSIZEERR flag</description>
                                    <value>#1</value>
                                </enumeratedValue>
                            </enumeratedValues>
                        </field>
                        <field>
                            <name>ECCERRS</name>
                            <description>Single Bit ECC Error Interrupt Flag Clear</description>
                            <lsb>28</lsb>
                            <msb>28</msb>
                            <access>write-only</access>
                            <enumeratedValues>
                                <enumeratedValue>
                                    <name>0</name>
                                    <description>No operation</description>
                                    <value>#0</value>
                                </enumeratedValue>
                                <enumeratedValue>
                                    <name>1</name>
                                    <description>Clear the RXSR.ECCERRS flag</description>
                                    <value>#1</value>
                                </enumeratedValue>
                            </enumeratedValues>
                        </field>
                        <field>
                            <name>RXAKE</name>
                            <description>Acknowledge and Error Report Receive Interrupt Flag Clear</description>
                            <lsb>30</lsb>
                            <msb>30</msb>
                            <access>write-only</access>
                            <enumeratedValues>
                                <enumeratedValue>
                                    <name>0</name>
                                    <description>No operation</description>
                                    <value>#0</value>
                                </enumeratedValue>
                                <enumeratedValue>
                                    <name>1</name>
                                    <description>Clear the RXSR.RXAKE flag</description>
                                    <value>#1</value>
                                </enumeratedValue>
                            </enumeratedValues>
                        </field>
                    </fields>
                </register>
                <register>
                    <name>RXIER</name>
                    <description>Receive Interrupt Enable Register</description>
                    <addressOffset>0x208</addressOffset>
                    <size>32</size>
                    <access>read-write</access>
                    <resetValue>0x00000000</resetValue>
                    <resetMask>0xffffffff</resetMask>
                    <fields>
                        <field>
                            <name>BTAREND</name>
                            <description>BTA Request End Interrupt Enable</description>
                            <lsb>0</lsb>
                            <msb>0</msb>
                            <access>read-write</access>
                            <enumeratedValues>
                                <enumeratedValue>
                                    <name>0</name>
                                    <description>Disable</description>
                                    <value>#0</value>
                                </enumeratedValue>
                                <enumeratedValue>
                                    <name>1</name>
                                    <description>Enable</description>
                                    <value>#1</value>
                                </enumeratedValue>
                            </enumeratedValues>
                        </field>
                        <field>
                            <name>LRXHTO</name>
                            <description>LP-RX Host Processor Timeout Interrupt Enable</description>
                            <lsb>1</lsb>
                            <msb>1</msb>
                            <access>read-write</access>
                            <enumeratedValues>
                                <enumeratedValue>
                                    <name>0</name>
                                    <description>Disable</description>
                                    <value>#0</value>
                                </enumeratedValue>
                                <enumeratedValue>
                                    <name>1</name>
                                    <description>Enable</description>
                                    <value>#1</value>
                                </enumeratedValue>
                            </enumeratedValues>
                        </field>
                        <field>
                            <name>TATO</name>
                            <description>Turnaround Acknowledge Timeout Interrupt Enable</description>
                            <lsb>2</lsb>
                            <msb>2</msb>
                            <access>read-write</access>
                            <enumeratedValues>
                                <enumeratedValue>
                                    <name>0</name>
                                    <description>Disable</description>
                                    <value>#0</value>
                                </enumeratedValue>
                                <enumeratedValue>
                                    <name>1</name>
                                    <description>Enable</description>
                                    <value>#1</value>
                                </enumeratedValue>
                            </enumeratedValues>
                        </field>
                        <field>
                            <name>RXRESP</name>
                            <description>Response Packet Receive Interrupt Enable</description>
                            <lsb>8</lsb>
                            <msb>8</msb>
                            <access>read-write</access>
                            <enumeratedValues>
                                <enumeratedValue>
                                    <name>0</name>
                                    <description>Disable</description>
                                    <value>#0</value>
                                </enumeratedValue>
                                <enumeratedValue>
                                    <name>1</name>
                                    <description>Enable</description>
                                    <value>#1</value>
                                </enumeratedValue>
                            </enumeratedValues>
                        </field>
                        <field>
                            <name>RXEOTP</name>
                            <description>EoTp Receive Interrupt Enable</description>
                            <lsb>10</lsb>
                            <msb>10</msb>
                            <access>read-write</access>
                            <enumeratedValues>
                                <enumeratedValue>
                                    <name>0</name>
                                    <description>Disable</description>
                                    <value>#0</value>
                                </enumeratedValue>
                                <enumeratedValue>
                                    <name>1</name>
                                    <description>Enable</description>
                                    <value>#1</value>
                                </enumeratedValue>
                            </enumeratedValues>
                        </field>
                        <field>
                            <name>RXACK</name>
                            <description>ACK Trigger Receive Interrupt Enable</description>
                            <lsb>14</lsb>
                            <msb>14</msb>
                            <access>read-write</access>
                            <enumeratedValues>
                                <enumeratedValue>
                                    <name>0</name>
                                    <description>Disable</description>
                                    <value>#0</value>
                                </enumeratedValue>
                                <enumeratedValue>
                                    <name>1</name>
                                    <description>Enable</description>
                                    <value>#1</value>
                                </enumeratedValue>
                            </enumeratedValues>
                        </field>
                        <field>
                            <name>EXTEDET</name>
                            <description>External Tearing Effect Detect Interrupt Enable</description>
                            <lsb>15</lsb>
                            <msb>15</msb>
                            <access>read-write</access>
                            <enumeratedValues>
                                <enumeratedValue>
                                    <name>0</name>
                                    <description>Disable</description>
                                    <value>#0</value>
                                </enumeratedValue>
                                <enumeratedValue>
                                    <name>1</name>
                                    <description>Enable</description>
                                    <value>#1</value>
                                </enumeratedValue>
                            </enumeratedValues>
                        </field>
                        <field>
                            <name>MLFERR</name>
                            <description>Malform Error Interrupt Enable</description>
                            <lsb>16</lsb>
                            <msb>16</msb>
                            <access>read-write</access>
                            <enumeratedValues>
                                <enumeratedValue>
                                    <name>0</name>
                                    <description>Disable</description>
                                    <value>#0</value>
                                </enumeratedValue>
                                <enumeratedValue>
                                    <name>1</name>
                                    <description>Enable</description>
                                    <value>#1</value>
                                </enumeratedValue>
                            </enumeratedValues>
                        </field>
                        <field>
                            <name>ECCERRM</name>
                            <description>Multi Bit ECC Error Interrupt Enable</description>
                            <lsb>17</lsb>
                            <msb>17</msb>
                            <access>read-write</access>
                            <enumeratedValues>
                                <enumeratedValue>
                                    <name>0</name>
                                    <description>Disable</description>
                                    <value>#0</value>
                                </enumeratedValue>
                                <enumeratedValue>
                                    <name>1</name>
                                    <description>Enable</description>
                                    <value>#1</value>
                                </enumeratedValue>
                            </enumeratedValues>
                        </field>
                        <field>
                            <name>UNEXERR</name>
                            <description>Unexpected Packet Error Interrupt Enable</description>
                            <lsb>18</lsb>
                            <msb>18</msb>
                            <access>read-write</access>
                            <enumeratedValues>
                                <enumeratedValue>
                                    <name>0</name>
                                    <description>Disable</description>
                                    <value>#0</value>
                                </enumeratedValue>
                                <enumeratedValue>
                                    <name>1</name>
                                    <description>Enable</description>
                                    <value>#1</value>
                                </enumeratedValue>
                            </enumeratedValues>
                        </field>
                        <field>
                            <name>WCERR</name>
                            <description>Word Count Error Interrupt Enable</description>
                            <lsb>20</lsb>
                            <msb>20</msb>
                            <access>read-write</access>
                            <enumeratedValues>
                                <enumeratedValue>
                                    <name>0</name>
                                    <description>Disable</description>
                                    <value>#0</value>
                                </enumeratedValue>
                                <enumeratedValue>
                                    <name>1</name>
                                    <description>Enable</description>
                                    <value>#1</value>
                                </enumeratedValue>
                            </enumeratedValues>
                        </field>
                        <field>
                            <name>CRCERR</name>
                            <description>CRC Error Interrupt Enable</description>
                            <lsb>21</lsb>
                            <msb>21</msb>
                            <access>read-write</access>
                            <enumeratedValues>
                                <enumeratedValue>
                                    <name>0</name>
                                    <description>Disable</description>
                                    <value>#0</value>
                                </enumeratedValue>
                                <enumeratedValue>
                                    <name>1</name>
                                    <description>Enable</description>
                                    <value>#1</value>
                                </enumeratedValue>
                            </enumeratedValues>
                        </field>
                        <field>
                            <name>IBERR</name>
                            <description>Internal Bus Error Interrupt Enable</description>
                            <lsb>22</lsb>
                            <msb>22</msb>
                            <access>read-write</access>
                            <enumeratedValues>
                                <enumeratedValue>
                                    <name>0</name>
                                    <description>Disable</description>
                                    <value>#0</value>
                                </enumeratedValue>
                                <enumeratedValue>
                                    <name>1</name>
                                    <description>Enable</description>
                                    <value>#1</value>
                                </enumeratedValue>
                            </enumeratedValues>
                        </field>
                        <field>
                            <name>RXOVFERR</name>
                            <description>Receive Buffer Overflow Error Interrupt Enable</description>
                            <lsb>23</lsb>
                            <msb>23</msb>
                            <access>read-write</access>
                            <enumeratedValues>
                                <enumeratedValue>
                                    <name>0</name>
                                    <description>Disable</description>
                                    <value>#0</value>
                                </enumeratedValue>
                                <enumeratedValue>
                                    <name>1</name>
                                    <description>Enable</description>
                                    <value>#1</value>
                                </enumeratedValue>
                            </enumeratedValues>
                        </field>
                        <field>
                            <name>PRTOERR</name>
                            <description>Peripheral Response Timeout Error Interrupt Enable</description>
                            <lsb>24</lsb>
                            <msb>24</msb>
                            <access>read-write</access>
                            <enumeratedValues>
                                <enumeratedValue>
                                    <name>0</name>
                                    <description>Disable</description>
                                    <value>#0</value>
                                </enumeratedValue>
                                <enumeratedValue>
                                    <name>1</name>
                                    <description>Enable</description>
                                    <value>#1</value>
                                </enumeratedValue>
                            </enumeratedValues>
                        </field>
                        <field>
                            <name>NORESERR</name>
                            <description>No Response Error Interrupt Enable</description>
                            <lsb>25</lsb>
                            <msb>25</msb>
                            <access>read-write</access>
                            <enumeratedValues>
                                <enumeratedValue>
                                    <name>0</name>
                                    <description>Disable</description>
                                    <value>#0</value>
                                </enumeratedValue>
                                <enumeratedValue>
                                    <name>1</name>
                                    <description>Enable</description>
                                    <value>#1</value>
                                </enumeratedValue>
                            </enumeratedValues>
                        </field>
                        <field>
                            <name>RSIZEERR</name>
                            <description>Return Packet Size Error Interrupt Enable</description>
                            <lsb>26</lsb>
                            <msb>26</msb>
                            <access>read-write</access>
                            <enumeratedValues>
                                <enumeratedValue>
                                    <name>0</name>
                                    <description>Disable</description>
                                    <value>#0</value>
                                </enumeratedValue>
                                <enumeratedValue>
                                    <name>1</name>
                                    <description>Enable</description>
                                    <value>#1</value>
                                </enumeratedValue>
                            </enumeratedValues>
                        </field>
                        <field>
                            <name>ECCERRS</name>
                            <description>Single Bit ECC Error Interrupt Enable</description>
                            <lsb>28</lsb>
                            <msb>28</msb>
                            <access>read-write</access>
                            <enumeratedValues>
                                <enumeratedValue>
                                    <name>0</name>
                                    <description>Disable</description>
                                    <value>#0</value>
                                </enumeratedValue>
                                <enumeratedValue>
                                    <name>1</name>
                                    <description>Enable</description>
                                    <value>#1</value>
                                </enumeratedValue>
                            </enumeratedValues>
                        </field>
                        <field>
                            <name>RXAKE</name>
                            <description>Acknowledge and Error Report Receive Interrupt Enable</description>
                            <lsb>30</lsb>
                            <msb>30</msb>
                            <access>read-write</access>
                            <enumeratedValues>
                                <enumeratedValue>
                                    <name>0</name>
                                    <description>Disable</description>
                                    <value>#0</value>
                                </enumeratedValue>
                                <enumeratedValue>
                                    <name>1</name>
                                    <description>Enable</description>
                                    <value>#1</value>
                                </enumeratedValue>
                            </enumeratedValues>
                        </field>
                    </fields>
                </register>
                <register>
                    <name>PRESPTOBTASETR</name>
                    <description>Peripheral Response Timeout BTA Set Register</description>
                    <addressOffset>0x210</addressOffset>
                    <size>32</size>
                    <access>read-write</access>
                    <resetValue>0x00000000</resetValue>
                    <resetMask>0xffffffff</resetMask>
                    <fields>
                        <field>
                            <name>PRTBTA</name>
                            <description>Peripheral Response Timeout Count</description>
                            <lsb>0</lsb>
                            <msb>31</msb>
                            <access>read-write</access>
                        </field>
                    </fields>
                </register>
                <register>
                    <name>PRESPTOLPSETR</name>
                    <description>Peripheral Response Timeout LP Set Register</description>
                    <addressOffset>0x214</addressOffset>
                    <size>32</size>
                    <access>read-write</access>
                    <resetValue>0x00000000</resetValue>
                    <resetMask>0xffffffff</resetMask>
                    <fields>
                        <field>
                            <name>LPWTO</name>
                            <description>LPDT WRITE Request Timeout</description>
                            <lsb>0</lsb>
                            <msb>15</msb>
                            <access>read-write</access>
                        </field>
                        <field>
                            <name>LPRTO</name>
                            <description>LPDT READ Request Timeout</description>
                            <lsb>16</lsb>
                            <msb>31</msb>
                            <access>read-write</access>
                        </field>
                    </fields>
                </register>
                <register>
                    <name>PRESPTOHSSETR</name>
                    <description>Peripheral Response Timeout HS Set Register</description>
                    <addressOffset>0x218</addressOffset>
                    <size>32</size>
                    <access>read-write</access>
                    <resetValue>0x00000000</resetValue>
                    <resetMask>0xffffffff</resetMask>
                    <fields>
                        <field>
                            <name>HSWTO</name>
                            <description>HS WRITE Request Timeout</description>
                            <lsb>0</lsb>
                            <msb>15</msb>
                            <access>read-write</access>
                        </field>
                        <field>
                            <name>HSRTO</name>
                            <description>HS READ Request Timeout</description>
                            <lsb>16</lsb>
                            <msb>31</msb>
                            <access>read-write</access>
                        </field>
                    </fields>
                </register>
                <register>
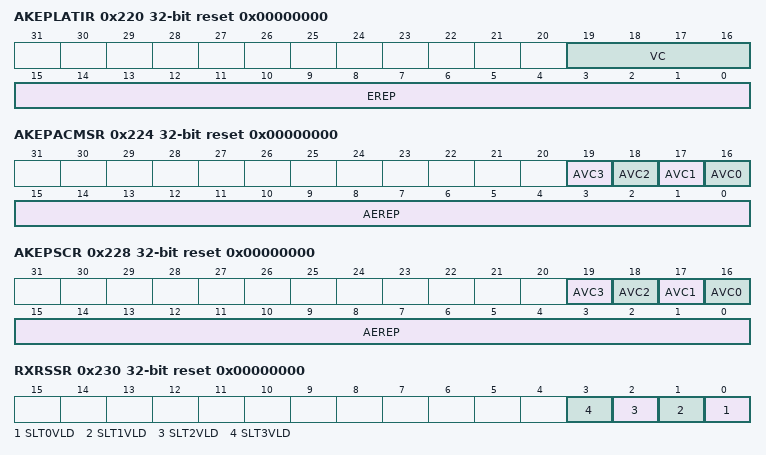
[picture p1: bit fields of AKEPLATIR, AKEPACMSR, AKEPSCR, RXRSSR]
                    <name>AKEPLATIR</name>
                    <description>Acknowledge and Error Report Packet Parameter Latest Info Register</description>
                    <addressOffset>0x220</addressOffset>
                    <size>32</size>
                    <access>read-only</access>
                    <resetValue>0x00000000</resetValue>
                    <resetMask>0xffffffff</resetMask>
                    <fields>
                        <field>
                            <name>EREP</name>
                            <description>Error Report</description>
                            <lsb>0</lsb>
                            <msb>15</msb>
                            <access>read-only</access>
                        </field>
                        <field>
                            <name>VC</name>
                            <description>Virtual Channel ID</description>
                            <lsb>16</lsb>
                            <msb>19</msb>
                            <access>read-only</access>
                            <enumeratedValues>
                                <enumeratedValue>
                                    <name>0x0</name>
                                    <description>No Error Report received</description>
                                    <value>0x0</value>
                                </enumeratedValue>
                                <enumeratedValue>
                                    <name>0x1</name>
                                    <description>From VC-0</description>
                                    <value>0x1</value>
                                </enumeratedValue>
                                <enumeratedValue>
                                    <name>0x2</name>
                                    <description>From VC-1</description>
                                    <value>0x2</value>
                                </enumeratedValue>
                                <enumeratedValue>
                                    <name>0x4</name>
                                    <description>From VC-2</description>
                                    <value>0x4</value>
                                </enumeratedValue>
                                <enumeratedValue>
                                    <name>0x8</name>
                                    <description>From VC-3</description>
                                    <value>0x8</value>
                                </enumeratedValue>
                                <enumeratedValue>
                                    <name>Others</name>
                                    <description>Reserved</description>
                                    <isDefault>true</isDefault>
                                </enumeratedValue>
                            </enumeratedValues>
                        </field>
                    </fields>
                </register>
                <register>
                    <name>AKEPACMSR</name>
                    <description>Acknowledge and Error Report Packet Parameter Accumulate Status Register</description>
                    <addressOffset>0x224</addressOffset>
                    <size>32</size>
                    <access>read-only</access>
                    <resetValue>0x00000000</resetValue>
                    <resetMask>0xffffffff</resetMask>
                    <fields>
                        <field>
                            <name>AEREP</name>
                            <description>Accumulated Error Report</description>
                            <lsb>0</lsb>
                            <msb>15</msb>
                            <access>read-only</access>
                        </field>
                        <field>
                            <name>AVC0</name>
                            <description>Virtual Channel-0 Accumulated Information</description>
                            <lsb>16</lsb>
                            <msb>16</msb>
                            <access>read-only</access>
                            <enumeratedValues>
                                <enumeratedValue>
                                    <name>0</name>
                                    <description>No Error Report received from VC-0</description>
                                    <value>#0</value>
                                </enumeratedValue>
                                <enumeratedValue>
                                    <name>1</name>
                                    <description>Received an Acknowledge and Error Report from VC-0</description>
                                    <value>#1</value>
                                </enumeratedValue>
                            </enumeratedValues>
                        </field>
                        <field>
                            <name>AVC1</name>
                            <description>Virtual Channel-1 Accumulated Information</description>
                            <lsb>17</lsb>
                            <msb>17</msb>
                            <access>read-only</access>
                            <enumeratedValues>
                                <enumeratedValue>
                                    <name>0</name>
                                    <description>No Error Report received from VC-1</description>
                                    <value>#0</value>
                                </enumeratedValue>
                                <enumeratedValue>
                                    <name>1</name>
                                    <description>Received an Acknowledge and Error Report from VC-1</description>
                                    <value>#1</value>
                                </enumeratedValue>
                            </enumeratedValues>
                        </field>
                        <field>
                            <name>AVC2</name>
                            <description>Virtual Channel-2 Accumulated Information</description>
                            <lsb>18</lsb>
                            <msb>18</msb>
                            <access>read-only</access>
                            <enumeratedValues>
                                <enumeratedValue>
                                    <name>0</name>
                                    <description>No Error Report received from VC-2</description>
                                    <value>#0</value>
                                </enumeratedValue>
                                <enumeratedValue>
                                    <name>1</name>
                                    <description>Received an Acknowledge and Error Report from VC-2</description>
                                    <value>#1</value>
                                </enumeratedValue>
                            </enumeratedValues>
                        </field>
                        <field>
                            <name>AVC3</name>
                            <description>Virtual Channel-3 Accumulated Information</description>
                            <lsb>19</lsb>
                            <msb>19</msb>
                            <access>read-only</access>
                            <enumeratedValues>
                                <enumeratedValue>
                                    <name>0</name>
                                    <description>No Error Report received from VC-3</description>
                                    <value>#0</value>
                                </enumeratedValue>
                                <enumeratedValue>
                                    <name>1</name>
                                    <description>Received an Acknowledge and Error Report from VC-3</description>
                                    <value>#1</value>
                                </enumeratedValue>
                            </enumeratedValues>
                        </field>
                    </fields>
                </register>
                <register>
                    <name>AKEPSCR</name>
                    <description>Acknowledge and Error Report Packet Parameter Status Clear Register</description>
                    <addressOffset>0x228</addressOffset>
                    <size>32</size>
                    <access>write-only</access>
                    <resetValue>0x00000000</resetValue>
                    <resetMask>0xffffffff</resetMask>
                    <fields>
                        <field>
                            <name>AEREP</name>
                            <description>Accumulated Error Report Clear</description>
                            <lsb>0</lsb>
                            <msb>15</msb>
                            <access>write-only</access>
                            <enumeratedValues>
                                <enumeratedValue>
                                    <name>0</name>
                                    <description>No operation</description>
                                    <value>#0</value>
                                </enumeratedValue>
                                <enumeratedValue>
                                    <name>1</name>
                                    <description>Clear the AKEPACMSR.AEREP[15:0] bits</description>
                                    <value>#1</value>
                                </enumeratedValue>
                            </enumeratedValues>
                        </field>
                        <field>
                            <name>AVC0</name>
                            <description>Virtual Channel-0 Accumulated Information Clear</description>
                            <lsb>16</lsb>
                            <msb>16</msb>
                            <access>write-only</access>
                            <enumeratedValues>
                                <enumeratedValue>
                                    <name>0</name>
                                    <description>No operation</description>
                                    <value>#0</value>
                                </enumeratedValue>
                                <enumeratedValue>
                                    <name>1</name>
                                    <description>Clear the AKEPACMSR.AVC0 bit</description>
                                    <value>#1</value>
                                </enumeratedValue>
                            </enumeratedValues>
                        </field>
                        <field>
                            <name>AVC1</name>
                            <description>Virtual Channel-1 Accumulated Information Clear</description>
                            <lsb>17</lsb>
                            <msb>17</msb>
                            <access>write-only</access>
                            <enumeratedValues>
                                <enumeratedValue>
                                    <name>0</name>
                                    <description>No operation</description>
                                    <value>#0</value>
                                </enumeratedValue>
                                <enumeratedValue>
                                    <name>1</name>
                                    <description>Clear the AKEPACMSR.AVC1 bit</description>
                                    <value>#1</value>
                                </enumeratedValue>
                            </enumeratedValues>
                        </field>
                        <field>
                            <name>AVC2</name>
                            <description>Virtual Channel-2 Accumulated Information Clear</description>
                            <lsb>18</lsb>
                            <msb>18</msb>
                            <access>write-only</access>
                            <enumeratedValues>
                                <enumeratedValue>
                                    <name>0</name>
                                    <description>No operation</description>
                                    <value>#0</value>
                                </enumeratedValue>
                                <enumeratedValue>
                                    <name>1</name>
                                    <description>Clear the AKEPACMSR.AVC2 bit</description>
                                    <value>#1</value>
                                </enumeratedValue>
                            </enumeratedValues>
                        </field>
                        <field>
                            <name>AVC3</name>
                            <description>Virtual Channel-3 Accumulated Information Clear</description>
                            <lsb>19</lsb>
                            <msb>19</msb>
                            <access>write-only</access>
                            <enumeratedValues>
                                <enumeratedValue>
                                    <name>0</name>
                                    <description>No operation</description>
                                    <value>#0</value>
                                </enumeratedValue>
                                <enumeratedValue>
                                    <name>1</name>
                                    <description>Clear the AKEPACMSR.AVC3 bit</description>
                                    <value>#1</value>
                                </enumeratedValue>
                            </enumeratedValues>
                        </field>
                    </fields>
                </register>
                <register>
                    <name>RXRSSR</name>
                    <description>Receive Result Saved Status Register</description>
                    <addressOffset>0x230</addressOffset>
                    <size>32</size>
                    <access>read-only</access>
                    <resetValue>0x00000000</resetValue>
                    <resetMask>0xffffffff</resetMask>
                    <fields>
                        <field>
                            <name>SLT0VLD</name>
                            <description>Slot-0 Valid Flag</description>
                            <lsb>0</lsb>
                            <msb>0</msb>
                            <access>read-only</access>
                            <enumeratedValues>
                                <enumeratedValue>
                                    <name>0</name>
                                    <description>None received</description>
                                    <value>#0</value>
                                </enumeratedValue>
                                <enumeratedValue>
                                    <name>1</name>
                                    <description>Response packet is received and stored in the RXRSS0R register</description>
                                    <value>#1</value>
                                </enumeratedValue>
                            </enumeratedValues>
                        </field>
                        <field>
                            <name>SLT1VLD</name>
                            <description>Slot-1 Valid Flag</description>
                            <lsb>1</lsb>
                            <msb>1</msb>
                            <access>read-only</access>
                            <enumeratedValues>
                                <enumeratedValue>
                                    <name>0</name>
                                    <description>None received</description>
                                    <value>#0</value>
                                </enumeratedValue>
                                <enumeratedValue>
                                    <name>1</name>
                                    <description>Response packet is received and stored in the RXRSS1R register</description>
                                    <value>#1</value>
                                </enumeratedValue>
                            </enumeratedValues>
                        </field>
                        <field>
                            <name>SLT2VLD</name>
                            <description>Slot-2 Valid Flag</description>
                            <lsb>2</lsb>
                            <msb>2</msb>
                            <access>read-only</access>
                            <enumeratedValues>
                                <enumeratedValue>
                                    <name>0</name>
                                    <description>None received</description>
                                    <value>#0</value>
                                </enumeratedValue>
                                <enumeratedValue>
                                    <name>1</name>
                                    <description>Response packet is received and stored in the RXRSS2R register</description>
                                    <value>#1</value>
                                </enumeratedValue>
                            </enumeratedValues>
                        </field>
                        <field>
                            <name>SLT3VLD</name>
                            <description>Slot-3 Valid Flag</description>
                            <lsb>3</lsb>
                            <msb>3</msb>
                            <access>read-only</access>
                            <enumeratedValues>
                                <enumeratedValue>
                                    <name>0</name>
                                    <description>None received</description>
                                    <value>#0</value>
                                </enumeratedValue>
                                <enumeratedValue>
                                    <name>1</name>
                                    <description>Response packet is received and stored in the RXRSS3R register</description>
                                    <value>#1</value>
                                </enumeratedValue>
                            </enumeratedValues>
                        </field>
                    </fields>
                </register>
                <register>
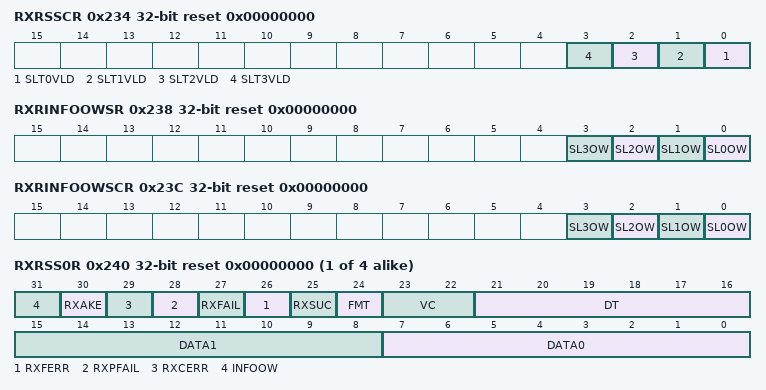
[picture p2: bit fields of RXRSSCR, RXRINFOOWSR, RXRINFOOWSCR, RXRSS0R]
                    <name>RXRSSCR</name>
                    <description>Receive Result Saved Status Clear Register</description>
                    <addressOffset>0x234</addressOffset>
                    <size>32</size>
                    <access>write-only</access>
                    <resetValue>0x00000000</resetValue>
                    <resetMask>0xffffffff</resetMask>
                    <fields>
                        <field>
                            <name>SLT0VLD</name>
                            <description>Slot-0 Valid Flag Clear</description>
                            <lsb>0</lsb>
                            <msb>0</msb>
                            <access>write-only</access>
                            <enumeratedValues>
                                <enumeratedValue>
                                    <name>0</name>
                                    <description>No operation</description>
                                    <value>#0</value>
                                </enumeratedValue>
                                <enumeratedValue>
                                    <name>1</name>
                                    <description>Clear the RXRSSR.SLT0VLD flag</description>
                                    <value>#1</value>
                                </enumeratedValue>
                            </enumeratedValues>
                        </field>
                        <field>
                            <name>SLT1VLD</name>
                            <description>Slot-1 Valid Flag Clear</description>
                            <lsb>1</lsb>
                            <msb>1</msb>
                            <access>write-only</access>
                            <enumeratedValues>
                                <enumeratedValue>
                                    <name>0</name>
                                    <description>No operation</description>
                                    <value>#0</value>
                                </enumeratedValue>
                                <enumeratedValue>
                                    <name>1</name>
                                    <description>Clear the RXRSSR.SLT1VLD flag</description>
                                    <value>#1</value>
                                </enumeratedValue>
                            </enumeratedValues>
                        </field>
                        <field>
                            <name>SLT2VLD</name>
                            <description>Slot-2 Valid Flag Clear</description>
                            <lsb>2</lsb>
                            <msb>2</msb>
                            <access>write-only</access>
                            <enumeratedValues>
                                <enumeratedValue>
                                    <name>0</name>
                                    <description>No operation</description>
                                    <value>#0</value>
                                </enumeratedValue>
                                <enumeratedValue>
                                    <name>1</name>
                                    <description>Clear the RXRSSR.SLT2VLD flag</description>
                                    <value>#1</value>
                                </enumeratedValue>
                            </enumeratedValues>
                        </field>
                        <field>
                            <name>SLT3VLD</name>
                            <description>Slot-3 Valid Flag Clear</description>
                            <lsb>3</lsb>
                            <msb>3</msb>
                            <access>write-only</access>
                            <enumeratedValues>
                                <enumeratedValue>
                                    <name>0</name>
                                    <description>No operation</description>
                                    <value>#0</value>
                                </enumeratedValue>
                                <enumeratedValue>
                                    <name>1</name>
                                    <description>Clear the RXRSSR.SLT3VLD flag</description>
                                    <value>#1</value>
                                </enumeratedValue>
                            </enumeratedValues>
                        </field>
                    </fields>
                </register>
                <register>
                    <name>RXRINFOOWSR</name>
                    <description>Receive Result Info Overwrite Status Register</description>
                    <addressOffset>0x238</addressOffset>
                    <size>32</size>
                    <access>read-only</access>
                    <resetValue>0x00000000</resetValue>
                    <resetMask>0xffffffff</resetMask>
                    <fields>
                        <field>
                            <name>SL0OW</name>
                            <description>Slot-0 Information Overwrite Flag</description>
                            <lsb>0</lsb>
                            <msb>0</msb>
                            <access>read-only</access>
                            <enumeratedValues>
                                <enumeratedValue>
                                    <name>0</name>
                                    <description>No overwritten</description>
                                    <value>#0</value>
                                </enumeratedValue>
                                <enumeratedValue>
                                    <name>1</name>
                                    <description>Slot-0 information overwritten</description>
                                    <value>#1</value>
                                </enumeratedValue>
                            </enumeratedValues>
                        </field>
                        <field>
                            <name>SL1OW</name>
                            <description>Slot-1 Information Overwrite Flag</description>
                            <lsb>1</lsb>
                            <msb>1</msb>
                            <access>read-only</access>
                            <enumeratedValues>
                                <enumeratedValue>
                                    <name>0</name>
                                    <description>No overwritten</description>
                                    <value>#0</value>
                                </enumeratedValue>
                                <enumeratedValue>
                                    <name>1</name>
                                    <description>Slot-1 information overwritten</description>
                                    <value>#1</value>
                                </enumeratedValue>
                            </enumeratedValues>
                        </field>
                        <field>
                            <name>SL2OW</name>
                            <description>Slot-2 Information Overwrite Flag</description>
                            <lsb>2</lsb>
                            <msb>2</msb>
                            <access>read-only</access>
                            <enumeratedValues>
                                <enumeratedValue>
                                    <name>0</name>
                                    <description>No overwritten</description>
                                    <value>#0</value>
                                </enumeratedValue>
                                <enumeratedValue>
                                    <name>1</name>
                                    <description>Slot-2 information overwritten</description>
                                    <value>#1</value>
                                </enumeratedValue>
                            </enumeratedValues>
                        </field>
                        <field>
                            <name>SL3OW</name>
                            <description>Slot-3 Information Overwrite Flag</description>
                            <lsb>3</lsb>
                            <msb>3</msb>
                            <access>read-only</access>
                            <enumeratedValues>
                                <enumeratedValue>
                                    <name>0</name>
                                    <description>No overwritten</description>
                                    <value>#0</value>
                                </enumeratedValue>
                                <enumeratedValue>
                                    <name>1</name>
                                    <description>Slot-3 information overwritten</description>
                                    <value>#1</value>
                                </enumeratedValue>
                            </enumeratedValues>
                        </field>
                    </fields>
                </register>
                <register>
                    <name>RXRINFOOWSCR</name>
                    <description>Receive Result Info Overwrite Status Clear Register</description>
                    <addressOffset>0x23C</addressOffset>
                    <size>32</size>
                    <access>write-only</access>
                    <resetValue>0x00000000</resetValue>
                    <resetMask>0xffffffff</resetMask>
                    <fields>
                        <field>
                            <name>SL0OW</name>
                            <description>Slot-0 Information Overwrite Flag Clear</description>
                            <lsb>0</lsb>
                            <msb>0</msb>
                            <access>write-only</access>
                            <enumeratedValues>
                                <enumeratedValue>
                                    <name>0</name>
                                    <description>No operation</description>
                                    <value>#0</value>
                                </enumeratedValue>
                                <enumeratedValue>
                                    <name>1</name>
                                    <description>Clear the RXRINFOOWSR.SL0OW flag</description>
                                    <value>#1</value>
                                </enumeratedValue>
                            </enumeratedValues>
                        </field>
                        <field>
                            <name>SL1OW</name>
                            <description>Slot-1 Information Overwrite Flag Clear</description>
                            <lsb>1</lsb>
                            <msb>1</msb>
                            <access>write-only</access>
                            <enumeratedValues>
                                <enumeratedValue>
                                    <name>0</name>
                                    <description>No operation</description>
                                    <value>#0</value>
                                </enumeratedValue>
                                <enumeratedValue>
                                    <name>1</name>
                                    <description>Clear the RXRINFOOWSR.SL1OW flag</description>
                                    <value>#1</value>
                                </enumeratedValue>
                            </enumeratedValues>
                        </field>
                        <field>
                            <name>SL2OW</name>
                            <description>Slot-2 Information Overwrite Flag Clear</description>
                            <lsb>2</lsb>
                            <msb>2</msb>
                            <access>write-only</access>
                            <enumeratedValues>
                                <enumeratedValue>
                                    <name>0</name>
                                    <description>No operation</description>
                                    <value>#0</value>
                                </enumeratedValue>
                                <enumeratedValue>
                                    <name>1</name>
                                    <description>Clear the RXRINFOOWSR.SL2OW flag</description>
                                    <value>#1</value>
                                </enumeratedValue>
                            </enumeratedValues>
                        </field>
                        <field>
                            <name>SL3OW</name>
                            <description>Slot-3 Information Overwrite Flag Clear</description>
                            <lsb>3</lsb>
                            <msb>3</msb>
                            <access>write-only</access>
                            <enumeratedValues>
                                <enumeratedValue>
                                    <name>0</name>
                                    <description>No operation</description>
                                    <value>#0</value>
                                </enumeratedValue>
                                <enumeratedValue>
                                    <name>1</name>
                                    <description>Clear the RXRINFOOWSR.SL3OW flag</description>
                                    <value>#1</value>
                                </enumeratedValue>
                            </enumeratedValues>
                        </field>
                    </fields>
                </register>
                <register>
                    <dim>4</dim>
                    <dimIncrement>0x4</dimIncrement>
                    <dimIndex>0-3</dimIndex>
                    <name>RXRSS%sR</name>
                    <description>Receive Result Save Slot-x Register (x = 0 to 3)</description>
                    <addressOffset>0x240</addressOffset>
                    <size>32</size>
                    <access>read-only</access>
                    <resetValue>0x00000000</resetValue>
                    <resetMask>0xffffffff</resetMask>
                    <fields>
                        <field>
                            <name>DATA0</name>
                            <description>Data 0</description>
                            <lsb>0</lsb>
                            <msb>7</msb>
                            <access>read-only</access>
                        </field>
                        <field>
                            <name>DATA1</name>
                            <description>Data 1</description>
                            <lsb>8</lsb>
                            <msb>15</msb>
                            <access>read-only</access>
                        </field>
                        <field>
                            <name>DT</name>
                            <description>Data Type</description>
                            <lsb>16</lsb>
                            <msb>21</msb>
                            <access>read-only</access>
                        </field>
                        <field>
                            <name>VC</name>
                            <description>Virtual Channel</description>
                            <lsb>22</lsb>
                            <msb>23</msb>
                            <access>read-only</access>
                        </field>
                        <field>
                            <name>FMT</name>
                            <description>Packet Format</description>
                            <lsb>24</lsb>
                            <msb>24</msb>
                            <access>read-only</access>
                            <enumeratedValues>
                                <enumeratedValue>
                                    <name>0</name>
                                    <description>Short packet</description>
                                    <value>#0</value>
                                </enumeratedValue>
                                <enumeratedValue>
                                    <name>1</name>
                                    <description>Long packet</description>
                                    <value>#1</value>
                                </enumeratedValue>
                            </enumeratedValues>
                        </field>
                        <field>
                            <name>RXSUC</name>
                            <description>Receive Success</description>
                            <lsb>25</lsb>
                            <msb>25</msb>
                            <access>read-only</access>
                            <enumeratedValues>
                                <enumeratedValue>
                                    <name>0</name>
                                    <description>No received</description>
                                    <value>#0</value>
                                </enumeratedValue>
                                <enumeratedValue>
                                    <name>1</name>
                                    <description>Response packet or ACK trigger received</description>
                                    <value>#1</value>
                                </enumeratedValue>
                            </enumeratedValues>
                        </field>
                        <field>
                            <name>RXFERR</name>
                            <description>Fatal Error</description>
                            <lsb>26</lsb>
                            <msb>26</msb>
                            <access>read-only</access>
                            <enumeratedValues>
                                <enumeratedValue>
                                    <name>0</name>
                                    <description>No fatal error</description>
                                    <value>#0</value>
                                </enumeratedValue>
                                <enumeratedValue>
                                    <name>1</name>
                                    <description>Fatal timeout occurred during BTA</description>
                                    <value>#1</value>
                                </enumeratedValue>
                            </enumeratedValues>
                        </field>
                        <field>
                            <name>RXFAIL</name>
                            <description>Receive Fail</description>
                            <lsb>27</lsb>
                            <msb>27</msb>
                            <access>read-only</access>
                            <enumeratedValues>
                                <enumeratedValue>
                                    <name>0</name>
                                    <description>No error</description>
                                    <value>#0</value>
                                </enumeratedValue>
                                <enumeratedValue>
                                    <name>1</name>
                                    <description>Expected receive not done</description>
                                    <value>#1</value>
                                </enumeratedValue>
                            </enumeratedValues>
                        </field>
                        <field>
                            <name>RXPFAIL</name>
                            <description>Receive Packet Data Fail</description>
                            <lsb>28</lsb>
                            <msb>28</msb>
                            <access>read-only</access>
                            <enumeratedValues>
                                <enumeratedValue>
                                    <name>0</name>
                                    <description>No error</description>
                                    <value>#0</value>
                                </enumeratedValue>
                                <enumeratedValue>
                                    <name>1</name>
                                    <description>Payload data not saved correctly</description>
                                    <value>#1</value>
                                </enumeratedValue>
                            </enumeratedValues>
                        </field>
                        <field>
                            <name>RXCERR</name>
                            <description>Receive Correctable Error</description>
                            <lsb>29</lsb>
                            <msb>29</msb>
                            <access>read-only</access>
                            <enumeratedValues>
                                <enumeratedValue>
                                    <name>0</name>
                                    <description>No error</description>
                                    <value>#0</value>
                                </enumeratedValue>
                                <enumeratedValue>
                                    <name>1</name>
                                    <description>Correctable error detected</description>
                                    <value>#1</value>
                                </enumeratedValue>
                            </enumeratedValues>
                        </field>
                        <field>
                            <name>RXAKE</name>
                            <description>Receive Acknowledge and Error Report Packet</description>
                            <lsb>30</lsb>
                            <msb>30</msb>
                            <access>read-only</access>
                            <enumeratedValues>
                                <enumeratedValue>
                                    <name>0</name>
                                    <description>No received</description>
                                    <value>#0</value>
                                </enumeratedValue>
                                <enumeratedValue>
                                    <name>1</name>
                                    <description>An Acknowledge and Error Report packet received</description>
                                    <value>#1</value>
                                </enumeratedValue>
                            </enumeratedValues>
                        </field>
                        <field>
                            <name>INFOOW</name>
                            <description>Information Overwrite</description>
                            <lsb>31</lsb>
                            <msb>31</msb>
                            <access>read-only</access>
                            <enumeratedValues>
                                <enumeratedValue>
                                    <name>0</name>
                                    <description>No update</description>
                                    <value>#0</value>
                                </enumeratedValue>
                                <enumeratedValue>
                                    <name>1</name>
                                    <description>This register information (RXRSSxR[30:0]) was overwritten</description>
                                    <value>#1</value>
                                </enumeratedValue>
                            </enumeratedValues>
                        </field>
                    </fields>
                </register>
                <register>
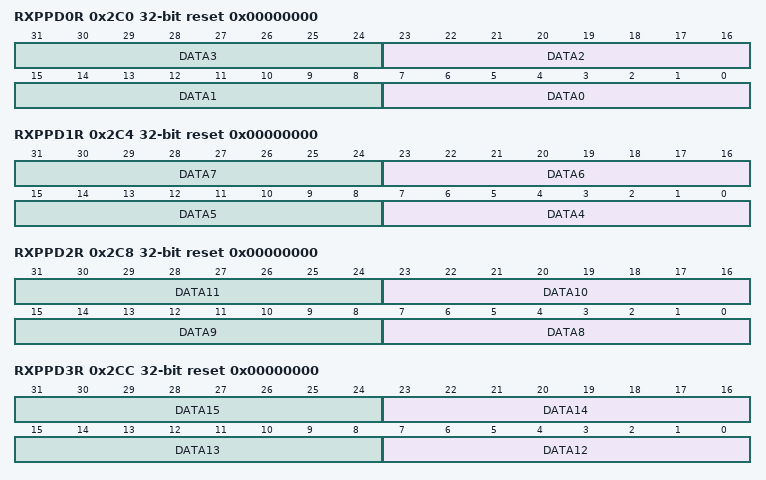
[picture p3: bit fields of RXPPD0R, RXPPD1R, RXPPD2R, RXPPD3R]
                    <name>RXPPD0R</name>
                    <description>Receive Packet Payload Data 0 Register</description>
                    <addressOffset>0x2C0</addressOffset>
                    <size>32</size>
                    <access>read-only</access>
                    <resetValue>0x00000000</resetValue>
                    <resetMask>0xffffffff</resetMask>
                    <fields>
                        <field>
                            <name>DATA0</name>
                            <description>Payload Data 0</description>
                            <lsb>0</lsb>
                            <msb>7</msb>
                            <access>read-only</access>
                        </field>
                        <field>
                            <name>DATA1</name>
                            <description>Payload Data 1</description>
                            <lsb>8</lsb>
                            <msb>15</msb>
                            <access>read-only</access>
                        </field>
                        <field>
                            <name>DATA2</name>
                            <description>Payload Data 2</description>
                            <lsb>16</lsb>
                            <msb>23</msb>
                            <access>read-only</access>
                        </field>
                        <field>
                            <name>DATA3</name>
                            <description>Payload Data 3</description>
                            <lsb>24</lsb>
                            <msb>31</msb>
                            <access>read-only</access>
                        </field>
                    </fields>
                </register>
                <register>
                    <name>RXPPD1R</name>
                    <description>Receive Packet Payload Data 1 Register</description>
                    <addressOffset>0x2C4</addressOffset>
                    <size>32</size>
                    <access>read-only</access>
                    <resetValue>0x00000000</resetValue>
                    <resetMask>0xffffffff</resetMask>
                    <fields>
                        <field>
                            <name>DATA4</name>
                            <description>Payload Data 4</description>
                            <lsb>0</lsb>
                            <msb>7</msb>
                            <access>read-only</access>
                        </field>
                        <field>
                            <name>DATA5</name>
                            <description>Payload Data 5</description>
                            <lsb>8</lsb>
                            <msb>15</msb>
                            <access>read-only</access>
                        </field>
                        <field>
                            <name>DATA6</name>
                            <description>Payload Data 6</description>
                            <lsb>16</lsb>
                            <msb>23</msb>
                            <access>read-only</access>
                        </field>
                        <field>
                            <name>DATA7</name>
                            <description>Payload Data 7</description>
                            <lsb>24</lsb>
                            <msb>31</msb>
                            <access>read-only</access>
                        </field>
                    </fields>
                </register>
                <register>
                    <name>RXPPD2R</name>
                    <description>Receive Packet Payload Data 2 Register</description>
                    <addressOffset>0x2C8</addressOffset>
                    <size>32</size>
                    <access>read-only</access>
                    <resetValue>0x00000000</resetValue>
                    <resetMask>0xffffffff</resetMask>
                    <fields>
                        <field>
                            <name>DATA8</name>
                            <description>Payload Data 8</description>
                            <lsb>0</lsb>
                            <msb>7</msb>
                            <access>read-only</access>
                        </field>
                        <field>
                            <name>DATA9</name>
                            <description>Payload Data 9</description>
                            <lsb>8</lsb>
                            <msb>15</msb>
                            <access>read-only</access>
                        </field>
                        <field>
                            <name>DATA10</name>
                            <description>Payload Data 10</description>
                            <lsb>16</lsb>
                            <msb>23</msb>
                            <access>read-only</access>
                        </field>
                        <field>
                            <name>DATA11</name>
                            <description>Payload Data 11</description>
                            <lsb>24</lsb>
                            <msb>31</msb>
                            <access>read-only</access>
                        </field>
                    </fields>
                </register>
                <register>
                    <name>RXPPD3R</name>
                    <description>Receive Packet Payload Data 3 Register</description>
                    <addressOffset>0x2CC</addressOffset>
                    <size>32</size>
                    <access>read-only</access>
                    <resetValue>0x00000000</resetValue>
                    <resetMask>0xffffffff</resetMask>
                    <fields>
                        <field>
                            <name>DATA12</name>
                            <description>Payload Data 12</description>
                            <lsb>0</lsb>
                            <msb>7</msb>
                            <access>read-only</access>
                        </field>
                        <field>
                            <name>DATA13</name>
                            <description>Payload Data 13</description>
                            <lsb>8</lsb>
                            <msb>15</msb>
                            <access>read-only</access>
                        </field>
                        <field>
                            <name>DATA14</name>
                            <description>Payload Data 14</description>
                            <lsb>16</lsb>
                            <msb>23</msb>
                            <access>read-only</access>
                        </field>
                        <field>
                            <name>DATA15</name>
                            <description>Payload Data 15</description>
                            <lsb>24</lsb>
                            <msb>31</msb>
                            <access>read-only</access>
                        </field>
                    </fields>
                </register>
                <register>
                    <name>HSTXTOSETR</name>
                    <description>HS TX Timeout Set Register</description>
                    <addressOffset>0x2E0</addressOffset>
                    <size>32</size>
                    <access>read-write</access>
                    <resetValue>0x00000000</resetValue>
                    <resetMask>0xffffffff</resetMask>
                    <fields>
                        <field>
                            <name>HTXTO</name>
                            <description>HS TX Timeout Count</description>
                            <lsb>0</lsb>
                            <msb>31</msb>
                            <access>read-write</access>
                        </field>
                    </fields>
                </register>
                <register>
                    <name>LRXHTOSETR</name>
                    <description>LRX-H Timeout Set Register</description>
                    <addressOffset>0x2E4</addressOffset>
                    <size>32</size>
                    <access>read-write</access>
                    <resetValue>0x00000000</resetValue>
                    <resetMask>0xffffffff</resetMask>
                    <fields>
                        <field>
                            <name>LRXHTO</name>
                            <description>LP-RX Host Processor Timeout</description>
                            <lsb>0</lsb>
                            <msb>31</msb>
                            <access>read-write</access>
                        </field>
                    </fields>
                </register>
                <register>
                    <name>TATOSETR</name>
                    <description>TA Timeout Set Register</description>
                    <addressOffset>0x2E8</addressOffset>
                    <size>32</size>
                    <access>read-write</access>
                    <resetValue>0x00000000</resetValue>
                    <resetMask>0xffffffff</resetMask>
                    <fields>
                        <field>
                            <name>TATO</name>
                            <description>Turnaround Acknowledge Timeout</description>
                            <lsb>0</lsb>
                            <msb>31</msb>
                            <access>read-write</access>
                        </field>
                    </fields>
                </register>
                <register>
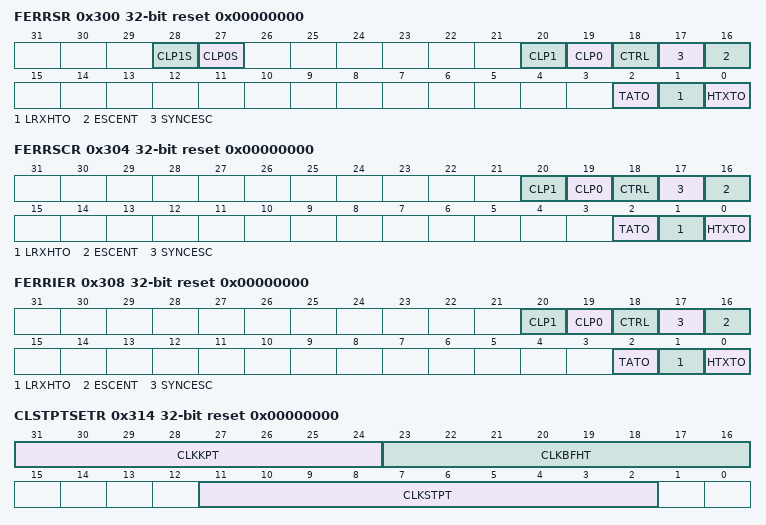
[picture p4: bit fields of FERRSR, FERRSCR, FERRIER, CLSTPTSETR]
                    <name>FERRSR</name>
                    <description>Fatal Error Status Register</description>
                    <addressOffset>0x300</addressOffset>
                    <size>32</size>
                    <access>read-only</access>
                    <resetValue>0x00000000</resetValue>
                    <resetMask>0xffffffff</resetMask>
                    <fields>
                        <field>
                            <name>HTXTO</name>
                            <description>HS TX Timeout Interrupt Flag</description>
                            <lsb>0</lsb>
                            <msb>0</msb>
                            <access>read-only</access>
                            <enumeratedValues>
                                <enumeratedValue>
                                    <name>0</name>
                                    <description>No detected</description>
                                    <value>#0</value>
                                </enumeratedValue>
                                <enumeratedValue>
                                    <name>1</name>
                                    <description>HS TX Timeout (HTX_TO) detected</description>
                                    <value>#1</value>
                                </enumeratedValue>
                            </enumeratedValues>
                        </field>
                        <field>
                            <name>LRXHTO</name>
                            <description>LP-RX Host Processor Timeout Interrupt Flag</description>
                            <lsb>1</lsb>
                            <msb>1</msb>
                            <access>read-only</access>
                            <enumeratedValues>
                                <enumeratedValue>
                                    <name>0</name>
                                    <description>No detected</description>
                                    <value>#0</value>
                                </enumeratedValue>
                                <enumeratedValue>
                                    <name>1</name>
                                    <description>LP-RX Host Processor Timeout (LRX-H_TO) detected</description>
                                    <value>#1</value>
                                </enumeratedValue>
                            </enumeratedValues>
                        </field>
                        <field>
                            <name>TATO</name>
                            <description>Turnaround Acknowledge Timeout Interrupt Flag</description>
                            <lsb>2</lsb>
                            <msb>2</msb>
                            <access>read-only</access>
                            <enumeratedValues>
                                <enumeratedValue>
                                    <name>0</name>
                                    <description>No detected</description>
                                    <value>#0</value>
                                </enumeratedValue>
                                <enumeratedValue>
                                    <name>1</name>
                                    <description>Turnaround Acknowledge Timeout (TA_TO) detected</description>
                                    <value>#1</value>
                                </enumeratedValue>
                            </enumeratedValues>
                        </field>
                        <field>
                            <name>ESCENT</name>
                            <description>Escape mode Entry Error Interrupt Flag</description>
                            <lsb>16</lsb>
                            <msb>16</msb>
                            <access>read-only</access>
                            <enumeratedValues>
                                <enumeratedValue>
                                    <name>0</name>
                                    <description>No error detected</description>
                                    <value>#0</value>
                                </enumeratedValue>
                                <enumeratedValue>
                                    <name>1</name>
                                    <description>Escape mode Entry Error (ErrEsc) detected</description>
                                    <value>#1</value>
                                </enumeratedValue>
                            </enumeratedValues>
                        </field>
                        <field>
                            <name>SYNCESC</name>
                            <description>LPDT Sync Error Interrupt Flag</description>
                            <lsb>17</lsb>
                            <msb>17</msb>
                            <access>read-only</access>
                            <enumeratedValues>
                                <enumeratedValue>
                                    <name>0</name>
                                    <description>No error detected</description>
                                    <value>#0</value>
                                </enumeratedValue>
                                <enumeratedValue>
                                    <name>1</name>
                                    <description>LPDT Synchronization Error (ErrSyncEsc) detected</description>
                                    <value>#1</value>
                                </enumeratedValue>
                            </enumeratedValues>
                        </field>
                        <field>
                            <name>CTRL</name>
                            <description>Control Error Interrupt Flag</description>
                            <lsb>18</lsb>
                            <msb>18</msb>
                            <access>read-only</access>
                            <enumeratedValues>
                                <enumeratedValue>
                                    <name>0</name>
                                    <description>No error detected</description>
                                    <value>#0</value>
                                </enumeratedValue>
                                <enumeratedValue>
                                    <name>1</name>
                                    <description>Control Error (ErrControl) detected</description>
                                    <value>#1</value>
                                </enumeratedValue>
                            </enumeratedValues>
                        </field>
                        <field>
                            <name>CLP0</name>
                            <description>LP0 Contention Error Interrupt Flag</description>
                            <lsb>19</lsb>
                            <msb>19</msb>
                            <access>read-only</access>
                            <enumeratedValues>
                                <enumeratedValue>
                                    <name>0</name>
                                    <description>No error detected</description>
                                    <value>#0</value>
                                </enumeratedValue>
                                <enumeratedValue>
                                    <name>1</name>
                                    <description>LP0 Contention Error (ErrContentionLP0) detected</description>
                                    <value>#1</value>
                                </enumeratedValue>
                            </enumeratedValues>
                        </field>
                        <field>
                            <name>CLP1</name>
                            <description>LP1 Contention Error Interrupt Flag</description>
                            <lsb>20</lsb>
                            <msb>20</msb>
                            <access>read-only</access>
                            <enumeratedValues>
                                <enumeratedValue>
                                    <name>0</name>
                                    <description>No error detected</description>
                                    <value>#0</value>
                                </enumeratedValue>
                                <enumeratedValue>
                                    <name>1</name>
                                    <description>LP1 Contention Error (ErrContentionLP1) detected</description>
                                    <value>#1</value>
                                </enumeratedValue>
                            </enumeratedValues>
                        </field>
                        <field>
                            <name>CLP0S</name>
                            <description>LP0 Contention Error Status</description>
                            <lsb>27</lsb>
                            <msb>27</msb>
                            <access>read-only</access>
                            <enumeratedValues>
                                <enumeratedValue>
                                    <name>0</name>
                                    <description>Normal state</description>
                                    <value>#0</value>
                                </enumeratedValue>
                                <enumeratedValue>
                                    <name>1</name>
                                    <description>LP0 Contention Error (ErrContentionLP0) state</description>
                                    <value>#1</value>
                                </enumeratedValue>
                            </enumeratedValues>
                        </field>
                        <field>
                            <name>CLP1S</name>
                            <description>LP1 Contention Error Status</description>
                            <lsb>28</lsb>
                            <msb>28</msb>
                            <access>read-only</access>
                            <enumeratedValues>
                                <enumeratedValue>
                                    <name>0</name>
                                    <description>Normal state</description>
                                    <value>#0</value>
                                </enumeratedValue>
                                <enumeratedValue>
                                    <name>1</name>
                                    <description>LP1 Contention Error (ErrContentionLP1) state</description>
                                    <value>#1</value>
                                </enumeratedValue>
                            </enumeratedValues>
                        </field>
                    </fields>
                </register>
                <register>
                    <name>FERRSCR</name>
                    <description>Fatal Error Status Clear Register</description>
                    <addressOffset>0x304</addressOffset>
                    <size>32</size>
                    <access>write-only</access>
                    <resetValue>0x00000000</resetValue>
                    <resetMask>0xffffffff</resetMask>
                    <fields>
                        <field>
                            <name>HTXTO</name>
                            <description>HS TX Timeout Interrupt Flag Clear</description>
                            <lsb>0</lsb>
                            <msb>0</msb>
                            <access>write-only</access>
                            <enumeratedValues>
                                <enumeratedValue>
                                    <name>0</name>
                                    <description>No operation</description>
                                    <value>#0</value>
                                </enumeratedValue>
                                <enumeratedValue>
                                    <name>1</name>
                                    <description>Clear the FERRSR.HTXTO flag</description>
                                    <value>#1</value>
                                </enumeratedValue>
                            </enumeratedValues>
                        </field>
                        <field>
                            <name>LRXHTO</name>
                            <description>LP-RX Host Processor Timeout Interrupt Flag Clear</description>
                            <lsb>1</lsb>
                            <msb>1</msb>
                            <access>write-only</access>
                            <enumeratedValues>
                                <enumeratedValue>
                                    <name>0</name>
                                    <description>No operation</description>
                                    <value>#0</value>
                                </enumeratedValue>
                                <enumeratedValue>
                                    <name>1</name>
                                    <description>Clear the FERRSR.LRXHTO flag</description>
                                    <value>#1</value>
                                </enumeratedValue>
                            </enumeratedValues>
                        </field>
                        <field>
                            <name>TATO</name>
                            <description>Turnaround Acknowledge Timeout Interrupt Flag Clear</description>
                            <lsb>2</lsb>
                            <msb>2</msb>
                            <access>write-only</access>
                            <enumeratedValues>
                                <enumeratedValue>
                                    <name>0</name>
                                    <description>No operation</description>
                                    <value>#0</value>
                                </enumeratedValue>
                                <enumeratedValue>
                                    <name>1</name>
                                    <description>Clear the FERRSR.TATO flag</description>
                                    <value>#1</value>
                                </enumeratedValue>
                            </enumeratedValues>
                        </field>
                        <field>
                            <name>ESCENT</name>
                            <description>Escape mode Entry Error Interrupt Flag Clear</description>
                            <lsb>16</lsb>
                            <msb>16</msb>
                            <access>write-only</access>
                            <enumeratedValues>
                                <enumeratedValue>
                                    <name>0</name>
                                    <description>No operation</description>
                                    <value>#0</value>
                                </enumeratedValue>
                                <enumeratedValue>
                                    <name>1</name>
                                    <description>Clear the FERRSR.ESCENT flag</description>
                                    <value>#1</value>
                                </enumeratedValue>
                            </enumeratedValues>
                        </field>
                        <field>
                            <name>SYNCESC</name>
                            <description>LPDT Sync Error Interrupt Flag Clear</description>
                            <lsb>17</lsb>
                            <msb>17</msb>
                            <access>write-only</access>
                            <enumeratedValues>
                                <enumeratedValue>
                                    <name>0</name>
                                    <description>No operation</description>
                                    <value>#0</value>
                                </enumeratedValue>
                                <enumeratedValue>
                                    <name>1</name>
                                    <description>Clear the FERRSR.SYNCESC flag</description>
                                    <value>#1</value>
                                </enumeratedValue>
                            </enumeratedValues>
                        </field>
                        <field>
                            <name>CTRL</name>
                            <description>Control Error Interrupt Flag Clear</description>
                            <lsb>18</lsb>
                            <msb>18</msb>
                            <access>write-only</access>
                            <enumeratedValues>
                                <enumeratedValue>
                                    <name>0</name>
                                    <description>No operation</description>
                                    <value>#0</value>
                                </enumeratedValue>
                                <enumeratedValue>
                                    <name>1</name>
                                    <description>Clear the FERRSR.CTRL flag</description>
                                    <value>#1</value>
                                </enumeratedValue>
                            </enumeratedValues>
                        </field>
                        <field>
                            <name>CLP0</name>
                            <description>LP0 Contention Error Interrupt Flag Clear</description>
                            <lsb>19</lsb>
                            <msb>19</msb>
                            <access>write-only</access>
                            <enumeratedValues>
                                <enumeratedValue>
                                    <name>0</name>
                                    <description>No operation</description>
                                    <value>#0</value>
                                </enumeratedValue>
                                <enumeratedValue>
                                    <name>1</name>
                                    <description>Clear the FERRSR.CLP0 flag</description>
                                    <value>#1</value>
                                </enumeratedValue>
                            </enumeratedValues>
                        </field>
                        <field>
                            <name>CLP1</name>
                            <description>LP1 Contention Error Interrupt Flag Clear</description>
                            <lsb>20</lsb>
                            <msb>20</msb>
                            <access>write-only</access>
                            <enumeratedValues>
                                <enumeratedValue>
                                    <name>0</name>
                                    <description>No operation</description>
                                    <value>#0</value>
                                </enumeratedValue>
                                <enumeratedValue>
                                    <name>1</name>
                                    <description>Clear the FERRSR.CLP1 flag</description>
                                    <value>#1</value>
                                </enumeratedValue>
                            </enumeratedValues>
                        </field>
                    </fields>
                </register>
                <register>
                    <name>FERRIER</name>
                    <description>Fatal Error Interrupt Enable Register</description>
                    <addressOffset>0x308</addressOffset>
                    <size>32</size>
                    <access>read-write</access>
                    <resetValue>0x00000000</resetValue>
                    <resetMask>0xffffffff</resetMask>
                    <fields>
                        <field>
                            <name>HTXTO</name>
                            <description>HS TX Timeout Interrupt Enable</description>
                            <lsb>0</lsb>
                            <msb>0</msb>
                            <access>read-write</access>
                            <enumeratedValues>
                                <enumeratedValue>
                                    <name>0</name>
                                    <description>Disable</description>
                                    <value>#0</value>
                                </enumeratedValue>
                                <enumeratedValue>
                                    <name>1</name>
                                    <description>Enable</description>
                                    <value>#1</value>
                                </enumeratedValue>
                            </enumeratedValues>
                        </field>
                        <field>
                            <name>LRXHTO</name>
                            <description>LP-RX Host Processor Timeout Interrupt Enable</description>
                            <lsb>1</lsb>
                            <msb>1</msb>
                            <access>read-write</access>
                            <enumeratedValues>
                                <enumeratedValue>
                                    <name>0</name>
                                    <description>Disable</description>
                                    <value>#0</value>
                                </enumeratedValue>
                                <enumeratedValue>
                                    <name>1</name>
                                    <description>Enable</description>
                                    <value>#1</value>
                                </enumeratedValue>
                            </enumeratedValues>
                        </field>
                        <field>
                            <name>TATO</name>
                            <description>Turnaround Acknowledge Timeout Interrupt Enable</description>
                            <lsb>2</lsb>
                            <msb>2</msb>
                            <access>read-write</access>
                            <enumeratedValues>
                                <enumeratedValue>
                                    <name>0</name>
                                    <description>Disable</description>
                                    <value>#0</value>
                                </enumeratedValue>
                                <enumeratedValue>
                                    <name>1</name>
                                    <description>Enable</description>
                                    <value>#1</value>
                                </enumeratedValue>
                            </enumeratedValues>
                        </field>
                        <field>
                            <name>ESCENT</name>
                            <description>Escape mode Entry Error Interrupt Enable</description>
                            <lsb>16</lsb>
                            <msb>16</msb>
                            <access>read-write</access>
                            <enumeratedValues>
                                <enumeratedValue>
                                    <name>0</name>
                                    <description>Disable</description>
                                    <value>#0</value>
                                </enumeratedValue>
                                <enumeratedValue>
                                    <name>1</name>
                                    <description>Enable</description>
                                    <value>#1</value>
                                </enumeratedValue>
                            </enumeratedValues>
                        </field>
                        <field>
                            <name>SYNCESC</name>
                            <description>LPDT Sync Error Interrupt Enable</description>
                            <lsb>17</lsb>
                            <msb>17</msb>
                            <access>read-write</access>
                            <enumeratedValues>
                                <enumeratedValue>
                                    <name>0</name>
                                    <description>Disable</description>
                                    <value>#0</value>
                                </enumeratedValue>
                                <enumeratedValue>
                                    <name>1</name>
                                    <description>Enable</description>
                                    <value>#1</value>
                                </enumeratedValue>
                            </enumeratedValues>
                        </field>
                        <field>
                            <name>CTRL</name>
                            <description>Control Error Interrupt Enable</description>
                            <lsb>18</lsb>
                            <msb>18</msb>
                            <access>read-write</access>
                            <enumeratedValues>
                                <enumeratedValue>
                                    <name>0</name>
                                    <description>Disable</description>
                                    <value>#0</value>
                                </enumeratedValue>
                                <enumeratedValue>
                                    <name>1</name>
                                    <description>Enable</description>
                                    <value>#1</value>
                                </enumeratedValue>
                            </enumeratedValues>
                        </field>
                        <field>
                            <name>CLP0</name>
                            <description>LP0 Contention Error Interrupt Enable</description>
                            <lsb>19</lsb>
                            <msb>19</msb>
                            <access>read-write</access>
                            <enumeratedValues>
                                <enumeratedValue>
                                    <name>0</name>
                                    <description>Disable</description>
                                    <value>#0</value>
                                </enumeratedValue>
                                <enumeratedValue>
                                    <name>1</name>
                                    <description>Enable</description>
                                    <value>#1</value>
                                </enumeratedValue>
                            </enumeratedValues>
                        </field>
                        <field>
                            <name>CLP1</name>
                            <description>LP1 Contention Error Interrupt Enable</description>
                            <lsb>20</lsb>
                            <msb>20</msb>
                            <access>read-write</access>
                            <enumeratedValues>
                                <enumeratedValue>
                                    <name>0</name>
                                    <description>Disable</description>
                                    <value>#0</value>
                                </enumeratedValue>
                                <enumeratedValue>
                                    <name>1</name>
                                    <description>Enable</description>
                                    <value>#1</value>
                                </enumeratedValue>
                            </enumeratedValues>
                        </field>
                    </fields>
                </register>
                <register>
                    <name>CLSTPTSETR</name>
                    <description>Clock Lane Stop Time Set Register</description>
                    <addressOffset>0x314</addressOffset>
                    <size>32</size>
                    <access>read-write</access>
                    <resetValue>0x00000000</resetValue>
                    <resetMask>0xffffffff</resetMask>
                    <fields>
                        <field>
                            <name>CLKSTPT</name>
                            <description>Clock Stop Time</description>
                            <lsb>2</lsb>
                            <msb>11</msb>
                            <access>read-write</access>
                        </field>
                        <field>
                            <name>CLKBFHT</name>
                            <description>Clock Beforehand Time</description>
                            <lsb>16</lsb>
                            <msb>23</msb>
                            <access>read-write</access>
                        </field>
                        <field>
                            <name>CLKKPT</name>
                            <description>Clock Keep Time</description>
                            <lsb>24</lsb>
                            <msb>31</msb>
                            <access>read-write</access>
                        </field>
                    </fields>
                </register>
                <register>
                    <name>LPTRNSTSETR</name>
                    <description>LP Transition Time Set Register</description>
                    <addressOffset>0x318</addressOffset>
                    <size>32</size>
                    <access>read-write</access>
                    <resetValue>0x00000000</resetValue>
                    <resetMask>0xffffffff</resetMask>
                    <fields>
                        <field>
                            <name>GOLPBKT</name>
                            <description>Go LP and Back Time</description>
                            <lsb>0</lsb>
                            <msb>9</msb>
                            <access>read-write</access>
                        </field>
                    </fields>
                </register>
                <register>
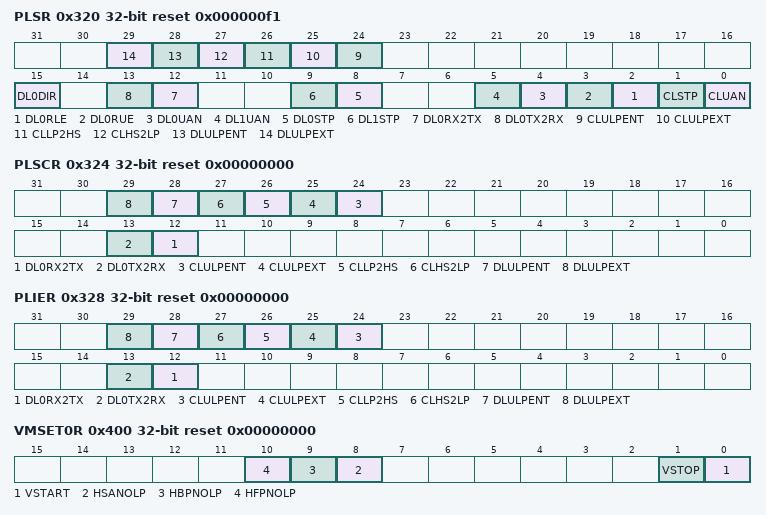
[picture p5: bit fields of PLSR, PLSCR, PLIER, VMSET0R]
                    <name>PLSR</name>
                    <description>Physical Lane Status Register</description>
                    <addressOffset>0x320</addressOffset>
                    <size>32</size>
                    <access>read-only</access>
                    <resetValue>0x000000f1</resetValue>
                    <resetMask>0xffffffff</resetMask>
                    <fields>
                        <field>
                            <name>CLUAN</name>
                            <description>Clock Lane UlpsActiveNot Status</description>
                            <lsb>0</lsb>
                            <msb>0</msb>
                            <access>read-only</access>
                            <enumeratedValues>
                                <enumeratedValue>
                                    <name>0</name>
                                    <description>In ULP state</description>
                                    <value>#0</value>
                                </enumeratedValue>
                                <enumeratedValue>
                                    <name>1</name>
                                    <description>Not in ULP state</description>
                                    <value>#1</value>
                                </enumeratedValue>
                            </enumeratedValues>
                        </field>
                        <field>
                            <name>CLSTP</name>
                            <description>Clock Lane Stop Status</description>
                            <lsb>1</lsb>
                            <msb>1</msb>
                            <access>read-only</access>
                            <enumeratedValues>
                                <enumeratedValue>
                                    <name>0</name>
                                    <description>Not in Stop state</description>
                                    <value>#0</value>
                                </enumeratedValue>
                                <enumeratedValue>
                                    <name>1</name>
                                    <description>In Stop state</description>
                                    <value>#1</value>
                                </enumeratedValue>
                            </enumeratedValues>
                        </field>
                        <field>
                            <name>DL0RLE</name>
                            <description>Data Lane-0 RxLpdtEsc Status</description>
                            <lsb>2</lsb>
                            <msb>2</msb>
                            <access>read-only</access>
                            <enumeratedValues>
                                <enumeratedValue>
                                    <name>0</name>
                                    <description>Not in Escape Low-Power Data Receive mode</description>
                                    <value>#0</value>
                                </enumeratedValue>
                                <enumeratedValue>
                                    <name>1</name>
                                    <description>In Escape Low-Power Data Receive mode</description>
                                    <value>#1</value>
                                </enumeratedValue>
                            </enumeratedValues>
                        </field>
                        <field>
                            <name>DL0RUE</name>
                            <description>Data Lane-0 RxUlpsEsc Status</description>
                            <lsb>3</lsb>
                            <msb>3</msb>
                            <access>read-only</access>
                            <enumeratedValues>
                                <enumeratedValue>
                                    <name>0</name>
                                    <description>Not in Escape Ultra-Low Power (Receive) mode</description>
                                    <value>#0</value>
                                </enumeratedValue>
                                <enumeratedValue>
                                    <name>1</name>
                                    <description>In Escape Ultra-Low Power (Receive) mode</description>
                                    <value>#1</value>
                                </enumeratedValue>
                            </enumeratedValues>
                        </field>
                        <field>
                            <name>DL0UAN</name>
                            <description>Data Lane-0 UlpsActiveNot Status</description>
                            <lsb>4</lsb>
                            <msb>4</msb>
                            <access>read-only</access>
                            <enumeratedValues>
                                <enumeratedValue>
                                    <name>0</name>
                                    <description>In ULP state</description>
                                    <value>#0</value>
                                </enumeratedValue>
                                <enumeratedValue>
                                    <name>1</name>
                                    <description>Not in ULP state</description>
                                    <value>#1</value>
                                </enumeratedValue>
                            </enumeratedValues>
                        </field>
                        <field>
                            <name>DL1UAN</name>
                            <description>Data Lane-1 UlpsActiveNot Status</description>
                            <lsb>5</lsb>
                            <msb>5</msb>
                            <access>read-only</access>
                            <enumeratedValues>
                                <enumeratedValue>
                                    <name>0</name>
                                    <description>In ULP state</description>
                                    <value>#0</value>
                                </enumeratedValue>
                                <enumeratedValue>
                                    <name>1</name>
                                    <description>Not in ULP state</description>
                                    <value>#1</value>
                                </enumeratedValue>
                            </enumeratedValues>
                        </field>
                        <field>
                            <name>DL0STP</name>
                            <description>Data Lane-0 Stop Status</description>
                            <lsb>8</lsb>
                            <msb>8</msb>
                            <access>read-only</access>
                            <enumeratedValues>
                                <enumeratedValue>
                                    <name>0</name>
                                    <description>Not in Stop state</description>
                                    <value>#0</value>
                                </enumeratedValue>
                                <enumeratedValue>
                                    <name>1</name>
                                    <description>In Stop state</description>
                                    <value>#1</value>
                                </enumeratedValue>
                            </enumeratedValues>
                        </field>
                        <field>
                            <name>DL1STP</name>
                            <description>Data Lane-1 Stop Status</description>
                            <lsb>9</lsb>
                            <msb>9</msb>
                            <access>read-only</access>
                            <enumeratedValues>
                                <enumeratedValue>
                                    <name>0</name>
                                    <description>Not in Stop state</description>
                                    <value>#0</value>
                                </enumeratedValue>
                                <enumeratedValue>
                                    <name>1</name>
                                    <description>In Stop state</description>
                                    <value>#1</value>
                                </enumeratedValue>
                            </enumeratedValues>
                        </field>
                        <field>
                            <name>DL0RX2TX</name>
                            <description>Data Lane-0 RX to TX Transition Interrupt Flag</description>
                            <lsb>12</lsb>
                            <msb>12</msb>
                            <access>read-only</access>
                            <enumeratedValues>
                                <enumeratedValue>
                                    <name>0</name>
                                    <description>Not detected</description>
                                    <value>#0</value>
                                </enumeratedValue>
                                <enumeratedValue>
                                    <name>1</name>
                                    <description>Detected</description>
                                    <value>#1</value>
                                </enumeratedValue>
                            </enumeratedValues>
                        </field>
                        <field>
                            <name>DL0TX2RX</name>
                            <description>Data Lane-0 TX to RX Transition Interrupt Flag</description>
                            <lsb>13</lsb>
                            <msb>13</msb>
                            <access>read-only</access>
                            <enumeratedValues>
                                <enumeratedValue>
                                    <name>0</name>
                                    <description>Not detected</description>
                                    <value>#0</value>
                                </enumeratedValue>
                                <enumeratedValue>
                                    <name>1</name>
                                    <description>Detected</description>
                                    <value>#1</value>
                                </enumeratedValue>
                            </enumeratedValues>
                        </field>
                        <field>
                            <name>DL0DIR</name>
                            <description>Data Lane-0 Direction</description>
                            <lsb>15</lsb>
                            <msb>15</msb>
                            <access>read-only</access>
                            <enumeratedValues>
                                <enumeratedValue>
                                    <name>0</name>
                                    <description>Transmitter</description>
                                    <value>#0</value>
                                </enumeratedValue>
                                <enumeratedValue>
                                    <name>1</name>
                                    <description>Receiver</description>
                                    <value>#1</value>
                                </enumeratedValue>
                            </enumeratedValues>
                        </field>
                        <field>
                            <name>CLULPENT</name>
                            <description>Clock Lane ULPS Enter Interrupt Flag</description>
                            <lsb>24</lsb>
                            <msb>24</msb>
                            <access>read-only</access>
                            <enumeratedValues>
                                <enumeratedValue>
                                    <name>0</name>
                                    <description>Not detected</description>
                                    <value>#0</value>
                                </enumeratedValue>
                                <enumeratedValue>
                                    <name>1</name>
                                    <description>Detected</description>
                                    <value>#1</value>
                                </enumeratedValue>
                            </enumeratedValues>
                        </field>
                        <field>
                            <name>CLULPEXT</name>
                            <description>Clock Lane ULPS Exit Interrupt Flag</description>
                            <lsb>25</lsb>
                            <msb>25</msb>
                            <access>read-only</access>
                            <enumeratedValues>
                                <enumeratedValue>
                                    <name>0</name>
                                    <description>Not detected</description>
                                    <value>#0</value>
                                </enumeratedValue>
                                <enumeratedValue>
                                    <name>1</name>
                                    <description>Detected</description>
                                    <value>#1</value>
                                </enumeratedValue>
                            </enumeratedValues>
                        </field>
                        <field>
                            <name>CLLP2HS</name>
                            <description>Clock Lane LP to HS Transition Interrupt Flag</description>
                            <lsb>26</lsb>
                            <msb>26</msb>
                            <access>read-only</access>
                            <enumeratedValues>
                                <enumeratedValue>
                                    <name>0</name>
                                    <description>Not detected</description>
                                    <value>#0</value>
                                </enumeratedValue>
                                <enumeratedValue>
                                    <name>1</name>
                                    <description>Detected</description>
                                    <value>#1</value>
                                </enumeratedValue>
                            </enumeratedValues>
                        </field>
                        <field>
                            <name>CLHS2LP</name>
                            <description>Clock Lane HS to LP Transition Interrupt Flag</description>
                            <lsb>27</lsb>
                            <msb>27</msb>
                            <access>read-only</access>
                            <enumeratedValues>
                                <enumeratedValue>
                                    <name>0</name>
                                    <description>Not detected</description>
                                    <value>#0</value>
                                </enumeratedValue>
                                <enumeratedValue>
                                    <name>1</name>
                                    <description>Detected</description>
                                    <value>#1</value>
                                </enumeratedValue>
                            </enumeratedValues>
                        </field>
                        <field>
                            <name>DLULPENT</name>
                            <description>Data Lane ULPS Enter Interrupt Flag</description>
                            <lsb>28</lsb>
                            <msb>28</msb>
                            <access>read-only</access>
                            <enumeratedValues>
                                <enumeratedValue>
                                    <name>0</name>
                                    <description>Not detected</description>
                                    <value>#0</value>
                                </enumeratedValue>
                                <enumeratedValue>
                                    <name>1</name>
                                    <description>Detected</description>
                                    <value>#1</value>
                                </enumeratedValue>
                            </enumeratedValues>
                        </field>
                        <field>
                            <name>DLULPEXT</name>
                            <description>Data Lane ULPS Exit Interrupt Flag</description>
                            <lsb>29</lsb>
                            <msb>29</msb>
                            <access>read-only</access>
                            <enumeratedValues>
                                <enumeratedValue>
                                    <name>0</name>
                                    <description>Not detected</description>
                                    <value>#0</value>
                                </enumeratedValue>
                                <enumeratedValue>
                                    <name>1</name>
                                    <description>Detected</description>
                                    <value>#1</value>
                                </enumeratedValue>
                            </enumeratedValues>
                        </field>
                    </fields>
                </register>
                <register>
                    <name>PLSCR</name>
                    <description>Physical Lane Status Clear Register</description>
                    <addressOffset>0x324</addressOffset>
                    <size>32</size>
                    <access>write-only</access>
                    <resetValue>0x00000000</resetValue>
                    <resetMask>0xffffffff</resetMask>
                    <fields>
                        <field>
                            <name>DL0RX2TX</name>
                            <description>Data Lane-0 RX to TX Transition Interrupt Flag Clear</description>
                            <lsb>12</lsb>
                            <msb>12</msb>
                            <access>write-only</access>
                            <enumeratedValues>
                                <enumeratedValue>
                                    <name>0</name>
                                    <description>No operation</description>
                                    <value>#0</value>
                                </enumeratedValue>
                                <enumeratedValue>
                                    <name>1</name>
                                    <description>Clear the PLSR.DL0RX2TX flag</description>
                                    <value>#1</value>
                                </enumeratedValue>
                            </enumeratedValues>
                        </field>
                        <field>
                            <name>DL0TX2RX</name>
                            <description>Data Lane-0 TX to RX Transition Interrupt Flag Clear</description>
                            <lsb>13</lsb>
                            <msb>13</msb>
                            <access>write-only</access>
                            <enumeratedValues>
                                <enumeratedValue>
                                    <name>0</name>
                                    <description>No operation</description>
                                    <value>#0</value>
                                </enumeratedValue>
                                <enumeratedValue>
                                    <name>1</name>
                                    <description>Clear the PLSR.DL0TX2RX flag</description>
                                    <value>#1</value>
                                </enumeratedValue>
                            </enumeratedValues>
                        </field>
                        <field>
                            <name>CLULPENT</name>
                            <description>Clock Lane ULPS Enter Interrupt Flag Clear</description>
                            <lsb>24</lsb>
                            <msb>24</msb>
                            <access>write-only</access>
                            <enumeratedValues>
                                <enumeratedValue>
                                    <name>0</name>
                                    <description>No operation</description>
                                    <value>#0</value>
                                </enumeratedValue>
                                <enumeratedValue>
                                    <name>1</name>
                                    <description>Clear the PLSR.CLULPENT flag</description>
                                    <value>#1</value>
                                </enumeratedValue>
                            </enumeratedValues>
                        </field>
                        <field>
                            <name>CLULPEXT</name>
                            <description>Clock Lane ULPS Exit Interrupt Flag Clear</description>
                            <lsb>25</lsb>
                            <msb>25</msb>
                            <access>write-only</access>
                            <enumeratedValues>
                                <enumeratedValue>
                                    <name>0</name>
                                    <description>No operation</description>
                                    <value>#0</value>
                                </enumeratedValue>
                                <enumeratedValue>
                                    <name>1</name>
                                    <description>Clear the PLSR.CLULPEXT flag</description>
                                    <value>#1</value>
                                </enumeratedValue>
                            </enumeratedValues>
                        </field>
                        <field>
                            <name>CLLP2HS</name>
                            <description>Clock Lane LP to HS Transition Interrupt Flag Clear</description>
                            <lsb>26</lsb>
                            <msb>26</msb>
                            <access>write-only</access>
                            <enumeratedValues>
                                <enumeratedValue>
                                    <name>0</name>
                                    <description>No operation</description>
                                    <value>#0</value>
                                </enumeratedValue>
                                <enumeratedValue>
                                    <name>1</name>
                                    <description>Clear the PLSR.CLLP2HS flag</description>
                                    <value>#1</value>
                                </enumeratedValue>
                            </enumeratedValues>
                        </field>
                        <field>
                            <name>CLHS2LP</name>
                            <description>Clock Lane HS to LP Transition Interrupt Flag Clear</description>
                            <lsb>27</lsb>
                            <msb>27</msb>
                            <access>write-only</access>
                            <enumeratedValues>
                                <enumeratedValue>
                                    <name>0</name>
                                    <description>No operation</description>
                                    <value>#0</value>
                                </enumeratedValue>
                                <enumeratedValue>
                                    <name>1</name>
                                    <description>Clear the PLSR.CLHS2LP flag</description>
                                    <value>#1</value>
                                </enumeratedValue>
                            </enumeratedValues>
                        </field>
                        <field>
                            <name>DLULPENT</name>
                            <description>Data Lane ULPS Enter Interrupt Flag Clear</description>
                            <lsb>28</lsb>
                            <msb>28</msb>
                            <access>write-only</access>
                            <enumeratedValues>
                                <enumeratedValue>
                                    <name>0</name>
                                    <description>No operation</description>
                                    <value>#0</value>
                                </enumeratedValue>
                                <enumeratedValue>
                                    <name>1</name>
                                    <description>Clear the PLSR.DLULPENT flag</description>
                                    <value>#1</value>
                                </enumeratedValue>
                            </enumeratedValues>
                        </field>
                        <field>
                            <name>DLULPEXT</name>
                            <description>Data Lane ULPS Exit Interrupt Flag Clear</description>
                            <lsb>29</lsb>
                            <msb>29</msb>
                            <access>write-only</access>
                            <enumeratedValues>
                                <enumeratedValue>
                                    <name>0</name>
                                    <description>No operation</description>
                                    <value>#0</value>
                                </enumeratedValue>
                                <enumeratedValue>
                                    <name>1</name>
                                    <description>Clear the PLSR.DLULPEXT flag</description>
                                    <value>#1</value>
                                </enumeratedValue>
                            </enumeratedValues>
                        </field>
                    </fields>
                </register>
                <register>
                    <name>PLIER</name>
                    <description>Physical Lane Interrupt Enable Register</description>
                    <addressOffset>0x328</addressOffset>
                    <size>32</size>
                    <access>read-write</access>
                    <resetValue>0x00000000</resetValue>
                    <resetMask>0xffffffff</resetMask>
                    <fields>
                        <field>
                            <name>DL0RX2TX</name>
                            <description>Data Lane-0 RX to TX Transition Interrupt Enable</description>
                            <lsb>12</lsb>
                            <msb>12</msb>
                            <access>read-write</access>
                            <enumeratedValues>
                                <enumeratedValue>
                                    <name>0</name>
                                    <description>Disable</description>
                                    <value>#0</value>
                                </enumeratedValue>
                                <enumeratedValue>
                                    <name>1</name>
                                    <description>Enable</description>
                                    <value>#1</value>
                                </enumeratedValue>
                            </enumeratedValues>
                        </field>
                        <field>
                            <name>DL0TX2RX</name>
                            <description>Data Lane-0 TX to RX Transition Interrupt Enable</description>
                            <lsb>13</lsb>
                            <msb>13</msb>
                            <access>read-write</access>
                            <enumeratedValues>
                                <enumeratedValue>
                                    <name>0</name>
                                    <description>Disable</description>
                                    <value>#0</value>
                                </enumeratedValue>
                                <enumeratedValue>
                                    <name>1</name>
                                    <description>Enable</description>
                                    <value>#1</value>
                                </enumeratedValue>
                            </enumeratedValues>
                        </field>
                        <field>
                            <name>CLULPENT</name>
                            <description>Clock Lane ULPS Enter Interrupt Enable</description>
                            <lsb>24</lsb>
                            <msb>24</msb>
                            <access>read-write</access>
                            <enumeratedValues>
                                <enumeratedValue>
                                    <name>0</name>
                                    <description>Disable</description>
                                    <value>#0</value>
                                </enumeratedValue>
                                <enumeratedValue>
                                    <name>1</name>
                                    <description>Enable</description>
                                    <value>#1</value>
                                </enumeratedValue>
                            </enumeratedValues>
                        </field>
                        <field>
                            <name>CLULPEXT</name>
                            <description>Clock Lane ULPS Exit Interrupt Enable</description>
                            <lsb>25</lsb>
                            <msb>25</msb>
                            <access>read-write</access>
                            <enumeratedValues>
                                <enumeratedValue>
                                    <name>0</name>
                                    <description>Disable</description>
                                    <value>#0</value>
                                </enumeratedValue>
                                <enumeratedValue>
                                    <name>1</name>
                                    <description>Enable</description>
                                    <value>#1</value>
                                </enumeratedValue>
                            </enumeratedValues>
                        </field>
                        <field>
                            <name>CLLP2HS</name>
                            <description>Clock Lane LP to HS Transition Interrupt Enable</description>
                            <lsb>26</lsb>
                            <msb>26</msb>
                            <access>read-write</access>
                            <enumeratedValues>
                                <enumeratedValue>
                                    <name>0</name>
                                    <description>Disable</description>
                                    <value>#0</value>
                                </enumeratedValue>
                                <enumeratedValue>
                                    <name>1</name>
                                    <description>Enable</description>
                                    <value>#1</value>
                                </enumeratedValue>
                            </enumeratedValues>
                        </field>
                        <field>
                            <name>CLHS2LP</name>
                            <description>Clock Lane HS to LP Transition Interrupt Enable</description>
                            <lsb>27</lsb>
                            <msb>27</msb>
                            <access>read-write</access>
                            <enumeratedValues>
                                <enumeratedValue>
                                    <name>0</name>
                                    <description>Disable</description>
                                    <value>#0</value>
                                </enumeratedValue>
                                <enumeratedValue>
                                    <name>1</name>
                                    <description>Enable</description>
                                    <value>#1</value>
                                </enumeratedValue>
                            </enumeratedValues>
                        </field>
                        <field>
                            <name>DLULPENT</name>
                            <description>Data Lane ULPS Enter Interrupt Enable</description>
                            <lsb>28</lsb>
                            <msb>28</msb>
                            <access>read-write</access>
                            <enumeratedValues>
                                <enumeratedValue>
                                    <name>0</name>
                                    <description>Disable</description>
                                    <value>#0</value>
                                </enumeratedValue>
                                <enumeratedValue>
                                    <name>1</name>
                                    <description>Enable</description>
                                    <value>#1</value>
                                </enumeratedValue>
                            </enumeratedValues>
                        </field>
                        <field>
                            <name>DLULPEXT</name>
                            <description>Data Lane ULPS Exit Interrupt Enable</description>
                            <lsb>29</lsb>
                            <msb>29</msb>
                            <access>read-write</access>
                            <enumeratedValues>
                                <enumeratedValue>
                                    <name>0</name>
                                    <description>Disable</description>
                                    <value>#0</value>
                                </enumeratedValue>
                                <enumeratedValue>
                                    <name>1</name>
                                    <description>Enable</description>
                                    <value>#1</value>
                                </enumeratedValue>
                            </enumeratedValues>
                        </field>
                    </fields>
                </register>
                <register>
                    <name>VMSET0R</name>
                    <description>Video Mode Set 0 Register</description>
                    <addressOffset>0x400</addressOffset>
                    <size>32</size>
                    <access>read-write</access>
                    <resetValue>0x00000000</resetValue>
                    <resetMask>0xffffffff</resetMask>
                    <fields>
                        <field>
                            <name>VSTART</name>
                            <description>Video Mode Operation Start</description>
                            <lsb>0</lsb>
                            <msb>0</msb>
                            <access>write-only</access>
                            <enumeratedValues>
                                <enumeratedValue>
                                    <name>0</name>
                                    <description>No operation</description>
                                    <value>#0</value>
                                </enumeratedValue>
                                <enumeratedValue>
                                    <name>1</name>
                                    <description>Start Video mode operation</description>
                                    <value>#1</value>
                                </enumeratedValue>
                            </enumeratedValues>
                        </field>
                        <field>
                            <name>VSTOP</name>
                            <description>Video Mode Operation Stop</description>
                            <lsb>1</lsb>
                            <msb>1</msb>
                            <access>write-only</access>
                            <enumeratedValues>
                                <enumeratedValue>
                                    <name>0</name>
                                    <description>No operation</description>
                                    <value>#0</value>
                                </enumeratedValue>
                                <enumeratedValue>
                                    <name>1</name>
                                    <description>Stop Video mode operation</description>
                                    <value>#1</value>
                                </enumeratedValue>
                            </enumeratedValues>
                        </field>
                        <field>
                            <name>HSANOLP</name>
                            <description>HSA period No LP</description>
                            <lsb>8</lsb>
                            <msb>8</msb>
                            <access>read-write</access>
                            <enumeratedValues>
                                <enumeratedValue>
                                    <name>0</name>
                                    <description>Not suppressing the transition to LP during HSA period</description>
                                    <value>#0</value>
                                </enumeratedValue>
                                <enumeratedValue>
                                    <name>1</name>
                                    <description>Suppress the transition to LP during HSA period and keep HS</description>
                                    <value>#1</value>
                                </enumeratedValue>
                            </enumeratedValues>
                        </field>
                        <field>
                            <name>HBPNOLP</name>
                            <description>HBP period No LP</description>
                            <lsb>9</lsb>
                            <msb>9</msb>
                            <access>read-write</access>
                            <enumeratedValues>
                                <enumeratedValue>
                                    <name>0</name>
                                    <description>Not suppressing the transition to LP during HBP period</description>
                                    <value>#0</value>
                                </enumeratedValue>
                                <enumeratedValue>
                                    <name>1</name>
                                    <description>Suppress the transition to LP during HBP period and keep HS</description>
                                    <value>#1</value>
                                </enumeratedValue>
                            </enumeratedValues>
                        </field>
                        <field>
                            <name>HFPNOLP</name>
                            <description>HFP period No LP</description>
                            <lsb>10</lsb>
                            <msb>10</msb>
                            <access>read-write</access>
                            <enumeratedValues>
                                <enumeratedValue>
                                    <name>0</name>
                                    <description>Not suppressing the transition to LP during HFP period</description>
                                    <value>#0</value>
                                </enumeratedValue>
                                <enumeratedValue>
                                    <name>1</name>
                                    <description>Suppress the transition to LP during HFP period and keep HS</description>
                                    <value>#1</value>
                                </enumeratedValue>
                            </enumeratedValues>
                        </field>
                    </fields>
                </register>
                <register>
                    <name>VMSET1R</name>
                    <description>Video Mode Set 1 Register</description>
                    <addressOffset>0x404</addressOffset>
                    <size>32</size>
                    <access>read-write</access>
                    <resetValue>0x10530000</resetValue>
                    <resetMask>0xffffffff</resetMask>
                    <fields>
                        <field>
                            <name>DLY</name>
                            <description>Delay Value</description>
                            <lsb>2</lsb>
                            <msb>13</msb>
                            <access>read-write</access>
                        </field>
                    </fields>
                </register>
                <register>
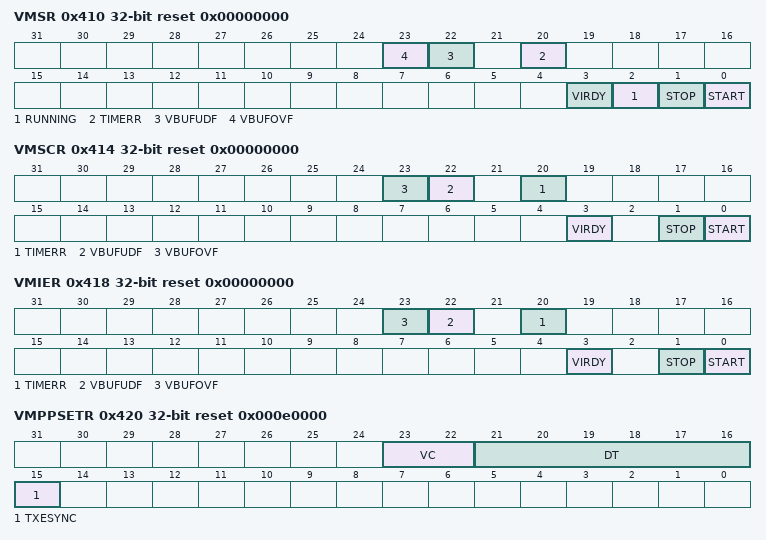
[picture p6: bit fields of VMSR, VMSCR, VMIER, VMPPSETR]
                    <name>VMSR</name>
                    <description>Video Mode Status Register</description>
                    <addressOffset>0x410</addressOffset>
                    <size>32</size>
                    <access>read-only</access>
                    <resetValue>0x00000000</resetValue>
                    <resetMask>0xffffffff</resetMask>
                    <fields>
                        <field>
                            <name>START</name>
                            <description>Video Mode Operation Start Interrupt Flag</description>
                            <lsb>0</lsb>
                            <msb>0</msb>
                            <access>read-only</access>
                            <enumeratedValues>
                                <enumeratedValue>
                                    <name>0</name>
                                    <description>Video mode operation has not started</description>
                                    <value>#0</value>
                                </enumeratedValue>
                                <enumeratedValue>
                                    <name>1</name>
                                    <description>Video mode operation has started</description>
                                    <value>#1</value>
                                </enumeratedValue>
                            </enumeratedValues>
                        </field>
                        <field>
                            <name>STOP</name>
                            <description>Video Mode Operation Stop Interrupt Flag</description>
                            <lsb>1</lsb>
                            <msb>1</msb>
                            <access>read-only</access>
                            <enumeratedValues>
                                <enumeratedValue>
                                    <name>0</name>
                                    <description>Video mode operation has not stopped</description>
                                    <value>#0</value>
                                </enumeratedValue>
                                <enumeratedValue>
                                    <name>1</name>
                                    <description>Video mode operation has stopped</description>
                                    <value>#1</value>
                                </enumeratedValue>
                            </enumeratedValues>
                        </field>
                        <field>
                            <name>RUNNING</name>
                            <description>Video Mode Operation Running Status</description>
                            <lsb>2</lsb>
                            <msb>2</msb>
                            <access>read-only</access>
                            <enumeratedValues>
                                <enumeratedValue>
                                    <name>0</name>
                                    <description>Video mode operation is stopped</description>
                                    <value>#0</value>
                                </enumeratedValue>
                                <enumeratedValue>
                                    <name>1</name>
                                    <description>Video mode operation is running</description>
                                    <value>#1</value>
                                </enumeratedValue>
                            </enumeratedValues>
                        </field>
                        <field>
                            <name>VIRDY</name>
                            <description>Video Mode Operation Ready Interrupt Flag</description>
                            <lsb>3</lsb>
                            <msb>3</msb>
                            <access>read-only</access>
                            <enumeratedValues>
                                <enumeratedValue>
                                    <name>0</name>
                                    <description>Video mode operation is not ready</description>
                                    <value>#0</value>
                                </enumeratedValue>
                                <enumeratedValue>
                                    <name>1</name>
                                    <description>Video mode operation is ready</description>
                                    <value>#1</value>
                                </enumeratedValue>
                            </enumeratedValues>
                        </field>
                        <field>
                            <name>TIMERR</name>
                            <description>Timing Error Interrupt Flag</description>
                            <lsb>20</lsb>
                            <msb>20</msb>
                            <access>read-only</access>
                            <enumeratedValues>
                                <enumeratedValue>
                                    <name>0</name>
                                    <description>Timing error is not occurred</description>
                                    <value>#0</value>
                                </enumeratedValue>
                                <enumeratedValue>
                                    <name>1</name>
                                    <description>Timing error is occurred during the video mode operation</description>
                                    <value>#1</value>
                                </enumeratedValue>
                            </enumeratedValues>
                        </field>
                        <field>
                            <name>VBUFUDF</name>
                            <description>Video Buffer Underflow Error Interrupt Flag</description>
                            <lsb>22</lsb>
                            <msb>22</msb>
                            <access>read-only</access>
                            <enumeratedValues>
                                <enumeratedValue>
                                    <name>0</name>
                                    <description>Data underflow is not occurred</description>
                                    <value>#0</value>
                                </enumeratedValue>
                                <enumeratedValue>
                                    <name>1</name>
                                    <description>Data underflow is occurred in the video buffer</description>
                                    <value>#1</value>
                                </enumeratedValue>
                            </enumeratedValues>
                        </field>
                        <field>
                            <name>VBUFOVF</name>
                            <description>Video Buffer Overflow Error Interrupt Flag</description>
                            <lsb>23</lsb>
                            <msb>23</msb>
                            <access>read-only</access>
                            <enumeratedValues>
                                <enumeratedValue>
                                    <name>0</name>
                                    <description>Data overflow is not occurred</description>
                                    <value>#0</value>
                                </enumeratedValue>
                                <enumeratedValue>
                                    <name>1</name>
                                    <description>Data overflow is occurred in the video buffer</description>
                                    <value>#1</value>
                                </enumeratedValue>
                            </enumeratedValues>
                        </field>
                    </fields>
                </register>
                <register>
                    <name>VMSCR</name>
                    <description>Video Mode Status Clear Register</description>
                    <addressOffset>0x414</addressOffset>
                    <size>32</size>
                    <access>write-only</access>
                    <resetValue>0x00000000</resetValue>
                    <resetMask>0xffffffff</resetMask>
                    <fields>
                        <field>
                            <name>START</name>
                            <description>Video Mode Operation Start Interrupt Flag Clear</description>
                            <lsb>0</lsb>
                            <msb>0</msb>
                            <access>write-only</access>
                            <enumeratedValues>
                                <enumeratedValue>
                                    <name>0</name>
                                    <description>No operation</description>
                                    <value>#0</value>
                                </enumeratedValue>
                                <enumeratedValue>
                                    <name>1</name>
                                    <description>Clear the VMSR.START flag</description>
                                    <value>#1</value>
                                </enumeratedValue>
                            </enumeratedValues>
                        </field>
                        <field>
                            <name>STOP</name>
                            <description>Video Mode Operation Stop Interrupt Flag Clear</description>
                            <lsb>1</lsb>
                            <msb>1</msb>
                            <access>write-only</access>
                            <enumeratedValues>
                                <enumeratedValue>
                                    <name>0</name>
                                    <description>No operation</description>
                                    <value>#0</value>
                                </enumeratedValue>
                                <enumeratedValue>
                                    <name>1</name>
                                    <description>Clear the VMSR.STOP flag</description>
                                    <value>#1</value>
                                </enumeratedValue>
                            </enumeratedValues>
                        </field>
                        <field>
                            <name>VIRDY</name>
                            <description>Video Mode Operation Ready Interrupt Flag Clear</description>
                            <lsb>3</lsb>
                            <msb>3</msb>
                            <access>write-only</access>
                            <enumeratedValues>
                                <enumeratedValue>
                                    <name>0</name>
                                    <description>No operation</description>
                                    <value>#0</value>
                                </enumeratedValue>
                                <enumeratedValue>
                                    <name>1</name>
                                    <description>Clear the VMSR.VIRDY flag</description>
                                    <value>#1</value>
                                </enumeratedValue>
                            </enumeratedValues>
                        </field>
                        <field>
                            <name>TIMERR</name>
                            <description>Timing Error Interrupt Flag Clear</description>
                            <lsb>20</lsb>
                            <msb>20</msb>
                            <access>write-only</access>
                            <enumeratedValues>
                                <enumeratedValue>
                                    <name>0</name>
                                    <description>No operation</description>
                                    <value>#0</value>
                                </enumeratedValue>
                                <enumeratedValue>
                                    <name>1</name>
                                    <description>Clear the VMSR.TIMERR flag</description>
                                    <value>#1</value>
                                </enumeratedValue>
                            </enumeratedValues>
                        </field>
                        <field>
                            <name>VBUFUDF</name>
                            <description>Video Buffer Underflow Error Interrupt Flag Clear</description>
                            <lsb>22</lsb>
                            <msb>22</msb>
                            <access>write-only</access>
                            <enumeratedValues>
                                <enumeratedValue>
                                    <name>0</name>
                                    <description>No operation</description>
                                    <value>#0</value>
                                </enumeratedValue>
                                <enumeratedValue>
                                    <name>1</name>
                                    <description>Clear the VMSR.VBUFUDF flag</description>
                                    <value>#1</value>
                                </enumeratedValue>
                            </enumeratedValues>
                        </field>
                        <field>
                            <name>VBUFOVF</name>
                            <description>Video Buffer Overflow Error Interrupt Flag Clear</description>
                            <lsb>23</lsb>
                            <msb>23</msb>
                            <access>write-only</access>
                            <enumeratedValues>
                                <enumeratedValue>
                                    <name>0</name>
                                    <description>No operation</description>
                                    <value>#0</value>
                                </enumeratedValue>
                                <enumeratedValue>
                                    <name>1</name>
                                    <description>Clear the VMSR.VBUFOVF flag</description>
                                    <value>#1</value>
                                </enumeratedValue>
                            </enumeratedValues>
                        </field>
                    </fields>
                </register>
                <register>
                    <name>VMIER</name>
                    <description>Video Mode Interrupt Enable Register</description>
                    <addressOffset>0x418</addressOffset>
                    <size>32</size>
                    <access>read-write</access>
                    <resetValue>0x00000000</resetValue>
                    <resetMask>0xffffffff</resetMask>
                    <fields>
                        <field>
                            <name>START</name>
                            <description>Video Mode Operation Start Interrupt Enable</description>
                            <lsb>0</lsb>
                            <msb>0</msb>
                            <access>read-write</access>
                            <enumeratedValues>
                                <enumeratedValue>
                                    <name>0</name>
                                    <description>Disable</description>
                                    <value>#0</value>
                                </enumeratedValue>
                                <enumeratedValue>
                                    <name>1</name>
                                    <description>Enable</description>
                                    <value>#1</value>
                                </enumeratedValue>
                            </enumeratedValues>
                        </field>
                        <field>
                            <name>STOP</name>
                            <description>Video Mode Operation Stop Interrupt Enable</description>
                            <lsb>1</lsb>
                            <msb>1</msb>
                            <access>read-write</access>
                            <enumeratedValues>
                                <enumeratedValue>
                                    <name>0</name>
                                    <description>Disable</description>
                                    <value>#0</value>
                                </enumeratedValue>
                                <enumeratedValue>
                                    <name>1</name>
                                    <description>Enable</description>
                                    <value>#1</value>
                                </enumeratedValue>
                            </enumeratedValues>
                        </field>
                        <field>
                            <name>VIRDY</name>
                            <description>Video Mode Operation Ready Interrupt Enable</description>
                            <lsb>3</lsb>
                            <msb>3</msb>
                            <access>read-write</access>
                            <enumeratedValues>
                                <enumeratedValue>
                                    <name>0</name>
                                    <description>Disable</description>
                                    <value>#0</value>
                                </enumeratedValue>
                                <enumeratedValue>
                                    <name>1</name>
                                    <description>Enable</description>
                                    <value>#1</value>
                                </enumeratedValue>
                            </enumeratedValues>
                        </field>
                        <field>
                            <name>TIMERR</name>
                            <description>Timing Error Interrupt Enable</description>
                            <lsb>20</lsb>
                            <msb>20</msb>
                            <access>read-write</access>
                            <enumeratedValues>
                                <enumeratedValue>
                                    <name>0</name>
                                    <description>Disable</description>
                                    <value>#0</value>
                                </enumeratedValue>
                                <enumeratedValue>
                                    <name>1</name>
                                    <description>Enable</description>
                                    <value>#1</value>
                                </enumeratedValue>
                            </enumeratedValues>
                        </field>
                        <field>
                            <name>VBUFUDF</name>
                            <description>Video Buffer Underflow Error Interrupt Enable</description>
                            <lsb>22</lsb>
                            <msb>22</msb>
                            <access>read-write</access>
                            <enumeratedValues>
                                <enumeratedValue>
                                    <name>0</name>
                                    <description>Disable</description>
                                    <value>#0</value>
                                </enumeratedValue>
                                <enumeratedValue>
                                    <name>1</name>
                                    <description>Enable</description>
                                    <value>#1</value>
                                </enumeratedValue>
                            </enumeratedValues>
                        </field>
                        <field>
                            <name>VBUFOVF</name>
                            <description>Video Buffer Overflow Error Interrupt Enable</description>
                            <lsb>23</lsb>
                            <msb>23</msb>
                            <access>read-write</access>
                            <enumeratedValues>
                                <enumeratedValue>
                                    <name>0</name>
                                    <description>Disable</description>
                                    <value>#0</value>
                                </enumeratedValue>
                                <enumeratedValue>
                                    <name>1</name>
                                    <description>Enable</description>
                                    <value>#1</value>
                                </enumeratedValue>
                            </enumeratedValues>
                        </field>
                    </fields>
                </register>
                <register>
                    <name>VMPPSETR</name>
                    <description>Video Mode Pixel Packet Set Register</description>
                    <addressOffset>0x420</addressOffset>
                    <size>32</size>
                    <access>read-write</access>
                    <resetValue>0x000e0000</resetValue>
                    <resetMask>0xffffffff</resetMask>
                    <fields>
                        <field>
                            <name>TXESYNC</name>
                            <description>Transmit End of Sync Pulse</description>
                            <lsb>15</lsb>
                            <msb>15</msb>
                            <access>read-write</access>
                            <enumeratedValues>
                                <enumeratedValue>
                                    <name>0</name>
                                    <description>HSE and VSE are not transmitted</description>
                                    <value>#0</value>
                                </enumeratedValue>
                                <enumeratedValue>
                                    <name>1</name>
                                    <description>HSE and VSE are transmitted</description>
                                    <value>#1</value>
                                </enumeratedValue>
                            </enumeratedValues>
                        </field>
                        <field>
                            <name>DT</name>
                            <description>Video Mode Data Type</description>
                            <lsb>16</lsb>
                            <msb>21</msb>
                            <access>read-write</access>
                            <enumeratedValues>
                                <enumeratedValue>
                                    <name>0x0E</name>
                                    <description>Packed Pixel Stream, 16 bit RGB</description>
                                    <value>0x0e</value>
                                </enumeratedValue>
                                <enumeratedValue>
                                    <name>0x1E</name>
                                    <description>Packed Pixel Stream, 18 bit RGB</description>
                                    <value>0x1e</value>
                                </enumeratedValue>
                                <enumeratedValue>
                                    <name>0x3E</name>
                                    <description>Packed Pixel Stream, 24 bit RGB</description>
                                    <value>0x3e</value>
                                </enumeratedValue>
                                <enumeratedValue>
                                    <name>Others</name>
                                    <description>Setting prohibited</description>
                                    <isDefault>true</isDefault>
                                </enumeratedValue>
                            </enumeratedValues>
                        </field>
                        <field>
                            <name>VC</name>
                            <description>Video Mode Virtual Channel</description>
                            <lsb>22</lsb>
                            <msb>23</msb>
                            <access>read-write</access>
                        </field>
                    </fields>
                </register>
                <register>
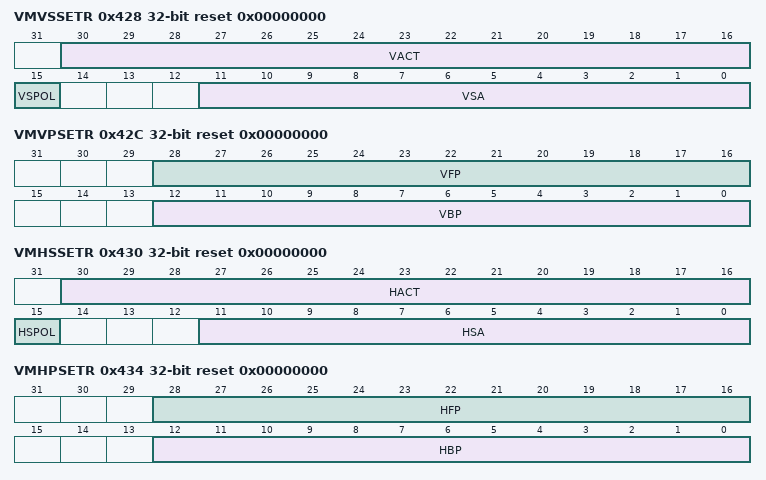
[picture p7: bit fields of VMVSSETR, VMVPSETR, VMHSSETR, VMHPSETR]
                    <name>VMVSSETR</name>
                    <description>Video Mode Vertical Size Set Register</description>
                    <addressOffset>0x428</addressOffset>
                    <size>32</size>
                    <access>read-write</access>
                    <resetValue>0x00000000</resetValue>
                    <resetMask>0xffffffff</resetMask>
                    <fields>
                        <field>
                            <name>VSA</name>
                            <description>VSA Lines</description>
                            <lsb>0</lsb>
                            <msb>11</msb>
                            <access>read-write</access>
                        </field>
                        <field>
                            <name>VSPOL</name>
                            <description>VSYNC Polarity</description>
                            <lsb>15</lsb>
                            <msb>15</msb>
                            <access>read-write</access>
                            <enumeratedValues>
                                <enumeratedValue>
                                    <name>0</name>
                                    <description>High Active</description>
                                    <value>#0</value>
                                </enumeratedValue>
                                <enumeratedValue>
                                    <name>1</name>
                                    <description>Low Active</description>
                                    <value>#1</value>
                                </enumeratedValue>
                            </enumeratedValues>
                        </field>
                        <field>
                            <name>VACT</name>
                            <description>Vertical Active Lines</description>
                            <lsb>16</lsb>
                            <msb>30</msb>
                            <access>read-write</access>
                        </field>
                    </fields>
                </register>
                <register>
                    <name>VMVPSETR</name>
                    <description>Video Mode Vertical Porch Set Register</description>
                    <addressOffset>0x42C</addressOffset>
                    <size>32</size>
                    <access>read-write</access>
                    <resetValue>0x00000000</resetValue>
                    <resetMask>0xffffffff</resetMask>
                    <fields>
                        <field>
                            <name>VBP</name>
                            <description>VBP Lines</description>
                            <lsb>0</lsb>
                            <msb>12</msb>
                            <access>read-write</access>
                        </field>
                        <field>
                            <name>VFP</name>
                            <description>VFP Lines</description>
                            <lsb>16</lsb>
                            <msb>28</msb>
                            <access>read-write</access>
                        </field>
                    </fields>
                </register>
                <register>
                    <name>VMHSSETR</name>
                    <description>Video Mode Horizontal Size Set Register</description>
                    <addressOffset>0x430</addressOffset>
                    <size>32</size>
                    <access>read-write</access>
                    <resetValue>0x00000000</resetValue>
                    <resetMask>0xffffffff</resetMask>
                    <fields>
                        <field>
                            <name>HSA</name>
                            <description>HSA Pixels</description>
                            <lsb>0</lsb>
                            <msb>11</msb>
                            <access>read-write</access>
                        </field>
                        <field>
                            <name>HSPOL</name>
                            <description>HSYNC Polarity</description>
                            <lsb>15</lsb>
                            <msb>15</msb>
                            <access>read-write</access>
                            <enumeratedValues>
                                <enumeratedValue>
                                    <name>0</name>
                                    <description>High Active</description>
                                    <value>#0</value>
                                </enumeratedValue>
                                <enumeratedValue>
                                    <name>1</name>
                                    <description>Low Active</description>
                                    <value>#1</value>
                                </enumeratedValue>
                            </enumeratedValues>
                        </field>
                        <field>
                            <name>HACT</name>
                            <description>HACT Pixels</description>
                            <lsb>16</lsb>
                            <msb>30</msb>
                            <access>read-write</access>
                        </field>
                    </fields>
                </register>
                <register>
                    <name>VMHPSETR</name>
                    <description>Video Mode Horizontal Porch Set Register</description>
                    <addressOffset>0x434</addressOffset>
                    <size>32</size>
                    <access>read-write</access>
                    <resetValue>0x00000000</resetValue>
                    <resetMask>0xffffffff</resetMask>
                    <fields>
                        <field>
                            <name>HBP</name>
                            <description>HBP Pixels</description>
                            <lsb>0</lsb>
                            <msb>12</msb>
                            <access>read-write</access>
                        </field>
                        <field>
                            <name>HFP</name>
                            <description>HFP Pixels</description>
                            <lsb>16</lsb>
                            <msb>28</msb>
                            <access>read-write</access>
                        </field>
                    </fields>
                </register>
                <register>
                    <name>SQCH0SET0R</name>
                    <description>Sequence Channel 0 Set 0 Register</description>
                    <addressOffset>0x5C0</addressOffset>
                    <size>32</size>
                    <access>write-only</access>
                    <resetValue>0x00800000</resetValue>
                    <resetMask>0xffffffff</resetMask>
                    <fields>
                        <field>
                            <name>START</name>
                            <description>Sequence Operation Start</description>
                            <lsb>0</lsb>
                            <msb>0</msb>
                            <access>write-only</access>
                            <enumeratedValues>
                                <enumeratedValue>
                                    <name>0</name>
                                    <description>No operation</description>
                                    <value>#0</value>
                                </enumeratedValue>
                                <enumeratedValue>
                                    <name>1</name>
                                    <description>Start the sequence operation</description>
                                    <value>#1</value>
                                </enumeratedValue>
                            </enumeratedValues>
                        </field>
                    </fields>
                </register>
                <register>
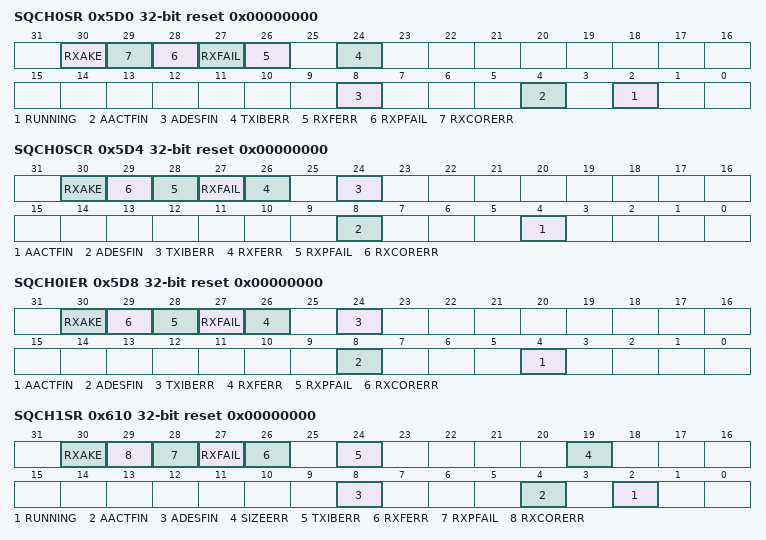
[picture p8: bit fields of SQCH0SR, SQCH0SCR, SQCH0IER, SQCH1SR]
                    <name>SQCH0SR</name>
                    <description>Sequence Channel 0 Status Register</description>
                    <addressOffset>0x5D0</addressOffset>
                    <size>32</size>
                    <access>read-only</access>
                    <resetValue>0x00000000</resetValue>
                    <resetMask>0xffffffff</resetMask>
                    <fields>
                        <field>
                            <name>RUNNING</name>
                            <description>Sequence Operation Running Status</description>
                            <lsb>2</lsb>
                            <msb>2</msb>
                            <access>read-only</access>
                            <enumeratedValues>
                                <enumeratedValue>
                                    <name>0</name>
                                    <description>Sequence operation is stopped</description>
                                    <value>#0</value>
                                </enumeratedValue>
                                <enumeratedValue>
                                    <name>1</name>
                                    <description>Sequence operation is running</description>
                                    <value>#1</value>
                                </enumeratedValue>
                            </enumeratedValues>
                        </field>
                        <field>
                            <name>AACTFIN</name>
                            <description>All Actions Finish Interrupt Flag</description>
                            <lsb>4</lsb>
                            <msb>4</msb>
                            <access>read-only</access>
                            <enumeratedValues>
                                <enumeratedValue>
                                    <name>0</name>
                                    <description>All actions of a descriptor have not finished</description>
                                    <value>#0</value>
                                </enumeratedValue>
                                <enumeratedValue>
                                    <name>1</name>
                                    <description>All actions of a descriptor finished operations</description>
                                    <value>#1</value>
                                </enumeratedValue>
                            </enumeratedValues>
                        </field>
                        <field>
                            <name>ADESFIN</name>
                            <description>All-Descriptors Finish Interrupt Flag</description>
                            <lsb>8</lsb>
                            <msb>8</msb>
                            <access>read-only</access>
                            <enumeratedValues>
                                <enumeratedValue>
                                    <name>0</name>
                                    <description>All descriptors have not finished</description>
                                    <value>#0</value>
                                </enumeratedValue>
                                <enumeratedValue>
                                    <name>1</name>
                                    <description>All descriptors finished operations</description>
                                    <value>#1</value>
                                </enumeratedValue>
                            </enumeratedValues>
                        </field>
                        <field>
                            <name>TXIBERR</name>
                            <description>Tx Internal Bus Error Interrupt Flag</description>
                            <lsb>24</lsb>
                            <msb>24</msb>
                            <access>read-only</access>
                            <enumeratedValues>
                                <enumeratedValue>
                                    <name>0</name>
                                    <description>No error</description>
                                    <value>#0</value>
                                </enumeratedValue>
                                <enumeratedValue>
                                    <name>1</name>
                                    <description>Internal AXI bus read error occurred</description>
                                    <value>#1</value>
                                </enumeratedValue>
                            </enumeratedValues>
                        </field>
                        <field>
                            <name>RXFERR</name>
                            <description>Receive Fatal Error Interrupt Flag</description>
                            <lsb>26</lsb>
                            <msb>26</msb>
                            <access>read-only</access>
                            <enumeratedValues>
                                <enumeratedValue>
                                    <name>0</name>
                                    <description>No error</description>
                                    <value>#0</value>
                                </enumeratedValue>
                                <enumeratedValue>
                                    <name>1</name>
                                    <description>Fatal timeout occurred during BTA</description>
                                    <value>#1</value>
                                </enumeratedValue>
                            </enumeratedValues>
                        </field>
                        <field>
                            <name>RXFAIL</name>
                            <description>Receive Fail Interrupt Flag</description>
                            <lsb>27</lsb>
                            <msb>27</msb>
                            <access>read-only</access>
                            <enumeratedValues>
                                <enumeratedValue>
                                    <name>0</name>
                                    <description>No error</description>
                                    <value>#0</value>
                                </enumeratedValue>
                                <enumeratedValue>
                                    <name>1</name>
                                    <description>Expected receive did not take place</description>
                                    <value>#1</value>
                                </enumeratedValue>
                            </enumeratedValues>
                        </field>
                        <field>
                            <name>RXPFAIL</name>
                            <description>Receive Packet Data Fail Interrupt Flag</description>
                            <lsb>28</lsb>
                            <msb>28</msb>
                            <access>read-only</access>
                            <enumeratedValues>
                                <enumeratedValue>
                                    <name>0</name>
                                    <description>No error</description>
                                    <value>#0</value>
                                </enumeratedValue>
                                <enumeratedValue>
                                    <name>1</name>
                                    <description>Received packet data is not stored correctly</description>
                                    <value>#1</value>
                                </enumeratedValue>
                            </enumeratedValues>
                        </field>
                        <field>
                            <name>RXCORERR</name>
                            <description>Receive Correctable Error Interrupt Flag</description>
                            <lsb>29</lsb>
                            <msb>29</msb>
                            <access>read-only</access>
                            <enumeratedValues>
                                <enumeratedValue>
                                    <name>0</name>
                                    <description>No error</description>
                                    <value>#0</value>
                                </enumeratedValue>
                                <enumeratedValue>
                                    <name>1</name>
                                    <description>Received packets have correctable error</description>
                                    <value>#1</value>
                                </enumeratedValue>
                            </enumeratedValues>
                        </field>
                        <field>
                            <name>RXAKE</name>
                            <description>Receive Acknowledge and Error Report Packet Interrupt Flag</description>
                            <lsb>30</lsb>
                            <msb>30</msb>
                            <access>read-only</access>
                            <enumeratedValues>
                                <enumeratedValue>
                                    <name>0</name>
                                    <description>No error</description>
                                    <value>#0</value>
                                </enumeratedValue>
                                <enumeratedValue>
                                    <name>1</name>
                                    <description>Acknowledge and Error Report Packet is received</description>
                                    <value>#1</value>
                                </enumeratedValue>
                            </enumeratedValues>
                        </field>
                    </fields>
                </register>
                <register>
                    <name>SQCH0SCR</name>
                    <description>Sequence Channel 0 Status Clear Register</description>
                    <addressOffset>0x5D4</addressOffset>
                    <size>32</size>
                    <access>write-only</access>
                    <resetValue>0x00000000</resetValue>
                    <resetMask>0xffffffff</resetMask>
                    <fields>
                        <field>
                            <name>AACTFIN</name>
                            <description>All Actions Finish Interrupt Flag Clear</description>
                            <lsb>4</lsb>
                            <msb>4</msb>
                            <access>write-only</access>
                            <enumeratedValues>
                                <enumeratedValue>
                                    <name>0</name>
                                    <description>No operation</description>
                                    <value>#0</value>
                                </enumeratedValue>
                                <enumeratedValue>
                                    <name>1</name>
                                    <description>Clear the SQCH0SR.AACTFIN flag</description>
                                    <value>#1</value>
                                </enumeratedValue>
                            </enumeratedValues>
                        </field>
                        <field>
                            <name>ADESFIN</name>
                            <description>All-Descriptors Finish Interrupt Flag Clear</description>
                            <lsb>8</lsb>
                            <msb>8</msb>
                            <access>write-only</access>
                            <enumeratedValues>
                                <enumeratedValue>
                                    <name>0</name>
                                    <description>No operation</description>
                                    <value>#0</value>
                                </enumeratedValue>
                                <enumeratedValue>
                                    <name>1</name>
                                    <description>Clear the SQCH0SR.ADESFIN flag</description>
                                    <value>#1</value>
                                </enumeratedValue>
                            </enumeratedValues>
                        </field>
                        <field>
                            <name>TXIBERR</name>
                            <description>Tx Internal Bus Error Interrupt Flag Clear</description>
                            <lsb>24</lsb>
                            <msb>24</msb>
                            <access>write-only</access>
                            <enumeratedValues>
                                <enumeratedValue>
                                    <name>0</name>
                                    <description>No operation</description>
                                    <value>#0</value>
                                </enumeratedValue>
                                <enumeratedValue>
                                    <name>1</name>
                                    <description>Clear the SQCH0SR.TXIBERR flag</description>
                                    <value>#1</value>
                                </enumeratedValue>
                            </enumeratedValues>
                        </field>
                        <field>
                            <name>RXFERR</name>
                            <description>Receive Fatal Error Interrupt Flag Clear</description>
                            <lsb>26</lsb>
                            <msb>26</msb>
                            <access>write-only</access>
                            <enumeratedValues>
                                <enumeratedValue>
                                    <name>0</name>
                                    <description>No operation</description>
                                    <value>#0</value>
                                </enumeratedValue>
                                <enumeratedValue>
                                    <name>1</name>
                                    <description>Clear the SQCH0SR.RXFERR flag</description>
                                    <value>#1</value>
                                </enumeratedValue>
                            </enumeratedValues>
                        </field>
                        <field>
                            <name>RXFAIL</name>
                            <description>Receive Fail Interrupt Flag Clear</description>
                            <lsb>27</lsb>
                            <msb>27</msb>
                            <access>write-only</access>
                            <enumeratedValues>
                                <enumeratedValue>
                                    <name>0</name>
                                    <description>No operation</description>
                                    <value>#0</value>
                                </enumeratedValue>
                                <enumeratedValue>
                                    <name>1</name>
                                    <description>Clear the SQCH0SR.RXFAIL flag</description>
                                    <value>#1</value>
                                </enumeratedValue>
                            </enumeratedValues>
                        </field>
                        <field>
                            <name>RXPFAIL</name>
                            <description>Receive Packet Data Fail Interrupt Flag Clear</description>
                            <lsb>28</lsb>
                            <msb>28</msb>
                            <access>write-only</access>
                            <enumeratedValues>
                                <enumeratedValue>
                                    <name>0</name>
                                    <description>No operation</description>
                                    <value>#0</value>
                                </enumeratedValue>
                                <enumeratedValue>
                                    <name>1</name>
                                    <description>Clear the SQCH0SR.RXPFAIL flag</description>
                                    <value>#1</value>
                                </enumeratedValue>
                            </enumeratedValues>
                        </field>
                        <field>
                            <name>RXCORERR</name>
                            <description>Receive Correctable Error Interrupt Flag Clear</description>
                            <lsb>29</lsb>
                            <msb>29</msb>
                            <access>write-only</access>
                            <enumeratedValues>
                                <enumeratedValue>
                                    <name>0</name>
                                    <description>No operation</description>
                                    <value>#0</value>
                                </enumeratedValue>
                                <enumeratedValue>
                                    <name>1</name>
                                    <description>Clear the SQCH0SR.RXCORERR flag</description>
                                    <value>#1</value>
                                </enumeratedValue>
                            </enumeratedValues>
                        </field>
                        <field>
                            <name>RXAKE</name>
                            <description>Receive Acknowledge and Error Report Packet Interrupt Flag Clear</description>
                            <lsb>30</lsb>
                            <msb>30</msb>
                            <access>write-only</access>
                            <enumeratedValues>
                                <enumeratedValue>
                                    <name>0</name>
                                    <description>No operation</description>
                                    <value>#0</value>
                                </enumeratedValue>
                                <enumeratedValue>
                                    <name>1</name>
                                    <description>Clear the SQCH0SR.RXAKE flag</description>
                                    <value>#1</value>
                                </enumeratedValue>
                            </enumeratedValues>
                        </field>
                    </fields>
                </register>
                <register>
                    <name>SQCH0IER</name>
                    <description>Sequence Channel 0 Interrupt Enable Register</description>
                    <addressOffset>0x5D8</addressOffset>
                    <size>32</size>
                    <access>read-write</access>
                    <resetValue>0x00000000</resetValue>
                    <resetMask>0xffffffff</resetMask>
                    <fields>
                        <field>
                            <name>AACTFIN</name>
                            <description>All Actions Finish Interrupt Enable</description>
                            <lsb>4</lsb>
                            <msb>4</msb>
                            <access>read-write</access>
                            <enumeratedValues>
                                <enumeratedValue>
                                    <name>0</name>
                                    <description>Disable</description>
                                    <value>#0</value>
                                </enumeratedValue>
                                <enumeratedValue>
                                    <name>1</name>
                                    <description>Enable</description>
                                    <value>#1</value>
                                </enumeratedValue>
                            </enumeratedValues>
                        </field>
                        <field>
                            <name>ADESFIN</name>
                            <description>All-Descriptors Finish Interrupt Enable</description>
                            <lsb>8</lsb>
                            <msb>8</msb>
                            <access>read-write</access>
                            <enumeratedValues>
                                <enumeratedValue>
                                    <name>0</name>
                                    <description>Disable</description>
                                    <value>#0</value>
                                </enumeratedValue>
                                <enumeratedValue>
                                    <name>1</name>
                                    <description>Enable</description>
                                    <value>#1</value>
                                </enumeratedValue>
                            </enumeratedValues>
                        </field>
                        <field>
                            <name>TXIBERR</name>
                            <description>Tx Internal Bus Error Interrupt Enable</description>
                            <lsb>24</lsb>
                            <msb>24</msb>
                            <access>read-write</access>
                            <enumeratedValues>
                                <enumeratedValue>
                                    <name>0</name>
                                    <description>Disable</description>
                                    <value>#0</value>
                                </enumeratedValue>
                                <enumeratedValue>
                                    <name>1</name>
                                    <description>Enable</description>
                                    <value>#1</value>
                                </enumeratedValue>
                            </enumeratedValues>
                        </field>
                        <field>
                            <name>RXFERR</name>
                            <description>Receive Fatal Error Interrupt Enable</description>
                            <lsb>26</lsb>
                            <msb>26</msb>
                            <access>read-write</access>
                            <enumeratedValues>
                                <enumeratedValue>
                                    <name>0</name>
                                    <description>Disable</description>
                                    <value>#0</value>
                                </enumeratedValue>
                                <enumeratedValue>
                                    <name>1</name>
                                    <description>Enable</description>
                                    <value>#1</value>
                                </enumeratedValue>
                            </enumeratedValues>
                        </field>
                        <field>
                            <name>RXFAIL</name>
                            <description>Receive Fail Interrupt Enable</description>
                            <lsb>27</lsb>
                            <msb>27</msb>
                            <access>read-write</access>
                            <enumeratedValues>
                                <enumeratedValue>
                                    <name>0</name>
                                    <description>Disable</description>
                                    <value>#0</value>
                                </enumeratedValue>
                                <enumeratedValue>
                                    <name>1</name>
                                    <description>Enable</description>
                                    <value>#1</value>
                                </enumeratedValue>
                            </enumeratedValues>
                        </field>
                        <field>
                            <name>RXPFAIL</name>
                            <description>Receive Packet Data Fail Interrupt Enable</description>
                            <lsb>28</lsb>
                            <msb>28</msb>
                            <access>read-write</access>
                            <enumeratedValues>
                                <enumeratedValue>
                                    <name>0</name>
                                    <description>Disable </description>
                                    <value>#0</value>
                                </enumeratedValue>
                                <enumeratedValue>
                                    <name>1</name>
                                    <description>Enable</description>
                                    <value>#1</value>
                                </enumeratedValue>
                            </enumeratedValues>
                        </field>
                        <field>
                            <name>RXCORERR</name>
                            <description>Receive Correctable Error Interrupt Enable</description>
                            <lsb>29</lsb>
                            <msb>29</msb>
                            <access>read-write</access>
                            <enumeratedValues>
                                <enumeratedValue>
                                    <name>0</name>
                                    <description>Disable </description>
                                    <value>#0</value>
                                </enumeratedValue>
                                <enumeratedValue>
                                    <name>1</name>
                                    <description>Enable</description>
                                    <value>#1</value>
                                </enumeratedValue>
                            </enumeratedValues>
                        </field>
                        <field>
                            <name>RXAKE</name>
                            <description>Receive Acknowledge and Error Report Packet Interrupt Enable</description>
                            <lsb>30</lsb>
                            <msb>30</msb>
                            <access>read-write</access>
                            <enumeratedValues>
                                <enumeratedValue>
                                    <name>0</name>
                                    <description>Disable </description>
                                    <value>#0</value>
                                </enumeratedValue>
                                <enumeratedValue>
                                    <name>1</name>
                                    <description>Enable</description>
                                    <value>#1</value>
                                </enumeratedValue>
                            </enumeratedValues>
                        </field>
                    </fields>
                </register>
                <register>
                    <name>SQCH1SET0R</name>
                    <description>Sequence Channel 1 Set 0 Register</description>
                    <addressOffset>0x600</addressOffset>
                    <size>32</size>
                    <access>write-only</access>
                    <resetValue>0x00800000</resetValue>
                    <resetMask>0xffffffff</resetMask>
                    <fields>
                        <field>
                            <name>START</name>
                            <description>Sequence Operation Start</description>
                            <lsb>0</lsb>
                            <msb>0</msb>
                            <access>write-only</access>
                            <enumeratedValues>
                                <enumeratedValue>
                                    <name>0</name>
                                    <description>No operation</description>
                                    <value>#0</value>
                                </enumeratedValue>
                                <enumeratedValue>
                                    <name>1</name>
                                    <description>Start the sequence operation</description>
                                    <value>#1</value>
                                </enumeratedValue>
                            </enumeratedValues>
                        </field>
                    </fields>
                </register>
                <register>
                    <name>SQCH1SR</name>
                    <description>Sequence Channel 1 Status Register</description>
                    <addressOffset>0x610</addressOffset>
                    <size>32</size>
                    <access>read-only</access>
                    <resetValue>0x00000000</resetValue>
                    <resetMask>0xffffffff</resetMask>
                    <fields>
                        <field>
                            <name>RUNNING</name>
                            <description>Sequence Operation Running Status</description>
                            <lsb>2</lsb>
                            <msb>2</msb>
                            <access>read-only</access>
                            <enumeratedValues>
                                <enumeratedValue>
                                    <name>0</name>
                                    <description>Sequence operation is stopped </description>
                                    <value>#0</value>
                                </enumeratedValue>
                                <enumeratedValue>
                                    <name>1</name>
                                    <description>Sequence operation is running</description>
                                    <value>#1</value>
                                </enumeratedValue>
                            </enumeratedValues>
                        </field>
                        <field>
                            <name>AACTFIN</name>
                            <description>All Actions Finish Interrupt Flag</description>
                            <lsb>4</lsb>
                            <msb>4</msb>
                            <access>read-only</access>
                            <enumeratedValues>
                                <enumeratedValue>
                                    <name>0</name>
                                    <description>All actions of a descriptor have not finished</description>
                                    <value>#0</value>
                                </enumeratedValue>
                                <enumeratedValue>
                                    <name>1</name>
                                    <description>All actions of a descriptor finished operations</description>
                                    <value>#1</value>
                                </enumeratedValue>
                            </enumeratedValues>
                        </field>
                        <field>
                            <name>ADESFIN</name>
                            <description>All-Descriptors Finish Interrupt Flag</description>
                            <lsb>8</lsb>
                            <msb>8</msb>
                            <access>read-only</access>
                            <enumeratedValues>
                                <enumeratedValue>
                                    <name>0</name>
                                    <description>All descriptors have not finished</description>
                                    <value>#0</value>
                                </enumeratedValue>
                                <enumeratedValue>
                                    <name>1</name>
                                    <description>All descriptors finished operations</description>
                                    <value>#1</value>
                                </enumeratedValue>
                            </enumeratedValues>
                        </field>
                        <field>
                            <name>SIZEERR</name>
                            <description>Packet Size Error Interrupt Flag</description>
                            <lsb>19</lsb>
                            <msb>19</msb>
                            <access>read-only</access>
                            <enumeratedValues>
                                <enumeratedValue>
                                    <name>0</name>
                                    <description>No error</description>
                                    <value>#0</value>
                                </enumeratedValue>
                                <enumeratedValue>
                                    <name>1</name>
                                    <description>Sequence packet size is too large</description>
                                    <value>#1</value>
                                </enumeratedValue>
                            </enumeratedValues>
                        </field>
                        <field>
                            <name>TXIBERR</name>
                            <description>Tx Internal Bus Error Interrupt Flag</description>
                            <lsb>24</lsb>
                            <msb>24</msb>
                            <access>read-only</access>
                            <enumeratedValues>
                                <enumeratedValue>
                                    <name>0</name>
                                    <description>No error</description>
                                    <value>#0</value>
                                </enumeratedValue>
                                <enumeratedValue>
                                    <name>1</name>
                                    <description>Internal AXI bus read error occurred</description>
                                    <value>#1</value>
                                </enumeratedValue>
                            </enumeratedValues>
                        </field>
                        <field>
                            <name>RXFERR</name>
                            <description>Receive Fatal Error Interrupt Flag</description>
                            <lsb>26</lsb>
                            <msb>26</msb>
                            <access>read-only</access>
                            <enumeratedValues>
                                <enumeratedValue>
                                    <name>0</name>
                                    <description>No error</description>
                                    <value>#0</value>
                                </enumeratedValue>
                                <enumeratedValue>
                                    <name>1</name>
                                    <description>Fatal timeout occurred during BTA</description>
                                    <value>#1</value>
                                </enumeratedValue>
                            </enumeratedValues>
                        </field>
                        <field>
                            <name>RXFAIL</name>
                            <description>Receive Fail Interrupt Flag</description>
                            <lsb>27</lsb>
                            <msb>27</msb>
                            <access>read-only</access>
                            <enumeratedValues>
                                <enumeratedValue>
                                    <name>0</name>
                                    <description>No error</description>
                                    <value>#0</value>
                                </enumeratedValue>
                                <enumeratedValue>
                                    <name>1</name>
                                    <description>Expected receive did not take place</description>
                                    <value>#1</value>
                                </enumeratedValue>
                            </enumeratedValues>
                        </field>
                        <field>
                            <name>RXPFAIL</name>
                            <description>Receive Packet Data Fail Interrupt Flag</description>
                            <lsb>28</lsb>
                            <msb>28</msb>
                            <access>read-only</access>
                            <enumeratedValues>
                                <enumeratedValue>
                                    <name>0</name>
                                    <description>No error</description>
                                    <value>#0</value>
                                </enumeratedValue>
                                <enumeratedValue>
                                    <name>1</name>
                                    <description>Received packet data is not stored correctly</description>
                                    <value>#1</value>
                                </enumeratedValue>
                            </enumeratedValues>
                        </field>
                        <field>
                            <name>RXCORERR</name>
                            <description>Receive Correctable Error Interrupt Flag</description>
                            <lsb>29</lsb>
                            <msb>29</msb>
                            <access>read-only</access>
                            <enumeratedValues>
                                <enumeratedValue>
                                    <name>0</name>
                                    <description>No error</description>
                                    <value>#0</value>
                                </enumeratedValue>
                                <enumeratedValue>
                                    <name>1</name>
                                    <description>Received packets have correctable error</description>
                                    <value>#1</value>
                                </enumeratedValue>
                            </enumeratedValues>
                        </field>
                        <field>
                            <name>RXAKE</name>
                            <description>Receive Acknowledge and Error Report Packet Interrupt Flag</description>
                            <lsb>30</lsb>
                            <msb>30</msb>
                            <access>read-only</access>
                            <enumeratedValues>
                                <enumeratedValue>
                                    <name>0</name>
                                    <description>No error</description>
                                    <value>#0</value>
                                </enumeratedValue>
                                <enumeratedValue>
                                    <name>1</name>
                                    <description>Acknowledge and Error Report Packet is received</description>
                                    <value>#1</value>
                                </enumeratedValue>
                            </enumeratedValues>
                        </field>
                    </fields>
                </register>
                <register>
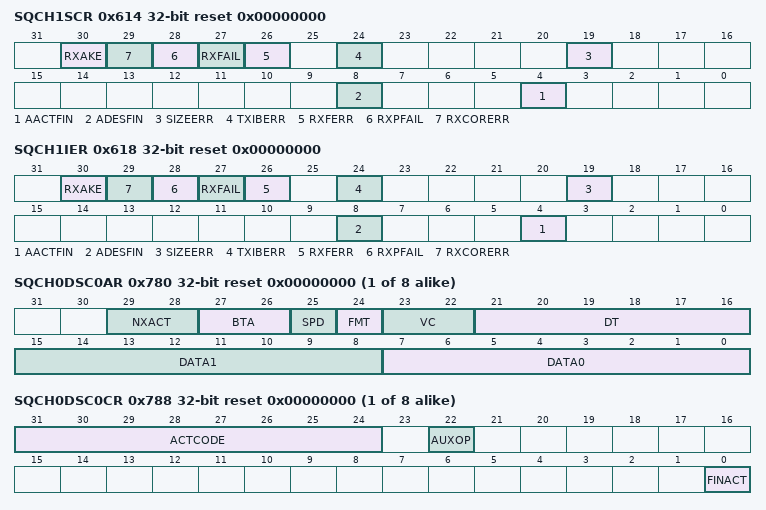
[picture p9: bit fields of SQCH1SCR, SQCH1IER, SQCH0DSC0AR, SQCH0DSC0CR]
                    <name>SQCH1SCR</name>
                    <description>Sequence Channel 1 Status Clear Register</description>
                    <addressOffset>0x614</addressOffset>
                    <size>32</size>
                    <access>write-only</access>
                    <resetValue>0x00000000</resetValue>
                    <resetMask>0xffffffff</resetMask>
                    <fields>
                        <field>
                            <name>AACTFIN</name>
                            <description>All Actions Finish Interrupt Flag Clear</description>
                            <lsb>4</lsb>
                            <msb>4</msb>
                            <access>write-only</access>
                            <enumeratedValues>
                                <enumeratedValue>
                                    <name>0</name>
                                    <description>No operation</description>
                                    <value>#0</value>
                                </enumeratedValue>
                                <enumeratedValue>
                                    <name>1</name>
                                    <description>Clear the SQCH1SR.AACTFIN flag</description>
                                    <value>#1</value>
                                </enumeratedValue>
                            </enumeratedValues>
                        </field>
                        <field>
                            <name>ADESFIN</name>
                            <description>All-Descriptors Finish Interrupt Flag Clear</description>
                            <lsb>8</lsb>
                            <msb>8</msb>
                            <access>write-only</access>
                            <enumeratedValues>
                                <enumeratedValue>
                                    <name>0</name>
                                    <description>No operation</description>
                                    <value>#0</value>
                                </enumeratedValue>
                                <enumeratedValue>
                                    <name>1</name>
                                    <description>Clear the SQCH1SR.ADESFIN flag</description>
                                    <value>#1</value>
                                </enumeratedValue>
                            </enumeratedValues>
                        </field>
                        <field>
                            <name>SIZEERR</name>
                            <description>Packet Size Error Interrupt Flag Clear</description>
                            <lsb>19</lsb>
                            <msb>19</msb>
                            <access>write-only</access>
                            <enumeratedValues>
                                <enumeratedValue>
                                    <name>0</name>
                                    <description>No operation</description>
                                    <value>#0</value>
                                </enumeratedValue>
                                <enumeratedValue>
                                    <name>1</name>
                                    <description>Clear the SQCH1SR.SIZEERR flag</description>
                                    <value>#1</value>
                                </enumeratedValue>
                            </enumeratedValues>
                        </field>
                        <field>
                            <name>TXIBERR</name>
                            <description>Tx Internal Bus Error Interrupt Flag Clear</description>
                            <lsb>24</lsb>
                            <msb>24</msb>
                            <access>write-only</access>
                            <enumeratedValues>
                                <enumeratedValue>
                                    <name>0</name>
                                    <description>No operation</description>
                                    <value>#0</value>
                                </enumeratedValue>
                                <enumeratedValue>
                                    <name>1</name>
                                    <description>Clear the SQCH1SR.TXIBERR flag</description>
                                    <value>#1</value>
                                </enumeratedValue>
                            </enumeratedValues>
                        </field>
                        <field>
                            <name>RXFERR</name>
                            <description>Receive Fatal Error Interrupt Flag Clear</description>
                            <lsb>26</lsb>
                            <msb>26</msb>
                            <access>write-only</access>
                            <enumeratedValues>
                                <enumeratedValue>
                                    <name>0</name>
                                    <description>No operation</description>
                                    <value>#0</value>
                                </enumeratedValue>
                                <enumeratedValue>
                                    <name>1</name>
                                    <description>Clear the SQCH1SR.RXFERR flag</description>
                                    <value>#1</value>
                                </enumeratedValue>
                            </enumeratedValues>
                        </field>
                        <field>
                            <name>RXFAIL</name>
                            <description>Receive Fail Interrupt Flag Clear</description>
                            <lsb>27</lsb>
                            <msb>27</msb>
                            <access>write-only</access>
                            <enumeratedValues>
                                <enumeratedValue>
                                    <name>0</name>
                                    <description>No operation</description>
                                    <value>#0</value>
                                </enumeratedValue>
                                <enumeratedValue>
                                    <name>1</name>
                                    <description>Clear the SQCH1SR.RXFAIL flag</description>
                                    <value>#1</value>
                                </enumeratedValue>
                            </enumeratedValues>
                        </field>
                        <field>
                            <name>RXPFAIL</name>
                            <description>Receive Packet Data Fail Interrupt Flag Clear</description>
                            <lsb>28</lsb>
                            <msb>28</msb>
                            <access>write-only</access>
                            <enumeratedValues>
                                <enumeratedValue>
                                    <name>0</name>
                                    <description>No operation</description>
                                    <value>#0</value>
                                </enumeratedValue>
                                <enumeratedValue>
                                    <name>1</name>
                                    <description>Clear the SQCH1SR.RXPFAIL flag</description>
                                    <value>#1</value>
                                </enumeratedValue>
                            </enumeratedValues>
                        </field>
                        <field>
                            <name>RXCORERR</name>
                            <description>Receive Correctable Error Interrupt Flag Clear</description>
                            <lsb>29</lsb>
                            <msb>29</msb>
                            <access>write-only</access>
                            <enumeratedValues>
                                <enumeratedValue>
                                    <name>0</name>
                                    <description>No operation</description>
                                    <value>#0</value>
                                </enumeratedValue>
                                <enumeratedValue>
                                    <name>1</name>
                                    <description>Clear the SQCH1SR.RXCORERR flag</description>
                                    <value>#1</value>
                                </enumeratedValue>
                            </enumeratedValues>
                        </field>
                        <field>
                            <name>RXAKE</name>
                            <description>Receive Acknowledge and Error Report Packet Interrupt Flag Clear</description>
                            <lsb>30</lsb>
                            <msb>30</msb>
                            <access>write-only</access>
                            <enumeratedValues>
                                <enumeratedValue>
                                    <name>0</name>
                                    <description>No operation</description>
                                    <value>#0</value>
                                </enumeratedValue>
                                <enumeratedValue>
                                    <name>1</name>
                                    <description>Clear the SQCH1SR.RXAKE flag</description>
                                    <value>#1</value>
                                </enumeratedValue>
                            </enumeratedValues>
                        </field>
                    </fields>
                </register>
                <register>
                    <name>SQCH1IER</name>
                    <description>Sequence Channel 1 Interrupt Enable Register</description>
                    <addressOffset>0x618</addressOffset>
                    <size>32</size>
                    <access>read-write</access>
                    <resetValue>0x00000000</resetValue>
                    <resetMask>0xffffffff</resetMask>
                    <fields>
                        <field>
                            <name>AACTFIN</name>
                            <description>All Actions Finish Interrupt Enable</description>
                            <lsb>4</lsb>
                            <msb>4</msb>
                            <access>read-write</access>
                            <enumeratedValues>
                                <enumeratedValue>
                                    <name>0</name>
                                    <description>Disable</description>
                                    <value>#0</value>
                                </enumeratedValue>
                                <enumeratedValue>
                                    <name>1</name>
                                    <description>Enable</description>
                                    <value>#1</value>
                                </enumeratedValue>
                            </enumeratedValues>
                        </field>
                        <field>
                            <name>ADESFIN</name>
                            <description>All-Descriptors Finish Interrupt Enable</description>
                            <lsb>8</lsb>
                            <msb>8</msb>
                            <access>read-write</access>
                            <enumeratedValues>
                                <enumeratedValue>
                                    <name>0</name>
                                    <description>Disable</description>
                                    <value>#0</value>
                                </enumeratedValue>
                                <enumeratedValue>
                                    <name>1</name>
                                    <description>Enable</description>
                                    <value>#1</value>
                                </enumeratedValue>
                            </enumeratedValues>
                        </field>
                        <field>
                            <name>SIZEERR</name>
                            <description>Packet Size Error Interrupt Enable</description>
                            <lsb>19</lsb>
                            <msb>19</msb>
                            <access>read-write</access>
                            <enumeratedValues>
                                <enumeratedValue>
                                    <name>0</name>
                                    <description>Disable</description>
                                    <value>#0</value>
                                </enumeratedValue>
                                <enumeratedValue>
                                    <name>1</name>
                                    <description>Enable</description>
                                    <value>#1</value>
                                </enumeratedValue>
                            </enumeratedValues>
                        </field>
                        <field>
                            <name>TXIBERR</name>
                            <description>Tx Internal Bus Error Interrupt Enable</description>
                            <lsb>24</lsb>
                            <msb>24</msb>
                            <access>read-write</access>
                            <enumeratedValues>
                                <enumeratedValue>
                                    <name>0</name>
                                    <description>Disable</description>
                                    <value>#0</value>
                                </enumeratedValue>
                                <enumeratedValue>
                                    <name>1</name>
                                    <description>Enable</description>
                                    <value>#1</value>
                                </enumeratedValue>
                            </enumeratedValues>
                        </field>
                        <field>
                            <name>RXFERR</name>
                            <description>Receive Fatal Error Interrupt Enable</description>
                            <lsb>26</lsb>
                            <msb>26</msb>
                            <access>read-write</access>
                            <enumeratedValues>
                                <enumeratedValue>
                                    <name>0</name>
                                    <description>Disable</description>
                                    <value>#0</value>
                                </enumeratedValue>
                                <enumeratedValue>
                                    <name>1</name>
                                    <description>Enable</description>
                                    <value>#1</value>
                                </enumeratedValue>
                            </enumeratedValues>
                        </field>
                        <field>
                            <name>RXFAIL</name>
                            <description>Receive Fail Interrupt Enable</description>
                            <lsb>27</lsb>
                            <msb>27</msb>
                            <access>read-write</access>
                            <enumeratedValues>
                                <enumeratedValue>
                                    <name>0</name>
                                    <description>Disable</description>
                                    <value>#0</value>
                                </enumeratedValue>
                                <enumeratedValue>
                                    <name>1</name>
                                    <description>Enable</description>
                                    <value>#1</value>
                                </enumeratedValue>
                            </enumeratedValues>
                        </field>
                        <field>
                            <name>RXPFAIL</name>
                            <description>Receive Packet Data Fail Interrupt Enable</description>
                            <lsb>28</lsb>
                            <msb>28</msb>
                            <access>read-write</access>
                            <enumeratedValues>
                                <enumeratedValue>
                                    <name>0</name>
                                    <description>Disable</description>
                                    <value>#0</value>
                                </enumeratedValue>
                                <enumeratedValue>
                                    <name>1</name>
                                    <description>Enable</description>
                                    <value>#1</value>
                                </enumeratedValue>
                            </enumeratedValues>
                        </field>
                        <field>
                            <name>RXCORERR</name>
                            <description>Receive Correctable Error Interrupt Enable</description>
                            <lsb>29</lsb>
                            <msb>29</msb>
                            <access>read-write</access>
                            <enumeratedValues>
                                <enumeratedValue>
                                    <name>0</name>
                                    <description>Disable</description>
                                    <value>#0</value>
                                </enumeratedValue>
                                <enumeratedValue>
                                    <name>1</name>
                                    <description>Enable</description>
                                    <value>#1</value>
                                </enumeratedValue>
                            </enumeratedValues>
                        </field>
                        <field>
                            <name>RXAKE</name>
                            <description>Receive Acknowledge and Error Report Packet Interrupt Enable</description>
                            <lsb>30</lsb>
                            <msb>30</msb>
                            <access>read-write</access>
                            <enumeratedValues>
                                <enumeratedValue>
                                    <name>0</name>
                                    <description>Disable</description>
                                    <value>#0</value>
                                </enumeratedValue>
                                <enumeratedValue>
                                    <name>1</name>
                                    <description>Enable</description>
                                    <value>#1</value>
                                </enumeratedValue>
                            </enumeratedValues>
                        </field>
                    </fields>
                </register>
                <register>
                    <dim>8</dim>
                    <dimIncrement>0x10</dimIncrement>
                    <dimIndex>0-7</dimIndex>
                    <name>SQCH0DSC%sAR</name>
                    <description>Sequence Channel 0 Descriptor-m A Register (m = 0 to 7)</description>
                    <addressOffset>0x780</addressOffset>
                    <size>32</size>
                    <access>read-write</access>
                    <resetValue>0x00000000</resetValue>
                    <resetMask>0x00000000</resetMask>
                    <fields>
                        <field>
                            <name>DATA0</name>
                            <description>Data 0</description>
                            <lsb>0</lsb>
                            <msb>7</msb>
                            <access>read-write</access>
                        </field>
                        <field>
                            <name>DATA1</name>
                            <description>Data 1</description>
                            <lsb>8</lsb>
                            <msb>15</msb>
                            <access>read-write</access>
                        </field>
                        <field>
                            <name>DT</name>
                            <description>Data Type</description>
                            <lsb>16</lsb>
                            <msb>21</msb>
                            <access>read-write</access>
                        </field>
                        <field>
                            <name>VC</name>
                            <description>Virtual Channel</description>
                            <lsb>22</lsb>
                            <msb>23</msb>
                            <access>read-write</access>
                        </field>
                        <field>
                            <name>FMT</name>
                            <description>Format</description>
                            <lsb>24</lsb>
                            <msb>24</msb>
                            <access>read-write</access>
                            <enumeratedValues>
                                <enumeratedValue>
                                    <name>0</name>
                                    <description>Short Packet</description>
                                    <value>#0</value>
                                </enumeratedValue>
                                <enumeratedValue>
                                    <name>1</name>
                                    <description>Long Packet</description>
                                    <value>#1</value>
                                </enumeratedValue>
                            </enumeratedValues>
                        </field>
                        <field>
                            <name>SPD</name>
                            <description>Speed</description>
                            <lsb>25</lsb>
                            <msb>25</msb>
                            <access>read-write</access>
                            <enumeratedValues>
                                <enumeratedValue>
                                    <name>0</name>
                                    <description>High Speed</description>
                                    <value>#0</value>
                                </enumeratedValue>
                                <enumeratedValue>
                                    <name>1</name>
                                    <description>Low Power</description>
                                    <value>#1</value>
                                </enumeratedValue>
                            </enumeratedValues>
                        </field>
                        <field>
                            <name>BTA</name>
                            <description>Bus Turn Around</description>
                            <lsb>26</lsb>
                            <msb>27</msb>
                            <access>read-write</access>
                            <enumeratedValues>
                                <enumeratedValue>
                                    <name>00</name>
                                    <description>Tx Request without BTA or no-operation</description>
                                    <value>#00</value>
                                </enumeratedValue>
                                <enumeratedValue>
                                    <name>01</name>
                                    <description>Tx non-Read Request with BTA</description>
                                    <value>#01</value>
                                </enumeratedValue>
                                <enumeratedValue>
                                    <name>10</name>
                                    <description>Tx Read Request with BTA</description>
                                    <value>#10</value>
                                </enumeratedValue>
                                <enumeratedValue>
                                    <name>11</name>
                                    <description>BTA only</description>
                                    <value>#11</value>
                                </enumeratedValue>
                            </enumeratedValues>
                        </field>
                        <field>
                            <name>NXACT</name>
                            <description>Next Action</description>
                            <lsb>28</lsb>
                            <msb>29</msb>
                            <access>read-write</access>
                            <enumeratedValues>
                                <enumeratedValue>
                                    <name>00</name>
                                    <description>Terminate the sequence operation after this descriptor processing is finished.</description>
                                    <value>#00</value>
                                </enumeratedValue>
                                <enumeratedValue>
                                    <name>01</name>
                                    <description>Start the next descriptor processing after this descriptor processing is finished.</description>
                                    <value>#01</value>
                                </enumeratedValue>
                                <enumeratedValue>
                                    <name>Others</name>
                                    <description>Settings prohibited</description>
                                    <isDefault>true</isDefault>
                                </enumeratedValue>
                            </enumeratedValues>
                        </field>
                    </fields>
                </register>
                <register>
                    <dim>8</dim>
                    <dimIncrement>0x10</dimIncrement>
                    <dimIndex>0-7</dimIndex>
                    <name>SQCH0DSC%sBR</name>
                    <description>Sequence Channel 0 Descriptor-m B Register (m = 0 to 7)</description>
                    <addressOffset>0x784</addressOffset>
                    <size>32</size>
                    <access>read-write</access>
                    <resetValue>0x00000000</resetValue>
                    <resetMask>0x00000000</resetMask>
                    <fields>
                        <field>
                            <name>DTSEL</name>
                            <description>Data Select</description>
                            <lsb>24</lsb>
                            <msb>25</msb>
                            <access>read-write</access>
                            <enumeratedValues>
                                <enumeratedValue>
                                    <name>00</name>
                                    <description>Use Packet Payload Data Register (TXPPDxR, RXPPDxR) </description>
                                    <value>#00</value>
                                </enumeratedValue>
                                <enumeratedValue>
                                    <name>01</name>
                                    <description>Use Memory space</description>
                                    <value>#01</value>
                                </enumeratedValue>
                                <enumeratedValue>
                                    <name>Others</name>
                                    <description>Setting prohibited</description>
                                    <isDefault>true</isDefault>
                                </enumeratedValue>
                            </enumeratedValues>
                        </field>
                    </fields>
                </register>
                <register>
                    <dim>8</dim>
                    <dimIncrement>0x10</dimIncrement>
                    <dimIndex>0-7</dimIndex>
                    <name>SQCH0DSC%sCR</name>
                    <description>Sequence Channel 0 Descriptor-m C Register</description>
                    <addressOffset>0x788</addressOffset>
                    <size>32</size>
                    <access>read-write</access>
                    <resetValue>0x00000000</resetValue>
                    <resetMask>0x00000000</resetMask>
                    <fields>
                        <field>
                            <name>FINACT</name>
                            <description>Finish Action</description>
                            <lsb>0</lsb>
                            <msb>0</msb>
                            <access>read-write</access>
                            <enumeratedValues>
                                <enumeratedValue>
                                    <name>0</name>
                                    <description>Disable</description>
                                    <value>#0</value>
                                </enumeratedValue>
                                <enumeratedValue>
                                    <name>1</name>
                                    <description>Enable</description>
                                    <value>#1</value>
                                </enumeratedValue>
                            </enumeratedValues>
                        </field>
                        <field>
                            <name>AUXOP</name>
                            <description>Auxiliary Operation</description>
                            <lsb>22</lsb>
                            <msb>22</msb>
                            <access>read-write</access>
                            <enumeratedValues>
                                <enumeratedValue>
                                    <name>0</name>
                                    <description>Not use auxiliary operation</description>
                                    <value>#0</value>
                                </enumeratedValue>
                                <enumeratedValue>
                                    <name>1</name>
                                    <description>Execute auxiliary operation</description>
                                    <value>#1</value>
                                </enumeratedValue>
                            </enumeratedValues>
                        </field>
                        <field>
                            <name>ACTCODE</name>
                            <description>Action Code</description>
                            <lsb>24</lsb>
                            <msb>31</msb>
                            <access>read-write</access>
                        </field>
                    </fields>
                </register>
                <register>
                    <dim>8</dim>
                    <dimIncrement>0x10</dimIncrement>
                    <dimIndex>0-7</dimIndex>
                    <name>SQCH0DSC%sDR</name>
                    <description>Sequence Channel 0 Descriptor-m D Register (m = 0 to 7)</description>
                    <addressOffset>0x78C</addressOffset>
                    <size>32</size>
                    <access>read-write</access>
                    <resetValue>0x00000000</resetValue>
                    <resetMask>0x00000000</resetMask>
                    <fields>
                        <field>
                            <name>LADDR</name>
                            <description>Lower Address</description>
                            <lsb>0</lsb>
                            <msb>31</msb>
                            <access>read-write</access>
                        </field>
                    </fields>
                </register>
                <register>
                    <dim>8</dim>
                    <dimIncrement>0x10</dimIncrement>
                    <dimIndex>0-7</dimIndex>
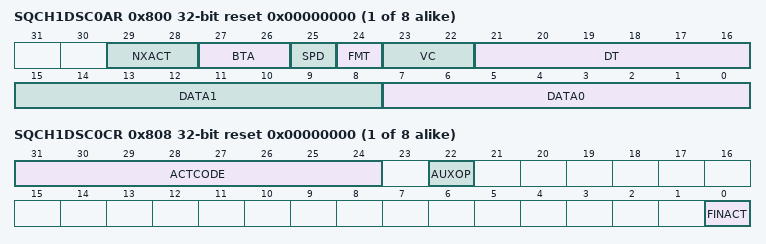
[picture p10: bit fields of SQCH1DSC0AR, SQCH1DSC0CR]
                    <name>SQCH1DSC%sAR</name>
                    <description>Sequence Channel 1 Descriptor-m A Register (m = 0 to 7)</description>
                    <addressOffset>0x800</addressOffset>
                    <size>32</size>
                    <access>read-write</access>
                    <resetValue>0x00000000</resetValue>
                    <resetMask>0x00000000</resetMask>
                    <fields>
                        <field>
                            <name>DATA0</name>
                            <description>Data 0</description>
                            <lsb>0</lsb>
                            <msb>7</msb>
                            <access>read-write</access>
                        </field>
                        <field>
                            <name>DATA1</name>
                            <description>Data 1</description>
                            <lsb>8</lsb>
                            <msb>15</msb>
                            <access>read-write</access>
                        </field>
                        <field>
                            <name>DT</name>
                            <description>Data Type</description>
                            <lsb>16</lsb>
                            <msb>21</msb>
                            <access>read-write</access>
                        </field>
                        <field>
                            <name>VC</name>
                            <description>Virtual Channel</description>
                            <lsb>22</lsb>
                            <msb>23</msb>
                            <access>read-write</access>
                        </field>
                        <field>
                            <name>FMT</name>
                            <description>Format</description>
                            <lsb>24</lsb>
                            <msb>24</msb>
                            <access>read-write</access>
                            <enumeratedValues>
                                <enumeratedValue>
                                    <name>0</name>
                                    <description>Short Packet</description>
                                    <value>#0</value>
                                </enumeratedValue>
                                <enumeratedValue>
                                    <name>1</name>
                                    <description>Long Packet</description>
                                    <value>#1</value>
                                </enumeratedValue>
                            </enumeratedValues>
                        </field>
                        <field>
                            <name>SPD</name>
                            <description>Speed</description>
                            <lsb>25</lsb>
                            <msb>25</msb>
                            <access>read-write</access>
                            <enumeratedValues>
                                <enumeratedValue>
                                    <name>0</name>
                                    <description>High Speed</description>
                                    <value>#0</value>
                                </enumeratedValue>
                                <enumeratedValue>
                                    <name>1</name>
                                    <description>Low Power</description>
                                    <value>#1</value>
                                </enumeratedValue>
                            </enumeratedValues>
                        </field>
                        <field>
                            <name>BTA</name>
                            <description>Bus Turn Around</description>
                            <lsb>26</lsb>
                            <msb>27</msb>
                            <access>read-write</access>
                            <enumeratedValues>
                                <enumeratedValue>
                                    <name>00</name>
                                    <description>Tx Request without BTA or no-operation</description>
                                    <value>#00</value>
                                </enumeratedValue>
                                <enumeratedValue>
                                    <name>01</name>
                                    <description>Tx non-Read Request with BTA</description>
                                    <value>#01</value>
                                </enumeratedValue>
                                <enumeratedValue>
                                    <name>10</name>
                                    <description>Tx Read Request with BTA</description>
                                    <value>#10</value>
                                </enumeratedValue>
                                <enumeratedValue>
                                    <name>11</name>
                                    <description>BTA only</description>
                                    <value>#11</value>
                                </enumeratedValue>
                            </enumeratedValues>
                        </field>
                        <field>
                            <name>NXACT</name>
                            <description>Next Action</description>
                            <lsb>28</lsb>
                            <msb>29</msb>
                            <access>read-write</access>
                            <enumeratedValues>
                                <enumeratedValue>
                                    <name>00</name>
                                    <description>Terminate the sequence operation after this descriptor processing is finished.</description>
                                    <value>#00</value>
                                </enumeratedValue>
                                <enumeratedValue>
                                    <name>01</name>
                                    <description>Start the next descriptor processing after this descriptor processing is finished.</description>
                                    <value>#01</value>
                                </enumeratedValue>
                                <enumeratedValue>
                                    <name>Others</name>
                                    <description>Settings prohibited</description>
                                    <isDefault>true</isDefault>
                                </enumeratedValue>
                            </enumeratedValues>
                        </field>
                    </fields>
                </register>
                <register>
                    <dim>8</dim>
                    <dimIncrement>0x10</dimIncrement>
                    <dimIndex>0-7</dimIndex>
                    <name>SQCH1DSC%sBR</name>
                    <description>Sequence Channel 1 Descriptor-m B Register (m = 0 to 7)</description>
                    <addressOffset>0x804</addressOffset>
                    <size>32</size>
                    <access>read-write</access>
                    <resetValue>0x00000000</resetValue>
                    <resetMask>0x00000000</resetMask>
                    <fields>
                        <field>
                            <name>DTSEL</name>
                            <description>Data Select</description>
                            <lsb>24</lsb>
                            <msb>25</msb>
                            <access>read-write</access>
                            <enumeratedValues>
                                <enumeratedValue>
                                    <name>00</name>
                                    <description>Use Packet Payload Data Register (TXPPDxR, RXPPDxR) </description>
                                    <value>#00</value>
                                </enumeratedValue>
                                <enumeratedValue>
                                    <name>01</name>
                                    <description>Use Memory space</description>
                                    <value>#01</value>
                                </enumeratedValue>
                                <enumeratedValue>
                                    <name>Others</name>
                                    <description>Setting prohibited</description>
                                    <isDefault>true</isDefault>
                                </enumeratedValue>
                            </enumeratedValues>
                        </field>
                    </fields>
                </register>
                <register>
                    <dim>8</dim>
                    <dimIncrement>0x10</dimIncrement>
                    <dimIndex>0-7</dimIndex>
                    <name>SQCH1DSC%sCR</name>
                    <description>Sequence Channel 1 Descriptor-m C Register</description>
                    <addressOffset>0x808</addressOffset>
                    <size>32</size>
                    <access>read-write</access>
                    <resetValue>0x00000000</resetValue>
                    <resetMask>0x00000000</resetMask>
                    <fields>
                        <field>
                            <name>FINACT</name>
                            <description>Finish Action</description>
                            <lsb>0</lsb>
                            <msb>0</msb>
                            <access>read-write</access>
                            <enumeratedValues>
                                <enumeratedValue>
                                    <name>0</name>
                                    <description>Disable</description>
                                    <value>#0</value>
                                </enumeratedValue>
                                <enumeratedValue>
                                    <name>1</name>
                                    <description>Enable</description>
                                    <value>#1</value>
                                </enumeratedValue>
                            </enumeratedValues>
                        </field>
                        <field>
                            <name>AUXOP</name>
                            <description>Auxiliary Operation</description>
                            <lsb>22</lsb>
                            <msb>22</msb>
                            <access>read-write</access>
                            <enumeratedValues>
                                <enumeratedValue>
                                    <name>0</name>
                                    <description>Not use auxiliary operation</description>
                                    <value>#0</value>
                                </enumeratedValue>
                                <enumeratedValue>
                                    <name>1</name>
                                    <description>Execute auxiliary operation</description>
                                    <value>#1</value>
                                </enumeratedValue>
                            </enumeratedValues>
                        </field>
                        <field>
                            <name>ACTCODE</name>
                            <description>Action Code</description>
                            <lsb>24</lsb>
                            <msb>31</msb>
                            <access>read-write</access>
                        </field>
                    </fields>
                </register>
                <register>
                    <dim>8</dim>
                    <dimIncrement>0x10</dimIncrement>
                    <dimIndex>0-7</dimIndex>
                    <name>SQCH1DSC%sDR</name>
                    <description>Sequence Channel 1 Descriptor-m D Register (m = 0 to 7)</description>
                    <addressOffset>0x80C</addressOffset>
                    <size>32</size>
                    <access>read-write</access>
                    <resetValue>0x00000000</resetValue>
                    <resetMask>0x00000000</resetMask>
                    <fields>
                        <field>
                            <name>LADDR</name>
                            <description>Lower Address</description>
                            <lsb>0</lsb>
                            <msb>31</msb>
                            <access>read-write</access>
                        </field>
                    </fields>
                </register>
            </registers>
        </peripheral>
        <peripheral>
            <name>MIPI_PHY0</name>
            <baseAddress>0x40346C00</baseAddress>
            <addressBlock>
                <offset>0x00</offset>
                <size>20</size>
                <usage>registers</usage>
            </addressBlock>
            <addressBlock>
                <offset>0x1C</offset>
                <size>32</size>
                <usage>registers</usage>
            </addressBlock>
            <registers>
                <register>
                    <name>DPHYREFCR</name>
                    <description>D-PHY Reference Clock Setting Register</description>
                    <addressOffset>0x000</addressOffset>
                    <size>32</size>
                    <access>read-write</access>
                    <resetValue>0x0000002f</resetValue>
                    <resetMask>0xffffffff</resetMask>
                    <fields>
                        <field>
                            <name>RFREQ</name>
                            <description>Reference Clock Frequency Setting</description>
                            <lsb>0</lsb>
                            <msb>7</msb>
                            <access>read-write</access>
                        </field>
                    </fields>
                </register>
                <register>
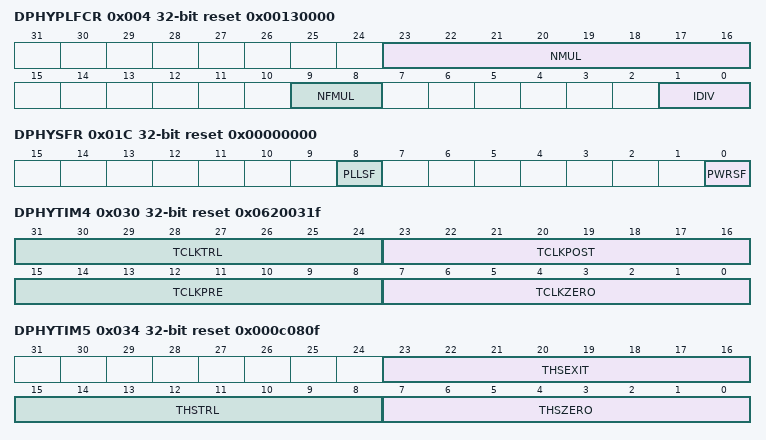
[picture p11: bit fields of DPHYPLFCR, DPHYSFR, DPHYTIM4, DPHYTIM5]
                    <name>DPHYPLFCR</name>
                    <description>D-PHY PLL Frequency Control Register</description>
                    <addressOffset>0x004</addressOffset>
                    <size>32</size>
                    <access>read-write</access>
                    <resetValue>0x00130000</resetValue>
                    <resetMask>0xffffffff</resetMask>
                    <fields>
                        <field>
                            <name>IDIV</name>
                            <description>D-PHY PLL Input Frequency Division Ratio Select</description>
                            <lsb>0</lsb>
                            <msb>1</msb>
                            <access>read-write</access>
                            <enumeratedValues>
                                <enumeratedValue>
                                    <name>00</name>
                                    <description>1</description>
                                    <value>#00</value>
                                </enumeratedValue>
                                <enumeratedValue>
                                    <name>01</name>
                                    <description>1/2</description>
                                    <value>#01</value>
                                </enumeratedValue>
                                <enumeratedValue>
                                    <name>10</name>
                                    <description>1/3</description>
                                    <value>#10</value>
                                </enumeratedValue>
                                <enumeratedValue>
                                    <name>11</name>
                                    <description>1/4</description>
                                    <value>#11</value>
                                </enumeratedValue>
                            </enumeratedValues>
                        </field>
                        <field>
                            <name>NFMUL</name>
                            <description>D-PHY PLL Frequency Multiplication Factor Select (Fractional Part)</description>
                            <lsb>8</lsb>
                            <msb>9</msb>
                            <access>read-write</access>
                            <enumeratedValues>
                                <enumeratedValue>
                                    <name>00</name>
                                    <description>0.00</description>
                                    <value>#00</value>
                                </enumeratedValue>
                                <enumeratedValue>
                                    <name>01</name>
                                    <description>0.33</description>
                                    <value>#01</value>
                                </enumeratedValue>
                                <enumeratedValue>
                                    <name>10</name>
                                    <description>0.66</description>
                                    <value>#10</value>
                                </enumeratedValue>
                                <enumeratedValue>
                                    <name>11</name>
                                    <description>0.50</description>
                                    <value>#11</value>
                                </enumeratedValue>
                            </enumeratedValues>
                        </field>
                        <field>
                            <name>NMUL</name>
                            <description>D-PHY PLL Frequency Multiplication Factor Select (Integer Part)</description>
                            <lsb>16</lsb>
                            <msb>23</msb>
                            <access>read-write</access>
                        </field>
                    </fields>
                </register>
                <register>
                    <name>DPHYPLOCR</name>
                    <description>D-PHY PLL Operation Control Register</description>
                    <addressOffset>0x008</addressOffset>
                    <size>32</size>
                    <access>read-write</access>
                    <resetValue>0x00000001</resetValue>
                    <resetMask>0xffffffff</resetMask>
                    <fields>
                        <field>
                            <name>PLLSTP</name>
                            <description>D-PHY PLL Operation Control</description>
                            <lsb>0</lsb>
                            <msb>0</msb>
                            <access>read-write</access>
                            <enumeratedValues>
                                <enumeratedValue>
                                    <name>0</name>
                                    <description>Operate the PLL</description>
                                    <value>#0</value>
                                </enumeratedValue>
                                <enumeratedValue>
                                    <name>1</name>
                                    <description>Stop the PLL</description>
                                    <value>#1</value>
                                </enumeratedValue>
                            </enumeratedValues>
                        </field>
                    </fields>
                </register>
                <register>
                    <name>DPHYESCCR</name>
                    <description>D-PHY Escape Mode Clock Control Register</description>
                    <addressOffset>0x00C</addressOffset>
                    <size>32</size>
                    <access>read-write</access>
                    <resetValue>0x00000000</resetValue>
                    <resetMask>0xffffffff</resetMask>
                    <fields>
                        <field>
                            <name>ESCDIV</name>
                            <description>Escape Mode Transfer Clock Division Ratio</description>
                            <lsb>0</lsb>
                            <msb>4</msb>
                            <access>read-write</access>
                        </field>
                    </fields>
                </register>
                <register>
                    <name>DPHYPWRCR</name>
                    <description>D-PHY Power Supplying Control Register</description>
                    <addressOffset>0x010</addressOffset>
                    <size>32</size>
                    <access>read-write</access>
                    <resetValue>0x00000000</resetValue>
                    <resetMask>0xffffffff</resetMask>
                    <fields>
                        <field>
                            <name>PWRSEN</name>
                            <description>D-PHY Power Supplying Control</description>
                            <lsb>0</lsb>
                            <msb>0</msb>
                            <access>read-write</access>
                            <enumeratedValues>
                                <enumeratedValue>
                                    <name>0</name>
                                    <description>Disable D-PHY LDO operation (stop supplying VDD_DPHY)</description>
                                    <value>#0</value>
                                </enumeratedValue>
                                <enumeratedValue>
                                    <name>1</name>
                                    <description>Enable D-PHY LDO operation (supply VDD_DPHY)</description>
                                    <value>#1</value>
                                </enumeratedValue>
                            </enumeratedValues>
                        </field>
                    </fields>
                </register>
                <register>
                    <name>DPHYSFR</name>
                    <description>D-PHY Status Flag Register</description>
                    <addressOffset>0x01C</addressOffset>
                    <size>32</size>
                    <access>read-only</access>
                    <resetValue>0x00000000</resetValue>
                    <resetMask>0xffffffff</resetMask>
                    <fields>
                        <field>
                            <name>PWRSF</name>
                            <description>D-PHY LDO Power-on Status Flag</description>
                            <lsb>0</lsb>
                            <msb>0</msb>
                            <access>read-only</access>
                            <enumeratedValues>
                                <enumeratedValue>
                                    <name>0</name>
                                    <description>D-PHY LDO is stopped or starting up</description>
                                    <value>#0</value>
                                </enumeratedValue>
                                <enumeratedValue>
                                    <name>1</name>
                                    <description>D-PHY LDO startup is completed (VDD_DPHY is stable)</description>
                                    <value>#1</value>
                                </enumeratedValue>
                            </enumeratedValues>
                        </field>
                        <field>
                            <name>PLLSF</name>
                            <description>D-PHY PLL Oscillation Stabilization Flag</description>
                            <lsb>8</lsb>
                            <msb>8</msb>
                            <access>read-only</access>
                            <enumeratedValues>
                                <enumeratedValue>
                                    <name>0</name>
                                    <description>D-PHY PLL clock is stopped or is not yet stable</description>
                                    <value>#0</value>
                                </enumeratedValue>
                                <enumeratedValue>
                                    <name>1</name>
                                    <description>D-PHY PLL clock is stable</description>
                                    <value>#1</value>
                                </enumeratedValue>
                            </enumeratedValues>
                        </field>
                    </fields>
                </register>
                <register>
                    <name>DPHYOCR</name>
                    <description>D-PHY Operation Control Register</description>
                    <addressOffset>0x020</addressOffset>
                    <size>32</size>
                    <access>read-write</access>
                    <resetValue>0x00000000</resetValue>
                    <resetMask>0xffffffff</resetMask>
                    <fields>
                        <field>
                            <name>DPHYEN</name>
                            <description>D-PHY Operation Control</description>
                            <lsb>0</lsb>
                            <msb>0</msb>
                            <access>read-write</access>
                            <enumeratedValues>
                                <enumeratedValue>
                                    <name>0</name>
                                    <description>Disable D-PHY operation</description>
                                    <value>#0</value>
                                </enumeratedValue>
                                <enumeratedValue>
                                    <name>1</name>
                                    <description>Enable D-PHY operation</description>
                                    <value>#1</value>
                                </enumeratedValue>
                            </enumeratedValues>
                        </field>
                    </fields>
                </register>
                <register>
                    <name>DPHYTIM1</name>
                    <description>D-PHY Timing Control Register 1</description>
                    <addressOffset>0x024</addressOffset>
                    <size>32</size>
                    <access>read-write</access>
                    <resetValue>0x00011941</resetValue>
                    <resetMask>0xffffffff</resetMask>
                    <fields>
                        <field>
                            <name>TINIT</name>
                            <description>D-PHY T_INIT Parameter Setting</description>
                            <lsb>0</lsb>
                            <msb>18</msb>
                            <access>read-write</access>
                        </field>
                    </fields>
                </register>
                <register>
                    <name>DPHYTIM2</name>
                    <description>D-PHY Timing Control Register 2</description>
                    <addressOffset>0x028</addressOffset>
                    <size>32</size>
                    <access>read-write</access>
                    <resetValue>0x00021008</resetValue>
                    <resetMask>0xffffffff</resetMask>
                    <fields>
                        <field>
                            <name>TCLKPREP</name>
                            <description>D-PHY T_CLK_PREPARE Parameter Setting</description>
                            <lsb>0</lsb>
                            <msb>7</msb>
                            <access>read-write</access>
                        </field>
                    </fields>
                </register>
                <register>
                    <name>DPHYTIM3</name>
                    <description>D-PHY Timing Control Register 3</description>
                    <addressOffset>0x02C</addressOffset>
                    <size>32</size>
                    <access>read-write</access>
                    <resetValue>0x00001008</resetValue>
                    <resetMask>0xffffffff</resetMask>
                    <fields>
                        <field>
                            <name>THSPREP</name>
                            <description>D-PHY T_THS_PREPARE Parameter Setting</description>
                            <lsb>0</lsb>
                            <msb>7</msb>
                            <access>read-write</access>
                        </field>
                    </fields>
                </register>
                <register>
                    <name>DPHYTIM4</name>
                    <description>D-PHY Timing Control Register 4</description>
                    <addressOffset>0x030</addressOffset>
                    <size>32</size>
                    <access>read-write</access>
                    <resetValue>0x0620031f</resetValue>
                    <resetMask>0xffffffff</resetMask>
                    <fields>
                        <field>
                            <name>TCLKZERO</name>
                            <description>D-PHY T_CLK_ZERO Parameter Setting</description>
                            <lsb>0</lsb>
                            <msb>7</msb>
                            <access>read-write</access>
                        </field>
                        <field>
                            <name>TCLKPRE</name>
                            <description>D-PHY T_TCLK_PRE Parameter Setting</description>
                            <lsb>8</lsb>
                            <msb>15</msb>
                            <access>read-write</access>
                        </field>
                        <field>
                            <name>TCLKPOST</name>
                            <description>D-PHY T_TCLK_POST Parameter Setting</description>
                            <lsb>16</lsb>
                            <msb>23</msb>
                            <access>read-write</access>
                        </field>
                        <field>
                            <name>TCLKTRL</name>
                            <description>D-PHY T_TCLK_TRAIL Parameter Setting</description>
                            <lsb>24</lsb>
                            <msb>31</msb>
                            <access>read-write</access>
                        </field>
                    </fields>
                </register>
                <register>
                    <name>DPHYTIM5</name>
                    <description>D-PHY Timing Control Register 5</description>
                    <addressOffset>0x034</addressOffset>
                    <size>32</size>
                    <access>read-write</access>
                    <resetValue>0x000c080f</resetValue>
                    <resetMask>0xffffffff</resetMask>
                    <fields>
                        <field>
                            <name>THSZERO</name>
                            <description>D-PHY T_THS_ZERO Parameter Setting</description>
                            <lsb>0</lsb>
                            <msb>7</msb>
                            <access>read-write</access>
                        </field>
                        <field>
                            <name>THSTRL</name>
                            <description>D-PHY T_THS_TRAIL Parameter Setting</description>
                            <lsb>8</lsb>
                            <msb>15</msb>
                            <access>read-write</access>
                        </field>
                        <field>
                            <name>THSEXIT</name>
                            <description>D-PHY T_THS_EXIT Parameter Setting</description>
                            <lsb>16</lsb>
                            <msb>23</msb>
                            <access>read-write</access>
                        </field>
                    </fields>
                </register>
                <register>
                    <name>DPHYTIM6</name>
                    <description>D-PHY Timing Control Register 6</description>
                    <addressOffset>0x038</addressOffset>
                    <size>32</size>
                    <access>read-write</access>
                    <resetValue>0x00000006</resetValue>
                    <resetMask>0xffffffff</resetMask>
                    <fields>
                        <field>
                            <name>TLPX</name>
                            <description>D-PHY T_TLPX Parameter Setting</description>
                            <lsb>0</lsb>
                            <msb>7</msb>
                            <access>read-write</access>
                        </field>
                    </fields>
                </register>
            </registers>
        </peripheral>
        <peripheral>
            <name>CEU</name>
            <description>Capture Engine Unit</description>
            <baseAddress>0x40348000</baseAddress>
            <addressBlock>
                <offset>0x00</offset>
                <size>28</size>
                <usage>registers</usage>
            </addressBlock>
            <addressBlock>
                <offset>0x28</offset>
                <size>40</size>
                <usage>registers</usage>
            </addressBlock>
            <addressBlock>
                <offset>0x5C</offset>
                <size>12</size>
                <usage>registers</usage>
            </addressBlock>
            <addressBlock>
                <offset>0x70</offset>
                <size>8</size>
                <usage>registers</usage>
            </addressBlock>
            <addressBlock>
                <offset>0x7C</offset>
                <size>4</size>
                <usage>registers</usage>
            </addressBlock>
            <addressBlock>
                <offset>0x84</offset>
                <size>4</size>
                <usage>registers</usage>
            </addressBlock>
            <addressBlock>
                <offset>0x90</offset>
                <size>20</size>
                <usage>registers</usage>
            </addressBlock>
            <addressBlock>
                <offset>0x1010</offset>
                <size>8</size>
                <usage>registers</usage>
            </addressBlock>
            <addressBlock>
                <offset>0x1030</offset>
                <size>32</size>
                <usage>registers</usage>
            </addressBlock>
            <addressBlock>
                <offset>0x1060</offset>
                <size>8</size>
                <usage>registers</usage>
            </addressBlock>
            <addressBlock>
                <offset>0x1090</offset>
                <size>16</size>
                <usage>registers</usage>
            </addressBlock>
            <addressBlock>
                <offset>0x2010</offset>
                <size>8</size>
                <usage>registers</usage>
            </addressBlock>
            <addressBlock>
                <offset>0x2030</offset>
                <size>32</size>
                <usage>registers</usage>
            </addressBlock>
            <addressBlock>
                <offset>0x2060</offset>
                <size>8</size>
                <usage>registers</usage>
            </addressBlock>
            <addressBlock>
                <offset>0x2090</offset>
                <size>16</size>
                <usage>registers</usage>
            </addressBlock>
            <registers>
                <register>
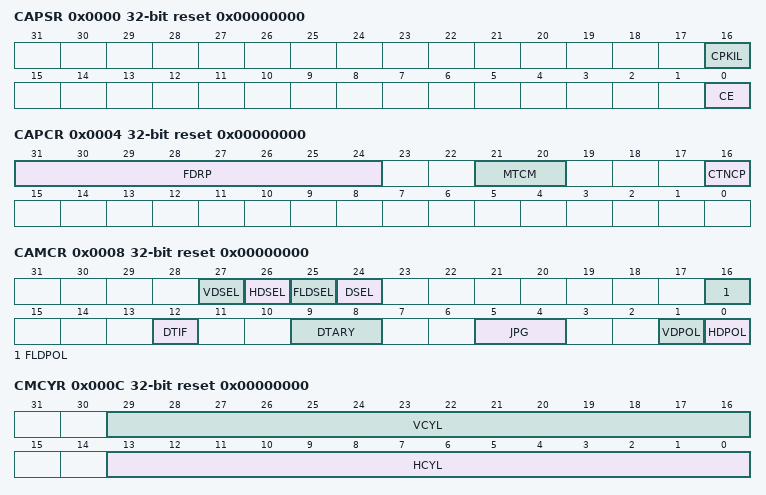
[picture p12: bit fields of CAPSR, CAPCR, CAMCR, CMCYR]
                    <name>CAPSR</name>
                    <description>Capture Start Register</description>
                    <addressOffset>0x0000</addressOffset>
                    <size>32</size>
                    <access>read-write</access>
                    <resetValue>0x00000000</resetValue>
                    <resetMask>0xffffffff</resetMask>
                    <fields>
                        <field>
                            <name>CE</name>
                            <description>Capture enable</description>
                            <lsb>0</lsb>
                            <msb>0</msb>
                            <access>read-write</access>
                            <enumeratedValues>
                                <enumeratedValue>
                                    <name>0</name>
                                    <description>Stops capturing</description>
                                    <value>#0</value>
                                </enumeratedValue>
                                <enumeratedValue>
                                    <name>1</name>
                                    <description>Starts capturing</description>
                                    <value>#1</value>
                                </enumeratedValue>
                            </enumeratedValues>
                        </field>
                        <field>
                            <name>CPKIL</name>
                            <description>Software reset of capturing</description>
                            <lsb>16</lsb>
                            <msb>16</msb>
                            <access>read-write</access>
                            <enumeratedValues>
                                <enumeratedValue>
                                    <name>0</name>
                                    <description>Normal state</description>
                                    <value>#0</value>
                                </enumeratedValue>
                                <enumeratedValue>
                                    <name>1</name>
                                    <description>Software reset of capturing</description>
                                    <value>#1</value>
                                </enumeratedValue>
                            </enumeratedValues>
                        </field>
                    </fields>
                </register>
                <register>
                    <name>CAPCR</name>
                    <description>Capture Control Register</description>
                    <addressOffset>0x0004</addressOffset>
                    <size>32</size>
                    <access>read-write</access>
                    <resetValue>0x00000000</resetValue>
                    <resetMask>0xffffffff</resetMask>
                    <fields>
                        <field>
                            <name>CTNCP</name>
                            <description>Continuous capture</description>
                            <lsb>16</lsb>
                            <msb>16</msb>
                            <access>read-write</access>
                            <enumeratedValues>
                                <enumeratedValue>
                                    <name>0</name>
                                    <description>One-frame capture when CAPSR.CE = 1</description>
                                    <value>#0</value>
                                </enumeratedValue>
                                <enumeratedValue>
                                    <name>1</name>
                                    <description>Continuous capture until CAPSR.CE = 0</description>
                                    <value>#1</value>
                                </enumeratedValue>
                            </enumeratedValues>
                        </field>
                        <field>
                            <name>MTCM</name>
                            <description>Specify the unit for transferring data to a bus bridge module.</description>
                            <lsb>20</lsb>
                            <msb>21</msb>
                            <access>read-write</access>
                            <enumeratedValues>
                                <enumeratedValue>
                                    <name>00</name>
                                    <description>Image capture: Y data and C data are transferred in 32-byte units Data fetch : Data is transferred in 32-byte units </description>
                                    <value>#00</value>
                                </enumeratedValue>
                                <enumeratedValue>
                                    <name>01</name>
                                    <description>Image capture: Y data and C data are transferred in 64-byte units Data fetch : Data is transferred in 64-byte </description>
                                    <value>#01</value>
                                </enumeratedValue>
                                <enumeratedValue>
                                    <name>10</name>
                                    <description>Image capture: Y data and C data are transferred in 128-byte units Data fetch : Data is transferred in 128-byte </description>
                                    <value>#10</value>
                                </enumeratedValue>
                                <enumeratedValue>
                                    <name>11</name>
                                    <description>Image capture: Y data and C data are transferred in 256-byte units Data fetch : Data is transferred in 256-byte </description>
                                    <value>#11</value>
                                </enumeratedValue>
                            </enumeratedValues>
                        </field>
                        <field>
                            <name>FDRP</name>
                            <description>Set the frame drop interval in continuous-frame capture.</description>
                            <lsb>24</lsb>
                            <msb>31</msb>
                            <access>read-write</access>
                        </field>
                    </fields>
                </register>
                <register>
                    <name>CAMCR</name>
                    <description>Capture Interface Control Register</description>
                    <addressOffset>0x0008</addressOffset>
                    <size>32</size>
                    <access>read-write</access>
                    <resetValue>0x00000000</resetValue>
                    <resetMask>0xffffffff</resetMask>
                    <fields>
                        <field>
                            <name>HDPOL</name>
                            <description>Sets the polarity for detection of the horizontal sync signal (HD) input from an external module.</description>
                            <lsb>0</lsb>
                            <msb>0</msb>
                            <access>read-write</access>
                            <enumeratedValues>
                                <enumeratedValue>
                                    <name>0</name>
                                    <description>Horizontal sync signal (HD) from an external module is detected as high active</description>
                                    <value>#0</value>
                                </enumeratedValue>
                                <enumeratedValue>
                                    <name>1</name>
                                    <description>Horizontal sync signal (HD) from an external module is detected as low active</description>
                                    <value>#1</value>
                                </enumeratedValue>
                            </enumeratedValues>
                        </field>
                        <field>
                            <name>VDPOL</name>
                            <description>Sets the polarity for detection of the vertical sync signal (VD) input from an external module.</description>
                            <lsb>1</lsb>
                            <msb>1</msb>
                            <access>read-write</access>
                            <enumeratedValues>
                                <enumeratedValue>
                                    <name>0</name>
                                    <description>Vertical sync signal (VD) from an external module is detected as high active</description>
                                    <value>#0</value>
                                </enumeratedValue>
                                <enumeratedValue>
                                    <name>1</name>
                                    <description>Vertical sync signal (VD) from an external module is detected as low active</description>
                                    <value>#1</value>
                                </enumeratedValue>
                            </enumeratedValues>
                        </field>
                        <field>
                            <name>JPG</name>
                            <description>These bits select the fetched data type.</description>
                            <lsb>4</lsb>
                            <msb>5</msb>
                            <access>read-write</access>
                            <enumeratedValues>
                                <enumeratedValue>
                                    <name>00</name>
                                    <description>Image capture mode (input data are separated into the luminance component data (Y) and the chrominance component data (CbCr) for output to the memory) </description>
                                    <value>#00</value>
                                </enumeratedValue>
                                <enumeratedValue>
                                    <name>01</name>
                                    <description>Data synchronous fetch mode (specified size of input data are output to the specified memory addresses in order of input and in synchronization with the sync signal) </description>
                                    <value>#01</value>
                                </enumeratedValue>
                                <enumeratedValue>
                                    <name>10</name>
                                    <description>Data enable fetch mode (input data are fetched with HD as an enable signal and output to the specified addresses in memory in order of input) </description>
                                    <value>#10</value>
                                </enumeratedValue>
                                <enumeratedValue>
                                    <name>11</name>
                                    <description>Setting prohibited</description>
                                    <value>#11</value>
                                </enumeratedValue>
                            </enumeratedValues>
                        </field>
                        <field>
                            <name>DTARY</name>
                            <description>Set the input order of the luminance component and chrominance component.</description>
                            <lsb>8</lsb>
                            <msb>9</msb>
                            <access>read-write</access>
                            <enumeratedValues>
                                <enumeratedValue>
                                    <name>00</name>
                                    <description>8-bit interface: Image input data is fetched in the order of Cb0, Y0, Cr0, and Y1 16-bit interface: Image input data is fetched in the order of {Cb0, Y0} and {Cr0, Y1} </description>
                                    <value>#00</value>
                                </enumeratedValue>
                                <enumeratedValue>
                                    <name>01</name>
                                    <description>8-bit interface: Image input data is fetched in the order of Cr0, Y0, Cb0, and Y1 16-bit interface: Image input data is fetched in the order of {Cr0, Y0} and {Cb0, Y1} </description>
                                    <value>#01</value>
                                </enumeratedValue>
                                <enumeratedValue>
                                    <name>10</name>
                                    <description>8-bit interface: Image input data is fetched in the order of Y0, Cb0, Y1, and Cr0 16-bit interface: Image input data is fetched in the order of {Y0, Cb0} and {Y1, Cr0} </description>
                                    <value>#10</value>
                                </enumeratedValue>
                                <enumeratedValue>
                                    <name>11</name>
                                    <description>8-bit interface: Image input data is fetched in the order of Y0, Cr0, Y1, and Cb0 16-bit interface: Image input data is fetched in the order of {Y0, Cr0} and {Y1, Cb0} </description>
                                    <value>#11</value>
                                </enumeratedValue>
                            </enumeratedValues>
                        </field>
                        <field>
                            <name>DTIF</name>
                            <description>Sets the digital image input pins from which data is to be captured.</description>
                            <lsb>12</lsb>
                            <msb>12</msb>
                            <access>read-write</access>
                            <enumeratedValues>
                                <enumeratedValue>
                                    <name>0</name>
                                    <description>Data input to 8-bit digital image input pins is captured</description>
                                    <value>#0</value>
                                </enumeratedValue>
                                <enumeratedValue>
                                    <name>1</name>
                                    <description>Data input to 16-bit digital image input pins is captured</description>
                                    <value>#1</value>
                                </enumeratedValue>
                            </enumeratedValues>
                        </field>
                        <field>
                            <name>FLDPOL</name>
                            <description>Sets the polarity of the field identification signal (FLD) from an external module.</description>
                            <lsb>16</lsb>
                            <msb>16</msb>
                            <access>read-write</access>
                            <enumeratedValues>
                                <enumeratedValue>
                                    <name>0</name>
                                    <description>When the FLD signal is high-active, the field is detected as the top field and when low-active, the field is detected as the bottom field. </description>
                                    <value>#0</value>
                                </enumeratedValue>
                                <enumeratedValue>
                                    <name>1</name>
                                    <description>When the FLD signal is low-active, the field is detected as the top field and when high-active, the field is detected as the bottom field. </description>
                                    <value>#1</value>
                                </enumeratedValue>
                            </enumeratedValues>
                        </field>
                        <field>
                            <name>DSEL</name>
                            <description>Sets the edge for fetching the image data (D15 to D0) from an external module.</description>
                            <lsb>24</lsb>
                            <msb>24</msb>
                            <access>read-write</access>
                            <enumeratedValues>
                                <enumeratedValue>
                                    <name>0</name>
                                    <description>D15 to D0 are fetched at the rising edge of the camera clock.</description>
                                    <value>#0</value>
                                </enumeratedValue>
                                <enumeratedValue>
                                    <name>1</name>
                                    <description>D15 to D0 are fetched at the falling edge of the camera clock.</description>
                                    <value>#1</value>
                                </enumeratedValue>
                            </enumeratedValues>
                        </field>
                        <field>
                            <name>FLDSEL</name>
                            <description>Sets the edge for capturing FLD from an external module.</description>
                            <lsb>25</lsb>
                            <msb>25</msb>
                            <access>read-write</access>
                            <enumeratedValues>
                                <enumeratedValue>
                                    <name>0</name>
                                    <description>FLD is captured at the rising edge of the camera clock.</description>
                                    <value>#0</value>
                                </enumeratedValue>
                                <enumeratedValue>
                                    <name>1</name>
                                    <description>FLD is captured at the falling edge of the camera clock.</description>
                                    <value>#1</value>
                                </enumeratedValue>
                            </enumeratedValues>
                        </field>
                        <field>
                            <name>HDSEL</name>
                            <description>Sets the edge for capturing HD from an external module.</description>
                            <lsb>26</lsb>
                            <msb>26</msb>
                            <access>read-write</access>
                            <enumeratedValues>
                                <enumeratedValue>
                                    <name>0</name>
                                    <description>HD is captured at the rising edge of the camera clock.</description>
                                    <value>#0</value>
                                </enumeratedValue>
                                <enumeratedValue>
                                    <name>1</name>
                                    <description>HD is captured at the falling edge of the camera clock.</description>
                                    <value>#1</value>
                                </enumeratedValue>
                            </enumeratedValues>
                        </field>
                        <field>
                            <name>VDSEL</name>
                            <description>Sets the edge for capturing VD from an external module.</description>
                            <lsb>27</lsb>
                            <msb>27</msb>
                            <access>read-write</access>
                            <enumeratedValues>
                                <enumeratedValue>
                                    <name>0</name>
                                    <description>VD is captured at the rising edge of the camera clock.</description>
                                    <value>#0</value>
                                </enumeratedValue>
                                <enumeratedValue>
                                    <name>1</name>
                                    <description>VD is captured at the falling edge of the camera clock.</description>
                                    <value>#1</value>
                                </enumeratedValue>
                            </enumeratedValues>
                        </field>
                    </fields>
                </register>
                <register>
                    <name>CMCYR</name>
                    <description>Capture Interface Cycle Register</description>
                    <addressOffset>0x000C</addressOffset>
                    <size>32</size>
                    <access>read-write</access>
                    <resetValue>0x00000000</resetValue>
                    <resetMask>0xffffffff</resetMask>
                    <fields>
                        <field>
                            <name>HCYL</name>
                            <description>Horizontal Cycle Count of External Module</description>
                            <lsb>0</lsb>
                            <msb>13</msb>
                            <access>read-write</access>
                        </field>
                        <field>
                            <name>VCYL</name>
                            <description>Vertical HD Count of External Module</description>
                            <lsb>16</lsb>
                            <msb>29</msb>
                            <access>read-write</access>
                        </field>
                    </fields>
                </register>
                <register>
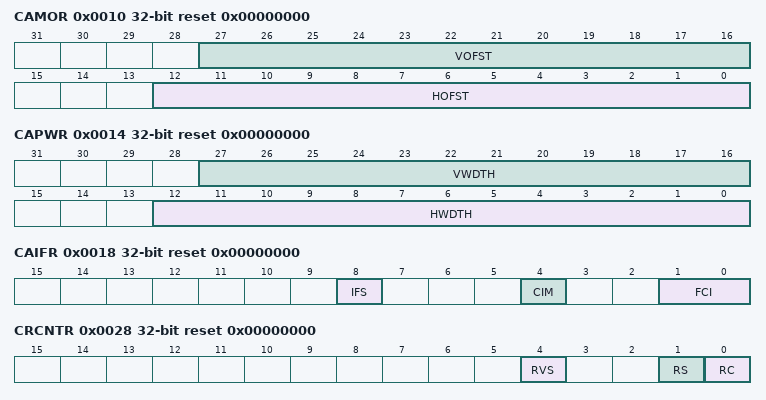
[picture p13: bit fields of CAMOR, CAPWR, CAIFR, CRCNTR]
                    <name>CAMOR</name>
                    <description>Capture Interface Offset Register</description>
                    <addressOffset>0x0010</addressOffset>
                    <size>32</size>
                    <access>read-write</access>
                    <resetValue>0x00000000</resetValue>
                    <resetMask>0xffffffff</resetMask>
                    <fields>
                        <field>
                            <name>HOFST</name>
                            <description>Specify the capture start location in terms of the number of clock cycles from a horizontal sync signal (1-cycle units).</description>
                            <lsb>0</lsb>
                            <msb>12</msb>
                            <access>read-write</access>
                        </field>
                        <field>
                            <name>VOFST</name>
                            <description>Specify the capture start location in terms of the HD count from a vertical sync signal (1-HD units).</description>
                            <lsb>16</lsb>
                            <msb>27</msb>
                            <access>read-write</access>
                        </field>
                    </fields>
                </register>
                <register>
                    <name>CAPWR</name>
                    <description>Capture Interface Width Register</description>
                    <addressOffset>0x0014</addressOffset>
                    <size>32</size>
                    <access>read-write</access>
                    <resetValue>0x00000000</resetValue>
                    <resetMask>0xffffffff</resetMask>
                    <fields>
                        <field>
                            <name>HWDTH</name>
                            <description>Specify the horizontal capture period.</description>
                            <lsb>0</lsb>
                            <msb>12</msb>
                            <access>read-write</access>
                        </field>
                        <field>
                            <name>VWDTH</name>
                            <description>Specify the vertical capture period (4-HD units).</description>
                            <lsb>16</lsb>
                            <msb>27</msb>
                            <access>read-write</access>
                        </field>
                    </fields>
                </register>
                <register>
                    <name>CAIFR</name>
                    <description>Capture Interface Input Format Register</description>
                    <addressOffset>0x0018</addressOffset>
                    <size>32</size>
                    <access>read-write</access>
                    <resetValue>0x00000000</resetValue>
                    <resetMask>0xffffffff</resetMask>
                    <fields>
                        <field>
                            <name>FCI</name>
                            <description>Set the timing to start capturing.</description>
                            <lsb>0</lsb>
                            <msb>1</msb>
                            <access>read-write</access>
                            <enumeratedValues>
                                <enumeratedValue>
                                    <name>00</name>
                                    <description>Capture starts from the VD input immediately after the CEU activation regardless of it being a top or bottom field </description>
                                    <value>#00</value>
                                </enumeratedValue>
                                <enumeratedValue>
                                    <name>01</name>
                                    <description>After the CEU activation, input of a top-field image is waited, and then capture starts from the top field </description>
                                    <value>#01</value>
                                </enumeratedValue>
                                <enumeratedValue>
                                    <name>10</name>
                                    <description>After the CEU activation, input of a bottom-field image is waited, and then capture starts from the bottom field </description>
                                    <value>#10</value>
                                </enumeratedValue>
                                <enumeratedValue>
                                    <name>11</name>
                                    <description>Setting prohibited</description>
                                    <value>#11</value>
                                </enumeratedValue>
                            </enumeratedValues>
                        </field>
                        <field>
                            <name>CIM</name>
                            <description>Sets the images to be captured.</description>
                            <lsb>4</lsb>
                            <msb>4</msb>
                            <access>read-write</access>
                            <enumeratedValues>
                                <enumeratedValue>
                                    <name>0</name>
                                    <description>Capture of frame image (1 VD) or both-field image (2 VD)</description>
                                    <value>#0</value>
                                </enumeratedValue>
                                <enumeratedValue>
                                    <name>1</name>
                                    <description>Capture of one-field image (1 VD)</description>
                                    <value>#1</value>
                                </enumeratedValue>
                            </enumeratedValues>
                        </field>
                        <field>
                            <name>IFS</name>
                            <description>Sets the input mode for capturing images.</description>
                            <lsb>8</lsb>
                            <msb>8</msb>
                            <access>read-write</access>
                            <enumeratedValues>
                                <enumeratedValue>
                                    <name>0</name>
                                    <description>Progressive</description>
                                    <value>#0</value>
                                </enumeratedValue>
                                <enumeratedValue>
                                    <name>1</name>
                                    <description>Interlace</description>
                                    <value>#1</value>
                                </enumeratedValue>
                            </enumeratedValues>
                        </field>
                    </fields>
                </register>
                <register>
                    <name>CRCNTR</name>
                    <description>CEU Register Control Register</description>
                    <addressOffset>0x0028</addressOffset>
                    <size>32</size>
                    <access>read-write</access>
                    <resetValue>0x00000000</resetValue>
                    <resetMask>0xffffffff</resetMask>
                    <fields>
                        <field>
                            <name>RC</name>
                            <description>Specifies switching of the register plane used by the CEU in synchronization with VD.</description>
                            <lsb>0</lsb>
                            <msb>0</msb>
                            <access>read-write</access>
                            <enumeratedValues>
                                <enumeratedValue>
                                    <name>0</name>
                                    <description>Uses the specified register plane in synchronization with VD</description>
                                    <value>#0</value>
                                </enumeratedValue>
                                <enumeratedValue>
                                    <name>1</name>
                                    <description>Switches the register plane in synchronization with VD</description>
                                    <value>#1</value>
                                </enumeratedValue>
                            </enumeratedValues>
                        </field>
                        <field>
                            <name>RS</name>
                            <description>Specifies which register plane is used by the CEU in synchronization with VD.</description>
                            <lsb>1</lsb>
                            <msb>1</msb>
                            <access>read-write</access>
                            <enumeratedValues>
                                <enumeratedValue>
                                    <name>0</name>
                                    <description>Uses plane A of the register</description>
                                    <value>#0</value>
                                </enumeratedValue>
                                <enumeratedValue>
                                    <name>1</name>
                                    <description>Uses plane B of the register</description>
                                    <value>#1</value>
                                </enumeratedValue>
                            </enumeratedValues>
                        </field>
                        <field>
                            <name>RVS</name>
                            <description>Sets the timing to switch the register plane in both-field capture.</description>
                            <lsb>4</lsb>
                            <msb>4</msb>
                            <access>read-write</access>
                            <enumeratedValues>
                                <enumeratedValue>
                                    <name>0</name>
                                    <description>Switches the register plane every 2 VD</description>
                                    <value>#0</value>
                                </enumeratedValue>
                                <enumeratedValue>
                                    <name>1</name>
                                    <description>Switches the register plane every 1 VD</description>
                                    <value>#1</value>
                                </enumeratedValue>
                            </enumeratedValues>
                        </field>
                    </fields>
                </register>
                <register>
                    <name>CRCMPR</name>
                    <description>CEU Register Forcible Control Register</description>
                    <addressOffset>0x002C</addressOffset>
                    <size>32</size>
                    <access>read-write</access>
                    <resetValue>0x00000000</resetValue>
                    <resetMask>0xffffffff</resetMask>
                    <fields>
                        <field>
                            <name>RA</name>
                            <description>Indicates the register plane currently specified.</description>
                            <lsb>0</lsb>
                            <msb>0</msb>
                            <access>read-write</access>
                            <enumeratedValues>
                                <enumeratedValue>
                                    <name>0</name>
                                    <description>Specifies plane A of the register</description>
                                    <value>#0</value>
                                </enumeratedValue>
                                <enumeratedValue>
                                    <name>1</name>
                                    <description>Specifies plane B of the register</description>
                                    <value>#1</value>
                                </enumeratedValue>
                            </enumeratedValues>
                        </field>
                    </fields>
                </register>
                <register>
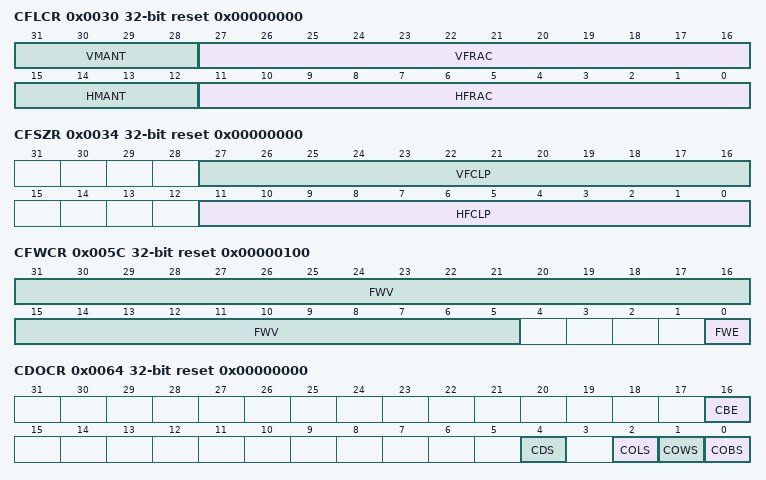
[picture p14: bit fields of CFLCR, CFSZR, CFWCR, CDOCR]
                    <name>CFLCR</name>
                    <description>Capture Filter Control Register</description>
                    <addressOffset>0x0030</addressOffset>
                    <size>32</size>
                    <access>read-write</access>
                    <resetValue>0x00000000</resetValue>
                    <resetMask>0xffffffff</resetMask>
                    <fields>
                        <field>
                            <name>HFRAC</name>
                            <description>Fraction Part of Horizontal Scale-Down Factor</description>
                            <lsb>0</lsb>
                            <msb>11</msb>
                            <access>read-write</access>
                        </field>
                        <field>
                            <name>HMANT</name>
                            <description>Mantissa Part of Horizontal Scale-Down Factor</description>
                            <lsb>12</lsb>
                            <msb>15</msb>
                            <access>read-write</access>
                        </field>
                        <field>
                            <name>VFRAC</name>
                            <description>Fraction Part of Vertical Scale-Down Factor</description>
                            <lsb>16</lsb>
                            <msb>27</msb>
                            <access>read-write</access>
                        </field>
                        <field>
                            <name>VMANT</name>
                            <description>Mantissa Part of Vertical Scale-Down Factor</description>
                            <lsb>28</lsb>
                            <msb>31</msb>
                            <access>read-write</access>
                        </field>
                    </fields>
                </register>
                <register>
                    <name>CFSZR</name>
                    <description>Capture Filter Size Clip Register</description>
                    <addressOffset>0x0034</addressOffset>
                    <size>32</size>
                    <access>read-write</access>
                    <resetValue>0x00000000</resetValue>
                    <resetMask>0xffffffff</resetMask>
                    <fields>
                        <field>
                            <name>HFCLP</name>
                            <description>Specify the horizontal clipping value of the filter output size (8-pixel units).</description>
                            <lsb>0</lsb>
                            <msb>11</msb>
                            <access>read-write</access>
                        </field>
                        <field>
                            <name>VFCLP</name>
                            <description>Specify the vertical clipping value of the filter output size (4-pixel units).</description>
                            <lsb>16</lsb>
                            <msb>27</msb>
                            <access>read-write</access>
                        </field>
                    </fields>
                </register>
                <register>
                    <name>CDWDR</name>
                    <description>Capture Destination Width Register</description>
                    <addressOffset>0x0038</addressOffset>
                    <size>32</size>
                    <access>read-write</access>
                    <resetValue>0x00000000</resetValue>
                    <resetMask>0xffffffff</resetMask>
                    <fields>
                        <field>
                            <name>CHDW</name>
                            <description>Specify the horizontal image size in the memory area where the captured image is to be stored (8-byte units).</description>
                            <lsb>0</lsb>
                            <msb>12</msb>
                            <access>read-write</access>
                        </field>
                    </fields>
                </register>
                <register>
                    <name>CDAYR</name>
                    <description>Capture Data Address Y Register</description>
                    <addressOffset>0x003C</addressOffset>
                    <size>32</size>
                    <access>read-write</access>
                    <resetValue>0x00000000</resetValue>
                    <resetMask>0xffffffff</resetMask>
                    <fields>
                        <field>
                            <name>CAYR</name>
                            <description>Capture Data Address Y</description>
                            <lsb>0</lsb>
                            <msb>31</msb>
                            <access>read-write</access>
                        </field>
                    </fields>
                </register>
                <register>
                    <name>CDACR</name>
                    <description>Capture Data Address C Register</description>
                    <addressOffset>0x0040</addressOffset>
                    <size>32</size>
                    <access>read-write</access>
                    <resetValue>0x00000000</resetValue>
                    <resetMask>0xffffffff</resetMask>
                    <fields>
                        <field>
                            <name>CACR</name>
                            <description>Capture Data Address C</description>
                            <lsb>0</lsb>
                            <msb>31</msb>
                            <access>read-write</access>
                        </field>
                    </fields>
                </register>
                <register>
                    <name>CDBYR</name>
                    <description>Capture Data Bottom-Field Address Y Register</description>
                    <addressOffset>0x0044</addressOffset>
                    <size>32</size>
                    <access>read-write</access>
                    <resetValue>0x00000000</resetValue>
                    <resetMask>0xffffffff</resetMask>
                    <fields>
                        <field>
                            <name>CBYR</name>
                            <description>Set the address for storing the luminance component data of the captured bottom-field data (8-pixel units).</description>
                            <lsb>0</lsb>
                            <msb>31</msb>
                            <access>read-write</access>
                        </field>
                    </fields>
                </register>
                <register>
                    <name>CDBCR</name>
                    <description>Capture Data Bottom-Field Address C Register</description>
                    <addressOffset>0x0048</addressOffset>
                    <size>32</size>
                    <access>read-write</access>
                    <resetValue>0x00000000</resetValue>
                    <resetMask>0xffffffff</resetMask>
                    <fields>
                        <field>
                            <name>CBCR</name>
                            <description>Set the address for storing the chrominance component data of the captured bottom-field data (8-pixel units).</description>
                            <lsb>0</lsb>
                            <msb>31</msb>
                            <access>read-write</access>
                        </field>
                    </fields>
                </register>
                <register>
                    <name>CBDSR</name>
                    <description>Capture Bundle Destination Size Register</description>
                    <addressOffset>0x004C</addressOffset>
                    <size>32</size>
                    <access>read-write</access>
                    <resetValue>0x00000000</resetValue>
                    <resetMask>0xffffffff</resetMask>
                    <fields>
                        <field>
                            <name>CBVS</name>
                            <description>Select the number of lines or number of bytes for output to the memory in a bundle write.</description>
                            <lsb>0</lsb>
                            <msb>22</msb>
                            <access>read-write</access>
                        </field>
                    </fields>
                </register>
                <register>
                    <name>CFWCR</name>
                    <description>Firewall Operation Control Register</description>
                    <addressOffset>0x005C</addressOffset>
                    <size>32</size>
                    <access>read-write</access>
                    <resetValue>0x00000100</resetValue>
                    <resetMask>0xffffffff</resetMask>
                    <fields>
                        <field>
                            <name>FWE</name>
                            <description>Firewall Operation</description>
                            <lsb>0</lsb>
                            <msb>0</msb>
                            <access>read-write</access>
                            <enumeratedValues>
                                <enumeratedValue>
                                    <name>0</name>
                                    <description>Firewall is not activated.</description>
                                    <value>#0</value>
                                </enumeratedValue>
                                <enumeratedValue>
                                    <name>1</name>
                                    <description>Firewall is activated.</description>
                                    <value>#1</value>
                                </enumeratedValue>
                            </enumeratedValues>
                        </field>
                        <field>
                            <name>FWV</name>
                            <description>Specify the upper limit of a write address.</description>
                            <lsb>5</lsb>
                            <msb>31</msb>
                            <access>read-write</access>
                        </field>
                    </fields>
                </register>
                <register>
                    <name>CLFCR</name>
                    <description>Capture Low-Pass Filter Control Register</description>
                    <addressOffset>0x0060</addressOffset>
                    <size>32</size>
                    <access>read-write</access>
                    <resetValue>0x00000000</resetValue>
                    <resetMask>0xffffffff</resetMask>
                    <fields>
                        <field>
                            <name>LPF</name>
                            <description>Enables or disables operation of the low-pass filter.</description>
                            <lsb>0</lsb>
                            <msb>0</msb>
                            <access>read-write</access>
                            <enumeratedValues>
                                <enumeratedValue>
                                    <name>0</name>
                                    <description>Low-pass filter not used</description>
                                    <value>#0</value>
                                </enumeratedValue>
                                <enumeratedValue>
                                    <name>1</name>
                                    <description>Low-pass filter used (only in the horizontal direction)</description>
                                    <value>#1</value>
                                </enumeratedValue>
                            </enumeratedValues>
                        </field>
                    </fields>
                </register>
                <register>
                    <name>CDOCR</name>
                    <description>Capture Data Output Control Register</description>
                    <addressOffset>0x0064</addressOffset>
                    <size>32</size>
                    <access>read-write</access>
                    <resetValue>0x00000000</resetValue>
                    <resetMask>0xffffffff</resetMask>
                    <fields>
                        <field>
                            <name>COBS</name>
                            <description>Controls swapping in 8-bit units for data output from the CEU.</description>
                            <lsb>0</lsb>
                            <msb>0</msb>
                            <access>read-write</access>
                            <enumeratedValues>
                                <enumeratedValue>
                                    <name>0</name>
                                    <description>Data is not swapped in 8-bit units</description>
                                    <value>#0</value>
                                </enumeratedValue>
                                <enumeratedValue>
                                    <name>1</name>
                                    <description>Data is swapped in 8-bit units</description>
                                    <value>#1</value>
                                </enumeratedValue>
                            </enumeratedValues>
                        </field>
                        <field>
                            <name>COWS</name>
                            <description>Controls swapping in 16-bit units for data output from the CEU.</description>
                            <lsb>1</lsb>
                            <msb>1</msb>
                            <access>read-write</access>
                            <enumeratedValues>
                                <enumeratedValue>
                                    <name>0</name>
                                    <description>Data is not swapped in 16-bit units</description>
                                    <value>#0</value>
                                </enumeratedValue>
                                <enumeratedValue>
                                    <name>1</name>
                                    <description>Data is swapped in 16-bit units</description>
                                    <value>#1</value>
                                </enumeratedValue>
                            </enumeratedValues>
                        </field>
                        <field>
                            <name>COLS</name>
                            <description>Controls swapping in 32-bit units for data output from the CEU.</description>
                            <lsb>2</lsb>
                            <msb>2</msb>
                            <access>read-write</access>
                            <enumeratedValues>
                                <enumeratedValue>
                                    <name>0</name>
                                    <description>Data is not swapped in 32-bit units</description>
                                    <value>#0</value>
                                </enumeratedValue>
                                <enumeratedValue>
                                    <name>1</name>
                                    <description>Data is swapped in 32-bit units</description>
                                    <value>#1</value>
                                </enumeratedValue>
                            </enumeratedValues>
                        </field>
                        <field>
                            <name>CDS</name>
                            <description>Sets the image format when outputting the image data captured in the YCbCr422 format to the memory.</description>
                            <lsb>4</lsb>
                            <msb>4</msb>
                            <access>read-write</access>
                            <enumeratedValues>
                                <enumeratedValue>
                                    <name>0</name>
                                    <description>Converts the YCbCr422 format to the YCbCr420 format before outputting data to the memory</description>
                                    <value>#0</value>
                                </enumeratedValue>
                                <enumeratedValue>
                                    <name>1</name>
                                    <description>Outputs data in the YCbCr422 format to the memory without conversion</description>
                                    <value>#1</value>
                                </enumeratedValue>
                            </enumeratedValues>
                        </field>
                        <field>
                            <name>CBE</name>
                            <description> Controls the number of lines of captured data to be written to the memory.</description>
                            <lsb>16</lsb>
                            <msb>16</msb>
                            <access>read-write</access>
                            <enumeratedValues>
                                <enumeratedValue>
                                    <name>0</name>
                                    <description>Normal write</description>
                                    <value>#0</value>
                                </enumeratedValue>
                                <enumeratedValue>
                                    <name>1</name>
                                    <description>Bundle write</description>
                                    <value>#1</value>
                                </enumeratedValue>
                            </enumeratedValues>
                        </field>
                    </fields>
                </register>
                <register>
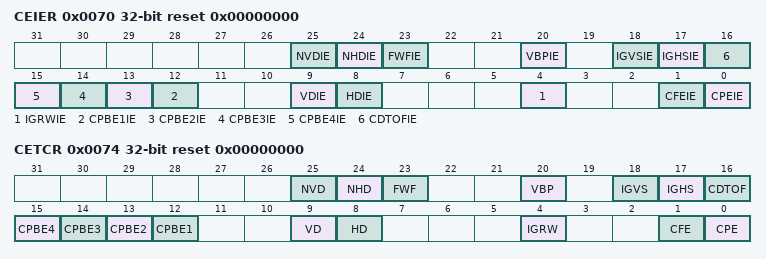
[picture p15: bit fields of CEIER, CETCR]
                    <name>CEIER</name>
                    <description>Capture Event Interrupt Enable Register</description>
                    <addressOffset>0x0070</addressOffset>
                    <size>32</size>
                    <access>read-write</access>
                    <resetValue>0x00000000</resetValue>
                    <resetMask>0xffffffff</resetMask>
                    <fields>
                        <field>
                            <name>CPEIE</name>
                            <description>One-Frame Capture End Interrupt Enable</description>
                            <lsb>0</lsb>
                            <msb>0</msb>
                            <access>read-write</access>
                            <enumeratedValues>
                                <enumeratedValue>
                                    <name>0</name>
                                    <description>Disables a one-frame capture end interrupt</description>
                                    <value>#0</value>
                                </enumeratedValue>
                                <enumeratedValue>
                                    <name>1</name>
                                    <description>Enables a one-frame capture end interrupt</description>
                                    <value>#1</value>
                                </enumeratedValue>
                            </enumeratedValues>
                        </field>
                        <field>
                            <name>CFEIE</name>
                            <description>CFE Interrupt Enable</description>
                            <lsb>1</lsb>
                            <msb>1</msb>
                            <access>read-write</access>
                            <enumeratedValues>
                                <enumeratedValue>
                                    <name>0</name>
                                    <description>Disables a CFE interrupt</description>
                                    <value>#0</value>
                                </enumeratedValue>
                                <enumeratedValue>
                                    <name>1</name>
                                    <description>Enables a CFE interrupt</description>
                                    <value>#1</value>
                                </enumeratedValue>
                            </enumeratedValues>
                        </field>
                        <field>
                            <name>IGRWIE</name>
                            <description>Register-Access-During-Capture Interrupt Enable</description>
                            <lsb>4</lsb>
                            <msb>4</msb>
                            <access>read-write</access>
                            <enumeratedValues>
                                <enumeratedValue>
                                    <name>0</name>
                                    <description>Disables a register-access-during-capture interrupt</description>
                                    <value>#0</value>
                                </enumeratedValue>
                                <enumeratedValue>
                                    <name>1</name>
                                    <description>Enables a register-access-during-capture interrupt</description>
                                    <value>#1</value>
                                </enumeratedValue>
                            </enumeratedValues>
                        </field>
                        <field>
                            <name>HDIE</name>
                            <description>HD Interrupt Enable</description>
                            <lsb>8</lsb>
                            <msb>8</msb>
                            <access>read-write</access>
                            <enumeratedValues>
                                <enumeratedValue>
                                    <name>0</name>
                                    <description>Disables an HD interrupt</description>
                                    <value>#0</value>
                                </enumeratedValue>
                                <enumeratedValue>
                                    <name>1</name>
                                    <description>Enables an HD interrupt</description>
                                    <value>#1</value>
                                </enumeratedValue>
                            </enumeratedValues>
                        </field>
                        <field>
                            <name>VDIE</name>
                            <description>VD Interrupt Enable</description>
                            <lsb>9</lsb>
                            <msb>9</msb>
                            <access>read-write</access>
                            <enumeratedValues>
                                <enumeratedValue>
                                    <name>0</name>
                                    <description>Disables a VD interrupt</description>
                                    <value>#0</value>
                                </enumeratedValue>
                                <enumeratedValue>
                                    <name>1</name>
                                    <description>Enables a VD interrupt</description>
                                    <value>#1</value>
                                </enumeratedValue>
                            </enumeratedValues>
                        </field>
                        <field>
                            <name>CPBE1IE</name>
                            <description>CPBE1 Interrupt Enable</description>
                            <lsb>12</lsb>
                            <msb>12</msb>
                            <access>read-write</access>
                            <enumeratedValues>
                                <enumeratedValue>
                                    <name>0</name>
                                    <description>Disables a CPBE1 interrupt</description>
                                    <value>#0</value>
                                </enumeratedValue>
                                <enumeratedValue>
                                    <name>1</name>
                                    <description>Enables a CPBE1 interrupt</description>
                                    <value>#1</value>
                                </enumeratedValue>
                            </enumeratedValues>
                        </field>
                        <field>
                            <name>CPBE2IE</name>
                            <description>CPBE2 Interrupt Enable</description>
                            <lsb>13</lsb>
                            <msb>13</msb>
                            <access>read-write</access>
                            <enumeratedValues>
                                <enumeratedValue>
                                    <name>0</name>
                                    <description>Disables a CPBE2 interrupt</description>
                                    <value>#0</value>
                                </enumeratedValue>
                                <enumeratedValue>
                                    <name>1</name>
                                    <description>Enables a CPBE2 interrupt</description>
                                    <value>#1</value>
                                </enumeratedValue>
                            </enumeratedValues>
                        </field>
                        <field>
                            <name>CPBE3IE</name>
                            <description>CPBE3 Interrupt Enable</description>
                            <lsb>14</lsb>
                            <msb>14</msb>
                            <access>read-write</access>
                            <enumeratedValues>
                                <enumeratedValue>
                                    <name>0</name>
                                    <description>Disables a CPBE3 interrupt</description>
                                    <value>#0</value>
                                </enumeratedValue>
                                <enumeratedValue>
                                    <name>1</name>
                                    <description>Enables a CPBE3 interrupt</description>
                                    <value>#1</value>
                                </enumeratedValue>
                            </enumeratedValues>
                        </field>
                        <field>
                            <name>CPBE4IE</name>
                            <description>CPBE4 Interrupt Enable</description>
                            <lsb>15</lsb>
                            <msb>15</msb>
                            <access>read-write</access>
                            <enumeratedValues>
                                <enumeratedValue>
                                    <name>0</name>
                                    <description>Disables a CPBE4 interrupt</description>
                                    <value>#0</value>
                                </enumeratedValue>
                                <enumeratedValue>
                                    <name>1</name>
                                    <description>Enables a CPBE4 interrupt</description>
                                    <value>#1</value>
                                </enumeratedValue>
                            </enumeratedValues>
                        </field>
                        <field>
                            <name>CDTOFIE</name>
                            <description>CDTOF Interrupt Enable</description>
                            <lsb>16</lsb>
                            <msb>16</msb>
                            <access>read-write</access>
                            <enumeratedValues>
                                <enumeratedValue>
                                    <name>0</name>
                                    <description>Disables a CDTOF interrupt</description>
                                    <value>#0</value>
                                </enumeratedValue>
                                <enumeratedValue>
                                    <name>1</name>
                                    <description>Enables a CDTOF interrupt</description>
                                    <value>#1</value>
                                </enumeratedValue>
                            </enumeratedValues>
                        </field>
                        <field>
                            <name>IGHSIE</name>
                            <description>IGHS Interrupt Enable</description>
                            <lsb>17</lsb>
                            <msb>17</msb>
                            <access>read-write</access>
                            <enumeratedValues>
                                <enumeratedValue>
                                    <name>0</name>
                                    <description>Disables an IGHS interrupt</description>
                                    <value>#0</value>
                                </enumeratedValue>
                                <enumeratedValue>
                                    <name>1</name>
                                    <description>Enables an IGHS interrupt</description>
                                    <value>#1</value>
                                </enumeratedValue>
                            </enumeratedValues>
                        </field>
                        <field>
                            <name>IGVSIE</name>
                            <description>IGVS Interrupt Enable</description>
                            <lsb>18</lsb>
                            <msb>18</msb>
                            <access>read-write</access>
                            <enumeratedValues>
                                <enumeratedValue>
                                    <name>0</name>
                                    <description>Disables an IGVS interrupt</description>
                                    <value>#0</value>
                                </enumeratedValue>
                                <enumeratedValue>
                                    <name>1</name>
                                    <description>Enables an IGVS interrupt</description>
                                    <value>#1</value>
                                </enumeratedValue>
                            </enumeratedValues>
                        </field>
                        <field>
                            <name>VBPIE</name>
                            <description>VBP Interrupt Enable</description>
                            <lsb>20</lsb>
                            <msb>20</msb>
                            <access>read-write</access>
                            <enumeratedValues>
                                <enumeratedValue>
                                    <name>0</name>
                                    <description>Disables a VBP interrupt</description>
                                    <value>#0</value>
                                </enumeratedValue>
                                <enumeratedValue>
                                    <name>1</name>
                                    <description>Enables a VBP interrupt</description>
                                    <value>#1</value>
                                </enumeratedValue>
                            </enumeratedValues>
                        </field>
                        <field>
                            <name>FWFIE</name>
                            <description>FWF Interrupt Enable</description>
                            <lsb>23</lsb>
                            <msb>23</msb>
                            <access>read-write</access>
                            <enumeratedValues>
                                <enumeratedValue>
                                    <name>0</name>
                                    <description>Disables a FWF interrupt</description>
                                    <value>#0</value>
                                </enumeratedValue>
                                <enumeratedValue>
                                    <name>1</name>
                                    <description>Enables a FWF interrupt</description>
                                    <value>#1</value>
                                </enumeratedValue>
                            </enumeratedValues>
                        </field>
                        <field>
                            <name>NHDIE</name>
                            <description>Non-HD Interrupt Enable</description>
                            <lsb>24</lsb>
                            <msb>24</msb>
                            <access>read-write</access>
                            <enumeratedValues>
                                <enumeratedValue>
                                    <name>0</name>
                                    <description>Disables a non-HD interrupt</description>
                                    <value>#0</value>
                                </enumeratedValue>
                                <enumeratedValue>
                                    <name>1</name>
                                    <description>Enables a non-HD interrupt</description>
                                    <value>#1</value>
                                </enumeratedValue>
                            </enumeratedValues>
                        </field>
                        <field>
                            <name>NVDIE</name>
                            <description>Non-VD Interrupt Enable</description>
                            <lsb>25</lsb>
                            <msb>25</msb>
                            <access>read-write</access>
                            <enumeratedValues>
                                <enumeratedValue>
                                    <name>0</name>
                                    <description>Disables a non-VD interrupt</description>
                                    <value>#0</value>
                                </enumeratedValue>
                                <enumeratedValue>
                                    <name>1</name>
                                    <description>Enables a non-VD interrupt</description>
                                    <value>#1</value>
                                </enumeratedValue>
                            </enumeratedValues>
                        </field>
                    </fields>
                </register>
                <register>
                    <name>CETCR</name>
                    <description>Capture Event Flag Clear Register</description>
                    <addressOffset>0x0074</addressOffset>
                    <size>32</size>
                    <access>read-write</access>
                    <resetValue>0x00000000</resetValue>
                    <resetMask>0xfffffcff</resetMask>
                    <fields>
                        <field>
                            <name>CPE</name>
                            <description>An interrupt indicating that capturing of one frame from an external module has finished.</description>
                            <lsb>0</lsb>
                            <msb>0</msb>
                            <access>read-write</access>
                        </field>
                        <field>
                            <name>CFE</name>
                            <description>An interrupt indicating that capturing of one field from an external module has finished.</description>
                            <lsb>1</lsb>
                            <msb>1</msb>
                            <access>read-write</access>
                        </field>
                        <field>
                            <name>IGRW</name>
                            <description>An interrupt indicating that during capturing, access was attempted to a register to which writing during operation is prohibited.</description>
                            <lsb>4</lsb>
                            <msb>4</msb>
                            <access>read-write</access>
                        </field>
                        <field>
                            <name>HD</name>
                            <description>An interrupt indicating that HD (horizontal sync signal) was input from an external module.</description>
                            <lsb>8</lsb>
                            <msb>8</msb>
                            <access>read-write</access>
                        </field>
                        <field>
                            <name>VD</name>
                            <description>An interrupt indicating that VD (vertical sync signal) was input from an external module.</description>
                            <lsb>9</lsb>
                            <msb>9</msb>
                            <access>read-write</access>
                        </field>
                        <field>
                            <name>CPBE1</name>
                            <description>An interrupt indicating that writing to CDAYR and CDACR in a bundle write has finished.</description>
                            <lsb>12</lsb>
                            <msb>12</msb>
                            <access>read-write</access>
                        </field>
                        <field>
                            <name>CPBE2</name>
                            <description>An interrupt indicating that writing to CDAYR2 and CDACR2 in a bundle write has finished.</description>
                            <lsb>13</lsb>
                            <msb>13</msb>
                            <access>read-write</access>
                        </field>
                        <field>
                            <name>CPBE3</name>
                            <description>An interrupt indicating that writing to CDBYR and CDBCR in a bundle write has finished.</description>
                            <lsb>14</lsb>
                            <msb>14</msb>
                            <access>read-write</access>
                        </field>
                        <field>
                            <name>CPBE4</name>
                            <description>An interrupt indicating that writing to CDBYR2 and CDBCR2 in a bundle write has finished.</description>
                            <lsb>15</lsb>
                            <msb>15</msb>
                            <access>read-write</access>
                        </field>
                        <field>
                            <name>CDTOF</name>
                            <description>An interrupt indicating that data overflowed in the CRAM of the write buffer</description>
                            <lsb>16</lsb>
                            <msb>16</msb>
                            <access>read-write</access>
                        </field>
                        <field>
                            <name>IGHS</name>
                            <description>An interrupt generated when the number of HD cycles set in CMCYR differ from the number of HD cycles input from an external module.</description>
                            <lsb>17</lsb>
                            <msb>17</msb>
                            <access>read-write</access>
                        </field>
                        <field>
                            <name>IGVS</name>
                            <description>An interrupt generated when the number of VD cycles set in CMCYR differ from the number of VD cycles input from an external module.</description>
                            <lsb>18</lsb>
                            <msb>18</msb>
                            <access>read-write</access>
                        </field>
                        <field>
                            <name>VBP</name>
                            <description>An interrupt indicating that VD has been input while the CEU holds data (insufficient vertical-sync front porch).</description>
                            <lsb>20</lsb>
                            <msb>20</msb>
                            <access>read-write</access>
                        </field>
                        <field>
                            <name>FWF</name>
                            <description>The interrupt is generated when data is written to the address that exceeds the value specified with CFWCR.FMV.</description>
                            <lsb>23</lsb>
                            <msb>23</msb>
                            <access>read-write</access>
                        </field>
                        <field>
                            <name>NHD</name>
                            <description>An interrupt indicating that no HD was input.</description>
                            <lsb>24</lsb>
                            <msb>24</msb>
                            <access>read-write</access>
                        </field>
                        <field>
                            <name>NVD</name>
                            <description>An interrupt indicating that no VD was input.</description>
                            <lsb>25</lsb>
                            <msb>25</msb>
                            <access>read-write</access>
                        </field>
                    </fields>
                </register>
                <register>
                    <name>CSTSR</name>
                    <description>Capture Status Register</description>
                    <addressOffset>0x007C</addressOffset>
                    <size>32</size>
                    <access>read-only</access>
                    <resetValue>0x00000000</resetValue>
                    <resetMask>0xffffffff</resetMask>
                    <fields>
                        <field>
                            <name>CPTON</name>
                            <description>Indicates that the CEU is operating.</description>
                            <lsb>0</lsb>
                            <msb>0</msb>
                            <access>read-only</access>
                        </field>
                        <field>
                            <name>CPFLD</name>
                            <description>Indicates which field is being captured.</description>
                            <lsb>16</lsb>
                            <msb>16</msb>
                            <access>read-only</access>
                            <enumeratedValues>
                                <enumeratedValue>
                                    <name>0</name>
                                    <description>Bottom field is being captured</description>
                                    <value>#0</value>
                                </enumeratedValue>
                                <enumeratedValue>
                                    <name>1</name>
                                    <description>Top field is being captured</description>
                                    <value>#1</value>
                                </enumeratedValue>
                            </enumeratedValues>
                        </field>
                        <field>
                            <name>CRST</name>
                            <description>Indicates which register plane is currently used.</description>
                            <lsb>24</lsb>
                            <msb>24</msb>
                            <access>read-only</access>
                            <enumeratedValues>
                                <enumeratedValue>
                                    <name>0</name>
                                    <description>Plane A of the register is being used</description>
                                    <value>#0</value>
                                </enumeratedValue>
                                <enumeratedValue>
                                    <name>1</name>
                                    <description>Plane B of the register is being used</description>
                                    <value>#1</value>
                                </enumeratedValue>
                            </enumeratedValues>
                        </field>
                    </fields>
                </register>
                <register>
                    <name>CDSSR</name>
                    <description>Capture Data Size Register</description>
                    <addressOffset>0x0084</addressOffset>
                    <size>32</size>
                    <access>read-only</access>
                    <resetValue>0x00000000</resetValue>
                    <resetMask>0xffffffff</resetMask>
                    <fields>
                        <field>
                            <name>CDSS</name>
                            <description>Indicate the size of data written to the memory in data enable fetch.</description>
                            <lsb>0</lsb>
                            <msb>31</msb>
                            <access>read-only</access>
                        </field>
                    </fields>
                </register>
                <register>
                    <name>CDAYR2</name>
                    <description>Capture Data Address Y Register 2</description>
                    <addressOffset>0x0090</addressOffset>
                    <size>32</size>
                    <access>read-write</access>
                    <resetValue>0x00000000</resetValue>
                    <resetMask>0xffffffff</resetMask>
                    <fields>
                        <field>
                            <name>CAYR2</name>
                            <description>Capture Data Address Y</description>
                            <lsb>0</lsb>
                            <msb>31</msb>
                            <access>read-write</access>
                        </field>
                    </fields>
                </register>
                <register>
                    <name>CDACR2</name>
                    <description>Capture Data Address C Register 2</description>
                    <addressOffset>0x0094</addressOffset>
                    <size>32</size>
                    <access>read-write</access>
                    <resetValue>0x00000000</resetValue>
                    <resetMask>0xffffffff</resetMask>
                    <fields>
                        <field>
                            <name>CACR2</name>
                            <description>Capture Data Address C</description>
                            <lsb>0</lsb>
                            <msb>31</msb>
                            <access>read-write</access>
                        </field>
                    </fields>
                </register>
                <register>
                    <name>CDBYR2</name>
                    <description>Capture Data Bottom-Field Address Y Register 2</description>
                    <addressOffset>0x0098</addressOffset>
                    <size>32</size>
                    <access>read-write</access>
                    <resetValue>0x00000000</resetValue>
                    <resetMask>0xffffffff</resetMask>
                    <fields>
                        <field>
                            <name>CBYR2</name>
                            <description>Set the address for storing the luminance component data of the captured bottom-field data (8-pixel units).</description>
                            <lsb>0</lsb>
                            <msb>31</msb>
                            <access>read-write</access>
                        </field>
                    </fields>
                </register>
                <register>
                    <name>CDBCR2</name>
                    <description>Capture Data Bottom-Field Address C Register 2</description>
                    <addressOffset>0x009C</addressOffset>
                    <size>32</size>
                    <access>read-write</access>
                    <resetValue>0x00000000</resetValue>
                    <resetMask>0xffffffff</resetMask>
                    <fields>
                        <field>
                            <name>CBCR2</name>
                            <description>Set the address for storing the chrominance component data of the captured bottom-field data (8-pixel units).</description>
                            <lsb>0</lsb>
                            <msb>31</msb>
                            <access>read-write</access>
                        </field>
                    </fields>
                </register>
                <register>
                    <name>CBWER</name>
                    <description>CEU Bufferable Write Enable Register</description>
                    <addressOffset>0x00A0</addressOffset>
                    <size>32</size>
                    <access>read-write</access>
                    <resetValue>0x00000000</resetValue>
                    <resetMask>0xffffffff</resetMask>
                    <fields>
                        <field>
                            <name>BWE</name>
                            <lsb>0</lsb>
                            <msb>0</msb>
                            <access>read-write</access>
                            <enumeratedValues>
                                <enumeratedValue>
                                    <name>0</name>
                                    <description>Disables Bufferable Write</description>
                                    <value>#0</value>
                                </enumeratedValue>
                                <enumeratedValue>
                                    <name>1</name>
                                    <description>Enables Bufferable Write</description>
                                    <value>#1</value>
                                </enumeratedValue>
                            </enumeratedValues>
                        </field>
                    </fields>
                </register>
                <register>
                    <name>CAMOR_B</name>
                    <description>Capture Interface Offset Register</description>
                    <addressOffset>0x1010</addressOffset>
                    <size>32</size>
                    <access>read-write</access>
                    <resetValue>0x00000000</resetValue>
                    <resetMask>0xffffffff</resetMask>
                    <fields>
                        <field>
                            <name>HOFST</name>
                            <description>Specify the capture start location in terms of the number of clock cycles from a horizontal sync signal (1-cycle units).</description>
                            <lsb>0</lsb>
                            <msb>12</msb>
                            <access>read-write</access>
                        </field>
                        <field>
                            <name>VOFST</name>
                            <description>Specify the capture start location in terms of the HD count from a vertical sync signal (1-HD units).</description>
                            <lsb>16</lsb>
                            <msb>27</msb>
                            <access>read-write</access>
                        </field>
                    </fields>
                </register>
                <register>
                    <name>CAPWR_B</name>
                    <description>Capture Interface Width Register</description>
                    <addressOffset>0x1014</addressOffset>
                    <size>32</size>
                    <access>read-write</access>
                    <resetValue>0x00000000</resetValue>
                    <resetMask>0xffffffff</resetMask>
                    <fields>
                        <field>
                            <name>HWDTH</name>
                            <description>Specify the horizontal capture period.</description>
                            <lsb>0</lsb>
                            <msb>12</msb>
                            <access>read-write</access>
                        </field>
                        <field>
                            <name>VWDTH</name>
                            <description>Specify the vertical capture period (4-HD units).</description>
                            <lsb>16</lsb>
                            <msb>27</msb>
                            <access>read-write</access>
                        </field>
                    </fields>
                </register>
                <register>
                    <name>CFLCR_B</name>
                    <description>Capture Filter Control Register</description>
                    <addressOffset>0x1030</addressOffset>
                    <size>32</size>
                    <access>read-write</access>
                    <resetValue>0x00000000</resetValue>
                    <resetMask>0xffffffff</resetMask>
                    <fields>
                        <field>
                            <name>HFRAC</name>
                            <description>Fraction Part of Horizontal Scale-Down Factor</description>
                            <lsb>0</lsb>
                            <msb>11</msb>
                            <access>read-write</access>
                        </field>
                        <field>
                            <name>HMANT</name>
                            <description>Mantissa Part of Horizontal Scale-Down Factor</description>
                            <lsb>12</lsb>
                            <msb>15</msb>
                            <access>read-write</access>
                        </field>
                        <field>
                            <name>VFRAC</name>
                            <description>Fraction Part of Vertical Scale-Down Factor</description>
                            <lsb>16</lsb>
                            <msb>27</msb>
                            <access>read-write</access>
                        </field>
                        <field>
                            <name>VMANT</name>
                            <description>Mantissa Part of Vertical Scale-Down Factor</description>
                            <lsb>28</lsb>
                            <msb>31</msb>
                            <access>read-write</access>
                        </field>
                    </fields>
                </register>
                <register>
                    <name>CFSZR_B</name>
                    <description>Capture Filter Size Clip Register</description>
                    <addressOffset>0x1034</addressOffset>
                    <size>32</size>
                    <access>read-write</access>
                    <resetValue>0x00000000</resetValue>
                    <resetMask>0xffffffff</resetMask>
                    <fields>
                        <field>
                            <name>HFCLP</name>
                            <description>Specify the horizontal clipping value of the filter output size (8-pixel units).</description>
                            <lsb>0</lsb>
                            <msb>11</msb>
                            <access>read-write</access>
                        </field>
                        <field>
                            <name>VFCLP</name>
                            <description>Specify the vertical clipping value of the filter output size (4-pixel units).</description>
                            <lsb>16</lsb>
                            <msb>27</msb>
                            <access>read-write</access>
                        </field>
                    </fields>
                </register>
                <register>
                    <name>CDWDR_B</name>
                    <description>Capture Destination Width Register</description>
                    <addressOffset>0x1038</addressOffset>
                    <size>32</size>
                    <access>read-write</access>
                    <resetValue>0x00000000</resetValue>
                    <resetMask>0xffffffff</resetMask>
                    <fields>
                        <field>
                            <name>CHDW</name>
                            <description>Specify the horizontal image size in the memory area where the captured image is to be stored (8-byte units).</description>
                            <lsb>0</lsb>
                            <msb>12</msb>
                            <access>read-write</access>
                        </field>
                    </fields>
                </register>
                <register>
                    <name>CDAYR_B</name>
                    <description>Capture Data Address Y Register</description>
                    <addressOffset>0x103C</addressOffset>
                    <size>32</size>
                    <access>read-write</access>
                    <resetValue>0x00000000</resetValue>
                    <resetMask>0xffffffff</resetMask>
                    <fields>
                        <field>
                            <name>CAYR</name>
                            <description>Capture Data Address Y</description>
                            <lsb>0</lsb>
                            <msb>31</msb>
                            <access>read-write</access>
                        </field>
                    </fields>
                </register>
                <register>
                    <name>CDACR_B</name>
                    <description>Capture Data Address C Register</description>
                    <addressOffset>0x1040</addressOffset>
                    <size>32</size>
                    <access>read-write</access>
                    <resetValue>0x00000000</resetValue>
                    <resetMask>0xffffffff</resetMask>
                    <fields>
                        <field>
                            <name>CACR</name>
                            <description>Capture Data Address C</description>
                            <lsb>0</lsb>
                            <msb>31</msb>
                            <access>read-write</access>
                        </field>
                    </fields>
                </register>
                <register>
                    <name>CDBYR_B</name>
                    <description>Capture Data Bottom-Field Address Y Register</description>
                    <addressOffset>0x1044</addressOffset>
                    <size>32</size>
                    <access>read-write</access>
                    <resetValue>0x00000000</resetValue>
                    <resetMask>0xffffffff</resetMask>
                    <fields>
                        <field>
                            <name>CBYR</name>
                            <description>Set the address for storing the luminance component data of the captured bottom-field data (8-pixel units).</description>
                            <lsb>0</lsb>
                            <msb>31</msb>
                            <access>read-write</access>
                        </field>
                    </fields>
                </register>
                <register>
                    <name>CDBCR_B</name>
                    <description>Capture Data Bottom-Field Address C Register</description>
                    <addressOffset>0x1048</addressOffset>
                    <size>32</size>
                    <access>read-write</access>
                    <resetValue>0x00000000</resetValue>
                    <resetMask>0xffffffff</resetMask>
                    <fields>
                        <field>
                            <name>CBCR</name>
                            <description>Set the address for storing the chrominance component data of the captured bottom-field data (8-pixel units).</description>
                            <lsb>0</lsb>
                            <msb>31</msb>
                            <access>read-write</access>
                        </field>
                    </fields>
                </register>
                <register>
                    <name>CBDSR_B</name>
                    <description>Capture Bundle Destination Size Register</description>
                    <addressOffset>0x104C</addressOffset>
                    <size>32</size>
                    <access>read-write</access>
                    <resetValue>0x00000000</resetValue>
                    <resetMask>0xffffffff</resetMask>
                    <fields>
                        <field>
                            <name>CBVS</name>
                            <description>Select the number of lines or number of bytes for output to the memory in a bundle write.</description>
                            <lsb>0</lsb>
                            <msb>22</msb>
                            <access>read-write</access>
                        </field>
                    </fields>
                </register>
                <register>
                    <name>CLFCR_B</name>
                    <description>Capture Low-Pass Filter Control Register</description>
                    <addressOffset>0x1060</addressOffset>
                    <size>32</size>
                    <access>read-write</access>
                    <resetValue>0x00000000</resetValue>
                    <resetMask>0xffffffff</resetMask>
                    <fields>
                        <field>
                            <name>LPF</name>
                            <description>Enables or disables operation of the low-pass filter.</description>
                            <lsb>0</lsb>
                            <msb>0</msb>
                            <access>read-write</access>
                            <enumeratedValues>
                                <enumeratedValue>
                                    <name>0</name>
                                    <description>Low-pass filter not used</description>
                                    <value>#0</value>
                                </enumeratedValue>
                                <enumeratedValue>
                                    <name>1</name>
                                    <description>Low-pass filter used (only in the horizontal direction)</description>
                                    <value>#1</value>
                                </enumeratedValue>
                            </enumeratedValues>
                        </field>
                    </fields>
                </register>
                <register>
                    <name>CDOCR_B</name>
                    <description>Capture Data Output Control Register</description>
                    <addressOffset>0x1064</addressOffset>
                    <size>32</size>
                    <access>read-write</access>
                    <resetValue>0x00000000</resetValue>
                    <resetMask>0xffffffff</resetMask>
                    <fields>
                        <field>
                            <name>COBS</name>
                            <description>Controls swapping in 8-bit units for data output from the CEU.</description>
                            <lsb>0</lsb>
                            <msb>0</msb>
                            <access>read-write</access>
                            <enumeratedValues>
                                <enumeratedValue>
                                    <name>0</name>
                                    <description>Data is not swapped in 8-bit units</description>
                                    <value>#0</value>
                                </enumeratedValue>
                                <enumeratedValue>
                                    <name>1</name>
                                    <description>Data is swapped in 8-bit units</description>
                                    <value>#1</value>
                                </enumeratedValue>
                            </enumeratedValues>
                        </field>
                        <field>
                            <name>COWS</name>
                            <description>Controls swapping in 16-bit units for data output from the CEU.</description>
                            <lsb>1</lsb>
                            <msb>1</msb>
                            <access>read-write</access>
                            <enumeratedValues>
                                <enumeratedValue>
                                    <name>0</name>
                                    <description>Data is not swapped in 16-bit units</description>
                                    <value>#0</value>
                                </enumeratedValue>
                                <enumeratedValue>
                                    <name>1</name>
                                    <description>Data is swapped in 16-bit units</description>
                                    <value>#1</value>
                                </enumeratedValue>
                            </enumeratedValues>
                        </field>
                        <field>
                            <name>COLS</name>
                            <description>Controls swapping in 32-bit units for data output from the CEU.</description>
                            <lsb>2</lsb>
                            <msb>2</msb>
                            <access>read-write</access>
                            <enumeratedValues>
                                <enumeratedValue>
                                    <name>0</name>
                                    <description>Data is not swapped in 32-bit units</description>
                                    <value>#0</value>
                                </enumeratedValue>
                                <enumeratedValue>
                                    <name>1</name>
                                    <description>Data is swapped in 32-bit units</description>
                                    <value>#1</value>
                                </enumeratedValue>
                            </enumeratedValues>
                        </field>
                        <field>
                            <name>CDS</name>
                            <description>Sets the image format when outputting the image data captured in the YCbCr422 format to the memory.</description>
                            <lsb>4</lsb>
                            <msb>4</msb>
                            <access>read-write</access>
                            <enumeratedValues>
                                <enumeratedValue>
                                    <name>0</name>
                                    <description>Converts the YCbCr422 format to the YCbCr420 format before outputting data to the memory</description>
                                    <value>#0</value>
                                </enumeratedValue>
                                <enumeratedValue>
                                    <name>1</name>
                                    <description>Outputs data in the YCbCr422 format to the memory without conversion</description>
                                    <value>#1</value>
                                </enumeratedValue>
                            </enumeratedValues>
                        </field>
                        <field>
                            <name>CBE</name>
                            <description> Controls the number of lines of captured data to be written to the memory.</description>
                            <lsb>16</lsb>
                            <msb>16</msb>
                            <access>read-write</access>
                            <enumeratedValues>
                                <enumeratedValue>
                                    <name>0</name>
                                    <description>Normal write</description>
                                    <value>#0</value>
                                </enumeratedValue>
                                <enumeratedValue>
                                    <name>1</name>
                                    <description>Bundle write</description>
                                    <value>#1</value>
                                </enumeratedValue>
                            </enumeratedValues>
                        </field>
                    </fields>
                </register>
                <register>
                    <name>CDAYR2_B</name>
                    <description>Capture Data Address Y Register 2</description>
                    <addressOffset>0x1090</addressOffset>
                    <size>32</size>
                    <access>read-write</access>
                    <resetValue>0x00000000</resetValue>
                    <resetMask>0xffffffff</resetMask>
                    <fields>
                        <field>
                            <name>CAYR2</name>
                            <description>Capture Data Address Y</description>
                            <lsb>0</lsb>
                            <msb>31</msb>
                            <access>read-write</access>
                        </field>
                    </fields>
                </register>
                <register>
                    <name>CDACR2_B</name>
                    <description>Capture Data Address C Register 2</description>
                    <addressOffset>0x1094</addressOffset>
                    <size>32</size>
                    <access>read-write</access>
                    <resetValue>0x00000000</resetValue>
                    <resetMask>0xffffffff</resetMask>
                    <fields>
                        <field>
                            <name>CACR2</name>
                            <description>Capture Data Address C</description>
                            <lsb>0</lsb>
                            <msb>31</msb>
                            <access>read-write</access>
                        </field>
                    </fields>
                </register>
                <register>
                    <name>CDBYR2_B</name>
                    <description>Capture Data Bottom-Field Address Y Register 2</description>
                    <addressOffset>0x1098</addressOffset>
                    <size>32</size>
                    <access>read-write</access>
                    <resetValue>0x00000000</resetValue>
                    <resetMask>0xffffffff</resetMask>
                    <fields>
                        <field>
                            <name>CBYR2</name>
                            <description>Set the address for storing the luminance component data of the captured bottom-field data (8-pixel units).</description>
                            <lsb>0</lsb>
                            <msb>31</msb>
                            <access>read-write</access>
                        </field>
                    </fields>
                </register>
                <register>
                    <name>CDBCR2_B</name>
                    <description>Capture Data Bottom-Field Address C Register 2</description>
                    <addressOffset>0x109C</addressOffset>
                    <size>32</size>
                    <access>read-write</access>
                    <resetValue>0x00000000</resetValue>
                    <resetMask>0xffffffff</resetMask>
                    <fields>
                        <field>
                            <name>CBCR2</name>
                            <description>Set the address for storing the chrominance component data of the captured bottom-field data (8-pixel units).</description>
                            <lsb>0</lsb>
                            <msb>31</msb>
                            <access>read-write</access>
                        </field>
                    </fields>
                </register>
                <register>
                    <name>CAMOR_M</name>
                    <description>Capture Interface Offset Register</description>
                    <addressOffset>0x2010</addressOffset>
                    <size>32</size>
                    <access>read-write</access>
                    <resetValue>0x00000000</resetValue>
                    <resetMask>0xffffffff</resetMask>
                    <fields>
                        <field>
                            <name>HOFST</name>
                            <description>Specify the capture start location in terms of the number of clock cycles from a horizontal sync signal (1-cycle units).</description>
                            <lsb>0</lsb>
                            <msb>12</msb>
                            <access>read-write</access>
                        </field>
                        <field>
                            <name>VOFST</name>
                            <description>Specify the capture start location in terms of the HD count from a vertical sync signal (1-HD units).</description>
                            <lsb>16</lsb>
                            <msb>27</msb>
                            <access>read-write</access>
                        </field>
                    </fields>
                </register>
                <register>
                    <name>CAPWR_M</name>
                    <description>Capture Interface Width Register</description>
                    <addressOffset>0x2014</addressOffset>
                    <size>32</size>
                    <access>read-write</access>
                    <resetValue>0x00000000</resetValue>
                    <resetMask>0xffffffff</resetMask>
                    <fields>
                        <field>
                            <name>HWDTH</name>
                            <description>Specify the horizontal capture period.</description>
                            <lsb>0</lsb>
                            <msb>12</msb>
                            <access>read-write</access>
                        </field>
                        <field>
                            <name>VWDTH</name>
                            <description>Specify the vertical capture period (4-HD units).</description>
                            <lsb>16</lsb>
                            <msb>27</msb>
                            <access>read-write</access>
                        </field>
                    </fields>
                </register>
                <register>
                    <name>CFLCR_M</name>
                    <description>Capture Filter Control Register</description>
                    <addressOffset>0x2030</addressOffset>
                    <size>32</size>
                    <access>read-write</access>
                    <resetValue>0x00000000</resetValue>
                    <resetMask>0xffffffff</resetMask>
                    <fields>
                        <field>
                            <name>HFRAC</name>
                            <description>Fraction Part of Horizontal Scale-Down Factor</description>
                            <lsb>0</lsb>
                            <msb>11</msb>
                            <access>read-write</access>
                        </field>
                        <field>
                            <name>HMANT</name>
                            <description>Mantissa Part of Horizontal Scale-Down Factor</description>
                            <lsb>12</lsb>
                            <msb>15</msb>
                            <access>read-write</access>
                        </field>
                        <field>
                            <name>VFRAC</name>
                            <description>Fraction Part of Vertical Scale-Down Factor</description>
                            <lsb>16</lsb>
                            <msb>27</msb>
                            <access>read-write</access>
                        </field>
                        <field>
                            <name>VMANT</name>
                            <description>Mantissa Part of Vertical Scale-Down Factor</description>
                            <lsb>28</lsb>
                            <msb>31</msb>
                            <access>read-write</access>
                        </field>
                    </fields>
                </register>
                <register>
                    <name>CFSZR_M</name>
                    <description>Capture Filter Size Clip Register</description>
                    <addressOffset>0x2034</addressOffset>
                    <size>32</size>
                    <access>read-write</access>
                    <resetValue>0x00000000</resetValue>
                    <resetMask>0xffffffff</resetMask>
                    <fields>
                        <field>
                            <name>HFCLP</name>
                            <description>Specify the horizontal clipping value of the filter output size (8-pixel units).</description>
                            <lsb>0</lsb>
                            <msb>11</msb>
                            <access>read-write</access>
                        </field>
                        <field>
                            <name>VFCLP</name>
                            <description>Specify the vertical clipping value of the filter output size (4-pixel units).</description>
                            <lsb>16</lsb>
                            <msb>27</msb>
                            <access>read-write</access>
                        </field>
                    </fields>
                </register>
                <register>
                    <name>CDWDR_M</name>
                    <description>Capture Destination Width Register</description>
                    <addressOffset>0x2038</addressOffset>
                    <size>32</size>
                    <access>read-write</access>
                    <resetValue>0x00000000</resetValue>
                    <resetMask>0xffffffff</resetMask>
                    <fields>
                        <field>
                            <name>CHDW</name>
                            <description>Specify the horizontal image size in the memory area where the captured image is to be stored (8-byte units).</description>
                            <lsb>0</lsb>
                            <msb>12</msb>
                            <access>read-write</access>
                        </field>
                    </fields>
                </register>
                <register>
                    <name>CDAYR_M</name>
                    <description>Capture Data Address Y Register</description>
                    <addressOffset>0x203C</addressOffset>
                    <size>32</size>
                    <access>read-write</access>
                    <resetValue>0x00000000</resetValue>
                    <resetMask>0xffffffff</resetMask>
                    <fields>
                        <field>
                            <name>CAYR</name>
                            <description>Capture Data Address Y</description>
                            <lsb>0</lsb>
                            <msb>31</msb>
                            <access>read-write</access>
                        </field>
                    </fields>
                </register>
                <register>
                    <name>CDACR_M</name>
                    <description>Capture Data Address C Register</description>
                    <addressOffset>0x2040</addressOffset>
                    <size>32</size>
                    <access>read-write</access>
                    <resetValue>0x00000000</resetValue>
                    <resetMask>0xffffffff</resetMask>
                    <fields>
                        <field>
                            <name>CACR</name>
                            <description>Capture Data Address C</description>
                            <lsb>0</lsb>
                            <msb>31</msb>
                            <access>read-write</access>
                        </field>
                    </fields>
                </register>
                <register>
                    <name>CDBYR_M</name>
                    <description>Capture Data Bottom-Field Address Y Register</description>
                    <addressOffset>0x2044</addressOffset>
                    <size>32</size>
                    <access>read-write</access>
                    <resetValue>0x00000000</resetValue>
                    <resetMask>0xffffffff</resetMask>
                    <fields>
                        <field>
                            <name>CBYR</name>
                            <description>Set the address for storing the luminance component data of the captured bottom-field data (8-pixel units).</description>
                            <lsb>0</lsb>
                            <msb>31</msb>
                            <access>read-write</access>
                        </field>
                    </fields>
                </register>
                <register>
                    <name>CDBCR_M</name>
                    <description>Capture Data Bottom-Field Address C Register</description>
                    <addressOffset>0x2048</addressOffset>
                    <size>32</size>
                    <access>read-write</access>
                    <resetValue>0x00000000</resetValue>
                    <resetMask>0xffffffff</resetMask>
                    <fields>
                        <field>
                            <name>CBCR</name>
                            <description>Set the address for storing the chrominance component data of the captured bottom-field data (8-pixel units).</description>
                            <lsb>0</lsb>
                            <msb>31</msb>
                            <access>read-write</access>
                        </field>
                    </fields>
                </register>
                <register>
                    <name>CBDSR_M</name>
                    <description>Capture Bundle Destination Size Register</description>
                    <addressOffset>0x204C</addressOffset>
                    <size>32</size>
                    <access>read-write</access>
                    <resetValue>0x00000000</resetValue>
                    <resetMask>0xffffffff</resetMask>
                    <fields>
                        <field>
                            <name>CBVS</name>
                            <description>Select the number of lines or number of bytes for output to the memory in a bundle write.</description>
                            <lsb>0</lsb>
                            <msb>22</msb>
                            <access>read-write</access>
                        </field>
                    </fields>
                </register>
                <register>
                    <name>CLFCR_M</name>
                    <description>Capture Low-Pass Filter Control Register</description>
                    <addressOffset>0x2060</addressOffset>
                    <size>32</size>
                    <access>read-write</access>
                    <resetValue>0x00000000</resetValue>
                    <resetMask>0xffffffff</resetMask>
                    <fields>
                        <field>
                            <name>LPF</name>
                            <description>Enables or disables operation of the low-pass filter.</description>
                            <lsb>0</lsb>
                            <msb>0</msb>
                            <access>read-write</access>
                            <enumeratedValues>
                                <enumeratedValue>
                                    <name>0</name>
                                    <description>Low-pass filter not used</description>
                                    <value>#0</value>
                                </enumeratedValue>
                                <enumeratedValue>
                                    <name>1</name>
                                    <description>Low-pass filter used (only in the horizontal direction)</description>
                                    <value>#1</value>
                                </enumeratedValue>
                            </enumeratedValues>
                        </field>
                    </fields>
                </register>
                <register>
                    <name>CDOCR_M</name>
                    <description>Capture Data Output Control Register</description>
                    <addressOffset>0x2064</addressOffset>
                    <size>32</size>
                    <access>read-write</access>
                    <resetValue>0x00000000</resetValue>
                    <resetMask>0xffffffff</resetMask>
                    <fields>
                        <field>
                            <name>COBS</name>
                            <description>Controls swapping in 8-bit units for data output from the CEU.</description>
                            <lsb>0</lsb>
                            <msb>0</msb>
                            <access>read-write</access>
                            <enumeratedValues>
                                <enumeratedValue>
                                    <name>0</name>
                                    <description>Data is not swapped in 8-bit units</description>
                                    <value>#0</value>
                                </enumeratedValue>
                                <enumeratedValue>
                                    <name>1</name>
                                    <description>Data is swapped in 8-bit units</description>
                                    <value>#1</value>
                                </enumeratedValue>
                            </enumeratedValues>
                        </field>
                        <field>
                            <name>COWS</name>
                            <description>Controls swapping in 16-bit units for data output from the CEU.</description>
                            <lsb>1</lsb>
                            <msb>1</msb>
                            <access>read-write</access>
                            <enumeratedValues>
                                <enumeratedValue>
                                    <name>0</name>
                                    <description>Data is not swapped in 16-bit units</description>
                                    <value>#0</value>
                                </enumeratedValue>
                                <enumeratedValue>
                                    <name>1</name>
                                    <description>Data is swapped in 16-bit units</description>
                                    <value>#1</value>
                                </enumeratedValue>
                            </enumeratedValues>
                        </field>
                        <field>
                            <name>COLS</name>
                            <description>Controls swapping in 32-bit units for data output from the CEU.</description>
                            <lsb>2</lsb>
                            <msb>2</msb>
                            <access>read-write</access>
                            <enumeratedValues>
                                <enumeratedValue>
                                    <name>0</name>
                                    <description>Data is not swapped in 32-bit units</description>
                                    <value>#0</value>
                                </enumeratedValue>
                                <enumeratedValue>
                                    <name>1</name>
                                    <description>Data is swapped in 32-bit units</description>
                                    <value>#1</value>
                                </enumeratedValue>
                            </enumeratedValues>
                        </field>
                        <field>
                            <name>CDS</name>
                            <description>Sets the image format when outputting the image data captured in the YCbCr422 format to the memory.</description>
                            <lsb>4</lsb>
                            <msb>4</msb>
                            <access>read-write</access>
                            <enumeratedValues>
                                <enumeratedValue>
                                    <name>0</name>
                                    <description>Converts the YCbCr422 format to the YCbCr420 format before outputting data to the memory</description>
                                    <value>#0</value>
                                </enumeratedValue>
                                <enumeratedValue>
                                    <name>1</name>
                                    <description>Outputs data in the YCbCr422 format to the memory without conversion</description>
                                    <value>#1</value>
                                </enumeratedValue>
                            </enumeratedValues>
                        </field>
                        <field>
                            <name>CBE</name>
                            <description> Controls the number of lines of captured data to be written to the memory.</description>
                            <lsb>16</lsb>
                            <msb>16</msb>
                            <access>read-write</access>
                            <enumeratedValues>
                                <enumeratedValue>
                                    <name>0</name>
                                    <description>Normal write</description>
                                    <value>#0</value>
                                </enumeratedValue>
                                <enumeratedValue>
                                    <name>1</name>
                                    <description>Bundle write</description>
                                    <value>#1</value>
                                </enumeratedValue>
                            </enumeratedValues>
                        </field>
                    </fields>
                </register>
                <register>
                    <name>CDAYR2_M</name>
                    <description>Capture Data Address Y Register 2</description>
                    <addressOffset>0x2090</addressOffset>
                    <size>32</size>
                    <access>read-write</access>
                    <resetValue>0x00000000</resetValue>
                    <resetMask>0xffffffff</resetMask>
                    <fields>
                        <field>
                            <name>CAYR2</name>
                            <description>Capture Data Address Y</description>
                            <lsb>0</lsb>
                            <msb>31</msb>
                            <access>read-write</access>
                        </field>
                    </fields>
                </register>
                <register>
                    <name>CDACR2_M</name>
                    <description>Capture Data Address C Register 2</description>
                    <addressOffset>0x2094</addressOffset>
                    <size>32</size>
                    <access>read-write</access>
                    <resetValue>0x00000000</resetValue>
                    <resetMask>0xffffffff</resetMask>
                    <fields>
                        <field>
                            <name>CACR2</name>
                            <description>Capture Data Address C</description>
                            <lsb>0</lsb>
                            <msb>31</msb>
                            <access>read-write</access>
                        </field>
                    </fields>
                </register>
                <register>
                    <name>CDBYR2_M</name>
                    <description>Capture Data Bottom-Field Address Y Register 2</description>
                    <addressOffset>0x2098</addressOffset>
                    <size>32</size>
                    <access>read-write</access>
                    <resetValue>0x00000000</resetValue>
                    <resetMask>0xffffffff</resetMask>
                    <fields>
                        <field>
                            <name>CBYR2</name>
                            <description>Set the address for storing the luminance component data of the captured bottom-field data (8-pixel units).</description>
                            <lsb>0</lsb>
                            <msb>31</msb>
                            <access>read-write</access>
                        </field>
                    </fields>
                </register>
                <register>
                    <name>CDBCR2_M</name>
                    <description>Capture Data Bottom-Field Address C Register 2</description>
                    <addressOffset>0x209C</addressOffset>
                    <size>32</size>
                    <access>read-write</access>
                    <resetValue>0x00000000</resetValue>
                    <resetMask>0xffffffff</resetMask>
                    <fields>
                        <field>
                            <name>CBCR2</name>
                            <description>Set the address for storing the chrominance component data of the captured bottom-field data (8-pixel units).</description>
                            <lsb>0</lsb>
                            <msb>31</msb>
                            <access>read-write</access>
                        </field>
                    </fields>
                </register>
            </registers>
        </peripheral>
        <peripheral>
            <name>USBHS</name>
            <description>USB 2.0 High-Speed Module</description>
            <baseAddress>0x40351000</baseAddress>
            <addressBlock>
                <offset>0x00</offset>
                <size>10</size>
                <usage>registers</usage>
            </addressBlock>
            <addressBlock>
                <offset>0x0C</offset>
                <size>2</size>
                <usage>registers</usage>
            </addressBlock>
            <addressBlock>
                <offset>0x14</offset>
                <size>12</size>
                <usage>registers</usage>
            </addressBlock>
            <addressBlock>
                <offset>0x20</offset>
                <size>4</size>
                <usage>registers</usage>
            </addressBlock>
            <addressBlock>
                <offset>0x28</offset>
                <size>12</size>
                <usage>registers</usage>
            </addressBlock>
            <addressBlock>
                <offset>0x36</offset>
                <size>14</size>
                <usage>registers</usage>
            </addressBlock>
            <addressBlock>
                <offset>0x46</offset>
                <size>12</size>
                <usage>registers</usage>
            </addressBlock>
            <addressBlock>
                <offset>0x54</offset>
                <size>14</size>
                <usage>registers</usage>
            </addressBlock>
            <addressBlock>
                <offset>0x64</offset>
                <size>2</size>
                <usage>registers</usage>
            </addressBlock>
            <addressBlock>
                <offset>0x68</offset>
                <size>26</size>
                <usage>registers</usage>
            </addressBlock>
            <addressBlock>
                <offset>0x90</offset>
                <size>22</size>
                <usage>registers</usage>
            </addressBlock>
            <addressBlock>
                <offset>0xD0</offset>
                <size>22</size>
                <usage>registers</usage>
            </addressBlock>
            <addressBlock>
                <offset>0x100</offset>
                <size>4</size>
                <usage>registers</usage>
            </addressBlock>
            <addressBlock>
                <offset>0x140</offset>
                <size>2</size>
                <usage>registers</usage>
            </addressBlock>
            <addressBlock>
                <offset>0x144</offset>
                <size>8</size>
                <usage>registers</usage>
            </addressBlock>
            <addressBlock>
                <offset>0x160</offset>
                <size>12</size>
                <usage>registers</usage>
            </addressBlock>
            <registers>
                <register>
                    <name>SYSCFG</name>
                    <description>System Configuration Control Register</description>
                    <addressOffset>0x000</addressOffset>
                    <size>16</size>
                    <access>read-write</access>
                    <resetValue>0x0020</resetValue>
                    <resetMask>0x01f1</resetMask>
                    <fields>
                        <field>
                            <name>USBE</name>
                            <description>USBHS Operation Enable</description>
                            <lsb>0</lsb>
                            <msb>0</msb>
                            <access>read-write</access>
                            <enumeratedValues>
                                <enumeratedValue>
                                    <name>0</name>
                                    <description>Disable</description>
                                    <value>#0</value>
                                </enumeratedValue>
                                <enumeratedValue>
                                    <name>1</name>
                                    <description>Enable</description>
                                    <value>#1</value>
                                </enumeratedValue>
                            </enumeratedValues>
                        </field>
                        <field>
                            <name>DPRPU</name>
                            <description>D+ Line Resistor Control</description>
                            <lsb>4</lsb>
                            <msb>4</msb>
                            <access>read-write</access>
                            <enumeratedValues>
                                <enumeratedValue>
                                    <name>0</name>
                                    <description>Disable line pull-up</description>
                                    <value>#0</value>
                                </enumeratedValue>
                                <enumeratedValue>
                                    <name>1</name>
                                    <description>Enable line pull-up</description>
                                    <value>#1</value>
                                </enumeratedValue>
                            </enumeratedValues>
                        </field>
                        <field>
                            <name>DRPD</name>
                            <description>D+/D- Line Resistor Control</description>
                            <lsb>5</lsb>
                            <msb>5</msb>
                            <access>read-write</access>
                            <enumeratedValues>
                                <enumeratedValue>
                                    <name>0</name>
                                    <description>Disable line pull-down</description>
                                    <value>#0</value>
                                </enumeratedValue>
                                <enumeratedValue>
                                    <name>1</name>
                                    <description>Enable line pull-down</description>
                                    <value>#1</value>
                                </enumeratedValue>
                            </enumeratedValues>
                        </field>
                        <field>
                            <name>DCFM</name>
                            <description>Controller Operation Select</description>
                            <lsb>6</lsb>
                            <msb>6</msb>
                            <access>read-write</access>
                            <enumeratedValues>
                                <enumeratedValue>
                                    <name>0</name>
                                    <description>Select device controller mode</description>
                                    <value>#0</value>
                                </enumeratedValue>
                                <enumeratedValue>
                                    <name>1</name>
                                    <description>Select host controller mode</description>
                                    <value>#1</value>
                                </enumeratedValue>
                            </enumeratedValues>
                        </field>
                        <field>
                            <name>HSE</name>
                            <description>High-Speed Operation Enable</description>
                            <lsb>7</lsb>
                            <msb>7</msb>
                            <access>read-write</access>
                            <enumeratedValues>
                                <enumeratedValue>
                                    <name>0</name>
                                    <description>Disable Device controller mode: full-speed Host controller mode: full-speed or low-speed </description>
                                    <value>#0</value>
                                </enumeratedValue>
                                <enumeratedValue>
                                    <name>1</name>
                                    <description>Enable The controller detects the communication speed </description>
                                    <value>#1</value>
                                </enumeratedValue>
                            </enumeratedValues>
                        </field>
                        <field>
                            <name>CNEN</name>
                            <description>Single-ended Receiver Enable</description>
                            <lsb>8</lsb>
                            <msb>8</msb>
                            <access>read-write</access>
                            <enumeratedValues>
                                <enumeratedValue>
                                    <name>0</name>
                                    <description>Disable</description>
                                    <value>#0</value>
                                </enumeratedValue>
                                <enumeratedValue>
                                    <name>1</name>
                                    <description>Enable</description>
                                    <value>#1</value>
                                </enumeratedValue>
                            </enumeratedValues>
                        </field>
                    </fields>
                </register>
                <register>
                    <name>BUSWAIT</name>
                    <description>CPU Bus Wait Register</description>
                    <addressOffset>0x002</addressOffset>
                    <size>16</size>
                    <access>read-write</access>
                    <resetValue>0x000f</resetValue>
                    <resetMask>0x3f3f</resetMask>
                    <fields>
                        <field>
                            <name>BWAIT</name>
                            <description>CPU Bus Access Wait Specification</description>
                            <lsb>0</lsb>
                            <msb>3</msb>
                            <access>read-write</access>
                        </field>
                    </fields>
                </register>
                <register>
                    <name>SYSSTS0</name>
                    <description>System Configuration Status Register</description>
                    <addressOffset>0x004</addressOffset>
                    <size>16</size>
                    <access>read-only</access>
                    <resetValue>0x0000</resetValue>
                    <resetMask>0x0060</resetMask>
                    <fields>
                        <field>
                            <name>LNST</name>
                            <description>USB Data Line Status Monitor Flag</description>
                            <lsb>0</lsb>
                            <msb>1</msb>
                            <access>read-only</access>
                        </field>
                        <field>
                            <name>IDMON</name>
                            <description>USBHS_ID Pin Monitor Flag</description>
                            <lsb>2</lsb>
                            <msb>2</msb>
                            <access>read-only</access>
                            <enumeratedValues>
                                <enumeratedValue>
                                    <name>0</name>
                                    <description>USBHS_ID pin is low</description>
                                    <value>#0</value>
                                </enumeratedValue>
                                <enumeratedValue>
                                    <name>1</name>
                                    <description>USBHS_ID pin is high</description>
                                    <value>#1</value>
                                </enumeratedValue>
                            </enumeratedValues>
                        </field>
                        <field>
                            <name>SOFEA</name>
                            <description>SOF Active Monitor Flag While Host Controller Operation Is Selected</description>
                            <lsb>5</lsb>
                            <msb>5</msb>
                            <access>read-only</access>
                            <enumeratedValues>
                                <enumeratedValue>
                                    <name>0</name>
                                    <description>SOF output stopped</description>
                                    <value>#0</value>
                                </enumeratedValue>
                                <enumeratedValue>
                                    <name>1</name>
                                    <description>SOF output operating</description>
                                    <value>#1</value>
                                </enumeratedValue>
                            </enumeratedValues>
                        </field>
                        <field>
                            <name>HTACT</name>
                            <description>Host Sequencer Status Monitor Flag</description>
                            <lsb>6</lsb>
                            <msb>6</msb>
                            <access>read-only</access>
                            <enumeratedValues>
                                <enumeratedValue>
                                    <name>0</name>
                                    <description>Host sequencer stopped</description>
                                    <value>#0</value>
                                </enumeratedValue>
                                <enumeratedValue>
                                    <name>1</name>
                                    <description>Host sequencer operating</description>
                                    <value>#1</value>
                                </enumeratedValue>
                            </enumeratedValues>
                        </field>
                        <field>
                            <name>OVCMON</name>
                            <description>External USBHS_OVRCURA or USBHS_OVRCURA-DS, and USBHS_OVRCURB or USBHS_OVRCURBB-DS Input Pin Monitor Flag</description>
                            <lsb>14</lsb>
                            <msb>15</msb>
                            <access>read-only</access>
                        </field>
                    </fields>
                </register>
                <register>
                    <name>PLLSTA</name>
                    <description>PLL Status Register</description>
                    <addressOffset>0x006</addressOffset>
                    <size>16</size>
                    <access>read-only</access>
                    <resetValue>0x0000</resetValue>
                    <resetMask>0x0001</resetMask>
                    <fields>
                        <field>
                            <name>PLLLOCK</name>
                            <description>PLL Lock Flag</description>
                            <lsb>0</lsb>
                            <msb>0</msb>
                            <access>read-only</access>
                            <enumeratedValues>
                                <enumeratedValue>
                                    <name>0</name>
                                    <description>PLL not locked</description>
                                    <value>#0</value>
                                </enumeratedValue>
                                <enumeratedValue>
                                    <name>1</name>
                                    <description>PLL locked</description>
                                    <value>#1</value>
                                </enumeratedValue>
                            </enumeratedValues>
                        </field>
                    </fields>
                </register>
                <register>
                    <name>DVSTCTR0</name>
                    <description>Device State Control Register 0</description>
                    <addressOffset>0x008</addressOffset>
                    <size>16</size>
                    <access>read-write</access>
                    <resetValue>0x0000</resetValue>
                    <resetMask>0x0ff7</resetMask>
                    <fields>
                        <field>
                            <name>RHST</name>
                            <description>USB Bus Reset Status Flag</description>
                            <lsb>0</lsb>
                            <msb>2</msb>
                            <access>read-only</access>
                            <enumeratedValues>
                                <enumeratedValue>
                                    <name>000</name>
                                    <description>Communication speed indeterminate (powered state or no connection)</description>
                                    <value>#000</value>
                                </enumeratedValue>
                                <enumeratedValue>
                                    <name>001</name>
                                    <description>Host controller mode Low-speed connection Device controller mode USB bus reset in progress or low-speed connection </description>
                                    <value>#001</value>
                                </enumeratedValue>
                                <enumeratedValue>
                                    <name>010</name>
                                    <description>Host controller mode Full-speed connection Device controller mode USB bus reset in progress or full-speed connection </description>
                                    <value>#010</value>
                                </enumeratedValue>
                                <enumeratedValue>
                                    <name>011</name>
                                    <description>Host controller mode High-speed connection Device controller mode USB bus reset in progress or high-speed connection </description>
                                    <value>#011</value>
                                </enumeratedValue>
                                <enumeratedValue>
                                    <name>Others</name>
                                    <description>Host controller mode USB bus reset in progress Device controller mode Setting prohibited </description>
                                    <isDefault>true</isDefault>
                                </enumeratedValue>
                            </enumeratedValues>
                        </field>
                        <field>
                            <name>UACT</name>
                            <description>USB Bus Operation Enable for the Host Controller Operation</description>
                            <lsb>4</lsb>
                            <msb>4</msb>
                            <access>read-write</access>
                            <enumeratedValues>
                                <enumeratedValue>
                                    <name>0</name>
                                    <description>Disable downstream port (disable SOF or micro-SOF transmission)</description>
                                    <value>#0</value>
                                </enumeratedValue>
                                <enumeratedValue>
                                    <name>1</name>
                                    <description>Enable downstream port (enable SOF or micro-SOF transmission)</description>
                                    <value>#1</value>
                                </enumeratedValue>
                            </enumeratedValues>
                        </field>
                        <field>
                            <name>RESUME</name>
                            <description>Resume Signal Output for the Host Controller Operation</description>
                            <lsb>5</lsb>
                            <msb>5</msb>
                            <access>read-write</access>
                            <enumeratedValues>
                                <enumeratedValue>
                                    <name>0</name>
                                    <description>Do not output resume signal</description>
                                    <value>#0</value>
                                </enumeratedValue>
                                <enumeratedValue>
                                    <name>1</name>
                                    <description>Output resume signal</description>
                                    <value>#1</value>
                                </enumeratedValue>
                            </enumeratedValues>
                        </field>
                        <field>
                            <name>USBRST</name>
                            <description>USB Bus Reset Output for the Host Controller Operation</description>
                            <lsb>6</lsb>
                            <msb>6</msb>
                            <access>read-write</access>
                            <enumeratedValues>
                                <enumeratedValue>
                                    <name>0</name>
                                    <description>Do not output USB bus reset signal</description>
                                    <value>#0</value>
                                </enumeratedValue>
                                <enumeratedValue>
                                    <name>1</name>
                                    <description>Output USB bus reset signal</description>
                                    <value>#1</value>
                                </enumeratedValue>
                            </enumeratedValues>
                        </field>
                        <field>
                            <name>RWUPE</name>
                            <description>Remote Wakeup Detection Enable for the Host Controller Operation</description>
                            <lsb>7</lsb>
                            <msb>7</msb>
                            <access>read-write</access>
                            <enumeratedValues>
                                <enumeratedValue>
                                    <name>0</name>
                                    <description>Disable downstream port remote wakeup</description>
                                    <value>#0</value>
                                </enumeratedValue>
                                <enumeratedValue>
                                    <name>1</name>
                                    <description>Enable downstream port remote wakeup</description>
                                    <value>#1</value>
                                </enumeratedValue>
                            </enumeratedValues>
                        </field>
                        <field>
                            <name>WKUP</name>
                            <description>Remote Wakeup Output for the Device Controller Operation</description>
                            <lsb>8</lsb>
                            <msb>8</msb>
                            <access>read-write</access>
                            <enumeratedValues>
                                <enumeratedValue>
                                    <name>0</name>
                                    <description>Do not output remote wakeup signal</description>
                                    <value>#0</value>
                                </enumeratedValue>
                                <enumeratedValue>
                                    <name>1</name>
                                    <description>Output remote wakeup signal</description>
                                    <value>#1</value>
                                </enumeratedValue>
                            </enumeratedValues>
                        </field>
                        <field>
                            <name>VBUSEN</name>
                            <description>USBHS_VBUSEN Output Pin Control</description>
                            <lsb>9</lsb>
                            <msb>9</msb>
                            <access>read-write</access>
                            <enumeratedValues>
                                <enumeratedValue>
                                    <name>0</name>
                                    <description>Output low on external USBHS_VBUSEN pin</description>
                                    <value>#0</value>
                                </enumeratedValue>
                                <enumeratedValue>
                                    <name>1</name>
                                    <description>Output high on external USBHS_VBUSEN pin</description>
                                    <value>#1</value>
                                </enumeratedValue>
                            </enumeratedValues>
                        </field>
                        <field>
                            <name>EXICEN</name>
                            <description>USBHS_EXICEN Output Pin Control</description>
                            <lsb>10</lsb>
                            <msb>10</msb>
                            <access>read-write</access>
                            <enumeratedValues>
                                <enumeratedValue>
                                    <name>0</name>
                                    <description>Output low on external USBHS_EXICEN pin</description>
                                    <value>#0</value>
                                </enumeratedValue>
                                <enumeratedValue>
                                    <name>1</name>
                                    <description>Output high on external USBHS_EXICEN pin</description>
                                    <value>#1</value>
                                </enumeratedValue>
                            </enumeratedValues>
                        </field>
                        <field>
                            <name>HNPBTOA</name>
                            <description>Host Negotiation Protocol (HNP) Control</description>
                            <lsb>11</lsb>
                            <msb>11</msb>
                            <access>read-write</access>
                        </field>
                    </fields>
                </register>
                <register>
                    <name>TESTMODE</name>
                    <description>USB Test Mode Register</description>
                    <addressOffset>0x00C</addressOffset>
                    <size>16</size>
                    <access>read-write</access>
                    <resetValue>0x0000</resetValue>
                    <resetMask>0x000f</resetMask>
                    <fields>
                        <field>
                            <name>UTST</name>
                            <description>Test Mode</description>
                            <lsb>0</lsb>
                            <msb>3</msb>
                            <access>read-write</access>
                        </field>
                    </fields>
                </register>
                <register>
                    <name>CFIFO</name>
                    <description>FIFO Port Register</description>
                    <addressOffset>0x014</addressOffset>
                    <size>32</size>
                    <access>read-write</access>
                    <resetValue>0x00000000</resetValue>
                    <resetMask>0xffffffff</resetMask>
                    <fields>
                        <field>
                            <name>FIFOPORT</name>
                            <description>Read receive data from the FIFO buffer or write transmit data to the FIFO buffer by accessing these bits.</description>
                            <lsb>0</lsb>
                            <msb>31</msb>
                            <access>read-write</access>
                        </field>
                    </fields>
                </register>
                <register>
                    <name>CFIFOL</name>
                    <description>FIFO Port Register</description>
                    <alternateRegister>CFIFO</alternateRegister>
                    <addressOffset>0x014</addressOffset>
                    <size>16</size>
                    <access>read-write</access>
                    <resetValue>0x0000</resetValue>
                    <resetMask>0xffff</resetMask>
                    <fields>
                        <field>
                            <name>FIFOPORT</name>
                            <description>Read receive data from the FIFO buffer or write transmit data to the FIFO buffer by accessing these bits.</description>
                            <lsb>0</lsb>
                            <msb>15</msb>
                            <access>read-write</access>
                        </field>
                    </fields>
                </register>
                <register>
                    <name>CFIFOLL</name>
                    <description>FIFO Port Register</description>
                    <alternateRegister>CFIFO</alternateRegister>
                    <addressOffset>0x014</addressOffset>
                    <size>8</size>
                    <access>read-write</access>
                    <resetValue>0x00</resetValue>
                    <resetMask>0xff</resetMask>
                    <fields>
                        <field>
                            <name>FIFOPORT</name>
                            <description>Read receive data from the FIFO buffer or write transmit data to the FIFO buffer by accessing these bits.</description>
                            <lsb>0</lsb>
                            <msb>7</msb>
                            <access>read-write</access>
                        </field>
                    </fields>
                </register>
                <register>
                    <name>CFIFOH</name>
                    <description>FIFO Port Register</description>
                    <alternateRegister>CFIFO</alternateRegister>
                    <addressOffset>0x016</addressOffset>
                    <size>16</size>
                    <access>read-write</access>
                    <resetValue>0x0000</resetValue>
                    <resetMask>0xffff</resetMask>
                    <fields>
                        <field>
                            <name>FIFOPORT</name>
                            <description>Read receive data from the FIFO buffer or write transmit data to the FIFO buffer by accessing these bits.</description>
                            <lsb>0</lsb>
                            <msb>15</msb>
                            <access>read-write</access>
                        </field>
                    </fields>
                </register>
                <register>
                    <name>CFIFOHH</name>
                    <description>FIFO Port Register</description>
                    <alternateRegister>CFIFO</alternateRegister>
                    <addressOffset>0x017</addressOffset>
                    <size>8</size>
                    <access>read-write</access>
                    <resetValue>0x00</resetValue>
                    <resetMask>0xff</resetMask>
                    <fields>
                        <field>
                            <name>FIFOPORT</name>
                            <description>Read receive data from the FIFO buffer or write transmit data to the FIFO buffer by accessing these bits.</description>
                            <lsb>0</lsb>
                            <msb>7</msb>
                            <access>read-write</access>
                        </field>
                    </fields>
                </register>
                <register>
                    <dim>2</dim>
                    <dimIncrement>0x04</dimIncrement>
                    <dimIndex>0-1</dimIndex>
                    <name>D%sFIFO</name>
                    <description>FIFO Port Register</description>
                    <addressOffset>0x018</addressOffset>
                    <size>32</size>
                    <access>read-write</access>
                    <resetValue>0x00000000</resetValue>
                    <resetMask>0xffffffff</resetMask>
                    <fields>
                        <field>
                            <name>FIFOPORT</name>
                            <description>Read receive data from the FIFO buffer or write transmit data to the FIFO buffer by accessing these bits.</description>
                            <lsb>0</lsb>
                            <msb>31</msb>
                            <access>read-write</access>
                        </field>
                    </fields>
                </register>
                <register>
                    <dim>2</dim>
                    <dimIncrement>0x04</dimIncrement>
                    <dimIndex>0-1</dimIndex>
                    <name>D%sFIFOL</name>
                    <description>FIFO Port Register</description>
                    <alternateRegister>D%sFIFO</alternateRegister>
                    <addressOffset>0x018</addressOffset>
                    <size>16</size>
                    <access>read-write</access>
                    <resetValue>0x0000</resetValue>
                    <resetMask>0xffff</resetMask>
                    <fields>
                        <field>
                            <name>FIFOPORT</name>
                            <description>Read receive data from the FIFO buffer or write transmit data to the FIFO buffer by accessing these bits.</description>
                            <lsb>0</lsb>
                            <msb>15</msb>
                            <access>read-write</access>
                        </field>
                    </fields>
                </register>
                <register>
                    <dim>2</dim>
                    <dimIncrement>0x04</dimIncrement>
                    <dimIndex>0-1</dimIndex>
                    <name>D%sFIFOLL</name>
                    <description>FIFO Port Register</description>
                    <alternateRegister>D%sFIFO</alternateRegister>
                    <addressOffset>0x018</addressOffset>
                    <size>8</size>
                    <access>read-write</access>
                    <resetValue>0x00</resetValue>
                    <resetMask>0xff</resetMask>
                    <fields>
                        <field>
                            <name>FIFOPORT</name>
                            <description>Read receive data from the FIFO buffer or write transmit data to the FIFO buffer by accessing these bits.</description>
                            <lsb>0</lsb>
                            <msb>7</msb>
                            <access>read-write</access>
                        </field>
                    </fields>
                </register>
                <register>
                    <name>D0FIFOH</name>
                    <description>FIFO Port Register</description>
                    <alternateRegister>D%sFIFO</alternateRegister>
                    <addressOffset>0x01A</addressOffset>
                    <size>16</size>
                    <access>read-write</access>
                    <resetValue>0x0000</resetValue>
                    <resetMask>0xffff</resetMask>
                    <fields>
                        <field>
                            <name>FIFOPORT</name>
                            <description>Read receive data from the FIFO buffer or write transmit data to the FIFO buffer by accessing these bits.</description>
                            <lsb>0</lsb>
                            <msb>15</msb>
                            <access>read-write</access>
                        </field>
                    </fields>
                </register>
                <register>
                    <name>D1FIFOH</name>
                    <description>FIFO Port Register</description>
                    <alternateRegister>D0FIFOH</alternateRegister>
                    <addressOffset>0x01A</addressOffset>
                    <size>16</size>
                    <access>read-write</access>
                    <resetValue>0x0000</resetValue>
                    <resetMask>0xffff</resetMask>
                    <fields>
                        <field>
                            <name>FIFOPORT</name>
                            <description>Read receive data from the FIFO buffer or write transmit data to the FIFO buffer by accessing these bits.</description>
                            <lsb>0</lsb>
                            <msb>15</msb>
                            <access>read-write</access>
                        </field>
                    </fields>
                </register>
                <register>
                    <name>D0FIFOHH</name>
                    <description>FIFO Port Register</description>
                    <alternateRegister>D%sFIFO</alternateRegister>
                    <addressOffset>0x01B</addressOffset>
                    <size>8</size>
                    <access>read-write</access>
                    <resetValue>0x00</resetValue>
                    <resetMask>0xff</resetMask>
                    <fields>
                        <field>
                            <name>FIFOPORT</name>
                            <description>Read receive data from the FIFO buffer or write transmit data to the FIFO buffer by accessing these bits.</description>
                            <lsb>0</lsb>
                            <msb>7</msb>
                            <access>read-write</access>
                        </field>
                    </fields>
                </register>
                <register>
                    <name>D1FIFOHH</name>
                    <description>FIFO Port Register</description>
                    <alternateRegister>D0FIFOHH</alternateRegister>
                    <addressOffset>0x01B</addressOffset>
                    <size>8</size>
                    <access>read-write</access>
                    <resetValue>0x00</resetValue>
                    <resetMask>0xff</resetMask>
                    <fields>
                        <field>
                            <name>FIFOPORT</name>
                            <description>Read receive data from the FIFO buffer or write transmit data to the FIFO buffer by accessing these bits.</description>
                            <lsb>0</lsb>
                            <msb>7</msb>
                            <access>read-write</access>
                        </field>
                    </fields>
                </register>
                <register>
                    <name>CFIFOSEL</name>
                    <description>CFIFO Port Selection Register</description>
                    <addressOffset>0x020</addressOffset>
                    <size>16</size>
                    <access>read-write</access>
                    <resetValue>0x0000</resetValue>
                    <resetMask>0xcd2f</resetMask>
                    <fields>
                        <field>
                            <name>CURPIPE</name>
                            <description>FIFO Port Access Pipe Specification</description>
                            <lsb>0</lsb>
                            <msb>3</msb>
                            <access>read-write</access>
                            <enumeratedValues>
                                <enumeratedValue>
                                    <name>0x0</name>
                                    <description>DCP (default control pipe)</description>
                                    <value>0x0</value>
                                </enumeratedValue>
                                <enumeratedValue>
                                    <name>0x1</name>
                                    <description>Pipe 1</description>
                                    <value>0x1</value>
                                </enumeratedValue>
                                <enumeratedValue>
                                    <name>0x2</name>
                                    <description>Pipe 2</description>
                                    <value>0x2</value>
                                </enumeratedValue>
                                <enumeratedValue>
                                    <name>0x3</name>
                                    <description>Pipe 3</description>
                                    <value>0x3</value>
                                </enumeratedValue>
                                <enumeratedValue>
                                    <name>0x4</name>
                                    <description>Pipe 4</description>
                                    <value>0x4</value>
                                </enumeratedValue>
                                <enumeratedValue>
                                    <name>0x5</name>
                                    <description>Pipe 5</description>
                                    <value>0x5</value>
                                </enumeratedValue>
                                <enumeratedValue>
                                    <name>0x6</name>
                                    <description>Pipe 6</description>
                                    <value>0x6</value>
                                </enumeratedValue>
                                <enumeratedValue>
                                    <name>0x7</name>
                                    <description>Pipe 7</description>
                                    <value>0x7</value>
                                </enumeratedValue>
                                <enumeratedValue>
                                    <name>0x8</name>
                                    <description>Pipe 8</description>
                                    <value>0x8</value>
                                </enumeratedValue>
                                <enumeratedValue>
                                    <name>0x9</name>
                                    <description>Pipe 9</description>
                                    <value>0x9</value>
                                </enumeratedValue>
                                <enumeratedValue>
                                    <name>Others</name>
                                    <description>Setting prohibited</description>
                                    <isDefault>true</isDefault>
                                </enumeratedValue>
                            </enumeratedValues>
                        </field>
                        <field>
                            <name>ISEL</name>
                            <description>FIFO Port Access Direction when DCP Is Selected</description>
                            <lsb>5</lsb>
                            <msb>5</msb>
                            <access>read-write</access>
                            <enumeratedValues>
                                <enumeratedValue>
                                    <name>0</name>
                                    <description>Select reading from the FIFO buffer</description>
                                    <value>#0</value>
                                </enumeratedValue>
                                <enumeratedValue>
                                    <name>1</name>
                                    <description>Select writing to the FIFO buffer</description>
                                    <value>#1</value>
                                </enumeratedValue>
                            </enumeratedValues>
                        </field>
                        <field>
                            <name>BIGEND</name>
                            <description>FIFO Port Endian Control</description>
                            <lsb>8</lsb>
                            <msb>8</msb>
                            <access>read-write</access>
                            <enumeratedValues>
                                <enumeratedValue>
                                    <name>0</name>
                                    <description>Little endian</description>
                                    <value>#0</value>
                                </enumeratedValue>
                                <enumeratedValue>
                                    <name>1</name>
                                    <description>Big endian</description>
                                    <value>#1</value>
                                </enumeratedValue>
                            </enumeratedValues>
                        </field>
                        <field>
                            <name>MBW</name>
                            <description>CFIFO Port Access Bit Width</description>
                            <lsb>10</lsb>
                            <msb>11</msb>
                            <access>read-write</access>
                            <enumeratedValues>
                                <enumeratedValue>
                                    <name>00</name>
                                    <description>8-bit width</description>
                                    <value>#00</value>
                                </enumeratedValue>
                                <enumeratedValue>
                                    <name>01</name>
                                    <description>16-bit width</description>
                                    <value>#01</value>
                                </enumeratedValue>
                                <enumeratedValue>
                                    <name>10</name>
                                    <description>32-bit width</description>
                                    <value>#10</value>
                                </enumeratedValue>
                                <enumeratedValue>
                                    <name>11</name>
                                    <description>Setting prohibited</description>
                                    <value>#11</value>
                                </enumeratedValue>
                            </enumeratedValues>
                        </field>
                        <field>
                            <name>REW</name>
                            <description>Buffer Pointer Rewind</description>
                            <lsb>14</lsb>
                            <msb>14</msb>
                            <access>write-only</access>
                            <enumeratedValues>
                                <enumeratedValue>
                                    <name>0</name>
                                    <description>Do not rewind buffer pointer (Writing 0 has no effect.)</description>
                                    <value>#0</value>
                                </enumeratedValue>
                                <enumeratedValue>
                                    <name>1</name>
                                    <description>Rewind buffer pointer</description>
                                    <value>#1</value>
                                </enumeratedValue>
                            </enumeratedValues>
                        </field>
                        <field>
                            <name>RCNT</name>
                            <description>Read Count Mode</description>
                            <lsb>15</lsb>
                            <msb>15</msb>
                            <access>read-write</access>
                            <enumeratedValues>
                                <enumeratedValue>
                                    <name>0</name>
                                    <description>Clear DTLN[11:0] flags in the FIFO port control register to 0x000 when all receive data is read from CFIFO</description>
                                    <value>#0</value>
                                </enumeratedValue>
                                <enumeratedValue>
                                    <name>1</name>
                                    <description>Decrement DTLN[11:0] flags each time receive data is read from CFIFO</description>
                                    <value>#1</value>
                                </enumeratedValue>
                            </enumeratedValues>
                        </field>
                    </fields>
                </register>
                <register>
                    <name>CFIFOCTR</name>
                    <description>FIFO Port Control Register</description>
                    <addressOffset>0x022</addressOffset>
                    <size>16</size>
                    <access>read-write</access>
                    <resetValue>0x0000</resetValue>
                    <resetMask>0xefff</resetMask>
                    <fields>
                        <field>
                            <name>DTLN</name>
                            <description>Receive Data Length Flag</description>
                            <lsb>0</lsb>
                            <msb>11</msb>
                            <access>read-only</access>
                        </field>
                        <field>
                            <name>FRDY</name>
                            <description>FIFO Port Ready Flag</description>
                            <lsb>13</lsb>
                            <msb>13</msb>
                            <access>read-only</access>
                            <enumeratedValues>
                                <enumeratedValue>
                                    <name>0</name>
                                    <description>FIFO port access disabled</description>
                                    <value>#0</value>
                                </enumeratedValue>
                                <enumeratedValue>
                                    <name>1</name>
                                    <description>FIFO port access enabled</description>
                                    <value>#1</value>
                                </enumeratedValue>
                            </enumeratedValues>
                        </field>
                        <field>
                            <name>BCLR</name>
                            <description>CPU Buffer Clear</description>
                            <lsb>14</lsb>
                            <msb>14</msb>
                            <access>write-only</access>
                            <enumeratedValues>
                                <enumeratedValue>
                                    <name>0</name>
                                    <description>No operation (writing 0 has no effect)</description>
                                    <value>#0</value>
                                </enumeratedValue>
                                <enumeratedValue>
                                    <name>1</name>
                                    <description>Clear FIFO buffer on the CPU side</description>
                                    <value>#1</value>
                                </enumeratedValue>
                            </enumeratedValues>
                        </field>
                        <field>
                            <name>BVAL</name>
                            <description>FIFO Buffer Valid Flag</description>
                            <lsb>15</lsb>
                            <msb>15</msb>
                            <access>read-write</access>
                            <enumeratedValues>
                                <enumeratedValue>
                                    <name>0</name>
                                    <description>Invalid (writing 0 has no effect)</description>
                                    <value>#0</value>
                                </enumeratedValue>
                                <enumeratedValue>
                                    <name>1</name>
                                    <description>Writing ended</description>
                                    <value>#1</value>
                                </enumeratedValue>
                            </enumeratedValues>
                        </field>
                    </fields>
                </register>
                <register>
                    <dim>2</dim>
                    <dimIncrement>0x4</dimIncrement>
                    <dimIndex>0-1</dimIndex>
                    <name>D%sFIFOSEL</name>
                    <description>D%sFIFO Port Selection Register</description>
                    <addressOffset>0x028</addressOffset>
                    <size>16</size>
                    <access>read-write</access>
                    <resetValue>0x0000</resetValue>
                    <resetMask>0xfd0f</resetMask>
                    <fields>
                        <field>
                            <name>CURPIPE</name>
                            <description>FIFO Port Access Pipe Specification</description>
                            <lsb>0</lsb>
                            <msb>3</msb>
                            <access>read-write</access>
                            <enumeratedValues>
                                <enumeratedValue>
                                    <name>0x0</name>
                                    <description>No pipe specification</description>
                                    <value>0x0</value>
                                </enumeratedValue>
                                <enumeratedValue>
                                    <name>0x1</name>
                                    <description>Pipe 1</description>
                                    <value>0x1</value>
                                </enumeratedValue>
                                <enumeratedValue>
                                    <name>0x2</name>
                                    <description>Pipe 2</description>
                                    <value>0x2</value>
                                </enumeratedValue>
                                <enumeratedValue>
                                    <name>0x3</name>
                                    <description>Pipe 3</description>
                                    <value>0x3</value>
                                </enumeratedValue>
                                <enumeratedValue>
                                    <name>0x4</name>
                                    <description>Pipe 4</description>
                                    <value>0x4</value>
                                </enumeratedValue>
                                <enumeratedValue>
                                    <name>0x5</name>
                                    <description>Pipe 5</description>
                                    <value>0x5</value>
                                </enumeratedValue>
                                <enumeratedValue>
                                    <name>0x6</name>
                                    <description>Pipe 6</description>
                                    <value>0x6</value>
                                </enumeratedValue>
                                <enumeratedValue>
                                    <name>0x7</name>
                                    <description>Pipe 7</description>
                                    <value>0x7</value>
                                </enumeratedValue>
                                <enumeratedValue>
                                    <name>0x8</name>
                                    <description>Pipe 8</description>
                                    <value>0x8</value>
                                </enumeratedValue>
                                <enumeratedValue>
                                    <name>0x9</name>
                                    <description>Pipe 9</description>
                                    <value>0x9</value>
                                </enumeratedValue>
                                <enumeratedValue>
                                    <name>Others</name>
                                    <description>Setting prohibited</description>
                                    <isDefault>true</isDefault>
                                </enumeratedValue>
                            </enumeratedValues>
                        </field>
                        <field>
                            <name>BIGEND</name>
                            <description>FIFO Port Endian Control</description>
                            <lsb>8</lsb>
                            <msb>8</msb>
                            <access>read-write</access>
                            <enumeratedValues>
                                <enumeratedValue>
                                    <name>0</name>
                                    <description>Little endian</description>
                                    <value>#0</value>
                                </enumeratedValue>
                                <enumeratedValue>
                                    <name>1</name>
                                    <description>Big endian</description>
                                    <value>#1</value>
                                </enumeratedValue>
                            </enumeratedValues>
                        </field>
                        <field>
                            <name>MBW</name>
                            <description>FIFO Port Access Bit Width</description>
                            <lsb>10</lsb>
                            <msb>11</msb>
                            <access>read-write</access>
                            <enumeratedValues>
                                <enumeratedValue>
                                    <name>00</name>
                                    <description>8-bit width</description>
                                    <value>#00</value>
                                </enumeratedValue>
                                <enumeratedValue>
                                    <name>01</name>
                                    <description>16-bit width</description>
                                    <value>#01</value>
                                </enumeratedValue>
                                <enumeratedValue>
                                    <name>10</name>
                                    <description>32-bit width</description>
                                    <value>#10</value>
                                </enumeratedValue>
                                <enumeratedValue>
                                    <name>11</name>
                                    <description>Setting prohibited</description>
                                    <value>#11</value>
                                </enumeratedValue>
                            </enumeratedValues>
                        </field>
                        <field>
                            <name>DREQE</name>
                            <description>DMAC/DTC Transfer Request Enable</description>
                            <lsb>12</lsb>
                            <msb>12</msb>
                            <access>read-write</access>
                            <enumeratedValues>
                                <enumeratedValue>
                                    <name>0</name>
                                    <description>Disable DMAC/DTC transfer request</description>
                                    <value>#0</value>
                                </enumeratedValue>
                                <enumeratedValue>
                                    <name>1</name>
                                    <description>Enable DMAC/DTC transfer request</description>
                                    <value>#1</value>
                                </enumeratedValue>
                            </enumeratedValues>
                        </field>
                        <field>
                            <name>DCLRM</name>
                            <description>Auto FIFO Buffer Clear Mode after Specified Pipe is Read</description>
                            <lsb>13</lsb>
                            <msb>13</msb>
                            <access>read-write</access>
                            <enumeratedValues>
                                <enumeratedValue>
                                    <name>0</name>
                                    <description>Disable auto buffer clear mode</description>
                                    <value>#0</value>
                                </enumeratedValue>
                                <enumeratedValue>
                                    <name>1</name>
                                    <description>Enable auto buffer clear mode</description>
                                    <value>#1</value>
                                </enumeratedValue>
                            </enumeratedValues>
                        </field>
                        <field>
                            <name>REW</name>
                            <description>Buffer Pointer Rewind</description>
                            <lsb>14</lsb>
                            <msb>14</msb>
                            <access>write-only</access>
                            <enumeratedValues>
                                <enumeratedValue>
                                    <name>0</name>
                                    <description>Do not rewind buffer pointer (writing 0 has no effect)</description>
                                    <value>#0</value>
                                </enumeratedValue>
                                <enumeratedValue>
                                    <name>1</name>
                                    <description>Rewind buffer pointer</description>
                                    <value>#1</value>
                                </enumeratedValue>
                            </enumeratedValues>
                        </field>
                        <field>
                            <name>RCNT</name>
                            <description>Read Count Mode</description>
                            <lsb>15</lsb>
                            <msb>15</msb>
                            <access>read-write</access>
                            <enumeratedValues>
                                <enumeratedValue>
                                    <name>0</name>
                                    <description>Clear DTLN[11:0] flags in the FIFO port control register to 0x000 when all receive data is read from DnFIFO (after read of a single plane in double buffer mode)</description>
                                    <value>#0</value>
                                </enumeratedValue>
                                <enumeratedValue>
                                    <name>1</name>
                                    <description>Decrement DTLN[11:0] flags each time receive data is read from DnFIFO</description>
                                    <value>#1</value>
                                </enumeratedValue>
                            </enumeratedValues>
                        </field>
                    </fields>
                </register>
                <register>
                    <dim>2</dim>
                    <dimIncrement>0x4</dimIncrement>
                    <dimIndex>0-1</dimIndex>
                    <name>D%sFIFOCTR</name>
                    <description>FIFO Port Control Register</description>
                    <addressOffset>0x02A</addressOffset>
                    <size>16</size>
                    <access>read-write</access>
                    <resetValue>0x0000</resetValue>
                    <resetMask>0xefff</resetMask>
                    <fields>
                        <field>
                            <name>DTLN</name>
                            <description>Receive Data Length Flag</description>
                            <lsb>0</lsb>
                            <msb>11</msb>
                            <access>read-only</access>
                        </field>
                        <field>
                            <name>FRDY</name>
                            <description>FIFO Port Ready Flag</description>
                            <lsb>13</lsb>
                            <msb>13</msb>
                            <access>read-only</access>
                            <enumeratedValues>
                                <enumeratedValue>
                                    <name>0</name>
                                    <description>FIFO port access disabled</description>
                                    <value>#0</value>
                                </enumeratedValue>
                                <enumeratedValue>
                                    <name>1</name>
                                    <description>FIFO port access enabled</description>
                                    <value>#1</value>
                                </enumeratedValue>
                            </enumeratedValues>
                        </field>
                        <field>
                            <name>BCLR</name>
                            <description>CPU Buffer Clear</description>
                            <lsb>14</lsb>
                            <msb>14</msb>
                            <access>write-only</access>
                            <enumeratedValues>
                                <enumeratedValue>
                                    <name>0</name>
                                    <description>No operation (writing 0 has no effect)</description>
                                    <value>#0</value>
                                </enumeratedValue>
                                <enumeratedValue>
                                    <name>1</name>
                                    <description>Clear FIFO buffer on the CPU side</description>
                                    <value>#1</value>
                                </enumeratedValue>
                            </enumeratedValues>
                        </field>
                        <field>
                            <name>BVAL</name>
                            <description>FIFO Buffer Valid Flag</description>
                            <lsb>15</lsb>
                            <msb>15</msb>
                            <access>read-write</access>
                            <enumeratedValues>
                                <enumeratedValue>
                                    <name>0</name>
                                    <description>Invalid (writing 0 has no effect)</description>
                                    <value>#0</value>
                                </enumeratedValue>
                                <enumeratedValue>
                                    <name>1</name>
                                    <description>Writing ended</description>
                                    <value>#1</value>
                                </enumeratedValue>
                            </enumeratedValues>
                        </field>
                    </fields>
                </register>
                <register>
                    <name>INTENB0</name>
                    <description>Interrupt Enable Register 0</description>
                    <addressOffset>0x030</addressOffset>
                    <size>16</size>
                    <access>read-write</access>
                    <resetValue>0x0000</resetValue>
                    <resetMask>0xff00</resetMask>
                    <fields>
                        <field>
                            <name>BRDYE</name>
                            <description>Buffer Ready Interrupt Request Enable</description>
                            <lsb>8</lsb>
                            <msb>8</msb>
                            <access>read-write</access>
                            <enumeratedValues>
                                <enumeratedValue>
                                    <name>0</name>
                                    <description>Disable interrupt request</description>
                                    <value>#0</value>
                                </enumeratedValue>
                                <enumeratedValue>
                                    <name>1</name>
                                    <description>Enable interrupt request</description>
                                    <value>#1</value>
                                </enumeratedValue>
                            </enumeratedValues>
                        </field>
                        <field>
                            <name>NRDYE</name>
                            <description>Buffer Not Ready Response Interrupt Request Enable</description>
                            <lsb>9</lsb>
                            <msb>9</msb>
                            <access>read-write</access>
                            <enumeratedValues>
                                <enumeratedValue>
                                    <name>0</name>
                                    <description>Disable interrupt request</description>
                                    <value>#0</value>
                                </enumeratedValue>
                                <enumeratedValue>
                                    <name>1</name>
                                    <description>Enable interrupt request</description>
                                    <value>#1</value>
                                </enumeratedValue>
                            </enumeratedValues>
                        </field>
                        <field>
                            <name>BEMPE</name>
                            <description>Buffer Empty Interrupt Request Enable</description>
                            <lsb>10</lsb>
                            <msb>10</msb>
                            <access>read-write</access>
                            <enumeratedValues>
                                <enumeratedValue>
                                    <name>0</name>
                                    <description>Disable interrupt request</description>
                                    <value>#0</value>
                                </enumeratedValue>
                                <enumeratedValue>
                                    <name>1</name>
                                    <description>Enable interrupt request</description>
                                    <value>#1</value>
                                </enumeratedValue>
                            </enumeratedValues>
                        </field>
                        <field>
                            <name>CTRE</name>
                            <description>Control Transfer Stage Transition Interrupt Request Enable</description>
                            <lsb>11</lsb>
                            <msb>11</msb>
                            <access>read-write</access>
                            <enumeratedValues>
                                <enumeratedValue>
                                    <name>0</name>
                                    <description>Disable interrupt request</description>
                                    <value>#0</value>
                                </enumeratedValue>
                                <enumeratedValue>
                                    <name>1</name>
                                    <description>Enable interrupt request</description>
                                    <value>#1</value>
                                </enumeratedValue>
                            </enumeratedValues>
                        </field>
                        <field>
                            <name>DVSE</name>
                            <description>Device State Transition Interrupt Request Enable</description>
                            <lsb>12</lsb>
                            <msb>12</msb>
                            <access>read-write</access>
                            <enumeratedValues>
                                <enumeratedValue>
                                    <name>0</name>
                                    <description>Disable interrupt request</description>
                                    <value>#0</value>
                                </enumeratedValue>
                                <enumeratedValue>
                                    <name>1</name>
                                    <description>Enable interrupt request</description>
                                    <value>#1</value>
                                </enumeratedValue>
                            </enumeratedValues>
                        </field>
                        <field>
                            <name>SOFE</name>
                            <description>Frame Number Update Interrupt Request Enable</description>
                            <lsb>13</lsb>
                            <msb>13</msb>
                            <access>read-write</access>
                            <enumeratedValues>
                                <enumeratedValue>
                                    <name>0</name>
                                    <description>Disable interrupt request</description>
                                    <value>#0</value>
                                </enumeratedValue>
                                <enumeratedValue>
                                    <name>1</name>
                                    <description>Enable interrupt request</description>
                                    <value>#1</value>
                                </enumeratedValue>
                            </enumeratedValues>
                        </field>
                        <field>
                            <name>RSME</name>
                            <description>Resume Interrupt Request Enable</description>
                            <lsb>14</lsb>
                            <msb>14</msb>
                            <access>read-write</access>
                            <enumeratedValues>
                                <enumeratedValue>
                                    <name>0</name>
                                    <description>Disable interrupt request</description>
                                    <value>#0</value>
                                </enumeratedValue>
                                <enumeratedValue>
                                    <name>1</name>
                                    <description>Enable interrupt request</description>
                                    <value>#1</value>
                                </enumeratedValue>
                            </enumeratedValues>
                        </field>
                        <field>
                            <name>VBSE</name>
                            <description>VBUS Interrupt Request Enable</description>
                            <lsb>15</lsb>
                            <msb>15</msb>
                            <access>read-write</access>
                            <enumeratedValues>
                                <enumeratedValue>
                                    <name>0</name>
                                    <description>Disable interrupt request</description>
                                    <value>#0</value>
                                </enumeratedValue>
                                <enumeratedValue>
                                    <name>1</name>
                                    <description>Enable interrupt request</description>
                                    <value>#1</value>
                                </enumeratedValue>
                            </enumeratedValues>
                        </field>
                    </fields>
                </register>
                <register>
                    <name>INTENB1</name>
                    <description>Interrupt Enable Register 1</description>
                    <addressOffset>0x032</addressOffset>
                    <size>16</size>
                    <access>read-write</access>
                    <resetValue>0x0000</resetValue>
                    <resetMask>0xdb71</resetMask>
                    <fields>
                        <field>
                            <name>PDDETINTE</name>
                            <description>PDDETINT Detection Interrupt Request Enable</description>
                            <lsb>0</lsb>
                            <msb>0</msb>
                            <access>read-write</access>
                            <enumeratedValues>
                                <enumeratedValue>
                                    <name>0</name>
                                    <description>Disable interrupt request</description>
                                    <value>#0</value>
                                </enumeratedValue>
                                <enumeratedValue>
                                    <name>1</name>
                                    <description>Enable interrupt request</description>
                                    <value>#1</value>
                                </enumeratedValue>
                            </enumeratedValues>
                        </field>
                        <field>
                            <name>SACKE</name>
                            <description>Setup Transaction Normal Response Interrupt Request Enable</description>
                            <lsb>4</lsb>
                            <msb>4</msb>
                            <access>read-write</access>
                            <enumeratedValues>
                                <enumeratedValue>
                                    <name>0</name>
                                    <description>Disable interrupt request</description>
                                    <value>#0</value>
                                </enumeratedValue>
                                <enumeratedValue>
                                    <name>1</name>
                                    <description>Enable interrupt request</description>
                                    <value>#1</value>
                                </enumeratedValue>
                            </enumeratedValues>
                        </field>
                        <field>
                            <name>SIGNE</name>
                            <description>Setup Transaction Error Interrupt Request Enable</description>
                            <lsb>5</lsb>
                            <msb>5</msb>
                            <access>read-write</access>
                            <enumeratedValues>
                                <enumeratedValue>
                                    <name>0</name>
                                    <description>Disable interrupt request</description>
                                    <value>#0</value>
                                </enumeratedValue>
                                <enumeratedValue>
                                    <name>1</name>
                                    <description>Enable interrupt request</description>
                                    <value>#1</value>
                                </enumeratedValue>
                            </enumeratedValues>
                        </field>
                        <field>
                            <name>EOFERRE</name>
                            <description>EOF Error Detection Interrupt Request Enable</description>
                            <lsb>6</lsb>
                            <msb>6</msb>
                            <access>read-write</access>
                            <enumeratedValues>
                                <enumeratedValue>
                                    <name>0</name>
                                    <description>Disable interrupt request</description>
                                    <value>#0</value>
                                </enumeratedValue>
                                <enumeratedValue>
                                    <name>1</name>
                                    <description>Enable interrupt request</description>
                                    <value>#1</value>
                                </enumeratedValue>
                            </enumeratedValues>
                        </field>
                        <field>
                            <name>LPMENDE</name>
                            <description>LPM Transaction End Interrupt Request Enable</description>
                            <lsb>8</lsb>
                            <msb>8</msb>
                            <access>read-write</access>
                            <enumeratedValues>
                                <enumeratedValue>
                                    <name>0</name>
                                    <description>Disable interrupt request</description>
                                    <value>#0</value>
                                </enumeratedValue>
                                <enumeratedValue>
                                    <name>1</name>
                                    <description>Enable interrupt request</description>
                                    <value>#1</value>
                                </enumeratedValue>
                            </enumeratedValues>
                        </field>
                        <field>
                            <name>L1RSMENDE</name>
                            <description>L1 Resume End Interrupt Enable</description>
                            <lsb>9</lsb>
                            <msb>9</msb>
                            <access>read-write</access>
                            <enumeratedValues>
                                <enumeratedValue>
                                    <name>0</name>
                                    <description>Disable interrupt request</description>
                                    <value>#0</value>
                                </enumeratedValue>
                                <enumeratedValue>
                                    <name>1</name>
                                    <description>Enable interrupt request</description>
                                    <value>#1</value>
                                </enumeratedValue>
                            </enumeratedValues>
                        </field>
                        <field>
                            <name>ATTCHE</name>
                            <description>Connection Detection Interrupt Request Enable</description>
                            <lsb>11</lsb>
                            <msb>11</msb>
                            <access>read-write</access>
                            <enumeratedValues>
                                <enumeratedValue>
                                    <name>0</name>
                                    <description>Disable interrupt request</description>
                                    <value>#0</value>
                                </enumeratedValue>
                                <enumeratedValue>
                                    <name>1</name>
                                    <description>Enable interrupt request</description>
                                    <value>#1</value>
                                </enumeratedValue>
                            </enumeratedValues>
                        </field>
                        <field>
                            <name>DTCHE</name>
                            <description>Disconnection Detection Interrupt Request Enable</description>
                            <lsb>12</lsb>
                            <msb>12</msb>
                            <access>read-write</access>
                            <enumeratedValues>
                                <enumeratedValue>
                                    <name>0</name>
                                    <description>Disable interrupt request</description>
                                    <value>#0</value>
                                </enumeratedValue>
                                <enumeratedValue>
                                    <name>1</name>
                                    <description>Enable interrupt request</description>
                                    <value>#1</value>
                                </enumeratedValue>
                            </enumeratedValues>
                        </field>
                        <field>
                            <name>BCHGE</name>
                            <description>USB Bus Change Interrupt Request Enable</description>
                            <lsb>14</lsb>
                            <msb>14</msb>
                            <access>read-write</access>
                            <enumeratedValues>
                                <enumeratedValue>
                                    <name>0</name>
                                    <description>Disable interrupt request</description>
                                    <value>#0</value>
                                </enumeratedValue>
                                <enumeratedValue>
                                    <name>1</name>
                                    <description>Enable interrupt request</description>
                                    <value>#1</value>
                                </enumeratedValue>
                            </enumeratedValues>
                        </field>
                        <field>
                            <name>OVRCRE</name>
                            <description>OVRCRE Interrupt Request Enable</description>
                            <lsb>15</lsb>
                            <msb>15</msb>
                            <access>read-write</access>
                            <enumeratedValues>
                                <enumeratedValue>
                                    <name>0</name>
                                    <description>Disable interrupt request</description>
                                    <value>#0</value>
                                </enumeratedValue>
                                <enumeratedValue>
                                    <name>1</name>
                                    <description>Enable interrupt request</description>
                                    <value>#1</value>
                                </enumeratedValue>
                            </enumeratedValues>
                        </field>
                    </fields>
                </register>
                <register>
                    <name>BRDYENB</name>
                    <description>BRDY Interrupt Enable Register</description>
                    <addressOffset>0x036</addressOffset>
                    <size>16</size>
                    <access>read-write</access>
                    <resetValue>0x0000</resetValue>
                    <resetMask>0xffff</resetMask>
                    <fields>
                        <field>
                            <name>PIPEBRDYE</name>
                            <description>BRDY Interrupt Request Enable for Pipes [9:0]</description>
                            <lsb>0</lsb>
                            <msb>9</msb>
                            <access>read-write</access>
                            <enumeratedValues>
                                <enumeratedValue>
                                    <name>0</name>
                                    <description>Disable interrupt request</description>
                                    <value>#0</value>
                                </enumeratedValue>
                                <enumeratedValue>
                                    <name>1</name>
                                    <description>Enable interrupt request</description>
                                    <value>#1</value>
                                </enumeratedValue>
                            </enumeratedValues>
                        </field>
                    </fields>
                </register>
                <register>
                    <name>NRDYENB</name>
                    <description>NRDY Interrupt Enable Register</description>
                    <addressOffset>0x038</addressOffset>
                    <size>16</size>
                    <access>read-write</access>
                    <resetValue>0x0000</resetValue>
                    <resetMask>0xffff</resetMask>
                    <fields>
                        <field>
                            <name>PIPENRDYE</name>
                            <description>NRDY Interrupt Enable for Pipes [9:0]</description>
                            <lsb>0</lsb>
                            <msb>9</msb>
                            <access>read-write</access>
                            <enumeratedValues>
                                <enumeratedValue>
                                    <name>0</name>
                                    <description>Disable interrupt request</description>
                                    <value>#0</value>
                                </enumeratedValue>
                                <enumeratedValue>
                                    <name>1</name>
                                    <description>Enable interrupt request</description>
                                    <value>#1</value>
                                </enumeratedValue>
                            </enumeratedValues>
                        </field>
                    </fields>
                </register>
                <register>
                    <name>BEMPENB</name>
                    <description>BEMP Interrupt Enable Register</description>
                    <addressOffset>0x03A</addressOffset>
                    <size>16</size>
                    <access>read-write</access>
                    <resetValue>0x0000</resetValue>
                    <resetMask>0xffff</resetMask>
                    <fields>
                        <field>
                            <name>PIPEBEMPE</name>
                            <description>BEMP Interrupt Enable for Pipes [9:0]</description>
                            <lsb>0</lsb>
                            <msb>9</msb>
                            <access>read-write</access>
                            <enumeratedValues>
                                <enumeratedValue>
                                    <name>0</name>
                                    <description>Disable interrupt request</description>
                                    <value>#0</value>
                                </enumeratedValue>
                                <enumeratedValue>
                                    <name>1</name>
                                    <description>Enable interrupt request</description>
                                    <value>#1</value>
                                </enumeratedValue>
                            </enumeratedValues>
                        </field>
                    </fields>
                </register>
                <register>
                    <name>SOFCFG</name>
                    <description>SOF Output Configuration Register</description>
                    <addressOffset>0x03C</addressOffset>
                    <size>16</size>
                    <access>read-write</access>
                    <resetValue>0x0000</resetValue>
                    <resetMask>0x0170</resetMask>
                    <fields>
                        <field>
                            <name>EDGESTS</name>
                            <description>Interrupt Edge Processing Status Flag</description>
                            <lsb>4</lsb>
                            <msb>4</msb>
                            <access>read-only</access>
                        </field>
                        <field>
                            <name>INTL</name>
                            <description>Interrupt Output Sense Select</description>
                            <lsb>5</lsb>
                            <msb>5</msb>
                            <access>read-write</access>
                            <enumeratedValues>
                                <enumeratedValue>
                                    <name>0</name>
                                    <description>Edge detection</description>
                                    <value>#0</value>
                                </enumeratedValue>
                                <enumeratedValue>
                                    <name>1</name>
                                    <description>Level detection</description>
                                    <value>#1</value>
                                </enumeratedValue>
                            </enumeratedValues>
                        </field>
                        <field>
                            <name>BRDYM</name>
                            <description>PIPEBRDY Interrupt Status Clear Timing</description>
                            <lsb>6</lsb>
                            <msb>6</msb>
                            <access>read-write</access>
                            <enumeratedValues>
                                <enumeratedValue>
                                    <name>0</name>
                                    <description>Clear BRDY flag through software</description>
                                    <value>#0</value>
                                </enumeratedValue>
                                <enumeratedValue>
                                    <name>1</name>
                                    <description>Clear BRDY flag by the USBHS through a data read from the FIFO buffer or data write to the FIFO buffer</description>
                                    <value>#1</value>
                                </enumeratedValue>
                            </enumeratedValues>
                        </field>
                        <field>
                            <name>TRNENSEL</name>
                            <description>Transaction-Enabled Time Select</description>
                            <lsb>8</lsb>
                            <msb>8</msb>
                            <access>read-write</access>
                            <enumeratedValues>
                                <enumeratedValue>
                                    <name>0</name>
                                    <description>Not low-speed communication</description>
                                    <value>#0</value>
                                </enumeratedValue>
                                <enumeratedValue>
                                    <name>1</name>
                                    <description>Low-speed communication</description>
                                    <value>#1</value>
                                </enumeratedValue>
                            </enumeratedValues>
                        </field>
                    </fields>
                </register>
                <register>
                    <name>PHYSET</name>
                    <description>PHY Setting Register</description>
                    <addressOffset>0x03E</addressOffset>
                    <size>16</size>
                    <access>read-write</access>
                    <resetValue>0x0033</resetValue>
                    <resetMask>0x0b3b</resetMask>
                    <fields>
                        <field>
                            <name>DIRPD</name>
                            <description>Power-Down Control</description>
                            <lsb>0</lsb>
                            <msb>0</msb>
                            <access>read-write</access>
                            <enumeratedValues>
                                <enumeratedValue>
                                    <name>0</name>
                                    <description>Do not enter low power mode</description>
                                    <value>#0</value>
                                </enumeratedValue>
                                <enumeratedValue>
                                    <name>1</name>
                                    <description>Enter low power mode</description>
                                    <value>#1</value>
                                </enumeratedValue>
                            </enumeratedValues>
                        </field>
                        <field>
                            <name>PLLRESET</name>
                            <description>PLL Reset Control</description>
                            <lsb>1</lsb>
                            <msb>1</msb>
                            <access>read-write</access>
                            <enumeratedValues>
                                <enumeratedValue>
                                    <name>0</name>
                                    <description>Disable PLL reset control for UTMI_PHY</description>
                                    <value>#0</value>
                                </enumeratedValue>
                                <enumeratedValue>
                                    <name>1</name>
                                    <description>Enable PLL reset control for UTMI_PHY</description>
                                    <value>#1</value>
                                </enumeratedValue>
                            </enumeratedValues>
                        </field>
                        <field>
                            <name>CDPEN</name>
                            <description>Charging Downstream Port Enable</description>
                            <lsb>3</lsb>
                            <msb>3</msb>
                            <access>read-write</access>
                            <enumeratedValues>
                                <enumeratedValue>
                                    <name>0</name>
                                    <description>Disable downstream port charging</description>
                                    <value>#0</value>
                                </enumeratedValue>
                                <enumeratedValue>
                                    <name>1</name>
                                    <description>Enable downstream port charging</description>
                                    <value>#1</value>
                                </enumeratedValue>
                            </enumeratedValues>
                        </field>
                        <field>
                            <name>CLKSEL</name>
                            <description>Input Clock Frequency Select</description>
                            <lsb>4</lsb>
                            <msb>5</msb>
                            <access>read-write</access>
                            <enumeratedValues>
                                <enumeratedValue>
                                    <name>00</name>
                                    <description>12 MHz</description>
                                    <value>#00</value>
                                </enumeratedValue>
                                <enumeratedValue>
                                    <name>01</name>
                                    <description>48 MHz</description>
                                    <value>#01</value>
                                </enumeratedValue>
                                <enumeratedValue>
                                    <name>10</name>
                                    <description>20 MHz</description>
                                    <value>#10</value>
                                </enumeratedValue>
                                <enumeratedValue>
                                    <name>11</name>
                                    <description>24 MHz</description>
                                    <value>#11</value>
                                </enumeratedValue>
                            </enumeratedValues>
                        </field>
                        <field>
                            <name>REPSEL</name>
                            <description>Terminating Resistance Adjustment Cycle</description>
                            <lsb>8</lsb>
                            <msb>9</msb>
                            <access>read-write</access>
                            <enumeratedValues>
                                <enumeratedValue>
                                    <name>00</name>
                                    <description>No cycle is set</description>
                                    <value>#00</value>
                                </enumeratedValue>
                                <enumeratedValue>
                                    <name>01</name>
                                    <description>Adjust terminating resistance at 16-second intervals</description>
                                    <value>#01</value>
                                </enumeratedValue>
                                <enumeratedValue>
                                    <name>10</name>
                                    <description>Adjust terminating resistance at 64-second intervals</description>
                                    <value>#10</value>
                                </enumeratedValue>
                                <enumeratedValue>
                                    <name>11</name>
                                    <description>Adjust terminating resistance at 128-second intervals</description>
                                    <value>#11</value>
                                </enumeratedValue>
                            </enumeratedValues>
                        </field>
                        <field>
                            <name>REPSTART</name>
                            <description>Forcibly Start Terminating Resistance Adjustment</description>
                            <lsb>11</lsb>
                            <msb>11</msb>
                            <access>read-write</access>
                            <enumeratedValues>
                                <enumeratedValue>
                                    <name>0</name>
                                    <description>Force terminating resistance adjustment to start</description>
                                    <value>#0</value>
                                </enumeratedValue>
                                <enumeratedValue>
                                    <name>1</name>
                                    <description>Do not force terminating resistance adjustment to start</description>
                                    <value>#1</value>
                                </enumeratedValue>
                            </enumeratedValues>
                        </field>
                        <field>
                            <name>HSEB</name>
                            <description>CL-only mode</description>
                            <lsb>15</lsb>
                            <msb>15</msb>
                            <access>read-write</access>
                            <enumeratedValues>
                                <enumeratedValue>
                                    <name>0</name>
                                    <description>Disable CL-only mode</description>
                                    <value>#0</value>
                                </enumeratedValue>
                                <enumeratedValue>
                                    <name>1</name>
                                    <description>Enable CL-only mode</description>
                                    <value>#1</value>
                                </enumeratedValue>
                            </enumeratedValues>
                        </field>
                    </fields>
                </register>
                <register>
                    <name>INTSTS0</name>
                    <description>Interrupt Status Register 0</description>
                    <addressOffset>0x040</addressOffset>
                    <size>16</size>
                    <access>read-write</access>
                    <resetValue>0x0000</resetValue>
                    <resetMask>0xff7f</resetMask>
                    <fields>
                        <field>
                            <name>CTSQ</name>
                            <description>Control Transfer Stage Flag</description>
                            <lsb>0</lsb>
                            <msb>2</msb>
                            <access>read-only</access>
                            <enumeratedValues>
                                <enumeratedValue>
                                    <name>000</name>
                                    <description>Idle or setup stage</description>
                                    <value>#000</value>
                                </enumeratedValue>
                                <enumeratedValue>
                                    <name>001</name>
                                    <description>Control read data stage</description>
                                    <value>#001</value>
                                </enumeratedValue>
                                <enumeratedValue>
                                    <name>010</name>
                                    <description>Control read status stage</description>
                                    <value>#010</value>
                                </enumeratedValue>
                                <enumeratedValue>
                                    <name>011</name>
                                    <description>Control write data stage</description>
                                    <value>#011</value>
                                </enumeratedValue>
                                <enumeratedValue>
                                    <name>100</name>
                                    <description>Control write status stage</description>
                                    <value>#100</value>
                                </enumeratedValue>
                                <enumeratedValue>
                                    <name>101</name>
                                    <description>Control write (no data) status stage</description>
                                    <value>#101</value>
                                </enumeratedValue>
                                <enumeratedValue>
                                    <name>110</name>
                                    <description>Control transfer sequence error</description>
                                    <value>#110</value>
                                </enumeratedValue>
                            </enumeratedValues>
                        </field>
                        <field>
                            <name>VALID</name>
                            <description>USB Request Reception Flag</description>
                            <lsb>3</lsb>
                            <msb>3</msb>
                            <access>read-write</access>
                            <enumeratedValues>
                                <enumeratedValue>
                                    <name>0</name>
                                    <description>Setup packet not received</description>
                                    <value>#0</value>
                                </enumeratedValue>
                                <enumeratedValue>
                                    <name>1</name>
                                    <description>Setup packet received</description>
                                    <value>#1</value>
                                </enumeratedValue>
                            </enumeratedValues>
                        </field>
                        <field>
                            <name>DVSQ</name>
                            <description>Device State</description>
                            <lsb>4</lsb>
                            <msb>6</msb>
                            <access>read-only</access>
                            <enumeratedValues>
                                <enumeratedValue>
                                    <name>000</name>
                                    <description>Powered state</description>
                                    <value>#000</value>
                                </enumeratedValue>
                                <enumeratedValue>
                                    <name>001</name>
                                    <description>Default state</description>
                                    <value>#001</value>
                                </enumeratedValue>
                                <enumeratedValue>
                                    <name>010</name>
                                    <description>Address state</description>
                                    <value>#010</value>
                                </enumeratedValue>
                                <enumeratedValue>
                                    <name>011</name>
                                    <description>Configured state</description>
                                    <value>#011</value>
                                </enumeratedValue>
                                <enumeratedValue>
                                    <name>Others</name>
                                    <description>Suspend state</description>
                                    <isDefault>true</isDefault>
                                </enumeratedValue>
                            </enumeratedValues>
                        </field>
                        <field>
                            <name>VBSTS</name>
                            <description>VBUS Input Status Flag</description>
                            <lsb>7</lsb>
                            <msb>7</msb>
                            <access>read-only</access>
                            <enumeratedValues>
                                <enumeratedValue>
                                    <name>0</name>
                                    <description>USBHS_VBUS pin is low</description>
                                    <value>#0</value>
                                </enumeratedValue>
                                <enumeratedValue>
                                    <name>1</name>
                                    <description>USBHS_VBUS pin is high</description>
                                    <value>#1</value>
                                </enumeratedValue>
                            </enumeratedValues>
                        </field>
                        <field>
                            <name>BRDY</name>
                            <description>BRDY Interrupt Status Flag</description>
                            <lsb>8</lsb>
                            <msb>8</msb>
                            <access>read-only</access>
                            <enumeratedValues>
                                <enumeratedValue>
                                    <name>0</name>
                                    <description>No BRDY interrupt occurred</description>
                                    <value>#0</value>
                                </enumeratedValue>
                                <enumeratedValue>
                                    <name>1</name>
                                    <description>BRDY interrupt occurred</description>
                                    <value>#1</value>
                                </enumeratedValue>
                            </enumeratedValues>
                        </field>
                        <field>
                            <name>NRDY</name>
                            <description>NRDY Interrupt Status Flag</description>
                            <lsb>9</lsb>
                            <msb>9</msb>
                            <access>read-only</access>
                            <enumeratedValues>
                                <enumeratedValue>
                                    <name>0</name>
                                    <description>No NRDY interrupt occurred</description>
                                    <value>#0</value>
                                </enumeratedValue>
                                <enumeratedValue>
                                    <name>1</name>
                                    <description>NRDY interrupt occurred</description>
                                    <value>#1</value>
                                </enumeratedValue>
                            </enumeratedValues>
                        </field>
                        <field>
                            <name>BEMP</name>
                            <description>BEMP Interrupt Status Flag</description>
                            <lsb>10</lsb>
                            <msb>10</msb>
                            <access>read-only</access>
                            <enumeratedValues>
                                <enumeratedValue>
                                    <name>0</name>
                                    <description>No BEMP interrupt occurred</description>
                                    <value>#0</value>
                                </enumeratedValue>
                                <enumeratedValue>
                                    <name>1</name>
                                    <description>BEMP interrupt occurred</description>
                                    <value>#1</value>
                                </enumeratedValue>
                            </enumeratedValues>
                        </field>
                        <field>
                            <name>CTRT</name>
                            <description>Control Transfer Stage Transition Interrupt Status Flag</description>
                            <lsb>11</lsb>
                            <msb>11</msb>
                            <access>read-write</access>
                            <enumeratedValues>
                                <enumeratedValue>
                                    <name>0</name>
                                    <description>No control transfer stage transition interrupt occurred</description>
                                    <value>#0</value>
                                </enumeratedValue>
                                <enumeratedValue>
                                    <name>1</name>
                                    <description>Control transfer stage transition interrupt occurred</description>
                                    <value>#1</value>
                                </enumeratedValue>
                            </enumeratedValues>
                        </field>
                        <field>
                            <name>DVST</name>
                            <description>Device State Transition Interrupt Status Flag</description>
                            <lsb>12</lsb>
                            <msb>12</msb>
                            <access>read-write</access>
                            <enumeratedValues>
                                <enumeratedValue>
                                    <name>0</name>
                                    <description>No device state transition interrupt occurred</description>
                                    <value>#0</value>
                                </enumeratedValue>
                                <enumeratedValue>
                                    <name>1</name>
                                    <description>Device state transition interrupt occurred</description>
                                    <value>#1</value>
                                </enumeratedValue>
                            </enumeratedValues>
                        </field>
                        <field>
                            <name>SOFR</name>
                            <description>Frame Number Refresh Interrupt Status Flag</description>
                            <lsb>13</lsb>
                            <msb>13</msb>
                            <access>read-write</access>
                            <enumeratedValues>
                                <enumeratedValue>
                                    <name>0</name>
                                    <description>No SOF interrupt occurred</description>
                                    <value>#0</value>
                                </enumeratedValue>
                                <enumeratedValue>
                                    <name>1</name>
                                    <description>SOF interrupt occurred</description>
                                    <value>#1</value>
                                </enumeratedValue>
                            </enumeratedValues>
                        </field>
                        <field>
                            <name>RESM</name>
                            <description>Resume Interrupt Status Flag</description>
                            <lsb>14</lsb>
                            <msb>14</msb>
                            <access>read-write</access>
                            <enumeratedValues>
                                <enumeratedValue>
                                    <name>0</name>
                                    <description>No resume interrupt occurred</description>
                                    <value>#0</value>
                                </enumeratedValue>
                                <enumeratedValue>
                                    <name>1</name>
                                    <description>Resume interrupt occurred</description>
                                    <value>#1</value>
                                </enumeratedValue>
                            </enumeratedValues>
                        </field>
                        <field>
                            <name>VBINT</name>
                            <description>VBUS Interrupt Status Flag</description>
                            <lsb>15</lsb>
                            <msb>15</msb>
                            <access>read-write</access>
                            <enumeratedValues>
                                <enumeratedValue>
                                    <name>0</name>
                                    <description>No VBUS interrupt occurred on detecting a change in the USBHS_VBUS pin</description>
                                    <value>#0</value>
                                </enumeratedValue>
                                <enumeratedValue>
                                    <name>1</name>
                                    <description>VBUS interrupt occurred on detecting a change in the USBHS_VBUS pin</description>
                                    <value>#1</value>
                                </enumeratedValue>
                            </enumeratedValues>
                        </field>
                    </fields>
                </register>
                <register>
                    <name>INTSTS1</name>
                    <description>Interrupt Status Register 1</description>
                    <addressOffset>0x042</addressOffset>
                    <size>16</size>
                    <access>read-write</access>
                    <resetValue>0x0000</resetValue>
                    <resetMask>0xdb71</resetMask>
                    <fields>
                        <field>
                            <name>PDDETINT</name>
                            <description>PDDET Detection Interrupt Status Flag</description>
                            <lsb>0</lsb>
                            <msb>0</msb>
                            <access>read-write</access>
                            <enumeratedValues>
                                <enumeratedValue>
                                    <name>0</name>
                                    <description>No PDDET interrupt occurred</description>
                                    <value>#0</value>
                                </enumeratedValue>
                                <enumeratedValue>
                                    <name>1</name>
                                    <description>PDDET interrupt occurred</description>
                                    <value>#1</value>
                                </enumeratedValue>
                            </enumeratedValues>
                        </field>
                        <field>
                            <name>SACK</name>
                            <description>Setup Transaction Normal Response Interrupt Status Flag</description>
                            <lsb>4</lsb>
                            <msb>4</msb>
                            <access>read-write</access>
                            <enumeratedValues>
                                <enumeratedValue>
                                    <name>0</name>
                                    <description>No SACK interrupt occurred</description>
                                    <value>#0</value>
                                </enumeratedValue>
                                <enumeratedValue>
                                    <name>1</name>
                                    <description>SACK interrupt occurred</description>
                                    <value>#1</value>
                                </enumeratedValue>
                            </enumeratedValues>
                        </field>
                        <field>
                            <name>SIGN</name>
                            <description>Setup Transaction Error Interrupt Status Flag</description>
                            <lsb>5</lsb>
                            <msb>5</msb>
                            <access>read-write</access>
                            <enumeratedValues>
                                <enumeratedValue>
                                    <name>0</name>
                                    <description>No SIGN interrupt occurred</description>
                                    <value>#0</value>
                                </enumeratedValue>
                                <enumeratedValue>
                                    <name>1</name>
                                    <description>SIGN interrupt occurred</description>
                                    <value>#1</value>
                                </enumeratedValue>
                            </enumeratedValues>
                        </field>
                        <field>
                            <name>EOFERR</name>
                            <description>EOF Error Detection Interrupt Status Flag</description>
                            <lsb>6</lsb>
                            <msb>6</msb>
                            <access>read-write</access>
                            <enumeratedValues>
                                <enumeratedValue>
                                    <name>0</name>
                                    <description>No EOFERR interrupt occurred</description>
                                    <value>#0</value>
                                </enumeratedValue>
                                <enumeratedValue>
                                    <name>1</name>
                                    <description>EOFERR interrupt occurred</description>
                                    <value>#1</value>
                                </enumeratedValue>
                            </enumeratedValues>
                        </field>
                        <field>
                            <name>LPMEND</name>
                            <description>LPM Transaction End Interrupt Status Flag</description>
                            <lsb>8</lsb>
                            <msb>8</msb>
                            <access>read-write</access>
                            <enumeratedValues>
                                <enumeratedValue>
                                    <name>0</name>
                                    <description>No LPMEND interrupt occurred</description>
                                    <value>#0</value>
                                </enumeratedValue>
                                <enumeratedValue>
                                    <name>1</name>
                                    <description>LPMEND interrupt occurred</description>
                                    <value>#1</value>
                                </enumeratedValue>
                            </enumeratedValues>
                        </field>
                        <field>
                            <name>L1RSMEND</name>
                            <description>L1 Resume End Interrupt Status Flag</description>
                            <lsb>9</lsb>
                            <msb>9</msb>
                            <access>read-write</access>
                            <enumeratedValues>
                                <enumeratedValue>
                                    <name>0</name>
                                    <description>No L1RSMEND interrupt occurred</description>
                                    <value>#0</value>
                                </enumeratedValue>
                                <enumeratedValue>
                                    <name>1</name>
                                    <description>L1RSMEND interrupt occurred</description>
                                    <value>#1</value>
                                </enumeratedValue>
                            </enumeratedValues>
                        </field>
                        <field>
                            <name>ATTCH</name>
                            <description>USB Connection Detection Interrupt Status Flag</description>
                            <lsb>11</lsb>
                            <msb>11</msb>
                            <access>read-write</access>
                            <enumeratedValues>
                                <enumeratedValue>
                                    <name>0</name>
                                    <description>No ATTCH interrupt occurred</description>
                                    <value>#0</value>
                                </enumeratedValue>
                                <enumeratedValue>
                                    <name>1</name>
                                    <description>ATTCH interrupt occurred</description>
                                    <value>#1</value>
                                </enumeratedValue>
                            </enumeratedValues>
                        </field>
                        <field>
                            <name>DTCH</name>
                            <description>USB Disconnection Detection Interrupt Status Flag</description>
                            <lsb>12</lsb>
                            <msb>12</msb>
                            <access>read-write</access>
                            <enumeratedValues>
                                <enumeratedValue>
                                    <name>0</name>
                                    <description>No DTCH interrupt occurred</description>
                                    <value>#0</value>
                                </enumeratedValue>
                                <enumeratedValue>
                                    <name>1</name>
                                    <description>DTCH interrupt occurred</description>
                                    <value>#1</value>
                                </enumeratedValue>
                            </enumeratedValues>
                        </field>
                        <field>
                            <name>BCHG</name>
                            <description>USB Bus Change Interrupt Status Flag</description>
                            <lsb>14</lsb>
                            <msb>14</msb>
                            <access>read-write</access>
                            <enumeratedValues>
                                <enumeratedValue>
                                    <name>0</name>
                                    <description>No BCHG interrupt occurred</description>
                                    <value>#0</value>
                                </enumeratedValue>
                                <enumeratedValue>
                                    <name>1</name>
                                    <description>BCHG interrupt occurred</description>
                                    <value>#1</value>
                                </enumeratedValue>
                            </enumeratedValues>
                        </field>
                        <field>
                            <name>OVRCR</name>
                            <description>OVRCR Interrupt Status Flag</description>
                            <lsb>15</lsb>
                            <msb>15</msb>
                            <access>read-write</access>
                            <enumeratedValues>
                                <enumeratedValue>
                                    <name>0</name>
                                    <description>No OVRCR interrupt occurred</description>
                                    <value>#0</value>
                                </enumeratedValue>
                                <enumeratedValue>
                                    <name>1</name>
                                    <description>OVRCR interrupt occurred</description>
                                    <value>#1</value>
                                </enumeratedValue>
                            </enumeratedValues>
                        </field>
                    </fields>
                </register>
                <register>
                    <name>BRDYSTS</name>
                    <description>BRDY Interrupt Status Register</description>
                    <addressOffset>0x046</addressOffset>
                    <size>16</size>
                    <access>read-write</access>
                    <resetValue>0x0000</resetValue>
                    <resetMask>0xffff</resetMask>
                    <fields>
                        <field>
                            <name>PIPEBRDY</name>
                            <description>BRDY Interrupt Status Flag for Pipe[9:0]</description>
                            <lsb>0</lsb>
                            <msb>9</msb>
                            <access>read-write</access>
                            <enumeratedValues>
                                <enumeratedValue>
                                    <name>0</name>
                                    <description>No BRDY interrupt occurred</description>
                                    <value>#0</value>
                                </enumeratedValue>
                                <enumeratedValue>
                                    <name>1</name>
                                    <description>BRDY interrupt occurred</description>
                                    <value>#1</value>
                                </enumeratedValue>
                            </enumeratedValues>
                        </field>
                    </fields>
                </register>
                <register>
                    <name>NRDYSTS</name>
                    <description>NRDY Interrupt Status Register</description>
                    <addressOffset>0x048</addressOffset>
                    <size>16</size>
                    <access>read-write</access>
                    <resetValue>0x0000</resetValue>
                    <resetMask>0xffff</resetMask>
                    <fields>
                        <field>
                            <name>PIPENRDY</name>
                            <description>NRDY Interrupt Status Flag for Pipe[9:0]</description>
                            <lsb>0</lsb>
                            <msb>9</msb>
                            <access>read-write</access>
                            <enumeratedValues>
                                <enumeratedValue>
                                    <name>0</name>
                                    <description>No NRDY interrupt occurred</description>
                                    <value>#0</value>
                                </enumeratedValue>
                                <enumeratedValue>
                                    <name>1</name>
                                    <description>NRDY interrupt occurred.</description>
                                    <value>#1</value>
                                </enumeratedValue>
                            </enumeratedValues>
                        </field>
                    </fields>
                </register>
                <register>
                    <name>BEMPSTS</name>
                    <description>BEMP Interrupt Status Register</description>
                    <addressOffset>0x04A</addressOffset>
                    <size>16</size>
                    <access>read-write</access>
                    <resetValue>0x0000</resetValue>
                    <resetMask>0xffff</resetMask>
                    <fields>
                        <field>
                            <name>PIPEBEMP</name>
                            <description>BEMP Interrupt Status Flag for Pipe[9:0]</description>
                            <lsb>0</lsb>
                            <msb>9</msb>
                            <access>read-write</access>
                            <enumeratedValues>
                                <enumeratedValue>
                                    <name>0</name>
                                    <description>No BEMP interrupt occurred</description>
                                    <value>#0</value>
                                </enumeratedValue>
                                <enumeratedValue>
                                    <name>1</name>
                                    <description>BEMP interrupt occurred.</description>
                                    <value>#1</value>
                                </enumeratedValue>
                            </enumeratedValues>
                        </field>
                    </fields>
                </register>
                <register>
                    <name>FRMNUM</name>
                    <description>Frame Number Register</description>
                    <addressOffset>0x04C</addressOffset>
                    <size>16</size>
                    <access>read-write</access>
                    <resetValue>0x0000</resetValue>
                    <resetMask>0xffff</resetMask>
                    <fields>
                        <field>
                            <name>FRNM</name>
                            <description>Frame Number Flag</description>
                            <lsb>0</lsb>
                            <msb>10</msb>
                            <access>read-only</access>
                        </field>
                        <field>
                            <name>CRCE</name>
                            <description>CRC Error Detection Status Flag</description>
                            <lsb>14</lsb>
                            <msb>14</msb>
                            <access>read-write</access>
                            <enumeratedValues>
                                <enumeratedValue>
                                    <name>0</name>
                                    <description>No error occurred</description>
                                    <value>#0</value>
                                </enumeratedValue>
                                <enumeratedValue>
                                    <name>1</name>
                                    <description>Error occurred</description>
                                    <value>#1</value>
                                </enumeratedValue>
                            </enumeratedValues>
                        </field>
                        <field>
                            <name>OVRN</name>
                            <description>Overrun/Underrun Detection Status Flag</description>
                            <lsb>15</lsb>
                            <msb>15</msb>
                            <access>read-write</access>
                            <enumeratedValues>
                                <enumeratedValue>
                                    <name>0</name>
                                    <description>No error occurred</description>
                                    <value>#0</value>
                                </enumeratedValue>
                                <enumeratedValue>
                                    <name>1</name>
                                    <description>Error occurred.</description>
                                    <value>#1</value>
                                </enumeratedValue>
                            </enumeratedValues>
                        </field>
                    </fields>
                </register>
                <register>
                    <name>UFRMNUM</name>
                    <description>µFrame Number Register</description>
                    <addressOffset>0x04E</addressOffset>
                    <size>16</size>
                    <access>read-write</access>
                    <resetValue>0x0000</resetValue>
                    <resetMask>0x8007</resetMask>
                    <fields>
                        <field>
                            <name>UFRNM</name>
                            <description>Microframe number</description>
                            <lsb>0</lsb>
                            <msb>2</msb>
                            <access>read-only</access>
                        </field>
                        <field>
                            <name>DVCHG</name>
                            <description>Device State Change</description>
                            <lsb>15</lsb>
                            <msb>15</msb>
                            <access>read-write</access>
                            <enumeratedValues>
                                <enumeratedValue>
                                    <name>0</name>
                                    <description>Disable writes to the USBADDR.STSRECOV0[2:0] and USBADDR.USBADDR[6:0] bits</description>
                                    <value>#0</value>
                                </enumeratedValue>
                                <enumeratedValue>
                                    <name>1</name>
                                    <description>Enable writes to the USBADDR.STSRECOV0[2:0] and USBADDR.USBADDR[6:0] bits</description>
                                    <value>#1</value>
                                </enumeratedValue>
                            </enumeratedValues>
                        </field>
                    </fields>
                </register>
                <register>
                    <name>USBADDR</name>
                    <description>USB Address Register</description>
                    <addressOffset>0x050</addressOffset>
                    <size>16</size>
                    <access>read-write</access>
                    <resetValue>0x0000</resetValue>
                    <resetMask>0x077f</resetMask>
                    <fields>
                        <field>
                            <name>USBADDR</name>
                            <description>USB Address Flag</description>
                            <lsb>0</lsb>
                            <msb>6</msb>
                            <access>read-only</access>
                        </field>
                        <field>
                            <name>STSRECOV0</name>
                            <description>Status Recovery</description>
                            <lsb>8</lsb>
                            <msb>10</msb>
                            <access>read-write</access>
                            <enumeratedValues>
                                <enumeratedValue>
                                    <name>000</name>
                                    <description>Reserved</description>
                                    <value>#000</value>
                                </enumeratedValue>
                                <enumeratedValue>
                                    <name>001</name>
                                    <description>[D] Return to the full-speed connection and Default state</description>
                                    <value>#001</value>
                                </enumeratedValue>
                                <enumeratedValue>
                                    <name>010</name>
                                    <description>[D] Return to the full-speed connection and Address state [H] Return to the low-speed state (bits DVSTCTR0.RHST[2:0] = 001b) </description>
                                    <value>#010</value>
                                </enumeratedValue>
                                <enumeratedValue>
                                    <name>011</name>
                                    <description>[D] Return to the full-speed connection and Configured state</description>
                                    <value>#011</value>
                                </enumeratedValue>
                                <enumeratedValue>
                                    <name>100</name>
                                    <description>[D] Return to the suspend connection and Suspend state [H] Return to the full-speed state (bits DVSTCTR0.RHST[2:0] = 010b) </description>
                                    <value>#100</value>
                                </enumeratedValue>
                                <enumeratedValue>
                                    <name>101</name>
                                    <description>[D] Return to the high-speed connection and Default state</description>
                                    <value>#101</value>
                                </enumeratedValue>
                                <enumeratedValue>
                                    <name>110</name>
                                    <description>[D] Return to the high-speed connection and Address state [H] Return to the high-speed state (bits DVSTCTR0.RHST[2:0] = 011b) </description>
                                    <value>#110</value>
                                </enumeratedValue>
                                <enumeratedValue>
                                    <name>111</name>
                                    <description>[D] Return to the high-speed connection and Configured state</description>
                                    <value>#111</value>
                                </enumeratedValue>
                            </enumeratedValues>
                        </field>
                    </fields>
                </register>
                <register>
                    <name>USBREQ</name>
                    <description>USB Request Type Register</description>
                    <addressOffset>0x054</addressOffset>
                    <size>16</size>
                    <access>read-write</access>
                    <resetValue>0x0000</resetValue>
                    <resetMask>0xffff</resetMask>
                    <fields>
                        <field>
                            <name>BMREQUESTTYPE</name>
                            <description>USB request bmRequestType value</description>
                            <lsb>0</lsb>
                            <msb>7</msb>
                            <access>read-write</access>
                        </field>
                        <field>
                            <name>BREQUEST</name>
                            <description>USB request bRequest value</description>
                            <lsb>8</lsb>
                            <msb>15</msb>
                            <access>read-write</access>
                        </field>
                    </fields>
                </register>
                <register>
                    <name>USBVAL</name>
                    <description>USB Request Value Register</description>
                    <addressOffset>0x056</addressOffset>
                    <size>16</size>
                    <access>read-write</access>
                    <resetValue>0x0000</resetValue>
                    <resetMask>0xffff</resetMask>
                    <fields>
                        <field>
                            <name>WVALUE</name>
                            <description>USB request wValue value</description>
                            <lsb>0</lsb>
                            <msb>15</msb>
                            <access>read-write</access>
                        </field>
                    </fields>
                </register>
                <register>
                    <name>USBINDX</name>
                    <description>USB Request Index Register</description>
                    <addressOffset>0x058</addressOffset>
                    <size>16</size>
                    <access>read-write</access>
                    <resetValue>0x0000</resetValue>
                    <resetMask>0xffff</resetMask>
                    <fields>
                        <field>
                            <name>WINDEX</name>
                            <description>USB request wIndex value</description>
                            <lsb>0</lsb>
                            <msb>15</msb>
                            <access>read-write</access>
                        </field>
                    </fields>
                </register>
                <register>
                    <name>USBLENG</name>
                    <description>USB Request Length Register</description>
                    <addressOffset>0x05A</addressOffset>
                    <size>16</size>
                    <access>read-write</access>
                    <resetValue>0x0000</resetValue>
                    <resetMask>0xffff</resetMask>
                    <fields>
                        <field>
                            <name>WLENTUH</name>
                            <description>USB request wLength value</description>
                            <lsb>0</lsb>
                            <msb>15</msb>
                            <access>read-write</access>
                        </field>
                    </fields>
                </register>
                <register>
                    <name>DCPCFG</name>
                    <description>DCP Configuration Register</description>
                    <addressOffset>0x05C</addressOffset>
                    <size>16</size>
                    <access>read-write</access>
                    <resetValue>0x0000</resetValue>
                    <resetMask>0xffff</resetMask>
                    <fields>
                        <field>
                            <name>DIR</name>
                            <description>Transfer Direction</description>
                            <lsb>4</lsb>
                            <msb>4</msb>
                            <access>read-write</access>
                            <enumeratedValues>
                                <enumeratedValue>
                                    <name>0</name>
                                    <description>Data receiving direction</description>
                                    <value>#0</value>
                                </enumeratedValue>
                                <enumeratedValue>
                                    <name>1</name>
                                    <description>Data transmitting direction</description>
                                    <value>#1</value>
                                </enumeratedValue>
                            </enumeratedValues>
                        </field>
                        <field>
                            <name>SHTNAK</name>
                            <description>Pipe Blocking on End of Transfer</description>
                            <lsb>7</lsb>
                            <msb>7</msb>
                            <access>read-write</access>
                            <enumeratedValues>
                                <enumeratedValue>
                                    <name>0</name>
                                    <description>Keep pipe open after transfer ends</description>
                                    <value>#0</value>
                                </enumeratedValue>
                                <enumeratedValue>
                                    <name>1</name>
                                    <description>Disable pipe after transfer ends</description>
                                    <value>#1</value>
                                </enumeratedValue>
                            </enumeratedValues>
                        </field>
                        <field>
                            <name>CNTMD</name>
                            <description>Continuous Transfer Mode</description>
                            <lsb>8</lsb>
                            <msb>8</msb>
                            <access>read-write</access>
                            <enumeratedValues>
                                <enumeratedValue>
                                    <name>0</name>
                                    <description>Non-continuous transfer mode</description>
                                    <value>#0</value>
                                </enumeratedValue>
                                <enumeratedValue>
                                    <name>1</name>
                                    <description>Continuous transfer mode</description>
                                    <value>#1</value>
                                </enumeratedValue>
                            </enumeratedValues>
                        </field>
                    </fields>
                </register>
                <register>
                    <name>DCPMAXP</name>
                    <description>DCP Maximum Packet Size Register</description>
                    <addressOffset>0x05E</addressOffset>
                    <size>16</size>
                    <access>read-write</access>
                    <resetValue>0x0040</resetValue>
                    <resetMask>0xf07f</resetMask>
                    <fields>
                        <field>
                            <name>MXPS</name>
                            <description>Maximum Packet Size</description>
                            <lsb>0</lsb>
                            <msb>6</msb>
                            <access>read-write</access>
                        </field>
                        <field>
                            <name>DEVSEL</name>
                            <description>Device Select</description>
                            <lsb>12</lsb>
                            <msb>15</msb>
                            <access>read-write</access>
                            <enumeratedValues>
                                <enumeratedValue>
                                    <name>0x0</name>
                                    <description>Address 0x0</description>
                                    <value>0x0</value>
                                </enumeratedValue>
                                <enumeratedValue>
                                    <name>0x1</name>
                                    <description>Address 0x1</description>
                                    <value>0x1</value>
                                </enumeratedValue>
                                <enumeratedValue>
                                    <name>0x2</name>
                                    <description>Address 0x2</description>
                                    <value>0x2</value>
                                </enumeratedValue>
                                <enumeratedValue>
                                    <name>0x3</name>
                                    <description>Address 0x3</description>
                                    <value>0x3</value>
                                </enumeratedValue>
                                <enumeratedValue>
                                    <name>0x4</name>
                                    <description>Address 0x4</description>
                                    <value>0x4</value>
                                </enumeratedValue>
                                <enumeratedValue>
                                    <name>0x5</name>
                                    <description>Address 0x5</description>
                                    <value>0x5</value>
                                </enumeratedValue>
                            </enumeratedValues>
                        </field>
                    </fields>
                </register>
                <register>
                    <name>DCPCTR</name>
                    <description>DCP Control Register</description>
                    <addressOffset>0x060</addressOffset>
                    <size>16</size>
                    <access>read-write</access>
                    <resetValue>0x0040</resetValue>
                    <resetMask>0xf1f7</resetMask>
                    <fields>
                        <field>
                            <name>PID</name>
                            <description>Response PID</description>
                            <lsb>0</lsb>
                            <msb>1</msb>
                            <access>read-write</access>
                            <enumeratedValues>
                                <enumeratedValue>
                                    <name>00</name>
                                    <description>NAK response</description>
                                    <value>#00</value>
                                </enumeratedValue>
                                <enumeratedValue>
                                    <name>01</name>
                                    <description>BUF response (depends on buffer state)</description>
                                    <value>#01</value>
                                </enumeratedValue>
                                <enumeratedValue>
                                    <name>10</name>
                                    <description>STALL response</description>
                                    <value>#10</value>
                                </enumeratedValue>
                                <enumeratedValue>
                                    <name>10</name>
                                    <description>STALL response</description>
                                    <value>#10</value>
                                </enumeratedValue>
                            </enumeratedValues>
                        </field>
                        <field>
                            <name>CCPL</name>
                            <description>Control Transfer End Enable</description>
                            <lsb>2</lsb>
                            <msb>2</msb>
                            <access>read-write</access>
                            <enumeratedValues>
                                <enumeratedValue>
                                    <name>0</name>
                                    <description>Disable control transfer completion</description>
                                    <value>#0</value>
                                </enumeratedValue>
                                <enumeratedValue>
                                    <name>1</name>
                                    <description>Enable control transfer completion</description>
                                    <value>#1</value>
                                </enumeratedValue>
                            </enumeratedValues>
                        </field>
                        <field>
                            <name>PINGE</name>
                            <description>PING Token Issue Enable</description>
                            <lsb>4</lsb>
                            <msb>4</msb>
                            <access>read-write</access>
                            <enumeratedValues>
                                <enumeratedValue>
                                    <name>0</name>
                                    <description>Disable PING token</description>
                                    <value>#0</value>
                                </enumeratedValue>
                                <enumeratedValue>
                                    <name>1</name>
                                    <description>Enable normal PING operation</description>
                                    <value>#1</value>
                                </enumeratedValue>
                            </enumeratedValues>
                        </field>
                        <field>
                            <name>PBUSY</name>
                            <description>Pipe Busy Flag</description>
                            <lsb>5</lsb>
                            <msb>5</msb>
                            <access>read-only</access>
                            <enumeratedValues>
                                <enumeratedValue>
                                    <name>0</name>
                                    <description>DCP not used for the USB bus</description>
                                    <value>#0</value>
                                </enumeratedValue>
                                <enumeratedValue>
                                    <name>1</name>
                                    <description>DCP in use for the USB bus</description>
                                    <value>#1</value>
                                </enumeratedValue>
                            </enumeratedValues>
                        </field>
                        <field>
                            <name>SQMON</name>
                            <description>Sequence Toggle Bit Monitor Flag</description>
                            <lsb>6</lsb>
                            <msb>6</msb>
                            <access>read-only</access>
                            <enumeratedValues>
                                <enumeratedValue>
                                    <name>0</name>
                                    <description>DATA0</description>
                                    <value>#0</value>
                                </enumeratedValue>
                                <enumeratedValue>
                                    <name>1</name>
                                    <description>DATA1</description>
                                    <value>#1</value>
                                </enumeratedValue>
                            </enumeratedValues>
                        </field>
                        <field>
                            <name>SQSET</name>
                            <description>Sequence Toggle Bit Set</description>
                            <lsb>7</lsb>
                            <msb>7</msb>
                            <access>write-only</access>
                            <enumeratedValues>
                                <enumeratedValue>
                                    <name>0</name>
                                    <description>Invalid (writing 0 has no effect)</description>
                                    <value>#0</value>
                                </enumeratedValue>
                                <enumeratedValue>
                                    <name>1</name>
                                    <description>Set the expected value for the next transaction to DATA1</description>
                                    <value>#1</value>
                                </enumeratedValue>
                            </enumeratedValues>
                        </field>
                        <field>
                            <name>SQCLR</name>
                            <description>Sequence Toggle Bit Clear</description>
                            <lsb>8</lsb>
                            <msb>8</msb>
                            <access>write-only</access>
                            <enumeratedValues>
                                <enumeratedValue>
                                    <name>0</name>
                                    <description>Invalid (writing 0 has no effect)</description>
                                    <value>#0</value>
                                </enumeratedValue>
                                <enumeratedValue>
                                    <name>1</name>
                                    <description>Clear the expected value for the next transaction to DATA0</description>
                                    <value>#1</value>
                                </enumeratedValue>
                            </enumeratedValues>
                        </field>
                        <field>
                            <name>SUREQCLR</name>
                            <description>SUREQ Bit Clear</description>
                            <lsb>11</lsb>
                            <msb>11</msb>
                            <access>write-only</access>
                            <enumeratedValues>
                                <enumeratedValue>
                                    <name>0</name>
                                    <description>Invalid (writing 0 has no effect)</description>
                                    <value>#0</value>
                                </enumeratedValue>
                                <enumeratedValue>
                                    <name>1</name>
                                    <description>Clear SUREQ to 0</description>
                                    <value>#1</value>
                                </enumeratedValue>
                            </enumeratedValues>
                        </field>
                        <field>
                            <name>CSSTS</name>
                            <description>CSSTS Status Flag</description>
                            <lsb>12</lsb>
                            <msb>12</msb>
                            <access>read-only</access>
                            <enumeratedValues>
                                <enumeratedValue>
                                    <name>0</name>
                                    <description>Start-split (SSPLIT) transaction, or processing for devices that are not using split transactions, in progress</description>
                                    <value>#0</value>
                                </enumeratedValue>
                                <enumeratedValue>
                                    <name>1</name>
                                    <description>Complete-split (CSPLIT) transaction in progress</description>
                                    <value>#1</value>
                                </enumeratedValue>
                            </enumeratedValues>
                        </field>
                        <field>
                            <name>CSCLR</name>
                            <description>CSSTS Status Flag Clear</description>
                            <lsb>13</lsb>
                            <msb>13</msb>
                            <access>write-only</access>
                            <enumeratedValues>
                                <enumeratedValue>
                                    <name>0</name>
                                    <description>(writing 0 has no effect)</description>
                                    <value>#0</value>
                                </enumeratedValue>
                                <enumeratedValue>
                                    <name>1</name>
                                    <description>Clear CSSTS to 0</description>
                                    <value>#1</value>
                                </enumeratedValue>
                            </enumeratedValues>
                        </field>
                        <field>
                            <name>SUREQ</name>
                            <description>SETUP Token Transmission</description>
                            <lsb>14</lsb>
                            <msb>14</msb>
                            <access>read-write</access>
                            <enumeratedValues>
                                <enumeratedValue>
                                    <name>0</name>
                                    <description>Invalid (writing 0 has no effect)</description>
                                    <value>#0</value>
                                </enumeratedValue>
                                <enumeratedValue>
                                    <name>1</name>
                                    <description>Transmit setup packet</description>
                                    <value>#1</value>
                                </enumeratedValue>
                            </enumeratedValues>
                        </field>
                        <field>
                            <name>BSTS</name>
                            <description>Buffer Status Flag</description>
                            <lsb>15</lsb>
                            <msb>15</msb>
                            <access>read-only</access>
                            <enumeratedValues>
                                <enumeratedValue>
                                    <name>0</name>
                                    <description>Buffer access disabled</description>
                                    <value>#0</value>
                                </enumeratedValue>
                                <enumeratedValue>
                                    <name>1</name>
                                    <description>Buffer access enabled</description>
                                    <value>#1</value>
                                </enumeratedValue>
                            </enumeratedValues>
                        </field>
                    </fields>
                </register>
                <register>
                    <name>PIPESEL</name>
                    <description>Pipe Window Select Register</description>
                    <addressOffset>0x064</addressOffset>
                    <size>16</size>
                    <access>read-write</access>
                    <resetValue>0x0000</resetValue>
                    <resetMask>0x000f</resetMask>
                    <fields>
                        <field>
                            <name>PIPESEL</name>
                            <description>Pipe Window Select</description>
                            <lsb>0</lsb>
                            <msb>3</msb>
                            <access>read-write</access>
                            <enumeratedValues>
                                <enumeratedValue>
                                    <name>0x0</name>
                                    <description>No pipe selected</description>
                                    <value>0x0</value>
                                </enumeratedValue>
                                <enumeratedValue>
                                    <name>0x1</name>
                                    <description>Pipe 1</description>
                                    <value>0x1</value>
                                </enumeratedValue>
                                <enumeratedValue>
                                    <name>0x2</name>
                                    <description>Pipe 2</description>
                                    <value>0x2</value>
                                </enumeratedValue>
                                <enumeratedValue>
                                    <name>0x3</name>
                                    <description>Pipe 3</description>
                                    <value>0x3</value>
                                </enumeratedValue>
                                <enumeratedValue>
                                    <name>0x4</name>
                                    <description>Pipe 4</description>
                                    <value>0x4</value>
                                </enumeratedValue>
                                <enumeratedValue>
                                    <name>0x5</name>
                                    <description>Pipe 5</description>
                                    <value>0x5</value>
                                </enumeratedValue>
                                <enumeratedValue>
                                    <name>0x6</name>
                                    <description>Pipe 6</description>
                                    <value>0x6</value>
                                </enumeratedValue>
                                <enumeratedValue>
                                    <name>0x7</name>
                                    <description>Pipe 7</description>
                                    <value>0x7</value>
                                </enumeratedValue>
                                <enumeratedValue>
                                    <name>0x8</name>
                                    <description>Pipe 8</description>
                                    <value>0x8</value>
                                </enumeratedValue>
                                <enumeratedValue>
                                    <name>0x9</name>
                                    <description>Pipe 9</description>
                                    <value>0x9</value>
                                </enumeratedValue>
                                <enumeratedValue>
                                    <name>Others</name>
                                    <description>Setting prohibited</description>
                                    <isDefault>true</isDefault>
                                </enumeratedValue>
                            </enumeratedValues>
                        </field>
                    </fields>
                </register>
                <register>
                    <name>PIPECFG</name>
                    <description>Pipe Configuration Register</description>
                    <addressOffset>0x068</addressOffset>
                    <size>16</size>
                    <access>read-write</access>
                    <resetValue>0x0000</resetValue>
                    <resetMask>0xc79f</resetMask>
                    <fields>
                        <field>
                            <name>EPNUM</name>
                            <description>Endpoint Number</description>
                            <lsb>0</lsb>
                            <msb>3</msb>
                            <access>read-write</access>
                        </field>
                        <field>
                            <name>DIR</name>
                            <description>Transfer Direction</description>
                            <lsb>4</lsb>
                            <msb>4</msb>
                            <access>read-write</access>
                            <enumeratedValues>
                                <enumeratedValue>
                                    <name>0</name>
                                    <description>Receiving direction</description>
                                    <value>#0</value>
                                </enumeratedValue>
                                <enumeratedValue>
                                    <name>1</name>
                                    <description>Transmitting direction</description>
                                    <value>#1</value>
                                </enumeratedValue>
                            </enumeratedValues>
                        </field>
                        <field>
                            <name>SHTNAK</name>
                            <description>Pipe Disabled at End of Transfer</description>
                            <lsb>7</lsb>
                            <msb>7</msb>
                            <access>read-write</access>
                            <enumeratedValues>
                                <enumeratedValue>
                                    <name>0</name>
                                    <description>Continue pipe operation after transfer ends</description>
                                    <value>#0</value>
                                </enumeratedValue>
                                <enumeratedValue>
                                    <name>1</name>
                                    <description>Disable pipe after transfer ends</description>
                                    <value>#1</value>
                                </enumeratedValue>
                            </enumeratedValues>
                        </field>
                        <field>
                            <name>CNTMD</name>
                            <description>Continuous Transfer Mode</description>
                            <lsb>8</lsb>
                            <msb>8</msb>
                            <access>read-write</access>
                            <enumeratedValues>
                                <enumeratedValue>
                                    <name>0</name>
                                    <description>Discontinuous transfer mode</description>
                                    <value>#0</value>
                                </enumeratedValue>
                                <enumeratedValue>
                                    <name>1</name>
                                    <description>Continuous transfer mode</description>
                                    <value>#1</value>
                                </enumeratedValue>
                            </enumeratedValues>
                        </field>
                        <field>
                            <name>DBLB</name>
                            <description>Double Buffer Mode</description>
                            <lsb>9</lsb>
                            <msb>9</msb>
                            <access>read-write</access>
                            <enumeratedValues>
                                <enumeratedValue>
                                    <name>0</name>
                                    <description>Single buffer</description>
                                    <value>#0</value>
                                </enumeratedValue>
                                <enumeratedValue>
                                    <name>1</name>
                                    <description>Double buffer</description>
                                    <value>#1</value>
                                </enumeratedValue>
                            </enumeratedValues>
                        </field>
                        <field>
                            <name>BFRE</name>
                            <description>BRDY Interrupt Operation Specification</description>
                            <lsb>10</lsb>
                            <msb>10</msb>
                            <access>read-write</access>
                            <enumeratedValues>
                                <enumeratedValue>
                                    <name>0</name>
                                    <description>Generate BRDY interrupt on transmitting or receiving data</description>
                                    <value>#0</value>
                                </enumeratedValue>
                                <enumeratedValue>
                                    <name>1</name>
                                    <description>Generate BRDY interrupt on completion of reading data</description>
                                    <value>#1</value>
                                </enumeratedValue>
                            </enumeratedValues>
                        </field>
                        <field>
                            <name>TYPE</name>
                            <description>Transfer Type</description>
                            <lsb>14</lsb>
                            <msb>15</msb>
                            <access>read-write</access>
                            <enumeratedValues>
                                <enumeratedValue>
                                    <name>00</name>
                                    <description>Pipe not used</description>
                                    <value>#00</value>
                                </enumeratedValue>
                                <enumeratedValue>
                                    <name>01</name>
                                    <description>(Pipe 1 to 5) Bulk transfer (Pipe 6 to 9) Setting prohibited </description>
                                    <value>#01</value>
                                </enumeratedValue>
                                <enumeratedValue>
                                    <name>10</name>
                                    <description>(Pipe 1 to 5) Setting prohibited (Pipe 6 to 9) Interrupt transfer </description>
                                    <value>#10</value>
                                </enumeratedValue>
                                <enumeratedValue>
                                    <name>11</name>
                                    <description>(Pipe 1 to 2) Isochronous transfer (Pipe 3 to 9) Setting prohibited </description>
                                    <value>#11</value>
                                </enumeratedValue>
                            </enumeratedValues>
                        </field>
                    </fields>
                </register>
                <register>
                    <name>PIPEBUF</name>
                    <description>Pipe Buffer Register</description>
                    <addressOffset>0x06A</addressOffset>
                    <size>16</size>
                    <access>read-write</access>
                    <resetValue>0x0000</resetValue>
                    <resetMask>0x7cff</resetMask>
                    <fields>
                        <field>
                            <name>BUFNMB</name>
                            <description>Buffer Number</description>
                            <lsb>0</lsb>
                            <msb>7</msb>
                            <access>read-write</access>
                        </field>
                        <field>
                            <name>BUFSIZE</name>
                            <description>Buffer Size</description>
                            <lsb>10</lsb>
                            <msb>14</msb>
                            <access>read-write</access>
                        </field>
                    </fields>
                </register>
                <register>
                    <name>PIPEMAXP</name>
                    <description>Pipe Maximum Packet Size Register</description>
                    <addressOffset>0x06C</addressOffset>
                    <size>16</size>
                    <access>read-write</access>
                    <resetValue>0x0000</resetValue>
                    <resetMask>0xefff</resetMask>
                    <fields>
                        <field>
                            <name>MXPS</name>
                            <description>Maximum Packet Size</description>
                            <lsb>0</lsb>
                            <msb>10</msb>
                            <access>read-write</access>
                        </field>
                        <field>
                            <name>DEVSEL</name>
                            <description>Device Select</description>
                            <lsb>12</lsb>
                            <msb>15</msb>
                            <access>read-write</access>
                        </field>
                    </fields>
                </register>
                <register>
                    <name>PIPEPERI</name>
                    <description>Pipe Cycle Control Register</description>
                    <addressOffset>0x06E</addressOffset>
                    <size>16</size>
                    <access>read-write</access>
                    <resetValue>0x0000</resetValue>
                    <resetMask>0x1007</resetMask>
                    <fields>
                        <field>
                            <name>IITV</name>
                            <description>Interval Error Detection Interval</description>
                            <lsb>0</lsb>
                            <msb>2</msb>
                            <access>read-write</access>
                        </field>
                        <field>
                            <name>IFIS</name>
                            <description>Isochronous IN Buffer Flush</description>
                            <lsb>12</lsb>
                            <msb>12</msb>
                            <access>read-write</access>
                            <enumeratedValues>
                                <enumeratedValue>
                                    <name>0</name>
                                    <description>Do not flush buffer</description>
                                    <value>#0</value>
                                </enumeratedValue>
                                <enumeratedValue>
                                    <name>1</name>
                                    <description>Flush buffer</description>
                                    <value>#1</value>
                                </enumeratedValue>
                            </enumeratedValues>
                        </field>
                    </fields>
                </register>
                <register>
                    <dim>9</dim>
                    <dimIncrement>0x2</dimIncrement>
                    <dimIndex>1-9</dimIndex>
                    <name>PIPE%sCTR</name>
                    <description>Pipe %s Control Register</description>
                    <addressOffset>0x070</addressOffset>
                    <size>16</size>
                    <access>read-write</access>
                    <resetValue>0x0000</resetValue>
                    <resetMask>0xf7e3</resetMask>
                    <fields>
                        <field>
                            <name>PID</name>
                            <description>Response PID</description>
                            <lsb>0</lsb>
                            <msb>1</msb>
                            <access>read-write</access>
                            <enumeratedValues>
                                <enumeratedValue>
                                    <name>00</name>
                                    <description>NAK response</description>
                                    <value>#00</value>
                                </enumeratedValue>
                                <enumeratedValue>
                                    <name>01</name>
                                    <description>BUF response (depends on buffer state)</description>
                                    <value>#01</value>
                                </enumeratedValue>
                                <enumeratedValue>
                                    <name>10</name>
                                    <description>STALL response</description>
                                    <value>#10</value>
                                </enumeratedValue>
                                <enumeratedValue>
                                    <name>11</name>
                                    <description>STALL response</description>
                                    <value>#11</value>
                                </enumeratedValue>
                            </enumeratedValues>
                        </field>
                        <field>
                            <name>PBUSY</name>
                            <description>Pipe Busy Flag</description>
                            <lsb>5</lsb>
                            <msb>5</msb>
                            <access>read-only</access>
                            <enumeratedValues>
                                <enumeratedValue>
                                    <name>0</name>
                                    <description>Pipe n not in use for the transaction</description>
                                    <value>#0</value>
                                </enumeratedValue>
                                <enumeratedValue>
                                    <name>1</name>
                                    <description>Pipe n in use for the transaction</description>
                                    <value>#1</value>
                                </enumeratedValue>
                            </enumeratedValues>
                        </field>
                        <field>
                            <name>SQMON</name>
                            <description>Sequence Toggle Bit Monitor Flag</description>
                            <lsb>6</lsb>
                            <msb>6</msb>
                            <access>read-only</access>
                            <enumeratedValues>
                                <enumeratedValue>
                                    <name>0</name>
                                    <description>DATA0</description>
                                    <value>#0</value>
                                </enumeratedValue>
                                <enumeratedValue>
                                    <name>1</name>
                                    <description>DATA1</description>
                                    <value>#1</value>
                                </enumeratedValue>
                            </enumeratedValues>
                        </field>
                        <field>
                            <name>SQSET</name>
                            <description>Sequence Toggle Bit Set</description>
                            <lsb>7</lsb>
                            <msb>7</msb>
                            <access>read-write</access>
                            <enumeratedValues>
                                <enumeratedValue>
                                    <name>0</name>
                                    <description>Invalid (writing 0 has no effect)</description>
                                    <value>#0</value>
                                </enumeratedValue>
                                <enumeratedValue>
                                    <name>1</name>
                                    <description>Set the expected value for the next transaction to DATA1. This bit is read as 0. </description>
                                    <value>#1</value>
                                </enumeratedValue>
                            </enumeratedValues>
                        </field>
                        <field>
                            <name>SQCLR</name>
                            <description>Sequence Toggle Bit Clear</description>
                            <lsb>8</lsb>
                            <msb>8</msb>
                            <access>write-only</access>
                            <enumeratedValues>
                                <enumeratedValue>
                                    <name>0</name>
                                    <description>Invalid (writing 0 has no effect)</description>
                                    <value>#0</value>
                                </enumeratedValue>
                                <enumeratedValue>
                                    <name>1</name>
                                    <description>Clear the expected value for the next transaction to DATA0</description>
                                    <value>#1</value>
                                </enumeratedValue>
                            </enumeratedValues>
                        </field>
                        <field>
                            <name>ACLRM</name>
                            <description>Auto Buffer Clear Mode</description>
                            <lsb>9</lsb>
                            <msb>9</msb>
                            <access>read-write</access>
                            <enumeratedValues>
                                <enumeratedValue>
                                    <name>0</name>
                                    <description>Disable</description>
                                    <value>#0</value>
                                </enumeratedValue>
                                <enumeratedValue>
                                    <name>1</name>
                                    <description>Enable (initialize all buffers)</description>
                                    <value>#1</value>
                                </enumeratedValue>
                            </enumeratedValues>
                        </field>
                        <field>
                            <name>ATREPM</name>
                            <description>Auto Response Mode</description>
                            <lsb>10</lsb>
                            <msb>10</msb>
                            <access>read-write</access>
                            <enumeratedValues>
                                <enumeratedValue>
                                    <name>0</name>
                                    <description>Disable auto response mode</description>
                                    <value>#0</value>
                                </enumeratedValue>
                                <enumeratedValue>
                                    <name>1</name>
                                    <description>Enable auto response mode</description>
                                    <value>#1</value>
                                </enumeratedValue>
                            </enumeratedValues>
                        </field>
                        <field>
                            <name>CSSTS</name>
                            <description>CSSTS Status Flag</description>
                            <lsb>12</lsb>
                            <msb>12</msb>
                            <access>read-only</access>
                            <enumeratedValues>
                                <enumeratedValue>
                                    <name>0</name>
                                    <description>Start-split (SSPLIT) transaction, or processing for devices that are not using split transactions, in progress.</description>
                                    <value>#0</value>
                                </enumeratedValue>
                                <enumeratedValue>
                                    <name>1</name>
                                    <description>Complete-split (CSPLIT) transaction in progress.</description>
                                    <value>#1</value>
                                </enumeratedValue>
                            </enumeratedValues>
                        </field>
                        <field>
                            <name>CSCLR</name>
                            <description>CSPLIT Status Clear</description>
                            <lsb>13</lsb>
                            <msb>13</msb>
                            <access>write-only</access>
                            <enumeratedValues>
                                <enumeratedValue>
                                    <name>0</name>
                                    <description>Invalid (writing 0 has no effect)</description>
                                    <value>#0</value>
                                </enumeratedValue>
                                <enumeratedValue>
                                    <name>1</name>
                                    <description>Clear CSSTS to 0</description>
                                    <value>#1</value>
                                </enumeratedValue>
                            </enumeratedValues>
                        </field>
                        <field>
                            <name>INBUFM</name>
                            <description>Transmit Buffer Monitor Flag</description>
                            <lsb>14</lsb>
                            <msb>14</msb>
                            <access>read-only</access>
                            <enumeratedValues>
                                <enumeratedValue>
                                    <name>0</name>
                                    <description>No data to be transmitted is in the FIFO buffer</description>
                                    <value>#0</value>
                                </enumeratedValue>
                                <enumeratedValue>
                                    <name>1</name>
                                    <description>Data to be transmitted is in the FIFO buffer</description>
                                    <value>#1</value>
                                </enumeratedValue>
                            </enumeratedValues>
                        </field>
                        <field>
                            <name>BSTS</name>
                            <description>Buffer Status Flag</description>
                            <lsb>15</lsb>
                            <msb>15</msb>
                            <access>read-only</access>
                            <enumeratedValues>
                                <enumeratedValue>
                                    <name>0</name>
                                    <description>Buffer access disabled</description>
                                    <value>#0</value>
                                </enumeratedValue>
                                <enumeratedValue>
                                    <name>1</name>
                                    <description>Buffer access enabled</description>
                                    <value>#1</value>
                                </enumeratedValue>
                            </enumeratedValues>
                        </field>
                    </fields>
                </register>
                <register>
                    <dim>5</dim>
                    <dimIncrement>0x4</dimIncrement>
                    <dimIndex>1-5</dimIndex>
                    <name>PIPE%sTRE</name>
                    <description>Pipe %s Transaction Counter Enable Register</description>
                    <addressOffset>0x090</addressOffset>
                    <size>16</size>
                    <access>read-write</access>
                    <resetValue>0x0000</resetValue>
                    <resetMask>0x0300</resetMask>
                    <fields>
                        <field>
                            <name>TRCLR</name>
                            <description>Transaction Counter Clear</description>
                            <lsb>8</lsb>
                            <msb>8</msb>
                            <access>read-write</access>
                            <enumeratedValues>
                                <enumeratedValue>
                                    <name>0</name>
                                    <description>Invalid (writing 0 has no effect)</description>
                                    <value>#0</value>
                                </enumeratedValue>
                                <enumeratedValue>
                                    <name>1</name>
                                    <description>Clear current counter value</description>
                                    <value>#1</value>
                                </enumeratedValue>
                            </enumeratedValues>
                        </field>
                        <field>
                            <name>TRENB</name>
                            <description>Transaction Counter Enable</description>
                            <lsb>9</lsb>
                            <msb>9</msb>
                            <access>read-write</access>
                            <enumeratedValues>
                                <enumeratedValue>
                                    <name>0</name>
                                    <description>Disable transaction counter</description>
                                    <value>#0</value>
                                </enumeratedValue>
                                <enumeratedValue>
                                    <name>1</name>
                                    <description>Enable transaction counter</description>
                                    <value>#1</value>
                                </enumeratedValue>
                            </enumeratedValues>
                        </field>
                    </fields>
                </register>
                <register>
                    <dim>5</dim>
                    <dimIncrement>0x4</dimIncrement>
                    <dimIndex>1-5</dimIndex>
                    <name>PIPE%sTRN</name>
                    <description>Pipe %s Transaction Counter Register</description>
                    <addressOffset>0x092</addressOffset>
                    <size>16</size>
                    <access>read-write</access>
                    <resetValue>0x0000</resetValue>
                    <resetMask>0xffff</resetMask>
                    <fields>
                        <field>
                            <name>TRNCNT</name>
                            <description>Transaction Counter</description>
                            <lsb>0</lsb>
                            <msb>15</msb>
                            <access>read-write</access>
                        </field>
                    </fields>
                </register>
                <register>
                    <dim>10</dim>
                    <dimIncrement>0x2</dimIncrement>
                    <dimIndex>0-9</dimIndex>
                    <name>DEVADD%s</name>
                    <description>Device Address %s Configuration Register </description>
                    <addressOffset>0x0D0</addressOffset>
                    <size>16</size>
                    <access>read-write</access>
                    <resetValue>0x0000</resetValue>
                    <resetMask>0x7fc0</resetMask>
                    <fields>
                        <field>
                            <name>USBSPD</name>
                            <description>Transfer Speed of Communication Target Device</description>
                            <lsb>6</lsb>
                            <msb>7</msb>
                            <access>read-write</access>
                            <enumeratedValues>
                                <enumeratedValue>
                                    <name>00</name>
                                    <description>Do not use DEVADDm</description>
                                    <value>#00</value>
                                </enumeratedValue>
                                <enumeratedValue>
                                    <name>01</name>
                                    <description>Low speed</description>
                                    <value>#01</value>
                                </enumeratedValue>
                                <enumeratedValue>
                                    <name>10</name>
                                    <description>Full speed</description>
                                    <value>#10</value>
                                </enumeratedValue>
                                <enumeratedValue>
                                    <name>11</name>
                                    <description>High speed</description>
                                    <value>#11</value>
                                </enumeratedValue>
                            </enumeratedValues>
                        </field>
                        <field>
                            <name>HUBPORT</name>
                            <description>Communication Target Connecting Hub Port</description>
                            <lsb>8</lsb>
                            <msb>10</msb>
                            <access>read-write</access>
                            <enumeratedValues>
                                <enumeratedValue>
                                    <name>000</name>
                                    <description>Connect directly to the USBHS port</description>
                                    <value>#000</value>
                                </enumeratedValue>
                                <enumeratedValue>
                                    <name>Others</name>
                                    <description>Port number of the hub</description>
                                    <isDefault>true</isDefault>
                                </enumeratedValue>
                            </enumeratedValues>
                        </field>
                        <field>
                            <name>UPPHUB</name>
                            <description>Communication Target Connecting Hub Register</description>
                            <lsb>11</lsb>
                            <msb>14</msb>
                            <access>read-write</access>
                            <enumeratedValues>
                                <enumeratedValue>
                                    <name>0x0</name>
                                    <description>Connect directly to the USBHS port</description>
                                    <value>0x0</value>
                                </enumeratedValue>
                                <enumeratedValue>
                                    <name>Others</name>
                                    <description>USB address of the hub. The value as 0xB or more is reserved.</description>
                                    <isDefault>true</isDefault>
                                </enumeratedValue>
                            </enumeratedValues>
                        </field>
                    </fields>
                </register>
                <register>
                    <name>DEVADDA</name>
                    <description>Device Address A Configuration Register </description>
                    <addressOffset>0x0E4</addressOffset>
                    <size>16</size>
                    <access>read-write</access>
                    <resetValue>0x0000</resetValue>
                    <resetMask>0x7fc0</resetMask>
                    <fields>
                        <field>
                            <name>USBSPD</name>
                            <description>Transfer Speed of Communication Target Device</description>
                            <lsb>6</lsb>
                            <msb>7</msb>
                            <access>read-write</access>
                            <enumeratedValues>
                                <enumeratedValue>
                                    <name>00</name>
                                    <description>Do not use DEVADDm</description>
                                    <value>#00</value>
                                </enumeratedValue>
                                <enumeratedValue>
                                    <name>01</name>
                                    <description>Low speed</description>
                                    <value>#01</value>
                                </enumeratedValue>
                                <enumeratedValue>
                                    <name>10</name>
                                    <description>Full speed</description>
                                    <value>#10</value>
                                </enumeratedValue>
                                <enumeratedValue>
                                    <name>11</name>
                                    <description>High speed</description>
                                    <value>#11</value>
                                </enumeratedValue>
                            </enumeratedValues>
                        </field>
                        <field>
                            <name>HUBPORT</name>
                            <description>Communication Target Connecting Hub Port</description>
                            <lsb>8</lsb>
                            <msb>10</msb>
                            <access>read-write</access>
                            <enumeratedValues>
                                <enumeratedValue>
                                    <name>000</name>
                                    <description>Connect directly to the USBHS port</description>
                                    <value>#000</value>
                                </enumeratedValue>
                                <enumeratedValue>
                                    <name>Others</name>
                                    <description>Port number of the hub</description>
                                    <isDefault>true</isDefault>
                                </enumeratedValue>
                            </enumeratedValues>
                        </field>
                        <field>
                            <name>UPPHUB</name>
                            <description>Communication Target Connecting Hub Register</description>
                            <lsb>11</lsb>
                            <msb>14</msb>
                            <access>read-write</access>
                            <enumeratedValues>
                                <enumeratedValue>
                                    <name>0x0</name>
                                    <description>Connect directly to the USBHS port</description>
                                    <value>0x0</value>
                                </enumeratedValue>
                                <enumeratedValue>
                                    <name>Others</name>
                                    <description>USB address of the hub. The value as 0xB or more is reserved.</description>
                                    <isDefault>true</isDefault>
                                </enumeratedValue>
                            </enumeratedValues>
                        </field>
                    </fields>
                </register>
                <register>
                    <name>LPCTRL</name>
                    <description>Low Power Control Register</description>
                    <addressOffset>0x100</addressOffset>
                    <size>16</size>
                    <access>read-write</access>
                    <resetValue>0x0000</resetValue>
                    <resetMask>0x0181</resetMask>
                    <fields>
                        <field>
                            <name>HWUPM</name>
                            <description>Resume Return Mode Setting</description>
                            <lsb>7</lsb>
                            <msb>7</msb>
                            <access>read-write</access>
                            <enumeratedValues>
                                <enumeratedValue>
                                    <name>0</name>
                                    <description>Hardware does not recover while CPU clock inactive</description>
                                    <value>#0</value>
                                </enumeratedValue>
                                <enumeratedValue>
                                    <name>1</name>
                                    <description>Hardware recovers while CPU clock inactive</description>
                                    <value>#1</value>
                                </enumeratedValue>
                            </enumeratedValues>
                        </field>
                    </fields>
                </register>
                <register>
                    <name>LPSTS</name>
                    <description>Low Power Status Register</description>
                    <addressOffset>0x102</addressOffset>
                    <size>16</size>
                    <access>read-write</access>
                    <resetValue>0x0000</resetValue>
                    <resetMask>0x510b</resetMask>
                    <fields>
                        <field>
                            <name>SUSPENDM</name>
                            <description>UTMI SuspendM Control</description>
                            <lsb>14</lsb>
                            <msb>14</msb>
                            <access>read-write</access>
                            <enumeratedValues>
                                <enumeratedValue>
                                    <name>0</name>
                                    <description>UTMI suspension mode</description>
                                    <value>#0</value>
                                </enumeratedValue>
                                <enumeratedValue>
                                    <name>1</name>
                                    <description>UTMI normal mode</description>
                                    <value>#1</value>
                                </enumeratedValue>
                            </enumeratedValues>
                        </field>
                    </fields>
                </register>
                <register>
                    <name>BCCTRL</name>
                    <description>Battery Charging Control Register</description>
                    <addressOffset>0x140</addressOffset>
                    <size>16</size>
                    <access>read-write</access>
                    <resetValue>0x0000</resetValue>
                    <resetMask>0x033f</resetMask>
                    <fields>
                        <field>
                            <name>IDPSRCE</name>
                            <description>IDPSRC Control</description>
                            <lsb>0</lsb>
                            <msb>0</msb>
                            <access>read-write</access>
                            <enumeratedValues>
                                <enumeratedValue>
                                    <name>0</name>
                                    <description>Disable IDP_SRC circuit</description>
                                    <value>#0</value>
                                </enumeratedValue>
                                <enumeratedValue>
                                    <name>1</name>
                                    <description>Enable IDP_SRC circuit</description>
                                    <value>#1</value>
                                </enumeratedValue>
                            </enumeratedValues>
                        </field>
                        <field>
                            <name>IDMSINKE</name>
                            <description>IDMSINK Control</description>
                            <lsb>1</lsb>
                            <msb>1</msb>
                            <access>read-write</access>
                            <enumeratedValues>
                                <enumeratedValue>
                                    <name>0</name>
                                    <description>Disable IDM_SINK circuit</description>
                                    <value>#0</value>
                                </enumeratedValue>
                                <enumeratedValue>
                                    <name>1</name>
                                    <description>Enable IDM_SINK circuit</description>
                                    <value>#1</value>
                                </enumeratedValue>
                            </enumeratedValues>
                        </field>
                        <field>
                            <name>VDPSRCE</name>
                            <description>VDPSRC Control</description>
                            <lsb>2</lsb>
                            <msb>2</msb>
                            <access>read-write</access>
                            <enumeratedValues>
                                <enumeratedValue>
                                    <name>0</name>
                                    <description>Disable VDP_SRC circuit</description>
                                    <value>#0</value>
                                </enumeratedValue>
                                <enumeratedValue>
                                    <name>1</name>
                                    <description>Enable VDP_SRC circuit</description>
                                    <value>#1</value>
                                </enumeratedValue>
                            </enumeratedValues>
                        </field>
                        <field>
                            <name>IDPSINKE</name>
                            <description>IDPSINK Control</description>
                            <lsb>3</lsb>
                            <msb>3</msb>
                            <access>read-write</access>
                            <enumeratedValues>
                                <enumeratedValue>
                                    <name>0</name>
                                    <description>Disable IDP_SINK circuit</description>
                                    <value>#0</value>
                                </enumeratedValue>
                                <enumeratedValue>
                                    <name>1</name>
                                    <description>Enable IDP_SINK circuit</description>
                                    <value>#1</value>
                                </enumeratedValue>
                            </enumeratedValues>
                        </field>
                        <field>
                            <name>VDMSRCE</name>
                            <description>VDMSRC Control</description>
                            <lsb>4</lsb>
                            <msb>4</msb>
                            <access>read-write</access>
                            <enumeratedValues>
                                <enumeratedValue>
                                    <name>0</name>
                                    <description>Disable VDM_SRC circuit</description>
                                    <value>#0</value>
                                </enumeratedValue>
                                <enumeratedValue>
                                    <name>1</name>
                                    <description>Enable VDM_SRC circuit</description>
                                    <value>#1</value>
                                </enumeratedValue>
                            </enumeratedValues>
                        </field>
                        <field>
                            <name>DCPMODE</name>
                            <description>DCP Mode Control</description>
                            <lsb>5</lsb>
                            <msb>5</msb>
                            <access>read-write</access>
                            <enumeratedValues>
                                <enumeratedValue>
                                    <name>0</name>
                                    <description>Disable RDCP_DAT resistor</description>
                                    <value>#0</value>
                                </enumeratedValue>
                                <enumeratedValue>
                                    <name>1</name>
                                    <description>Enable RDCP_DAT resistor</description>
                                    <value>#1</value>
                                </enumeratedValue>
                            </enumeratedValues>
                        </field>
                        <field>
                            <name>CHGDETSTS</name>
                            <description>CHGDET Status Flag</description>
                            <lsb>8</lsb>
                            <msb>8</msb>
                            <access>read-only</access>
                            <enumeratedValues>
                                <enumeratedValue>
                                    <name>0</name>
                                    <description>The CHGDET pin is at low level</description>
                                    <value>#0</value>
                                </enumeratedValue>
                                <enumeratedValue>
                                    <name>1</name>
                                    <description>The CHGDET pin is at high level</description>
                                    <value>#1</value>
                                </enumeratedValue>
                            </enumeratedValues>
                        </field>
                        <field>
                            <name>PDDETSTS</name>
                            <description>PDDET Status Flag</description>
                            <lsb>9</lsb>
                            <msb>9</msb>
                            <access>read-only</access>
                            <enumeratedValues>
                                <enumeratedValue>
                                    <name>0</name>
                                    <description>The PDDET pin is at low level</description>
                                    <value>#0</value>
                                </enumeratedValue>
                                <enumeratedValue>
                                    <name>1</name>
                                    <description>The PDDET pin is at high level</description>
                                    <value>#1</value>
                                </enumeratedValue>
                            </enumeratedValues>
                        </field>
                    </fields>
                </register>
                <register>
                    <name>PL1CTRL1</name>
                    <description>Function L1 Control Register 1</description>
                    <addressOffset>0x144</addressOffset>
                    <size>16</size>
                    <access>read-write</access>
                    <resetValue>0x0000</resetValue>
                    <resetMask>0x4fff</resetMask>
                    <fields>
                        <field>
                            <name>L1RESPEN</name>
                            <description>L1 Response Enable</description>
                            <lsb>0</lsb>
                            <msb>0</msb>
                            <access>read-write</access>
                            <enumeratedValues>
                                <enumeratedValue>
                                    <name>0</name>
                                    <description>Do not support LPM</description>
                                    <value>#0</value>
                                </enumeratedValue>
                                <enumeratedValue>
                                    <name>1</name>
                                    <description>Support LPM</description>
                                    <value>#1</value>
                                </enumeratedValue>
                            </enumeratedValues>
                        </field>
                        <field>
                            <name>L1RESPMD</name>
                            <description>L1 Response Mode</description>
                            <lsb>1</lsb>
                            <msb>2</msb>
                            <access>read-write</access>
                            <enumeratedValues>
                                <enumeratedValue>
                                    <name>00</name>
                                    <description>NYET response</description>
                                    <value>#00</value>
                                </enumeratedValue>
                                <enumeratedValue>
                                    <name>01</name>
                                    <description>ACK response</description>
                                    <value>#01</value>
                                </enumeratedValue>
                                <enumeratedValue>
                                    <name>10</name>
                                    <description>STALL response</description>
                                    <value>#10</value>
                                </enumeratedValue>
                                <enumeratedValue>
                                    <name>11</name>
                                    <description>Response based on L1NEGOMD setting</description>
                                    <value>#11</value>
                                </enumeratedValue>
                            </enumeratedValues>
                        </field>
                        <field>
                            <name>L1NEGOMD</name>
                            <description>L1 Response Negotiation Control</description>
                            <lsb>3</lsb>
                            <msb>3</msb>
                            <access>read-write</access>
                            <enumeratedValues>
                                <enumeratedValue>
                                    <name>0</name>
                                    <description>Return ACK when received HIRD is larger than HIRDTHR[3:0]. Otherwise (including when HIRD = HIRDTHR[3:0]), return NYET</description>
                                    <value>#0</value>
                                </enumeratedValue>
                                <enumeratedValue>
                                    <name>1</name>
                                    <description>Return ACK when received HIRD is smaller than HIRDTHR[3:0]. Otherwise (including when HIRD = HIRDTHR[3:0]), return NYET</description>
                                    <value>#1</value>
                                </enumeratedValue>
                            </enumeratedValues>
                        </field>
                        <field>
                            <name>DVSQ</name>
                            <description>DVSQ Extension Flag</description>
                            <lsb>4</lsb>
                            <msb>7</msb>
                            <access>read-only</access>
                            <enumeratedValues>
                                <enumeratedValue>
                                    <name>0000</name>
                                    <description>Powered state</description>
                                    <value>#0000</value>
                                </enumeratedValue>
                                <enumeratedValue>
                                    <name>0001</name>
                                    <description>Default state</description>
                                    <value>#0001</value>
                                </enumeratedValue>
                                <enumeratedValue>
                                    <name>0010</name>
                                    <description>Address state</description>
                                    <value>#0010</value>
                                </enumeratedValue>
                                <enumeratedValue>
                                    <name>0011</name>
                                    <description>Configured state</description>
                                    <value>#0011</value>
                                </enumeratedValue>
                                <enumeratedValue>
                                    <name>01xx</name>
                                    <description>Suspend state</description>
                                    <value>#01xx</value>
                                </enumeratedValue>
                                <enumeratedValue>
                                    <name>10xx</name>
                                    <description>L1 state</description>
                                    <value>#10xx</value>
                                </enumeratedValue>
                            </enumeratedValues>
                        </field>
                        <field>
                            <name>HIRDTHR</name>
                            <description>L1 Response Negotiation Threshold Value</description>
                            <lsb>8</lsb>
                            <msb>11</msb>
                            <access>read-write</access>
                        </field>
                        <field>
                            <name>L1EXTMD</name>
                            <description>PHY Control Mode at L1 Return</description>
                            <lsb>14</lsb>
                            <msb>14</msb>
                            <access>read-write</access>
                            <enumeratedValues>
                                <enumeratedValue>
                                    <name>0</name>
                                    <description>Do not set LPSTS.SUSPENDM bit through hardware when Host K is received</description>
                                    <value>#0</value>
                                </enumeratedValue>
                                <enumeratedValue>
                                    <name>1</name>
                                    <description>Set LPSTS.SUSPENDM bit through hardware when Host K is received</description>
                                    <value>#1</value>
                                </enumeratedValue>
                            </enumeratedValues>
                        </field>
                    </fields>
                </register>
                <register>
                    <name>PL1CTRL2</name>
                    <description>Function L1 Control Register 2</description>
                    <addressOffset>0x146</addressOffset>
                    <size>16</size>
                    <access>read-write</access>
                    <resetValue>0x0000</resetValue>
                    <resetMask>0x1f00</resetMask>
                    <fields>
                        <field>
                            <name>HIRDMON</name>
                            <description>HIRD Value Monitor</description>
                            <lsb>8</lsb>
                            <msb>11</msb>
                            <access>read-only</access>
                        </field>
                        <field>
                            <name>RWEMON</name>
                            <description>RWE Value Monitor</description>
                            <lsb>12</lsb>
                            <msb>12</msb>
                            <access>read-only</access>
                        </field>
                    </fields>
                </register>
                <register>
                    <name>HL1CTRL1</name>
                    <description>Host L1 Control Register 1</description>
                    <addressOffset>0x148</addressOffset>
                    <size>16</size>
                    <access>read-write</access>
                    <resetValue>0x0000</resetValue>
                    <resetMask>0x0007</resetMask>
                    <fields>
                        <field>
                            <name>L1REQ</name>
                            <description>L1 Transition Request</description>
                            <lsb>0</lsb>
                            <msb>0</msb>
                            <access>read-write</access>
                        </field>
                        <field>
                            <name>L1STATUS</name>
                            <description>L1 Request Completion Status</description>
                            <lsb>1</lsb>
                            <msb>2</msb>
                            <access>read-only</access>
                            <enumeratedValues>
                                <enumeratedValue>
                                    <name>00</name>
                                    <description>ACK received</description>
                                    <value>#00</value>
                                </enumeratedValue>
                                <enumeratedValue>
                                    <name>01</name>
                                    <description>NYET received</description>
                                    <value>#01</value>
                                </enumeratedValue>
                                <enumeratedValue>
                                    <name>10</name>
                                    <description>STALL received</description>
                                    <value>#10</value>
                                </enumeratedValue>
                                <enumeratedValue>
                                    <name>11</name>
                                    <description>Transaction error</description>
                                    <value>#11</value>
                                </enumeratedValue>
                            </enumeratedValues>
                        </field>
                    </fields>
                </register>
                <register>
                    <name>HL1CTRL2</name>
                    <description>Host L1 Control Register 2</description>
                    <addressOffset>0x14A</addressOffset>
                    <size>16</size>
                    <access>read-write</access>
                    <resetValue>0x0000</resetValue>
                    <resetMask>0x9f0f</resetMask>
                    <fields>
                        <field>
                            <name>L1ADDR</name>
                            <description>LPM Token DeviceAddress</description>
                            <lsb>0</lsb>
                            <msb>3</msb>
                            <access>read-write</access>
                        </field>
                        <field>
                            <name>HIRD</name>
                            <description>LPM Token HIRD</description>
                            <lsb>8</lsb>
                            <msb>11</msb>
                            <access>read-write</access>
                        </field>
                        <field>
                            <name>L1RWE</name>
                            <description>LPM Token L1 RemoteWake Enable</description>
                            <lsb>12</lsb>
                            <msb>12</msb>
                            <access>read-write</access>
                        </field>
                        <field>
                            <name>BESL</name>
                            <description>BESL &amp; Alternate HIRD</description>
                            <lsb>15</lsb>
                            <msb>15</msb>
                            <access>read-write</access>
                        </field>
                    </fields>
                </register>
                <register>
                    <name>DPUSR0R</name>
                    <description>Deep Software Standby USB Transceiver Control/Pin Monitor Register</description>
                    <addressOffset>0x160</addressOffset>
                    <size>32</size>
                    <access>read-only</access>
                    <resetValue>0x00000000</resetValue>
                    <resetMask>0xff4fffff</resetMask>
                    <fields>
                        <field>
                            <name>DOVCAHM</name>
                            <description>OVRCURA Input Flag</description>
                            <lsb>20</lsb>
                            <msb>20</msb>
                            <access>read-only</access>
                        </field>
                        <field>
                            <name>DOVCBHM</name>
                            <description>OVRCURB Input Flag</description>
                            <lsb>21</lsb>
                            <msb>21</msb>
                            <access>read-only</access>
                        </field>
                        <field>
                            <name>DVBSTSHM</name>
                            <description>VBUS Input Flag</description>
                            <lsb>23</lsb>
                            <msb>23</msb>
                            <access>read-only</access>
                        </field>
                    </fields>
                </register>
                <register>
                    <name>DPUSR1R</name>
                    <description>Deep Software Standby USB Suspend/Resume Interrupt Register</description>
                    <addressOffset>0x164</addressOffset>
                    <size>32</size>
                    <access>read-write</access>
                    <resetValue>0x00000000</resetValue>
                    <resetMask>0xffffffff</resetMask>
                    <fields>
                        <field>
                            <name>DOVCAHE</name>
                            <description>OVRCURA Interrupt Enable Clear</description>
                            <lsb>4</lsb>
                            <msb>4</msb>
                            <access>read-write</access>
                            <enumeratedValues>
                                <enumeratedValue>
                                    <name>0</name>
                                    <description>Disable recovery from Deep Software Standby mode 1</description>
                                    <value>#0</value>
                                </enumeratedValue>
                                <enumeratedValue>
                                    <name>1</name>
                                    <description>Enable recovery from Deep Software Standby mode 1</description>
                                    <value>#1</value>
                                </enumeratedValue>
                            </enumeratedValues>
                        </field>
                        <field>
                            <name>DOVCBHE</name>
                            <description>OVRCURB Interrupt Enable Clear</description>
                            <lsb>5</lsb>
                            <msb>5</msb>
                            <access>read-write</access>
                            <enumeratedValues>
                                <enumeratedValue>
                                    <name>0</name>
                                    <description>Disable recovery from Deep Software Standby mode 1</description>
                                    <value>#0</value>
                                </enumeratedValue>
                                <enumeratedValue>
                                    <name>1</name>
                                    <description>Enable recovery from Deep Software Standby mode 1</description>
                                    <value>#1</value>
                                </enumeratedValue>
                            </enumeratedValues>
                        </field>
                        <field>
                            <name>DVBSTSHE</name>
                            <description>VBUS Interrupt Enable/Clear</description>
                            <lsb>7</lsb>
                            <msb>7</msb>
                            <access>read-write</access>
                            <enumeratedValues>
                                <enumeratedValue>
                                    <name>0</name>
                                    <description>Disable recovery from Deep Software Standby mode 1</description>
                                    <value>#0</value>
                                </enumeratedValue>
                                <enumeratedValue>
                                    <name>1</name>
                                    <description>Enable recovery from Deep Software Standby mode 1</description>
                                    <value>#1</value>
                                </enumeratedValue>
                            </enumeratedValues>
                        </field>
                        <field>
                            <name>DOVCAH</name>
                            <description>OVRCURA Interrupt Source Return Status Flag</description>
                            <lsb>20</lsb>
                            <msb>20</msb>
                            <access>read-only</access>
                            <enumeratedValues>
                                <enumeratedValue>
                                    <name>0</name>
                                    <description>System has not recovered from Deep Software Standby mode 1</description>
                                    <value>#0</value>
                                </enumeratedValue>
                                <enumeratedValue>
                                    <name>1</name>
                                    <description>System recovered from Deep Software Standby mode 1</description>
                                    <value>#1</value>
                                </enumeratedValue>
                            </enumeratedValues>
                        </field>
                        <field>
                            <name>DOVCBH</name>
                            <description>OVRCURB Interrupt Source Return Status Flag</description>
                            <lsb>21</lsb>
                            <msb>21</msb>
                            <access>read-only</access>
                            <enumeratedValues>
                                <enumeratedValue>
                                    <name>0</name>
                                    <description>System has not recovered from Deep Software Standby mode 1</description>
                                    <value>#0</value>
                                </enumeratedValue>
                                <enumeratedValue>
                                    <name>1</name>
                                    <description>System recovered from Deep Software Standby mode 1</description>
                                    <value>#1</value>
                                </enumeratedValue>
                            </enumeratedValues>
                        </field>
                        <field>
                            <name>DVBSTSH</name>
                            <description>VBUS Interrupt Source Return Status Flag</description>
                            <lsb>23</lsb>
                            <msb>23</msb>
                            <access>read-only</access>
                            <enumeratedValues>
                                <enumeratedValue>
                                    <name>0</name>
                                    <description>System has not recovered from Deep Software Standby mode 1</description>
                                    <value>#0</value>
                                </enumeratedValue>
                                <enumeratedValue>
                                    <name>1</name>
                                    <description>System recovered from Deep Software Standby mode 1</description>
                                    <value>#1</value>
                                </enumeratedValue>
                            </enumeratedValues>
                        </field>
                    </fields>
                </register>
                <register>
                    <name>DPUSR2R</name>
                    <description>Deep Software Standby USB Suspend/Resume Interrupt Register</description>
                    <addressOffset>0x168</addressOffset>
                    <size>16</size>
                    <access>read-write</access>
                    <resetValue>0x0000</resetValue>
                    <resetMask>0xffff</resetMask>
                    <fields>
                        <field>
                            <name>DPINT</name>
                            <description>Indication of Return from DP Interrupt Source</description>
                            <lsb>0</lsb>
                            <msb>0</msb>
                            <access>read-only</access>
                            <enumeratedValues>
                                <enumeratedValue>
                                    <name>0</name>
                                    <description>System has not recovered from Deep Software Standby mode 1</description>
                                    <value>#0</value>
                                </enumeratedValue>
                                <enumeratedValue>
                                    <name>1</name>
                                    <description>System recovered from Deep Software Standby mode 1</description>
                                    <value>#1</value>
                                </enumeratedValue>
                            </enumeratedValues>
                        </field>
                        <field>
                            <name>DMINT</name>
                            <description>Indication of Return from DM Interrupt Source</description>
                            <lsb>1</lsb>
                            <msb>1</msb>
                            <access>read-only</access>
                            <enumeratedValues>
                                <enumeratedValue>
                                    <name>0</name>
                                    <description>System has not recovered from Deep Software Standby mode 1</description>
                                    <value>#0</value>
                                </enumeratedValue>
                                <enumeratedValue>
                                    <name>1</name>
                                    <description>System recovered from Deep Software Standby mode 1</description>
                                    <value>#1</value>
                                </enumeratedValue>
                            </enumeratedValues>
                        </field>
                        <field>
                            <name>DPVAL</name>
                            <description>DP Input</description>
                            <lsb>4</lsb>
                            <msb>4</msb>
                            <access>read-only</access>
                        </field>
                        <field>
                            <name>DMVAL</name>
                            <description>DM Input</description>
                            <lsb>5</lsb>
                            <msb>5</msb>
                            <access>read-only</access>
                        </field>
                        <field>
                            <name>DPINTE</name>
                            <description>DP Interrupt Enable Clear</description>
                            <lsb>8</lsb>
                            <msb>8</msb>
                            <access>read-write</access>
                            <enumeratedValues>
                                <enumeratedValue>
                                    <name>0</name>
                                    <description>Disable recovery from Deep Software Standby mode 1</description>
                                    <value>#0</value>
                                </enumeratedValue>
                                <enumeratedValue>
                                    <name>1</name>
                                    <description>Enable recovery from Deep Software Standby mode 1</description>
                                    <value>#1</value>
                                </enumeratedValue>
                            </enumeratedValues>
                        </field>
                        <field>
                            <name>DMINTE</name>
                            <description>DM Interrupt Enable Clear</description>
                            <lsb>9</lsb>
                            <msb>9</msb>
                            <access>read-write</access>
                            <enumeratedValues>
                                <enumeratedValue>
                                    <name>0</name>
                                    <description>Disable recovery from Deep Software Standby mode 1</description>
                                    <value>#0</value>
                                </enumeratedValue>
                                <enumeratedValue>
                                    <name>1</name>
                                    <description>Enable recovery from Deep Software Standby mode 1</description>
                                    <value>#1</value>
                                </enumeratedValue>
                            </enumeratedValues>
                        </field>
                    </fields>
                </register>
                <register>
                    <name>DPUSRCR</name>
                    <description>Deep Software Standby USB Suspend/Resume Command Register</description>
                    <addressOffset>0x16A</addressOffset>
                    <size>16</size>
                    <access>read-write</access>
                    <resetValue>0x0000</resetValue>
                    <resetMask>0xffff</resetMask>
                    <fields>
                        <field>
                            <name>FIXPHY</name>
                            <description>USB Transceiver Control Fix</description>
                            <lsb>0</lsb>
                            <msb>0</msb>
                            <access>read-write</access>
                            <enumeratedValues>
                                <enumeratedValue>
                                    <name>0</name>
                                    <description>Normal mode</description>
                                    <value>#0</value>
                                </enumeratedValue>
                                <enumeratedValue>
                                    <name>1</name>
                                    <description>Invoke/recover from Deep Software Standby mode 1</description>
                                    <value>#1</value>
                                </enumeratedValue>
                            </enumeratedValues>
                        </field>
                        <field>
                            <name>FIXPHYPD</name>
                            <description>USB Transceiver Control Fix for PLL</description>
                            <lsb>1</lsb>
                            <msb>1</msb>
                            <access>read-write</access>
                            <enumeratedValues>
                                <enumeratedValue>
                                    <name>0</name>
                                    <description>Normal mode</description>
                                    <value>#0</value>
                                </enumeratedValue>
                                <enumeratedValue>
                                    <name>1</name>
                                    <description>Invoke/recover from Deep Software Standby mode 1</description>
                                    <value>#1</value>
                                </enumeratedValue>
                            </enumeratedValues>
                        </field>
                    </fields>
                </register>
            </registers>
        </peripheral>
        <peripheral>
            <name>EDMAC0</name>
            <description>DMA Controller for the Ethernet Controller Channel 0</description>
            <baseAddress>0x40354000</baseAddress>
            <addressBlock>
                <offset>0x00</offset>
                <size>4</size>
                <usage>registers</usage>
            </addressBlock>
            <addressBlock>
                <offset>0x08</offset>
                <size>4</size>
                <usage>registers</usage>
            </addressBlock>
            <addressBlock>
                <offset>0x10</offset>
                <size>4</size>
                <usage>registers</usage>
            </addressBlock>
            <addressBlock>
                <offset>0x18</offset>
                <size>4</size>
                <usage>registers</usage>
            </addressBlock>
            <addressBlock>
                <offset>0x20</offset>
                <size>4</size>
                <usage>registers</usage>
            </addressBlock>
            <addressBlock>
                <offset>0x28</offset>
                <size>4</size>
                <usage>registers</usage>
            </addressBlock>
            <addressBlock>
                <offset>0x30</offset>
                <size>4</size>
                <usage>registers</usage>
            </addressBlock>
            <addressBlock>
                <offset>0x38</offset>
                <size>4</size>
                <usage>registers</usage>
            </addressBlock>
            <addressBlock>
                <offset>0x40</offset>
                <size>4</size>
                <usage>registers</usage>
            </addressBlock>
            <addressBlock>
                <offset>0x48</offset>
                <size>4</size>
                <usage>registers</usage>
            </addressBlock>
            <addressBlock>
                <offset>0x50</offset>
                <size>4</size>
                <usage>registers</usage>
            </addressBlock>
            <addressBlock>
                <offset>0x58</offset>
                <size>4</size>
                <usage>registers</usage>
            </addressBlock>
            <addressBlock>
                <offset>0x64</offset>
                <size>16</size>
                <usage>registers</usage>
            </addressBlock>
            <addressBlock>
                <offset>0x78</offset>
                <size>8</size>
                <usage>registers</usage>
            </addressBlock>
            <addressBlock>
                <offset>0xC8</offset>
                <size>8</size>
                <usage>registers</usage>
            </addressBlock>
            <addressBlock>
                <offset>0xD4</offset>
                <size>8</size>
                <usage>registers</usage>
            </addressBlock>
            <registers>
                <register>
                    <name>EDMR</name>
                    <description>EDMAC Mode Register</description>
                    <addressOffset>0x00</addressOffset>
                    <size>32</size>
                    <access>read-write</access>
                    <resetValue>0x00000000</resetValue>
                    <resetMask>0xffffffff</resetMask>
                    <fields>
                        <field>
                            <name>SWR</name>
                            <description>Software Reset</description>
                            <lsb>0</lsb>
                            <msb>0</msb>
                            <access>read-write</access>
                        </field>
                        <field>
                            <name>DL</name>
                            <description>Transmit/Receive Descriptor Length</description>
                            <lsb>4</lsb>
                            <msb>5</msb>
                            <access>read-write</access>
                            <enumeratedValues>
                                <enumeratedValue>
                                    <name>00</name>
                                    <description>16 bytes</description>
                                    <value>#00</value>
                                </enumeratedValue>
                                <enumeratedValue>
                                    <name>01</name>
                                    <description>32 bytes</description>
                                    <value>#01</value>
                                </enumeratedValue>
                                <enumeratedValue>
                                    <name>10</name>
                                    <description>64 bytes</description>
                                    <value>#10</value>
                                </enumeratedValue>
                                <enumeratedValue>
                                    <name>11</name>
                                    <description>16 bytes.</description>
                                    <value>#11</value>
                                </enumeratedValue>
                            </enumeratedValues>
                        </field>
                        <field>
                            <name>DE</name>
                            <description>Big Endian Mode/Little Endian Mode</description>
                            <lsb>6</lsb>
                            <msb>6</msb>
                            <access>read-write</access>
                            <enumeratedValues>
                                <enumeratedValue>
                                    <name>0</name>
                                    <description>Big endian mode</description>
                                    <value>#0</value>
                                </enumeratedValue>
                                <enumeratedValue>
                                    <name>1</name>
                                    <description>Little endian mode.</description>
                                    <value>#1</value>
                                </enumeratedValue>
                            </enumeratedValues>
                        </field>
                    </fields>
                </register>
                <register>
                    <name>EDTRR</name>
                    <description>EDMAC Transmit Request Register</description>
                    <addressOffset>0x08</addressOffset>
                    <size>32</size>
                    <access>read-write</access>
                    <resetValue>0x00000000</resetValue>
                    <resetMask>0xffffffff</resetMask>
                    <fields>
                        <field>
                            <name>TR</name>
                            <description>Transmit Request</description>
                            <lsb>0</lsb>
                            <msb>0</msb>
                            <access>read-write</access>
                        </field>
                    </fields>
                </register>
                <register>
                    <name>EDRRR</name>
                    <description>EDMAC Receive Request Register</description>
                    <addressOffset>0x10</addressOffset>
                    <size>32</size>
                    <access>read-write</access>
                    <resetValue>0x00000000</resetValue>
                    <resetMask>0xffffffff</resetMask>
                    <fields>
                        <field>
                            <name>RR</name>
                            <description>Receive Request</description>
                            <lsb>0</lsb>
                            <msb>0</msb>
                            <access>read-write</access>
                            <enumeratedValues>
                                <enumeratedValue>
                                    <name>0</name>
                                    <description>Disable the receive function</description>
                                    <value>#0</value>
                                </enumeratedValue>
                                <enumeratedValue>
                                    <name>1</name>
                                    <description>Read receive descriptor and enable the receive function.</description>
                                    <value>#1</value>
                                </enumeratedValue>
                            </enumeratedValues>
                        </field>
                    </fields>
                </register>
                <register>
                    <name>TDLAR</name>
                    <description>Transmit Descriptor List Start Address Register</description>
                    <addressOffset>0x18</addressOffset>
                    <size>32</size>
                    <access>read-write</access>
                    <resetValue>0x00000000</resetValue>
                    <resetMask>0xffffffff</resetMask>
                </register>
                <register>
                    <name>RDLAR</name>
                    <description>Receive Descriptor List Start Address Register</description>
                    <addressOffset>0x20</addressOffset>
                    <size>32</size>
                    <access>read-write</access>
                    <resetValue>0x00000000</resetValue>
                    <resetMask>0xffffffff</resetMask>
                </register>
                <register>
                    <name>EESR</name>
                    <description>ETHERC/EDMAC Status Register</description>
                    <addressOffset>0x28</addressOffset>
                    <size>32</size>
                    <access>read-write</access>
                    <resetValue>0x00000000</resetValue>
                    <resetMask>0xffffffff</resetMask>
                    <fields>
                        <field>
                            <name>CERF</name>
                            <description>CRC Error Flag</description>
                            <lsb>0</lsb>
                            <msb>0</msb>
                            <access>read-write</access>
                            <enumeratedValues>
                                <enumeratedValue>
                                    <name>0</name>
                                    <description>CRC error not detected</description>
                                    <value>#0</value>
                                </enumeratedValue>
                                <enumeratedValue>
                                    <name>1</name>
                                    <description>CRC error detected.</description>
                                    <value>#1</value>
                                </enumeratedValue>
                            </enumeratedValues>
                        </field>
                        <field>
                            <name>PRE</name>
                            <description>PHY-LSI Receive Error Flag</description>
                            <lsb>1</lsb>
                            <msb>1</msb>
                            <access>read-write</access>
                            <enumeratedValues>
                                <enumeratedValue>
                                    <name>0</name>
                                    <description>PHY-LSI receive error not detected</description>
                                    <value>#0</value>
                                </enumeratedValue>
                                <enumeratedValue>
                                    <name>1</name>
                                    <description>PHY-LSI receive error detected.</description>
                                    <value>#1</value>
                                </enumeratedValue>
                            </enumeratedValues>
                        </field>
                        <field>
                            <name>RTSF</name>
                            <description>Frame-Too-Short Error Flag</description>
                            <lsb>2</lsb>
                            <msb>2</msb>
                            <access>read-write</access>
                            <enumeratedValues>
                                <enumeratedValue>
                                    <name>0</name>
                                    <description>Frame-too-short error not detected</description>
                                    <value>#0</value>
                                </enumeratedValue>
                                <enumeratedValue>
                                    <name>1</name>
                                    <description>Frame-too-short error detected.</description>
                                    <value>#1</value>
                                </enumeratedValue>
                            </enumeratedValues>
                        </field>
                        <field>
                            <name>RTLF</name>
                            <description>Frame-Too-Long Error Flag</description>
                            <lsb>3</lsb>
                            <msb>3</msb>
                            <access>read-write</access>
                            <enumeratedValues>
                                <enumeratedValue>
                                    <name>0</name>
                                    <description>Frame-too-long error not detected</description>
                                    <value>#0</value>
                                </enumeratedValue>
                                <enumeratedValue>
                                    <name>1</name>
                                    <description>Frame-too-long error detected.</description>
                                    <value>#1</value>
                                </enumeratedValue>
                            </enumeratedValues>
                        </field>
                        <field>
                            <name>RRF</name>
                            <description>Alignment Error Flag</description>
                            <lsb>4</lsb>
                            <msb>4</msb>
                            <access>read-write</access>
                            <enumeratedValues>
                                <enumeratedValue>
                                    <name>0</name>
                                    <description>Alignment error not detected</description>
                                    <value>#0</value>
                                </enumeratedValue>
                                <enumeratedValue>
                                    <name>1</name>
                                    <description>Alignment error detected.</description>
                                    <value>#1</value>
                                </enumeratedValue>
                            </enumeratedValues>
                        </field>
                        <field>
                            <name>RMAF</name>
                            <description>Multicast Address Frame Receive Flag</description>
                            <lsb>7</lsb>
                            <msb>7</msb>
                            <access>read-write</access>
                            <enumeratedValues>
                                <enumeratedValue>
                                    <name>0</name>
                                    <description>Multicast address frame not received</description>
                                    <value>#0</value>
                                </enumeratedValue>
                                <enumeratedValue>
                                    <name>1</name>
                                    <description>Multicast address frame received.</description>
                                    <value>#1</value>
                                </enumeratedValue>
                            </enumeratedValues>
                        </field>
                        <field>
                            <name>TRO</name>
                            <description>Transmit Retry Over Flag</description>
                            <lsb>8</lsb>
                            <msb>8</msb>
                            <access>read-write</access>
                            <enumeratedValues>
                                <enumeratedValue>
                                    <name>0</name>
                                    <description>Transmit retry-over condition not detected</description>
                                    <value>#0</value>
                                </enumeratedValue>
                                <enumeratedValue>
                                    <name>1</name>
                                    <description>Transmit retry-over condition detected.</description>
                                    <value>#1</value>
                                </enumeratedValue>
                            </enumeratedValues>
                        </field>
                        <field>
                            <name>CD</name>
                            <description>Late Collision Detect Flag</description>
                            <lsb>9</lsb>
                            <msb>9</msb>
                            <access>read-write</access>
                            <enumeratedValues>
                                <enumeratedValue>
                                    <name>0</name>
                                    <description>Late collision not detected</description>
                                    <value>#0</value>
                                </enumeratedValue>
                                <enumeratedValue>
                                    <name>1</name>
                                    <description>Late collision detected during frame transmission.</description>
                                    <value>#1</value>
                                </enumeratedValue>
                            </enumeratedValues>
                        </field>
                        <field>
                            <name>DLC</name>
                            <description>Loss of Carrier Detect Flag</description>
                            <lsb>10</lsb>
                            <msb>10</msb>
                            <access>read-write</access>
                            <enumeratedValues>
                                <enumeratedValue>
                                    <name>0</name>
                                    <description>Loss of carrier not detected</description>
                                    <value>#0</value>
                                </enumeratedValue>
                                <enumeratedValue>
                                    <name>1</name>
                                    <description>Loss of carrier detected during frame transmission.</description>
                                    <value>#1</value>
                                </enumeratedValue>
                            </enumeratedValues>
                        </field>
                        <field>
                            <name>CND</name>
                            <description>Carrier Not Detect Flag</description>
                            <lsb>11</lsb>
                            <msb>11</msb>
                            <access>read-write</access>
                            <enumeratedValues>
                                <enumeratedValue>
                                    <name>0</name>
                                    <description>Carrier detected when transmission started</description>
                                    <value>#0</value>
                                </enumeratedValue>
                                <enumeratedValue>
                                    <name>1</name>
                                    <description>Carrier not detected during preamble transmission.</description>
                                    <value>#1</value>
                                </enumeratedValue>
                            </enumeratedValues>
                        </field>
                        <field>
                            <name>RFOF</name>
                            <description>Receive FIFO Overflow Flag</description>
                            <lsb>16</lsb>
                            <msb>16</msb>
                            <access>read-write</access>
                            <enumeratedValues>
                                <enumeratedValue>
                                    <name>0</name>
                                    <description>No overflow occurred</description>
                                    <value>#0</value>
                                </enumeratedValue>
                                <enumeratedValue>
                                    <name>1</name>
                                    <description>Overflow occurred.</description>
                                    <value>#1</value>
                                </enumeratedValue>
                            </enumeratedValues>
                        </field>
                        <field>
                            <name>RDE</name>
                            <description>Receive Descriptor Empty Flag</description>
                            <lsb>17</lsb>
                            <msb>17</msb>
                            <access>read-write</access>
                            <enumeratedValues>
                                <enumeratedValue>
                                    <name>0</name>
                                    <description>EDMAC detected that the receive descriptor valid bit (RD0.RACT) is 1 </description>
                                    <value>#0</value>
                                </enumeratedValue>
                                <enumeratedValue>
                                    <name>1</name>
                                    <description>EDMAC detected that the receive descriptor valid bit (RD0.RACT) is 0. </description>
                                    <value>#1</value>
                                </enumeratedValue>
                            </enumeratedValues>
                        </field>
                        <field>
                            <name>FR</name>
                            <description>Frame Receive Flag</description>
                            <lsb>18</lsb>
                            <msb>18</msb>
                            <access>read-write</access>
                            <enumeratedValues>
                                <enumeratedValue>
                                    <name>0</name>
                                    <description>Frame not received</description>
                                    <value>#0</value>
                                </enumeratedValue>
                                <enumeratedValue>
                                    <name>1</name>
                                    <description>Frame received and update of the receive descriptor is complete. </description>
                                    <value>#1</value>
                                </enumeratedValue>
                            </enumeratedValues>
                        </field>
                        <field>
                            <name>TFUF</name>
                            <description>Transmit FIFO Underflow Flag</description>
                            <lsb>19</lsb>
                            <msb>19</msb>
                            <access>read-write</access>
                            <enumeratedValues>
                                <enumeratedValue>
                                    <name>0</name>
                                    <description>No underflow occurred</description>
                                    <value>#0</value>
                                </enumeratedValue>
                                <enumeratedValue>
                                    <name>1</name>
                                    <description>Underflow occurred.</description>
                                    <value>#1</value>
                                </enumeratedValue>
                            </enumeratedValues>
                        </field>
                        <field>
                            <name>TDE</name>
                            <description>Transmit Descriptor Empty Flag</description>
                            <lsb>20</lsb>
                            <msb>20</msb>
                            <access>read-write</access>
                            <enumeratedValues>
                                <enumeratedValue>
                                    <name>0</name>
                                    <description>EDMAC detected that the transmit descriptor valid bit (TD0.TACT) is 1 </description>
                                    <value>#0</value>
                                </enumeratedValue>
                                <enumeratedValue>
                                    <name>1</name>
                                    <description>EDMAC detected that the transmit descriptor valid bit (TD0.TACT) is 0. </description>
                                    <value>#1</value>
                                </enumeratedValue>
                            </enumeratedValues>
                        </field>
                        <field>
                            <name>TC</name>
                            <description>Frame Transfer Complete Flag</description>
                            <lsb>21</lsb>
                            <msb>21</msb>
                            <access>read-write</access>
                            <enumeratedValues>
                                <enumeratedValue>
                                    <name>0</name>
                                    <description>Transfer not complete or no transfer requested</description>
                                    <value>#0</value>
                                </enumeratedValue>
                                <enumeratedValue>
                                    <name>1</name>
                                    <description>All frames indicated in the transmit descriptor were completely transferred to the transmit FIFO. </description>
                                    <value>#1</value>
                                </enumeratedValue>
                            </enumeratedValues>
                        </field>
                        <field>
                            <name>ECI</name>
                            <description>ETHERC Status Register Source Flag</description>
                            <lsb>22</lsb>
                            <msb>22</msb>
                            <access>read-only</access>
                            <enumeratedValues>
                                <enumeratedValue>
                                    <name>0</name>
                                    <description>ETHERC status interrupt source not detected</description>
                                    <value>#0</value>
                                </enumeratedValue>
                                <enumeratedValue>
                                    <name>1</name>
                                    <description>ETHERC status interrupt source detected.</description>
                                    <value>#1</value>
                                </enumeratedValue>
                            </enumeratedValues>
                        </field>
                        <field>
                            <name>ADE</name>
                            <description>Address Error Flag</description>
                            <lsb>23</lsb>
                            <msb>23</msb>
                            <access>read-write</access>
                            <enumeratedValues>
                                <enumeratedValue>
                                    <name>0</name>
                                    <description>Invalid memory address not detected (normal operation)</description>
                                    <value>#0</value>
                                </enumeratedValue>
                                <enumeratedValue>
                                    <name>1</name>
                                    <description>Invalid memory address detected.</description>
                                    <value>#1</value>
                                </enumeratedValue>
                            </enumeratedValues>
                        </field>
                        <field>
                            <name>RFCOF</name>
                            <description>Receive Frame Counter Overflow Flag</description>
                            <lsb>24</lsb>
                            <msb>24</msb>
                            <access>read-write</access>
                            <enumeratedValues>
                                <enumeratedValue>
                                    <name>0</name>
                                    <description>Receive frame counter did not overflow</description>
                                    <value>#0</value>
                                </enumeratedValue>
                                <enumeratedValue>
                                    <name>1</name>
                                    <description>Receive frame counter overflowed.</description>
                                    <value>#1</value>
                                </enumeratedValue>
                            </enumeratedValues>
                        </field>
                        <field>
                            <name>RABT</name>
                            <description>Receive Abort Detect Flag</description>
                            <lsb>25</lsb>
                            <msb>25</msb>
                            <access>read-write</access>
                            <enumeratedValues>
                                <enumeratedValue>
                                    <name>0</name>
                                    <description>Frame reception not aborted or no reception requested</description>
                                    <value>#0</value>
                                </enumeratedValue>
                                <enumeratedValue>
                                    <name>1</name>
                                    <description>Frame reception aborted.</description>
                                    <value>#1</value>
                                </enumeratedValue>
                            </enumeratedValues>
                        </field>
                        <field>
                            <name>TABT</name>
                            <description>Transmit Abort Detect Flag</description>
                            <lsb>26</lsb>
                            <msb>26</msb>
                            <access>read-write</access>
                            <enumeratedValues>
                                <enumeratedValue>
                                    <name>0</name>
                                    <description>Frame transmission not aborted or no transmission requested. </description>
                                    <value>#0</value>
                                </enumeratedValue>
                                <enumeratedValue>
                                    <name>1</name>
                                    <description>Frame transmission aborted.</description>
                                    <value>#1</value>
                                </enumeratedValue>
                            </enumeratedValues>
                        </field>
                        <field>
                            <name>TWB</name>
                            <description>Write-Back Complete Flag</description>
                            <lsb>30</lsb>
                            <msb>30</msb>
                            <access>read-write</access>
                            <enumeratedValues>
                                <enumeratedValue>
                                    <name>0</name>
                                    <description>Write-back not complete or no transmission requested</description>
                                    <value>#0</value>
                                </enumeratedValue>
                                <enumeratedValue>
                                    <name>1</name>
                                    <description>Write-back to the transmit descriptor completed.</description>
                                    <value>#1</value>
                                </enumeratedValue>
                            </enumeratedValues>
                        </field>
                    </fields>
                </register>
                <register>
                    <name>EESIPR</name>
                    <description>ETHERC/EDMAC Status Interrupt Enable Register</description>
                    <addressOffset>0x30</addressOffset>
                    <size>32</size>
                    <access>read-write</access>
                    <resetValue>0x00000000</resetValue>
                    <resetMask>0xffffffff</resetMask>
                    <fields>
                        <field>
                            <name>CERFIP</name>
                            <description>CRC Error Interrupt Request Enable</description>
                            <lsb>0</lsb>
                            <msb>0</msb>
                            <access>read-write</access>
                            <enumeratedValues>
                                <enumeratedValue>
                                    <name>0</name>
                                    <description>Disable CRC error interrupt requests</description>
                                    <value>#0</value>
                                </enumeratedValue>
                                <enumeratedValue>
                                    <name>1</name>
                                    <description>Enable CRC error interrupt requests.</description>
                                    <value>#1</value>
                                </enumeratedValue>
                            </enumeratedValues>
                        </field>
                        <field>
                            <name>PREIP</name>
                            <description>PHY-LSI Receive Error Interrupt Request Enable</description>
                            <lsb>1</lsb>
                            <msb>1</msb>
                            <access>read-write</access>
                            <enumeratedValues>
                                <enumeratedValue>
                                    <name>0</name>
                                    <description>Disable PHY-LSI receive error interrupt requests</description>
                                    <value>#0</value>
                                </enumeratedValue>
                                <enumeratedValue>
                                    <name>1</name>
                                    <description>Enable PHY-LSI receive error interrupt requests.</description>
                                    <value>#1</value>
                                </enumeratedValue>
                            </enumeratedValues>
                        </field>
                        <field>
                            <name>RTSFIP</name>
                            <description>Frame-Too-Short Error Interrupt Request Enable</description>
                            <lsb>2</lsb>
                            <msb>2</msb>
                            <access>read-write</access>
                            <enumeratedValues>
                                <enumeratedValue>
                                    <name>0</name>
                                    <description>Disable frame-too-short error interrupt requests</description>
                                    <value>#0</value>
                                </enumeratedValue>
                                <enumeratedValue>
                                    <name>1</name>
                                    <description>Enable frame-too-short error interrupt requests.</description>
                                    <value>#1</value>
                                </enumeratedValue>
                            </enumeratedValues>
                        </field>
                        <field>
                            <name>RTLFIP</name>
                            <description>Frame-Too-Long Error Interrupt Request Enable</description>
                            <lsb>3</lsb>
                            <msb>3</msb>
                            <access>read-write</access>
                            <enumeratedValues>
                                <enumeratedValue>
                                    <name>0</name>
                                    <description>Disable frame-too-long error interrupt requests</description>
                                    <value>#0</value>
                                </enumeratedValue>
                                <enumeratedValue>
                                    <name>1</name>
                                    <description>Enable frame-too-long error interrupt requests.</description>
                                    <value>#1</value>
                                </enumeratedValue>
                            </enumeratedValues>
                        </field>
                        <field>
                            <name>RRFIP</name>
                            <description>Alignment Error Interrupt Request Enable</description>
                            <lsb>4</lsb>
                            <msb>4</msb>
                            <access>read-write</access>
                            <enumeratedValues>
                                <enumeratedValue>
                                    <name>0</name>
                                    <description>Disable alignment error interrupt requests</description>
                                    <value>#0</value>
                                </enumeratedValue>
                                <enumeratedValue>
                                    <name>1</name>
                                    <description>Enable alignment error interrupt requests.</description>
                                    <value>#1</value>
                                </enumeratedValue>
                            </enumeratedValues>
                        </field>
                        <field>
                            <name>RMAFIP</name>
                            <description>Multicast Address Frame Receive Interrupt Request Enable</description>
                            <lsb>7</lsb>
                            <msb>7</msb>
                            <access>read-write</access>
                            <enumeratedValues>
                                <enumeratedValue>
                                    <name>0</name>
                                    <description>Disable multicast address frame receive interrupt requests </description>
                                    <value>#0</value>
                                </enumeratedValue>
                                <enumeratedValue>
                                    <name>1</name>
                                    <description>Enable multicast address frame receive interrupt requests. </description>
                                    <value>#1</value>
                                </enumeratedValue>
                            </enumeratedValues>
                        </field>
                        <field>
                            <name>TROIP</name>
                            <description>Transmit Retry Over Interrupt Request Enable</description>
                            <lsb>8</lsb>
                            <msb>8</msb>
                            <access>read-write</access>
                            <enumeratedValues>
                                <enumeratedValue>
                                    <name>0</name>
                                    <description>Disable transmit retry over interrupt requests</description>
                                    <value>#0</value>
                                </enumeratedValue>
                                <enumeratedValue>
                                    <name>1</name>
                                    <description>Enable transmit retry over interrupt requests.</description>
                                    <value>#1</value>
                                </enumeratedValue>
                            </enumeratedValues>
                        </field>
                        <field>
                            <name>CDIP</name>
                            <description>Late Collision Detect Interrupt Request Enable</description>
                            <lsb>9</lsb>
                            <msb>9</msb>
                            <access>read-write</access>
                            <enumeratedValues>
                                <enumeratedValue>
                                    <name>0</name>
                                    <description>Disable late collision detected interrupt requests</description>
                                    <value>#0</value>
                                </enumeratedValue>
                                <enumeratedValue>
                                    <name>1</name>
                                    <description>Enable late collision detected interrupt requests.</description>
                                    <value>#1</value>
                                </enumeratedValue>
                            </enumeratedValues>
                        </field>
                        <field>
                            <name>DLCIP</name>
                            <description>Loss of Carrier Detect Interrupt Request Enable</description>
                            <lsb>10</lsb>
                            <msb>10</msb>
                            <access>read-write</access>
                            <enumeratedValues>
                                <enumeratedValue>
                                    <name>0</name>
                                    <description>Disable loss of carrier detected interrupt requests</description>
                                    <value>#0</value>
                                </enumeratedValue>
                                <enumeratedValue>
                                    <name>1</name>
                                    <description>Enable loss of carrier detected interrupt requests.</description>
                                    <value>#1</value>
                                </enumeratedValue>
                            </enumeratedValues>
                        </field>
                        <field>
                            <name>CNDIP</name>
                            <description>Carrier Not Detect Interrupt Request Enable</description>
                            <lsb>11</lsb>
                            <msb>11</msb>
                            <access>read-write</access>
                            <enumeratedValues>
                                <enumeratedValue>
                                    <name>0</name>
                                    <description>Disable carrier not detected interrupt requests</description>
                                    <value>#0</value>
                                </enumeratedValue>
                                <enumeratedValue>
                                    <name>1</name>
                                    <description>Enable carrier not detected interrupt requests.</description>
                                    <value>#1</value>
                                </enumeratedValue>
                            </enumeratedValues>
                        </field>
                        <field>
                            <name>RFOFIP</name>
                            <description>Receive FIFO Overflow Interrupt Request Enable</description>
                            <lsb>16</lsb>
                            <msb>16</msb>
                            <access>read-write</access>
                            <enumeratedValues>
                                <enumeratedValue>
                                    <name>0</name>
                                    <description>Disable overflow interrupt requests</description>
                                    <value>#0</value>
                                </enumeratedValue>
                                <enumeratedValue>
                                    <name>1</name>
                                    <description>Enable overflow interrupt requests.</description>
                                    <value>#1</value>
                                </enumeratedValue>
                            </enumeratedValues>
                        </field>
                        <field>
                            <name>RDEIP</name>
                            <description>Receive Descriptor Empty Interrupt Request Enable</description>
                            <lsb>17</lsb>
                            <msb>17</msb>
                            <access>read-write</access>
                            <enumeratedValues>
                                <enumeratedValue>
                                    <name>0</name>
                                    <description>Disable receive descriptor empty interrupt requests</description>
                                    <value>#0</value>
                                </enumeratedValue>
                                <enumeratedValue>
                                    <name>1</name>
                                    <description>Enable receive descriptor empty interrupt requests.</description>
                                    <value>#1</value>
                                </enumeratedValue>
                            </enumeratedValues>
                        </field>
                        <field>
                            <name>FRIP</name>
                            <description>Frame Receive Interrupt Request Enable</description>
                            <lsb>18</lsb>
                            <msb>18</msb>
                            <access>read-write</access>
                            <enumeratedValues>
                                <enumeratedValue>
                                    <name>0</name>
                                    <description>Disable frame reception interrupt requests</description>
                                    <value>#0</value>
                                </enumeratedValue>
                                <enumeratedValue>
                                    <name>1</name>
                                    <description>Enable frame reception interrupt requests.</description>
                                    <value>#1</value>
                                </enumeratedValue>
                            </enumeratedValues>
                        </field>
                        <field>
                            <name>TFUFIP</name>
                            <description>Transmit FIFO Underflow Interrupt Request Enable</description>
                            <lsb>19</lsb>
                            <msb>19</msb>
                            <access>read-write</access>
                            <enumeratedValues>
                                <enumeratedValue>
                                    <name>0</name>
                                    <description>Disable underflow interrupt requests</description>
                                    <value>#0</value>
                                </enumeratedValue>
                                <enumeratedValue>
                                    <name>1</name>
                                    <description>Enable underflow interrupt requests.</description>
                                    <value>#1</value>
                                </enumeratedValue>
                            </enumeratedValues>
                        </field>
                        <field>
                            <name>TDEIP</name>
                            <description>Transmit Descriptor Empty Interrupt Request Enable</description>
                            <lsb>20</lsb>
                            <msb>20</msb>
                            <access>read-write</access>
                            <enumeratedValues>
                                <enumeratedValue>
                                    <name>0</name>
                                    <description>Disable transmit descriptor empty interrupt requests</description>
                                    <value>#0</value>
                                </enumeratedValue>
                                <enumeratedValue>
                                    <name>1</name>
                                    <description>Enable transmit descriptor empty interrupt requests.</description>
                                    <value>#1</value>
                                </enumeratedValue>
                            </enumeratedValues>
                        </field>
                        <field>
                            <name>TCIP</name>
                            <description>Frame Transfer Complete Interrupt Request Enable</description>
                            <lsb>21</lsb>
                            <msb>21</msb>
                            <access>read-write</access>
                            <enumeratedValues>
                                <enumeratedValue>
                                    <name>0</name>
                                    <description>Disable frame transmission complete interrupt requests </description>
                                    <value>#0</value>
                                </enumeratedValue>
                                <enumeratedValue>
                                    <name>1</name>
                                    <description>Enable frame transmission complete interrupt requests. </description>
                                    <value>#1</value>
                                </enumeratedValue>
                            </enumeratedValues>
                        </field>
                        <field>
                            <name>ECIIP</name>
                            <description>ETHERC Status Register Source Interrupt Request Enable</description>
                            <lsb>22</lsb>
                            <msb>22</msb>
                            <access>read-write</access>
                            <enumeratedValues>
                                <enumeratedValue>
                                    <name>0</name>
                                    <description>Disable ETHERC status interrupt requests</description>
                                    <value>#0</value>
                                </enumeratedValue>
                                <enumeratedValue>
                                    <name>1</name>
                                    <description>Enable ETHERC status interrupt requests.</description>
                                    <value>#1</value>
                                </enumeratedValue>
                            </enumeratedValues>
                        </field>
                        <field>
                            <name>ADEIP</name>
                            <description>Address Error Interrupt Request Enable</description>
                            <lsb>23</lsb>
                            <msb>23</msb>
                            <access>read-write</access>
                            <enumeratedValues>
                                <enumeratedValue>
                                    <name>0</name>
                                    <description>Disable address error interrupt requests</description>
                                    <value>#0</value>
                                </enumeratedValue>
                                <enumeratedValue>
                                    <name>1</name>
                                    <description>Enable address error interrupt requests.</description>
                                    <value>#1</value>
                                </enumeratedValue>
                            </enumeratedValues>
                        </field>
                        <field>
                            <name>RFCOFIP</name>
                            <description>Receive Frame Counter Overflow Interrupt Request Enable</description>
                            <lsb>24</lsb>
                            <msb>24</msb>
                            <access>read-write</access>
                            <enumeratedValues>
                                <enumeratedValue>
                                    <name>0</name>
                                    <description>Disable receive frame counter overflow interrupt requests </description>
                                    <value>#0</value>
                                </enumeratedValue>
                                <enumeratedValue>
                                    <name>1</name>
                                    <description>Enable receive frame counter overflow interrupt requests. </description>
                                    <value>#1</value>
                                </enumeratedValue>
                            </enumeratedValues>
                        </field>
                        <field>
                            <name>RABTIP</name>
                            <description>Receive Abort Detect Interrupt Request Enable</description>
                            <lsb>25</lsb>
                            <msb>25</msb>
                            <access>read-write</access>
                            <enumeratedValues>
                                <enumeratedValue>
                                    <name>0</name>
                                    <description>Disable receive abort detected interrupt requests</description>
                                    <value>#0</value>
                                </enumeratedValue>
                                <enumeratedValue>
                                    <name>1</name>
                                    <description>Enable receive abort detected interrupt requests.</description>
                                    <value>#1</value>
                                </enumeratedValue>
                            </enumeratedValues>
                        </field>
                        <field>
                            <name>TABTIP</name>
                            <description>Transmit Abort Detect Interrupt Request Enable</description>
                            <lsb>26</lsb>
                            <msb>26</msb>
                            <access>read-write</access>
                            <enumeratedValues>
                                <enumeratedValue>
                                    <name>0</name>
                                    <description>Disable transmit abort detected interrupt requests</description>
                                    <value>#0</value>
                                </enumeratedValue>
                                <enumeratedValue>
                                    <name>1</name>
                                    <description>Enable transmit abort detected interrupt requests.</description>
                                    <value>#1</value>
                                </enumeratedValue>
                            </enumeratedValues>
                        </field>
                        <field>
                            <name>TWBIP</name>
                            <description>Write-Back Complete Interrupt Request Enable</description>
                            <lsb>30</lsb>
                            <msb>30</msb>
                            <access>read-write</access>
                            <enumeratedValues>
                                <enumeratedValue>
                                    <name>0</name>
                                    <description>Disable write-back complete interrupt requests</description>
                                    <value>#0</value>
                                </enumeratedValue>
                                <enumeratedValue>
                                    <name>1</name>
                                    <description>Enable write-back complete interrupt requests.</description>
                                    <value>#1</value>
                                </enumeratedValue>
                            </enumeratedValues>
                        </field>
                    </fields>
                </register>
                <register>
                    <name>TRSCER</name>
                    <description>ETHERC/EDMAC Transmit/Receive Status Copy Enable Register</description>
                    <addressOffset>0x38</addressOffset>
                    <size>32</size>
                    <access>read-write</access>
                    <resetValue>0x00000000</resetValue>
                    <resetMask>0xffffffff</resetMask>
                    <fields>
                        <field>
                            <name>RRFCE</name>
                            <description>RRF Flag Copy Enable</description>
                            <lsb>4</lsb>
                            <msb>4</msb>
                            <access>read-write</access>
                            <enumeratedValues>
                                <enumeratedValue>
                                    <name>0</name>
                                    <description>Reflect the EESR.RRF flag status in the RD0.RFE bit of the receive descriptor </description>
                                    <value>#0</value>
                                </enumeratedValue>
                                <enumeratedValue>
                                    <name>1</name>
                                    <description>Do not reflect the EESR.RRF flag status in the RD0.RFE bit of the receive descriptor. </description>
                                    <value>#1</value>
                                </enumeratedValue>
                            </enumeratedValues>
                        </field>
                        <field>
                            <name>RMAFCE</name>
                            <description>RMAF Flag Copy Enable</description>
                            <lsb>7</lsb>
                            <msb>7</msb>
                            <access>read-write</access>
                            <enumeratedValues>
                                <enumeratedValue>
                                    <name>0</name>
                                    <description>Reflect the EESR.RMAF flag status in the RD0.RFE bit of the receive descriptor </description>
                                    <value>#0</value>
                                </enumeratedValue>
                                <enumeratedValue>
                                    <name>1</name>
                                    <description>Do not reflect the EESR.RMAF flag status in the RD0.RFE bit of the receive descriptor. </description>
                                    <value>#1</value>
                                </enumeratedValue>
                            </enumeratedValues>
                        </field>
                    </fields>
                </register>
                <register>
                    <name>RMFCR</name>
                    <description>Missed-Frame Counter Register</description>
                    <addressOffset>0x40</addressOffset>
                    <size>32</size>
                    <access>read-write</access>
                    <resetValue>0x00000000</resetValue>
                    <resetMask>0xffffffff</resetMask>
                    <fields>
                        <field>
                            <name>MFC</name>
                            <description>Missed-Frame Counter</description>
                            <lsb>0</lsb>
                            <msb>15</msb>
                            <access>read-write</access>
                        </field>
                    </fields>
                </register>
                <register>
                    <name>TFTR</name>
                    <description>Transmit FIFO Threshold Register</description>
                    <addressOffset>0x48</addressOffset>
                    <size>32</size>
                    <access>read-write</access>
                    <resetValue>0x00000000</resetValue>
                    <resetMask>0xffffffff</resetMask>
                    <fields>
                        <field>
                            <name>TFT</name>
                            <description>Transmit FIFO Threshold</description>
                            <lsb>0</lsb>
                            <msb>10</msb>
                            <access>read-write</access>
                        </field>
                    </fields>
                </register>
                <register>
                    <name>FDR</name>
                    <description>FIFO Depth Register</description>
                    <addressOffset>0x50</addressOffset>
                    <size>32</size>
                    <access>read-write</access>
                    <resetValue>0x00000000</resetValue>
                    <resetMask>0xffffffff</resetMask>
                    <fields>
                        <field>
                            <name>RFD</name>
                            <description>Receive FIFO Depth</description>
                            <lsb>0</lsb>
                            <msb>4</msb>
                            <access>read-write</access>
                            <enumeratedValues>
                                <enumeratedValue>
                                    <name>0x0F</name>
                                    <description>4096 bytes</description>
                                    <value>0x0f</value>
                                </enumeratedValue>
                                <enumeratedValue>
                                    <name>Others</name>
                                    <description>settings prohibited</description>
                                    <isDefault>true</isDefault>
                                </enumeratedValue>
                            </enumeratedValues>
                        </field>
                        <field>
                            <name>TFD</name>
                            <description>Transmit FIFO Depth</description>
                            <lsb>8</lsb>
                            <msb>12</msb>
                            <access>read-write</access>
                            <enumeratedValues>
                                <enumeratedValue>
                                    <name>0x07</name>
                                    <description>2048 bytes</description>
                                    <value>0x07</value>
                                </enumeratedValue>
                                <enumeratedValue>
                                    <name>Others</name>
                                    <description>settings prohibited</description>
                                    <isDefault>true</isDefault>
                                </enumeratedValue>
                            </enumeratedValues>
                        </field>
                    </fields>
                </register>
                <register>
                    <name>RMCR</name>
                    <description>Receive Method Control Register</description>
                    <addressOffset>0x58</addressOffset>
                    <size>32</size>
                    <access>read-write</access>
                    <resetValue>0x00000000</resetValue>
                    <resetMask>0xffffffff</resetMask>
                    <fields>
                        <field>
                            <name>RNR</name>
                            <description>Receive Request Reset</description>
                            <lsb>0</lsb>
                            <msb>0</msb>
                            <access>read-write</access>
                            <enumeratedValues>
                                <enumeratedValue>
                                    <name>0</name>
                                    <description>EDRRR.RR bit (receive request bit) is cleared to 0 when one frame is received </description>
                                    <value>#0</value>
                                </enumeratedValue>
                                <enumeratedValue>
                                    <name>1</name>
                                    <description>EDRRR.RR bit (receive request bit) is not cleared to 0 when one frame is received. </description>
                                    <value>#1</value>
                                </enumeratedValue>
                            </enumeratedValues>
                        </field>
                    </fields>
                </register>
                <register>
                    <name>TFUCR</name>
                    <description>Transmit FIFO Underflow Counter</description>
                    <addressOffset>0x64</addressOffset>
                    <size>32</size>
                    <access>read-write</access>
                    <resetValue>0x00000000</resetValue>
                    <resetMask>0xffffffff</resetMask>
                    <fields>
                        <field>
                            <name>UNDER</name>
                            <description>Transmit FIFO Underflow Count</description>
                            <lsb>0</lsb>
                            <msb>15</msb>
                            <access>read-write</access>
                        </field>
                    </fields>
                </register>
                <register>
                    <name>RFOCR</name>
                    <description>Receive FIFO Overflow Counter</description>
                    <addressOffset>0x68</addressOffset>
                    <size>32</size>
                    <access>read-write</access>
                    <resetValue>0x00000000</resetValue>
                    <resetMask>0xffffffff</resetMask>
                    <fields>
                        <field>
                            <name>OVER</name>
                            <description>Receive FIFO Overflow Count</description>
                            <lsb>0</lsb>
                            <msb>15</msb>
                            <access>read-write</access>
                        </field>
                    </fields>
                </register>
                <register>
                    <name>IOSR</name>
                    <description>Independent Output Signal Setting Register</description>
                    <addressOffset>0x6C</addressOffset>
                    <size>32</size>
                    <access>read-write</access>
                    <resetValue>0x00000000</resetValue>
                    <resetMask>0xffffffff</resetMask>
                    <fields>
                        <field>
                            <name>ELB</name>
                            <description>External Loopback Mode</description>
                            <lsb>0</lsb>
                            <msb>0</msb>
                            <access>read-write</access>
                            <enumeratedValues>
                                <enumeratedValue>
                                    <name>0</name>
                                    <description>Output low on the ET0_EXOUT pin</description>
                                    <value>#0</value>
                                </enumeratedValue>
                                <enumeratedValue>
                                    <name>1</name>
                                    <description>Output high on the ET0_EXOUT pin.</description>
                                    <value>#1</value>
                                </enumeratedValue>
                            </enumeratedValues>
                        </field>
                    </fields>
                </register>
                <register>
                    <name>FCFTR</name>
                    <description>Flow Control Start FIFO Threshold Setting Register</description>
                    <addressOffset>0x70</addressOffset>
                    <size>32</size>
                    <access>read-write</access>
                    <resetValue>0x00070007</resetValue>
                    <resetMask>0xffffffff</resetMask>
                    <fields>
                        <field>
                            <name>RFDO</name>
                            <description>Receive FIFO Data PAUSE Output Threshold</description>
                            <lsb>0</lsb>
                            <msb>2</msb>
                            <access>read-write</access>
                        </field>
                        <field>
                            <name>RFFO</name>
                            <description>Receive FIFO Frame PAUSE Output Threshold</description>
                            <lsb>16</lsb>
                            <msb>18</msb>
                            <access>read-write</access>
                        </field>
                    </fields>
                </register>
                <register>
                    <name>RPADIR</name>
                    <description>Receive Data Padding Insert Register</description>
                    <addressOffset>0x78</addressOffset>
                    <size>32</size>
                    <access>read-write</access>
                    <resetValue>0x00000000</resetValue>
                    <resetMask>0xffffffff</resetMask>
                    <fields>
                        <field>
                            <name>PADR</name>
                            <description>Padding Slot</description>
                            <lsb>0</lsb>
                            <msb>5</msb>
                            <access>read-write</access>
                        </field>
                        <field>
                            <name>PADS</name>
                            <description>Padding Size</description>
                            <lsb>16</lsb>
                            <msb>17</msb>
                            <access>read-write</access>
                            <enumeratedValues>
                                <enumeratedValue>
                                    <name>00</name>
                                    <description>Do not insert padding</description>
                                    <value>#00</value>
                                </enumeratedValue>
                                <enumeratedValue>
                                    <name>Others</name>
                                    <description>settings prohibited</description>
                                    <isDefault>true</isDefault>
                                </enumeratedValue>
                            </enumeratedValues>
                        </field>
                    </fields>
                </register>
                <register>
                    <name>TRIMD</name>
                    <description>Transmit Interrupt Setting Register</description>
                    <addressOffset>0x7C</addressOffset>
                    <size>32</size>
                    <access>read-write</access>
                    <resetValue>0x00000000</resetValue>
                    <resetMask>0xffffffff</resetMask>
                    <fields>
                        <field>
                            <name>TIS</name>
                            <description>Transmit Interrupt Enable</description>
                            <lsb>0</lsb>
                            <msb>0</msb>
                            <access>read-write</access>
                            <enumeratedValues>
                                <enumeratedValue>
                                    <name>0</name>
                                    <description>Disable transmit interrupts</description>
                                    <value>#0</value>
                                </enumeratedValue>
                                <enumeratedValue>
                                    <name>1</name>
                                    <description>Enable transmit Interrupts.</description>
                                    <value>#1</value>
                                </enumeratedValue>
                            </enumeratedValues>
                        </field>
                        <field>
                            <name>TIM</name>
                            <description>Transmit Interrupt Mode</description>
                            <lsb>4</lsb>
                            <msb>4</msb>
                            <access>read-write</access>
                            <enumeratedValues>
                                <enumeratedValue>
                                    <name>0</name>
                                    <description>Select transmission complete interrupt mode, where an interrupt occurs when a frame is transmitted </description>
                                    <value>#0</value>
                                </enumeratedValue>
                                <enumeratedValue>
                                    <name>1</name>
                                    <description>Select write-back complete interrupt mode, where an interrupt occurs when write-back to the transmit descriptor is complete while the TWBI bit is 1. </description>
                                    <value>#1</value>
                                </enumeratedValue>
                            </enumeratedValues>
                        </field>
                    </fields>
                </register>
                <register>
                    <name>RBWAR</name>
                    <description>Receive Buffer Write Address Register</description>
                    <addressOffset>0xC8</addressOffset>
                    <size>32</size>
                    <access>read-only</access>
                    <resetValue>0x00000000</resetValue>
                    <resetMask>0xffffffff</resetMask>
                </register>
                <register>
                    <name>RDFAR</name>
                    <description>Receive Descriptor Fetch Address Register</description>
                    <addressOffset>0xCC</addressOffset>
                    <size>32</size>
                    <access>read-only</access>
                    <resetValue>0x00000000</resetValue>
                    <resetMask>0xffffffff</resetMask>
                </register>
                <register>
                    <name>TBRAR</name>
                    <description>Transmit Buffer Read Address Register</description>
                    <addressOffset>0xD4</addressOffset>
                    <size>32</size>
                    <access>read-only</access>
                    <resetValue>0x00000000</resetValue>
                    <resetMask>0xffffffff</resetMask>
                </register>
                <register>
                    <name>TDFAR</name>
                    <description>Transmit Descriptor Fetch Address Register</description>
                    <addressOffset>0xD8</addressOffset>
                    <size>32</size>
                    <access>read-only</access>
                    <resetValue>0x00000000</resetValue>
                    <resetMask>0xffffffff</resetMask>
                </register>
            </registers>
        </peripheral>
        <peripheral>
            <name>ETHERC0</name>
            <description>Ethernet Controller Channel 0</description>
            <baseAddress>0x40354100</baseAddress>
            <addressBlock>
                <offset>0x00</offset>
                <size>4</size>
                <usage>registers</usage>
            </addressBlock>
            <addressBlock>
                <offset>0x08</offset>
                <size>4</size>
                <usage>registers</usage>
            </addressBlock>
            <addressBlock>
                <offset>0x10</offset>
                <size>4</size>
                <usage>registers</usage>
            </addressBlock>
            <addressBlock>
                <offset>0x18</offset>
                <size>4</size>
                <usage>registers</usage>
            </addressBlock>
            <addressBlock>
                <offset>0x20</offset>
                <size>4</size>
                <usage>registers</usage>
            </addressBlock>
            <addressBlock>
                <offset>0x28</offset>
                <size>4</size>
                <usage>registers</usage>
            </addressBlock>
            <addressBlock>
                <offset>0x40</offset>
                <size>4</size>
                <usage>registers</usage>
            </addressBlock>
            <addressBlock>
                <offset>0x50</offset>
                <size>12</size>
                <usage>registers</usage>
            </addressBlock>
            <addressBlock>
                <offset>0x60</offset>
                <size>16</size>
                <usage>registers</usage>
            </addressBlock>
            <addressBlock>
                <offset>0xC0</offset>
                <size>4</size>
                <usage>registers</usage>
            </addressBlock>
            <addressBlock>
                <offset>0xC8</offset>
                <size>4</size>
                <usage>registers</usage>
            </addressBlock>
            <addressBlock>
                <offset>0xD0</offset>
                <size>16</size>
                <usage>registers</usage>
            </addressBlock>
            <addressBlock>
                <offset>0xE4</offset>
                <size>24</size>
                <usage>registers</usage>
            </addressBlock>
            <registers>
                <register>
                    <name>ECMR</name>
                    <description>ETHERC Mode Register</description>
                    <addressOffset>0x00</addressOffset>
                    <size>32</size>
                    <access>read-write</access>
                    <resetValue>0x00000000</resetValue>
                    <resetMask>0xffffffff</resetMask>
                    <fields>
                        <field>
                            <name>PRM</name>
                            <description>Promiscuous Mode</description>
                            <lsb>0</lsb>
                            <msb>0</msb>
                            <access>read-write</access>
                            <enumeratedValues>
                                <enumeratedValue>
                                    <name>0</name>
                                    <description>Disable promiscuous mode</description>
                                    <value>#0</value>
                                </enumeratedValue>
                                <enumeratedValue>
                                    <name>1</name>
                                    <description>Enable promiscuous mode.</description>
                                    <value>#1</value>
                                </enumeratedValue>
                            </enumeratedValues>
                        </field>
                        <field>
                            <name>DM</name>
                            <description>Duplex Mode</description>
                            <lsb>1</lsb>
                            <msb>1</msb>
                            <access>read-write</access>
                            <enumeratedValues>
                                <enumeratedValue>
                                    <name>0</name>
                                    <description>Half-duplex mode</description>
                                    <value>#0</value>
                                </enumeratedValue>
                                <enumeratedValue>
                                    <name>1</name>
                                    <description>Full-duplex mode.</description>
                                    <value>#1</value>
                                </enumeratedValue>
                            </enumeratedValues>
                        </field>
                        <field>
                            <name>RTM</name>
                            <description>Bit Rate</description>
                            <lsb>2</lsb>
                            <msb>2</msb>
                            <access>read-write</access>
                            <enumeratedValues>
                                <enumeratedValue>
                                    <name>0</name>
                                    <description>10 Mbps</description>
                                    <value>#0</value>
                                </enumeratedValue>
                                <enumeratedValue>
                                    <name>1</name>
                                    <description>100 Mbps.</description>
                                    <value>#1</value>
                                </enumeratedValue>
                            </enumeratedValues>
                        </field>
                        <field>
                            <name>ILB</name>
                            <description>Internal Loopback Mode</description>
                            <lsb>3</lsb>
                            <msb>3</msb>
                            <access>read-write</access>
                            <enumeratedValues>
                                <enumeratedValue>
                                    <name>0</name>
                                    <description>Perform normal data transmission or reception</description>
                                    <value>#0</value>
                                </enumeratedValue>
                                <enumeratedValue>
                                    <name>1</name>
                                    <description>Loop data back in the ETHERC when full-duplex mode is selected.</description>
                                    <value>#1</value>
                                </enumeratedValue>
                            </enumeratedValues>
                        </field>
                        <field>
                            <name>TE</name>
                            <description>Transmission Enable</description>
                            <lsb>5</lsb>
                            <msb>5</msb>
                            <access>read-write</access>
                            <enumeratedValues>
                                <enumeratedValue>
                                    <name>0</name>
                                    <description>Disable transmit function</description>
                                    <value>#0</value>
                                </enumeratedValue>
                                <enumeratedValue>
                                    <name>1</name>
                                    <description>Enable transmit function.</description>
                                    <value>#1</value>
                                </enumeratedValue>
                            </enumeratedValues>
                        </field>
                        <field>
                            <name>RE</name>
                            <description>Reception Enable</description>
                            <lsb>6</lsb>
                            <msb>6</msb>
                            <access>read-write</access>
                            <enumeratedValues>
                                <enumeratedValue>
                                    <name>0</name>
                                    <description>Disable receive function</description>
                                    <value>#0</value>
                                </enumeratedValue>
                                <enumeratedValue>
                                    <name>1</name>
                                    <description>Enable receive function.</description>
                                    <value>#1</value>
                                </enumeratedValue>
                            </enumeratedValues>
                        </field>
                        <field>
                            <name>MPDE</name>
                            <description>Magic Packet Detection Enable</description>
                            <lsb>9</lsb>
                            <msb>9</msb>
                            <access>read-write</access>
                            <enumeratedValues>
                                <enumeratedValue>
                                    <name>0</name>
                                    <description>Disable Magic Packet detection</description>
                                    <value>#0</value>
                                </enumeratedValue>
                                <enumeratedValue>
                                    <name>1</name>
                                    <description>Enable Magic Packet detection.</description>
                                    <value>#1</value>
                                </enumeratedValue>
                            </enumeratedValues>
                        </field>
                        <field>
                            <name>PRCEF</name>
                            <description>CRC Error Frame Receive Mode</description>
                            <lsb>12</lsb>
                            <msb>12</msb>
                            <access>read-write</access>
                            <enumeratedValues>
                                <enumeratedValue>
                                    <name>0</name>
                                    <description>Notify EDMAC of a CRC error</description>
                                    <value>#0</value>
                                </enumeratedValue>
                                <enumeratedValue>
                                    <name>1</name>
                                    <description>Do not notify EDMAC of a CRC error.</description>
                                    <value>#1</value>
                                </enumeratedValue>
                            </enumeratedValues>
                        </field>
                        <field>
                            <name>TXF</name>
                            <description>Transmit Flow Control Operating Mode</description>
                            <lsb>16</lsb>
                            <msb>16</msb>
                            <access>read-write</access>
                            <enumeratedValues>
                                <enumeratedValue>
                                    <name>0</name>
                                    <description>Disable automatic PAUSE frame transmission (PAUSE frame is not automatically transmitted) </description>
                                    <value>#0</value>
                                </enumeratedValue>
                                <enumeratedValue>
                                    <name>1</name>
                                    <description>Enable automatic PAUSE frame transmission (PAUSE frame is automatically transmitted as required). </description>
                                    <value>#1</value>
                                </enumeratedValue>
                            </enumeratedValues>
                        </field>
                        <field>
                            <name>RXF</name>
                            <description>Receive Flow Control Operating Mode</description>
                            <lsb>17</lsb>
                            <msb>17</msb>
                            <access>read-write</access>
                            <enumeratedValues>
                                <enumeratedValue>
                                    <name>0</name>
                                    <description>Disable PAUSE frame detection</description>
                                    <value>#0</value>
                                </enumeratedValue>
                                <enumeratedValue>
                                    <name>1</name>
                                    <description>Enable PAUSE frame detection.</description>
                                    <value>#1</value>
                                </enumeratedValue>
                            </enumeratedValues>
                        </field>
                        <field>
                            <name>PFR</name>
                            <description>PAUSE Frame Receive Mode</description>
                            <lsb>18</lsb>
                            <msb>18</msb>
                            <access>read-write</access>
                            <enumeratedValues>
                                <enumeratedValue>
                                    <name>0</name>
                                    <description>Do not transfer PAUSE frame to the EDMAC</description>
                                    <value>#0</value>
                                </enumeratedValue>
                                <enumeratedValue>
                                    <name>1</name>
                                    <description>Transfer PAUSE frame to the EDMAC.</description>
                                    <value>#1</value>
                                </enumeratedValue>
                            </enumeratedValues>
                        </field>
                        <field>
                            <name>ZPF</name>
                            <description>0 Time PAUSE Frame Enable</description>
                            <lsb>19</lsb>
                            <msb>19</msb>
                            <access>read-write</access>
                            <enumeratedValues>
                                <enumeratedValue>
                                    <name>0</name>
                                    <description>Do not use PAUSE frames that containing a pause_time parameter of 0 </description>
                                    <value>#0</value>
                                </enumeratedValue>
                                <enumeratedValue>
                                    <name>1</name>
                                    <description>Use PAUSE frames that containing a pause_time parameter of 0.</description>
                                    <value>#1</value>
                                </enumeratedValue>
                            </enumeratedValues>
                        </field>
                        <field>
                            <name>TPC</name>
                            <description>PAUSE Frame Transmit</description>
                            <lsb>20</lsb>
                            <msb>20</msb>
                            <access>read-write</access>
                            <enumeratedValues>
                                <enumeratedValue>
                                    <name>0</name>
                                    <description>Transmit PAUSE frame even during a PAUSE period</description>
                                    <value>#0</value>
                                </enumeratedValue>
                                <enumeratedValue>
                                    <name>1</name>
                                    <description>Do not transmit PAUSE frame during a PAUSE period.</description>
                                    <value>#1</value>
                                </enumeratedValue>
                            </enumeratedValues>
                        </field>
                    </fields>
                </register>
                <register>
                    <name>RFLR</name>
                    <description>Receive Frame Maximum Length Register</description>
                    <addressOffset>0x08</addressOffset>
                    <size>32</size>
                    <access>read-write</access>
                    <resetValue>0x00000000</resetValue>
                    <resetMask>0xffffffff</resetMask>
                    <fields>
                        <field>
                            <name>RFL</name>
                            <description>Receive Frame Maximum Length</description>
                            <lsb>0</lsb>
                            <msb>11</msb>
                            <access>read-write</access>
                        </field>
                    </fields>
                </register>
                <register>
                    <name>ECSR</name>
                    <description>ETHERC Status Register</description>
                    <addressOffset>0x10</addressOffset>
                    <size>32</size>
                    <access>read-write</access>
                    <resetValue>0x00000000</resetValue>
                    <resetMask>0xffffffff</resetMask>
                    <fields>
                        <field>
                            <name>ICD</name>
                            <description>False Carrier Detect Flag</description>
                            <lsb>0</lsb>
                            <msb>0</msb>
                            <access>read-write</access>
                            <enumeratedValues>
                                <enumeratedValue>
                                    <name>0</name>
                                    <description>PHY-LSI has not detected a false carrier on the line</description>
                                    <value>#0</value>
                                </enumeratedValue>
                                <enumeratedValue>
                                    <name>1</name>
                                    <description>PHY-LSI detected a false carrier on the line.</description>
                                    <value>#1</value>
                                </enumeratedValue>
                            </enumeratedValues>
                        </field>
                        <field>
                            <name>MPD</name>
                            <description>Magic Packet Detect Flag</description>
                            <lsb>1</lsb>
                            <msb>1</msb>
                            <access>read-write</access>
                            <enumeratedValues>
                                <enumeratedValue>
                                    <name>0</name>
                                    <description>Magic Packet not detected</description>
                                    <value>#0</value>
                                </enumeratedValue>
                                <enumeratedValue>
                                    <name>1</name>
                                    <description>Magic Packet detected.</description>
                                    <value>#1</value>
                                </enumeratedValue>
                            </enumeratedValues>
                        </field>
                        <field>
                            <name>LCHNG</name>
                            <description>Link Signal Change Flag</description>
                            <lsb>2</lsb>
                            <msb>2</msb>
                            <access>read-write</access>
                            <enumeratedValues>
                                <enumeratedValue>
                                    <name>0</name>
                                    <description>Change in the ET0_LINKSTA signal not detected</description>
                                    <value>#0</value>
                                </enumeratedValue>
                                <enumeratedValue>
                                    <name>1</name>
                                    <description>Change in the ET0_LINKSTA signal detected (high to low, or low to high). </description>
                                    <value>#1</value>
                                </enumeratedValue>
                            </enumeratedValues>
                        </field>
                        <field>
                            <name>PSRTO</name>
                            <description>PAUSE Frame Retransmit Over Flag</description>
                            <lsb>4</lsb>
                            <msb>4</msb>
                            <access>read-write</access>
                            <enumeratedValues>
                                <enumeratedValue>
                                    <name>0</name>
                                    <description>PAUSE frame retransmit count has not reached the upper limit</description>
                                    <value>#0</value>
                                </enumeratedValue>
                                <enumeratedValue>
                                    <name>1</name>
                                    <description>PAUSE frame retransmit count reached the upper limit.</description>
                                    <value>#1</value>
                                </enumeratedValue>
                            </enumeratedValues>
                        </field>
                        <field>
                            <name>BFR</name>
                            <description>Continuous Broadcast Frame Reception Flag</description>
                            <lsb>5</lsb>
                            <msb>5</msb>
                            <access>read-write</access>
                            <enumeratedValues>
                                <enumeratedValue>
                                    <name>0</name>
                                    <description>Continuous reception of broadcast frames not detected</description>
                                    <value>#0</value>
                                </enumeratedValue>
                                <enumeratedValue>
                                    <name>1</name>
                                    <description>Continuous reception of broadcast frames detected.</description>
                                    <value>#1</value>
                                </enumeratedValue>
                            </enumeratedValues>
                        </field>
                    </fields>
                </register>
                <register>
                    <name>ECSIPR</name>
                    <description>ETHERC Interrupt Enable Register</description>
                    <addressOffset>0x18</addressOffset>
                    <size>32</size>
                    <access>read-write</access>
                    <resetValue>0x00000000</resetValue>
                    <resetMask>0xffffffff</resetMask>
                    <fields>
                        <field>
                            <name>ICDIP</name>
                            <description>False Carrier Detect Interrupt Enable</description>
                            <lsb>0</lsb>
                            <msb>0</msb>
                            <access>read-write</access>
                            <enumeratedValues>
                                <enumeratedValue>
                                    <name>0</name>
                                    <description>Disable interrupt notification</description>
                                    <value>#0</value>
                                </enumeratedValue>
                                <enumeratedValue>
                                    <name>1</name>
                                    <description>Enable interrupt notification.</description>
                                    <value>#1</value>
                                </enumeratedValue>
                            </enumeratedValues>
                        </field>
                        <field>
                            <name>MPDIP</name>
                            <description>Magic Packet Detect Interrupt Enable</description>
                            <lsb>1</lsb>
                            <msb>1</msb>
                            <access>read-write</access>
                            <enumeratedValues>
                                <enumeratedValue>
                                    <name>0</name>
                                    <description>Disable interrupt notification</description>
                                    <value>#0</value>
                                </enumeratedValue>
                                <enumeratedValue>
                                    <name>1</name>
                                    <description>Enable interrupt notification.</description>
                                    <value>#1</value>
                                </enumeratedValue>
                            </enumeratedValues>
                        </field>
                        <field>
                            <name>LCHNGIP</name>
                            <description>LINK Signal Change Interrupt Enable</description>
                            <lsb>2</lsb>
                            <msb>2</msb>
                            <access>read-write</access>
                            <enumeratedValues>
                                <enumeratedValue>
                                    <name>0</name>
                                    <description>Disable interrupt notification</description>
                                    <value>#0</value>
                                </enumeratedValue>
                                <enumeratedValue>
                                    <name>1</name>
                                    <description>Enable interrupt notification.</description>
                                    <value>#1</value>
                                </enumeratedValue>
                            </enumeratedValues>
                        </field>
                        <field>
                            <name>PSRTOIP</name>
                            <description>PAUSE Frame Retransmit Over Interrupt Enable</description>
                            <lsb>4</lsb>
                            <msb>4</msb>
                            <access>read-write</access>
                            <enumeratedValues>
                                <enumeratedValue>
                                    <name>0</name>
                                    <description>Disable interrupt notification</description>
                                    <value>#0</value>
                                </enumeratedValue>
                                <enumeratedValue>
                                    <name>1</name>
                                    <description>Enable interrupt notification.</description>
                                    <value>#1</value>
                                </enumeratedValue>
                            </enumeratedValues>
                        </field>
                        <field>
                            <name>BFSIPR</name>
                            <description>Continuous Broadcast Frame Reception Interrupt Enable</description>
                            <lsb>5</lsb>
                            <msb>5</msb>
                            <access>read-write</access>
                            <enumeratedValues>
                                <enumeratedValue>
                                    <name>0</name>
                                    <description>Disable interrupt notification</description>
                                    <value>#0</value>
                                </enumeratedValue>
                                <enumeratedValue>
                                    <name>1</name>
                                    <description>Enable interrupt notification.</description>
                                    <value>#1</value>
                                </enumeratedValue>
                            </enumeratedValues>
                        </field>
                    </fields>
                </register>
                <register>
                    <name>PIR</name>
                    <description>PHY Interface Register</description>
                    <addressOffset>0x20</addressOffset>
                    <size>32</size>
                    <access>read-write</access>
                    <resetValue>0x00000000</resetValue>
                    <resetMask>0xfffffff7</resetMask>
                    <fields>
                        <field>
                            <name>MDC</name>
                            <description>MII/RMII Management Data Clock</description>
                            <lsb>0</lsb>
                            <msb>0</msb>
                            <access>read-write</access>
                        </field>
                        <field>
                            <name>MMD</name>
                            <description>MII/RMII Management Mode</description>
                            <lsb>1</lsb>
                            <msb>1</msb>
                            <access>read-write</access>
                            <enumeratedValues>
                                <enumeratedValue>
                                    <name>0</name>
                                    <description>Read</description>
                                    <value>#0</value>
                                </enumeratedValue>
                                <enumeratedValue>
                                    <name>1</name>
                                    <description>Write.</description>
                                    <value>#1</value>
                                </enumeratedValue>
                            </enumeratedValues>
                        </field>
                        <field>
                            <name>MDO</name>
                            <description>MII/RMII Management Data-Out</description>
                            <lsb>2</lsb>
                            <msb>2</msb>
                            <access>read-write</access>
                        </field>
                        <field>
                            <name>MDI</name>
                            <description>MII/RMII Management Data-In</description>
                            <lsb>3</lsb>
                            <msb>3</msb>
                            <access>read-only</access>
                        </field>
                    </fields>
                </register>
                <register>
                    <name>PSR</name>
                    <description>PHY Status Register</description>
                    <addressOffset>0x28</addressOffset>
                    <size>32</size>
                    <access>read-only</access>
                    <resetValue>0x00000000</resetValue>
                    <resetMask>0xfffffffe</resetMask>
                    <fields>
                        <field>
                            <name>LMON</name>
                            <description>ET0_LINKSTA Pin Status Flag</description>
                            <lsb>0</lsb>
                            <msb>0</msb>
                            <access>read-only</access>
                        </field>
                    </fields>
                </register>
                <register>
                    <name>RDMLR</name>
                    <description>Random Number Generation Counter Upper Limit Setting Register</description>
                    <addressOffset>0x40</addressOffset>
                    <size>32</size>
                    <access>read-write</access>
                    <resetValue>0x00000000</resetValue>
                    <resetMask>0xffff0000</resetMask>
                    <fields>
                        <field>
                            <name>RMD</name>
                            <description>Random Number Generation Counter</description>
                            <lsb>0</lsb>
                            <msb>19</msb>
                            <access>read-write</access>
                        </field>
                    </fields>
                </register>
                <register>
                    <name>IPGR</name>
                    <description>Interpacket Gap Register</description>
                    <addressOffset>0x50</addressOffset>
                    <size>32</size>
                    <access>read-write</access>
                    <resetValue>0x00000014</resetValue>
                    <resetMask>0xffffffff</resetMask>
                    <fields>
                        <field>
                            <name>IPG</name>
                            <lsb>0</lsb>
                            <msb>4</msb>
                            <access>read-write</access>
                        </field>
                    </fields>
                </register>
                <register>
                    <name>APR</name>
                    <description>Automatic PAUSE Frame Register</description>
                    <addressOffset>0x54</addressOffset>
                    <size>32</size>
                    <access>read-write</access>
                    <resetValue>0x00000000</resetValue>
                    <resetMask>0xffffffff</resetMask>
                    <fields>
                        <field>
                            <name>AP</name>
                            <description>Automatic PAUSE Time Setting</description>
                            <lsb>0</lsb>
                            <msb>15</msb>
                            <access>read-write</access>
                        </field>
                    </fields>
                </register>
                <register>
                    <name>MPR</name>
                    <description>Manual PAUSE Frame Register</description>
                    <addressOffset>0x58</addressOffset>
                    <size>32</size>
                    <access>read-write</access>
                    <resetValue>0x00000000</resetValue>
                    <resetMask>0xffff0000</resetMask>
                    <fields>
                        <field>
                            <name>MP</name>
                            <description>Manual PAUSE Time Setting</description>
                            <lsb>0</lsb>
                            <msb>15</msb>
                            <access>read-write</access>
                        </field>
                    </fields>
                </register>
                <register>
                    <name>RFCF</name>
                    <description>Received PAUSE Frame Counter</description>
                    <addressOffset>0x60</addressOffset>
                    <size>32</size>
                    <access>read-only</access>
                    <resetValue>0x00000000</resetValue>
                    <resetMask>0xffffffff</resetMask>
                    <fields>
                        <field>
                            <name>RPAUSE</name>
                            <description>Received PAUSE Frame Count</description>
                            <lsb>0</lsb>
                            <msb>7</msb>
                            <access>read-only</access>
                        </field>
                    </fields>
                </register>
                <register>
                    <name>TPAUSER</name>
                    <description>PAUSE Frame Retransmit Count Setting Register</description>
                    <addressOffset>0x64</addressOffset>
                    <size>32</size>
                    <access>read-write</access>
                    <resetValue>0x00000000</resetValue>
                    <resetMask>0xffffffff</resetMask>
                    <fields>
                        <field>
                            <name>TPAUSE</name>
                            <lsb>0</lsb>
                            <msb>15</msb>
                            <access>read-write</access>
                        </field>
                    </fields>
                </register>
                <register>
                    <name>TPAUSECR</name>
                    <description>PAUSE Frame Retransmit Counter</description>
                    <addressOffset>0x68</addressOffset>
                    <size>32</size>
                    <access>read-only</access>
                    <resetValue>0x00000000</resetValue>
                    <resetMask>0xffffffff</resetMask>
                    <fields>
                        <field>
                            <name>TXP</name>
                            <description>PAUSE Frame Retransmit Count</description>
                            <lsb>0</lsb>
                            <msb>7</msb>
                            <access>read-only</access>
                        </field>
                    </fields>
                </register>
                <register>
                    <name>BCFRR</name>
                    <description>Broadcast Frame Receive Count Setting Register</description>
                    <addressOffset>0x6C</addressOffset>
                    <size>32</size>
                    <access>read-write</access>
                    <resetValue>0x00000000</resetValue>
                    <resetMask>0xffffffff</resetMask>
                    <fields>
                        <field>
                            <name>BCF</name>
                            <lsb>0</lsb>
                            <msb>15</msb>
                            <access>read-write</access>
                        </field>
                    </fields>
                </register>
                <register>
                    <name>MAHR</name>
                    <description>MAC Address Upper Bit Register</description>
                    <addressOffset>0xC0</addressOffset>
                    <size>32</size>
                    <access>read-write</access>
                    <resetValue>0x00000000</resetValue>
                    <resetMask>0xffffffff</resetMask>
                    <fields>
                        <field>
                            <name>MAHR</name>
                            <description>MAC Address Upper Bit</description>
                            <lsb>0</lsb>
                            <msb>31</msb>
                            <access>read-write</access>
                        </field>
                    </fields>
                </register>
                <register>
                    <name>MALR</name>
                    <description>MAC Address Lower Bit Register</description>
                    <addressOffset>0xC8</addressOffset>
                    <size>32</size>
                    <access>read-write</access>
                    <resetValue>0x00000000</resetValue>
                    <resetMask>0xffffffff</resetMask>
                    <fields>
                        <field>
                            <name>MALR</name>
                            <description>MAC Address Lower Bit</description>
                            <lsb>0</lsb>
                            <msb>15</msb>
                            <access>read-write</access>
                        </field>
                    </fields>
                </register>
                <register>
                    <name>TROCR</name>
                    <description>Transmit Retry Over Counter Register</description>
                    <addressOffset>0xD0</addressOffset>
                    <size>32</size>
                    <access>read-write</access>
                    <resetValue>0x00000000</resetValue>
                    <resetMask>0xffffffff</resetMask>
                    <fields>
                        <field>
                            <name>TROCR</name>
                            <description>Transmit Retry Over Counter</description>
                            <lsb>0</lsb>
                            <msb>31</msb>
                            <access>read-write</access>
                        </field>
                    </fields>
                </register>
                <register>
                    <name>CDCR</name>
                    <description>Late Collision Detect Counter Register</description>
                    <addressOffset>0xD4</addressOffset>
                    <size>32</size>
                    <access>read-write</access>
                    <resetValue>0x00000000</resetValue>
                    <resetMask>0xffffffff</resetMask>
                    <fields>
                        <field>
                            <name>CDCR</name>
                            <description>Late Collision Detect Counter</description>
                            <lsb>0</lsb>
                            <msb>31</msb>
                            <access>read-write</access>
                        </field>
                    </fields>
                </register>
                <register>
                    <name>LCCR</name>
                    <description>Lost Carrier Counter Register</description>
                    <addressOffset>0xD8</addressOffset>
                    <size>32</size>
                    <access>read-write</access>
                    <resetValue>0x00000000</resetValue>
                    <resetMask>0xffffffff</resetMask>
                    <fields>
                        <field>
                            <name>LCCR</name>
                            <description>Lost Carrier Counter</description>
                            <lsb>0</lsb>
                            <msb>31</msb>
                            <access>read-write</access>
                        </field>
                    </fields>
                </register>
                <register>
                    <name>CNDCR</name>
                    <description>Carrier Not Detect Counter Register</description>
                    <addressOffset>0xDC</addressOffset>
                    <size>32</size>
                    <access>read-write</access>
                    <resetValue>0x00000000</resetValue>
                    <resetMask>0xffffffff</resetMask>
                    <fields>
                        <field>
                            <name>CNDCR</name>
                            <description>Carrier Not Detect Counter</description>
                            <lsb>0</lsb>
                            <msb>31</msb>
                            <access>read-write</access>
                        </field>
                    </fields>
                </register>
                <register>
                    <name>CEFCR</name>
                    <description>CRC Error Frame Receive Counter Register</description>
                    <addressOffset>0xE4</addressOffset>
                    <size>32</size>
                    <access>read-write</access>
                    <resetValue>0x00000000</resetValue>
                    <resetMask>0xffffffff</resetMask>
                    <fields>
                        <field>
                            <name>CEFCR</name>
                            <description>CRC Error Frame Receive Counter</description>
                            <lsb>0</lsb>
                            <msb>31</msb>
                            <access>read-write</access>
                        </field>
                    </fields>
                </register>
                <register>
                    <name>FRECR</name>
                    <description>Frame Receive Error Counter Register</description>
                    <addressOffset>0xE8</addressOffset>
                    <size>32</size>
                    <access>read-write</access>
                    <resetValue>0x00000000</resetValue>
                    <resetMask>0xffffffff</resetMask>
                    <fields>
                        <field>
                            <name>FRECR</name>
                            <description>Frame Receive Error Counter</description>
                            <lsb>0</lsb>
                            <msb>31</msb>
                            <access>read-write</access>
                        </field>
                    </fields>
                </register>
                <register>
                    <name>TSFRCR</name>
                    <description>Too-Short Frame Receive Counter Register</description>
                    <addressOffset>0xEC</addressOffset>
                    <size>32</size>
                    <access>read-write</access>
                    <resetValue>0x00000000</resetValue>
                    <resetMask>0xffffffff</resetMask>
                    <fields>
                        <field>
                            <name>TSFRCR</name>
                            <description>Too-Short Frame Receive Counter</description>
                            <lsb>0</lsb>
                            <msb>31</msb>
                            <access>read-write</access>
                        </field>
                    </fields>
                </register>
                <register>
                    <name>TLFRCR</name>
                    <description>Too-Long Frame Receive Counter Register</description>
                    <addressOffset>0xF0</addressOffset>
                    <size>32</size>
                    <access>read-write</access>
                    <resetValue>0x00000000</resetValue>
                    <resetMask>0xffffffff</resetMask>
                    <fields>
                        <field>
                            <name>TLFRCR</name>
                            <description>Too-Long Frame Receive Counter</description>
                            <lsb>0</lsb>
                            <msb>31</msb>
                            <access>read-write</access>
                        </field>
                    </fields>
                </register>
                <register>
                    <name>RFCR</name>
                    <description>Received Alignment Error Frame Counter Register</description>
                    <addressOffset>0xF4</addressOffset>
                    <size>32</size>
                    <access>read-write</access>
                    <resetValue>0x00000000</resetValue>
                    <resetMask>0xffffffff</resetMask>
                    <fields>
                        <field>
                            <name>RFCR</name>
                            <description>Received Alignment Error Frame Counter</description>
                            <lsb>0</lsb>
                            <msb>31</msb>
                            <access>read-write</access>
                        </field>
                    </fields>
                </register>
                <register>
                    <name>MAFCR</name>
                    <description>Multicast Address Frame Receive Counter Register</description>
                    <addressOffset>0xF8</addressOffset>
                    <size>32</size>
                    <access>read-write</access>
                    <resetValue>0x00000000</resetValue>
                    <resetMask>0xffffffff</resetMask>
                    <fields>
                        <field>
                            <name>MAFCR</name>
                            <description>Multicast Address Frame Receive Counter</description>
                            <lsb>0</lsb>
                            <msb>31</msb>
                            <access>read-write</access>
                        </field>
                    </fields>
                </register>
            </registers>
        </peripheral>
        <peripheral>
            <name>SCI0_B</name>
            <description>Serial Communication Interface</description>
            <baseAddress>0x40358000</baseAddress>
            <addressBlock>
                <offset>0x00</offset>
                <size>4</size>
                <usage>registers</usage>
            </addressBlock>
            <addressBlock>
                <offset>0x04</offset>
                <size>4</size>
                <usage>registers</usage>
            </addressBlock>
            <addressBlock>
                <offset>0x08</offset>
                <size>21</size>
                <usage>registers</usage>
            </addressBlock>
            <addressBlock>
                <offset>0x20</offset>
                <size>8</size>
                <usage>registers</usage>
            </addressBlock>
            <addressBlock>
                <offset>0x2C</offset>
                <size>20</size>
                <usage>registers</usage>
            </addressBlock>
            <addressBlock>
                <offset>0x48</offset>
                <size>28</size>
                <usage>registers</usage>
            </addressBlock>
            <addressBlock>
                <offset>0x68</offset>
                <size>20</size>
                <usage>registers</usage>
            </addressBlock>
            <registers>
                <register>
                    <name>RDR</name>
                    <description>Receive Data Register</description>
                    <addressOffset>0x00</addressOffset>
                    <size>32</size>
                    <access>read-only</access>
                    <resetValue>0x00000000</resetValue>
                    <resetMask>0xffffffff</resetMask>
                    <fields>
                        <field>
                            <name>RDAT</name>
                            <description>Serial receive data</description>
                            <lsb>0</lsb>
                            <msb>8</msb>
                            <access>read-only</access>
                        </field>
                        <field>
                            <name>MPB</name>
                            <description>Multi-processor flag</description>
                            <lsb>9</lsb>
                            <msb>9</msb>
                            <access>read-only</access>
                            <enumeratedValues>
                                <enumeratedValue>
                                    <name>0</name>
                                    <description>Data transmission cycles</description>
                                    <value>#0</value>
                                </enumeratedValue>
                                <enumeratedValue>
                                    <name>1</name>
                                    <description>ID transmission cycles</description>
                                    <value>#1</value>
                                </enumeratedValue>
                            </enumeratedValues>
                        </field>
                        <field>
                            <name>DR</name>
                            <description>Receive data ready flag</description>
                            <lsb>10</lsb>
                            <msb>10</msb>
                            <access>read-only</access>
                        </field>
                        <field>
                            <name>FPER</name>
                            <description>FIFO parity error flag</description>
                            <lsb>11</lsb>
                            <msb>11</msb>
                            <access>read-only</access>
                            <enumeratedValues>
                                <enumeratedValue>
                                    <name>0</name>
                                    <description>There is no parity error in the data read from the receive-FIFO</description>
                                    <value>#0</value>
                                </enumeratedValue>
                                <enumeratedValue>
                                    <name>1</name>
                                    <description>There is parity error in the data read from the receive-FIFO</description>
                                    <value>#1</value>
                                </enumeratedValue>
                            </enumeratedValues>
                        </field>
                        <field>
                            <name>FFER</name>
                            <description>FIFO framing error flag</description>
                            <lsb>12</lsb>
                            <msb>12</msb>
                            <access>read-only</access>
                            <enumeratedValues>
                                <enumeratedValue>
                                    <name>0</name>
                                    <description>There is no framing error in the data read from the receive-FIFO</description>
                                    <value>#0</value>
                                </enumeratedValue>
                                <enumeratedValue>
                                    <name>1</name>
                                    <description>There is framing error in the data read from the receive-FIFO</description>
                                    <value>#1</value>
                                </enumeratedValue>
                            </enumeratedValues>
                        </field>
                        <field>
                            <name>ORER</name>
                            <description>Overrun Error flag</description>
                            <lsb>24</lsb>
                            <msb>24</msb>
                            <access>read-only</access>
                        </field>
                        <field>
                            <name>PER</name>
                            <description>Parity error flag</description>
                            <lsb>27</lsb>
                            <msb>27</msb>
                            <access>read-only</access>
                        </field>
                        <field>
                            <name>FER</name>
                            <description>Framing error flag</description>
                            <lsb>28</lsb>
                            <msb>28</msb>
                            <access>read-only</access>
                        </field>
                    </fields>
                </register>
                <register>
                    <name>RDR_BY</name>
                    <description>Receive Data Register</description>
                    <alternateRegister>RDR</alternateRegister>
                    <addressOffset>0x00</addressOffset>
                    <size>8</size>
                    <access>read-only</access>
                    <resetValue>0x00</resetValue>
                    <resetMask>0xff</resetMask>
                    <fields>
                        <field>
                            <name>ORER</name>
                            <description>Overrun Error flag</description>
                            <lsb>0</lsb>
                            <msb>0</msb>
                            <access>read-only</access>
                        </field>
                        <field>
                            <name>PER</name>
                            <description>Parity error flag</description>
                            <lsb>3</lsb>
                            <msb>3</msb>
                            <access>read-only</access>
                        </field>
                        <field>
                            <name>FER</name>
                            <description>Framing error flag</description>
                            <lsb>4</lsb>
                            <msb>4</msb>
                            <access>read-only</access>
                        </field>
                    </fields>
                </register>
                <register>
                    <name>TDR</name>
                    <description>Transmit Data Register</description>
                    <addressOffset>0x04</addressOffset>
                    <size>32</size>
                    <access>read-write</access>
                    <resetValue>0xffffffff</resetValue>
                    <resetMask>0xffffffff</resetMask>
                    <fields>
                        <field>
                            <name>TDAT</name>
                            <description>Serial transmit data</description>
                            <lsb>0</lsb>
                            <msb>8</msb>
                            <access>read-write</access>
                        </field>
                        <field>
                            <name>MPBT</name>
                            <description>Multi-processor transfer bit flag</description>
                            <lsb>9</lsb>
                            <msb>9</msb>
                            <access>read-write</access>
                            <enumeratedValues>
                                <enumeratedValue>
                                    <name>0</name>
                                    <description>Data transmission cycles</description>
                                    <value>#0</value>
                                </enumeratedValue>
                                <enumeratedValue>
                                    <name>1</name>
                                    <description>ID transmission cycles</description>
                                    <value>#1</value>
                                </enumeratedValue>
                            </enumeratedValues>
                        </field>
                        <field>
                            <name>TSYNC</name>
                            <description>Transmit SYNC data</description>
                            <lsb>12</lsb>
                            <msb>12</msb>
                            <access>read-write</access>
                            <enumeratedValues>
                                <enumeratedValue>
                                    <name>0</name>
                                    <description>The Start Bit is transmitted as DATA SYNC.</description>
                                    <value>#0</value>
                                </enumeratedValue>
                                <enumeratedValue>
                                    <name>1</name>
                                    <description>The Start Bit is transmitted as COMMAND SYNC.</description>
                                    <value>#1</value>
                                </enumeratedValue>
                            </enumeratedValues>
                        </field>
                    </fields>
                </register>
                <register>
                    <name>TDRLL</name>
                    <description>Transmit Data Register</description>
                    <alternateRegister>TDR</alternateRegister>
                    <addressOffset>0x04</addressOffset>
                    <size>16</size>
                    <access>read-write</access>
                    <resetValue>0xffff</resetValue>
                    <resetMask>0xffff</resetMask>
                </register>
                <register>
                    <name>TDRLH</name>
                    <description>Transmit Data Register</description>
                    <alternateRegister>TDR</alternateRegister>
                    <addressOffset>0x05</addressOffset>
                    <size>16</size>
                    <access>read-write</access>
                    <resetValue>0xffff</resetValue>
                    <resetMask>0xffff</resetMask>
                    <fields>
                        <field>
                            <name>TDAT</name>
                            <description>Serial transmit data</description>
                            <lsb>0</lsb>
                            <msb>0</msb>
                            <access>read-write</access>
                        </field>
                        <field>
                            <name>MPBT</name>
                            <description>Multi-processor transfer bit flag</description>
                            <lsb>1</lsb>
                            <msb>1</msb>
                            <access>read-write</access>
                            <enumeratedValues>
                                <enumeratedValue>
                                    <name>0</name>
                                    <description>Data transmission cycles</description>
                                    <value>#0</value>
                                </enumeratedValue>
                                <enumeratedValue>
                                    <name>1</name>
                                    <description>ID transmission cycles</description>
                                    <value>#1</value>
                                </enumeratedValue>
                            </enumeratedValues>
                        </field>
                        <field>
                            <name>TSYNC</name>
                            <description>Transmit SYNC data</description>
                            <lsb>4</lsb>
                            <msb>4</msb>
                            <access>read-write</access>
                            <enumeratedValues>
                                <enumeratedValue>
                                    <name>0</name>
                                    <description>The Start Bit is transmitted as DATA SYNC.</description>
                                    <value>#0</value>
                                </enumeratedValue>
                                <enumeratedValue>
                                    <name>1</name>
                                    <description>The Start Bit is transmitted as COMMAND SYNC.</description>
                                    <value>#1</value>
                                </enumeratedValue>
                            </enumeratedValues>
                        </field>
                    </fields>
                </register>
                <register>
                    <name>CCR0</name>
                    <description>Common Control Register 0</description>
                    <addressOffset>0x08</addressOffset>
                    <size>32</size>
                    <access>read-write</access>
                    <resetValue>0x00000000</resetValue>
                    <resetMask>0xffffffff</resetMask>
                    <fields>
                        <field>
                            <name>RE</name>
                            <description>Receive Enable</description>
                            <lsb>0</lsb>
                            <msb>0</msb>
                            <access>read-write</access>
                            <enumeratedValues>
                                <enumeratedValue>
                                    <name>0</name>
                                    <description>Serial reception is disabled</description>
                                    <value>#0</value>
                                </enumeratedValue>
                                <enumeratedValue>
                                    <name>1</name>
                                    <description>Serial reception is enabled</description>
                                    <value>#1</value>
                                </enumeratedValue>
                            </enumeratedValues>
                        </field>
                        <field>
                            <name>TE</name>
                            <description>Transmit Enable</description>
                            <lsb>4</lsb>
                            <msb>4</msb>
                            <access>read-write</access>
                            <enumeratedValues>
                                <enumeratedValue>
                                    <name>0</name>
                                    <description>Serial transmission is disabled</description>
                                    <value>#0</value>
                                </enumeratedValue>
                                <enumeratedValue>
                                    <name>1</name>
                                    <description>Serial transmission is enabled</description>
                                    <value>#1</value>
                                </enumeratedValue>
                            </enumeratedValues>
                        </field>
                        <field>
                            <name>MPIE</name>
                            <description>Multi-Processor Interrupt Enable</description>
                            <lsb>8</lsb>
                            <msb>8</msb>
                            <access>read-write</access>
                            <enumeratedValues>
                                <enumeratedValue>
                                    <name>0</name>
                                    <description>Non-multi-processor reception</description>
                                    <value>#0</value>
                                </enumeratedValue>
                                <enumeratedValue>
                                    <name>1</name>
                                    <description>Multi-processor reception When the data with the multi-processor bit set to 0 is received, the data is not read, and setting the status flags to 1 is disabled. When the data with the multi-processor bit set to 1 is received, the MPIE bit is automatically cleared to 0, and non-multi-processor reception is resumed. If you want to continue receiving operation using the multiprocessor function, set this bit to 1 sufficiently earlier than receiving the STOP bit of the next received frame (consider the synchronization delay time). </description>
                                    <value>#1</value>
                                </enumeratedValue>
                            </enumeratedValues>
                        </field>
                        <field>
                            <name>DCME</name>
                            <description>Data Compare Match Enable</description>
                            <lsb>9</lsb>
                            <msb>9</msb>
                            <access>read-write</access>
                            <enumeratedValues>
                                <enumeratedValue>
                                    <name>0</name>
                                    <description>Address match function is disabled</description>
                                    <value>#0</value>
                                </enumeratedValue>
                                <enumeratedValue>
                                    <name>1</name>
                                    <description>Address match function is enabled</description>
                                    <value>#1</value>
                                </enumeratedValue>
                            </enumeratedValues>
                        </field>
                        <field>
                            <name>IDSEL</name>
                            <description>ID Frame Select</description>
                            <lsb>10</lsb>
                            <msb>10</msb>
                            <access>read-write</access>
                            <enumeratedValues>
                                <enumeratedValue>
                                    <name>0</name>
                                    <description>Compare data irrespective of the value of the MPB bit</description>
                                    <value>#0</value>
                                </enumeratedValue>
                                <enumeratedValue>
                                    <name>1</name>
                                    <description>Compare data only when the MPB bit is 1 (ID frame)</description>
                                    <value>#1</value>
                                </enumeratedValue>
                            </enumeratedValues>
                        </field>
                        <field>
                            <name>RIE</name>
                            <description>Receive Interrupt Enable</description>
                            <lsb>16</lsb>
                            <msb>16</msb>
                            <access>read-write</access>
                            <enumeratedValues>
                                <enumeratedValue>
                                    <name>0</name>
                                    <description>SCIn_RXI and SCIn_ERI interrupt requests are disabled</description>
                                    <value>#0</value>
                                </enumeratedValue>
                                <enumeratedValue>
                                    <name>1</name>
                                    <description>SCIn_RXI and SCIn_ERI interrupt requests are enabled</description>
                                    <value>#1</value>
                                </enumeratedValue>
                            </enumeratedValues>
                        </field>
                        <field>
                            <name>TIE</name>
                            <description>Transmit Interrupt Enable</description>
                            <lsb>20</lsb>
                            <msb>20</msb>
                            <access>read-write</access>
                            <enumeratedValues>
                                <enumeratedValue>
                                    <name>0</name>
                                    <description>SCIn_TXI interrupt request is disabled</description>
                                    <value>#0</value>
                                </enumeratedValue>
                                <enumeratedValue>
                                    <name>1</name>
                                    <description>SCIn_TXI interrupt request is enabled</description>
                                    <value>#1</value>
                                </enumeratedValue>
                            </enumeratedValues>
                        </field>
                        <field>
                            <name>TEIE</name>
                            <description>Transmit End Interrupt Enable</description>
                            <lsb>21</lsb>
                            <msb>21</msb>
                            <access>read-write</access>
                            <enumeratedValues>
                                <enumeratedValue>
                                    <name>0</name>
                                    <description>SCIn_TEI interrupt request is disabled</description>
                                    <value>#0</value>
                                </enumeratedValue>
                                <enumeratedValue>
                                    <name>1</name>
                                    <description>SCIn_TEI interrupt request is enabled</description>
                                    <value>#1</value>
                                </enumeratedValue>
                            </enumeratedValues>
                        </field>
                        <field>
                            <name>SSE</name>
                            <description>SSn Pin Function Enable</description>
                            <lsb>24</lsb>
                            <msb>24</msb>
                            <access>read-write</access>
                            <enumeratedValues>
                                <enumeratedValue>
                                    <name>0</name>
                                    <description>SSn pin function is disabled</description>
                                    <value>#0</value>
                                </enumeratedValue>
                                <enumeratedValue>
                                    <name>1</name>
                                    <description>SSn pin function is enabled</description>
                                    <value>#1</value>
                                </enumeratedValue>
                            </enumeratedValues>
                        </field>
                    </fields>
                </register>
                <register>
                    <name>CCR1</name>
                    <description>Common Control Register 1</description>
                    <addressOffset>0x0C</addressOffset>
                    <size>32</size>
                    <access>read-write</access>
                    <resetValue>0x00000010</resetValue>
                    <resetMask>0xffffffff</resetMask>
                    <fields>
                        <field>
                            <name>CTSE</name>
                            <description>CTS Enable</description>
                            <lsb>0</lsb>
                            <msb>0</msb>
                            <access>read-write</access>
                            <enumeratedValues>
                                <enumeratedValue>
                                    <name>0</name>
                                    <description>CTS function is disabled (RTS output function is enabled)</description>
                                    <value>#0</value>
                                </enumeratedValue>
                                <enumeratedValue>
                                    <name>1</name>
                                    <description>CTS function is enabled</description>
                                    <value>#1</value>
                                </enumeratedValue>
                            </enumeratedValues>
                        </field>
                        <field>
                            <name>CTSPEN</name>
                            <description>CTS External Pin Enable</description>
                            <lsb>1</lsb>
                            <msb>1</msb>
                            <access>read-write</access>
                            <enumeratedValues>
                                <enumeratedValue>
                                    <name>0</name>
                                    <description>Alternate setting to use CTS and RTS functions as either 1 pin</description>
                                    <value>#0</value>
                                </enumeratedValue>
                                <enumeratedValue>
                                    <name>1</name>
                                    <description>Dedicated setting for separately using CTS and RTS functions with 2 pins</description>
                                    <value>#1</value>
                                </enumeratedValue>
                            </enumeratedValues>
                        </field>
                        <field>
                            <name>SPB2DT</name>
                            <description>Serial Port Break Data Select</description>
                            <lsb>4</lsb>
                            <msb>4</msb>
                            <access>read-write</access>
                            <enumeratedValues>
                                <enumeratedValue>
                                    <name>0</name>
                                    <description>When TINV is 0, low level is output in TXDn pin. When TINV is 1, high level is output in TXDn pin. </description>
                                    <value>#0</value>
                                </enumeratedValue>
                                <enumeratedValue>
                                    <name>1</name>
                                    <description>When TINV is 0, high level is output in TXDn pin. When TINV is 1, low level is output in TXDn pin. </description>
                                    <value>#1</value>
                                </enumeratedValue>
                            </enumeratedValues>
                        </field>
                        <field>
                            <name>SPB2IO</name>
                            <description>Serial Port Break I/O</description>
                            <lsb>5</lsb>
                            <msb>5</msb>
                            <access>read-write</access>
                            <enumeratedValues>
                                <enumeratedValue>
                                    <name>0</name>
                                    <description>The value of SPB2DT bit is not output in TXDn pin</description>
                                    <value>#0</value>
                                </enumeratedValue>
                                <enumeratedValue>
                                    <name>1</name>
                                    <description>The value of SPB2DT bit is output in TXDn pin</description>
                                    <value>#1</value>
                                </enumeratedValue>
                            </enumeratedValues>
                        </field>
                        <field>
                            <name>PE</name>
                            <description>Parity Enable</description>
                            <lsb>8</lsb>
                            <msb>8</msb>
                            <access>read-write</access>
                            <enumeratedValues>
                                <enumeratedValue>
                                    <name>0</name>
                                    <description>When transmitting: Do not add parity bit When receiving: Do not check parity bit </description>
                                    <value>#0</value>
                                </enumeratedValue>
                                <enumeratedValue>
                                    <name>1</name>
                                    <description>When transmitting: Add parity bit When receiving: Check parity bit </description>
                                    <value>#1</value>
                                </enumeratedValue>
                            </enumeratedValues>
                        </field>
                        <field>
                            <name>PM</name>
                            <description>Parity Mode</description>
                            <lsb>9</lsb>
                            <msb>9</msb>
                            <access>read-write</access>
                            <enumeratedValues>
                                <enumeratedValue>
                                    <name>0</name>
                                    <description>Selects even parity</description>
                                    <value>#0</value>
                                </enumeratedValue>
                                <enumeratedValue>
                                    <name>1</name>
                                    <description>Selects odd parity</description>
                                    <value>#1</value>
                                </enumeratedValue>
                            </enumeratedValues>
                        </field>
                        <field>
                            <name>TINV</name>
                            <description>TXD Invert</description>
                            <lsb>12</lsb>
                            <msb>12</msb>
                            <access>read-write</access>
                            <enumeratedValues>
                                <enumeratedValue>
                                    <name>0</name>
                                    <description>Transmit data is not inverted and output to TXDn</description>
                                    <value>#0</value>
                                </enumeratedValue>
                                <enumeratedValue>
                                    <name>1</name>
                                    <description>Transmit data is inverted and output to TXDn</description>
                                    <value>#1</value>
                                </enumeratedValue>
                            </enumeratedValues>
                        </field>
                        <field>
                            <name>RINV</name>
                            <description>RXD Invert</description>
                            <lsb>13</lsb>
                            <msb>13</msb>
                            <access>read-write</access>
                            <enumeratedValues>
                                <enumeratedValue>
                                    <name>0</name>
                                    <description>Received data from RXDn is not inverted and input</description>
                                    <value>#0</value>
                                </enumeratedValue>
                                <enumeratedValue>
                                    <name>1</name>
                                    <description>Received data from RXDn is inverted and input</description>
                                    <value>#1</value>
                                </enumeratedValue>
                            </enumeratedValues>
                        </field>
                        <field>
                            <name>SPLP</name>
                            <description>Loopback Control</description>
                            <lsb>16</lsb>
                            <msb>16</msb>
                            <access>read-write</access>
                            <enumeratedValues>
                                <enumeratedValue>
                                    <name>0</name>
                                    <description>Normal mode</description>
                                    <value>#0</value>
                                </enumeratedValue>
                                <enumeratedValue>
                                    <name>1</name>
                                    <description>Loopback mode</description>
                                    <value>#1</value>
                                </enumeratedValue>
                            </enumeratedValues>
                        </field>
                        <field>
                            <name>SHARPS</name>
                            <description>Half-Duplex Communication Select</description>
                            <lsb>20</lsb>
                            <msb>20</msb>
                            <access>read-write</access>
                            <enumeratedValues>
                                <enumeratedValue>
                                    <name>0</name>
                                    <description>TXDn pin, RXDn pin independent</description>
                                    <value>#0</value>
                                </enumeratedValue>
                                <enumeratedValue>
                                    <name>1</name>
                                    <description>TXDn/RXDn pin combination use (half-duplex communication using TXDn pin) </description>
                                    <value>#1</value>
                                </enumeratedValue>
                            </enumeratedValues>
                        </field>
                        <field>
                            <name>NFCS</name>
                            <description>Noise Filter Clock Select</description>
                            <lsb>24</lsb>
                            <msb>26</msb>
                            <access>read-write</access>
                            <enumeratedValues>
                                <enumeratedValue>
                                    <name>000</name>
                                    <description>The base clock signal divided by 1</description>
                                    <value>#000</value>
                                </enumeratedValue>
                                <enumeratedValue>
                                    <name>001</name>
                                    <description>The on-chip baud rate generator source clock divided by 1</description>
                                    <value>#001</value>
                                </enumeratedValue>
                                <enumeratedValue>
                                    <name>010</name>
                                    <description>The on-chip baud rate generator source clock divided by 2</description>
                                    <value>#010</value>
                                </enumeratedValue>
                                <enumeratedValue>
                                    <name>011</name>
                                    <description>The on-chip baud rate generator source clock divided by 4</description>
                                    <value>#011</value>
                                </enumeratedValue>
                                <enumeratedValue>
                                    <name>100</name>
                                    <description>The on-chip baud rate generator source clock divided by 8</description>
                                    <value>#100</value>
                                </enumeratedValue>
                                <enumeratedValue>
                                    <name>others</name>
                                    <description>Setting prohibited</description>
                                    <isDefault>true</isDefault>
                                </enumeratedValue>
                            </enumeratedValues>
                        </field>
                        <field>
                            <name>NFEN</name>
                            <description>Digital Noise Filter Function Enable</description>
                            <lsb>28</lsb>
                            <msb>28</msb>
                            <access>read-write</access>
                            <enumeratedValues>
                                <enumeratedValue>
                                    <name>0</name>
                                    <description>In Asynchronous, Manchester, Simple LIN modes: Disable noise cancellation function for RXDn input signal In Simple IIC mode: Disable noise cancellation function for SCLn and SDAn input signals </description>
                                    <value>#0</value>
                                </enumeratedValue>
                                <enumeratedValue>
                                    <name>1</name>
                                    <description>In Asynchronous, Manchester, Simple LIN modes: Enable noise cancellation function for RXDn input signal In Simple IIC mode: Enable noise cancellation function for SCLn and SDAn input signals </description>
                                    <value>#1</value>
                                </enumeratedValue>
                            </enumeratedValues>
                        </field>
                        <field>
                            <name>NFM</name>
                            <description>Noise Filter Mode</description>
                            <lsb>29</lsb>
                            <msb>29</msb>
                            <access>read-write</access>
                            <enumeratedValues>
                                <enumeratedValue>
                                    <name>0</name>
                                    <description>3-point matching mode</description>
                                    <value>#0</value>
                                </enumeratedValue>
                                <enumeratedValue>
                                    <name>1</name>
                                    <description>Majority vote mode</description>
                                    <value>#1</value>
                                </enumeratedValue>
                            </enumeratedValues>
                        </field>
                    </fields>
                </register>
                <register>
                    <name>CCR2</name>
                    <description>Common Control Register 2</description>
                    <addressOffset>0x10</addressOffset>
                    <size>32</size>
                    <access>read-write</access>
                    <resetValue>0xff00ff04</resetValue>
                    <resetMask>0xffffffff</resetMask>
                    <fields>
                        <field>
                            <name>BCP</name>
                            <description>Base Clock Pulse</description>
                            <lsb>0</lsb>
                            <msb>2</msb>
                            <access>read-write</access>
                            <enumeratedValues>
                                <enumeratedValue>
                                    <name>000</name>
                                    <description>93 clock cycles (S = 93)</description>
                                    <value>#000</value>
                                </enumeratedValue>
                                <enumeratedValue>
                                    <name>001</name>
                                    <description>128 clock cycles (S = 128)</description>
                                    <value>#001</value>
                                </enumeratedValue>
                                <enumeratedValue>
                                    <name>010</name>
                                    <description>186 clock cycles (S = 186)</description>
                                    <value>#010</value>
                                </enumeratedValue>
                                <enumeratedValue>
                                    <name>011</name>
                                    <description>512 clock cycles (S = 512)</description>
                                    <value>#011</value>
                                </enumeratedValue>
                                <enumeratedValue>
                                    <name>100</name>
                                    <description>32 clock cycles (S = 32) (Initial value)</description>
                                    <value>#100</value>
                                </enumeratedValue>
                                <enumeratedValue>
                                    <name>101</name>
                                    <description>64 clock cycles (S = 64)</description>
                                    <value>#101</value>
                                </enumeratedValue>
                                <enumeratedValue>
                                    <name>110</name>
                                    <description>372 clock cycles (S = 372)</description>
                                    <value>#110</value>
                                </enumeratedValue>
                                <enumeratedValue>
                                    <name>111</name>
                                    <description>256 clock cycles (S = 256)</description>
                                    <value>#111</value>
                                </enumeratedValue>
                            </enumeratedValues>
                        </field>
                        <field>
                            <name>BGDM</name>
                            <description>Baud Rate Generator Double-Speed Mode Select</description>
                            <lsb>4</lsb>
                            <msb>4</msb>
                            <access>read-write</access>
                            <enumeratedValues>
                                <enumeratedValue>
                                    <name>0</name>
                                    <description>Baud rate generator outputs the clock with single frequency</description>
                                    <value>#0</value>
                                </enumeratedValue>
                                <enumeratedValue>
                                    <name>1</name>
                                    <description>Baud rate generator outputs the clock with doubled frequency</description>
                                    <value>#1</value>
                                </enumeratedValue>
                            </enumeratedValues>
                        </field>
                        <field>
                            <name>ABCS</name>
                            <description>Asynchronous Mode Base Clock Select</description>
                            <lsb>5</lsb>
                            <msb>5</msb>
                            <access>read-write</access>
                            <enumeratedValues>
                                <enumeratedValue>
                                    <name>0</name>
                                    <description>Selects 16 base clock cycles for 1-bit period</description>
                                    <value>#0</value>
                                </enumeratedValue>
                                <enumeratedValue>
                                    <name>1</name>
                                    <description>Selects 8 base clock cycles for 1-bit period</description>
                                    <value>#1</value>
                                </enumeratedValue>
                            </enumeratedValues>
                        </field>
                        <field>
                            <name>ABCSE</name>
                            <description>Asynchronous Mode Extended Base Clock Select</description>
                            <lsb>6</lsb>
                            <msb>6</msb>
                            <access>read-write</access>
                            <enumeratedValues>
                                <enumeratedValue>
                                    <name>0</name>
                                    <description>Clock cycles for 1-bit period is determined by combination between CCR2.BGDM and CCR2.ABCS.</description>
                                    <value>#0</value>
                                </enumeratedValue>
                                <enumeratedValue>
                                    <name>1</name>
                                    <description>Baud rate is 6 base clock cycles for 1-bit period and the clock of a double frequency is output from the baud rate generator.</description>
                                    <value>#1</value>
                                </enumeratedValue>
                            </enumeratedValues>
                        </field>
                        <field>
                            <name>ABCSE2</name>
                            <description>Asynchronous Mode Extended Base Clock Select 2</description>
                            <lsb>7</lsb>
                            <msb>7</msb>
                            <access>read-write</access>
                            <enumeratedValues>
                                <enumeratedValue>
                                    <name>0</name>
                                    <description>Clock cycles for 1-bit period is decided with combination between CCR2.BGDM and CCR2.ABCS.</description>
                                    <value>#0</value>
                                </enumeratedValue>
                                <enumeratedValue>
                                    <name>1</name>
                                    <description>Baud rate is 4 base clock cycles for 1-bit period and the clock of a double frequency is output from the baud rate generator.</description>
                                    <value>#1</value>
                                </enumeratedValue>
                            </enumeratedValues>
                        </field>
                        <field>
                            <name>BRR</name>
                            <description>Bit Rate Setting</description>
                            <lsb>8</lsb>
                            <msb>15</msb>
                            <access>read-write</access>
                        </field>
                        <field>
                            <name>BRME</name>
                            <description>Bit Rate Modulation Enable</description>
                            <lsb>16</lsb>
                            <msb>16</msb>
                            <access>read-write</access>
                            <enumeratedValues>
                                <enumeratedValue>
                                    <name>0</name>
                                    <description>Bit rate modulation function is disabled</description>
                                    <value>#0</value>
                                </enumeratedValue>
                                <enumeratedValue>
                                    <name>1</name>
                                    <description>Bit rate modulation function is enabled</description>
                                    <value>#1</value>
                                </enumeratedValue>
                            </enumeratedValues>
                        </field>
                        <field>
                            <name>CKS</name>
                            <description>Clock Select</description>
                            <lsb>20</lsb>
                            <msb>21</msb>
                            <access>read-write</access>
                            <enumeratedValues>
                                <enumeratedValue>
                                    <name>00</name>
                                    <description>TCLK clock (n = 0)</description>
                                    <value>#00</value>
                                </enumeratedValue>
                                <enumeratedValue>
                                    <name>01</name>
                                    <description>TCLK/4 clock (n = 1)</description>
                                    <value>#01</value>
                                </enumeratedValue>
                                <enumeratedValue>
                                    <name>10</name>
                                    <description>TCLK/16 clock (n = 2)</description>
                                    <value>#10</value>
                                </enumeratedValue>
                                <enumeratedValue>
                                    <name>11</name>
                                    <description>TCLK/64 clock (n = 3)</description>
                                    <value>#11</value>
                                </enumeratedValue>
                            </enumeratedValues>
                        </field>
                        <field>
                            <name>MDDR</name>
                            <description>Modulation Duty Setting</description>
                            <lsb>24</lsb>
                            <msb>31</msb>
                            <access>read-write</access>
                        </field>
                    </fields>
                </register>
                <register>
                    <name>CCR3</name>
                    <description>Common Control Register 3</description>
                    <addressOffset>0x14</addressOffset>
                    <size>32</size>
                    <access>read-write</access>
                    <resetValue>0x00001203</resetValue>
                    <resetMask>0xffffffff</resetMask>
                    <fields>
                        <field>
                            <name>CPHA</name>
                            <description>Clock Phase Select</description>
                            <lsb>0</lsb>
                            <msb>0</msb>
                            <access>read-write</access>
                            <enumeratedValues>
                                <enumeratedValue>
                                    <name>0</name>
                                    <description>Data is sampled at an odd edge and changes at an even edge (clock is delayed)</description>
                                    <value>#0</value>
                                </enumeratedValue>
                                <enumeratedValue>
                                    <name>1</name>
                                    <description>Data changes at an odd edge and is sampled at an even edge (clock is not delayed)</description>
                                    <value>#1</value>
                                </enumeratedValue>
                            </enumeratedValues>
                        </field>
                        <field>
                            <name>CPOL</name>
                            <description>Clock Polarity Select</description>
                            <lsb>1</lsb>
                            <msb>1</msb>
                            <access>read-write</access>
                            <enumeratedValues>
                                <enumeratedValue>
                                    <name>0</name>
                                    <description>SCKn in idle state is 0</description>
                                    <value>#0</value>
                                </enumeratedValue>
                                <enumeratedValue>
                                    <name>1</name>
                                    <description>SCKn in idle state is 1</description>
                                    <value>#1</value>
                                </enumeratedValue>
                            </enumeratedValues>
                        </field>
                        <field>
                            <name>BPEN</name>
                            <description>Synchronizer Bypass Enable</description>
                            <lsb>7</lsb>
                            <msb>7</msb>
                            <access>read-write</access>
                            <enumeratedValues>
                                <enumeratedValue>
                                    <name>0</name>
                                    <description>Synchronizer circuit is not bypassed</description>
                                    <value>#0</value>
                                </enumeratedValue>
                                <enumeratedValue>
                                    <name>1</name>
                                    <description>Synchronizer circuit is bypassed</description>
                                    <value>#1</value>
                                </enumeratedValue>
                            </enumeratedValues>
                        </field>
                        <field>
                            <name>CHR</name>
                            <description>Character Length</description>
                            <lsb>8</lsb>
                            <msb>9</msb>
                            <access>read-write</access>
                            <enumeratedValues>
                                <enumeratedValue>
                                    <name>00</name>
                                    <description>Transmit/receive in 9-bit data length</description>
                                    <value>#00</value>
                                </enumeratedValue>
                                <enumeratedValue>
                                    <name>01</name>
                                    <description>Transmit/receive in 9-bit data length</description>
                                    <value>#01</value>
                                </enumeratedValue>
                                <enumeratedValue>
                                    <name>10</name>
                                    <description>Transmit/receive in 8-bit data length (initial value)</description>
                                    <value>#10</value>
                                </enumeratedValue>
                                <enumeratedValue>
                                    <name>11</name>
                                    <description>Transmit/receive in 7-bit data length</description>
                                    <value>#11</value>
                                </enumeratedValue>
                            </enumeratedValues>
                        </field>
                        <field>
                            <name>LSBF</name>
                            <description>LSB First select</description>
                            <lsb>12</lsb>
                            <msb>12</msb>
                            <access>read-write</access>
                            <enumeratedValues>
                                <enumeratedValue>
                                    <name>0</name>
                                    <description>MSB-first</description>
                                    <value>#0</value>
                                </enumeratedValue>
                                <enumeratedValue>
                                    <name>1</name>
                                    <description>LSB-first</description>
                                    <value>#1</value>
                                </enumeratedValue>
                            </enumeratedValues>
                        </field>
                        <field>
                            <name>SINV</name>
                            <description>Transmitted/Received Data Invert</description>
                            <lsb>13</lsb>
                            <msb>13</msb>
                            <access>read-write</access>
                            <enumeratedValues>
                                <enumeratedValue>
                                    <name>0</name>
                                    <description>TDR contents are transmitted to TSR as is. RSR contents are stored to RDR as is. </description>
                                    <value>#0</value>
                                </enumeratedValue>
                                <enumeratedValue>
                                    <name>1</name>
                                    <description>TDR contents are inverted before being transmitted to TSR. RSR contents are inverted and stored to RDR. </description>
                                    <value>#1</value>
                                </enumeratedValue>
                            </enumeratedValues>
                        </field>
                        <field>
                            <name>STP</name>
                            <description>Stop Bit Length</description>
                            <lsb>14</lsb>
                            <msb>14</msb>
                            <access>read-write</access>
                            <enumeratedValues>
                                <enumeratedValue>
                                    <name>0</name>
                                    <description>1 stop bit/break delimiter length is 1-bit</description>
                                    <value>#0</value>
                                </enumeratedValue>
                                <enumeratedValue>
                                    <name>1</name>
                                    <description>2 stop bits/break delimiter length is 2-bit</description>
                                    <value>#1</value>
                                </enumeratedValue>
                            </enumeratedValues>
                        </field>
                        <field>
                            <name>RXDESEL</name>
                            <description>Asynchronous Start Bit Edge Detection Select</description>
                            <lsb>15</lsb>
                            <msb>15</msb>
                            <access>read-write</access>
                            <enumeratedValues>
                                <enumeratedValue>
                                    <name>0</name>
                                    <description>The low level on the RXDn pin is detected as the start bit</description>
                                    <value>#0</value>
                                </enumeratedValue>
                                <enumeratedValue>
                                    <name>1</name>
                                    <description>A falling edge on the RXDn pin is detected as the start bit</description>
                                    <value>#1</value>
                                </enumeratedValue>
                            </enumeratedValues>
                        </field>
                        <field>
                            <name>MOD</name>
                            <description>Communication Mode Select</description>
                            <lsb>16</lsb>
                            <msb>18</msb>
                            <access>read-write</access>
                            <enumeratedValues>
                                <enumeratedValue>
                                    <name>000</name>
                                    <description>Asynchronous mode (multi-processor mode)</description>
                                    <value>#000</value>
                                </enumeratedValue>
                                <enumeratedValue>
                                    <name>001</name>
                                    <description>Smart card interface mode</description>
                                    <value>#001</value>
                                </enumeratedValue>
                                <enumeratedValue>
                                    <name>010</name>
                                    <description>Clock synchronous mode</description>
                                    <value>#010</value>
                                </enumeratedValue>
                                <enumeratedValue>
                                    <name>011</name>
                                    <description>Simple SPI mode</description>
                                    <value>#011</value>
                                </enumeratedValue>
                                <enumeratedValue>
                                    <name>100</name>
                                    <description>Simple IIC mode</description>
                                    <value>#100</value>
                                </enumeratedValue>
                                <enumeratedValue>
                                    <name>101</name>
                                    <description>Manchester mode</description>
                                    <value>#101</value>
                                </enumeratedValue>
                                <enumeratedValue>
                                    <name>110</name>
                                    <description>Simple LIN mode</description>
                                    <value>#110</value>
                                </enumeratedValue>
                                <enumeratedValue>
                                    <name>111</name>
                                    <description>Setting prohibited</description>
                                    <value>#111</value>
                                </enumeratedValue>
                            </enumeratedValues>
                        </field>
                        <field>
                            <name>MP</name>
                            <description>Multi-Processor Mode</description>
                            <lsb>19</lsb>
                            <msb>19</msb>
                            <access>read-write</access>
                            <enumeratedValues>
                                <enumeratedValue>
                                    <name>0</name>
                                    <description>Multi-processor communications function is disabled</description>
                                    <value>#0</value>
                                </enumeratedValue>
                                <enumeratedValue>
                                    <name>1</name>
                                    <description>Multi-processor communications function is enabled</description>
                                    <value>#1</value>
                                </enumeratedValue>
                            </enumeratedValues>
                        </field>
                        <field>
                            <name>FM</name>
                            <description>FIFO Mode Select</description>
                            <lsb>20</lsb>
                            <msb>20</msb>
                            <access>read-write</access>
                            <enumeratedValues>
                                <enumeratedValue>
                                    <name>0</name>
                                    <description>TDR register and RDR register are non-FIFO buffer configuration</description>
                                    <value>#0</value>
                                </enumeratedValue>
                                <enumeratedValue>
                                    <name>1</name>
                                    <description>TDR register and RDR register are FIFO buffer configuration</description>
                                    <value>#1</value>
                                </enumeratedValue>
                            </enumeratedValues>
                        </field>
                        <field>
                            <name>DEN</name>
                            <description>Driver Enable</description>
                            <lsb>21</lsb>
                            <msb>21</msb>
                            <access>read-write</access>
                            <enumeratedValues>
                                <enumeratedValue>
                                    <name>0</name>
                                    <description>RS-485 driver control function disabled</description>
                                    <value>#0</value>
                                </enumeratedValue>
                                <enumeratedValue>
                                    <name>1</name>
                                    <description>RS-485 driver control function enabled</description>
                                    <value>#1</value>
                                </enumeratedValue>
                            </enumeratedValues>
                        </field>
                        <field>
                            <name>CKE</name>
                            <description>Clock Enable</description>
                            <lsb>24</lsb>
                            <msb>25</msb>
                            <access>read-write</access>
                        </field>
                        <field>
                            <name>ACS0</name>
                            <description>Asynchronous Mode Clock Source Select</description>
                            <lsb>26</lsb>
                            <msb>26</msb>
                            <access>read-write</access>
                            <enumeratedValues>
                                <enumeratedValue>
                                    <name>0</name>
                                    <description>External clock input</description>
                                    <value>#0</value>
                                </enumeratedValue>
                                <enumeratedValue>
                                    <name>1</name>
                                    <description>Logical AND of compare matches output from the internal GPT</description>
                                    <value>#1</value>
                                </enumeratedValue>
                            </enumeratedValues>
                        </field>
                        <field>
                            <name>GM</name>
                            <description>GSM Mode</description>
                            <lsb>28</lsb>
                            <msb>28</msb>
                            <access>read-write</access>
                            <enumeratedValues>
                                <enumeratedValue>
                                    <name>0</name>
                                    <description>Non-GSM mode operation</description>
                                    <value>#0</value>
                                </enumeratedValue>
                                <enumeratedValue>
                                    <name>1</name>
                                    <description>GSM mode operation</description>
                                    <value>#1</value>
                                </enumeratedValue>
                            </enumeratedValues>
                        </field>
                        <field>
                            <name>BLK</name>
                            <description>Block Transfer Mode</description>
                            <lsb>29</lsb>
                            <msb>29</msb>
                            <access>read-write</access>
                            <enumeratedValues>
                                <enumeratedValue>
                                    <name>0</name>
                                    <description>Non-block transfer mode operation</description>
                                    <value>#0</value>
                                </enumeratedValue>
                                <enumeratedValue>
                                    <name>1</name>
                                    <description>Block transfer mode operation</description>
                                    <value>#1</value>
                                </enumeratedValue>
                            </enumeratedValues>
                        </field>
                    </fields>
                </register>
                <register>
                    <name>CCR4</name>
                    <description>Common Control Register 4</description>
                    <addressOffset>0x18</addressOffset>
                    <size>32</size>
                    <access>read-write</access>
                    <resetValue>0x00000000</resetValue>
                    <resetMask>0xffffffff</resetMask>
                    <fields>
                        <field>
                            <name>CMPD</name>
                            <description>Compare Match Data</description>
                            <lsb>0</lsb>
                            <msb>8</msb>
                            <access>read-write</access>
                        </field>
                        <field>
                            <name>ASEN</name>
                            <description>Adjust Receive Sampling Timing Enable</description>
                            <lsb>16</lsb>
                            <msb>16</msb>
                            <access>read-write</access>
                            <enumeratedValues>
                                <enumeratedValue>
                                    <name>0</name>
                                    <description>Adjust sampling timing disabled</description>
                                    <value>#0</value>
                                </enumeratedValue>
                                <enumeratedValue>
                                    <name>1</name>
                                    <description>Adjust sampling timing enabled</description>
                                    <value>#1</value>
                                </enumeratedValue>
                            </enumeratedValues>
                        </field>
                        <field>
                            <name>ATEN</name>
                            <description>Adjust Transmit Timing Enable</description>
                            <lsb>17</lsb>
                            <msb>17</msb>
                            <access>read-write</access>
                            <enumeratedValues>
                                <enumeratedValue>
                                    <name>0</name>
                                    <description>Adjust transmit timing disabled</description>
                                    <value>#0</value>
                                </enumeratedValue>
                                <enumeratedValue>
                                    <name>1</name>
                                    <description>Adjust transmit timing enabled</description>
                                    <value>#1</value>
                                </enumeratedValue>
                            </enumeratedValues>
                        </field>
                        <field>
                            <name>SCKSEL</name>
                            <description>Master receive clock selection</description>
                            <lsb>19</lsb>
                            <msb>19</msb>
                            <access>read-write</access>
                            <enumeratedValues>
                                <enumeratedValue>
                                    <name>0</name>
                                    <description>Master receive clock is disabled</description>
                                    <value>#0</value>
                                </enumeratedValue>
                                <enumeratedValue>
                                    <name>1</name>
                                    <description>Master receive clock is enabled</description>
                                    <value>#1</value>
                                </enumeratedValue>
                            </enumeratedValues>
                        </field>
                        <field>
                            <name>AST</name>
                            <description>Adjustment Value for Receive Sampling Timing</description>
                            <lsb>24</lsb>
                            <msb>26</msb>
                            <access>read-write</access>
                            <enumeratedValues>
                                <enumeratedValue>
                                    <name>000</name>
                                    <description>1-TCLK delay</description>
                                    <value>#000</value>
                                </enumeratedValue>
                                <enumeratedValue>
                                    <name>001</name>
                                    <description>2-TCLK delay</description>
                                    <value>#001</value>
                                </enumeratedValue>
                                <enumeratedValue>
                                    <name>010</name>
                                    <description>3-TCLK delay</description>
                                    <value>#010</value>
                                </enumeratedValue>
                                <enumeratedValue>
                                    <name>011</name>
                                    <description>4-TCLK delay</description>
                                    <value>#011</value>
                                </enumeratedValue>
                                <enumeratedValue>
                                    <name>Others</name>
                                    <description>Setting prohibited</description>
                                    <isDefault>true</isDefault>
                                </enumeratedValue>
                            </enumeratedValues>
                        </field>
                        <field>
                            <name>AJD</name>
                            <description>Adjustment Direction for Receive Sampling Timing</description>
                            <lsb>27</lsb>
                            <msb>27</msb>
                            <access>read-write</access>
                            <enumeratedValues>
                                <enumeratedValue>
                                    <name>0</name>
                                    <description>The sampling timing is adjusted backward to the middle of bit.</description>
                                    <value>#0</value>
                                </enumeratedValue>
                                <enumeratedValue>
                                    <name>1</name>
                                    <description>The sampling timing is adjusted forward to the middle of bit.</description>
                                    <value>#1</value>
                                </enumeratedValue>
                            </enumeratedValues>
                        </field>
                        <field>
                            <name>ATT</name>
                            <description>Adjustment Value for Transmit Timing</description>
                            <lsb>28</lsb>
                            <msb>30</msb>
                            <access>read-write</access>
                        </field>
                        <field>
                            <name>AET</name>
                            <description>Adjustment Edge for Transmit Timing</description>
                            <lsb>31</lsb>
                            <msb>31</msb>
                            <access>read-write</access>
                            <enumeratedValues>
                                <enumeratedValue>
                                    <name>0</name>
                                    <description>When CCR1.TINV is 0, adjust the rising edge timing. When CCR1.TINV is 1, adjust the falling edge timing. </description>
                                    <value>#0</value>
                                </enumeratedValue>
                                <enumeratedValue>
                                    <name>1</name>
                                    <description>When CCR1.TINV is 0, adjust the falling edge timing. When CCR1.TINV is 1, adjust the rising edge timing. </description>
                                    <value>#1</value>
                                </enumeratedValue>
                            </enumeratedValues>
                        </field>
                    </fields>
                </register>
                <register>
                    <name>CESR</name>
                    <description>Communication Enable Status Register</description>
                    <addressOffset>0x1C</addressOffset>
                    <size>8</size>
                    <access>read-only</access>
                    <resetValue>0x00</resetValue>
                    <resetMask>0xff</resetMask>
                    <fields>
                        <field>
                            <name>RIST</name>
                            <description>RE Internal Status</description>
                            <lsb>0</lsb>
                            <msb>0</msb>
                            <access>read-only</access>
                            <enumeratedValues>
                                <enumeratedValue>
                                    <name>0</name>
                                    <description>RE signal internal state value 0</description>
                                    <value>#0</value>
                                </enumeratedValue>
                                <enumeratedValue>
                                    <name>1</name>
                                    <description>RE signal internal state value 1</description>
                                    <value>#1</value>
                                </enumeratedValue>
                            </enumeratedValues>
                        </field>
                        <field>
                            <name>TIST</name>
                            <description>TE Internal Status</description>
                            <lsb>4</lsb>
                            <msb>4</msb>
                            <access>read-only</access>
                            <enumeratedValues>
                                <enumeratedValue>
                                    <name>0</name>
                                    <description>TE signal internal state value 0</description>
                                    <value>#0</value>
                                </enumeratedValue>
                                <enumeratedValue>
                                    <name>1</name>
                                    <description>TE signal internal state value 1</description>
                                    <value>#1</value>
                                </enumeratedValue>
                            </enumeratedValues>
                        </field>
                    </fields>
                </register>
                <register>
                    <name>ICR</name>
                    <description>Simple IIC Control Register</description>
                    <addressOffset>0x20</addressOffset>
                    <size>32</size>
                    <access>read-write</access>
                    <resetValue>0x00000000</resetValue>
                    <resetMask>0xffffffff</resetMask>
                    <fields>
                        <field>
                            <name>IICDL</name>
                            <description>SDA Delay Output Select</description>
                            <lsb>0</lsb>
                            <msb>4</msb>
                            <access>read-write</access>
                        </field>
                        <field>
                            <name>IICINTM</name>
                            <description>IIC Interrupt Mode Select</description>
                            <lsb>8</lsb>
                            <msb>8</msb>
                            <access>read-write</access>
                            <enumeratedValues>
                                <enumeratedValue>
                                    <name>0</name>
                                    <description>Use ACK/NACK interrupts</description>
                                    <value>#0</value>
                                </enumeratedValue>
                                <enumeratedValue>
                                    <name>1</name>
                                    <description>Use reception and transmission interrupts</description>
                                    <value>#1</value>
                                </enumeratedValue>
                            </enumeratedValues>
                        </field>
                        <field>
                            <name>IICCSC</name>
                            <description>Clock Synchronization</description>
                            <lsb>9</lsb>
                            <msb>9</msb>
                            <access>read-write</access>
                            <enumeratedValues>
                                <enumeratedValue>
                                    <name>0</name>
                                    <description>No synchronization with the clock signal</description>
                                    <value>#0</value>
                                </enumeratedValue>
                                <enumeratedValue>
                                    <name>1</name>
                                    <description>Synchronization with the clock signal</description>
                                    <value>#1</value>
                                </enumeratedValue>
                            </enumeratedValues>
                        </field>
                        <field>
                            <name>IICACKT</name>
                            <description>ACK Transmission Data</description>
                            <lsb>13</lsb>
                            <msb>13</msb>
                            <access>read-write</access>
                            <enumeratedValues>
                                <enumeratedValue>
                                    <name>0</name>
                                    <description>ACK transmission</description>
                                    <value>#0</value>
                                </enumeratedValue>
                                <enumeratedValue>
                                    <name>1</name>
                                    <description>NACK transmission and reception of ACK/NACK</description>
                                    <value>#1</value>
                                </enumeratedValue>
                            </enumeratedValues>
                        </field>
                        <field>
                            <name>IICSTAREQ</name>
                            <description>Start Condition Generation</description>
                            <lsb>16</lsb>
                            <msb>16</msb>
                            <access>read-write</access>
                            <enumeratedValues>
                                <enumeratedValue>
                                    <name>0</name>
                                    <description>A start condition is not generated</description>
                                    <value>#0</value>
                                </enumeratedValue>
                                <enumeratedValue>
                                    <name>1</name>
                                    <description>A start condition is generated </description>
                                    <value>#1</value>
                                </enumeratedValue>
                            </enumeratedValues>
                        </field>
                        <field>
                            <name>IICRSTAREQ</name>
                            <description>Restart Condition Generation</description>
                            <lsb>17</lsb>
                            <msb>17</msb>
                            <access>read-write</access>
                            <enumeratedValues>
                                <enumeratedValue>
                                    <name>0</name>
                                    <description>A restart condition is not generated</description>
                                    <value>#0</value>
                                </enumeratedValue>
                                <enumeratedValue>
                                    <name>1</name>
                                    <description>A restart condition is generated </description>
                                    <value>#1</value>
                                </enumeratedValue>
                            </enumeratedValues>
                        </field>
                        <field>
                            <name>IICSTPREQ</name>
                            <description>Stop Condition Generation</description>
                            <lsb>18</lsb>
                            <msb>18</msb>
                            <access>read-write</access>
                            <enumeratedValues>
                                <enumeratedValue>
                                    <name>0</name>
                                    <description>A stop condition is not generated.</description>
                                    <value>#0</value>
                                </enumeratedValue>
                                <enumeratedValue>
                                    <name>1</name>
                                    <description>A stop condition is generated </description>
                                    <value>#1</value>
                                </enumeratedValue>
                            </enumeratedValues>
                        </field>
                        <field>
                            <name>IICSDAS</name>
                            <description>SDA Output Select</description>
                            <lsb>20</lsb>
                            <msb>21</msb>
                            <access>read-write</access>
                            <enumeratedValues>
                                <enumeratedValue>
                                    <name>00</name>
                                    <description>Serial data output</description>
                                    <value>#00</value>
                                </enumeratedValue>
                                <enumeratedValue>
                                    <name>01</name>
                                    <description>Generate a start, restart, or stop condition</description>
                                    <value>#01</value>
                                </enumeratedValue>
                                <enumeratedValue>
                                    <name>10</name>
                                    <description>Output the low level on the SDAn pin</description>
                                    <value>#10</value>
                                </enumeratedValue>
                                <enumeratedValue>
                                    <name>11</name>
                                    <description>Place the SDAn pin in the high-impedance state</description>
                                    <value>#11</value>
                                </enumeratedValue>
                            </enumeratedValues>
                        </field>
                        <field>
                            <name>IICSCLS</name>
                            <description>SCL Output Select</description>
                            <lsb>22</lsb>
                            <msb>23</msb>
                            <access>read-write</access>
                            <enumeratedValues>
                                <enumeratedValue>
                                    <name>00</name>
                                    <description>Serial clock output</description>
                                    <value>#00</value>
                                </enumeratedValue>
                                <enumeratedValue>
                                    <name>01</name>
                                    <description>Generate a start, restart, or stop condition</description>
                                    <value>#01</value>
                                </enumeratedValue>
                                <enumeratedValue>
                                    <name>10</name>
                                    <description>Output the low level on the SCLn pin</description>
                                    <value>#10</value>
                                </enumeratedValue>
                                <enumeratedValue>
                                    <name>11</name>
                                    <description>Place the SCLn pin in the high-impedance state</description>
                                    <value>#11</value>
                                </enumeratedValue>
                            </enumeratedValues>
                        </field>
                    </fields>
                </register>
                <register>
                    <name>FCR</name>
                    <description>FIFO Control Register</description>
                    <addressOffset>0x24</addressOffset>
                    <size>32</size>
                    <access>read-write</access>
                    <resetValue>0x1f1f0000</resetValue>
                    <resetMask>0xffffffff</resetMask>
                    <fields>
                        <field>
                            <name>DRES</name>
                            <description>Receive Data Ready Error Select Bit</description>
                            <lsb>0</lsb>
                            <msb>0</msb>
                            <access>read-write</access>
                            <enumeratedValues>
                                <enumeratedValue>
                                    <name>0</name>
                                    <description>Reception data full interrupt (SCIn_RXI)</description>
                                    <value>#0</value>
                                </enumeratedValue>
                                <enumeratedValue>
                                    <name>1</name>
                                    <description>Receive error interrupt (SCIn_ERI)</description>
                                    <value>#1</value>
                                </enumeratedValue>
                            </enumeratedValues>
                        </field>
                        <field>
                            <name>TTRG</name>
                            <description>Transmit FIFO Data Trigger Number</description>
                            <lsb>8</lsb>
                            <msb>12</msb>
                            <access>read-write</access>
                        </field>
                        <field>
                            <name>TFRST</name>
                            <description>Transmit FIFO Data Register Reset</description>
                            <lsb>15</lsb>
                            <msb>15</msb>
                            <access>write-only</access>
                            <enumeratedValues>
                                <enumeratedValue>
                                    <name>0</name>
                                    <description>When set, this bit is invalid and does not affect operation</description>
                                    <value>#0</value>
                                </enumeratedValue>
                                <enumeratedValue>
                                    <name>1</name>
                                    <description>The number of data stored in Transmit-FIFO (TDR register) is 0</description>
                                    <value>#1</value>
                                </enumeratedValue>
                            </enumeratedValues>
                        </field>
                        <field>
                            <name>RTRG</name>
                            <description>Receive FIFO Data Trigger Number</description>
                            <lsb>16</lsb>
                            <msb>20</msb>
                            <access>read-write</access>
                        </field>
                        <field>
                            <name>RFRST</name>
                            <description>Receive FIFO Data Register Reset</description>
                            <lsb>23</lsb>
                            <msb>23</msb>
                            <access>write-only</access>
                            <enumeratedValues>
                                <enumeratedValue>
                                    <name>0</name>
                                    <description>When set, this bit is invalid and does not affect operation</description>
                                    <value>#0</value>
                                </enumeratedValue>
                                <enumeratedValue>
                                    <name>1</name>
                                    <description>The number of data stored in Receive-FIFO(RDR register) is 0</description>
                                    <value>#1</value>
                                </enumeratedValue>
                            </enumeratedValues>
                        </field>
                        <field>
                            <name>RSTRG</name>
                            <description>RTS Output Active Trigger Number Select</description>
                            <lsb>24</lsb>
                            <msb>28</msb>
                            <access>read-write</access>
                        </field>
                    </fields>
                </register>
                <register>
                    <name>MCR</name>
                    <description>Manchester Control Register</description>
                    <addressOffset>0x2C</addressOffset>
                    <size>32</size>
                    <access>read-write</access>
                    <resetValue>0x00000000</resetValue>
                    <resetMask>0xffffffff</resetMask>
                    <fields>
                        <field>
                            <name>RMPOL</name>
                            <description>Polarity of Received Manchester Code</description>
                            <lsb>0</lsb>
                            <msb>0</msb>
                            <access>read-write</access>
                            <enumeratedValues>
                                <enumeratedValue>
                                    <name>0</name>
                                    <description>Logic 0 is coded as a zero-to-one transition in Manchester code Logic 1 is coded as a one-to-zero transition in Manchester code </description>
                                    <value>#0</value>
                                </enumeratedValue>
                                <enumeratedValue>
                                    <name>1</name>
                                    <description>Logic 0 is coded as a one-to-zero transition in Manchester code Logic 1 is coded as a zero-to-one transition in Manchester code </description>
                                    <value>#1</value>
                                </enumeratedValue>
                            </enumeratedValues>
                        </field>
                        <field>
                            <name>TMPOL</name>
                            <description>Polarity of Transmit Manchester Code</description>
                            <lsb>1</lsb>
                            <msb>1</msb>
                            <access>read-write</access>
                            <enumeratedValues>
                                <enumeratedValue>
                                    <name>0</name>
                                    <description>Logic 0 is coded as a zero-to-one transition in Manchester code Logic 1 is coded as a one-to-zero transition in Manchester code </description>
                                    <value>#0</value>
                                </enumeratedValue>
                                <enumeratedValue>
                                    <name>1</name>
                                    <description>Logic 0 is coded as a one-to-zero transition in Manchester code Logic 1 is coded as a zero-to-one transition in Manchester code </description>
                                    <value>#1</value>
                                </enumeratedValue>
                            </enumeratedValues>
                        </field>
                        <field>
                            <name>ERTEN</name>
                            <description>Manchester Edge Retiming Enable</description>
                            <lsb>2</lsb>
                            <msb>2</msb>
                            <access>read-write</access>
                            <enumeratedValues>
                                <enumeratedValue>
                                    <name>0</name>
                                    <description>Disables the receive retiming function</description>
                                    <value>#0</value>
                                </enumeratedValue>
                                <enumeratedValue>
                                    <name>1</name>
                                    <description>Enables the receive retiming function</description>
                                    <value>#1</value>
                                </enumeratedValue>
                            </enumeratedValues>
                        </field>
                        <field>
                            <name>SYNVAL</name>
                            <description>SYNC value Setting</description>
                            <lsb>4</lsb>
                            <msb>4</msb>
                            <access>read-write</access>
                        </field>
                        <field>
                            <name>SYNSEL</name>
                            <description>SYNC Select</description>
                            <lsb>5</lsb>
                            <msb>5</msb>
                            <access>read-write</access>
                            <enumeratedValues>
                                <enumeratedValue>
                                    <name>0</name>
                                    <description>The start bit pattern is set with the SYNVAL bit</description>
                                    <value>#0</value>
                                </enumeratedValue>
                                <enumeratedValue>
                                    <name>1</name>
                                    <description>The start bit pattern is set with the TSYNC bit</description>
                                    <value>#1</value>
                                </enumeratedValue>
                            </enumeratedValues>
                        </field>
                        <field>
                            <name>SBSEL</name>
                            <description>Start Bit Select</description>
                            <lsb>6</lsb>
                            <msb>6</msb>
                            <access>read-write</access>
                            <enumeratedValues>
                                <enumeratedValue>
                                    <name>0</name>
                                    <description>The start bit area consists of one bit</description>
                                    <value>#0</value>
                                </enumeratedValue>
                                <enumeratedValue>
                                    <name>1</name>
                                    <description>The start bit area consists of three bits (COMMAND SYNC or DATA SYNC) </description>
                                    <value>#1</value>
                                </enumeratedValue>
                            </enumeratedValues>
                        </field>
                        <field>
                            <name>TPLEN</name>
                            <description>Transmit Preface Length</description>
                            <lsb>8</lsb>
                            <msb>11</msb>
                            <access>read-write</access>
                            <enumeratedValues>
                                <enumeratedValue>
                                    <name>0x0</name>
                                    <description>Disables the transmit preface generation</description>
                                    <value>0x0</value>
                                </enumeratedValue>
                                <enumeratedValue>
                                    <name>Others</name>
                                    <description>Transmit preface length (bit length)</description>
                                    <isDefault>true</isDefault>
                                </enumeratedValue>
                            </enumeratedValues>
                        </field>
                        <field>
                            <name>TPPAT</name>
                            <description>Transmit Preface Pattern</description>
                            <lsb>12</lsb>
                            <msb>13</msb>
                            <access>read-write</access>
                            <enumeratedValues>
                                <enumeratedValue>
                                    <name>00</name>
                                    <description>ALL ZERO</description>
                                    <value>#00</value>
                                </enumeratedValue>
                                <enumeratedValue>
                                    <name>01</name>
                                    <description>ZERO ONE</description>
                                    <value>#01</value>
                                </enumeratedValue>
                                <enumeratedValue>
                                    <name>10</name>
                                    <description>ONE ZERO</description>
                                    <value>#10</value>
                                </enumeratedValue>
                                <enumeratedValue>
                                    <name>11</name>
                                    <description>ALL ONE</description>
                                    <value>#11</value>
                                </enumeratedValue>
                            </enumeratedValues>
                        </field>
                        <field>
                            <name>RPLEN</name>
                            <description>Receive Preface Length</description>
                            <lsb>16</lsb>
                            <msb>19</msb>
                            <access>read-write</access>
                            <enumeratedValues>
                                <enumeratedValue>
                                    <name>0x0</name>
                                    <description>Disables the receive preface generation</description>
                                    <value>0x0</value>
                                </enumeratedValue>
                                <enumeratedValue>
                                    <name>Others</name>
                                    <description>Receive preface length (bit length)</description>
                                    <isDefault>true</isDefault>
                                </enumeratedValue>
                            </enumeratedValues>
                        </field>
                        <field>
                            <name>RPPAT</name>
                            <description>Receive Preface Pattern</description>
                            <lsb>20</lsb>
                            <msb>21</msb>
                            <access>read-write</access>
                            <enumeratedValues>
                                <enumeratedValue>
                                    <name>00</name>
                                    <description>ALL ZERO</description>
                                    <value>#00</value>
                                </enumeratedValue>
                                <enumeratedValue>
                                    <name>01</name>
                                    <description>ZERO ONE</description>
                                    <value>#01</value>
                                </enumeratedValue>
                                <enumeratedValue>
                                    <name>10</name>
                                    <description>ONE ZERO</description>
                                    <value>#10</value>
                                </enumeratedValue>
                                <enumeratedValue>
                                    <name>11</name>
                                    <description>ALL ONE</description>
                                    <value>#11</value>
                                </enumeratedValue>
                            </enumeratedValues>
                        </field>
                        <field>
                            <name>PFEREN</name>
                            <description>Preface Error Enable</description>
                            <lsb>24</lsb>
                            <msb>24</msb>
                            <access>read-write</access>
                            <enumeratedValues>
                                <enumeratedValue>
                                    <name>0</name>
                                    <description>Does not handle a preface error as an interrupt source</description>
                                    <value>#0</value>
                                </enumeratedValue>
                                <enumeratedValue>
                                    <name>1</name>
                                    <description>Handles a preface error as an interrupt source</description>
                                    <value>#1</value>
                                </enumeratedValue>
                            </enumeratedValues>
                        </field>
                        <field>
                            <name>SYEREN</name>
                            <description>Receive SYNC Error Enable</description>
                            <lsb>25</lsb>
                            <msb>25</msb>
                            <access>read-write</access>
                            <enumeratedValues>
                                <enumeratedValue>
                                    <name>0</name>
                                    <description>Does not handle a receive SYNC error as an interrupt source</description>
                                    <value>#0</value>
                                </enumeratedValue>
                                <enumeratedValue>
                                    <name>1</name>
                                    <description>Handles a receive SYNC error as an interrupt source</description>
                                    <value>#1</value>
                                </enumeratedValue>
                            </enumeratedValues>
                        </field>
                        <field>
                            <name>SBEREN</name>
                            <description>Start Bit Error Enable</description>
                            <lsb>26</lsb>
                            <msb>26</msb>
                            <access>read-write</access>
                            <enumeratedValues>
                                <enumeratedValue>
                                    <name>0</name>
                                    <description>Does not handle a start bit error as an interrupt source</description>
                                    <value>#0</value>
                                </enumeratedValue>
                                <enumeratedValue>
                                    <name>1</name>
                                    <description>Handles a start bit error as an interrupt source</description>
                                    <value>#1</value>
                                </enumeratedValue>
                            </enumeratedValues>
                        </field>
                    </fields>
                </register>
                <register>
                    <name>DCR</name>
                    <description>Driver Control Register</description>
                    <addressOffset>0x30</addressOffset>
                    <size>32</size>
                    <access>read-write</access>
                    <resetValue>0x00000000</resetValue>
                    <resetMask>0xffffffff</resetMask>
                    <fields>
                        <field>
                            <name>DEPOL</name>
                            <description>Driver Effective Polarity Select</description>
                            <lsb>0</lsb>
                            <msb>0</msb>
                            <access>read-write</access>
                            <enumeratedValues>
                                <enumeratedValue>
                                    <name>0</name>
                                    <description>The DEn signal is active-high</description>
                                    <value>#0</value>
                                </enumeratedValue>
                                <enumeratedValue>
                                    <name>1</name>
                                    <description>The DEn signal is active-low</description>
                                    <value>#1</value>
                                </enumeratedValue>
                            </enumeratedValues>
                        </field>
                        <field>
                            <name>DEAST</name>
                            <description>Driver Assertion Time</description>
                            <lsb>8</lsb>
                            <msb>12</msb>
                            <access>read-write</access>
                        </field>
                        <field>
                            <name>DENGT</name>
                            <description>Driver Negate Time</description>
                            <lsb>16</lsb>
                            <msb>20</msb>
                            <access>read-write</access>
                        </field>
                    </fields>
                </register>
                <register>
                    <name>XCR0</name>
                    <description>Simple LIN Control Register 0</description>
                    <addressOffset>0x34</addressOffset>
                    <size>32</size>
                    <access>read-write</access>
                    <resetValue>0x00000000</resetValue>
                    <resetMask>0xffffffff</resetMask>
                    <fields>
                        <field>
                            <name>TCSS</name>
                            <description>Timer Count Clock Source Selection</description>
                            <lsb>0</lsb>
                            <msb>1</msb>
                            <access>read-write</access>
                            <enumeratedValues>
                                <enumeratedValue>
                                    <name>01</name>
                                    <description>TCLK/4</description>
                                    <value>#01</value>
                                </enumeratedValue>
                                <enumeratedValue>
                                    <name>10</name>
                                    <description>TCLK/16</description>
                                    <value>#10</value>
                                </enumeratedValue>
                                <enumeratedValue>
                                    <name>11</name>
                                    <description>TCLK/64</description>
                                    <value>#11</value>
                                </enumeratedValue>
                            </enumeratedValues>
                        </field>
                        <field>
                            <name>BFE</name>
                            <description>Break Field Enable</description>
                            <lsb>8</lsb>
                            <msb>8</msb>
                            <access>read-write</access>
                            <enumeratedValues>
                                <enumeratedValue>
                                    <name>0</name>
                                    <description>No Break Field</description>
                                    <value>#0</value>
                                </enumeratedValue>
                                <enumeratedValue>
                                    <name>1</name>
                                    <description>With Break Field</description>
                                    <value>#1</value>
                                </enumeratedValue>
                            </enumeratedValues>
                        </field>
                        <field>
                            <name>CF0RE</name>
                            <description>Control Field 0 Enable</description>
                            <lsb>9</lsb>
                            <msb>9</msb>
                            <access>read-write</access>
                            <enumeratedValues>
                                <enumeratedValue>
                                    <name>0</name>
                                    <description>No Control Field 0</description>
                                    <value>#0</value>
                                </enumeratedValue>
                                <enumeratedValue>
                                    <name>1</name>
                                    <description>With Control Field 0</description>
                                    <value>#1</value>
                                </enumeratedValue>
                            </enumeratedValues>
                        </field>
                        <field>
                            <name>CF1DS</name>
                            <description>Control Field1 Compare Data Select</description>
                            <lsb>10</lsb>
                            <msb>11</msb>
                            <access>read-write</access>
                            <enumeratedValues>
                                <enumeratedValue>
                                    <name>00</name>
                                    <description>Select XCR1.PCF1D[7:0] as the compare data</description>
                                    <value>#00</value>
                                </enumeratedValue>
                                <enumeratedValue>
                                    <name>01</name>
                                    <description>Select XCR1.SCF1D[7:0] as the compare data</description>
                                    <value>#01</value>
                                </enumeratedValue>
                                <enumeratedValue>
                                    <name>10</name>
                                    <description>Select both XCR1.PCF1D[7:0] and XCR1.SCF1D[7:0] as the compare data</description>
                                    <value>#10</value>
                                </enumeratedValue>
                                <enumeratedValue>
                                    <name>11</name>
                                    <description>Setting prohibited</description>
                                    <value>#11</value>
                                </enumeratedValue>
                            </enumeratedValues>
                        </field>
                        <field>
                            <name>PIBE</name>
                            <description>Priority Interrupt Bit Enable</description>
                            <lsb>12</lsb>
                            <msb>12</msb>
                            <access>read-write</access>
                            <enumeratedValues>
                                <enumeratedValue>
                                    <name>0</name>
                                    <description>Priority interrupt bit disabled</description>
                                    <value>#0</value>
                                </enumeratedValue>
                                <enumeratedValue>
                                    <name>1</name>
                                    <description>Priority interrupt bit enabled</description>
                                    <value>#1</value>
                                </enumeratedValue>
                            </enumeratedValues>
                        </field>
                        <field>
                            <name>PIBS</name>
                            <description>Priority Interrupt Bit Select</description>
                            <lsb>13</lsb>
                            <msb>15</msb>
                            <access>read-write</access>
                            <enumeratedValues>
                                <enumeratedValue>
                                    <name>000</name>
                                    <description>Bit 0 of Control Field 1</description>
                                    <value>#000</value>
                                </enumeratedValue>
                                <enumeratedValue>
                                    <name>001</name>
                                    <description>Bit 1 of Control Field 1</description>
                                    <value>#001</value>
                                </enumeratedValue>
                                <enumeratedValue>
                                    <name>010</name>
                                    <description>Bit 2 of Control Field 1</description>
                                    <value>#010</value>
                                </enumeratedValue>
                                <enumeratedValue>
                                    <name>011</name>
                                    <description>Bit 3 of Control Field 1</description>
                                    <value>#011</value>
                                </enumeratedValue>
                                <enumeratedValue>
                                    <name>100</name>
                                    <description>Bit 4 of Control Field 1</description>
                                    <value>#100</value>
                                </enumeratedValue>
                                <enumeratedValue>
                                    <name>101</name>
                                    <description>Bit 5 of Control Field 1</description>
                                    <value>#101</value>
                                </enumeratedValue>
                                <enumeratedValue>
                                    <name>110</name>
                                    <description>Bit 6 of Control Field 1</description>
                                    <value>#110</value>
                                </enumeratedValue>
                                <enumeratedValue>
                                    <name>111</name>
                                    <description>Bit 7 of Control Field 1</description>
                                    <value>#111</value>
                                </enumeratedValue>
                            </enumeratedValues>
                        </field>
                        <field>
                            <name>BFOIE</name>
                            <description>Break Field Output Completion Interrupt Enable</description>
                            <lsb>16</lsb>
                            <msb>16</msb>
                            <access>read-write</access>
                            <enumeratedValues>
                                <enumeratedValue>
                                    <name>0</name>
                                    <description>Break Field output completion is not included in SCIn_TXI interrupt factor</description>
                                    <value>#0</value>
                                </enumeratedValue>
                                <enumeratedValue>
                                    <name>1</name>
                                    <description>Break Field output completion is included in SCIn_TXI interrupt factor</description>
                                    <value>#1</value>
                                </enumeratedValue>
                            </enumeratedValues>
                        </field>
                        <field>
                            <name>BCDIE</name>
                            <description>Bus Conflict Detection Interrupt Enable</description>
                            <lsb>17</lsb>
                            <msb>17</msb>
                            <access>read-write</access>
                            <enumeratedValues>
                                <enumeratedValue>
                                    <name>0</name>
                                    <description>Bus conflict detection is not included in SCIn_ERI interrupt factor</description>
                                    <value>#0</value>
                                </enumeratedValue>
                                <enumeratedValue>
                                    <name>1</name>
                                    <description>Bus conflict detection is included in SCIn_ERI interrupt factor</description>
                                    <value>#1</value>
                                </enumeratedValue>
                            </enumeratedValues>
                        </field>
                        <field>
                            <name>BFDIE</name>
                            <description>Break Field Detection Interrupt Enable</description>
                            <lsb>20</lsb>
                            <msb>20</msb>
                            <access>read-write</access>
                            <enumeratedValues>
                                <enumeratedValue>
                                    <name>0</name>
                                    <description>Break Field detection interrupt disabled</description>
                                    <value>#0</value>
                                </enumeratedValue>
                                <enumeratedValue>
                                    <name>1</name>
                                    <description>Break Field detection interrupt enabled</description>
                                    <value>#1</value>
                                </enumeratedValue>
                            </enumeratedValues>
                        </field>
                        <field>
                            <name>COFIE</name>
                            <description>Counter Overflow Interrupt Enable</description>
                            <lsb>21</lsb>
                            <msb>21</msb>
                            <access>read-write</access>
                            <enumeratedValues>
                                <enumeratedValue>
                                    <name>0</name>
                                    <description>Counter overflow is not included in SCIn_ERI interrupt factor</description>
                                    <value>#0</value>
                                </enumeratedValue>
                                <enumeratedValue>
                                    <name>1</name>
                                    <description>Counter overflow is included in SCIn_ERI interrupt factor</description>
                                    <value>#1</value>
                                </enumeratedValue>
                            </enumeratedValues>
                        </field>
                        <field>
                            <name>AEDIE</name>
                            <description>Active Edge Detection Interrupt Enable</description>
                            <lsb>22</lsb>
                            <msb>22</msb>
                            <access>read-write</access>
                            <enumeratedValues>
                                <enumeratedValue>
                                    <name>0</name>
                                    <description>Active edge detection interrupt disabled</description>
                                    <value>#0</value>
                                </enumeratedValue>
                                <enumeratedValue>
                                    <name>1</name>
                                    <description>Active edge detection interrupt enabled</description>
                                    <value>#1</value>
                                </enumeratedValue>
                            </enumeratedValues>
                        </field>
                        <field>
                            <name>BCCS</name>
                            <description>Bus Conflict Detection Clock Selection</description>
                            <lsb>24</lsb>
                            <msb>25</msb>
                            <access>read-write</access>
                            <enumeratedValues>
                                <enumeratedValue>
                                    <name>00</name>
                                    <description>Base clock</description>
                                    <value>#00</value>
                                </enumeratedValue>
                                <enumeratedValue>
                                    <name>01</name>
                                    <description>Base clock/2</description>
                                    <value>#01</value>
                                </enumeratedValue>
                                <enumeratedValue>
                                    <name>10</name>
                                    <description>Base clock/4</description>
                                    <value>#10</value>
                                </enumeratedValue>
                                <enumeratedValue>
                                    <name>11</name>
                                    <description>Setting prohibited</description>
                                    <value>#11</value>
                                </enumeratedValue>
                            </enumeratedValues>
                        </field>
                    </fields>
                </register>
                <register>
                    <name>XCR1</name>
                    <description>Simple LIN Control Register 1</description>
                    <addressOffset>0x38</addressOffset>
                    <size>32</size>
                    <access>read-write</access>
                    <resetValue>0x00000000</resetValue>
                    <resetMask>0xffffffff</resetMask>
                    <fields>
                        <field>
                            <name>TCST</name>
                            <description>Break Field Output Timer Count Start Trigger</description>
                            <lsb>0</lsb>
                            <msb>0</msb>
                            <access>read-write</access>
                            <enumeratedValues>
                                <enumeratedValue>
                                    <name>0</name>
                                    <description>Break Field output timer count stopped</description>
                                    <value>#0</value>
                                </enumeratedValue>
                                <enumeratedValue>
                                    <name>1</name>
                                    <description>Break Field output timer count start</description>
                                    <value>#1</value>
                                </enumeratedValue>
                            </enumeratedValues>
                        </field>
                        <field>
                            <name>SDST</name>
                            <description>Start Frame Detection Enable</description>
                            <lsb>4</lsb>
                            <msb>4</msb>
                            <access>read-write</access>
                            <enumeratedValues>
                                <enumeratedValue>
                                    <name>0</name>
                                    <description>Start Frame/Break Field detection disabled</description>
                                    <value>#0</value>
                                </enumeratedValue>
                                <enumeratedValue>
                                    <name>1</name>
                                    <description>Start Frame/Break Field detection enabled</description>
                                    <value>#1</value>
                                </enumeratedValue>
                            </enumeratedValues>
                        </field>
                        <field>
                            <name>BMEN</name>
                            <description>Bit Rate Measurement Enable</description>
                            <lsb>5</lsb>
                            <msb>5</msb>
                            <access>read-write</access>
                            <enumeratedValues>
                                <enumeratedValue>
                                    <name>0</name>
                                    <description>Bit rate measurement disabled</description>
                                    <value>#0</value>
                                </enumeratedValue>
                                <enumeratedValue>
                                    <name>1</name>
                                    <description>Bit rate measurement enabled</description>
                                    <value>#1</value>
                                </enumeratedValue>
                            </enumeratedValues>
                        </field>
                        <field>
                            <name>PCF1D</name>
                            <description>Priority Compare Data for Control Field 1</description>
                            <lsb>8</lsb>
                            <msb>15</msb>
                            <access>read-write</access>
                        </field>
                        <field>
                            <name>SCF1D</name>
                            <description>Secondary Compare Data for Control Field 1</description>
                            <lsb>16</lsb>
                            <msb>23</msb>
                            <access>read-write</access>
                        </field>
                        <field>
                            <name>CF1CE</name>
                            <description>Control Field 1 Compare Bit Enable</description>
                            <lsb>24</lsb>
                            <msb>31</msb>
                            <access>read-write</access>
                            <enumeratedValues>
                                <enumeratedValue>
                                    <name>0</name>
                                    <description>Control Field 1 bit N compare disabled</description>
                                    <value>#0</value>
                                </enumeratedValue>
                                <enumeratedValue>
                                    <name>1</name>
                                    <description>Control Field 1 bit N compare enabled</description>
                                    <value>#1</value>
                                </enumeratedValue>
                            </enumeratedValues>
                        </field>
                    </fields>
                </register>
                <register>
                    <name>XCR2</name>
                    <description>Simple LIN Control Register 2</description>
                    <addressOffset>0x3C</addressOffset>
                    <size>32</size>
                    <access>read-write</access>
                    <resetValue>0xfffe0000</resetValue>
                    <resetMask>0xffffffff</resetMask>
                    <fields>
                        <field>
                            <name>CF0D</name>
                            <description>Control Field 0 Compare Data</description>
                            <lsb>0</lsb>
                            <msb>7</msb>
                            <access>read-write</access>
                        </field>
                        <field>
                            <name>CF0CE</name>
                            <description>Control Field 0 Compare Bit Enable</description>
                            <lsb>8</lsb>
                            <msb>15</msb>
                            <access>read-write</access>
                            <enumeratedValues>
                                <enumeratedValue>
                                    <name>0</name>
                                    <description>Control Field 0 bit N compare disabled</description>
                                    <value>#0</value>
                                </enumeratedValue>
                                <enumeratedValue>
                                    <name>1</name>
                                    <description>Control Field 0 bit N compare enabled</description>
                                    <value>#1</value>
                                </enumeratedValue>
                            </enumeratedValues>
                        </field>
                        <field>
                            <name>BFLW</name>
                            <description>Break Field Length Setting</description>
                            <lsb>16</lsb>
                            <msb>31</msb>
                            <access>read-write</access>
                        </field>
                    </fields>
                </register>
                <register>
                    <name>CSR</name>
                    <description>Common Status Register</description>
                    <addressOffset>0x48</addressOffset>
                    <size>32</size>
                    <access>read-only</access>
                    <resetValue>0x60008000</resetValue>
                    <resetMask>0xffffffff</resetMask>
                    <fields>
                        <field>
                            <name>ERS</name>
                            <description>Error Signal Status Flag</description>
                            <lsb>4</lsb>
                            <msb>4</msb>
                            <access>read-only</access>
                            <enumeratedValues>
                                <enumeratedValue>
                                    <name>0</name>
                                    <description>Error signal low not responded</description>
                                    <value>#0</value>
                                </enumeratedValue>
                                <enumeratedValue>
                                    <name>1</name>
                                    <description>Error signal low responded</description>
                                    <value>#1</value>
                                </enumeratedValue>
                            </enumeratedValues>
                        </field>
                        <field>
                            <name>RXDMON</name>
                            <description>Serial Input Data Monitor Bit</description>
                            <lsb>15</lsb>
                            <msb>15</msb>
                            <access>read-only</access>
                            <enumeratedValues>
                                <enumeratedValue>
                                    <name>0</name>
                                    <description>When RINV is 0, RXDn pin is the low level. When RINV is 1, RXDn pin is the high level. </description>
                                    <value>#0</value>
                                </enumeratedValue>
                                <enumeratedValue>
                                    <name>1</name>
                                    <description>When RINV is 0, RXDn pin is the high level. When RINV is 1, RXDn pin is the low level. </description>
                                    <value>#1</value>
                                </enumeratedValue>
                            </enumeratedValues>
                        </field>
                        <field>
                            <name>DCMF</name>
                            <description>Data Compare Match Flag</description>
                            <lsb>16</lsb>
                            <msb>16</msb>
                            <access>read-only</access>
                            <enumeratedValues>
                                <enumeratedValue>
                                    <name>0</name>
                                    <description>No matched</description>
                                    <value>#0</value>
                                </enumeratedValue>
                                <enumeratedValue>
                                    <name>1</name>
                                    <description>Matched</description>
                                    <value>#1</value>
                                </enumeratedValue>
                            </enumeratedValues>
                        </field>
                        <field>
                            <name>DPER</name>
                            <description>Data Compare Match Parity Error Flag</description>
                            <lsb>17</lsb>
                            <msb>17</msb>
                            <access>read-only</access>
                            <enumeratedValues>
                                <enumeratedValue>
                                    <name>0</name>
                                    <description>No parity error occurred at address match detection</description>
                                    <value>#0</value>
                                </enumeratedValue>
                                <enumeratedValue>
                                    <name>1</name>
                                    <description>A parity error has occurred at address match detection</description>
                                    <value>#1</value>
                                </enumeratedValue>
                            </enumeratedValues>
                        </field>
                        <field>
                            <name>DFER</name>
                            <description>Data Compare Match Framing Error Flag</description>
                            <lsb>18</lsb>
                            <msb>18</msb>
                            <access>read-only</access>
                            <enumeratedValues>
                                <enumeratedValue>
                                    <name>0</name>
                                    <description>No framing error occurred at address match detection</description>
                                    <value>#0</value>
                                </enumeratedValue>
                                <enumeratedValue>
                                    <name>1</name>
                                    <description>A framing error has occurred at address match detection</description>
                                    <value>#1</value>
                                </enumeratedValue>
                            </enumeratedValues>
                        </field>
                        <field>
                            <name>ORER</name>
                            <description>Overrun Error Flag</description>
                            <lsb>24</lsb>
                            <msb>24</msb>
                            <access>read-only</access>
                            <enumeratedValues>
                                <enumeratedValue>
                                    <name>0</name>
                                    <description>No overrun error occurred</description>
                                    <value>#0</value>
                                </enumeratedValue>
                                <enumeratedValue>
                                    <name>1</name>
                                    <description>An overrun error has occurred</description>
                                    <value>#1</value>
                                </enumeratedValue>
                            </enumeratedValues>
                        </field>
                        <field>
                            <name>MFF</name>
                            <description>Mode Fault Error Flag</description>
                            <lsb>26</lsb>
                            <msb>26</msb>
                            <access>read-only</access>
                            <enumeratedValues>
                                <enumeratedValue>
                                    <name>0</name>
                                    <description>No mode fault error</description>
                                    <value>#0</value>
                                </enumeratedValue>
                                <enumeratedValue>
                                    <name>1</name>
                                    <description>Mode fault error</description>
                                    <value>#1</value>
                                </enumeratedValue>
                            </enumeratedValues>
                        </field>
                        <field>
                            <name>PER</name>
                            <description>Parity Error Flag</description>
                            <lsb>27</lsb>
                            <msb>27</msb>
                            <access>read-only</access>
                            <enumeratedValues>
                                <enumeratedValue>
                                    <name>0</name>
                                    <description>Non-FIFO selected (CCR3.FM = 0): No parity error occurred FIFO selected (CCR3.FM = 1): No parity error in all received data in receive-FIFO </description>
                                    <value>#0</value>
                                </enumeratedValue>
                                <enumeratedValue>
                                    <name>1</name>
                                    <description>Non-FIFO selected (CCR3.FM = 0): A parity error has occurred FIFO selected (CCR3.FM = 1): One or more parity errors occurred in received data in receive-FIFO </description>
                                    <value>#1</value>
                                </enumeratedValue>
                            </enumeratedValues>
                        </field>
                        <field>
                            <name>FER</name>
                            <description>Framing Error Flag</description>
                            <lsb>28</lsb>
                            <msb>28</msb>
                            <access>read-only</access>
                            <enumeratedValues>
                                <enumeratedValue>
                                    <name>0</name>
                                    <description>Non-FIFO selected (CCR3.FM = 0): No framing error occurred FIFO selected (CCR3.FM = 1): No framing error in all received data in receive-FIFO </description>
                                    <value>#0</value>
                                </enumeratedValue>
                                <enumeratedValue>
                                    <name>1</name>
                                    <description>Non-FIFO selected (CCR3.FM = 0): A framing error has occurred FIFO selected (CCR3.FM = 1): One or more framing errors occurred in received data in receive-FIFO </description>
                                    <value>#1</value>
                                </enumeratedValue>
                            </enumeratedValues>
                        </field>
                        <field>
                            <name>TDRE</name>
                            <description>Transmit Data Empty Flag</description>
                            <lsb>29</lsb>
                            <msb>29</msb>
                            <access>read-only</access>
                            <enumeratedValues>
                                <enumeratedValue>
                                    <name>0</name>
                                    <description>Non-FIFO selected (CCR3.FM = 0): Transmit data is in TDR register FIFO selected (CCR3.FM = 1): The quantity of transmit data written in transmit-FIFO exceeds the specified transmit triggering number. </description>
                                    <value>#0</value>
                                </enumeratedValue>
                                <enumeratedValue>
                                    <name>1</name>
                                    <description>Non-FIFO selected (CCR3.FM = 0): No transmit data is in TDR register FIFO selected (CCR3.FM = 1): The quantity of transmit data written in transmit-FIFO is equal to or less than the specified transmit triggering number. </description>
                                    <value>#1</value>
                                </enumeratedValue>
                            </enumeratedValues>
                        </field>
                        <field>
                            <name>TEND</name>
                            <description>Transmit End Flag</description>
                            <lsb>30</lsb>
                            <msb>30</msb>
                            <access>read-only</access>
                            <enumeratedValues>
                                <enumeratedValue>
                                    <name>0</name>
                                    <description>A character is being transmitted or standing by for transmission.</description>
                                    <value>#0</value>
                                </enumeratedValue>
                                <enumeratedValue>
                                    <name>1</name>
                                    <description>Character transfer has been completed, or sending Break Field.</description>
                                    <value>#1</value>
                                </enumeratedValue>
                            </enumeratedValues>
                        </field>
                        <field>
                            <name>RDRF</name>
                            <description>Receive Data Full Flag</description>
                            <lsb>31</lsb>
                            <msb>31</msb>
                            <access>read-only</access>
                            <enumeratedValues>
                                <enumeratedValue>
                                    <name>0</name>
                                    <description>Non-FIFO selected (CCR3.FM = 0): No received data is in RDR register FIFO selected (CCR3.FM = 1): The quantity of receive data written in receive-FIFO falls below the specified receive triggering number. </description>
                                    <value>#0</value>
                                </enumeratedValue>
                                <enumeratedValue>
                                    <name>1</name>
                                    <description>Non-FIFO selected (CCR3.FM = 0): Received data is in RDR register FIFO selected (CCR3.FM = 1): The quantity of receive data written in receive-FIFO is equal to or greater than the specified receive triggering number. </description>
                                    <value>#1</value>
                                </enumeratedValue>
                            </enumeratedValues>
                        </field>
                    </fields>
                </register>
                <register>
                    <name>ISR</name>
                    <description>Simple IIC Status Register</description>
                    <addressOffset>0x4C</addressOffset>
                    <size>32</size>
                    <access>read-only</access>
                    <resetValue>0x00000000</resetValue>
                    <resetMask>0xffffffff</resetMask>
                    <fields>
                        <field>
                            <name>IICACKR</name>
                            <description>ACK Reception Data Flag</description>
                            <lsb>0</lsb>
                            <msb>0</msb>
                            <access>read-only</access>
                            <enumeratedValues>
                                <enumeratedValue>
                                    <name>0</name>
                                    <description>ACK received</description>
                                    <value>#0</value>
                                </enumeratedValue>
                                <enumeratedValue>
                                    <name>1</name>
                                    <description>NACK received</description>
                                    <value>#1</value>
                                </enumeratedValue>
                            </enumeratedValues>
                        </field>
                        <field>
                            <name>IICSTIF</name>
                            <description>Issuing of Start, Restart, or Stop Condition Completed Flag</description>
                            <lsb>3</lsb>
                            <msb>3</msb>
                            <access>read-only</access>
                            <enumeratedValues>
                                <enumeratedValue>
                                    <name>0</name>
                                    <description>There are no requests for generating conditions or a condition is being generated.</description>
                                    <value>#0</value>
                                </enumeratedValue>
                                <enumeratedValue>
                                    <name>1</name>
                                    <description>A start, restart, or stop condition is completely generated.</description>
                                    <value>#1</value>
                                </enumeratedValue>
                            </enumeratedValues>
                        </field>
                    </fields>
                </register>
                <register>
                    <name>FRSR</name>
                    <description>FIFO Receive Status Register</description>
                    <addressOffset>0x50</addressOffset>
                    <size>32</size>
                    <access>read-only</access>
                    <resetValue>0x00000000</resetValue>
                    <resetMask>0xfffffffd</resetMask>
                    <fields>
                        <field>
                            <name>DR</name>
                            <description>Receive Data Ready Flag</description>
                            <lsb>0</lsb>
                            <msb>0</msb>
                            <access>read-only</access>
                            <enumeratedValues>
                                <enumeratedValue>
                                    <name>0</name>
                                    <description>Receiving is in progress, or no received data remains in the receive-FIFO after a successful reception (receive-FIFO is empty)</description>
                                    <value>#0</value>
                                </enumeratedValue>
                                <enumeratedValue>
                                    <name>1</name>
                                    <description>The following receive data is not received for a fixed period after storing data under the threshold in the receive-FIFO</description>
                                    <value>#1</value>
                                </enumeratedValue>
                            </enumeratedValues>
                        </field>
                        <field>
                            <name>R</name>
                            <description>Receive-FIFO Data Count</description>
                            <lsb>8</lsb>
                            <msb>13</msb>
                            <access>read-only</access>
                        </field>
                        <field>
                            <name>PNUM</name>
                            <description>Parity Error Count</description>
                            <lsb>16</lsb>
                            <msb>21</msb>
                            <access>read-only</access>
                        </field>
                        <field>
                            <name>FNUM</name>
                            <description>Framing Error Count</description>
                            <lsb>24</lsb>
                            <msb>29</msb>
                            <access>read-only</access>
                        </field>
                    </fields>
                </register>
                <register>
                    <name>FTSR</name>
                    <description>FIFO Transmit Status Register</description>
                    <addressOffset>0x54</addressOffset>
                    <size>32</size>
                    <access>read-only</access>
                    <resetValue>0x00000000</resetValue>
                    <resetMask>0xffffffff</resetMask>
                    <fields>
                        <field>
                            <name>T</name>
                            <description>Transmit-FIFO Data Count</description>
                            <lsb>0</lsb>
                            <msb>5</msb>
                            <access>read-only</access>
                        </field>
                    </fields>
                </register>
                <register>
                    <name>MSR</name>
                    <description>Manchester Status Register</description>
                    <addressOffset>0x58</addressOffset>
                    <size>32</size>
                    <access>read-only</access>
                    <resetValue>0x00000000</resetValue>
                    <resetMask>0xffffffff</resetMask>
                    <fields>
                        <field>
                            <name>PFER</name>
                            <description>Preface Error Flag</description>
                            <lsb>0</lsb>
                            <msb>0</msb>
                            <access>read-only</access>
                            <enumeratedValues>
                                <enumeratedValue>
                                    <name>0</name>
                                    <description>No preface error detected</description>
                                    <value>#0</value>
                                </enumeratedValue>
                                <enumeratedValue>
                                    <name>1</name>
                                    <description>Preface error detected</description>
                                    <value>#1</value>
                                </enumeratedValue>
                            </enumeratedValues>
                        </field>
                        <field>
                            <name>SYER</name>
                            <description>SYNC Error Flag</description>
                            <lsb>1</lsb>
                            <msb>1</msb>
                            <access>read-only</access>
                            <enumeratedValues>
                                <enumeratedValue>
                                    <name>0</name>
                                    <description>No receive SYNC error detected</description>
                                    <value>#0</value>
                                </enumeratedValue>
                                <enumeratedValue>
                                    <name>1</name>
                                    <description>Receive SYNC error detected</description>
                                    <value>#1</value>
                                </enumeratedValue>
                            </enumeratedValues>
                        </field>
                        <field>
                            <name>SBER</name>
                            <description>Start Bit Error Flag</description>
                            <lsb>2</lsb>
                            <msb>2</msb>
                            <access>read-only</access>
                            <enumeratedValues>
                                <enumeratedValue>
                                    <name>0</name>
                                    <description>No start bit error detected</description>
                                    <value>#0</value>
                                </enumeratedValue>
                                <enumeratedValue>
                                    <name>1</name>
                                    <description>Start bit error detected</description>
                                    <value>#1</value>
                                </enumeratedValue>
                            </enumeratedValues>
                        </field>
                        <field>
                            <name>MER</name>
                            <description>Manchester Error Flag</description>
                            <lsb>4</lsb>
                            <msb>4</msb>
                            <access>read-only</access>
                            <enumeratedValues>
                                <enumeratedValue>
                                    <name>0</name>
                                    <description>No Manchester error occurred</description>
                                    <value>#0</value>
                                </enumeratedValue>
                                <enumeratedValue>
                                    <name>1</name>
                                    <description>Manchester error has occurred</description>
                                    <value>#1</value>
                                </enumeratedValue>
                            </enumeratedValues>
                        </field>
                        <field>
                            <name>RSYNC</name>
                            <description>Receive SYNC Data Bit</description>
                            <lsb>6</lsb>
                            <msb>6</msb>
                            <access>read-only</access>
                            <enumeratedValues>
                                <enumeratedValue>
                                    <name>0</name>
                                    <description>The received start bit is DATA SYNC</description>
                                    <value>#0</value>
                                </enumeratedValue>
                                <enumeratedValue>
                                    <name>1</name>
                                    <description>The received start bit is COMMAND SYNC</description>
                                    <value>#1</value>
                                </enumeratedValue>
                            </enumeratedValues>
                        </field>
                    </fields>
                </register>
                <register>
                    <name>XSR0</name>
                    <description>Simple LIN Status Register 0</description>
                    <addressOffset>0x5C</addressOffset>
                    <size>32</size>
                    <access>read-only</access>
                    <resetValue>0x00000000</resetValue>
                    <resetMask>0xffffffff</resetMask>
                    <fields>
                        <field>
                            <name>SFSF</name>
                            <description>Start Frame Status Flag</description>
                            <lsb>0</lsb>
                            <msb>0</msb>
                            <access>read-only</access>
                            <enumeratedValues>
                                <enumeratedValue>
                                    <name>0</name>
                                    <description>Start Frame detection disabled or Start Frame detection complete</description>
                                    <value>#0</value>
                                </enumeratedValue>
                                <enumeratedValue>
                                    <name>1</name>
                                    <description>Before Start Frame detection or during detection</description>
                                    <value>#1</value>
                                </enumeratedValue>
                            </enumeratedValues>
                        </field>
                        <field>
                            <name>RXDSF</name>
                            <description>RXDn Input Status Flag</description>
                            <lsb>1</lsb>
                            <msb>1</msb>
                            <access>read-only</access>
                            <enumeratedValues>
                                <enumeratedValue>
                                    <name>0</name>
                                    <description>RXDn input to SCI is enabled</description>
                                    <value>#0</value>
                                </enumeratedValue>
                                <enumeratedValue>
                                    <name>1</name>
                                    <description>RXDn input to SCI is disabled</description>
                                    <value>#1</value>
                                </enumeratedValue>
                            </enumeratedValues>
                        </field>
                        <field>
                            <name>BFOF</name>
                            <description>Break Field Output Completion Flag</description>
                            <lsb>8</lsb>
                            <msb>8</msb>
                            <access>read-only</access>
                            <enumeratedValues>
                                <enumeratedValue>
                                    <name>0</name>
                                    <description>Break Field is being output or is not being output</description>
                                    <value>#0</value>
                                </enumeratedValue>
                                <enumeratedValue>
                                    <name>1</name>
                                    <description>Completed BF output</description>
                                    <value>#1</value>
                                </enumeratedValue>
                            </enumeratedValues>
                        </field>
                        <field>
                            <name>BCDF</name>
                            <description>Bus Conflict Detection Flag</description>
                            <lsb>9</lsb>
                            <msb>9</msb>
                            <access>read-only</access>
                            <enumeratedValues>
                                <enumeratedValue>
                                    <name>0</name>
                                    <description>No bus collision detected</description>
                                    <value>#0</value>
                                </enumeratedValue>
                                <enumeratedValue>
                                    <name>1</name>
                                    <description>Detected a bus collision</description>
                                    <value>#1</value>
                                </enumeratedValue>
                            </enumeratedValues>
                        </field>
                        <field>
                            <name>BFDF</name>
                            <description>Break Field Detection Flag</description>
                            <lsb>10</lsb>
                            <msb>10</msb>
                            <access>read-only</access>
                            <enumeratedValues>
                                <enumeratedValue>
                                    <name>0</name>
                                    <description>Break Field is not detected</description>
                                    <value>#0</value>
                                </enumeratedValue>
                                <enumeratedValue>
                                    <name>1</name>
                                    <description>Break Field is detected</description>
                                    <value>#1</value>
                                </enumeratedValue>
                            </enumeratedValues>
                        </field>
                        <field>
                            <name>CF0MF</name>
                            <description>Control Field 0 Compare Match Flag</description>
                            <lsb>11</lsb>
                            <msb>11</msb>
                            <access>read-only</access>
                            <enumeratedValues>
                                <enumeratedValue>
                                    <name>0</name>
                                    <description>Control Field 0 received data does not match the setting data</description>
                                    <value>#0</value>
                                </enumeratedValue>
                                <enumeratedValue>
                                    <name>1</name>
                                    <description>Control Field 0 received data matches the setting data</description>
                                    <value>#1</value>
                                </enumeratedValue>
                            </enumeratedValues>
                        </field>
                        <field>
                            <name>CF1MF</name>
                            <description>Control Field 1 Compare Match Flag</description>
                            <lsb>12</lsb>
                            <msb>12</msb>
                            <access>read-only</access>
                            <enumeratedValues>
                                <enumeratedValue>
                                    <name>0</name>
                                    <description>Control Field 1 received data does not match the setting data</description>
                                    <value>#0</value>
                                </enumeratedValue>
                                <enumeratedValue>
                                    <name>1</name>
                                    <description>Control Field 1 received data matches the setting data</description>
                                    <value>#1</value>
                                </enumeratedValue>
                            </enumeratedValues>
                        </field>
                        <field>
                            <name>PIBDF</name>
                            <description>Priority Interrupt Bit Detection Flag</description>
                            <lsb>13</lsb>
                            <msb>13</msb>
                            <access>read-only</access>
                            <enumeratedValues>
                                <enumeratedValue>
                                    <name>0</name>
                                    <description>Priority interrupt bit is not detected</description>
                                    <value>#0</value>
                                </enumeratedValue>
                                <enumeratedValue>
                                    <name>1</name>
                                    <description>Priority interrupt bit is detected</description>
                                    <value>#1</value>
                                </enumeratedValue>
                            </enumeratedValues>
                        </field>
                        <field>
                            <name>COF</name>
                            <description>Counter Overflow Flag</description>
                            <lsb>14</lsb>
                            <msb>14</msb>
                            <access>read-only</access>
                            <enumeratedValues>
                                <enumeratedValue>
                                    <name>0</name>
                                    <description>Break Field detection counter has not overflowed</description>
                                    <value>#0</value>
                                </enumeratedValue>
                                <enumeratedValue>
                                    <name>1</name>
                                    <description>Break Field detection counter overflowed</description>
                                    <value>#1</value>
                                </enumeratedValue>
                            </enumeratedValues>
                        </field>
                        <field>
                            <name>AEDF</name>
                            <description>Active Edge Detection Flag</description>
                            <lsb>15</lsb>
                            <msb>15</msb>
                            <access>read-only</access>
                            <enumeratedValues>
                                <enumeratedValue>
                                    <name>0</name>
                                    <description>No valid edge detected</description>
                                    <value>#0</value>
                                </enumeratedValue>
                                <enumeratedValue>
                                    <name>1</name>
                                    <description>Detected a valid edge</description>
                                    <value>#1</value>
                                </enumeratedValue>
                            </enumeratedValues>
                        </field>
                        <field>
                            <name>CF0RD</name>
                            <description>Control Field 0 received data</description>
                            <lsb>16</lsb>
                            <msb>23</msb>
                            <access>read-only</access>
                        </field>
                        <field>
                            <name>CF1RD</name>
                            <description>Control Field 1 received data</description>
                            <lsb>24</lsb>
                            <msb>31</msb>
                            <access>read-only</access>
                        </field>
                    </fields>
                </register>
                <register>
                    <name>XSR1</name>
                    <description>Simple LIN Status Register 1</description>
                    <addressOffset>0x60</addressOffset>
                    <size>32</size>
                    <access>read-only</access>
                    <resetValue>0x00000000</resetValue>
                    <resetMask>0xffffffff</resetMask>
                    <fields>
                        <field>
                            <name>TCNT</name>
                            <description>Timer Count Capture Value</description>
                            <lsb>0</lsb>
                            <msb>15</msb>
                            <access>read-only</access>
                        </field>
                    </fields>
                </register>
                <register>
                    <name>CFCLR</name>
                    <description>Common Flag Clear Register</description>
                    <addressOffset>0x68</addressOffset>
                    <size>32</size>
                    <access>write-only</access>
                    <resetValue>0x00000000</resetValue>
                    <resetMask>0xffffffff</resetMask>
                    <fields>
                        <field>
                            <name>ERSC</name>
                            <description>ERS Clear Bit</description>
                            <lsb>4</lsb>
                            <msb>4</msb>
                            <access>write-only</access>
                        </field>
                        <field>
                            <name>DCMFC</name>
                            <description>DCMF Clear Bit</description>
                            <lsb>16</lsb>
                            <msb>16</msb>
                            <access>write-only</access>
                        </field>
                        <field>
                            <name>DPERC</name>
                            <description>DPER Clear Bit</description>
                            <lsb>17</lsb>
                            <msb>17</msb>
                            <access>write-only</access>
                        </field>
                        <field>
                            <name>DFERC</name>
                            <description>DFER Clear Bit</description>
                            <lsb>18</lsb>
                            <msb>18</msb>
                            <access>write-only</access>
                        </field>
                        <field>
                            <name>ORERC</name>
                            <description>ORER Clear Bit</description>
                            <lsb>24</lsb>
                            <msb>24</msb>
                            <access>write-only</access>
                        </field>
                        <field>
                            <name>MFFC</name>
                            <description>MFF Clear Bit</description>
                            <lsb>26</lsb>
                            <msb>26</msb>
                            <access>write-only</access>
                        </field>
                        <field>
                            <name>PERC</name>
                            <description>PER Clear Bit</description>
                            <lsb>27</lsb>
                            <msb>27</msb>
                            <access>write-only</access>
                        </field>
                        <field>
                            <name>FERC</name>
                            <description>FER Clear Bit</description>
                            <lsb>28</lsb>
                            <msb>28</msb>
                            <access>write-only</access>
                        </field>
                        <field>
                            <name>TDREC</name>
                            <description>TDRE Clear Bit</description>
                            <lsb>29</lsb>
                            <msb>29</msb>
                            <access>write-only</access>
                        </field>
                        <field>
                            <name>RDRFC</name>
                            <description>RDRF Clear Bit</description>
                            <lsb>31</lsb>
                            <msb>31</msb>
                            <access>write-only</access>
                        </field>
                    </fields>
                </register>
                <register>
                    <name>ICFCLR</name>
                    <description>Simple IIC Flag Clear Register</description>
                    <addressOffset>0x6C</addressOffset>
                    <size>32</size>
                    <access>write-only</access>
                    <resetValue>0x00000000</resetValue>
                    <resetMask>0xffffffff</resetMask>
                    <fields>
                        <field>
                            <name>IICSTIFC</name>
                            <description>IICSTIF Clear Bit</description>
                            <lsb>3</lsb>
                            <msb>3</msb>
                            <access>write-only</access>
                        </field>
                    </fields>
                </register>
                <register>
                    <name>FFCLR</name>
                    <description>FIFO Flag Clear Register</description>
                    <addressOffset>0x70</addressOffset>
                    <size>32</size>
                    <access>write-only</access>
                    <resetValue>0x00000000</resetValue>
                    <resetMask>0xffffffff</resetMask>
                    <fields>
                        <field>
                            <name>DRC</name>
                            <description>DR Clear Bit</description>
                            <lsb>0</lsb>
                            <msb>0</msb>
                            <access>write-only</access>
                        </field>
                    </fields>
                </register>
                <register>
                    <name>MFCLR</name>
                    <description>Manchester Flag Clear Register</description>
                    <addressOffset>0x74</addressOffset>
                    <size>32</size>
                    <access>write-only</access>
                    <resetValue>0x00000000</resetValue>
                    <resetMask>0xffffffff</resetMask>
                    <fields>
                        <field>
                            <name>PFERC</name>
                            <description>PFER Clear Bit</description>
                            <lsb>0</lsb>
                            <msb>0</msb>
                            <access>write-only</access>
                        </field>
                        <field>
                            <name>SYERC</name>
                            <description>SYER Clear Bit</description>
                            <lsb>1</lsb>
                            <msb>1</msb>
                            <access>write-only</access>
                        </field>
                        <field>
                            <name>SBERC</name>
                            <description>SBER Clear Bit</description>
                            <lsb>2</lsb>
                            <msb>2</msb>
                            <access>write-only</access>
                        </field>
                        <field>
                            <name>MERC</name>
                            <description>MER Clear Bit</description>
                            <lsb>4</lsb>
                            <msb>4</msb>
                            <access>write-only</access>
                        </field>
                    </fields>
                </register>
                <register>
                    <name>XFCLR</name>
                    <description>Simple LIN Flag Clear Register</description>
                    <addressOffset>0x78</addressOffset>
                    <size>32</size>
                    <access>write-only</access>
                    <resetValue>0x00000000</resetValue>
                    <resetMask>0xffffffff</resetMask>
                    <fields>
                        <field>
                            <name>BFOC</name>
                            <description>BFOF Clear Bit</description>
                            <lsb>8</lsb>
                            <msb>8</msb>
                            <access>write-only</access>
                        </field>
                        <field>
                            <name>BCDC</name>
                            <description>BCDF Clear Bit</description>
                            <lsb>9</lsb>
                            <msb>9</msb>
                            <access>write-only</access>
                        </field>
                        <field>
                            <name>BFDC</name>
                                </enumeratedValue>
                                <enumeratedValue>
                                    <name>10</name>
                                    <description>ONE ZERO</description>
                                    <value>#10</value>
                                </enumeratedValue>
                                <enumeratedValue>
                                    <name>11</name>
                                    <description>ALL ONE</description>
                                    <value>#11</value>
                                </enumeratedValue>
                            </enumeratedValues>
                        </field>
                        <field>
                            <name>RPLEN</name>
                            <description>Receive Preface Length</description>
                            <lsb>16</lsb>
                            <msb>19</msb>
                            <access>read-write</access>
                            <enumeratedValues>
                                <enumeratedValue>
                                    <name>0x0</name>
                                    <description>Disables the receive preface generation</description>
                                    <value>0x0</value>
                                </enumeratedValue>
                                <enumeratedValue>
                                    <name>Others</name>
                                    <description>Receive preface length (bit length)</description>
                                    <isDefault>true</isDefault>
                                </enumeratedValue>
                            </enumeratedValues>
                        </field>
                        <field>
                            <name>RPPAT</name>
                            <description>Receive Preface Pattern</description>
                            <lsb>20</lsb>
                            <msb>21</msb>
                            <access>read-write</access>
                            <enumeratedValues>
                                <enumeratedValue>
                                    <name>00</name>
                                    <description>ALL ZERO</description>
                                    <value>#00</value>
                                </enumeratedValue>
                                <enumeratedValue>
                                    <name>01</name>
                                    <description>ZERO ONE</description>
                                    <value>#01</value>
                                </enumeratedValue>
                                <enumeratedValue>
                                    <name>10</name>
                                    <description>ONE ZERO</description>
                                    <value>#10</value>
                                </enumeratedValue>
                                <enumeratedValue>
                                    <name>11</name>
                                    <description>ALL ONE</description>
                                    <value>#11</value>
                                </enumeratedValue>
                            </enumeratedValues>
                        </field>
                        <field>
                            <name>PFEREN</name>
                            <description>Preface Error Enable</description>
                            <lsb>24</lsb>
                            <msb>24</msb>
                            <access>read-write</access>
                            <enumeratedValues>
                                <enumeratedValue>
                                    <name>0</name>
                                    <description>Does not handle a preface error as an interrupt source</description>
                                    <value>#0</value>
                                </enumeratedValue>
                                <enumeratedValue>
                                    <name>1</name>
                                    <description>Handles a preface error as an interrupt source</description>
                                    <value>#1</value>
                                </enumeratedValue>
                            </enumeratedValues>
                        </field>
                        <field>
                            <name>SYEREN</name>
                            <description>Receive SYNC Error Enable</description>
                            <lsb>25</lsb>
                            <msb>25</msb>
                            <access>read-write</access>
                            <enumeratedValues>
                                <enumeratedValue>
                                    <name>0</name>
                                    <description>Does not handle a receive SYNC error as an interrupt source</description>
                                    <value>#0</value>
                                </enumeratedValue>
                                <enumeratedValue>
                                    <name>1</name>
                                    <description>Handles a receive SYNC error as an interrupt source</description>
                                    <value>#1</value>
                                </enumeratedValue>
                            </enumeratedValues>
                        </field>
                        <field>
                            <name>SBEREN</name>
                            <description>Start Bit Error Enable</description>
                            <lsb>26</lsb>
                            <msb>26</msb>
                            <access>read-write</access>
                            <enumeratedValues>
                                <enumeratedValue>
                                    <name>0</name>
                                    <description>Does not handle a start bit error as an interrupt source</description>
                                    <value>#0</value>
                                </enumeratedValue>
                                <enumeratedValue>
                                    <name>1</name>
                                    <description>Handles a start bit error as an interrupt source</description>
                                    <value>#1</value>
                                </enumeratedValue>
                            </enumeratedValues>
                        </field>
                    </fields>
                </register>
                <register>
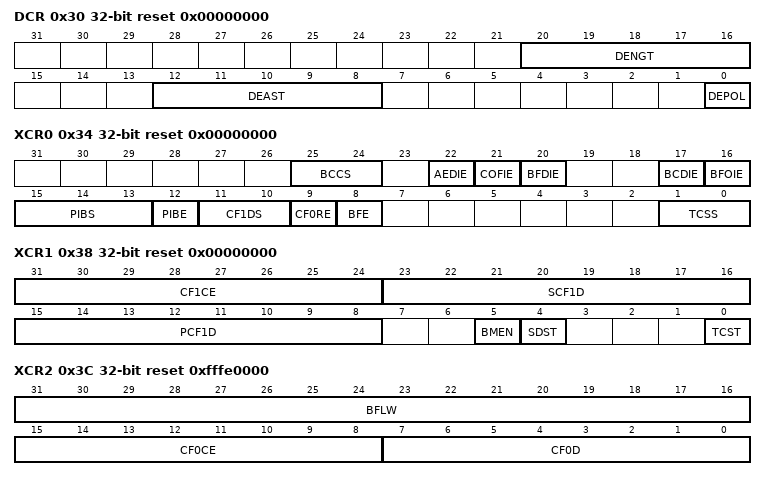
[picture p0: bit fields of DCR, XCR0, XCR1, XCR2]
                    <name>DCR</name>
                    <description>Driver Control Register</description>
                    <addressOffset>0x30</addressOffset>
                    <size>32</size>
                    <access>read-write</access>
                    <resetValue>0x00000000</resetValue>
                    <resetMask>0xffffffff</resetMask>
                    <fields>
                        <field>
                            <name>DEPOL</name>
                            <description>Driver Effective Polarity Select</description>
                            <lsb>0</lsb>
                            <msb>0</msb>
                            <access>read-write</access>
                            <enumeratedValues>
                                <enumeratedValue>
                                    <name>0</name>
                                    <description>The DEn signal is active-high</description>
                                    <value>#0</value>
                                </enumeratedValue>
                                <enumeratedValue>
                                    <name>1</name>
                                    <description>The DEn signal is active-low</description>
                                    <value>#1</value>
                                </enumeratedValue>
                            </enumeratedValues>
                        </field>
                        <field>
                            <name>DEAST</name>
                            <description>Driver Assertion Time</description>
                            <lsb>8</lsb>
                            <msb>12</msb>
                            <access>read-write</access>
                        </field>
                        <field>
                            <name>DENGT</name>
                            <description>Driver Negate Time</description>
                            <lsb>16</lsb>
                            <msb>20</msb>
                            <access>read-write</access>
                        </field>
                    </fields>
                </register>
                <register>
                    <name>XCR0</name>
                    <description>Simple LIN Control Register 0</description>
                    <addressOffset>0x34</addressOffset>
                    <size>32</size>
                    <access>read-write</access>
                    <resetValue>0x00000000</resetValue>
                    <resetMask>0xffffffff</resetMask>
                    <fields>
                        <field>
                            <name>TCSS</name>
                            <description>Timer Count Clock Source Selection</description>
                            <lsb>0</lsb>
                            <msb>1</msb>
                            <access>read-write</access>
                            <enumeratedValues>
                                <enumeratedValue>
                                    <name>01</name>
                                    <description>TCLK/4</description>
                                    <value>#01</value>
                                </enumeratedValue>
                                <enumeratedValue>
                                    <name>10</name>
                                    <description>TCLK/16</description>
                                    <value>#10</value>
                                </enumeratedValue>
                                <enumeratedValue>
                                    <name>11</name>
                                    <description>TCLK/64</description>
                                    <value>#11</value>
                                </enumeratedValue>
                            </enumeratedValues>
                        </field>
                        <field>
                            <name>BFE</name>
                            <description>Break Field Enable</description>
                            <lsb>8</lsb>
                            <msb>8</msb>
                            <access>read-write</access>
                            <enumeratedValues>
                                <enumeratedValue>
                                    <name>0</name>
                                    <description>No Break Field</description>
                                    <value>#0</value>
                                </enumeratedValue>
                                <enumeratedValue>
                                    <name>1</name>
                                    <description>With Break Field</description>
                                    <value>#1</value>
                                </enumeratedValue>
                            </enumeratedValues>
                        </field>
                        <field>
                            <name>CF0RE</name>
                            <description>Control Field 0 Enable</description>
                            <lsb>9</lsb>
                            <msb>9</msb>
                            <access>read-write</access>
                            <enumeratedValues>
                                <enumeratedValue>
                                    <name>0</name>
                                    <description>No Control Field 0</description>
                                    <value>#0</value>
                                </enumeratedValue>
                                <enumeratedValue>
                                    <name>1</name>
                                    <description>With Control Field 0</description>
                                    <value>#1</value>
                                </enumeratedValue>
                            </enumeratedValues>
                        </field>
                        <field>
                            <name>CF1DS</name>
                            <description>Control Field1 Compare Data Select</description>
                            <lsb>10</lsb>
                            <msb>11</msb>
                            <access>read-write</access>
                            <enumeratedValues>
                                <enumeratedValue>
                                    <name>00</name>
                                    <description>Select XCR1.PCF1D[7:0] as the compare data</description>
                                    <value>#00</value>
                                </enumeratedValue>
                                <enumeratedValue>
                                    <name>01</name>
                                    <description>Select XCR1.SCF1D[7:0] as the compare data</description>
                                    <value>#01</value>
                                </enumeratedValue>
                                <enumeratedValue>
                                    <name>10</name>
                                    <description>Select both XCR1.PCF1D[7:0] and XCR1.SCF1D[7:0] as the compare data</description>
                                    <value>#10</value>
                                </enumeratedValue>
                                <enumeratedValue>
                                    <name>11</name>
                                    <description>Setting prohibited</description>
                                    <value>#11</value>
                                </enumeratedValue>
                            </enumeratedValues>
                        </field>
                        <field>
                            <name>PIBE</name>
                            <description>Priority Interrupt Bit Enable</description>
                            <lsb>12</lsb>
                            <msb>12</msb>
                            <access>read-write</access>
                            <enumeratedValues>
                                <enumeratedValue>
                                    <name>0</name>
                                    <description>Priority interrupt bit disabled</description>
                                    <value>#0</value>
                                </enumeratedValue>
                                <enumeratedValue>
                                    <name>1</name>
                                    <description>Priority interrupt bit enabled</description>
                                    <value>#1</value>
                                </enumeratedValue>
                            </enumeratedValues>
                        </field>
                        <field>
                            <name>PIBS</name>
                            <description>Priority Interrupt Bit Select</description>
                            <lsb>13</lsb>
                            <msb>15</msb>
                            <access>read-write</access>
                            <enumeratedValues>
                                <enumeratedValue>
                                    <name>000</name>
                                    <description>Bit 0 of Control Field 1</description>
                                    <value>#000</value>
                                </enumeratedValue>
                                <enumeratedValue>
                                    <name>001</name>
                                    <description>Bit 1 of Control Field 1</description>
                                    <value>#001</value>
                                </enumeratedValue>
                                <enumeratedValue>
                                    <name>010</name>
                                    <description>Bit 2 of Control Field 1</description>
                                    <value>#010</value>
                                </enumeratedValue>
                                <enumeratedValue>
                                    <name>011</name>
                                    <description>Bit 3 of Control Field 1</description>
                                    <value>#011</value>
                                </enumeratedValue>
                                <enumeratedValue>
                                    <name>100</name>
                                    <description>Bit 4 of Control Field 1</description>
                                    <value>#100</value>
                                </enumeratedValue>
                                <enumeratedValue>
                                    <name>101</name>
                                    <description>Bit 5 of Control Field 1</description>
                                    <value>#101</value>
                                </enumeratedValue>
                                <enumeratedValue>
                                    <name>110</name>
                                    <description>Bit 6 of Control Field 1</description>
                                    <value>#110</value>
                                </enumeratedValue>
                                <enumeratedValue>
                                    <name>111</name>
                                    <description>Bit 7 of Control Field 1</description>
                                    <value>#111</value>
                                </enumeratedValue>
                            </enumeratedValues>
                        </field>
                        <field>
                            <name>BFOIE</name>
                            <description>Break Field Output Completion Interrupt Enable</description>
                            <lsb>16</lsb>
                            <msb>16</msb>
                            <access>read-write</access>
                            <enumeratedValues>
                                <enumeratedValue>
                                    <name>0</name>
                                    <description>Break Field output completion is not included in SCIn_TXI interrupt factor</description>
                                    <value>#0</value>
                                </enumeratedValue>
                                <enumeratedValue>
                                    <name>1</name>
                                    <description>Break Field output completion is included in SCIn_TXI interrupt factor</description>
                                    <value>#1</value>
                                </enumeratedValue>
                            </enumeratedValues>
                        </field>
                        <field>
                            <name>BCDIE</name>
                            <description>Bus Conflict Detection Interrupt Enable</description>
                            <lsb>17</lsb>
                            <msb>17</msb>
                            <access>read-write</access>
                            <enumeratedValues>
                                <enumeratedValue>
                                    <name>0</name>
                                    <description>Bus conflict detection is not included in SCIn_ERI interrupt factor</description>
                                    <value>#0</value>
                                </enumeratedValue>
                                <enumeratedValue>
                                    <name>1</name>
                                    <description>Bus conflict detection is included in SCIn_ERI interrupt factor</description>
                                    <value>#1</value>
                                </enumeratedValue>
                            </enumeratedValues>
                        </field>
                        <field>
                            <name>BFDIE</name>
                            <description>Break Field Detection Interrupt Enable</description>
                            <lsb>20</lsb>
                            <msb>20</msb>
                            <access>read-write</access>
                            <enumeratedValues>
                                <enumeratedValue>
                                    <name>0</name>
                                    <description>Break Field detection interrupt disabled</description>
                                    <value>#0</value>
                                </enumeratedValue>
                                <enumeratedValue>
                                    <name>1</name>
                                    <description>Break Field detection interrupt enabled</description>
                                    <value>#1</value>
                                </enumeratedValue>
                            </enumeratedValues>
                        </field>
                        <field>
                            <name>COFIE</name>
                            <description>Counter Overflow Interrupt Enable</description>
                            <lsb>21</lsb>
                            <msb>21</msb>
                            <access>read-write</access>
                            <enumeratedValues>
                                <enumeratedValue>
                                    <name>0</name>
                                    <description>Counter overflow is not included in SCIn_ERI interrupt factor</description>
                                    <value>#0</value>
                                </enumeratedValue>
                                <enumeratedValue>
                                    <name>1</name>
                                    <description>Counter overflow is included in SCIn_ERI interrupt factor</description>
                                    <value>#1</value>
                                </enumeratedValue>
                            </enumeratedValues>
                        </field>
                        <field>
                            <name>AEDIE</name>
                            <description>Active Edge Detection Interrupt Enable</description>
                            <lsb>22</lsb>
                            <msb>22</msb>
                            <access>read-write</access>
                            <enumeratedValues>
                                <enumeratedValue>
                                    <name>0</name>
                                    <description>Active edge detection interrupt disabled</description>
                                    <value>#0</value>
                                </enumeratedValue>
                                <enumeratedValue>
                                    <name>1</name>
                                    <description>Active edge detection interrupt enabled</description>
                                    <value>#1</value>
                                </enumeratedValue>
                            </enumeratedValues>
                        </field>
                        <field>
                            <name>BCCS</name>
                            <description>Bus Conflict Detection Clock Selection</description>
                            <lsb>24</lsb>
                            <msb>25</msb>
                            <access>read-write</access>
                            <enumeratedValues>
                                <enumeratedValue>
                                    <name>00</name>
                                    <description>Base clock</description>
                                    <value>#00</value>
                                </enumeratedValue>
                                <enumeratedValue>
                                    <name>01</name>
                                    <description>Base clock/2</description>
                                    <value>#01</value>
                                </enumeratedValue>
                                <enumeratedValue>
                                    <name>10</name>
                                    <description>Base clock/4</description>
                                    <value>#10</value>
                                </enumeratedValue>
                                <enumeratedValue>
                                    <name>11</name>
                                    <description>Setting prohibited</description>
                                    <value>#11</value>
                                </enumeratedValue>
                            </enumeratedValues>
                        </field>
                    </fields>
                </register>
                <register>
                    <name>XCR1</name>
                    <description>Simple LIN Control Register 1</description>
                    <addressOffset>0x38</addressOffset>
                    <size>32</size>
                    <access>read-write</access>
                    <resetValue>0x00000000</resetValue>
                    <resetMask>0xffffffff</resetMask>
                    <fields>
                        <field>
                            <name>TCST</name>
                            <description>Break Field Output Timer Count Start Trigger</description>
                            <lsb>0</lsb>
                            <msb>0</msb>
                            <access>read-write</access>
                            <enumeratedValues>
                                <enumeratedValue>
                                    <name>0</name>
                                    <description>Break Field output timer count stopped</description>
                                    <value>#0</value>
                                </enumeratedValue>
                                <enumeratedValue>
                                    <name>1</name>
                                    <description>Break Field output timer count start</description>
                                    <value>#1</value>
                                </enumeratedValue>
                            </enumeratedValues>
                        </field>
                        <field>
                            <name>SDST</name>
                            <description>Start Frame Detection Enable</description>
                            <lsb>4</lsb>
                            <msb>4</msb>
                            <access>read-write</access>
                            <enumeratedValues>
                                <enumeratedValue>
                                    <name>0</name>
                                    <description>Start Frame/Break Field detection disabled</description>
                                    <value>#0</value>
                                </enumeratedValue>
                                <enumeratedValue>
                                    <name>1</name>
                                    <description>Start Frame/Break Field detection enabled</description>
                                    <value>#1</value>
                                </enumeratedValue>
                            </enumeratedValues>
                        </field>
                        <field>
                            <name>BMEN</name>
                            <description>Bit Rate Measurement Enable</description>
                            <lsb>5</lsb>
                            <msb>5</msb>
                            <access>read-write</access>
                            <enumeratedValues>
                                <enumeratedValue>
                                    <name>0</name>
                                    <description>Bit rate measurement disabled</description>
                                    <value>#0</value>
                                </enumeratedValue>
                                <enumeratedValue>
                                    <name>1</name>
                                    <description>Bit rate measurement enabled</description>
                                    <value>#1</value>
                                </enumeratedValue>
                            </enumeratedValues>
                        </field>
                        <field>
                            <name>PCF1D</name>
                            <description>Priority Compare Data for Control Field 1</description>
                            <lsb>8</lsb>
                            <msb>15</msb>
                            <access>read-write</access>
                        </field>
                        <field>
                            <name>SCF1D</name>
                            <description>Secondary Compare Data for Control Field 1</description>
                            <lsb>16</lsb>
                            <msb>23</msb>
                            <access>read-write</access>
                        </field>
                        <field>
                            <name>CF1CE</name>
                            <description>Control Field 1 Compare Bit Enable</description>
                            <lsb>24</lsb>
                            <msb>31</msb>
                            <access>read-write</access>
                            <enumeratedValues>
                                <enumeratedValue>
                                    <name>0</name>
                                    <description>Control Field 1 bit N compare disabled</description>
                                    <value>#0</value>
                                </enumeratedValue>
                                <enumeratedValue>
                                    <name>1</name>
                                    <description>Control Field 1 bit N compare enabled</description>
                                    <value>#1</value>
                                </enumeratedValue>
                            </enumeratedValues>
                        </field>
                    </fields>
                </register>
                <register>
                    <name>XCR2</name>
                    <description>Simple LIN Control Register 2</description>
                    <addressOffset>0x3C</addressOffset>
                    <size>32</size>
                    <access>read-write</access>
                    <resetValue>0xfffe0000</resetValue>
                    <resetMask>0xffffffff</resetMask>
                    <fields>
                        <field>
                            <name>CF0D</name>
                            <description>Control Field 0 Compare Data</description>
                            <lsb>0</lsb>
                            <msb>7</msb>
                            <access>read-write</access>
                        </field>
                        <field>
                            <name>CF0CE</name>
                            <description>Control Field 0 Compare Bit Enable</description>
                            <lsb>8</lsb>
                            <msb>15</msb>
                            <access>read-write</access>
                            <enumeratedValues>
                                <enumeratedValue>
                                    <name>0</name>
                                    <description>Control Field 0 bit N compare disabled</description>
                                    <value>#0</value>
                                </enumeratedValue>
                                <enumeratedValue>
                                    <name>1</name>
                                    <description>Control Field 0 bit N compare enabled</description>
                                    <value>#1</value>
                                </enumeratedValue>
                            </enumeratedValues>
                        </field>
                        <field>
                            <name>BFLW</name>
                            <description>Break Field Length Setting</description>
                            <lsb>16</lsb>
                            <msb>31</msb>
                            <access>read-write</access>
                        </field>
                    </fields>
                </register>
                <register>
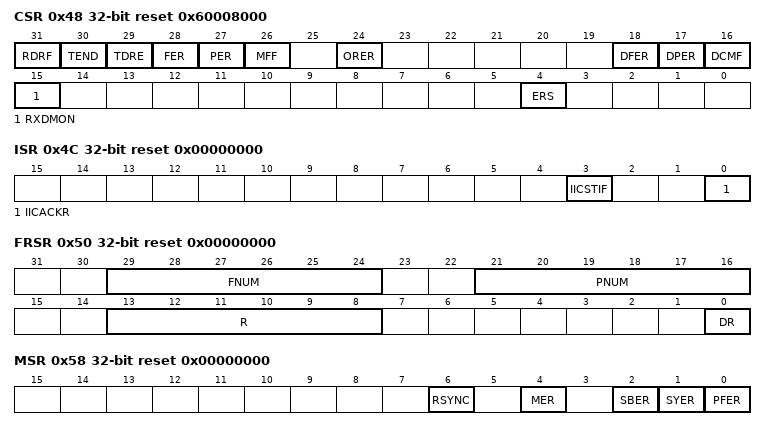
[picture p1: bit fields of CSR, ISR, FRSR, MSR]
                    <name>CSR</name>
                    <description>Common Status Register</description>
                    <addressOffset>0x48</addressOffset>
                    <size>32</size>
                    <access>read-only</access>
                    <resetValue>0x60008000</resetValue>
                    <resetMask>0xffffffff</resetMask>
                    <fields>
                        <field>
                            <name>ERS</name>
                            <description>Error Signal Status Flag</description>
                            <lsb>4</lsb>
                            <msb>4</msb>
                            <access>read-only</access>
                            <enumeratedValues>
                                <enumeratedValue>
                                    <name>0</name>
                                    <description>Error signal low not responded</description>
                                    <value>#0</value>
                                </enumeratedValue>
                                <enumeratedValue>
                                    <name>1</name>
                                    <description>Error signal low responded</description>
                                    <value>#1</value>
                                </enumeratedValue>
                            </enumeratedValues>
                        </field>
                        <field>
                            <name>RXDMON</name>
                            <description>Serial Input Data Monitor Bit</description>
                            <lsb>15</lsb>
                            <msb>15</msb>
                            <access>read-only</access>
                            <enumeratedValues>
                                <enumeratedValue>
                                    <name>0</name>
                                    <description>When RINV is 0, RXDn pin is the low level. When RINV is 1, RXDn pin is the high level. </description>
                                    <value>#0</value>
                                </enumeratedValue>
                                <enumeratedValue>
                                    <name>1</name>
                                    <description>When RINV is 0, RXDn pin is the high level. When RINV is 1, RXDn pin is the low level. </description>
                                    <value>#1</value>
                                </enumeratedValue>
                            </enumeratedValues>
                        </field>
                        <field>
                            <name>DCMF</name>
                            <description>Data Compare Match Flag</description>
                            <lsb>16</lsb>
                            <msb>16</msb>
                            <access>read-only</access>
                            <enumeratedValues>
                                <enumeratedValue>
                                    <name>0</name>
                                    <description>No matched</description>
                                    <value>#0</value>
                                </enumeratedValue>
                                <enumeratedValue>
                                    <name>1</name>
                                    <description>Matched</description>
                                    <value>#1</value>
                                </enumeratedValue>
                            </enumeratedValues>
                        </field>
                        <field>
                            <name>DPER</name>
                            <description>Data Compare Match Parity Error Flag</description>
                            <lsb>17</lsb>
                            <msb>17</msb>
                            <access>read-only</access>
                            <enumeratedValues>
                                <enumeratedValue>
                                    <name>0</name>
                                    <description>No parity error occurred at address match detection</description>
                                    <value>#0</value>
                                </enumeratedValue>
                                <enumeratedValue>
                                    <name>1</name>
                                    <description>A parity error has occurred at address match detection</description>
                                    <value>#1</value>
                                </enumeratedValue>
                            </enumeratedValues>
                        </field>
                        <field>
                            <name>DFER</name>
                            <description>Data Compare Match Framing Error Flag</description>
                            <lsb>18</lsb>
                            <msb>18</msb>
                            <access>read-only</access>
                            <enumeratedValues>
                                <enumeratedValue>
                                    <name>0</name>
                                    <description>No framing error occurred at address match detection</description>
                                    <value>#0</value>
                                </enumeratedValue>
                                <enumeratedValue>
                                    <name>1</name>
                                    <description>A framing error has occurred at address match detection</description>
                                    <value>#1</value>
                                </enumeratedValue>
                            </enumeratedValues>
                        </field>
                        <field>
                            <name>ORER</name>
                            <description>Overrun Error Flag</description>
                            <lsb>24</lsb>
                            <msb>24</msb>
                            <access>read-only</access>
                            <enumeratedValues>
                                <enumeratedValue>
                                    <name>0</name>
                                    <description>No overrun error occurred</description>
                                    <value>#0</value>
                                </enumeratedValue>
                                <enumeratedValue>
                                    <name>1</name>
                                    <description>An overrun error has occurred</description>
                                    <value>#1</value>
                                </enumeratedValue>
                            </enumeratedValues>
                        </field>
                        <field>
                            <name>MFF</name>
                            <description>Mode Fault Error Flag</description>
                            <lsb>26</lsb>
                            <msb>26</msb>
                            <access>read-only</access>
                            <enumeratedValues>
                                <enumeratedValue>
                                    <name>0</name>
                                    <description>No mode fault error</description>
                                    <value>#0</value>
                                </enumeratedValue>
                                <enumeratedValue>
                                    <name>1</name>
                                    <description>Mode fault error</description>
                                    <value>#1</value>
                                </enumeratedValue>
                            </enumeratedValues>
                        </field>
                        <field>
                            <name>PER</name>
                            <description>Parity Error Flag</description>
                            <lsb>27</lsb>
                            <msb>27</msb>
                            <access>read-only</access>
                            <enumeratedValues>
                                <enumeratedValue>
                                    <name>0</name>
                                    <description>Non-FIFO selected (CCR3.FM = 0): No parity error occurred FIFO selected (CCR3.FM = 1): No parity error in all received data in receive-FIFO </description>
                                    <value>#0</value>
                                </enumeratedValue>
                                <enumeratedValue>
                                    <name>1</name>
                                    <description>Non-FIFO selected (CCR3.FM = 0): A parity error has occurred FIFO selected (CCR3.FM = 1): One or more parity errors occurred in received data in receive-FIFO </description>
                                    <value>#1</value>
                                </enumeratedValue>
                            </enumeratedValues>
                        </field>
                        <field>
                            <name>FER</name>
                            <description>Framing Error Flag</description>
                            <lsb>28</lsb>
                            <msb>28</msb>
                            <access>read-only</access>
                            <enumeratedValues>
                                <enumeratedValue>
                                    <name>0</name>
                                    <description>Non-FIFO selected (CCR3.FM = 0): No framing error occurred FIFO selected (CCR3.FM = 1): No framing error in all received data in receive-FIFO </description>
                                    <value>#0</value>
                                </enumeratedValue>
                                <enumeratedValue>
                                    <name>1</name>
                                    <description>Non-FIFO selected (CCR3.FM = 0): A framing error has occurred FIFO selected (CCR3.FM = 1): One or more framing errors occurred in received data in receive-FIFO </description>
                                    <value>#1</value>
                                </enumeratedValue>
                            </enumeratedValues>
                        </field>
                        <field>
                            <name>TDRE</name>
                            <description>Transmit Data Empty Flag</description>
                            <lsb>29</lsb>
                            <msb>29</msb>
                            <access>read-only</access>
                            <enumeratedValues>
                                <enumeratedValue>
                                    <name>0</name>
                                    <description>Non-FIFO selected (CCR3.FM = 0): Transmit data is in TDR register FIFO selected (CCR3.FM = 1): The quantity of transmit data written in transmit-FIFO exceeds the specified transmit triggering number. </description>
                                    <value>#0</value>
                                </enumeratedValue>
                                <enumeratedValue>
                                    <name>1</name>
                                    <description>Non-FIFO selected (CCR3.FM = 0): No transmit data is in TDR register FIFO selected (CCR3.FM = 1): The quantity of transmit data written in transmit-FIFO is equal to or less than the specified transmit triggering number. </description>
                                    <value>#1</value>
                                </enumeratedValue>
                            </enumeratedValues>
                        </field>
                        <field>
                            <name>TEND</name>
                            <description>Transmit End Flag</description>
                            <lsb>30</lsb>
                            <msb>30</msb>
                            <access>read-only</access>
                            <enumeratedValues>
                                <enumeratedValue>
                                    <name>0</name>
                                    <description>A character is being transmitted or standing by for transmission.</description>
                                    <value>#0</value>
                                </enumeratedValue>
                                <enumeratedValue>
                                    <name>1</name>
                                    <description>Character transfer has been completed, or sending Break Field.</description>
                                    <value>#1</value>
                                </enumeratedValue>
                            </enumeratedValues>
                        </field>
                        <field>
                            <name>RDRF</name>
                            <description>Receive Data Full Flag</description>
                            <lsb>31</lsb>
                            <msb>31</msb>
                            <access>read-only</access>
                            <enumeratedValues>
                                <enumeratedValue>
                                    <name>0</name>
                                    <description>Non-FIFO selected (CCR3.FM = 0): No received data is in RDR register FIFO selected (CCR3.FM = 1): The quantity of receive data written in receive-FIFO falls below the specified receive triggering number. </description>
                                    <value>#0</value>
                                </enumeratedValue>
                                <enumeratedValue>
                                    <name>1</name>
                                    <description>Non-FIFO selected (CCR3.FM = 0): Received data is in RDR register FIFO selected (CCR3.FM = 1): The quantity of receive data written in receive-FIFO is equal to or greater than the specified receive triggering number. </description>
                                    <value>#1</value>
                                </enumeratedValue>
                            </enumeratedValues>
                        </field>
                    </fields>
                </register>
                <register>
                    <name>ISR</name>
                    <description>Simple IIC Status Register</description>
                    <addressOffset>0x4C</addressOffset>
                    <size>32</size>
                    <access>read-only</access>
                    <resetValue>0x00000000</resetValue>
                    <resetMask>0xffffffff</resetMask>
                    <fields>
                        <field>
                            <name>IICACKR</name>
                            <description>ACK Reception Data Flag</description>
                            <lsb>0</lsb>
                            <msb>0</msb>
                            <access>read-only</access>
                            <enumeratedValues>
                                <enumeratedValue>
                                    <name>0</name>
                                    <description>ACK received</description>
                                    <value>#0</value>
                                </enumeratedValue>
                                <enumeratedValue>
                                    <name>1</name>
                                    <description>NACK received</description>
                                    <value>#1</value>
                                </enumeratedValue>
                            </enumeratedValues>
                        </field>
                        <field>
                            <name>IICSTIF</name>
                            <description>Issuing of Start, Restart, or Stop Condition Completed Flag</description>
                            <lsb>3</lsb>
                            <msb>3</msb>
                            <access>read-only</access>
                            <enumeratedValues>
                                <enumeratedValue>
                                    <name>0</name>
                                    <description>There are no requests for generating conditions or a condition is being generated.</description>
                                    <value>#0</value>
                                </enumeratedValue>
                                <enumeratedValue>
                                    <name>1</name>
                                    <description>A start, restart, or stop condition is completely generated.</description>
                                    <value>#1</value>
                                </enumeratedValue>
                            </enumeratedValues>
                        </field>
                    </fields>
                </register>
                <register>
                    <name>FRSR</name>
                    <description>FIFO Receive Status Register</description>
                    <addressOffset>0x50</addressOffset>
                    <size>32</size>
                    <access>read-only</access>
                    <resetValue>0x00000000</resetValue>
                    <resetMask>0xfffffffd</resetMask>
                    <fields>
                        <field>
                            <name>DR</name>
                            <description>Receive Data Ready Flag</description>
                            <lsb>0</lsb>
                            <msb>0</msb>
                            <access>read-only</access>
                            <enumeratedValues>
                                <enumeratedValue>
                                    <name>0</name>
                                    <description>Receiving is in progress, or no received data remains in the receive-FIFO after a successful reception (receive-FIFO is empty)</description>
                                    <value>#0</value>
                                </enumeratedValue>
                                <enumeratedValue>
                                    <name>1</name>
                                    <description>The following receive data is not received for a fixed period after storing data under the threshold in the receive-FIFO</description>
                                    <value>#1</value>
                                </enumeratedValue>
                            </enumeratedValues>
                        </field>
                        <field>
                            <name>R</name>
                            <description>Receive-FIFO Data Count</description>
                            <lsb>8</lsb>
                            <msb>13</msb>
                            <access>read-only</access>
                        </field>
                        <field>
                            <name>PNUM</name>
                            <description>Parity Error Count</description>
                            <lsb>16</lsb>
                            <msb>21</msb>
                            <access>read-only</access>
                        </field>
                        <field>
                            <name>FNUM</name>
                            <description>Framing Error Count</description>
                            <lsb>24</lsb>
                            <msb>29</msb>
                            <access>read-only</access>
                        </field>
                    </fields>
                </register>
                <register>
                    <name>FTSR</name>
                    <description>FIFO Transmit Status Register</description>
                    <addressOffset>0x54</addressOffset>
                    <size>32</size>
                    <access>read-only</access>
                    <resetValue>0x00000000</resetValue>
                    <resetMask>0xffffffff</resetMask>
                    <fields>
                        <field>
                            <name>T</name>
                            <description>Transmit-FIFO Data Count</description>
                            <lsb>0</lsb>
                            <msb>5</msb>
                            <access>read-only</access>
                        </field>
                    </fields>
                </register>
                <register>
                    <name>MSR</name>
                    <description>Manchester Status Register</description>
                    <addressOffset>0x58</addressOffset>
                    <size>32</size>
                    <access>read-only</access>
                    <resetValue>0x00000000</resetValue>
                    <resetMask>0xffffffff</resetMask>
                    <fields>
                        <field>
                            <name>PFER</name>
                            <description>Preface Error Flag</description>
                            <lsb>0</lsb>
                            <msb>0</msb>
                            <access>read-only</access>
                            <enumeratedValues>
                                <enumeratedValue>
                                    <name>0</name>
                                    <description>No preface error detected</description>
                                    <value>#0</value>
                                </enumeratedValue>
                                <enumeratedValue>
                                    <name>1</name>
                                    <description>Preface error detected</description>
                                    <value>#1</value>
                                </enumeratedValue>
                            </enumeratedValues>
                        </field>
                        <field>
                            <name>SYER</name>
                            <description>SYNC Error Flag</description>
                            <lsb>1</lsb>
                            <msb>1</msb>
                            <access>read-only</access>
                            <enumeratedValues>
                                <enumeratedValue>
                                    <name>0</name>
                                    <description>No receive SYNC error detected</description>
                                    <value>#0</value>
                                </enumeratedValue>
                                <enumeratedValue>
                                    <name>1</name>
                                    <description>Receive SYNC error detected</description>
                                    <value>#1</value>
                                </enumeratedValue>
                            </enumeratedValues>
                        </field>
                        <field>
                            <name>SBER</name>
                            <description>Start Bit Error Flag</description>
                            <lsb>2</lsb>
                            <msb>2</msb>
                            <access>read-only</access>
                            <enumeratedValues>
                                <enumeratedValue>
                                    <name>0</name>
                                    <description>No start bit error detected</description>
                                    <value>#0</value>
                                </enumeratedValue>
                                <enumeratedValue>
                                    <name>1</name>
                                    <description>Start bit error detected</description>
                                    <value>#1</value>
                                </enumeratedValue>
                            </enumeratedValues>
                        </field>
                        <field>
                            <name>MER</name>
                            <description>Manchester Error Flag</description>
                            <lsb>4</lsb>
                            <msb>4</msb>
                            <access>read-only</access>
                            <enumeratedValues>
                                <enumeratedValue>
                                    <name>0</name>
                                    <description>No Manchester error occurred</description>
                                    <value>#0</value>
                                </enumeratedValue>
                                <enumeratedValue>
                                    <name>1</name>
                                    <description>Manchester error has occurred</description>
                                    <value>#1</value>
                                </enumeratedValue>
                            </enumeratedValues>
                        </field>
                        <field>
                            <name>RSYNC</name>
                            <description>Receive SYNC Data Bit</description>
                            <lsb>6</lsb>
                            <msb>6</msb>
                            <access>read-only</access>
                            <enumeratedValues>
                                <enumeratedValue>
                                    <name>0</name>
                                    <description>The received start bit is DATA SYNC</description>
                                    <value>#0</value>
                                </enumeratedValue>
                                <enumeratedValue>
                                    <name>1</name>
                                    <description>The received start bit is COMMAND SYNC</description>
                                    <value>#1</value>
                                </enumeratedValue>
                            </enumeratedValues>
                        </field>
                    </fields>
                </register>
                <register>
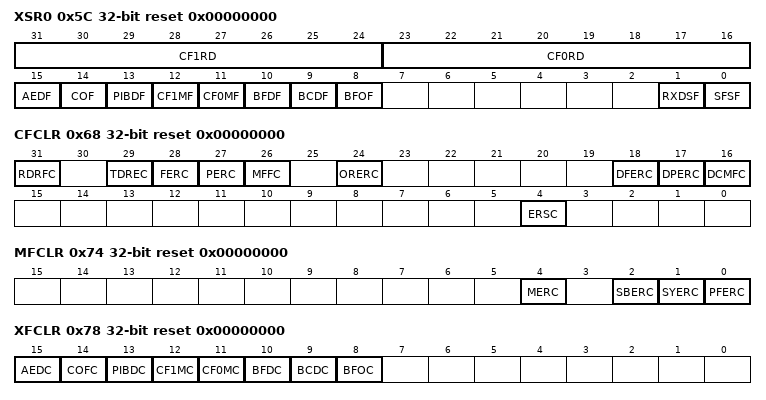
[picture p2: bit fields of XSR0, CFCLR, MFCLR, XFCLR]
                    <name>XSR0</name>
                    <description>Simple LIN Status Register 0</description>
                    <addressOffset>0x5C</addressOffset>
                    <size>32</size>
                    <access>read-only</access>
                    <resetValue>0x00000000</resetValue>
                    <resetMask>0xffffffff</resetMask>
                    <fields>
                        <field>
                            <name>SFSF</name>
                            <description>Start Frame Status Flag</description>
                            <lsb>0</lsb>
                            <msb>0</msb>
                            <access>read-only</access>
                            <enumeratedValues>
                                <enumeratedValue>
                                    <name>0</name>
                                    <description>Start Frame detection disabled or Start Frame detection complete</description>
                                    <value>#0</value>
                                </enumeratedValue>
                                <enumeratedValue>
                                    <name>1</name>
                                    <description>Before Start Frame detection or during detection</description>
                                    <value>#1</value>
                                </enumeratedValue>
                            </enumeratedValues>
                        </field>
                        <field>
                            <name>RXDSF</name>
                            <description>RXDn Input Status Flag</description>
                            <lsb>1</lsb>
                            <msb>1</msb>
                            <access>read-only</access>
                            <enumeratedValues>
                                <enumeratedValue>
                                    <name>0</name>
                                    <description>RXDn input to SCI is enabled</description>
                                    <value>#0</value>
                                </enumeratedValue>
                                <enumeratedValue>
                                    <name>1</name>
                                    <description>RXDn input to SCI is disabled</description>
                                    <value>#1</value>
                                </enumeratedValue>
                            </enumeratedValues>
                        </field>
                        <field>
                            <name>BFOF</name>
                            <description>Break Field Output Completion Flag</description>
                            <lsb>8</lsb>
                            <msb>8</msb>
                            <access>read-only</access>
                            <enumeratedValues>
                                <enumeratedValue>
                                    <name>0</name>
                                    <description>Break Field is being output or is not being output</description>
                                    <value>#0</value>
                                </enumeratedValue>
                                <enumeratedValue>
                                    <name>1</name>
                                    <description>Completed BF output</description>
                                    <value>#1</value>
                                </enumeratedValue>
                            </enumeratedValues>
                        </field>
                        <field>
                            <name>BCDF</name>
                            <description>Bus Conflict Detection Flag</description>
                            <lsb>9</lsb>
                            <msb>9</msb>
                            <access>read-only</access>
                            <enumeratedValues>
                                <enumeratedValue>
                                    <name>0</name>
                                    <description>No bus collision detected</description>
                                    <value>#0</value>
                                </enumeratedValue>
                                <enumeratedValue>
                                    <name>1</name>
                                    <description>Detected a bus collision</description>
                                    <value>#1</value>
                                </enumeratedValue>
                            </enumeratedValues>
                        </field>
                        <field>
                            <name>BFDF</name>
                            <description>Break Field Detection Flag</description>
                            <lsb>10</lsb>
                            <msb>10</msb>
                            <access>read-only</access>
                            <enumeratedValues>
                                <enumeratedValue>
                                    <name>0</name>
                                    <description>Break Field is not detected</description>
                                    <value>#0</value>
                                </enumeratedValue>
                                <enumeratedValue>
                                    <name>1</name>
                                    <description>Break Field is detected</description>
                                    <value>#1</value>
                                </enumeratedValue>
                            </enumeratedValues>
                        </field>
                        <field>
                            <name>CF0MF</name>
                            <description>Control Field 0 Compare Match Flag</description>
                            <lsb>11</lsb>
                            <msb>11</msb>
                            <access>read-only</access>
                            <enumeratedValues>
                                <enumeratedValue>
                                    <name>0</name>
                                    <description>Control Field 0 received data does not match the setting data</description>
                                    <value>#0</value>
                                </enumeratedValue>
                                <enumeratedValue>
                                    <name>1</name>
                                    <description>Control Field 0 received data matches the setting data</description>
                                    <value>#1</value>
                                </enumeratedValue>
                            </enumeratedValues>
                        </field>
                        <field>
                            <name>CF1MF</name>
                            <description>Control Field 1 Compare Match Flag</description>
                            <lsb>12</lsb>
                            <msb>12</msb>
                            <access>read-only</access>
                            <enumeratedValues>
                                <enumeratedValue>
                                    <name>0</name>
                                    <description>Control Field 1 received data does not match the setting data</description>
                                    <value>#0</value>
                                </enumeratedValue>
                                <enumeratedValue>
                                    <name>1</name>
                                    <description>Control Field 1 received data matches the setting data</description>
                                    <value>#1</value>
                                </enumeratedValue>
                            </enumeratedValues>
                        </field>
                        <field>
                            <name>PIBDF</name>
                            <description>Priority Interrupt Bit Detection Flag</description>
                            <lsb>13</lsb>
                            <msb>13</msb>
                            <access>read-only</access>
                            <enumeratedValues>
                                <enumeratedValue>
                                    <name>0</name>
                                    <description>Priority interrupt bit is not detected</description>
                                    <value>#0</value>
                                </enumeratedValue>
                                <enumeratedValue>
                                    <name>1</name>
                                    <description>Priority interrupt bit is detected</description>
                                    <value>#1</value>
                                </enumeratedValue>
                            </enumeratedValues>
                        </field>
                        <field>
                            <name>COF</name>
                            <description>Counter Overflow Flag</description>
                            <lsb>14</lsb>
                            <msb>14</msb>
                            <access>read-only</access>
                            <enumeratedValues>
                                <enumeratedValue>
                                    <name>0</name>
                                    <description>Break Field detection counter has not overflowed</description>
                                    <value>#0</value>
                                </enumeratedValue>
                                <enumeratedValue>
                                    <name>1</name>
                                    <description>Break Field detection counter overflowed</description>
                                    <value>#1</value>
                                </enumeratedValue>
                            </enumeratedValues>
                        </field>
                        <field>
                            <name>AEDF</name>
                            <description>Active Edge Detection Flag</description>
                            <lsb>15</lsb>
                            <msb>15</msb>
                            <access>read-only</access>
                            <enumeratedValues>
                                <enumeratedValue>
                                    <name>0</name>
                                    <description>No valid edge detected</description>
                                    <value>#0</value>
                                </enumeratedValue>
                                <enumeratedValue>
                                    <name>1</name>
                                    <description>Detected a valid edge</description>
                                    <value>#1</value>
                                </enumeratedValue>
                            </enumeratedValues>
                        </field>
                        <field>
                            <name>CF0RD</name>
                            <description>Control Field 0 received data</description>
                            <lsb>16</lsb>
                            <msb>23</msb>
                            <access>read-only</access>
                        </field>
                        <field>
                            <name>CF1RD</name>
                            <description>Control Field 1 received data</description>
                            <lsb>24</lsb>
                            <msb>31</msb>
                            <access>read-only</access>
                        </field>
                    </fields>
                </register>
                <register>
                    <name>XSR1</name>
                    <description>Simple LIN Status Register 1</description>
                    <addressOffset>0x60</addressOffset>
                    <size>32</size>
                    <access>read-only</access>
                    <resetValue>0x00000000</resetValue>
                    <resetMask>0xffffffff</resetMask>
                    <fields>
                        <field>
                            <name>TCNT</name>
                            <description>Timer Count Capture Value</description>
                            <lsb>0</lsb>
                            <msb>15</msb>
                            <access>read-only</access>
                        </field>
                    </fields>
                </register>
                <register>
                    <name>CFCLR</name>
                    <description>Common Flag Clear Register</description>
                    <addressOffset>0x68</addressOffset>
                    <size>32</size>
                    <access>write-only</access>
                    <resetValue>0x00000000</resetValue>
                    <resetMask>0xffffffff</resetMask>
                    <fields>
                        <field>
                            <name>ERSC</name>
                            <description>ERS Clear Bit</description>
                            <lsb>4</lsb>
                            <msb>4</msb>
                            <access>write-only</access>
                        </field>
                        <field>
                            <name>DCMFC</name>
                            <description>DCMF Clear Bit</description>
                            <lsb>16</lsb>
                            <msb>16</msb>
                            <access>write-only</access>
                        </field>
                        <field>
                            <name>DPERC</name>
                            <description>DPER Clear Bit</description>
                            <lsb>17</lsb>
                            <msb>17</msb>
                            <access>write-only</access>
                        </field>
                        <field>
                            <name>DFERC</name>
                            <description>DFER Clear Bit</description>
                            <lsb>18</lsb>
                            <msb>18</msb>
                            <access>write-only</access>
                        </field>
                        <field>
                            <name>ORERC</name>
                            <description>ORER Clear Bit</description>
                            <lsb>24</lsb>
                            <msb>24</msb>
                            <access>write-only</access>
                        </field>
                        <field>
                            <name>MFFC</name>
                            <description>MFF Clear Bit</description>
                            <lsb>26</lsb>
                            <msb>26</msb>
                            <access>write-only</access>
                        </field>
                        <field>
                            <name>PERC</name>
                            <description>PER Clear Bit</description>
                            <lsb>27</lsb>
                            <msb>27</msb>
                            <access>write-only</access>
                        </field>
                        <field>
                            <name>FERC</name>
                            <description>FER Clear Bit</description>
                            <lsb>28</lsb>
                            <msb>28</msb>
                            <access>write-only</access>
                        </field>
                        <field>
                            <name>TDREC</name>
                            <description>TDRE Clear Bit</description>
                            <lsb>29</lsb>
                            <msb>29</msb>
                            <access>write-only</access>
                        </field>
                        <field>
                            <name>RDRFC</name>
                            <description>RDRF Clear Bit</description>
                            <lsb>31</lsb>
                            <msb>31</msb>
                            <access>write-only</access>
                        </field>
                    </fields>
                </register>
                <register>
                    <name>ICFCLR</name>
                    <description>Simple IIC Flag Clear Register</description>
                    <addressOffset>0x6C</addressOffset>
                    <size>32</size>
                    <access>write-only</access>
                    <resetValue>0x00000000</resetValue>
                    <resetMask>0xffffffff</resetMask>
                    <fields>
                        <field>
                            <name>IICSTIFC</name>
                            <description>IICSTIF Clear Bit</description>
                            <lsb>3</lsb>
                            <msb>3</msb>
                            <access>write-only</access>
                        </field>
                    </fields>
                </register>
                <register>
                    <name>FFCLR</name>
                    <description>FIFO Flag Clear Register</description>
                    <addressOffset>0x70</addressOffset>
                    <size>32</size>
                    <access>write-only</access>
                    <resetValue>0x00000000</resetValue>
                    <resetMask>0xffffffff</resetMask>
                    <fields>
                        <field>
                            <name>DRC</name>
                            <description>DR Clear Bit</description>
                            <lsb>0</lsb>
                            <msb>0</msb>
                            <access>write-only</access>
                        </field>
                    </fields>
                </register>
                <register>
                    <name>MFCLR</name>
                    <description>Manchester Flag Clear Register</description>
                    <addressOffset>0x74</addressOffset>
                    <size>32</size>
                    <access>write-only</access>
                    <resetValue>0x00000000</resetValue>
                    <resetMask>0xffffffff</resetMask>
                    <fields>
                        <field>
                            <name>PFERC</name>
                            <description>PFER Clear Bit</description>
                            <lsb>0</lsb>
                            <msb>0</msb>
                            <access>write-only</access>
                        </field>
                        <field>
                            <name>SYERC</name>
                            <description>SYER Clear Bit</description>
                            <lsb>1</lsb>
                            <msb>1</msb>
                            <access>write-only</access>
                        </field>
                        <field>
                            <name>SBERC</name>
                            <description>SBER Clear Bit</description>
                            <lsb>2</lsb>
                            <msb>2</msb>
                            <access>write-only</access>
                        </field>
                        <field>
                            <name>MERC</name>
                            <description>MER Clear Bit</description>
                            <lsb>4</lsb>
                            <msb>4</msb>
                            <access>write-only</access>
                        </field>
                    </fields>
                </register>
                <register>
                    <name>XFCLR</name>
                    <description>Simple LIN Flag Clear Register</description>
                    <addressOffset>0x78</addressOffset>
                    <size>32</size>
                    <access>write-only</access>
                    <resetValue>0x00000000</resetValue>
                    <resetMask>0xffffffff</resetMask>
                    <fields>
                        <field>
                            <name>BFOC</name>
                            <description>BFOF Clear Bit</description>
                            <lsb>8</lsb>
                            <msb>8</msb>
                            <access>write-only</access>
                        </field>
                        <field>
                            <name>BCDC</name>
                            <description>BCDF Clear Bit</description>
                            <lsb>9</lsb>
                            <msb>9</msb>
                            <access>write-only</access>
                        </field>
                        <field>
                            <name>BFDC</name>
                            <description>BFDF Clear Bit</description>
                            <lsb>10</lsb>
                            <msb>10</msb>
                            <access>write-only</access>
                        </field>
                        <field>
                            <name>CF0MC</name>
                            <description>CF0MF Clear Bit</description>
                            <lsb>11</lsb>
                            <msb>11</msb>
                            <access>write-only</access>
                        </field>
                        <field>
                            <name>CF1MC</name>
                            <description>CF1MF Clear Bit</description>
                            <lsb>12</lsb>
                            <msb>12</msb>
                            <access>write-only</access>
                        </field>
                        <field>
                            <name>PIBDC</name>
                            <description>PIBDF Clear Bit</description>
                            <lsb>13</lsb>
                            <msb>13</msb>
                            <access>write-only</access>
                        </field>
                        <field>
                            <name>COFC</name>
                            <description>COFF Clear Bit</description>
                            <lsb>14</lsb>
                            <msb>14</msb>
                            <access>write-only</access>
                        </field>
                        <field>
                            <name>AEDC</name>
                            <description>AEDF Clear Bit</description>
                            <lsb>15</lsb>
                            <msb>15</msb>
                            <access>write-only</access>
                        </field>
                    </fields>
                </register>
            </registers>
        </peripheral>
        <peripheral derivedFrom="SCI0_B_NS">
            <name>SCI1_B_NS</name>
            <description>Serial Communication Interface</description>
            <baseAddress>0x50358100</baseAddress>
        </peripheral>
        <peripheral derivedFrom="SCI0_B_NS">
            <name>SCI2_B_NS</name>
            <description>Serial Communication Interface</description>
            <baseAddress>0x50358200</baseAddress>
        </peripheral>
        <peripheral derivedFrom="SCI0_B_NS">
            <name>SCI3_B_NS</name>
            <description>Serial Communication Interface</description>
            <baseAddress>0x50358300</baseAddress>
        </peripheral>
        <peripheral derivedFrom="SCI0_B_NS">
            <name>SCI4_B_NS</name>
            <description>Serial Communication Interface</description>
            <baseAddress>0x50358400</baseAddress>
        </peripheral>
        <peripheral derivedFrom="SCI0_B_NS">
            <name>SCI9_B_NS</name>
            <description>Serial Communication Interface</description>
            <baseAddress>0x50358900</baseAddress>
        </peripheral>
        <peripheral>
            <name>SPI0_B_NS</name>
            <description>Serial Peripheral Interface 0</description>
            <baseAddress>0x5035C000</baseAddress>
            <addressBlock>
                <offset>0x00</offset>
                <size>52</size>
                <usage>registers</usage>
            </addressBlock>
            <addressBlock>
                <offset>0x40</offset>
                <size>8</size>
                <usage>registers</usage>
            </addressBlock>
            <addressBlock>
                <offset>0x50</offset>
                <size>4</size>
                <usage>registers</usage>
            </addressBlock>
            <addressBlock>
                <offset>0x58</offset>
                <size>12</size>
                <usage>registers</usage>
            </addressBlock>
            <addressBlock>
                <offset>0x68</offset>
                <size>8</size>
                <usage>registers</usage>
            </addressBlock>
            <registers>
                <register>
                    <name>SPDR</name>
                    <description>SPI Data Register</description>
                    <addressOffset>0x00</addressOffset>
                    <size>32</size>
                    <access>read-write</access>
                    <resetValue>0x00000000</resetValue>
                    <resetMask>0xffffffff</resetMask>
                    <fields>
                        <field>
                            <name>SPD</name>
                            <description>These bits are the interface with the buffers that hold data for transmission and reception by the SPI.</description>
                            <lsb>0</lsb>
                            <msb>31</msb>
                            <access>read-write</access>
                        </field>
                    </fields>
                </register>
                <register>
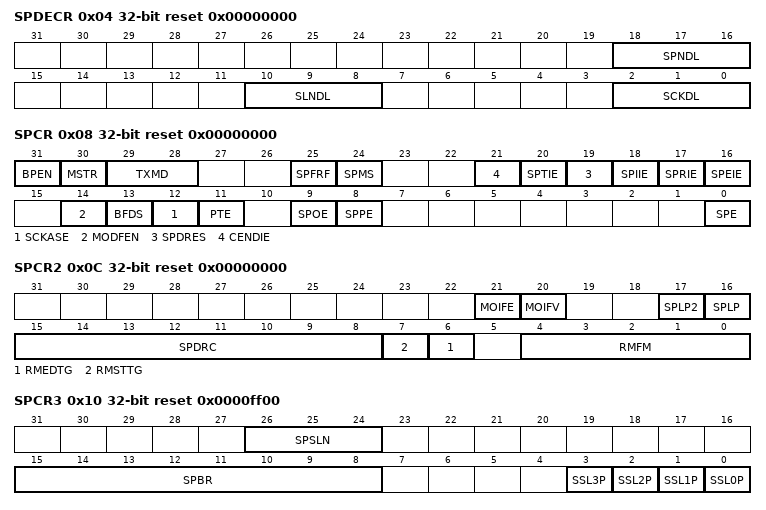
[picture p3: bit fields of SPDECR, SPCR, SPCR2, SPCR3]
                    <name>SPDECR</name>
                    <description>SPI Delay Control Register</description>
                    <addressOffset>0x04</addressOffset>
                    <size>32</size>
                    <access>read-write</access>
                    <resetValue>0x00000000</resetValue>
                    <resetMask>0xffffffff</resetMask>
                    <fields>
                        <field>
                            <name>SCKDL</name>
                            <description>RSPCK Delay</description>
                            <lsb>0</lsb>
                            <msb>2</msb>
                            <access>read-write</access>
                            <enumeratedValues>
                                <enumeratedValue>
                                    <name>000</name>
                                    <description>1RSPCK</description>
                                    <value>#000</value>
                                </enumeratedValue>
                                <enumeratedValue>
                                    <name>001</name>
                                    <description>2RSPCK</description>
                                    <value>#001</value>
                                </enumeratedValue>
                                <enumeratedValue>
                                    <name>010</name>
                                    <description>3RSPCK</description>
                                    <value>#010</value>
                                </enumeratedValue>
                                <enumeratedValue>
                                    <name>011</name>
                                    <description>4RSPCK</description>
                                    <value>#011</value>
                                </enumeratedValue>
                                <enumeratedValue>
                                    <name>100</name>
                                    <description>5RSPCK</description>
                                    <value>#100</value>
                                </enumeratedValue>
                                <enumeratedValue>
                                    <name>101</name>
                                    <description>6RSPCK</description>
                                    <value>#101</value>
                                </enumeratedValue>
                                <enumeratedValue>
                                    <name>110</name>
                                    <description>7RSPCK</description>
                                    <value>#110</value>
                                </enumeratedValue>
                                <enumeratedValue>
                                    <name>111</name>
                                    <description>8RSPCK</description>
                                    <value>#111</value>
                                </enumeratedValue>
                            </enumeratedValues>
                        </field>
                        <field>
                            <name>SLNDL</name>
                            <description>SSL Negation Delay</description>
                            <lsb>8</lsb>
                            <msb>10</msb>
                            <access>read-write</access>
                            <enumeratedValues>
                                <enumeratedValue>
                                    <name>000</name>
                                    <description>1RSPCK</description>
                                    <value>#000</value>
                                </enumeratedValue>
                                <enumeratedValue>
                                    <name>001</name>
                                    <description>2RSPCK</description>
                                    <value>#001</value>
                                </enumeratedValue>
                                <enumeratedValue>
                                    <name>010</name>
                                    <description>3RSPCK</description>
                                    <value>#010</value>
                                </enumeratedValue>
                                <enumeratedValue>
                                    <name>011</name>
                                    <description>4RSPCK</description>
                                    <value>#011</value>
                                </enumeratedValue>
                                <enumeratedValue>
                                    <name>100</name>
                                    <description>5RSPCK</description>
                                    <value>#100</value>
                                </enumeratedValue>
                                <enumeratedValue>
                                    <name>101</name>
                                    <description>6RSPCK</description>
                                    <value>#101</value>
                                </enumeratedValue>
                                <enumeratedValue>
                                    <name>110</name>
                                    <description>7RSPCK</description>
                                    <value>#110</value>
                                </enumeratedValue>
                                <enumeratedValue>
                                    <name>111</name>
                                    <description>8RSPCK</description>
                                    <value>#111</value>
                                </enumeratedValue>
                            </enumeratedValues>
                        </field>
                        <field>
                            <name>SPNDL</name>
                            <description>SPI Next-Access Delay</description>
                            <lsb>16</lsb>
                            <msb>18</msb>
                            <access>read-write</access>
                            <enumeratedValues>
                                <enumeratedValue>
                                    <name>000</name>
                                    <description>1RSPCK + 5TCLK</description>
                                    <value>#000</value>
                                </enumeratedValue>
                                <enumeratedValue>
                                    <name>001</name>
                                    <description>2RSPCK + 5TCLK</description>
                                    <value>#001</value>
                                </enumeratedValue>
                                <enumeratedValue>
                                    <name>010</name>
                                    <description>3RSPCK + 5TCLK</description>
                                    <value>#010</value>
                                </enumeratedValue>
                                <enumeratedValue>
                                    <name>011</name>
                                    <description>4RSPCK + 5TCLK</description>
                                    <value>#011</value>
                                </enumeratedValue>
                                <enumeratedValue>
                                    <name>100</name>
                                    <description>5RSPCK + 5TCLK</description>
                                    <value>#100</value>
                                </enumeratedValue>
                                <enumeratedValue>
                                    <name>101</name>
                                    <description>6RSPCK + 5TCLK</description>
                                    <value>#101</value>
                                </enumeratedValue>
                                <enumeratedValue>
                                    <name>110</name>
                                    <description>7RSPCK + 5TCLK</description>
                                    <value>#110</value>
                                </enumeratedValue>
                                <enumeratedValue>
                                    <name>111</name>
                                    <description>8RSPCK + 5TCLK</description>
                                    <value>#111</value>
                                </enumeratedValue>
                            </enumeratedValues>
                        </field>
                    </fields>
                </register>
                <register>
                    <name>SPCR</name>
                    <description>SPI Control Register</description>
                    <addressOffset>0x08</addressOffset>
                    <size>32</size>
                    <access>read-write</access>
                    <resetValue>0x00000000</resetValue>
                    <resetMask>0xffffffff</resetMask>
                    <fields>
                        <field>
                            <name>SPE</name>
                            <description>SPI Function Enable</description>
                            <lsb>0</lsb>
                            <msb>0</msb>
                            <access>read-write</access>
                            <enumeratedValues>
                                <enumeratedValue>
                                    <name>0</name>
                                    <description>SPI function is disabled.</description>
                                    <value>#0</value>
                                </enumeratedValue>
                                <enumeratedValue>
                                    <name>1</name>
                                    <description>SPI function is enabled.</description>
                                    <value>#1</value>
                                </enumeratedValue>
                            </enumeratedValues>
                        </field>
                        <field>
                            <name>SPPE</name>
                            <description>Parity Enable</description>
                            <lsb>8</lsb>
                            <msb>8</msb>
                            <access>read-write</access>
                            <enumeratedValues>
                                <enumeratedValue>
                                    <name>0</name>
                                    <description>A parity bit is not added to transmit data. Received-data parity check is not performed. </description>
                                    <value>#0</value>
                                </enumeratedValue>
                                <enumeratedValue>
                                    <name>1</name>
                                    <description>A parity bit is added to transmit data. Received-data parity check is performed. </description>
                                    <value>#1</value>
                                </enumeratedValue>
                            </enumeratedValues>
                        </field>
                        <field>
                            <name>SPOE</name>
                            <description>Parity Mode</description>
                            <lsb>9</lsb>
                            <msb>9</msb>
                            <access>read-write</access>
                            <enumeratedValues>
                                <enumeratedValue>
                                    <name>0</name>
                                    <description>Even parity is used for transmission and reception.</description>
                                    <value>#0</value>
                                </enumeratedValue>
                                <enumeratedValue>
                                    <name>1</name>
                                    <description>Odd parity is used for transmission and reception.</description>
                                    <value>#1</value>
                                </enumeratedValue>
                            </enumeratedValues>
                        </field>
                        <field>
                            <name>PTE</name>
                            <description>Parity Self-Diagnosis Enable</description>
                            <lsb>11</lsb>
                            <msb>11</msb>
                            <access>read-write</access>
                            <enumeratedValues>
                                <enumeratedValue>
                                    <name>0</name>
                                    <description>Parity circuit self-diagnosis function is disabled.</description>
                                    <value>#0</value>
                                </enumeratedValue>
                                <enumeratedValue>
                                    <name>1</name>
                                    <description>Parity circuit self-diagnosis function is enabled.</description>
                                    <value>#1</value>
                                </enumeratedValue>
                            </enumeratedValues>
                        </field>
                        <field>
                            <name>SCKASE</name>
                            <description>RSPCK Auto-Stop Function Enable</description>
                            <lsb>12</lsb>
                            <msb>12</msb>
                            <access>read-write</access>
                            <enumeratedValues>
                                <enumeratedValue>
                                    <name>0</name>
                                    <description>RSPCK auto-stop function is disabled.</description>
                                    <value>#0</value>
                                </enumeratedValue>
                                <enumeratedValue>
                                    <name>1</name>
                                    <description>RSPCK auto-stop function is enabled.</description>
                                    <value>#1</value>
                                </enumeratedValue>
                            </enumeratedValues>
                        </field>
                        <field>
                            <name>BFDS</name>
                            <description>Between Burst Transfer Frames Delay Select</description>
                            <lsb>13</lsb>
                            <msb>13</msb>
                            <access>read-write</access>
                            <enumeratedValues>
                                <enumeratedValue>
                                    <name>0</name>
                                    <description>Delay (RSPCK delay, SSL negation delay and next-access delay) between frames is inserted in burst transfer</description>
                                    <value>#0</value>
                                </enumeratedValue>
                                <enumeratedValue>
                                    <name>1</name>
                                    <description>Delay between frames is not inserted in burst transfer.</description>
                                    <value>#1</value>
                                </enumeratedValue>
                            </enumeratedValues>
                        </field>
                        <field>
                            <name>MODFEN</name>
                            <description>Mode Fault Error Detection Enable</description>
                            <lsb>14</lsb>
                            <msb>14</msb>
                            <access>read-write</access>
                            <enumeratedValues>
                                <enumeratedValue>
                                    <name>0</name>
                                    <description>Mode fault error detection is disabled.</description>
                                    <value>#0</value>
                                </enumeratedValue>
                                <enumeratedValue>
                                    <name>1</name>
                                    <description>Mode fault error detection is enabled.</description>
                                    <value>#1</value>
                                </enumeratedValue>
                            </enumeratedValues>
                        </field>
                        <field>
                            <name>SPEIE</name>
                            <description>SPI Error Interrupt Enable</description>
                            <lsb>16</lsb>
                            <msb>16</msb>
                            <access>read-write</access>
                            <enumeratedValues>
                                <enumeratedValue>
                                    <name>0</name>
                                    <description>SPI error interrupt request is disabled.</description>
                                    <value>#0</value>
                                </enumeratedValue>
                                <enumeratedValue>
                                    <name>1</name>
                                    <description>SPI error interrupt request is enabled.</description>
                                    <value>#1</value>
                                </enumeratedValue>
                            </enumeratedValues>
                        </field>
                        <field>
                            <name>SPRIE</name>
                            <description>SPI Receive Buffer Full Interrupt Enable</description>
                            <lsb>17</lsb>
                            <msb>17</msb>
                            <access>read-write</access>
                            <enumeratedValues>
                                <enumeratedValue>
                                    <name>0</name>
                                    <description>SPI receive buffer full interrupt request is disabled.</description>
                                    <value>#0</value>
                                </enumeratedValue>
                                <enumeratedValue>
                                    <name>1</name>
                                    <description>SPI receive buffer full interrupt request is enabled.</description>
                                    <value>#1</value>
                                </enumeratedValue>
                            </enumeratedValues>
                        </field>
                        <field>
                            <name>SPIIE</name>
                            <description>SPI Idle Interrupt Enable</description>
                            <lsb>18</lsb>
                            <msb>18</msb>
                            <access>read-write</access>
                            <enumeratedValues>
                                <enumeratedValue>
                                    <name>0</name>
                                    <description>Idle interrupt request is disabled.</description>
                                    <value>#0</value>
                                </enumeratedValue>
                                <enumeratedValue>
                                    <name>1</name>
                                    <description>Idle interrupt request is enabled.</description>
                                    <value>#1</value>
                                </enumeratedValue>
                            </enumeratedValues>
                        </field>
                        <field>
                            <name>SPDRES</name>
                            <description>SPI receive data ready error select</description>
                            <lsb>19</lsb>
                            <msb>19</msb>
                            <access>read-write</access>
                            <enumeratedValues>
                                <enumeratedValue>
                                    <name>0</name>
                                    <description>Receive data full interrupt</description>
                                    <value>#0</value>
                                </enumeratedValue>
                                <enumeratedValue>
                                    <name>1</name>
                                    <description>Error interrupt</description>
                                    <value>#1</value>
                                </enumeratedValue>
                            </enumeratedValues>
                        </field>
                        <field>
                            <name>SPTIE</name>
                            <description>SPI Transmit Buffer Empty Interrupt Enable</description>
                            <lsb>20</lsb>
                            <msb>20</msb>
                            <access>read-write</access>
                            <enumeratedValues>
                                <enumeratedValue>
                                    <name>0</name>
                                    <description>SPI transmit buffer empty interrupt request is disabled.</description>
                                    <value>#0</value>
                                </enumeratedValue>
                                <enumeratedValue>
                                    <name>1</name>
                                    <description>SPI transmit buffer empty interrupt request is enabled.</description>
                                    <value>#1</value>
                                </enumeratedValue>
                            </enumeratedValues>
                        </field>
                        <field>
                            <name>CENDIE</name>
                            <description>SPI Communication End Interrupt Enable</description>
                            <lsb>21</lsb>
                            <msb>21</msb>
                            <access>read-write</access>
                            <enumeratedValues>
                                <enumeratedValue>
                                    <name>0</name>
                                    <description>Communication end interrupt request is disabled.</description>
                                    <value>#0</value>
                                </enumeratedValue>
                                <enumeratedValue>
                                    <name>1</name>
                                    <description>Communication end interrupt request is enabled.</description>
                                    <value>#1</value>
                                </enumeratedValue>
                            </enumeratedValues>
                        </field>
                        <field>
                            <name>SPMS</name>
                            <description>SPI Mode Select</description>
                            <lsb>24</lsb>
                            <msb>24</msb>
                            <access>read-write</access>
                            <enumeratedValues>
                                <enumeratedValue>
                                    <name>0</name>
                                    <description>SPI operation (4-wire)</description>
                                    <value>#0</value>
                                </enumeratedValue>
                                <enumeratedValue>
                                    <name>1</name>
                                    <description>Clock synchronous operation (3-wire)</description>
                                    <value>#1</value>
                                </enumeratedValue>
                            </enumeratedValues>
                        </field>
                        <field>
                            <name>SPFRF</name>
                            <description>SPI Frame Format Select</description>
                            <lsb>25</lsb>
                            <msb>25</msb>
                            <access>read-write</access>
                            <enumeratedValues>
                                <enumeratedValue>
                                    <name>0</name>
                                    <description>Motorola-SPI</description>
                                    <value>#0</value>
                                </enumeratedValue>
                                <enumeratedValue>
                                    <name>1</name>
                                    <description>TI-SSP</description>
                                    <value>#1</value>
                                </enumeratedValue>
                            </enumeratedValues>
                        </field>
                        <field>
                            <name>TXMD</name>
                            <description>Communication Mode Select</description>
                            <lsb>28</lsb>
                            <msb>29</msb>
                            <access>read-write</access>
                            <enumeratedValues>
                                <enumeratedValue>
                                    <name>00</name>
                                    <description>Transmit-Receive</description>
                                    <value>#00</value>
                                </enumeratedValue>
                                <enumeratedValue>
                                    <name>01</name>
                                    <description>Transmit only</description>
                                    <value>#01</value>
                                </enumeratedValue>
                                <enumeratedValue>
                                    <name>Others</name>
                                    <description>Receive only</description>
                                    <isDefault>true</isDefault>
                                </enumeratedValue>
                            </enumeratedValues>
                        </field>
                        <field>
                            <name>MSTR</name>
                            <description>SPI Master/Slave Mode Select</description>
                            <lsb>30</lsb>
                            <msb>30</msb>
                            <access>read-write</access>
                            <enumeratedValues>
                                <enumeratedValue>
                                    <name>0</name>
                                    <description>Slave mode</description>
                                    <value>#0</value>
                                </enumeratedValue>
                                <enumeratedValue>
                                    <name>1</name>
                                    <description>Master mode</description>
                                    <value>#1</value>
                                </enumeratedValue>
                            </enumeratedValues>
                        </field>
                        <field>
                            <name>BPEN</name>
                            <description>Synchronization Circuit Bypass Enable</description>
                            <lsb>31</lsb>
                            <msb>31</msb>
                            <access>read-write</access>
                            <enumeratedValues>
                                <enumeratedValue>
                                    <name>0</name>
                                    <description>Non-Bypass</description>
                                    <value>#0</value>
                                </enumeratedValue>
                                <enumeratedValue>
                                    <name>1</name>
                                    <description>Bypass</description>
                                    <value>#1</value>
                                </enumeratedValue>
                            </enumeratedValues>
                        </field>
                    </fields>
                </register>
                <register>
                    <name>SPCR2</name>
                    <description>SPI Control Register 2</description>
                    <addressOffset>0x0C</addressOffset>
                    <size>32</size>
                    <access>read-write</access>
                    <resetValue>0x00000000</resetValue>
                    <resetMask>0xffffffff</resetMask>
                    <fields>
                        <field>
                            <name>RMFM</name>
                            <description>Frame processing count setting in Master Receive only</description>
                            <lsb>0</lsb>
                            <msb>4</msb>
                            <access>read-write</access>
                        </field>
                        <field>
                            <name>RMEDTG</name>
                            <description>End Trigger in Master Receive only</description>
                            <lsb>6</lsb>
                            <msb>6</msb>
                            <access>write-only</access>
                            <enumeratedValues>
                                <enumeratedValue>
                                    <name>1</name>
                                    <description>Receive End (Writable only when Master Receive only) Reading value is always 0 </description>
                                    <value>#1</value>
                                </enumeratedValue>
                            </enumeratedValues>
                        </field>
                        <field>
                            <name>RMSTTG</name>
                            <description>Start Trigger in Master Receive only</description>
                            <lsb>7</lsb>
                            <msb>7</msb>
                            <access>write-only</access>
                            <enumeratedValues>
                                <enumeratedValue>
                                    <name>1</name>
                                    <description>Receive Start (Writable only when Master Receive only)  Reading value is always 0</description>
                                    <value>#1</value>
                                </enumeratedValue>
                            </enumeratedValues>
                        </field>
                        <field>
                            <name>SPDRC</name>
                            <description>SPI received data ready detect adjustment</description>
                            <lsb>8</lsb>
                            <msb>15</msb>
                            <access>read-write</access>
                        </field>
                        <field>
                            <name>SPLP</name>
                            <description>SPI Loopback</description>
                            <lsb>16</lsb>
                            <msb>16</msb>
                            <access>read-write</access>
                            <enumeratedValues>
                                <enumeratedValue>
                                    <name>0</name>
                                    <description>Normal mode</description>
                                    <value>#0</value>
                                </enumeratedValue>
                                <enumeratedValue>
                                    <name>1</name>
                                    <description>Loopback mode (inverted transmit data = receive data)</description>
                                    <value>#1</value>
                                </enumeratedValue>
                            </enumeratedValues>
                        </field>
                        <field>
                            <name>SPLP2</name>
                            <description>SPI Loopback 2</description>
                            <lsb>17</lsb>
                            <msb>17</msb>
                            <access>read-write</access>
                            <enumeratedValues>
                                <enumeratedValue>
                                    <name>0</name>
                                    <description>Normal mode</description>
                                    <value>#0</value>
                                </enumeratedValue>
                                <enumeratedValue>
                                    <name>1</name>
                                    <description>Loopback mode (transmit data = receive data)</description>
                                    <value>#1</value>
                                </enumeratedValue>
                            </enumeratedValues>
                        </field>
                        <field>
                            <name>MOIFV</name>
                            <description>MOSI Idle Fixed Value</description>
                            <lsb>20</lsb>
                            <msb>20</msb>
                            <access>read-write</access>
                            <enumeratedValues>
                                <enumeratedValue>
                                    <name>0</name>
                                    <description>The fixed value of MOSI idle = 0.</description>
                                    <value>#0</value>
                                </enumeratedValue>
                                <enumeratedValue>
                                    <name>1</name>
                                    <description>The fixed value of MOSI idle = 1.</description>
                                    <value>#1</value>
                                </enumeratedValue>
                            </enumeratedValues>
                        </field>
                        <field>
                            <name>MOIFE</name>
                            <description>MOSI Idle Fixed Value Enable</description>
                            <lsb>21</lsb>
                            <msb>21</msb>
                            <access>read-write</access>
                            <enumeratedValues>
                                <enumeratedValue>
                                    <name>0</name>
                                    <description>The MOSI output value is the last data of previous transfer.</description>
                                    <value>#0</value>
                                </enumeratedValue>
                                <enumeratedValue>
                                    <name>1</name>
                                    <description>The MOSI output value is the set MOIFV bit value.</description>
                                    <value>#1</value>
                                </enumeratedValue>
                            </enumeratedValues>
                        </field>
                    </fields>
                </register>
                <register>
                    <name>SPCR3</name>
                    <description>SPI Control Register 3</description>
                    <addressOffset>0x10</addressOffset>
                    <size>32</size>
                    <access>read-write</access>
                    <resetValue>0x0000ff00</resetValue>
                    <resetMask>0xffffffff</resetMask>
                    <fields>
                        <field>
                            <name>SSL0P</name>
                            <description>SSL0 Signal Polarity</description>
                            <lsb>0</lsb>
                            <msb>0</msb>
                            <access>read-write</access>
                            <enumeratedValues>
                                <enumeratedValue>
                                    <name>0</name>
                                    <description>The SSL0 signal is active low.</description>
                                    <value>#0</value>
                                </enumeratedValue>
                                <enumeratedValue>
                                    <name>1</name>
                                    <description>The SSL0 signal is active high.</description>
                                    <value>#1</value>
                                </enumeratedValue>
                            </enumeratedValues>
                        </field>
                        <field>
                            <name>SSL1P</name>
                            <description>SSL1 Signal Polarity</description>
                            <lsb>1</lsb>
                            <msb>1</msb>
                            <access>read-write</access>
                            <enumeratedValues>
                                <enumeratedValue>
                                    <name>0</name>
                                    <description>The SSL1 signal is active low.</description>
                                    <value>#0</value>
                                </enumeratedValue>
                                <enumeratedValue>
                                    <name>1</name>
                                    <description>The SSL1 signal is active high.</description>
                                    <value>#1</value>
                                </enumeratedValue>
                            </enumeratedValues>
                        </field>
                        <field>
                            <name>SSL2P</name>
                            <description>SSL2 Signal Polarity</description>
                            <lsb>2</lsb>
                            <msb>2</msb>
                            <access>read-write</access>
                            <enumeratedValues>
                                <enumeratedValue>
                                    <name>0</name>
                                    <description>The SSL2 signal is active low.</description>
                                    <value>#0</value>
                                </enumeratedValue>
                                <enumeratedValue>
                                    <name>1</name>
                                    <description>The SSL2 signal is active high.</description>
                                    <value>#1</value>
                                </enumeratedValue>
                            </enumeratedValues>
                        </field>
                        <field>
                            <name>SSL3P</name>
                            <description>SSL3 Signal Polarity</description>
                            <lsb>3</lsb>
                            <msb>3</msb>
                            <access>read-write</access>
                            <enumeratedValues>
                                <enumeratedValue>
                                    <name>0</name>
                                    <description>The SSL3 signal is active low.</description>
                                    <value>#0</value>
                                </enumeratedValue>
                                <enumeratedValue>
                                    <name>1</name>
                                    <description>The SSL3 signal is active high.</description>
                                    <value>#1</value>
                                </enumeratedValue>
                            </enumeratedValues>
                        </field>
                        <field>
                            <name>SPBR</name>
                            <description>SPI Bit Rate</description>
                            <lsb>8</lsb>
                            <msb>15</msb>
                            <access>read-write</access>
                        </field>
                        <field>
                            <name>SPSLN</name>
                            <description>SPI Sequence Length</description>
                            <lsb>24</lsb>
                            <msb>26</msb>
                            <access>read-write</access>
                            <enumeratedValues>
                                <enumeratedValue>
                                    <name>000</name>
                                    <description>Sequence Length is 1 (Referenced SPCMDn, n = 0→0→…)</description>
                                    <value>#000</value>
                                </enumeratedValue>
                                <enumeratedValue>
                                    <name>001</name>
                                    <description>Sequence Length is 2 (Referenced SPCMDn, n = 0→1→0→…)</description>
                                    <value>#001</value>
                                </enumeratedValue>
                                <enumeratedValue>
                                    <name>010</name>
                                    <description>Sequence Length is 3 (Referenced SPCMDn, n = 0→1→2→0→…)</description>
                                    <value>#010</value>
                                </enumeratedValue>
                                <enumeratedValue>
                                    <name>011</name>
                                    <description>Sequence Length is 4 (Referenced SPCMDn, n = 0→1→2→3→0→…)</description>
                                    <value>#011</value>
                                </enumeratedValue>
                                <enumeratedValue>
                                    <name>100</name>
                                    <description>Sequence Length is 5 (Referenced SPCMDn, n = 0→1→2→3→4→0→…)</description>
                                    <value>#100</value>
                                </enumeratedValue>
                                <enumeratedValue>
                                    <name>101</name>
                                    <description>Sequence Length is 6 (Referenced SPCMDn, n = 0→1→2→3→4→5→0→…)</description>
                                    <value>#101</value>
                                </enumeratedValue>
                                <enumeratedValue>
                                    <name>110</name>
                                    <description>Sequence Length is 7 (Referenced SPCMDn, n = 0→1→2→3→4→5→6→0→…)</description>
                                    <value>#110</value>
                                </enumeratedValue>
                                <enumeratedValue>
                                    <name>111</name>
                                    <description>Sequence Length is 8 (Referenced SPCMDn, n = 0→1→2→3→4→5→6→7→0→…)</description>
                                    <value>#111</value>
                                </enumeratedValue>
                            </enumeratedValues>
                        </field>
                    </fields>
                </register>
                <register>
                    <dim>8</dim>
                    <dimIncrement>0x04</dimIncrement>
                    <dimIndex>0-7</dimIndex>
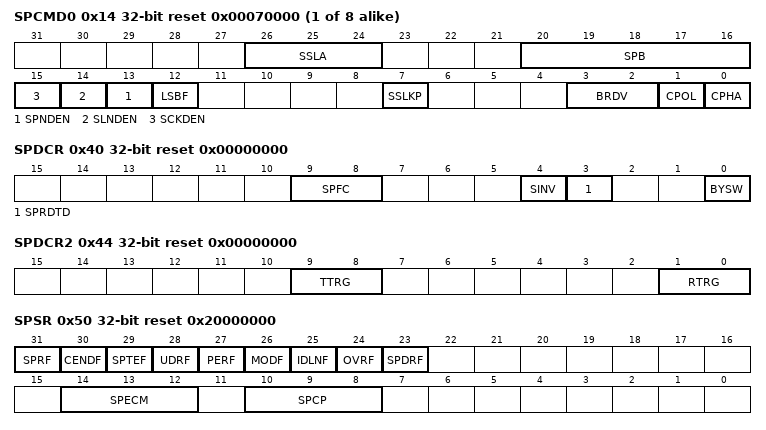
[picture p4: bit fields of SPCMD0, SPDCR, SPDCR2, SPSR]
                    <name>SPCMD%s</name>
                    <description>SPI Command Register</description>
                    <addressOffset>0x14</addressOffset>
                    <size>32</size>
                    <access>read-write</access>
                    <resetValue>0x00070000</resetValue>
                    <resetMask>0xffffffff</resetMask>
                    <fields>
                        <field>
                            <name>CPHA</name>
                            <description>RSPCK Phase</description>
                            <lsb>0</lsb>
                            <msb>0</msb>
                            <access>read-write</access>
                            <enumeratedValues>
                                <enumeratedValue>
                                    <name>0</name>
                                    <description>Data is sampled at an odd edge and changes at an even edge.</description>
                                    <value>#0</value>
                                </enumeratedValue>
                                <enumeratedValue>
                                    <name>1</name>
                                    <description>Data changes at an odd edge and is sampled at an even edge.</description>
                                    <value>#1</value>
                                </enumeratedValue>
                            </enumeratedValues>
                        </field>
                        <field>
                            <name>CPOL</name>
                            <description>RSPCK Polarity</description>
                            <lsb>1</lsb>
                            <msb>1</msb>
                            <access>read-write</access>
                            <enumeratedValues>
                                <enumeratedValue>
                                    <name>0</name>
                                    <description>RSPCK in idle state is 0.</description>
                                    <value>#0</value>
                                </enumeratedValue>
                                <enumeratedValue>
                                    <name>1</name>
                                    <description>RSPCK in idle state is 1.</description>
                                    <value>#1</value>
                                </enumeratedValue>
                            </enumeratedValues>
                        </field>
                        <field>
                            <name>BRDV</name>
                            <description>Bit Rate Division</description>
                            <lsb>2</lsb>
                            <msb>3</msb>
                            <access>read-write</access>
                            <enumeratedValues>
                                <enumeratedValue>
                                    <name>00</name>
                                    <description>Base bit rate</description>
                                    <value>#00</value>
                                </enumeratedValue>
                                <enumeratedValue>
                                    <name>01</name>
                                    <description>Base bit rate divided by 2</description>
                                    <value>#01</value>
                                </enumeratedValue>
                                <enumeratedValue>
                                    <name>10</name>
                                    <description>Base bit rate divided by 4</description>
                                    <value>#10</value>
                                </enumeratedValue>
                                <enumeratedValue>
                                    <name>11</name>
                                    <description>Base bit rate divided by 8</description>
                                    <value>#11</value>
                                </enumeratedValue>
                            </enumeratedValues>
                        </field>
                        <field>
                            <name>SSLKP</name>
                            <description>SSL Signal Level Hold</description>
                            <lsb>7</lsb>
                            <msb>7</msb>
                            <access>read-write</access>
                            <enumeratedValues>
                                <enumeratedValue>
                                    <name>0</name>
                                    <description>All SSL signals are negated at the end of transfer.</description>
                                    <value>#0</value>
                                </enumeratedValue>
                                <enumeratedValue>
                                    <name>1</name>
                                    <description>SSL signal level is held after the transfer ends until the next access starts.</description>
                                    <value>#1</value>
                                </enumeratedValue>
                            </enumeratedValues>
                        </field>
                        <field>
                            <name>LSBF</name>
                            <description>SPI LSB First</description>
                            <lsb>12</lsb>
                            <msb>12</msb>
                            <access>read-write</access>
                            <enumeratedValues>
                                <enumeratedValue>
                                    <name>0</name>
                                    <description>MSB first</description>
                                    <value>#0</value>
                                </enumeratedValue>
                                <enumeratedValue>
                                    <name>1</name>
                                    <description>LSB first</description>
                                    <value>#1</value>
                                </enumeratedValue>
                            </enumeratedValues>
                        </field>
                        <field>
                            <name>SPNDEN</name>
                            <description>SPI Next-Access Delay Enable</description>
                            <lsb>13</lsb>
                            <msb>13</msb>
                            <access>read-write</access>
                            <enumeratedValues>
                                <enumeratedValue>
                                    <name>0</name>
                                    <description>Next-access delay is 1RSPCK + 5TCLK</description>
                                    <value>#0</value>
                                </enumeratedValue>
                                <enumeratedValue>
                                    <name>1</name>
                                    <description>Next-access delay is the set value of the SPI next-access delay (SPDECR.SPNDL).</description>
                                    <value>#1</value>
                                </enumeratedValue>
                            </enumeratedValues>
                        </field>
                        <field>
                            <name>SLNDEN</name>
                            <description>SSL Negation Delay Setting Enable</description>
                            <lsb>14</lsb>
                            <msb>14</msb>
                            <access>read-write</access>
                            <enumeratedValues>
                                <enumeratedValue>
                                    <name>0</name>
                                    <description>[Master] SSL negation delay is 1RSPCK. [Slave in the TI-SSP] SSL negation delay is 1TCLK </description>
                                    <value>#0</value>
                                </enumeratedValue>
                                <enumeratedValue>
                                    <name>1</name>
                                    <description>SSL negation delay is the set value of the slave select negation delay (SPDECR.SLNDL).</description>
                                    <value>#1</value>
                                </enumeratedValue>
                            </enumeratedValues>
                        </field>
                        <field>
                            <name>SCKDEN</name>
                            <description>RSPCK Delay Setting Enable</description>
                            <lsb>15</lsb>
                            <msb>15</msb>
                            <access>read-write</access>
                            <enumeratedValues>
                                <enumeratedValue>
                                    <name>0</name>
                                    <description>RSPCK delay is 1 RSPCK.</description>
                                    <value>#0</value>
                                </enumeratedValue>
                                <enumeratedValue>
                                    <name>1</name>
                                    <description>RSPCK delay is the set value of the RSPCK delay (SPDECR.SCKDL).</description>
                                    <value>#1</value>
                                </enumeratedValue>
                            </enumeratedValues>
                        </field>
                        <field>
                            <name>SPB</name>
                            <description>SPI Data Length</description>
                            <lsb>16</lsb>
                            <msb>20</msb>
                            <access>read-write</access>
                        </field>
                        <field>
                            <name>SSLA</name>
                            <description>SSL Signal Assertion</description>
                            <lsb>24</lsb>
                            <msb>26</msb>
                            <access>read-write</access>
                            <enumeratedValues>
                                <enumeratedValue>
                                    <name>000</name>
                                    <description>SSL0</description>
                                    <value>#000</value>
                                </enumeratedValue>
                                <enumeratedValue>
                                    <name>001</name>
                                    <description>SSL1</description>
                                    <value>#001</value>
                                </enumeratedValue>
                                <enumeratedValue>
                                    <name>010</name>
                                    <description>SSL2</description>
                                    <value>#010</value>
                                </enumeratedValue>
                                <enumeratedValue>
                                    <name>011</name>
                                    <description>SSL3</description>
                                    <value>#011</value>
                                </enumeratedValue>
                                <enumeratedValue>
                                    <name>Others</name>
                                    <description>Setting prohibited</description>
                                    <isDefault>true</isDefault>
                                </enumeratedValue>
                            </enumeratedValues>
                        </field>
                    </fields>
                </register>
                <register>
                    <name>SPDCR</name>
                    <description>SPI Data Control Register</description>
                    <addressOffset>0x40</addressOffset>
                    <size>32</size>
                    <access>read-write</access>
                    <resetValue>0x00000000</resetValue>
                    <resetMask>0xffffffff</resetMask>
                    <fields>
                        <field>
                            <name>BYSW</name>
                            <description>Byte Swap Operating Mode Select</description>
                            <lsb>0</lsb>
                            <msb>0</msb>
                            <access>read-write</access>
                            <enumeratedValues>
                                <enumeratedValue>
                                    <name>0</name>
                                    <description>Byte Swap OFF</description>
                                    <value>#0</value>
                                </enumeratedValue>
                                <enumeratedValue>
                                    <name>1</name>
                                    <description>Byte Swap ON</description>
                                    <value>#1</value>
                                </enumeratedValue>
                            </enumeratedValues>
                        </field>
                        <field>
                            <name>SPRDTD</name>
                            <description>SPI Receive Data or Transmit Data Select</description>
                            <lsb>3</lsb>
                            <msb>3</msb>
                            <access>read-write</access>
                            <enumeratedValues>
                                <enumeratedValue>
                                    <name>0</name>
                                    <description>The SPDR reads the receive buffer.</description>
                                    <value>#0</value>
                                </enumeratedValue>
                                <enumeratedValue>
                                    <name>1</name>
                                    <description>The SPDR reads the transmit buffer</description>
                                    <value>#1</value>
                                </enumeratedValue>
                            </enumeratedValues>
                        </field>
                        <field>
                            <name>SINV</name>
                            <description>Serial data invert bit</description>
                            <lsb>4</lsb>
                            <msb>4</msb>
                            <access>read-write</access>
                            <enumeratedValues>
                                <enumeratedValue>
                                    <name>0</name>
                                    <description>Not invert serial data</description>
                                    <value>#0</value>
                                </enumeratedValue>
                                <enumeratedValue>
                                    <name>1</name>
                                    <description>Invert serial data.</description>
                                    <value>#1</value>
                                </enumeratedValue>
                            </enumeratedValues>
                        </field>
                        <field>
                            <name>SPFC</name>
                            <description>Frame Count</description>
                            <lsb>8</lsb>
                            <msb>9</msb>
                            <access>read-write</access>
                            <enumeratedValues>
                                <enumeratedValue>
                                    <name>00</name>
                                    <description>1 frame</description>
                                    <value>#00</value>
                                </enumeratedValue>
                                <enumeratedValue>
                                    <name>01</name>
                                    <description>2 frames</description>
                                    <value>#01</value>
                                </enumeratedValue>
                                <enumeratedValue>
                                    <name>10</name>
                                    <description>3 frames</description>
                                    <value>#10</value>
                                </enumeratedValue>
                                <enumeratedValue>
                                    <name>11</name>
                                    <description>4 frames</description>
                                    <value>#11</value>
                                </enumeratedValue>
                            </enumeratedValues>
                        </field>
                    </fields>
                </register>
                <register>
                    <name>SPDCR2</name>
                    <description>SPI Data Control Register 2</description>
                    <addressOffset>0x44</addressOffset>
                    <size>32</size>
                    <access>read-write</access>
                    <resetValue>0x00000000</resetValue>
                    <resetMask>0xffffffff</resetMask>
                    <fields>
                        <field>
                            <name>RTRG</name>
                            <description>Receive FIFO threshold setting</description>
                            <lsb>0</lsb>
                            <msb>1</msb>
                            <access>read-write</access>
                            <enumeratedValues>
                                <enumeratedValue>
                                    <name>00</name>
                                    <description>threshold 0</description>
                                    <value>#00</value>
                                </enumeratedValue>
                                <enumeratedValue>
                                    <name>01</name>
                                    <description>threshold 1</description>
                                    <value>#01</value>
                                </enumeratedValue>
                                <enumeratedValue>
                                    <name>10</name>
                                    <description>threshold 2</description>
                                    <value>#10</value>
                                </enumeratedValue>
                                <enumeratedValue>
                                    <name>11</name>
                                    <description>threshold 3</description>
                                    <value>#11</value>
                                </enumeratedValue>
                            </enumeratedValues>
                        </field>
                        <field>
                            <name>TTRG</name>
                            <description>Transmission FIFO threshold setting</description>
                            <lsb>8</lsb>
                            <msb>9</msb>
                            <access>read-write</access>
                            <enumeratedValues>
                                <enumeratedValue>
                                    <name>00</name>
                                    <description>threshold 0</description>
                                    <value>#00</value>
                                </enumeratedValue>
                                <enumeratedValue>
                                    <name>01</name>
                                    <description>threshold 1</description>
                                    <value>#01</value>
                                </enumeratedValue>
                                <enumeratedValue>
                                    <name>10</name>
                                    <description>threshold 2</description>
                                    <value>#10</value>
                                </enumeratedValue>
                                <enumeratedValue>
                                    <name>11</name>
                                    <description>threshold 3</description>
                                    <value>#11</value>
                                </enumeratedValue>
                            </enumeratedValues>
                        </field>
                    </fields>
                </register>
                <register>
                    <name>SPSR</name>
                    <description>SPI Status Register</description>
                    <addressOffset>0x50</addressOffset>
                    <size>32</size>
                    <access>read-only</access>
                    <resetValue>0x20000000</resetValue>
                    <resetMask>0xffffffff</resetMask>
                    <fields>
                        <field>
                            <name>SPCP</name>
                            <description>SPI Command Pointer</description>
                            <lsb>8</lsb>
                            <msb>10</msb>
                            <access>read-only</access>
                            <enumeratedValues>
                                <enumeratedValue>
                                    <name>000</name>
                                    <description>SPCMD0</description>
                                    <value>#000</value>
                                </enumeratedValue>
                                <enumeratedValue>
                                    <name>001</name>
                                    <description>SPCMD1</description>
                                    <value>#001</value>
                                </enumeratedValue>
                                <enumeratedValue>
                                    <name>010</name>
                                    <description>SPCMD2</description>
                                    <value>#010</value>
                                </enumeratedValue>
                                <enumeratedValue>
                                    <name>011</name>
                                    <description>SPCMD3</description>
                                    <value>#011</value>
                                </enumeratedValue>
                                <enumeratedValue>
                                    <name>100</name>
                                    <description>SPCMD4</description>
                                    <value>#100</value>
                                </enumeratedValue>
                                <enumeratedValue>
                                    <name>101</name>
                                    <description>SPCMD5</description>
                                    <value>#101</value>
                                </enumeratedValue>
                                <enumeratedValue>
                                    <name>110</name>
                                    <description>SPCMD6</description>
                                    <value>#110</value>
                                </enumeratedValue>
                                <enumeratedValue>
                                    <name>111</name>
                                    <description>SPCMD7</description>
                                    <value>#111</value>
                                </enumeratedValue>
                            </enumeratedValues>
                        </field>
                        <field>
                            <name>SPECM</name>
                            <description>SPI Error Command</description>
                            <lsb>12</lsb>
                            <msb>14</msb>
                            <access>read-only</access>
                            <enumeratedValues>
                                <enumeratedValue>
                                    <name>000</name>
                                    <description>SPCMD0</description>
                                    <value>#000</value>
                                </enumeratedValue>
                                <enumeratedValue>
                                    <name>001</name>
                                    <description>SPCMD1</description>
                                    <value>#001</value>
                                </enumeratedValue>
                                <enumeratedValue>
                                    <name>010</name>
                                    <description>SPCMD2</description>
                                    <value>#010</value>
                                </enumeratedValue>
                                <enumeratedValue>
                                    <name>011</name>
                                    <description>SPCMD3</description>
                                    <value>#011</value>
                                </enumeratedValue>
                                <enumeratedValue>
                                    <name>100</name>
                                    <description>SPCMD4</description>
                                    <value>#100</value>
                                </enumeratedValue>
                                <enumeratedValue>
                                    <name>101</name>
                                    <description>SPCMD5</description>
                                    <value>#101</value>
                                </enumeratedValue>
                                <enumeratedValue>
                                    <name>110</name>
                                    <description>SPCMD6</description>
                                    <value>#110</value>
                                </enumeratedValue>
                                <enumeratedValue>
                                    <name>111</name>
                                    <description>SPCMD7</description>
                                    <value>#111</value>
                                </enumeratedValue>
                            </enumeratedValues>
                        </field>
                        <field>
                            <name>SPDRF</name>
                            <description>SPI Receive Data Ready Flag</description>
                            <lsb>23</lsb>
                            <msb>23</msb>
                            <access>read-only</access>
                            <enumeratedValues>
                                <enumeratedValue>
                                    <name>0</name>
                                    <description>Receive data ready not detected</description>
                                    <value>#0</value>
                                </enumeratedValue>
                                <enumeratedValue>
                                    <name>1</name>
                                    <description>Receive data ready detected</description>
                                    <value>#1</value>
                                </enumeratedValue>
                            </enumeratedValues>
                        </field>
                        <field>
                            <name>OVRF</name>
                            <description>Overrun Error Flag</description>
                            <lsb>24</lsb>
                            <msb>24</msb>
                            <access>read-only</access>
                            <enumeratedValues>
                                <enumeratedValue>
                                    <name>0</name>
                                    <description>No overrun error is present.</description>
                                    <value>#0</value>
                                </enumeratedValue>
                                <enumeratedValue>
                                    <name>1</name>
                                    <description>An overrun error is present.</description>
                                    <value>#1</value>
                                </enumeratedValue>
                            </enumeratedValues>
                        </field>
                        <field>
                            <name>IDLNF</name>
                            <description>SPI Idle Flag</description>
                            <lsb>25</lsb>
                            <msb>25</msb>
                            <access>read-only</access>
                            <enumeratedValues>
                                <enumeratedValue>
                                    <name>0</name>
                                    <description>The SPI is in the idle state.</description>
                                    <value>#0</value>
                                </enumeratedValue>
                                <enumeratedValue>
                                    <name>1</name>
                                    <description>The SPI is in the transfer state.</description>
                                    <value>#1</value>
                                </enumeratedValue>
                            </enumeratedValues>
                        </field>
                        <field>
                            <name>MODF</name>
                            <description>Mode Fault Error Flag</description>
                            <lsb>26</lsb>
                            <msb>26</msb>
                            <access>read-only</access>
                            <enumeratedValues>
                                <enumeratedValue>
                                    <name>0</name>
                                    <description>Neither mode fault error nor underrun error is present.</description>
                                    <value>#0</value>
                                </enumeratedValue>
                                <enumeratedValue>
                                    <name>1</name>
                                    <description>A mode fault error or underrun error is present.</description>
                                    <value>#1</value>
                                </enumeratedValue>
                            </enumeratedValues>
                        </field>
                        <field>
                            <name>PERF</name>
                            <description>Parity Error Flag</description>
                            <lsb>27</lsb>
                            <msb>27</msb>
                            <access>read-only</access>
                            <enumeratedValues>
                                <enumeratedValue>
                                    <name>0</name>
                                    <description>No parity error is present.</description>
                                    <value>#0</value>
                                </enumeratedValue>
                                <enumeratedValue>
                                    <name>1</name>
                                    <description>A parity error is present.</description>
                                    <value>#1</value>
                                </enumeratedValue>
                            </enumeratedValues>
                        </field>
                        <field>
                            <name>UDRF</name>
                            <description>Underrun Error Flag</description>
                            <lsb>28</lsb>
                            <msb>28</msb>
                            <access>read-only</access>
                            <enumeratedValues>
                                <enumeratedValue>
                                    <name>0</name>
                                    <description>When MODF=0, neither mode fault error nor underrun error is present. When MODF=1, a mode fault error is present. </description>
                                    <value>#0</value>
                                </enumeratedValue>
                                <enumeratedValue>
                                    <name>1</name>
                                    <description>When MODF=0, neither mode fault error nor underrun error is present. When MODF=1, an underrun error is present. </description>
                                    <value>#1</value>
                                </enumeratedValue>
                            </enumeratedValues>
                        </field>
                        <field>
                            <name>SPTEF</name>
                            <description>SPI Transmit Buffer Empty Flag</description>
                            <lsb>29</lsb>
                            <msb>29</msb>
                            <access>read-only</access>
                            <enumeratedValues>
                                <enumeratedValue>
                                    <name>0</name>
                                    <description>The number of empty stages in the transmit FIFO ≤ the value set in SPDCR2.TTRG</description>
                                    <value>#0</value>
                                </enumeratedValue>
                                <enumeratedValue>
                                    <name>1</name>
                                    <description>The number of empty stages in the transmit FIFO &gt; the value set in SPDCR2.TTRG</description>
                                    <value>#1</value>
                                </enumeratedValue>
                            </enumeratedValues>
                        </field>
                        <field>
                            <name>CENDF</name>
                            <description>Communication End Flag</description>
                            <lsb>30</lsb>
                            <msb>30</msb>
                            <access>read-only</access>
                            <enumeratedValues>
                                <enumeratedValue>
                                    <name>0</name>
                                    <description>The SPI is not communicating or communicating.</description>
                                    <value>#0</value>
                                </enumeratedValue>
                                <enumeratedValue>
                                    <name>1</name>
                                    <description>The SPI communication completed.</description>
                                    <value>#1</value>
                                </enumeratedValue>
                            </enumeratedValues>
                        </field>
                        <field>
                            <name>SPRF</name>
                            <description>SPI Receive Buffer Full Flag</description>
                            <lsb>31</lsb>
                            <msb>31</msb>
                            <access>read-only</access>
                            <enumeratedValues>
                                <enumeratedValue>
                                    <name>0</name>
                                    <description>The number of data stored in the receive FIFO ≤ number of frames set by the SPDCR2.RTRG bit.</description>
                                    <value>#0</value>
                                </enumeratedValue>
                                <enumeratedValue>
                                    <name>1</name>
                                    <description>The number of data stored in the receive FIFO &gt; number of frames set by the SPDCR2.RTRG bit.</description>
                                    <value>#1</value>
                                </enumeratedValue>
                            </enumeratedValues>
                        </field>
                    </fields>
                </register>
                <register>
                    <name>SPTFSR</name>
                    <description>SPI Transfer FIFO Status Register</description>
                    <addressOffset>0x58</addressOffset>
                    <size>32</size>
                    <access>read-only</access>
                    <resetValue>0x00000000</resetValue>
                    <resetMask>0xffffffff</resetMask>
                    <fields>
                        <field>
                            <name>TFDN</name>
                            <description>Transmit FIFO data empty stage number</description>
                            <lsb>0</lsb>
                            <msb>2</msb>
                            <access>read-only</access>
                        </field>
                    </fields>
                </register>
                <register>
                    <name>SPRFSR</name>
                    <description>SPI Receive FIFO Status Register</description>
                    <addressOffset>0x5C</addressOffset>
                    <size>32</size>
                    <access>read-only</access>
                    <resetValue>0x00000004</resetValue>
                    <resetMask>0xffffffff</resetMask>
                    <fields>
                        <field>
                            <name>RFDN</name>
                            <description>Receive FIFO data store stage number</description>
                            <lsb>0</lsb>
                            <msb>2</msb>
                            <access>read-only</access>
                        </field>
                    </fields>
                </register>
                <register>
                    <name>SPPSR</name>
                    <description>SPI Polling Register</description>
                    <addressOffset>0x60</addressOffset>
                    <size>32</size>
                    <access>read-only</access>
                    <resetValue>0x00000000</resetValue>
                    <resetMask>0xffffffff</resetMask>
                    <fields>
                        <field>
                            <name>SPEPS</name>
                            <description>SPI Polling Status</description>
                            <lsb>0</lsb>
                            <msb>0</msb>
                            <access>read-only</access>
                            <enumeratedValues>
                                <enumeratedValue>
                                    <name>0</name>
                                    <description>SPCR.SPE is 0</description>
                                    <value>#0</value>
                                </enumeratedValue>
                                <enumeratedValue>
                                    <name>1</name>
                                    <description>SPCR.SPE is 1</description>
                                    <value>#1</value>
                                </enumeratedValue>
                            </enumeratedValues>
                        </field>
                    </fields>
                </register>
                <register>
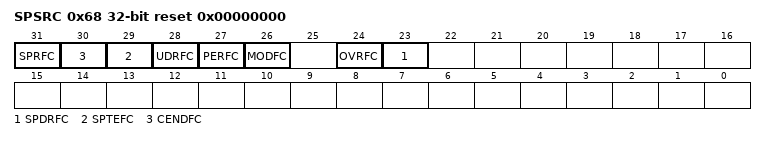
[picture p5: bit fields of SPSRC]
                    <name>SPSRC</name>
                    <description>SPI Status Clear Register</description>
                    <addressOffset>0x68</addressOffset>
                    <size>32</size>
                    <access>write-only</access>
                    <resetValue>0x00000000</resetValue>
                    <resetMask>0xffffffff</resetMask>
                    <fields>
                        <field>
                            <name>SPDRFC</name>
                            <description>SPI Receive Data Ready Flag Clear</description>
                            <lsb>23</lsb>
                            <msb>23</msb>
                            <access>write-only</access>
                        </field>
                        <field>
                            <name>OVRFC</name>
                            <description>Overrun Error Flag Clear</description>
                            <lsb>24</lsb>
                            <msb>24</msb>
                            <access>write-only</access>
                        </field>
                        <field>
                            <name>MODFC</name>
                            <description>Mode Fault Error Flag Clear</description>
                            <lsb>26</lsb>
                            <msb>26</msb>
                            <access>write-only</access>
                        </field>
                        <field>
                            <name>PERFC</name>
                            <description>Parity Error Flag Clear</description>
                            <lsb>27</lsb>
                            <msb>27</msb>
                            <access>write-only</access>
                        </field>
                        <field>
                            <name>UDRFC</name>
                            <description>Underrun Error Flag Clear</description>
                            <lsb>28</lsb>
                            <msb>28</msb>
                            <access>write-only</access>
                        </field>
                        <field>
                            <name>SPTEFC</name>
                            <description>SPI Transmit Buffer Empty Flag Clear</description>
                            <lsb>29</lsb>
                            <msb>29</msb>
                            <access>write-only</access>
                        </field>
                        <field>
                            <name>CENDFC</name>
                            <description>Communication End Flag Clear</description>
                            <lsb>30</lsb>
                            <msb>30</msb>
                            <access>write-only</access>
                        </field>
                        <field>
                            <name>SPRFC</name>
                            <description>SPI Receive Buffer Full Flag Clear</description>
                            <lsb>31</lsb>
                            <msb>31</msb>
                            <access>write-only</access>
                        </field>
                    </fields>
                </register>
                <register>
                    <name>SPFCR</name>
                    <description>SPI FIFO Clear Register</description>
                    <addressOffset>0x6C</addressOffset>
                    <size>32</size>
                    <access>write-only</access>
                    <resetValue>0x00000000</resetValue>
                    <resetMask>0xffffffff</resetMask>
                    <fields>
                        <field>
                            <name>SPFRST</name>
                            <description>SPI FIFO clear</description>
                            <lsb>0</lsb>
                            <msb>0</msb>
                            <access>write-only</access>
                        </field>
                    </fields>
                </register>
            </registers>
        </peripheral>
        <peripheral derivedFrom="SPI0_B_NS">
            <name>SPI1_B_NS</name>
            <description>Serial Peripheral Interface 1</description>
            <baseAddress>0x5035C100</baseAddress>
        </peripheral>
        <peripheral>
            <name>I3C_NS</name>
            <description>I3C Bus Interface</description>
            <baseAddress>0x5035F000</baseAddress>
            <addressBlock>
                <offset>0x00</offset>
                <size>4</size>
                <usage>registers</usage>
            </addressBlock>
            <addressBlock>
                <offset>0x10</offset>
                <size>12</size>
                <usage>registers</usage>
            </addressBlock>
            <addressBlock>
                <offset>0x20</offset>
                <size>8</size>
                <usage>registers</usage>
            </addressBlock>
            <addressBlock>
                <offset>0x30</offset>
                <size>16</size>
                <usage>registers</usage>
            </addressBlock>
            <addressBlock>
                <offset>0x44</offset>
                <size>4</size>
                <usage>registers</usage>
            </addressBlock>
            <addressBlock>
                <offset>0x58</offset>
                <size>4</size>
                <usage>registers</usage>
            </addressBlock>
            <addressBlock>
                <offset>0x60</offset>
                <size>8</size>
                <usage>registers</usage>
            </addressBlock>
            <addressBlock>
                <offset>0x70</offset>
                <size>36</size>
                <usage>registers</usage>
            </addressBlock>
            <addressBlock>
                <offset>0x98</offset>
                <size>4</size>
                <usage>registers</usage>
            </addressBlock>
            <addressBlock>
                <offset>0xA0</offset>
                <size>8</size>
                <usage>registers</usage>
            </addressBlock>
            <addressBlock>
                <offset>0xB0</offset>
                <size>4</size>
                <usage>registers</usage>
            </addressBlock>
            <addressBlock>
                <offset>0xC0</offset>
                <size>4</size>
                <usage>registers</usage>
            </addressBlock>
            <addressBlock>
                <offset>0x120</offset>
                <size>16</size>
                <usage>registers</usage>
            </addressBlock>
            <addressBlock>
                <offset>0x140</offset>
                <size>4</size>
                <usage>registers</usage>
            </addressBlock>
            <addressBlock>
                <offset>0x150</offset>
                <size>12</size>
                <usage>registers</usage>
            </addressBlock>
            <addressBlock>
                <offset>0x17C</offset>
                <size>28</size>
                <usage>registers</usage>
            </addressBlock>
            <addressBlock>
                <offset>0x1C0</offset>
                <size>12</size>
                <usage>registers</usage>
            </addressBlock>
            <addressBlock>
                <offset>0x1D0</offset>
                <size>32</size>
                <usage>registers</usage>
            </addressBlock>
            <addressBlock>
                <offset>0x200</offset>
                <size>32</size>
                <usage>registers</usage>
            </addressBlock>
            <addressBlock>
                <offset>0x224</offset>
                <size>64</size>
                <usage>registers</usage>
            </addressBlock>
            <addressBlock>
                <offset>0x2A0</offset>
                <size>4</size>
                <usage>registers</usage>
            </addressBlock>
            <addressBlock>
                <offset>0x2B0</offset>
                <size>12</size>
                <usage>registers</usage>
            </addressBlock>
            <addressBlock>
                <offset>0x2D0</offset>
                <size>32</size>
                <usage>registers</usage>
            </addressBlock>
            <addressBlock>
                <offset>0x320</offset>
                <size>12</size>
                <usage>registers</usage>
            </addressBlock>
            <addressBlock>
                <offset>0x330</offset>
                <size>12</size>
                <usage>registers</usage>
            </addressBlock>
            <addressBlock>
                <offset>0x350</offset>
                <size>52</size>
                <usage>registers</usage>
            </addressBlock>
            <addressBlock>
                <offset>0x394</offset>
                <size>8</size>
                <usage>registers</usage>
            </addressBlock>
            <addressBlock>
                <offset>0x3C0</offset>
                <size>20</size>
                <usage>registers</usage>
            </addressBlock>
            <addressBlock>
                <offset>0x3E0</offset>
                <size>8</size>
                <usage>registers</usage>
            </addressBlock>
            <registers>
                <register>
                    <name>PRTS</name>
                    <description>Protocol Selection Register</description>
                    <addressOffset>0x000</addressOffset>
                    <size>32</size>
                    <access>read-write</access>
                    <resetValue>0x00000001</resetValue>
                    <resetMask>0xffffffff</resetMask>
                    <fields>
                        <field>
                            <name>PRTMD</name>
                            <description>Protocol Mode</description>
                            <lsb>0</lsb>
                            <msb>0</msb>
                            <access>read-write</access>
                            <enumeratedValues>
                                <enumeratedValue>
                                    <name>0</name>
                                    <description>I3C protocol mode</description>
                                    <value>#0</value>
                                </enumeratedValue>
                                <enumeratedValue>
                                    <name>1</name>
                                    <description>I2C protocol mode</description>
                                    <value>#1</value>
                                </enumeratedValue>
                            </enumeratedValues>
                        </field>
                    </fields>
                </register>
                <register>
                    <name>CECTL</name>
                    <description>Clock Enable Control Register</description>
                    <addressOffset>0x010</addressOffset>
                    <size>32</size>
                    <access>read-write</access>
                    <resetValue>0x00000000</resetValue>
                    <resetMask>0xffffffff</resetMask>
                    <fields>
                        <field>
                            <name>CLKE</name>
                            <description>Clock Enable</description>
                            <lsb>0</lsb>
                            <msb>0</msb>
                            <access>read-write</access>
                            <enumeratedValues>
                                <enumeratedValue>
                                    <name>0</name>
                                    <description>Clock disable</description>
                                    <value>#0</value>
                                </enumeratedValue>
                                <enumeratedValue>
                                    <name>1</name>
                                    <description>Clock enable</description>
                                    <value>#1</value>
                                </enumeratedValue>
                            </enumeratedValues>
                        </field>
                    </fields>
                </register>
                <register>
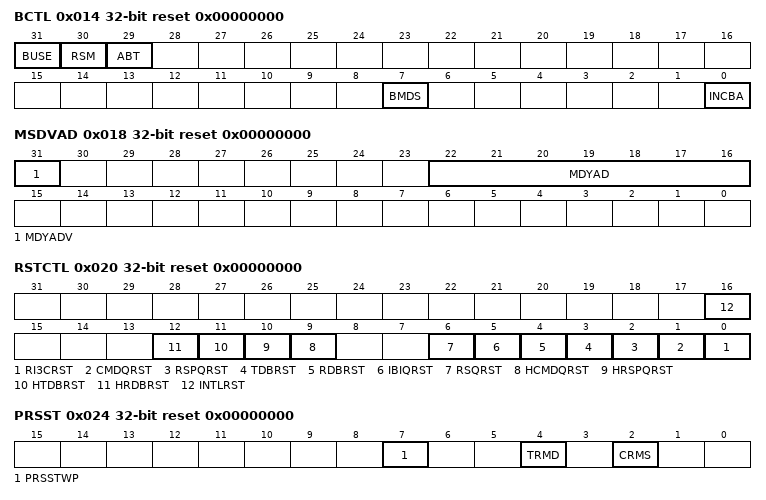
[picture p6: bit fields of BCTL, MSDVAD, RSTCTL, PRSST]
                    <name>BCTL</name>
                    <description>Bus Control Register</description>
                    <addressOffset>0x014</addressOffset>
                    <size>32</size>
                    <access>read-write</access>
                    <resetValue>0x00000000</resetValue>
                    <resetMask>0xffffffff</resetMask>
                    <fields>
                        <field>
                            <name>INCBA</name>
                            <description>Include I3C Broadcast Address</description>
                            <lsb>0</lsb>
                            <msb>0</msb>
                            <access>read-write</access>
                            <enumeratedValues>
                                <enumeratedValue>
                                    <name>0</name>
                                    <description>Do not include I3C broadcast address for private transfers</description>
                                    <value>#0</value>
                                </enumeratedValue>
                                <enumeratedValue>
                                    <name>1</name>
                                    <description>Include I3C broadcast address for private transfers</description>
                                    <value>#1</value>
                                </enumeratedValue>
                            </enumeratedValues>
                        </field>
                        <field>
                            <name>BMDS</name>
                            <description>Bus Mode Selection</description>
                            <lsb>7</lsb>
                            <msb>7</msb>
                            <access>read-write</access>
                            <enumeratedValues>
                                <enumeratedValue>
                                    <name>0</name>
                                    <description>Legacy inclusive Bus mode disabled</description>
                                    <value>#0</value>
                                </enumeratedValue>
                                <enumeratedValue>
                                    <name>1</name>
                                    <description>Legacy inclusive (mix) Bus mode enabled</description>
                                    <value>#1</value>
                                </enumeratedValue>
                            </enumeratedValues>
                        </field>
                        <field>
                            <name>ABT</name>
                            <description>Abort</description>
                            <lsb>29</lsb>
                            <msb>29</msb>
                            <access>read-write</access>
                            <enumeratedValues>
                                <enumeratedValue>
                                    <name>0</name>
                                    <description>I3C is running.</description>
                                    <value>#0</value>
                                </enumeratedValue>
                                <enumeratedValue>
                                    <name>1</name>
                                    <description>I3C has aborted a transfer.</description>
                                    <value>#1</value>
                                </enumeratedValue>
                            </enumeratedValues>
                        </field>
                        <field>
                            <name>RSM</name>
                            <description>Resume</description>
                            <lsb>30</lsb>
                            <msb>30</msb>
                            <access>read-write</access>
                            <enumeratedValues>
                                <enumeratedValue>
                                    <name>0</name>
                                    <description>I3C is running.</description>
                                    <value>#0</value>
                                </enumeratedValue>
                                <enumeratedValue>
                                    <name>1</name>
                                    <description>I3C is suspended.</description>
                                    <value>#1</value>
                                </enumeratedValue>
                            </enumeratedValues>
                        </field>
                        <field>
                            <name>BUSE</name>
                            <description>Bus Enable</description>
                            <lsb>31</lsb>
                            <msb>31</msb>
                            <access>read-write</access>
                            <enumeratedValues>
                                <enumeratedValue>
                                    <name>0</name>
                                    <description>I3C bus operation is disabled.</description>
                                    <value>#0</value>
                                </enumeratedValue>
                                <enumeratedValue>
                                    <name>1</name>
                                    <description>I3C bus operation is enabled.</description>
                                    <value>#1</value>
                                </enumeratedValue>
                            </enumeratedValues>
                        </field>
                    </fields>
                </register>
                <register>
                    <name>MSDVAD</name>
                    <description>Master Device Address Register</description>
                    <addressOffset>0x018</addressOffset>
                    <size>32</size>
                    <access>read-write</access>
                    <resetValue>0x00000000</resetValue>
                    <resetMask>0xffffffff</resetMask>
                    <fields>
                        <field>
                            <name>MDYAD</name>
                            <description>Master Dynamic Address</description>
                            <lsb>16</lsb>
                            <msb>22</msb>
                            <access>read-write</access>
                        </field>
                        <field>
                            <name>MDYADV</name>
                            <description>Master Dynamic Address Valid</description>
                            <lsb>31</lsb>
                            <msb>31</msb>
                            <access>read-write</access>
                            <enumeratedValues>
                                <enumeratedValue>
                                    <name>0</name>
                                    <description>The master dynamic address field is not valid.</description>
                                    <value>#0</value>
                                </enumeratedValue>
                                <enumeratedValue>
                                    <name>1</name>
                                    <description>The master dynamic address field is valid.</description>
                                    <value>#1</value>
                                </enumeratedValue>
                            </enumeratedValues>
                        </field>
                    </fields>
                </register>
                <register>
                    <name>RSTCTL</name>
                    <description>Reset Control Register</description>
                    <addressOffset>0x020</addressOffset>
                    <size>32</size>
                    <access>read-write</access>
                    <resetValue>0x00000000</resetValue>
                    <resetMask>0xffffffff</resetMask>
                    <fields>
                        <field>
                            <name>RI3CRST</name>
                            <description>I3C Software Reset</description>
                            <lsb>0</lsb>
                            <msb>0</msb>
                            <access>read-write</access>
                            <enumeratedValues>
                                <enumeratedValue>
                                    <name>0</name>
                                    <description>Release I3C reset.</description>
                                    <value>#0</value>
                                </enumeratedValue>
                                <enumeratedValue>
                                    <name>1</name>
                                    <description>Initiate I3C reset.</description>
                                    <value>#1</value>
                                </enumeratedValue>
                            </enumeratedValues>
                        </field>
                        <field>
                            <name>CMDQRST</name>
                            <description>Normal Command Queue Software Reset</description>
                            <lsb>1</lsb>
                            <msb>1</msb>
                            <access>read-write</access>
                            <enumeratedValues>
                                <enumeratedValue>
                                    <name>0</name>
                                    <description>The Normal Command Queues in I3C is not flushed.</description>
                                    <value>#0</value>
                                </enumeratedValue>
                                <enumeratedValue>
                                    <name>1</name>
                                    <description>The Normal Command Queues in I3C is flushed.</description>
                                    <value>#1</value>
                                </enumeratedValue>
                            </enumeratedValues>
                        </field>
                        <field>
                            <name>RSPQRST</name>
                            <description>Normal Response Queue Software Reset</description>
                            <lsb>2</lsb>
                            <msb>2</msb>
                            <access>read-write</access>
                            <enumeratedValues>
                                <enumeratedValue>
                                    <name>0</name>
                                    <description>The Normal Response Queues in I3C is not flushed.</description>
                                    <value>#0</value>
                                </enumeratedValue>
                                <enumeratedValue>
                                    <name>1</name>
                                    <description>The Normal Response Queues in I3C is flushed.</description>
                                    <value>#1</value>
                                </enumeratedValue>
                            </enumeratedValues>
                        </field>
                        <field>
                            <name>TDBRST</name>
                            <description>Normal Tx Data Buffer Software Reset</description>
                            <lsb>3</lsb>
                            <msb>3</msb>
                            <access>read-write</access>
                            <enumeratedValues>
                                <enumeratedValue>
                                    <name>0</name>
                                    <description>The Normal Tx Data buffers in I3C is not flushed.</description>
                                    <value>#0</value>
                                </enumeratedValue>
                                <enumeratedValue>
                                    <name>1</name>
                                    <description>The Normal Tx Data buffers in I3C is flushed.</description>
                                    <value>#1</value>
                                </enumeratedValue>
                            </enumeratedValues>
                        </field>
                        <field>
                            <name>RDBRST</name>
                            <description>Normal Rx Data Buffer Software Reset</description>
                            <lsb>4</lsb>
                            <msb>4</msb>
                            <access>read-write</access>
                            <enumeratedValues>
                                <enumeratedValue>
                                    <name>0</name>
                                    <description>The Normal Rx Data buffers in I3C is not flushed.</description>
                                    <value>#0</value>
                                </enumeratedValue>
                                <enumeratedValue>
                                    <name>1</name>
                                    <description>The Normal Rx Data buffers in I3C is flushed.</description>
                                    <value>#1</value>
                                </enumeratedValue>
                            </enumeratedValues>
                        </field>
                        <field>
                            <name>IBIQRST</name>
                            <description>Normal IBI Queue Software Reset</description>
                            <lsb>5</lsb>
                            <msb>5</msb>
                            <access>read-write</access>
                            <enumeratedValues>
                                <enumeratedValue>
                                    <name>0</name>
                                    <description>The Normal IBI Queues in I3C is not flushed.</description>
                                    <value>#0</value>
                                </enumeratedValue>
                                <enumeratedValue>
                                    <name>1</name>
                                    <description>The Normal IBI Queues in I3C is flushed.</description>
                                    <value>#1</value>
                                </enumeratedValue>
                            </enumeratedValues>
                        </field>
                        <field>
                            <name>RSQRST</name>
                            <description>Normal Receive Status Queue Software Reset</description>
                            <lsb>6</lsb>
                            <msb>6</msb>
                            <access>read-write</access>
                            <enumeratedValues>
                                <enumeratedValue>
                                    <name>0</name>
                                    <description>The Normal Receive Status Queue in I3C is not flushed.</description>
                                    <value>#0</value>
                                </enumeratedValue>
                                <enumeratedValue>
                                    <name>1</name>
                                    <description>The Normal Receive Status Queue in I3C is flushed.</description>
                                    <value>#1</value>
                                </enumeratedValue>
                            </enumeratedValues>
                        </field>
                        <field>
                            <name>HCMDQRST</name>
                            <description>High Priority Command Queue Software Reset</description>
                            <lsb>9</lsb>
                            <msb>9</msb>
                            <access>read-write</access>
                            <enumeratedValues>
                                <enumeratedValue>
                                    <name>0</name>
                                    <description>The High Priority Command Queues in I3C is not flushed.</description>
                                    <value>#0</value>
                                </enumeratedValue>
                                <enumeratedValue>
                                    <name>1</name>
                                    <description>The High Priority Command Queues in I3C is flushed.</description>
                                    <value>#1</value>
                                </enumeratedValue>
                            </enumeratedValues>
                        </field>
                        <field>
                            <name>HRSPQRST</name>
                            <description>High Priority Response Queue Software Reset</description>
                            <lsb>10</lsb>
                            <msb>10</msb>
                            <access>read-write</access>
                            <enumeratedValues>
                                <enumeratedValue>
                                    <name>0</name>
                                    <description>The High Priority Response Queues in I3C is not flushed.</description>
                                    <value>#0</value>
                                </enumeratedValue>
                                <enumeratedValue>
                                    <name>1</name>
                                    <description>The High Priority Response Queues in I3C is flushed.</description>
                                    <value>#1</value>
                                </enumeratedValue>
                            </enumeratedValues>
                        </field>
                        <field>
                            <name>HTDBRST</name>
                            <description>High Priority Tx Data Buffer Software Reset</description>
                            <lsb>11</lsb>
                            <msb>11</msb>
                            <access>read-write</access>
                            <enumeratedValues>
                                <enumeratedValue>
                                    <name>0</name>
                                    <description>The High Priority Tx Data buffers in I3C is not flushed.</description>
                                    <value>#0</value>
                                </enumeratedValue>
                                <enumeratedValue>
                                    <name>1</name>
                                    <description>The High Priority Tx Data buffers in I3C is flushed.</description>
                                    <value>#1</value>
                                </enumeratedValue>
                            </enumeratedValues>
                        </field>
                        <field>
                            <name>HRDBRST</name>
                            <description>High Priority Rx Data Buffer Software Reset</description>
                            <lsb>12</lsb>
                            <msb>12</msb>
                            <access>read-write</access>
                            <enumeratedValues>
                                <enumeratedValue>
                                    <name>0</name>
                                    <description>The High Priority Rx Data buffers in I3C is not flushed.</description>
                                    <value>#0</value>
                                </enumeratedValue>
                                <enumeratedValue>
                                    <name>1</name>
                                    <description>The High Priority Rx Data buffers in I3C is flushed.</description>
                                    <value>#1</value>
                                </enumeratedValue>
                            </enumeratedValues>
                        </field>
                        <field>
                            <name>INTLRST</name>
                            <description>Internal Software Reset</description>
                            <lsb>16</lsb>
                            <msb>16</msb>
                            <access>read-write</access>
                            <enumeratedValues>
                                <enumeratedValue>
                                    <name>0</name>
                                    <description>Releases of some registers and internal state.</description>
                                    <value>#0</value>
                                </enumeratedValue>
                                <enumeratedValue>
                                    <name>1</name>
                                    <description>Resets of some registers and internal state.</description>
                                    <value>#1</value>
                                </enumeratedValue>
                            </enumeratedValues>
                        </field>
                    </fields>
                </register>
                <register>
                    <name>PRSST</name>
                    <description>Present State Register</description>
                    <addressOffset>0x024</addressOffset>
                    <size>32</size>
                    <access>read-write</access>
                    <resetValue>0x00000000</resetValue>
                    <resetMask>0xffffffff</resetMask>
                    <fields>
                        <field>
                            <name>CRMS</name>
                            <description>Current Master</description>
                            <lsb>2</lsb>
                            <msb>2</msb>
                            <access>read-write</access>
                            <enumeratedValues>
                                <enumeratedValue>
                                    <name>0</name>
                                    <description>The Master is not the Current Master, and must request and acquire bus ownership before initiating any transfer.</description>
                                    <value>#0</value>
                                </enumeratedValue>
                                <enumeratedValue>
                                    <name>1</name>
                                    <description>The Master is the Current Master, and as a result can initiate transfers.</description>
                                    <value>#1</value>
                                </enumeratedValue>
                            </enumeratedValues>
                        </field>
                        <field>
                            <name>TRMD</name>
                            <description>Transmit/Receive Mode</description>
                            <lsb>4</lsb>
                            <msb>4</msb>
                            <access>read-only</access>
                            <enumeratedValues>
                                <enumeratedValue>
                                    <name>0</name>
                                    <description>Receive mode</description>
                                    <value>#0</value>
                                </enumeratedValue>
                                <enumeratedValue>
                                    <name>1</name>
                                    <description>Transmit mode</description>
                                    <value>#1</value>
                                </enumeratedValue>
                            </enumeratedValues>
                        </field>
                        <field>
                            <name>PRSSTWP</name>
                            <description>Present State Write Protect</description>
                            <lsb>7</lsb>
                            <msb>7</msb>
                            <access>write-only</access>
                            <enumeratedValues>
                                <enumeratedValue>
                                    <name>0</name>
                                    <description>CRMS bit is protected.</description>
                                    <value>#0</value>
                                </enumeratedValue>
                                <enumeratedValue>
                                    <name>1</name>
                                    <description>CRMS bit can be written when writing simultaneously with the value of the target bit.</description>
                                    <value>#1</value>
                                </enumeratedValue>
                            </enumeratedValues>
                        </field>
                    </fields>
                </register>
                <register>
                    <name>INST</name>
                    <description>Internal Status Register</description>
                    <addressOffset>0x030</addressOffset>
                    <size>32</size>
                    <access>read-write</access>
                    <resetValue>0x00000000</resetValue>
                    <resetMask>0xffffffff</resetMask>
                    <fields>
                        <field>
                            <name>INEF</name>
                            <description>Internal Error Flag</description>
                            <lsb>10</lsb>
                            <msb>10</msb>
                            <access>read-write</access>
                            <enumeratedValues>
                                <enumeratedValue>
                                    <name>0</name>
                                    <description>I3C Internal Error has not detected.</description>
                                    <value>#0</value>
                                </enumeratedValue>
                                <enumeratedValue>
                                    <name>1</name>
                                    <description>I3C Internal Error has detected.</description>
                                    <value>#1</value>
                                </enumeratedValue>
                            </enumeratedValues>
                        </field>
                    </fields>
                </register>
                <register>
                    <name>INSTE</name>
                    <description>Internal Status Enable Register</description>
                    <addressOffset>0x034</addressOffset>
                    <size>32</size>
                    <access>read-write</access>
                    <resetValue>0x00000000</resetValue>
                    <resetMask>0xffffffff</resetMask>
                    <fields>
                        <field>
                            <name>INEE</name>
                            <description>Internal Error Enable</description>
                            <lsb>10</lsb>
                            <msb>10</msb>
                            <access>read-write</access>
                            <enumeratedValues>
                                <enumeratedValue>
                                    <name>0</name>
                                    <description>Disable INST.INEF</description>
                                    <value>#0</value>
                                </enumeratedValue>
                                <enumeratedValue>
                                    <name>1</name>
                                    <description>Enable INST.INEF</description>
                                    <value>#1</value>
                                </enumeratedValue>
                            </enumeratedValues>
                        </field>
                    </fields>
                </register>
                <register>
                    <name>INIE</name>
                    <description>Internal Interrupt Enable Register</description>
                    <addressOffset>0x038</addressOffset>
                    <size>32</size>
                    <access>read-write</access>
                    <resetValue>0x00000000</resetValue>
                    <resetMask>0xffffffff</resetMask>
                    <fields>
                        <field>
                            <name>INEIE</name>
                            <description>Internal Error Interrupt Enable</description>
                            <lsb>10</lsb>
                            <msb>10</msb>
                            <access>read-write</access>
                            <enumeratedValues>
                                <enumeratedValue>
                                    <name>0</name>
                                    <description>Disables Non-recoverable Internal Error Interrupt Signal.</description>
                                    <value>#0</value>
                                </enumeratedValue>
                                <enumeratedValue>
                                    <name>1</name>
                                    <description>Enables Non-recoverable Internal Error Interrupt Signal.</description>
                                    <value>#1</value>
                                </enumeratedValue>
                            </enumeratedValues>
                        </field>
                    </fields>
                </register>
                <register>
                    <name>INSTFC</name>
                    <description>Internal Status Force Register</description>
                    <addressOffset>0x03C</addressOffset>
                    <size>32</size>
                    <access>write-only</access>
                    <resetValue>0x00000000</resetValue>
                    <resetMask>0xffffffff</resetMask>
                    <fields>
                        <field>
                            <name>INEFC</name>
                            <description>Internal Error Force</description>
                            <lsb>10</lsb>
                            <msb>10</msb>
                            <access>write-only</access>
                            <enumeratedValues>
                                <enumeratedValue>
                                    <name>0</name>
                                    <description>Not force a specific interrupt</description>
                                    <value>#0</value>
                                </enumeratedValue>
                                <enumeratedValue>
                                    <name>1</name>
                                    <description>Force a specific interrupt</description>
                                    <value>#1</value>
                                </enumeratedValue>
                            </enumeratedValues>
                        </field>
                    </fields>
                </register>
                <register>
                    <name>DVCT</name>
                    <description>Device Characteristic Table Register</description>
                    <addressOffset>0x044</addressOffset>
                    <size>32</size>
                    <access>read-only</access>
                    <resetValue>0x00000000</resetValue>
                    <resetMask>0xffffffff</resetMask>
                    <fields>
                        <field>
                            <name>IDX</name>
                            <description>DCT Table Index</description>
                            <lsb>19</lsb>
                            <msb>23</msb>
                            <access>read-only</access>
                        </field>
                    </fields>
                </register>
                <register>
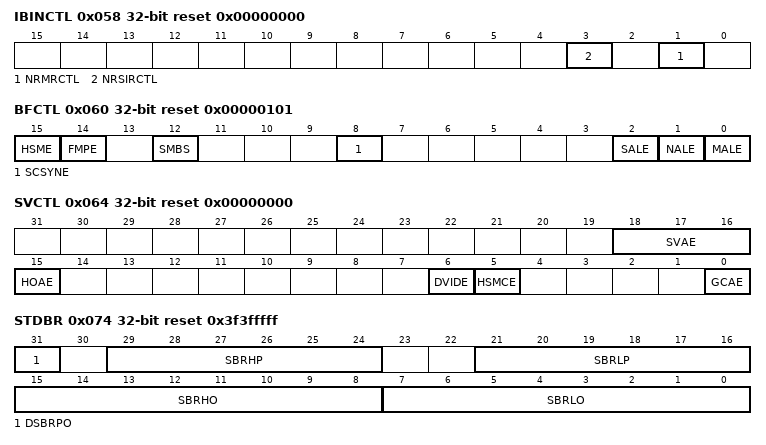
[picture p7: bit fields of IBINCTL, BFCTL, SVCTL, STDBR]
                    <name>IBINCTL</name>
                    <description>IBI Notify Control Register</description>
                    <addressOffset>0x058</addressOffset>
                    <size>32</size>
                    <access>read-write</access>
                    <resetValue>0x00000000</resetValue>
                    <resetMask>0xffffffff</resetMask>
                    <fields>
                        <field>
                            <name>NRMRCTL</name>
                            <description>Notify Rejected Master Request Control</description>
                            <lsb>1</lsb>
                            <msb>1</msb>
                            <access>read-write</access>
                            <enumeratedValues>
                                <enumeratedValue>
                                    <name>0</name>
                                    <description>Do not pass rejected IBI Status to the Normal IBI Queue, if the incoming Master Request is NACKed and is auto-disabled based on DVMRRJ field in relevant DAT entry.</description>
                                    <value>#0</value>
                                </enumeratedValue>
                                <enumeratedValue>
                                    <name>1</name>
                                    <description>Pass rejected IBI Status to the Normal IBI Queue if the incoming Master Request is NACKed and is autodisabled based on DVMRRJ field in relevant DAT entry.</description>
                                    <value>#1</value>
                                </enumeratedValue>
                            </enumeratedValues>
                        </field>
                        <field>
                            <name>NRSIRCTL</name>
                            <description>Notify Rejected Slave Interrupt Request Control</description>
                            <lsb>3</lsb>
                            <msb>3</msb>
                            <access>read-write</access>
                            <enumeratedValues>
                                <enumeratedValue>
                                    <name>0</name>
                                    <description>Do not pass rejected IBI Status to the Normal IBI Queue, if the incoming SIR is NACKed and is auto-disabled based on DVSIRRJ field in relevant DAT entry.</description>
                                    <value>#0</value>
                                </enumeratedValue>
                                <enumeratedValue>
                                    <name>1</name>
                                    <description>Pass rejected IBI Status to the Normal IBI Queue, if the incoming SIR is NACKed and is auto-disabled based on DVSIRRJ field in relevant DAT entry.</description>
                                    <value>#1</value>
                                </enumeratedValue>
                            </enumeratedValues>
                        </field>
                    </fields>
                </register>
                <register>
                    <name>BFCTL</name>
                    <description>Bus Function Control Register</description>
                    <addressOffset>0x060</addressOffset>
                    <size>32</size>
                    <access>read-write</access>
                    <resetValue>0x00000101</resetValue>
                    <resetMask>0xffffffff</resetMask>
                    <fields>
                        <field>
                            <name>MALE</name>
                            <description>Master Arbitration-Lost Detection Enable</description>
                            <lsb>0</lsb>
                            <msb>0</msb>
                            <access>read-write</access>
                            <enumeratedValues>
                                <enumeratedValue>
                                    <name>0</name>
                                    <description>Master arbitration-lost detection disables. Disables the arbitration-lost detection function and does not clear the CRMS and TRMD bits in PRSST automatically when arbitration is lost. </description>
                                    <value>#0</value>
                                </enumeratedValue>
                                <enumeratedValue>
                                    <name>1</name>
                                    <description>Master arbitration-lost detection enables. Enables the arbitration-lost detection function and clears the CRMS and TRMD bits in PRSST automatically when arbitration is lost. </description>
                                    <value>#1</value>
                                </enumeratedValue>
                            </enumeratedValues>
                        </field>
                        <field>
                            <name>NALE</name>
                            <description>NACK Transmission Arbitration-Lost Detection Enable</description>
                            <lsb>1</lsb>
                            <msb>1</msb>
                            <access>read-write</access>
                            <enumeratedValues>
                                <enumeratedValue>
                                    <name>0</name>
                                    <description>NACK transmission arbitration-lost detection disables.</description>
                                    <value>#0</value>
                                </enumeratedValue>
                                <enumeratedValue>
                                    <name>1</name>
                                    <description>NACK transmission arbitration-lost detection enables.</description>
                                    <value>#1</value>
                                </enumeratedValue>
                            </enumeratedValues>
                        </field>
                        <field>
                            <name>SALE</name>
                            <description>Slave Arbitration-Lost Detection Enable</description>
                            <lsb>2</lsb>
                            <msb>2</msb>
                            <access>read-write</access>
                            <enumeratedValues>
                                <enumeratedValue>
                                    <name>0</name>
                                    <description>Slave arbitration-lost detection disables.</description>
                                    <value>#0</value>
                                </enumeratedValue>
                                <enumeratedValue>
                                    <name>1</name>
                                    <description>Slave arbitration-lost detection enables.</description>
                                    <value>#1</value>
                                </enumeratedValue>
                            </enumeratedValues>
                        </field>
                        <field>
                            <name>SCSYNE</name>
                            <description>SCL Synchronous Circuit Enable</description>
                            <lsb>8</lsb>
                            <msb>8</msb>
                            <access>read-write</access>
                            <enumeratedValues>
                                <enumeratedValue>
                                    <name>0</name>
                                    <description>No SCL synchronous circuit uses.</description>
                                    <value>#0</value>
                                </enumeratedValue>
                                <enumeratedValue>
                                    <name>1</name>
                                    <description>An SCL synchronous circuit uses.</description>
                                    <value>#1</value>
                                </enumeratedValue>
                            </enumeratedValues>
                        </field>
                        <field>
                            <name>SMBS</name>
                            <description>SMBus/I2C Bus Selection</description>
                            <lsb>12</lsb>
                            <msb>12</msb>
                            <access>read-write</access>
                            <enumeratedValues>
                                <enumeratedValue>
                                    <name>0</name>
                                    <description>The I2C bus select.</description>
                                    <value>#0</value>
                                </enumeratedValue>
                                <enumeratedValue>
                                    <name>1</name>
                                    <description>The SMBus select.</description>
                                    <value>#1</value>
                                </enumeratedValue>
                            </enumeratedValues>
                        </field>
                        <field>
                            <name>FMPE</name>
                            <description>Fast-mode Plus Enable</description>
                            <lsb>14</lsb>
                            <msb>14</msb>
                            <access>read-write</access>
                            <enumeratedValues>
                                <enumeratedValue>
                                    <name>0</name>
                                    <description>No Fm+ slope control circuit uses for the I3C_SCL pin and I3C_SDA pin. (n = 0)</description>
                                    <value>#0</value>
                                </enumeratedValue>
                                <enumeratedValue>
                                    <name>1</name>
                                    <description>An Fm+ slope control circuit uses for the I3C_SCL pin and I3C_SDA pin. (n = 0)</description>
                                    <value>#1</value>
                                </enumeratedValue>
                            </enumeratedValues>
                        </field>
                        <field>
                            <name>HSME</name>
                            <description>High Speed Mode Enable</description>
                            <lsb>15</lsb>
                            <msb>15</msb>
                            <access>read-write</access>
                            <enumeratedValues>
                                <enumeratedValue>
                                    <name>0</name>
                                    <description>Disable High Speed Mode.</description>
                                    <value>#0</value>
                                </enumeratedValue>
                                <enumeratedValue>
                                    <name>1</name>
                                    <description>Enable High Speed Mode.</description>
                                    <value>#1</value>
                                </enumeratedValue>
                            </enumeratedValues>
                        </field>
                    </fields>
                </register>
                <register>
                    <name>SVCTL</name>
                    <description>Slave Control Register</description>
                    <addressOffset>0x064</addressOffset>
                    <size>32</size>
                    <access>read-write</access>
                    <resetValue>0x00000000</resetValue>
                    <resetMask>0xffffffff</resetMask>
                    <fields>
                        <field>
                            <name>GCAE</name>
                            <description>General Call Address Enable</description>
                            <lsb>0</lsb>
                            <msb>0</msb>
                            <access>read-write</access>
                            <enumeratedValues>
                                <enumeratedValue>
                                    <name>0</name>
                                    <description>General call address detection disables.</description>
                                    <value>#0</value>
                                </enumeratedValue>
                                <enumeratedValue>
                                    <name>1</name>
                                    <description>General call address detection enables.</description>
                                    <value>#1</value>
                                </enumeratedValue>
                            </enumeratedValues>
                        </field>
                        <field>
                            <name>HSMCE</name>
                            <description>Hs-mode Master Code Enable</description>
                            <lsb>5</lsb>
                            <msb>5</msb>
                            <access>read-write</access>
                            <enumeratedValues>
                                <enumeratedValue>
                                    <name>0</name>
                                    <description>Hs-mode Master Code Detection disables.</description>
                                    <value>#0</value>
                                </enumeratedValue>
                                <enumeratedValue>
                                    <name>1</name>
                                    <description>Hs-mode Master Code Detection enables.</description>
                                    <value>#1</value>
                                </enumeratedValue>
                            </enumeratedValues>
                        </field>
                        <field>
                            <name>DVIDE</name>
                            <description>Device-ID Address Enable</description>
                            <lsb>6</lsb>
                            <msb>6</msb>
                            <access>read-write</access>
                            <enumeratedValues>
                                <enumeratedValue>
                                    <name>0</name>
                                    <description>Device-ID address detection disables.</description>
                                    <value>#0</value>
                                </enumeratedValue>
                                <enumeratedValue>
                                    <name>1</name>
                                    <description>Device-ID address detection enables.</description>
                                    <value>#1</value>
                                </enumeratedValue>
                            </enumeratedValues>
                        </field>
                        <field>
                            <name>HOAE</name>
                            <description>Host Address Enable</description>
                            <lsb>15</lsb>
                            <msb>15</msb>
                            <access>read-write</access>
                            <enumeratedValues>
                                <enumeratedValue>
                                    <name>0</name>
                                    <description>Host address detection disables.</description>
                                    <value>#0</value>
                                </enumeratedValue>
                                <enumeratedValue>
                                    <name>1</name>
                                    <description>Host address detection enables.</description>
                                    <value>#1</value>
                                </enumeratedValue>
                            </enumeratedValues>
                        </field>
                        <field>
                            <name>SVAE</name>
                            <description>Slave Address Enable n ( n = 0 to 2 )</description>
                            <lsb>16</lsb>
                            <msb>18</msb>
                            <access>read-write</access>
                            <enumeratedValues>
                                <enumeratedValue>
                                    <name>0</name>
                                    <description>Slave n disables</description>
                                    <value>#0</value>
                                </enumeratedValue>
                                <enumeratedValue>
                                    <name>1</name>
                                    <description>Slave n enables</description>
                                    <value>#1</value>
                                </enumeratedValue>
                            </enumeratedValues>
                        </field>
                    </fields>
                </register>
                <register>
                    <name>REFCKCTL</name>
                    <description>Reference Clock Control Register</description>
                    <addressOffset>0x070</addressOffset>
                    <size>32</size>
                    <access>read-write</access>
                    <resetValue>0x00000000</resetValue>
                    <resetMask>0xffffffff</resetMask>
                    <fields>
                        <field>
                            <name>IREFCKS</name>
                            <description>Internal Reference Clock Selection</description>
                            <lsb>0</lsb>
                            <msb>2</msb>
                            <access>read-write</access>
                            <enumeratedValues>
                                <enumeratedValue>
                                    <name>000</name>
                                    <description>TCLK/1 clock</description>
                                    <value>#000</value>
                                </enumeratedValue>
                                <enumeratedValue>
                                    <name>001</name>
                                    <description>TCLK/2 clock</description>
                                    <value>#001</value>
                                </enumeratedValue>
                                <enumeratedValue>
                                    <name>010</name>
                                    <description>TCLK/4 clock</description>
                                    <value>#010</value>
                                </enumeratedValue>
                                <enumeratedValue>
                                    <name>011</name>
                                    <description>TCLK/8 clock</description>
                                    <value>#011</value>
                                </enumeratedValue>
                                <enumeratedValue>
                                    <name>100</name>
                                    <description>TCLK/16 clock</description>
                                    <value>#100</value>
                                </enumeratedValue>
                                <enumeratedValue>
                                    <name>101</name>
                                    <description>TCLK/32 clock</description>
                                    <value>#101</value>
                                </enumeratedValue>
                                <enumeratedValue>
                                    <name>110</name>
                                    <description>TCLK/64 clock</description>
                                    <value>#110</value>
                                </enumeratedValue>
                                <enumeratedValue>
                                    <name>111</name>
                                    <description>TCLK/128 clock</description>
                                    <value>#111</value>
                                </enumeratedValue>
                            </enumeratedValues>
                        </field>
                    </fields>
                </register>
                <register>
                    <name>STDBR</name>
                    <description>Standard Bit Rate Register</description>
                    <addressOffset>0x074</addressOffset>
                    <size>32</size>
                    <access>read-write</access>
                    <resetValue>0x3f3fffff</resetValue>
                    <resetMask>0xffffffff</resetMask>
                    <fields>
                        <field>
                            <name>SBRLO</name>
                            <description>Standard Bit Rate Low-Level Period Open-Drain</description>
                            <lsb>0</lsb>
                            <msb>7</msb>
                            <access>read-write</access>
                        </field>
                        <field>
                            <name>SBRHO</name>
                            <description>Standard Bit Rate High-Level Period Open-Drain</description>
                            <lsb>8</lsb>
                            <msb>15</msb>
                            <access>read-write</access>
                        </field>
                        <field>
                            <name>SBRLP</name>
                            <description>Standard Bit Rate Low-level Period Push-Pull</description>
                            <lsb>16</lsb>
                            <msb>21</msb>
                            <access>read-write</access>
                        </field>
                        <field>
                            <name>SBRHP</name>
                            <description>Standard Bit Rate High-Level Period Push-Pull</description>
                            <lsb>24</lsb>
                            <msb>29</msb>
                            <access>read-write</access>
                        </field>
                        <field>
                            <name>DSBRPO</name>
                            <description>Double the Standard Bit Rate Period for Open-Drain</description>
                            <lsb>31</lsb>
                            <msb>31</msb>
                            <access>read-write</access>
                            <enumeratedValues>
                                <enumeratedValue>
                                    <name>0</name>
                                    <description>The time period set for SBRHO[7:0] and SBRLO[7:0] is not doubled. </description>
                                    <value>#0</value>
                                </enumeratedValue>
                                <enumeratedValue>
                                    <name>1</name>
                                    <description>The time period set for SBRHO[7:0] and SBRLO[7:0] is doubled. </description>
                                    <value>#1</value>
                                </enumeratedValue>
                            </enumeratedValues>
                        </field>
                    </fields>
                </register>
                <register>
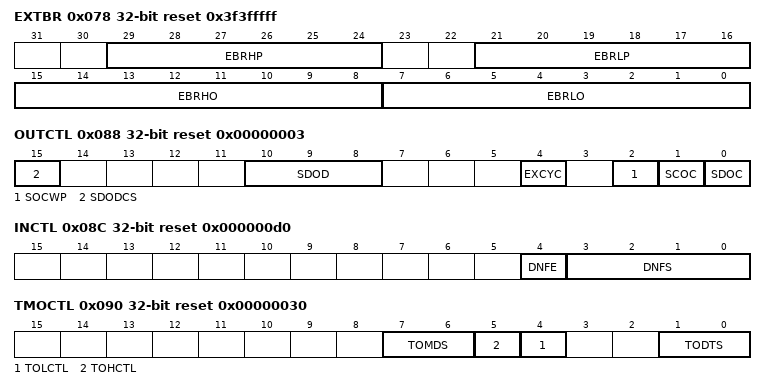
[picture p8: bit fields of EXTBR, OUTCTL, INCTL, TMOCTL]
                    <name>EXTBR</name>
                    <description>Extended Bit Rate Register</description>
                    <addressOffset>0x078</addressOffset>
                    <size>32</size>
                    <access>read-write</access>
                    <resetValue>0x3f3fffff</resetValue>
                    <resetMask>0xffffffff</resetMask>
                    <fields>
                        <field>
                            <name>EBRLO</name>
                            <description>Extended Bit Rate Low-Level Period Open-Drain</description>
                            <lsb>0</lsb>
                            <msb>7</msb>
                            <access>read-write</access>
                        </field>
                        <field>
                            <name>EBRHO</name>
                            <description>Extended Bit Rate High-Level Period Open-Drain</description>
                            <lsb>8</lsb>
                            <msb>15</msb>
                            <access>read-write</access>
                        </field>
                        <field>
                            <name>EBRLP</name>
                            <description>Extended Bit Rate Low-Level Period Push-Pull</description>
                            <lsb>16</lsb>
                            <msb>21</msb>
                            <access>read-write</access>
                        </field>
                        <field>
                            <name>EBRHP</name>
                            <description>Extended Bit Rate High-Level Period Push-Pull</description>
                            <lsb>24</lsb>
                            <msb>29</msb>
                            <access>read-write</access>
                        </field>
                    </fields>
                </register>
                <register>
                    <name>BFRECDT</name>
                    <description>Bus Free Condition Detection Time Register</description>
                    <addressOffset>0x07C</addressOffset>
                    <size>32</size>
                    <access>read-write</access>
                    <resetValue>0x00000000</resetValue>
                    <resetMask>0xffffffff</resetMask>
                    <fields>
                        <field>
                            <name>FRECYC</name>
                            <description>Bus Free Condition Detection Cycle</description>
                            <lsb>0</lsb>
                            <msb>8</msb>
                            <access>read-write</access>
                        </field>
                    </fields>
                </register>
                <register>
                    <name>BAVLCDT</name>
                    <description>Bus Available Condition Detection Time Register</description>
                    <addressOffset>0x080</addressOffset>
                    <size>32</size>
                    <access>read-write</access>
                    <resetValue>0x00000000</resetValue>
                    <resetMask>0xffffffff</resetMask>
                    <fields>
                        <field>
                            <name>AVLCYC</name>
                            <description>Bus Available Condition Detection Cycle</description>
                            <lsb>0</lsb>
                            <msb>8</msb>
                            <access>read-write</access>
                        </field>
                    </fields>
                </register>
                <register>
                    <name>BIDLCDT</name>
                    <description>Bus Idle Condition Detection Time Register</description>
                    <addressOffset>0x084</addressOffset>
                    <size>32</size>
                    <access>read-write</access>
                    <resetValue>0x00000000</resetValue>
                    <resetMask>0xffffffff</resetMask>
                    <fields>
                        <field>
                            <name>IDLCYC</name>
                            <description>Bus Idle Condition Detection Cycle</description>
                            <lsb>0</lsb>
                            <msb>17</msb>
                            <access>read-write</access>
                        </field>
                    </fields>
                </register>
                <register>
                    <name>OUTCTL</name>
                    <description>Output Control Register</description>
                    <addressOffset>0x088</addressOffset>
                    <size>32</size>
                    <access>read-write</access>
                    <resetValue>0x00000003</resetValue>
                    <resetMask>0xffffffff</resetMask>
                    <fields>
                        <field>
                            <name>SDOC</name>
                            <description>SDA Output Control</description>
                            <lsb>0</lsb>
                            <msb>0</msb>
                            <access>read-write</access>
                            <enumeratedValues>
                                <enumeratedValue>
                                    <name>0</name>
                                    <description>I3C drives the I3C_SDA pin low.</description>
                                    <value>#0</value>
                                </enumeratedValue>
                                <enumeratedValue>
                                    <name>1</name>
                                    <description>I3C releases the I3C_SDA pin.</description>
                                    <value>#1</value>
                                </enumeratedValue>
                            </enumeratedValues>
                        </field>
                        <field>
                            <name>SCOC</name>
                            <description>SCL Output Control</description>
                            <lsb>1</lsb>
                            <msb>1</msb>
                            <access>read-write</access>
                            <enumeratedValues>
                                <enumeratedValue>
                                    <name>0</name>
                                    <description>I3C drives the I3C_SCL pin low.</description>
                                    <value>#0</value>
                                </enumeratedValue>
                                <enumeratedValue>
                                    <name>1</name>
                                    <description>I3C releases the I3C_SCL pin.</description>
                                    <value>#1</value>
                                </enumeratedValue>
                            </enumeratedValues>
                        </field>
                        <field>
                            <name>SOCWP</name>
                            <description>SCL/SDA Output Control Write Protect</description>
                            <lsb>2</lsb>
                            <msb>2</msb>
                            <access>write-only</access>
                            <enumeratedValues>
                                <enumeratedValue>
                                    <name>0</name>
                                    <description>Bits SCOC and SDOC are protected.</description>
                                    <value>#0</value>
                                </enumeratedValue>
                                <enumeratedValue>
                                    <name>1</name>
                                    <description>Bits SCOC and SDOC can be written (When writing simultaneously with the value of the target bit). This bit is read as 0. </description>
                                    <value>#1</value>
                                </enumeratedValue>
                            </enumeratedValues>
                        </field>
                        <field>
                            <name>EXCYC</name>
                            <description>Extra SCL Clock Cycle Output</description>
                            <lsb>4</lsb>
                            <msb>4</msb>
                            <access>read-write</access>
                            <enumeratedValues>
                                <enumeratedValue>
                                    <name>0</name>
                                    <description>Does not output an extra SCL clock cycle (default).</description>
                                    <value>#0</value>
                                </enumeratedValue>
                                <enumeratedValue>
                                    <name>1</name>
                                    <description>Outputs an extra SCL clock cycle.</description>
                                    <value>#1</value>
                                </enumeratedValue>
                            </enumeratedValues>
                        </field>
                        <field>
                            <name>SDOD</name>
                            <description>SDA Output Delay</description>
                            <lsb>8</lsb>
                            <msb>10</msb>
                            <access>read-write</access>
                            <enumeratedValues>
                                <enumeratedValue>
                                    <name>000</name>
                                    <description>No output delay</description>
                                    <value>#000</value>
                                </enumeratedValue>
                                <enumeratedValue>
                                    <name>001</name>
                                    <description>1 I3Cφ cycle (When OUTCTL.SDODCS = 0 (I3Cφ)) 1 or 2 I3Cφ cycles (When OUTCTL.SDODCS = 1 (I3Cφ/2)) </description>
                                    <value>#001</value>
                                </enumeratedValue>
                                <enumeratedValue>
                                    <name>010</name>
                                    <description>2 I3Cφ cycles (When OUTCTL.SDODCS = 0 (I3Cφ)) 3 or 4 I3Cφ cycles (When OUTCTL.SDODCS = 1 (I3Cφ/2)) </description>
                                    <value>#010</value>
                                </enumeratedValue>
                                <enumeratedValue>
                                    <name>011</name>
                                    <description>3 I3Cφ cycles (When OUTCTL.SDODCS = 0 (I3Cφ)) 5 or 6 I3Cφ cycles (When OUTCTL.SDODCS = 1 (I3Cφ/2)) </description>
                                    <value>#011</value>
                                </enumeratedValue>
                                <enumeratedValue>
                                    <name>100</name>
                                    <description>4 I3Cφ cycles (When OUTCTL.SDODCS = 0 (I3Cφ)) 7 or 8 I3Cφ cycles (When OUTCTL.SDODCS = 1 (I3Cφ/2)) </description>
                                    <value>#100</value>
                                </enumeratedValue>
                                <enumeratedValue>
                                    <name>101</name>
                                    <description>5 I3Cφ cycles (When OUTCTL.SDODCS = 0 (I3Cφ)) 9 or 10 I3Cφ cycles (When OUTCTL.SDODCS = 1 (I3Cφ/2)) </description>
                                    <value>#101</value>
                                </enumeratedValue>
                                <enumeratedValue>
                                    <name>110</name>
                                    <description>6 I3Cφ cycles (When OUTCTL.SDODCS = 0 (I3Cφ)) 11 or 12 I3Cφ cycles (When OUTCTL.SDODCS = 1 (I3Cφ/2)) </description>
                                    <value>#110</value>
                                </enumeratedValue>
                                <enumeratedValue>
                                    <name>111</name>
                                    <description>7 I3Cφ cycles (When OUTCTL.SDODCS = 0 (I3Cφ)) 13 or 14 I3Cφ cycles (When OUTCTL.SDODCS = 1 (I3Cφ/2)) </description>
                                    <value>#111</value>
                                </enumeratedValue>
                            </enumeratedValues>
                        </field>
                        <field>
                            <name>SDODCS</name>
                            <description>SDA Output Delay Clock Source Selection</description>
                            <lsb>15</lsb>
                            <msb>15</msb>
                            <access>read-write</access>
                            <enumeratedValues>
                                <enumeratedValue>
                                    <name>0</name>
                                    <description>The internal reference clock (I3Cφ) is selected as the clock source of the SDA output delay counter.</description>
                                    <value>#0</value>
                                </enumeratedValue>
                                <enumeratedValue>
                                    <name>1</name>
                                    <description>The internal reference clock divided by 2 (I3Cφ/2) is selected as the clock source of the SDA output delay counter.</description>
                                    <value>#1</value>
                                </enumeratedValue>
                            </enumeratedValues>
                        </field>
                    </fields>
                </register>
                <register>
                    <name>INCTL</name>
                    <description>Input Control Register</description>
                    <addressOffset>0x08C</addressOffset>
                    <size>32</size>
                    <access>read-write</access>
                    <resetValue>0x000000d0</resetValue>
                    <resetMask>0xffffffff</resetMask>
                    <fields>
                        <field>
                            <name>DNFS</name>
                            <description>Digital Noise Filter Stage Selection</description>
                            <lsb>0</lsb>
                            <msb>3</msb>
                            <access>read-write</access>
                        </field>
                        <field>
                            <name>DNFE</name>
                            <description>Digital Noise Filter Circuit Enable</description>
                            <lsb>4</lsb>
                            <msb>4</msb>
                            <access>read-write</access>
                            <enumeratedValues>
                                <enumeratedValue>
                                    <name>0</name>
                                    <description>No digital noise filter circuit is used.</description>
                                    <value>#0</value>
                                </enumeratedValue>
                                <enumeratedValue>
                                    <name>1</name>
                                    <description>A digital noise filter circuit is used.</description>
                                    <value>#1</value>
                                </enumeratedValue>
                            </enumeratedValues>
                        </field>
                    </fields>
                </register>
                <register>
                    <name>TMOCTL</name>
                    <description>Timeout Control Register</description>
                    <addressOffset>0x090</addressOffset>
                    <size>32</size>
                    <access>read-write</access>
                    <resetValue>0x00000030</resetValue>
                    <resetMask>0xffffffff</resetMask>
                    <fields>
                        <field>
                            <name>TODTS</name>
                            <description>Timeout Detection Time Selection</description>
                            <lsb>0</lsb>
                            <msb>1</msb>
                            <access>read-write</access>
                            <enumeratedValues>
                                <enumeratedValue>
                                    <name>00</name>
                                    <description>16bit-timeout</description>
                                    <value>#00</value>
                                </enumeratedValue>
                                <enumeratedValue>
                                    <name>01</name>
                                    <description>14bit-timeout</description>
                                    <value>#01</value>
                                </enumeratedValue>
                                <enumeratedValue>
                                    <name>10</name>
                                    <description>8bit-timeout</description>
                                    <value>#10</value>
                                </enumeratedValue>
                                <enumeratedValue>
                                    <name>11</name>
                                    <description>6bit-timeout</description>
                                    <value>#11</value>
                                </enumeratedValue>
                            </enumeratedValues>
                        </field>
                        <field>
                            <name>TOLCTL</name>
                            <description>Timeout L Count Control</description>
                            <lsb>4</lsb>
                            <msb>4</msb>
                            <access>read-write</access>
                            <enumeratedValues>
                                <enumeratedValue>
                                    <name>0</name>
                                    <description>Count is disabled while the I3C_SCL line is at a low level.</description>
                                    <value>#0</value>
                                </enumeratedValue>
                                <enumeratedValue>
                                    <name>1</name>
                                    <description>Count is enabled while the I3C_SCL line is at a low level.</description>
                                    <value>#1</value>
                                </enumeratedValue>
                            </enumeratedValues>
                        </field>
                        <field>
                            <name>TOHCTL</name>
                            <description>Timeout H Count Control</description>
                            <lsb>5</lsb>
                            <msb>5</msb>
                            <access>read-write</access>
                            <enumeratedValues>
                                <enumeratedValue>
                                    <name>0</name>
                                    <description>Count is disabled while the I3C_SCL line is at a high level.</description>
                                    <value>#0</value>
                                </enumeratedValue>
                                <enumeratedValue>
                                    <name>1</name>
                                    <description>Count is enabled while the I3C_SCL line is at a high level.</description>
                                    <value>#1</value>
                                </enumeratedValue>
                            </enumeratedValues>
                        </field>
                        <field>
                            <name>TOMDS</name>
                            <description>Timeout Operation Mode Selection</description>
                            <lsb>6</lsb>
                            <msb>7</msb>
                            <access>read-write</access>
                            <enumeratedValues>
                                <enumeratedValue>
                                    <name>00</name>
                                    <description>Timeout is detected during the following conditions: The bus is busy (BCST.BFREF = 0) in master mode.I3C’s own slave address is detected and the bus is busy in slave mode.The bus is free (BCST.BFREF = 1) while generation of a START condition is requested (CNDCTL.STCND = 1).</description>
                                    <value>#00</value>
                                </enumeratedValue>
                                <enumeratedValue>
                                    <name>01</name>
                                    <description>Timeout is detected while the bus is busy.</description>
                                    <value>#01</value>
                                </enumeratedValue>
                                <enumeratedValue>
                                    <name>10</name>
                                    <description>Timeout is detected while the bus is free.</description>
                                    <value>#10</value>
                                </enumeratedValue>
                                <enumeratedValue>
                                    <name>11</name>
                                    <description>Setting prohibited</description>
                                    <value>#11</value>
                                </enumeratedValue>
                            </enumeratedValues>
                        </field>
                    </fields>
                </register>
                <register>
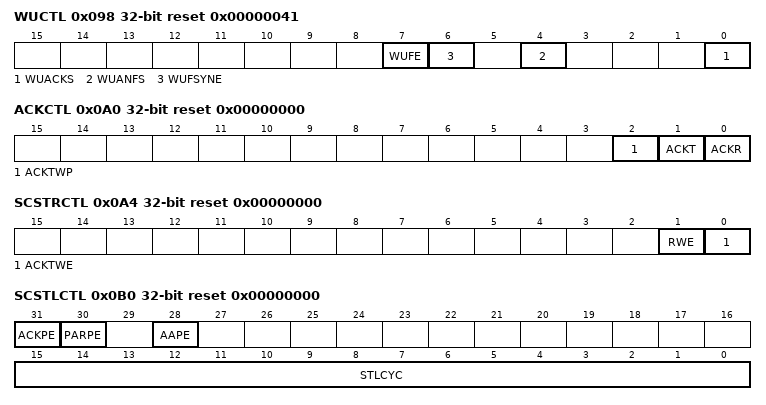
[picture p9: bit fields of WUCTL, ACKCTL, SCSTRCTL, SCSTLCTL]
                    <name>WUCTL</name>
                    <description>Wake Up Unit Control Register</description>
                    <addressOffset>0x098</addressOffset>
                    <size>32</size>
                    <access>read-write</access>
                    <resetValue>0x00000041</resetValue>
                    <resetMask>0xffffffff</resetMask>
                    <fields>
                        <field>
                            <name>WUACKS</name>
                            <description>Wake-Up Acknowledge Selection</description>
                            <lsb>0</lsb>
                            <msb>0</msb>
                            <access>read-write</access>
                        </field>
                        <field>
                            <name>WUANFS</name>
                            <description>Wake-Up Analog Noise Filter Selection</description>
                            <lsb>4</lsb>
                            <msb>4</msb>
                            <access>read-write</access>
                            <enumeratedValues>
                                <enumeratedValue>
                                    <name>0</name>
                                    <description>Do not add the Wake Up analog filter.</description>
                                    <value>#0</value>
                                </enumeratedValue>
                                <enumeratedValue>
                                    <name>1</name>
                                    <description>Add the Wake Up analog filter.</description>
                                    <value>#1</value>
                                </enumeratedValue>
                            </enumeratedValues>
                        </field>
                        <field>
                            <name>WUFSYNE</name>
                            <description>Wake-Up function PCLK Synchronous Enable</description>
                            <lsb>6</lsb>
                            <msb>6</msb>
                            <access>read-write</access>
                            <enumeratedValues>
                                <enumeratedValue>
                                    <name>0</name>
                                    <description>I3C asynchronous circuit enable</description>
                                    <value>#0</value>
                                </enumeratedValue>
                                <enumeratedValue>
                                    <name>1</name>
                                    <description>I3C synchronous circuit enable</description>
                                    <value>#1</value>
                                </enumeratedValue>
                            </enumeratedValues>
                        </field>
                        <field>
                            <name>WUFE</name>
                            <description>Wake-Up function Enable</description>
                            <lsb>7</lsb>
                            <msb>7</msb>
                            <access>read-write</access>
                            <enumeratedValues>
                                <enumeratedValue>
                                    <name>0</name>
                                    <description>Wake-up function disables</description>
                                    <value>#0</value>
                                </enumeratedValue>
                                <enumeratedValue>
                                    <name>1</name>
                                    <description>Wake-up function enables</description>
                                    <value>#1</value>
                                </enumeratedValue>
                            </enumeratedValues>
                        </field>
                    </fields>
                </register>
                <register>
                    <name>ACKCTL</name>
                    <description>Acknowledge Control Register</description>
                    <addressOffset>0x0A0</addressOffset>
                    <size>32</size>
                    <access>read-write</access>
                    <resetValue>0x00000000</resetValue>
                    <resetMask>0xffffffff</resetMask>
                    <fields>
                        <field>
                            <name>ACKR</name>
                            <description>Acknowledge Reception</description>
                            <lsb>0</lsb>
                            <msb>0</msb>
                            <access>read-only</access>
                            <enumeratedValues>
                                <enumeratedValue>
                                    <name>0</name>
                                    <description>A 0 is received as the acknowledge bit (ACK reception).</description>
                                    <value>#0</value>
                                </enumeratedValue>
                                <enumeratedValue>
                                    <name>1</name>
                                    <description>A 1 is received as the acknowledge bit (NACK reception).</description>
                                    <value>#1</value>
                                </enumeratedValue>
                            </enumeratedValues>
                        </field>
                        <field>
                            <name>ACKT</name>
                            <description>Acknowledge Transmission</description>
                            <lsb>1</lsb>
                            <msb>1</msb>
                            <access>read-write</access>
                            <enumeratedValues>
                                <enumeratedValue>
                                    <name>0</name>
                                    <description>A 0 is sent as the acknowledge bit (ACK transmission).</description>
                                    <value>#0</value>
                                </enumeratedValue>
                                <enumeratedValue>
                                    <name>1</name>
                                    <description>A 1 is sent as the acknowledge bit (NACK transmission).</description>
                                    <value>#1</value>
                                </enumeratedValue>
                            </enumeratedValues>
                        </field>
                        <field>
                            <name>ACKTWP</name>
                            <description>ACKT Write Protect</description>
                            <lsb>2</lsb>
                            <msb>2</msb>
                            <access>write-only</access>
                            <enumeratedValues>
                                <enumeratedValue>
                                    <name>0</name>
                                    <description>The ACKT bit are protected.</description>
                                    <value>#0</value>
                                </enumeratedValue>
                                <enumeratedValue>
                                    <name>1</name>
                                    <description>The ACKT bit can be written (when writing simultaneously with the value of the target bit). This bit is read as 0. </description>
                                    <value>#1</value>
                                </enumeratedValue>
                            </enumeratedValues>
                        </field>
                    </fields>
                </register>
                <register>
                    <name>SCSTRCTL</name>
                    <description>SCL Stretch Control Register</description>
                    <addressOffset>0x0A4</addressOffset>
                    <size>32</size>
                    <access>read-write</access>
                    <resetValue>0x00000000</resetValue>
                    <resetMask>0xffffffff</resetMask>
                    <fields>
                        <field>
                            <name>ACKTWE</name>
                            <description>Acknowledge Transmission Wait Enable</description>
                            <lsb>0</lsb>
                            <msb>0</msb>
                            <access>read-write</access>
                            <enumeratedValues>
                                <enumeratedValue>
                                    <name>0</name>
                                    <description>NTST.RDBFF0 is set at the rising edge of the ninth SCL clock cycle. (The I3C_SCL line is not held low at the falling edge of the eighth clock cycle.)</description>
                                    <value>#0</value>
                                </enumeratedValue>
                                <enumeratedValue>
                                    <name>1</name>
                                    <description>NTST.RDBFF0 is set at the rising edge of the eighth SCL clock cycle. (The I3C_SCL line is held low at the falling edge of the eighth clock cycle.) Low-hold is released by writing a value to the ACKCTL.ACKT bit. </description>
                                    <value>#1</value>
                                </enumeratedValue>
                            </enumeratedValues>
                        </field>
                        <field>
                            <name>RWE</name>
                            <description>Receive Wait Enable</description>
                            <lsb>1</lsb>
                            <msb>1</msb>
                            <access>read-write</access>
                            <enumeratedValues>
                                <enumeratedValue>
                                    <name>0</name>
                                    <description>No WAIT (The period between ninth clock cycle and first clock cycle is not held low.)</description>
                                    <value>#0</value>
                                </enumeratedValue>
                                <enumeratedValue>
                                    <name>1</name>
                                    <description>WAIT (The period between ninth clock cycle and first clock cycle is held low.) Low-hold is released by reading NTDTBP0. </description>
                                    <value>#1</value>
                                </enumeratedValue>
                            </enumeratedValues>
                        </field>
                    </fields>
                </register>
                <register>
                    <name>SCSTLCTL</name>
                    <description>SCL Stalling Control Register</description>
                    <addressOffset>0x0B0</addressOffset>
                    <size>32</size>
                    <access>read-write</access>
                    <resetValue>0x00000000</resetValue>
                    <resetMask>0xffffffff</resetMask>
                    <fields>
                        <field>
                            <name>STLCYC</name>
                            <description>Stalling Cycle</description>
                            <lsb>0</lsb>
                            <msb>15</msb>
                            <access>read-write</access>
                        </field>
                        <field>
                            <name>AAPE</name>
                            <description>Assigned Address Phase Enable</description>
                            <lsb>28</lsb>
                            <msb>28</msb>
                            <access>read-write</access>
                            <enumeratedValues>
                                <enumeratedValue>
                                    <name>0</name>
                                    <description>Does not stall the SCL clock during the address assignment phase.</description>
                                    <value>#0</value>
                                </enumeratedValue>
                                <enumeratedValue>
                                    <name>1</name>
                                    <description>Stall the SCL clock during address assignment phase.</description>
                                    <value>#1</value>
                                </enumeratedValue>
                            </enumeratedValues>
                        </field>
                        <field>
                            <name>PARPE</name>
                            <description>Parity Phase Enable</description>
                            <lsb>30</lsb>
                            <msb>30</msb>
                            <access>read-write</access>
                            <enumeratedValues>
                                <enumeratedValue>
                                    <name>0</name>
                                    <description>Does not stall the SCL clock during the parity bit period.</description>
                                    <value>#0</value>
                                </enumeratedValue>
                                <enumeratedValue>
                                    <name>1</name>
                                    <description>Stall the SCL clock during the parity bit period.</description>
                                    <value>#1</value>
                                </enumeratedValue>
                            </enumeratedValues>
                        </field>
                        <field>
                            <name>ACKPE</name>
                            <description>ACK phase Enable</description>
                            <lsb>31</lsb>
                            <msb>31</msb>
                            <access>read-write</access>
                            <enumeratedValues>
                                <enumeratedValue>
                                    <name>0</name>
                                    <description>Does not stall the SCL clock during the ACK/NACK phase.</description>
                                    <value>#0</value>
                                </enumeratedValue>
                                <enumeratedValue>
                                    <name>1</name>
                                    <description>Stall the SCL clock during the ACK/NACK phase.</description>
                                    <value>#1</value>
                                </enumeratedValue>
                            </enumeratedValues>
                        </field>
                    </fields>
                </register>
                <register>
                    <name>SVTDLG0</name>
                    <description>Slave Transfer Data Length Register 0</description>
                    <addressOffset>0x0C0</addressOffset>
                    <size>32</size>
                    <access>read-write</access>
                    <resetValue>0x00000000</resetValue>
                    <resetMask>0xffffffff</resetMask>
                    <fields>
                        <field>
                            <name>STDLG</name>
                            <description>Slave Transfer Data Length</description>
                            <lsb>16</lsb>
                            <msb>31</msb>
                            <access>read-write</access>
                        </field>
                    </fields>
                </register>
                <register>
                    <name>STCTL</name>
                    <description>Synchronous Timing Control Register</description>
                    <addressOffset>0x120</addressOffset>
                    <size>32</size>
                    <access>read-write</access>
                    <resetValue>0x00000000</resetValue>
                    <resetMask>0xffffffff</resetMask>
                    <fields>
                        <field>
                            <name>STOE</name>
                            <description>Synchronous Timing output Enable</description>
                            <lsb>0</lsb>
                            <msb>0</msb>
                            <access>read-write</access>
                            <enumeratedValues>
                                <enumeratedValue>
                                    <name>0</name>
                                    <description>Disable</description>
                                    <value>#0</value>
                                </enumeratedValue>
                                <enumeratedValue>
                                    <name>1</name>
                                    <description>Enable</description>
                                    <value>#1</value>
                                </enumeratedValue>
                            </enumeratedValues>
                        </field>
                    </fields>
                </register>
                <register>
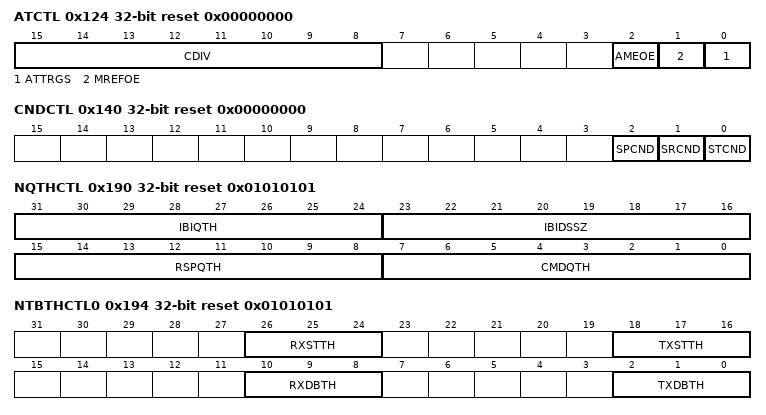
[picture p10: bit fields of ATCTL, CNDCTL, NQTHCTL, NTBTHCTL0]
                    <name>ATCTL</name>
                    <description>Asynchronous Timing Control Register</description>
                    <addressOffset>0x124</addressOffset>
                    <size>32</size>
                    <access>read-write</access>
                    <resetValue>0x00000000</resetValue>
                    <resetMask>0xffffffff</resetMask>
                    <fields>
                        <field>
                            <name>ATTRGS</name>
                            <description>Asynchronous Timing Trigger Select</description>
                            <lsb>0</lsb>
                            <msb>0</msb>
                            <access>read-write</access>
                            <enumeratedValues>
                                <enumeratedValue>
                                    <name>0</name>
                                    <description>Software trigger</description>
                                    <value>#0</value>
                                </enumeratedValue>
                                <enumeratedValue>
                                    <name>1</name>
                                    <description>Hardware trigger</description>
                                    <value>#1</value>
                                </enumeratedValue>
                            </enumeratedValues>
                        </field>
                        <field>
                            <name>MREFOE</name>
                            <description>MREF Output Enable (Capture Event / Counter Overflow)</description>
                            <lsb>1</lsb>
                            <msb>1</msb>
                            <access>read-write</access>
                            <enumeratedValues>
                                <enumeratedValue>
                                    <name>0</name>
                                    <description>Disable</description>
                                    <value>#0</value>
                                </enumeratedValue>
                                <enumeratedValue>
                                    <name>1</name>
                                    <description>Enable</description>
                                    <value>#1</value>
                                </enumeratedValue>
                            </enumeratedValues>
                        </field>
                        <field>
                            <name>AMEOE</name>
                            <description>Additional Master-initiated bus Event Output Enable</description>
                            <lsb>2</lsb>
                            <msb>2</msb>
                            <access>read-write</access>
                            <enumeratedValues>
                                <enumeratedValue>
                                    <name>0</name>
                                    <description>Disable</description>
                                    <value>#0</value>
                                </enumeratedValue>
                                <enumeratedValue>
                                    <name>1</name>
                                    <description>Enable</description>
                                    <value>#1</value>
                                </enumeratedValue>
                            </enumeratedValues>
                        </field>
                        <field>
                            <name>CDIV</name>
                            <description>TCLK Counter Divide Setting</description>
                            <lsb>8</lsb>
                            <msb>15</msb>
                            <access>read-write</access>
                        </field>
                    </fields>
                </register>
                <register>
                    <name>ATTRG</name>
                    <description>Asynchronous Timing Trigger Register</description>
                    <addressOffset>0x128</addressOffset>
                    <size>32</size>
                    <access>read-write</access>
                    <resetValue>0x00000000</resetValue>
                    <resetMask>0xffffffff</resetMask>
                    <fields>
                        <field>
                            <name>ATSTRG</name>
                            <description>Asynchronous Timing Software Trigger</description>
                            <lsb>0</lsb>
                            <msb>0</msb>
                            <access>write-only</access>
                            <enumeratedValues>
                                <enumeratedValue>
                                    <name>0</name>
                                    <description>Do nothing</description>
                                    <value>#0</value>
                                </enumeratedValue>
                                <enumeratedValue>
                                    <name>1</name>
                                    <description>Software trigger (one-shot pulse) output This bit is always read as 0. </description>
                                    <value>#1</value>
                                </enumeratedValue>
                            </enumeratedValues>
                        </field>
                    </fields>
                </register>
                <register>
                    <name>ATCCNTE</name>
                    <description>Asynchronous Timing Control Counter Enable Register</description>
                    <addressOffset>0x12C</addressOffset>
                    <size>32</size>
                    <access>read-write</access>
                    <resetValue>0x00000000</resetValue>
                    <resetMask>0xffffffff</resetMask>
                    <fields>
                        <field>
                            <name>ATCE</name>
                            <description>Asynchronous Timing Counter Enable for MREF, MC2, SC1, SC2.</description>
                            <lsb>0</lsb>
                            <msb>0</msb>
                            <access>read-write</access>
                            <enumeratedValues>
                                <enumeratedValue>
                                    <name>0</name>
                                    <description>Disable</description>
                                    <value>#0</value>
                                </enumeratedValue>
                                <enumeratedValue>
                                    <name>1</name>
                                    <description>Enable</description>
                                    <value>#1</value>
                                </enumeratedValue>
                            </enumeratedValues>
                        </field>
                    </fields>
                </register>
                <register>
                    <name>CNDCTL</name>
                    <description>Condition Control Register</description>
                    <addressOffset>0x140</addressOffset>
                    <size>32</size>
                    <access>read-write</access>
                    <resetValue>0x00000000</resetValue>
                    <resetMask>0xffffffff</resetMask>
                    <fields>
                        <field>
                            <name>STCND</name>
                            <description>START (S) Condition Issuance</description>
                            <lsb>0</lsb>
                            <msb>0</msb>
                            <access>read-write</access>
                            <enumeratedValues>
                                <enumeratedValue>
                                    <name>0</name>
                                    <description>Does not request to issue a START condition.</description>
                                    <value>#0</value>
                                </enumeratedValue>
                                <enumeratedValue>
                                    <name>1</name>
                                    <description>Requests to issue a START condition.</description>
                                    <value>#1</value>
                                </enumeratedValue>
                            </enumeratedValues>
                        </field>
                        <field>
                            <name>SRCND</name>
                            <description>Repeated START (Sr) Condition Issuance</description>
                            <lsb>1</lsb>
                            <msb>1</msb>
                            <access>read-write</access>
                            <enumeratedValues>
                                <enumeratedValue>
                                    <name>0</name>
                                    <description>Does not request to issue a Repeated START condition.</description>
                                    <value>#0</value>
                                </enumeratedValue>
                                <enumeratedValue>
                                    <name>1</name>
                                    <description>Requests to issue a Repeated START condition.</description>
                                    <value>#1</value>
                                </enumeratedValue>
                            </enumeratedValues>
                        </field>
                        <field>
                            <name>SPCND</name>
                            <description>STOP (P) Condition Issuance</description>
                            <lsb>2</lsb>
                            <msb>2</msb>
                            <access>read-write</access>
                            <enumeratedValues>
                                <enumeratedValue>
                                    <name>0</name>
                                    <description>Does not request to issue a STOP condition.</description>
                                    <value>#0</value>
                                </enumeratedValue>
                                <enumeratedValue>
                                    <name>1</name>
                                    <description>Requests to issue a STOP condition.</description>
                                    <value>#1</value>
                                </enumeratedValue>
                            </enumeratedValues>
                        </field>
                    </fields>
                </register>
                <register>
                    <name>NCMDQP</name>
                    <description>Normal Command Queue Port Register</description>
                    <addressOffset>0x150</addressOffset>
                    <size>32</size>
                    <access>write-only</access>
                    <resetValue>0x00000000</resetValue>
                    <resetMask>0xffffffff</resetMask>
                </register>
                <register>
                    <name>NRSPQP</name>
                    <description>Normal Response Queue Port Register</description>
                    <addressOffset>0x154</addressOffset>
                    <size>32</size>
                    <access>read-only</access>
                    <resetValue>0x00000000</resetValue>
                    <resetMask>0xffffffff</resetMask>
                </register>
                <register>
                    <name>NTDTBP0</name>
                    <description>Normal Transfer Data Buffer Port Register 0</description>
                    <addressOffset>0x158</addressOffset>
                    <size>32</size>
                    <access>read-write</access>
                    <resetValue>0x00000000</resetValue>
                    <resetMask>0xffffffff</resetMask>
                </register>
                <register>
                    <name>NTDTBP0_BY</name>
                    <description>Normal Transfer Data Buffer Port Register 0</description>
                    <alternateRegister>NTDTBP0</alternateRegister>
                    <addressOffset>0x158</addressOffset>
                    <size>8</size>
                    <access>read-write</access>
                    <resetValue>0x00</resetValue>
                    <resetMask>0xff</resetMask>
                </register>
                <register>
                    <name>NIBIQP</name>
                    <description>Normal IBI Queue Port Register</description>
                    <addressOffset>0x17C</addressOffset>
                    <size>32</size>
                    <access>read-write</access>
                    <resetValue>0x00000000</resetValue>
                    <resetMask>0xffffffff</resetMask>
                </register>
                <register>
                    <name>NRSQP</name>
                    <description>Normal Receive Status Queue Port Register</description>
                    <addressOffset>0x180</addressOffset>
                    <size>32</size>
                    <access>read-only</access>
                    <resetValue>0x00000000</resetValue>
                    <resetMask>0xffffffff</resetMask>
                </register>
                <register>
                    <name>HCMDQP</name>
                    <description>High Priority Command Queue Port Register</description>
                    <addressOffset>0x184</addressOffset>
                    <size>32</size>
                    <access>write-only</access>
                    <resetValue>0x00000000</resetValue>
                    <resetMask>0xffffffff</resetMask>
                </register>
                <register>
                    <name>HRSPQP</name>
                    <description>High Priority Response Queue Port Register</description>
                    <addressOffset>0x188</addressOffset>
                    <size>32</size>
                    <access>read-only</access>
                    <resetValue>0x00000000</resetValue>
                    <resetMask>0xffffffff</resetMask>
                </register>
                <register>
                    <name>HTDTBP</name>
                    <description>High Priority Transfer Data Buffer Port Register</description>
                    <addressOffset>0x18C</addressOffset>
                    <size>32</size>
                    <access>read-write</access>
                    <resetValue>0x00000000</resetValue>
                    <resetMask>0xffffffff</resetMask>
                </register>
                <register>
                    <name>NQTHCTL</name>
                    <description>Normal Queue Threshold Control Register</description>
                    <addressOffset>0x190</addressOffset>
                    <size>32</size>
                    <access>read-write</access>
                    <resetValue>0x01010101</resetValue>
                    <resetMask>0xffffffff</resetMask>
                    <fields>
                        <field>
                            <name>CMDQTH</name>
                            <description>Normal Command Queue Threshold</description>
                            <lsb>0</lsb>
                            <msb>7</msb>
                            <access>read-write</access>
                            <enumeratedValues>
                                <enumeratedValue>
                                    <name>0x00</name>
                                    <description>Interrupt is issued when Normal Command Queue is completely empty.</description>
                                    <value>0x00</value>
                                </enumeratedValue>
                                <enumeratedValue>
                                    <name>Others</name>
                                    <description>Interrupt is issued when Normal Command Queue contains N empties. (N = CMDQTH[7:0])</description>
                                    <isDefault>true</isDefault>
                                </enumeratedValue>
                            </enumeratedValues>
                        </field>
                        <field>
                            <name>RSPQTH</name>
                            <description>Normal Response Queue Threshold</description>
                            <lsb>8</lsb>
                            <msb>15</msb>
                            <access>read-write</access>
                            <enumeratedValues>
                                <enumeratedValue>
                                    <name>0x00</name>
                                    <description>Interrupt is issued when Normal Response Queue contains 1 entry (DWORD).</description>
                                    <value>0x00</value>
                                </enumeratedValue>
                                <enumeratedValue>
                                    <name>Others</name>
                                    <description>Interrupt is triggered when Normal Response Queue contains N+1 entries (DWORD). (N = CMDQTH[7:0])</description>
                                    <isDefault>true</isDefault>
                                </enumeratedValue>
                            </enumeratedValues>
                        </field>
                        <field>
                            <name>IBIDSSZ</name>
                            <description>Normal IBI Data Segment Size</description>
                            <lsb>16</lsb>
                            <msb>23</msb>
                            <access>read-write</access>
                        </field>
                        <field>
                            <name>IBIQTH</name>
                            <description>Normal IBI Queue Threshold</description>
                            <lsb>24</lsb>
                            <msb>31</msb>
                            <access>read-write</access>
                            <enumeratedValues>
                                <enumeratedValue>
                                    <name>0x00</name>
                                    <description>I3C Protocol mode (Master): Interrupt is generated when the Outstanding IBI Status count is 1 or more. I3C Protocol mode (Slave): Interrupt is issued when IBI Data Buffer is completely empty. </description>
                                    <value>0x00</value>
                                </enumeratedValue>
                                <enumeratedValue>
                                    <name>Others</name>
                                    <description>I3C Protocol mode (Master): Interrupt is generated when the Outstanding IBI Status count is N + 1 or more. (N = CMDQTH[7:0]) I3C Protocol mode (Slave): Interrupt is issued when IBI Data Buffer contains N empties. </description>
                                    <isDefault>true</isDefault>
                                </enumeratedValue>
                            </enumeratedValues>
                        </field>
                    </fields>
                </register>
                <register>
                    <name>NTBTHCTL0</name>
                    <description>Normal Transfer Data Buffer Threshold Control Register 0</description>
                    <addressOffset>0x194</addressOffset>
                    <size>32</size>
                    <access>read-write</access>
                    <resetValue>0x01010101</resetValue>
                    <resetMask>0xffffffff</resetMask>
                    <fields>
                        <field>
                            <name>TXDBTH</name>
                            <description>Normal Tx Data Buffer Threshold</description>
                            <lsb>0</lsb>
                            <msb>2</msb>
                            <access>read-write</access>
                            <enumeratedValues>
                                <enumeratedValue>
                                    <name>000</name>
                                    <description>Interrupt triggers at 2 Tx Buffer empties, DWORDs</description>
                                    <value>#000</value>
                                </enumeratedValue>
                                <enumeratedValue>
                                    <name>001</name>
                                    <description>Interrupt triggers at 4 Tx Buffer empties, DWORDs</description>
                                    <value>#001</value>
                                </enumeratedValue>
                                <enumeratedValue>
                                    <name>010</name>
                                    <description>Interrupt triggers at 8 Tx Buffer empties, DWORDs</description>
                                    <value>#010</value>
                                </enumeratedValue>
                                <enumeratedValue>
                                    <name>011</name>
                                    <description>Interrupt triggers at 16 Tx Buffer empties, DWORDs</description>
                                    <value>#011</value>
                                </enumeratedValue>
                                <enumeratedValue>
                                    <name>Others</name>
                                    <description>Setting prohibited</description>
                                    <isDefault>true</isDefault>
                                </enumeratedValue>
                            </enumeratedValues>
                        </field>
                        <field>
                            <name>RXDBTH</name>
                            <description>Normal Rx Data Buffer Threshold</description>
                            <lsb>8</lsb>
                            <msb>10</msb>
                            <access>read-write</access>
                            <enumeratedValues>
                                <enumeratedValue>
                                    <name>000</name>
                                    <description>Interrupt triggers at 2 Rx Buffer entries, DWORDs</description>
                                    <value>#000</value>
                                </enumeratedValue>
                                <enumeratedValue>
                                    <name>001</name>
                                    <description>Interrupt triggers at 4 Rx Buffer entries, DWORDs</description>
                                    <value>#001</value>
                                </enumeratedValue>
                                <enumeratedValue>
                                    <name>010</name>
                                    <description>Interrupt triggers at 8 Rx Buffer entries, DWORDs</description>
                                    <value>#010</value>
                                </enumeratedValue>
                                <enumeratedValue>
                                    <name>011</name>
                                    <description>Interrupt triggers at 16 Rx Buffer entries, DWORDs</description>
                                    <value>#011</value>
                                </enumeratedValue>
                                <enumeratedValue>
                                    <name>Others</name>
                                    <description>Setting prohibited</description>
                                    <isDefault>true</isDefault>
                                </enumeratedValue>
                            </enumeratedValues>
                        </field>
                        <field>
                            <name>TXSTTH</name>
                            <description>Normal Tx Start Threshold</description>
                            <lsb>16</lsb>
                            <msb>18</msb>
                            <access>read-write</access>
                            <enumeratedValues>
                                <enumeratedValue>
                                    <name>000</name>
                                    <description>Wait for 2 entry DWORDs</description>
                                    <value>#000</value>
                                </enumeratedValue>
                                <enumeratedValue>
                                    <name>001</name>
                                    <description>Wait for 4 entry DWORDs</description>
                                    <value>#001</value>
                                </enumeratedValue>
                                <enumeratedValue>
                                    <name>010</name>
                                    <description>Wait for 8 entry DWORDs</description>
                                    <value>#010</value>
                                </enumeratedValue>
                                <enumeratedValue>
                                    <name>011</name>
                                    <description>Wait for 16 entry DWORDs</description>
                                    <value>#011</value>
                                </enumeratedValue>
                                <enumeratedValue>
                                    <name>Others</name>
                                    <description>Setting prohibited</description>
                                    <isDefault>true</isDefault>
                                </enumeratedValue>
                            </enumeratedValues>
                        </field>
                        <field>
                            <name>RXSTTH</name>
                            <description>Normal Rx Start Threshold</description>
                            <lsb>24</lsb>
                            <msb>26</msb>
                            <access>read-write</access>
                            <enumeratedValues>
                                <enumeratedValue>
                                    <name>000</name>
                                    <description>Wait for 2 empty DWORDs</description>
                                    <value>#000</value>
                                </enumeratedValue>
                                <enumeratedValue>
                                    <name>001</name>
                                    <description>Wait for 4 empty DWORDs</description>
                                    <value>#001</value>
                                </enumeratedValue>
                                <enumeratedValue>
                                    <name>010</name>
                                    <description>Wait for 8 empty DWORDs</description>
                                    <value>#010</value>
                                </enumeratedValue>
                                <enumeratedValue>
                                    <name>011</name>
                                    <description>Wait for 16 empty DWORDs</description>
                                    <value>#011</value>
                                </enumeratedValue>
                                <enumeratedValue>
                                    <name>Others</name>
                                    <description>Setting prohibited</description>
                                    <isDefault>true</isDefault>
                                </enumeratedValue>
                            </enumeratedValues>
                        </field>
                    </fields>
                </register>
                <register>
                    <name>NRQTHCTL</name>
                    <description>Normal Receive Status Queue Threshold Control Register</description>
                    <addressOffset>0x1C0</addressOffset>
                    <size>32</size>
                    <access>read-write</access>
                    <resetValue>0x00000001</resetValue>
                    <resetMask>0xffffffff</resetMask>
                    <fields>
                        <field>
                            <name>RSQTH</name>
                            <description>Normal Receive Status Queue Threshold</description>
                            <lsb>0</lsb>
                            <msb>7</msb>
                            <access>read-write</access>
                            <enumeratedValues>
                                <enumeratedValue>
                                    <name>0x00</name>
                                    <description>Interrupt is issued when Normal Receive Status Queue contains 1 entry (DWORD).</description>
                                    <value>0x00</value>
                                </enumeratedValue>
                                <enumeratedValue>
                                    <name>Others</name>
                                    <description>Interrupt is triggered when Normal Receive Status Queue contains N+1 entries (DWORD). (N = RSQTH[7:0])</description>
                                    <isDefault>true</isDefault>
                                </enumeratedValue>
                            </enumeratedValues>
                        </field>
                    </fields>
                </register>
                <register>
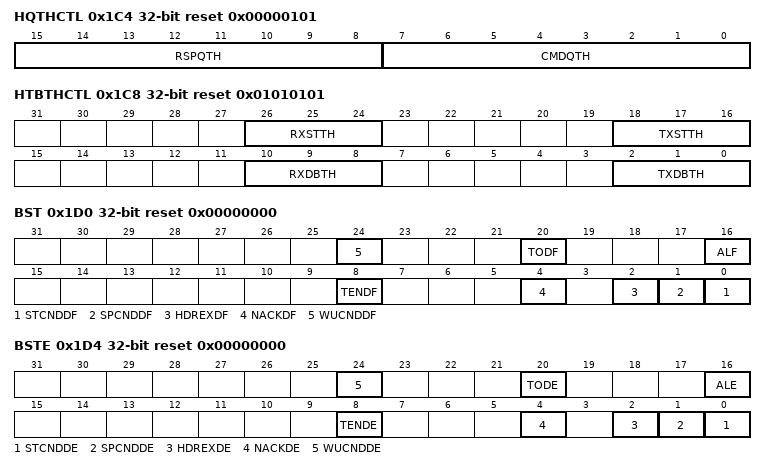
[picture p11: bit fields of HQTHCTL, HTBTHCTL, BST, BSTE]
                    <name>HQTHCTL</name>
                    <description>High Priority Queue Threshold Control Register</description>
                    <addressOffset>0x1C4</addressOffset>
                    <size>32</size>
                    <access>read-write</access>
                    <resetValue>0x00000101</resetValue>
                    <resetMask>0xffffffff</resetMask>
                    <fields>
                        <field>
                            <name>CMDQTH</name>
                            <description>High Priority Command Queue Threshold</description>
                            <lsb>0</lsb>
                            <msb>7</msb>
                            <access>read-write</access>
                            <enumeratedValues>
                                <enumeratedValue>
                                    <name>0x00</name>
                                    <description>Interrupt is issued when High Priority Command Queue is completely empty.</description>
                                    <value>0x00</value>
                                </enumeratedValue>
                                <enumeratedValue>
                                    <name>Others</name>
                                    <description>Interrupt is issued when High Priority Command Queue contains N entries. (N = CMDQTH[7:0])</description>
                                    <isDefault>true</isDefault>
                                </enumeratedValue>
                            </enumeratedValues>
                        </field>
                        <field>
                            <name>RSPQTH</name>
                            <description>High Priority Response Queue Threshold</description>
                            <lsb>8</lsb>
                            <msb>15</msb>
                            <access>read-write</access>
                            <enumeratedValues>
                                <enumeratedValue>
                                    <name>0x00</name>
                                    <description>Interrupt is issued when High Priority Response Queue contains 1 entry (DWORD).</description>
                                    <value>0x00</value>
                                </enumeratedValue>
                                <enumeratedValue>
                                    <name>Others</name>
                                    <description>Interrupt is triggered when High Priority Response Queue contains N+1 entries (DWORD). (N = RSPQTH[7:0])</description>
                                    <isDefault>true</isDefault>
                                </enumeratedValue>
                            </enumeratedValues>
                        </field>
                    </fields>
                </register>
                <register>
                    <name>HTBTHCTL</name>
                    <description>High Priority Transfer Data Buffer Threshold Control Register</description>
                    <addressOffset>0x1C8</addressOffset>
                    <size>32</size>
                    <access>read-write</access>
                    <resetValue>0x01010101</resetValue>
                    <resetMask>0xffffffff</resetMask>
                    <fields>
                        <field>
                            <name>TXDBTH</name>
                            <description>High Priority Tx Data Buffer Threshold</description>
                            <lsb>0</lsb>
                            <msb>2</msb>
                            <access>read-write</access>
                            <enumeratedValues>
                                <enumeratedValue>
                                    <name>000</name>
                                    <description>Interrupt triggers at 2 High Priority Tx Buffer empties, DWORDs</description>
                                    <value>#000</value>
                                </enumeratedValue>
                                <enumeratedValue>
                                    <name>001</name>
                                    <description>Reserved</description>
                                    <value>#001</value>
                                </enumeratedValue>
                                <enumeratedValue>
                                    <name>Others</name>
                                    <description>Setting prohibited</description>
                                    <isDefault>true</isDefault>
                                </enumeratedValue>
                            </enumeratedValues>
                        </field>
                        <field>
                            <name>RXDBTH</name>
                            <description>High Priority Rx Data Buffer Threshold</description>
                            <lsb>8</lsb>
                            <msb>10</msb>
                            <access>read-write</access>
                            <enumeratedValues>
                                <enumeratedValue>
                                    <name>000</name>
                                    <description>Interrupt triggers at 2 High Priority Rx Buffer entries, DWORDs</description>
                                    <value>#000</value>
                                </enumeratedValue>
                                <enumeratedValue>
                                    <name>001</name>
                                    <description>Reserved</description>
                                    <value>#001</value>
                                </enumeratedValue>
                                <enumeratedValue>
                                    <name>Others</name>
                                    <description>Setting prohibited</description>
                                    <isDefault>true</isDefault>
                                </enumeratedValue>
                            </enumeratedValues>
                        </field>
                        <field>
                            <name>TXSTTH</name>
                            <description>High Priority Tx Start Threshold</description>
                            <lsb>16</lsb>
                            <msb>18</msb>
                            <access>read-write</access>
                            <enumeratedValues>
                                <enumeratedValue>
                                    <name>000</name>
                                    <description>Wait for 2 entry DWORDs</description>
                                    <value>#000</value>
                                </enumeratedValue>
                                <enumeratedValue>
                                    <name>001</name>
                                    <description>Reserved</description>
                                    <value>#001</value>
                                </enumeratedValue>
                                <enumeratedValue>
                                    <name>Others</name>
                                    <description>Setting prohibited</description>
                                    <isDefault>true</isDefault>
                                </enumeratedValue>
                            </enumeratedValues>
                        </field>
                        <field>
                            <name>RXSTTH</name>
                            <description>High Priority Rx Start Threshold</description>
                            <lsb>24</lsb>
                            <msb>26</msb>
                            <access>read-write</access>
                            <enumeratedValues>
                                <enumeratedValue>
                                    <name>000</name>
                                    <description>Wait for 2 empty DWORDs</description>
                                    <value>#000</value>
                                </enumeratedValue>
                                <enumeratedValue>
                                    <name>001</name>
                                    <description>Reserved</description>
                                    <value>#001</value>
                                </enumeratedValue>
                                <enumeratedValue>
                                    <name>Others</name>
                                    <description>Setting prohibited</description>
                                    <isDefault>true</isDefault>
                                </enumeratedValue>
                            </enumeratedValues>
                        </field>
                    </fields>
                </register>
                <register>
                    <name>BST</name>
                    <description>Bus Status Register</description>
                    <addressOffset>0x1D0</addressOffset>
                    <size>32</size>
                    <access>read-write</access>
                    <resetValue>0x00000000</resetValue>
                    <resetMask>0xffffffff</resetMask>
                    <fields>
                        <field>
                            <name>STCNDDF</name>
                            <description>START Condition Detection Flag</description>
                            <lsb>0</lsb>
                            <msb>0</msb>
                            <access>read-write</access>
                            <enumeratedValues>
                                <enumeratedValue>
                                    <name>0</name>
                                    <description>START condition is not detected.</description>
                                    <value>#0</value>
                                </enumeratedValue>
                                <enumeratedValue>
                                    <name>1</name>
                                    <description>START condition is detected.</description>
                                    <value>#1</value>
                                </enumeratedValue>
                            </enumeratedValues>
                        </field>
                        <field>
                            <name>SPCNDDF</name>
                            <description>STOP Condition Detection Flag</description>
                            <lsb>1</lsb>
                            <msb>1</msb>
                            <access>read-write</access>
                            <enumeratedValues>
                                <enumeratedValue>
                                    <name>0</name>
                                    <description>STOP condition is not detected.</description>
                                    <value>#0</value>
                                </enumeratedValue>
                                <enumeratedValue>
                                    <name>1</name>
                                    <description>STOP condition is detected.</description>
                                    <value>#1</value>
                                </enumeratedValue>
                            </enumeratedValues>
                        </field>
                        <field>
                            <name>HDREXDF</name>
                            <description>HDR Exit Pattern Detection Flag</description>
                            <lsb>2</lsb>
                            <msb>2</msb>
                            <access>read-write</access>
                            <enumeratedValues>
                                <enumeratedValue>
                                    <name>0</name>
                                    <description>HDR Exit Pattern is not detected</description>
                                    <value>#0</value>
                                </enumeratedValue>
                                <enumeratedValue>
                                    <name>1</name>
                                    <description>HDR Exit Pattern is detected.</description>
                                    <value>#1</value>
                                </enumeratedValue>
                            </enumeratedValues>
                        </field>
                        <field>
                            <name>NACKDF</name>
                            <description>NACK Detection Flag</description>
                            <lsb>4</lsb>
                            <msb>4</msb>
                            <access>read-write</access>
                            <enumeratedValues>
                                <enumeratedValue>
                                    <name>0</name>
                                    <description>NACK is not detected.</description>
                                    <value>#0</value>
                                </enumeratedValue>
                                <enumeratedValue>
                                    <name>1</name>
                                    <description>NACK is detected.</description>
                                    <value>#1</value>
                                </enumeratedValue>
                            </enumeratedValues>
                        </field>
                        <field>
                            <name>TENDF</name>
                            <description>Transmit End Flag</description>
                            <lsb>8</lsb>
                            <msb>8</msb>
                            <access>read-write</access>
                            <enumeratedValues>
                                <enumeratedValue>
                                    <name>0</name>
                                    <description>Data is being transmitted.</description>
                                    <value>#0</value>
                                </enumeratedValue>
                                <enumeratedValue>
                                    <name>1</name>
                                    <description>Data has been transmitted.</description>
                                    <value>#1</value>
                                </enumeratedValue>
                            </enumeratedValues>
                        </field>
                        <field>
                            <name>ALF</name>
                            <description>Arbitration Lost Flag</description>
                            <lsb>16</lsb>
                            <msb>16</msb>
                            <access>read-write</access>
                            <enumeratedValues>
                                <enumeratedValue>
                                    <name>0</name>
                                    <description>Arbitration is not lost</description>
                                    <value>#0</value>
                                </enumeratedValue>
                                <enumeratedValue>
                                    <name>1</name>
                                    <description>Arbitration is lost.</description>
                                    <value>#1</value>
                                </enumeratedValue>
                            </enumeratedValues>
                        </field>
                        <field>
                            <name>TODF</name>
                            <description>Timeout Detection Flag</description>
                            <lsb>20</lsb>
                            <msb>20</msb>
                            <access>read-write</access>
                            <enumeratedValues>
                                <enumeratedValue>
                                    <name>0</name>
                                    <description>Timeout is not detected.</description>
                                    <value>#0</value>
                                </enumeratedValue>
                                <enumeratedValue>
                                    <name>1</name>
                                    <description>Timeout is detected.</description>
                                    <value>#1</value>
                                </enumeratedValue>
                            </enumeratedValues>
                        </field>
                        <field>
                            <name>WUCNDDF</name>
                            <description>Wake-Up Condition Detection Flag</description>
                            <lsb>24</lsb>
                            <msb>24</msb>
                            <access>read-write</access>
                            <enumeratedValues>
                                <enumeratedValue>
                                    <name>0</name>
                                    <description>Wake-Up is not detected.</description>
                                    <value>#0</value>
                                </enumeratedValue>
                                <enumeratedValue>
                                    <name>1</name>
                                    <description>Wake-Up is detected.</description>
                                    <value>#1</value>
                                </enumeratedValue>
                            </enumeratedValues>
                        </field>
                    </fields>
                </register>
                <register>
                    <name>BSTE</name>
                    <description>Bus Status Enable Register</description>
                    <addressOffset>0x1D4</addressOffset>
                    <size>32</size>
                    <access>read-write</access>
                    <resetValue>0x00000000</resetValue>
                    <resetMask>0xffffffff</resetMask>
                    <fields>
                        <field>
                            <name>STCNDDE</name>
                            <description>START Condition Detection Enable</description>
                            <lsb>0</lsb>
                            <msb>0</msb>
                            <access>read-write</access>
                            <enumeratedValues>
                                <enumeratedValue>
                                    <name>0</name>
                                    <description>Disables START condition Detection Interrupt Status logging.</description>
                                    <value>#0</value>
                                </enumeratedValue>
                                <enumeratedValue>
                                    <name>1</name>
                                    <description>Enables START condition Detection Interrupt Status logging.</description>
                                    <value>#1</value>
                                </enumeratedValue>
                            </enumeratedValues>
                        </field>
                        <field>
                            <name>SPCNDDE</name>
                            <description>STOP Condition Detection Enable</description>
                            <lsb>1</lsb>
                            <msb>1</msb>
                            <access>read-write</access>
                            <enumeratedValues>
                                <enumeratedValue>
                                    <name>0</name>
                                    <description>Disables STOP condition Detection Interrupt Status logging.</description>
                                    <value>#0</value>
                                </enumeratedValue>
                                <enumeratedValue>
                                    <name>1</name>
                                    <description>Enables STOP condition Detection Interrupt Status logging.</description>
                                    <value>#1</value>
                                </enumeratedValue>
                            </enumeratedValues>
                        </field>
                        <field>
                            <name>HDREXDE</name>
                            <description>HDR Exit Pattern Detection Enable</description>
                            <lsb>2</lsb>
                            <msb>2</msb>
                            <access>read-write</access>
                            <enumeratedValues>
                                <enumeratedValue>
                                    <name>0</name>
                                    <description>Disables HDR Exit Pattern Detection Interrupt Status logging.</description>
                                    <value>#0</value>
                                </enumeratedValue>
                                <enumeratedValue>
                                    <name>1</name>
                                    <description>Enables HDR Exit Pattern Detection Interrupt Status logging.</description>
                                    <value>#1</value>
                                </enumeratedValue>
                            </enumeratedValues>
                        </field>
                        <field>
                            <name>NACKDE</name>
                            <description>NACK Detection Enable</description>
                            <lsb>4</lsb>
                            <msb>4</msb>
                            <access>read-write</access>
                            <enumeratedValues>
                                <enumeratedValue>
                                    <name>0</name>
                                    <description>Disables NACK Detection Interrupt Status logging.</description>
                                    <value>#0</value>
                                </enumeratedValue>
                                <enumeratedValue>
                                    <name>1</name>
                                    <description>Enables NACK Detection Interrupt Status logging.</description>
                                    <value>#1</value>
                                </enumeratedValue>
                            </enumeratedValues>
                        </field>
                        <field>
                            <name>TENDE</name>
                            <description>Transmit End Enable</description>
                            <lsb>8</lsb>
                            <msb>8</msb>
                            <access>read-write</access>
                            <enumeratedValues>
                                <enumeratedValue>
                                    <name>0</name>
                                    <description>Disables Transmit End Interrupt Status logging.</description>
                                    <value>#0</value>
                                </enumeratedValue>
                                <enumeratedValue>
                                    <name>1</name>
                                    <description>Enables Transmit End Interrupt Status logging.</description>
                                    <value>#1</value>
                                </enumeratedValue>
                            </enumeratedValues>
                        </field>
                        <field>
                            <name>ALE</name>
                            <description>Arbitration Lost Enable</description>
                            <lsb>16</lsb>
                            <msb>16</msb>
                            <access>read-write</access>
                            <enumeratedValues>
                                <enumeratedValue>
                                    <name>0</name>
                                    <description>Disables Arbitration Lost Interrupt Status logging.</description>
                                    <value>#0</value>
                                </enumeratedValue>
                                <enumeratedValue>
                                    <name>1</name>
                                    <description>Enables Arbitration Lost Interrupt Status logging.</description>
                                    <value>#1</value>
                                </enumeratedValue>
                            </enumeratedValues>
                        </field>
                        <field>
                            <name>TODE</name>
                            <description>Timeout Detection Enable</description>
                            <lsb>20</lsb>
                            <msb>20</msb>
                            <access>read-write</access>
                            <enumeratedValues>
                                <enumeratedValue>
                                    <name>0</name>
                                    <description>Disables Timeout Detection Interrupt Status logging.</description>
                                    <value>#0</value>
                                </enumeratedValue>
                                <enumeratedValue>
                                    <name>1</name>
                                    <description>Enables Timeout Detection Interrupt Status logging.</description>
                                    <value>#1</value>
                                </enumeratedValue>
                            </enumeratedValues>
                        </field>
                        <field>
                            <name>WUCNDDE</name>
                            <description>Wake-up Condition Detection Enable</description>
                            <lsb>24</lsb>
                            <msb>24</msb>
                            <access>read-write</access>
                            <enumeratedValues>
                                <enumeratedValue>
                                    <name>0</name>
                                    <description>Disables Wake-up Condition Detection Status logging.</description>
                                    <value>#0</value>
                                </enumeratedValue>
                                <enumeratedValue>
                                    <name>1</name>
                                    <description>Enables Wake-up Condition Detection Status logging.</description>
                                    <value>#1</value>
                                </enumeratedValue>
                            </enumeratedValues>
                        </field>
                    </fields>
                </register>
                <register>
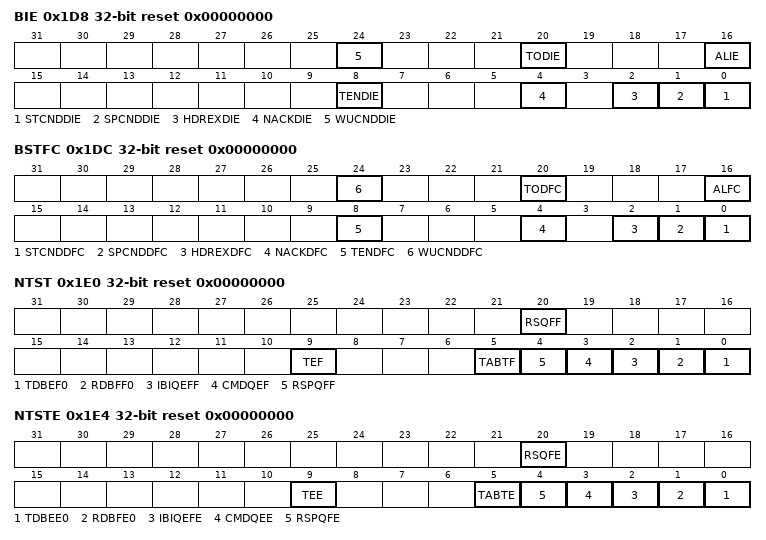
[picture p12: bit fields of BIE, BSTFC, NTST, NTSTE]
                    <name>BIE</name>
                    <description>Bus Interrupt Enable Register</description>
                    <addressOffset>0x1D8</addressOffset>
                    <size>32</size>
                    <access>read-write</access>
                    <resetValue>0x00000000</resetValue>
                    <resetMask>0xffffffff</resetMask>
                    <fields>
                        <field>
                            <name>STCNDDIE</name>
                            <description>START Condition Detection Interrupt Enable</description>
                            <lsb>0</lsb>
                            <msb>0</msb>
                            <access>read-write</access>
                            <enumeratedValues>
                                <enumeratedValue>
                                    <name>0</name>
                                    <description>Disables START condition Detection Interrupt Signal.</description>
                                    <value>#0</value>
                                </enumeratedValue>
                                <enumeratedValue>
                                    <name>1</name>
                                    <description>Enables START condition Detection Interrupt Signal.</description>
                                    <value>#1</value>
                                </enumeratedValue>
                            </enumeratedValues>
                        </field>
                        <field>
                            <name>SPCNDDIE</name>
                            <description>STOP Condition Detection Interrupt Enable</description>
                            <lsb>1</lsb>
                            <msb>1</msb>
                            <access>read-write</access>
                            <enumeratedValues>
                                <enumeratedValue>
                                    <name>0</name>
                                    <description>Disables STOP condition Detection Interrupt Signal.</description>
                                    <value>#0</value>
                                </enumeratedValue>
                                <enumeratedValue>
                                    <name>1</name>
                                    <description>Enables STOP condition Detection Interrupt Signal.</description>
                                    <value>#1</value>
                                </enumeratedValue>
                            </enumeratedValues>
                        </field>
                        <field>
                            <name>HDREXDIE</name>
                            <description>HDR Exit Pattern Detection Interrupt Enable</description>
                            <lsb>2</lsb>
                            <msb>2</msb>
                            <access>read-write</access>
                            <enumeratedValues>
                                <enumeratedValue>
                                    <name>0</name>
                                    <description>Disables HDR Exit Pattern Detection Interrupt Signal.</description>
                                    <value>#0</value>
                                </enumeratedValue>
                                <enumeratedValue>
                                    <name>1</name>
                                    <description>Enables HDR Exit Pattern Detection Interrupt Signal.</description>
                                    <value>#1</value>
                                </enumeratedValue>
                            </enumeratedValues>
                        </field>
                        <field>
                            <name>NACKDIE</name>
                            <description>NACK Detection Interrupt Enable</description>
                            <lsb>4</lsb>
                            <msb>4</msb>
                            <access>read-write</access>
                            <enumeratedValues>
                                <enumeratedValue>
                                    <name>0</name>
                                    <description>Disables NACK Detection Interrupt Signal.</description>
                                    <value>#0</value>
                                </enumeratedValue>
                                <enumeratedValue>
                                    <name>1</name>
                                    <description>Enables NACK Detection Interrupt Signal.</description>
                                    <value>#1</value>
                                </enumeratedValue>
                            </enumeratedValues>
                        </field>
                        <field>
                            <name>TENDIE</name>
                            <description>Transmit End Interrupt Enable</description>
                            <lsb>8</lsb>
                            <msb>8</msb>
                            <access>read-write</access>
                            <enumeratedValues>
                                <enumeratedValue>
                                    <name>0</name>
                                    <description>Disables Transmit End Interrupt Signal.</description>
                                    <value>#0</value>
                                </enumeratedValue>
                                <enumeratedValue>
                                    <name>1</name>
                                    <description>Enables Transmit End Interrupt Signal.</description>
                                    <value>#1</value>
                                </enumeratedValue>
                            </enumeratedValues>
                        </field>
                        <field>
                            <name>ALIE</name>
                            <description>Arbitration Lost Interrupt Enable</description>
                            <lsb>16</lsb>
                            <msb>16</msb>
                            <access>read-write</access>
                            <enumeratedValues>
                                <enumeratedValue>
                                    <name>0</name>
                                    <description>Disables Arbitration Lost Interrupt Signal.</description>
                                    <value>#0</value>
                                </enumeratedValue>
                                <enumeratedValue>
                                    <name>1</name>
                                    <description>Enables Arbitration Lost Interrupt Signal.</description>
                                    <value>#1</value>
                                </enumeratedValue>
                            </enumeratedValues>
                        </field>
                        <field>
                            <name>TODIE</name>
                            <description>Timeout Detection Interrupt Enable</description>
                            <lsb>20</lsb>
                            <msb>20</msb>
                            <access>read-write</access>
                            <enumeratedValues>
                                <enumeratedValue>
                                    <name>0</name>
                                    <description>Disables Timeout Detection Interrupt Signal.</description>
                                    <value>#0</value>
                                </enumeratedValue>
                                <enumeratedValue>
                                    <name>1</name>
                                    <description>Enables Timeout Detection Interrupt Signal.</description>
                                    <value>#1</value>
                                </enumeratedValue>
                            </enumeratedValues>
                        </field>
                        <field>
                            <name>WUCNDDIE</name>
                            <description>Wake-Up Condition Detection Interrupt Enable</description>
                            <lsb>24</lsb>
                            <msb>24</msb>
                            <access>read-write</access>
                            <enumeratedValues>
                                <enumeratedValue>
                                    <name>0</name>
                                    <description>Disables Wake-Up Condition Detection Interrupt Signal.</description>
                                    <value>#0</value>
                                </enumeratedValue>
                                <enumeratedValue>
                                    <name>1</name>
                                    <description>Enables Wake-Up Condition Detection Interrupt Signal.</description>
                                    <value>#1</value>
                                </enumeratedValue>
                            </enumeratedValues>
                        </field>
                    </fields>
                </register>
                <register>
                    <name>BSTFC</name>
                    <description>Bus Status Force Register</description>
                    <addressOffset>0x1DC</addressOffset>
                    <size>32</size>
                    <access>read-write</access>
                    <resetValue>0x00000000</resetValue>
                    <resetMask>0xffffffff</resetMask>
                    <fields>
                        <field>
                            <name>STCNDDFC</name>
                            <description>START condition Detection Force</description>
                            <lsb>0</lsb>
                            <msb>0</msb>
                            <access>write-only</access>
                            <enumeratedValues>
                                <enumeratedValue>
                                    <name>0</name>
                                    <description>Not Force START condition Detection Interrupt for software testing.</description>
                                    <value>#0</value>
                                </enumeratedValue>
                                <enumeratedValue>
                                    <name>1</name>
                                    <description>Force START condition Detection Interrupt for software testing.</description>
                                    <value>#1</value>
                                </enumeratedValue>
                            </enumeratedValues>
                        </field>
                        <field>
                            <name>SPCNDDFC</name>
                            <description>STOP condition Detection Force</description>
                            <lsb>1</lsb>
                            <msb>1</msb>
                            <access>write-only</access>
                            <enumeratedValues>
                                <enumeratedValue>
                                    <name>0</name>
                                    <description>Not Force STOP condition Detection Interrupt for software testing.</description>
                                    <value>#0</value>
                                </enumeratedValue>
                                <enumeratedValue>
                                    <name>1</name>
                                    <description>Force STOP condition Detection Interrupt for software testing.</description>
                                    <value>#1</value>
                                </enumeratedValue>
                            </enumeratedValues>
                        </field>
                        <field>
                            <name>HDREXDFC</name>
                            <description>HDR Exit Pattern Detection Force</description>
                            <lsb>2</lsb>
                            <msb>2</msb>
                            <access>write-only</access>
                            <enumeratedValues>
                                <enumeratedValue>
                                    <name>0</name>
                                    <description>Not Force HDR Exit Pattern Detection Interrupt for software testing.</description>
                                    <value>#0</value>
                                </enumeratedValue>
                                <enumeratedValue>
                                    <name>1</name>
                                    <description>Force HDR Exit Pattern Detection Interrupt for software testing.</description>
                                    <value>#1</value>
                                </enumeratedValue>
                            </enumeratedValues>
                        </field>
                        <field>
                            <name>NACKDFC</name>
                            <description>NACK Detection Force</description>
                            <lsb>4</lsb>
                            <msb>4</msb>
                            <access>write-only</access>
                            <enumeratedValues>
                                <enumeratedValue>
                                    <name>0</name>
                                    <description>Not Force NACK Detection Interrupt for software testing.</description>
                                    <value>#0</value>
                                </enumeratedValue>
                                <enumeratedValue>
                                    <name>1</name>
                                    <description>Force NACK Detection Interrupt for software testing.</description>
                                    <value>#1</value>
                                </enumeratedValue>
                            </enumeratedValues>
                        </field>
                        <field>
                            <name>TENDFC</name>
                            <description>Transmit End Force</description>
                            <lsb>8</lsb>
                            <msb>8</msb>
                            <access>write-only</access>
                            <enumeratedValues>
                                <enumeratedValue>
                                    <name>0</name>
                                    <description>Not Force Transmit End Interrupt for software testing.</description>
                                    <value>#0</value>
                                </enumeratedValue>
                                <enumeratedValue>
                                    <name>1</name>
                                    <description>Force Transmit End Interrupt for software testing.</description>
                                    <value>#1</value>
                                </enumeratedValue>
                            </enumeratedValues>
                        </field>
                        <field>
                            <name>ALFC</name>
                            <description>Arbitration Lost Force</description>
                            <lsb>16</lsb>
                            <msb>16</msb>
                            <access>write-only</access>
                            <enumeratedValues>
                                <enumeratedValue>
                                    <name>0</name>
                                    <description>Not Force Arbitration Lost Interrupt for software testing.</description>
                                    <value>#0</value>
                                </enumeratedValue>
                                <enumeratedValue>
                                    <name>1</name>
                                    <description>Force Arbitration Lost Interrupt for software testing.</description>
                                    <value>#1</value>
                                </enumeratedValue>
                            </enumeratedValues>
                        </field>
                        <field>
                            <name>TODFC</name>
                            <description>Timeout Detection Force</description>
                            <lsb>20</lsb>
                            <msb>20</msb>
                            <access>write-only</access>
                            <enumeratedValues>
                                <enumeratedValue>
                                    <name>0</name>
                                    <description>Not Force Timeout Detection Interrupt for software testing.</description>
                                    <value>#0</value>
                                </enumeratedValue>
                                <enumeratedValue>
                                    <name>1</name>
                                    <description>Force Timeout Detection Interrupt for software testing.</description>
                                    <value>#1</value>
                                </enumeratedValue>
                            </enumeratedValues>
                        </field>
                        <field>
                            <name>WUCNDDFC</name>
                            <description>Wake-Up Condition Detection Force</description>
                            <lsb>24</lsb>
                            <msb>24</msb>
                            <access>write-only</access>
                            <enumeratedValues>
                                <enumeratedValue>
                                    <name>0</name>
                                    <description>Not Force Wake-Up Condition Detection Interrupt for software testing.</description>
                                    <value>#0</value>
                                </enumeratedValue>
                                <enumeratedValue>
                                    <name>1</name>
                                    <description>Force Wake-Up Condition Detection Interrupt for software testing.</description>
                                    <value>#1</value>
                                </enumeratedValue>
                            </enumeratedValues>
                        </field>
                    </fields>
                </register>
                <register>
                    <name>NTST</name>
                    <description>Normal Transfer Status Register</description>
                    <addressOffset>0x1E0</addressOffset>
                    <size>32</size>
                    <access>read-write</access>
                    <resetValue>0x00000000</resetValue>
                    <resetMask>0xffffffff</resetMask>
                    <fields>
                        <field>
                            <name>TDBEF0</name>
                            <description>Normal Tx Data Buffer Empty Flag 0</description>
                            <lsb>0</lsb>
                            <msb>0</msb>
                            <access>read-write</access>
                            <enumeratedValues>
                                <enumeratedValue>
                                    <name>0</name>
                                    <description>For I2C protocol mode: PRTS.PRTMD bit = 1. Normal Tx Data Buffer contains transmit data. For I3C protocol mode: PRTS.PRTMD bit = 0. The number of empties in the Normal Tx Data Buffer is less than the NTBTHCTL0.TXDBTH[2:0] threshold. </description>
                                    <value>#0</value>
                                </enumeratedValue>
                                <enumeratedValue>
                                    <name>1</name>
                                    <description>For I2C protocol mode: PRTS.PRTMD bit = 1. Normal Tx Data Buffer contains no transmit data. For I3C protocol mode: PRTS.PRTMD bit = 0. The number of empties in the Normal Tx Data Buffer is the NTBTHCTL0.TXDBTH[2:0] threshold or more. </description>
                                    <value>#1</value>
                                </enumeratedValue>
                            </enumeratedValues>
                        </field>
                        <field>
                            <name>RDBFF0</name>
                            <description>Normal Rx Data Buffer Full Flag 0</description>
                            <lsb>1</lsb>
                            <msb>1</msb>
                            <access>read-write</access>
                            <enumeratedValues>
                                <enumeratedValue>
                                    <name>0</name>
                                    <description>For I2C protocol mode: PRTS.PRTMD bit = 1. Normal Rx Data Buffer contains no receive data. For I3C Protocol mode: PRTS.PRTMD bit = 0. The number of entries in the Normal Rx Data Buffer is less than the NTBTHCTL0.RXDBTH[2:0] threshold. </description>
                                    <value>#0</value>
                                </enumeratedValue>
                                <enumeratedValue>
                                    <name>1</name>
                                    <description>For I2C protocol mode: PRTS.PRTMD bit = 1. Normal Rx Data Buffer contains receive data. For I3C Protocol mode: PRTS.PRTMD bit = 0. The number of entries in the Normal Rx Data Buffer is the NTBTHCTL0.RXDBTH[2:0] threshold or more. </description>
                                    <value>#1</value>
                                </enumeratedValue>
                            </enumeratedValues>
                        </field>
                        <field>
                            <name>IBIQEFF</name>
                            <description>Normal IBI Queue Empty/Full Flag</description>
                            <lsb>2</lsb>
                            <msb>2</msb>
                            <access>read-write</access>
                            <enumeratedValues>
                                <enumeratedValue>
                                    <name>0</name>
                                    <description>For I3C protocol mode (Master): PRTS.PRTMD bit = 0, PRSST.CRMS bit = 1. The number of Normal IBI Queue entries is the NQTHCTL.IBIQTH threshold or less. For I3C protocol mode (Slave) : PRTS.PRTMD bit = 0, PRSST.CRMS bit = 0. If the NQTHCTL.IBIQTH = 0: The number of IBI Data Buffer empties is less than the IBI Data Buffer size. If the NQTHCTL.IBIQTH is other than 0: The number of IBI Data Buffer empties is less than the NQTHCTL.IBIQTH threshold. </description>
                                    <value>#0</value>
                                </enumeratedValue>
                                <enumeratedValue>
                                    <name>1</name>
                                    <description>For I3C protocol mode (Master): PRTS.PRTMD bit = 0, PRSST.CRMS bit = 1. The number of Normal IBI Queue entries is more than the NQTHCTL.IBIQTH threshold. For I3C protocol mode (Slave) : PRTS.PRTMD bit = 0, PRSST.CRMS bit = 0. If the NQTHCTL.IBIQTH = 0: The number of IBI Data Buffer empties is the IBI Data Buffer size. If the NQTHCTL.IBIQTH is other than 0: The number of IBI Data Buffer empties is the NQTHCTL.IBIQTH threshold or more. </description>
                                    <value>#1</value>
                                </enumeratedValue>
                            </enumeratedValues>
                        </field>
                        <field>
                            <name>CMDQEF</name>
                            <description>Normal Command Queue Empty Flag</description>
                            <lsb>3</lsb>
                            <msb>3</msb>
                            <access>read-write</access>
                            <enumeratedValues>
                                <enumeratedValue>
                                    <name>0</name>
                                    <description>If the NQTHCTL.CMDQTH = 0: The number of Normal Command Queue empties is less than the Normal Command Queue size. If the NQTHCTL.CMDQTH is other than 0: The number of Normal Command Queue empties is less than the NQTHCTL.CMDQTH threshold. </description>
                                    <value>#0</value>
                                </enumeratedValue>
                                <enumeratedValue>
                                    <name>1</name>
                                    <description>If the NQTHCTL.CMDQTH = 0: The number of Normal Command Queue empties is the Normal Command Queue size. If the NQTHCTL.CMDQTH is other than 0: 1: The number of Normal Command Queue empties is the NQTHCTL.CMDQTH threshold or more. </description>
                                    <value>#1</value>
                                </enumeratedValue>
                            </enumeratedValues>
                        </field>
                        <field>
                            <name>RSPQFF</name>
                            <description>Normal Response Queue Full Flag</description>
                            <lsb>4</lsb>
                            <msb>4</msb>
                            <access>read-write</access>
                            <enumeratedValues>
                                <enumeratedValue>
                                    <name>0</name>
                                    <description>The number of Normal Response Queue entries is the NQTHCTL.RSPQTH threshold or less.</description>
                                    <value>#0</value>
                                </enumeratedValue>
                                <enumeratedValue>
                                    <name>1</name>
                                    <description>The number of Normal Response Queue entries is more than the NQTHCTL.RSPQTH threshold.</description>
                                    <value>#1</value>
                                </enumeratedValue>
                            </enumeratedValues>
                        </field>
                        <field>
                            <name>TABTF</name>
                            <description>Normal Transfer Abort Flag</description>
                            <lsb>5</lsb>
                            <msb>5</msb>
                            <access>read-write</access>
                            <enumeratedValues>
                                <enumeratedValue>
                                    <name>0</name>
                                    <description>Normal Transfer Abort does not occur.</description>
                                    <value>#0</value>
                                </enumeratedValue>
                                <enumeratedValue>
                                    <name>1</name>
                                    <description>Normal Transfer Abort occur. To clear, write 0 to this bit after 1 state is read. </description>
                                    <value>#1</value>
                                </enumeratedValue>
                            </enumeratedValues>
                        </field>
                        <field>
                            <name>TEF</name>
                            <description>Normal Transfer Error Flag</description>
                            <lsb>9</lsb>
                            <msb>9</msb>
                            <access>read-write</access>
                            <enumeratedValues>
                                <enumeratedValue>
                                    <name>0</name>
                                    <description>Normal Transfer Error does not occur.</description>
                                    <value>#0</value>
                                </enumeratedValue>
                                <enumeratedValue>
                                    <name>1</name>
                                    <description>Normal Transfer Error occurs. To clear, write 0 to this bit after 1 state is read. </description>
                                    <value>#1</value>
                                </enumeratedValue>
                            </enumeratedValues>
                        </field>
                        <field>
                            <name>RSQFF</name>
                            <description>Normal Receive Status Queue Full Flag</description>
                            <lsb>20</lsb>
                            <msb>20</msb>
                            <access>read-write</access>
                            <enumeratedValues>
                                <enumeratedValue>
                                    <name>0</name>
                                    <description>The number of Normal Receive Status Queue entries is the NRQTHCTL.RSQTH threshold or less.</description>
                                    <value>#0</value>
                                </enumeratedValue>
                                <enumeratedValue>
                                    <name>1</name>
                                    <description>The number of Normal Receive Status Queue entries is more than the NRQTHCTL.RSQTH threshold.</description>
                                    <value>#1</value>
                                </enumeratedValue>
                            </enumeratedValues>
                        </field>
                    </fields>
                </register>
                <register>
                    <name>NTSTE</name>
                    <description>Normal Transfer Status Enable Register</description>
                    <addressOffset>0x1E4</addressOffset>
                    <size>32</size>
                    <access>read-write</access>
                    <resetValue>0x00000000</resetValue>
                    <resetMask>0xffffffff</resetMask>
                    <fields>
                        <field>
                            <name>TDBEE0</name>
                            <description>Normal Tx Data Buffer Empty Enable 0</description>
                            <lsb>0</lsb>
                            <msb>0</msb>
                            <access>read-write</access>
                            <enumeratedValues>
                                <enumeratedValue>
                                    <name>0</name>
                                    <description>Disables Normal Tx Data Buffer Empty Interrupt Status logging.</description>
                                    <value>#0</value>
                                </enumeratedValue>
                                <enumeratedValue>
                                    <name>1</name>
                                    <description>Enables Normal Tx Data Buffer Empty Interrupt Status logging.</description>
                                    <value>#1</value>
                                </enumeratedValue>
                            </enumeratedValues>
                        </field>
                        <field>
                            <name>RDBFE0</name>
                            <description>Normal Rx Data Buffer Full Enable 0</description>
                            <lsb>1</lsb>
                            <msb>1</msb>
                            <access>read-write</access>
                            <enumeratedValues>
                                <enumeratedValue>
                                    <name>0</name>
                                    <description>Disables Normal Rx Data Buffer Full Interrupt Status logging.</description>
                                    <value>#0</value>
                                </enumeratedValue>
                                <enumeratedValue>
                                    <name>1</name>
                                    <description>Enables Normal Rx Data Buffer Full Interrupt Status logging.</description>
                                    <value>#1</value>
                                </enumeratedValue>
                            </enumeratedValues>
                        </field>
                        <field>
                            <name>IBIQEFE</name>
                            <description>Normal IBI Queue Empty/Full Enable</description>
                            <lsb>2</lsb>
                            <msb>2</msb>
                            <access>read-write</access>
                            <enumeratedValues>
                                <enumeratedValue>
                                    <name>0</name>
                                    <description>Disables Normal IBI Queue Empty/Full Interrupt Status logging.</description>
                                    <value>#0</value>
                                </enumeratedValue>
                                <enumeratedValue>
                                    <name>1</name>
                                    <description>Enables Normal IBI Queue Empty/Full Interrupt Status logging.</description>
                                    <value>#1</value>
                                </enumeratedValue>
                            </enumeratedValues>
                        </field>
                        <field>
                            <name>CMDQEE</name>
                            <description>Normal Command Queue Empty Enable</description>
                            <lsb>3</lsb>
                            <msb>3</msb>
                            <access>read-write</access>
                            <enumeratedValues>
                                <enumeratedValue>
                                    <name>0</name>
                                    <description>Disables Normal Command Queue Empty Interrupt Status logging.</description>
                                    <value>#0</value>
                                </enumeratedValue>
                                <enumeratedValue>
                                    <name>1</name>
                                    <description>Enables Normal Command Queue Empty Interrupt Status logging.</description>
                                    <value>#1</value>
                                </enumeratedValue>
                            </enumeratedValues>
                        </field>
                        <field>
                            <name>RSPQFE</name>
                            <description>Normal Response Queue Full Enable</description>
                            <lsb>4</lsb>
                            <msb>4</msb>
                            <access>read-write</access>
                            <enumeratedValues>
                                <enumeratedValue>
                                    <name>0</name>
                                    <description>Disables Normal Response queue Full Interrupt Status logging.</description>
                                    <value>#0</value>
                                </enumeratedValue>
                                <enumeratedValue>
                                    <name>1</name>
                                    <description>Enables Normal Response queue Full Interrupt Status logging.</description>
                                    <value>#1</value>
                                </enumeratedValue>
                            </enumeratedValues>
                        </field>
                        <field>
                            <name>TABTE</name>
                            <description>Normal Transfer Abort Enable</description>
                            <lsb>5</lsb>
                            <msb>5</msb>
                            <access>read-write</access>
                            <enumeratedValues>
                                <enumeratedValue>
                                    <name>0</name>
                                    <description>Disables Normal Transfer Abort Interrupt Status logging.</description>
                                    <value>#0</value>
                                </enumeratedValue>
                                <enumeratedValue>
                                    <name>1</name>
                                    <description>Enables Normal Transfer Abort Interrupt Status logging.</description>
                                    <value>#1</value>
                                </enumeratedValue>
                            </enumeratedValues>
                        </field>
                        <field>
                            <name>TEE</name>
                            <description>Normal Transfer Error Enable</description>
                            <lsb>9</lsb>
                            <msb>9</msb>
                            <access>read-write</access>
                            <enumeratedValues>
                                <enumeratedValue>
                                    <name>0</name>
                                    <description>Disables Normal Transfer Error Interrupt Status logging.</description>
                                    <value>#0</value>
                                </enumeratedValue>
                                <enumeratedValue>
                                    <name>1</name>
                                    <description>Enables Normal Transfer Error Interrupt Status logging.</description>
                                    <value>#1</value>
                                </enumeratedValue>
                            </enumeratedValues>
                        </field>
                        <field>
                            <name>RSQFE</name>
                            <description>Normal Receive Status Queue Full Enable</description>
                            <lsb>20</lsb>
                            <msb>20</msb>
                            <access>read-write</access>
                            <enumeratedValues>
                                <enumeratedValue>
                                    <name>0</name>
                                    <description>Disables Normal Receive Status Queue Full Interrupt Status logging.</description>
                                    <value>#0</value>
                                </enumeratedValue>
                                <enumeratedValue>
                                    <name>1</name>
                                    <description>Enables Normal Receive Status Queue Full Interrupt Status logging.</description>
                                    <value>#1</value>
                                </enumeratedValue>
                            </enumeratedValues>
                        </field>
                    </fields>
                </register>
                <register>
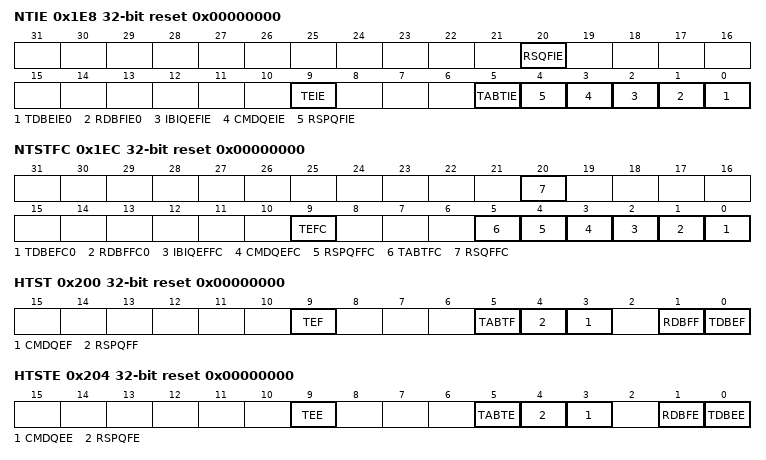
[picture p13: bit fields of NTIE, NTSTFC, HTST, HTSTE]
                    <name>NTIE</name>
                    <description>Normal Transfer Interrupt Enable Register</description>
                    <addressOffset>0x1E8</addressOffset>
                    <size>32</size>
                    <access>read-write</access>
                    <resetValue>0x00000000</resetValue>
                    <resetMask>0xffffffff</resetMask>
                    <fields>
                        <field>
                            <name>TDBEIE0</name>
                            <description>Normal Tx Data Buffer Empty Interrupt Enable 0</description>
                            <lsb>0</lsb>
                            <msb>0</msb>
                            <access>read-write</access>
                            <enumeratedValues>
                                <enumeratedValue>
                                    <name>0</name>
                                    <description>Disables Normal Tx Data Buffer Empty Interrupt Signal.</description>
                                    <value>#0</value>
                                </enumeratedValue>
                                <enumeratedValue>
                                    <name>1</name>
                                    <description>Enables Normal Tx Data Buffer Empty Interrupt Signal.</description>
                                    <value>#1</value>
                                </enumeratedValue>
                            </enumeratedValues>
                        </field>
                        <field>
                            <name>RDBFIE0</name>
                            <description>Normal Rx Data Buffer Full Interrupt Enable 0</description>
                            <lsb>1</lsb>
                            <msb>1</msb>
                            <access>read-write</access>
                            <enumeratedValues>
                                <enumeratedValue>
                                    <name>0</name>
                                    <description>Disables Normal Rx Data Buffer Full Interrupt Signal.</description>
                                    <value>#0</value>
                                </enumeratedValue>
                                <enumeratedValue>
                                    <name>1</name>
                                    <description>Enables Normal Rx Data Buffer Full Interrupt Signal.</description>
                                    <value>#1</value>
                                </enumeratedValue>
                            </enumeratedValues>
                        </field>
                        <field>
                            <name>IBIQEFIE</name>
                            <description>Normal IBI Queue Empty/Full Interrupt Enable</description>
                            <lsb>2</lsb>
                            <msb>2</msb>
                            <access>read-write</access>
                            <enumeratedValues>
                                <enumeratedValue>
                                    <name>0</name>
                                    <description>Disables Normal IBI Queue Empty/Full Interrupt Signal.</description>
                                    <value>#0</value>
                                </enumeratedValue>
                                <enumeratedValue>
                                    <name>1</name>
                                    <description>Enables Normal IBI Queue Empty/Full Interrupt Signal.</description>
                                    <value>#1</value>
                                </enumeratedValue>
                            </enumeratedValues>
                        </field>
                        <field>
                            <name>CMDQEIE</name>
                            <description>Normal Command Queue Empty Interrupt Enable</description>
                            <lsb>3</lsb>
                            <msb>3</msb>
                            <access>read-write</access>
                            <enumeratedValues>
                                <enumeratedValue>
                                    <name>0</name>
                                    <description>Disables Normal Command Queue Empty Interrupt Signal.</description>
                                    <value>#0</value>
                                </enumeratedValue>
                                <enumeratedValue>
                                    <name>1</name>
                                    <description>Enables Normal Command Queue Empty Interrupt Signal.</description>
                                    <value>#1</value>
                                </enumeratedValue>
                            </enumeratedValues>
                        </field>
                        <field>
                            <name>RSPQFIE</name>
                            <description>Normal Response Queue Full Interrupt Enable</description>
                            <lsb>4</lsb>
                            <msb>4</msb>
                            <access>read-write</access>
                            <enumeratedValues>
                                <enumeratedValue>
                                    <name>0</name>
                                    <description>Disables Normal Response Queue Full Interrupt Signal.</description>
                                    <value>#0</value>
                                </enumeratedValue>
                                <enumeratedValue>
                                    <name>1</name>
                                    <description>Enables Normal Response Queue Full Interrupt Signal.</description>
                                    <value>#1</value>
                                </enumeratedValue>
                            </enumeratedValues>
                        </field>
                        <field>
                            <name>TABTIE</name>
                            <description>Normal Transfer Abort Interrupt Enable</description>
                            <lsb>5</lsb>
                            <msb>5</msb>
                            <access>read-write</access>
                            <enumeratedValues>
                                <enumeratedValue>
                                    <name>0</name>
                                    <description>Disables Normal Transfer Abort Interrupt Signal.</description>
                                    <value>#0</value>
                                </enumeratedValue>
                                <enumeratedValue>
                                    <name>1</name>
                                    <description>Enables Normal Transfer Abort Interrupt Signal.</description>
                                    <value>#1</value>
                                </enumeratedValue>
                            </enumeratedValues>
                        </field>
                        <field>
                            <name>TEIE</name>
                            <description>Normal Transfer Error Interrupt Enable</description>
                            <lsb>9</lsb>
                            <msb>9</msb>
                            <access>read-write</access>
                            <enumeratedValues>
                                <enumeratedValue>
                                    <name>0</name>
                                    <description>Disables Normal Transfer Error Interrupt Signal.</description>
                                    <value>#0</value>
                                </enumeratedValue>
                                <enumeratedValue>
                                    <name>1</name>
                                    <description>Enables Normal Transfer Error Interrupt Signal.</description>
                                    <value>#1</value>
                                </enumeratedValue>
                            </enumeratedValues>
                        </field>
                        <field>
                            <name>RSQFIE</name>
                            <description>Normal Receive Status Queue Full Interrupt Enable</description>
                            <lsb>20</lsb>
                            <msb>20</msb>
                            <access>read-write</access>
                            <enumeratedValues>
                                <enumeratedValue>
                                    <name>0</name>
                                    <description>Disables Normal Receive Status Queue Full Interrupt Signal.</description>
                                    <value>#0</value>
                                </enumeratedValue>
                                <enumeratedValue>
                                    <name>1</name>
                                    <description>Enables Normal Receive Status Queue Full Interrupt Signal.</description>
                                    <value>#1</value>
                                </enumeratedValue>
                            </enumeratedValues>
                        </field>
                    </fields>
                </register>
                <register>
                    <name>NTSTFC</name>
                    <description>Normal Transfer Status Force Register</description>
                    <addressOffset>0x1EC</addressOffset>
                    <size>32</size>
                    <access>read-write</access>
                    <resetValue>0x00000000</resetValue>
                    <resetMask>0xffffffff</resetMask>
                    <fields>
                        <field>
                            <name>TDBEFC0</name>
                            <description>Normal Tx Data Buffer Empty Force 0</description>
                            <lsb>0</lsb>
                            <msb>0</msb>
                            <access>write-only</access>
                            <enumeratedValues>
                                <enumeratedValue>
                                    <name>0</name>
                                    <description>Not Force Normal Tx Data Buffer Empty Interrupt for software testing.</description>
                                    <value>#0</value>
                                </enumeratedValue>
                                <enumeratedValue>
                                    <name>1</name>
                                    <description>Force Normal Tx Data Buffer Empty Interrupt for software testing.</description>
                                    <value>#1</value>
                                </enumeratedValue>
                            </enumeratedValues>
                        </field>
                        <field>
                            <name>RDBFFC0</name>
                            <description>Normal Rx Data Buffer Full Force 0</description>
                            <lsb>1</lsb>
                            <msb>1</msb>
                            <access>write-only</access>
                            <enumeratedValues>
                                <enumeratedValue>
                                    <name>0</name>
                                    <description>Not Force Normal Rx Data Buffer Full Interrupt for software testing.</description>
                                    <value>#0</value>
                                </enumeratedValue>
                                <enumeratedValue>
                                    <name>1</name>
                                    <description>Force Normal Rx Data Buffer Full Interrupt for software testing.</description>
                                    <value>#1</value>
                                </enumeratedValue>
                            </enumeratedValues>
                        </field>
                        <field>
                            <name>IBIQEFFC</name>
                            <description>Normal IBI Queue Empty/Full Force</description>
                            <lsb>2</lsb>
                            <msb>2</msb>
                            <access>write-only</access>
                            <enumeratedValues>
                                <enumeratedValue>
                                    <name>0</name>
                                    <description>Not Force Normal IBI Queue Empty/Full Interrupt for software testing.</description>
                                    <value>#0</value>
                                </enumeratedValue>
                                <enumeratedValue>
                                    <name>1</name>
                                    <description>Force Normal IBI Queue Empty/Full Interrupt for software testing.</description>
                                    <value>#1</value>
                                </enumeratedValue>
                            </enumeratedValues>
                        </field>
                        <field>
                            <name>CMDQEFC</name>
                            <description>Normal Command Queue Empty Force</description>
                            <lsb>3</lsb>
                            <msb>3</msb>
                            <access>write-only</access>
                            <enumeratedValues>
                                <enumeratedValue>
                                    <name>0</name>
                                    <description>Not Force Normal Command Queue Empty Interrupt for software testing.</description>
                                    <value>#0</value>
                                </enumeratedValue>
                                <enumeratedValue>
                                    <name>1</name>
                                    <description>Force Normal Command Queue Empty Interrupt for software testing.</description>
                                    <value>#1</value>
                                </enumeratedValue>
                            </enumeratedValues>
                        </field>
                        <field>
                            <name>RSPQFFC</name>
                            <description>Normal Response Queue Full Force</description>
                            <lsb>4</lsb>
                            <msb>4</msb>
                            <access>write-only</access>
                            <enumeratedValues>
                                <enumeratedValue>
                                    <name>0</name>
                                    <description>Not Force Normal Response Queue Full Interrupt for software testing.</description>
                                    <value>#0</value>
                                </enumeratedValue>
                                <enumeratedValue>
                                    <name>1</name>
                                    <description>Force Normal Response Queue Full Interrupt for software testing.</description>
                                    <value>#1</value>
                                </enumeratedValue>
                            </enumeratedValues>
                        </field>
                        <field>
                            <name>TABTFC</name>
                            <description>Normal Transfer Abort Force</description>
                            <lsb>5</lsb>
                            <msb>5</msb>
                            <access>write-only</access>
                            <enumeratedValues>
                                <enumeratedValue>
                                    <name>0</name>
                                    <description>Not Force Normal Transfer Abort Interrupt for software testing.</description>
                                    <value>#0</value>
                                </enumeratedValue>
                                <enumeratedValue>
                                    <name>1</name>
                                    <description>Force Normal Transfer Abort Interrupt for software testing.</description>
                                    <value>#1</value>
                                </enumeratedValue>
                            </enumeratedValues>
                        </field>
                        <field>
                            <name>TEFC</name>
                            <description>Normal Transfer Error Force</description>
                            <lsb>9</lsb>
                            <msb>9</msb>
                            <access>write-only</access>
                            <enumeratedValues>
                                <enumeratedValue>
                                    <name>0</name>
                                    <description>Not Force Normal Transfer Error Interrupt for software testing.</description>
                                    <value>#0</value>
                                </enumeratedValue>
                                <enumeratedValue>
                                    <name>1</name>
                                    <description>Force Normal Transfer Error Interrupt for software testing.</description>
                                    <value>#1</value>
                                </enumeratedValue>
                            </enumeratedValues>
                        </field>
                        <field>
                            <name>RSQFFC</name>
                            <description>Normal Receive Status Queue Full Force</description>
                            <lsb>20</lsb>
                            <msb>20</msb>
                            <access>write-only</access>
                            <enumeratedValues>
                                <enumeratedValue>
                                    <name>0</name>
                                    <description>Not Force Normal Receive Status Queue Full Interrupt for software testing.</description>
                                    <value>#0</value>
                                </enumeratedValue>
                                <enumeratedValue>
                                    <name>1</name>
                                    <description>Force Normal Receive Status Queue Full Interrupt for software testing.</description>
                                    <value>#1</value>
                                </enumeratedValue>
                            </enumeratedValues>
                        </field>
                    </fields>
                </register>
                <register>
                    <name>HTST</name>
                    <description>High Priority Transfer Status Register</description>
                    <addressOffset>0x200</addressOffset>
                    <size>32</size>
                    <access>read-write</access>
                    <resetValue>0x00000000</resetValue>
                    <resetMask>0xffffffff</resetMask>
                    <fields>
                        <field>
                            <name>TDBEF</name>
                            <description>High Priority Tx Data Buffer Empty Flag</description>
                            <lsb>0</lsb>
                            <msb>0</msb>
                            <access>read-write</access>
                            <enumeratedValues>
                                <enumeratedValue>
                                    <name>0</name>
                                    <description>The number of empties in the High Priority Tx Data Buffer is less than the HTBTHCTL.TXDBTH[2:0] threshold.</description>
                                    <value>#0</value>
                                </enumeratedValue>
                                <enumeratedValue>
                                    <name>1</name>
                                    <description>The number of empties in the High Priority Tx Data Buffer is or more than the HTBTHCTL.TXDBTH[2:0] threshold.</description>
                                    <value>#1</value>
                                </enumeratedValue>
                            </enumeratedValues>
                        </field>
                        <field>
                            <name>RDBFF</name>
                            <description>High Priority Rx Data Buffer Full Flag</description>
                            <lsb>1</lsb>
                            <msb>1</msb>
                            <access>read-write</access>
                            <enumeratedValues>
                                <enumeratedValue>
                                    <name>0</name>
                                    <description>The number of entries in the High Priority Rx Data Buffer is less than the HTBTHCTL.RXDBTH[2:0] threshold.</description>
                                    <value>#0</value>
                                </enumeratedValue>
                                <enumeratedValue>
                                    <name>1</name>
                                    <description>The number of entries in the High Priority Rx Data Buffer is or more than the HTBTHCTL.RXDBTH[2:0] threshold.</description>
                                    <value>#1</value>
                                </enumeratedValue>
                            </enumeratedValues>
                        </field>
                        <field>
                            <name>CMDQEF</name>
                            <description>High Priority Command Queue Empty Flag</description>
                            <lsb>3</lsb>
                            <msb>3</msb>
                            <access>read-write</access>
                            <enumeratedValues>
                                <enumeratedValue>
                                    <name>0</name>
                                    <description>If HQTHCTL.CMDQTH is 0, the number of High Priority Command Queue empties is less than the Command Queue size. If HQTHCTL.CMDQTH is other than 0, the number of High Priority Command Queue empties is less than the HQTHCTL.CMDQTH threshold. </description>
                                    <value>#0</value>
                                </enumeratedValue>
                                <enumeratedValue>
                                    <name>1</name>
                                    <description>If HQTHCTL.CMDQTH is 0, the number of High Priority Command Queue empties is the Command Queue size. If HQTHCTL.CMDQTH is other than 0, the number of High Priority Command Queue empties is or more than the HQTHCTL.CMDQTH threshold . </description>
                                    <value>#1</value>
                                </enumeratedValue>
                            </enumeratedValues>
                        </field>
                        <field>
                            <name>RSPQFF</name>
                            <description>High Priority Response Queue Full Flag</description>
                            <lsb>4</lsb>
                            <msb>4</msb>
                            <access>read-write</access>
                            <enumeratedValues>
                                <enumeratedValue>
                                    <name>0</name>
                                    <description>The number of High Priority Response Queue entries is less than the HQTHCTL .RSPQTH threshold.</description>
                                    <value>#0</value>
                                </enumeratedValue>
                                <enumeratedValue>
                                    <name>1</name>
                                    <description>The number of High Priority Response Queue entries is or more than the HQTHCTL .RSPQTH threshold.</description>
                                    <value>#1</value>
                                </enumeratedValue>
                            </enumeratedValues>
                        </field>
                        <field>
                            <name>TABTF</name>
                            <description>High Priority Transfer Abort Flag</description>
                            <lsb>5</lsb>
                            <msb>5</msb>
                            <access>read-write</access>
                            <enumeratedValues>
                                <enumeratedValue>
                                    <name>0</name>
                                    <description>High Priority Transfer Abort does not occur.</description>
                                    <value>#0</value>
                                </enumeratedValue>
                                <enumeratedValue>
                                    <name>1</name>
                                    <description>High Priority Transfer Abort occurs. To clear, write 0 to this bit after 1 is read. </description>
                                    <value>#1</value>
                                </enumeratedValue>
                            </enumeratedValues>
                        </field>
                        <field>
                            <name>TEF</name>
                            <description>High Priority Transfer Error Flag</description>
                            <lsb>9</lsb>
                            <msb>9</msb>
                            <access>read-write</access>
                            <enumeratedValues>
                                <enumeratedValue>
                                    <name>0</name>
                                    <description>High Priority Transfer Error does not occur.</description>
                                    <value>#0</value>
                                </enumeratedValue>
                                <enumeratedValue>
                                    <name>1</name>
                                    <description>High Priority Transfer Error occurs. To clear, write 0 to this bit after 1 is read. </description>
                                    <value>#1</value>
                                </enumeratedValue>
                            </enumeratedValues>
                        </field>
                    </fields>
                </register>
                <register>
                    <name>HTSTE</name>
                    <description>High Priority Transfer Status Enable Register</description>
                    <addressOffset>0x204</addressOffset>
                    <size>32</size>
                    <access>read-write</access>
                    <resetValue>0x00000000</resetValue>
                    <resetMask>0xffffffff</resetMask>
                    <fields>
                        <field>
                            <name>TDBEE</name>
                            <description>High Priority Tx Data Buffer Empty Enable</description>
                            <lsb>0</lsb>
                            <msb>0</msb>
                            <access>read-write</access>
                            <enumeratedValues>
                                <enumeratedValue>
                                    <name>0</name>
                                    <description>Disables High Priority Tx Data Buffer Empty Interrupt Status logging.</description>
                                    <value>#0</value>
                                </enumeratedValue>
                                <enumeratedValue>
                                    <name>1</name>
                                    <description>Enables High Priority Tx Data Buffer Empty Interrupt Status logging.</description>
                                    <value>#1</value>
                                </enumeratedValue>
                            </enumeratedValues>
                        </field>
                        <field>
                            <name>RDBFE</name>
                            <description>High Priority Rx Data Buffer Full Enable</description>
                            <lsb>1</lsb>
                            <msb>1</msb>
                            <access>read-write</access>
                            <enumeratedValues>
                                <enumeratedValue>
                                    <name>0</name>
                                    <description>Disables High Priority Rx Data Buffer Full Interrupt Status logging.</description>
                                    <value>#0</value>
                                </enumeratedValue>
                                <enumeratedValue>
                                    <name>1</name>
                                    <description>Enables High Priority Rx Data Buffer Full Interrupt Status logging.</description>
                                    <value>#1</value>
                                </enumeratedValue>
                            </enumeratedValues>
                        </field>
                        <field>
                            <name>CMDQEE</name>
                            <description>High Priority Command Queue Empty Enable</description>
                            <lsb>3</lsb>
                            <msb>3</msb>
                            <access>read-write</access>
                            <enumeratedValues>
                                <enumeratedValue>
                                    <name>0</name>
                                    <description>Disables High Priority Command Queue Empty Interrupt Status logging.</description>
                                    <value>#0</value>
                                </enumeratedValue>
                                <enumeratedValue>
                                    <name>1</name>
                                    <description>Enables High Priority Command Queue Empty Interrupt Status logging.</description>
                                    <value>#1</value>
                                </enumeratedValue>
                            </enumeratedValues>
                        </field>
                        <field>
                            <name>RSPQFE</name>
                            <description>High Priority Response Queue Full Enable</description>
                            <lsb>4</lsb>
                            <msb>4</msb>
                            <access>read-write</access>
                            <enumeratedValues>
                                <enumeratedValue>
                                    <name>0</name>
                                    <description>Disables High Priority Response Queue Full Interrupt Status logging.</description>
                                    <value>#0</value>
                                </enumeratedValue>
                                <enumeratedValue>
                                    <name>1</name>
                                    <description>Enables High Priority Response Queue Full Interrupt Status logging.</description>
                                    <value>#1</value>
                                </enumeratedValue>
                            </enumeratedValues>
                        </field>
                        <field>
                            <name>TABTE</name>
                            <description>High Priority Transfer Abort Enable</description>
                            <lsb>5</lsb>
                            <msb>5</msb>
                            <access>read-write</access>
                            <enumeratedValues>
                                <enumeratedValue>
                                    <name>0</name>
                                    <description>Disables High Priority Transfer Abort Interrupt Status logging.</description>
                                    <value>#0</value>
                                </enumeratedValue>
                                <enumeratedValue>
                                    <name>1</name>
                                    <description>Enables High Priority Transfer Abort Interrupt Status logging.</description>
                                    <value>#1</value>
                                </enumeratedValue>
                            </enumeratedValues>
                        </field>
                        <field>
                            <name>TEE</name>
                            <description>High Priority Transfer Error Enable</description>
                            <lsb>9</lsb>
                            <msb>9</msb>
                            <access>read-write</access>
                            <enumeratedValues>
                                <enumeratedValue>
                                    <name>0</name>
                                    <description>Disables High Priority Transfer Error interrupt Stats logging.</description>
                                    <value>#0</value>
                                </enumeratedValue>
                                <enumeratedValue>
                                    <name>1</name>
                                    <description>Enables High Priority Transfer Error interrupt Stats logging.</description>
                                    <value>#1</value>
                                </enumeratedValue>
                            </enumeratedValues>
                        </field>
                    </fields>
                </register>
                <register>
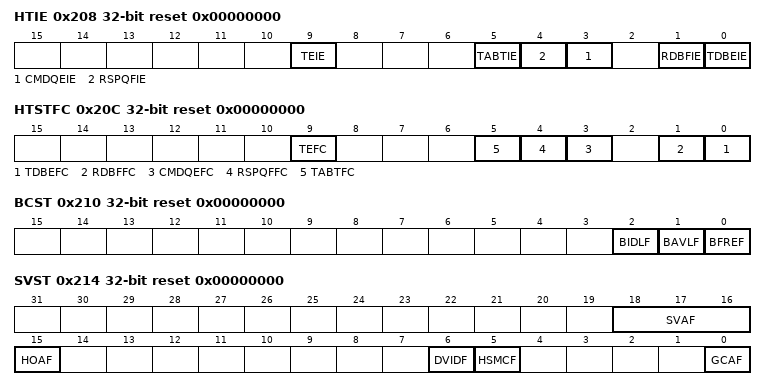
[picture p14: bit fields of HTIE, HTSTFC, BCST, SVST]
                    <name>HTIE</name>
                    <description>High Priority Transfer Interrupt Enable Register</description>
                    <addressOffset>0x208</addressOffset>
                    <size>32</size>
                    <access>read-write</access>
                    <resetValue>0x00000000</resetValue>
                    <resetMask>0xffffffff</resetMask>
                    <fields>
                        <field>
                            <name>TDBEIE</name>
                            <description>High Priority Tx Data Buffer Empty Interrupt Enable</description>
                            <lsb>0</lsb>
                            <msb>0</msb>
                            <access>read-write</access>
                            <enumeratedValues>
                                <enumeratedValue>
                                    <name>0</name>
                                    <description>Disables High Priority Tx Data Buffer Empty Interrupt Signal.</description>
                                    <value>#0</value>
                                </enumeratedValue>
                                <enumeratedValue>
                                    <name>1</name>
                                    <description>Enables High Priority Tx Data Buffer Empty Interrupt Signal.</description>
                                    <value>#1</value>
                                </enumeratedValue>
                            </enumeratedValues>
                        </field>
                        <field>
                            <name>RDBFIE</name>
                            <description>High Priority Rx Data Buffer Full Interrupt Enable</description>
                            <lsb>1</lsb>
                            <msb>1</msb>
                            <access>read-write</access>
                            <enumeratedValues>
                                <enumeratedValue>
                                    <name>0</name>
                                    <description>Disables High Priority Rx Data Buffer Full Interrupt Signal.</description>
                                    <value>#0</value>
                                </enumeratedValue>
                                <enumeratedValue>
                                    <name>1</name>
                                    <description>Enables High Priority Rx Data Buffer Full Interrupt Signal.</description>
                                    <value>#1</value>
                                </enumeratedValue>
                            </enumeratedValues>
                        </field>
                        <field>
                            <name>CMDQEIE</name>
                            <description>High Priority Command Queue Empty Interrupt Enable</description>
                            <lsb>3</lsb>
                            <msb>3</msb>
                            <access>read-write</access>
                            <enumeratedValues>
                                <enumeratedValue>
                                    <name>0</name>
                                    <description>Disables High Priority Command Queue Empty Interrupt Signal.</description>
                                    <value>#0</value>
                                </enumeratedValue>
                                <enumeratedValue>
                                    <name>1</name>
                                    <description>Enables High Priority Command Queue Empty Interrupt Signal.</description>
                                    <value>#1</value>
                                </enumeratedValue>
                            </enumeratedValues>
                        </field>
                        <field>
                            <name>RSPQFIE</name>
                            <description>High Priority Response Queue Full Interrupt Enable</description>
                            <lsb>4</lsb>
                            <msb>4</msb>
                            <access>read-write</access>
                            <enumeratedValues>
                                <enumeratedValue>
                                    <name>0</name>
                                    <description>Disables High Priority Response Queue Full Interrupt Signal.</description>
                                    <value>#0</value>
                                </enumeratedValue>
                                <enumeratedValue>
                                    <name>1</name>
                                    <description>Enables High Priority Response Queue Full Interrupt Signal.</description>
                                    <value>#1</value>
                                </enumeratedValue>
                            </enumeratedValues>
                        </field>
                        <field>
                            <name>TABTIE</name>
                            <description>High Priority Transfer Abort Interrupt Enable</description>
                            <lsb>5</lsb>
                            <msb>5</msb>
                            <access>read-write</access>
                            <enumeratedValues>
                                <enumeratedValue>
                                    <name>0</name>
                                    <description>Disables High Priority Transfer Abort interrupt Signal.</description>
                                    <value>#0</value>
                                </enumeratedValue>
                                <enumeratedValue>
                                    <name>1</name>
                                    <description>Enables High Priority Transfer Abort interrupt Signal.</description>
                                    <value>#1</value>
                                </enumeratedValue>
                            </enumeratedValues>
                        </field>
                        <field>
                            <name>TEIE</name>
                            <description>High Priority Transfer Error Interrupt Enable</description>
                            <lsb>9</lsb>
                            <msb>9</msb>
                            <access>read-write</access>
                            <enumeratedValues>
                                <enumeratedValue>
                                    <name>0</name>
                                    <description>Disables High Priority Transfer Error Interrupt Signal.</description>
                                    <value>#0</value>
                                </enumeratedValue>
                                <enumeratedValue>
                                    <name>1</name>
                                    <description>Enables High Priority Transfer Error Interrupt Signal.</description>
                                    <value>#1</value>
                                </enumeratedValue>
                            </enumeratedValues>
                        </field>
                    </fields>
                </register>
                <register>
                    <name>HTSTFC</name>
                    <description>High Priority Transfer Status Force Register</description>
                    <addressOffset>0x20C</addressOffset>
                    <size>32</size>
                    <access>read-write</access>
                    <resetValue>0x00000000</resetValue>
                    <resetMask>0xffffffff</resetMask>
                    <fields>
                        <field>
                            <name>TDBEFC</name>
                            <description>High Priority Tx Data Buffer Empty Force</description>
                            <lsb>0</lsb>
                            <msb>0</msb>
                            <access>write-only</access>
                            <enumeratedValues>
                                <enumeratedValue>
                                    <name>0</name>
                                    <description>Not Force High Priority Tx Data Buffer Empty Interrupt for software testing.</description>
                                    <value>#0</value>
                                </enumeratedValue>
                                <enumeratedValue>
                                    <name>1</name>
                                    <description>Force High Priority Tx Data Buffer Empty Interrupt for software testing.</description>
                                    <value>#1</value>
                                </enumeratedValue>
                            </enumeratedValues>
                        </field>
                        <field>
                            <name>RDBFFC</name>
                            <description>High Priority Rx Data Buffer Full Force</description>
                            <lsb>1</lsb>
                            <msb>1</msb>
                            <access>write-only</access>
                            <enumeratedValues>
                                <enumeratedValue>
                                    <name>0</name>
                                    <description>Not Force High Priority Rx Data Buffer Full Interrupt for software testing.</description>
                                    <value>#0</value>
                                </enumeratedValue>
                                <enumeratedValue>
                                    <name>1</name>
                                    <description>Force High Priority Rx Data Buffer Full Interrupt for software testing.</description>
                                    <value>#1</value>
                                </enumeratedValue>
                            </enumeratedValues>
                        </field>
                        <field>
                            <name>CMDQEFC</name>
                            <description>High Priority Command Queue Empty Force</description>
                            <lsb>3</lsb>
                            <msb>3</msb>
                            <access>write-only</access>
                            <enumeratedValues>
                                <enumeratedValue>
                                    <name>0</name>
                                    <description>Not Force High Priority Command Queue Empty Interrupt for software testing.</description>
                                    <value>#0</value>
                                </enumeratedValue>
                                <enumeratedValue>
                                    <name>1</name>
                                    <description>Force High Priority Command Queue Empty Interrupt for software testing.</description>
                                    <value>#1</value>
                                </enumeratedValue>
                            </enumeratedValues>
                        </field>
                        <field>
                            <name>RSPQFFC</name>
                            <description>High Priority Response Queue Full Force</description>
                            <lsb>4</lsb>
                            <msb>4</msb>
                            <access>write-only</access>
                            <enumeratedValues>
                                <enumeratedValue>
                                    <name>0</name>
                                    <description>Not Force High Priority Response Queue Full Interrupt for software testing.</description>
                                    <value>#0</value>
                                </enumeratedValue>
                                <enumeratedValue>
                                    <name>1</name>
                                    <description>Force High Priority Response Queue Full Interrupt for software testing.</description>
                                    <value>#1</value>
                                </enumeratedValue>
                            </enumeratedValues>
                        </field>
                        <field>
                            <name>TABTFC</name>
                            <description>High Priority Transfer Abort Force</description>
                            <lsb>5</lsb>
                            <msb>5</msb>
                            <access>write-only</access>
                            <enumeratedValues>
                                <enumeratedValue>
                                    <name>0</name>
                                    <description>Not Force High Priority Transfer Abort Interrupt for software testing.</description>
                                    <value>#0</value>
                                </enumeratedValue>
                                <enumeratedValue>
                                    <name>1</name>
                                    <description>Force High Priority Transfer Abort Interrupt for software testing.</description>
                                    <value>#1</value>
                                </enumeratedValue>
                            </enumeratedValues>
                        </field>
                        <field>
                            <name>TEFC</name>
                            <description>High Priority Transfer Error Force</description>
                            <lsb>9</lsb>
                            <msb>9</msb>
                            <access>write-only</access>
                            <enumeratedValues>
                                <enumeratedValue>
                                    <name>0</name>
                                    <description>Not Force High Priority Transfer Error Interrupt for software testing.</description>
                                    <value>#0</value>
                                </enumeratedValue>
                                <enumeratedValue>
                                    <name>1</name>
                                    <description>Force High Priority Transfer Error Interrupt for software testing.</description>
                                    <value>#1</value>
                                </enumeratedValue>
                            </enumeratedValues>
                        </field>
                    </fields>
                </register>
                <register>
                    <name>BCST</name>
                    <description>Bus Condition Status Register</description>
                    <addressOffset>0x210</addressOffset>
                    <size>32</size>
                    <access>read-only</access>
                    <resetValue>0x00000000</resetValue>
                    <resetMask>0xffffffff</resetMask>
                    <fields>
                        <field>
                            <name>BFREF</name>
                            <description>Bus Free Detection Flag</description>
                            <lsb>0</lsb>
                            <msb>0</msb>
                            <access>read-only</access>
                            <enumeratedValues>
                                <enumeratedValue>
                                    <name>0</name>
                                    <description>Have not Detected Bus Free</description>
                                    <value>#0</value>
                                </enumeratedValue>
                                <enumeratedValue>
                                    <name>1</name>
                                    <description>Have Detected Bus Free</description>
                                    <value>#1</value>
                                </enumeratedValue>
                            </enumeratedValues>
                        </field>
                        <field>
                            <name>BAVLF</name>
                            <description>Bus Available Detection Flag</description>
                            <lsb>1</lsb>
                            <msb>1</msb>
                            <access>read-only</access>
                            <enumeratedValues>
                                <enumeratedValue>
                                    <name>0</name>
                                    <description>Have not Detected Bus Available</description>
                                    <value>#0</value>
                                </enumeratedValue>
                                <enumeratedValue>
                                    <name>1</name>
                                    <description>Have Detected Bus Available</description>
                                    <value>#1</value>
                                </enumeratedValue>
                            </enumeratedValues>
                        </field>
                        <field>
                            <name>BIDLF</name>
                            <description>Bus Idle Detection Flag</description>
                            <lsb>2</lsb>
                            <msb>2</msb>
                            <access>read-only</access>
                            <enumeratedValues>
                                <enumeratedValue>
                                    <name>0</name>
                                    <description>Have not Detected Bus Idle</description>
                                    <value>#0</value>
                                </enumeratedValue>
                                <enumeratedValue>
                                    <name>1</name>
                                    <description>Have Detected Bus Idle</description>
                                    <value>#1</value>
                                </enumeratedValue>
                            </enumeratedValues>
                        </field>
                    </fields>
                </register>
                <register>
                    <name>SVST</name>
                    <description>Slave Status Register</description>
                    <addressOffset>0x214</addressOffset>
                    <size>32</size>
                    <access>read-write</access>
                    <resetValue>0x00000000</resetValue>
                    <resetMask>0xffffffff</resetMask>
                    <fields>
                        <field>
                            <name>GCAF</name>
                            <description>General Call Address Detection Flag</description>
                            <lsb>0</lsb>
                            <msb>0</msb>
                            <access>read-write</access>
                            <enumeratedValues>
                                <enumeratedValue>
                                    <name>0</name>
                                    <description>General call address does not detect.</description>
                                    <value>#0</value>
                                </enumeratedValue>
                                <enumeratedValue>
                                    <name>1</name>
                                    <description>General call address detects.</description>
                                    <value>#1</value>
                                </enumeratedValue>
                            </enumeratedValues>
                        </field>
                        <field>
                            <name>HSMCF</name>
                            <description>Hs-mode Master Code Detection Flag</description>
                            <lsb>5</lsb>
                            <msb>5</msb>
                            <access>read-write</access>
                            <enumeratedValues>
                                <enumeratedValue>
                                    <name>0</name>
                                    <description>Hs-mode Master Code does not detect.</description>
                                    <value>#0</value>
                                </enumeratedValue>
                                <enumeratedValue>
                                    <name>1</name>
                                    <description>Hs-mode Master Code detects.</description>
                                    <value>#1</value>
                                </enumeratedValue>
                            </enumeratedValues>
                        </field>
                        <field>
                            <name>DVIDF</name>
                            <description>Device-ID Address Detection Flag</description>
                            <lsb>6</lsb>
                            <msb>6</msb>
                            <access>read-write</access>
                            <enumeratedValues>
                                <enumeratedValue>
                                    <name>0</name>
                                    <description>Device-ID command does not detect.</description>
                                    <value>#0</value>
                                </enumeratedValue>
                                <enumeratedValue>
                                    <name>1</name>
                                    <description>Device-ID command detects. This bit set to 1 when the first frame received immediately after a START condition is detected matches a value of (device ID (1111 100) + 0[W]).</description>
                                    <value>#1</value>
                                </enumeratedValue>
                            </enumeratedValues>
                        </field>
                        <field>
                            <name>HOAF</name>
                            <description>Host Address Detection Flag</description>
                            <lsb>15</lsb>
                            <msb>15</msb>
                            <access>read-write</access>
                            <enumeratedValues>
                                <enumeratedValue>
                                    <name>0</name>
                                    <description>Host address does not detect.</description>
                                    <value>#0</value>
                                </enumeratedValue>
                                <enumeratedValue>
                                    <name>1</name>
                                    <description>Host address detects. This bit set to 1 when the received slave address matches the host address (0001 000).</description>
                                    <value>#1</value>
                                </enumeratedValue>
                            </enumeratedValues>
                        </field>
                        <field>
                            <name>SVAF</name>
                            <description>Slave Address Detection Flag n ( n = 0 to 2 )</description>
                            <lsb>16</lsb>
                            <msb>18</msb>
                            <access>read-write</access>
                            <enumeratedValues>
                                <enumeratedValue>
                                    <name>0</name>
                                    <description>Slave n does not detect</description>
                                    <value>#0</value>
                                </enumeratedValue>
                                <enumeratedValue>
                                    <name>1</name>
                                    <description>Slave n detect</description>
                                    <value>#1</value>
                                </enumeratedValue>
                            </enumeratedValues>
                        </field>
                    </fields>
                </register>
                <register>
                    <name>WUST</name>
                    <description>Wake Up Unit Operating Status Register</description>
                    <addressOffset>0x218</addressOffset>
                    <size>32</size>
                    <access>read-only</access>
                    <resetValue>0x00000000</resetValue>
                    <resetMask>0xffffffff</resetMask>
                    <fields>
                        <field>
                            <name>WUASYNF</name>
                            <description>Wake-up function asynchronous operation status flag</description>
                            <lsb>0</lsb>
                            <msb>0</msb>
                            <access>read-only</access>
                            <enumeratedValues>
                                <enumeratedValue>
                                    <name>0</name>
                                    <description>I3C synchronous circuit enable condition.</description>
                                    <value>#0</value>
                                </enumeratedValue>
                                <enumeratedValue>
                                    <name>1</name>
                                    <description>I3C asynchronous circuit enable condition.</description>
                                    <value>#1</value>
                                </enumeratedValue>
                            </enumeratedValues>
                        </field>
                    </fields>
                </register>
                <register>
                    <name>MRCCPT</name>
                    <description>MsyncCNT Counter Capture Register</description>
                    <addressOffset>0x21C</addressOffset>
                    <size>32</size>
                    <access>read-only</access>
                    <resetValue>0x00000000</resetValue>
                    <resetMask>0xffffffff</resetMask>
                </register>
                <register>
                    <dim>8</dim>
                    <dimIncrement>0x08</dimIncrement>
                    <dimIndex>0-7</dimIndex>
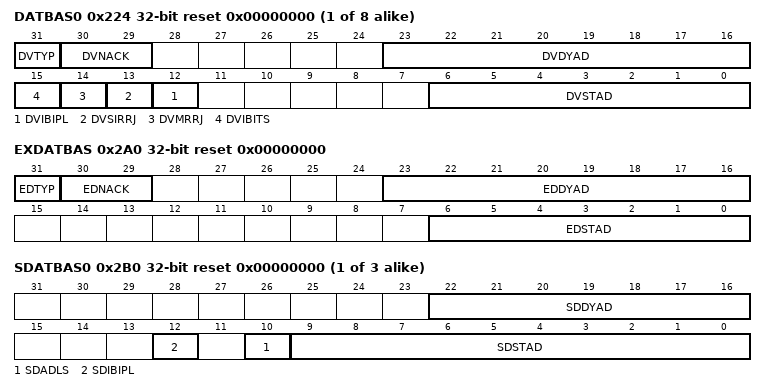
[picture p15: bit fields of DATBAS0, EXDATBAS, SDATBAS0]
                    <name>DATBAS%s</name>
                    <description>Device Address Table Basic Register %s</description>
                    <addressOffset>0x224</addressOffset>
                    <size>32</size>
                    <access>read-write</access>
                    <resetValue>0x00000000</resetValue>
                    <resetMask>0xffffffff</resetMask>
                    <fields>
                        <field>
                            <name>DVSTAD</name>
                            <description>Device Static Address</description>
                            <lsb>0</lsb>
                            <msb>6</msb>
                            <access>read-write</access>
                        </field>
                        <field>
                            <name>DVIBIPL</name>
                            <description>Device IBI Payload</description>
                            <lsb>12</lsb>
                            <msb>12</msb>
                            <access>read-write</access>
                            <enumeratedValues>
                                <enumeratedValue>
                                    <name>0</name>
                                    <description>IBIs from this Device do not carry a Data Payload.</description>
                                    <value>#0</value>
                                </enumeratedValue>
                                <enumeratedValue>
                                    <name>1</name>
                                    <description>IBIs from this Device do carry a Data Payload.</description>
                                    <value>#1</value>
                                </enumeratedValue>
                            </enumeratedValues>
                        </field>
                        <field>
                            <name>DVSIRRJ</name>
                            <description>Device In-Band Slave Interrupt Request Reject</description>
                            <lsb>13</lsb>
                            <msb>13</msb>
                            <access>read-write</access>
                            <enumeratedValues>
                                <enumeratedValue>
                                    <name>0</name>
                                    <description>This Device shall ACK the SIR.</description>
                                    <value>#0</value>
                                </enumeratedValue>
                                <enumeratedValue>
                                    <name>1</name>
                                    <description>This Device shall NACK the SIR and send the auto-disable CCC.</description>
                                    <value>#1</value>
                                </enumeratedValue>
                            </enumeratedValues>
                        </field>
                        <field>
                            <name>DVMRRJ</name>
                            <description>Device In-Band Master Request Reject</description>
                            <lsb>14</lsb>
                            <msb>14</msb>
                            <access>read-write</access>
                            <enumeratedValues>
                                <enumeratedValue>
                                    <name>0</name>
                                    <description>This Device shall ACK Master Requests.</description>
                                    <value>#0</value>
                                </enumeratedValue>
                                <enumeratedValue>
                                    <name>1</name>
                                    <description>This Device shall NACK Master Requests and send the auto-disable command.</description>
                                    <value>#1</value>
                                </enumeratedValue>
                            </enumeratedValues>
                        </field>
                        <field>
                            <name>DVIBITS</name>
                            <description>Device IBI Time-stamp</description>
                            <lsb>15</lsb>
                            <msb>15</msb>
                            <access>read-write</access>
                            <enumeratedValues>
                                <enumeratedValue>
                                    <name>0</name>
                                    <description>The Master shall not time-stamp IBIs from this Device with Master Time-stamps.</description>
                                    <value>#0</value>
                                </enumeratedValue>
                                <enumeratedValue>
                                    <name>1</name>
                                    <description>The Master shall time-stamp IBIs for this Device with Master Time-stamps.</description>
                                    <value>#1</value>
                                </enumeratedValue>
                            </enumeratedValues>
                        </field>
                        <field>
                            <name>DVDYAD</name>
                            <description>Device I3C Dynamic Address</description>
                            <lsb>16</lsb>
                            <msb>23</msb>
                            <access>read-write</access>
                        </field>
                        <field>
                            <name>DVNACK</name>
                            <description>Device NACK Retry Count</description>
                            <lsb>29</lsb>
                            <msb>30</msb>
                            <access>read-write</access>
                        </field>
                        <field>
                            <name>DVTYP</name>
                            <description>Device Type</description>
                            <lsb>31</lsb>
                            <msb>31</msb>
                            <access>read-write</access>
                            <enumeratedValues>
                                <enumeratedValue>
                                    <name>0</name>
                                    <description>I3C Device</description>
                                    <value>#0</value>
                                </enumeratedValue>
                                <enumeratedValue>
                                    <name>1</name>
                                    <description>I2C Device</description>
                                    <value>#1</value>
                                </enumeratedValue>
                            </enumeratedValues>
                        </field>
                    </fields>
                </register>
                <register>
                    <name>EXDATBAS</name>
                    <description>Extended Device Address Table Basic Register</description>
                    <addressOffset>0x2A0</addressOffset>
                    <size>32</size>
                    <access>read-write</access>
                    <resetValue>0x00000000</resetValue>
                    <resetMask>0xffffffff</resetMask>
                    <fields>
                        <field>
                            <name>EDSTAD</name>
                            <description>Extended Device Static Address</description>
                            <lsb>0</lsb>
                            <msb>6</msb>
                            <access>read-write</access>
                        </field>
                        <field>
                            <name>EDDYAD</name>
                            <description>Extended Device I3C Dynamic Address</description>
                            <lsb>16</lsb>
                            <msb>23</msb>
                            <access>read-write</access>
                        </field>
                        <field>
                            <name>EDNACK</name>
                            <description>Extended Device NACK Retry Count</description>
                            <lsb>29</lsb>
                            <msb>30</msb>
                            <access>read-write</access>
                        </field>
                        <field>
                            <name>EDTYP</name>
                            <description>Extended Device Type</description>
                            <lsb>31</lsb>
                            <msb>31</msb>
                            <access>read-write</access>
                            <enumeratedValues>
                                <enumeratedValue>
                                    <name>0</name>
                                    <description>I3C Device</description>
                                    <value>#0</value>
                                </enumeratedValue>
                                <enumeratedValue>
                                    <name>1</name>
                                    <description>I2C Device</description>
                                    <value>#1</value>
                                </enumeratedValue>
                            </enumeratedValues>
                        </field>
                    </fields>
                </register>
                <register>
                    <dim>3</dim>
                    <dimIncrement>0x04</dimIncrement>
                    <dimIndex>0-2</dimIndex>
                    <name>SDATBAS%s</name>
                    <description>Slave Device Address Table Basic Register %s</description>
                    <addressOffset>0x2B0</addressOffset>
                    <size>32</size>
                    <access>read-write</access>
                    <resetValue>0x00000000</resetValue>
                    <resetMask>0xffffffff</resetMask>
                    <fields>
                        <field>
                            <name>SDSTAD</name>
                            <description>Slave Device Static Address</description>
                            <lsb>0</lsb>
                            <msb>9</msb>
                            <access>read-write</access>
                        </field>
                        <field>
                            <name>SDADLS</name>
                            <description>Slave Device Address Length Selection</description>
                            <lsb>10</lsb>
                            <msb>10</msb>
                            <access>read-write</access>
                            <enumeratedValues>
                                <enumeratedValue>
                                    <name>0</name>
                                    <description>Slave device address length 7 bits selected.</description>
                                    <value>#0</value>
                                </enumeratedValue>
                                <enumeratedValue>
                                    <name>1</name>
                                    <description>Slave device address length 10 bits selected. (I2C device only) </description>
                                    <value>#1</value>
                                </enumeratedValue>
                            </enumeratedValues>
                        </field>
                        <field>
                            <name>SDIBIPL</name>
                            <description>Slave Device IBI Payload</description>
                            <lsb>12</lsb>
                            <msb>12</msb>
                            <access>read-write</access>
                            <enumeratedValues>
                                <enumeratedValue>
                                    <name>0</name>
                                    <description>IBIs from this device do not carry a data payload.</description>
                                    <value>#0</value>
                                </enumeratedValue>
                                <enumeratedValue>
                                    <name>1</name>
                                    <description>IBIs from this device carry a data payload.</description>
                                    <value>#1</value>
                                </enumeratedValue>
                            </enumeratedValues>
                        </field>
                        <field>
                            <name>SDDYAD</name>
                            <description>Slave Device I3C Dynamic Address</description>
                            <lsb>16</lsb>
                            <msb>22</msb>
                            <access>read-write</access>
                        </field>
                    </fields>
                </register>
                <register>
                    <dim>8</dim>
                    <dimIncrement>0x04</dimIncrement>
                    <dimIndex>0-7</dimIndex>
                    <name>MSDCT%s</name>
                    <description>Master Device Characteristic Table Register %s</description>
                    <addressOffset>0x2D0</addressOffset>
                    <size>32</size>
                    <access>read-write</access>
                    <resetValue>0x00000000</resetValue>
                    <resetMask>0xffffffff</resetMask>
                    <fields>
                        <field>
                            <name>RBCR0</name>
                            <description>Max Data Speed Limitation</description>
                            <lsb>8</lsb>
                            <msb>8</msb>
                            <access>read-write</access>
                            <enumeratedValues>
                                <enumeratedValue>
                                    <name>0</name>
                                    <description>No Limitation</description>
                                    <value>#0</value>
                                </enumeratedValue>
                                <enumeratedValue>
                                    <name>1</name>
                                    <description>Limitation</description>
                                    <value>#1</value>
                                </enumeratedValue>
                            </enumeratedValues>
                        </field>
                        <field>
                            <name>RBCR1</name>
                            <description>IBI Request Capable</description>
                            <lsb>9</lsb>
                            <msb>9</msb>
                            <access>read-write</access>
                            <enumeratedValues>
                                <enumeratedValue>
                                    <name>0</name>
                                    <description>Not Capable</description>
                                    <value>#0</value>
                                </enumeratedValue>
                                <enumeratedValue>
                                    <name>1</name>
                                    <description>Capable</description>
                                    <value>#1</value>
                                </enumeratedValue>
                            </enumeratedValues>
                        </field>
                        <field>
                            <name>RBCR2</name>
                            <description>IBI Payload</description>
                            <lsb>10</lsb>
                            <msb>10</msb>
                            <access>read-write</access>
                            <enumeratedValues>
                                <enumeratedValue>
                                    <name>0</name>
                                    <description>No data byte follows the accepted IBI.</description>
                                    <value>#0</value>
                                </enumeratedValue>
                                <enumeratedValue>
                                    <name>1</name>
                                    <description>Mandatory one or more data bytes follow the accepted IBI. Data byte continuation is indicated by T-Bit.</description>
                                    <value>#1</value>
                                </enumeratedValue>
                            </enumeratedValues>
                        </field>
                        <field>
                            <name>RBCR3</name>
                            <description>Offline Capable</description>
                            <lsb>11</lsb>
                            <msb>11</msb>
                            <access>read-write</access>
                            <enumeratedValues>
                                <enumeratedValue>
                                    <name>0</name>
                                    <description>Device will always respond to I3C bus commands.</description>
                                    <value>#0</value>
                                </enumeratedValue>
                                <enumeratedValue>
                                    <name>1</name>
                                    <description>Device will not always respond to I3C bus commands.</description>
                                    <value>#1</value>
                                </enumeratedValue>
                            </enumeratedValues>
                        </field>
                        <field>
                            <name>RBCR4</name>
                            <description>Bridge Identifier</description>
                            <lsb>12</lsb>
                            <msb>12</msb>
                            <access>read-write</access>
                            <enumeratedValues>
                                <enumeratedValue>
                                    <name>0</name>
                                    <description>Not a Bridge Device</description>
                                    <value>#0</value>
                                </enumeratedValue>
                                <enumeratedValue>
                                    <name>1</name>
                                    <description>A Bridge Device</description>
                                    <value>#1</value>
                                </enumeratedValue>
                            </enumeratedValues>
                        </field>
                        <field>
                            <name>RBCR5</name>
                            <description>SDR Only / SDR and HDR Capable</description>
                            <lsb>13</lsb>
                            <msb>13</msb>
                            <access>read-write</access>
                            <enumeratedValues>
                                <enumeratedValue>
                                    <name>0</name>
                                    <description>SDR only</description>
                                    <value>#0</value>
                                </enumeratedValue>
                                <enumeratedValue>
                                    <name>1</name>
                                    <description>HDR Capable</description>
                                    <value>#1</value>
                                </enumeratedValue>
                            </enumeratedValues>
                        </field>
                        <field>
                            <name>RBCR76</name>
                            <description>Device Role</description>
                            <lsb>14</lsb>
                            <msb>15</msb>
                            <access>read-write</access>
                            <enumeratedValues>
                                <enumeratedValue>
                                    <name>00</name>
                                    <description>I3C Slave</description>
                                    <value>#00</value>
                                </enumeratedValue>
                                <enumeratedValue>
                                    <name>01</name>
                                    <description>I3C Master</description>
                                    <value>#01</value>
                                </enumeratedValue>
                                <enumeratedValue>
                                    <name>Others</name>
                                    <description>Setting prohibited</description>
                                    <isDefault>true</isDefault>
                                </enumeratedValue>
                            </enumeratedValues>
                        </field>
                    </fields>
                </register>
                <register>
                    <name>SVDCT</name>
                    <description>Slave Device Characteristic Table Register</description>
                    <addressOffset>0x320</addressOffset>
                    <size>32</size>
                    <access>read-write</access>
                    <resetValue>0x00000000</resetValue>
                    <resetMask>0xffffffff</resetMask>
                    <fields>
                        <field>
                            <name>TDCR</name>
                            <description>Transfar Device Characteristic Register</description>
                            <lsb>0</lsb>
                            <msb>7</msb>
                            <access>read-write</access>
                        </field>
                        <field>
                            <name>TBCR0</name>
                            <description>Max Data Speed Limitation</description>
                            <lsb>8</lsb>
                            <msb>8</msb>
                            <access>read-write</access>
                            <enumeratedValues>
                                <enumeratedValue>
                                    <name>0</name>
                                    <description>No Limitation</description>
                                    <value>#0</value>
                                </enumeratedValue>
                                <enumeratedValue>
                                    <name>1</name>
                                    <description>Limitation</description>
                                    <value>#1</value>
                                </enumeratedValue>
                            </enumeratedValues>
                        </field>
                        <field>
                            <name>TBCR1</name>
                            <description>IBI Request Capable</description>
                            <lsb>9</lsb>
                            <msb>9</msb>
                            <access>read-write</access>
                            <enumeratedValues>
                                <enumeratedValue>
                                    <name>0</name>
                                    <description>Not Capable</description>
                                    <value>#0</value>
                                </enumeratedValue>
                                <enumeratedValue>
                                    <name>1</name>
                                    <description>Capable</description>
                                    <value>#1</value>
                                </enumeratedValue>
                            </enumeratedValues>
                        </field>
                        <field>
                            <name>TBCR2</name>
                            <description>IBI Payload</description>
                            <lsb>10</lsb>
                            <msb>10</msb>
                            <access>read-write</access>
                            <enumeratedValues>
                                <enumeratedValue>
                                    <name>0</name>
                                    <description>No data byte follows the accepted IBI.</description>
                                    <value>#0</value>
                                </enumeratedValue>
                                <enumeratedValue>
                                    <name>1</name>
                                    <description>Mandatory one or more data bytes follow the accepted IBI. Data byte continuation is indicated by T-Bit.</description>
                                    <value>#1</value>
                                </enumeratedValue>
                            </enumeratedValues>
                        </field>
                        <field>
                            <name>TBCR3</name>
                            <description>Offline Capable</description>
                            <lsb>11</lsb>
                            <msb>11</msb>
                            <access>read-write</access>
                            <enumeratedValues>
                                <enumeratedValue>
                                    <name>0</name>
                                    <description>Device will always respond to I3C bus commands.</description>
                                    <value>#0</value>
                                </enumeratedValue>
                                <enumeratedValue>
                                    <name>1</name>
                                    <description>Device will not always respond to I3C bus commands.</description>
                                    <value>#1</value>
                                </enumeratedValue>
                            </enumeratedValues>
                        </field>
                        <field>
                            <name>TBCR4</name>
                            <description>Bridge Identifier</description>
                            <lsb>12</lsb>
                            <msb>12</msb>
                            <access>read-write</access>
                            <enumeratedValues>
                                <enumeratedValue>
                                    <name>0</name>
                                    <description>Not a Bridge Device</description>
                                    <value>#0</value>
                                </enumeratedValue>
                                <enumeratedValue>
                                    <name>1</name>
                                    <description>A Bridge Device</description>
                                    <value>#1</value>
                                </enumeratedValue>
                            </enumeratedValues>
                        </field>
                        <field>
                            <name>TBCR5</name>
                            <description>SDR Only / SDR and HDR Capable</description>
                            <lsb>13</lsb>
                            <msb>13</msb>
                            <access>read-write</access>
                            <enumeratedValues>
                                <enumeratedValue>
                                    <name>0</name>
                                    <description>SDR only</description>
                                    <value>#0</value>
                                </enumeratedValue>
                                <enumeratedValue>
                                    <name>1</name>
                                    <description>HDR capable</description>
                                    <value>#1</value>
                                </enumeratedValue>
                            </enumeratedValues>
                        </field>
                        <field>
                            <name>TBCR76</name>
                            <description>Device Role</description>
                            <lsb>14</lsb>
                            <msb>15</msb>
                            <access>read-write</access>
                            <enumeratedValues>
                                <enumeratedValue>
                                    <name>00</name>
                                    <description>I3C Slave</description>
                                    <value>#00</value>
                                </enumeratedValue>
                                <enumeratedValue>
                                    <name>01</name>
                                    <description>I3C Master</description>
                                    <value>#01</value>
                                </enumeratedValue>
                                <enumeratedValue>
                                    <name>Others</name>
                                    <description>Setting prohibited</description>
                                    <isDefault>true</isDefault>
                                </enumeratedValue>
                            </enumeratedValues>
                        </field>
                    </fields>
                </register>
                <register>
                    <name>SDCTPIDL</name>
                    <description>Slave Device Characteristic Table Provisional ID Low Register</description>
                    <addressOffset>0x324</addressOffset>
                    <size>32</size>
                    <access>read-write</access>
                    <resetValue>0x00000000</resetValue>
                    <resetMask>0xffffffff</resetMask>
                </register>
                <register>
                    <name>SDCTPIDH</name>
                    <description>Slave Device Characteristic Table Provisional ID High Register</description>
                    <addressOffset>0x328</addressOffset>
                    <size>32</size>
                    <access>read-write</access>
                    <resetValue>0x00000000</resetValue>
                    <resetMask>0xffffffff</resetMask>
                </register>
                <register>
                    <dim>3</dim>
                    <dimIncrement>0x04</dimIncrement>
                    <dimIndex>0-2</dimIndex>
                    <name>SVDVAD%s</name>
                    <description>Slave Device Address Register %s</description>
                    <addressOffset>0x330</addressOffset>
                    <size>32</size>
                    <access>read-only</access>
                    <resetValue>0x00000000</resetValue>
                    <resetMask>0xffffffff</resetMask>
                    <fields>
                        <field>
                            <name>SVAD</name>
                            <description>Slave Address</description>
                            <lsb>16</lsb>
                            <msb>25</msb>
                            <access>read-only</access>
                        </field>
                        <field>
                            <name>SADLG</name>
                            <description>Slave Address Length</description>
                            <lsb>27</lsb>
                            <msb>27</msb>
                            <access>read-only</access>
                            <enumeratedValues>
                                <enumeratedValue>
                                    <name>0</name>
                                    <description>The 7-bit address format is selected.</description>
                                    <value>#0</value>
                                </enumeratedValue>
                                <enumeratedValue>
                                    <name>1</name>
                                    <description>The 10-bit address format is selected.</description>
                                    <value>#1</value>
                                </enumeratedValue>
                            </enumeratedValues>
                        </field>
                        <field>
                            <name>SSTADV</name>
                            <description>Slave Static Address Valid</description>
                            <lsb>30</lsb>
                            <msb>30</msb>
                            <access>read-only</access>
                            <enumeratedValues>
                                <enumeratedValue>
                                    <name>0</name>
                                    <description>Slave address is disabled.</description>
                                    <value>#0</value>
                                </enumeratedValue>
                                <enumeratedValue>
                                    <name>1</name>
                                    <description>Slave address is enabled.</description>
                                    <value>#1</value>
                                </enumeratedValue>
                            </enumeratedValues>
                        </field>
                        <field>
                            <name>SDYADV</name>
                            <description>Slave Dynamic Address Valid</description>
                            <lsb>31</lsb>
                            <msb>31</msb>
                            <access>read-only</access>
                            <enumeratedValues>
                                <enumeratedValue>
                                    <name>0</name>
                                    <description>Dynamic Address is disabled.</description>
                                    <value>#0</value>
                                </enumeratedValue>
                                <enumeratedValue>
                                    <name>1</name>
                                    <description>Dynamic Address is enabled.</description>
                                    <value>#1</value>
                                </enumeratedValue>
                            </enumeratedValues>
                        </field>
                    </fields>
                </register>
                <register>
                    <name>CSECMD</name>
                    <description>CCC Slave Events Command Register</description>
                    <addressOffset>0x350</addressOffset>
                    <size>32</size>
                    <access>read-write</access>
                    <resetValue>0x00000000</resetValue>
                    <resetMask>0xffffffff</resetMask>
                    <fields>
                        <field>
                            <name>SVIRQE</name>
                            <description>Slave Interrupt Requests Enable</description>
                            <lsb>0</lsb>
                            <msb>0</msb>
                            <access>read-write</access>
                            <enumeratedValues>
                                <enumeratedValue>
                                    <name>0</name>
                                    <description>DISABLED: Slave-initiated Interrupts is Disabled by the Master to control.</description>
                                    <value>#0</value>
                                </enumeratedValue>
                                <enumeratedValue>
                                    <name>1</name>
                                    <description>ENABLED: Slave-initiated Interrupts is Enabled by the Master to control.</description>
                                    <value>#1</value>
                                </enumeratedValue>
                            </enumeratedValues>
                        </field>
                        <field>
                            <name>MSRQE</name>
                            <description>Mastership Requests Enable</description>
                            <lsb>1</lsb>
                            <msb>1</msb>
                            <access>read-write</access>
                            <enumeratedValues>
                                <enumeratedValue>
                                    <name>0</name>
                                    <description>DISABLED: Mastership requests from Secondary Masters is Disabled by the Current Master to control.</description>
                                    <value>#0</value>
                                </enumeratedValue>
                                <enumeratedValue>
                                    <name>1</name>
                                    <description>ENABLED: Mastership requests from Secondary Masters is Enabled by the Current Master to control.</description>
                                    <value>#1</value>
                                </enumeratedValue>
                            </enumeratedValues>
                        </field>
                    </fields>
                </register>
                <register>
                    <name>CEACTST</name>
                    <description>CCC Enter Activity State Register</description>
                    <addressOffset>0x354</addressOffset>
                    <size>32</size>
                    <access>read-write</access>
                    <resetValue>0x00000000</resetValue>
                    <resetMask>0xffffffff</resetMask>
                    <fields>
                        <field>
                            <name>ACTST</name>
                            <description>Activity State</description>
                            <lsb>0</lsb>
                            <msb>3</msb>
                            <access>read-write</access>
                            <enumeratedValues>
                                <enumeratedValue>
                                    <name>0x1</name>
                                    <description>ENTAS0 (1µs: Latency-free operation)</description>
                                    <value>0x1</value>
                                </enumeratedValue>
                                <enumeratedValue>
                                    <name>0x2</name>
                                    <description>ENTAS1 (100 µs)</description>
                                    <value>0x2</value>
                                </enumeratedValue>
                                <enumeratedValue>
                                    <name>0x4</name>
                                    <description>ENTAS2 (2 ms)</description>
                                    <value>0x4</value>
                                </enumeratedValue>
                                <enumeratedValue>
                                    <name>0x8</name>
                                    <description>ENTAS3 (50 ms: Lowest-activity operation)</description>
                                    <value>0x8</value>
                                </enumeratedValue>
                                <enumeratedValue>
                                    <name>Others</name>
                                    <description>Setting prohibited</description>
                                    <isDefault>true</isDefault>
                                </enumeratedValue>
                            </enumeratedValues>
                        </field>
                    </fields>
                </register>
                <register>
                    <name>CMWLG</name>
                    <description>CCC Max Write Length Register</description>
                    <addressOffset>0x358</addressOffset>
                    <size>32</size>
                    <access>read-write</access>
                    <resetValue>0x00000000</resetValue>
                    <resetMask>0xffffffff</resetMask>
                    <fields>
                        <field>
                            <name>MWLG</name>
                            <description>Max Write Length</description>
                            <lsb>0</lsb>
                            <msb>15</msb>
                            <access>read-write</access>
                        </field>
                    </fields>
                </register>
                <register>
                    <name>CMRLG</name>
                    <description>CCC Max Read Length Register</description>
                    <addressOffset>0x35C</addressOffset>
                    <size>32</size>
                    <access>read-write</access>
                    <resetValue>0x00000000</resetValue>
                    <resetMask>0xffffffff</resetMask>
                    <fields>
                        <field>
                            <name>MRLG</name>
                            <description>Max Read Length</description>
                            <lsb>0</lsb>
                            <msb>15</msb>
                            <access>read-write</access>
                        </field>
                        <field>
                            <name>IBIPSZ</name>
                            <description>IBI Payload Size</description>
                            <lsb>16</lsb>
                            <msb>23</msb>
                            <access>read-write</access>
                        </field>
                    </fields>
                </register>
                <register>
                    <name>CETSTMD</name>
                    <description>CCC Enter Test Mode Register</description>
                    <addressOffset>0x360</addressOffset>
                    <size>32</size>
                    <access>read-only</access>
                    <resetValue>0x00000000</resetValue>
                    <resetMask>0xffffffff</resetMask>
                    <fields>
                        <field>
                            <name>TSTMD</name>
                            <description>Test Mode</description>
                            <lsb>0</lsb>
                            <msb>7</msb>
                            <access>read-only</access>
                            <enumeratedValues>
                                <enumeratedValue>
                                    <name>0x00</name>
                                    <description>Exit Test Mode This value removes all I3C devices from Test Mode. </description>
                                    <value>0x00</value>
                                </enumeratedValue>
                                <enumeratedValue>
                                    <name>0x01</name>
                                    <description>Vendor Test Mode This value indicates that I3C devices shall return a random 32bit value in the provisional ID during the Dynamic Address Assignment procedure. </description>
                                    <value>0x01</value>
                                </enumeratedValue>
                                <enumeratedValue>
                                    <name>Others</name>
                                    <description>Setting prohibited </description>
                                    <isDefault>true</isDefault>
                                </enumeratedValue>
                            </enumeratedValues>
                        </field>
                    </fields>
                </register>
                <register>
                    <name>CGDVST</name>
                    <description>CCC Get Device Status Register</description>
                    <addressOffset>0x364</addressOffset>
                    <size>32</size>
                    <access>read-write</access>
                    <resetValue>0x00000000</resetValue>
                    <resetMask>0xffffffff</resetMask>
                    <fields>
                        <field>
                            <name>PNDINT</name>
                            <description>Pending Interrupt</description>
                            <lsb>0</lsb>
                            <msb>3</msb>
                            <access>read-write</access>
                        </field>
                        <field>
                            <name>PRTE</name>
                            <description>Protocol Error</description>
                            <lsb>5</lsb>
                            <msb>5</msb>
                            <access>read-write</access>
                            <enumeratedValues>
                                <enumeratedValue>
                                    <name>0</name>
                                    <description>The Slave has not detected a protocol error since the last Status read.</description>
                                    <value>#0</value>
                                </enumeratedValue>
                                <enumeratedValue>
                                    <name>1</name>
                                    <description>The Slave has detected a protocol error since the last Status read.</description>
                                    <value>#1</value>
                                </enumeratedValue>
                            </enumeratedValues>
                        </field>
                        <field>
                            <name>ACTMD</name>
                            <description>Slave Device’s current Activity Mode</description>
                            <lsb>6</lsb>
                            <msb>7</msb>
                            <access>read-write</access>
                            <enumeratedValues>
                                <enumeratedValue>
                                    <name>00</name>
                                    <description>Activity Mode 0</description>
                                    <value>#00</value>
                                </enumeratedValue>
                                <enumeratedValue>
                                    <name>01</name>
                                    <description>Activity Mode 1</description>
                                    <value>#01</value>
                                </enumeratedValue>
                                <enumeratedValue>
                                    <name>10</name>
                                    <description>Activity Mode 2</description>
                                    <value>#10</value>
                                </enumeratedValue>
                                <enumeratedValue>
                                    <name>11</name>
                                    <description>Activity Mode 3</description>
                                    <value>#11</value>
                                </enumeratedValue>
                            </enumeratedValues>
                        </field>
                        <field>
                            <name>VDRSV</name>
                            <description>Vendor Reserved</description>
                            <lsb>8</lsb>
                            <msb>15</msb>
                            <access>read-write</access>
                        </field>
                    </fields>
                </register>
                <register>
                    <name>CMDSPW</name>
                    <description>CCC Max Data Speed W (Write) Register</description>
                    <addressOffset>0x368</addressOffset>
                    <size>32</size>
                    <access>read-write</access>
                    <resetValue>0x00000000</resetValue>
                    <resetMask>0xffffffff</resetMask>
                    <fields>
                        <field>
                            <name>MSWDR</name>
                            <description>Maximum Sustained Write Data Rate</description>
                            <lsb>0</lsb>
                            <msb>2</msb>
                            <access>read-write</access>
                            <enumeratedValues>
                                <enumeratedValue>
                                    <name>000</name>
                                    <description>fscl Max (default value)</description>
                                    <value>#000</value>
                                </enumeratedValue>
                                <enumeratedValue>
                                    <name>001</name>
                                    <description>8 MHz</description>
                                    <value>#001</value>
                                </enumeratedValue>
                                <enumeratedValue>
                                    <name>010</name>
                                    <description>6 MHz</description>
                                    <value>#010</value>
                                </enumeratedValue>
                                <enumeratedValue>
                                    <name>011</name>
                                    <description>4 MHz</description>
                                    <value>#011</value>
                                </enumeratedValue>
                                <enumeratedValue>
                                    <name>100</name>
                                    <description>2 MHz</description>
                                    <value>#100</value>
                                </enumeratedValue>
                                <enumeratedValue>
                                    <name>Others</name>
                                    <description>Setting prohibited</description>
                                    <isDefault>true</isDefault>
                                </enumeratedValue>
                            </enumeratedValues>
                        </field>
                    </fields>
                </register>
                <register>
                    <name>CMDSPR</name>
                    <description>CCC Max Data Speed R (Read) Register</description>
                    <addressOffset>0x36C</addressOffset>
                    <size>32</size>
                    <access>read-write</access>
                    <resetValue>0x00000000</resetValue>
                    <resetMask>0xffffffff</resetMask>
                    <fields>
                        <field>
                            <name>MSRDR</name>
                            <description>Maximum Sustained Read Data Rate</description>
                            <lsb>0</lsb>
                            <msb>2</msb>
                            <access>read-write</access>
                            <enumeratedValues>
                                <enumeratedValue>
                                    <name>000</name>
                                    <description>fscl Max (default value)</description>
                                    <value>#000</value>
                                </enumeratedValue>
                                <enumeratedValue>
                                    <name>001</name>
                                    <description>8 MHz</description>
                                    <value>#001</value>
                                </enumeratedValue>
                                <enumeratedValue>
                                    <name>010</name>
                                    <description>6 MHz</description>
                                    <value>#010</value>
                                </enumeratedValue>
                                <enumeratedValue>
                                    <name>011</name>
                                    <description>4 MHz</description>
                                    <value>#011</value>
                                </enumeratedValue>
                                <enumeratedValue>
                                    <name>100</name>
                                    <description>2 MHz</description>
                                    <value>#100</value>
                                </enumeratedValue>
                                <enumeratedValue>
                                    <name>Others</name>
                                    <description>Setting prohibited</description>
                                    <isDefault>true</isDefault>
                                </enumeratedValue>
                            </enumeratedValues>
                        </field>
                        <field>
                            <name>CDTTIM</name>
                            <description>Clock to Data Turnaround Time (TSCO)</description>
                            <lsb>3</lsb>
                            <msb>5</msb>
                            <access>read-write</access>
                            <enumeratedValues>
                                <enumeratedValue>
                                    <name>000</name>
                                    <description>8 ns or less (default value)</description>
                                    <value>#000</value>
                                </enumeratedValue>
                                <enumeratedValue>
                                    <name>001</name>
                                    <description>9 ns or less</description>
                                    <value>#001</value>
                                </enumeratedValue>
                                <enumeratedValue>
                                    <name>010</name>
                                    <description>10 ns or less</description>
                                    <value>#010</value>
                                </enumeratedValue>
                                <enumeratedValue>
                                    <name>011</name>
                                    <description>11 ns or less</description>
                                    <value>#011</value>
                                </enumeratedValue>
                                <enumeratedValue>
                                    <name>100</name>
                                    <description>12 ns or less</description>
                                    <value>#100</value>
                                </enumeratedValue>
                                <enumeratedValue>
                                    <name>111</name>
                                    <description>TSCO is more than 12 ns, and is reported by private agreement.</description>
                                    <value>#111</value>
                                </enumeratedValue>
                                <enumeratedValue>
                                    <name>Others</name>
                                    <description>Setting prohibited</description>
                                    <isDefault>true</isDefault>
                                </enumeratedValue>
                            </enumeratedValues>
                        </field>
                    </fields>
                </register>
                <register>
                    <name>CMDSPT</name>
                    <description>CCC Max Data Speed T (Turnaround) Register</description>
                    <addressOffset>0x370</addressOffset>
                    <size>32</size>
                    <access>read-write</access>
                    <resetValue>0x00000000</resetValue>
                    <resetMask>0xffffffff</resetMask>
                    <fields>
                        <field>
                            <name>MRTTIM</name>
                            <description>Maximum Read Turnaround Time</description>
                            <lsb>0</lsb>
                            <msb>23</msb>
                            <access>read-write</access>
                        </field>
                        <field>
                            <name>MRTE</name>
                            <description>Maximum Read Turnaround Time Enable</description>
                            <lsb>31</lsb>
                            <msb>31</msb>
                            <access>read-write</access>
                            <enumeratedValues>
                                <enumeratedValue>
                                    <name>0</name>
                                    <description>Disables transmission of the Maximum Read Turnaround Time. (GETMXDS Format 1: Without Turnaround) </description>
                                    <value>#0</value>
                                </enumeratedValue>
                                <enumeratedValue>
                                    <name>1</name>
                                    <description>Enables transmission of the Maximum Read Turnaround Time. (GETMXDS Format 2: With Turnaround) </description>
                                    <value>#1</value>
                                </enumeratedValue>
                            </enumeratedValues>
                        </field>
                    </fields>
                </register>
                <register>
                    <name>CETSM</name>
                    <description>CCC Exchange Timing Support Information M (Mode) Register</description>
                    <addressOffset>0x374</addressOffset>
                    <size>32</size>
                    <access>read-write</access>
                    <resetValue>0x00000000</resetValue>
                    <resetMask>0xffffffff</resetMask>
                    <fields>
                        <field>
                            <name>SPTSYN</name>
                            <description>Supports Sync Mode</description>
                            <lsb>0</lsb>
                            <msb>0</msb>
                            <access>read-write</access>
                            <enumeratedValues>
                                <enumeratedValue>
                                    <name>0</name>
                                    <description>Sync Mode is not supported.</description>
                                    <value>#0</value>
                                </enumeratedValue>
                                <enumeratedValue>
                                    <name>1</name>
                                    <description>Sync Mode is supported.</description>
                                    <value>#1</value>
                                </enumeratedValue>
                            </enumeratedValues>
                        </field>
                        <field>
                            <name>SPTASYN0</name>
                            <description>Support Async Mode 0</description>
                            <lsb>1</lsb>
                            <msb>1</msb>
                            <access>read-write</access>
                            <enumeratedValues>
                                <enumeratedValue>
                                    <name>0</name>
                                    <description>Async Mode 0 is not supported.</description>
                                    <value>#0</value>
                                </enumeratedValue>
                                <enumeratedValue>
                                    <name>1</name>
                                    <description>Async Mode 0 is supported.</description>
                                    <value>#1</value>
                                </enumeratedValue>
                            </enumeratedValues>
                        </field>
                        <field>
                            <name>SPTASYN1</name>
                            <description>Support Async Mode 1</description>
                            <lsb>2</lsb>
                            <msb>2</msb>
                            <access>read-write</access>
                            <enumeratedValues>
                                <enumeratedValue>
                                    <name>0</name>
                                    <description>Async Mode 1 is not supported.</description>
                                    <value>#0</value>
                                </enumeratedValue>
                                <enumeratedValue>
                                    <name>1</name>
                                    <description>Async Mode 1 is supported.</description>
                                    <value>#1</value>
                                </enumeratedValue>
                            </enumeratedValues>
                        </field>
                        <field>
                            <name>FREQ</name>
                            <description>Frequency Byte</description>
                            <lsb>8</lsb>
                            <msb>15</msb>
                            <access>read-write</access>
                        </field>
                        <field>
                            <name>INAC</name>
                            <description>Inaccuracy Byte</description>
                            <lsb>16</lsb>
                            <msb>23</msb>
                            <access>read-write</access>
                        </field>
                    </fields>
                </register>
                <register>
                    <name>CETSS</name>
                    <description>CCC Exchange Timing Support Information S (State) Register</description>
                    <addressOffset>0x378</addressOffset>
                    <size>32</size>
                    <access>read-write</access>
                    <resetValue>0x00000000</resetValue>
                    <resetMask>0xffffffff</resetMask>
                    <fields>
                        <field>
                            <name>SYNE</name>
                            <description>Sync Mode Enabled</description>
                            <lsb>0</lsb>
                            <msb>0</msb>
                            <access>read-write</access>
                            <enumeratedValues>
                                <enumeratedValue>
                                    <name>0</name>
                                    <description>Sync Mode Disabled</description>
                                    <value>#0</value>
                                </enumeratedValue>
                                <enumeratedValue>
                                    <name>1</name>
                                    <description>Sync Mode Enabled</description>
                                    <value>#1</value>
                                </enumeratedValue>
                            </enumeratedValues>
                        </field>
                        <field>
                            <name>ASYNE</name>
                            <description>Async Mode Enabled</description>
                            <lsb>1</lsb>
                            <msb>2</msb>
                            <access>read-write</access>
                            <enumeratedValues>
                                <enumeratedValue>
                                    <name>00</name>
                                    <description>All Mode Disable</description>
                                    <value>#00</value>
                                </enumeratedValue>
                                <enumeratedValue>
                                    <name>01</name>
                                    <description>Async Mode 0 Enabled</description>
                                    <value>#01</value>
                                </enumeratedValue>
                                <enumeratedValue>
                                    <name>10</name>
                                    <description>Async Mode 1 Enabled</description>
                                    <value>#10</value>
                                </enumeratedValue>
                                <enumeratedValue>
                                    <name>Others</name>
                                    <description>Setting prohibited</description>
                                    <isDefault>true</isDefault>
                                </enumeratedValue>
                            </enumeratedValues>
                        </field>
                        <field>
                            <name>ICOVF</name>
                            <description>Internal Counter Overflow</description>
                            <lsb>7</lsb>
                            <msb>7</msb>
                            <access>read-write</access>
                            <enumeratedValues>
                                <enumeratedValue>
                                    <name>0</name>
                                    <description>Slave has not experienced a counter overflow since the most recent previous check.</description>
                                    <value>#0</value>
                                </enumeratedValue>
                                <enumeratedValue>
                                    <name>1</name>
                                    <description>Slave experienced a counter overflow since the most recent previous check.</description>
                                    <value>#1</value>
                                </enumeratedValue>
                            </enumeratedValues>
                        </field>
                    </fields>
                </register>
                <register>
                    <name>CGHDRCAP</name>
                    <description>CCC Get HDR Capability Register</description>
                    <addressOffset>0x37C</addressOffset>
                    <size>32</size>
                    <access>read-write</access>
                    <resetValue>0x00000000</resetValue>
                    <resetMask>0xffffffff</resetMask>
                    <fields>
                        <field>
                            <name>DDREN</name>
                            <description>HDR-DDR Operation Enable</description>
                            <lsb>0</lsb>
                            <msb>0</msb>
                            <access>read-write</access>
                            <enumeratedValues>
                                <enumeratedValue>
                                    <name>0</name>
                                    <description>HDR-DDR Operation is Disabled.</description>
                                    <value>#0</value>
                                </enumeratedValue>
                                <enumeratedValue>
                                    <name>1</name>
                                    <description>HDR-DDR Operation is Enabled.</description>
                                    <value>#1</value>
                                </enumeratedValue>
                            </enumeratedValues>
                        </field>
                        <field>
                            <name>TSPEN</name>
                            <description>HDR-TSP Operation Enable</description>
                            <lsb>1</lsb>
                            <msb>1</msb>
                            <access>read-write</access>
                            <enumeratedValues>
                                <enumeratedValue>
                                    <name>0</name>
                                    <description>HDR-TSP Operation is Disabled.</description>
                                    <value>#0</value>
                                </enumeratedValue>
                                <enumeratedValue>
                                    <name>1</name>
                                    <description>HDR-TSP Operation is Enabled.</description>
                                    <value>#1</value>
                                </enumeratedValue>
                            </enumeratedValues>
                        </field>
                        <field>
                            <name>TSLEN</name>
                            <description>HDR-TSL Operation Enable</description>
                            <lsb>2</lsb>
                            <msb>2</msb>
                            <access>read-write</access>
                            <enumeratedValues>
                                <enumeratedValue>
                                    <name>0</name>
                                    <description>HDR-TSL Operation is Disabled.</description>
                                    <value>#0</value>
                                </enumeratedValue>
                                <enumeratedValue>
                                    <name>1</name>
                                    <description>HDR-TSL Operation is Enabled.</description>
                                    <value>#1</value>
                                </enumeratedValue>
                            </enumeratedValues>
                        </field>
                    </fields>
                </register>
                <register>
                    <name>BITCNT</name>
                    <description>Bit Count Register</description>
                    <addressOffset>0x380</addressOffset>
                    <size>32</size>
                    <access>read-only</access>
                    <resetValue>0x00000000</resetValue>
                    <resetMask>0xffffffff</resetMask>
                    <fields>
                        <field>
                            <name>BCNT</name>
                            <description>Bit Counter</description>
                            <lsb>0</lsb>
                            <msb>4</msb>
                            <access>read-only</access>
                        </field>
                    </fields>
                </register>
                <register>
                    <name>NQSTLV</name>
                    <description>Normal Queue Status Level Register</description>
                    <addressOffset>0x394</addressOffset>
                    <size>32</size>
                    <access>read-only</access>
                    <resetValue>0x00000004</resetValue>
                    <resetMask>0xffffffff</resetMask>
                    <fields>
                        <field>
                            <name>CMDQFLV</name>
                            <description>Normal Command Queue Free Level</description>
                            <lsb>0</lsb>
                            <msb>7</msb>
                            <access>read-only</access>
                        </field>
                        <field>
                            <name>RSPQLV</name>
                            <description>Normal Response Queue Level</description>
                            <lsb>8</lsb>
                            <msb>15</msb>
                            <access>read-only</access>
                        </field>
                        <field>
                            <name>IBIQLV</name>
                            <description>Normal IBI Queue Level</description>
                            <lsb>16</lsb>
                            <msb>23</msb>
                            <access>read-only</access>
                        </field>
                        <field>
                            <name>IBISCNT</name>
                            <description>Normal IBI Status Count</description>
                            <lsb>24</lsb>
                            <msb>28</msb>
                            <access>read-only</access>
                        </field>
                    </fields>
                </register>
                <register>
                    <name>NDBSTLV0</name>
                    <description>Normal Data Buffer Status Level Register 0</description>
                    <addressOffset>0x398</addressOffset>
                    <size>32</size>
                    <access>read-only</access>
                    <resetValue>0x00000001</resetValue>
                    <resetMask>0xffffffff</resetMask>
                    <fields>
                        <field>
                            <name>TDBFLV</name>
                            <description>Normal Tx Data Buffer Free Level</description>
                            <lsb>0</lsb>
                            <msb>7</msb>
                            <access>read-only</access>
                        </field>
                        <field>
                            <name>RDBLV</name>
                            <description>Normal Rx Data Buffer Level</description>
                            <lsb>8</lsb>
                            <msb>15</msb>
                            <access>read-only</access>
                        </field>
                    </fields>
                </register>
                <register>
                    <name>NRSQSTLV</name>
                    <description>Normal Receive Status Queue Status Level Register</description>
                    <addressOffset>0x3C0</addressOffset>
                    <size>32</size>
                    <access>read-only</access>
                    <resetValue>0x00000000</resetValue>
                    <resetMask>0xffffffff</resetMask>
                    <fields>
                        <field>
                            <name>RSQLV</name>
                            <description>Normal Receive Status Queue Level</description>
                            <lsb>0</lsb>
                            <msb>7</msb>
                            <access>read-only</access>
                        </field>
                    </fields>
                </register>
                <register>
                    <name>HQSTLV</name>
                    <description>High Priority Queue Status Level Register</description>
                    <addressOffset>0x3C4</addressOffset>
                    <size>32</size>
                    <access>read-only</access>
                    <resetValue>0x00000002</resetValue>
                    <resetMask>0xffffffff</resetMask>
                    <fields>
                        <field>
                            <name>CMDQLV</name>
                            <description>High Priority Command Queue Level</description>
                            <lsb>0</lsb>
                            <msb>7</msb>
                            <access>read-only</access>
                        </field>
                        <field>
                            <name>RSPQLV</name>
                            <description>High Priority Response Queue Level</description>
                            <lsb>8</lsb>
                            <msb>15</msb>
                            <access>read-only</access>
                        </field>
                    </fields>
                </register>
                <register>
                    <name>HDBSTLV</name>
                    <description>High Priority Data Buffer Status Level Register</description>
                    <addressOffset>0x3C8</addressOffset>
                    <size>32</size>
                    <access>read-only</access>
                    <resetValue>0x00000002</resetValue>
                    <resetMask>0xffffffff</resetMask>
                    <fields>
                        <field>
                            <name>TDBFLV</name>
                            <description>High Priority Tx Data Buffer Free Level</description>
                            <lsb>0</lsb>
                            <msb>7</msb>
                            <access>read-only</access>
                        </field>
                        <field>
                            <name>RDBLV</name>
                            <description>High Priority Rx Data Buffer Level</description>
                            <lsb>8</lsb>
                            <msb>15</msb>
                            <access>read-only</access>
                        </field>
                    </fields>
                </register>
                <register>
                    <name>PRSTDBG</name>
                    <description>Present State Debug Register</description>
                    <addressOffset>0x3CC</addressOffset>
                    <size>32</size>
                    <access>read-only</access>
                    <resetValue>0x0000000f</resetValue>
                    <resetMask>0xffffffff</resetMask>
                    <fields>
                        <field>
                            <name>SCILV</name>
                            <description>I3C_SCL Line Signal Level</description>
                            <lsb>0</lsb>
                            <msb>0</msb>
                            <access>read-only</access>
                        </field>
                        <field>
                            <name>SDILV</name>
                            <description>I3C_SDA Line Signal Level</description>
                            <lsb>1</lsb>
                            <msb>1</msb>
                            <access>read-only</access>
                        </field>
                        <field>
                            <name>SCOLV</name>
                            <description>SCL Output Level</description>
                            <lsb>2</lsb>
                            <msb>2</msb>
                            <access>read-only</access>
                            <enumeratedValues>
                                <enumeratedValue>
                                    <name>0</name>
                                    <description>I3C has driven the I3C_SCL pin low.</description>
                                    <value>#0</value>
                                </enumeratedValue>
                                <enumeratedValue>
                                    <name>1</name>
                                    <description>I3C has released the I3C_SCL pin.</description>
                                    <value>#1</value>
                                </enumeratedValue>
                            </enumeratedValues>
                        </field>
                        <field>
                            <name>SDOLV</name>
                            <description>SDA Output Level</description>
                            <lsb>3</lsb>
                            <msb>3</msb>
                            <access>read-only</access>
                            <enumeratedValues>
                                <enumeratedValue>
                                    <name>0</name>
                                    <description>I3C has driven the I3C_SDA pin low.</description>
                                    <value>#0</value>
                                </enumeratedValue>
                                <enumeratedValue>
                                    <name>1</name>
                                    <description>I3C has released the I3C_SDA pin.</description>
                                    <value>#1</value>
                                </enumeratedValue>
                            </enumeratedValues>
                        </field>
                    </fields>
                </register>
                <register>
                    <name>MSERRCNT</name>
                    <description>Master Error Counters Register</description>
                    <addressOffset>0x3D0</addressOffset>
                    <size>32</size>
                    <access>read-only</access>
                    <resetValue>0x00000000</resetValue>
                    <resetMask>0xffffffff</resetMask>
                    <fields>
                        <field>
                            <name>M2ECNT</name>
                            <description>M2 Error Counter</description>
                            <lsb>0</lsb>
                            <msb>7</msb>
                            <access>read-only</access>
                        </field>
                    </fields>
                </register>
                <register>
                    <name>SC1CPT</name>
                    <description>SC1 Capture Monitor Register</description>
                    <addressOffset>0x3E0</addressOffset>
                    <size>32</size>
                    <access>read-only</access>
                    <resetValue>0x00000000</resetValue>
                    <resetMask>0xffffffff</resetMask>
                    <fields>
                        <field>
                            <name>SC1C</name>
                            <description>SC1 Capture</description>
                            <lsb>0</lsb>
                            <msb>15</msb>
                            <access>read-only</access>
                        </field>
                    </fields>
                </register>
                <register>
                    <name>SC2CPT</name>
                    <description>SC2 Capture Monitor Register</description>
                    <addressOffset>0x3E4</addressOffset>
                    <size>32</size>
                    <access>read-only</access>
                    <resetValue>0x00000000</resetValue>
                    <resetMask>0xffffffff</resetMask>
                    <fields>
                        <field>
                            <name>SC2C</name>
                            <description>SC2 Capture</description>
                            <lsb>0</lsb>
                            <msb>15</msb>
                            <access>read-only</access>
                        </field>
                    </fields>
                </register>
            </registers>
        </peripheral>
        <peripheral>
            <name>ECCMB0_NS</name>
            <description>ECCMB0</description>
            <baseAddress>0x5036F200</baseAddress>
            <addressBlock>
                <offset>0x00</offset>
                <size>6</size>
                <usage>registers</usage>
            </addressBlock>
            <addressBlock>
                <offset>0x0C</offset>
                <size>8</size>
                <usage>registers</usage>
            </addressBlock>
            <registers>
                <register>
                    <name>EC710CTL</name>
                    <description>ECC Control Register</description>
                    <addressOffset>0x00</addressOffset>
                    <size>32</size>
                    <access>read-write</access>
                    <resetValue>0x00000010</resetValue>
                    <resetMask>0xffffffff</resetMask>
                    <fields>
                        <field>
                            <name>ECEMF</name>
                            <description>ECC Error Message Flag</description>
                            <lsb>0</lsb>
                            <msb>0</msb>
                            <access>read-only</access>
                            <enumeratedValues>
                                <enumeratedValue>
                                    <name>0</name>
                                    <description>There is no bit error in present RAM output data</description>
                                    <value>#0</value>
                                </enumeratedValue>
                                <enumeratedValue>
                                    <name>1</name>
                                    <description>There is bit error in present RAM output data</description>
                                    <value>#1</value>
                                </enumeratedValue>
                            </enumeratedValues>
                        </field>
                        <field>
                            <name>ECER1F</name>
                            <description>ECC Error Detection and Correction Flag</description>
                            <lsb>1</lsb>
                            <msb>1</msb>
                            <access>read-only</access>
                            <enumeratedValues>
                                <enumeratedValue>
                                    <name>0</name>
                                    <description>After clearing this bit, 1-bit error correction has not occurred</description>
                                    <value>#0</value>
                                </enumeratedValue>
                                <enumeratedValue>
                                    <name>1</name>
                                    <description>1-bit error has occurred</description>
                                    <value>#1</value>
                                </enumeratedValue>
                            </enumeratedValues>
                        </field>
                        <field>
                            <name>ECER2F</name>
                            <description>2-bit ECC Error Detection Flag</description>
                            <lsb>2</lsb>
                            <msb>2</msb>
                            <access>read-only</access>
                            <enumeratedValues>
                                <enumeratedValue>
                                    <name>0</name>
                                    <description>After clearing this bit, 2-bit error has not occurred</description>
                                    <value>#0</value>
                                </enumeratedValue>
                                <enumeratedValue>
                                    <name>1</name>
                                    <description>2-bit error has occurred</description>
                                    <value>#1</value>
                                </enumeratedValue>
                            </enumeratedValues>
                        </field>
                        <field>
                            <name>EC1EDIC</name>
                            <description>ECC 1-bit Error Detection Interrupt Control</description>
                            <lsb>3</lsb>
                            <msb>3</msb>
                            <access>read-write</access>
                            <enumeratedValues>
                                <enumeratedValue>
                                    <name>0</name>
                                    <description>Disable 1-bit error detection interrupt request</description>
                                    <value>#0</value>
                                </enumeratedValue>
                                <enumeratedValue>
                                    <name>1</name>
                                    <description>Enable 1-bit error detection interrupt request</description>
                                    <value>#1</value>
                                </enumeratedValue>
                            </enumeratedValues>
                        </field>
                        <field>
                            <name>EC2EDIC</name>
                            <description>ECC 2-bit Error Detection Interrupt Control</description>
                            <lsb>4</lsb>
                            <msb>4</msb>
                            <access>read-write</access>
                            <enumeratedValues>
                                <enumeratedValue>
                                    <name>0</name>
                                    <description>Disable 2-bit error detection interrupt request</description>
                                    <value>#0</value>
                                </enumeratedValue>
                                <enumeratedValue>
                                    <name>1</name>
                                    <description>Enable 2-bit error detection interrupt request</description>
                                    <value>#1</value>
                                </enumeratedValue>
                            </enumeratedValues>
                        </field>
                        <field>
                            <name>EC1ECP</name>
                            <description>ECC 1-bit Error Correction Permission</description>
                            <lsb>5</lsb>
                            <msb>5</msb>
                            <access>read-write</access>
                            <enumeratedValues>
                                <enumeratedValue>
                                    <name>0</name>
                                    <description>At 1-bit error detection, the error correction is executed</description>
                                    <value>#0</value>
                                </enumeratedValue>
                                <enumeratedValue>
                                    <name>1</name>
                                    <description>At 1-bit error detection, the error correction is not executed</description>
                                    <value>#1</value>
                                </enumeratedValue>
                            </enumeratedValues>
                        </field>
                        <field>
                            <name>ECERVF</name>
                            <description>ECC Error Judgment Enable Flag</description>
                            <lsb>6</lsb>
                            <msb>6</msb>
                            <access>read-write</access>
                            <enumeratedValues>
                                <enumeratedValue>
                                    <name>0</name>
                                    <description>Error judgment disable</description>
                                    <value>#0</value>
                                </enumeratedValue>
                                <enumeratedValue>
                                    <name>1</name>
                                    <description>Error judgment enable</description>
                                    <value>#1</value>
                                </enumeratedValue>
                            </enumeratedValues>
                        </field>
                        <field>
                            <name>ECER1C</name>
                            <description>Accumulating ECC Error Detection and Correction Flag Clear</description>
                            <lsb>9</lsb>
                            <msb>9</msb>
                            <access>read-write</access>
                            <enumeratedValues>
                                <enumeratedValue>
                                    <name>0</name>
                                    <description>No effect</description>
                                    <value>#0</value>
                                </enumeratedValue>
                                <enumeratedValue>
                                    <name>1</name>
                                    <description>Clear accumulating ECC error detection and correction flag</description>
                                    <value>#1</value>
                                </enumeratedValue>
                            </enumeratedValues>
                        </field>
                        <field>
                            <name>ECER2C</name>
                            <description>2-bit ECC Error Detection Flag Clear</description>
                            <lsb>10</lsb>
                            <msb>10</msb>
                            <access>read-write</access>
                            <enumeratedValues>
                                <enumeratedValue>
                                    <name>0</name>
                                    <description>No effect</description>
                                    <value>#0</value>
                                </enumeratedValue>
                                <enumeratedValue>
                                    <name>1</name>
                                    <description>Clear 2-bit ECC error detection flag</description>
                                    <value>#1</value>
                                </enumeratedValue>
                            </enumeratedValues>
                        </field>
                        <field>
                            <name>ECOVFF</name>
                            <description>ECC Overflow Detection Flag</description>
                            <lsb>11</lsb>
                            <msb>11</msb>
                            <access>read-only</access>
                            <enumeratedValues>
                                <enumeratedValue>
                                    <name>0</name>
                                    <description>No effect</description>
                                    <value>#0</value>
                                </enumeratedValue>
                                <enumeratedValue>
                                    <name>1</name>
                                    <description>ECC overflow detection flag</description>
                                    <value>#1</value>
                                </enumeratedValue>
                            </enumeratedValues>
                        </field>
                        <field>
                            <name>EMCA</name>
                            <description>Access Control to ECC Mode Select bit</description>
                            <lsb>14</lsb>
                            <msb>15</msb>
                            <access>read-write</access>
                        </field>
                        <field>
                            <name>ECSEDF0</name>
                            <description>ECC Single bit Error Address Detection Flag</description>
                            <lsb>16</lsb>
                            <msb>16</msb>
                            <access>read-only</access>
                            <enumeratedValues>
                                <enumeratedValue>
                                    <name>0</name>
                                    <description>There is no bit error in EC710EAD0 after reset or clearing ECER1F bit</description>
                                    <value>#0</value>
                                </enumeratedValue>
                                <enumeratedValue>
                                    <name>1</name>
                                    <description>Address captured in EC710EAD0 shows that 1-bit error occurred and captured</description>
                                    <value>#1</value>
                                </enumeratedValue>
                            </enumeratedValues>
                        </field>
                        <field>
                            <name>ECDEDF0</name>
                            <description>ECC Dual Bit Error Address Detection Flag</description>
                            <lsb>17</lsb>
                            <msb>17</msb>
                            <access>read-only</access>
                            <enumeratedValues>
                                <enumeratedValue>
                                    <name>0</name>
                                    <description>There is no bit error in EC710EAD0 after reset or clearing ECER2F bit</description>
                                    <value>#0</value>
                                </enumeratedValue>
                                <enumeratedValue>
                                    <name>1</name>
                                    <description>Address captured in EC710EAD0 shows that 2-bit error occurred and captured</description>
                                    <value>#1</value>
                                </enumeratedValue>
                            </enumeratedValues>
                        </field>
                    </fields>
                </register>
                <register>
                    <name>EC710TMC</name>
                    <description>ECC Test Mode Control Register</description>
                    <addressOffset>0x04</addressOffset>
                    <size>16</size>
                    <access>read-write</access>
                    <resetValue>0x0000</resetValue>
                    <resetMask>0xffff</resetMask>
                    <fields>
                        <field>
                            <name>ECDCS</name>
                            <description>ECC Decode Input Select</description>
                            <lsb>1</lsb>
                            <msb>1</msb>
                            <access>read-write</access>
                            <enumeratedValues>
                                <enumeratedValue>
                                    <name>0</name>
                                    <description>Input lower 32 bits of RAM output data to data area of decode circuit</description>
                                    <value>#0</value>
                                </enumeratedValue>
                                <enumeratedValue>
                                    <name>1</name>
                                    <description>Input ECEDB31-0 in EC710TED register to data area of decode circuit</description>
                                    <value>#1</value>
                                </enumeratedValue>
                            </enumeratedValues>
                        </field>
                        <field>
                            <name>ECTMCE</name>
                            <description>ECC Test Mode Control Enable</description>
                            <lsb>7</lsb>
                            <msb>7</msb>
                            <access>read-write</access>
                            <enumeratedValues>
                                <enumeratedValue>
                                    <name>0</name>
                                    <description>The access to test mode register and bit is disabled</description>
                                    <value>#0</value>
                                </enumeratedValue>
                                <enumeratedValue>
                                    <name>1</name>
                                    <description>The access to test mode register and bit is enabled</description>
                                    <value>#1</value>
                                </enumeratedValue>
                            </enumeratedValues>
                        </field>
                        <field>
                            <name>ETMA</name>
                            <description>ECC Test Mode Bit Access Control</description>
                            <lsb>14</lsb>
                            <msb>15</msb>
                            <access>read-write</access>
                        </field>
                    </fields>
                </register>
                <register>
                    <name>EC710TED</name>
                    <description>ECC Test Substitute Data Register</description>
                    <addressOffset>0x0C</addressOffset>
                    <size>32</size>
                    <access>read-write</access>
                    <resetValue>0x00000000</resetValue>
                    <resetMask>0xffffffff</resetMask>
                    <fields>
                        <field>
                            <name>ECEDB</name>
                            <description>ECC Test Substitute Data</description>
                            <lsb>0</lsb>
                            <msb>31</msb>
                            <access>read-write</access>
                        </field>
                    </fields>
                </register>
                <register>
                    <name>EC710EAD0</name>
                    <description>ECC Error Address Register</description>
                    <addressOffset>0x10</addressOffset>
                    <size>32</size>
                    <access>read-only</access>
                    <resetValue>0x00000000</resetValue>
                    <resetMask>0xffffffff</resetMask>
                    <fields>
                        <field>
                            <name>ECEAD</name>
                            <description>ECC Error Address</description>
                            <lsb>0</lsb>
                            <msb>9</msb>
                            <access>read-only</access>
                        </field>
                    </fields>
                </register>
            </registers>
        </peripheral>
        <peripheral derivedFrom="ECCMB0_NS">
            <name>ECCMB1_NS</name>
            <description>ECCMB1</description>
            <baseAddress>0x5036F300</baseAddress>
        </peripheral>
        <peripheral>
            <name>CANFD0_NS</name>
            <description>CANFD0</description>
            <baseAddress>0x50380000</baseAddress>
            <addressBlock>
                <offset>0x00</offset>
                <size>16</size>
                <usage>registers</usage>
            </addressBlock>
            <addressBlock>
                <offset>0x14</offset>
                <size>34</size>
                <usage>registers</usage>
            </addressBlock>
            <addressBlock>
                <offset>0x38</offset>
                <size>2</size>
                <usage>registers</usage>
            </addressBlock>
            <addressBlock>
                <offset>0x3C</offset>
                <size>120</size>
                <usage>registers</usage>
            </addressBlock>
            <addressBlock>
                <offset>0xB8</offset>
                <size>4</size>
                <usage>registers</usage>
            </addressBlock>
            <addressBlock>
                <offset>0xC0</offset>
                <size>16</size>
                <usage>registers</usage>
            </addressBlock>
            <addressBlock>
                <offset>0xD8</offset>
                <size>4</size>
                <usage>registers</usage>
            </addressBlock>
            <addressBlock>
                <offset>0x100</offset>
                <size>20</size>
                <usage>registers</usage>
            </addressBlock>
            <addressBlock>
                <offset>0x120</offset>
                <size>268</size>
                <usage>registers</usage>
            </addressBlock>
            <addressBlock>
                <offset>0x280</offset>
                <size>256</size>
                <usage>registers</usage>
            </addressBlock>
            <addressBlock>
                <offset>0x520</offset>
                <size>604</size>
                <usage>registers</usage>
            </addressBlock>
            <addressBlock>
                <offset>0x920</offset>
                <size>680</size>
                <usage>registers</usage>
            </addressBlock>
            <addressBlock>
                <offset>0xD20</offset>
                <size>680</size>
                <usage>registers</usage>
            </addressBlock>
            <addressBlock>
                <offset>0x1124</offset>
                <size>676</size>
                <usage>registers</usage>
            </addressBlock>
            <addressBlock>
                <offset>0x1524</offset>
                <size>676</size>
                <usage>registers</usage>
            </addressBlock>
            <registers>
                <register>
                    <name>CFDC0NCFG</name>
                    <description>Nominal Bitrate Configuration Register</description>
                    <addressOffset>0x0000</addressOffset>
                    <size>32</size>
                    <access>read-write</access>
                    <resetValue>0x00000000</resetValue>
                    <resetMask>0xffffffff</resetMask>
                    <fields>
                        <field>
                            <name>NBRP</name>
                            <description>Channel Nominal Baud Rate Prescaler</description>
                            <lsb>0</lsb>
                            <msb>9</msb>
                            <access>read-write</access>
                        </field>
                        <field>
                            <name>NSJW</name>
                            <description>Resynchronization Jump Width</description>
                            <lsb>10</lsb>
                            <msb>16</msb>
                            <access>read-write</access>
                        </field>
                        <field>
                            <name>NTSEG1</name>
                            <description>Timing Segment 1</description>
                            <lsb>17</lsb>
                            <msb>24</msb>
                            <access>read-write</access>
                        </field>
                        <field>
                            <name>NTSEG2</name>
                            <description>Timing Segment 2</description>
                            <lsb>25</lsb>
                            <msb>31</msb>
                            <access>read-write</access>
                        </field>
                    </fields>
                </register>
                <register>
                    <name>CFDC0CTR</name>
                    <description>Control Register</description>
                    <addressOffset>0x0004</addressOffset>
                    <size>32</size>
                    <access>read-write</access>
                    <resetValue>0x00000005</resetValue>
                    <resetMask>0xffffffff</resetMask>
                    <fields>
                        <field>
                            <name>CHMDC</name>
                            <description>Channel Mode Control</description>
                            <lsb>0</lsb>
                            <msb>1</msb>
                            <access>read-write</access>
                            <enumeratedValues>
                                <enumeratedValue>
                                    <name>00</name>
                                    <description>Channel operation mode request</description>
                                    <value>#00</value>
                                </enumeratedValue>
                                <enumeratedValue>
                                    <name>01</name>
                                    <description>Channel reset request</description>
                                    <value>#01</value>
                                </enumeratedValue>
                                <enumeratedValue>
                                    <name>10</name>
                                    <description>Channel halt request</description>
                                    <value>#10</value>
                                </enumeratedValue>
                                <enumeratedValue>
                                    <name>11</name>
                                    <description>Keep current value</description>
                                    <value>#11</value>
                                </enumeratedValue>
                            </enumeratedValues>
                        </field>
                        <field>
                            <name>CSLPR</name>
                            <description>Channel Sleep Request</description>
                            <lsb>2</lsb>
                            <msb>2</msb>
                            <access>read-write</access>
                            <enumeratedValues>
                                <enumeratedValue>
                                    <name>0</name>
                                    <description>Channel sleep request disabled</description>
                                    <value>#0</value>
                                </enumeratedValue>
                                <enumeratedValue>
                                    <name>1</name>
                                    <description>Channel sleep request enabled</description>
                                    <value>#1</value>
                                </enumeratedValue>
                            </enumeratedValues>
                        </field>
                        <field>
                            <name>RTBO</name>
                            <description>Return from Bus-Off</description>
                            <lsb>3</lsb>
                            <msb>3</msb>
                            <access>read-write</access>
                            <enumeratedValues>
                                <enumeratedValue>
                                    <name>0</name>
                                    <description>Channel is not forced to return from bus-off</description>
                                    <value>#0</value>
                                </enumeratedValue>
                                <enumeratedValue>
                                    <name>1</name>
                                    <description>Channel is forced to return from bus-off</description>
                                    <value>#1</value>
                                </enumeratedValue>
                            </enumeratedValues>
                        </field>
                        <field>
                            <name>BEIE</name>
                            <description>Bus Error Interrupt Enable</description>
                            <lsb>8</lsb>
                            <msb>8</msb>
                            <access>read-write</access>
                            <enumeratedValues>
                                <enumeratedValue>
                                    <name>0</name>
                                    <description>Bus error interrupt disabled</description>
                                    <value>#0</value>
                                </enumeratedValue>
                                <enumeratedValue>
                                    <name>1</name>
                                    <description>Bus error interrupt enabled</description>
                                    <value>#1</value>
                                </enumeratedValue>
                            </enumeratedValues>
                        </field>
                        <field>
                            <name>EWIE</name>
                            <description>Error Warning Interrupt Enable</description>
                            <lsb>9</lsb>
                            <msb>9</msb>
                            <access>read-write</access>
                            <enumeratedValues>
                                <enumeratedValue>
                                    <name>0</name>
                                    <description>Error warning interrupt disabled</description>
                                    <value>#0</value>
                                </enumeratedValue>
                                <enumeratedValue>
                                    <name>1</name>
                                    <description>Error warning interrupt enabled</description>
                                    <value>#1</value>
                                </enumeratedValue>
                            </enumeratedValues>
                        </field>
                        <field>
                            <name>EPIE</name>
                            <description>Error Passive Interrupt Enable</description>
                            <lsb>10</lsb>
                            <msb>10</msb>
                            <access>read-write</access>
                            <enumeratedValues>
                                <enumeratedValue>
                                    <name>0</name>
                                    <description>Error passive interrupt disabled</description>
                                    <value>#0</value>
                                </enumeratedValue>
                                <enumeratedValue>
                                    <name>1</name>
                                    <description>Error passive interrupt enabled</description>
                                    <value>#1</value>
                                </enumeratedValue>
                            </enumeratedValues>
                        </field>
                        <field>
                            <name>BOEIE</name>
                            <description>Bus-Off Entry Interrupt Enable</description>
                            <lsb>11</lsb>
                            <msb>11</msb>
                            <access>read-write</access>
                            <enumeratedValues>
                                <enumeratedValue>
                                    <name>0</name>
                                    <description>Bus-off entry interrupt disabled</description>
                                    <value>#0</value>
                                </enumeratedValue>
                                <enumeratedValue>
                                    <name>1</name>
                                    <description>Bus-off entry interrupt enabled</description>
                                    <value>#1</value>
                                </enumeratedValue>
                            </enumeratedValues>
                        </field>
                        <field>
                            <name>BORIE</name>
                            <description>Bus-Off Recovery Interrupt Enable</description>
                            <lsb>12</lsb>
                            <msb>12</msb>
                            <access>read-write</access>
                            <enumeratedValues>
                                <enumeratedValue>
                                    <name>0</name>
                                    <description>Bus-off recovery interrupt disabled</description>
                                    <value>#0</value>
                                </enumeratedValue>
                                <enumeratedValue>
                                    <name>1</name>
                                    <description>Bus-off recovery interrupt enabled</description>
                                    <value>#1</value>
                                </enumeratedValue>
                            </enumeratedValues>
                        </field>
                        <field>
                            <name>OLIE</name>
                            <description>Overload Interrupt Enable</description>
                            <lsb>13</lsb>
                            <msb>13</msb>
                            <access>read-write</access>
                            <enumeratedValues>
                                <enumeratedValue>
                                    <name>0</name>
                                    <description>Overload interrupt disabled</description>
                                    <value>#0</value>
                                </enumeratedValue>
                                <enumeratedValue>
                                    <name>1</name>
                                    <description>Overload interrupt enabled</description>
                                    <value>#1</value>
                                </enumeratedValue>
                            </enumeratedValues>
                        </field>
                        <field>
                            <name>BLIE</name>
                            <description>Bus Lock Interrupt Enable</description>
                            <lsb>14</lsb>
                            <msb>14</msb>
                            <access>read-write</access>
                            <enumeratedValues>
                                <enumeratedValue>
                                    <name>0</name>
                                    <description>Bus lock interrupt disabled</description>
                                    <value>#0</value>
                                </enumeratedValue>
                                <enumeratedValue>
                                    <name>1</name>
                                    <description>Bus lock interrupt enabled</description>
                                    <value>#1</value>
                                </enumeratedValue>
                            </enumeratedValues>
                        </field>
                        <field>
                            <name>ALIE</name>
                            <description>Arbitration Lost Interrupt Enable</description>
                            <lsb>15</lsb>
                            <msb>15</msb>
                            <access>read-write</access>
                            <enumeratedValues>
                                <enumeratedValue>
                                    <name>0</name>
                                    <description>Arbitration lost interrupt disabled</description>
                                    <value>#0</value>
                                </enumeratedValue>
                                <enumeratedValue>
                                    <name>1</name>
                                    <description>Arbitration lost interrupt enabled</description>
                                    <value>#1</value>
                                </enumeratedValue>
                            </enumeratedValues>
                        </field>
                        <field>
                            <name>TAIE</name>
                            <description>Transmission Abort Interrupt Enable</description>
                            <lsb>16</lsb>
                            <msb>16</msb>
                            <access>read-write</access>
                            <enumeratedValues>
                                <enumeratedValue>
                                    <name>0</name>
                                    <description>TX abort interrupt disabled</description>
                                    <value>#0</value>
                                </enumeratedValue>
                                <enumeratedValue>
                                    <name>1</name>
                                    <description>TX abort interrupt enabled</description>
                                    <value>#1</value>
                                </enumeratedValue>
                            </enumeratedValues>
                        </field>
                        <field>
                            <name>EOCOIE</name>
                            <description>Error Occurrence Counter Overflow Interrupt Enable</description>
                            <lsb>17</lsb>
                            <msb>17</msb>
                            <access>read-write</access>
                            <enumeratedValues>
                                <enumeratedValue>
                                    <name>0</name>
                                    <description>Error occurrence counter overflow interrupt disabled</description>
                                    <value>#0</value>
                                </enumeratedValue>
                                <enumeratedValue>
                                    <name>1</name>
                                    <description>Error occurrence counter overflow interrupt enabled</description>
                                    <value>#1</value>
                                </enumeratedValue>
                            </enumeratedValues>
                        </field>
                        <field>
                            <name>SOCOIE</name>
                            <description>Successful Occurrence Counter Overflow Interrupt Enable</description>
                            <lsb>18</lsb>
                            <msb>18</msb>
                            <access>read-write</access>
                            <enumeratedValues>
                                <enumeratedValue>
                                    <name>0</name>
                                    <description>Successful occurrence counter overflow interrupt disabled</description>
                                    <value>#0</value>
                                </enumeratedValue>
                                <enumeratedValue>
                                    <name>1</name>
                                    <description>Successful occurrence counter overflow interrupt enabled</description>
                                    <value>#1</value>
                                </enumeratedValue>
                            </enumeratedValues>
                        </field>
                        <field>
                            <name>TDCVFIE</name>
                            <description>Transceiver Delay Compensation Violation Interrupt Enable</description>
                            <lsb>19</lsb>
                            <msb>19</msb>
                            <access>read-write</access>
                            <enumeratedValues>
                                <enumeratedValue>
                                    <name>0</name>
                                    <description>Transceiver delay compensation violation interrupt disabled</description>
                                    <value>#0</value>
                                </enumeratedValue>
                                <enumeratedValue>
                                    <name>1</name>
                                    <description>Transceiver delay compensation violation interrupt enabled</description>
                                    <value>#1</value>
                                </enumeratedValue>
                            </enumeratedValues>
                        </field>
                        <field>
                            <name>BOM</name>
                            <description>Channel Bus-Off Mode</description>
                            <lsb>21</lsb>
                            <msb>22</msb>
                            <access>read-write</access>
                            <enumeratedValues>
                                <enumeratedValue>
                                    <name>00</name>
                                    <description>Normal mode (comply with ISO 11898-1)</description>
                                    <value>#00</value>
                                </enumeratedValue>
                                <enumeratedValue>
                                    <name>01</name>
                                    <description>Entry to Halt mode automatically at bus-off start</description>
                                    <value>#01</value>
                                </enumeratedValue>
                                <enumeratedValue>
                                    <name>10</name>
                                    <description>Entry to Halt mode automatically at bus-off end</description>
                                    <value>#10</value>
                                </enumeratedValue>
                                <enumeratedValue>
                                    <name>11</name>
                                    <description>Entry to Halt mode (during bus-off recovery period) by software</description>
                                    <value>#11</value>
                                </enumeratedValue>
                            </enumeratedValues>
                        </field>
                        <field>
                            <name>ERRD</name>
                            <description>Channel Error Display</description>
                            <lsb>23</lsb>
                            <msb>23</msb>
                            <access>read-write</access>
                            <enumeratedValues>
                                <enumeratedValue>
                                    <name>0</name>
                                    <description>Only the first set of error codes displayed</description>
                                    <value>#0</value>
                                </enumeratedValue>
                                <enumeratedValue>
                                    <name>1</name>
                                    <description>Accumulated error codes displayed</description>
                                    <value>#1</value>
                                </enumeratedValue>
                            </enumeratedValues>
                        </field>
                        <field>
                            <name>CTME</name>
                            <description>Channel Test Mode Enable</description>
                            <lsb>24</lsb>
                            <msb>24</msb>
                            <access>read-write</access>
                            <enumeratedValues>
                                <enumeratedValue>
                                    <name>0</name>
                                    <description>Channel test mode disabled</description>
                                    <value>#0</value>
                                </enumeratedValue>
                                <enumeratedValue>
                                    <name>1</name>
                                    <description>Channel test mode enabled</description>
                                    <value>#1</value>
                                </enumeratedValue>
                            </enumeratedValues>
                        </field>
                        <field>
                            <name>CTMS</name>
                            <description>Channel Test Mode Select</description>
                            <lsb>25</lsb>
                            <msb>26</msb>
                            <access>read-write</access>
                            <enumeratedValues>
                                <enumeratedValue>
                                    <name>00</name>
                                    <description>Basic test mode</description>
                                    <value>#00</value>
                                </enumeratedValue>
                                <enumeratedValue>
                                    <name>01</name>
                                    <description>Listen-only mode</description>
                                    <value>#01</value>
                                </enumeratedValue>
                                <enumeratedValue>
                                    <name>10</name>
                                    <description>Self-test mode 0 (External loopback mode)</description>
                                    <value>#10</value>
                                </enumeratedValue>
                                <enumeratedValue>
                                    <name>11</name>
                                    <description>Self-test mode 1 (Internal loopback mode)</description>
                                    <value>#11</value>
                                </enumeratedValue>
                            </enumeratedValues>
                        </field>
                        <field>
                            <name>BFT</name>
                            <description>Bit Flip Test</description>
                            <lsb>30</lsb>
                            <msb>30</msb>
                            <access>read-write</access>
                            <enumeratedValues>
                                <enumeratedValue>
                                    <name>0</name>
                                    <description>First data bit of reception stream not inverted</description>
                                    <value>#0</value>
                                </enumeratedValue>
                                <enumeratedValue>
                                    <name>1</name>
                                    <description>First data bit of reception stream inverted</description>
                                    <value>#1</value>
                                </enumeratedValue>
                            </enumeratedValues>
                        </field>
                        <field>
                            <name>ROM</name>
                            <description>Restricted Operation Mode</description>
                            <lsb>31</lsb>
                            <msb>31</msb>
                            <access>read-write</access>
                            <enumeratedValues>
                                <enumeratedValue>
                                    <name>0</name>
                                    <description>Restricted operation mode disabled</description>
                                    <value>#0</value>
                                </enumeratedValue>
                                <enumeratedValue>
                                    <name>1</name>
                                    <description>Restricted operation mode enabled</description>
                                    <value>#1</value>
                                </enumeratedValue>
                            </enumeratedValues>
                        </field>
                    </fields>
                </register>
                <register>
                    <name>CFDC0STS</name>
                    <description>Status Register</description>
                    <addressOffset>0x0008</addressOffset>
                    <size>32</size>
                    <access>read-write</access>
                    <resetValue>0x00000005</resetValue>
                    <resetMask>0xffffffff</resetMask>
                    <fields>
                        <field>
                            <name>CRSTSTS</name>
                            <description>Channel Reset Status</description>
                            <lsb>0</lsb>
                            <msb>0</msb>
                            <access>read-only</access>
                            <enumeratedValues>
                                <enumeratedValue>
                                    <name>0</name>
                                    <description>Channel not in Reset mode</description>
                                    <value>#0</value>
                                </enumeratedValue>
                                <enumeratedValue>
                                    <name>1</name>
                                    <description>Channel in Reset mode</description>
                                    <value>#1</value>
                                </enumeratedValue>
                            </enumeratedValues>
                        </field>
                        <field>
                            <name>CHLTSTS</name>
                            <description>Channel Halt Status</description>
                            <lsb>1</lsb>
                            <msb>1</msb>
                            <access>read-only</access>
                            <enumeratedValues>
                                <enumeratedValue>
                                    <name>0</name>
                                    <description>Channel not in Halt mode</description>
                                    <value>#0</value>
                                </enumeratedValue>
                                <enumeratedValue>
                                    <name>1</name>
                                    <description>Channel in Halt mode</description>
                                    <value>#1</value>
                                </enumeratedValue>
                            </enumeratedValues>
                        </field>
                        <field>
                            <name>CSLPSTS</name>
                            <description>Channel Sleep Status</description>
                            <lsb>2</lsb>
                            <msb>2</msb>
                            <access>read-only</access>
                            <enumeratedValues>
                                <enumeratedValue>
                                    <name>0</name>
                                    <description>Channel not in Sleep mode</description>
                                    <value>#0</value>
                                </enumeratedValue>
                                <enumeratedValue>
                                    <name>1</name>
                                    <description>Channel in Sleep mode</description>
                                    <value>#1</value>
                                </enumeratedValue>
                            </enumeratedValues>
                        </field>
                        <field>
                            <name>EPSTS</name>
                            <description>Channel Error Passive Status</description>
                            <lsb>3</lsb>
                            <msb>3</msb>
                            <access>read-only</access>
                            <enumeratedValues>
                                <enumeratedValue>
                                    <name>0</name>
                                    <description>Channel not in error passive state</description>
                                    <value>#0</value>
                                </enumeratedValue>
                                <enumeratedValue>
                                    <name>1</name>
                                    <description>Channel in error passive state</description>
                                    <value>#1</value>
                                </enumeratedValue>
                            </enumeratedValues>
                        </field>
                        <field>
                            <name>BOSTS</name>
                            <description>Channel Bus-Off Status</description>
                            <lsb>4</lsb>
                            <msb>4</msb>
                            <access>read-only</access>
                            <enumeratedValues>
                                <enumeratedValue>
                                    <name>0</name>
                                    <description>Channel not in bus-off state</description>
                                    <value>#0</value>
                                </enumeratedValue>
                                <enumeratedValue>
                                    <name>1</name>
                                    <description>Channel in bus-off state</description>
                                    <value>#1</value>
                                </enumeratedValue>
                            </enumeratedValues>
                        </field>
                        <field>
                            <name>TRMSTS</name>
                            <description>Channel Transmit Status</description>
                            <lsb>5</lsb>
                            <msb>5</msb>
                            <access>read-only</access>
                            <enumeratedValues>
                                <enumeratedValue>
                                    <name>0</name>
                                    <description>Channel is not transmitting</description>
                                    <value>#0</value>
                                </enumeratedValue>
                                <enumeratedValue>
                                    <name>1</name>
                                    <description>Channel is transmitting</description>
                                    <value>#1</value>
                                </enumeratedValue>
                            </enumeratedValues>
                        </field>
                        <field>
                            <name>RECSTS</name>
                            <description>Channel Receive Status</description>
                            <lsb>6</lsb>
                            <msb>6</msb>
                            <access>read-only</access>
                            <enumeratedValues>
                                <enumeratedValue>
                                    <name>0</name>
                                    <description>Channel is not receiving</description>
                                    <value>#0</value>
                                </enumeratedValue>
                                <enumeratedValue>
                                    <name>1</name>
                                    <description>Channel is receiving</description>
                                    <value>#1</value>
                                </enumeratedValue>
                            </enumeratedValues>
                        </field>
                        <field>
                            <name>COMSTS</name>
                            <description>Channel Communication Status</description>
                            <lsb>7</lsb>
                            <msb>7</msb>
                            <access>read-only</access>
                            <enumeratedValues>
                                <enumeratedValue>
                                    <name>0</name>
                                    <description>Channel is not ready for communication</description>
                                    <value>#0</value>
                                </enumeratedValue>
                                <enumeratedValue>
                                    <name>1</name>
                                    <description>Channel is ready for communication</description>
                                    <value>#1</value>
                                </enumeratedValue>
                            </enumeratedValues>
                        </field>
                        <field>
                            <name>ESIF</name>
                            <description>Error State Indication Flag</description>
                            <lsb>8</lsb>
                            <msb>8</msb>
                            <access>read-write</access>
                            <enumeratedValues>
                                <enumeratedValue>
                                    <name>0</name>
                                    <description>No CANFD message has been received when the ESI flag was set</description>
                                    <value>#0</value>
                                </enumeratedValue>
                                <enumeratedValue>
                                    <name>1</name>
                                    <description>At least one CANFD message was received when the ESI flag was set</description>
                                    <value>#1</value>
                                </enumeratedValue>
                            </enumeratedValues>
                        </field>
                        <field>
                            <name>REC</name>
                            <description>Reception Error Count</description>
                            <lsb>16</lsb>
                            <msb>23</msb>
                            <access>read-only</access>
                        </field>
                        <field>
                            <name>TEC</name>
                            <description>Transmission Error Count</description>
                            <lsb>24</lsb>
                            <msb>31</msb>
                            <access>read-only</access>
                        </field>
                    </fields>
                </register>
                <register>
                    <name>CFDC0ERFL</name>
                    <description> Error Flag Register</description>
                    <addressOffset>0x000C</addressOffset>
                    <size>32</size>
                    <access>read-write</access>
                    <resetValue>0x00000000</resetValue>
                    <resetMask>0xffffffff</resetMask>
                    <fields>
                        <field>
                            <name>BEF</name>
                            <description>Bus Error Flag</description>
                            <lsb>0</lsb>
                            <msb>0</msb>
                            <access>read-write</access>
                            <enumeratedValues>
                                <enumeratedValue>
                                    <name>0</name>
                                    <description>Channel bus error not detected</description>
                                    <value>#0</value>
                                </enumeratedValue>
                                <enumeratedValue>
                                    <name>1</name>
                                    <description>Channel bus error detected</description>
                                    <value>#1</value>
                                </enumeratedValue>
                            </enumeratedValues>
                        </field>
                        <field>
                            <name>EWF</name>
                            <description>Error Warning Flag</description>
                            <lsb>1</lsb>
                            <msb>1</msb>
                            <access>read-write</access>
                            <enumeratedValues>
                                <enumeratedValue>
                                    <name>0</name>
                                    <description>Channel error warning not detected</description>
                                    <value>#0</value>
                                </enumeratedValue>
                                <enumeratedValue>
                                    <name>1</name>
                                    <description>Channel error warning detected</description>
                                    <value>#1</value>
                                </enumeratedValue>
                            </enumeratedValues>
                        </field>
                        <field>
                            <name>EPF</name>
                            <description>Error Passive Flag</description>
                            <lsb>2</lsb>
                            <msb>2</msb>
                            <access>read-write</access>
                            <enumeratedValues>
                                <enumeratedValue>
                                    <name>0</name>
                                    <description>Channel error passive not detected</description>
                                    <value>#0</value>
                                </enumeratedValue>
                                <enumeratedValue>
                                    <name>1</name>
                                    <description>Channel error passive detected</description>
                                    <value>#1</value>
                                </enumeratedValue>
                            </enumeratedValues>
                        </field>
                        <field>
                            <name>BOEF</name>
                            <description>Bus-Off Entry Flag</description>
                            <lsb>3</lsb>
                            <msb>3</msb>
                            <access>read-write</access>
                            <enumeratedValues>
                                <enumeratedValue>
                                    <name>0</name>
                                    <description>Channel bus-off entry not detected</description>
                                    <value>#0</value>
                                </enumeratedValue>
                                <enumeratedValue>
                                    <name>1</name>
                                    <description>Channel bus-off entry detected</description>
                                    <value>#1</value>
                                </enumeratedValue>
                            </enumeratedValues>
                        </field>
                        <field>
                            <name>BORF</name>
                            <description>Bus-Off Recovery Flag</description>
                            <lsb>4</lsb>
                            <msb>4</msb>
                            <access>read-write</access>
                            <enumeratedValues>
                                <enumeratedValue>
                                    <name>0</name>
                                    <description>Channel bus-off recovery not detected</description>
                                    <value>#0</value>
                                </enumeratedValue>
                                <enumeratedValue>
                                    <name>1</name>
                                    <description>Channel bus-off recovery detected</description>
                                    <value>#1</value>
                                </enumeratedValue>
                            </enumeratedValues>
                        </field>
                        <field>
                            <name>OVLF</name>
                            <description>Overload Flag</description>
                            <lsb>5</lsb>
                            <msb>5</msb>
                            <access>read-write</access>
                            <enumeratedValues>
                                <enumeratedValue>
                                    <name>0</name>
                                    <description>Channel overload not detected</description>
                                    <value>#0</value>
                                </enumeratedValue>
                                <enumeratedValue>
                                    <name>1</name>
                                    <description>Channel overload detected</description>
                                    <value>#1</value>
                                </enumeratedValue>
                            </enumeratedValues>
                        </field>
                        <field>
                            <name>BLF</name>
                            <description>Bus Lock Flag</description>
                            <lsb>6</lsb>
                            <msb>6</msb>
                            <access>read-write</access>
                            <enumeratedValues>
                                <enumeratedValue>
                                    <name>0</name>
                                    <description>Channel bus lock not detected</description>
                                    <value>#0</value>
                                </enumeratedValue>
                                <enumeratedValue>
                                    <name>1</name>
                                    <description>Channel bus lock detected</description>
                                    <value>#1</value>
                                </enumeratedValue>
                            </enumeratedValues>
                        </field>
                        <field>
                            <name>ALF</name>
                            <description>Arbitration Lost Flag</description>
                            <lsb>7</lsb>
                            <msb>7</msb>
                            <access>read-write</access>
                            <enumeratedValues>
                                <enumeratedValue>
                                    <name>0</name>
                                    <description>Channel arbitration lost not detected</description>
                                    <value>#0</value>
                                </enumeratedValue>
                                <enumeratedValue>
                                    <name>1</name>
                                    <description>Channel arbitration lost detected</description>
                                    <value>#1</value>
                                </enumeratedValue>
                            </enumeratedValues>
                        </field>
                        <field>
                            <name>SERR</name>
                            <description>Stuff Error</description>
                            <lsb>8</lsb>
                            <msb>8</msb>
                            <access>read-write</access>
                            <enumeratedValues>
                                <enumeratedValue>
                                    <name>0</name>
                                    <description>Channel stuff error not detected</description>
                                    <value>#0</value>
                                </enumeratedValue>
                                <enumeratedValue>
                                    <name>1</name>
                                    <description>Channel stuff error detected</description>
                                    <value>#1</value>
                                </enumeratedValue>
                            </enumeratedValues>
                        </field>
                        <field>
                            <name>FERR</name>
                            <description>Form Error</description>
                            <lsb>9</lsb>
                            <msb>9</msb>
                            <access>read-write</access>
                            <enumeratedValues>
                                <enumeratedValue>
                                    <name>0</name>
                                    <description>Channel form error not detected</description>
                                    <value>#0</value>
                                </enumeratedValue>
                                <enumeratedValue>
                                    <name>1</name>
                                    <description>Channel form error detected</description>
                                    <value>#1</value>
                                </enumeratedValue>
                            </enumeratedValues>
                        </field>
                        <field>
                            <name>AERR</name>
                            <description>Acknowledge Error</description>
                            <lsb>10</lsb>
                            <msb>10</msb>
                            <access>read-write</access>
                            <enumeratedValues>
                                <enumeratedValue>
                                    <name>0</name>
                                    <description>Channel acknowledge error not detected</description>
                                    <value>#0</value>
                                </enumeratedValue>
                                <enumeratedValue>
                                    <name>1</name>
                                    <description>Channel acknowledge error detected</description>
                                    <value>#1</value>
                                </enumeratedValue>
                            </enumeratedValues>
                        </field>
                        <field>
                            <name>CERR</name>
                            <description>CRC Error</description>
                            <lsb>11</lsb>
                            <msb>11</msb>
                            <access>read-write</access>
                            <enumeratedValues>
                                <enumeratedValue>
                                    <name>0</name>
                                    <description>Channel CRC error not detected</description>
                                    <value>#0</value>
                                </enumeratedValue>
                                <enumeratedValue>
                                    <name>1</name>
                                    <description>Channel CRC error detected</description>
                                    <value>#1</value>
                                </enumeratedValue>
                            </enumeratedValues>
                        </field>
                        <field>
                            <name>B1ERR</name>
                            <description>Bit 1 Error</description>
                            <lsb>12</lsb>
                            <msb>12</msb>
                            <access>read-write</access>
                            <enumeratedValues>
                                <enumeratedValue>
                                    <name>0</name>
                                    <description>Channel bit 1 error not detected</description>
                                    <value>#0</value>
                                </enumeratedValue>
                                <enumeratedValue>
                                    <name>1</name>
                                    <description>Channel bit 1 error detected</description>
                                    <value>#1</value>
                                </enumeratedValue>
                            </enumeratedValues>
                        </field>
                        <field>
                            <name>B0ERR</name>
                            <description>Bit 0 Error</description>
                            <lsb>13</lsb>
                            <msb>13</msb>
                            <access>read-write</access>
                            <enumeratedValues>
                                <enumeratedValue>
                                    <name>0</name>
                                    <description>Channel bit 0 error not detected</description>
                                    <value>#0</value>
                                </enumeratedValue>
                                <enumeratedValue>
                                    <name>1</name>
                                    <description>Channel bit 0 error detected</description>
                                    <value>#1</value>
                                </enumeratedValue>
                            </enumeratedValues>
                        </field>
                        <field>
                            <name>ADERR</name>
                            <description>Acknowledge Delimiter Error</description>
                            <lsb>14</lsb>
                            <msb>14</msb>
                            <access>read-write</access>
                            <enumeratedValues>
                                <enumeratedValue>
                                    <name>0</name>
                                    <description>Channel acknowledge delimiter error not detected</description>
                                    <value>#0</value>
                                </enumeratedValue>
                                <enumeratedValue>
                                    <name>1</name>
                                    <description>Channel acknowledge delimiter error detected</description>
                                    <value>#1</value>
                                </enumeratedValue>
                            </enumeratedValues>
                        </field>
                        <field>
                            <name>CRCREG</name>
                            <description>CRC Register value</description>
                            <lsb>16</lsb>
                            <msb>30</msb>
                            <access>read-only</access>
                        </field>
                    </fields>
                </register>
                <register>
                    <name>CFDGCFG</name>
                    <description>Global Configuration Register</description>
                    <addressOffset>0x0014</addressOffset>
                    <size>32</size>
                    <access>read-write</access>
                    <resetValue>0x00000000</resetValue>
                    <resetMask>0xffffffff</resetMask>
                    <fields>
                        <field>
                            <name>TPRI</name>
                            <description>Transmission Priority</description>
                            <lsb>0</lsb>
                            <msb>0</msb>
                            <access>read-write</access>
                            <enumeratedValues>
                                <enumeratedValue>
                                    <name>0</name>
                                    <description>ID priority</description>
                                    <value>#0</value>
                                </enumeratedValue>
                                <enumeratedValue>
                                    <name>1</name>
                                    <description>Message buffer number priority</description>
                                    <value>#1</value>
                                </enumeratedValue>
                            </enumeratedValues>
                        </field>
                        <field>
                            <name>DCE</name>
                            <description>DLC Check Enable</description>
                            <lsb>1</lsb>
                            <msb>1</msb>
                            <access>read-write</access>
                            <enumeratedValues>
                                <enumeratedValue>
                                    <name>0</name>
                                    <description>DLC check disabled</description>
                                    <value>#0</value>
                                </enumeratedValue>
                                <enumeratedValue>
                                    <name>1</name>
                                    <description>DLC check enabled</description>
                                    <value>#1</value>
                                </enumeratedValue>
                            </enumeratedValues>
                        </field>
                        <field>
                            <name>DRE</name>
                            <description>DLC Replacement Enable</description>
                            <lsb>2</lsb>
                            <msb>2</msb>
                            <access>read-write</access>
                            <enumeratedValues>
                                <enumeratedValue>
                                    <name>0</name>
                                    <description>DLC replacement disabled</description>
                                    <value>#0</value>
                                </enumeratedValue>
                                <enumeratedValue>
                                    <name>1</name>
                                    <description>DLC replacement enabled</description>
                                    <value>#1</value>
                                </enumeratedValue>
                            </enumeratedValues>
                        </field>
                        <field>
                            <name>MME</name>
                            <description>Mirror Mode Enable</description>
                            <lsb>3</lsb>
                            <msb>3</msb>
                            <access>read-write</access>
                            <enumeratedValues>
                                <enumeratedValue>
                                    <name>0</name>
                                    <description>Mirror mode disabled</description>
                                    <value>#0</value>
                                </enumeratedValue>
                                <enumeratedValue>
                                    <name>1</name>
                                    <description>Mirror mode enabled</description>
                                    <value>#1</value>
                                </enumeratedValue>
                            </enumeratedValues>
                        </field>
                        <field>
                            <name>DCS</name>
                            <description>Data Link Controller Clock Select</description>
                            <lsb>4</lsb>
                            <msb>4</msb>
                            <access>read-write</access>
                            <enumeratedValues>
                                <enumeratedValue>
                                    <name>0</name>
                                    <description>CANFD core clock (CANFDCLK)</description>
                                    <value>#0</value>
                                </enumeratedValue>
                                <enumeratedValue>
                                    <name>1</name>
                                    <description>External oscillator clock (CANMCLK)</description>
                                    <value>#1</value>
                                </enumeratedValue>
                            </enumeratedValues>
                        </field>
                        <field>
                            <name>CMPOC</name>
                            <description>CANFD Message Payload Overflow Configuration</description>
                            <lsb>5</lsb>
                            <msb>5</msb>
                            <access>read-write</access>
                            <enumeratedValues>
                                <enumeratedValue>
                                    <name>0</name>
                                    <description>Message is rejected</description>
                                    <value>#0</value>
                                </enumeratedValue>
                                <enumeratedValue>
                                    <name>1</name>
                                    <description>Message payload is cut to fit to configured message size</description>
                                    <value>#1</value>
                                </enumeratedValue>
                            </enumeratedValues>
                        </field>
                        <field>
                            <name>TSP</name>
                            <description>Timestamp Prescaler</description>
                            <lsb>8</lsb>
                            <msb>11</msb>
                            <access>read-write</access>
                        </field>
                        <field>
                            <name>TSSS</name>
                            <description>Timestamp Source Select</description>
                            <lsb>12</lsb>
                            <msb>12</msb>
                            <access>read-write</access>
                            <enumeratedValues>
                                <enumeratedValue>
                                    <name>0</name>
                                    <description>Source clock for timestamp counter is peripheral clock</description>
                                    <value>#0</value>
                                </enumeratedValue>
                                <enumeratedValue>
                                    <name>1</name>
                                    <description>Source clock for timestamp counter is bit time clock</description>
                                    <value>#1</value>
                                </enumeratedValue>
                            </enumeratedValues>
                        </field>
                        <field>
                            <name>ITRCP</name>
                            <description>Interval Timer Reference Clock Prescaler</description>
                            <lsb>16</lsb>
                            <msb>31</msb>
                            <access>read-write</access>
                        </field>
                    </fields>
                </register>
                <register>
                    <name>CFDGCTR</name>
                    <description>Global Control Register</description>
                    <addressOffset>0x0018</addressOffset>
                    <size>32</size>
                    <access>read-write</access>
                    <resetValue>0x00000005</resetValue>
                    <resetMask>0xffffffff</resetMask>
                    <fields>
                        <field>
                            <name>GMDC</name>
                            <description>Global Mode Control</description>
                            <lsb>0</lsb>
                            <msb>1</msb>
                            <access>read-write</access>
                            <enumeratedValues>
                                <enumeratedValue>
                                    <name>00</name>
                                    <description>Global operation mode request</description>
                                    <value>#00</value>
                                </enumeratedValue>
                                <enumeratedValue>
                                    <name>01</name>
                                    <description>Global reset mode request</description>
                                    <value>#01</value>
                                </enumeratedValue>
                                <enumeratedValue>
                                    <name>10</name>
                                    <description>Global halt mode request</description>
                                    <value>#10</value>
                                </enumeratedValue>
                                <enumeratedValue>
                                    <name>11</name>
                                    <description>Keep current value</description>
                                    <value>#11</value>
                                </enumeratedValue>
                            </enumeratedValues>
                        </field>
                        <field>
                            <name>GSLPR</name>
                            <description>Global Sleep Request</description>
                            <lsb>2</lsb>
                            <msb>2</msb>
                            <access>read-write</access>
                            <enumeratedValues>
                                <enumeratedValue>
                                    <name>0</name>
                                    <description>Global sleep request disabled</description>
                                    <value>#0</value>
                                </enumeratedValue>
                                <enumeratedValue>
                                    <name>1</name>
                                    <description>Global sleep request enabled</description>
                                    <value>#1</value>
                                </enumeratedValue>
                            </enumeratedValues>
                        </field>
                        <field>
                            <name>DEIE</name>
                            <description>DLC Check Interrupt Enable</description>
                            <lsb>8</lsb>
                            <msb>8</msb>
                            <access>read-write</access>
                            <enumeratedValues>
                                <enumeratedValue>
                                    <name>0</name>
                                    <description>DLC check interrupt disabled</description>
                                    <value>#0</value>
                                </enumeratedValue>
                                <enumeratedValue>
                                    <name>1</name>
                                    <description>DLC check interrupt enabled</description>
                                    <value>#1</value>
                                </enumeratedValue>
                            </enumeratedValues>
                        </field>
                        <field>
                            <name>MEIE</name>
                            <description>Message Lost Error Interrupt Enable</description>
                            <lsb>9</lsb>
                            <msb>9</msb>
                            <access>read-write</access>
                            <enumeratedValues>
                                <enumeratedValue>
                                    <name>0</name>
                                    <description>Message lost error interrupt disabled</description>
                                    <value>#0</value>
                                </enumeratedValue>
                                <enumeratedValue>
                                    <name>1</name>
                                    <description>Message lost error interrupt enabled</description>
                                    <value>#1</value>
                                </enumeratedValue>
                            </enumeratedValues>
                        </field>
                        <field>
                            <name>THLEIE</name>
                            <description>TX History List Entry Lost Interrupt Enable</description>
                            <lsb>10</lsb>
                            <msb>10</msb>
                            <access>read-write</access>
                            <enumeratedValues>
                                <enumeratedValue>
                                    <name>0</name>
                                    <description>TX history list entry lost interrupt disabled</description>
                                    <value>#0</value>
                                </enumeratedValue>
                                <enumeratedValue>
                                    <name>1</name>
                                    <description>TX history list entry lost interrupt enabled</description>
                                    <value>#1</value>
                                </enumeratedValue>
                            </enumeratedValues>
                        </field>
                        <field>
                            <name>CMPOFIE</name>
                            <description>CANFD Message Payload Overflow Flag Interrupt Enable</description>
                            <lsb>11</lsb>
                            <msb>11</msb>
                            <access>read-write</access>
                            <enumeratedValues>
                                <enumeratedValue>
                                    <name>0</name>
                                    <description>CANFD message payload overflow flag interrupt disabled</description>
                                    <value>#0</value>
                                </enumeratedValue>
                                <enumeratedValue>
                                    <name>1</name>
                                    <description>CANFD message payload overflow flag interrupt enabled</description>
                                    <value>#1</value>
                                </enumeratedValue>
                            </enumeratedValues>
                        </field>
                        <field>
                            <name>TSRST</name>
                            <description>Timestamp Reset</description>
                            <lsb>16</lsb>
                            <msb>16</msb>
                            <access>read-write</access>
                            <enumeratedValues>
                                <enumeratedValue>
                                    <name>0</name>
                                    <description>Timestamp not reset</description>
                                    <value>#0</value>
                                </enumeratedValue>
                                <enumeratedValue>
                                    <name>1</name>
                                    <description>Timestamp reset</description>
                                    <value>#1</value>
                                </enumeratedValue>
                            </enumeratedValues>
                        </field>
                    </fields>
                </register>
                <register>
                    <name>CFDGSTS</name>
                    <description>Global Status Register</description>
                    <addressOffset>0x001C</addressOffset>
                    <size>32</size>
                    <access>read-only</access>
                    <resetValue>0x0000000d</resetValue>
                    <resetMask>0xffffffff</resetMask>
                    <fields>
                        <field>
                            <name>GRSTSTS</name>
                            <description>Global Reset Status</description>
                            <lsb>0</lsb>
                            <msb>0</msb>
                            <access>read-only</access>
                            <enumeratedValues>
                                <enumeratedValue>
                                    <name>0</name>
                                    <description>Not in Reset mode</description>
                                    <value>#0</value>
                                </enumeratedValue>
                                <enumeratedValue>
                                    <name>1</name>
                                    <description>In Reset mode</description>
                                    <value>#1</value>
                                </enumeratedValue>
                            </enumeratedValues>
                        </field>
                        <field>
                            <name>GHLTSTS</name>
                            <description>Global Halt Status</description>
                            <lsb>1</lsb>
                            <msb>1</msb>
                            <access>read-only</access>
                            <enumeratedValues>
                                <enumeratedValue>
                                    <name>0</name>
                                    <description>Not in Halt mode</description>
                                    <value>#0</value>
                                </enumeratedValue>
                                <enumeratedValue>
                                    <name>1</name>
                                    <description>In Halt mode</description>
                                    <value>#1</value>
                                </enumeratedValue>
                            </enumeratedValues>
                        </field>
                        <field>
                            <name>GSLPSTS</name>
                            <description>Global Sleep Status</description>
                            <lsb>2</lsb>
                            <msb>2</msb>
                            <access>read-only</access>
                            <enumeratedValues>
                                <enumeratedValue>
                                    <name>0</name>
                                    <description>Not in Sleep mode</description>
                                    <value>#0</value>
                                </enumeratedValue>
                                <enumeratedValue>
                                    <name>1</name>
                                    <description>In Sleep mode</description>
                                    <value>#1</value>
                                </enumeratedValue>
                            </enumeratedValues>
                        </field>
                        <field>
                            <name>GRAMINIT</name>
                            <description>Global RAM Initialization</description>
                            <lsb>3</lsb>
                            <msb>3</msb>
                            <access>read-only</access>
                            <enumeratedValues>
                                <enumeratedValue>
                                    <name>0</name>
                                    <description>RAM initialization is complete</description>
                                    <value>#0</value>
                                </enumeratedValue>
                                <enumeratedValue>
                                    <name>1</name>
                                    <description>RAM initialization is ongoing</description>
                                    <value>#1</value>
                                </enumeratedValue>
                            </enumeratedValues>
                        </field>
                    </fields>
                </register>
                <register>
                    <name>CFDGERFL</name>
                    <description>Global Error Flag Register</description>
                    <addressOffset>0x0020</addressOffset>
                    <size>32</size>
                    <access>read-write</access>
                    <resetValue>0x00000000</resetValue>
                    <resetMask>0xffffffff</resetMask>
                    <fields>
                        <field>
                            <name>DEF</name>
                            <description>DLC Error Flag</description>
                            <lsb>0</lsb>
                            <msb>0</msb>
                            <access>read-write</access>
                            <enumeratedValues>
                                <enumeratedValue>
                                    <name>0</name>
                                    <description>DLC error not detected</description>
                                    <value>#0</value>
                                </enumeratedValue>
                                <enumeratedValue>
                                    <name>1</name>
                                    <description>DLC error detected</description>
                                    <value>#1</value>
                                </enumeratedValue>
                            </enumeratedValues>
                        </field>
                        <field>
                            <name>MES</name>
                            <description>Message Lost Error Status</description>
                            <lsb>1</lsb>
                            <msb>1</msb>
                            <access>read-only</access>
                            <enumeratedValues>
                                <enumeratedValue>
                                    <name>0</name>
                                    <description>Message lost error not detected</description>
                                    <value>#0</value>
                                </enumeratedValue>
                                <enumeratedValue>
                                    <name>1</name>
                                    <description>Message lost error detected</description>
                                    <value>#1</value>
                                </enumeratedValue>
                            </enumeratedValues>
                        </field>
                        <field>
                            <name>THLES</name>
                            <description>TX History List Entry Lost Error Status</description>
                            <lsb>2</lsb>
                            <msb>2</msb>
                            <access>read-only</access>
                            <enumeratedValues>
                                <enumeratedValue>
                                    <name>0</name>
                                    <description>TX history list entry lost error not detected</description>
                                    <value>#0</value>
                                </enumeratedValue>
                                <enumeratedValue>
                                    <name>1</name>
                                    <description>TX history list entry lost error detected</description>
                                    <value>#1</value>
                                </enumeratedValue>
                            </enumeratedValues>
                        </field>
                        <field>
                            <name>CMPOF</name>
                            <description>CANFD Message Payload Overflow Flag</description>
                            <lsb>3</lsb>
                            <msb>3</msb>
                            <access>read-write</access>
                            <enumeratedValues>
                                <enumeratedValue>
                                    <name>0</name>
                                    <description>CANFD message payload overflow not detected</description>
                                    <value>#0</value>
                                </enumeratedValue>
                                <enumeratedValue>
                                    <name>1</name>
                                    <description>CANFD message payload overflow detected</description>
                                    <value>#1</value>
                                </enumeratedValue>
                            </enumeratedValues>
                        </field>
                        <field>
                            <name>EEF0</name>
                            <description>ECC Error Flag</description>
                            <lsb>16</lsb>
                            <msb>16</msb>
                            <access>read-write</access>
                            <enumeratedValues>
                                <enumeratedValue>
                                    <name>0</name>
                                    <description>ECC error not detected during TX-SCAN</description>
                                    <value>#0</value>
                                </enumeratedValue>
                                <enumeratedValue>
                                    <name>1</name>
                                    <description>ECC error detected during TX-SCAN</description>
                                    <value>#1</value>
                                </enumeratedValue>
                            </enumeratedValues>
                        </field>
                    </fields>
                </register>
                <register>
                    <name>CFDGTSC</name>
                    <description>Global Timestamp Counter Register</description>
                    <addressOffset>0x0024</addressOffset>
                    <size>32</size>
                    <access>read-only</access>
                    <resetValue>0x00000000</resetValue>
                    <resetMask>0xffffffff</resetMask>
                    <fields>
                        <field>
                            <name>TS</name>
                            <description>Timestamp value</description>
                            <lsb>0</lsb>
                            <msb>15</msb>
                            <access>read-only</access>
                        </field>
                    </fields>
                </register>
                <register>
                    <name>CFDGAFLECTR</name>
                    <description>Global Acceptance Filter List Entry Control Register</description>
                    <addressOffset>0x0028</addressOffset>
                    <size>32</size>
                    <access>read-write</access>
                    <resetValue>0x00000000</resetValue>
                    <resetMask>0xffffffff</resetMask>
                    <fields>
                        <field>
                            <name>AFLDAE</name>
                            <description>Acceptance Filter List Data Access Enable</description>
                            <lsb>8</lsb>
                            <msb>8</msb>
                            <access>read-write</access>
                            <enumeratedValues>
                                <enumeratedValue>
                                    <name>0</name>
                                    <description>Acceptance Filter List data access disabled</description>
                                    <value>#0</value>
                                </enumeratedValue>
                                <enumeratedValue>
                                    <name>1</name>
                                    <description>Acceptance Filter List data access enabled</description>
                                    <value>#1</value>
                                </enumeratedValue>
                            </enumeratedValues>
                        </field>
                    </fields>
                </register>
                <register>
                    <name>CFDGAFLCFG</name>
                    <description>Global Acceptance Filter List Configuration Register</description>
                    <addressOffset>0x002C</addressOffset>
                    <size>32</size>
                    <access>read-write</access>
                    <resetValue>0x00000000</resetValue>
                    <resetMask>0xffffffff</resetMask>
                    <fields>
                        <field>
                            <name>RNC0</name>
                            <description>Rule Number</description>
                            <lsb>16</lsb>
                            <msb>20</msb>
                            <access>read-write</access>
                        </field>
                    </fields>
                </register>
                <register>
                    <name>CFDRMNB</name>
                    <description>RX Message Buffer Number Register</description>
                    <addressOffset>0x0030</addressOffset>
                    <size>32</size>
                    <access>read-write</access>
                    <resetValue>0x00000000</resetValue>
                    <resetMask>0xffffffff</resetMask>
                    <fields>
                        <field>
                            <name>NRXMB</name>
                            <description>Number of RX Message Buffers</description>
                            <lsb>0</lsb>
                            <msb>4</msb>
                            <access>read-write</access>
                        </field>
                        <field>
                            <name>RMPLS</name>
                            <description>Reception Message Buffer Payload Data Size</description>
                            <lsb>8</lsb>
                            <msb>10</msb>
                            <access>read-write</access>
                            <enumeratedValues>
                                <enumeratedValue>
                                    <name>000</name>
                                    <description>8 bytes</description>
                                    <value>#000</value>
                                </enumeratedValue>
                                <enumeratedValue>
                                    <name>001</name>
                                    <description>12 bytes</description>
                                    <value>#001</value>
                                </enumeratedValue>
                                <enumeratedValue>
                                    <name>010</name>
                                    <description>16 bytes</description>
                                    <value>#010</value>
                                </enumeratedValue>
                                <enumeratedValue>
                                    <name>011</name>
                                    <description>20 bytes</description>
                                    <value>#011</value>
                                </enumeratedValue>
                                <enumeratedValue>
                                    <name>100</name>
                                    <description>24 bytes</description>
                                    <value>#100</value>
                                </enumeratedValue>
                                <enumeratedValue>
                                    <name>101</name>
                                    <description>32 bytes</description>
                                    <value>#101</value>
                                </enumeratedValue>
                                <enumeratedValue>
                                    <name>110</name>
                                    <description>48 bytes</description>
                                    <value>#110</value>
                                </enumeratedValue>
                                <enumeratedValue>
                                    <name>111</name>
                                    <description>64 bytes</description>
                                    <value>#111</value>
                                </enumeratedValue>
                            </enumeratedValues>
                        </field>
                    </fields>
                </register>
                <register>
                    <name>CFDRMND</name>
                    <description>RX Message Buffer New Data Register</description>
                    <addressOffset>0x0034</addressOffset>
                    <size>16</size>
                    <access>read-write</access>
                    <resetValue>0x0000</resetValue>
                    <resetMask>0xffff</resetMask>
                    <fields>
                        <field>
                            <name>RMNS</name>
                            <description>RX Message Buffer New Data Status</description>
                            <lsb>0</lsb>
                            <msb>15</msb>
                            <access>read-write</access>
                            <enumeratedValues>
                                <enumeratedValue>
                                    <name>0</name>
                                    <description>New data not stored in corresponding RX message buffer</description>
                                    <value>#0</value>
                                </enumeratedValue>
                                <enumeratedValue>
                                    <name>1</name>
                                    <description>New data stored in corresponding RX message buffer</description>
                                    <value>#1</value>
                                </enumeratedValue>
                            </enumeratedValues>
                        </field>
                    </fields>
                </register>
                <register>
                    <name>CFDRMIEC</name>
                    <description>RX Message Buffer Interrupt Enable Configuration Register</description>
                    <addressOffset>0x0038</addressOffset>
                    <size>16</size>
                    <access>read-write</access>
                    <resetValue>0x0000</resetValue>
                    <resetMask>0xffff</resetMask>
                    <fields>
                        <field>
                            <name>RMIE</name>
                            <description>RX Message Buffer Interrupt Enable</description>
                            <lsb>0</lsb>
                            <msb>15</msb>
                            <access>read-write</access>
                            <enumeratedValues>
                                <enumeratedValue>
                                    <name>0</name>
                                    <description>RX Message Buffer Interrupt disabled for corresponding RX message buffer</description>
                                    <value>#0</value>
                                </enumeratedValue>
                                <enumeratedValue>
                                    <name>1</name>
                                    <description>RX Message Buffer Interrupt enabled for corresponding RX message buffer</description>
                                    <value>#1</value>
                                </enumeratedValue>
                            </enumeratedValues>
                        </field>
                    </fields>
                </register>
                <register>
                    <dim>2</dim>
                    <dimIncrement>0x04</dimIncrement>
                    <dimIndex>0-1</dimIndex>
                    <name>CFDRFCC%s</name>
                    <description>RX FIFO Configuration/Control Registers %s</description>
                    <addressOffset>0x003C</addressOffset>
                    <size>32</size>
                    <access>read-write</access>
                    <resetValue>0x00000000</resetValue>
                    <resetMask>0xffffffff</resetMask>
                    <fields>
                        <field>
                            <name>RFE</name>
                            <description>RX FIFO Enable</description>
                            <lsb>0</lsb>
                            <msb>0</msb>
                            <access>read-write</access>
                            <enumeratedValues>
                                <enumeratedValue>
                                    <name>0</name>
                                    <description>FIFO disabled</description>
                                    <value>#0</value>
                                </enumeratedValue>
                                <enumeratedValue>
                                    <name>1</name>
                                    <description>FIFO enabled</description>
                                    <value>#1</value>
                                </enumeratedValue>
                            </enumeratedValues>
                        </field>
                        <field>
                            <name>RFIE</name>
                            <description>RX FIFO Interrupt Enable</description>
                            <lsb>1</lsb>
                            <msb>1</msb>
                            <access>read-write</access>
                            <enumeratedValues>
                                <enumeratedValue>
                                    <name>0</name>
                                    <description>FIFO interrupt generation disabled</description>
                                    <value>#0</value>
                                </enumeratedValue>
                                <enumeratedValue>
                                    <name>1</name>
                                    <description>FIFO interrupt generation enabled</description>
                                    <value>#1</value>
                                </enumeratedValue>
                            </enumeratedValues>
                        </field>
                        <field>
                            <name>RFPLS</name>
                            <description>Rx FIFO Payload Data Size Configuration</description>
                            <lsb>4</lsb>
                            <msb>6</msb>
                            <access>read-write</access>
                            <enumeratedValues>
                                <enumeratedValue>
                                    <name>000</name>
                                    <description>8 bytes</description>
                                    <value>#000</value>
                                </enumeratedValue>
                                <enumeratedValue>
                                    <name>001</name>
                                    <description>12 bytes</description>
                                    <value>#001</value>
                                </enumeratedValue>
                                <enumeratedValue>
                                    <name>010</name>
                                    <description>16 bytes</description>
                                    <value>#010</value>
                                </enumeratedValue>
                                <enumeratedValue>
                                    <name>011</name>
                                    <description>20 bytes</description>
                                    <value>#011</value>
                                </enumeratedValue>
                                <enumeratedValue>
                                    <name>100</name>
                                    <description>24 bytes</description>
                                    <value>#100</value>
                                </enumeratedValue>
                                <enumeratedValue>
                                    <name>101</name>
                                    <description>32 bytes</description>
                                    <value>#101</value>
                                </enumeratedValue>
                                <enumeratedValue>
                                    <name>110</name>
                                    <description>48 bytes</description>
                                    <value>#110</value>
                                </enumeratedValue>
                                <enumeratedValue>
                                    <name>111</name>
                                    <description>64 bytes</description>
                                    <value>#111</value>
                                </enumeratedValue>
                            </enumeratedValues>
                        </field>
                        <field>
                            <name>RFDC</name>
                            <description>RX FIFO Depth Configuration</description>
                            <lsb>8</lsb>
                            <msb>10</msb>
                            <access>read-write</access>
                            <enumeratedValues>
                                <enumeratedValue>
                                    <name>000</name>
                                    <description>FIFO Depth = 0 message</description>
                                    <value>#000</value>
                                </enumeratedValue>
                                <enumeratedValue>
                                    <name>001</name>
                                    <description>FIFO Depth = 4 messages</description>
                                    <value>#001</value>
                                </enumeratedValue>
                                <enumeratedValue>
                                    <name>010</name>
                                    <description>FIFO Depth = 8 messages</description>
                                    <value>#010</value>
                                </enumeratedValue>
                                <enumeratedValue>
                                    <name>011</name>
                                    <description>FIFO Depth = 16 messages</description>
                                    <value>#011</value>
                                </enumeratedValue>
                                <enumeratedValue>
                                    <name>100</name>
                                    <description>FIFO Depth = 32 essages</description>
                                    <value>#100</value>
                                </enumeratedValue>
                                <enumeratedValue>
                                    <name>101</name>
                                    <description>FIFO Depth = 48 messages</description>
                                    <value>#101</value>
                                </enumeratedValue>
                                <enumeratedValue>
                                    <name>110</name>
                                    <description>Reserved</description>
                                    <value>#110</value>
                                </enumeratedValue>
                                <enumeratedValue>
                                    <name>111</name>
                                    <description>Reserved</description>
                                    <value>#111</value>
                                </enumeratedValue>
                            </enumeratedValues>
                        </field>
                        <field>
                            <name>RFIM</name>
                            <description>RX FIFO Interrupt Mode</description>
                            <lsb>12</lsb>
                            <msb>12</msb>
                            <access>read-write</access>
                            <enumeratedValues>
                                <enumeratedValue>
                                    <name>0</name>
                                    <description>Interrupt generated when RX FIFO counter reaches RFIGCV value from values smaller than RFIGCV</description>
                                    <value>#0</value>
                                </enumeratedValue>
                                <enumeratedValue>
                                    <name>1</name>
                                    <description>Interrupt generated at the end of every received message storage</description>
                                    <value>#1</value>
                                </enumeratedValue>
                            </enumeratedValues>
                        </field>
                        <field>
                            <name>RFIGCV</name>
                            <description>RX FIFO Interrupt Generation Counter Value</description>
                            <lsb>13</lsb>
                            <msb>15</msb>
                            <access>read-write</access>
                            <enumeratedValues>
                                <enumeratedValue>
                                    <name>000</name>
                                    <description>Interrupt generated when FIFO is 1/8th full</description>
                                    <value>#000</value>
                                </enumeratedValue>
                                <enumeratedValue>
                                    <name>001</name>
                                    <description>Interrupt generated when FIFO is 1/4th full</description>
                                    <value>#001</value>
                                </enumeratedValue>
                                <enumeratedValue>
                                    <name>010</name>
                                    <description>Interrupt generated when FIFO is 3/8th full</description>
                                    <value>#010</value>
                                </enumeratedValue>
                                <enumeratedValue>
                                    <name>011</name>
                                    <description>Interrupt generated when FIFO is 1/2 full</description>
                                    <value>#011</value>
                                </enumeratedValue>
                                <enumeratedValue>
                                    <name>100</name>
                                    <description>Interrupt generated when FIFO is 5/8th full</description>
                                    <value>#100</value>
                                </enumeratedValue>
                                <enumeratedValue>
                                    <name>101</name>
                                    <description>Interrupt generated when FIFO is 3/4th full</description>
                                    <value>#101</value>
                                </enumeratedValue>
                                <enumeratedValue>
                                    <name>110</name>
                                    <description>Interrupt generated when FIFO is 7/8th full</description>
                                    <value>#110</value>
                                </enumeratedValue>
                                <enumeratedValue>
                                    <name>111</name>
                                    <description>Interrupt generated when FIFO is full</description>
                                    <value>#111</value>
                                </enumeratedValue>
                            </enumeratedValues>
                        </field>
                    </fields>
                </register>
                <register>
                    <dim>2</dim>
                    <dimIncrement>0x04</dimIncrement>
                    <dimIndex>0-1</dimIndex>
                    <name>CFDRFSTS%s</name>
                    <description>RX FIFO Status Registers %s</description>
                    <addressOffset>0x0044</addressOffset>
                    <size>32</size>
                    <access>read-write</access>
                    <resetValue>0x00000001</resetValue>
                    <resetMask>0xffffffff</resetMask>
                    <fields>
                        <field>
                            <name>RFEMP</name>
                            <description>RX FIFO Empty</description>
                            <lsb>0</lsb>
                            <msb>0</msb>
                            <access>read-only</access>
                            <enumeratedValues>
                                <enumeratedValue>
                                    <name>0</name>
                                    <description>FIFO not empty</description>
                                    <value>#0</value>
                                </enumeratedValue>
                                <enumeratedValue>
                                    <name>1</name>
                                    <description>FIFO empty</description>
                                    <value>#1</value>
                                </enumeratedValue>
                            </enumeratedValues>
                        </field>
                        <field>
                            <name>RFFLL</name>
                            <description>RX FIFO Full</description>
                            <lsb>1</lsb>
                            <msb>1</msb>
                            <access>read-only</access>
                            <enumeratedValues>
                                <enumeratedValue>
                                    <name>0</name>
                                    <description>FIFO not full</description>
                                    <value>#0</value>
                                </enumeratedValue>
                                <enumeratedValue>
                                    <name>1</name>
                                    <description>FIFO full</description>
                                    <value>#1</value>
                                </enumeratedValue>
                            </enumeratedValues>
                        </field>
                        <field>
                            <name>RFMLT</name>
                            <description>RX FIFO Message Lost</description>
                            <lsb>2</lsb>
                            <msb>2</msb>
                            <access>read-write</access>
                            <enumeratedValues>
                                <enumeratedValue>
                                    <name>0</name>
                                    <description>No message lost in FIFO</description>
                                    <value>#0</value>
                                </enumeratedValue>
                                <enumeratedValue>
                                    <name>1</name>
                                    <description>FIFO message lost</description>
                                    <value>#1</value>
                                </enumeratedValue>
                            </enumeratedValues>
                        </field>
                        <field>
                            <name>RFIF</name>
                            <description>RX FIFO Interrupt Flag</description>
                            <lsb>3</lsb>
                            <msb>3</msb>
                            <access>read-write</access>
                            <enumeratedValues>
                                <enumeratedValue>
                                    <name>0</name>
                                    <description>FIFO interrupt condition not satisfied</description>
                                    <value>#0</value>
                                </enumeratedValue>
                                <enumeratedValue>
                                    <name>1</name>
                                    <description>FIFO interrupt condition satisfied</description>
                                    <value>#1</value>
                                </enumeratedValue>
                            </enumeratedValues>
                        </field>
                        <field>
                            <name>RFMC</name>
                            <description>RX FIFO Message Count</description>
                            <lsb>8</lsb>
                            <msb>13</msb>
                            <access>read-only</access>
                        </field>
                    </fields>
                </register>
                <register>
                    <dim>2</dim>
                    <dimIncrement>0x04</dimIncrement>
                    <dimIndex>0-1</dimIndex>
                    <name>CFDRFPCTR%s</name>
                    <description>RX FIFO Pointer Control Registers %s</description>
                    <addressOffset>0x004C</addressOffset>
                    <size>32</size>
                    <access>write-only</access>
                    <resetValue>0x00000000</resetValue>
                    <resetMask>0xffffffff</resetMask>
                    <fields>
                        <field>
                            <name>RFPC</name>
                            <description>RX FIFO Pointer Control</description>
                            <lsb>0</lsb>
                            <msb>7</msb>
                            <access>write-only</access>
                        </field>
                    </fields>
                </register>
                <register>
                    <name>CFDCFCC</name>
                    <description>Common FIFO Configuration/Control Register</description>
                    <addressOffset>0x0054</addressOffset>
                    <size>32</size>
                    <access>read-write</access>
                    <resetValue>0x00000000</resetValue>
                    <resetMask>0xffffffff</resetMask>
                    <fields>
                        <field>
                            <name>CFE</name>
                            <description>Common FIFO Enable</description>
                            <lsb>0</lsb>
                            <msb>0</msb>
                            <access>read-write</access>
                            <enumeratedValues>
                                <enumeratedValue>
                                    <name>0</name>
                                    <description>FIFO disabled</description>
                                    <value>#0</value>
                                </enumeratedValue>
                                <enumeratedValue>
                                    <name>1</name>
                                    <description>FIFO enabled</description>
                                    <value>#1</value>
                                </enumeratedValue>
                            </enumeratedValues>
                        </field>
                        <field>
                            <name>CFRXIE</name>
                            <description>Common FIFO RX Interrupt Enable</description>
                            <lsb>1</lsb>
                            <msb>1</msb>
                            <access>read-write</access>
                            <enumeratedValues>
                                <enumeratedValue>
                                    <name>0</name>
                                    <description>FIFO interrupt generation disabled for Frame RX</description>
                                    <value>#0</value>
                                </enumeratedValue>
                                <enumeratedValue>
                                    <name>1</name>
                                    <description>FIFO interrupt generation enabled for Frame RX</description>
                                    <value>#1</value>
                                </enumeratedValue>
                            </enumeratedValues>
                        </field>
                        <field>
                            <name>CFTXIE</name>
                            <description>Common FIFO TX Interrupt Enable</description>
                            <lsb>2</lsb>
                            <msb>2</msb>
                            <access>read-write</access>
                            <enumeratedValues>
                                <enumeratedValue>
                                    <name>0</name>
                                    <description>FIFO interrupt generation disabled for Frame TX</description>
                                    <value>#0</value>
                                </enumeratedValue>
                                <enumeratedValue>
                                    <name>1</name>
                                    <description>FIFO interrupt generation enabled for Frame TX</description>
                                    <value>#1</value>
                                </enumeratedValue>
                            </enumeratedValues>
                        </field>
                        <field>
                            <name>CFPLS</name>
                            <description>Common FIFO Payload Data Size Configuration</description>
                            <lsb>4</lsb>
                            <msb>6</msb>
                            <access>read-write</access>
                            <enumeratedValues>
                                <enumeratedValue>
                                    <name>000</name>
                                    <description>8 bytes</description>
                                    <value>#000</value>
                                </enumeratedValue>
                                <enumeratedValue>
                                    <name>001</name>
                                    <description>12 bytes</description>
                                    <value>#001</value>
                                </enumeratedValue>
                                <enumeratedValue>
                                    <name>010</name>
                                    <description>16 bytes</description>
                                    <value>#010</value>
                                </enumeratedValue>
                                <enumeratedValue>
                                    <name>011</name>
                                    <description>20 bytes</description>
                                    <value>#011</value>
                                </enumeratedValue>
                                <enumeratedValue>
                                    <name>100</name>
                                    <description>24 bytes</description>
                                    <value>#100</value>
                                </enumeratedValue>
                                <enumeratedValue>
                                    <name>101</name>
                                    <description>32 bytes</description>
                                    <value>#101</value>
                                </enumeratedValue>
                                <enumeratedValue>
                                    <name>110</name>
                                    <description>48 bytes</description>
                                    <value>#110</value>
                                </enumeratedValue>
                                <enumeratedValue>
                                    <name>111</name>
                                    <description>64 bytes</description>
                                    <value>#111</value>
                                </enumeratedValue>
                            </enumeratedValues>
                        </field>
                        <field>
                            <name>CFM</name>
                            <description>Common FIFO Mode</description>
                            <lsb>8</lsb>
                            <msb>8</msb>
                            <access>read-write</access>
                            <enumeratedValues>
                                <enumeratedValue>
                                    <name>0</name>
                                    <description>RX FIFO mode</description>
                                    <value>#0</value>
                                </enumeratedValue>
                                <enumeratedValue>
                                    <name>1</name>
                                    <description>TX FIFO mode</description>
                                    <value>#1</value>
                                </enumeratedValue>
                            </enumeratedValues>
                        </field>
                        <field>
                            <name>CFITSS</name>
                            <description>Common FIFO Interval Timer Source Select</description>
                            <lsb>10</lsb>
                            <msb>10</msb>
                            <access>read-write</access>
                            <enumeratedValues>
                                <enumeratedValue>
                                    <name>0</name>
                                    <description>Reference clock (× 1 / × 10 period)</description>
                                    <value>#0</value>
                                </enumeratedValue>
                                <enumeratedValue>
                                    <name>1</name>
                                    <description>Bit time clock of related channel (FIFO is linked to fixed channel)</description>
                                    <value>#1</value>
                                </enumeratedValue>
                            </enumeratedValues>
                        </field>
                        <field>
                            <name>CFITR</name>
                            <description>Common FIFO Interval Timer Resolution</description>
                            <lsb>11</lsb>
                            <msb>11</msb>
                            <access>read-write</access>
                            <enumeratedValues>
                                <enumeratedValue>
                                    <name>0</name>
                                    <description>Reference clock period × 1</description>
                                    <value>#0</value>
                                </enumeratedValue>
                                <enumeratedValue>
                                    <name>1</name>
                                    <description>Reference clock period × 10</description>
                                    <value>#1</value>
                                </enumeratedValue>
                            </enumeratedValues>
                        </field>
                        <field>
                            <name>CFIM</name>
                            <description>Common FIFO Interrupt Mode</description>
                            <lsb>12</lsb>
                            <msb>12</msb>
                            <access>read-write</access>
                            <enumeratedValues>
                                <enumeratedValue>
                                    <name>0</name>
                                    <description>RX FIFO mode: RX interrupt generated when Common FIFO counter reaches CFIGCV value from a lower value TX FIFO mode: TX interrupt generated when Common FIFO transmits the last message successfully </description>
                                    <value>#0</value>
                                </enumeratedValue>
                                <enumeratedValue>
                                    <name>1</name>
                                    <description>RX FIFO mode: RX interrupt generated at the end of every received message storage TX FIFO mode: interrupt generated for every successfully transmitted message </description>
                                    <value>#1</value>
                                </enumeratedValue>
                            </enumeratedValues>
                        </field>
                        <field>
                            <name>CFIGCV</name>
                            <description>Common FIFO Interrupt Generation Counter Value</description>
                            <lsb>13</lsb>
                            <msb>15</msb>
                            <access>read-write</access>
                            <enumeratedValues>
                                <enumeratedValue>
                                    <name>000</name>
                                    <description>Interrupt generated when FIFO is 1/8th full</description>
                                    <value>#000</value>
                                </enumeratedValue>
                                <enumeratedValue>
                                    <name>001</name>
                                    <description>Interrupt generated when FIFO is 1/4th full</description>
                                    <value>#001</value>
                                </enumeratedValue>
                                <enumeratedValue>
                                    <name>010</name>
                                    <description>Interrupt generated when FIFO is 3/8th full</description>
                                    <value>#010</value>
                                </enumeratedValue>
                                <enumeratedValue>
                                    <name>011</name>
                                    <description>Interrupt generated when FIFO is 1/2 full</description>
                                    <value>#011</value>
                                </enumeratedValue>
                                <enumeratedValue>
                                    <name>100</name>
                                    <description>Interrupt generated when FIFO is 5/8th full</description>
                                    <value>#100</value>
                                </enumeratedValue>
                                <enumeratedValue>
                                    <name>101</name>
                                    <description>Interrupt generated when FIFO is 3/4th full</description>
                                    <value>#101</value>
                                </enumeratedValue>
                                <enumeratedValue>
                                    <name>110</name>
                                    <description>Interrupt generated when FIFO is 7/8th full</description>
                                    <value>#110</value>
                                </enumeratedValue>
                                <enumeratedValue>
                                    <name>111</name>
                                    <description>Interrupt generated when FIFO is full</description>
                                    <value>#111</value>
                                </enumeratedValue>
                            </enumeratedValues>
                        </field>
                        <field>
                            <name>CFTML</name>
                            <description>Common FIFO TX Message Buffer Link</description>
                            <lsb>16</lsb>
                            <msb>17</msb>
                            <access>read-write</access>
                        </field>
                        <field>
                            <name>CFDC</name>
                            <description>Common FIFO Depth Configuration</description>
                            <lsb>21</lsb>
                            <msb>23</msb>
                            <access>read-write</access>
                            <enumeratedValues>
                                <enumeratedValue>
                                    <name>000</name>
                                    <description>FIFO Depth = 0 message</description>
                                    <value>#000</value>
                                </enumeratedValue>
                                <enumeratedValue>
                                    <name>001</name>
                                    <description>FIFO Depth = 4 messages</description>
                                    <value>#001</value>
                                </enumeratedValue>
                                <enumeratedValue>
                                    <name>010</name>
                                    <description>FIFO Depth = 8 messages</description>
                                    <value>#010</value>
                                </enumeratedValue>
                                <enumeratedValue>
                                    <name>011</name>
                                    <description>FIFO Depth = 16 messages</description>
                                    <value>#011</value>
                                </enumeratedValue>
                                <enumeratedValue>
                                    <name>100</name>
                                    <description>FIFO Depth = 32 messages</description>
                                    <value>#100</value>
                                </enumeratedValue>
                                <enumeratedValue>
                                    <name>101</name>
                                    <description>FIFO Depth = 48 messages</description>
                                    <value>#101</value>
                                </enumeratedValue>
                                <enumeratedValue>
                                    <name>110</name>
                                    <description>FIFO Depth = Reserved</description>
                                    <value>#110</value>
                                </enumeratedValue>
                                <enumeratedValue>
                                    <name>111</name>
                                    <description>FIFO Depth = Reserved</description>
                                    <value>#111</value>
                                </enumeratedValue>
                            </enumeratedValues>
                        </field>
                        <field>
                            <name>CFITT</name>
                            <description>Common FIFO Interval Transmission Time</description>
                            <lsb>24</lsb>
                            <msb>31</msb>
                            <access>read-write</access>
                        </field>
                    </fields>
                </register>
                <register>
                    <name>CFDCFSTS</name>
                    <description>Common FIFO Status Register</description>
                    <addressOffset>0x0058</addressOffset>
                    <size>32</size>
                    <access>read-write</access>
                    <resetValue>0x00000001</resetValue>
                    <resetMask>0xffffffff</resetMask>
                    <fields>
                        <field>
                            <name>CFEMP</name>
                            <description>Common FIFO Empty</description>
                            <lsb>0</lsb>
                            <msb>0</msb>
                            <access>read-only</access>
                            <enumeratedValues>
                                <enumeratedValue>
                                    <name>0</name>
                                    <description>FIFO not empty</description>
                                    <value>#0</value>
                                </enumeratedValue>
                                <enumeratedValue>
                                    <name>1</name>
                                    <description>FIFO empty</description>
                                    <value>#1</value>
                                </enumeratedValue>
                            </enumeratedValues>
                        </field>
                        <field>
                            <name>CFFLL</name>
                            <description>Common FIFO Full</description>
                            <lsb>1</lsb>
                            <msb>1</msb>
                            <access>read-only</access>
                            <enumeratedValues>
                                <enumeratedValue>
                                    <name>0</name>
                                    <description>FIFO not full</description>
                                    <value>#0</value>
                                </enumeratedValue>
                                <enumeratedValue>
                                    <name>1</name>
                                    <description>FIFO full</description>
                                    <value>#1</value>
                                </enumeratedValue>
                            </enumeratedValues>
                        </field>
                        <field>
                            <name>CFMLT</name>
                            <description>Common FIFO Message Lost</description>
                            <lsb>2</lsb>
                            <msb>2</msb>
                            <access>read-write</access>
                            <enumeratedValues>
                                <enumeratedValue>
                                    <name>0</name>
                                    <description>Number of message lost in FIFO</description>
                                    <value>#0</value>
                                </enumeratedValue>
                                <enumeratedValue>
                                    <name>1</name>
                                    <description>FIFO message lost</description>
                                    <value>#1</value>
                                </enumeratedValue>
                            </enumeratedValues>
                        </field>
                        <field>
                            <name>CFRXIF</name>
                            <description>Common RX FIFO Interrupt Flag</description>
                            <lsb>3</lsb>
                            <msb>3</msb>
                            <access>read-write</access>
                            <enumeratedValues>
                                <enumeratedValue>
                                    <name>0</name>
                                    <description>FIFO interrupt condition not satisfied after frame reception</description>
                                    <value>#0</value>
                                </enumeratedValue>
                                <enumeratedValue>
                                    <name>1</name>
                                    <description>FIFO interrupt condition satisfied after frame reception</description>
                                    <value>#1</value>
                                </enumeratedValue>
                            </enumeratedValues>
                        </field>
                        <field>
                            <name>CFTXIF</name>
                            <description>Common TX FIFO Interrupt Flag</description>
                            <lsb>4</lsb>
                            <msb>4</msb>
                            <access>read-write</access>
                            <enumeratedValues>
                                <enumeratedValue>
                                    <name>0</name>
                                    <description>FIFO interrupt condition not satisfied after frame transmission</description>
                                    <value>#0</value>
                                </enumeratedValue>
                                <enumeratedValue>
                                    <name>1</name>
                                    <description>FIFO Interrupt condition satisfied after frame transmission</description>
                                    <value>#1</value>
                                </enumeratedValue>
                            </enumeratedValues>
                        </field>
                        <field>
                            <name>CFMC</name>
                            <description>Common FIFO Message Count</description>
                            <lsb>8</lsb>
                            <msb>13</msb>
                            <access>read-only</access>
                        </field>
                    </fields>
                </register>
                <register>
                    <name>CFDCFPCTR</name>
                    <description>Common FIFO Pointer Control Register</description>
                    <addressOffset>0x005C</addressOffset>
                    <size>32</size>
                    <access>write-only</access>
                    <resetValue>0x00000000</resetValue>
                    <resetMask>0xffffffff</resetMask>
                    <fields>
                        <field>
                            <name>CFPC</name>
                            <description>Common FIFO Pointer Control</description>
                            <lsb>0</lsb>
                            <msb>7</msb>
                            <access>write-only</access>
                        </field>
                    </fields>
                </register>
                <register>
                    <name>CFDFESTS</name>
                    <description>FIFO Empty Status Register</description>
                    <addressOffset>0x0060</addressOffset>
                    <size>32</size>
                    <access>read-only</access>
                    <resetValue>0x00000103</resetValue>
                    <resetMask>0xffffffff</resetMask>
                    <fields>
                        <field>
                            <name>RFXEMP</name>
                            <description>RX FIFO Empty Status</description>
                            <lsb>0</lsb>
                            <msb>1</msb>
                            <access>read-only</access>
                            <enumeratedValues>
                                <enumeratedValue>
                                    <name>0</name>
                                    <description>Corresponding FIFO not empty</description>
                                    <value>#0</value>
                                </enumeratedValue>
                                <enumeratedValue>
                                    <name>1</name>
                                    <description>Corresponding FIFO empty</description>
                                    <value>#1</value>
                                </enumeratedValue>
                            </enumeratedValues>
                        </field>
                        <field>
                            <name>CFEMP</name>
                            <description>Common FIFO Empty Status</description>
                            <lsb>8</lsb>
                            <msb>8</msb>
                            <access>read-only</access>
                            <enumeratedValues>
                                <enumeratedValue>
                                    <name>0</name>
                                    <description>Corresponding FIFO not empty</description>
                                    <value>#0</value>
                                </enumeratedValue>
                                <enumeratedValue>
                                    <name>1</name>
                                    <description>Corresponding FIFO empty</description>
                                    <value>#1</value>
                                </enumeratedValue>
                            </enumeratedValues>
                        </field>
                    </fields>
                </register>
                <register>
                    <name>CFDFFSTS</name>
                    <description>FIFO Full Status Register</description>
                    <addressOffset>0x0064</addressOffset>
                    <size>32</size>
                    <access>read-only</access>
                    <resetValue>0x00000000</resetValue>
                    <resetMask>0xffffffff</resetMask>
                    <fields>
                        <field>
                            <name>RFXFLL</name>
                            <description>RX FIF0 Full Status</description>
                            <lsb>0</lsb>
                            <msb>1</msb>
                            <access>read-only</access>
                            <enumeratedValues>
                                <enumeratedValue>
                                    <name>0</name>
                                    <description>Corresponding FIFO not full</description>
                                    <value>#0</value>
                                </enumeratedValue>
                                <enumeratedValue>
                                    <name>1</name>
                                    <description>Corresponding FIFO full</description>
                                    <value>#1</value>
                                </enumeratedValue>
                            </enumeratedValues>
                        </field>
                        <field>
                            <name>CFFLL</name>
                            <description>Common FIF0 Full Status</description>
                            <lsb>8</lsb>
                            <msb>8</msb>
                            <access>read-only</access>
                            <enumeratedValues>
                                <enumeratedValue>
                                    <name>0</name>
                                    <description>Corresponding FIFO not full</description>
                                    <value>#0</value>
                                </enumeratedValue>
                                <enumeratedValue>
                                    <name>1</name>
                                    <description>Corresponding FIFO full</description>
                                    <value>#1</value>
                                </enumeratedValue>
                            </enumeratedValues>
                        </field>
                    </fields>
                </register>
                <register>
                    <name>CFDFMSTS</name>
                    <description>FIFO Message Lost Status Register</description>
                    <addressOffset>0x0068</addressOffset>
                    <size>32</size>
                    <access>read-only</access>
                    <resetValue>0x00000000</resetValue>
                    <resetMask>0xffffffff</resetMask>
                    <fields>
                        <field>
                            <name>RFXMLT</name>
                            <description>RX FIFO Message Lost Status</description>
                            <lsb>0</lsb>
                            <msb>1</msb>
                            <access>read-only</access>
                            <enumeratedValues>
                                <enumeratedValue>
                                    <name>0</name>
                                    <description>Corresponding FIFO Message Lost flag not set</description>
                                    <value>#0</value>
                                </enumeratedValue>
                                <enumeratedValue>
                                    <name>1</name>
                                    <description>Corresponding FIFO Message Lost flag set</description>
                                    <value>#1</value>
                                </enumeratedValue>
                            </enumeratedValues>
                        </field>
                        <field>
                            <name>CFMLT</name>
                            <description>Common FIFO Message Lost Status</description>
                            <lsb>8</lsb>
                            <msb>8</msb>
                            <access>read-only</access>
                            <enumeratedValues>
                                <enumeratedValue>
                                    <name>0</name>
                                    <description>Corresponding FIFO Message Lost flag not set</description>
                                    <value>#0</value>
                                </enumeratedValue>
                                <enumeratedValue>
                                    <name>1</name>
                                    <description>Corresponding FIFO Message Lost flag set</description>
                                    <value>#1</value>
                                </enumeratedValue>
                            </enumeratedValues>
                        </field>
                    </fields>
                </register>
                <register>
                    <name>CFDRFISTS</name>
                    <description>RX FIFO Interrupt Flag Status Register</description>
                    <addressOffset>0x006C</addressOffset>
                    <size>32</size>
                    <access>read-only</access>
                    <resetValue>0x00000000</resetValue>
                    <resetMask>0xffffffff</resetMask>
                    <fields>
                        <field>
                            <name>RFXIF</name>
                            <description>RX FIFO[x] Interrupt Flag Status</description>
                            <lsb>0</lsb>
                            <msb>1</msb>
                            <access>read-only</access>
                            <enumeratedValues>
                                <enumeratedValue>
                                    <name>0</name>
                                    <description>Corresponding RX FIFO Interrupt flag not set</description>
                                    <value>#0</value>
                                </enumeratedValue>
                                <enumeratedValue>
                                    <name>1</name>
                                    <description>Corresponding RX FIFO Interrupt flag set</description>
                                    <value>#1</value>
                                </enumeratedValue>
                            </enumeratedValues>
                        </field>
                    </fields>
                </register>
                <register>
                    <dim>4</dim>
                    <dimIncrement>0x01</dimIncrement>
                    <dimIndex>0-3</dimIndex>
                    <name>CFDTMC%s</name>
                    <description>TX Message Buffer Control Registers %s</description>
                    <addressOffset>0x0070</addressOffset>
                    <size>8</size>
                    <access>read-write</access>
                    <resetValue>0x00</resetValue>
                    <resetMask>0xff</resetMask>
                    <fields>
                        <field>
                            <name>TMTR</name>
                            <description>TX Message Buffer Transmission Request</description>
                            <lsb>0</lsb>
                            <msb>0</msb>
                            <access>read-write</access>
                            <enumeratedValues>
                                <enumeratedValue>
                                    <name>0</name>
                                    <description>TX Message buffer transmission not requested</description>
                                    <value>#0</value>
                                </enumeratedValue>
                                <enumeratedValue>
                                    <name>1</name>
                                    <description>TX message buffer transmission requested</description>
                                    <value>#1</value>
                                </enumeratedValue>
                            </enumeratedValues>
                        </field>
                        <field>
                            <name>TMTAR</name>
                            <description>TX Message Buffer Transmission Abort Request</description>
                            <lsb>1</lsb>
                            <msb>1</msb>
                            <access>read-write</access>
                            <enumeratedValues>
                                <enumeratedValue>
                                    <name>0</name>
                                    <description>TX message buffer transmission request abort not requested</description>
                                    <value>#0</value>
                                </enumeratedValue>
                                <enumeratedValue>
                                    <name>1</name>
                                    <description>TX message buffer transmission request abort requested</description>
                                    <value>#1</value>
                                </enumeratedValue>
                            </enumeratedValues>
                        </field>
                        <field>
                            <name>TMOM</name>
                            <description>TX Message Buffer One-shot Mode</description>
                            <lsb>2</lsb>
                            <msb>2</msb>
                            <access>read-write</access>
                            <enumeratedValues>
                                <enumeratedValue>
                                    <name>0</name>
                                    <description>TX message buffer not configured in one-shot mode</description>
                                    <value>#0</value>
                                </enumeratedValue>
                                <enumeratedValue>
                                    <name>1</name>
                                    <description>TX message buffer configured in one-shot mode</description>
                                    <value>#1</value>
                                </enumeratedValue>
                            </enumeratedValues>
                        </field>
                    </fields>
                </register>
                <register>
                    <dim>4</dim>
                    <dimIncrement>0x01</dimIncrement>
                    <dimIndex>0-3</dimIndex>
                    <name>CFDTMSTS%s</name>
                    <description>TX Message Buffer Status Registers %s</description>
                    <addressOffset>0x0074</addressOffset>
                    <size>8</size>
                    <access>read-write</access>
                    <resetValue>0x00</resetValue>
                    <resetMask>0xff</resetMask>
                    <fields>
                        <field>
                            <name>TMTSTS</name>
                            <description>TX Message Buffer Transmission Status</description>
                            <lsb>0</lsb>
                            <msb>0</msb>
                            <access>read-only</access>
                            <enumeratedValues>
                                <enumeratedValue>
                                    <name>0</name>
                                    <description>No on-going transmission</description>
                                    <value>#0</value>
                                </enumeratedValue>
                                <enumeratedValue>
                                    <name>1</name>
                                    <description>On-going transmission</description>
                                    <value>#1</value>
                                </enumeratedValue>
                            </enumeratedValues>
                        </field>
                        <field>
                            <name>TMTRF</name>
                            <description>TX Message Buffer Transmission Result Flag</description>
                            <lsb>1</lsb>
                            <msb>2</msb>
                            <access>read-write</access>
                            <enumeratedValues>
                                <enumeratedValue>
                                    <name>00</name>
                                    <description>No result</description>
                                    <value>#00</value>
                                </enumeratedValue>
                                <enumeratedValue>
                                    <name>01</name>
                                    <description>Transmission aborted from the TX message buffer</description>
                                    <value>#01</value>
                                </enumeratedValue>
                                <enumeratedValue>
                                    <name>10</name>
                                    <description>Transmission successful from the TX message buffer and transmission abort was not requested</description>
                                    <value>#10</value>
                                </enumeratedValue>
                                <enumeratedValue>
                                    <name>11</name>
                                    <description>Transmission successful from the TX message buffer and transmission abort was requested</description>
                                    <value>#11</value>
                                </enumeratedValue>
                            </enumeratedValues>
                        </field>
                        <field>
                            <name>TMTRM</name>
                            <description>TX Message Buffer Transmission Request Mirrored</description>
                            <lsb>3</lsb>
                            <msb>3</msb>
                            <access>read-only</access>
                            <enumeratedValues>
                                <enumeratedValue>
                                    <name>0</name>
                                    <description>TX message buffer transmission not requested</description>
                                    <value>#0</value>
                                </enumeratedValue>
                                <enumeratedValue>
                                    <name>1</name>
                                    <description>TX message buffer transmission requested</description>
                                    <value>#1</value>
                                </enumeratedValue>
                            </enumeratedValues>
                        </field>
                        <field>
                            <name>TMTARM</name>
                            <description>TX Message Buffer Transmission Abort Request Mirrored</description>
                            <lsb>4</lsb>
                            <msb>4</msb>
                            <access>read-only</access>
                            <enumeratedValues>
                                <enumeratedValue>
                                    <name>0</name>
                                    <description>TX message buffer transmission request abort not requested</description>
                                    <value>#0</value>
                                </enumeratedValue>
                                <enumeratedValue>
                                    <name>1</name>
                                    <description>TX message buffer transmission request abort requested</description>
                                    <value>#1</value>
                                </enumeratedValue>
                            </enumeratedValues>
                        </field>
                    </fields>
                </register>
                <register>
                    <name>CFDTMTRSTS</name>
                    <description>TX Message Buffer Transmission Request Status Register</description>
                    <addressOffset>0x0078</addressOffset>
                    <size>32</size>
                    <access>read-only</access>
                    <resetValue>0x00000000</resetValue>
                    <resetMask>0xffffffff</resetMask>
                    <fields>
                        <field>
                            <name>CFDTMTRSTS</name>
                            <description>TX Message Buffer Transmission Request Status</description>
                            <lsb>0</lsb>
                            <msb>3</msb>
                            <access>read-only</access>
                            <enumeratedValues>
                                <enumeratedValue>
                                    <name>0</name>
                                    <description>Transmission not requested for corresponding TX message buffer</description>
                                    <value>#0</value>
                                </enumeratedValue>
                                <enumeratedValue>
                                    <name>1</name>
                                    <description>Transmission requested for corresponding TX message buffer</description>
                                    <value>#1</value>
                                </enumeratedValue>
                            </enumeratedValues>
                        </field>
                    </fields>
                </register>
                <register>
                    <name>CFDTMTARSTS</name>
                    <description>TX Message Buffer Transmission Abort Request Status Register</description>
                    <addressOffset>0x007C</addressOffset>
                    <size>32</size>
                    <access>read-only</access>
                    <resetValue>0x00000000</resetValue>
                    <resetMask>0xffffffff</resetMask>
                    <fields>
                        <field>
                            <name>CFDTMTARSTS</name>
                            <description>TX Message Buffer Transmission Abort Request Status</description>
                            <lsb>0</lsb>
                            <msb>3</msb>
                            <access>read-only</access>
                            <enumeratedValues>
                                <enumeratedValue>
                                    <name>0</name>
                                    <description>Transmission abort not requested for corresponding TX message buffer</description>
                                    <value>#0</value>
                                </enumeratedValue>
                                <enumeratedValue>
                                    <name>1</name>
                                    <description>Transmission abort requested for corresponding TX message buffer</description>
                                    <value>#1</value>
                                </enumeratedValue>
                            </enumeratedValues>
                        </field>
                    </fields>
                </register>
                <register>
                    <name>CFDTMTCSTS</name>
                    <description>TX Message Buffer Transmission Completion Status Register</description>
                    <addressOffset>0x0080</addressOffset>
                    <size>32</size>
                    <access>read-only</access>
                    <resetValue>0x00000000</resetValue>
                    <resetMask>0xffffffff</resetMask>
                    <fields>
                        <field>
                            <name>CFDTMTCSTS</name>
                            <description>TX Message Buffer Transmission Completion Status</description>
                            <lsb>0</lsb>
                            <msb>3</msb>
                            <access>read-only</access>
                            <enumeratedValues>
                                <enumeratedValue>
                                    <name>0</name>
                                    <description>Transmission not complete for corresponding TX message buffer</description>
                                    <value>#0</value>
                                </enumeratedValue>
                                <enumeratedValue>
                                    <name>1</name>
                                    <description>Transmission completed for corresponding TX message buffer</description>
                                    <value>#1</value>
                                </enumeratedValue>
                            </enumeratedValues>
                        </field>
                    </fields>
                </register>
                <register>
                    <name>CFDTMTASTS</name>
                    <description>TX Message Buffer Transmission Abort Status Register</description>
                    <addressOffset>0x0084</addressOffset>
                    <size>32</size>
                    <access>read-only</access>
                    <resetValue>0x00000000</resetValue>
                    <resetMask>0xffffffff</resetMask>
                    <fields>
                        <field>
                            <name>CFDTMTASTS</name>
                            <description>TX Message Buffer Transmission Abort Status</description>
                            <lsb>0</lsb>
                            <msb>3</msb>
                            <access>read-only</access>
                            <enumeratedValues>
                                <enumeratedValue>
                                    <name>0</name>
                                    <description>Transmission not aborted for corresponding TX message buffer</description>
                                    <value>#0</value>
                                </enumeratedValue>
                                <enumeratedValue>
                                    <name>1</name>
                                    <description>Transmission aborted for corresponding TX message buffer</description>
                                    <value>#1</value>
                                </enumeratedValue>
                            </enumeratedValues>
                        </field>
                    </fields>
                </register>
                <register>
                    <name>CFDTMIEC</name>
                    <description>TX Message Buffer Interrupt Enable Configuration Register</description>
                    <addressOffset>0x0088</addressOffset>
                    <size>32</size>
                    <access>read-write</access>
                    <resetValue>0x00000000</resetValue>
                    <resetMask>0xffffffff</resetMask>
                    <fields>
                        <field>
                            <name>TMIEg</name>
                            <description>TX Message Buffer Interrupt Enable</description>
                            <lsb>0</lsb>
                            <msb>3</msb>
                            <access>read-write</access>
                            <enumeratedValues>
                                <enumeratedValue>
                                    <name>0</name>
                                    <description>TX message buffer interrupt disabled for corresponding TX message buffer</description>
                                    <value>#0</value>
                                </enumeratedValue>
                                <enumeratedValue>
                                    <name>1</name>
                                    <description>TX message buffer interrupt enabled for corresponding TX message buffer</description>
                                    <value>#1</value>
                                </enumeratedValue>
                            </enumeratedValues>
                        </field>
                    </fields>
                </register>
                <register>
                    <name>CFDTXQCC</name>
                    <description>TX Queue Configuration/Control Register</description>
                    <addressOffset>0x008C</addressOffset>
                    <size>32</size>
                    <access>read-write</access>
                    <resetValue>0x00000000</resetValue>
                    <resetMask>0xffffffff</resetMask>
                    <fields>
                        <field>
                            <name>TXQE</name>
                            <description>TX Queue Enable</description>
                            <lsb>0</lsb>
                            <msb>0</msb>
                            <access>read-write</access>
                            <enumeratedValues>
                                <enumeratedValue>
                                    <name>0</name>
                                    <description>TX Queue disabled</description>
                                    <value>#0</value>
                                </enumeratedValue>
                                <enumeratedValue>
                                    <name>1</name>
                                    <description>TX Queue enabled</description>
                                    <value>#1</value>
                                </enumeratedValue>
                            </enumeratedValues>
                        </field>
                        <field>
                            <name>TXQTXIE</name>
                            <description>TX Queue TX Interrupt Enable</description>
                            <lsb>5</lsb>
                            <msb>5</msb>
                            <access>read-write</access>
                            <enumeratedValues>
                                <enumeratedValue>
                                    <name>0</name>
                                    <description>TX Queue TX interrupt disabled</description>
                                    <value>#0</value>
                                </enumeratedValue>
                                <enumeratedValue>
                                    <name>1</name>
                                    <description>TX Queue TX interrupt enabled</description>
                                    <value>#1</value>
                                </enumeratedValue>
                            </enumeratedValues>
                        </field>
                        <field>
                            <name>TXQIM</name>
                            <description>TX Queue Interrupt Mode</description>
                            <lsb>7</lsb>
                            <msb>7</msb>
                            <access>read-write</access>
                            <enumeratedValues>
                                <enumeratedValue>
                                    <name>0</name>
                                    <description>When the last message is successfully transmitted</description>
                                    <value>#0</value>
                                </enumeratedValue>
                                <enumeratedValue>
                                    <name>1</name>
                                    <description>At every successful transmission</description>
                                    <value>#1</value>
                                </enumeratedValue>
                            </enumeratedValues>
                        </field>
                        <field>
                            <name>TXQDC</name>
                            <description>TX Queue Depth Configuration</description>
                            <lsb>8</lsb>
                            <msb>9</msb>
                            <access>read-write</access>
                            <enumeratedValues>
                                <enumeratedValue>
                                    <name>0x00</name>
                                    <description>0 messages</description>
                                    <value>0x00</value>
                                </enumeratedValue>
                                <enumeratedValue>
                                    <name>0x01</name>
                                    <description>Reserved</description>
                                    <value>0x01</value>
                                </enumeratedValue>
                                <enumeratedValue>
                                    <name>0x10</name>
                                    <description>3 messages</description>
                                    <value>0x10</value>
                                </enumeratedValue>
                                <enumeratedValue>
                                    <name>0x11</name>
                                    <description>4 messages</description>
                                    <value>0x11</value>
                                </enumeratedValue>
                            </enumeratedValues>
                        </field>
                    </fields>
                </register>
                <register>
                    <name>CFDTXQSTS</name>
                    <description>TX Queue Status Register</description>
                    <addressOffset>0x0090</addressOffset>
                    <size>32</size>
                    <access>read-write</access>
                    <resetValue>0x00000001</resetValue>
                    <resetMask>0xffffffff</resetMask>
                    <fields>
                        <field>
                            <name>TXQEMP</name>
                            <description>TX Queue Empty</description>
                            <lsb>0</lsb>
                            <msb>0</msb>
                            <access>read-only</access>
                            <enumeratedValues>
                                <enumeratedValue>
                                    <name>0</name>
                                    <description>TX Queue not empty</description>
                                    <value>#0</value>
                                </enumeratedValue>
                                <enumeratedValue>
                                    <name>1</name>
                                    <description>TX Queue empty</description>
                                    <value>#1</value>
                                </enumeratedValue>
                            </enumeratedValues>
                        </field>
                        <field>
                            <name>TXQFLL</name>
                            <description>TX Queue Full</description>
                            <lsb>1</lsb>
                            <msb>1</msb>
                            <access>read-only</access>
                            <enumeratedValues>
                                <enumeratedValue>
                                    <name>0</name>
                                    <description>TX Queue not full</description>
                                    <value>#0</value>
                                </enumeratedValue>
                                <enumeratedValue>
                                    <name>1</name>
                                    <description>TX Queue full</description>
                                    <value>#1</value>
                                </enumeratedValue>
                            </enumeratedValues>
                        </field>
                        <field>
                            <name>TXQTXIF</name>
                            <description>TX Queue TX Interrupt Flag</description>
                            <lsb>2</lsb>
                            <msb>2</msb>
                            <access>read-write</access>
                            <enumeratedValues>
                                <enumeratedValue>
                                    <name>0</name>
                                    <description>TX Queue interrupt condition not satisfied after a frame TX</description>
                                    <value>#0</value>
                                </enumeratedValue>
                                <enumeratedValue>
                                    <name>1</name>
                                    <description>TX Queue interrupt condition satisfied after a frame TX</description>
                                    <value>#1</value>
                                </enumeratedValue>
                            </enumeratedValues>
                        </field>
                        <field>
                            <name>TXQMC</name>
                            <description>TX Queue Message Count</description>
                            <lsb>8</lsb>
                            <msb>10</msb>
                            <access>read-only</access>
                        </field>
                    </fields>
                </register>
                <register>
                    <name>CFDTXQPCTR</name>
                    <description>TX Queue Pointer Control Register</description>
                    <addressOffset>0x0094</addressOffset>
                    <size>32</size>
                    <access>write-only</access>
                    <resetValue>0x00000000</resetValue>
                    <resetMask>0xffffffff</resetMask>
                    <fields>
                        <field>
                            <name>TXQPC</name>
                            <description>TX Queue Pointer Control</description>
                            <lsb>0</lsb>
                            <msb>7</msb>
                            <access>write-only</access>
                        </field>
                    </fields>
                </register>
                <register>
                    <name>CFDTHLCC</name>
                    <description>TX History List Configuration/Control Register</description>
                    <addressOffset>0x0098</addressOffset>
                    <size>32</size>
                    <access>read-write</access>
                    <resetValue>0x00000000</resetValue>
                    <resetMask>0xffffffff</resetMask>
                    <fields>
                        <field>
                            <name>THLE</name>
                            <description>TX History List Enable</description>
                            <lsb>0</lsb>
                            <msb>0</msb>
                            <access>read-write</access>
                            <enumeratedValues>
                                <enumeratedValue>
                                    <name>0</name>
                                    <description>TX History List disabled</description>
                                    <value>#0</value>
                                </enumeratedValue>
                                <enumeratedValue>
                                    <name>1</name>
                                    <description>TX History List enabled</description>
                                    <value>#1</value>
                                </enumeratedValue>
                            </enumeratedValues>
                        </field>
                        <field>
                            <name>THLIE</name>
                            <description>TX History List Interrupt Enable</description>
                            <lsb>8</lsb>
                            <msb>8</msb>
                            <access>read-write</access>
                            <enumeratedValues>
                                <enumeratedValue>
                                    <name>0</name>
                                    <description>TX History List Interrupt disabled</description>
                                    <value>#0</value>
                                </enumeratedValue>
                                <enumeratedValue>
                                    <name>1</name>
                                    <description>TX History List Interrupt enabled</description>
                                    <value>#1</value>
                                </enumeratedValue>
                            </enumeratedValues>
                        </field>
                        <field>
                            <name>THLIM</name>
                            <description>TX History List Interrupt Mode</description>
                            <lsb>9</lsb>
                            <msb>9</msb>
                            <access>read-write</access>
                            <enumeratedValues>
                                <enumeratedValue>
                                    <name>0</name>
                                    <description>Interrupt generated if TX History List level reaches ¾ of the TX History List depth</description>
                                    <value>#0</value>
                                </enumeratedValue>
                                <enumeratedValue>
                                    <name>1</name>
                                    <description>Interrupt generated for every successfully stored entry</description>
                                    <value>#1</value>
                                </enumeratedValue>
                            </enumeratedValues>
                        </field>
                        <field>
                            <name>THLDTE</name>
                            <description>TX History List Dedicated TX Enable</description>
                            <lsb>10</lsb>
                            <msb>10</msb>
                            <access>read-write</access>
                            <enumeratedValues>
                                <enumeratedValue>
                                    <name>0</name>
                                    <description>TX FIFO + TX Queue</description>
                                    <value>#0</value>
                                </enumeratedValue>
                                <enumeratedValue>
                                    <name>1</name>
                                    <description>Flat TX MB + TX FIFO + TX Queue</description>
                                    <value>#1</value>
                                </enumeratedValue>
                            </enumeratedValues>
                        </field>
                    </fields>
                </register>
                <register>
                    <name>CFDTHLSTS</name>
                    <description>TX History List Status Register</description>
                    <addressOffset>0x009C</addressOffset>
                    <size>32</size>
                    <access>read-write</access>
                    <resetValue>0x00000001</resetValue>
                    <resetMask>0xffffffff</resetMask>
                    <fields>
                        <field>
                            <name>THLEMP</name>
                            <description>TX History List Empty</description>
                            <lsb>0</lsb>
                            <msb>0</msb>
                            <access>read-only</access>
                            <enumeratedValues>
                                <enumeratedValue>
                                    <name>0</name>
                                    <description>TX History List not empty</description>
                                    <value>#0</value>
                                </enumeratedValue>
                                <enumeratedValue>
                                    <name>1</name>
                                    <description>TX History List empty</description>
                                    <value>#1</value>
                                </enumeratedValue>
                            </enumeratedValues>
                        </field>
                        <field>
                            <name>THLFLL</name>
                            <description>TX History List Full</description>
                            <lsb>1</lsb>
                            <msb>1</msb>
                            <access>read-only</access>
                            <enumeratedValues>
                                <enumeratedValue>
                                    <name>0</name>
                                    <description>TX History List not full</description>
                                    <value>#0</value>
                                </enumeratedValue>
                                <enumeratedValue>
                                    <name>1</name>
                                    <description>TX History List full</description>
                                    <value>#1</value>
                                </enumeratedValue>
                            </enumeratedValues>
                        </field>
                        <field>
                            <name>THLELT</name>
                            <description>TX History List Entry Lost</description>
                            <lsb>2</lsb>
                            <msb>2</msb>
                            <access>read-write</access>
                            <enumeratedValues>
                                <enumeratedValue>
                                    <name>0</name>
                                    <description>No entry lost in TX History List</description>
                                    <value>#0</value>
                                </enumeratedValue>
                                <enumeratedValue>
                                    <name>1</name>
                                    <description>TX History List entry Lost</description>
                                    <value>#1</value>
                                </enumeratedValue>
                            </enumeratedValues>
                        </field>
                        <field>
                            <name>THLIF</name>
                            <description>TX History List Interrupt Flag</description>
                            <lsb>3</lsb>
                            <msb>3</msb>
                            <access>read-write</access>
                            <enumeratedValues>
                                <enumeratedValue>
                                    <name>0</name>
                                    <description>TX History List interrupt condition not satisfied</description>
                                    <value>#0</value>
                                </enumeratedValue>
                                <enumeratedValue>
                                    <name>1</name>
                                    <description>TX History List interrupt condition satisfied</description>
                                    <value>#1</value>
                                </enumeratedValue>
                            </enumeratedValues>
                        </field>
                        <field>
                            <name>THLMC</name>
                            <description>TX History List Message Count</description>
                            <lsb>8</lsb>
                            <msb>11</msb>
                            <access>read-only</access>
                        </field>
                    </fields>
                </register>
                <register>
                    <name>CFDTHLPCTR</name>
                    <description>TX History List Pointer Control Register</description>
                    <addressOffset>0x00A0</addressOffset>
                    <size>32</size>
                    <access>write-only</access>
                    <resetValue>0x00000000</resetValue>
                    <resetMask>0xffffffff</resetMask>
                    <fields>
                        <field>
                            <name>THLPC</name>
                            <description>TX History List Pointer Control</description>
                            <lsb>0</lsb>
                            <msb>7</msb>
                            <access>write-only</access>
                        </field>
                    </fields>
                </register>
                <register>
                    <name>CFDGTINTSTS</name>
                    <description>Global TX Interrupt Status Register</description>
                    <addressOffset>0x00A4</addressOffset>
                    <size>32</size>
                    <access>read-only</access>
                    <resetValue>0x00000000</resetValue>
                    <resetMask>0xffffffff</resetMask>
                    <fields>
                        <field>
                            <name>TSIF0</name>
                            <description>TX Successful Interrupt Flag</description>
                            <lsb>0</lsb>
                            <msb>0</msb>
                            <access>read-only</access>
                            <enumeratedValues>
                                <enumeratedValue>
                                    <name>0</name>
                                    <description>Channel n TX Successful Interrupt flag not set</description>
                                    <value>#0</value>
                                </enumeratedValue>
                                <enumeratedValue>
                                    <name>1</name>
                                    <description>Channel n TX Successful Interrupt flag set</description>
                                    <value>#1</value>
                                </enumeratedValue>
                            </enumeratedValues>
                        </field>
                        <field>
                            <name>TAI0</name>
                            <description>TX Abort Interrupt Flag</description>
                            <lsb>1</lsb>
                            <msb>1</msb>
                            <access>read-only</access>
                            <enumeratedValues>
                                <enumeratedValue>
                                    <name>0</name>
                                    <description>Channel n TX Abort Interrupt flag not set</description>
                                    <value>#0</value>
                                </enumeratedValue>
                                <enumeratedValue>
                                    <name>1</name>
                                    <description>Channel n TX Abort Interrupt flag set</description>
                                    <value>#1</value>
                                </enumeratedValue>
                            </enumeratedValues>
                        </field>
                        <field>
                            <name>TQIF0</name>
                            <description>TX Queue Interrupt Flag</description>
                            <lsb>2</lsb>
                            <msb>2</msb>
                            <access>read-only</access>
                            <enumeratedValues>
                                <enumeratedValue>
                                    <name>0</name>
                                    <description>Channel n TX Queue Interrupt flag not set</description>
                                    <value>#0</value>
                                </enumeratedValue>
                                <enumeratedValue>
                                    <name>1</name>
                                    <description>Channel n TX Queue Interrupt flag set</description>
                                    <value>#1</value>
                                </enumeratedValue>
                            </enumeratedValues>
                        </field>
                        <field>
                            <name>CFTIF0</name>
                            <description>COM FIFO TX Mode Interrupt Flag</description>
                            <lsb>3</lsb>
                            <msb>3</msb>
                            <access>read-only</access>
                            <enumeratedValues>
                                <enumeratedValue>
                                    <name>0</name>
                                    <description>Channel n COM FIFO TX Mode Interrupt flag not set</description>
                                    <value>#0</value>
                                </enumeratedValue>
                                <enumeratedValue>
                                    <name>1</name>
                                    <description>Channel n COM FIFO TX Mode Interrupt flag set</description>
                                    <value>#1</value>
                                </enumeratedValue>
                            </enumeratedValues>
                        </field>
                        <field>
                            <name>THIF0</name>
                            <description>TX History List Interrupt</description>
                            <lsb>4</lsb>
                            <msb>4</msb>
                            <access>read-only</access>
                            <enumeratedValues>
                                <enumeratedValue>
                                    <name>0</name>
                                    <description>Channel n TX History List Interrupt flag not set</description>
                                    <value>#0</value>
                                </enumeratedValue>
                                <enumeratedValue>
                                    <name>1</name>
                                    <description>Channel n TX History List Interrupt flag set</description>
                                    <value>#1</value>
                                </enumeratedValue>
                            </enumeratedValues>
                        </field>
                    </fields>
                </register>
                <register>
                    <name>CFDGTSTCFG</name>
                    <description>Global Test Configuration Register</description>
                    <addressOffset>0x00A8</addressOffset>
                    <size>32</size>
                    <access>read-write</access>
                    <resetValue>0x00000000</resetValue>
                    <resetMask>0xffffffff</resetMask>
                    <fields>
                        <field>
                            <name>RTMPS</name>
                            <description>RAM Test Mode Page Select</description>
                            <lsb>16</lsb>
                            <msb>19</msb>
                            <access>read-write</access>
                        </field>
                    </fields>
                </register>
                <register>
                    <name>CFDGTSTCTR</name>
                    <description>Global Test Control Register</description>
                    <addressOffset>0x00AC</addressOffset>
                    <size>32</size>
                    <access>read-write</access>
                    <resetValue>0x00000000</resetValue>
                    <resetMask>0xffffffff</resetMask>
                    <fields>
                        <field>
                            <name>RTME</name>
                            <description>RAM Test Mode Enable</description>
                            <lsb>2</lsb>
                            <msb>2</msb>
                            <access>read-write</access>
                            <enumeratedValues>
                                <enumeratedValue>
                                    <name>0</name>
                                    <description>RAM test mode disabled</description>
                                    <value>#0</value>
                                </enumeratedValue>
                                <enumeratedValue>
                                    <name>1</name>
                                    <description>RAM test mode enabled</description>
                                    <value>#1</value>
                                </enumeratedValue>
                            </enumeratedValues>
                        </field>
                    </fields>
                </register>
                <register>
                    <name>CFDGFDCFG</name>
                    <description>Global FD Configuration Register</description>
                    <addressOffset>0x00B0</addressOffset>
                    <size>32</size>
                    <access>read-write</access>
                    <resetValue>0x00000000</resetValue>
                    <resetMask>0xffffffff</resetMask>
                    <fields>
                        <field>
                            <name>RPED</name>
                            <description>RES Bit Protocol Exception Disable</description>
                            <lsb>0</lsb>
                            <msb>0</msb>
                            <access>read-write</access>
                            <enumeratedValues>
                                <enumeratedValue>
                                    <name>0</name>
                                    <description>Protocol exception event detection enabled</description>
                                    <value>#0</value>
                                </enumeratedValue>
                                <enumeratedValue>
                                    <name>1</name>
                                    <description>Protocol exception event detection disabled</description>
                                    <value>#1</value>
                                </enumeratedValue>
                            </enumeratedValues>
                        </field>
                        <field>
                            <name>TSCCFG</name>
                            <description>Timestamp Capture Configuration</description>
                            <lsb>8</lsb>
                            <msb>9</msb>
                            <access>read-write</access>
                            <enumeratedValues>
                                <enumeratedValue>
                                    <name>00</name>
                                    <description>Timestamp capture at the sample point of SOF (start of frame)</description>
                                    <value>#00</value>
                                </enumeratedValue>
                                <enumeratedValue>
                                    <name>01</name>
                                    <description>Timestamp capture at frame valid indication</description>
                                    <value>#01</value>
                                </enumeratedValue>
                                <enumeratedValue>
                                    <name>10</name>
                                    <description>Timestamp capture at the sample point of RES bit</description>
                                    <value>#10</value>
                                </enumeratedValue>
                                <enumeratedValue>
                                    <name>11</name>
                                    <description>Reserved</description>
                                    <value>#11</value>
                                </enumeratedValue>
                            </enumeratedValues>
                        </field>
                    </fields>
                </register>
                <register>
                    <name>CFDGLOCKK</name>
                    <description>Global Lock Key Register</description>
                    <addressOffset>0x00B8</addressOffset>
                    <size>32</size>
                    <access>write-only</access>
                    <resetValue>0x00000000</resetValue>
                    <resetMask>0xffffffff</resetMask>
                    <fields>
                        <field>
                            <name>LOCK</name>
                            <description>Lock Key</description>
                            <lsb>0</lsb>
                            <msb>15</msb>
                            <access>write-only</access>
                        </field>
                    </fields>
                </register>
                <register>
                    <name>CFDGAFLIGNENT</name>
                    <description>Global AFL Ignore Entry Register</description>
                    <addressOffset>0x00C0</addressOffset>
                    <size>32</size>
                    <access>read-write</access>
                    <resetValue>0x00000000</resetValue>
                    <resetMask>0xffffffff</resetMask>
                    <fields>
                        <field>
                            <name>IRN</name>
                            <description>Ignore Rule Number</description>
                            <lsb>0</lsb>
                            <msb>3</msb>
                            <access>read-write</access>
                        </field>
                    </fields>
                </register>
                <register>
                    <name>CFDGAFLIGNCTR</name>
                    <description>Global AFL Ignore Control Register</description>
                    <addressOffset>0x00C4</addressOffset>
                    <size>32</size>
                    <access>read-write</access>
                    <resetValue>0x00000000</resetValue>
                    <resetMask>0xffffffff</resetMask>
                    <fields>
                        <field>
                            <name>IREN</name>
                            <description>Ignore Rule Enable</description>
                            <lsb>0</lsb>
                            <msb>0</msb>
                            <access>read-write</access>
                            <enumeratedValues>
                                <enumeratedValue>
                                    <name>0</name>
                                    <description>AFL entry number is not ignored</description>
                                    <value>#0</value>
                                </enumeratedValue>
                                <enumeratedValue>
                                    <name>1</name>
                                    <description>AFL entry number is ignored</description>
                                    <value>#1</value>
                                </enumeratedValue>
                            </enumeratedValues>
                        </field>
                        <field>
                            <name>KEY</name>
                            <description>Key Code</description>
                            <lsb>8</lsb>
                            <msb>15</msb>
                            <access>write-only</access>
                        </field>
                    </fields>
                </register>
                <register>
                    <name>CFDCDTCT</name>
                    <description>DMA Transfer Control Register</description>
                    <addressOffset>0x00C8</addressOffset>
                    <size>32</size>
                    <access>read-write</access>
                    <resetValue>0x00000000</resetValue>
                    <resetMask>0xffffffff</resetMask>
                    <fields>
                        <field>
                            <name>RFDMAE0</name>
                            <description>DMA Transfer Enable for RXFIFO 0</description>
                            <lsb>0</lsb>
                            <msb>0</msb>
                            <access>read-write</access>
                            <enumeratedValues>
                                <enumeratedValue>
                                    <name>0</name>
                                    <description>DMA transfer request disabled</description>
                                    <value>#0</value>
                                </enumeratedValue>
                                <enumeratedValue>
                                    <name>1</name>
                                    <description>DMA transfer request enabled</description>
                                    <value>#1</value>
                                </enumeratedValue>
                            </enumeratedValues>
                        </field>
                        <field>
                            <name>RFDMAE1</name>
                            <description>DMA Transfer Enable for RXFIFO 1</description>
                            <lsb>1</lsb>
                            <msb>1</msb>
                            <access>read-write</access>
                            <enumeratedValues>
                                <enumeratedValue>
                                    <name>0</name>
                                    <description>DMA transfer request disabled</description>
                                    <value>#0</value>
                                </enumeratedValue>
                                <enumeratedValue>
                                    <name>1</name>
                                    <description>DMA transfer request enabled</description>
                                    <value>#1</value>
                                </enumeratedValue>
                            </enumeratedValues>
                        </field>
                        <field>
                            <name>CFDMAE</name>
                            <description>DMA Transfer Enable for Common FIFO 0</description>
                            <lsb>8</lsb>
                            <msb>8</msb>
                            <access>read-write</access>
                            <enumeratedValues>
                                <enumeratedValue>
                                    <name>0</name>
                                    <description>DMA transfer request disabled</description>
                                    <value>#0</value>
                                </enumeratedValue>
                                <enumeratedValue>
                                    <name>1</name>
                                    <description>DMA transfer request enabled</description>
                                    <value>#1</value>
                                </enumeratedValue>
                            </enumeratedValues>
                        </field>
                    </fields>
                </register>
                <register>
                    <name>CFDCDTSTS</name>
                    <description>DMA Transfer Status Register</description>
                    <addressOffset>0x00CC</addressOffset>
                    <size>32</size>
                    <access>read-only</access>
                    <resetValue>0x00000000</resetValue>
                    <resetMask>0xffffffff</resetMask>
                    <fields>
                        <field>
                            <name>RFDMASTS0</name>
                            <description>DMA Transfer Status for RX FIFO 0</description>
                            <lsb>0</lsb>
                            <msb>0</msb>
                            <access>read-only</access>
                            <enumeratedValues>
                                <enumeratedValue>
                                    <name>0</name>
                                    <description>DMA transfer stopped</description>
                                    <value>#0</value>
                                </enumeratedValue>
                                <enumeratedValue>
                                    <name>1</name>
                                    <description>DMA transfer on going</description>
                                    <value>#1</value>
                                </enumeratedValue>
                            </enumeratedValues>
                        </field>
                        <field>
                            <name>RFDMASTS1</name>
                            <description>DMA Transfer Status for RX FIFO 1</description>
                            <lsb>1</lsb>
                            <msb>1</msb>
                            <access>read-only</access>
                            <enumeratedValues>
                                <enumeratedValue>
                                    <name>0</name>
                                    <description>DMA transfer stopped</description>
                                    <value>#0</value>
                                </enumeratedValue>
                                <enumeratedValue>
                                    <name>1</name>
                                    <description>DMA transfer on going</description>
                                    <value>#1</value>
                                </enumeratedValue>
                            </enumeratedValues>
                        </field>
                        <field>
                            <name>CFDMASTS</name>
                            <description>DMA Transfer Status only for Common FIFO</description>
                            <lsb>8</lsb>
                            <msb>8</msb>
                            <access>read-only</access>
                            <enumeratedValues>
                                <enumeratedValue>
                                    <name>0</name>
                                    <description>DMA transfer stopped</description>
                                    <value>#0</value>
                                </enumeratedValue>
                                <enumeratedValue>
                                    <name>1</name>
                                    <description>DMA transfer on going</description>
                                    <value>#1</value>
                                </enumeratedValue>
                            </enumeratedValues>
                        </field>
                    </fields>
                </register>
                <register>
                    <name>CFDGRSTC</name>
                    <description>Global SW reset Register</description>
                    <addressOffset>0x00D8</addressOffset>
                    <size>32</size>
                    <access>read-write</access>
                    <resetValue>0x00000000</resetValue>
                    <resetMask>0xffffffff</resetMask>
                    <fields>
                        <field>
                            <name>SRST</name>
                            <description>SW Reset</description>
                            <lsb>0</lsb>
                            <msb>0</msb>
                            <access>read-write</access>
                            <enumeratedValues>
                                <enumeratedValue>
                                    <name>0</name>
                                    <description>Normal state</description>
                                    <value>#0</value>
                                </enumeratedValue>
                                <enumeratedValue>
                                    <name>1</name>
                                    <description>SW reset state</description>
                                    <value>#1</value>
                                </enumeratedValue>
                            </enumeratedValues>
                        </field>
                        <field>
                            <name>KEY</name>
                            <description>Key Code</description>
                            <lsb>8</lsb>
                            <msb>15</msb>
                            <access>write-only</access>
                        </field>
                    </fields>
                </register>
                <register>
                    <name>CFDC0DCFG</name>
                    <description> Data Bitrate Configuration Register</description>
                    <addressOffset>0x0100</addressOffset>
                    <size>32</size>
                    <access>read-write</access>
                    <resetValue>0x00000000</resetValue>
                    <resetMask>0xffffffff</resetMask>
                    <fields>
                        <field>
                            <name>DBRP</name>
                            <description>Channel Data Baud Rate Prescaler</description>
                            <lsb>0</lsb>
                            <msb>7</msb>
                            <access>read-write</access>
                        </field>
                        <field>
                            <name>DTSEG1</name>
                            <description>Timing Segment 1</description>
                            <lsb>8</lsb>
                            <msb>12</msb>
                            <access>read-write</access>
                        </field>
                        <field>
                            <name>DTSEG2</name>
                            <description>Timing Segment 2</description>
                            <lsb>16</lsb>
                            <msb>19</msb>
                            <access>read-write</access>
                        </field>
                        <field>
                            <name>DSJW</name>
                            <description>Resynchronization Jump Width</description>
                            <lsb>24</lsb>
                            <msb>27</msb>
                            <access>read-write</access>
                        </field>
                    </fields>
                </register>
                <register>
                    <name>CFDC0FDCFG</name>
                    <description>CANFD Configuration Register</description>
                    <addressOffset>0x0104</addressOffset>
                    <size>32</size>
                    <access>read-write</access>
                    <resetValue>0x00000000</resetValue>
                    <resetMask>0xbfffffff</resetMask>
                    <fields>
                        <field>
                            <name>EOCCFG</name>
                            <description>Error Occurrence Counter Configuration</description>
                            <lsb>0</lsb>
                            <msb>2</msb>
                            <access>read-write</access>
                            <enumeratedValues>
                                <enumeratedValue>
                                    <name>000</name>
                                    <description>All transmitter or receiver CAN frames</description>
                                    <value>#000</value>
                                </enumeratedValue>
                                <enumeratedValue>
                                    <name>001</name>
                                    <description>All transmitter CAN frames</description>
                                    <value>#001</value>
                                </enumeratedValue>
                                <enumeratedValue>
                                    <name>010</name>
                                    <description>All receiver CAN frames</description>
                                    <value>#010</value>
                                </enumeratedValue>
                                <enumeratedValue>
                                    <name>011</name>
                                    <description>Reserved</description>
                                    <value>#011</value>
                                </enumeratedValue>
                                <enumeratedValue>
                                    <name>100</name>
                                    <description>Only transmitter or receiver CANFD data-phase (fast bits)</description>
                                    <value>#100</value>
                                </enumeratedValue>
                                <enumeratedValue>
                                    <name>101</name>
                                    <description>Only transmitter CANFD data-phase (fast bits)</description>
                                    <value>#101</value>
                                </enumeratedValue>
                                <enumeratedValue>
                                    <name>110</name>
                                    <description>Only receiver CANFD data-phase (fast bits)</description>
                                    <value>#110</value>
                                </enumeratedValue>
                                <enumeratedValue>
                                    <name>111</name>
                                    <description>Reserved</description>
                                    <value>#111</value>
                                </enumeratedValue>
                            </enumeratedValues>
                        </field>
                        <field>
                            <name>TDCOC</name>
                            <description>Transceiver Delay Compensation Offset Configuration</description>
                            <lsb>8</lsb>
                            <msb>8</msb>
                            <access>read-write</access>
                            <enumeratedValues>
                                <enumeratedValue>
                                    <name>0</name>
                                    <description>Measured + offset</description>
                                    <value>#0</value>
                                </enumeratedValue>
                                <enumeratedValue>
                                    <name>1</name>
                                    <description>Offset-only</description>
                                    <value>#1</value>
                                </enumeratedValue>
                            </enumeratedValues>
                        </field>
                        <field>
                            <name>TDCE</name>
                            <description>Transceiver Delay Compensation Enable</description>
                            <lsb>9</lsb>
                            <msb>9</msb>
                            <access>read-write</access>
                            <enumeratedValues>
                                <enumeratedValue>
                                    <name>0</name>
                                    <description>Transceiver delay compensation disabled</description>
                                    <value>#0</value>
                                </enumeratedValue>
                                <enumeratedValue>
                                    <name>1</name>
                                    <description>Transceiver delay compensation enabled</description>
                                    <value>#1</value>
                                </enumeratedValue>
                            </enumeratedValues>
                        </field>
                        <field>
                            <name>ESIC</name>
                            <description>Error State Indication Configuration</description>
                            <lsb>10</lsb>
                            <msb>10</msb>
                            <access>read-write</access>
                            <enumeratedValues>
                                <enumeratedValue>
                                    <name>0</name>
                                    <description>The ESI bit in the frame represents the error state of the node itself</description>
                                    <value>#0</value>
                                </enumeratedValue>
                                <enumeratedValue>
                                    <name>1</name>
                                    <description>The ESI bit in the frame represents the error state of the message buffer if the node itself is not in error passive. If the node is in error passive, then the ESI bit is driven by the node itself.</description>
                                    <value>#1</value>
                                </enumeratedValue>
                            </enumeratedValues>
                        </field>
                        <field>
                            <name>TDCO</name>
                            <description>Transceiver Delay Compensation Offset</description>
                            <lsb>16</lsb>
                            <msb>23</msb>
                            <access>read-write</access>
                        </field>
                        <field>
                            <name>FDOE</name>
                            <description>FD-Only Enable</description>
                            <lsb>28</lsb>
                            <msb>28</msb>
                            <access>read-write</access>
                            <enumeratedValues>
                                <enumeratedValue>
                                    <name>0</name>
                                    <description>FD-only mode disabled</description>
                                    <value>#0</value>
                                </enumeratedValue>
                                <enumeratedValue>
                                    <name>1</name>
                                    <description>FD-only mode enabled</description>
                                    <value>#1</value>
                                </enumeratedValue>
                            </enumeratedValues>
                        </field>
                        <field>
                            <name>REFE</name>
                            <description>RX Edge Filter Enable</description>
                            <lsb>29</lsb>
                            <msb>29</msb>
                            <access>read-write</access>
                            <enumeratedValues>
                                <enumeratedValue>
                                    <name>0</name>
                                    <description>RX edge filter disabled</description>
                                    <value>#0</value>
                                </enumeratedValue>
                                <enumeratedValue>
                                    <name>1</name>
                                    <description>RX edge filter enabled</description>
                                    <value>#1</value>
                                </enumeratedValue>
                            </enumeratedValues>
                        </field>
                        <field>
                            <name>CLOE</name>
                            <description>Classical CAN Enable</description>
                            <lsb>30</lsb>
                            <msb>30</msb>
                            <access>read-write</access>
                            <enumeratedValues>
                                <enumeratedValue>
                                    <name>0</name>
                                    <description>Classical CAN mode disabled</description>
                                    <value>#0</value>
                                </enumeratedValue>
                                <enumeratedValue>
                                    <name>1</name>
                                    <description>Classical CAN mode enabled</description>
                                    <value>#1</value>
                                </enumeratedValue>
                            </enumeratedValues>
                        </field>
                    </fields>
                </register>
                <register>
                    <name>CFDC0FDCTR</name>
                    <description>CANFD Control Register</description>
                    <addressOffset>0x0108</addressOffset>
                    <size>32</size>
                    <access>read-write</access>
                    <resetValue>0x00000000</resetValue>
                    <resetMask>0xffffffff</resetMask>
                    <fields>
                        <field>
                            <name>EOCCLR</name>
                            <description>Error Occurrence Counter Clear</description>
                            <lsb>0</lsb>
                            <msb>0</msb>
                            <access>read-write</access>
                            <enumeratedValues>
                                <enumeratedValue>
                                    <name>0</name>
                                    <description>No error occurrence counter clear</description>
                                    <value>#0</value>
                                </enumeratedValue>
                                <enumeratedValue>
                                    <name>1</name>
                                    <description>Clear error occurrence counter</description>
                                    <value>#1</value>
                                </enumeratedValue>
                            </enumeratedValues>
                        </field>
                        <field>
                            <name>SOCCLR</name>
                            <description>Successful Occurrence Counter Clear</description>
                            <lsb>1</lsb>
                            <msb>1</msb>
                            <access>read-write</access>
                            <enumeratedValues>
                                <enumeratedValue>
                                    <name>0</name>
                                    <description>No successful occurrence counter clear</description>
                                    <value>#0</value>
                                </enumeratedValue>
                                <enumeratedValue>
                                    <name>1</name>
                                    <description>Clear successful occurrence counter</description>
                                    <value>#1</value>
                                </enumeratedValue>
                            </enumeratedValues>
                        </field>
                    </fields>
                </register>
                <register>
                    <name>CFDC0FDSTS</name>
                    <description>CANFD Status Register</description>
                    <addressOffset>0x010C</addressOffset>
                    <size>32</size>
                    <access>read-write</access>
                    <resetValue>0x00000000</resetValue>
                    <resetMask>0xffffffff</resetMask>
                    <fields>
                        <field>
                            <name>TDCR</name>
                            <description>Transceiver Delay Compensation Result</description>
                            <lsb>0</lsb>
                            <msb>7</msb>
                            <access>read-only</access>
                        </field>
                        <field>
                            <name>EOCO</name>
                            <description>Error Occurrence Counter Overflow</description>
                            <lsb>8</lsb>
                            <msb>8</msb>
                            <access>read-write</access>
                            <enumeratedValues>
                                <enumeratedValue>
                                    <name>0</name>
                                    <description>Error occurrence counter has not overflowed</description>
                                    <value>#0</value>
                                </enumeratedValue>
                                <enumeratedValue>
                                    <name>1</name>
                                    <description>Error occurrence counter has overflowed</description>
                                    <value>#1</value>
                                </enumeratedValue>
                            </enumeratedValues>
                        </field>
                        <field>
                            <name>SOCO</name>
                            <description>Successful Occurrence Counter Overflow</description>
                            <lsb>9</lsb>
                            <msb>9</msb>
                            <access>read-write</access>
                            <enumeratedValues>
                                <enumeratedValue>
                                    <name>0</name>
                                    <description>Successful occurrence counter has not overflowed</description>
                                    <value>#0</value>
                                </enumeratedValue>
                                <enumeratedValue>
                                    <name>1</name>
                                    <description>Successful occurrence counter has overflowed</description>
                                    <value>#1</value>
                                </enumeratedValue>
                            </enumeratedValues>
                        </field>
                        <field>
                            <name>TDCVF</name>
                            <description>Transceiver Delay Compensation Violation Flag</description>
                            <lsb>15</lsb>
                            <msb>15</msb>
                            <access>read-write</access>
                            <enumeratedValues>
                                <enumeratedValue>
                                    <name>0</name>
                                    <description>Transceiver delay compensation violation has not occurred</description>
                                    <value>#0</value>
                                </enumeratedValue>
                                <enumeratedValue>
                                    <name>1</name>
                                    <description>Transceiver delay compensation violation has occurred</description>
                                    <value>#1</value>
                                </enumeratedValue>
                            </enumeratedValues>
                        </field>
                        <field>
                            <name>EOC</name>
                            <description>Error Occurrence Counter</description>
                            <lsb>16</lsb>
                            <msb>23</msb>
                            <access>read-only</access>
                        </field>
                        <field>
                            <name>SOC</name>
                            <description>Successful occurrence counter</description>
                            <lsb>24</lsb>
                            <msb>31</msb>
                            <access>read-only</access>
                        </field>
                    </fields>
                </register>
                <register>
                    <name>CFDC0FDCRC</name>
                    <description>CANFD CRC Register</description>
                    <addressOffset>0x0110</addressOffset>
                    <size>32</size>
                    <access>read-only</access>
                    <resetValue>0x00000000</resetValue>
                    <resetMask>0xffffffff</resetMask>
                    <fields>
                        <field>
                            <name>CRCREG</name>
                            <description>CRC Register value</description>
                            <lsb>0</lsb>
                            <msb>20</msb>
                            <access>read-only</access>
                        </field>
                        <field>
                            <name>SCNT</name>
                            <description>Stuff bit count</description>
                            <lsb>24</lsb>
                            <msb>27</msb>
                            <access>read-only</access>
                        </field>
                    </fields>
                </register>
                <register>
                    <dim>16</dim>
                    <dimIncrement>0x0010</dimIncrement>
                    <dimIndex>1-16</dimIndex>
                    <name>CFDGAFLID%s</name>
                    <description>Global Acceptance Filter List ID Registers</description>
                    <addressOffset>0x0120</addressOffset>
                    <size>32</size>
                    <access>read-write</access>
                    <resetValue>0x00000000</resetValue>
                    <resetMask>0xffffffff</resetMask>
                    <fields>
                        <field>
                            <name>GAFLID</name>
                            <description>Global Acceptance Filter List Entry ID Field</description>
                            <lsb>0</lsb>
                            <msb>28</msb>
                            <access>read-write</access>
                        </field>
                        <field>
                            <name>GAFLLB</name>
                            <description>Global Acceptance Filter List Entry Loopback Configuration</description>
                            <lsb>29</lsb>
                            <msb>29</msb>
                            <access>read-write</access>
                            <enumeratedValues>
                                <enumeratedValue>
                                    <name>0</name>
                                    <description>Global Acceptance Filter List entry ID for acceptance filtering with attribute RX</description>
                                    <value>#0</value>
                                </enumeratedValue>
                                <enumeratedValue>
                                    <name>1</name>
                                    <description>Global Acceptance Filter List entry ID for acceptance filtering with attribute TX</description>
                                    <value>#1</value>
                                </enumeratedValue>
                            </enumeratedValues>
                        </field>
                        <field>
                            <name>GAFLRTR</name>
                            <description>Global Acceptance Filter List Entry RTR Field</description>
                            <lsb>30</lsb>
                            <msb>30</msb>
                            <access>read-write</access>
                            <enumeratedValues>
                                <enumeratedValue>
                                    <name>0</name>
                                    <description>Data frame</description>
                                    <value>#0</value>
                                </enumeratedValue>
                                <enumeratedValue>
                                    <name>1</name>
                                    <description>Remote frame</description>
                                    <value>#1</value>
                                </enumeratedValue>
                            </enumeratedValues>
                        </field>
                        <field>
                            <name>GAFLIDE</name>
                            <description>Global Acceptance Filter List Entry IDE Field</description>
                            <lsb>31</lsb>
                            <msb>31</msb>
                            <access>read-write</access>
                            <enumeratedValues>
                                <enumeratedValue>
                                    <name>0</name>
                                    <description>Standard identifier of rule entry ID is valid for acceptance filtering</description>
                                    <value>#0</value>
                                </enumeratedValue>
                                <enumeratedValue>
                                    <name>1</name>
                                    <description>Extended identifier of rule entry ID is valid for acceptance filtering</description>
                                    <value>#1</value>
                                </enumeratedValue>
                            </enumeratedValues>
                        </field>
                    </fields>
                </register>
                <register>
                    <dim>16</dim>
                    <dimIncrement>0x0010</dimIncrement>
                    <dimIndex>1-16</dimIndex>
                    <name>CFDGAFLM%s</name>
                    <description>Global Acceptance Filter List Mask Registers</description>
                    <addressOffset>0x0124</addressOffset>
                    <size>32</size>
                    <access>read-write</access>
                    <resetValue>0x00000000</resetValue>
                    <resetMask>0xffffffff</resetMask>
                    <fields>
                        <field>
                            <name>GAFLIDM</name>
                            <description>Global Acceptance Filter List ID Mask Field</description>
                            <lsb>0</lsb>
                            <msb>28</msb>
                            <access>read-write</access>
                        </field>
                        <field>
                            <name>GAFLIFL1</name>
                            <description>Global Acceptance Filter List Information Label 1</description>
                            <lsb>29</lsb>
                            <msb>29</msb>
                            <access>read-write</access>
                        </field>
                        <field>
                            <name>GAFLRTRM</name>
                            <description>Global Acceptance Filter List Entry RTR Mask</description>
                            <lsb>30</lsb>
                            <msb>30</msb>
                            <access>read-write</access>
                            <enumeratedValues>
                                <enumeratedValue>
                                    <name>0</name>
                                    <description>RTR bit is not used for ID matching</description>
                                    <value>#0</value>
                                </enumeratedValue>
                                <enumeratedValue>
                                    <name>1</name>
                                    <description>RTR bit is used for ID matching</description>
                                    <value>#1</value>
                                </enumeratedValue>
                            </enumeratedValues>
                        </field>
                        <field>
                            <name>GAFLIDEM</name>
                            <description>Global Acceptance Filter List IDE Mask</description>
                            <lsb>31</lsb>
                            <msb>31</msb>
                            <access>read-write</access>
                            <enumeratedValues>
                                <enumeratedValue>
                                    <name>0</name>
                                    <description>IDE bit is not used for ID matching</description>
                                    <value>#0</value>
                                </enumeratedValue>
                                <enumeratedValue>
                                    <name>1</name>
                                    <description>IDE bit is used for ID matching</description>
                                    <value>#1</value>
                                </enumeratedValue>
                            </enumeratedValues>
                        </field>
                    </fields>
                </register>
                <register>
                    <dim>16</dim>
                    <dimIncrement>0x0010</dimIncrement>
                    <dimIndex>1-16</dimIndex>
                    <name>CFDGAFLP0%s</name>
                    <description>Global Acceptance Filter List Pointer 0 Registers</description>
                    <addressOffset>0x0128</addressOffset>
                    <size>32</size>
                    <access>read-write</access>
                    <resetValue>0x00000000</resetValue>
                    <resetMask>0xffffffff</resetMask>
                    <fields>
                        <field>
                            <name>GAFLDLC</name>
                            <description>Global Acceptance Filter List DLC Field</description>
                            <lsb>0</lsb>
                            <msb>3</msb>
                            <access>read-write</access>
                        </field>
                        <field>
                            <name>GAFLIFL0</name>
                            <description>Global Acceptance Filter List Information Label 0</description>
                            <lsb>7</lsb>
                            <msb>7</msb>
                            <access>read-write</access>
                        </field>
                        <field>
                            <name>GAFLRMDP</name>
                            <description>Global Acceptance Filter List RX Message Buffer Direction Pointer</description>
                            <lsb>8</lsb>
                            <msb>12</msb>
                            <access>read-write</access>
                        </field>
                        <field>
                            <name>GAFLRMV</name>
                            <description>Global Acceptance Filter List RX Message Buffer Valid</description>
                            <lsb>15</lsb>
                            <msb>15</msb>
                            <access>read-write</access>
                            <enumeratedValues>
                                <enumeratedValue>
                                    <name>0</name>
                                    <description>Single message buffer direction pointer is invalid</description>
                                    <value>#0</value>
                                </enumeratedValue>
                                <enumeratedValue>
                                    <name>1</name>
                                    <description>Single message buffer direction pointer is valid</description>
                                    <value>#1</value>
                                </enumeratedValue>
                            </enumeratedValues>
                        </field>
                        <field>
                            <name>GAFLPTR</name>
                            <description>Global Acceptance Filter List Pointer</description>
                            <lsb>16</lsb>
                            <msb>31</msb>
                            <access>read-write</access>
                        </field>
                    </fields>
                </register>
                <register>
                    <dim>16</dim>
                    <dimIncrement>0x0010</dimIncrement>
                    <dimIndex>1-16</dimIndex>
                    <name>CFDGAFLP1%s</name>
                    <description>Global Acceptance Filter List Pointer 1 Registers</description>
                    <addressOffset>0x012C</addressOffset>
                    <size>32</size>
                    <access>read-write</access>
                    <resetValue>0x00000000</resetValue>
                    <resetMask>0xffffffff</resetMask>
                    <fields>
                        <field>
                            <name>GAFLFDP0</name>
                            <description>Global Acceptance Filter List FIFO Direction Pointer</description>
                            <lsb>0</lsb>
                            <msb>0</msb>
                            <access>read-write</access>
                            <enumeratedValues>
                                <enumeratedValue>
                                    <name>0</name>
                                    <description>Disable RX FIFO 0 as target for reception</description>
                                    <value>#0</value>
                                </enumeratedValue>
                                <enumeratedValue>
                                    <name>1</name>
                                    <description>Enable RX FIFO 0 as target for reception</description>
                                    <value>#1</value>
                                </enumeratedValue>
                            </enumeratedValues>
                        </field>
                        <field>
                            <name>GAFLFDP1</name>
                            <description>Global Acceptance Filter List FIFO Direction Pointer</description>
                            <lsb>1</lsb>
                            <msb>1</msb>
                            <access>read-write</access>
                            <enumeratedValues>
                                <enumeratedValue>
                                    <name>0</name>
                                    <description>Disable RX FIFO 1 as target for reception</description>
                                    <value>#0</value>
                                </enumeratedValue>
                                <enumeratedValue>
                                    <name>1</name>
                                    <description>Enable RX FIFO 1 as target for reception</description>
                                    <value>#1</value>
                                </enumeratedValue>
                            </enumeratedValues>
                        </field>
                        <field>
                            <name>GAFLFDP8</name>
                            <description>Global Acceptance Filter List FIFO Direction Pointer</description>
                            <lsb>8</lsb>
                            <msb>8</msb>
                            <access>read-write</access>
                            <enumeratedValues>
                                <enumeratedValue>
                                    <name>0</name>
                                    <description>Disable Common FIFO as target for reception</description>
                                    <value>#0</value>
                                </enumeratedValue>
                                <enumeratedValue>
                                    <name>1</name>
                                    <description>Enable Common FIFO as target for reception</description>
                                    <value>#1</value>
                                </enumeratedValue>
                            </enumeratedValues>
                        </field>
                    </fields>
                </register>
                <register>
                    <dim>64</dim>
                    <dimIncrement>0x0004</dimIncrement>
                    <dimIndex>0-63</dimIndex>
                    <name>CFDRPGACC%s</name>
                    <description>RAM Test Page Access Registers %s</description>
                    <addressOffset>0x0280</addressOffset>
                    <size>32</size>
                    <access>read-write</access>
                    <resetValue>0x00000000</resetValue>
                    <resetMask>0xffffffff</resetMask>
                    <fields>
                        <field>
                            <name>RDTA</name>
                            <description>RAM Data Test Access</description>
                            <lsb>0</lsb>
                            <msb>31</msb>
                            <access>read-write</access>
                        </field>
                    </fields>
                </register>
                <register>
                    <dim>2</dim>
                    <dimIncrement>0x004C</dimIncrement>
                    <dimIndex>0-1</dimIndex>
                    <name>CFDRFID%s</name>
                    <description>RX FIFO Access ID Register %s</description>
                    <addressOffset>0x0520</addressOffset>
                    <size>32</size>
                    <access>read-only</access>
                    <resetValue>0x00000000</resetValue>
                    <resetMask>0xffffffff</resetMask>
                    <fields>
                        <field>
                            <name>RFID</name>
                            <description>RX FIFO Buffer ID Field</description>
                            <lsb>0</lsb>
                            <msb>28</msb>
                            <access>read-only</access>
                        </field>
                        <field>
                            <name>RFRTR</name>
                            <description>RX FIFO Buffer RTR bit</description>
                            <lsb>30</lsb>
                            <msb>30</msb>
                            <access>read-only</access>
                            <enumeratedValues>
                                <enumeratedValue>
                                    <name>0</name>
                                    <description>Data frame</description>
                                    <value>#0</value>
                                </enumeratedValue>
                                <enumeratedValue>
                                    <name>1</name>
                                    <description>Remote frame</description>
                                    <value>#1</value>
                                </enumeratedValue>
                            </enumeratedValues>
                        </field>
                        <field>
                            <name>RFIDE</name>
                            <description>RX FIFO Buffer IDE bit</description>
                            <lsb>31</lsb>
                            <msb>31</msb>
                            <access>read-only</access>
                            <enumeratedValues>
                                <enumeratedValue>
                                    <name>0</name>
                                    <description>STD-ID has been received</description>
                                    <value>#0</value>
                                </enumeratedValue>
                                <enumeratedValue>
                                    <name>1</name>
                                    <description>EXT-ID has been received</description>
                                    <value>#1</value>
                                </enumeratedValue>
                            </enumeratedValues>
                        </field>
                    </fields>
                </register>
                <register>
                    <dim>2</dim>
                    <dimIncrement>0x004C</dimIncrement>
                    <dimIndex>0-1</dimIndex>
                    <name>CFDRFPTR%s</name>
                    <description>RX FIFO Access Pointer Register %s</description>
                    <addressOffset>0x0524</addressOffset>
                    <size>32</size>
                    <access>read-only</access>
                    <resetValue>0x00000000</resetValue>
                    <resetMask>0xffffffff</resetMask>
                    <fields>
                        <field>
                            <name>RFTS</name>
                            <description>RX FIFO Timestamp Value</description>
                            <lsb>0</lsb>
                            <msb>15</msb>
                            <access>read-only</access>
                        </field>
                        <field>
                            <name>RFDLC</name>
                            <description>RX FIFO Buffer DLC Field</description>
                            <lsb>28</lsb>
                            <msb>31</msb>
                            <access>read-only</access>
                        </field>
                    </fields>
                </register>
                <register>
                    <dim>2</dim>
                    <dimIncrement>0x004C</dimIncrement>
                    <dimIndex>0-1</dimIndex>
                    <name>CFDRFFDSTS%s</name>
                    <description>RX FIFO Access CANFD Status Register %s</description>
                    <addressOffset>0x0528</addressOffset>
                    <size>32</size>
                    <access>read-only</access>
                    <resetValue>0x00000000</resetValue>
                    <resetMask>0xffffffff</resetMask>
                    <fields>
                        <field>
                            <name>RFESI</name>
                            <description>Error State Indicator bit</description>
                            <lsb>0</lsb>
                            <msb>0</msb>
                            <access>read-only</access>
                            <enumeratedValues>
                                <enumeratedValue>
                                    <name>0</name>
                                    <description>CANFD frame received from error active node</description>
                                    <value>#0</value>
                                </enumeratedValue>
                                <enumeratedValue>
                                    <name>1</name>
                                    <description>CANFD frame received from error passive node</description>
                                    <value>#1</value>
                                </enumeratedValue>
                            </enumeratedValues>
                        </field>
                        <field>
                            <name>RFBRS</name>
                            <description>Bit Rate Switch bit</description>
                            <lsb>1</lsb>
                            <msb>1</msb>
                            <access>read-only</access>
                            <enumeratedValues>
                                <enumeratedValue>
                                    <name>0</name>
                                    <description>CANFD frame received with no bit rate switch</description>
                                    <value>#0</value>
                                </enumeratedValue>
                                <enumeratedValue>
                                    <name>1</name>
                                    <description>CANFD frame received with bit rate switch</description>
                                    <value>#1</value>
                                </enumeratedValue>
                            </enumeratedValues>
                        </field>
                        <field>
                            <name>RFFDF</name>
                            <description>CAN FD Format bit</description>
                            <lsb>2</lsb>
                            <msb>2</msb>
                            <access>read-only</access>
                            <enumeratedValues>
                                <enumeratedValue>
                                    <name>0</name>
                                    <description>Non CANFD frame received</description>
                                    <value>#0</value>
                                </enumeratedValue>
                                <enumeratedValue>
                                    <name>1</name>
                                    <description>CANFD frame received</description>
                                    <value>#1</value>
                                </enumeratedValue>
                            </enumeratedValues>
                        </field>
                        <field>
                            <name>RFIFL</name>
                            <description>RX FIFO Buffer Information Label Field</description>
                            <lsb>8</lsb>
                            <msb>9</msb>
                            <access>read-only</access>
                        </field>
                        <field>
                            <name>CFDRFPTR</name>
                            <description>RX FIFO Buffer Pointer Field</description>
                            <lsb>16</lsb>
                            <msb>31</msb>
                            <access>read-only</access>
                        </field>
                    </fields>
                </register>
                <register>
                    <dim>2</dim>
                    <dimIncrement>0x04C</dimIncrement>
                    <dimIndex>0-1</dimIndex>
                    <name>CFDRFDF%s_0</name>
                    <description>RX FIFO Access Data Field 0 Register %s</description>
                    <addressOffset>0x052C</addressOffset>
                    <size>32</size>
                    <access>read-only</access>
                    <resetValue>0x00000000</resetValue>
                    <resetMask>0xffffffff</resetMask>
                    <fields>
                        <field>
                            <name>RFDB_LL</name>
                            <description>RX FIFO Buffer Data Byte (p × 4)</description>
                            <lsb>0</lsb>
                            <msb>7</msb>
                            <access>read-only</access>
                        </field>
                        <field>
                            <name>RFDB_LH</name>
                            <description>RX FIFO Buffer Data Byte ((p × 4) + 1)</description>
                            <lsb>8</lsb>
                            <msb>15</msb>
                            <access>read-only</access>
                        </field>
                        <field>
                            <name>RFDB_HL</name>
                            <description>RX FIFO Buffer Data Byte ((p × 4) + 2)</description>
                            <lsb>16</lsb>
                            <msb>23</msb>
                            <access>read-only</access>
                        </field>
                        <field>
                            <name>RFDB_HH</name>
                            <description>RX FIFO Buffer Data Byte ((p × 4) + 3)</description>
                            <lsb>24</lsb>
                            <msb>31</msb>
                            <access>read-only</access>
                        </field>
                    </fields>
                </register>
                <register>
                    <dim>2</dim>
                    <dimIncrement>0x04C</dimIncrement>
                    <dimIndex>0-1</dimIndex>
                    <name>CFDRFDF%s_1</name>
                    <description>RX FIFO Access Data Field 1 Register %s</description>
                    <addressOffset>0x0530</addressOffset>
                    <size>32</size>
                    <access>read-only</access>
                    <resetValue>0x00000000</resetValue>
                    <resetMask>0xffffffff</resetMask>
                    <fields>
                        <field>
                            <name>RFDB_LL</name>
                            <description>RX FIFO Buffer Data Byte (p × 4)</description>
                            <lsb>0</lsb>
                            <msb>7</msb>
                            <access>read-only</access>
                        </field>
                        <field>
                            <name>RFDB_LH</name>
                            <description>RX FIFO Buffer Data Byte ((p × 4) + 1)</description>
                            <lsb>8</lsb>
                            <msb>15</msb>
                            <access>read-only</access>
                        </field>
                        <field>
                            <name>RFDB_HL</name>
                            <description>RX FIFO Buffer Data Byte ((p × 4) + 2)</description>
                            <lsb>16</lsb>
                            <msb>23</msb>
                            <access>read-only</access>
                        </field>
                        <field>
                            <name>RFDB_HH</name>
                            <description>RX FIFO Buffer Data Byte ((p × 4) + 3)</description>
                            <lsb>24</lsb>
                            <msb>31</msb>
                            <access>read-only</access>
                        </field>
                    </fields>
                </register>
                <register>
                    <dim>2</dim>
                    <dimIncrement>0x04C</dimIncrement>
                    <dimIndex>0-1</dimIndex>
                    <name>CFDRFDF%s_2</name>
                    <description>RX FIFO Access Data Field 2 Register %s</description>
                    <addressOffset>0x0534</addressOffset>
                    <size>32</size>
                    <access>read-only</access>
                    <resetValue>0x00000000</resetValue>
                    <resetMask>0xffffffff</resetMask>
                    <fields>
                        <field>
                            <name>RFDB_LL</name>
                            <description>RX FIFO Buffer Data Byte (p × 4)</description>
                            <lsb>0</lsb>
                            <msb>7</msb>
                            <access>read-only</access>
                        </field>
                        <field>
                            <name>RFDB_LH</name>
                            <description>RX FIFO Buffer Data Byte ((p × 4) + 1)</description>
                            <lsb>8</lsb>
                            <msb>15</msb>
                            <access>read-only</access>
                        </field>
                        <field>
                            <name>RFDB_HL</name>
                            <description>RX FIFO Buffer Data Byte ((p × 4) + 2)</description>
                            <lsb>16</lsb>
                            <msb>23</msb>
                            <access>read-only</access>
                        </field>
                        <field>
                            <name>RFDB_HH</name>
                            <description>RX FIFO Buffer Data Byte ((p × 4) + 3)</description>
                            <lsb>24</lsb>
                            <msb>31</msb>
                            <access>read-only</access>
                        </field>
                    </fields>
                </register>
                <register>
                    <dim>2</dim>
                    <dimIncrement>0x04C</dimIncrement>
                    <dimIndex>0-1</dimIndex>
                    <name>CFDRFDF%s_3</name>
                    <description>RX FIFO Access Data Field 3 Register %s</description>
                    <addressOffset>0x0538</addressOffset>
                    <size>32</size>
                    <access>read-only</access>
                    <resetValue>0x00000000</resetValue>
                    <resetMask>0xffffffff</resetMask>
                    <fields>
                        <field>
                            <name>RFDB_LL</name>
                            <description>RX FIFO Buffer Data Byte (p × 4)</description>
                            <lsb>0</lsb>
                            <msb>7</msb>
                            <access>read-only</access>
                        </field>
                        <field>
                            <name>RFDB_LH</name>
                            <description>RX FIFO Buffer Data Byte ((p × 4) + 1)</description>
                            <lsb>8</lsb>
                            <msb>15</msb>
                            <access>read-only</access>
                        </field>
                        <field>
                            <name>RFDB_HL</name>
                            <description>RX FIFO Buffer Data Byte ((p × 4) + 2)</description>
                            <lsb>16</lsb>
                            <msb>23</msb>
                            <access>read-only</access>
                        </field>
                        <field>
                            <name>RFDB_HH</name>
                            <description>RX FIFO Buffer Data Byte ((p × 4) + 3)</description>
                            <lsb>24</lsb>
                            <msb>31</msb>
                            <access>read-only</access>
                        </field>
                    </fields>
                </register>
                <register>
                    <dim>2</dim>
                    <dimIncrement>0x04C</dimIncrement>
                    <dimIndex>0-1</dimIndex>
                    <name>CFDRFDF%s_4</name>
                    <description>RX FIFO Access Data Field 4 Register %s</description>
                    <addressOffset>0x053C</addressOffset>
                    <size>32</size>
                    <access>read-only</access>
                    <resetValue>0x00000000</resetValue>
                    <resetMask>0xffffffff</resetMask>
                    <fields>
                        <field>
                            <name>RFDB_LL</name>
                            <description>RX FIFO Buffer Data Byte (p × 4)</description>
                            <lsb>0</lsb>
                            <msb>7</msb>
                            <access>read-only</access>
                        </field>
                        <field>
                            <name>RFDB_LH</name>
                            <description>RX FIFO Buffer Data Byte ((p × 4) + 1)</description>
                            <lsb>8</lsb>
                            <msb>15</msb>
                            <access>read-only</access>
                        </field>
                        <field>
                            <name>RFDB_HL</name>
                            <description>RX FIFO Buffer Data Byte ((p × 4) + 2)</description>
                            <lsb>16</lsb>
                            <msb>23</msb>
                            <access>read-only</access>
                        </field>
                        <field>
                            <name>RFDB_HH</name>
                            <description>RX FIFO Buffer Data Byte ((p × 4) + 3)</description>
                            <lsb>24</lsb>
                            <msb>31</msb>
                            <access>read-only</access>
                        </field>
                    </fields>
                </register>
                <register>
                    <dim>2</dim>
                    <dimIncrement>0x04C</dimIncrement>
                    <dimIndex>0-1</dimIndex>
                    <name>CFDRFDF%s_5</name>
                    <description>RX FIFO Access Data Field 5 Register %s</description>
                    <addressOffset>0x0540</addressOffset>
                    <size>32</size>
                    <access>read-only</access>
                    <resetValue>0x00000000</resetValue>
                    <resetMask>0xffffffff</resetMask>
                    <fields>
                        <field>
                            <name>RFDB_LL</name>
                            <description>RX FIFO Buffer Data Byte (p × 4)</description>
                            <lsb>0</lsb>
                            <msb>7</msb>
                            <access>read-only</access>
                        </field>
                        <field>
                            <name>RFDB_LH</name>
                            <description>RX FIFO Buffer Data Byte ((p × 4) + 1)</description>
                            <lsb>8</lsb>
                            <msb>15</msb>
                            <access>read-only</access>
                        </field>
                        <field>
                            <name>RFDB_HL</name>
                            <description>RX FIFO Buffer Data Byte ((p × 4) + 2)</description>
                            <lsb>16</lsb>
                            <msb>23</msb>
                            <access>read-only</access>
                        </field>
                        <field>
                            <name>RFDB_HH</name>
                            <description>RX FIFO Buffer Data Byte ((p × 4) + 3)</description>
                            <lsb>24</lsb>
                            <msb>31</msb>
                            <access>read-only</access>
                        </field>
                    </fields>
                </register>
                <register>
                    <dim>2</dim>
                    <dimIncrement>0x04C</dimIncrement>
                    <dimIndex>0-1</dimIndex>
                    <name>CFDRFDF%s_6</name>
                    <description>RX FIFO Access Data Field 6 Register %s</description>
                    <addressOffset>0x0544</addressOffset>
                    <size>32</size>
                    <access>read-only</access>
                    <resetValue>0x00000000</resetValue>
                    <resetMask>0xffffffff</resetMask>
                    <fields>
                        <field>
                            <name>RFDB_LL</name>
                            <description>RX FIFO Buffer Data Byte (p × 4)</description>
                            <lsb>0</lsb>
                            <msb>7</msb>
                            <access>read-only</access>
                        </field>
                        <field>
                            <name>RFDB_LH</name>
                            <description>RX FIFO Buffer Data Byte ((p × 4) + 1)</description>
                            <lsb>8</lsb>
                            <msb>15</msb>
                            <access>read-only</access>
                        </field>
                        <field>
                            <name>RFDB_HL</name>
                            <description>RX FIFO Buffer Data Byte ((p × 4) + 2)</description>
                            <lsb>16</lsb>
                            <msb>23</msb>
                            <access>read-only</access>
                        </field>
                        <field>
                            <name>RFDB_HH</name>
                            <description>RX FIFO Buffer Data Byte ((p × 4) + 3)</description>
                            <lsb>24</lsb>
                            <msb>31</msb>
                            <access>read-only</access>
                        </field>
                    </fields>
                </register>
                <register>
                    <dim>2</dim>
                    <dimIncrement>0x04C</dimIncrement>
                    <dimIndex>0-1</dimIndex>
                    <name>CFDRFDF%s_7</name>
                    <description>RX FIFO Access Data Field 7 Register %s</description>
                    <addressOffset>0x0548</addressOffset>
                    <size>32</size>
                    <access>read-only</access>
                    <resetValue>0x00000000</resetValue>
                    <resetMask>0xffffffff</resetMask>
                    <fields>
                        <field>
                            <name>RFDB_LL</name>
                            <description>RX FIFO Buffer Data Byte (p × 4)</description>
                            <lsb>0</lsb>
                            <msb>7</msb>
                            <access>read-only</access>
                        </field>
                        <field>
                            <name>RFDB_LH</name>
                            <description>RX FIFO Buffer Data Byte ((p × 4) + 1)</description>
                            <lsb>8</lsb>
                            <msb>15</msb>
                            <access>read-only</access>
                        </field>
                        <field>
                            <name>RFDB_HL</name>
                            <description>RX FIFO Buffer Data Byte ((p × 4) + 2)</description>
                            <lsb>16</lsb>
                            <msb>23</msb>
                            <access>read-only</access>
                        </field>
                        <field>
                            <name>RFDB_HH</name>
                            <description>RX FIFO Buffer Data Byte ((p × 4) + 3)</description>
                            <lsb>24</lsb>
                            <msb>31</msb>
                            <access>read-only</access>
                        </field>
                    </fields>
                </register>
                <register>
                    <dim>2</dim>
                    <dimIncrement>0x04C</dimIncrement>
                    <dimIndex>0-1</dimIndex>
                    <name>CFDRFDF%s_8</name>
                    <description>RX FIFO Access Data Field 8 Register %s</description>
                    <addressOffset>0x054C</addressOffset>
                    <size>32</size>
                    <access>read-only</access>
                    <resetValue>0x00000000</resetValue>
                    <resetMask>0xffffffff</resetMask>
                    <fields>
                        <field>
                            <name>RFDB_LL</name>
                            <description>RX FIFO Buffer Data Byte (p × 4)</description>
                            <lsb>0</lsb>
                            <msb>7</msb>
                            <access>read-only</access>
                        </field>
                        <field>
                            <name>RFDB_LH</name>
                            <description>RX FIFO Buffer Data Byte ((p × 4) + 1)</description>
                            <lsb>8</lsb>
                            <msb>15</msb>
                            <access>read-only</access>
                        </field>
                        <field>
                            <name>RFDB_HL</name>
                            <description>RX FIFO Buffer Data Byte ((p × 4) + 2)</description>
                            <lsb>16</lsb>
                            <msb>23</msb>
                            <access>read-only</access>
                        </field>
                        <field>
                            <name>RFDB_HH</name>
                            <description>RX FIFO Buffer Data Byte ((p × 4) + 3)</description>
                            <lsb>24</lsb>
                            <msb>31</msb>
                            <access>read-only</access>
                        </field>
                    </fields>
                </register>
                <register>
                    <dim>2</dim>
                    <dimIncrement>0x04C</dimIncrement>
                    <dimIndex>0-1</dimIndex>
                    <name>CFDRFDF%s_9</name>
                    <description>RX FIFO Access Data Field 9 Register %s</description>
                    <addressOffset>0x0550</addressOffset>
                    <size>32</size>
                    <access>read-only</access>
                    <resetValue>0x00000000</resetValue>
                    <resetMask>0xffffffff</resetMask>
                    <fields>
                        <field>
                            <name>RFDB_LL</name>
                            <description>RX FIFO Buffer Data Byte (p × 4)</description>
                            <lsb>0</lsb>
                            <msb>7</msb>
                            <access>read-only</access>
                        </field>
                        <field>
                            <name>RFDB_LH</name>
                            <description>RX FIFO Buffer Data Byte ((p × 4) + 1)</description>
                            <lsb>8</lsb>
                            <msb>15</msb>
                            <access>read-only</access>
                        </field>
                        <field>
                            <name>RFDB_HL</name>
                            <description>RX FIFO Buffer Data Byte ((p × 4) + 2)</description>
                            <lsb>16</lsb>
                            <msb>23</msb>
                            <access>read-only</access>
                        </field>
                        <field>
                            <name>RFDB_HH</name>
                            <description>RX FIFO Buffer Data Byte ((p × 4) + 3)</description>
                            <lsb>24</lsb>
                            <msb>31</msb>
                            <access>read-only</access>
                        </field>
                    </fields>
                </register>
                <register>
                    <dim>2</dim>
                    <dimIncrement>0x04C</dimIncrement>
                    <dimIndex>0-1</dimIndex>
                    <name>CFDRFDF%s_10</name>
                    <description>RX FIFO Access Data Field 10 Register %s</description>
                    <addressOffset>0x0554</addressOffset>
                    <size>32</size>
                    <access>read-only</access>
                    <resetValue>0x00000000</resetValue>
                    <resetMask>0xffffffff</resetMask>
                    <fields>
                        <field>
                            <name>RFDB_LL</name>
                            <description>RX FIFO Buffer Data Byte (p × 4)</description>
                            <lsb>0</lsb>
                            <msb>7</msb>
                            <access>read-only</access>
                        </field>
                        <field>
                            <name>RFDB_LH</name>
                            <description>RX FIFO Buffer Data Byte ((p × 4) + 1)</description>
                            <lsb>8</lsb>
                            <msb>15</msb>
                            <access>read-only</access>
                        </field>
                        <field>
                            <name>RFDB_HL</name>
                            <description>RX FIFO Buffer Data Byte ((p × 4) + 2)</description>
                            <lsb>16</lsb>
                            <msb>23</msb>
                            <access>read-only</access>
                        </field>
                        <field>
                            <name>RFDB_HH</name>
                            <description>RX FIFO Buffer Data Byte ((p × 4) + 3)</description>
                            <lsb>24</lsb>
                            <msb>31</msb>
                            <access>read-only</access>
                        </field>
                    </fields>
                </register>
                <register>
                    <dim>2</dim>
                    <dimIncrement>0x04C</dimIncrement>
                    <dimIndex>0-1</dimIndex>
                    <name>CFDRFDF%s_11</name>
                    <description>RX FIFO Access Data Field 11 Register %s</description>
                    <addressOffset>0x0558</addressOffset>
                    <size>32</size>
                    <access>read-only</access>
                    <resetValue>0x00000000</resetValue>
                    <resetMask>0xffffffff</resetMask>
                    <fields>
                        <field>
                            <name>RFDB_LL</name>
                            <description>RX FIFO Buffer Data Byte (p × 4)</description>
                            <lsb>0</lsb>
                            <msb>7</msb>
                            <access>read-only</access>
                        </field>
                        <field>
                            <name>RFDB_LH</name>
                            <description>RX FIFO Buffer Data Byte ((p × 4) + 1)</description>
                            <lsb>8</lsb>
                            <msb>15</msb>
                            <access>read-only</access>
                        </field>
                        <field>
                            <name>RFDB_HL</name>
                            <description>RX FIFO Buffer Data Byte ((p × 4) + 2)</description>
                            <lsb>16</lsb>
                            <msb>23</msb>
                            <access>read-only</access>
                        </field>
                        <field>
                            <name>RFDB_HH</name>
                            <description>RX FIFO Buffer Data Byte ((p × 4) + 3)</description>
                            <lsb>24</lsb>
                            <msb>31</msb>
                            <access>read-only</access>
                        </field>
                    </fields>
                </register>
                <register>
                    <dim>2</dim>
                    <dimIncrement>0x04C</dimIncrement>
                    <dimIndex>0-1</dimIndex>
                    <name>CFDRFDF%s_12</name>
                    <description>RX FIFO Access Data Field 12 Register %s</description>
                    <addressOffset>0x055C</addressOffset>
                    <size>32</size>
                    <access>read-only</access>
                    <resetValue>0x00000000</resetValue>
                    <resetMask>0xffffffff</resetMask>
                    <fields>
                        <field>
                            <name>RFDB_LL</name>
                            <description>RX FIFO Buffer Data Byte (p × 4)</description>
                            <lsb>0</lsb>
                            <msb>7</msb>
                            <access>read-only</access>
                        </field>
                        <field>
                            <name>RFDB_LH</name>
                            <description>RX FIFO Buffer Data Byte ((p × 4) + 1)</description>
                            <lsb>8</lsb>
                            <msb>15</msb>
                            <access>read-only</access>
                        </field>
                        <field>
                            <name>RFDB_HL</name>
                            <description>RX FIFO Buffer Data Byte ((p × 4) + 2)</description>
                            <lsb>16</lsb>
                            <msb>23</msb>
                            <access>read-only</access>
                        </field>
                        <field>
                            <name>RFDB_HH</name>
                            <description>RX FIFO Buffer Data Byte ((p × 4) + 3)</description>
                            <lsb>24</lsb>
                            <msb>31</msb>
                            <access>read-only</access>
                        </field>
                    </fields>
                </register>
                <register>
                    <dim>2</dim>
                    <dimIncrement>0x04C</dimIncrement>
                    <dimIndex>0-1</dimIndex>
                    <name>CFDRFDF%s_13</name>
                    <description>RX FIFO Access Data Field 13 Register %s</description>
                    <addressOffset>0x0560</addressOffset>
                    <size>32</size>
                    <access>read-only</access>
                    <resetValue>0x00000000</resetValue>
                    <resetMask>0xffffffff</resetMask>
                    <fields>
                        <field>
                            <name>RFDB_LL</name>
                            <description>RX FIFO Buffer Data Byte (p × 4)</description>
                            <lsb>0</lsb>
                            <msb>7</msb>
                            <access>read-only</access>
                        </field>
                        <field>
                            <name>RFDB_LH</name>
                            <description>RX FIFO Buffer Data Byte ((p × 4) + 1)</description>
                            <lsb>8</lsb>
                            <msb>15</msb>
                            <access>read-only</access>
                        </field>
                        <field>
                            <name>RFDB_HL</name>
                            <description>RX FIFO Buffer Data Byte ((p × 4) + 2)</description>
                            <lsb>16</lsb>
                            <msb>23</msb>
                            <access>read-only</access>
                        </field>
                        <field>
                            <name>RFDB_HH</name>
                            <description>RX FIFO Buffer Data Byte ((p × 4) + 3)</description>
                            <lsb>24</lsb>
                            <msb>31</msb>
                            <access>read-only</access>
                        </field>
                    </fields>
                </register>
                <register>
                    <dim>2</dim>
                    <dimIncrement>0x04C</dimIncrement>
                    <dimIndex>0-1</dimIndex>
                    <name>CFDRFDF%s_14</name>
                    <description>RX FIFO Access Data Field 14 Register %s</description>
                    <addressOffset>0x0564</addressOffset>
                    <size>32</size>
                    <access>read-only</access>
                    <resetValue>0x00000000</resetValue>
                    <resetMask>0xffffffff</resetMask>
                    <fields>
                        <field>
                            <name>RFDB_LL</name>
                            <description>RX FIFO Buffer Data Byte (p × 4)</description>
                            <lsb>0</lsb>
                            <msb>7</msb>
                            <access>read-only</access>
                        </field>
                        <field>
                            <name>RFDB_LH</name>
                            <description>RX FIFO Buffer Data Byte ((p × 4) + 1)</description>
                            <lsb>8</lsb>
                            <msb>15</msb>
                            <access>read-only</access>
                        </field>
                        <field>
                            <name>RFDB_HL</name>
                            <description>RX FIFO Buffer Data Byte ((p × 4) + 2)</description>
                            <lsb>16</lsb>
                            <msb>23</msb>
                            <access>read-only</access>
                        </field>
                        <field>
                            <name>RFDB_HH</name>
                            <description>RX FIFO Buffer Data Byte ((p × 4) + 3)</description>
                            <lsb>24</lsb>
                            <msb>31</msb>
                            <access>read-only</access>
                        </field>
                    </fields>
                </register>
                <register>
                    <dim>2</dim>
                    <dimIncrement>0x04C</dimIncrement>
                    <dimIndex>0-1</dimIndex>
                    <name>CFDRFDF%s_15</name>
                    <description>RX FIFO Access Data Field 15 Register %s</description>
                    <addressOffset>0x0568</addressOffset>
                    <size>32</size>
                    <access>read-only</access>
                    <resetValue>0x00000000</resetValue>
                    <resetMask>0xffffffff</resetMask>
                    <fields>
                        <field>
                            <name>RFDB_LL</name>
                            <description>RX FIFO Buffer Data Byte (p × 4)</description>
                            <lsb>0</lsb>
                            <msb>7</msb>
                            <access>read-only</access>
                        </field>
                        <field>
                            <name>RFDB_LH</name>
                            <description>RX FIFO Buffer Data Byte ((p × 4) + 1)</description>
                            <lsb>8</lsb>
                            <msb>15</msb>
                            <access>read-only</access>
                        </field>
                        <field>
                            <name>RFDB_HL</name>
                            <description>RX FIFO Buffer Data Byte ((p × 4) + 2)</description>
                            <lsb>16</lsb>
                            <msb>23</msb>
                            <access>read-only</access>
                        </field>
                        <field>
                            <name>RFDB_HH</name>
                            <description>RX FIFO Buffer Data Byte ((p × 4) + 3)</description>
                            <lsb>24</lsb>
                            <msb>31</msb>
                            <access>read-only</access>
                        </field>
                    </fields>
                </register>
                <register>
                    <name>CFDCFID</name>
                    <description>Common FIFO Access ID Register</description>
                    <addressOffset>0x05B8</addressOffset>
                    <size>32</size>
                    <access>read-write</access>
                    <resetValue>0x00000000</resetValue>
                    <resetMask>0xffffffff</resetMask>
                    <fields>
                        <field>
                            <name>CFID</name>
                            <description>Common FIFO Buffer ID Field</description>
                            <lsb>0</lsb>
                            <msb>28</msb>
                            <access>read-write</access>
                        </field>
                        <field>
                            <name>THLEN</name>
                            <description>THL Entry enable</description>
                            <lsb>29</lsb>
                            <msb>29</msb>
                            <access>read-write</access>
                            <enumeratedValues>
                                <enumeratedValue>
                                    <name>0</name>
                                    <description>Entry will not be stored in THL after successful TX.</description>
                                    <value>#0</value>
                                </enumeratedValue>
                                <enumeratedValue>
                                    <name>1</name>
                                    <description>Entry will be stored in THL after successful TX.</description>
                                    <value>#1</value>
                                </enumeratedValue>
                            </enumeratedValues>
                        </field>
                        <field>
                            <name>CFRTR</name>
                            <description>Common FIFO Buffer RTR Bit</description>
                            <lsb>30</lsb>
                            <msb>30</msb>
                            <access>read-write</access>
                            <enumeratedValues>
                                <enumeratedValue>
                                    <name>0</name>
                                    <description>Data Frame</description>
                                    <value>#0</value>
                                </enumeratedValue>
                                <enumeratedValue>
                                    <name>1</name>
                                    <description>Remote Frame</description>
                                    <value>#1</value>
                                </enumeratedValue>
                            </enumeratedValues>
                        </field>
                        <field>
                            <name>CFIDE</name>
                            <description>Common FIFO Buffer IDE Bit</description>
                            <lsb>31</lsb>
                            <msb>31</msb>
                            <access>read-write</access>
                            <enumeratedValues>
                                <enumeratedValue>
                                    <name>0</name>
                                    <description>STD-ID will be transmitted or has been received</description>
                                    <value>#0</value>
                                </enumeratedValue>
                                <enumeratedValue>
                                    <name>1</name>
                                    <description>EXT-ID will be transmitted or has been received</description>
                                    <value>#1</value>
                                </enumeratedValue>
                            </enumeratedValues>
                        </field>
                    </fields>
                </register>
                <register>
                    <name>CFDCFPTR</name>
                    <description>Common FIFO Access Pointer Register</description>
                    <addressOffset>0x05BC</addressOffset>
                    <size>32</size>
                    <access>read-write</access>
                    <resetValue>0x00000000</resetValue>
                    <resetMask>0xffffffff</resetMask>
                    <fields>
                        <field>
                            <name>CFTS</name>
                            <description>Common FIFO Timestamp Value</description>
                            <lsb>0</lsb>
                            <msb>15</msb>
                            <access>read-write</access>
                        </field>
                        <field>
                            <name>CFDLC</name>
                            <description>Common FIFO Buffer DLC Field</description>
                            <lsb>28</lsb>
                            <msb>31</msb>
                            <access>read-write</access>
                        </field>
                    </fields>
                </register>
                <register>
                    <name>CFDCFFDCSTS</name>
                    <description>Common FIFO Access CANFD Control/Status Register</description>
                    <addressOffset>0x05C0</addressOffset>
                    <size>32</size>
                    <access>read-write</access>
                    <resetValue>0x00000000</resetValue>
                    <resetMask>0xffffffff</resetMask>
                    <fields>
                        <field>
                            <name>CFESI</name>
                            <description>Error State Indicator bit</description>
                            <lsb>0</lsb>
                            <msb>0</msb>
                            <access>read-write</access>
                            <enumeratedValues>
                                <enumeratedValue>
                                    <name>0</name>
                                    <description>CANFD frame received or to transmit by error active node</description>
                                    <value>#0</value>
                                </enumeratedValue>
                                <enumeratedValue>
                                    <name>1</name>
                                    <description>CANFD frame received or to transmit by error passive node</description>
                                    <value>#1</value>
                                </enumeratedValue>
                            </enumeratedValues>
                        </field>
                        <field>
                            <name>CFBRS</name>
                            <description>Bit Rate Switch bit</description>
                            <lsb>1</lsb>
                            <msb>1</msb>
                            <access>read-write</access>
                            <enumeratedValues>
                                <enumeratedValue>
                                    <name>0</name>
                                    <description>CANFD frame received or to transmit with no bit rate switch</description>
                                    <value>#0</value>
                                </enumeratedValue>
                                <enumeratedValue>
                                    <name>1</name>
                                    <description>CANFD frame received or to transmit with bit rate switch</description>
                                    <value>#1</value>
                                </enumeratedValue>
                            </enumeratedValues>
                        </field>
                        <field>
                            <name>CFFDF</name>
                            <description>CAN FD Format bit</description>
                            <lsb>2</lsb>
                            <msb>2</msb>
                            <access>read-write</access>
                            <enumeratedValues>
                                <enumeratedValue>
                                    <name>0</name>
                                    <description>Non CANFD frame received or to transmit</description>
                                    <value>#0</value>
                                </enumeratedValue>
                                <enumeratedValue>
                                    <name>1</name>
                                    <description>CANFD frame received or to transmit</description>
                                    <value>#1</value>
                                </enumeratedValue>
                            </enumeratedValues>
                        </field>
                        <field>
                            <name>CFIFL</name>
                            <description>COMMON FIFO Buffer Information Label Field</description>
                            <lsb>8</lsb>
                            <msb>9</msb>
                            <access>read-write</access>
                        </field>
                        <field>
                            <name>CFPTR</name>
                            <description>Common FIFO Buffer Pointer Field</description>
                            <lsb>16</lsb>
                            <msb>31</msb>
                            <access>read-write</access>
                        </field>
                    </fields>
                </register>
                <register>
                    <dim>16</dim>
                    <dimIncrement>0x004</dimIncrement>
                    <dimIndex>0-15</dimIndex>
                    <name>CFDCFDF%s</name>
                    <description>Common FIFO Access Data Field %s Registers</description>
                    <addressOffset>0x05C4</addressOffset>
                    <size>32</size>
                    <access>read-write</access>
                    <resetValue>0x00000000</resetValue>
                    <resetMask>0xffffffff</resetMask>
                    <fields>
                        <field>
                            <name>CFDB_LL</name>
                            <description>Common FIFO Buffer Data Bytes (p × 4)</description>
                            <lsb>0</lsb>
                            <msb>7</msb>
                            <access>read-write</access>
                        </field>
                        <field>
                            <name>CFDB_LH</name>
                            <description>Common FIFO Buffer Data Bytes ((p × 4) + 1)</description>
                            <lsb>8</lsb>
                            <msb>15</msb>
                            <access>read-write</access>
                        </field>
                        <field>
                            <name>CFDB_HL</name>
                            <description>Common FIFO Buffer Data Bytes ((p × 4) + 2)</description>
                            <lsb>16</lsb>
                            <msb>23</msb>
                            <access>read-write</access>
                        </field>
                        <field>
                            <name>CFDB_HH</name>
                            <description>Common FIFO Buffer Data Bytes ((p × 4) + 3)</description>
                            <lsb>24</lsb>
                            <msb>31</msb>
                            <access>read-write</access>
                        </field>
                    </fields>
                </register>
                <register>
                    <dim>4</dim>
                    <dimIncrement>0x004C</dimIncrement>
                    <dimIndex>0-3</dimIndex>
                    <name>CFDTMID%s</name>
                    <description>TX Message Buffer ID Registers</description>
                    <addressOffset>0x0604</addressOffset>
                    <size>32</size>
                    <access>read-write</access>
                    <resetValue>0x00000000</resetValue>
                    <resetMask>0xffffffff</resetMask>
                    <fields>
                        <field>
                            <name>TMID</name>
                            <description>TX Message Buffer ID Field</description>
                            <lsb>0</lsb>
                            <msb>28</msb>
                            <access>read-write</access>
                        </field>
                        <field>
                            <name>THLEN</name>
                            <description>Tx History List Entry</description>
                            <lsb>29</lsb>
                            <msb>29</msb>
                            <access>read-write</access>
                            <enumeratedValues>
                                <enumeratedValue>
                                    <name>0</name>
                                    <description>Entry not stored in THL after successful TX</description>
                                    <value>#0</value>
                                </enumeratedValue>
                                <enumeratedValue>
                                    <name>1</name>
                                    <description>Entry stored in THL after successful TX</description>
                                    <value>#1</value>
                                </enumeratedValue>
                            </enumeratedValues>
                        </field>
                        <field>
                            <name>TMRTR</name>
                            <description>TX Message Buffer RTR bit</description>
                            <lsb>30</lsb>
                            <msb>30</msb>
                            <access>read-write</access>
                            <enumeratedValues>
                                <enumeratedValue>
                                    <name>0</name>
                                    <description>Data frame</description>
                                    <value>#0</value>
                                </enumeratedValue>
                                <enumeratedValue>
                                    <name>1</name>
                                    <description>Remote frame</description>
                                    <value>#1</value>
                                </enumeratedValue>
                            </enumeratedValues>
                        </field>
                        <field>
                            <name>TMIDE</name>
                            <description>TX Message Buffer IDE bit</description>
                            <lsb>31</lsb>
                            <msb>31</msb>
                            <access>read-write</access>
                            <enumeratedValues>
                                <enumeratedValue>
                                    <name>0</name>
                                    <description>STD-ID is transmitted</description>
                                    <value>#0</value>
                                </enumeratedValue>
                                <enumeratedValue>
                                    <name>1</name>
                                    <description>EXT-ID is transmitted</description>
                                    <value>#1</value>
                                </enumeratedValue>
                            </enumeratedValues>
                        </field>
                    </fields>
                </register>
                <register>
                    <dim>4</dim>
                    <dimIncrement>0x004C</dimIncrement>
                    <dimIndex>0-3</dimIndex>
                    <name>CFDTMPTR%s</name>
                    <description>TX Message Buffer Pointer Register </description>
                    <addressOffset>0x0608</addressOffset>
                    <size>32</size>
                    <access>read-write</access>
                    <resetValue>0x00000000</resetValue>
                    <resetMask>0xffffffff</resetMask>
                    <fields>
                        <field>
                            <name>TMDLC</name>
                            <description>TX Message Buffer DLC Field</description>
                            <lsb>28</lsb>
                            <msb>31</msb>
                            <access>read-write</access>
                        </field>
                    </fields>
                </register>
                <register>
                    <dim>4</dim>
                    <dimIncrement>0x004C</dimIncrement>
                    <dimIndex>0-3</dimIndex>
                    <name>CFDTMFDCTR%s</name>
                    <description>TX Message Buffer CANFD Control Register </description>
                    <addressOffset>0x060C</addressOffset>
                    <size>32</size>
                    <access>read-write</access>
                    <resetValue>0x00000000</resetValue>
                    <resetMask>0xffffffff</resetMask>
                    <fields>
                        <field>
                            <name>TMESI</name>
                            <description>Error State Indicator bit</description>
                            <lsb>0</lsb>
                            <msb>0</msb>
                            <access>read-write</access>
                            <enumeratedValues>
                                <enumeratedValue>
                                    <name>0</name>
                                    <description>CANFD frame to transmit by error active node</description>
                                    <value>#0</value>
                                </enumeratedValue>
                                <enumeratedValue>
                                    <name>1</name>
                                    <description>CANFD frame to transmit by error passive node</description>
                                    <value>#1</value>
                                </enumeratedValue>
                            </enumeratedValues>
                        </field>
                        <field>
                            <name>TMBRS</name>
                            <description>Bit Rate Switch bit</description>
                            <lsb>1</lsb>
                            <msb>1</msb>
                            <access>read-write</access>
                            <enumeratedValues>
                                <enumeratedValue>
                                    <name>0</name>
                                    <description>CANFD frame to transmit with no bit rate switch</description>
                                    <value>#0</value>
                                </enumeratedValue>
                                <enumeratedValue>
                                    <name>1</name>
                                    <description>CANFD frame to transmit with bit rate switch</description>
                                    <value>#1</value>
                                </enumeratedValue>
                            </enumeratedValues>
                        </field>
                        <field>
                            <name>TMFDF</name>
                            <description>CAN FD Format bit</description>
                            <lsb>2</lsb>
                            <msb>2</msb>
                            <access>read-write</access>
                            <enumeratedValues>
                                <enumeratedValue>
                                    <name>0</name>
                                    <description>Non CANFD frame to transmit</description>
                                    <value>#0</value>
                                </enumeratedValue>
                                <enumeratedValue>
                                    <name>1</name>
                                    <description>CANFD frame to transmit</description>
                                    <value>#1</value>
                                </enumeratedValue>
                            </enumeratedValues>
                        </field>
                        <field>
                            <name>TMIFL</name>
                            <description>TX Message Buffer Information Label Field</description>
                            <lsb>8</lsb>
                            <msb>9</msb>
                            <access>read-write</access>
                        </field>
                        <field>
                            <name>TMPTR</name>
                            <description>TX Message Buffer Pointer Field</description>
                            <lsb>16</lsb>
                            <msb>31</msb>
                            <access>read-write</access>
                        </field>
                    </fields>
                </register>
                <register>
                    <dim>4</dim>
                    <dimIncrement>0x04c</dimIncrement>
                    <dimIndex>0-3</dimIndex>
                    <name>CFDTMDF%s_0</name>
                    <description>TX Message Buffer Data Field Register</description>
                    <addressOffset>0x0610</addressOffset>
                    <size>32</size>
                    <access>read-write</access>
                    <resetValue>0x00000000</resetValue>
                    <resetMask>0xffffffff</resetMask>
                    <fields>
                        <field>
                            <name>TMDB_LL</name>
                            <description>TX Message Buffer Data Byte ((p × 4)</description>
                            <lsb>0</lsb>
                            <msb>7</msb>
                            <access>read-write</access>
                        </field>
                        <field>
                            <name>TMDB_LH</name>
                            <description>TX Message Buffer Data Byte ((p × 4) + 1)</description>
                            <lsb>8</lsb>
                            <msb>15</msb>
                            <access>read-write</access>
                        </field>
                        <field>
                            <name>TMDB_HL</name>
                            <description>TX Message Buffer Data Byte ((p × 4) + 2)</description>
                            <lsb>16</lsb>
                            <msb>23</msb>
                            <access>read-write</access>
                        </field>
                        <field>
                            <name>TMDB_HH</name>
                            <description>TX Message Buffer Data Byte ((p × 4) + 3)</description>
                            <lsb>24</lsb>
                            <msb>31</msb>
                            <access>read-write</access>
                        </field>
                    </fields>
                </register>
                <register>
                    <dim>4</dim>
                    <dimIncrement>0x04c</dimIncrement>
                    <dimIndex>0-3</dimIndex>
                    <name>CFDTMDF%s_1</name>
                    <description>TX Message Buffer Data Field Register</description>
                    <addressOffset>0x0614</addressOffset>
                    <size>32</size>
                    <access>read-write</access>
                    <resetValue>0x00000000</resetValue>
                    <resetMask>0xffffffff</resetMask>
                    <fields>
                        <field>
                            <name>TMDB_LL</name>
                            <description>TX Message Buffer Data Byte ((p × 4)</description>
                            <lsb>0</lsb>
                            <msb>7</msb>
                            <access>read-write</access>
                        </field>
                        <field>
                            <name>TMDB_LH</name>
                            <description>TX Message Buffer Data Byte ((p × 4) + 1)</description>
                            <lsb>8</lsb>
                            <msb>15</msb>
                            <access>read-write</access>
                        </field>
                        <field>
                            <name>TMDB_HL</name>
                            <description>TX Message Buffer Data Byte ((p × 4) + 2)</description>
                            <lsb>16</lsb>
                            <msb>23</msb>
                            <access>read-write</access>
                        </field>
                        <field>
                            <name>TMDB_HH</name>
                            <description>TX Message Buffer Data Byte ((p × 4) + 3)</description>
                            <lsb>24</lsb>
                            <msb>31</msb>
                            <access>read-write</access>
                        </field>
                    </fields>
                </register>
                <register>
                    <dim>4</dim>
                    <dimIncrement>0x04c</dimIncrement>
                    <dimIndex>0-3</dimIndex>
                    <name>CFDTMDF%s_2</name>
                    <description>TX Message Buffer Data Field Register</description>
                    <addressOffset>0x0618</addressOffset>
                    <size>32</size>
                    <access>read-write</access>
                    <resetValue>0x00000000</resetValue>
                    <resetMask>0xffffffff</resetMask>
                    <fields>
                        <field>
                            <name>TMDB_LL</name>
                            <description>TX Message Buffer Data Byte ((p × 4)</description>
                            <lsb>0</lsb>
                            <msb>7</msb>
                            <access>read-write</access>
                        </field>
                        <field>
                            <name>TMDB_LH</name>
                            <description>TX Message Buffer Data Byte ((p × 4) + 1)</description>
                            <lsb>8</lsb>
                            <msb>15</msb>
                            <access>read-write</access>
                        </field>
                        <field>
                            <name>TMDB_HL</name>
                            <description>TX Message Buffer Data Byte ((p × 4) + 2)</description>
                            <lsb>16</lsb>
                            <msb>23</msb>
                            <access>read-write</access>
                        </field>
                        <field>
                            <name>TMDB_HH</name>
                            <description>TX Message Buffer Data Byte ((p × 4) + 3)</description>
                            <lsb>24</lsb>
                            <msb>31</msb>
                            <access>read-write</access>
                        </field>
                    </fields>
                </register>
                <register>
                    <dim>4</dim>
                    <dimIncrement>0x04c</dimIncrement>
                    <dimIndex>0-3</dimIndex>
                    <name>CFDTMDF%s_3</name>
                    <description>TX Message Buffer Data Field Register</description>
                    <addressOffset>0x061C</addressOffset>
                    <size>32</size>
                    <access>read-write</access>
                    <resetValue>0x00000000</resetValue>
                    <resetMask>0xffffffff</resetMask>
                    <fields>
                        <field>
                            <name>TMDB_LL</name>
                            <description>TX Message Buffer Data Byte ((p × 4)</description>
                            <lsb>0</lsb>
                            <msb>7</msb>
                            <access>read-write</access>
                        </field>
                        <field>
                            <name>TMDB_LH</name>
                            <description>TX Message Buffer Data Byte ((p × 4) + 1)</description>
                            <lsb>8</lsb>
                            <msb>15</msb>
                            <access>read-write</access>
                        </field>
                        <field>
                            <name>TMDB_HL</name>
                            <description>TX Message Buffer Data Byte ((p × 4) + 2)</description>
                            <lsb>16</lsb>
                            <msb>23</msb>
                            <access>read-write</access>
                        </field>
                        <field>
                            <name>TMDB_HH</name>
                            <description>TX Message Buffer Data Byte ((p × 4) + 3)</description>
                            <lsb>24</lsb>
                            <msb>31</msb>
                            <access>read-write</access>
                        </field>
                    </fields>
                </register>
                <register>
                    <dim>4</dim>
                    <dimIncrement>0x04c</dimIncrement>
                    <dimIndex>0-3</dimIndex>
                    <name>CFDTMDF%s_4</name>
                    <description>TX Message Buffer Data Field Register</description>
                    <addressOffset>0x0620</addressOffset>
                    <size>32</size>
                    <access>read-write</access>
                    <resetValue>0x00000000</resetValue>
                    <resetMask>0xffffffff</resetMask>
                    <fields>
                        <field>
                            <name>TMDB_LL</name>
                            <description>TX Message Buffer Data Byte ((p × 4)</description>
                            <lsb>0</lsb>
                            <msb>7</msb>
                            <access>read-write</access>
                        </field>
                        <field>
                            <name>TMDB_LH</name>
                            <description>TX Message Buffer Data Byte ((p × 4) + 1)</description>
                            <lsb>8</lsb>
                            <msb>15</msb>
                            <access>read-write</access>
                        </field>
                        <field>
                            <name>TMDB_HL</name>
                            <description>TX Message Buffer Data Byte ((p × 4) + 2)</description>
                            <lsb>16</lsb>
                            <msb>23</msb>
                            <access>read-write</access>
                        </field>
                        <field>
                            <name>TMDB_HH</name>
                            <description>TX Message Buffer Data Byte ((p × 4) + 3)</description>
                            <lsb>24</lsb>
                            <msb>31</msb>
                            <access>read-write</access>
                        </field>
                    </fields>
                </register>
                <register>
                    <dim>4</dim>
                    <dimIncrement>0x04c</dimIncrement>
                    <dimIndex>0-3</dimIndex>
                    <name>CFDTMDF%s_5</name>
                    <description>TX Message Buffer Data Field Register</description>
                    <addressOffset>0x0624</addressOffset>
                    <size>32</size>
                    <access>read-write</access>
                    <resetValue>0x00000000</resetValue>
                    <resetMask>0xffffffff</resetMask>
                    <fields>
                        <field>
                            <name>TMDB_LL</name>
                            <description>TX Message Buffer Data Byte ((p × 4)</description>
                            <lsb>0</lsb>
                            <msb>7</msb>
                            <access>read-write</access>
                        </field>
                        <field>
                            <name>TMDB_LH</name>
                            <description>TX Message Buffer Data Byte ((p × 4) + 1)</description>
                            <lsb>8</lsb>
                            <msb>15</msb>
                            <access>read-write</access>
                        </field>
                        <field>
                            <name>TMDB_HL</name>
                            <description>TX Message Buffer Data Byte ((p × 4) + 2)</description>
                            <lsb>16</lsb>
                            <msb>23</msb>
                            <access>read-write</access>
                        </field>
                        <field>
                            <name>TMDB_HH</name>
                            <description>TX Message Buffer Data Byte ((p × 4) + 3)</description>
                            <lsb>24</lsb>
                            <msb>31</msb>
                            <access>read-write</access>
                        </field>
                    </fields>
                </register>
                <register>
                    <dim>4</dim>
                    <dimIncrement>0x04c</dimIncrement>
                    <dimIndex>0-3</dimIndex>
                    <name>CFDTMDF%s_6</name>
                    <description>TX Message Buffer Data Field Register </description>
                    <addressOffset>0x0628</addressOffset>
                    <size>32</size>
                    <access>read-write</access>
                    <resetValue>0x00000000</resetValue>
                    <resetMask>0xffffffff</resetMask>
                    <fields>
                        <field>
                            <name>TMDB_LL</name>
                            <description>TX Message Buffer Data Byte ((p × 4)</description>
                            <lsb>0</lsb>
                            <msb>7</msb>
                            <access>read-write</access>
                        </field>
                        <field>
                            <name>TMDB_LH</name>
                            <description>TX Message Buffer Data Byte ((p × 4) + 1)</description>
                            <lsb>8</lsb>
                            <msb>15</msb>
                            <access>read-write</access>
                        </field>
                        <field>
                            <name>TMDB_HL</name>
                            <description>TX Message Buffer Data Byte ((p × 4) + 2)</description>
                            <lsb>16</lsb>
                            <msb>23</msb>
                            <access>read-write</access>
                        </field>
                        <field>
                            <name>TMDB_HH</name>
                            <description>TX Message Buffer Data Byte ((p × 4) + 3)</description>
                            <lsb>24</lsb>
                            <msb>31</msb>
                            <access>read-write</access>
                        </field>
                    </fields>
                </register>
                <register>
                    <dim>4</dim>
                    <dimIncrement>0x04c</dimIncrement>
                    <dimIndex>0-3</dimIndex>
                    <name>CFDTMDF%s_7</name>
                    <description>TX Message Buffer Data Field Register</description>
                    <addressOffset>0x062C</addressOffset>
                    <size>32</size>
                    <access>read-write</access>
                    <resetValue>0x00000000</resetValue>
                    <resetMask>0xffffffff</resetMask>
                    <fields>
                        <field>
                            <name>TMDB_LL</name>
                            <description>TX Message Buffer Data Byte ((p × 4)</description>
                            <lsb>0</lsb>
                            <msb>7</msb>
                            <access>read-write</access>
                        </field>
                        <field>
                            <name>TMDB_LH</name>
                            <description>TX Message Buffer Data Byte ((p × 4) + 1)</description>
                            <lsb>8</lsb>
                            <msb>15</msb>
                            <access>read-write</access>
                        </field>
                        <field>
                            <name>TMDB_HL</name>
                            <description>TX Message Buffer Data Byte ((p × 4) + 2)</description>
                            <lsb>16</lsb>
                            <msb>23</msb>
                            <access>read-write</access>
                        </field>
                        <field>
                            <name>TMDB_HH</name>
                            <description>TX Message Buffer Data Byte ((p × 4) + 3)</description>
                            <lsb>24</lsb>
                            <msb>31</msb>
                            <access>read-write</access>
                        </field>
                    </fields>
                </register>
                <register>
                    <dim>4</dim>
                    <dimIncrement>0x04c</dimIncrement>
                    <dimIndex>0-3</dimIndex>
                    <name>CFDTMDF%s_8</name>
                    <description>TX Message Buffer Data Field Register</description>
                    <addressOffset>0x0630</addressOffset>
                    <size>32</size>
                    <access>read-write</access>
                    <resetValue>0x00000000</resetValue>
                    <resetMask>0xffffffff</resetMask>
                    <fields>
                        <field>
                            <name>TMDB_LL</name>
                            <description>TX Message Buffer Data Byte ((p × 4)</description>
                            <lsb>0</lsb>
                            <msb>7</msb>
                            <access>read-write</access>
                        </field>
                        <field>
                            <name>TMDB_LH</name>
                            <description>TX Message Buffer Data Byte ((p × 4) + 1)</description>
                            <lsb>8</lsb>
                            <msb>15</msb>
                            <access>read-write</access>
                        </field>
                        <field>
                            <name>TMDB_HL</name>
                            <description>TX Message Buffer Data Byte ((p × 4) + 2)</description>
                            <lsb>16</lsb>
                            <msb>23</msb>
                            <access>read-write</access>
                        </field>
                        <field>
                            <name>TMDB_HH</name>
                            <description>TX Message Buffer Data Byte ((p × 4) + 3)</description>
                            <lsb>24</lsb>
                            <msb>31</msb>
                            <access>read-write</access>
                        </field>
                    </fields>
                </register>
                <register>
                    <dim>4</dim>
                    <dimIncrement>0x04c</dimIncrement>
                    <dimIndex>0-3</dimIndex>
                    <name>CFDTMDF%s_9</name>
                    <description>TX Message Buffer Data Field Register</description>
                    <addressOffset>0x0634</addressOffset>
                    <size>32</size>
                    <access>read-write</access>
                    <resetValue>0x00000000</resetValue>
                    <resetMask>0xffffffff</resetMask>
                    <fields>
                        <field>
                            <name>TMDB_LL</name>
                            <description>TX Message Buffer Data Byte ((p × 4)</description>
                            <lsb>0</lsb>
                            <msb>7</msb>
                            <access>read-write</access>
                        </field>
                        <field>
                            <name>TMDB_LH</name>
                            <description>TX Message Buffer Data Byte ((p × 4) + 1)</description>
                            <lsb>8</lsb>
                            <msb>15</msb>
                            <access>read-write</access>
                        </field>
                        <field>
                            <name>TMDB_HL</name>
                            <description>TX Message Buffer Data Byte ((p × 4) + 2)</description>
                            <lsb>16</lsb>
                            <msb>23</msb>
                            <access>read-write</access>
                        </field>
                        <field>
                            <name>TMDB_HH</name>
                            <description>TX Message Buffer Data Byte ((p × 4) + 3)</description>
                            <lsb>24</lsb>
                            <msb>31</msb>
                            <access>read-write</access>
                        </field>
                    </fields>
                </register>
                <register>
                    <dim>4</dim>
                    <dimIncrement>0x04c</dimIncrement>
                    <dimIndex>0-3</dimIndex>
                    <name>CFDTMDF%s_10</name>
                    <description>TX Message Buffer Data Field Register </description>
                    <addressOffset>0x0638</addressOffset>
                    <size>32</size>
                    <access>read-write</access>
                    <resetValue>0x00000000</resetValue>
                    <resetMask>0xffffffff</resetMask>
                    <fields>
                        <field>
                            <name>TMDB_LL</name>
                            <description>TX Message Buffer Data Byte ((p × 4)</description>
                            <lsb>0</lsb>
                            <msb>7</msb>
                            <access>read-write</access>
                        </field>
                        <field>
                            <name>TMDB_LH</name>
                            <description>TX Message Buffer Data Byte ((p × 4) + 1)</description>
                            <lsb>8</lsb>
                            <msb>15</msb>
                            <access>read-write</access>
                        </field>
                        <field>
                            <name>TMDB_HL</name>
                            <description>TX Message Buffer Data Byte ((p × 4) + 2)</description>
                            <lsb>16</lsb>
                            <msb>23</msb>
                            <access>read-write</access>
                        </field>
                        <field>
                            <name>TMDB_HH</name>
                            <description>TX Message Buffer Data Byte ((p × 4) + 3)</description>
                            <lsb>24</lsb>
                            <msb>31</msb>
                            <access>read-write</access>
                        </field>
                    </fields>
                </register>
                <register>
                    <dim>4</dim>
                    <dimIncrement>0x04c</dimIncrement>
                    <dimIndex>0-3</dimIndex>
                    <name>CFDTMDF%s_11</name>
                    <description>TX Message Buffer Data Field Register</description>
                    <addressOffset>0x063C</addressOffset>
                    <size>32</size>
                    <access>read-write</access>
                    <resetValue>0x00000000</resetValue>
                    <resetMask>0xffffffff</resetMask>
                    <fields>
                        <field>
                            <name>TMDB_LL</name>
                            <description>TX Message Buffer Data Byte ((p × 4)</description>
                            <lsb>0</lsb>
                            <msb>7</msb>
                            <access>read-write</access>
                        </field>
                        <field>
                            <name>TMDB_LH</name>
                            <description>TX Message Buffer Data Byte ((p × 4) + 1)</description>
                            <lsb>8</lsb>
                            <msb>15</msb>
                            <access>read-write</access>
                        </field>
                        <field>
                            <name>TMDB_HL</name>
                            <description>TX Message Buffer Data Byte ((p × 4) + 2)</description>
                            <lsb>16</lsb>
                            <msb>23</msb>
                            <access>read-write</access>
                        </field>
                        <field>
                            <name>TMDB_HH</name>
                            <description>TX Message Buffer Data Byte ((p × 4) + 3)</description>
                            <lsb>24</lsb>
                            <msb>31</msb>
                            <access>read-write</access>
                        </field>
                    </fields>
                </register>
                <register>
                    <dim>4</dim>
                    <dimIncrement>0x04c</dimIncrement>
                    <dimIndex>0-3</dimIndex>
                    <name>CFDTMDF%s_12</name>
                    <description>TX Message Buffer Data Field Register</description>
                    <addressOffset>0x0640</addressOffset>
                    <size>32</size>
                    <access>read-write</access>
                    <resetValue>0x00000000</resetValue>
                    <resetMask>0xffffffff</resetMask>
                    <fields>
                        <field>
                            <name>TMDB_LL</name>
                            <description>TX Message Buffer Data Byte ((p × 4)</description>
                            <lsb>0</lsb>
                            <msb>7</msb>
                            <access>read-write</access>
                        </field>
                        <field>
                            <name>TMDB_LH</name>
                            <description>TX Message Buffer Data Byte ((p × 4) + 1)</description>
                            <lsb>8</lsb>
                            <msb>15</msb>
                            <access>read-write</access>
                        </field>
                        <field>
                            <name>TMDB_HL</name>
                            <description>TX Message Buffer Data Byte ((p × 4) + 2)</description>
                            <lsb>16</lsb>
                            <msb>23</msb>
                            <access>read-write</access>
                        </field>
                        <field>
                            <name>TMDB_HH</name>
                            <description>TX Message Buffer Data Byte ((p × 4) + 3)</description>
                            <lsb>24</lsb>
                            <msb>31</msb>
                            <access>read-write</access>
                        </field>
                    </fields>
                </register>
                <register>
                    <dim>4</dim>
                    <dimIncrement>0x04c</dimIncrement>
                    <dimIndex>0-3</dimIndex>
                    <name>CFDTMDF%s_13</name>
                    <description>TX Message Buffer Data Field Register</description>
                    <addressOffset>0x0644</addressOffset>
                    <size>32</size>
                    <access>read-write</access>
                    <resetValue>0x00000000</resetValue>
                    <resetMask>0xffffffff</resetMask>
                    <fields>
                        <field>
                            <name>TMDB_LL</name>
                            <description>TX Message Buffer Data Byte ((p × 4)</description>
                            <lsb>0</lsb>
                            <msb>7</msb>
                            <access>read-write</access>
                        </field>
                        <field>
                            <name>TMDB_LH</name>
                            <description>TX Message Buffer Data Byte ((p × 4) + 1)</description>
                            <lsb>8</lsb>
                            <msb>15</msb>
                            <access>read-write</access>
                        </field>
                        <field>
                            <name>TMDB_HL</name>
                            <description>TX Message Buffer Data Byte ((p × 4) + 2)</description>
                            <lsb>16</lsb>
                            <msb>23</msb>
                            <access>read-write</access>
                        </field>
                        <field>
                            <name>TMDB_HH</name>
                            <description>TX Message Buffer Data Byte ((p × 4) + 3)</description>
                            <lsb>24</lsb>
                            <msb>31</msb>
                            <access>read-write</access>
                        </field>
                    </fields>
                </register>
                <register>
                    <dim>4</dim>
                    <dimIncrement>0x04c</dimIncrement>
                    <dimIndex>0-3</dimIndex>
                    <name>CFDTMDF%s_14</name>
                    <description>TX Message Buffer Data Field Register</description>
                    <addressOffset>0x0648</addressOffset>
                    <size>32</size>
                    <access>read-write</access>
                    <resetValue>0x00000000</resetValue>
                    <resetMask>0xffffffff</resetMask>
                    <fields>
                        <field>
                            <name>TMDB_LL</name>
                            <description>TX Message Buffer Data Byte ((p × 4)</description>
                            <lsb>0</lsb>
                            <msb>7</msb>
                            <access>read-write</access>
                        </field>
                        <field>
                            <name>TMDB_LH</name>
                            <description>TX Message Buffer Data Byte ((p × 4) + 1)</description>
                            <lsb>8</lsb>
                            <msb>15</msb>
                            <access>read-write</access>
                        </field>
                        <field>
                            <name>TMDB_HL</name>
                            <description>TX Message Buffer Data Byte ((p × 4) + 2)</description>
                            <lsb>16</lsb>
                            <msb>23</msb>
                            <access>read-write</access>
                        </field>
                        <field>
                            <name>TMDB_HH</name>
                            <description>TX Message Buffer Data Byte ((p × 4) + 3)</description>
                            <lsb>24</lsb>
                            <msb>31</msb>
                            <access>read-write</access>
                        </field>
                    </fields>
                </register>
                <register>
                    <dim>4</dim>
                    <dimIncrement>0x04c</dimIncrement>
                    <dimIndex>0-3</dimIndex>
                    <name>CFDTMDF%s_15</name>
                    <description>TX Message Buffer Data Field Register</description>
                    <addressOffset>0x064C</addressOffset>
                    <size>32</size>
                    <access>read-write</access>
                    <resetValue>0x00000000</resetValue>
                    <resetMask>0xffffffff</resetMask>
                    <fields>
                        <field>
                            <name>TMDB_LL</name>
                            <description>TX Message Buffer Data Byte ((p × 4)</description>
                            <lsb>0</lsb>
                            <msb>7</msb>
                            <access>read-write</access>
                        </field>
                        <field>
                            <name>TMDB_LH</name>
                            <description>TX Message Buffer Data Byte ((p × 4) + 1)</description>
                            <lsb>8</lsb>
                            <msb>15</msb>
                            <access>read-write</access>
                        </field>
                        <field>
                            <name>TMDB_HL</name>
                            <description>TX Message Buffer Data Byte ((p × 4) + 2)</description>
                            <lsb>16</lsb>
                            <msb>23</msb>
                            <access>read-write</access>
                        </field>
                        <field>
                            <name>TMDB_HH</name>
                            <description>TX Message Buffer Data Byte ((p × 4) + 3)</description>
                            <lsb>24</lsb>
                            <msb>31</msb>
                            <access>read-write</access>
                        </field>
                    </fields>
                </register>
                <register>
                    <name>CFDTHLACC0</name>
                    <description>TX History List Access Register 0</description>
                    <addressOffset>0x0740</addressOffset>
                    <size>32</size>
                    <access>read-only</access>
                    <resetValue>0x00000000</resetValue>
                    <resetMask>0xffffffff</resetMask>
                    <fields>
                        <field>
                            <name>BT</name>
                            <description>Buffer Type</description>
                            <lsb>0</lsb>
                            <msb>2</msb>
                            <access>read-only</access>
                            <enumeratedValues>
                                <enumeratedValue>
                                    <name>001</name>
                                    <description>Flat TX message buffer</description>
                                    <value>#001</value>
                                </enumeratedValue>
                                <enumeratedValue>
                                    <name>010</name>
                                    <description>TX FIFO message buffer number</description>
                                    <value>#010</value>
                                </enumeratedValue>
                                <enumeratedValue>
                                    <name>100</name>
                                    <description>TX Queue message buffer number</description>
                                    <value>#100</value>
                                </enumeratedValue>
                            </enumeratedValues>
                        </field>
                        <field>
                            <name>BN</name>
                            <description>Buffer Number</description>
                            <lsb>3</lsb>
                            <msb>4</msb>
                            <access>read-only</access>
                        </field>
                        <field>
                            <name>TMTS</name>
                            <description>Transmit Timestamp</description>
                            <lsb>16</lsb>
                            <msb>31</msb>
                            <access>read-only</access>
                        </field>
                    </fields>
                </register>
                <register>
                    <name>CFDTHLACC1</name>
                    <description>TX History List Access Register 1</description>
                    <addressOffset>0x0744</addressOffset>
                    <size>32</size>
                    <access>read-only</access>
                    <resetValue>0x00000000</resetValue>
                    <resetMask>0xffffffff</resetMask>
                    <fields>
                        <field>
                            <name>TID</name>
                            <description>Transmit ID</description>
                            <lsb>0</lsb>
                            <msb>15</msb>
                            <access>read-only</access>
                        </field>
                        <field>
                            <name>TIFL</name>
                            <description>Transmit Information Label</description>
                            <lsb>16</lsb>
                            <msb>17</msb>
                            <access>read-only</access>
                        </field>
                    </fields>
                </register>
                <register>
                    <dim>8</dim>
                    <dimIncrement>0x004C</dimIncrement>
                    <dimIndex>0-7</dimIndex>
                    <name>CFDRMID%s</name>
                    <description>RX Message Buffer ID Registers</description>
                    <addressOffset>0x0920</addressOffset>
                    <size>32</size>
                    <access>read-only</access>
                    <resetValue>0x00000000</resetValue>
                    <resetMask>0xffffffff</resetMask>
                    <fields>
                        <field>
                            <name>RMID</name>
                            <description>RX Message Buffer ID Field</description>
                            <lsb>0</lsb>
                            <msb>28</msb>
                            <access>read-only</access>
                        </field>
                        <field>
                            <name>RMRTR</name>
                            <description>RX Message Buffer RTR Bit</description>
                            <lsb>30</lsb>
                            <msb>30</msb>
                            <access>read-only</access>
                            <enumeratedValues>
                                <enumeratedValue>
                                    <name>0</name>
                                    <description>Data frame</description>
                                    <value>#0</value>
                                </enumeratedValue>
                                <enumeratedValue>
                                    <name>1</name>
                                    <description>Remote frame</description>
                                    <value>#1</value>
                                </enumeratedValue>
                            </enumeratedValues>
                        </field>
                        <field>
                            <name>RMIDE</name>
                            <description>RX Message Buffer IDE Bit</description>
                            <lsb>31</lsb>
                            <msb>31</msb>
                            <access>read-only</access>
                            <enumeratedValues>
                                <enumeratedValue>
                                    <name>0</name>
                                    <description>STD-ID is stored</description>
                                    <value>#0</value>
                                </enumeratedValue>
                                <enumeratedValue>
                                    <name>1</name>
                                    <description>EXT-ID is stored</description>
                                    <value>#1</value>
                                </enumeratedValue>
                            </enumeratedValues>
                        </field>
                    </fields>
                </register>
                <register>
                    <dim>8</dim>
                    <dimIncrement>0x004C</dimIncrement>
                    <dimIndex>0-7</dimIndex>
                    <name>CFDRMPTR%s</name>
                    <description>RX Message Buffer Pointer Registers</description>
                    <addressOffset>0x0924</addressOffset>
                    <size>32</size>
                    <access>read-only</access>
                    <resetValue>0x00000000</resetValue>
                    <resetMask>0xffffffff</resetMask>
                    <fields>
                        <field>
                            <name>RMTS</name>
                            <description>RX Message Buffer Timestamp Field</description>
                            <lsb>0</lsb>
                            <msb>15</msb>
                            <access>read-only</access>
                        </field>
                        <field>
                            <name>RMDLC</name>
                            <description>RX Message Buffer DLC Field</description>
                            <lsb>28</lsb>
                            <msb>31</msb>
                            <access>read-only</access>
                        </field>
                    </fields>
                </register>
                <register>
                    <dim>8</dim>
                    <dimIncrement>0x004C</dimIncrement>
                    <dimIndex>0-7</dimIndex>
                    <name>CFDRMFDSTS%s</name>
                    <description>RX Message Buffer CANFD Status Registers</description>
                    <addressOffset>0x0928</addressOffset>
                    <size>32</size>
                    <access>read-only</access>
                    <resetValue>0x00000000</resetValue>
                    <resetMask>0xffffffff</resetMask>
                    <fields>
                        <field>
                            <name>RMESI</name>
                            <description>Error State Indicator bit</description>
                            <lsb>0</lsb>
                            <msb>0</msb>
                            <access>read-only</access>
                            <enumeratedValues>
                                <enumeratedValue>
                                    <name>0</name>
                                    <description>CANFD frame received from error active node</description>
                                    <value>#0</value>
                                </enumeratedValue>
                                <enumeratedValue>
                                    <name>1</name>
                                    <description>CANFD frame received from error passive node</description>
                                    <value>#1</value>
                                </enumeratedValue>
                            </enumeratedValues>
                        </field>
                        <field>
                            <name>RMBRS</name>
                            <description>Bit Rate Switch bit</description>
                            <lsb>1</lsb>
                            <msb>1</msb>
                            <access>read-only</access>
                            <enumeratedValues>
                                <enumeratedValue>
                                    <name>0</name>
                                    <description>CANFD frame received with no bit rate switch</description>
                                    <value>#0</value>
                                </enumeratedValue>
                                <enumeratedValue>
                                    <name>1</name>
                                    <description>CANFD frame received with bit rate switch</description>
                                    <value>#1</value>
                                </enumeratedValue>
                            </enumeratedValues>
                        </field>
                        <field>
                            <name>RMFDF</name>
                            <description>CAN FD Format bit</description>
                            <lsb>2</lsb>
                            <msb>2</msb>
                            <access>read-only</access>
                            <enumeratedValues>
                                <enumeratedValue>
                                    <name>0</name>
                                    <description>Non CANFD frame received</description>
                                    <value>#0</value>
                                </enumeratedValue>
                                <enumeratedValue>
                                    <name>1</name>
                                    <description>CANFD frame received</description>
                                    <value>#1</value>
                                </enumeratedValue>
                            </enumeratedValues>
                        </field>
                        <field>
                            <name>RMIFL</name>
                            <description>RX Message Buffer Information Label Field</description>
                            <lsb>8</lsb>
                            <msb>9</msb>
                            <access>read-only</access>
                        </field>
                        <field>
                            <name>RMPTR</name>
                            <description>RX Message Buffer Pointer Field</description>
                            <lsb>16</lsb>
                            <msb>31</msb>
                            <access>read-only</access>
                        </field>
                    </fields>
                </register>
                <register>
                    <dim>8</dim>
                    <dimIncrement>0x004C</dimIncrement>
                    <dimIndex>0-7</dimIndex>
                    <name>CFDRMDF%s_0</name>
                    <description>RX Message Buffer Data Field 0 Registers</description>
                    <addressOffset>0x092C</addressOffset>
                    <size>32</size>
                    <access>read-only</access>
                    <resetValue>0x00000000</resetValue>
                    <resetMask>0xffffffff</resetMask>
                    <fields>
                        <field>
                            <name>RMDB_LL</name>
                            <description>RX Message Buffer Data Byte (p × 4)</description>
                            <lsb>0</lsb>
                            <msb>7</msb>
                            <access>read-only</access>
                        </field>
                        <field>
                            <name>RMDB_LH</name>
                            <description>RX Message Buffer Data Byte ((p × 4) + 1)</description>
                            <lsb>8</lsb>
                            <msb>15</msb>
                            <access>read-only</access>
                        </field>
                        <field>
                            <name>RMDB_HL</name>
                            <description>RX Message Buffer Data Byte ((p × 4) + 2)</description>
                            <lsb>16</lsb>
                            <msb>23</msb>
                            <access>read-only</access>
                        </field>
                        <field>
                            <name>RMDB_HH</name>
                            <description>RX Message Buffer Data Byte ((p × 4) + 3)</description>
                            <lsb>24</lsb>
                            <msb>31</msb>
                            <access>read-only</access>
                        </field>
                    </fields>
                </register>
                <register>
                    <dim>8</dim>
                    <dimIncrement>0x004C</dimIncrement>
                    <dimIndex>0-7</dimIndex>
                    <name>CFDRMDF%s_1</name>
                    <description>RX Message Buffer Data Field 1 Registers</description>
                    <addressOffset>0x0930</addressOffset>
                    <size>32</size>
                    <access>read-only</access>
                    <resetValue>0x00000000</resetValue>
                    <resetMask>0xffffffff</resetMask>
                    <fields>
                        <field>
                            <name>RMDB_LL</name>
                            <description>RX Message Buffer Data Byte (p × 4)</description>
                            <lsb>0</lsb>
                            <msb>7</msb>
                            <access>read-only</access>
                        </field>
                        <field>
                            <name>RMDB_LH</name>
                            <description>RX Message Buffer Data Byte ((p × 4) + 1)</description>
                            <lsb>8</lsb>
                            <msb>15</msb>
                            <access>read-only</access>
                        </field>
                        <field>
                            <name>RMDB_HL</name>
                            <description>RX Message Buffer Data Byte ((p × 4) + 2)</description>
                            <lsb>16</lsb>
                            <msb>23</msb>
                            <access>read-only</access>
                        </field>
                        <field>
                            <name>RMDB_HH</name>
                            <description>RX Message Buffer Data Byte ((p × 4) + 3)</description>
                            <lsb>24</lsb>
                            <msb>31</msb>
                            <access>read-only</access>
                        </field>
                    </fields>
                </register>
                <register>
                    <dim>8</dim>
                    <dimIncrement>0x004C</dimIncrement>
                    <dimIndex>0-7</dimIndex>
                    <name>CFDRMDF%s_2</name>
                    <description>RX Message Buffer Data Field 2 Registers</description>
                    <addressOffset>0x0934</addressOffset>
                    <size>32</size>
                    <access>read-only</access>
                    <resetValue>0x00000000</resetValue>
                    <resetMask>0xffffffff</resetMask>
                    <fields>
                        <field>
                            <name>RMDB_LL</name>
                            <description>RX Message Buffer Data Byte (p × 4)</description>
                            <lsb>0</lsb>
                            <msb>7</msb>
                            <access>read-only</access>
                        </field>
                        <field>
                            <name>RMDB_LH</name>
                            <description>RX Message Buffer Data Byte ((p × 4) + 1)</description>
                            <lsb>8</lsb>
                            <msb>15</msb>
                            <access>read-only</access>
                        </field>
                        <field>
                            <name>RMDB_HL</name>
                            <description>RX Message Buffer Data Byte ((p × 4) + 2)</description>
                            <lsb>16</lsb>
                            <msb>23</msb>
                            <access>read-only</access>
                        </field>
                        <field>
                            <name>RMDB_HH</name>
                            <description>RX Message Buffer Data Byte ((p × 4) + 3)</description>
                            <lsb>24</lsb>
                            <msb>31</msb>
                            <access>read-only</access>
                        </field>
                    </fields>
                </register>
                <register>
                    <dim>8</dim>
                    <dimIncrement>0x004C</dimIncrement>
                    <dimIndex>0-7</dimIndex>
                    <name>CFDRMDF%s_3</name>
                    <description>RX Message Buffer Data Field 3 Registers</description>
                    <addressOffset>0x0938</addressOffset>
                    <size>32</size>
                    <access>read-only</access>
                    <resetValue>0x00000000</resetValue>
                    <resetMask>0xffffffff</resetMask>
                    <fields>
                        <field>
                            <name>RMDB_LL</name>
                            <description>RX Message Buffer Data Byte (p × 4)</description>
                            <lsb>0</lsb>
                            <msb>7</msb>
                            <access>read-only</access>
                        </field>
                        <field>
                            <name>RMDB_LH</name>
                            <description>RX Message Buffer Data Byte ((p × 4) + 1)</description>
                            <lsb>8</lsb>
                            <msb>15</msb>
                            <access>read-only</access>
                        </field>
                        <field>
                            <name>RMDB_HL</name>
                            <description>RX Message Buffer Data Byte ((p × 4) + 2)</description>
                            <lsb>16</lsb>
                            <msb>23</msb>
                            <access>read-only</access>
                        </field>
                        <field>
                            <name>RMDB_HH</name>
                            <description>RX Message Buffer Data Byte ((p × 4) + 3)</description>
                            <lsb>24</lsb>
                            <msb>31</msb>
                            <access>read-only</access>
                        </field>
                    </fields>
                </register>
                <register>
                    <dim>8</dim>
                    <dimIncrement>0x004C</dimIncrement>
                    <dimIndex>0-7</dimIndex>
                    <name>CFDRMDF%s_4</name>
                    <description>RX Message Buffer Data Field 4 Registers</description>
                    <addressOffset>0x093C</addressOffset>
                    <size>32</size>
                    <access>read-only</access>
                    <resetValue>0x00000000</resetValue>
                    <resetMask>0xffffffff</resetMask>
                    <fields>
                        <field>
                            <name>RMDB_LL</name>
                            <description>RX Message Buffer Data Byte (p × 4)</description>
                            <lsb>0</lsb>
                            <msb>7</msb>
                            <access>read-only</access>
                        </field>
                        <field>
                            <name>RMDB_LH</name>
                            <description>RX Message Buffer Data Byte ((p × 4) + 1)</description>
                            <lsb>8</lsb>
                            <msb>15</msb>
                            <access>read-only</access>
                        </field>
                        <field>
                            <name>RMDB_HL</name>
                            <description>RX Message Buffer Data Byte ((p × 4) + 2)</description>
                            <lsb>16</lsb>
                            <msb>23</msb>
                            <access>read-only</access>
                        </field>
                        <field>
                            <name>RMDB_HH</name>
                            <description>RX Message Buffer Data Byte ((p × 4) + 3)</description>
                            <lsb>24</lsb>
                            <msb>31</msb>
                            <access>read-only</access>
                        </field>
                    </fields>
                </register>
                <register>
                    <dim>8</dim>
                    <dimIncrement>0x004C</dimIncrement>
                    <dimIndex>0-7</dimIndex>
                    <name>CFDRMDF%s_5</name>
                    <description>RX Message Buffer Data Field 5 Registers</description>
                    <addressOffset>0x0940</addressOffset>
                    <size>32</size>
                    <access>read-only</access>
                    <resetValue>0x00000000</resetValue>
                    <resetMask>0xffffffff</resetMask>
                    <fields>
                        <field>
                            <name>RMDB_LL</name>
                            <description>RX Message Buffer Data Byte (p × 4)</description>
                            <lsb>0</lsb>
                            <msb>7</msb>
                            <access>read-only</access>
                        </field>
                        <field>
                            <name>RMDB_LH</name>
                            <description>RX Message Buffer Data Byte ((p × 4) + 1)</description>
                            <lsb>8</lsb>
                            <msb>15</msb>
                            <access>read-only</access>
                        </field>
                        <field>
                            <name>RMDB_HL</name>
                            <description>RX Message Buffer Data Byte ((p × 4) + 2)</description>
                            <lsb>16</lsb>
                            <msb>23</msb>
                            <access>read-only</access>
                        </field>
                        <field>
                            <name>RMDB_HH</name>
                            <description>RX Message Buffer Data Byte ((p × 4) + 3)</description>
                            <lsb>24</lsb>
                            <msb>31</msb>
                            <access>read-only</access>
                        </field>
                    </fields>
                </register>
                <register>
                    <dim>8</dim>
                    <dimIncrement>0x004C</dimIncrement>
                    <dimIndex>0-7</dimIndex>
                    <name>CFDRMDF%s_6</name>
                    <description>RX Message Buffer Data Field 6 Registers</description>
                    <addressOffset>0x0944</addressOffset>
                    <size>32</size>
                    <access>read-only</access>
                    <resetValue>0x00000000</resetValue>
                    <resetMask>0xffffffff</resetMask>
                    <fields>
                        <field>
                            <name>RMDB_LL</name>
                            <description>RX Message Buffer Data Byte (p × 4)</description>
                            <lsb>0</lsb>
                            <msb>7</msb>
                            <access>read-only</access>
                        </field>
                        <field>
                            <name>RMDB_LH</name>
                            <description>RX Message Buffer Data Byte ((p × 4) + 1)</description>
                            <lsb>8</lsb>
                            <msb>15</msb>
                            <access>read-only</access>
                        </field>
                        <field>
                            <name>RMDB_HL</name>
                            <description>RX Message Buffer Data Byte ((p × 4) + 2)</description>
                            <lsb>16</lsb>
                            <msb>23</msb>
                            <access>read-only</access>
                        </field>
                        <field>
                            <name>RMDB_HH</name>
                            <description>RX Message Buffer Data Byte ((p × 4) + 3)</description>
                            <lsb>24</lsb>
                            <msb>31</msb>
                            <access>read-only</access>
                        </field>
                    </fields>
                </register>
                <register>
                    <dim>8</dim>
                    <dimIncrement>0x004C</dimIncrement>
                    <dimIndex>0-7</dimIndex>
                    <name>CFDRMDF%s_7</name>
                    <description>RX Message Buffer Data Field 7 Registers</description>
                    <addressOffset>0x0948</addressOffset>
                    <size>32</size>
                    <access>read-only</access>
                    <resetValue>0x00000000</resetValue>
                    <resetMask>0xffffffff</resetMask>
                    <fields>
                        <field>
                            <name>RMDB_LL</name>
                            <description>RX Message Buffer Data Byte (p × 4)</description>
                            <lsb>0</lsb>
                            <msb>7</msb>
                            <access>read-only</access>
                        </field>
                        <field>
                            <name>RMDB_LH</name>
                            <description>RX Message Buffer Data Byte ((p × 4) + 1)</description>
                            <lsb>8</lsb>
                            <msb>15</msb>
                            <access>read-only</access>
                        </field>
                        <field>
                            <name>RMDB_HL</name>
                            <description>RX Message Buffer Data Byte ((p × 4) + 2)</description>
                            <lsb>16</lsb>
                            <msb>23</msb>
                            <access>read-only</access>
                        </field>
                        <field>
                            <name>RMDB_HH</name>
                            <description>RX Message Buffer Data Byte ((p × 4) + 3)</description>
                            <lsb>24</lsb>
                            <msb>31</msb>
                            <access>read-only</access>
                        </field>
                    </fields>
                </register>
                <register>
                    <dim>8</dim>
                    <dimIncrement>0x004C</dimIncrement>
                    <dimIndex>0-7</dimIndex>
                    <name>CFDRMDF%s_8</name>
                    <description>RX Message Buffer Data Field 8 Registers</description>
                    <addressOffset>0x094C</addressOffset>
                    <size>32</size>
                    <access>read-only</access>
                    <resetValue>0x00000000</resetValue>
                    <resetMask>0xffffffff</resetMask>
                    <fields>
                        <field>
                            <name>RMDB_LL</name>
                            <description>RX Message Buffer Data Byte (p × 4)</description>
                            <lsb>0</lsb>
                            <msb>7</msb>
                            <access>read-only</access>
                        </field>
                        <field>
                            <name>RMDB_LH</name>
                            <description>RX Message Buffer Data Byte ((p × 4) + 1)</description>
                            <lsb>8</lsb>
                            <msb>15</msb>
                            <access>read-only</access>
                        </field>
                        <field>
                            <name>RMDB_HL</name>
                            <description>RX Message Buffer Data Byte ((p × 4) + 2)</description>
                            <lsb>16</lsb>
                            <msb>23</msb>
                            <access>read-only</access>
                        </field>
                        <field>
                            <name>RMDB_HH</name>
                            <description>RX Message Buffer Data Byte ((p × 4) + 3)</description>
                            <lsb>24</lsb>
                            <msb>31</msb>
                            <access>read-only</access>
                        </field>
                    </fields>
                </register>
                <register>
                    <dim>8</dim>
                    <dimIncrement>0x004C</dimIncrement>
                    <dimIndex>0-7</dimIndex>
                    <name>CFDRMDF%s_9</name>
                    <description>RX Message Buffer Data Field 9 Registers</description>
                    <addressOffset>0x0950</addressOffset>
                    <size>32</size>
                    <access>read-only</access>
                    <resetValue>0x00000000</resetValue>
                    <resetMask>0xffffffff</resetMask>
                    <fields>
                        <field>
                            <name>RMDB_LL</name>
                            <description>RX Message Buffer Data Byte (p × 4)</description>
                            <lsb>0</lsb>
                            <msb>7</msb>
                            <access>read-only</access>
                        </field>
                        <field>
                            <name>RMDB_LH</name>
                            <description>RX Message Buffer Data Byte ((p × 4) + 1)</description>
                            <lsb>8</lsb>
                            <msb>15</msb>
                            <access>read-only</access>
                        </field>
                        <field>
                            <name>RMDB_HL</name>
                            <description>RX Message Buffer Data Byte ((p × 4) + 2)</description>
                            <lsb>16</lsb>
                            <msb>23</msb>
                            <access>read-only</access>
                        </field>
                        <field>
                            <name>RMDB_HH</name>
                            <description>RX Message Buffer Data Byte ((p × 4) + 3)</description>
                            <lsb>24</lsb>
                            <msb>31</msb>
                            <access>read-only</access>
                        </field>
                    </fields>
                </register>
                <register>
                    <dim>8</dim>
                    <dimIncrement>0x004C</dimIncrement>
                    <dimIndex>0-7</dimIndex>
                    <name>CFDRMDF%s_10</name>
                    <description>RX Message Buffer Data Field 10 Registers</description>
                    <addressOffset>0x0954</addressOffset>
                    <size>32</size>
                    <access>read-only</access>
                    <resetValue>0x00000000</resetValue>
                    <resetMask>0xffffffff</resetMask>
                    <fields>
                        <field>
                            <name>RMDB_LL</name>
                            <description>RX Message Buffer Data Byte (p × 4)</description>
                            <lsb>0</lsb>
                            <msb>7</msb>
                            <access>read-only</access>
                        </field>
                        <field>
                            <name>RMDB_LH</name>
                            <description>RX Message Buffer Data Byte ((p × 4) + 1)</description>
                            <lsb>8</lsb>
                            <msb>15</msb>
                            <access>read-only</access>
                        </field>
                        <field>
                            <name>RMDB_HL</name>
                            <description>RX Message Buffer Data Byte ((p × 4) + 2)</description>
                            <lsb>16</lsb>
                            <msb>23</msb>
                            <access>read-only</access>
                        </field>
                        <field>
                            <name>RMDB_HH</name>
                            <description>RX Message Buffer Data Byte ((p × 4) + 3)</description>
                            <lsb>24</lsb>
                            <msb>31</msb>
                            <access>read-only</access>
                        </field>
                    </fields>
                </register>
                <register>
                    <dim>8</dim>
                    <dimIncrement>0x004C</dimIncrement>
                    <dimIndex>0-7</dimIndex>
                    <name>CFDRMDF%s_11</name>
                    <description>RX Message Buffer Data Field 11 Registers</description>
                    <addressOffset>0x0958</addressOffset>
                    <size>32</size>
                    <access>read-only</access>
                    <resetValue>0x00000000</resetValue>
                    <resetMask>0xffffffff</resetMask>
                    <fields>
                        <field>
                            <name>RMDB_LL</name>
                            <description>RX Message Buffer Data Byte (p × 4)</description>
                            <lsb>0</lsb>
                            <msb>7</msb>
                            <access>read-only</access>
                        </field>
                        <field>
                            <name>RMDB_LH</name>
                            <description>RX Message Buffer Data Byte ((p × 4) + 1)</description>
                            <lsb>8</lsb>
                            <msb>15</msb>
                            <access>read-only</access>
                        </field>
                        <field>
                            <name>RMDB_HL</name>
                            <description>RX Message Buffer Data Byte ((p × 4) + 2)</description>
                            <lsb>16</lsb>
                            <msb>23</msb>
                            <access>read-only</access>
                        </field>
                        <field>
                            <name>RMDB_HH</name>
                            <description>RX Message Buffer Data Byte ((p × 4) + 3)</description>
                            <lsb>24</lsb>
                            <msb>31</msb>
                            <access>read-only</access>
                        </field>
                    </fields>
                </register>
                <register>
                    <dim>8</dim>
                    <dimIncrement>0x004C</dimIncrement>
                    <dimIndex>0-7</dimIndex>
                    <name>CFDRMDF%s_12</name>
                    <description>RX Message Buffer Data Field 12 Registers</description>
                    <addressOffset>0x095C</addressOffset>
                    <size>32</size>
                    <access>read-only</access>
                    <resetValue>0x00000000</resetValue>
                    <resetMask>0xffffffff</resetMask>
                    <fields>
                        <field>
                            <name>RMDB_LL</name>
                            <description>RX Message Buffer Data Byte (p × 4)</description>
                            <lsb>0</lsb>
                            <msb>7</msb>
                            <access>read-only</access>
                        </field>
                        <field>
                            <name>RMDB_LH</name>
                            <description>RX Message Buffer Data Byte ((p × 4) + 1)</description>
                            <lsb>8</lsb>
                            <msb>15</msb>
                            <access>read-only</access>
                        </field>
                        <field>
                            <name>RMDB_HL</name>
                            <description>RX Message Buffer Data Byte ((p × 4) + 2)</description>
                            <lsb>16</lsb>
                            <msb>23</msb>
                            <access>read-only</access>
                        </field>
                        <field>
                            <name>RMDB_HH</name>
                            <description>RX Message Buffer Data Byte ((p × 4) + 3)</description>
                            <lsb>24</lsb>
                            <msb>31</msb>
                            <access>read-only</access>
                        </field>
                    </fields>
                </register>
                <register>
                    <dim>8</dim>
                    <dimIncrement>0x004C</dimIncrement>
                    <dimIndex>0-7</dimIndex>
                    <name>CFDRMDF%s_13</name>
                    <description>RX Message Buffer Data Field 13 Registers</description>
                    <addressOffset>0x0960</addressOffset>
                    <size>32</size>
                    <access>read-only</access>
                    <resetValue>0x00000000</resetValue>
                    <resetMask>0xffffffff</resetMask>
                    <fields>
                        <field>
                            <name>RMDB_LL</name>
                            <description>RX Message Buffer Data Byte (p × 4)</description>
                            <lsb>0</lsb>
                            <msb>7</msb>
                            <access>read-only</access>
                        </field>
                        <field>
                            <name>RMDB_LH</name>
                            <description>RX Message Buffer Data Byte ((p × 4) + 1)</description>
                            <lsb>8</lsb>
                            <msb>15</msb>
                            <access>read-only</access>
                        </field>
                        <field>
                            <name>RMDB_HL</name>
                            <description>RX Message Buffer Data Byte ((p × 4) + 2)</description>
                            <lsb>16</lsb>
                            <msb>23</msb>
                            <access>read-only</access>
                        </field>
                        <field>
                            <name>RMDB_HH</name>
                            <description>RX Message Buffer Data Byte ((p × 4) + 3)</description>
                            <lsb>24</lsb>
                            <msb>31</msb>
                            <access>read-only</access>
                        </field>
                    </fields>
                </register>
                <register>
                    <dim>8</dim>
                    <dimIncrement>0x004C</dimIncrement>
                    <dimIndex>0-7</dimIndex>
                    <name>CFDRMDF%s_14</name>
                    <description>RX Message Buffer Data Field 14 Registers</description>
                    <addressOffset>0x0964</addressOffset>
                    <size>32</size>
                    <access>read-only</access>
                    <resetValue>0x00000000</resetValue>
                    <resetMask>0xffffffff</resetMask>
                    <fields>
                        <field>
                            <name>RMDB_LL</name>
                            <description>RX Message Buffer Data Byte (p × 4)</description>
                            <lsb>0</lsb>
                            <msb>7</msb>
                            <access>read-only</access>
                        </field>
                        <field>
                            <name>RMDB_LH</name>
                            <description>RX Message Buffer Data Byte ((p × 4) + 1)</description>
                            <lsb>8</lsb>
                            <msb>15</msb>
                            <access>read-only</access>
                        </field>
                        <field>
                            <name>RMDB_HL</name>
                            <description>RX Message Buffer Data Byte ((p × 4) + 2)</description>
                            <lsb>16</lsb>
                            <msb>23</msb>
                            <access>read-only</access>
                        </field>
                        <field>
                            <name>RMDB_HH</name>
                            <description>RX Message Buffer Data Byte ((p × 4) + 3)</description>
                            <lsb>24</lsb>
                            <msb>31</msb>
                            <access>read-only</access>
                        </field>
                    </fields>
                </register>
                <register>
                    <dim>8</dim>
                    <dimIncrement>0x004C</dimIncrement>
                    <dimIndex>0-7</dimIndex>
                    <name>CFDRMDF%s_15</name>
                    <description>RX Message Buffer Data Field 15 Registers</description>
                    <addressOffset>0x0968</addressOffset>
                    <size>32</size>
                    <access>read-only</access>
                    <resetValue>0x00000000</resetValue>
                    <resetMask>0xffffffff</resetMask>
                    <fields>
                        <field>
                            <name>RMDB_LL</name>
                            <description>RX Message Buffer Data Byte (p × 4)</description>
                            <lsb>0</lsb>
                            <msb>7</msb>
                            <access>read-only</access>
                        </field>
                        <field>
                            <name>RMDB_LH</name>
                            <description>RX Message Buffer Data Byte ((p × 4) + 1)</description>
                            <lsb>8</lsb>
                            <msb>15</msb>
                            <access>read-only</access>
                        </field>
                        <field>
                            <name>RMDB_HL</name>
                            <description>RX Message Buffer Data Byte ((p × 4) + 2)</description>
                            <lsb>16</lsb>
                            <msb>23</msb>
                            <access>read-only</access>
                        </field>
                        <field>
                            <name>RMDB_HH</name>
                            <description>RX Message Buffer Data Byte ((p × 4) + 3)</description>
                            <lsb>24</lsb>
                            <msb>31</msb>
                            <access>read-only</access>
                        </field>
                    </fields>
                </register>
                <register>
                    <dim>8</dim>
                    <dimIncrement>0x004C</dimIncrement>
                    <dimIndex>8-15</dimIndex>
                    <name>CFDRMID%s</name>
                    <description>RX Message Buffer ID Registers</description>
                    <addressOffset>0x0D20</addressOffset>
                    <size>32</size>
                    <access>read-only</access>
                    <resetValue>0x00000000</resetValue>
                    <resetMask>0xffffffff</resetMask>
                    <fields>
                        <field>
                            <name>RMID</name>
                            <description>RX Message Buffer ID Field</description>
                            <lsb>0</lsb>
                            <msb>28</msb>
                            <access>read-only</access>
                        </field>
                        <field>
                            <name>RMRTR</name>
                            <description>RX Message Buffer RTR Bit</description>
                            <lsb>30</lsb>
                            <msb>30</msb>
                            <access>read-only</access>
                            <enumeratedValues>
                                <enumeratedValue>
                                    <name>0</name>
                                    <description>Data frame</description>
                                    <value>#0</value>
                                </enumeratedValue>
                                <enumeratedValue>
                                    <name>1</name>
                                    <description>Remote frame</description>
                                    <value>#1</value>
                                </enumeratedValue>
                            </enumeratedValues>
                        </field>
                        <field>
                            <name>RMIDE</name>
                            <description>RX Message Buffer IDE Bit</description>
                            <lsb>31</lsb>
                            <msb>31</msb>
                            <access>read-only</access>
                            <enumeratedValues>
                                <enumeratedValue>
                                    <name>0</name>
                                    <description>STD-ID is stored</description>
                                    <value>#0</value>
                                </enumeratedValue>
                                <enumeratedValue>
                                    <name>1</name>
                                    <description>EXT-ID is stored</description>
                                    <value>#1</value>
                                </enumeratedValue>
                            </enumeratedValues>
                        </field>
                    </fields>
                </register>
                <register>
                    <dim>8</dim>
                    <dimIncrement>0x004C</dimIncrement>
                    <dimIndex>8-15</dimIndex>
                    <name>CFDRMPTR%s</name>
                    <description>RX Message Buffer Pointer Registers</description>
                    <addressOffset>0x0D24</addressOffset>
                    <size>32</size>
                    <access>read-only</access>
                    <resetValue>0x00000000</resetValue>
                    <resetMask>0xffffffff</resetMask>
                    <fields>
                        <field>
                            <name>RMTS</name>
                            <description>RX Message Buffer Timestamp Field</description>
                            <lsb>0</lsb>
                            <msb>15</msb>
                            <access>read-only</access>
                        </field>
                        <field>
                            <name>RMDLC</name>
                            <description>RX Message Buffer DLC Field</description>
                            <lsb>28</lsb>
                            <msb>31</msb>
                            <access>read-only</access>
                        </field>
                    </fields>
                </register>
                <register>
                    <dim>8</dim>
                    <dimIncrement>0x004C</dimIncrement>
                    <dimIndex>8-15</dimIndex>
                    <name>CFDRMFDSTS%s</name>
                    <description>RX Message Buffer CANFD Status Registers</description>
                    <addressOffset>0x0D28</addressOffset>
                    <size>32</size>
                    <access>read-only</access>
                    <resetValue>0x00000000</resetValue>
                    <resetMask>0xffffffff</resetMask>
                    <fields>
                        <field>
                            <name>RMESI</name>
                            <description>Error State Indicator bit</description>
                            <lsb>0</lsb>
                            <msb>0</msb>
                            <access>read-only</access>
                            <enumeratedValues>
                                <enumeratedValue>
                                    <name>0</name>
                                    <description>CANFD frame received from error active node</description>
                                    <value>#0</value>
                                </enumeratedValue>
                                <enumeratedValue>
                                    <name>1</name>
                                    <description>CANFD frame received from error passive node</description>
                                    <value>#1</value>
                                </enumeratedValue>
                            </enumeratedValues>
                        </field>
                        <field>
                            <name>RMBRS</name>
                            <description>Bit Rate Switch bit</description>
                            <lsb>1</lsb>
                            <msb>1</msb>
                            <access>read-only</access>
                            <enumeratedValues>
                                <enumeratedValue>
                                    <name>0</name>
                                    <description>CANFD frame received with no bit rate switch</description>
                                    <value>#0</value>
                                </enumeratedValue>
                                <enumeratedValue>
                                    <name>1</name>
                                    <description>CANFD frame received with bit rate switch</description>
                                    <value>#1</value>
                                </enumeratedValue>
                            </enumeratedValues>
                        </field>
                        <field>
                            <name>RMFDF</name>
                            <description>CAN FD Format bit</description>
                            <lsb>2</lsb>
                            <msb>2</msb>
                            <access>read-only</access>
                            <enumeratedValues>
                                <enumeratedValue>
                                    <name>0</name>
                                    <description>Non CANFD frame received</description>
                                    <value>#0</value>
                                </enumeratedValue>
                                <enumeratedValue>
                                    <name>1</name>
                                    <description>CANFD frame received</description>
                                    <value>#1</value>
                                </enumeratedValue>
                            </enumeratedValues>
                        </field>
                        <field>
                            <name>RMIFL</name>
                            <description>RX Message Buffer Information Label Field</description>
                            <lsb>8</lsb>
                            <msb>9</msb>
                            <access>read-only</access>
                        </field>
                        <field>
                            <name>RMPTR</name>
                            <description>RX Message Buffer Pointer Field</description>
                            <lsb>16</lsb>
                            <msb>31</msb>
                            <access>read-only</access>
                        </field>
                    </fields>
                </register>
                <register>
                    <dim>8</dim>
                    <dimIncrement>0x004C</dimIncrement>
                    <dimIndex>8-15</dimIndex>
                    <name>CFDRMDF%s_0</name>
                    <description>RX Message Buffer Data Field 0 Registers</description>
                    <addressOffset>0x0D2C</addressOffset>
                    <size>32</size>
                    <access>read-only</access>
                    <resetValue>0x00000000</resetValue>
                    <resetMask>0xffffffff</resetMask>
                    <fields>
                        <field>
                            <name>RMDB_LL</name>
                            <description>RX Message Buffer Data Byte (p × 4)</description>
                            <lsb>0</lsb>
                            <msb>7</msb>
                            <access>read-only</access>
                        </field>
                        <field>
                            <name>RMDB_LH</name>
                            <description>RX Message Buffer Data Byte ((p × 4) + 1)</description>
                            <lsb>8</lsb>
                            <msb>15</msb>
                            <access>read-only</access>
                        </field>
                        <field>
                            <name>RMDB_HL</name>
                            <description>RX Message Buffer Data Byte ((p × 4) + 2)</description>
                            <lsb>16</lsb>
                            <msb>23</msb>
                            <access>read-only</access>
                        </field>
                        <field>
                            <name>RMDB_HH</name>
                            <description>RX Message Buffer Data Byte ((p × 4) + 3)</description>
                            <lsb>24</lsb>
                            <msb>31</msb>
                            <access>read-only</access>
                        </field>
                    </fields>
                </register>
                <register>
                    <dim>8</dim>
                    <dimIncrement>0x004C</dimIncrement>
                    <dimIndex>8-15</dimIndex>
                    <name>CFDRMDF%s_1</name>
                    <description>RX Message Buffer Data Field 1 Registers</description>
                    <addressOffset>0x0D30</addressOffset>
                    <size>32</size>
                    <access>read-only</access>
                    <resetValue>0x00000000</resetValue>
                    <resetMask>0xffffffff</resetMask>
                    <fields>
                        <field>
                            <name>RMDB_LL</name>
                            <description>RX Message Buffer Data Byte (p × 4)</description>
                            <lsb>0</lsb>
                            <msb>7</msb>
                            <access>read-only</access>
                        </field>
                        <field>
                            <name>RMDB_LH</name>
                            <description>RX Message Buffer Data Byte ((p × 4) + 1)</description>
                            <lsb>8</lsb>
                            <msb>15</msb>
                            <access>read-only</access>
                        </field>
                        <field>
                            <name>RMDB_HL</name>
                            <description>RX Message Buffer Data Byte ((p × 4) + 2)</description>
                            <lsb>16</lsb>
                            <msb>23</msb>
                            <access>read-only</access>
                        </field>
                        <field>
                            <name>RMDB_HH</name>
                            <description>RX Message Buffer Data Byte ((p × 4) + 3)</description>
                            <lsb>24</lsb>
                            <msb>31</msb>
                            <access>read-only</access>
                        </field>
                    </fields>
                </register>
                <register>
                    <dim>8</dim>
                    <dimIncrement>0x004C</dimIncrement>
                    <dimIndex>8-15</dimIndex>
                    <name>CFDRMDF%s_2</name>
                    <description>RX Message Buffer Data Field 2 Registers</description>
                    <addressOffset>0x0D34</addressOffset>
                    <size>32</size>
                    <access>read-only</access>
                    <resetValue>0x00000000</resetValue>
                    <resetMask>0xffffffff</resetMask>
                    <fields>
                        <field>
                            <name>RMDB_LL</name>
                            <description>RX Message Buffer Data Byte (p × 4)</description>
                            <lsb>0</lsb>
                            <msb>7</msb>
                            <access>read-only</access>
                        </field>
                        <field>
                            <name>RMDB_LH</name>
                            <description>RX Message Buffer Data Byte ((p × 4) + 1)</description>
                            <lsb>8</lsb>
                            <msb>15</msb>
                            <access>read-only</access>
                        </field>
                        <field>
                            <name>RMDB_HL</name>
                            <description>RX Message Buffer Data Byte ((p × 4) + 2)</description>
                            <lsb>16</lsb>
                            <msb>23</msb>
                            <access>read-only</access>
                        </field>
                        <field>
                            <name>RMDB_HH</name>
                            <description>RX Message Buffer Data Byte ((p × 4) + 3)</description>
                            <lsb>24</lsb>
                            <msb>31</msb>
                            <access>read-only</access>
                        </field>
                    </fields>
                </register>
                <register>
                    <dim>8</dim>
                    <dimIncrement>0x004C</dimIncrement>
                    <dimIndex>8-15</dimIndex>
                    <name>CFDRMDF%s_3</name>
                    <description>RX Message Buffer Data Field 3 Registers</description>
                    <addressOffset>0x0D38</addressOffset>
                    <size>32</size>
                    <access>read-only</access>
                    <resetValue>0x00000000</resetValue>
                    <resetMask>0xffffffff</resetMask>
                    <fields>
                        <field>
                            <name>RMDB_LL</name>
                            <description>RX Message Buffer Data Byte (p × 4)</description>
                            <lsb>0</lsb>
                            <msb>7</msb>
                            <access>read-only</access>
                        </field>
                        <field>
                            <name>RMDB_LH</name>
                            <description>RX Message Buffer Data Byte ((p × 4) + 1)</description>
                            <lsb>8</lsb>
                            <msb>15</msb>
                            <access>read-only</access>
                        </field>
                        <field>
                            <name>RMDB_HL</name>
                            <description>RX Message Buffer Data Byte ((p × 4) + 2)</description>
                            <lsb>16</lsb>
                            <msb>23</msb>
                            <access>read-only</access>
                        </field>
                        <field>
                            <name>RMDB_HH</name>
                            <description>RX Message Buffer Data Byte ((p × 4) + 3)</description>
                            <lsb>24</lsb>
                            <msb>31</msb>
                            <access>read-only</access>
                        </field>
                    </fields>
                </register>
                <register>
                    <dim>8</dim>
                    <dimIncrement>0x004C</dimIncrement>
                    <dimIndex>8-15</dimIndex>
                    <name>CFDRMDF%s_4</name>
                    <description>RX Message Buffer Data Field 4 Registers</description>
                    <addressOffset>0x0D3C</addressOffset>
                    <size>32</size>
                    <access>read-only</access>
                    <resetValue>0x00000000</resetValue>
                    <resetMask>0xffffffff</resetMask>
                    <fields>
                        <field>
                            <name>RMDB_LL</name>
                            <description>RX Message Buffer Data Byte (p × 4)</description>
                            <lsb>0</lsb>
                            <msb>7</msb>
                            <access>read-only</access>
                        </field>
                        <field>
                            <name>RMDB_LH</name>
                            <description>RX Message Buffer Data Byte ((p × 4) + 1)</description>
                            <lsb>8</lsb>
                            <msb>15</msb>
                            <access>read-only</access>
                        </field>
                        <field>
                            <name>RMDB_HL</name>
                            <description>RX Message Buffer Data Byte ((p × 4) + 2)</description>
                            <lsb>16</lsb>
                            <msb>23</msb>
                            <access>read-only</access>
                        </field>
                        <field>
                            <name>RMDB_HH</name>
                            <description>RX Message Buffer Data Byte ((p × 4) + 3)</description>
                            <lsb>24</lsb>
                            <msb>31</msb>
                            <access>read-only</access>
                        </field>
                    </fields>
                </register>
                <register>
                    <dim>8</dim>
                    <dimIncrement>0x004C</dimIncrement>
                    <dimIndex>8-15</dimIndex>
                    <name>CFDRMDF%s_5</name>
                    <description>RX Message Buffer Data Field 5 Registers</description>
                    <addressOffset>0x0D40</addressOffset>
                    <size>32</size>
                    <access>read-only</access>
                    <resetValue>0x00000000</resetValue>
                    <resetMask>0xffffffff</resetMask>
                    <fields>
                        <field>
                            <name>RMDB_LL</name>
                            <description>RX Message Buffer Data Byte (p × 4)</description>
                            <lsb>0</lsb>
                            <msb>7</msb>
                            <access>read-only</access>
                        </field>
                        <field>
                            <name>RMDB_LH</name>
                            <description>RX Message Buffer Data Byte ((p × 4) + 1)</description>
                            <lsb>8</lsb>
                            <msb>15</msb>
                            <access>read-only</access>
                        </field>
                        <field>
                            <name>RMDB_HL</name>
                            <description>RX Message Buffer Data Byte ((p × 4) + 2)</description>
                            <lsb>16</lsb>
                            <msb>23</msb>
                            <access>read-only</access>
                        </field>
                        <field>
                            <name>RMDB_HH</name>
                            <description>RX Message Buffer Data Byte ((p × 4) + 3)</description>
                            <lsb>24</lsb>
                            <msb>31</msb>
                            <access>read-only</access>
                        </field>
                    </fields>
                </register>
                <register>
                    <dim>8</dim>
                    <dimIncrement>0x004C</dimIncrement>
                    <dimIndex>8-15</dimIndex>
                    <name>CFDRMDF%s_6</name>
                    <description>RX Message Buffer Data Field 6 Registers</description>
                    <addressOffset>0x0D44</addressOffset>
                    <size>32</size>
                    <access>read-only</access>
                    <resetValue>0x00000000</resetValue>
                    <resetMask>0xffffffff</resetMask>
                    <fields>
                        <field>
                            <name>RMDB_LL</name>
                            <description>RX Message Buffer Data Byte (p × 4)</description>
                            <lsb>0</lsb>
                            <msb>7</msb>
                            <access>read-only</access>
                        </field>
                        <field>
                            <name>RMDB_LH</name>
                            <description>RX Message Buffer Data Byte ((p × 4) + 1)</description>
                            <lsb>8</lsb>
                            <msb>15</msb>
                            <access>read-only</access>
                        </field>
                        <field>
                            <name>RMDB_HL</name>
                            <description>RX Message Buffer Data Byte ((p × 4) + 2)</description>
                            <lsb>16</lsb>
                            <msb>23</msb>
                            <access>read-only</access>
                        </field>
                        <field>
                            <name>RMDB_HH</name>
                            <description>RX Message Buffer Data Byte ((p × 4) + 3)</description>
                            <lsb>24</lsb>
                            <msb>31</msb>
                            <access>read-only</access>
                        </field>
                    </fields>
                </register>
                <register>
                    <dim>8</dim>
                    <dimIncrement>0x004C</dimIncrement>
                    <dimIndex>8-15</dimIndex>
                    <name>CFDRMDF%s_7</name>
                    <description>RX Message Buffer Data Field 7 Registers</description>
                    <addressOffset>0x0D48</addressOffset>
                    <size>32</size>
                    <access>read-only</access>
                    <resetValue>0x00000000</resetValue>
                    <resetMask>0xffffffff</resetMask>
                    <fields>
                        <field>
                            <name>RMDB_LL</name>
                            <description>RX Message Buffer Data Byte (p × 4)</description>
                            <lsb>0</lsb>
                            <msb>7</msb>
                            <access>read-only</access>
                        </field>
                        <field>
                            <name>RMDB_LH</name>
                            <description>RX Message Buffer Data Byte ((p × 4) + 1)</description>
                            <lsb>8</lsb>
                            <msb>15</msb>
                            <access>read-only</access>
                        </field>
                        <field>
                            <name>RMDB_HL</name>
                            <description>RX Message Buffer Data Byte ((p × 4) + 2)</description>
                            <lsb>16</lsb>
                            <msb>23</msb>
                            <access>read-only</access>
                        </field>
                        <field>
                            <name>RMDB_HH</name>
                            <description>RX Message Buffer Data Byte ((p × 4) + 3)</description>
                            <lsb>24</lsb>
                            <msb>31</msb>
                            <access>read-only</access>
                        </field>
                    </fields>
                </register>
                <register>
                    <dim>8</dim>
                    <dimIncrement>0x004C</dimIncrement>
                    <dimIndex>8-15</dimIndex>
                    <name>CFDRMDF%s_8</name>
                    <description>RX Message Buffer Data Field 8 Registers</description>
                    <addressOffset>0x0D4C</addressOffset>
                    <size>32</size>
                    <access>read-only</access>
                    <resetValue>0x00000000</resetValue>
                    <resetMask>0xffffffff</resetMask>
                    <fields>
                        <field>
                            <name>RMDB_LL</name>
                            <description>RX Message Buffer Data Byte (p × 4)</description>
                            <lsb>0</lsb>
                            <msb>7</msb>
                            <access>read-only</access>
                        </field>
                        <field>
                            <name>RMDB_LH</name>
                            <description>RX Message Buffer Data Byte ((p × 4) + 1)</description>
                            <lsb>8</lsb>
                            <msb>15</msb>
                            <access>read-only</access>
                        </field>
                        <field>
                            <name>RMDB_HL</name>
                            <description>RX Message Buffer Data Byte ((p × 4) + 2)</description>
                            <lsb>16</lsb>
                            <msb>23</msb>
                            <access>read-only</access>
                        </field>
                        <field>
                            <name>RMDB_HH</name>
                            <description>RX Message Buffer Data Byte ((p × 4) + 3)</description>
                            <lsb>24</lsb>
                            <msb>31</msb>
                            <access>read-only</access>
                        </field>
                    </fields>
                </register>
                <register>
                    <dim>8</dim>
                    <dimIncrement>0x004C</dimIncrement>
                    <dimIndex>8-15</dimIndex>
                    <name>CFDRMDF%s_9</name>
                    <description>RX Message Buffer Data Field 9 Registers</description>
                    <addressOffset>0x0D50</addressOffset>
                    <size>32</size>
                    <access>read-only</access>
                    <resetValue>0x00000000</resetValue>
                    <resetMask>0xffffffff</resetMask>
                    <fields>
                        <field>
                            <name>RMDB_LL</name>
                            <description>RX Message Buffer Data Byte (p × 4)</description>
                            <lsb>0</lsb>
                            <msb>7</msb>
                            <access>read-only</access>
                        </field>
                        <field>
                            <name>RMDB_LH</name>
                            <description>RX Message Buffer Data Byte ((p × 4) + 1)</description>
                            <lsb>8</lsb>
                            <msb>15</msb>
                            <access>read-only</access>
                        </field>
                        <field>
                            <name>RMDB_HL</name>
                            <description>RX Message Buffer Data Byte ((p × 4) + 2)</description>
                            <lsb>16</lsb>
                            <msb>23</msb>
                            <access>read-only</access>
                        </field>
                        <field>
                            <name>RMDB_HH</name>
                            <description>RX Message Buffer Data Byte ((p × 4) + 3)</description>
                            <lsb>24</lsb>
                            <msb>31</msb>
                            <access>read-only</access>
                        </field>
                    </fields>
                </register>
                <register>
                    <dim>8</dim>
                    <dimIncrement>0x004C</dimIncrement>
                    <dimIndex>8-15</dimIndex>
                    <name>CFDRMDF%s_10</name>
                    <description>RX Message Buffer Data Field 10 Registers</description>
                    <addressOffset>0x0D54</addressOffset>
                    <size>32</size>
                    <access>read-only</access>
                    <resetValue>0x00000000</resetValue>
                    <resetMask>0xffffffff</resetMask>
                    <fields>
                        <field>
                            <name>RMDB_LL</name>
                            <description>RX Message Buffer Data Byte (p × 4)</description>
                            <lsb>0</lsb>
                            <msb>7</msb>
                            <access>read-only</access>
                        </field>
                        <field>
                            <name>RMDB_LH</name>
                            <description>RX Message Buffer Data Byte ((p × 4) + 1)</description>
                            <lsb>8</lsb>
                            <msb>15</msb>
                            <access>read-only</access>
                        </field>
                        <field>
                            <name>RMDB_HL</name>
                            <description>RX Message Buffer Data Byte ((p × 4) + 2)</description>
                            <lsb>16</lsb>
                            <msb>23</msb>
                            <access>read-only</access>
                        </field>
                        <field>
                            <name>RMDB_HH</name>
                            <description>RX Message Buffer Data Byte ((p × 4) + 3)</description>
                            <lsb>24</lsb>
                            <msb>31</msb>
                            <access>read-only</access>
                        </field>
                    </fields>
                </register>
                <register>
                    <dim>8</dim>
                    <dimIncrement>0x004C</dimIncrement>
                    <dimIndex>8-15</dimIndex>
                    <name>CFDRMDF%s_11</name>
                    <description>RX Message Buffer Data Field 11 Registers</description>
                    <addressOffset>0x0D58</addressOffset>
                    <size>32</size>
                    <access>read-only</access>
                    <resetValue>0x00000000</resetValue>
                    <resetMask>0xffffffff</resetMask>
                    <fields>
                        <field>
                            <name>RMDB_LL</name>
                            <description>RX Message Buffer Data Byte (p × 4)</description>
                            <lsb>0</lsb>
                            <msb>7</msb>
                            <access>read-only</access>
                        </field>
                        <field>
                            <name>RMDB_LH</name>
                            <description>RX Message Buffer Data Byte ((p × 4) + 1)</description>
                            <lsb>8</lsb>
                            <msb>15</msb>
                            <access>read-only</access>
                        </field>
                        <field>
                            <name>RMDB_HL</name>
                            <description>RX Message Buffer Data Byte ((p × 4) + 2)</description>
                            <lsb>16</lsb>
                            <msb>23</msb>
                            <access>read-only</access>
                        </field>
                        <field>
                            <name>RMDB_HH</name>
                            <description>RX Message Buffer Data Byte ((p × 4) + 3)</description>
                            <lsb>24</lsb>
                            <msb>31</msb>
                            <access>read-only</access>
                        </field>
                    </fields>
                </register>
                <register>
                    <dim>8</dim>
                    <dimIncrement>0x004C</dimIncrement>
                    <dimIndex>8-15</dimIndex>
                    <name>CFDRMDF%s_12</name>
                    <description>RX Message Buffer Data Field 12 Registers</description>
                    <addressOffset>0x0D5C</addressOffset>
                    <size>32</size>
                    <access>read-only</access>
                    <resetValue>0x00000000</resetValue>
                    <resetMask>0xffffffff</resetMask>
                    <fields>
                        <field>
                            <name>RMDB_LL</name>
                            <description>RX Message Buffer Data Byte (p × 4)</description>
                            <lsb>0</lsb>
                            <msb>7</msb>
                            <access>read-only</access>
                        </field>
                        <field>
                            <name>RMDB_LH</name>
                            <description>RX Message Buffer Data Byte ((p × 4) + 1)</description>
                            <lsb>8</lsb>
                            <msb>15</msb>
                            <access>read-only</access>
                        </field>
                        <field>
                            <name>RMDB_HL</name>
                            <description>RX Message Buffer Data Byte ((p × 4) + 2)</description>
                            <lsb>16</lsb>
                            <msb>23</msb>
                            <access>read-only</access>
                        </field>
                        <field>
                            <name>RMDB_HH</name>
                            <description>RX Message Buffer Data Byte ((p × 4) + 3)</description>
                            <lsb>24</lsb>
                            <msb>31</msb>
                            <access>read-only</access>
                        </field>
                    </fields>
                </register>
                <register>
                    <dim>8</dim>
                    <dimIncrement>0x004C</dimIncrement>
                    <dimIndex>8-15</dimIndex>
                    <name>CFDRMDF%s_13</name>
                    <description>RX Message Buffer Data Field 13 Registers</description>
                    <addressOffset>0x0D60</addressOffset>
                    <size>32</size>
                    <access>read-only</access>
                    <resetValue>0x00000000</resetValue>
                    <resetMask>0xffffffff</resetMask>
                    <fields>
                        <field>
                            <name>RMDB_LL</name>
                            <description>RX Message Buffer Data Byte (p × 4)</description>
                            <lsb>0</lsb>
                            <msb>7</msb>
                            <access>read-only</access>
                        </field>
                        <field>
                            <name>RMDB_LH</name>
                            <description>RX Message Buffer Data Byte ((p × 4) + 1)</description>
                            <lsb>8</lsb>
                            <msb>15</msb>
                            <access>read-only</access>
                        </field>
                        <field>
                            <name>RMDB_HL</name>
                            <description>RX Message Buffer Data Byte ((p × 4) + 2)</description>
                            <lsb>16</lsb>
                            <msb>23</msb>
                            <access>read-only</access>
                        </field>
                        <field>
                            <name>RMDB_HH</name>
                            <description>RX Message Buffer Data Byte ((p × 4) + 3)</description>
                            <lsb>24</lsb>
                            <msb>31</msb>
                            <access>read-only</access>
                        </field>
                    </fields>
                </register>
                <register>
                    <dim>8</dim>
                    <dimIncrement>0x004C</dimIncrement>
                    <dimIndex>8-15</dimIndex>
                    <name>CFDRMDF%s_14</name>
                    <description>RX Message Buffer Data Field 14 Registers</description>
                    <addressOffset>0x0D64</addressOffset>
                    <size>32</size>
                    <access>read-only</access>
                    <resetValue>0x00000000</resetValue>
                    <resetMask>0xffffffff</resetMask>
                    <fields>
                        <field>
                            <name>RMDB_LL</name>
                            <description>RX Message Buffer Data Byte (p × 4)</description>
                            <lsb>0</lsb>
                            <msb>7</msb>
                            <access>read-only</access>
                        </field>
                        <field>
                            <name>RMDB_LH</name>
                            <description>RX Message Buffer Data Byte ((p × 4) + 1)</description>
                            <lsb>8</lsb>
                            <msb>15</msb>
                            <access>read-only</access>
                        </field>
                        <field>
                            <name>RMDB_HL</name>
                            <description>RX Message Buffer Data Byte ((p × 4) + 2)</description>
                            <lsb>16</lsb>
                            <msb>23</msb>
                            <access>read-only</access>
                        </field>
                        <field>
                            <name>RMDB_HH</name>
                            <description>RX Message Buffer Data Byte ((p × 4) + 3)</description>
                            <lsb>24</lsb>
                            <msb>31</msb>
                            <access>read-only</access>
                        </field>
                    </fields>
                </register>
                <register>
                    <dim>8</dim>
                    <dimIncrement>0x004C</dimIncrement>
                    <dimIndex>8-15</dimIndex>
                    <name>CFDRMDF%s_15</name>
                    <description>RX Message Buffer Data Field 15 Registers</description>
                    <addressOffset>0x0D68</addressOffset>
                    <size>32</size>
                    <access>read-only</access>
                    <resetValue>0x00000000</resetValue>
                    <resetMask>0xffffffff</resetMask>
                    <fields>
                        <field>
                            <name>RMDB_LL</name>
                            <description>RX Message Buffer Data Byte (p × 4)</description>
                            <lsb>0</lsb>
                            <msb>7</msb>
                            <access>read-only</access>
                        </field>
                        <field>
                            <name>RMDB_LH</name>
                            <description>RX Message Buffer Data Byte ((p × 4) + 1)</description>
                            <lsb>8</lsb>
                            <msb>15</msb>
                            <access>read-only</access>
                        </field>
                        <field>
                            <name>RMDB_HL</name>
                            <description>RX Message Buffer Data Byte ((p × 4) + 2)</description>
                            <lsb>16</lsb>
                            <msb>23</msb>
                            <access>read-only</access>
                        </field>
                        <field>
                            <name>RMDB_HH</name>
                            <description>RX Message Buffer Data Byte ((p × 4) + 3)</description>
                            <lsb>24</lsb>
                            <msb>31</msb>
                            <access>read-only</access>
                        </field>
                    </fields>
                </register>
                <register>
                    <dim>8</dim>
                    <dimIncrement>0x004C</dimIncrement>
                    <dimIndex>16-23</dimIndex>
                    <name>CFDRMPTR%s</name>
                    <description>RX Message Buffer Pointer Registers</description>
                    <addressOffset>0x01124</addressOffset>
                    <size>32</size>
                    <access>read-only</access>
                    <resetValue>0x00000000</resetValue>
                    <resetMask>0xffffffff</resetMask>
                    <fields>
                        <field>
                            <name>RMTS</name>
                            <description>RX Message Buffer Timestamp Field</description>
                            <lsb>0</lsb>
                            <msb>15</msb>
                            <access>read-only</access>
                        </field>
                        <field>
                            <name>RMDLC</name>
                            <description>RX Message Buffer DLC Field</description>
                            <lsb>28</lsb>
                            <msb>31</msb>
                            <access>read-only</access>
                        </field>
                    </fields>
                </register>
                <register>
                    <dim>8</dim>
                    <dimIncrement>0x004C</dimIncrement>
                    <dimIndex>16-23</dimIndex>
                    <name>CFDRMFDSTS%s</name>
                    <description>RX Message Buffer CANFD Status Registers</description>
                    <addressOffset>0x01128</addressOffset>
                    <size>32</size>
                    <access>read-only</access>
                    <resetValue>0x00000000</resetValue>
                    <resetMask>0xffffffff</resetMask>
                    <fields>
                        <field>
                            <name>RMESI</name>
                            <description>Error State Indicator bit</description>
                            <lsb>0</lsb>
                            <msb>0</msb>
                            <access>read-only</access>
                            <enumeratedValues>
                                <enumeratedValue>
                                    <name>0</name>
                                    <description>CANFD frame received from error active node</description>
                                    <value>#0</value>
                                </enumeratedValue>
                                <enumeratedValue>
                                    <name>1</name>
                                    <description>CANFD frame received from error passive node</description>
                                    <value>#1</value>
                                </enumeratedValue>
                            </enumeratedValues>
                        </field>
                        <field>
                            <name>RMBRS</name>
                            <description>Bit Rate Switch bit</description>
                            <lsb>1</lsb>
                            <msb>1</msb>
                            <access>read-only</access>
                            <enumeratedValues>
                                <enumeratedValue>
                                    <name>0</name>
                                    <description>CANFD frame received with no bit rate switch</description>
                                    <value>#0</value>
                                </enumeratedValue>
                                <enumeratedValue>
                                    <name>1</name>
                                    <description>CANFD frame received with bit rate switch</description>
                                    <value>#1</value>
                                </enumeratedValue>
                            </enumeratedValues>
                        </field>
                        <field>
                            <name>RMFDF</name>
                            <description>CAN FD Format bit</description>
                            <lsb>2</lsb>
                            <msb>2</msb>
                            <access>read-only</access>
                            <enumeratedValues>
                                <enumeratedValue>
                                    <name>0</name>
                                    <description>Non CANFD frame received</description>
                                    <value>#0</value>
                                </enumeratedValue>
                                <enumeratedValue>
                                    <name>1</name>
                                    <description>CANFD frame received</description>
                                    <value>#1</value>
                                </enumeratedValue>
                            </enumeratedValues>
                        </field>
                        <field>
                            <name>RMIFL</name>
                            <description>RX Message Buffer Information Label Field</description>
                            <lsb>8</lsb>
                            <msb>9</msb>
                            <access>read-only</access>
                        </field>
                        <field>
                            <name>RMPTR</name>
                            <description>RX Message Buffer Pointer Field</description>
                            <lsb>16</lsb>
                            <msb>31</msb>
                            <access>read-only</access>
                        </field>
                    </fields>
                </register>
                <register>
                    <dim>8</dim>
                    <dimIncrement>0x004C</dimIncrement>
                    <dimIndex>16-23</dimIndex>
                    <name>CFDRMDF%s_0</name>
                    <description>RX Message Buffer Data Field 0 Registers</description>
                    <addressOffset>0x112C</addressOffset>
                    <size>32</size>
                    <access>read-only</access>
                    <resetValue>0x00000000</resetValue>
                    <resetMask>0xffffffff</resetMask>
                    <fields>
                        <field>
                            <name>RMDB_LL</name>
                            <description>RX Message Buffer Data Byte (p × 4)</description>
                            <lsb>0</lsb>
                            <msb>7</msb>
                            <access>read-only</access>
                        </field>
                        <field>
                            <name>RMDB_LH</name>
                            <description>RX Message Buffer Data Byte ((p × 4) + 1)</description>
                            <lsb>8</lsb>
                            <msb>15</msb>
                            <access>read-only</access>
                        </field>
                        <field>
                            <name>RMDB_HL</name>
                            <description>RX Message Buffer Data Byte ((p × 4) + 2)</description>
                            <lsb>16</lsb>
                            <msb>23</msb>
                            <access>read-only</access>
                        </field>
                        <field>
                            <name>RMDB_HH</name>
                            <description>RX Message Buffer Data Byte ((p × 4) + 3)</description>
                            <lsb>24</lsb>
                            <msb>31</msb>
                            <access>read-only</access>
                        </field>
                    </fields>
                </register>
                <register>
                    <dim>8</dim>
                    <dimIncrement>0x004C</dimIncrement>
                    <dimIndex>16-23</dimIndex>
                    <name>CFDRMDF%s_1</name>
                    <description>RX Message Buffer Data Field 1 Registers</description>
                    <addressOffset>0x1130</addressOffset>
                    <size>32</size>
                    <access>read-only</access>
                    <resetValue>0x00000000</resetValue>
                    <resetMask>0xffffffff</resetMask>
                    <fields>
                        <field>
                            <name>RMDB_LL</name>
                            <description>RX Message Buffer Data Byte (p × 4)</description>
                            <lsb>0</lsb>
                            <msb>7</msb>
                            <access>read-only</access>
                        </field>
                        <field>
                            <name>RMDB_LH</name>
                            <description>RX Message Buffer Data Byte ((p × 4) + 1)</description>
                            <lsb>8</lsb>
                            <msb>15</msb>
                            <access>read-only</access>
                        </field>
                        <field>
                            <name>RMDB_HL</name>
                            <description>RX Message Buffer Data Byte ((p × 4) + 2)</description>
                            <lsb>16</lsb>
                            <msb>23</msb>
                            <access>read-only</access>
                        </field>
                        <field>
                            <name>RMDB_HH</name>
                            <description>RX Message Buffer Data Byte ((p × 4) + 3)</description>
                            <lsb>24</lsb>
                            <msb>31</msb>
                            <access>read-only</access>
                        </field>
                    </fields>
                </register>
                <register>
                    <dim>8</dim>
                    <dimIncrement>0x004C</dimIncrement>
                    <dimIndex>16-23</dimIndex>
                    <name>CFDRMDF%s_2</name>
                    <description>RX Message Buffer Data Field 2 Registers</description>
                    <addressOffset>0x1134</addressOffset>
                    <size>32</size>
                    <access>read-only</access>
                    <resetValue>0x00000000</resetValue>
                    <resetMask>0xffffffff</resetMask>
                    <fields>
                        <field>
                            <name>RMDB_LL</name>
                            <description>RX Message Buffer Data Byte (p × 4)</description>
                            <lsb>0</lsb>
                            <msb>7</msb>
                            <access>read-only</access>
                        </field>
                        <field>
                            <name>RMDB_LH</name>
                            <description>RX Message Buffer Data Byte ((p × 4) + 1)</description>
                            <lsb>8</lsb>
                            <msb>15</msb>
                            <access>read-only</access>
                        </field>
                        <field>
                            <name>RMDB_HL</name>
                            <description>RX Message Buffer Data Byte ((p × 4) + 2)</description>
                            <lsb>16</lsb>
                            <msb>23</msb>
                            <access>read-only</access>
                        </field>
                        <field>
                            <name>RMDB_HH</name>
                            <description>RX Message Buffer Data Byte ((p × 4) + 3)</description>
                            <lsb>24</lsb>
                            <msb>31</msb>
                            <access>read-only</access>
                        </field>
                    </fields>
                </register>
                <register>
                    <dim>8</dim>
                    <dimIncrement>0x004C</dimIncrement>
                    <dimIndex>16-23</dimIndex>
                    <name>CFDRMDF%s_3</name>
                    <description>RX Message Buffer Data Field 3 Registers</description>
                    <addressOffset>0x1138</addressOffset>
                    <size>32</size>
                    <access>read-only</access>
                    <resetValue>0x00000000</resetValue>
                    <resetMask>0xffffffff</resetMask>
                    <fields>
                        <field>
                            <name>RMDB_LL</name>
                            <description>RX Message Buffer Data Byte (p × 4)</description>
                            <lsb>0</lsb>
                            <msb>7</msb>
                            <access>read-only</access>
                        </field>
                        <field>
                            <name>RMDB_LH</name>
                            <description>RX Message Buffer Data Byte ((p × 4) + 1)</description>
                            <lsb>8</lsb>
                            <msb>15</msb>
                            <access>read-only</access>
                        </field>
                        <field>
                            <name>RMDB_HL</name>
                            <description>RX Message Buffer Data Byte ((p × 4) + 2)</description>
                            <lsb>16</lsb>
                            <msb>23</msb>
                            <access>read-only</access>
                        </field>
                        <field>
                            <name>RMDB_HH</name>
                            <description>RX Message Buffer Data Byte ((p × 4) + 3)</description>
                            <lsb>24</lsb>
                            <msb>31</msb>
                            <access>read-only</access>
                        </field>
                    </fields>
                </register>
                <register>
                    <dim>8</dim>
                    <dimIncrement>0x004C</dimIncrement>
                    <dimIndex>16-23</dimIndex>
                    <name>CFDRMDF%s_4</name>
                    <description>RX Message Buffer Data Field 4 Registers</description>
                    <addressOffset>0x113C</addressOffset>
                    <size>32</size>
                    <access>read-only</access>
                    <resetValue>0x00000000</resetValue>
                    <resetMask>0xffffffff</resetMask>
                    <fields>
                        <field>
                            <name>RMDB_LL</name>
                            <description>RX Message Buffer Data Byte (p × 4)</description>
                            <lsb>0</lsb>
                            <msb>7</msb>
                            <access>read-only</access>
                        </field>
                        <field>
                            <name>RMDB_LH</name>
                            <description>RX Message Buffer Data Byte ((p × 4) + 1)</description>
                            <lsb>8</lsb>
                            <msb>15</msb>
                            <access>read-only</access>
                        </field>
                        <field>
                            <name>RMDB_HL</name>
                            <description>RX Message Buffer Data Byte ((p × 4) + 2)</description>
                            <lsb>16</lsb>
                            <msb>23</msb>
                            <access>read-only</access>
                        </field>
                        <field>
                            <name>RMDB_HH</name>
                            <description>RX Message Buffer Data Byte ((p × 4) + 3)</description>
                            <lsb>24</lsb>
                            <msb>31</msb>
                            <access>read-only</access>
                        </field>
                    </fields>
                </register>
                <register>
                    <dim>8</dim>
                    <dimIncrement>0x004C</dimIncrement>
                    <dimIndex>16-23</dimIndex>
                    <name>CFDRMDF%s_5</name>
                    <description>RX Message Buffer Data Field 5 Registers</description>
                    <addressOffset>0x1140</addressOffset>
                    <size>32</size>
                    <access>read-only</access>
                    <resetValue>0x00000000</resetValue>
                    <resetMask>0xffffffff</resetMask>
                    <fields>
                        <field>
                            <name>RMDB_LL</name>
                            <description>RX Message Buffer Data Byte (p × 4)</description>
                            <lsb>0</lsb>
                            <msb>7</msb>
                            <access>read-only</access>
                        </field>
                        <field>
                            <name>RMDB_LH</name>
                            <description>RX Message Buffer Data Byte ((p × 4) + 1)</description>
                            <lsb>8</lsb>
                            <msb>15</msb>
                            <access>read-only</access>
                        </field>
                        <field>
                            <name>RMDB_HL</name>
                            <description>RX Message Buffer Data Byte ((p × 4) + 2)</description>
                            <lsb>16</lsb>
                            <msb>23</msb>
                            <access>read-only</access>
                        </field>
                        <field>
                            <name>RMDB_HH</name>
                            <description>RX Message Buffer Data Byte ((p × 4) + 3)</description>
                            <lsb>24</lsb>
                            <msb>31</msb>
                            <access>read-only</access>
                        </field>
                    </fields>
                </register>
                <register>
                    <dim>8</dim>
                    <dimIncrement>0x004C</dimIncrement>
                    <dimIndex>16-23</dimIndex>
                    <name>CFDRMDF%s_6</name>
                    <description>RX Message Buffer Data Field 6 Registers</description>
                    <addressOffset>0x1144</addressOffset>
                    <size>32</size>
                    <access>read-only</access>
                    <resetValue>0x00000000</resetValue>
                    <resetMask>0xffffffff</resetMask>
                    <fields>
                        <field>
                            <name>RMDB_LL</name>
                            <description>RX Message Buffer Data Byte (p × 4)</description>
                            <lsb>0</lsb>
                            <msb>7</msb>
                            <access>read-only</access>
                        </field>
                        <field>
                            <name>RMDB_LH</name>
                            <description>RX Message Buffer Data Byte ((p × 4) + 1)</description>
                            <lsb>8</lsb>
                            <msb>15</msb>
                            <access>read-only</access>
                        </field>
                        <field>
                            <name>RMDB_HL</name>
                            <description>RX Message Buffer Data Byte ((p × 4) + 2)</description>
                            <lsb>16</lsb>
                            <msb>23</msb>
                            <access>read-only</access>
                        </field>
                        <field>
                            <name>RMDB_HH</name>
                            <description>RX Message Buffer Data Byte ((p × 4) + 3)</description>
                            <lsb>24</lsb>
                            <msb>31</msb>
                            <access>read-only</access>
                        </field>
                    </fields>
                </register>
                <register>
                    <dim>8</dim>
                    <dimIncrement>0x004C</dimIncrement>
                    <dimIndex>16-23</dimIndex>
                    <name>CFDRMDF%s_7</name>
                    <description>RX Message Buffer Data Field 7 Registers</description>
                    <addressOffset>0x1148</addressOffset>
                    <size>32</size>
                    <access>read-only</access>
                    <resetValue>0x00000000</resetValue>
                    <resetMask>0xffffffff</resetMask>
                    <fields>
                        <field>
                            <name>RMDB_LL</name>
                            <description>RX Message Buffer Data Byte (p × 4)</description>
                            <lsb>0</lsb>
                            <msb>7</msb>
                            <access>read-only</access>
                        </field>
                        <field>
                            <name>RMDB_LH</name>
                            <description>RX Message Buffer Data Byte ((p × 4) + 1)</description>
                            <lsb>8</lsb>
                            <msb>15</msb>
                            <access>read-only</access>
                        </field>
                        <field>
                            <name>RMDB_HL</name>
                            <description>RX Message Buffer Data Byte ((p × 4) + 2)</description>
                            <lsb>16</lsb>
                            <msb>23</msb>
                            <access>read-only</access>
                        </field>
                        <field>
                            <name>RMDB_HH</name>
                            <description>RX Message Buffer Data Byte ((p × 4) + 3)</description>
                            <lsb>24</lsb>
                            <msb>31</msb>
                            <access>read-only</access>
                        </field>
                    </fields>
                </register>
                <register>
                    <dim>8</dim>
                    <dimIncrement>0x004C</dimIncrement>
                    <dimIndex>16-23</dimIndex>
                    <name>CFDRMDF%s_8</name>
                    <description>RX Message Buffer Data Field 8 Registers</description>
                    <addressOffset>0x114C</addressOffset>
                    <size>32</size>
                    <access>read-only</access>
                    <resetValue>0x00000000</resetValue>
                    <resetMask>0xffffffff</resetMask>
                    <fields>
                        <field>
                            <name>RMDB_LL</name>
                            <description>RX Message Buffer Data Byte (p × 4)</description>
                            <lsb>0</lsb>
                            <msb>7</msb>
                            <access>read-only</access>
                        </field>
                        <field>
                            <name>RMDB_LH</name>
                            <description>RX Message Buffer Data Byte ((p × 4) + 1)</description>
                            <lsb>8</lsb>
                            <msb>15</msb>
                            <access>read-only</access>
                        </field>
                        <field>
                            <name>RMDB_HL</name>
                            <description>RX Message Buffer Data Byte ((p × 4) + 2)</description>
                            <lsb>16</lsb>
                            <msb>23</msb>
                            <access>read-only</access>
                        </field>
                        <field>
                            <name>RMDB_HH</name>
                            <description>RX Message Buffer Data Byte ((p × 4) + 3)</description>
                            <lsb>24</lsb>
                            <msb>31</msb>
                            <access>read-only</access>
                        </field>
                    </fields>
                </register>
                <register>
                    <dim>8</dim>
                    <dimIncrement>0x004C</dimIncrement>
                    <dimIndex>16-23</dimIndex>
                    <name>CFDRMDF%s_9</name>
                    <description>RX Message Buffer Data Field 9 Registers</description>
                    <addressOffset>0x1150</addressOffset>
                    <size>32</size>
                    <access>read-only</access>
                    <resetValue>0x00000000</resetValue>
                    <resetMask>0xffffffff</resetMask>
                    <fields>
                        <field>
                            <name>RMDB_LL</name>
                            <description>RX Message Buffer Data Byte (p × 4)</description>
                            <lsb>0</lsb>
                            <msb>7</msb>
                            <access>read-only</access>
                        </field>
                        <field>
                            <name>RMDB_LH</name>
                            <description>RX Message Buffer Data Byte ((p × 4) + 1)</description>
                            <lsb>8</lsb>
                            <msb>15</msb>
                            <access>read-only</access>
                        </field>
                        <field>
                            <name>RMDB_HL</name>
                            <description>RX Message Buffer Data Byte ((p × 4) + 2)</description>
                            <lsb>16</lsb>
                            <msb>23</msb>
                            <access>read-only</access>
                        </field>
                        <field>
                            <name>RMDB_HH</name>
                            <description>RX Message Buffer Data Byte ((p × 4) + 3)</description>
                            <lsb>24</lsb>
                            <msb>31</msb>
                            <access>read-only</access>
                        </field>
                    </fields>
                </register>
                <register>
                    <dim>8</dim>
                    <dimIncrement>0x004C</dimIncrement>
                    <dimIndex>16-23</dimIndex>
                    <name>CFDRMDF%s_10</name>
                    <description>RX Message Buffer Data Field 10 Registers</description>
                    <addressOffset>0x1154</addressOffset>
                    <size>32</size>
                    <access>read-only</access>
                    <resetValue>0x00000000</resetValue>
                    <resetMask>0xffffffff</resetMask>
                    <fields>
                        <field>
                            <name>RMDB_LL</name>
                            <description>RX Message Buffer Data Byte (p × 4)</description>
                            <lsb>0</lsb>
                            <msb>7</msb>
                            <access>read-only</access>
                        </field>
                        <field>
                            <name>RMDB_LH</name>
                            <description>RX Message Buffer Data Byte ((p × 4) + 1)</description>
                            <lsb>8</lsb>
                            <msb>15</msb>
                            <access>read-only</access>
                        </field>
                        <field>
                            <name>RMDB_HL</name>
                            <description>RX Message Buffer Data Byte ((p × 4) + 2)</description>
                            <lsb>16</lsb>
                            <msb>23</msb>
                            <access>read-only</access>
                        </field>
                        <field>
                            <name>RMDB_HH</name>
                            <description>RX Message Buffer Data Byte ((p × 4) + 3)</description>
                            <lsb>24</lsb>
                            <msb>31</msb>
                            <access>read-only</access>
                        </field>
                    </fields>
                </register>
                <register>
                    <dim>8</dim>
                    <dimIncrement>0x004C</dimIncrement>
                    <dimIndex>16-23</dimIndex>
                    <name>CFDRMDF%s_11</name>
                    <description>RX Message Buffer Data Field 11 Registers</description>
                    <addressOffset>0x1158</addressOffset>
                    <size>32</size>
                    <access>read-only</access>
                    <resetValue>0x00000000</resetValue>
                    <resetMask>0xffffffff</resetMask>
                    <fields>
                        <field>
                            <name>RMDB_LL</name>
                            <description>RX Message Buffer Data Byte (p × 4)</description>
                            <lsb>0</lsb>
                            <msb>7</msb>
                            <access>read-only</access>
                        </field>
                        <field>
                            <name>RMDB_LH</name>
                            <description>RX Message Buffer Data Byte ((p × 4) + 1)</description>
                            <lsb>8</lsb>
                            <msb>15</msb>
                            <access>read-only</access>
                        </field>
                        <field>
                            <name>RMDB_HL</name>
                            <description>RX Message Buffer Data Byte ((p × 4) + 2)</description>
                            <lsb>16</lsb>
                            <msb>23</msb>
                            <access>read-only</access>
                        </field>
                        <field>
                            <name>RMDB_HH</name>
                            <description>RX Message Buffer Data Byte ((p × 4) + 3)</description>
                            <lsb>24</lsb>
                            <msb>31</msb>
                            <access>read-only</access>
                        </field>
                    </fields>
                </register>
                <register>
                    <dim>8</dim>
                    <dimIncrement>0x004C</dimIncrement>
                    <dimIndex>16-23</dimIndex>
                    <name>CFDRMDF%s_12</name>
                    <description>RX Message Buffer Data Field 12 Registers</description>
                    <addressOffset>0x115C</addressOffset>
                    <size>32</size>
                    <access>read-only</access>
                    <resetValue>0x00000000</resetValue>
                    <resetMask>0xffffffff</resetMask>
                    <fields>
                        <field>
                            <name>RMDB_LL</name>
                            <description>RX Message Buffer Data Byte (p × 4)</description>
                            <lsb>0</lsb>
                            <msb>7</msb>
                            <access>read-only</access>
                        </field>
                        <field>
                            <name>RMDB_LH</name>
                            <description>RX Message Buffer Data Byte ((p × 4) + 1)</description>
                            <lsb>8</lsb>
                            <msb>15</msb>
                            <access>read-only</access>
                        </field>
                        <field>
                            <name>RMDB_HL</name>
                            <description>RX Message Buffer Data Byte ((p × 4) + 2)</description>
                            <lsb>16</lsb>
                            <msb>23</msb>
                            <access>read-only</access>
                        </field>
                        <field>
                            <name>RMDB_HH</name>
                            <description>RX Message Buffer Data Byte ((p × 4) + 3)</description>
                            <lsb>24</lsb>
                            <msb>31</msb>
                            <access>read-only</access>
                        </field>
                    </fields>
                </register>
                <register>
                    <dim>8</dim>
                    <dimIncrement>0x004C</dimIncrement>
                    <dimIndex>16-23</dimIndex>
                    <name>CFDRMDF%s_13</name>
                    <description>RX Message Buffer Data Field 13 Registers</description>
                    <addressOffset>0x1160</addressOffset>
                    <size>32</size>
                    <access>read-only</access>
                    <resetValue>0x00000000</resetValue>
                    <resetMask>0xffffffff</resetMask>
                    <fields>
                        <field>
                            <name>RMDB_LL</name>
                            <description>RX Message Buffer Data Byte (p × 4)</description>
                            <lsb>0</lsb>
                            <msb>7</msb>
                            <access>read-only</access>
                        </field>
                        <field>
                            <name>RMDB_LH</name>
                            <description>RX Message Buffer Data Byte ((p × 4) + 1)</description>
                            <lsb>8</lsb>
                            <msb>15</msb>
                            <access>read-only</access>
                        </field>
                        <field>
                            <name>RMDB_HL</name>
                            <description>RX Message Buffer Data Byte ((p × 4) + 2)</description>
                            <lsb>16</lsb>
                            <msb>23</msb>
                            <access>read-only</access>
                        </field>
                        <field>
                            <name>RMDB_HH</name>
                            <description>RX Message Buffer Data Byte ((p × 4) + 3)</description>
                            <lsb>24</lsb>
                            <msb>31</msb>
                            <access>read-only</access>
                        </field>
                    </fields>
                </register>
                <register>
                    <dim>8</dim>
                    <dimIncrement>0x004C</dimIncrement>
                    <dimIndex>16-23</dimIndex>
                    <name>CFDRMDF%s_14</name>
                    <description>RX Message Buffer Data Field 14 Registers</description>
                    <addressOffset>0x1164</addressOffset>
                    <size>32</size>
                    <access>read-only</access>
                    <resetValue>0x00000000</resetValue>
                    <resetMask>0xffffffff</resetMask>
                    <fields>
                        <field>
                            <name>RMDB_LL</name>
                            <description>RX Message Buffer Data Byte (p × 4)</description>
                            <lsb>0</lsb>
                            <msb>7</msb>
                            <access>read-only</access>
                        </field>
                        <field>
                            <name>RMDB_LH</name>
                            <description>RX Message Buffer Data Byte ((p × 4) + 1)</description>
                            <lsb>8</lsb>
                            <msb>15</msb>
                            <access>read-only</access>
                        </field>
                        <field>
                            <name>RMDB_HL</name>
                            <description>RX Message Buffer Data Byte ((p × 4) + 2)</description>
                            <lsb>16</lsb>
                            <msb>23</msb>
                            <access>read-only</access>
                        </field>
                        <field>
                            <name>RMDB_HH</name>
                            <description>RX Message Buffer Data Byte ((p × 4) + 3)</description>
                            <lsb>24</lsb>
                            <msb>31</msb>
                            <access>read-only</access>
                        </field>
                    </fields>
                </register>
                <register>
                    <dim>8</dim>
                    <dimIncrement>0x004C</dimIncrement>
                    <dimIndex>16-23</dimIndex>
                    <name>CFDRMDF%s_15</name>
                    <description>RX Message Buffer Data Field 15 Registers</description>
                    <addressOffset>0x1168</addressOffset>
                    <size>32</size>
                    <access>read-only</access>
                    <resetValue>0x00000000</resetValue>
                    <resetMask>0xffffffff</resetMask>
                    <fields>
                        <field>
                            <name>RMDB_LL</name>
                            <description>RX Message Buffer Data Byte (p × 4)</description>
                            <lsb>0</lsb>
                            <msb>7</msb>
                            <access>read-only</access>
                        </field>
                        <field>
                            <name>RMDB_LH</name>
                            <description>RX Message Buffer Data Byte ((p × 4) + 1)</description>
                            <lsb>8</lsb>
                            <msb>15</msb>
                            <access>read-only</access>
                        </field>
                        <field>
                            <name>RMDB_HL</name>
                            <description>RX Message Buffer Data Byte ((p × 4) + 2)</description>
                            <lsb>16</lsb>
                            <msb>23</msb>
                            <access>read-only</access>
                        </field>
                        <field>
                            <name>RMDB_HH</name>
                            <description>RX Message Buffer Data Byte ((p × 4) + 3)</description>
                            <lsb>24</lsb>
                            <msb>31</msb>
                            <access>read-only</access>
                        </field>
                    </fields>
                </register>
                <register>
                    <dim>8</dim>
                    <dimIncrement>0x004C</dimIncrement>
                    <dimIndex>24-31</dimIndex>
                    <name>CFDRMPTR%s</name>
                    <description>RX Message Buffer Pointer Registers</description>
                    <addressOffset>0x01524</addressOffset>
                    <size>32</size>
                    <access>read-only</access>
                    <resetValue>0x00000000</resetValue>
                    <resetMask>0xffffffff</resetMask>
                    <fields>
                        <field>
                            <name>RMTS</name>
                            <description>RX Message Buffer Timestamp Field</description>
                            <lsb>0</lsb>
                            <msb>15</msb>
                            <access>read-only</access>
                        </field>
                        <field>
                            <name>RMDLC</name>
                            <description>RX Message Buffer DLC Field</description>
                            <lsb>28</lsb>
                            <msb>31</msb>
                            <access>read-only</access>
                        </field>
                    </fields>
                </register>
                <register>
                    <dim>8</dim>
                    <dimIncrement>0x004C</dimIncrement>
                    <dimIndex>24-31</dimIndex>
                    <name>CFDRMFDSTS%s</name>
                    <description>RX Message Buffer CANFD Status Registers</description>
                    <addressOffset>0x01528</addressOffset>
                    <size>32</size>
                    <access>read-only</access>
                    <resetValue>0x00000000</resetValue>
                    <resetMask>0xffffffff</resetMask>
                    <fields>
                        <field>
                            <name>RMESI</name>
                            <description>Error State Indicator bit</description>
                            <lsb>0</lsb>
                            <msb>0</msb>
                            <access>read-only</access>
                            <enumeratedValues>
                                <enumeratedValue>
                                    <name>0</name>
                                    <description>CANFD frame received from error active node</description>
                                    <value>#0</value>
                                </enumeratedValue>
                                <enumeratedValue>
                                    <name>1</name>
                                    <description>CANFD frame received from error passive node</description>
                                    <value>#1</value>
                                </enumeratedValue>
                            </enumeratedValues>
                        </field>
                        <field>
                            <name>RMBRS</name>
                            <description>Bit Rate Switch bit</description>
                            <lsb>1</lsb>
                            <msb>1</msb>
                            <access>read-only</access>
                            <enumeratedValues>
                                <enumeratedValue>
                                    <name>0</name>
                                    <description>CANFD frame received with no bit rate switch</description>
                                    <value>#0</value>
                                </enumeratedValue>
                                <enumeratedValue>
                                    <name>1</name>
                                    <description>CANFD frame received with bit rate switch</description>
                                    <value>#1</value>
                                </enumeratedValue>
                            </enumeratedValues>
                        </field>
                        <field>
                            <name>RMFDF</name>
                            <description>CAN FD Format bit</description>
                            <lsb>2</lsb>
                            <msb>2</msb>
                            <access>read-only</access>
                            <enumeratedValues>
                                <enumeratedValue>
                                    <name>0</name>
                                    <description>Non CANFD frame received</description>
                                    <value>#0</value>
                                </enumeratedValue>
                                <enumeratedValue>
                                    <name>1</name>
                                    <description>CANFD frame received</description>
                                    <value>#1</value>
                                </enumeratedValue>
                            </enumeratedValues>
                        </field>
                        <field>
                            <name>RMIFL</name>
                            <description>RX Message Buffer Information Label Field</description>
                            <lsb>8</lsb>
                            <msb>9</msb>
                            <access>read-only</access>
                        </field>
                        <field>
                            <name>RMPTR</name>
                            <description>RX Message Buffer Pointer Field</description>
                            <lsb>16</lsb>
                            <msb>31</msb>
                            <access>read-only</access>
                        </field>
                    </fields>
                </register>
                <register>
                    <dim>8</dim>
                    <dimIncrement>0x004C</dimIncrement>
                    <dimIndex>24-31</dimIndex>
                    <name>CFDRMDF%s_0</name>
                    <description>RX Message Buffer Data Field 0 Registers</description>
                    <addressOffset>0x152C</addressOffset>
                    <size>32</size>
                    <access>read-only</access>
                    <resetValue>0x00000000</resetValue>
                    <resetMask>0xffffffff</resetMask>
                    <fields>
                        <field>
                            <name>RMDB_LL</name>
                            <description>RX Message Buffer Data Byte (p × 4)</description>
                            <lsb>0</lsb>
                            <msb>7</msb>
                            <access>read-only</access>
                        </field>
                        <field>
                            <name>RMDB_LH</name>
                            <description>RX Message Buffer Data Byte ((p × 4) + 1)</description>
                            <lsb>8</lsb>
                            <msb>15</msb>
                            <access>read-only</access>
                        </field>
                        <field>
                            <name>RMDB_HL</name>
                            <description>RX Message Buffer Data Byte ((p × 4) + 2)</description>
                            <lsb>16</lsb>
                            <msb>23</msb>
                            <access>read-only</access>
                        </field>
                        <field>
                            <name>RMDB_HH</name>
                            <description>RX Message Buffer Data Byte ((p × 4) + 3)</description>
                            <lsb>24</lsb>
                            <msb>31</msb>
                            <access>read-only</access>
                        </field>
                    </fields>
                </register>
                <register>
                    <dim>8</dim>
                    <dimIncrement>0x004C</dimIncrement>
                    <dimIndex>24-31</dimIndex>
                    <name>CFDRMDF%s_1</name>
                    <description>RX Message Buffer Data Field 1 Registers</description>
                    <addressOffset>0x1530</addressOffset>
                    <size>32</size>
                    <access>read-only</access>
                    <resetValue>0x00000000</resetValue>
                    <resetMask>0xffffffff</resetMask>
                    <fields>
                        <field>
                            <name>RMDB_LL</name>
                            <description>RX Message Buffer Data Byte (p × 4)</description>
                            <lsb>0</lsb>
                            <msb>7</msb>
                            <access>read-only</access>
                        </field>
                        <field>
                            <name>RMDB_LH</name>
                            <description>RX Message Buffer Data Byte ((p × 4) + 1)</description>
                            <lsb>8</lsb>
                            <msb>15</msb>
                            <access>read-only</access>
                        </field>
                        <field>
                            <name>RMDB_HL</name>
                            <description>RX Message Buffer Data Byte ((p × 4) + 2)</description>
                            <lsb>16</lsb>
                            <msb>23</msb>
                            <access>read-only</access>
                        </field>
                        <field>
                            <name>RMDB_HH</name>
                            <description>RX Message Buffer Data Byte ((p × 4) + 3)</description>
                            <lsb>24</lsb>
                            <msb>31</msb>
                            <access>read-only</access>
                        </field>
                    </fields>
                </register>
                <register>
                    <dim>8</dim>
                    <dimIncrement>0x004C</dimIncrement>
                    <dimIndex>24-31</dimIndex>
                    <name>CFDRMDF%s_2</name>
                    <description>RX Message Buffer Data Field 2 Registers</description>
                    <addressOffset>0x1534</addressOffset>
                    <size>32</size>
                    <access>read-only</access>
                    <resetValue>0x00000000</resetValue>
                    <resetMask>0xffffffff</resetMask>
                    <fields>
                        <field>
                            <name>RMDB_LL</name>
                            <description>RX Message Buffer Data Byte (p × 4)</description>
                            <lsb>0</lsb>
                            <msb>7</msb>
                            <access>read-only</access>
                        </field>
                        <field>
                            <name>RMDB_LH</name>
                            <description>RX Message Buffer Data Byte ((p × 4) + 1)</description>
                            <lsb>8</lsb>
                            <msb>15</msb>
                            <access>read-only</access>
                        </field>
                        <field>
                            <name>RMDB_HL</name>
                            <description>RX Message Buffer Data Byte ((p × 4) + 2)</description>
                            <lsb>16</lsb>
                            <msb>23</msb>
                            <access>read-only</access>
                        </field>
                        <field>
                            <name>RMDB_HH</name>
                            <description>RX Message Buffer Data Byte ((p × 4) + 3)</description>
                            <lsb>24</lsb>
                            <msb>31</msb>
                            <access>read-only</access>
                        </field>
                    </fields>
                </register>
                <register>
                    <dim>8</dim>
                    <dimIncrement>0x004C</dimIncrement>
                    <dimIndex>24-31</dimIndex>
                    <name>CFDRMDF%s_3</name>
                    <description>RX Message Buffer Data Field 3 Registers</description>
                    <addressOffset>0x1538</addressOffset>
                    <size>32</size>
                    <access>read-only</access>
                    <resetValue>0x00000000</resetValue>
                    <resetMask>0xffffffff</resetMask>
                    <fields>
                        <field>
                            <name>RMDB_LL</name>
                            <description>RX Message Buffer Data Byte (p × 4)</description>
                            <lsb>0</lsb>
                            <msb>7</msb>
                            <access>read-only</access>
                        </field>
                        <field>
                            <name>RMDB_LH</name>
                            <description>RX Message Buffer Data Byte ((p × 4) + 1)</description>
                            <lsb>8</lsb>
                            <msb>15</msb>
                            <access>read-only</access>
                        </field>
                        <field>
                            <name>RMDB_HL</name>
                            <description>RX Message Buffer Data Byte ((p × 4) + 2)</description>
                            <lsb>16</lsb>
                            <msb>23</msb>
                            <access>read-only</access>
                        </field>
                        <field>
                            <name>RMDB_HH</name>
                            <description>RX Message Buffer Data Byte ((p × 4) + 3)</description>
                            <lsb>24</lsb>
                            <msb>31</msb>
                            <access>read-only</access>
                        </field>
                    </fields>
                </register>
                <register>
                    <dim>8</dim>
                    <dimIncrement>0x004C</dimIncrement>
                    <dimIndex>24-31</dimIndex>
                    <name>CFDRMDF%s_4</name>
                    <description>RX Message Buffer Data Field 4 Registers</description>
                    <addressOffset>0x153C</addressOffset>
                    <size>32</size>
                    <access>read-only</access>
                    <resetValue>0x00000000</resetValue>
                    <resetMask>0xffffffff</resetMask>
                    <fields>
                        <field>
                            <name>RMDB_LL</name>
                            <description>RX Message Buffer Data Byte (p × 4)</description>
                            <lsb>0</lsb>
                            <msb>7</msb>
                            <access>read-only</access>
                        </field>
                        <field>
                            <name>RMDB_LH</name>
                            <description>RX Message Buffer Data Byte ((p × 4) + 1)</description>
                            <lsb>8</lsb>
                            <msb>15</msb>
                            <access>read-only</access>
                        </field>
                        <field>
                            <name>RMDB_HL</name>
                            <description>RX Message Buffer Data Byte ((p × 4) + 2)</description>
                            <lsb>16</lsb>
                            <msb>23</msb>
                            <access>read-only</access>
                        </field>
                        <field>
                            <name>RMDB_HH</name>
                            <description>RX Message Buffer Data Byte ((p × 4) + 3)</description>
                            <lsb>24</lsb>
                            <msb>31</msb>
                            <access>read-only</access>
                        </field>
                    </fields>
                </register>
                <register>
                    <dim>8</dim>
                    <dimIncrement>0x004C</dimIncrement>
                    <dimIndex>24-31</dimIndex>
                    <name>CFDRMDF%s_5</name>
                    <description>RX Message Buffer Data Field 5 Registers</description>
                    <addressOffset>0x1540</addressOffset>
                    <size>32</size>
                    <access>read-only</access>
                    <resetValue>0x00000000</resetValue>
                    <resetMask>0xffffffff</resetMask>
                    <fields>
                        <field>
                            <name>RMDB_LL</name>
                            <description>RX Message Buffer Data Byte (p × 4)</description>
                            <lsb>0</lsb>
                            <msb>7</msb>
                            <access>read-only</access>
                        </field>
                        <field>
                            <name>RMDB_LH</name>
                            <description>RX Message Buffer Data Byte ((p × 4) + 1)</description>
                            <lsb>8</lsb>
                            <msb>15</msb>
                            <access>read-only</access>
                        </field>
                        <field>
                            <name>RMDB_HL</name>
                            <description>RX Message Buffer Data Byte ((p × 4) + 2)</description>
                            <lsb>16</lsb>
                            <msb>23</msb>
                            <access>read-only</access>
                        </field>
                        <field>
                            <name>RMDB_HH</name>
                            <description>RX Message Buffer Data Byte ((p × 4) + 3)</description>
                            <lsb>24</lsb>
                            <msb>31</msb>
                            <access>read-only</access>
                        </field>
                    </fields>
                </register>
                <register>
                    <dim>8</dim>
                    <dimIncrement>0x004C</dimIncrement>
                    <dimIndex>24-31</dimIndex>
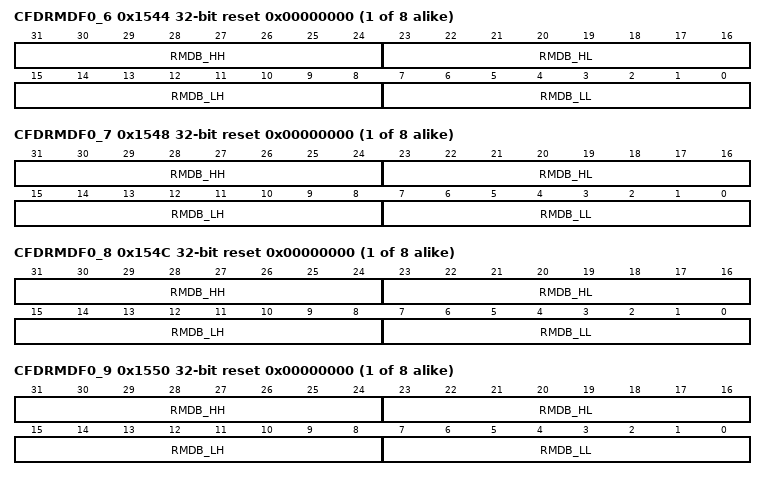
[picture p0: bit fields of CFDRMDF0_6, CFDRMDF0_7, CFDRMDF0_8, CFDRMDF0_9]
                    <name>CFDRMDF%s_6</name>
                    <description>RX Message Buffer Data Field 6 Registers</description>
                    <addressOffset>0x1544</addressOffset>
                    <size>32</size>
                    <access>read-only</access>
                    <resetValue>0x00000000</resetValue>
                    <resetMask>0xffffffff</resetMask>
                    <fields>
                        <field>
                            <name>RMDB_LL</name>
                            <description>RX Message Buffer Data Byte (p × 4)</description>
                            <lsb>0</lsb>
                            <msb>7</msb>
                            <access>read-only</access>
                        </field>
                        <field>
                            <name>RMDB_LH</name>
                            <description>RX Message Buffer Data Byte ((p × 4) + 1)</description>
                            <lsb>8</lsb>
                            <msb>15</msb>
                            <access>read-only</access>
                        </field>
                        <field>
                            <name>RMDB_HL</name>
                            <description>RX Message Buffer Data Byte ((p × 4) + 2)</description>
                            <lsb>16</lsb>
                            <msb>23</msb>
                            <access>read-only</access>
                        </field>
                        <field>
                            <name>RMDB_HH</name>
                            <description>RX Message Buffer Data Byte ((p × 4) + 3)</description>
                            <lsb>24</lsb>
                            <msb>31</msb>
                            <access>read-only</access>
                        </field>
                    </fields>
                </register>
                <register>
                    <dim>8</dim>
                    <dimIncrement>0x004C</dimIncrement>
                    <dimIndex>24-31</dimIndex>
                    <name>CFDRMDF%s_7</name>
                    <description>RX Message Buffer Data Field 7 Registers</description>
                    <addressOffset>0x1548</addressOffset>
                    <size>32</size>
                    <access>read-only</access>
                    <resetValue>0x00000000</resetValue>
                    <resetMask>0xffffffff</resetMask>
                    <fields>
                        <field>
                            <name>RMDB_LL</name>
                            <description>RX Message Buffer Data Byte (p × 4)</description>
                            <lsb>0</lsb>
                            <msb>7</msb>
                            <access>read-only</access>
                        </field>
                        <field>
                            <name>RMDB_LH</name>
                            <description>RX Message Buffer Data Byte ((p × 4) + 1)</description>
                            <lsb>8</lsb>
                            <msb>15</msb>
                            <access>read-only</access>
                        </field>
                        <field>
                            <name>RMDB_HL</name>
                            <description>RX Message Buffer Data Byte ((p × 4) + 2)</description>
                            <lsb>16</lsb>
                            <msb>23</msb>
                            <access>read-only</access>
                        </field>
                        <field>
                            <name>RMDB_HH</name>
                            <description>RX Message Buffer Data Byte ((p × 4) + 3)</description>
                            <lsb>24</lsb>
                            <msb>31</msb>
                            <access>read-only</access>
                        </field>
                    </fields>
                </register>
                <register>
                    <dim>8</dim>
                    <dimIncrement>0x004C</dimIncrement>
                    <dimIndex>24-31</dimIndex>
                    <name>CFDRMDF%s_8</name>
                    <description>RX Message Buffer Data Field 8 Registers</description>
                    <addressOffset>0x154C</addressOffset>
                    <size>32</size>
                    <access>read-only</access>
                    <resetValue>0x00000000</resetValue>
                    <resetMask>0xffffffff</resetMask>
                    <fields>
                        <field>
                            <name>RMDB_LL</name>
                            <description>RX Message Buffer Data Byte (p × 4)</description>
                            <lsb>0</lsb>
                            <msb>7</msb>
                            <access>read-only</access>
                        </field>
                        <field>
                            <name>RMDB_LH</name>
                            <description>RX Message Buffer Data Byte ((p × 4) + 1)</description>
                            <lsb>8</lsb>
                            <msb>15</msb>
                            <access>read-only</access>
                        </field>
                        <field>
                            <name>RMDB_HL</name>
                            <description>RX Message Buffer Data Byte ((p × 4) + 2)</description>
                            <lsb>16</lsb>
                            <msb>23</msb>
                            <access>read-only</access>
                        </field>
                        <field>
                            <name>RMDB_HH</name>
                            <description>RX Message Buffer Data Byte ((p × 4) + 3)</description>
                            <lsb>24</lsb>
                            <msb>31</msb>
                            <access>read-only</access>
                        </field>
                    </fields>
                </register>
                <register>
                    <dim>8</dim>
                    <dimIncrement>0x004C</dimIncrement>
                    <dimIndex>24-31</dimIndex>
                    <name>CFDRMDF%s_9</name>
                    <description>RX Message Buffer Data Field 9 Registers</description>
                    <addressOffset>0x1550</addressOffset>
                    <size>32</size>
                    <access>read-only</access>
                    <resetValue>0x00000000</resetValue>
                    <resetMask>0xffffffff</resetMask>
                    <fields>
                        <field>
                            <name>RMDB_LL</name>
                            <description>RX Message Buffer Data Byte (p × 4)</description>
                            <lsb>0</lsb>
                            <msb>7</msb>
                            <access>read-only</access>
                        </field>
                        <field>
                            <name>RMDB_LH</name>
                            <description>RX Message Buffer Data Byte ((p × 4) + 1)</description>
                            <lsb>8</lsb>
                            <msb>15</msb>
                            <access>read-only</access>
                        </field>
                        <field>
                            <name>RMDB_HL</name>
                            <description>RX Message Buffer Data Byte ((p × 4) + 2)</description>
                            <lsb>16</lsb>
                            <msb>23</msb>
                            <access>read-only</access>
                        </field>
                        <field>
                            <name>RMDB_HH</name>
                            <description>RX Message Buffer Data Byte ((p × 4) + 3)</description>
                            <lsb>24</lsb>
                            <msb>31</msb>
                            <access>read-only</access>
                        </field>
                    </fields>
                </register>
                <register>
                    <dim>8</dim>
                    <dimIncrement>0x004C</dimIncrement>
                    <dimIndex>24-31</dimIndex>
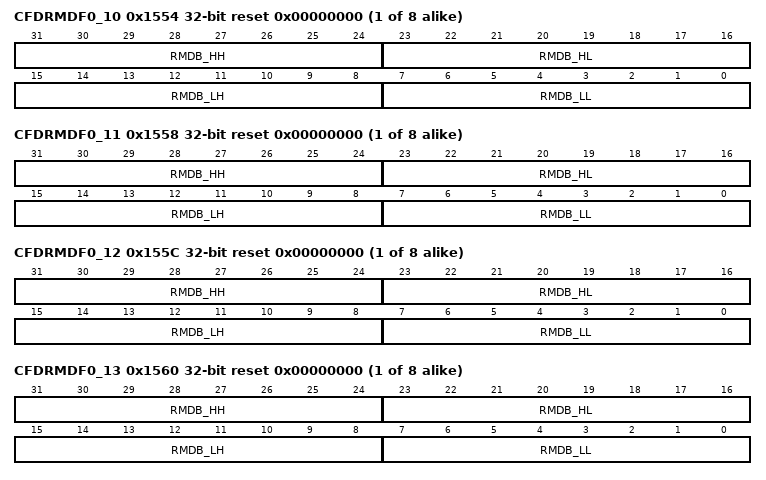
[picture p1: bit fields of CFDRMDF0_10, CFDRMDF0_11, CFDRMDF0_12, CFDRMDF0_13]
                    <name>CFDRMDF%s_10</name>
                    <description>RX Message Buffer Data Field 10 Registers</description>
                    <addressOffset>0x1554</addressOffset>
                    <size>32</size>
                    <access>read-only</access>
                    <resetValue>0x00000000</resetValue>
                    <resetMask>0xffffffff</resetMask>
                    <fields>
                        <field>
                            <name>RMDB_LL</name>
                            <description>RX Message Buffer Data Byte (p × 4)</description>
                            <lsb>0</lsb>
                            <msb>7</msb>
                            <access>read-only</access>
                        </field>
                        <field>
                            <name>RMDB_LH</name>
                            <description>RX Message Buffer Data Byte ((p × 4) + 1)</description>
                            <lsb>8</lsb>
                            <msb>15</msb>
                            <access>read-only</access>
                        </field>
                        <field>
                            <name>RMDB_HL</name>
                            <description>RX Message Buffer Data Byte ((p × 4) + 2)</description>
                            <lsb>16</lsb>
                            <msb>23</msb>
                            <access>read-only</access>
                        </field>
                        <field>
                            <name>RMDB_HH</name>
                            <description>RX Message Buffer Data Byte ((p × 4) + 3)</description>
                            <lsb>24</lsb>
                            <msb>31</msb>
                            <access>read-only</access>
                        </field>
                    </fields>
                </register>
                <register>
                    <dim>8</dim>
                    <dimIncrement>0x004C</dimIncrement>
                    <dimIndex>24-31</dimIndex>
                    <name>CFDRMDF%s_11</name>
                    <description>RX Message Buffer Data Field 11 Registers</description>
                    <addressOffset>0x1558</addressOffset>
                    <size>32</size>
                    <access>read-only</access>
                    <resetValue>0x00000000</resetValue>
                    <resetMask>0xffffffff</resetMask>
                    <fields>
                        <field>
                            <name>RMDB_LL</name>
                            <description>RX Message Buffer Data Byte (p × 4)</description>
                            <lsb>0</lsb>
                            <msb>7</msb>
                            <access>read-only</access>
                        </field>
                        <field>
                            <name>RMDB_LH</name>
                            <description>RX Message Buffer Data Byte ((p × 4) + 1)</description>
                            <lsb>8</lsb>
                            <msb>15</msb>
                            <access>read-only</access>
                        </field>
                        <field>
                            <name>RMDB_HL</name>
                            <description>RX Message Buffer Data Byte ((p × 4) + 2)</description>
                            <lsb>16</lsb>
                            <msb>23</msb>
                            <access>read-only</access>
                        </field>
                        <field>
                            <name>RMDB_HH</name>
                            <description>RX Message Buffer Data Byte ((p × 4) + 3)</description>
                            <lsb>24</lsb>
                            <msb>31</msb>
                            <access>read-only</access>
                        </field>
                    </fields>
                </register>
                <register>
                    <dim>8</dim>
                    <dimIncrement>0x004C</dimIncrement>
                    <dimIndex>24-31</dimIndex>
                    <name>CFDRMDF%s_12</name>
                    <description>RX Message Buffer Data Field 12 Registers</description>
                    <addressOffset>0x155C</addressOffset>
                    <size>32</size>
                    <access>read-only</access>
                    <resetValue>0x00000000</resetValue>
                    <resetMask>0xffffffff</resetMask>
                    <fields>
                        <field>
                            <name>RMDB_LL</name>
                            <description>RX Message Buffer Data Byte (p × 4)</description>
                            <lsb>0</lsb>
                            <msb>7</msb>
                            <access>read-only</access>
                        </field>
                        <field>
                            <name>RMDB_LH</name>
                            <description>RX Message Buffer Data Byte ((p × 4) + 1)</description>
                            <lsb>8</lsb>
                            <msb>15</msb>
                            <access>read-only</access>
                        </field>
                        <field>
                            <name>RMDB_HL</name>
                            <description>RX Message Buffer Data Byte ((p × 4) + 2)</description>
                            <lsb>16</lsb>
                            <msb>23</msb>
                            <access>read-only</access>
                        </field>
                        <field>
                            <name>RMDB_HH</name>
                            <description>RX Message Buffer Data Byte ((p × 4) + 3)</description>
                            <lsb>24</lsb>
                            <msb>31</msb>
                            <access>read-only</access>
                        </field>
                    </fields>
                </register>
                <register>
                    <dim>8</dim>
                    <dimIncrement>0x004C</dimIncrement>
                    <dimIndex>24-31</dimIndex>
                    <name>CFDRMDF%s_13</name>
                    <description>RX Message Buffer Data Field 13 Registers</description>
                    <addressOffset>0x1560</addressOffset>
                    <size>32</size>
                    <access>read-only</access>
                    <resetValue>0x00000000</resetValue>
                    <resetMask>0xffffffff</resetMask>
                    <fields>
                        <field>
                            <name>RMDB_LL</name>
                            <description>RX Message Buffer Data Byte (p × 4)</description>
                            <lsb>0</lsb>
                            <msb>7</msb>
                            <access>read-only</access>
                        </field>
                        <field>
                            <name>RMDB_LH</name>
                            <description>RX Message Buffer Data Byte ((p × 4) + 1)</description>
                            <lsb>8</lsb>
                            <msb>15</msb>
                            <access>read-only</access>
                        </field>
                        <field>
                            <name>RMDB_HL</name>
                            <description>RX Message Buffer Data Byte ((p × 4) + 2)</description>
                            <lsb>16</lsb>
                            <msb>23</msb>
                            <access>read-only</access>
                        </field>
                        <field>
                            <name>RMDB_HH</name>
                            <description>RX Message Buffer Data Byte ((p × 4) + 3)</description>
                            <lsb>24</lsb>
                            <msb>31</msb>
                            <access>read-only</access>
                        </field>
                    </fields>
                </register>
                <register>
                    <dim>8</dim>
                    <dimIncrement>0x004C</dimIncrement>
                    <dimIndex>24-31</dimIndex>
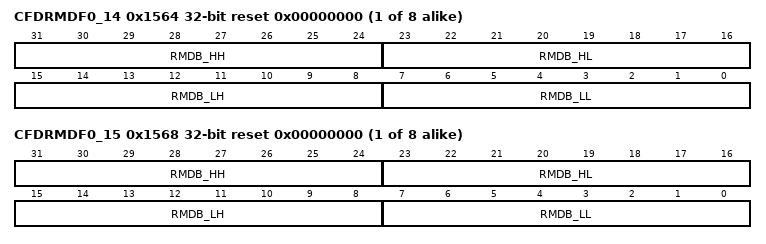
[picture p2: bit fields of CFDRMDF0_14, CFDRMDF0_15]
                    <name>CFDRMDF%s_14</name>
                    <description>RX Message Buffer Data Field 14 Registers</description>
                    <addressOffset>0x1564</addressOffset>
                    <size>32</size>
                    <access>read-only</access>
                    <resetValue>0x00000000</resetValue>
                    <resetMask>0xffffffff</resetMask>
                    <fields>
                        <field>
                            <name>RMDB_LL</name>
                            <description>RX Message Buffer Data Byte (p × 4)</description>
                            <lsb>0</lsb>
                            <msb>7</msb>
                            <access>read-only</access>
                        </field>
                        <field>
                            <name>RMDB_LH</name>
                            <description>RX Message Buffer Data Byte ((p × 4) + 1)</description>
                            <lsb>8</lsb>
                            <msb>15</msb>
                            <access>read-only</access>
                        </field>
                        <field>
                            <name>RMDB_HL</name>
                            <description>RX Message Buffer Data Byte ((p × 4) + 2)</description>
                            <lsb>16</lsb>
                            <msb>23</msb>
                            <access>read-only</access>
                        </field>
                        <field>
                            <name>RMDB_HH</name>
                            <description>RX Message Buffer Data Byte ((p × 4) + 3)</description>
                            <lsb>24</lsb>
                            <msb>31</msb>
                            <access>read-only</access>
                        </field>
                    </fields>
                </register>
                <register>
                    <dim>8</dim>
                    <dimIncrement>0x004C</dimIncrement>
                    <dimIndex>24-31</dimIndex>
                    <name>CFDRMDF%s_15</name>
                    <description>RX Message Buffer Data Field 15 Registers</description>
                    <addressOffset>0x1568</addressOffset>
                    <size>32</size>
                    <access>read-only</access>
                    <resetValue>0x00000000</resetValue>
                    <resetMask>0xffffffff</resetMask>
                    <fields>
                        <field>
                            <name>RMDB_LL</name>
                            <description>RX Message Buffer Data Byte (p × 4)</description>
                            <lsb>0</lsb>
                            <msb>7</msb>
                            <access>read-only</access>
                        </field>
                        <field>
                            <name>RMDB_LH</name>
                            <description>RX Message Buffer Data Byte ((p × 4) + 1)</description>
                            <lsb>8</lsb>
                            <msb>15</msb>
                            <access>read-only</access>
                        </field>
                        <field>
                            <name>RMDB_HL</name>
                            <description>RX Message Buffer Data Byte ((p × 4) + 2)</description>
                            <lsb>16</lsb>
                            <msb>23</msb>
                            <access>read-only</access>
                        </field>
                        <field>
                            <name>RMDB_HH</name>
                            <description>RX Message Buffer Data Byte ((p × 4) + 3)</description>
                            <lsb>24</lsb>
                            <msb>31</msb>
                            <access>read-only</access>
                        </field>
                    </fields>
                </register>
            </registers>
        </peripheral>
        <peripheral derivedFrom="CANFD0_NS">
            <name>CANFD1_NS</name>
            <description>CANFD1</description>
            <baseAddress>0x50382000</baseAddress>
        </peripheral>
        <peripheral>
            <name>PORT0_NS</name>
            <description>Pmn Pin FunctionPort 0 Control RegistersPmn Pin Function Control Register</description>
            <baseAddress>0x50400000</baseAddress>
            <addressBlock>
                <offset>0x00</offset>
                <size>8</size>
                <usage>registers</usage>
            </addressBlock>
            <addressBlock>
                <offset>0x08</offset>
                <size>4</size>
                <usage>registers</usage>
            </addressBlock>
            <registers>
                <register>
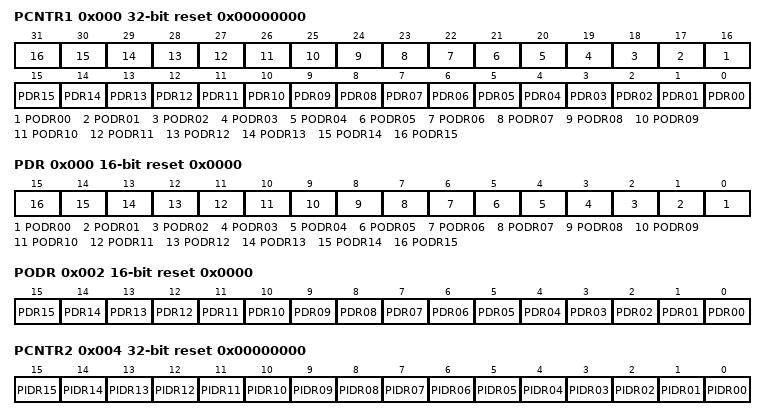
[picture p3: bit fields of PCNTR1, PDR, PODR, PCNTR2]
                    <name>PCNTR1</name>
                    <description>Port Control Register 1</description>
                    <addressOffset>0x000</addressOffset>
                    <size>32</size>
                    <access>read-write</access>
                    <resetValue>0x00000000</resetValue>
                    <resetMask>0xffffffff</resetMask>
                    <fields>
                        <field>
                            <name>PDR00</name>
                            <description>Pmn Direction</description>
                            <lsb>0</lsb>
                            <msb>0</msb>
                            <access>read-write</access>
                            <enumeratedValues>
                                <enumeratedValue>
                                    <name>0</name>
                                    <description>Input (functions as an input pin)</description>
                                    <value>#0</value>
                                </enumeratedValue>
                                <enumeratedValue>
                                    <name>1</name>
                                    <description>Output (functions as an output pin)</description>
                                    <value>#1</value>
                                </enumeratedValue>
                            </enumeratedValues>
                        </field>
                        <field>
                            <name>PDR01</name>
                            <description>Pmn Direction</description>
                            <lsb>1</lsb>
                            <msb>1</msb>
                            <access>read-write</access>
                            <enumeratedValues>
                                <enumeratedValue>
                                    <name>0</name>
                                    <description>Input (functions as an input pin)</description>
                                    <value>#0</value>
                                </enumeratedValue>
                                <enumeratedValue>
                                    <name>1</name>
                                    <description>Output (functions as an output pin)</description>
                                    <value>#1</value>
                                </enumeratedValue>
                            </enumeratedValues>
                        </field>
                        <field>
                            <name>PDR02</name>
                            <description>Pmn Direction</description>
                            <lsb>2</lsb>
                            <msb>2</msb>
                            <access>read-write</access>
                            <enumeratedValues>
                                <enumeratedValue>
                                    <name>0</name>
                                    <description>Input (functions as an input pin)</description>
                                    <value>#0</value>
                                </enumeratedValue>
                                <enumeratedValue>
                                    <name>1</name>
                                    <description>Output (functions as an output pin)</description>
                                    <value>#1</value>
                                </enumeratedValue>
                            </enumeratedValues>
                        </field>
                        <field>
                            <name>PDR03</name>
                            <description>Pmn Direction</description>
                            <lsb>3</lsb>
                            <msb>3</msb>
                            <access>read-write</access>
                            <enumeratedValues>
                                <enumeratedValue>
                                    <name>0</name>
                                    <description>Input (functions as an input pin)</description>
                                    <value>#0</value>
                                </enumeratedValue>
                                <enumeratedValue>
                                    <name>1</name>
                                    <description>Output (functions as an output pin)</description>
                                    <value>#1</value>
                                </enumeratedValue>
                            </enumeratedValues>
                        </field>
                        <field>
                            <name>PDR04</name>
                            <description>Pmn Direction</description>
                            <lsb>4</lsb>
                            <msb>4</msb>
                            <access>read-write</access>
                            <enumeratedValues>
                                <enumeratedValue>
                                    <name>0</name>
                                    <description>Input (functions as an input pin)</description>
                                    <value>#0</value>
                                </enumeratedValue>
                                <enumeratedValue>
                                    <name>1</name>
                                    <description>Output (functions as an output pin)</description>
                                    <value>#1</value>
                                </enumeratedValue>
                            </enumeratedValues>
                        </field>
                        <field>
                            <name>PDR05</name>
                            <description>Pmn Direction</description>
                            <lsb>5</lsb>
                            <msb>5</msb>
                            <access>read-write</access>
                            <enumeratedValues>
                                <enumeratedValue>
                                    <name>0</name>
                                    <description>Input (functions as an input pin)</description>
                                    <value>#0</value>
                                </enumeratedValue>
                                <enumeratedValue>
                                    <name>1</name>
                                    <description>Output (functions as an output pin)</description>
                                    <value>#1</value>
                                </enumeratedValue>
                            </enumeratedValues>
                        </field>
                        <field>
                            <name>PDR06</name>
                            <description>Pmn Direction</description>
                            <lsb>6</lsb>
                            <msb>6</msb>
                            <access>read-write</access>
                            <enumeratedValues>
                                <enumeratedValue>
                                    <name>0</name>
                                    <description>Input (functions as an input pin)</description>
                                    <value>#0</value>
                                </enumeratedValue>
                                <enumeratedValue>
                                    <name>1</name>
                                    <description>Output (functions as an output pin)</description>
                                    <value>#1</value>
                                </enumeratedValue>
                            </enumeratedValues>
                        </field>
                        <field>
                            <name>PDR07</name>
                            <description>Pmn Direction</description>
                            <lsb>7</lsb>
                            <msb>7</msb>
                            <access>read-write</access>
                            <enumeratedValues>
                                <enumeratedValue>
                                    <name>0</name>
                                    <description>Input (functions as an input pin)</description>
                                    <value>#0</value>
                                </enumeratedValue>
                                <enumeratedValue>
                                    <name>1</name>
                                    <description>Output (functions as an output pin)</description>
                                    <value>#1</value>
                                </enumeratedValue>
                            </enumeratedValues>
                        </field>
                        <field>
                            <name>PDR08</name>
                            <description>Pmn Direction</description>
                            <lsb>8</lsb>
                            <msb>8</msb>
                            <access>read-write</access>
                            <enumeratedValues>
                                <enumeratedValue>
                                    <name>0</name>
                                    <description>Input (functions as an input pin)</description>
                                    <value>#0</value>
                                </enumeratedValue>
                                <enumeratedValue>
                                    <name>1</name>
                                    <description>Output (functions as an output pin)</description>
                                    <value>#1</value>
                                </enumeratedValue>
                            </enumeratedValues>
                        </field>
                        <field>
                            <name>PDR09</name>
                            <description>Pmn Direction</description>
                            <lsb>9</lsb>
                            <msb>9</msb>
                            <access>read-write</access>
                            <enumeratedValues>
                                <enumeratedValue>
                                    <name>0</name>
                                    <description>Input (functions as an input pin)</description>
                                    <value>#0</value>
                                </enumeratedValue>
                                <enumeratedValue>
                                    <name>1</name>
                                    <description>Output (functions as an output pin)</description>
                                    <value>#1</value>
                                </enumeratedValue>
                            </enumeratedValues>
                        </field>
                        <field>
                            <name>PDR10</name>
                            <description>Pmn Direction</description>
                            <lsb>10</lsb>
                            <msb>10</msb>
                            <access>read-write</access>
                            <enumeratedValues>
                                <enumeratedValue>
                                    <name>0</name>
                                    <description>Input (functions as an input pin)</description>
                                    <value>#0</value>
                                </enumeratedValue>
                                <enumeratedValue>
                                    <name>1</name>
                                    <description>Output (functions as an output pin)</description>
                                    <value>#1</value>
                                </enumeratedValue>
                            </enumeratedValues>
                        </field>
                        <field>
                            <name>PDR11</name>
                            <description>Pmn Direction</description>
                            <lsb>11</lsb>
                            <msb>11</msb>
                            <access>read-write</access>
                            <enumeratedValues>
                                <enumeratedValue>
                                    <name>0</name>
                                    <description>Input (functions as an input pin)</description>
                                    <value>#0</value>
                                </enumeratedValue>
                                <enumeratedValue>
                                    <name>1</name>
                                    <description>Output (functions as an output pin)</description>
                                    <value>#1</value>
                                </enumeratedValue>
                            </enumeratedValues>
                        </field>
                        <field>
                            <name>PDR12</name>
                            <description>Pmn Direction</description>
                            <lsb>12</lsb>
                            <msb>12</msb>
                            <access>read-write</access>
                            <enumeratedValues>
                                <enumeratedValue>
                                    <name>0</name>
                                    <description>Input (functions as an input pin)</description>
                                    <value>#0</value>
                                </enumeratedValue>
                                <enumeratedValue>
                                    <name>1</name>
                                    <description>Output (functions as an output pin)</description>
                                    <value>#1</value>
                                </enumeratedValue>
                            </enumeratedValues>
                        </field>
                        <field>
                            <name>PDR13</name>
                            <description>Pmn Direction</description>
                            <lsb>13</lsb>
                            <msb>13</msb>
                            <access>read-write</access>
                            <enumeratedValues>
                                <enumeratedValue>
                                    <name>0</name>
                                    <description>Input (functions as an input pin)</description>
                                    <value>#0</value>
                                </enumeratedValue>
                                <enumeratedValue>
                                    <name>1</name>
                                    <description>Output (functions as an output pin)</description>
                                    <value>#1</value>
                                </enumeratedValue>
                            </enumeratedValues>
                        </field>
                        <field>
                            <name>PDR14</name>
                            <description>Pmn Direction</description>
                            <lsb>14</lsb>
                            <msb>14</msb>
                            <access>read-write</access>
                            <enumeratedValues>
                                <enumeratedValue>
                                    <name>0</name>
                                    <description>Input (functions as an input pin)</description>
                                    <value>#0</value>
                                </enumeratedValue>
                                <enumeratedValue>
                                    <name>1</name>
                                    <description>Output (functions as an output pin)</description>
                                    <value>#1</value>
                                </enumeratedValue>
                            </enumeratedValues>
                        </field>
                        <field>
                            <name>PDR15</name>
                            <description>Pmn Direction</description>
                            <lsb>15</lsb>
                            <msb>15</msb>
                            <access>read-write</access>
                            <enumeratedValues>
                                <enumeratedValue>
                                    <name>0</name>
                                    <description>Input (functions as an input pin)</description>
                                    <value>#0</value>
                                </enumeratedValue>
                                <enumeratedValue>
                                    <name>1</name>
                                    <description>Output (functions as an output pin)</description>
                                    <value>#1</value>
                                </enumeratedValue>
                            </enumeratedValues>
                        </field>
                        <field>
                            <name>PODR00</name>
                            <description>Pmn Output Data</description>
                            <lsb>16</lsb>
                            <msb>16</msb>
                            <access>read-write</access>
                            <enumeratedValues>
                                <enumeratedValue>
                                    <name>0</name>
                                    <description>Low output</description>
                                    <value>#0</value>
                                </enumeratedValue>
                                <enumeratedValue>
                                    <name>1</name>
                                    <description>High output</description>
                                    <value>#1</value>
                                </enumeratedValue>
                            </enumeratedValues>
                        </field>
                        <field>
                            <name>PODR01</name>
                            <description>Pmn Output Data</description>
                            <lsb>17</lsb>
                            <msb>17</msb>
                            <access>read-write</access>
                            <enumeratedValues>
                                <enumeratedValue>
                                    <name>0</name>
                                    <description>Low output</description>
                                    <value>#0</value>
                                </enumeratedValue>
                                <enumeratedValue>
                                    <name>1</name>
                                    <description>High output</description>
                                    <value>#1</value>
                                </enumeratedValue>
                            </enumeratedValues>
                        </field>
                        <field>
                            <name>PODR02</name>
                            <description>Pmn Output Data</description>
                            <lsb>18</lsb>
                            <msb>18</msb>
                            <access>read-write</access>
                            <enumeratedValues>
                                <enumeratedValue>
                                    <name>0</name>
                                    <description>Low output</description>
                                    <value>#0</value>
                                </enumeratedValue>
                                <enumeratedValue>
                                    <name>1</name>
                                    <description>High output</description>
                                    <value>#1</value>
                                </enumeratedValue>
                            </enumeratedValues>
                        </field>
                        <field>
                            <name>PODR03</name>
                            <description>Pmn Output Data</description>
                            <lsb>19</lsb>
                            <msb>19</msb>
                            <access>read-write</access>
                            <enumeratedValues>
                                <enumeratedValue>
                                    <name>0</name>
                                    <description>Low output</description>
                                    <value>#0</value>
                                </enumeratedValue>
                                <enumeratedValue>
                                    <name>1</name>
                                    <description>High output</description>
                                    <value>#1</value>
                                </enumeratedValue>
                            </enumeratedValues>
                        </field>
                        <field>
                            <name>PODR04</name>
                            <description>Pmn Output Data</description>
                            <lsb>20</lsb>
                            <msb>20</msb>
                            <access>read-write</access>
                            <enumeratedValues>
                                <enumeratedValue>
                                    <name>0</name>
                                    <description>Low output</description>
                                    <value>#0</value>
                                </enumeratedValue>
                                <enumeratedValue>
                                    <name>1</name>
                                    <description>High output</description>
                                    <value>#1</value>
                                </enumeratedValue>
                            </enumeratedValues>
                        </field>
                        <field>
                            <name>PODR05</name>
                            <description>Pmn Output Data</description>
                            <lsb>21</lsb>
                            <msb>21</msb>
                            <access>read-write</access>
                            <enumeratedValues>
                                <enumeratedValue>
                                    <name>0</name>
                                    <description>Low output</description>
                                    <value>#0</value>
                                </enumeratedValue>
                                <enumeratedValue>
                                    <name>1</name>
                                    <description>High output</description>
                                    <value>#1</value>
                                </enumeratedValue>
                            </enumeratedValues>
                        </field>
                        <field>
                            <name>PODR06</name>
                            <description>Pmn Output Data</description>
                            <lsb>22</lsb>
                            <msb>22</msb>
                            <access>read-write</access>
                            <enumeratedValues>
                                <enumeratedValue>
                                    <name>0</name>
                                    <description>Low output</description>
                                    <value>#0</value>
                                </enumeratedValue>
                                <enumeratedValue>
                                    <name>1</name>
                                    <description>High output</description>
                                    <value>#1</value>
                                </enumeratedValue>
                            </enumeratedValues>
                        </field>
                        <field>
                            <name>PODR07</name>
                            <description>Pmn Output Data</description>
                            <lsb>23</lsb>
                            <msb>23</msb>
                            <access>read-write</access>
                            <enumeratedValues>
                                <enumeratedValue>
                                    <name>0</name>
                                    <description>Low output</description>
                                    <value>#0</value>
                                </enumeratedValue>
                                <enumeratedValue>
                                    <name>1</name>
                                    <description>High output</description>
                                    <value>#1</value>
                                </enumeratedValue>
                            </enumeratedValues>
                        </field>
                        <field>
                            <name>PODR08</name>
                            <description>Pmn Output Data</description>
                            <lsb>24</lsb>
                            <msb>24</msb>
                            <access>read-write</access>
                            <enumeratedValues>
                                <enumeratedValue>
                                    <name>0</name>
                                    <description>Low output</description>
                                    <value>#0</value>
                                </enumeratedValue>
                                <enumeratedValue>
                                    <name>1</name>
                                    <description>High output</description>
                                    <value>#1</value>
                                </enumeratedValue>
                            </enumeratedValues>
                        </field>
                        <field>
                            <name>PODR09</name>
                            <description>Pmn Output Data</description>
                            <lsb>25</lsb>
                            <msb>25</msb>
                            <access>read-write</access>
                            <enumeratedValues>
                                <enumeratedValue>
                                    <name>0</name>
                                    <description>Low output</description>
                                    <value>#0</value>
                                </enumeratedValue>
                                <enumeratedValue>
                                    <name>1</name>
                                    <description>High output</description>
                                    <value>#1</value>
                                </enumeratedValue>
                            </enumeratedValues>
                        </field>
                        <field>
                            <name>PODR10</name>
                            <description>Pmn Output Data</description>
                            <lsb>26</lsb>
                            <msb>26</msb>
                            <access>read-write</access>
                            <enumeratedValues>
                                <enumeratedValue>
                                    <name>0</name>
                                    <description>Low output</description>
                                    <value>#0</value>
                                </enumeratedValue>
                                <enumeratedValue>
                                    <name>1</name>
                                    <description>High output</description>
                                    <value>#1</value>
                                </enumeratedValue>
                            </enumeratedValues>
                        </field>
                        <field>
                            <name>PODR11</name>
                            <description>Pmn Output Data</description>
                            <lsb>27</lsb>
                            <msb>27</msb>
                            <access>read-write</access>
                            <enumeratedValues>
                                <enumeratedValue>
                                    <name>0</name>
                                    <description>Low output</description>
                                    <value>#0</value>
                                </enumeratedValue>
                                <enumeratedValue>
                                    <name>1</name>
                                    <description>High output</description>
                                    <value>#1</value>
                                </enumeratedValue>
                            </enumeratedValues>
                        </field>
                        <field>
                            <name>PODR12</name>
                            <description>Pmn Output Data</description>
                            <lsb>28</lsb>
                            <msb>28</msb>
                            <access>read-write</access>
                            <enumeratedValues>
                                <enumeratedValue>
                                    <name>0</name>
                                    <description>Low output</description>
                                    <value>#0</value>
                                </enumeratedValue>
                                <enumeratedValue>
                                    <name>1</name>
                                    <description>High output</description>
                                    <value>#1</value>
                                </enumeratedValue>
                            </enumeratedValues>
                        </field>
                        <field>
                            <name>PODR13</name>
                            <description>Pmn Output Data</description>
                            <lsb>29</lsb>
                            <msb>29</msb>
                            <access>read-write</access>
                            <enumeratedValues>
                                <enumeratedValue>
                                    <name>0</name>
                                    <description>Low output</description>
                                    <value>#0</value>
                                </enumeratedValue>
                                <enumeratedValue>
                                    <name>1</name>
                                    <description>High output</description>
                                    <value>#1</value>
                                </enumeratedValue>
                            </enumeratedValues>
                        </field>
                        <field>
                            <name>PODR14</name>
                            <description>Pmn Output Data</description>
                            <lsb>30</lsb>
                            <msb>30</msb>
                            <access>read-write</access>
                            <enumeratedValues>
                                <enumeratedValue>
                                    <name>0</name>
                                    <description>Low output</description>
                                    <value>#0</value>
                                </enumeratedValue>
                                <enumeratedValue>
                                    <name>1</name>
                                    <description>High output</description>
                                    <value>#1</value>
                                </enumeratedValue>
                            </enumeratedValues>
                        </field>
                        <field>
                            <name>PODR15</name>
                            <description>Pmn Output Data</description>
                            <lsb>31</lsb>
                            <msb>31</msb>
                            <access>read-write</access>
                            <enumeratedValues>
                                <enumeratedValue>
                                    <name>0</name>
                                    <description>Low output</description>
                                    <value>#0</value>
                                </enumeratedValue>
                                <enumeratedValue>
                                    <name>1</name>
                                    <description>High output</description>
                                    <value>#1</value>
                                </enumeratedValue>
                            </enumeratedValues>
                        </field>
                    </fields>
                </register>
                <register>
                    <name>PDR</name>
                    <description>Port Control Register 1</description>
                    <alternateRegister>PCNTR1</alternateRegister>
                    <addressOffset>0x000</addressOffset>
                    <size>16</size>
                    <access>read-write</access>
                    <resetValue>0x0000</resetValue>
                    <resetMask>0xffff</resetMask>
                    <fields>
                        <field>
                            <name>PODR00</name>
                            <description>Pmn Output Data</description>
                            <lsb>0</lsb>
                            <msb>0</msb>
                            <access>read-write</access>
                            <enumeratedValues>
                                <enumeratedValue>
                                    <name>0</name>
                                    <description>Low output</description>
                                    <value>#0</value>
                                </enumeratedValue>
                                <enumeratedValue>
                                    <name>1</name>
                                    <description>High output</description>
                                    <value>#1</value>
                                </enumeratedValue>
                            </enumeratedValues>
                        </field>
                        <field>
                            <name>PODR01</name>
                            <description>Pmn Output Data</description>
                            <lsb>1</lsb>
                            <msb>1</msb>
                            <access>read-write</access>
                            <enumeratedValues>
                                <enumeratedValue>
                                    <name>0</name>
                                    <description>Low output</description>
                                    <value>#0</value>
                                </enumeratedValue>
                                <enumeratedValue>
                                    <name>1</name>
                                    <description>High output</description>
                                    <value>#1</value>
                                </enumeratedValue>
                            </enumeratedValues>
                        </field>
                        <field>
                            <name>PODR02</name>
                            <description>Pmn Output Data</description>
                            <lsb>2</lsb>
                            <msb>2</msb>
                            <access>read-write</access>
                            <enumeratedValues>
                                <enumeratedValue>
                                    <name>0</name>
                                    <description>Low output</description>
                                    <value>#0</value>
                                </enumeratedValue>
                                <enumeratedValue>
                                    <name>1</name>
                                    <description>High output</description>
                                    <value>#1</value>
                                </enumeratedValue>
                            </enumeratedValues>
                        </field>
                        <field>
                            <name>PODR03</name>
                            <description>Pmn Output Data</description>
                            <lsb>3</lsb>
                            <msb>3</msb>
                            <access>read-write</access>
                            <enumeratedValues>
                                <enumeratedValue>
                                    <name>0</name>
                                    <description>Low output</description>
                                    <value>#0</value>
                                </enumeratedValue>
                                <enumeratedValue>
                                    <name>1</name>
                                    <description>High output</description>
                                    <value>#1</value>
                                </enumeratedValue>
                            </enumeratedValues>
                        </field>
                        <field>
                            <name>PODR04</name>
                            <description>Pmn Output Data</description>
                            <lsb>4</lsb>
                            <msb>4</msb>
                            <access>read-write</access>
                            <enumeratedValues>
                                <enumeratedValue>
                                    <name>0</name>
                                    <description>Low output</description>
                                    <value>#0</value>
                                </enumeratedValue>
                                <enumeratedValue>
                                    <name>1</name>
                                    <description>High output</description>
                                    <value>#1</value>
                                </enumeratedValue>
                            </enumeratedValues>
                        </field>
                        <field>
                            <name>PODR05</name>
                            <description>Pmn Output Data</description>
                            <lsb>5</lsb>
                            <msb>5</msb>
                            <access>read-write</access>
                            <enumeratedValues>
                                <enumeratedValue>
                                    <name>0</name>
                                    <description>Low output</description>
                                    <value>#0</value>
                                </enumeratedValue>
                                <enumeratedValue>
                                    <name>1</name>
                                    <description>High output</description>
                                    <value>#1</value>
                                </enumeratedValue>
                            </enumeratedValues>
                        </field>
                        <field>
                            <name>PODR06</name>
                            <description>Pmn Output Data</description>
                            <lsb>6</lsb>
                            <msb>6</msb>
                            <access>read-write</access>
                            <enumeratedValues>
                                <enumeratedValue>
                                    <name>0</name>
                                    <description>Low output</description>
                                    <value>#0</value>
                                </enumeratedValue>
                                <enumeratedValue>
                                    <name>1</name>
                                    <description>High output</description>
                                    <value>#1</value>
                                </enumeratedValue>
                            </enumeratedValues>
                        </field>
                        <field>
                            <name>PODR07</name>
                            <description>Pmn Output Data</description>
                            <lsb>7</lsb>
                            <msb>7</msb>
                            <access>read-write</access>
                            <enumeratedValues>
                                <enumeratedValue>
                                    <name>0</name>
                                    <description>Low output</description>
                                    <value>#0</value>
                                </enumeratedValue>
                                <enumeratedValue>
                                    <name>1</name>
                                    <description>High output</description>
                                    <value>#1</value>
                                </enumeratedValue>
                            </enumeratedValues>
                        </field>
                        <field>
                            <name>PODR08</name>
                            <description>Pmn Output Data</description>
                            <lsb>8</lsb>
                            <msb>8</msb>
                            <access>read-write</access>
                            <enumeratedValues>
                                <enumeratedValue>
                                    <name>0</name>
                                    <description>Low output</description>
                                    <value>#0</value>
                                </enumeratedValue>
                                <enumeratedValue>
                                    <name>1</name>
                                    <description>High output</description>
                                    <value>#1</value>
                                </enumeratedValue>
                            </enumeratedValues>
                        </field>
                        <field>
                            <name>PODR09</name>
                            <description>Pmn Output Data</description>
                            <lsb>9</lsb>
                            <msb>9</msb>
                            <access>read-write</access>
                            <enumeratedValues>
                                <enumeratedValue>
                                    <name>0</name>
                                    <description>Low output</description>
                                    <value>#0</value>
                                </enumeratedValue>
                                <enumeratedValue>
                                    <name>1</name>
                                    <description>High output</description>
                                    <value>#1</value>
                                </enumeratedValue>
                            </enumeratedValues>
                        </field>
                        <field>
                            <name>PODR10</name>
                            <description>Pmn Output Data</description>
                            <lsb>10</lsb>
                            <msb>10</msb>
                            <access>read-write</access>
                            <enumeratedValues>
                                <enumeratedValue>
                                    <name>0</name>
                                    <description>Low output</description>
                                    <value>#0</value>
                                </enumeratedValue>
                                <enumeratedValue>
                                    <name>1</name>
                                    <description>High output</description>
                                    <value>#1</value>
                                </enumeratedValue>
                            </enumeratedValues>
                        </field>
                        <field>
                            <name>PODR11</name>
                            <description>Pmn Output Data</description>
                            <lsb>11</lsb>
                            <msb>11</msb>
                            <access>read-write</access>
                            <enumeratedValues>
                                <enumeratedValue>
                                    <name>0</name>
                                    <description>Low output</description>
                                    <value>#0</value>
                                </enumeratedValue>
                                <enumeratedValue>
                                    <name>1</name>
                                    <description>High output</description>
                                    <value>#1</value>
                                </enumeratedValue>
                            </enumeratedValues>
                        </field>
                        <field>
                            <name>PODR12</name>
                            <description>Pmn Output Data</description>
                            <lsb>12</lsb>
                            <msb>12</msb>
                            <access>read-write</access>
                            <enumeratedValues>
                                <enumeratedValue>
                                    <name>0</name>
                                    <description>Low output</description>
                                    <value>#0</value>
                                </enumeratedValue>
                                <enumeratedValue>
                                    <name>1</name>
                                    <description>High output</description>
                                    <value>#1</value>
                                </enumeratedValue>
                            </enumeratedValues>
                        </field>
                        <field>
                            <name>PODR13</name>
                            <description>Pmn Output Data</description>
                            <lsb>13</lsb>
                            <msb>13</msb>
                            <access>read-write</access>
                            <enumeratedValues>
                                <enumeratedValue>
                                    <name>0</name>
                                    <description>Low output</description>
                                    <value>#0</value>
                                </enumeratedValue>
                                <enumeratedValue>
                                    <name>1</name>
                                    <description>High output</description>
                                    <value>#1</value>
                                </enumeratedValue>
                            </enumeratedValues>
                        </field>
                        <field>
                            <name>PODR14</name>
                            <description>Pmn Output Data</description>
                            <lsb>14</lsb>
                            <msb>14</msb>
                            <access>read-write</access>
                            <enumeratedValues>
                                <enumeratedValue>
                                    <name>0</name>
                                    <description>Low output</description>
                                    <value>#0</value>
                                </enumeratedValue>
                                <enumeratedValue>
                                    <name>1</name>
                                    <description>High output</description>
                                    <value>#1</value>
                                </enumeratedValue>
                            </enumeratedValues>
                        </field>
                        <field>
                            <name>PODR15</name>
                            <description>Pmn Output Data</description>
                            <lsb>15</lsb>
                            <msb>15</msb>
                            <access>read-write</access>
                            <enumeratedValues>
                                <enumeratedValue>
                                    <name>0</name>
                                    <description>Low output</description>
                                    <value>#0</value>
                                </enumeratedValue>
                                <enumeratedValue>
                                    <name>1</name>
                                    <description>High output</description>
                                    <value>#1</value>
                                </enumeratedValue>
                            </enumeratedValues>
                        </field>
                    </fields>
                </register>
                <register>
                    <name>PODR</name>
                    <description>Port Control Register 1</description>
                    <alternateRegister>PCNTR1</alternateRegister>
                    <addressOffset>0x002</addressOffset>
                    <size>16</size>
                    <access>read-write</access>
                    <resetValue>0x0000</resetValue>
                    <resetMask>0xffff</resetMask>
                    <fields>
                        <field>
                            <name>PDR00</name>
                            <description>Pmn Direction</description>
                            <lsb>0</lsb>
                            <msb>0</msb>
                            <access>read-write</access>
                            <enumeratedValues>
                                <enumeratedValue>
                                    <name>0</name>
                                    <description>Input (functions as an input pin)</description>
                                    <value>#0</value>
                                </enumeratedValue>
                                <enumeratedValue>
                                    <name>1</name>
                                    <description>Output (functions as an output pin)</description>
                                    <value>#1</value>
                                </enumeratedValue>
                            </enumeratedValues>
                        </field>
                        <field>
                            <name>PDR01</name>
                            <description>Pmn Direction</description>
                            <lsb>1</lsb>
                            <msb>1</msb>
                            <access>read-write</access>
                            <enumeratedValues>
                                <enumeratedValue>
                                    <name>0</name>
                                    <description>Input (functions as an input pin)</description>
                                    <value>#0</value>
                                </enumeratedValue>
                                <enumeratedValue>
                                    <name>1</name>
                                    <description>Output (functions as an output pin)</description>
                                    <value>#1</value>
                                </enumeratedValue>
                            </enumeratedValues>
                        </field>
                        <field>
                            <name>PDR02</name>
                            <description>Pmn Direction</description>
                            <lsb>2</lsb>
                            <msb>2</msb>
                            <access>read-write</access>
                            <enumeratedValues>
                                <enumeratedValue>
                                    <name>0</name>
                                    <description>Input (functions as an input pin)</description>
                                    <value>#0</value>
                                </enumeratedValue>
                                <enumeratedValue>
                                    <name>1</name>
                                    <description>Output (functions as an output pin)</description>
                                    <value>#1</value>
                                </enumeratedValue>
                            </enumeratedValues>
                        </field>
                        <field>
                            <name>PDR03</name>
                            <description>Pmn Direction</description>
                            <lsb>3</lsb>
                            <msb>3</msb>
                            <access>read-write</access>
                            <enumeratedValues>
                                <enumeratedValue>
                                    <name>0</name>
                                    <description>Input (functions as an input pin)</description>
                                    <value>#0</value>
                                </enumeratedValue>
                                <enumeratedValue>
                                    <name>1</name>
                                    <description>Output (functions as an output pin)</description>
                                    <value>#1</value>
                                </enumeratedValue>
                            </enumeratedValues>
                        </field>
                        <field>
                            <name>PDR04</name>
                            <description>Pmn Direction</description>
                            <lsb>4</lsb>
                            <msb>4</msb>
                            <access>read-write</access>
                            <enumeratedValues>
                                <enumeratedValue>
                                    <name>0</name>
                                    <description>Input (functions as an input pin)</description>
                                    <value>#0</value>
                                </enumeratedValue>
                                <enumeratedValue>
                                    <name>1</name>
                                    <description>Output (functions as an output pin)</description>
                                    <value>#1</value>
                                </enumeratedValue>
                            </enumeratedValues>
                        </field>
                        <field>
                            <name>PDR05</name>
                            <description>Pmn Direction</description>
                            <lsb>5</lsb>
                            <msb>5</msb>
                            <access>read-write</access>
                            <enumeratedValues>
                                <enumeratedValue>
                                    <name>0</name>
                                    <description>Input (functions as an input pin)</description>
                                    <value>#0</value>
                                </enumeratedValue>
                                <enumeratedValue>
                                    <name>1</name>
                                    <description>Output (functions as an output pin)</description>
                                    <value>#1</value>
                                </enumeratedValue>
                            </enumeratedValues>
                        </field>
                        <field>
                            <name>PDR06</name>
                            <description>Pmn Direction</description>
                            <lsb>6</lsb>
                            <msb>6</msb>
                            <access>read-write</access>
                            <enumeratedValues>
                                <enumeratedValue>
                                    <name>0</name>
                                    <description>Input (functions as an input pin)</description>
                                    <value>#0</value>
                                </enumeratedValue>
                                <enumeratedValue>
                                    <name>1</name>
                                    <description>Output (functions as an output pin)</description>
                                    <value>#1</value>
                                </enumeratedValue>
                            </enumeratedValues>
                        </field>
                        <field>
                            <name>PDR07</name>
                            <description>Pmn Direction</description>
                            <lsb>7</lsb>
                            <msb>7</msb>
                            <access>read-write</access>
                            <enumeratedValues>
                                <enumeratedValue>
                                    <name>0</name>
                                    <description>Input (functions as an input pin)</description>
                                    <value>#0</value>
                                </enumeratedValue>
                                <enumeratedValue>
                                    <name>1</name>
                                    <description>Output (functions as an output pin)</description>
                                    <value>#1</value>
                                </enumeratedValue>
                            </enumeratedValues>
                        </field>
                        <field>
                            <name>PDR08</name>
                            <description>Pmn Direction</description>
                            <lsb>8</lsb>
                            <msb>8</msb>
                            <access>read-write</access>
                            <enumeratedValues>
                                <enumeratedValue>
                                    <name>0</name>
                                    <description>Input (functions as an input pin)</description>
                                    <value>#0</value>
                                </enumeratedValue>
                                <enumeratedValue>
                                    <name>1</name>
                                    <description>Output (functions as an output pin)</description>
                                    <value>#1</value>
                                </enumeratedValue>
                            </enumeratedValues>
                        </field>
                        <field>
                            <name>PDR09</name>
                            <description>Pmn Direction</description>
                            <lsb>9</lsb>
                            <msb>9</msb>
                            <access>read-write</access>
                            <enumeratedValues>
                                <enumeratedValue>
                                    <name>0</name>
                                    <description>Input (functions as an input pin)</description>
                                    <value>#0</value>
                                </enumeratedValue>
                                <enumeratedValue>
                                    <name>1</name>
                                    <description>Output (functions as an output pin)</description>
                                    <value>#1</value>
                                </enumeratedValue>
                            </enumeratedValues>
                        </field>
                        <field>
                            <name>PDR10</name>
                            <description>Pmn Direction</description>
                            <lsb>10</lsb>
                            <msb>10</msb>
                            <access>read-write</access>
                            <enumeratedValues>
                                <enumeratedValue>
                                    <name>0</name>
                                    <description>Input (functions as an input pin)</description>
                                    <value>#0</value>
                                </enumeratedValue>
                                <enumeratedValue>
                                    <name>1</name>
                                    <description>Output (functions as an output pin)</description>
                                    <value>#1</value>
                                </enumeratedValue>
                            </enumeratedValues>
                        </field>
                        <field>
                            <name>PDR11</name>
                            <description>Pmn Direction</description>
                            <lsb>11</lsb>
                            <msb>11</msb>
                            <access>read-write</access>
                            <enumeratedValues>
                                <enumeratedValue>
                                    <name>0</name>
                                    <description>Input (functions as an input pin)</description>
                                    <value>#0</value>
                                </enumeratedValue>
                                <enumeratedValue>
                                    <name>1</name>
                                    <description>Output (functions as an output pin)</description>
                                    <value>#1</value>
                                </enumeratedValue>
                            </enumeratedValues>
                        </field>
                        <field>
                            <name>PDR12</name>
                            <description>Pmn Direction</description>
                            <lsb>12</lsb>
                            <msb>12</msb>
                            <access>read-write</access>
                            <enumeratedValues>
                                <enumeratedValue>
                                    <name>0</name>
                                    <description>Input (functions as an input pin)</description>
                                    <value>#0</value>
                                </enumeratedValue>
                                <enumeratedValue>
                                    <name>1</name>
                                    <description>Output (functions as an output pin)</description>
                                    <value>#1</value>
                                </enumeratedValue>
                            </enumeratedValues>
                        </field>
                        <field>
                            <name>PDR13</name>
                            <description>Pmn Direction</description>
                            <lsb>13</lsb>
                            <msb>13</msb>
                            <access>read-write</access>
                            <enumeratedValues>
                                <enumeratedValue>
                                    <name>0</name>
                                    <description>Input (functions as an input pin)</description>
                                    <value>#0</value>
                                </enumeratedValue>
                                <enumeratedValue>
                                    <name>1</name>
                                    <description>Output (functions as an output pin)</description>
                                    <value>#1</value>
                                </enumeratedValue>
                            </enumeratedValues>
                        </field>
                        <field>
                            <name>PDR14</name>
                            <description>Pmn Direction</description>
                            <lsb>14</lsb>
                            <msb>14</msb>
                            <access>read-write</access>
                            <enumeratedValues>
                                <enumeratedValue>
                                    <name>0</name>
                                    <description>Input (functions as an input pin)</description>
                                    <value>#0</value>
                                </enumeratedValue>
                                <enumeratedValue>
                                    <name>1</name>
                                    <description>Output (functions as an output pin)</description>
                                    <value>#1</value>
                                </enumeratedValue>
                            </enumeratedValues>
                        </field>
                        <field>
                            <name>PDR15</name>
                            <description>Pmn Direction</description>
                            <lsb>15</lsb>
                            <msb>15</msb>
                            <access>read-write</access>
                            <enumeratedValues>
                                <enumeratedValue>
                                    <name>0</name>
                                    <description>Input (functions as an input pin)</description>
                                    <value>#0</value>
                                </enumeratedValue>
                                <enumeratedValue>
                                    <name>1</name>
                                    <description>Output (functions as an output pin)</description>
                                    <value>#1</value>
                                </enumeratedValue>
                            </enumeratedValues>
                        </field>
                    </fields>
                </register>
                <register>
                    <name>PCNTR2</name>
                    <description>Port Control Register 2</description>
                    <addressOffset>0x004</addressOffset>
                    <size>32</size>
                    <access>read-only</access>
                    <resetValue>0x00000000</resetValue>
                    <resetMask>0xffff0000</resetMask>
                    <fields>
                        <field>
                            <name>PIDR00</name>
                            <description>Pmn State</description>
                            <lsb>0</lsb>
                            <msb>0</msb>
                            <access>read-only</access>
                            <enumeratedValues>
                                <enumeratedValue>
                                    <name>0</name>
                                    <description>Low level</description>
                                    <value>#0</value>
                                </enumeratedValue>
                                <enumeratedValue>
                                    <name>1</name>
                                    <description>High level</description>
                                    <value>#1</value>
                                </enumeratedValue>
                            </enumeratedValues>
                        </field>
                        <field>
                            <name>PIDR01</name>
                            <description>Pmn State</description>
                            <lsb>1</lsb>
                            <msb>1</msb>
                            <access>read-only</access>
                            <enumeratedValues>
                                <enumeratedValue>
                                    <name>0</name>
                                    <description>Low level</description>
                                    <value>#0</value>
                                </enumeratedValue>
                                <enumeratedValue>
                                    <name>1</name>
                                    <description>High level</description>
                                    <value>#1</value>
                                </enumeratedValue>
                            </enumeratedValues>
                        </field>
                        <field>
                            <name>PIDR02</name>
                            <description>Pmn State</description>
                            <lsb>2</lsb>
                            <msb>2</msb>
                            <access>read-only</access>
                            <enumeratedValues>
                                <enumeratedValue>
                                    <name>0</name>
                                    <description>Low level</description>
                                    <value>#0</value>
                                </enumeratedValue>
                                <enumeratedValue>
                                    <name>1</name>
                                    <description>High level</description>
                                    <value>#1</value>
                                </enumeratedValue>
                            </enumeratedValues>
                        </field>
                        <field>
                            <name>PIDR03</name>
                            <description>Pmn State</description>
                            <lsb>3</lsb>
                            <msb>3</msb>
                            <access>read-only</access>
                            <enumeratedValues>
                                <enumeratedValue>
                                    <name>0</name>
                                    <description>Low level</description>
                                    <value>#0</value>
                                </enumeratedValue>
                                <enumeratedValue>
                                    <name>1</name>
                                    <description>High level</description>
                                    <value>#1</value>
                                </enumeratedValue>
                            </enumeratedValues>
                        </field>
                        <field>
                            <name>PIDR04</name>
                            <description>Pmn State</description>
                            <lsb>4</lsb>
                            <msb>4</msb>
                            <access>read-only</access>
                            <enumeratedValues>
                                <enumeratedValue>
                                    <name>0</name>
                                    <description>Low level</description>
                                    <value>#0</value>
                                </enumeratedValue>
                                <enumeratedValue>
                                    <name>1</name>
                                    <description>High level</description>
                                    <value>#1</value>
                                </enumeratedValue>
                            </enumeratedValues>
                        </field>
                        <field>
                            <name>PIDR05</name>
                            <description>Pmn State</description>
                            <lsb>5</lsb>
                            <msb>5</msb>
                            <access>read-only</access>
                            <enumeratedValues>
                                <enumeratedValue>
                                    <name>0</name>
                                    <description>Low level</description>
                                    <value>#0</value>
                                </enumeratedValue>
                                <enumeratedValue>
                                    <name>1</name>
                                    <description>High level</description>
                                    <value>#1</value>
                                </enumeratedValue>
                            </enumeratedValues>
                        </field>
                        <field>
                            <name>PIDR06</name>
                            <description>Pmn State</description>
                            <lsb>6</lsb>
                            <msb>6</msb>
                            <access>read-only</access>
                            <enumeratedValues>
                                <enumeratedValue>
                                    <name>0</name>
                                    <description>Low level</description>
                                    <value>#0</value>
                                </enumeratedValue>
                                <enumeratedValue>
                                    <name>1</name>
                                    <description>High level</description>
                                    <value>#1</value>
                                </enumeratedValue>
                            </enumeratedValues>
                        </field>
                        <field>
                            <name>PIDR07</name>
                            <description>Pmn State</description>
                            <lsb>7</lsb>
                            <msb>7</msb>
                            <access>read-only</access>
                            <enumeratedValues>
                                <enumeratedValue>
                                    <name>0</name>
                                    <description>Low level</description>
                                    <value>#0</value>
                                </enumeratedValue>
                                <enumeratedValue>
                                    <name>1</name>
                                    <description>High level</description>
                                    <value>#1</value>
                                </enumeratedValue>
                            </enumeratedValues>
                        </field>
                        <field>
                            <name>PIDR08</name>
                            <description>Pmn State</description>
                            <lsb>8</lsb>
                            <msb>8</msb>
                            <access>read-only</access>
                            <enumeratedValues>
                                <enumeratedValue>
                                    <name>0</name>
                                    <description>Low level</description>
                                    <value>#0</value>
                                </enumeratedValue>
                                <enumeratedValue>
                                    <name>1</name>
                                    <description>High level</description>
                                    <value>#1</value>
                                </enumeratedValue>
                            </enumeratedValues>
                        </field>
                        <field>
                            <name>PIDR09</name>
                            <description>Pmn State</description>
                            <lsb>9</lsb>
                            <msb>9</msb>
                            <access>read-only</access>
                            <enumeratedValues>
                                <enumeratedValue>
                                    <name>0</name>
                                    <description>Low level</description>
                                    <value>#0</value>
                                </enumeratedValue>
                                <enumeratedValue>
                                    <name>1</name>
                                    <description>High level</description>
                                    <value>#1</value>
                                </enumeratedValue>
                            </enumeratedValues>
                        </field>
                        <field>
                            <name>PIDR10</name>
                            <description>Pmn State</description>
                            <lsb>10</lsb>
                            <msb>10</msb>
                            <access>read-only</access>
                            <enumeratedValues>
                                <enumeratedValue>
                                    <name>0</name>
                                    <description>Low level</description>
                                    <value>#0</value>
                                </enumeratedValue>
                                <enumeratedValue>
                                    <name>1</name>
                                    <description>High level</description>
                                    <value>#1</value>
                                </enumeratedValue>
                            </enumeratedValues>
                        </field>
                        <field>
                            <name>PIDR11</name>
                            <description>Pmn State</description>
                            <lsb>11</lsb>
                            <msb>11</msb>
                            <access>read-only</access>
                            <enumeratedValues>
                                <enumeratedValue>
                                    <name>0</name>
                                    <description>Low level</description>
                                    <value>#0</value>
                                </enumeratedValue>
                                <enumeratedValue>
                                    <name>1</name>
                                    <description>High level</description>
                                    <value>#1</value>
                                </enumeratedValue>
                            </enumeratedValues>
                        </field>
                        <field>
                            <name>PIDR12</name>
                            <description>Pmn State</description>
                            <lsb>12</lsb>
                            <msb>12</msb>
                            <access>read-only</access>
                            <enumeratedValues>
                                <enumeratedValue>
                                    <name>0</name>
                                    <description>Low level</description>
                                    <value>#0</value>
                                </enumeratedValue>
                                <enumeratedValue>
                                    <name>1</name>
                                    <description>High level</description>
                                    <value>#1</value>
                                </enumeratedValue>
                            </enumeratedValues>
                        </field>
                        <field>
                            <name>PIDR13</name>
                            <description>Pmn State</description>
                            <lsb>13</lsb>
                            <msb>13</msb>
                            <access>read-only</access>
                            <enumeratedValues>
                                <enumeratedValue>
                                    <name>0</name>
                                    <description>Low level</description>
                                    <value>#0</value>
                                </enumeratedValue>
                                <enumeratedValue>
                                    <name>1</name>
                                    <description>High level</description>
                                    <value>#1</value>
                                </enumeratedValue>
                            </enumeratedValues>
                        </field>
                        <field>
                            <name>PIDR14</name>
                            <description>Pmn State</description>
                            <lsb>14</lsb>
                            <msb>14</msb>
                            <access>read-only</access>
                            <enumeratedValues>
                                <enumeratedValue>
                                    <name>0</name>
                                    <description>Low level</description>
                                    <value>#0</value>
                                </enumeratedValue>
                                <enumeratedValue>
                                    <name>1</name>
                                    <description>High level</description>
                                    <value>#1</value>
                                </enumeratedValue>
                            </enumeratedValues>
                        </field>
                        <field>
                            <name>PIDR15</name>
                            <description>Pmn State</description>
                            <lsb>15</lsb>
                            <msb>15</msb>
                            <access>read-only</access>
                            <enumeratedValues>
                                <enumeratedValue>
                                    <name>0</name>
                                    <description>Low level</description>
                                    <value>#0</value>
                                </enumeratedValue>
                                <enumeratedValue>
                                    <name>1</name>
                                    <description>High level</description>
                                    <value>#1</value>
                                </enumeratedValue>
                            </enumeratedValues>
                        </field>
                    </fields>
                </register>
                <register>
                    <name>PIDR</name>
                    <description>Port Control Register 2</description>
                    <alternateRegister>PCNTR2</alternateRegister>
                    <addressOffset>0x004</addressOffset>
                    <size>16</size>
                    <access>read-only</access>
                    <resetValue>0x0000</resetValue>
                    <resetMask>0xffff</resetMask>
                </register>
                <register>
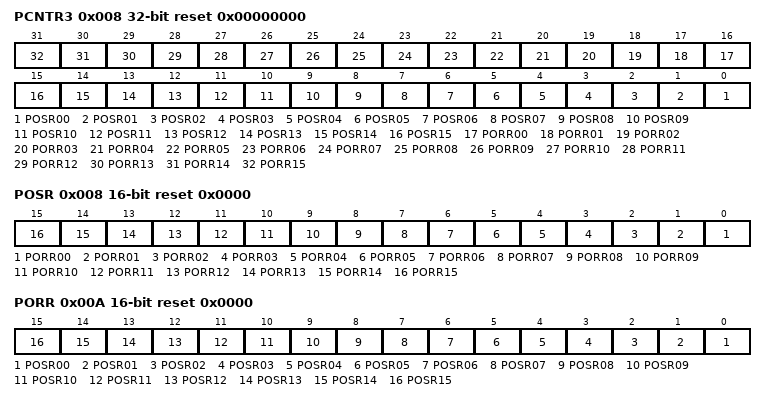
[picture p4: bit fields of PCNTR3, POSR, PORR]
                    <name>PCNTR3</name>
                    <description>Port Control Register 3</description>
                    <addressOffset>0x008</addressOffset>
                    <size>32</size>
                    <access>write-only</access>
                    <resetValue>0x00000000</resetValue>
                    <resetMask>0xffffffff</resetMask>
                    <fields>
                        <field>
                            <name>POSR00</name>
                            <description>Pmn Output Set</description>
                            <lsb>0</lsb>
                            <msb>0</msb>
                            <access>write-only</access>
                            <enumeratedValues>
                                <enumeratedValue>
                                    <name>0</name>
                                    <description>No effect on output</description>
                                    <value>#0</value>
                                </enumeratedValue>
                                <enumeratedValue>
                                    <name>1</name>
                                    <description>High output</description>
                                    <value>#1</value>
                                </enumeratedValue>
                            </enumeratedValues>
                        </field>
                        <field>
                            <name>POSR01</name>
                            <description>Pmn Output Set</description>
                            <lsb>1</lsb>
                            <msb>1</msb>
                            <access>write-only</access>
                            <enumeratedValues>
                                <enumeratedValue>
                                    <name>0</name>
                                    <description>No effect on output</description>
                                    <value>#0</value>
                                </enumeratedValue>
                                <enumeratedValue>
                                    <name>1</name>
                                    <description>High output</description>
                                    <value>#1</value>
                                </enumeratedValue>
                            </enumeratedValues>
                        </field>
                        <field>
                            <name>POSR02</name>
                            <description>Pmn Output Set</description>
                            <lsb>2</lsb>
                            <msb>2</msb>
                            <access>write-only</access>
                            <enumeratedValues>
                                <enumeratedValue>
                                    <name>0</name>
                                    <description>No effect on output</description>
                                    <value>#0</value>
                                </enumeratedValue>
                                <enumeratedValue>
                                    <name>1</name>
                                    <description>High output</description>
                                    <value>#1</value>
                                </enumeratedValue>
                            </enumeratedValues>
                        </field>
                        <field>
                            <name>POSR03</name>
                            <description>Pmn Output Set</description>
                            <lsb>3</lsb>
                            <msb>3</msb>
                            <access>write-only</access>
                            <enumeratedValues>
                                <enumeratedValue>
                                    <name>0</name>
                                    <description>No effect on output</description>
                                    <value>#0</value>
                                </enumeratedValue>
                                <enumeratedValue>
                                    <name>1</name>
                                    <description>High output</description>
                                    <value>#1</value>
                                </enumeratedValue>
                            </enumeratedValues>
                        </field>
                        <field>
                            <name>POSR04</name>
                            <description>Pmn Output Set</description>
                            <lsb>4</lsb>
                            <msb>4</msb>
                            <access>write-only</access>
                            <enumeratedValues>
                                <enumeratedValue>
                                    <name>0</name>
                                    <description>No effect on output</description>
                                    <value>#0</value>
                                </enumeratedValue>
                                <enumeratedValue>
                                    <name>1</name>
                                    <description>High output</description>
                                    <value>#1</value>
                                </enumeratedValue>
                            </enumeratedValues>
                        </field>
                        <field>
                            <name>POSR05</name>
                            <description>Pmn Output Set</description>
                            <lsb>5</lsb>
                            <msb>5</msb>
                            <access>write-only</access>
                            <enumeratedValues>
                                <enumeratedValue>
                                    <name>0</name>
                                    <description>No effect on output</description>
                                    <value>#0</value>
                                </enumeratedValue>
                                <enumeratedValue>
                                    <name>1</name>
                                    <description>High output</description>
                                    <value>#1</value>
                                </enumeratedValue>
                            </enumeratedValues>
                        </field>
                        <field>
                            <name>POSR06</name>
                            <description>Pmn Output Set</description>
                            <lsb>6</lsb>
                            <msb>6</msb>
                            <access>write-only</access>
                            <enumeratedValues>
                                <enumeratedValue>
                                    <name>0</name>
                                    <description>No effect on output</description>
                                    <value>#0</value>
                                </enumeratedValue>
                                <enumeratedValue>
                                    <name>1</name>
                                    <description>High output</description>
                                    <value>#1</value>
                                </enumeratedValue>
                            </enumeratedValues>
                        </field>
                        <field>
                            <name>POSR07</name>
                            <description>Pmn Output Set</description>
                            <lsb>7</lsb>
                            <msb>7</msb>
                            <access>write-only</access>
                            <enumeratedValues>
                                <enumeratedValue>
                                    <name>0</name>
                                    <description>No effect on output</description>
                                    <value>#0</value>
                                </enumeratedValue>
                                <enumeratedValue>
                                    <name>1</name>
                                    <description>High output</description>
                                    <value>#1</value>
                                </enumeratedValue>
                            </enumeratedValues>
                        </field>
                        <field>
                            <name>POSR08</name>
                            <description>Pmn Output Set</description>
                            <lsb>8</lsb>
                            <msb>8</msb>
                            <access>write-only</access>
                            <enumeratedValues>
                                <enumeratedValue>
                                    <name>0</name>
                                    <description>No effect on output</description>
                                    <value>#0</value>
                                </enumeratedValue>
                                <enumeratedValue>
                                    <name>1</name>
                                    <description>High output</description>
                                    <value>#1</value>
                                </enumeratedValue>
                            </enumeratedValues>
                        </field>
                        <field>
                            <name>POSR09</name>
                            <description>Pmn Output Set</description>
                            <lsb>9</lsb>
                            <msb>9</msb>
                            <access>write-only</access>
                            <enumeratedValues>
                                <enumeratedValue>
                                    <name>0</name>
                                    <description>No effect on output</description>
                                    <value>#0</value>
                                </enumeratedValue>
                                <enumeratedValue>
                                    <name>1</name>
                                    <description>High output</description>
                                    <value>#1</value>
                                </enumeratedValue>
                            </enumeratedValues>
                        </field>
                        <field>
                            <name>POSR10</name>
                            <description>Pmn Output Set</description>
                            <lsb>10</lsb>
                            <msb>10</msb>
                            <access>write-only</access>
                            <enumeratedValues>
                                <enumeratedValue>
                                    <name>0</name>
                                    <description>No effect on output</description>
                                    <value>#0</value>
                                </enumeratedValue>
                                <enumeratedValue>
                                    <name>1</name>
                                    <description>High output</description>
                                    <value>#1</value>
                                </enumeratedValue>
                            </enumeratedValues>
                        </field>
                        <field>
                            <name>POSR11</name>
                            <description>Pmn Output Set</description>
                            <lsb>11</lsb>
                            <msb>11</msb>
                            <access>write-only</access>
                            <enumeratedValues>
                                <enumeratedValue>
                                    <name>0</name>
                                    <description>No effect on output</description>
                                    <value>#0</value>
                                </enumeratedValue>
                                <enumeratedValue>
                                    <name>1</name>
                                    <description>High output</description>
                                    <value>#1</value>
                                </enumeratedValue>
                            </enumeratedValues>
                        </field>
                        <field>
                            <name>POSR12</name>
                            <description>Pmn Output Set</description>
                            <lsb>12</lsb>
                            <msb>12</msb>
                            <access>write-only</access>
                            <enumeratedValues>
                                <enumeratedValue>
                                    <name>0</name>
                                    <description>No effect on output</description>
                                    <value>#0</value>
                                </enumeratedValue>
                                <enumeratedValue>
                                    <name>1</name>
                                    <description>High output</description>
                                    <value>#1</value>
                                </enumeratedValue>
                            </enumeratedValues>
                        </field>
                        <field>
                            <name>POSR13</name>
                            <description>Pmn Output Set</description>
                            <lsb>13</lsb>
                            <msb>13</msb>
                            <access>write-only</access>
                            <enumeratedValues>
                                <enumeratedValue>
                                    <name>0</name>
                                    <description>No effect on output</description>
                                    <value>#0</value>
                                </enumeratedValue>
                                <enumeratedValue>
                                    <name>1</name>
                                    <description>High output</description>
                                    <value>#1</value>
                                </enumeratedValue>
                            </enumeratedValues>
                        </field>
                        <field>
                            <name>POSR14</name>
                            <description>Pmn Output Set</description>
                            <lsb>14</lsb>
                            <msb>14</msb>
                            <access>write-only</access>
                            <enumeratedValues>
                                <enumeratedValue>
                                    <name>0</name>
                                    <description>No effect on output</description>
                                    <value>#0</value>
                                </enumeratedValue>
                                <enumeratedValue>
                                    <name>1</name>
                                    <description>High output</description>
                                    <value>#1</value>
                                </enumeratedValue>
                            </enumeratedValues>
                        </field>
                        <field>
                            <name>POSR15</name>
                            <description>Pmn Output Set</description>
                            <lsb>15</lsb>
                            <msb>15</msb>
                            <access>write-only</access>
                            <enumeratedValues>
                                <enumeratedValue>
                                    <name>0</name>
                                    <description>No effect on output</description>
                                    <value>#0</value>
                                </enumeratedValue>
                                <enumeratedValue>
                                    <name>1</name>
                                    <description>High output</description>
                                    <value>#1</value>
                                </enumeratedValue>
                            </enumeratedValues>
                        </field>
                        <field>
                            <name>PORR00</name>
                            <description>Pmn Output Reset</description>
                            <lsb>16</lsb>
                            <msb>16</msb>
                            <access>write-only</access>
                            <enumeratedValues>
                                <enumeratedValue>
                                    <name>0</name>
                                    <description>No effect on output</description>
                                    <value>#0</value>
                                </enumeratedValue>
                                <enumeratedValue>
                                    <name>1</name>
                                    <description>Low output</description>
                                    <value>#1</value>
                                </enumeratedValue>
                            </enumeratedValues>
                        </field>
                        <field>
                            <name>PORR01</name>
                            <description>Pmn Output Reset</description>
                            <lsb>17</lsb>
                            <msb>17</msb>
                            <access>write-only</access>
                            <enumeratedValues>
                                <enumeratedValue>
                                    <name>0</name>
                                    <description>No effect on output</description>
                                    <value>#0</value>
                                </enumeratedValue>
                                <enumeratedValue>
                                    <name>1</name>
                                    <description>Low output</description>
                                    <value>#1</value>
                                </enumeratedValue>
                            </enumeratedValues>
                        </field>
                        <field>
                            <name>PORR02</name>
                            <description>Pmn Output Reset</description>
                            <lsb>18</lsb>
                            <msb>18</msb>
                            <access>write-only</access>
                            <enumeratedValues>
                                <enumeratedValue>
                                    <name>0</name>
                                    <description>No effect on output</description>
                                    <value>#0</value>
                                </enumeratedValue>
                                <enumeratedValue>
                                    <name>1</name>
                                    <description>Low output</description>
                                    <value>#1</value>
                                </enumeratedValue>
                            </enumeratedValues>
                        </field>
                        <field>
                            <name>PORR03</name>
                            <description>Pmn Output Reset</description>
                            <lsb>19</lsb>
                            <msb>19</msb>
                            <access>write-only</access>
                            <enumeratedValues>
                                <enumeratedValue>
                                    <name>0</name>
                                    <description>No effect on output</description>
                                    <value>#0</value>
                                </enumeratedValue>
                                <enumeratedValue>
                                    <name>1</name>
                                    <description>Low output</description>
                                    <value>#1</value>
                                </enumeratedValue>
                            </enumeratedValues>
                        </field>
                        <field>
                            <name>PORR04</name>
                            <description>Pmn Output Reset</description>
                            <lsb>20</lsb>
                            <msb>20</msb>
                            <access>write-only</access>
                            <enumeratedValues>
                                <enumeratedValue>
                                    <name>0</name>
                                    <description>No effect on output</description>
                                    <value>#0</value>
                                </enumeratedValue>
                                <enumeratedValue>
                                    <name>1</name>
                                    <description>Low output</description>
                                    <value>#1</value>
                                </enumeratedValue>
                            </enumeratedValues>
                        </field>
                        <field>
                            <name>PORR05</name>
                            <description>Pmn Output Reset</description>
                            <lsb>21</lsb>
                            <msb>21</msb>
                            <access>write-only</access>
                            <enumeratedValues>
                                <enumeratedValue>
                                    <name>0</name>
                                    <description>No effect on output</description>
                                    <value>#0</value>
                                </enumeratedValue>
                                <enumeratedValue>
                                    <name>1</name>
                                    <description>Low output</description>
                                    <value>#1</value>
                                </enumeratedValue>
                            </enumeratedValues>
                        </field>
                        <field>
                            <name>PORR06</name>
                            <description>Pmn Output Reset</description>
                            <lsb>22</lsb>
                            <msb>22</msb>
                            <access>write-only</access>
                            <enumeratedValues>
                                <enumeratedValue>
                                    <name>0</name>
                                    <description>No effect on output</description>
                                    <value>#0</value>
                                </enumeratedValue>
                                <enumeratedValue>
                                    <name>1</name>
                                    <description>Low output</description>
                                    <value>#1</value>
                                </enumeratedValue>
                            </enumeratedValues>
                        </field>
                        <field>
                            <name>PORR07</name>
                            <description>Pmn Output Reset</description>
                            <lsb>23</lsb>
                            <msb>23</msb>
                            <access>write-only</access>
                            <enumeratedValues>
                                <enumeratedValue>
                                    <name>0</name>
                                    <description>No effect on output</description>
                                    <value>#0</value>
                                </enumeratedValue>
                                <enumeratedValue>
                                    <name>1</name>
                                    <description>Low output</description>
                                    <value>#1</value>
                                </enumeratedValue>
                            </enumeratedValues>
                        </field>
                        <field>
                            <name>PORR08</name>
                            <description>Pmn Output Reset</description>
                            <lsb>24</lsb>
                            <msb>24</msb>
                            <access>write-only</access>
                            <enumeratedValues>
                                <enumeratedValue>
                                    <name>0</name>
                                    <description>No effect on output</description>
                                    <value>#0</value>
                                </enumeratedValue>
                                <enumeratedValue>
                                    <name>1</name>
                                    <description>Low output</description>
                                    <value>#1</value>
                                </enumeratedValue>
                            </enumeratedValues>
                        </field>
                        <field>
                            <name>PORR09</name>
                            <description>Pmn Output Reset</description>
                            <lsb>25</lsb>
                            <msb>25</msb>
                            <access>write-only</access>
                            <enumeratedValues>
                                <enumeratedValue>
                                    <name>0</name>
                                    <description>No effect on output</description>
                                    <value>#0</value>
                                </enumeratedValue>
                                <enumeratedValue>
                                    <name>1</name>
                                    <description>Low output</description>
                                    <value>#1</value>
                                </enumeratedValue>
                            </enumeratedValues>
                        </field>
                        <field>
                            <name>PORR10</name>
                            <description>Pmn Output Reset</description>
                            <lsb>26</lsb>
                            <msb>26</msb>
                            <access>write-only</access>
                            <enumeratedValues>
                                <enumeratedValue>
                                    <name>0</name>
                                    <description>No effect on output</description>
                                    <value>#0</value>
                                </enumeratedValue>
                                <enumeratedValue>
                                    <name>1</name>
                                    <description>Low output</description>
                                    <value>#1</value>
                                </enumeratedValue>
                            </enumeratedValues>
                        </field>
                        <field>
                            <name>PORR11</name>
                            <description>Pmn Output Reset</description>
                            <lsb>27</lsb>
                            <msb>27</msb>
                            <access>write-only</access>
                            <enumeratedValues>
                                <enumeratedValue>
                                    <name>0</name>
                                    <description>No effect on output</description>
                                    <value>#0</value>
                                </enumeratedValue>
                                <enumeratedValue>
                                    <name>1</name>
                                    <description>Low output</description>
                                    <value>#1</value>
                                </enumeratedValue>
                            </enumeratedValues>
                        </field>
                        <field>
                            <name>PORR12</name>
                            <description>Pmn Output Reset</description>
                            <lsb>28</lsb>
                            <msb>28</msb>
                            <access>write-only</access>
                            <enumeratedValues>
                                <enumeratedValue>
                                    <name>0</name>
                                    <description>No effect on output</description>
                                    <value>#0</value>
                                </enumeratedValue>
                                <enumeratedValue>
                                    <name>1</name>
                                    <description>Low output</description>
                                    <value>#1</value>
                                </enumeratedValue>
                            </enumeratedValues>
                        </field>
                        <field>
                            <name>PORR13</name>
                            <description>Pmn Output Reset</description>
                            <lsb>29</lsb>
                            <msb>29</msb>
                            <access>write-only</access>
                            <enumeratedValues>
                                <enumeratedValue>
                                    <name>0</name>
                                    <description>No effect on output</description>
                                    <value>#0</value>
                                </enumeratedValue>
                                <enumeratedValue>
                                    <name>1</name>
                                    <description>Low output</description>
                                    <value>#1</value>
                                </enumeratedValue>
                            </enumeratedValues>
                        </field>
                        <field>
                            <name>PORR14</name>
                            <description>Pmn Output Reset</description>
                            <lsb>30</lsb>
                            <msb>30</msb>
                            <access>write-only</access>
                            <enumeratedValues>
                                <enumeratedValue>
                                    <name>0</name>
                                    <description>No effect on output</description>
                                    <value>#0</value>
                                </enumeratedValue>
                                <enumeratedValue>
                                    <name>1</name>
                                    <description>Low output</description>
                                    <value>#1</value>
                                </enumeratedValue>
                            </enumeratedValues>
                        </field>
                        <field>
                            <name>PORR15</name>
                            <description>Pmn Output Reset</description>
                            <lsb>31</lsb>
                            <msb>31</msb>
                            <access>write-only</access>
                            <enumeratedValues>
                                <enumeratedValue>
                                    <name>0</name>
                                    <description>No effect on output</description>
                                    <value>#0</value>
                                </enumeratedValue>
                                <enumeratedValue>
                                    <name>1</name>
                                    <description>Low output</description>
                                    <value>#1</value>
                                </enumeratedValue>
                            </enumeratedValues>
                        </field>
                    </fields>
                </register>
                <register>
                    <name>POSR</name>
                    <description>Port Control Register 3</description>
                    <alternateRegister>PCNTR3</alternateRegister>
                    <addressOffset>0x008</addressOffset>
                    <size>16</size>
                    <access>write-only</access>
                    <resetValue>0x0000</resetValue>
                    <resetMask>0xffff</resetMask>
                    <fields>
                        <field>
                            <name>PORR00</name>
                            <description>Pmn Output Reset</description>
                            <lsb>0</lsb>
                            <msb>0</msb>
                            <access>write-only</access>
                            <enumeratedValues>
                                <enumeratedValue>
                                    <name>0</name>
                                    <description>No effect on output</description>
                                    <value>#0</value>
                                </enumeratedValue>
                                <enumeratedValue>
                                    <name>1</name>
                                    <description>Low output</description>
                                    <value>#1</value>
                                </enumeratedValue>
                            </enumeratedValues>
                        </field>
                        <field>
                            <name>PORR01</name>
                            <description>Pmn Output Reset</description>
                            <lsb>1</lsb>
                            <msb>1</msb>
                            <access>write-only</access>
                            <enumeratedValues>
                                <enumeratedValue>
                                    <name>0</name>
                                    <description>No effect on output</description>
                                    <value>#0</value>
                                </enumeratedValue>
                                <enumeratedValue>
                                    <name>1</name>
                                    <description>Low output</description>
                                    <value>#1</value>
                                </enumeratedValue>
                            </enumeratedValues>
                        </field>
                        <field>
                            <name>PORR02</name>
                            <description>Pmn Output Reset</description>
                            <lsb>2</lsb>
                            <msb>2</msb>
                            <access>write-only</access>
                            <enumeratedValues>
                                <enumeratedValue>
                                    <name>0</name>
                                    <description>No effect on output</description>
                                    <value>#0</value>
                                </enumeratedValue>
                                <enumeratedValue>
                                    <name>1</name>
                                    <description>Low output</description>
                                    <value>#1</value>
                                </enumeratedValue>
                            </enumeratedValues>
                        </field>
                        <field>
                            <name>PORR03</name>
                            <description>Pmn Output Reset</description>
                            <lsb>3</lsb>
                            <msb>3</msb>
                            <access>write-only</access>
                            <enumeratedValues>
                                <enumeratedValue>
                                    <name>0</name>
                                    <description>No effect on output</description>
                                    <value>#0</value>
                                </enumeratedValue>
                                <enumeratedValue>
                                    <name>1</name>
                                    <description>Low output</description>
                                    <value>#1</value>
                                </enumeratedValue>
                            </enumeratedValues>
                        </field>
                        <field>
                            <name>PORR04</name>
                            <description>Pmn Output Reset</description>
                            <lsb>4</lsb>
                            <msb>4</msb>
                            <access>write-only</access>
                            <enumeratedValues>
                                <enumeratedValue>
                                    <name>0</name>
                                    <description>No effect on output</description>
                                    <value>#0</value>
                                </enumeratedValue>
                                <enumeratedValue>
                                    <name>1</name>
                                    <description>Low output</description>
                                    <value>#1</value>
                                </enumeratedValue>
                            </enumeratedValues>
                        </field>
                        <field>
                            <name>PORR05</name>
                            <description>Pmn Output Reset</description>
                            <lsb>5</lsb>
                            <msb>5</msb>
                            <access>write-only</access>
                            <enumeratedValues>
                                <enumeratedValue>
                                    <name>0</name>
                                    <description>No effect on output</description>
                                    <value>#0</value>
                                </enumeratedValue>
                                <enumeratedValue>
                                    <name>1</name>
                                    <description>Low output</description>
                                    <value>#1</value>
                                </enumeratedValue>
                            </enumeratedValues>
                        </field>
                        <field>
                            <name>PORR06</name>
                            <description>Pmn Output Reset</description>
                            <lsb>6</lsb>
                            <msb>6</msb>
                            <access>write-only</access>
                            <enumeratedValues>
                                <enumeratedValue>
                                    <name>0</name>
                                    <description>No effect on output</description>
                                    <value>#0</value>
                                </enumeratedValue>
                                <enumeratedValue>
                                    <name>1</name>
                                    <description>Low output</description>
                                    <value>#1</value>
                                </enumeratedValue>
                            </enumeratedValues>
                        </field>
                        <field>
                            <name>PORR07</name>
                            <description>Pmn Output Reset</description>
                            <lsb>7</lsb>
                            <msb>7</msb>
                            <access>write-only</access>
                            <enumeratedValues>
                                <enumeratedValue>
                                    <name>0</name>
                                    <description>No effect on output</description>
                                    <value>#0</value>
                                </enumeratedValue>
                                <enumeratedValue>
                                    <name>1</name>
                                    <description>Low output</description>
                                    <value>#1</value>
                                </enumeratedValue>
                            </enumeratedValues>
                        </field>
                        <field>
                            <name>PORR08</name>
                            <description>Pmn Output Reset</description>
                            <lsb>8</lsb>
                            <msb>8</msb>
                            <access>write-only</access>
                            <enumeratedValues>
                                <enumeratedValue>
                                    <name>0</name>
                                    <description>No effect on output</description>
                                    <value>#0</value>
                                </enumeratedValue>
                                <enumeratedValue>
                                    <name>1</name>
                                    <description>Low output</description>
                                    <value>#1</value>
                                </enumeratedValue>
                            </enumeratedValues>
                        </field>
                        <field>
                            <name>PORR09</name>
                            <description>Pmn Output Reset</description>
                            <lsb>9</lsb>
                            <msb>9</msb>
                            <access>write-only</access>
                            <enumeratedValues>
                                <enumeratedValue>
                                    <name>0</name>
                                    <description>No effect on output</description>
                                    <value>#0</value>
                                </enumeratedValue>
                                <enumeratedValue>
                                    <name>1</name>
                                    <description>Low output</description>
                                    <value>#1</value>
                                </enumeratedValue>
                            </enumeratedValues>
                        </field>
                        <field>
                            <name>PORR10</name>
                            <description>Pmn Output Reset</description>
                            <lsb>10</lsb>
                            <msb>10</msb>
                            <access>write-only</access>
                            <enumeratedValues>
                                <enumeratedValue>
                                    <name>0</name>
                                    <description>No effect on output</description>
                                    <value>#0</value>
                                </enumeratedValue>
                                <enumeratedValue>
                                    <name>1</name>
                                    <description>Low output</description>
                                    <value>#1</value>
                                </enumeratedValue>
                            </enumeratedValues>
                        </field>
                        <field>
                            <name>PORR11</name>
                            <description>Pmn Output Reset</description>
                            <lsb>11</lsb>
                            <msb>11</msb>
                            <access>write-only</access>
                            <enumeratedValues>
                                <enumeratedValue>
                                    <name>0</name>
                                    <description>No effect on output</description>
                                    <value>#0</value>
                                </enumeratedValue>
                                <enumeratedValue>
                                    <name>1</name>
                                    <description>Low output</description>
                                    <value>#1</value>
                                </enumeratedValue>
                            </enumeratedValues>
                        </field>
                        <field>
                            <name>PORR12</name>
                            <description>Pmn Output Reset</description>
                            <lsb>12</lsb>
                            <msb>12</msb>
                            <access>write-only</access>
                            <enumeratedValues>
                                <enumeratedValue>
                                    <name>0</name>
                                    <description>No effect on output</description>
                                    <value>#0</value>
                                </enumeratedValue>
                                <enumeratedValue>
                                    <name>1</name>
                                    <description>Low output</description>
                                    <value>#1</value>
                                </enumeratedValue>
                            </enumeratedValues>
                        </field>
                        <field>
                            <name>PORR13</name>
                            <description>Pmn Output Reset</description>
                            <lsb>13</lsb>
                            <msb>13</msb>
                            <access>write-only</access>
                            <enumeratedValues>
                                <enumeratedValue>
                                    <name>0</name>
                                    <description>No effect on output</description>
                                    <value>#0</value>
                                </enumeratedValue>
                                <enumeratedValue>
                                    <name>1</name>
                                    <description>Low output</description>
                                    <value>#1</value>
                                </enumeratedValue>
                            </enumeratedValues>
                        </field>
                        <field>
                            <name>PORR14</name>
                            <description>Pmn Output Reset</description>
                            <lsb>14</lsb>
                            <msb>14</msb>
                            <access>write-only</access>
                            <enumeratedValues>
                                <enumeratedValue>
                                    <name>0</name>
                                    <description>No effect on output</description>
                                    <value>#0</value>
                                </enumeratedValue>
                                <enumeratedValue>
                                    <name>1</name>
                                    <description>Low output</description>
                                    <value>#1</value>
                                </enumeratedValue>
                            </enumeratedValues>
                        </field>
                        <field>
                            <name>PORR15</name>
                            <description>Pmn Output Reset</description>
                            <lsb>15</lsb>
                            <msb>15</msb>
                            <access>write-only</access>
                            <enumeratedValues>
                                <enumeratedValue>
                                    <name>0</name>
                                    <description>No effect on output</description>
                                    <value>#0</value>
                                </enumeratedValue>
                                <enumeratedValue>
                                    <name>1</name>
                                    <description>Low output</description>
                                    <value>#1</value>
                                </enumeratedValue>
                            </enumeratedValues>
                        </field>
                    </fields>
                </register>
                <register>
                    <name>PORR</name>
                    <description>Port Control Register 3</description>
                    <alternateRegister>PCNTR3</alternateRegister>
                    <addressOffset>0x00A</addressOffset>
                    <size>16</size>
                    <access>write-only</access>
                    <resetValue>0x0000</resetValue>
                    <resetMask>0xffff</resetMask>
                    <fields>
                        <field>
                            <name>POSR00</name>
                            <description>Pmn Output Set</description>
                            <lsb>0</lsb>
                            <msb>0</msb>
                            <access>write-only</access>
                            <enumeratedValues>
                                <enumeratedValue>
                                    <name>0</name>
                                    <description>No effect on output</description>
                                    <value>#0</value>
                                </enumeratedValue>
                                <enumeratedValue>
                                    <name>1</name>
                                    <description>High output</description>
                                    <value>#1</value>
                                </enumeratedValue>
                            </enumeratedValues>
                        </field>
                        <field>
                            <name>POSR01</name>
                            <description>Pmn Output Set</description>
                            <lsb>1</lsb>
                            <msb>1</msb>
                            <access>write-only</access>
                            <enumeratedValues>
                                <enumeratedValue>
                                    <name>0</name>
                                    <description>No effect on output</description>
                                    <value>#0</value>
                                </enumeratedValue>
                                <enumeratedValue>
                                    <name>1</name>
                                    <description>High output</description>
                                    <value>#1</value>
                                </enumeratedValue>
                            </enumeratedValues>
                        </field>
                        <field>
                            <name>POSR02</name>
                            <description>Pmn Output Set</description>
                            <lsb>2</lsb>
                            <msb>2</msb>
                            <access>write-only</access>
                            <enumeratedValues>
                                <enumeratedValue>
                                    <name>0</name>
                                    <description>No effect on output</description>
                                    <value>#0</value>
                                </enumeratedValue>
                                <enumeratedValue>
                                    <name>1</name>
                                    <description>High output</description>
                                    <value>#1</value>
                                </enumeratedValue>
                            </enumeratedValues>
                        </field>
                        <field>
                            <name>POSR03</name>
                            <description>Pmn Output Set</description>
                            <lsb>3</lsb>
                            <msb>3</msb>
                            <access>write-only</access>
                            <enumeratedValues>
                                <enumeratedValue>
                                    <name>0</name>
                                    <description>No effect on output</description>
                                    <value>#0</value>
                                </enumeratedValue>
                                <enumeratedValue>
                                    <name>1</name>
                                    <description>High output</description>
                                    <value>#1</value>
                                </enumeratedValue>
                            </enumeratedValues>
                        </field>
                        <field>
                            <name>POSR04</name>
                            <description>Pmn Output Set</description>
                            <lsb>4</lsb>
                            <msb>4</msb>
                            <access>write-only</access>
                            <enumeratedValues>
                                <enumeratedValue>
                                    <name>0</name>
                                    <description>No effect on output</description>
                                    <value>#0</value>
                                </enumeratedValue>
                                <enumeratedValue>
                                    <name>1</name>
                                    <description>High output</description>
                                    <value>#1</value>
                                </enumeratedValue>
                            </enumeratedValues>
                        </field>
                        <field>
                            <name>POSR05</name>
                            <description>Pmn Output Set</description>
                            <lsb>5</lsb>
                            <msb>5</msb>
                            <access>write-only</access>
                            <enumeratedValues>
                                <enumeratedValue>
                                    <name>0</name>
                                    <description>No effect on output</description>
                                    <value>#0</value>
                                </enumeratedValue>
                                <enumeratedValue>
                                    <name>1</name>
                                    <description>High output</description>
                                    <value>#1</value>
                                </enumeratedValue>
                            </enumeratedValues>
                        </field>
                        <field>
                            <name>POSR06</name>
                            <description>Pmn Output Set</description>
                            <lsb>6</lsb>
                            <msb>6</msb>
                            <access>write-only</access>
                            <enumeratedValues>
                                <enumeratedValue>
                                    <name>0</name>
                                    <description>No effect on output</description>
                                    <value>#0</value>
                                </enumeratedValue>
                                <enumeratedValue>
                                    <name>1</name>
                                    <description>High output</description>
                                    <value>#1</value>
                                </enumeratedValue>
                            </enumeratedValues>
                        </field>
                        <field>
                            <name>POSR07</name>
                            <description>Pmn Output Set</description>
                            <lsb>7</lsb>
                            <msb>7</msb>
                            <access>write-only</access>
                            <enumeratedValues>
                                <enumeratedValue>
                                    <name>0</name>
                                    <description>No effect on output</description>
                                    <value>#0</value>
                                </enumeratedValue>
                                <enumeratedValue>
                                    <name>1</name>
                                    <description>High output</description>
                                    <value>#1</value>
                                </enumeratedValue>
                            </enumeratedValues>
                        </field>
                        <field>
                            <name>POSR08</name>
                            <description>Pmn Output Set</description>
                            <lsb>8</lsb>
                            <msb>8</msb>
                            <access>write-only</access>
                            <enumeratedValues>
                                <enumeratedValue>
                                    <name>0</name>
                                    <description>No effect on output</description>
                                    <value>#0</value>
                                </enumeratedValue>
                                <enumeratedValue>
                                    <name>1</name>
                                    <description>High output</description>
                                    <value>#1</value>
                                </enumeratedValue>
                            </enumeratedValues>
                        </field>
                        <field>
                            <name>POSR09</name>
                            <description>Pmn Output Set</description>
                            <lsb>9</lsb>
                            <msb>9</msb>
                            <access>write-only</access>
                            <enumeratedValues>
                                <enumeratedValue>
                                    <name>0</name>
                                    <description>No effect on output</description>
                                    <value>#0</value>
                                </enumeratedValue>
                                <enumeratedValue>
                                    <name>1</name>
                                    <description>High output</description>
                                    <value>#1</value>
                                </enumeratedValue>
                            </enumeratedValues>
                        </field>
                        <field>
                            <name>POSR10</name>
                            <description>Pmn Output Set</description>
                            <lsb>10</lsb>
                            <msb>10</msb>
                            <access>write-only</access>
                            <enumeratedValues>
                                <enumeratedValue>
                                    <name>0</name>
                                    <description>No effect on output</description>
                                    <value>#0</value>
                                </enumeratedValue>
                                <enumeratedValue>
                                    <name>1</name>
                                    <description>High output</description>
                                    <value>#1</value>
                                </enumeratedValue>
                            </enumeratedValues>
                        </field>
                        <field>
                            <name>POSR11</name>
                            <description>Pmn Output Set</description>
                            <lsb>11</lsb>
                            <msb>11</msb>
                            <access>write-only</access>
                            <enumeratedValues>
                                <enumeratedValue>
                                    <name>0</name>
                                    <description>No effect on output</description>
                                    <value>#0</value>
                                </enumeratedValue>
                                <enumeratedValue>
                                    <name>1</name>
                                    <description>High output</description>
                                    <value>#1</value>
                                </enumeratedValue>
                            </enumeratedValues>
                        </field>
                        <field>
                            <name>POSR12</name>
                            <description>Pmn Output Set</description>
                            <lsb>12</lsb>
                            <msb>12</msb>
                            <access>write-only</access>
                            <enumeratedValues>
                                <enumeratedValue>
                                    <name>0</name>
                                    <description>No effect on output</description>
                                    <value>#0</value>
                                </enumeratedValue>
                                <enumeratedValue>
                                    <name>1</name>
                                    <description>High output</description>
                                    <value>#1</value>
                                </enumeratedValue>
                            </enumeratedValues>
                        </field>
                        <field>
                            <name>POSR13</name>
                            <description>Pmn Output Set</description>
                            <lsb>13</lsb>
                            <msb>13</msb>
                            <access>write-only</access>
                            <enumeratedValues>
                                <enumeratedValue>
                                    <name>0</name>
                                    <description>No effect on output</description>
                                    <value>#0</value>
                                </enumeratedValue>
                                <enumeratedValue>
                                    <name>1</name>
                                    <description>High output</description>
                                    <value>#1</value>
                                </enumeratedValue>
                            </enumeratedValues>
                        </field>
                        <field>
                            <name>POSR14</name>
                            <description>Pmn Output Set</description>
                            <lsb>14</lsb>
                            <msb>14</msb>
                            <access>write-only</access>
                            <enumeratedValues>
                                <enumeratedValue>
                                    <name>0</name>
                                    <description>No effect on output</description>
                                    <value>#0</value>
                                </enumeratedValue>
                                <enumeratedValue>
                                    <name>1</name>
                                    <description>High output</description>
                                    <value>#1</value>
                                </enumeratedValue>
                            </enumeratedValues>
                        </field>
                        <field>
                            <name>POSR15</name>
                            <description>Pmn Output Set</description>
                            <lsb>15</lsb>
                            <msb>15</msb>
                            <access>write-only</access>
                            <enumeratedValues>
                                <enumeratedValue>
                                    <name>0</name>
                                    <description>No effect on output</description>
                                    <value>#0</value>
                                </enumeratedValue>
                                <enumeratedValue>
                                    <name>1</name>
                                    <description>High output</description>
                                    <value>#1</value>
                                </enumeratedValue>
                            </enumeratedValues>
                        </field>
                    </fields>
                </register>
            </registers>
        </peripheral>
        <peripheral>
            <name>PORT1_NS</name>
            <description>Pmn Pin FunctionPort 1 Control RegistersPmn Pin Function Control Register</description>
            <baseAddress>0x50400020</baseAddress>
            <addressBlock>
                <offset>0x00</offset>
                <size>16</size>
                <usage>registers</usage>
            </addressBlock>
            <registers>
                <register>
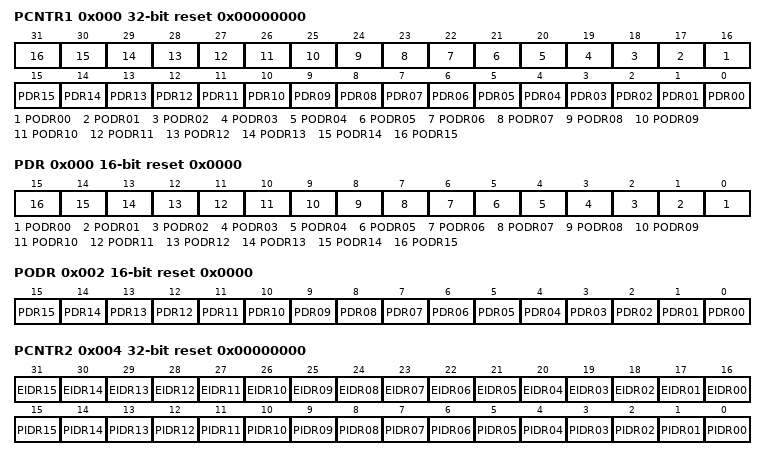
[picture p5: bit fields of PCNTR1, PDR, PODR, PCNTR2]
                    <name>PCNTR1</name>
                    <description>Port Control Register 1</description>
                    <addressOffset>0x000</addressOffset>
                    <size>32</size>
                    <access>read-write</access>
                    <resetValue>0x00000000</resetValue>
                    <resetMask>0xffffffff</resetMask>
                    <fields>
                        <field>
                            <name>PDR00</name>
                            <description>Pmn Direction</description>
                            <lsb>0</lsb>
                            <msb>0</msb>
                            <access>read-write</access>
                            <enumeratedValues>
                                <enumeratedValue>
                                    <name>0</name>
                                    <description>Input (functions as an input pin)</description>
                                    <value>#0</value>
                                </enumeratedValue>
                                <enumeratedValue>
                                    <name>1</name>
                                    <description>Output (functions as an output pin)</description>
                                    <value>#1</value>
                                </enumeratedValue>
                            </enumeratedValues>
                        </field>
                        <field>
                            <name>PDR01</name>
                            <description>Pmn Direction</description>
                            <lsb>1</lsb>
                            <msb>1</msb>
                            <access>read-write</access>
                            <enumeratedValues>
                                <enumeratedValue>
                                    <name>0</name>
                                    <description>Input (functions as an input pin)</description>
                                    <value>#0</value>
                                </enumeratedValue>
                                <enumeratedValue>
                                    <name>1</name>
                                    <description>Output (functions as an output pin)</description>
                                    <value>#1</value>
                                </enumeratedValue>
                            </enumeratedValues>
                        </field>
                        <field>
                            <name>PDR02</name>
                            <description>Pmn Direction</description>
                            <lsb>2</lsb>
                            <msb>2</msb>
                            <access>read-write</access>
                            <enumeratedValues>
                                <enumeratedValue>
                                    <name>0</name>
                                    <description>Input (functions as an input pin)</description>
                                    <value>#0</value>
                                </enumeratedValue>
                                <enumeratedValue>
                                    <name>1</name>
                                    <description>Output (functions as an output pin)</description>
                                    <value>#1</value>
                                </enumeratedValue>
                            </enumeratedValues>
                        </field>
                        <field>
                            <name>PDR03</name>
                            <description>Pmn Direction</description>
                            <lsb>3</lsb>
                            <msb>3</msb>
                            <access>read-write</access>
                            <enumeratedValues>
                                <enumeratedValue>
                                    <name>0</name>
                                    <description>Input (functions as an input pin)</description>
                                    <value>#0</value>
                                </enumeratedValue>
                                <enumeratedValue>
                                    <name>1</name>
                                    <description>Output (functions as an output pin)</description>
                                    <value>#1</value>
                                </enumeratedValue>
                            </enumeratedValues>
                        </field>
                        <field>
                            <name>PDR04</name>
                            <description>Pmn Direction</description>
                            <lsb>4</lsb>
                            <msb>4</msb>
                            <access>read-write</access>
                            <enumeratedValues>
                                <enumeratedValue>
                                    <name>0</name>
                                    <description>Input (functions as an input pin)</description>
                                    <value>#0</value>
                                </enumeratedValue>
                                <enumeratedValue>
                                    <name>1</name>
                                    <description>Output (functions as an output pin)</description>
                                    <value>#1</value>
                                </enumeratedValue>
                            </enumeratedValues>
                        </field>
                        <field>
                            <name>PDR05</name>
                            <description>Pmn Direction</description>
                            <lsb>5</lsb>
                            <msb>5</msb>
                            <access>read-write</access>
                            <enumeratedValues>
                                <enumeratedValue>
                                    <name>0</name>
                                    <description>Input (functions as an input pin)</description>
                                    <value>#0</value>
                                </enumeratedValue>
                                <enumeratedValue>
                                    <name>1</name>
                                    <description>Output (functions as an output pin)</description>
                                    <value>#1</value>
                                </enumeratedValue>
                            </enumeratedValues>
                        </field>
                        <field>
                            <name>PDR06</name>
                            <description>Pmn Direction</description>
                            <lsb>6</lsb>
                            <msb>6</msb>
                            <access>read-write</access>
                            <enumeratedValues>
                                <enumeratedValue>
                                    <name>0</name>
                                    <description>Input (functions as an input pin)</description>
                                    <value>#0</value>
                                </enumeratedValue>
                                <enumeratedValue>
                                    <name>1</name>
                                    <description>Output (functions as an output pin)</description>
                                    <value>#1</value>
                                </enumeratedValue>
                            </enumeratedValues>
                        </field>
                        <field>
                            <name>PDR07</name>
                            <description>Pmn Direction</description>
                            <lsb>7</lsb>
                            <msb>7</msb>
                            <access>read-write</access>
                            <enumeratedValues>
                                <enumeratedValue>
                                    <name>0</name>
                                    <description>Input (functions as an input pin)</description>
                                    <value>#0</value>
                                </enumeratedValue>
                                <enumeratedValue>
                                    <name>1</name>
                                    <description>Output (functions as an output pin)</description>
                                    <value>#1</value>
                                </enumeratedValue>
                            </enumeratedValues>
                        </field>
                        <field>
                            <name>PDR08</name>
                            <description>Pmn Direction</description>
                            <lsb>8</lsb>
                            <msb>8</msb>
                            <access>read-write</access>
                            <enumeratedValues>
                                <enumeratedValue>
                                    <name>0</name>
                                    <description>Input (functions as an input pin)</description>
                                    <value>#0</value>
                                </enumeratedValue>
                                <enumeratedValue>
                                    <name>1</name>
                                    <description>Output (functions as an output pin)</description>
                                    <value>#1</value>
                                </enumeratedValue>
                            </enumeratedValues>
                        </field>
                        <field>
                            <name>PDR09</name>
                            <description>Pmn Direction</description>
                            <lsb>9</lsb>
                            <msb>9</msb>
                            <access>read-write</access>
                            <enumeratedValues>
                                <enumeratedValue>
                                    <name>0</name>
                                    <description>Input (functions as an input pin)</description>
                                    <value>#0</value>
                                </enumeratedValue>
                                <enumeratedValue>
                                    <name>1</name>
                                    <description>Output (functions as an output pin)</description>
                                    <value>#1</value>
                                </enumeratedValue>
                            </enumeratedValues>
                        </field>
                        <field>
                            <name>PDR10</name>
                            <description>Pmn Direction</description>
                            <lsb>10</lsb>
                            <msb>10</msb>
                            <access>read-write</access>
                            <enumeratedValues>
                                <enumeratedValue>
                                    <name>0</name>
                                    <description>Input (functions as an input pin)</description>
                                    <value>#0</value>
                                </enumeratedValue>
                                <enumeratedValue>
                                    <name>1</name>
                                    <description>Output (functions as an output pin)</description>
                                    <value>#1</value>
                                </enumeratedValue>
                            </enumeratedValues>
                        </field>
                        <field>
                            <name>PDR11</name>
                            <description>Pmn Direction</description>
                            <lsb>11</lsb>
                            <msb>11</msb>
                            <access>read-write</access>
                            <enumeratedValues>
                                <enumeratedValue>
                                    <name>0</name>
                                    <description>Input (functions as an input pin)</description>
                                    <value>#0</value>
                                </enumeratedValue>
                                <enumeratedValue>
                                    <name>1</name>
                                    <description>Output (functions as an output pin)</description>
                                    <value>#1</value>
                                </enumeratedValue>
                            </enumeratedValues>
                        </field>
                        <field>
                            <name>PDR12</name>
                            <description>Pmn Direction</description>
                            <lsb>12</lsb>
                            <msb>12</msb>
                            <access>read-write</access>
                            <enumeratedValues>
                                <enumeratedValue>
                                    <name>0</name>
                                    <description>Input (functions as an input pin)</description>
                                    <value>#0</value>
                                </enumeratedValue>
                                <enumeratedValue>
                                    <name>1</name>
                                    <description>Output (functions as an output pin)</description>
                                    <value>#1</value>
                                </enumeratedValue>
                            </enumeratedValues>
                        </field>
                        <field>
                            <name>PDR13</name>
                            <description>Pmn Direction</description>
                            <lsb>13</lsb>
                            <msb>13</msb>
                            <access>read-write</access>
                            <enumeratedValues>
                                <enumeratedValue>
                                    <name>0</name>
                                    <description>Input (functions as an input pin)</description>
                                    <value>#0</value>
                                </enumeratedValue>
                                <enumeratedValue>
                                    <name>1</name>
                                    <description>Output (functions as an output pin)</description>
                                    <value>#1</value>
                                </enumeratedValue>
                            </enumeratedValues>
                        </field>
                        <field>
                            <name>PDR14</name>
                            <description>Pmn Direction</description>
                            <lsb>14</lsb>
                            <msb>14</msb>
                            <access>read-write</access>
                            <enumeratedValues>
                                <enumeratedValue>
                                    <name>0</name>
                                    <description>Input (functions as an input pin)</description>
                                    <value>#0</value>
                                </enumeratedValue>
                                <enumeratedValue>
                                    <name>1</name>
                                    <description>Output (functions as an output pin)</description>
                                    <value>#1</value>
                                </enumeratedValue>
                            </enumeratedValues>
                        </field>
                        <field>
                            <name>PDR15</name>
                            <description>Pmn Direction</description>
                            <lsb>15</lsb>
                            <msb>15</msb>
                            <access>read-write</access>
                            <enumeratedValues>
                                <enumeratedValue>
                                    <name>0</name>
                                    <description>Input (functions as an input pin)</description>
                                    <value>#0</value>
                                </enumeratedValue>
                                <enumeratedValue>
                                    <name>1</name>
                                    <description>Output (functions as an output pin)</description>
                                    <value>#1</value>
                                </enumeratedValue>
                            </enumeratedValues>
                        </field>
                        <field>
                            <name>PODR00</name>
                            <description>Pmn Output Data</description>
                            <lsb>16</lsb>
                            <msb>16</msb>
                            <access>read-write</access>
                            <enumeratedValues>
                                <enumeratedValue>
                                    <name>0</name>
                                    <description>Low output</description>
                                    <value>#0</value>
                                </enumeratedValue>
                                <enumeratedValue>
                                    <name>1</name>
                                    <description>High output</description>
                                    <value>#1</value>
                                </enumeratedValue>
                            </enumeratedValues>
                        </field>
                        <field>
                            <name>PODR01</name>
                            <description>Pmn Output Data</description>
                            <lsb>17</lsb>
                            <msb>17</msb>
                            <access>read-write</access>
                            <enumeratedValues>
                                <enumeratedValue>
                                    <name>0</name>
                                    <description>Low output</description>
                                    <value>#0</value>
                                </enumeratedValue>
                                <enumeratedValue>
                                    <name>1</name>
                                    <description>High output</description>
                                    <value>#1</value>
                                </enumeratedValue>
                            </enumeratedValues>
                        </field>
                        <field>
                            <name>PODR02</name>
                            <description>Pmn Output Data</description>
                            <lsb>18</lsb>
                            <msb>18</msb>
                            <access>read-write</access>
                            <enumeratedValues>
                                <enumeratedValue>
                                    <name>0</name>
                                    <description>Low output</description>
                                    <value>#0</value>
                                </enumeratedValue>
                                <enumeratedValue>
                                    <name>1</name>
                                    <description>High output</description>
                                    <value>#1</value>
                                </enumeratedValue>
                            </enumeratedValues>
                        </field>
                        <field>
                            <name>PODR03</name>
                            <description>Pmn Output Data</description>
                            <lsb>19</lsb>
                            <msb>19</msb>
                            <access>read-write</access>
                            <enumeratedValues>
                                <enumeratedValue>
                                    <name>0</name>
                                    <description>Low output</description>
                                    <value>#0</value>
                                </enumeratedValue>
                                <enumeratedValue>
                                    <name>1</name>
                                    <description>High output</description>
                                    <value>#1</value>
                                </enumeratedValue>
                            </enumeratedValues>
                        </field>
                        <field>
                            <name>PODR04</name>
                            <description>Pmn Output Data</description>
                            <lsb>20</lsb>
                            <msb>20</msb>
                            <access>read-write</access>
                            <enumeratedValues>
                                <enumeratedValue>
                                    <name>0</name>
                                    <description>Low output</description>
                                    <value>#0</value>
                                </enumeratedValue>
                                <enumeratedValue>
                                    <name>1</name>
                                    <description>High output</description>
                                    <value>#1</value>
                                </enumeratedValue>
                            </enumeratedValues>
                        </field>
                        <field>
                            <name>PODR05</name>
                            <description>Pmn Output Data</description>
                            <lsb>21</lsb>
                            <msb>21</msb>
                            <access>read-write</access>
                            <enumeratedValues>
                                <enumeratedValue>
                                    <name>0</name>
                                    <description>Low output</description>
                                    <value>#0</value>
                                </enumeratedValue>
                                <enumeratedValue>
                                    <name>1</name>
                                    <description>High output</description>
                                    <value>#1</value>
                                </enumeratedValue>
                            </enumeratedValues>
                        </field>
                        <field>
                            <name>PODR06</name>
                            <description>Pmn Output Data</description>
                            <lsb>22</lsb>
                            <msb>22</msb>
                            <access>read-write</access>
                            <enumeratedValues>
                                <enumeratedValue>
                                    <name>0</name>
                                    <description>Low output</description>
                                    <value>#0</value>
                                </enumeratedValue>
                                <enumeratedValue>
                                    <name>1</name>
                                    <description>High output</description>
                                    <value>#1</value>
                                </enumeratedValue>
                            </enumeratedValues>
                        </field>
                        <field>
                            <name>PODR07</name>
                            <description>Pmn Output Data</description>
                            <lsb>23</lsb>
                            <msb>23</msb>
                            <access>read-write</access>
                            <enumeratedValues>
                                <enumeratedValue>
                                    <name>0</name>
                                    <description>Low output</description>
                                    <value>#0</value>
                                </enumeratedValue>
                                <enumeratedValue>
                                    <name>1</name>
                                    <description>High output</description>
                                    <value>#1</value>
                                </enumeratedValue>
                            </enumeratedValues>
                        </field>
                        <field>
                            <name>PODR08</name>
                            <description>Pmn Output Data</description>
                            <lsb>24</lsb>
                            <msb>24</msb>
                            <access>read-write</access>
                            <enumeratedValues>
                                <enumeratedValue>
                                    <name>0</name>
                                    <description>Low output</description>
                                    <value>#0</value>
                                </enumeratedValue>
                                <enumeratedValue>
                                    <name>1</name>
                                    <description>High output</description>
                                    <value>#1</value>
                                </enumeratedValue>
                            </enumeratedValues>
                        </field>
                        <field>
                            <name>PODR09</name>
                            <description>Pmn Output Data</description>
                            <lsb>25</lsb>
                            <msb>25</msb>
                            <access>read-write</access>
                            <enumeratedValues>
                                <enumeratedValue>
                                    <name>0</name>
                                    <description>Low output</description>
                                    <value>#0</value>
                                </enumeratedValue>
                                <enumeratedValue>
                                    <name>1</name>
                                    <description>High output</description>
                                    <value>#1</value>
                                </enumeratedValue>
                            </enumeratedValues>
                        </field>
                        <field>
                            <name>PODR10</name>
                            <description>Pmn Output Data</description>
                            <lsb>26</lsb>
                            <msb>26</msb>
                            <access>read-write</access>
                            <enumeratedValues>
                                <enumeratedValue>
                                    <name>0</name>
                                    <description>Low output</description>
                                    <value>#0</value>
                                </enumeratedValue>
                                <enumeratedValue>
                                    <name>1</name>
                                    <description>High output</description>
                                    <value>#1</value>
                                </enumeratedValue>
                            </enumeratedValues>
                        </field>
                        <field>
                            <name>PODR11</name>
                            <description>Pmn Output Data</description>
                            <lsb>27</lsb>
                            <msb>27</msb>
                            <access>read-write</access>
                            <enumeratedValues>
                                <enumeratedValue>
                                    <name>0</name>
                                    <description>Low output</description>
                                    <value>#0</value>
                                </enumeratedValue>
                                <enumeratedValue>
                                    <name>1</name>
                                    <description>High output</description>
                                    <value>#1</value>
                                </enumeratedValue>
                            </enumeratedValues>
                        </field>
                        <field>
                            <name>PODR12</name>
                            <description>Pmn Output Data</description>
                            <lsb>28</lsb>
                            <msb>28</msb>
                            <access>read-write</access>
                            <enumeratedValues>
                                <enumeratedValue>
                                    <name>0</name>
                                    <description>Low output</description>
                                    <value>#0</value>
                                </enumeratedValue>
                                <enumeratedValue>
                                    <name>1</name>
                                    <description>High output</description>
                                    <value>#1</value>
                                </enumeratedValue>
                            </enumeratedValues>
                        </field>
                        <field>
                            <name>PODR13</name>
                            <description>Pmn Output Data</description>
                            <lsb>29</lsb>
                            <msb>29</msb>
                            <access>read-write</access>
                            <enumeratedValues>
                                <enumeratedValue>
                                    <name>0</name>
                                    <description>Low output</description>
                                    <value>#0</value>
                                </enumeratedValue>
                                <enumeratedValue>
                                    <name>1</name>
                                    <description>High output</description>
                                    <value>#1</value>
                                </enumeratedValue>
                            </enumeratedValues>
                        </field>
                        <field>
                            <name>PODR14</name>
                            <description>Pmn Output Data</description>
                            <lsb>30</lsb>
                            <msb>30</msb>
                            <access>read-write</access>
                            <enumeratedValues>
                                <enumeratedValue>
                                    <name>0</name>
                                    <description>Low output</description>
                                    <value>#0</value>
                                </enumeratedValue>
                                <enumeratedValue>
                                    <name>1</name>
                                    <description>High output</description>
                                    <value>#1</value>
                                </enumeratedValue>
                            </enumeratedValues>
                        </field>
                        <field>
                            <name>PODR15</name>
                            <description>Pmn Output Data</description>
                            <lsb>31</lsb>
                            <msb>31</msb>
                            <access>read-write</access>
                            <enumeratedValues>
                                <enumeratedValue>
                                    <name>0</name>
                                    <description>Low output</description>
                                    <value>#0</value>
                                </enumeratedValue>
                                <enumeratedValue>
                                    <name>1</name>
                                    <description>High output</description>
                                    <value>#1</value>
                                </enumeratedValue>
                            </enumeratedValues>
                        </field>
                    </fields>
                </register>
                <register>
                    <name>PDR</name>
                    <description>Port Control Register 1</description>
                    <alternateRegister>PCNTR1</alternateRegister>
                    <addressOffset>0x000</addressOffset>
                    <size>16</size>
                    <access>read-write</access>
                    <resetValue>0x0000</resetValue>
                    <resetMask>0xffff</resetMask>
                    <fields>
                        <field>
                            <name>PODR00</name>
                            <description>Pmn Output Data</description>
                            <lsb>0</lsb>
                            <msb>0</msb>
                            <access>read-write</access>
                            <enumeratedValues>
                                <enumeratedValue>
                                    <name>0</name>
                                    <description>Low output</description>
                                    <value>#0</value>
                                </enumeratedValue>
                                <enumeratedValue>
                                    <name>1</name>
                                    <description>High output</description>
                                    <value>#1</value>
                                </enumeratedValue>
                            </enumeratedValues>
                        </field>
                        <field>
                            <name>PODR01</name>
                            <description>Pmn Output Data</description>
                            <lsb>1</lsb>
                            <msb>1</msb>
                            <access>read-write</access>
                            <enumeratedValues>
                                <enumeratedValue>
                                    <name>0</name>
                                    <description>Low output</description>
                                    <value>#0</value>
                                </enumeratedValue>
                                <enumeratedValue>
                                    <name>1</name>
                                    <description>High output</description>
                                    <value>#1</value>
                                </enumeratedValue>
                            </enumeratedValues>
                        </field>
                        <field>
                            <name>PODR02</name>
                            <description>Pmn Output Data</description>
                            <lsb>2</lsb>
                            <msb>2</msb>
                            <access>read-write</access>
                            <enumeratedValues>
                                <enumeratedValue>
                                    <name>0</name>
                                    <description>Low output</description>
                                    <value>#0</value>
                                </enumeratedValue>
                                <enumeratedValue>
                                    <name>1</name>
                                    <description>High output</description>
                                    <value>#1</value>
                                </enumeratedValue>
                            </enumeratedValues>
                        </field>
                        <field>
                            <name>PODR03</name>
                            <description>Pmn Output Data</description>
                            <lsb>3</lsb>
                            <msb>3</msb>
                            <access>read-write</access>
                            <enumeratedValues>
                                <enumeratedValue>
                                    <name>0</name>
                                    <description>Low output</description>
                                    <value>#0</value>
                                </enumeratedValue>
                                <enumeratedValue>
                                    <name>1</name>
                                    <description>High output</description>
                                    <value>#1</value>
                                </enumeratedValue>
                            </enumeratedValues>
                        </field>
                        <field>
                            <name>PODR04</name>
                            <description>Pmn Output Data</description>
                            <lsb>4</lsb>
                            <msb>4</msb>
                            <access>read-write</access>
                            <enumeratedValues>
                                <enumeratedValue>
                                    <name>0</name>
                                    <description>Low output</description>
                                    <value>#0</value>
                                </enumeratedValue>
                                <enumeratedValue>
                                    <name>1</name>
                                    <description>High output</description>
                                    <value>#1</value>
                                </enumeratedValue>
                            </enumeratedValues>
                        </field>
                        <field>
                            <name>PODR05</name>
                            <description>Pmn Output Data</description>
                            <lsb>5</lsb>
                            <msb>5</msb>
                            <access>read-write</access>
                            <enumeratedValues>
                                <enumeratedValue>
                                    <name>0</name>
                                    <description>Low output</description>
                                    <value>#0</value>
                                </enumeratedValue>
                                <enumeratedValue>
                                    <name>1</name>
                                    <description>High output</description>
                                    <value>#1</value>
                                </enumeratedValue>
                            </enumeratedValues>
                        </field>
                        <field>
                            <name>PODR06</name>
                            <description>Pmn Output Data</description>
                            <lsb>6</lsb>
                            <msb>6</msb>
                            <access>read-write</access>
                            <enumeratedValues>
                                <enumeratedValue>
                                    <name>0</name>
                                    <description>Low output</description>
                                    <value>#0</value>
                                </enumeratedValue>
                                <enumeratedValue>
                                    <name>1</name>
                                    <description>High output</description>
                                    <value>#1</value>
                                </enumeratedValue>
                            </enumeratedValues>
                        </field>
                        <field>
                            <name>PODR07</name>
                            <description>Pmn Output Data</description>
                            <lsb>7</lsb>
                            <msb>7</msb>
                            <access>read-write</access>
                            <enumeratedValues>
                                <enumeratedValue>
                                    <name>0</name>
                                    <description>Low output</description>
                                    <value>#0</value>
                                </enumeratedValue>
                                <enumeratedValue>
                                    <name>1</name>
                                    <description>High output</description>
                                    <value>#1</value>
                                </enumeratedValue>
                            </enumeratedValues>
                        </field>
                        <field>
                            <name>PODR08</name>
                            <description>Pmn Output Data</description>
                            <lsb>8</lsb>
                            <msb>8</msb>
                            <access>read-write</access>
                            <enumeratedValues>
                                <enumeratedValue>
                                    <name>0</name>
                                    <description>Low output</description>
                                    <value>#0</value>
                                </enumeratedValue>
                                <enumeratedValue>
                                    <name>1</name>
                                    <description>High output</description>
                                    <value>#1</value>
                                </enumeratedValue>
                            </enumeratedValues>
                        </field>
                        <field>
                            <name>PODR09</name>
                            <description>Pmn Output Data</description>
                            <lsb>9</lsb>
                            <msb>9</msb>
                            <access>read-write</access>
                            <enumeratedValues>
                                <enumeratedValue>
                                    <name>0</name>
                                    <description>Low output</description>
                                    <value>#0</value>
                                </enumeratedValue>
                                <enumeratedValue>
                                    <name>1</name>
                                    <description>High output</description>
                                    <value>#1</value>
                                </enumeratedValue>
                            </enumeratedValues>
                        </field>
                        <field>
                            <name>PODR10</name>
                            <description>Pmn Output Data</description>
                            <lsb>10</lsb>
                            <msb>10</msb>
                            <access>read-write</access>
                            <enumeratedValues>
                                <enumeratedValue>
                                    <name>0</name>
                                    <description>Low output</description>
                                    <value>#0</value>
                                </enumeratedValue>
                                <enumeratedValue>
                                    <name>1</name>
                                    <description>High output</description>
                                    <value>#1</value>
                                </enumeratedValue>
                            </enumeratedValues>
                        </field>
                        <field>
                            <name>PODR11</name>
                            <description>Pmn Output Data</description>
                            <lsb>11</lsb>
                            <msb>11</msb>
                            <access>read-write</access>
                            <enumeratedValues>
                                <enumeratedValue>
                                    <name>0</name>
                                    <description>Low output</description>
                                    <value>#0</value>
                                </enumeratedValue>
                                <enumeratedValue>
                                    <name>1</name>
                                    <description>High output</description>
                                    <value>#1</value>
                                </enumeratedValue>
                            </enumeratedValues>
                        </field>
                        <field>
                            <name>PODR12</name>
                            <description>Pmn Output Data</description>
                            <lsb>12</lsb>
                            <msb>12</msb>
                            <access>read-write</access>
                            <enumeratedValues>
                                <enumeratedValue>
                                    <name>0</name>
                                    <description>Low output</description>
                                    <value>#0</value>
                                </enumeratedValue>
                                <enumeratedValue>
                                    <name>1</name>
                                    <description>High output</description>
                                    <value>#1</value>
                                </enumeratedValue>
                            </enumeratedValues>
                        </field>
                        <field>
                            <name>PODR13</name>
                            <description>Pmn Output Data</description>
                            <lsb>13</lsb>
                            <msb>13</msb>
                            <access>read-write</access>
                            <enumeratedValues>
                                <enumeratedValue>
                                    <name>0</name>
                                    <description>Low output</description>
                                    <value>#0</value>
                                </enumeratedValue>
                                <enumeratedValue>
                                    <name>1</name>
                                    <description>High output</description>
                                    <value>#1</value>
                                </enumeratedValue>
                            </enumeratedValues>
                        </field>
                        <field>
                            <name>PODR14</name>
                            <description>Pmn Output Data</description>
                            <lsb>14</lsb>
                            <msb>14</msb>
                            <access>read-write</access>
                            <enumeratedValues>
                                <enumeratedValue>
                                    <name>0</name>
                                    <description>Low output</description>
                                    <value>#0</value>
                                </enumeratedValue>
                                <enumeratedValue>
                                    <name>1</name>
                                    <description>High output</description>
                                    <value>#1</value>
                                </enumeratedValue>
                            </enumeratedValues>
                        </field>
                        <field>
                            <name>PODR15</name>
                            <description>Pmn Output Data</description>
                            <lsb>15</lsb>
                            <msb>15</msb>
                            <access>read-write</access>
                            <enumeratedValues>
                                <enumeratedValue>
                                    <name>0</name>
                                    <description>Low output</description>
                                    <value>#0</value>
                                </enumeratedValue>
                                <enumeratedValue>
                                    <name>1</name>
                                    <description>High output</description>
                                    <value>#1</value>
                                </enumeratedValue>
                            </enumeratedValues>
                        </field>
                    </fields>
                </register>
                <register>
                    <name>PODR</name>
                    <description>Port Control Register 1</description>
                    <alternateRegister>PCNTR1</alternateRegister>
                    <addressOffset>0x002</addressOffset>
                    <size>16</size>
                    <access>read-write</access>
                    <resetValue>0x0000</resetValue>
                    <resetMask>0xffff</resetMask>
                    <fields>
                        <field>
                            <name>PDR00</name>
                            <description>Pmn Direction</description>
                            <lsb>0</lsb>
                            <msb>0</msb>
                            <access>read-write</access>
                            <enumeratedValues>
                                <enumeratedValue>
                                    <name>0</name>
                                    <description>Input (functions as an input pin)</description>
                                    <value>#0</value>
                                </enumeratedValue>
                                <enumeratedValue>
                                    <name>1</name>
                                    <description>Output (functions as an output pin)</description>
                                    <value>#1</value>
                                </enumeratedValue>
                            </enumeratedValues>
                        </field>
                        <field>
                            <name>PDR01</name>
                            <description>Pmn Direction</description>
                            <lsb>1</lsb>
                            <msb>1</msb>
                            <access>read-write</access>
                            <enumeratedValues>
                                <enumeratedValue>
                                    <name>0</name>
                                    <description>Input (functions as an input pin)</description>
                                    <value>#0</value>
                                </enumeratedValue>
                                <enumeratedValue>
                                    <name>1</name>
                                    <description>Output (functions as an output pin)</description>
                                    <value>#1</value>
                                </enumeratedValue>
                            </enumeratedValues>
                        </field>
                        <field>
                            <name>PDR02</name>
                            <description>Pmn Direction</description>
                            <lsb>2</lsb>
                            <msb>2</msb>
                            <access>read-write</access>
                            <enumeratedValues>
                                <enumeratedValue>
                                    <name>0</name>
                                    <description>Input (functions as an input pin)</description>
                                    <value>#0</value>
                                </enumeratedValue>
                                <enumeratedValue>
                                    <name>1</name>
                                    <description>Output (functions as an output pin)</description>
                                    <value>#1</value>
                                </enumeratedValue>
                            </enumeratedValues>
                        </field>
                        <field>
                            <name>PDR03</name>
                            <description>Pmn Direction</description>
                            <lsb>3</lsb>
                            <msb>3</msb>
                            <access>read-write</access>
                            <enumeratedValues>
                                <enumeratedValue>
                                    <name>0</name>
                                    <description>Input (functions as an input pin)</description>
                                    <value>#0</value>
                                </enumeratedValue>
                                <enumeratedValue>
                                    <name>1</name>
                                    <description>Output (functions as an output pin)</description>
                                    <value>#1</value>
                                </enumeratedValue>
                            </enumeratedValues>
                        </field>
                        <field>
                            <name>PDR04</name>
                            <description>Pmn Direction</description>
                            <lsb>4</lsb>
                            <msb>4</msb>
                            <access>read-write</access>
                            <enumeratedValues>
                                <enumeratedValue>
                                    <name>0</name>
                                    <description>Input (functions as an input pin)</description>
                                    <value>#0</value>
                                </enumeratedValue>
                                <enumeratedValue>
                                    <name>1</name>
                                    <description>Output (functions as an output pin)</description>
                                    <value>#1</value>
                                </enumeratedValue>
                            </enumeratedValues>
                        </field>
                        <field>
                            <name>PDR05</name>
                            <description>Pmn Direction</description>
                            <lsb>5</lsb>
                            <msb>5</msb>
                            <access>read-write</access>
                            <enumeratedValues>
                                <enumeratedValue>
                                    <name>0</name>
                                    <description>Input (functions as an input pin)</description>
                                    <value>#0</value>
                                </enumeratedValue>
                                <enumeratedValue>
                                    <name>1</name>
                                    <description>Output (functions as an output pin)</description>
                                    <value>#1</value>
                                </enumeratedValue>
                            </enumeratedValues>
                        </field>
                        <field>
                            <name>PDR06</name>
                            <description>Pmn Direction</description>
                            <lsb>6</lsb>
                            <msb>6</msb>
                            <access>read-write</access>
                            <enumeratedValues>
                                <enumeratedValue>
                                    <name>0</name>
                                    <description>Input (functions as an input pin)</description>
                                    <value>#0</value>
                                </enumeratedValue>
                                <enumeratedValue>
                                    <name>1</name>
                                    <description>Output (functions as an output pin)</description>
                                    <value>#1</value>
                                </enumeratedValue>
                            </enumeratedValues>
                        </field>
                        <field>
                            <name>PDR07</name>
                            <description>Pmn Direction</description>
                            <lsb>7</lsb>
                            <msb>7</msb>
                            <access>read-write</access>
                            <enumeratedValues>
                                <enumeratedValue>
                                    <name>0</name>
                                    <description>Input (functions as an input pin)</description>
                                    <value>#0</value>
                                </enumeratedValue>
                                <enumeratedValue>
                                    <name>1</name>
                                    <description>Output (functions as an output pin)</description>
                                    <value>#1</value>
                                </enumeratedValue>
                            </enumeratedValues>
                        </field>
                        <field>
                            <name>PDR08</name>
                            <description>Pmn Direction</description>
                            <lsb>8</lsb>
                            <msb>8</msb>
                            <access>read-write</access>
                            <enumeratedValues>
                                <enumeratedValue>
                                    <name>0</name>
                                    <description>Input (functions as an input pin)</description>
                                    <value>#0</value>
                                </enumeratedValue>
                                <enumeratedValue>
                                    <name>1</name>
                                    <description>Output (functions as an output pin)</description>
                                    <value>#1</value>
                                </enumeratedValue>
                            </enumeratedValues>
                        </field>
                        <field>
                            <name>PDR09</name>
                            <description>Pmn Direction</description>
                            <lsb>9</lsb>
                            <msb>9</msb>
                            <access>read-write</access>
                            <enumeratedValues>
                                <enumeratedValue>
                                    <name>0</name>
                                    <description>Input (functions as an input pin)</description>
                                    <value>#0</value>
                                </enumeratedValue>
                                <enumeratedValue>
                                    <name>1</name>
                                    <description>Output (functions as an output pin)</description>
                                    <value>#1</value>
                                </enumeratedValue>
                            </enumeratedValues>
                        </field>
                        <field>
                            <name>PDR10</name>
                            <description>Pmn Direction</description>
                            <lsb>10</lsb>
                            <msb>10</msb>
                            <access>read-write</access>
                            <enumeratedValues>
                                <enumeratedValue>
                                    <name>0</name>
                                    <description>Input (functions as an input pin)</description>
                                    <value>#0</value>
                                </enumeratedValue>
                                <enumeratedValue>
                                    <name>1</name>
                                    <description>Output (functions as an output pin)</description>
                                    <value>#1</value>
                                </enumeratedValue>
                            </enumeratedValues>
                        </field>
                        <field>
                            <name>PDR11</name>
                            <description>Pmn Direction</description>
                            <lsb>11</lsb>
                            <msb>11</msb>
                            <access>read-write</access>
                            <enumeratedValues>
                                <enumeratedValue>
                                    <name>0</name>
                                    <description>Input (functions as an input pin)</description>
                                    <value>#0</value>
                                </enumeratedValue>
                                <enumeratedValue>
                                    <name>1</name>
                                    <description>Output (functions as an output pin)</description>
                                    <value>#1</value>
                                </enumeratedValue>
                            </enumeratedValues>
                        </field>
                        <field>
                            <name>PDR12</name>
                            <description>Pmn Direction</description>
                            <lsb>12</lsb>
                            <msb>12</msb>
                            <access>read-write</access>
                            <enumeratedValues>
                                <enumeratedValue>
                                    <name>0</name>
                                    <description>Input (functions as an input pin)</description>
                                    <value>#0</value>
                                </enumeratedValue>
                                <enumeratedValue>
                                    <name>1</name>
                                    <description>Output (functions as an output pin)</description>
                                    <value>#1</value>
                                </enumeratedValue>
                            </enumeratedValues>
                        </field>
                        <field>
                            <name>PDR13</name>
                            <description>Pmn Direction</description>
                            <lsb>13</lsb>
                            <msb>13</msb>
                            <access>read-write</access>
                            <enumeratedValues>
                                <enumeratedValue>
                                    <name>0</name>
                                    <description>Input (functions as an input pin)</description>
                                    <value>#0</value>
                                </enumeratedValue>
                                <enumeratedValue>
                                    <name>1</name>
                                    <description>Output (functions as an output pin)</description>
                                    <value>#1</value>
                                </enumeratedValue>
                            </enumeratedValues>
                        </field>
                        <field>
                            <name>PDR14</name>
                            <description>Pmn Direction</description>
                            <lsb>14</lsb>
                            <msb>14</msb>
                            <access>read-write</access>
                            <enumeratedValues>
                                <enumeratedValue>
                                    <name>0</name>
                                    <description>Input (functions as an input pin)</description>
                                    <value>#0</value>
                                </enumeratedValue>
                                <enumeratedValue>
                                    <name>1</name>
                                    <description>Output (functions as an output pin)</description>
                                    <value>#1</value>
                                </enumeratedValue>
                            </enumeratedValues>
                        </field>
                        <field>
                            <name>PDR15</name>
                            <description>Pmn Direction</description>
                            <lsb>15</lsb>
                            <msb>15</msb>
                            <access>read-write</access>
                            <enumeratedValues>
                                <enumeratedValue>
                                    <name>0</name>
                                    <description>Input (functions as an input pin)</description>
                                    <value>#0</value>
                                </enumeratedValue>
                                <enumeratedValue>
                                    <name>1</name>
                                    <description>Output (functions as an output pin)</description>
                                    <value>#1</value>
                                </enumeratedValue>
                            </enumeratedValues>
                        </field>
                    </fields>
                </register>
                <register>
                    <name>PCNTR2</name>
                    <description>Port Control Register 2</description>
                    <addressOffset>0x004</addressOffset>
                    <size>32</size>
                    <access>read-only</access>
                    <resetValue>0x00000000</resetValue>
                    <resetMask>0xffff0000</resetMask>
                    <fields>
                        <field>
                            <name>PIDR00</name>
                            <description>Pmn State</description>
                            <lsb>0</lsb>
                            <msb>0</msb>
                            <access>read-only</access>
                            <enumeratedValues>
                                <enumeratedValue>
                                    <name>0</name>
                                    <description>Low level</description>
                                    <value>#0</value>
                                </enumeratedValue>
                                <enumeratedValue>
                                    <name>1</name>
                                    <description>High level</description>
                                    <value>#1</value>
                                </enumeratedValue>
                            </enumeratedValues>
                        </field>
                        <field>
                            <name>PIDR01</name>
                            <description>Pmn State</description>
                            <lsb>1</lsb>
                            <msb>1</msb>
                            <access>read-only</access>
                            <enumeratedValues>
                                <enumeratedValue>
                                    <name>0</name>
                                    <description>Low level</description>
                                    <value>#0</value>
                                </enumeratedValue>
                                <enumeratedValue>
                                    <name>1</name>
                                    <description>High level</description>
                                    <value>#1</value>
                                </enumeratedValue>
                            </enumeratedValues>
                        </field>
                        <field>
                            <name>PIDR02</name>
                            <description>Pmn State</description>
                            <lsb>2</lsb>
                            <msb>2</msb>
                            <access>read-only</access>
                            <enumeratedValues>
                                <enumeratedValue>
                                    <name>0</name>
                                    <description>Low level</description>
                                    <value>#0</value>
                                </enumeratedValue>
                                <enumeratedValue>
                                    <name>1</name>
                                    <description>High level</description>
                                    <value>#1</value>
                                </enumeratedValue>
                            </enumeratedValues>
                        </field>
                        <field>
                            <name>PIDR03</name>
                            <description>Pmn State</description>
                            <lsb>3</lsb>
                            <msb>3</msb>
                            <access>read-only</access>
                            <enumeratedValues>
                                <enumeratedValue>
                                    <name>0</name>
                                    <description>Low level</description>
                                    <value>#0</value>
                                </enumeratedValue>
                                <enumeratedValue>
                                    <name>1</name>
                                    <description>High level</description>
                                    <value>#1</value>
                                </enumeratedValue>
                            </enumeratedValues>
                        </field>
                        <field>
                            <name>PIDR04</name>
                            <description>Pmn State</description>
                            <lsb>4</lsb>
                            <msb>4</msb>
                            <access>read-only</access>
                            <enumeratedValues>
                                <enumeratedValue>
                                    <name>0</name>
                                    <description>Low level</description>
                                    <value>#0</value>
                                </enumeratedValue>
                                <enumeratedValue>
                                    <name>1</name>
                                    <description>High level</description>
                                    <value>#1</value>
                                </enumeratedValue>
                            </enumeratedValues>
                        </field>
                        <field>
                            <name>PIDR05</name>
                            <description>Pmn State</description>
                            <lsb>5</lsb>
                            <msb>5</msb>
                            <access>read-only</access>
                            <enumeratedValues>
                                <enumeratedValue>
                                    <name>0</name>
                                    <description>Low level</description>
                                    <value>#0</value>
                                </enumeratedValue>
                                <enumeratedValue>
                                    <name>1</name>
                                    <description>High level</description>
                                    <value>#1</value>
                                </enumeratedValue>
                            </enumeratedValues>
                        </field>
                        <field>
                            <name>PIDR06</name>
                            <description>Pmn State</description>
                            <lsb>6</lsb>
                            <msb>6</msb>
                            <access>read-only</access>
                            <enumeratedValues>
                                <enumeratedValue>
                                    <name>0</name>
                                    <description>Low level</description>
                                    <value>#0</value>
                                </enumeratedValue>
                                <enumeratedValue>
                                    <name>1</name>
                                    <description>High level</description>
                                    <value>#1</value>
                                </enumeratedValue>
                            </enumeratedValues>
                        </field>
                        <field>
                            <name>PIDR07</name>
                            <description>Pmn State</description>
                            <lsb>7</lsb>
                            <msb>7</msb>
                            <access>read-only</access>
                            <enumeratedValues>
                                <enumeratedValue>
                                    <name>0</name>
                                    <description>Low level</description>
                                    <value>#0</value>
                                </enumeratedValue>
                                <enumeratedValue>
                                    <name>1</name>
                                    <description>High level</description>
                                    <value>#1</value>
                                </enumeratedValue>
                            </enumeratedValues>
                        </field>
                        <field>
                            <name>PIDR08</name>
                            <description>Pmn State</description>
                            <lsb>8</lsb>
                            <msb>8</msb>
                            <access>read-only</access>
                            <enumeratedValues>
                                <enumeratedValue>
                                    <name>0</name>
                                    <description>Low level</description>
                                    <value>#0</value>
                                </enumeratedValue>
                                <enumeratedValue>
                                    <name>1</name>
                                    <description>High level</description>
                                    <value>#1</value>
                                </enumeratedValue>
                            </enumeratedValues>
                        </field>
                        <field>
                            <name>PIDR09</name>
                            <description>Pmn State</description>
                            <lsb>9</lsb>
                            <msb>9</msb>
                            <access>read-only</access>
                            <enumeratedValues>
                                <enumeratedValue>
                                    <name>0</name>
                                    <description>Low level</description>
                                    <value>#0</value>
                                </enumeratedValue>
                                <enumeratedValue>
                                    <name>1</name>
                                    <description>High level</description>
                                    <value>#1</value>
                                </enumeratedValue>
                            </enumeratedValues>
                        </field>
                        <field>
                            <name>PIDR10</name>
                            <description>Pmn State</description>
                            <lsb>10</lsb>
                            <msb>10</msb>
                            <access>read-only</access>
                            <enumeratedValues>
                                <enumeratedValue>
                                    <name>0</name>
                                    <description>Low level</description>
                                    <value>#0</value>
                                </enumeratedValue>
                                <enumeratedValue>
                                    <name>1</name>
                                    <description>High level</description>
                                    <value>#1</value>
                                </enumeratedValue>
                            </enumeratedValues>
                        </field>
                        <field>
                            <name>PIDR11</name>
                            <description>Pmn State</description>
                            <lsb>11</lsb>
                            <msb>11</msb>
                            <access>read-only</access>
                            <enumeratedValues>
                                <enumeratedValue>
                                    <name>0</name>
                                    <description>Low level</description>
                                    <value>#0</value>
                                </enumeratedValue>
                                <enumeratedValue>
                                    <name>1</name>
                                    <description>High level</description>
                                    <value>#1</value>
                                </enumeratedValue>
                            </enumeratedValues>
                        </field>
                        <field>
                            <name>PIDR12</name>
                            <description>Pmn State</description>
                            <lsb>12</lsb>
                            <msb>12</msb>
                            <access>read-only</access>
                            <enumeratedValues>
                                <enumeratedValue>
                                    <name>0</name>
                                    <description>Low level</description>
                                    <value>#0</value>
                                </enumeratedValue>
                                <enumeratedValue>
                                    <name>1</name>
                                    <description>High level</description>
                                    <value>#1</value>
                                </enumeratedValue>
                            </enumeratedValues>
                        </field>
                        <field>
                            <name>PIDR13</name>
                            <description>Pmn State</description>
                            <lsb>13</lsb>
                            <msb>13</msb>
                            <access>read-only</access>
                            <enumeratedValues>
                                <enumeratedValue>
                                    <name>0</name>
                                    <description>Low level</description>
                                    <value>#0</value>
                                </enumeratedValue>
                                <enumeratedValue>
                                    <name>1</name>
                                    <description>High level</description>
                                    <value>#1</value>
                                </enumeratedValue>
                            </enumeratedValues>
                        </field>
                        <field>
                            <name>PIDR14</name>
                            <description>Pmn State</description>
                            <lsb>14</lsb>
                            <msb>14</msb>
                            <access>read-only</access>
                            <enumeratedValues>
                                <enumeratedValue>
                                    <name>0</name>
                                    <description>Low level</description>
                                    <value>#0</value>
                                </enumeratedValue>
                                <enumeratedValue>
                                    <name>1</name>
                                    <description>High level</description>
                                    <value>#1</value>
                                </enumeratedValue>
                            </enumeratedValues>
                        </field>
                        <field>
                            <name>PIDR15</name>
                            <description>Pmn State</description>
                            <lsb>15</lsb>
                            <msb>15</msb>
                            <access>read-only</access>
                            <enumeratedValues>
                                <enumeratedValue>
                                    <name>0</name>
                                    <description>Low level</description>
                                    <value>#0</value>
                                </enumeratedValue>
                                <enumeratedValue>
                                    <name>1</name>
                                    <description>High level</description>
                                    <value>#1</value>
                                </enumeratedValue>
                            </enumeratedValues>
                        </field>
                        <field>
                            <name>EIDR00</name>
                            <description>Port Event Input Data</description>
                            <lsb>16</lsb>
                            <msb>16</msb>
                            <access>read-only</access>
                            <enumeratedValues>
                                <enumeratedValue>
                                    <name>0</name>
                                    <description>Low input</description>
                                    <value>#0</value>
                                </enumeratedValue>
                                <enumeratedValue>
                                    <name>1</name>
                                    <description>High input</description>
                                    <value>#1</value>
                                </enumeratedValue>
                            </enumeratedValues>
                        </field>
                        <field>
                            <name>EIDR01</name>
                            <description>Port Event Input Data</description>
                            <lsb>17</lsb>
                            <msb>17</msb>
                            <access>read-only</access>
                            <enumeratedValues>
                                <enumeratedValue>
                                    <name>0</name>
                                    <description>Low input</description>
                                    <value>#0</value>
                                </enumeratedValue>
                                <enumeratedValue>
                                    <name>1</name>
                                    <description>High input</description>
                                    <value>#1</value>
                                </enumeratedValue>
                            </enumeratedValues>
                        </field>
                        <field>
                            <name>EIDR02</name>
                            <description>Port Event Input Data</description>
                            <lsb>18</lsb>
                            <msb>18</msb>
                            <access>read-only</access>
                            <enumeratedValues>
                                <enumeratedValue>
                                    <name>0</name>
                                    <description>Low input</description>
                                    <value>#0</value>
                                </enumeratedValue>
                                <enumeratedValue>
                                    <name>1</name>
                                    <description>High input</description>
                                    <value>#1</value>
                                </enumeratedValue>
                            </enumeratedValues>
                        </field>
                        <field>
                            <name>EIDR03</name>
                            <description>Port Event Input Data</description>
                            <lsb>19</lsb>
                            <msb>19</msb>
                            <access>read-only</access>
                            <enumeratedValues>
                                <enumeratedValue>
                                    <name>0</name>
                                    <description>Low input</description>
                                    <value>#0</value>
                                </enumeratedValue>
                                <enumeratedValue>
                                    <name>1</name>
                                    <description>High input</description>
                                    <value>#1</value>
                                </enumeratedValue>
                            </enumeratedValues>
                        </field>
                        <field>
                            <name>EIDR04</name>
                            <description>Port Event Input Data</description>
                            <lsb>20</lsb>
                            <msb>20</msb>
                            <access>read-only</access>
                            <enumeratedValues>
                                <enumeratedValue>
                                    <name>0</name>
                                    <description>Low input</description>
                                    <value>#0</value>
                                </enumeratedValue>
                                <enumeratedValue>
                                    <name>1</name>
                                    <description>High input</description>
                                    <value>#1</value>
                                </enumeratedValue>
                            </enumeratedValues>
                        </field>
                        <field>
                            <name>EIDR05</name>
                            <description>Port Event Input Data</description>
                            <lsb>21</lsb>
                            <msb>21</msb>
                            <access>read-only</access>
                            <enumeratedValues>
                                <enumeratedValue>
                                    <name>0</name>
                                    <description>Low input</description>
                                    <value>#0</value>
                                </enumeratedValue>
                                <enumeratedValue>
                                    <name>1</name>
                                    <description>High input</description>
                                    <value>#1</value>
                                </enumeratedValue>
                            </enumeratedValues>
                        </field>
                        <field>
                            <name>EIDR06</name>
                            <description>Port Event Input Data</description>
                            <lsb>22</lsb>
                            <msb>22</msb>
                            <access>read-only</access>
                            <enumeratedValues>
                                <enumeratedValue>
                                    <name>0</name>
                                    <description>Low input</description>
                                    <value>#0</value>
                                </enumeratedValue>
                                <enumeratedValue>
                                    <name>1</name>
                                    <description>High input</description>
                                    <value>#1</value>
                                </enumeratedValue>
                            </enumeratedValues>
                        </field>
                        <field>
                            <name>EIDR07</name>
                            <description>Port Event Input Data</description>
                            <lsb>23</lsb>
                            <msb>23</msb>
                            <access>read-only</access>
                            <enumeratedValues>
                                <enumeratedValue>
                                    <name>0</name>
                                    <description>Low input</description>
                                    <value>#0</value>
                                </enumeratedValue>
                                <enumeratedValue>
                                    <name>1</name>
                                    <description>High input</description>
                                    <value>#1</value>
                                </enumeratedValue>
                            </enumeratedValues>
                        </field>
                        <field>
                            <name>EIDR08</name>
                            <description>Port Event Input Data</description>
                            <lsb>24</lsb>
                            <msb>24</msb>
                            <access>read-only</access>
                            <enumeratedValues>
                                <enumeratedValue>
                                    <name>0</name>
                                    <description>Low input</description>
                                    <value>#0</value>
                                </enumeratedValue>
                                <enumeratedValue>
                                    <name>1</name>
                                    <description>High input</description>
                                    <value>#1</value>
                                </enumeratedValue>
                            </enumeratedValues>
                        </field>
                        <field>
                            <name>EIDR09</name>
                            <description>Port Event Input Data</description>
                            <lsb>25</lsb>
                            <msb>25</msb>
                            <access>read-only</access>
                            <enumeratedValues>
                                <enumeratedValue>
                                    <name>0</name>
                                    <description>Low input</description>
                                    <value>#0</value>
                                </enumeratedValue>
                                <enumeratedValue>
                                    <name>1</name>
                                    <description>High input</description>
                                    <value>#1</value>
                                </enumeratedValue>
                            </enumeratedValues>
                        </field>
                        <field>
                            <name>EIDR10</name>
                            <description>Port Event Input Data</description>
                            <lsb>26</lsb>
                            <msb>26</msb>
                            <access>read-only</access>
                            <enumeratedValues>
                                <enumeratedValue>
                                    <name>0</name>
                                    <description>Low input</description>
                                    <value>#0</value>
                                </enumeratedValue>
                                <enumeratedValue>
                                    <name>1</name>
                                    <description>High input</description>
                                    <value>#1</value>
                                </enumeratedValue>
                            </enumeratedValues>
                        </field>
                        <field>
                            <name>EIDR11</name>
                            <description>Port Event Input Data</description>
                            <lsb>27</lsb>
                            <msb>27</msb>
                            <access>read-only</access>
                            <enumeratedValues>
                                <enumeratedValue>
                                    <name>0</name>
                                    <description>Low input</description>
                                    <value>#0</value>
                                </enumeratedValue>
                                <enumeratedValue>
                                    <name>1</name>
                                    <description>High input</description>
                                    <value>#1</value>
                                </enumeratedValue>
                            </enumeratedValues>
                        </field>
                        <field>
                            <name>EIDR12</name>
                            <description>Port Event Input Data</description>
                            <lsb>28</lsb>
                            <msb>28</msb>
                            <access>read-only</access>
                            <enumeratedValues>
                                <enumeratedValue>
                                    <name>0</name>
                                    <description>Low input</description>
                                    <value>#0</value>
                                </enumeratedValue>
                                <enumeratedValue>
                                    <name>1</name>
                                    <description>High input</description>
                                    <value>#1</value>
                                </enumeratedValue>
                            </enumeratedValues>
                        </field>
                        <field>
                            <name>EIDR13</name>
                            <description>Port Event Input Data</description>
                            <lsb>29</lsb>
                            <msb>29</msb>
                            <access>read-only</access>
                            <enumeratedValues>
                                <enumeratedValue>
                                    <name>0</name>
                                    <description>Low input</description>
                                    <value>#0</value>
                                </enumeratedValue>
                                <enumeratedValue>
                                    <name>1</name>
                                    <description>High input</description>
                                    <value>#1</value>
                                </enumeratedValue>
                            </enumeratedValues>
                        </field>
                        <field>
                            <name>EIDR14</name>
                            <description>Port Event Input Data</description>
                            <lsb>30</lsb>
                            <msb>30</msb>
                            <access>read-only</access>
                            <enumeratedValues>
                                <enumeratedValue>
                                    <name>0</name>
                                    <description>Low input</description>
                                    <value>#0</value>
                                </enumeratedValue>
                                <enumeratedValue>
                                    <name>1</name>
                                    <description>High input</description>
                                    <value>#1</value>
                                </enumeratedValue>
                            </enumeratedValues>
                        </field>
                        <field>
                            <name>EIDR15</name>
                            <description>Port Event Input Data</description>
                            <lsb>31</lsb>
                            <msb>31</msb>
                            <access>read-only</access>
                            <enumeratedValues>
                                <enumeratedValue>
                                    <name>0</name>
                                    <description>Low input</description>
                                    <value>#0</value>
                                </enumeratedValue>
                                <enumeratedValue>
                                    <name>1</name>
                                    <description>High input</description>
                                    <value>#1</value>
                                </enumeratedValue>
                            </enumeratedValues>
                        </field>
                    </fields>
                </register>
                <register>
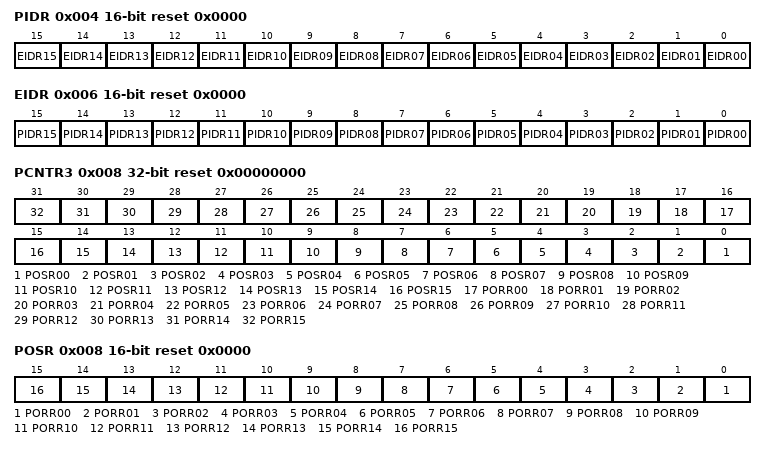
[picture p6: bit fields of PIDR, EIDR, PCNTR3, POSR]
                    <name>PIDR</name>
                    <description>Port Control Register 2</description>
                    <alternateRegister>PCNTR2</alternateRegister>
                    <addressOffset>0x004</addressOffset>
                    <size>16</size>
                    <access>read-only</access>
                    <resetValue>0x0000</resetValue>
                    <resetMask>0xffff</resetMask>
                    <fields>
                        <field>
                            <name>EIDR00</name>
                            <description>Port Event Input Data</description>
                            <lsb>0</lsb>
                            <msb>0</msb>
                            <access>read-only</access>
                            <enumeratedValues>
                                <enumeratedValue>
                                    <name>0</name>
                                    <description>Low input</description>
                                    <value>#0</value>
                                </enumeratedValue>
                                <enumeratedValue>
                                    <name>1</name>
                                    <description>High input</description>
                                    <value>#1</value>
                                </enumeratedValue>
                            </enumeratedValues>
                        </field>
                        <field>
                            <name>EIDR01</name>
                            <description>Port Event Input Data</description>
                            <lsb>1</lsb>
                            <msb>1</msb>
                            <access>read-only</access>
                            <enumeratedValues>
                                <enumeratedValue>
                                    <name>0</name>
                                    <description>Low input</description>
                                    <value>#0</value>
                                </enumeratedValue>
                                <enumeratedValue>
                                    <name>1</name>
                                    <description>High input</description>
                                    <value>#1</value>
                                </enumeratedValue>
                            </enumeratedValues>
                        </field>
                        <field>
                            <name>EIDR02</name>
                            <description>Port Event Input Data</description>
                            <lsb>2</lsb>
                            <msb>2</msb>
                            <access>read-only</access>
                            <enumeratedValues>
                                <enumeratedValue>
                                    <name>0</name>
                                    <description>Low input</description>
                                    <value>#0</value>
                                </enumeratedValue>
                                <enumeratedValue>
                                    <name>1</name>
                                    <description>High input</description>
                                    <value>#1</value>
                                </enumeratedValue>
                            </enumeratedValues>
                        </field>
                        <field>
                            <name>EIDR03</name>
                            <description>Port Event Input Data</description>
                            <lsb>3</lsb>
                            <msb>3</msb>
                            <access>read-only</access>
                            <enumeratedValues>
                                <enumeratedValue>
                                    <name>0</name>
                                    <description>Low input</description>
                                    <value>#0</value>
                                </enumeratedValue>
                                <enumeratedValue>
                                    <name>1</name>
                                    <description>High input</description>
                                    <value>#1</value>
                                </enumeratedValue>
                            </enumeratedValues>
                        </field>
                        <field>
                            <name>EIDR04</name>
                            <description>Port Event Input Data</description>
                            <lsb>4</lsb>
                            <msb>4</msb>
                            <access>read-only</access>
                            <enumeratedValues>
                                <enumeratedValue>
                                    <name>0</name>
                                    <description>Low input</description>
                                    <value>#0</value>
                                </enumeratedValue>
                                <enumeratedValue>
                                    <name>1</name>
                                    <description>High input</description>
                                    <value>#1</value>
                                </enumeratedValue>
                            </enumeratedValues>
                        </field>
                        <field>
                            <name>EIDR05</name>
                            <description>Port Event Input Data</description>
                            <lsb>5</lsb>
                            <msb>5</msb>
                            <access>read-only</access>
                            <enumeratedValues>
                                <enumeratedValue>
                                    <name>0</name>
                                    <description>Low input</description>
                                    <value>#0</value>
                                </enumeratedValue>
                                <enumeratedValue>
                                    <name>1</name>
                                    <description>High input</description>
                                    <value>#1</value>
                                </enumeratedValue>
                            </enumeratedValues>
                        </field>
                        <field>
                            <name>EIDR06</name>
                            <description>Port Event Input Data</description>
                            <lsb>6</lsb>
                            <msb>6</msb>
                            <access>read-only</access>
                            <enumeratedValues>
                                <enumeratedValue>
                                    <name>0</name>
                                    <description>Low input</description>
                                    <value>#0</value>
                                </enumeratedValue>
                                <enumeratedValue>
                                    <name>1</name>
                                    <description>High input</description>
                                    <value>#1</value>
                                </enumeratedValue>
                            </enumeratedValues>
                        </field>
                        <field>
                            <name>EIDR07</name>
                            <description>Port Event Input Data</description>
                            <lsb>7</lsb>
                            <msb>7</msb>
                            <access>read-only</access>
                            <enumeratedValues>
                                <enumeratedValue>
                                    <name>0</name>
                                    <description>Low input</description>
                                    <value>#0</value>
                                </enumeratedValue>
                                <enumeratedValue>
                                    <name>1</name>
                                    <description>High input</description>
                                    <value>#1</value>
                                </enumeratedValue>
                            </enumeratedValues>
                        </field>
                        <field>
                            <name>EIDR08</name>
                            <description>Port Event Input Data</description>
                            <lsb>8</lsb>
                            <msb>8</msb>
                            <access>read-only</access>
                            <enumeratedValues>
                                <enumeratedValue>
                                    <name>0</name>
                                    <description>Low input</description>
                                    <value>#0</value>
                                </enumeratedValue>
                                <enumeratedValue>
                                    <name>1</name>
                                    <description>High input</description>
                                    <value>#1</value>
                                </enumeratedValue>
                            </enumeratedValues>
                        </field>
                        <field>
                            <name>EIDR09</name>
                            <description>Port Event Input Data</description>
                            <lsb>9</lsb>
                            <msb>9</msb>
                            <access>read-only</access>
                            <enumeratedValues>
                                <enumeratedValue>
                                    <name>0</name>
                                    <description>Low input</description>
                                    <value>#0</value>
                                </enumeratedValue>
                                <enumeratedValue>
                                    <name>1</name>
                                    <description>High input</description>
                                    <value>#1</value>
                                </enumeratedValue>
                            </enumeratedValues>
                        </field>
                        <field>
                            <name>EIDR10</name>
                            <description>Port Event Input Data</description>
                            <lsb>10</lsb>
                            <msb>10</msb>
                            <access>read-only</access>
                            <enumeratedValues>
                                <enumeratedValue>
                                    <name>0</name>
                                    <description>Low input</description>
                                    <value>#0</value>
                                </enumeratedValue>
                                <enumeratedValue>
                                    <name>1</name>
                                    <description>High input</description>
                                    <value>#1</value>
                                </enumeratedValue>
                            </enumeratedValues>
                        </field>
                        <field>
                            <name>EIDR11</name>
                            <description>Port Event Input Data</description>
                            <lsb>11</lsb>
                            <msb>11</msb>
                            <access>read-only</access>
                            <enumeratedValues>
                                <enumeratedValue>
                                    <name>0</name>
                                    <description>Low input</description>
                                    <value>#0</value>
                                </enumeratedValue>
                                <enumeratedValue>
                                    <name>1</name>
                                    <description>High input</description>
                                    <value>#1</value>
                                </enumeratedValue>
                            </enumeratedValues>
                        </field>
                        <field>
                            <name>EIDR12</name>
                            <description>Port Event Input Data</description>
                            <lsb>12</lsb>
                            <msb>12</msb>
                            <access>read-only</access>
                            <enumeratedValues>
                                <enumeratedValue>
                                    <name>0</name>
                                    <description>Low input</description>
                                    <value>#0</value>
                                </enumeratedValue>
                                <enumeratedValue>
                                    <name>1</name>
                                    <description>High input</description>
                                    <value>#1</value>
                                </enumeratedValue>
                            </enumeratedValues>
                        </field>
                        <field>
                            <name>EIDR13</name>
                            <description>Port Event Input Data</description>
                            <lsb>13</lsb>
                            <msb>13</msb>
                            <access>read-only</access>
                            <enumeratedValues>
                                <enumeratedValue>
                                    <name>0</name>
                                    <description>Low input</description>
                                    <value>#0</value>
                                </enumeratedValue>
                                <enumeratedValue>
                                    <name>1</name>
                                    <description>High input</description>
                                    <value>#1</value>
                                </enumeratedValue>
                            </enumeratedValues>
                        </field>
                        <field>
                            <name>EIDR14</name>
                            <description>Port Event Input Data</description>
                            <lsb>14</lsb>
                            <msb>14</msb>
                            <access>read-only</access>
                            <enumeratedValues>
                                <enumeratedValue>
                                    <name>0</name>
                                    <description>Low input</description>
                                    <value>#0</value>
                                </enumeratedValue>
                                <enumeratedValue>
                                    <name>1</name>
                                    <description>High input</description>
                                    <value>#1</value>
                                </enumeratedValue>
                            </enumeratedValues>
                        </field>
                        <field>
                            <name>EIDR15</name>
                            <description>Port Event Input Data</description>
                            <lsb>15</lsb>
                            <msb>15</msb>
                            <access>read-only</access>
                            <enumeratedValues>
                                <enumeratedValue>
                                    <name>0</name>
                                    <description>Low input</description>
                                    <value>#0</value>
                                </enumeratedValue>
                                <enumeratedValue>
                                    <name>1</name>
                                    <description>High input</description>
                                    <value>#1</value>
                                </enumeratedValue>
                            </enumeratedValues>
                        </field>
                    </fields>
                </register>
                <register>
                    <name>EIDR</name>
                    <description>Port Control Register 2</description>
                    <alternateRegister>PCNTR2</alternateRegister>
                    <addressOffset>0x006</addressOffset>
                    <size>16</size>
                    <access>read-only</access>
                    <resetValue>0x0000</resetValue>
                    <resetMask>0x0000</resetMask>
                    <fields>
                        <field>
                            <name>PIDR00</name>
                            <description>Pmn State</description>
                            <lsb>0</lsb>
                            <msb>0</msb>
                            <access>read-only</access>
                            <enumeratedValues>
                                <enumeratedValue>
                                    <name>0</name>
                                    <description>Low level</description>
                                    <value>#0</value>
                                </enumeratedValue>
                                <enumeratedValue>
                                    <name>1</name>
                                    <description>High level</description>
                                    <value>#1</value>
                                </enumeratedValue>
                            </enumeratedValues>
                        </field>
                        <field>
                            <name>PIDR01</name>
                            <description>Pmn State</description>
                            <lsb>1</lsb>
                            <msb>1</msb>
                            <access>read-only</access>
                            <enumeratedValues>
                                <enumeratedValue>
                                    <name>0</name>
                                    <description>Low level</description>
                                    <value>#0</value>
                                </enumeratedValue>
                                <enumeratedValue>
                                    <name>1</name>
                                    <description>High level</description>
                                    <value>#1</value>
                                </enumeratedValue>
                            </enumeratedValues>
                        </field>
                        <field>
                            <name>PIDR02</name>
                            <description>Pmn State</description>
                            <lsb>2</lsb>
                            <msb>2</msb>
                            <access>read-only</access>
                            <enumeratedValues>
                                <enumeratedValue>
                                    <name>0</name>
                                    <description>Low level</description>
                                    <value>#0</value>
                                </enumeratedValue>
                                <enumeratedValue>
                                    <name>1</name>
                                    <description>High level</description>
                                    <value>#1</value>
                                </enumeratedValue>
                            </enumeratedValues>
                        </field>
                        <field>
                            <name>PIDR03</name>
                            <description>Pmn State</description>
                            <lsb>3</lsb>
                            <msb>3</msb>
                            <access>read-only</access>
                            <enumeratedValues>
                                <enumeratedValue>
                                    <name>0</name>
                                    <description>Low level</description>
                                    <value>#0</value>
                                </enumeratedValue>
                                <enumeratedValue>
                                    <name>1</name>
                                    <description>High level</description>
                                    <value>#1</value>
                                </enumeratedValue>
                            </enumeratedValues>
                        </field>
                        <field>
                            <name>PIDR04</name>
                            <description>Pmn State</description>
                            <lsb>4</lsb>
                            <msb>4</msb>
                            <access>read-only</access>
                            <enumeratedValues>
                                <enumeratedValue>
                                    <name>0</name>
                                    <description>Low level</description>
                                    <value>#0</value>
                                </enumeratedValue>
                                <enumeratedValue>
                                    <name>1</name>
                                    <description>High level</description>
                                    <value>#1</value>
                                </enumeratedValue>
                            </enumeratedValues>
                        </field>
                        <field>
                            <name>PIDR05</name>
                            <description>Pmn State</description>
                            <lsb>5</lsb>
                            <msb>5</msb>
                            <access>read-only</access>
                            <enumeratedValues>
                                <enumeratedValue>
                                    <name>0</name>
                                    <description>Low level</description>
                                    <value>#0</value>
                                </enumeratedValue>
                                <enumeratedValue>
                                    <name>1</name>
                                    <description>High level</description>
                                    <value>#1</value>
                                </enumeratedValue>
                            </enumeratedValues>
                        </field>
                        <field>
                            <name>PIDR06</name>
                            <description>Pmn State</description>
                            <lsb>6</lsb>
                            <msb>6</msb>
                            <access>read-only</access>
                            <enumeratedValues>
                                <enumeratedValue>
                                    <name>0</name>
                                    <description>Low level</description>
                                    <value>#0</value>
                                </enumeratedValue>
                                <enumeratedValue>
                                    <name>1</name>
                                    <description>High level</description>
                                    <value>#1</value>
                                </enumeratedValue>
                            </enumeratedValues>
                        </field>
                        <field>
                            <name>PIDR07</name>
                            <description>Pmn State</description>
                            <lsb>7</lsb>
                            <msb>7</msb>
                            <access>read-only</access>
                            <enumeratedValues>
                                <enumeratedValue>
                                    <name>0</name>
                                    <description>Low level</description>
                                    <value>#0</value>
                                </enumeratedValue>
                                <enumeratedValue>
                                    <name>1</name>
                                    <description>High level</description>
                                    <value>#1</value>
                                </enumeratedValue>
                            </enumeratedValues>
                        </field>
                        <field>
                            <name>PIDR08</name>
                            <description>Pmn State</description>
                            <lsb>8</lsb>
                            <msb>8</msb>
                            <access>read-only</access>
                            <enumeratedValues>
                                <enumeratedValue>
                                    <name>0</name>
                                    <description>Low level</description>
                                    <value>#0</value>
                                </enumeratedValue>
                                <enumeratedValue>
                                    <name>1</name>
                                    <description>High level</description>
                                    <value>#1</value>
                                </enumeratedValue>
                            </enumeratedValues>
                        </field>
                        <field>
                            <name>PIDR09</name>
                            <description>Pmn State</description>
                            <lsb>9</lsb>
                            <msb>9</msb>
                            <access>read-only</access>
                            <enumeratedValues>
                                <enumeratedValue>
                                    <name>0</name>
                                    <description>Low level</description>
                                    <value>#0</value>
                                </enumeratedValue>
                                <enumeratedValue>
                                    <name>1</name>
                                    <description>High level</description>
                                    <value>#1</value>
                                </enumeratedValue>
                            </enumeratedValues>
                        </field>
                        <field>
                            <name>PIDR10</name>
                            <description>Pmn State</description>
                            <lsb>10</lsb>
                            <msb>10</msb>
                            <access>read-only</access>
                            <enumeratedValues>
                                <enumeratedValue>
                                    <name>0</name>
                                    <description>Low level</description>
                                    <value>#0</value>
                                </enumeratedValue>
                                <enumeratedValue>
                                    <name>1</name>
                                    <description>High level</description>
                                    <value>#1</value>
                                </enumeratedValue>
                            </enumeratedValues>
                        </field>
                        <field>
                            <name>PIDR11</name>
                            <description>Pmn State</description>
                            <lsb>11</lsb>
                            <msb>11</msb>
                            <access>read-only</access>
                            <enumeratedValues>
                                <enumeratedValue>
                                    <name>0</name>
                                    <description>Low level</description>
                                    <value>#0</value>
                                </enumeratedValue>
                                <enumeratedValue>
                                    <name>1</name>
                                    <description>High level</description>
                                    <value>#1</value>
                                </enumeratedValue>
                            </enumeratedValues>
                        </field>
                        <field>
                            <name>PIDR12</name>
                            <description>Pmn State</description>
                            <lsb>12</lsb>
                            <msb>12</msb>
                            <access>read-only</access>
                            <enumeratedValues>
                                <enumeratedValue>
                                    <name>0</name>
                                    <description>Low level</description>
                                    <value>#0</value>
                                </enumeratedValue>
                                <enumeratedValue>
                                    <name>1</name>
                                    <description>High level</description>
                                    <value>#1</value>
                                </enumeratedValue>
                            </enumeratedValues>
                        </field>
                        <field>
                            <name>PIDR13</name>
                            <description>Pmn State</description>
                            <lsb>13</lsb>
                            <msb>13</msb>
                            <access>read-only</access>
                            <enumeratedValues>
                                <enumeratedValue>
                                    <name>0</name>
                                    <description>Low level</description>
                                    <value>#0</value>
                                </enumeratedValue>
                                <enumeratedValue>
                                    <name>1</name>
                                    <description>High level</description>
                                    <value>#1</value>
                                </enumeratedValue>
                            </enumeratedValues>
                        </field>
                        <field>
                            <name>PIDR14</name>
                            <description>Pmn State</description>
                            <lsb>14</lsb>
                            <msb>14</msb>
                            <access>read-only</access>
                            <enumeratedValues>
                                <enumeratedValue>
                                    <name>0</name>
                                    <description>Low level</description>
                                    <value>#0</value>
                                </enumeratedValue>
                                <enumeratedValue>
                                    <name>1</name>
                                    <description>High level</description>
                                    <value>#1</value>
                                </enumeratedValue>
                            </enumeratedValues>
                        </field>
                        <field>
                            <name>PIDR15</name>
                            <description>Pmn State</description>
                            <lsb>15</lsb>
                            <msb>15</msb>
                            <access>read-only</access>
                            <enumeratedValues>
                                <enumeratedValue>
                                    <name>0</name>
                                    <description>Low level</description>
                                    <value>#0</value>
                                </enumeratedValue>
                                <enumeratedValue>
                                    <name>1</name>
                                    <description>High level</description>
                                    <value>#1</value>
                                </enumeratedValue>
                            </enumeratedValues>
                        </field>
                    </fields>
                </register>
                <register>
                    <name>PCNTR3</name>
                    <description>Port Control Register 3</description>
                    <addressOffset>0x008</addressOffset>
                    <size>32</size>
                    <access>write-only</access>
                    <resetValue>0x00000000</resetValue>
                    <resetMask>0xffffffff</resetMask>
                    <fields>
                        <field>
                            <name>POSR00</name>
                            <description>Pmn Output Set</description>
                            <lsb>0</lsb>
                            <msb>0</msb>
                            <access>write-only</access>
                            <enumeratedValues>
                                <enumeratedValue>
                                    <name>0</name>
                                    <description>No effect on output</description>
                                    <value>#0</value>
                                </enumeratedValue>
                                <enumeratedValue>
                                    <name>1</name>
                                    <description>High output</description>
                                    <value>#1</value>
                                </enumeratedValue>
                            </enumeratedValues>
                        </field>
                        <field>
                            <name>POSR01</name>
                            <description>Pmn Output Set</description>
                            <lsb>1</lsb>
                            <msb>1</msb>
                            <access>write-only</access>
                            <enumeratedValues>
                                <enumeratedValue>
                                    <name>0</name>
                                    <description>No effect on output</description>
                                    <value>#0</value>
                                </enumeratedValue>
                                <enumeratedValue>
                                    <name>1</name>
                                    <description>High output</description>
                                    <value>#1</value>
                                </enumeratedValue>
                            </enumeratedValues>
                        </field>
                        <field>
                            <name>POSR02</name>
                            <description>Pmn Output Set</description>
                            <lsb>2</lsb>
                            <msb>2</msb>
                            <access>write-only</access>
                            <enumeratedValues>
                                <enumeratedValue>
                                    <name>0</name>
                                    <description>No effect on output</description>
                                    <value>#0</value>
                                </enumeratedValue>
                                <enumeratedValue>
                                    <name>1</name>
                                    <description>High output</description>
                                    <value>#1</value>
                                </enumeratedValue>
                            </enumeratedValues>
                        </field>
                        <field>
                            <name>POSR03</name>
                            <description>Pmn Output Set</description>
                            <lsb>3</lsb>
                            <msb>3</msb>
                            <access>write-only</access>
                            <enumeratedValues>
                                <enumeratedValue>
                                    <name>0</name>
                                    <description>No effect on output</description>
                                    <value>#0</value>
                                </enumeratedValue>
                                <enumeratedValue>
                                    <name>1</name>
                                    <description>High output</description>
                                    <value>#1</value>
                                </enumeratedValue>
                            </enumeratedValues>
                        </field>
                        <field>
                            <name>POSR04</name>
                            <description>Pmn Output Set</description>
                            <lsb>4</lsb>
                            <msb>4</msb>
                            <access>write-only</access>
                            <enumeratedValues>
                                <enumeratedValue>
                                    <name>0</name>
                                    <description>No effect on output</description>
                                    <value>#0</value>
                                </enumeratedValue>
                                <enumeratedValue>
                                    <name>1</name>
                                    <description>High output</description>
                                    <value>#1</value>
                                </enumeratedValue>
                            </enumeratedValues>
                        </field>
                        <field>
                            <name>POSR05</name>
                            <description>Pmn Output Set</description>
                            <lsb>5</lsb>
                            <msb>5</msb>
                            <access>write-only</access>
                            <enumeratedValues>
                                <enumeratedValue>
                                    <name>0</name>
                                    <description>No effect on output</description>
                                    <value>#0</value>
                                </enumeratedValue>
                                <enumeratedValue>
                                    <name>1</name>
                                    <description>High output</description>
                                    <value>#1</value>
                                </enumeratedValue>
                            </enumeratedValues>
                        </field>
                        <field>
                            <name>POSR06</name>
                            <description>Pmn Output Set</description>
                            <lsb>6</lsb>
                            <msb>6</msb>
                            <access>write-only</access>
                            <enumeratedValues>
                                <enumeratedValue>
                                    <name>0</name>
                                    <description>No effect on output</description>
                                    <value>#0</value>
                                </enumeratedValue>
                                <enumeratedValue>
                                    <name>1</name>
                                    <description>High output</description>
                                    <value>#1</value>
                                </enumeratedValue>
                            </enumeratedValues>
                        </field>
                        <field>
                            <name>POSR07</name>
                            <description>Pmn Output Set</description>
                            <lsb>7</lsb>
                            <msb>7</msb>
                            <access>write-only</access>
                            <enumeratedValues>
                                <enumeratedValue>
                                    <name>0</name>
                                    <description>No effect on output</description>
                                    <value>#0</value>
                                </enumeratedValue>
                                <enumeratedValue>
                                    <name>1</name>
                                    <description>High output</description>
                                    <value>#1</value>
                                </enumeratedValue>
                            </enumeratedValues>
                        </field>
                        <field>
                            <name>POSR08</name>
                            <description>Pmn Output Set</description>
                            <lsb>8</lsb>
                            <msb>8</msb>
                            <access>write-only</access>
                            <enumeratedValues>
                                <enumeratedValue>
                                    <name>0</name>
                                    <description>No effect on output</description>
                                    <value>#0</value>
                                </enumeratedValue>
                                <enumeratedValue>
                                    <name>1</name>
                                    <description>High output</description>
                                    <value>#1</value>
                                </enumeratedValue>
                            </enumeratedValues>
                        </field>
                        <field>
                            <name>POSR09</name>
                            <description>Pmn Output Set</description>
                            <lsb>9</lsb>
                            <msb>9</msb>
                            <access>write-only</access>
                            <enumeratedValues>
                                <enumeratedValue>
                                    <name>0</name>
                                    <description>No effect on output</description>
                                    <value>#0</value>
                                </enumeratedValue>
                                <enumeratedValue>
                                    <name>1</name>
                                    <description>High output</description>
                                    <value>#1</value>
                                </enumeratedValue>
                            </enumeratedValues>
                        </field>
                        <field>
                            <name>POSR10</name>
                            <description>Pmn Output Set</description>
                            <lsb>10</lsb>
                            <msb>10</msb>
                            <access>write-only</access>
                            <enumeratedValues>
                                <enumeratedValue>
                                    <name>0</name>
                                    <description>No effect on output</description>
                                    <value>#0</value>
                                </enumeratedValue>
                                <enumeratedValue>
                                    <name>1</name>
                                    <description>High output</description>
                                    <value>#1</value>
                                </enumeratedValue>
                            </enumeratedValues>
                        </field>
                        <field>
                            <name>POSR11</name>
                            <description>Pmn Output Set</description>
                            <lsb>11</lsb>
                            <msb>11</msb>
                            <access>write-only</access>
                            <enumeratedValues>
                                <enumeratedValue>
                                    <name>0</name>
                                    <description>No effect on output</description>
                                    <value>#0</value>
                                </enumeratedValue>
                                <enumeratedValue>
                                    <name>1</name>
                                    <description>High output</description>
                                    <value>#1</value>
                                </enumeratedValue>
                            </enumeratedValues>
                        </field>
                        <field>
                            <name>POSR12</name>
                            <description>Pmn Output Set</description>
                            <lsb>12</lsb>
                            <msb>12</msb>
                            <access>write-only</access>
                            <enumeratedValues>
                                <enumeratedValue>
                                    <name>0</name>
                                    <description>No effect on output</description>
                                    <value>#0</value>
                                </enumeratedValue>
                                <enumeratedValue>
                                    <name>1</name>
                                    <description>High output</description>
                                    <value>#1</value>
                                </enumeratedValue>
                            </enumeratedValues>
                        </field>
                        <field>
                            <name>POSR13</name>
                            <description>Pmn Output Set</description>
                            <lsb>13</lsb>
                            <msb>13</msb>
                            <access>write-only</access>
                            <enumeratedValues>
                                <enumeratedValue>
                                    <name>0</name>
                                    <description>No effect on output</description>
                                    <value>#0</value>
                                </enumeratedValue>
                                <enumeratedValue>
                                    <name>1</name>
                                    <description>High output</description>
                                    <value>#1</value>
                                </enumeratedValue>
                            </enumeratedValues>
                        </field>
                        <field>
                            <name>POSR14</name>
                            <description>Pmn Output Set</description>
                            <lsb>14</lsb>
                            <msb>14</msb>
                            <access>write-only</access>
                            <enumeratedValues>
                                <enumeratedValue>
                                    <name>0</name>
                                    <description>No effect on output</description>
                                    <value>#0</value>
                                </enumeratedValue>
                                <enumeratedValue>
                                    <name>1</name>
                                    <description>High output</description>
                                    <value>#1</value>
                                </enumeratedValue>
                            </enumeratedValues>
                        </field>
                        <field>
                            <name>POSR15</name>
                            <description>Pmn Output Set</description>
                            <lsb>15</lsb>
                            <msb>15</msb>
                            <access>write-only</access>
                            <enumeratedValues>
                                <enumeratedValue>
                                    <name>0</name>
                                    <description>No effect on output</description>
                                    <value>#0</value>
                                </enumeratedValue>
                                <enumeratedValue>
                                    <name>1</name>
                                    <description>High output</description>
                                    <value>#1</value>
                                </enumeratedValue>
                            </enumeratedValues>
                        </field>
                        <field>
                            <name>PORR00</name>
                            <description>Pmn Output Reset</description>
                            <lsb>16</lsb>
                            <msb>16</msb>
                            <access>write-only</access>
                            <enumeratedValues>
                                <enumeratedValue>
                                    <name>0</name>
                                    <description>No effect on output</description>
                                    <value>#0</value>
                                </enumeratedValue>
                                <enumeratedValue>
                                    <name>1</name>
                                    <description>Low output</description>
                                    <value>#1</value>
                                </enumeratedValue>
                            </enumeratedValues>
                        </field>
                        <field>
                            <name>PORR01</name>
                            <description>Pmn Output Reset</description>
                            <lsb>17</lsb>
                            <msb>17</msb>
                            <access>write-only</access>
                            <enumeratedValues>
                                <enumeratedValue>
                                    <name>0</name>
                                    <description>No effect on output</description>
                                    <value>#0</value>
                                </enumeratedValue>
                                <enumeratedValue>
                                    <name>1</name>
                                    <description>Low output</description>
                                    <value>#1</value>
                                </enumeratedValue>
                            </enumeratedValues>
                        </field>
                        <field>
                            <name>PORR02</name>
                            <description>Pmn Output Reset</description>
                            <lsb>18</lsb>
                            <msb>18</msb>
                            <access>write-only</access>
                            <enumeratedValues>
                                <enumeratedValue>
                                    <name>0</name>
                                    <description>No effect on output</description>
                                    <value>#0</value>
                                </enumeratedValue>
                                <enumeratedValue>
                                    <name>1</name>
                                    <description>Low output</description>
                                    <value>#1</value>
                                </enumeratedValue>
                            </enumeratedValues>
                        </field>
                        <field>
                            <name>PORR03</name>
                            <description>Pmn Output Reset</description>
                            <lsb>19</lsb>
                            <msb>19</msb>
                            <access>write-only</access>
                            <enumeratedValues>
                                <enumeratedValue>
                                    <name>0</name>
                                    <description>No effect on output</description>
                                    <value>#0</value>
                                </enumeratedValue>
                                <enumeratedValue>
                                    <name>1</name>
                                    <description>Low output</description>
                                    <value>#1</value>
                                </enumeratedValue>
                            </enumeratedValues>
                        </field>
                        <field>
                            <name>PORR04</name>
                            <description>Pmn Output Reset</description>
                            <lsb>20</lsb>
                            <msb>20</msb>
                            <access>write-only</access>
                            <enumeratedValues>
                                <enumeratedValue>
                                    <name>0</name>
                                    <description>No effect on output</description>
                                    <value>#0</value>
                                </enumeratedValue>
                                <enumeratedValue>
                                    <name>1</name>
                                    <description>Low output</description>
                                    <value>#1</value>
                                </enumeratedValue>
                            </enumeratedValues>
                        </field>
                        <field>
                            <name>PORR05</name>
                            <description>Pmn Output Reset</description>
                            <lsb>21</lsb>
                            <msb>21</msb>
                            <access>write-only</access>
                            <enumeratedValues>
                                <enumeratedValue>
                                    <name>0</name>
                                    <description>No effect on output</description>
                                    <value>#0</value>
                                </enumeratedValue>
                                <enumeratedValue>
                                    <name>1</name>
                                    <description>Low output</description>
                                    <value>#1</value>
                                </enumeratedValue>
                            </enumeratedValues>
                        </field>
                        <field>
                            <name>PORR06</name>
                            <description>Pmn Output Reset</description>
                            <lsb>22</lsb>
                            <msb>22</msb>
                            <access>write-only</access>
                            <enumeratedValues>
                                <enumeratedValue>
                                    <name>0</name>
                                    <description>No effect on output</description>
                                    <value>#0</value>
                                </enumeratedValue>
                                <enumeratedValue>
                                    <name>1</name>
                                    <description>Low output</description>
                                    <value>#1</value>
                                </enumeratedValue>
                            </enumeratedValues>
                        </field>
                        <field>
                            <name>PORR07</name>
                            <description>Pmn Output Reset</description>
                            <lsb>23</lsb>
                            <msb>23</msb>
                            <access>write-only</access>
                            <enumeratedValues>
                                <enumeratedValue>
                                    <name>0</name>
                                    <description>No effect on output</description>
                                    <value>#0</value>
                                </enumeratedValue>
                                <enumeratedValue>
                                    <name>1</name>
                                    <description>Low output</description>
                                    <value>#1</value>
                                </enumeratedValue>
                            </enumeratedValues>
                        </field>
                        <field>
                            <name>PORR08</name>
                            <description>Pmn Output Reset</description>
                            <lsb>24</lsb>
                            <msb>24</msb>
                            <access>write-only</access>
                            <enumeratedValues>
                                <enumeratedValue>
                                    <name>0</name>
                                    <description>No effect on output</description>
                                    <value>#0</value>
                                </enumeratedValue>
                                <enumeratedValue>
                                    <name>1</name>
                                    <description>Low output</description>
                                    <value>#1</value>
                                </enumeratedValue>
                            </enumeratedValues>
                        </field>
                        <field>
                            <name>PORR09</name>
                            <description>Pmn Output Reset</description>
                            <lsb>25</lsb>
                            <msb>25</msb>
                            <access>write-only</access>
                            <enumeratedValues>
                                <enumeratedValue>
                                    <name>0</name>
                                    <description>No effect on output</description>
                                    <value>#0</value>
                                </enumeratedValue>
                                <enumeratedValue>
                                    <name>1</name>
                                    <description>Low output</description>
                                    <value>#1</value>
                                </enumeratedValue>
                            </enumeratedValues>
                        </field>
                        <field>
                            <name>PORR10</name>
                            <description>Pmn Output Reset</description>
                            <lsb>26</lsb>
                            <msb>26</msb>
                            <access>write-only</access>
                            <enumeratedValues>
                                <enumeratedValue>
                                    <name>0</name>
                                    <description>No effect on output</description>
                                    <value>#0</value>
                                </enumeratedValue>
                                <enumeratedValue>
                                    <name>1</name>
                                    <description>Low output</description>
                                    <value>#1</value>
                                </enumeratedValue>
                            </enumeratedValues>
                        </field>
                        <field>
                            <name>PORR11</name>
                            <description>Pmn Output Reset</description>
                            <lsb>27</lsb>
                            <msb>27</msb>
                            <access>write-only</access>
                            <enumeratedValues>
                                <enumeratedValue>
                                    <name>0</name>
                                    <description>No effect on output</description>
                                    <value>#0</value>
                                </enumeratedValue>
                                <enumeratedValue>
                                    <name>1</name>
                                    <description>Low output</description>
                                    <value>#1</value>
                                </enumeratedValue>
                            </enumeratedValues>
                        </field>
                        <field>
                            <name>PORR12</name>
                            <description>Pmn Output Reset</description>
                            <lsb>28</lsb>
                            <msb>28</msb>
                            <access>write-only</access>
                            <enumeratedValues>
                                <enumeratedValue>
                                    <name>0</name>
                                    <description>No effect on output</description>
                                    <value>#0</value>
                                </enumeratedValue>
                                <enumeratedValue>
                                    <name>1</name>
                                    <description>Low output</description>
                                    <value>#1</value>
                                </enumeratedValue>
                            </enumeratedValues>
                        </field>
                        <field>
                            <name>PORR13</name>
                            <description>Pmn Output Reset</description>
                            <lsb>29</lsb>
                            <msb>29</msb>
                            <access>write-only</access>
                            <enumeratedValues>
                                <enumeratedValue>
                                    <name>0</name>
                                    <description>No effect on output</description>
                                    <value>#0</value>
                                </enumeratedValue>
                                <enumeratedValue>
                                    <name>1</name>
                                    <description>Low output</description>
                                    <value>#1</value>
                                </enumeratedValue>
                            </enumeratedValues>
                        </field>
                        <field>
                            <name>PORR14</name>
                            <description>Pmn Output Reset</description>
                            <lsb>30</lsb>
                            <msb>30</msb>
                            <access>write-only</access>
                            <enumeratedValues>
                                <enumeratedValue>
                                    <name>0</name>
                                    <description>No effect on output</description>
                                    <value>#0</value>
                                </enumeratedValue>
                                <enumeratedValue>
                                    <name>1</name>
                                    <description>Low output</description>
                                    <value>#1</value>
                                </enumeratedValue>
                            </enumeratedValues>
                        </field>
                        <field>
                            <name>PORR15</name>
                            <description>Pmn Output Reset</description>
                            <lsb>31</lsb>
                            <msb>31</msb>
                            <access>write-only</access>
                            <enumeratedValues>
                                <enumeratedValue>
                                    <name>0</name>
                                    <description>No effect on output</description>
                                    <value>#0</value>
                                </enumeratedValue>
                                <enumeratedValue>
                                    <name>1</name>
                                    <description>Low output</description>
                                    <value>#1</value>
                                </enumeratedValue>
                            </enumeratedValues>
                        </field>
                    </fields>
                </register>
                <register>
                    <name>POSR</name>
                    <description>Port Control Register 3</description>
                    <alternateRegister>PCNTR3</alternateRegister>
                    <addressOffset>0x008</addressOffset>
                    <size>16</size>
                    <access>write-only</access>
                    <resetValue>0x0000</resetValue>
                    <resetMask>0xffff</resetMask>
                    <fields>
                        <field>
                            <name>PORR00</name>
                            <description>Pmn Output Reset</description>
                            <lsb>0</lsb>
                            <msb>0</msb>
                            <access>write-only</access>
                            <enumeratedValues>
                                <enumeratedValue>
                                    <name>0</name>
                                    <description>No effect on output</description>
                                    <value>#0</value>
                                </enumeratedValue>
                                <enumeratedValue>
                                    <name>1</name>
                                    <description>Low output</description>
                                    <value>#1</value>
                                </enumeratedValue>
                            </enumeratedValues>
                        </field>
                        <field>
                            <name>PORR01</name>
                            <description>Pmn Output Reset</description>
                            <lsb>1</lsb>
                            <msb>1</msb>
                            <access>write-only</access>
                            <enumeratedValues>
                                <enumeratedValue>
                                    <name>0</name>
                                    <description>No effect on output</description>
                                    <value>#0</value>
                                </enumeratedValue>
                                <enumeratedValue>
                                    <name>1</name>
                                    <description>Low output</description>
                                    <value>#1</value>
                                </enumeratedValue>
                            </enumeratedValues>
                        </field>
                        <field>
                            <name>PORR02</name>
                            <description>Pmn Output Reset</description>
                            <lsb>2</lsb>
                            <msb>2</msb>
                            <access>write-only</access>
                            <enumeratedValues>
                                <enumeratedValue>
                                    <name>0</name>
                                    <description>No effect on output</description>
                                    <value>#0</value>
                                </enumeratedValue>
                                <enumeratedValue>
                                    <name>1</name>
                                    <description>Low output</description>
                                    <value>#1</value>
                                </enumeratedValue>
                            </enumeratedValues>
                        </field>
                        <field>
                            <name>PORR03</name>
                            <description>Pmn Output Reset</description>
                            <lsb>3</lsb>
                            <msb>3</msb>
                            <access>write-only</access>
                            <enumeratedValues>
                                <enumeratedValue>
                                    <name>0</name>
                                    <description>No effect on output</description>
                                    <value>#0</value>
                                </enumeratedValue>
                                <enumeratedValue>
                                    <name>1</name>
                                    <description>Low output</description>
                                    <value>#1</value>
                                </enumeratedValue>
                            </enumeratedValues>
                        </field>
                        <field>
                            <name>PORR04</name>
                            <description>Pmn Output Reset</description>
                            <lsb>4</lsb>
                            <msb>4</msb>
                            <access>write-only</access>
                            <enumeratedValues>
                                <enumeratedValue>
                                    <name>0</name>
                                    <description>No effect on output</description>
                                    <value>#0</value>
                                </enumeratedValue>
                                <enumeratedValue>
                                    <name>1</name>
                                    <description>Low output</description>
                                    <value>#1</value>
                                </enumeratedValue>
                            </enumeratedValues>
                        </field>
                        <field>
                            <name>PORR05</name>
                            <description>Pmn Output Reset</description>
                            <lsb>5</lsb>
                            <msb>5</msb>
                            <access>write-only</access>
                            <enumeratedValues>
                                <enumeratedValue>
                                    <name>0</name>
                                    <description>No effect on output</description>
                                    <value>#0</value>
                                </enumeratedValue>
                                <enumeratedValue>
                                    <name>1</name>
                                    <description>Low output</description>
                                    <value>#1</value>
                                </enumeratedValue>
                            </enumeratedValues>
                        </field>
                        <field>
                            <name>PORR06</name>
                            <description>Pmn Output Reset</description>
                            <lsb>6</lsb>
                            <msb>6</msb>
                            <access>write-only</access>
                            <enumeratedValues>
                                <enumeratedValue>
                                    <name>0</name>
                                    <description>No effect on output</description>
                                    <value>#0</value>
                                </enumeratedValue>
                                <enumeratedValue>
                                    <name>1</name>
                                    <description>Low output</description>
                                    <value>#1</value>
                                </enumeratedValue>
                            </enumeratedValues>
                        </field>
                        <field>
                            <name>PORR07</name>
                            <description>Pmn Output Reset</description>
                            <lsb>7</lsb>
                            <msb>7</msb>
                            <access>write-only</access>
                            <enumeratedValues>
                                <enumeratedValue>
                                    <name>0</name>
                                    <description>No effect on output</description>
                                    <value>#0</value>
                                </enumeratedValue>
                                <enumeratedValue>
                                    <name>1</name>
                                    <description>Low output</description>
                                    <value>#1</value>
                                </enumeratedValue>
                            </enumeratedValues>
                        </field>
                        <field>
                            <name>PORR08</name>
                            <description>Pmn Output Reset</description>
                            <lsb>8</lsb>
                            <msb>8</msb>
                            <access>write-only</access>
                            <enumeratedValues>
                                <enumeratedValue>
                                    <name>0</name>
                                    <description>No effect on output</description>
                                    <value>#0</value>
                                </enumeratedValue>
                                <enumeratedValue>
                                    <name>1</name>
                                    <description>Low output</description>
                                    <value>#1</value>
                                </enumeratedValue>
                            </enumeratedValues>
                        </field>
                        <field>
                            <name>PORR09</name>
                            <description>Pmn Output Reset</description>
                            <lsb>9</lsb>
                            <msb>9</msb>
                            <access>write-only</access>
                            <enumeratedValues>
                                <enumeratedValue>
                                    <name>0</name>
                                    <description>No effect on output</description>
                                    <value>#0</value>
                                </enumeratedValue>
                                <enumeratedValue>
                                    <name>1</name>
                                    <description>Low output</description>
                                    <value>#1</value>
                                </enumeratedValue>
                            </enumeratedValues>
                        </field>
                        <field>
                            <name>PORR10</name>
                            <description>Pmn Output Reset</description>
                            <lsb>10</lsb>
                            <msb>10</msb>
                            <access>write-only</access>
                            <enumeratedValues>
                                <enumeratedValue>
                                    <name>0</name>
                                    <description>No effect on output</description>
                                    <value>#0</value>
                                </enumeratedValue>
                                <enumeratedValue>
                                    <name>1</name>
                                    <description>Low output</description>
                                    <value>#1</value>
                                </enumeratedValue>
                            </enumeratedValues>
                        </field>
                        <field>
                            <name>PORR11</name>
                            <description>Pmn Output Reset</description>
                            <lsb>11</lsb>
                            <msb>11</msb>
                            <access>write-only</access>
                            <enumeratedValues>
                                <enumeratedValue>
                                    <name>0</name>
                                    <description>No effect on output</description>
                                    <value>#0</value>
                                </enumeratedValue>
                                <enumeratedValue>
                                    <name>1</name>
                                    <description>Low output</description>
                                    <value>#1</value>
                                </enumeratedValue>
                            </enumeratedValues>
                        </field>
                        <field>
                            <name>PORR12</name>
                            <description>Pmn Output Reset</description>
                            <lsb>12</lsb>
                            <msb>12</msb>
                            <access>write-only</access>
                            <enumeratedValues>
                                <enumeratedValue>
                                    <name>0</name>
                                    <description>No effect on output</description>
                                    <value>#0</value>
                                </enumeratedValue>
                                <enumeratedValue>
                                    <name>1</name>
                                    <description>Low output</description>
                                    <value>#1</value>
                                </enumeratedValue>
                            </enumeratedValues>
                        </field>
                        <field>
                            <name>PORR13</name>
                            <description>Pmn Output Reset</description>
                            <lsb>13</lsb>
                            <msb>13</msb>
                            <access>write-only</access>
                            <enumeratedValues>
                                <enumeratedValue>
                                    <name>0</name>
                                    <description>No effect on output</description>
                                    <value>#0</value>
                                </enumeratedValue>
                                <enumeratedValue>
                                    <name>1</name>
                                    <description>Low output</description>
                                    <value>#1</value>
                                </enumeratedValue>
                            </enumeratedValues>
                        </field>
                        <field>
                            <name>PORR14</name>
                            <description>Pmn Output Reset</description>
                            <lsb>14</lsb>
                            <msb>14</msb>
                            <access>write-only</access>
                            <enumeratedValues>
                                <enumeratedValue>
                                    <name>0</name>
                                    <description>No effect on output</description>
                                    <value>#0</value>
                                </enumeratedValue>
                                <enumeratedValue>
                                    <name>1</name>
                                    <description>Low output</description>
                                    <value>#1</value>
                                </enumeratedValue>
                            </enumeratedValues>
                        </field>
                        <field>
                            <name>PORR15</name>
                            <description>Pmn Output Reset</description>
                            <lsb>15</lsb>
                            <msb>15</msb>
                            <access>write-only</access>
                            <enumeratedValues>
                                <enumeratedValue>
                                    <name>0</name>
                                    <description>No effect on output</description>
                                    <value>#0</value>
                                </enumeratedValue>
                                <enumeratedValue>
                                    <name>1</name>
                                    <description>Low output</description>
                                    <value>#1</value>
                                </enumeratedValue>
                            </enumeratedValues>
                        </field>
                    </fields>
                </register>
                <register>
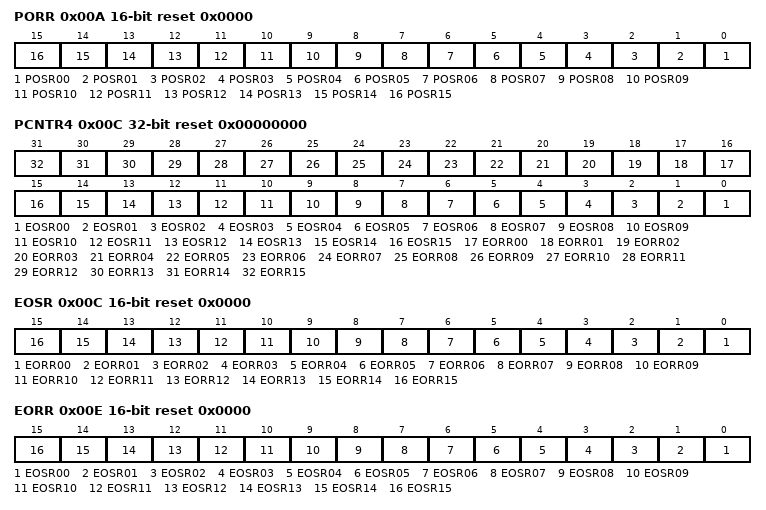
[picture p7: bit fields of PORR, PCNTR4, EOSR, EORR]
                    <name>PORR</name>
                    <description>Port Control Register 3</description>
                    <alternateRegister>PCNTR3</alternateRegister>
                    <addressOffset>0x00A</addressOffset>
                    <size>16</size>
                    <access>write-only</access>
                    <resetValue>0x0000</resetValue>
                    <resetMask>0xffff</resetMask>
                    <fields>
                        <field>
                            <name>POSR00</name>
                            <description>Pmn Output Set</description>
                            <lsb>0</lsb>
                            <msb>0</msb>
                            <access>write-only</access>
                            <enumeratedValues>
                                <enumeratedValue>
                                    <name>0</name>
                                    <description>No effect on output</description>
                                    <value>#0</value>
                                </enumeratedValue>
                                <enumeratedValue>
                                    <name>1</name>
                                    <description>High output</description>
                                    <value>#1</value>
                                </enumeratedValue>
                            </enumeratedValues>
                        </field>
                        <field>
                            <name>POSR01</name>
                            <description>Pmn Output Set</description>
                            <lsb>1</lsb>
                            <msb>1</msb>
                            <access>write-only</access>
                            <enumeratedValues>
                                <enumeratedValue>
                                    <name>0</name>
                                    <description>No effect on output</description>
                                    <value>#0</value>
                                </enumeratedValue>
                                <enumeratedValue>
                                    <name>1</name>
                                    <description>High output</description>
                                    <value>#1</value>
                                </enumeratedValue>
                            </enumeratedValues>
                        </field>
                        <field>
                            <name>POSR02</name>
                            <description>Pmn Output Set</description>
                            <lsb>2</lsb>
                            <msb>2</msb>
                            <access>write-only</access>
                            <enumeratedValues>
                                <enumeratedValue>
                                    <name>0</name>
                                    <description>No effect on output</description>
                                    <value>#0</value>
                                </enumeratedValue>
                                <enumeratedValue>
                                    <name>1</name>
                                    <description>High output</description>
                                    <value>#1</value>
                                </enumeratedValue>
                            </enumeratedValues>
                        </field>
                        <field>
                            <name>POSR03</name>
                            <description>Pmn Output Set</description>
                            <lsb>3</lsb>
                            <msb>3</msb>
                            <access>write-only</access>
                            <enumeratedValues>
                                <enumeratedValue>
                                    <name>0</name>
                                    <description>No effect on output</description>
                                    <value>#0</value>
                                </enumeratedValue>
                                <enumeratedValue>
                                    <name>1</name>
                                    <description>High output</description>
                                    <value>#1</value>
                                </enumeratedValue>
                            </enumeratedValues>
                        </field>
                        <field>
                            <name>POSR04</name>
                            <description>Pmn Output Set</description>
                            <lsb>4</lsb>
                            <msb>4</msb>
                            <access>write-only</access>
                            <enumeratedValues>
                                <enumeratedValue>
                                    <name>0</name>
                                    <description>No effect on output</description>
                                    <value>#0</value>
                                </enumeratedValue>
                                <enumeratedValue>
                                    <name>1</name>
                                    <description>High output</description>
                                    <value>#1</value>
                                </enumeratedValue>
                            </enumeratedValues>
                        </field>
                        <field>
                            <name>POSR05</name>
                            <description>Pmn Output Set</description>
                            <lsb>5</lsb>
                            <msb>5</msb>
                            <access>write-only</access>
                            <enumeratedValues>
                                <enumeratedValue>
                                    <name>0</name>
                                    <description>No effect on output</description>
                                    <value>#0</value>
                                </enumeratedValue>
                                <enumeratedValue>
                                    <name>1</name>
                                    <description>High output</description>
                                    <value>#1</value>
                                </enumeratedValue>
                            </enumeratedValues>
                        </field>
                        <field>
                            <name>POSR06</name>
                            <description>Pmn Output Set</description>
                            <lsb>6</lsb>
                            <msb>6</msb>
                            <access>write-only</access>
                            <enumeratedValues>
                                <enumeratedValue>
                                    <name>0</name>
                                    <description>No effect on output</description>
                                    <value>#0</value>
                                </enumeratedValue>
                                <enumeratedValue>
                                    <name>1</name>
                                    <description>High output</description>
                                    <value>#1</value>
                                </enumeratedValue>
                            </enumeratedValues>
                        </field>
                        <field>
                            <name>POSR07</name>
                            <description>Pmn Output Set</description>
                            <lsb>7</lsb>
                            <msb>7</msb>
                            <access>write-only</access>
                            <enumeratedValues>
                                <enumeratedValue>
                                    <name>0</name>
                                    <description>No effect on output</description>
                                    <value>#0</value>
                                </enumeratedValue>
                                <enumeratedValue>
                                    <name>1</name>
                                    <description>High output</description>
                                    <value>#1</value>
                                </enumeratedValue>
                            </enumeratedValues>
                        </field>
                        <field>
                            <name>POSR08</name>
                            <description>Pmn Output Set</description>
                            <lsb>8</lsb>
                            <msb>8</msb>
                            <access>write-only</access>
                            <enumeratedValues>
                                <enumeratedValue>
                                    <name>0</name>
                                    <description>No effect on output</description>
                                    <value>#0</value>
                                </enumeratedValue>
                                <enumeratedValue>
                                    <name>1</name>
                                    <description>High output</description>
                                    <value>#1</value>
                                </enumeratedValue>
                            </enumeratedValues>
                        </field>
                        <field>
                            <name>POSR09</name>
                            <description>Pmn Output Set</description>
                            <lsb>9</lsb>
                            <msb>9</msb>
                            <access>write-only</access>
                            <enumeratedValues>
                                <enumeratedValue>
                                    <name>0</name>
                                    <description>No effect on output</description>
                                    <value>#0</value>
                                </enumeratedValue>
                                <enumeratedValue>
                                    <name>1</name>
                                    <description>High output</description>
                                    <value>#1</value>
                                </enumeratedValue>
                            </enumeratedValues>
                        </field>
                        <field>
                            <name>POSR10</name>
                            <description>Pmn Output Set</description>
                            <lsb>10</lsb>
                            <msb>10</msb>
                            <access>write-only</access>
                            <enumeratedValues>
                                <enumeratedValue>
                                    <name>0</name>
                                    <description>No effect on output</description>
                                    <value>#0</value>
                                </enumeratedValue>
                                <enumeratedValue>
                                    <name>1</name>
                                    <description>High output</description>
                                    <value>#1</value>
                                </enumeratedValue>
                            </enumeratedValues>
                        </field>
                        <field>
                            <name>POSR11</name>
                            <description>Pmn Output Set</description>
                            <lsb>11</lsb>
                            <msb>11</msb>
                            <access>write-only</access>
                            <enumeratedValues>
                                <enumeratedValue>
                                    <name>0</name>
                                    <description>No effect on output</description>
                                    <value>#0</value>
                                </enumeratedValue>
                                <enumeratedValue>
                                    <name>1</name>
                                    <description>High output</description>
                                    <value>#1</value>
                                </enumeratedValue>
                            </enumeratedValues>
                        </field>
                        <field>
                            <name>POSR12</name>
                            <description>Pmn Output Set</description>
                            <lsb>12</lsb>
                            <msb>12</msb>
                            <access>write-only</access>
                            <enumeratedValues>
                                <enumeratedValue>
                                    <name>0</name>
                                    <description>No effect on output</description>
                                    <value>#0</value>
                                </enumeratedValue>
                                <enumeratedValue>
                                    <name>1</name>
                                    <description>High output</description>
                                    <value>#1</value>
                                </enumeratedValue>
                            </enumeratedValues>
                        </field>
                        <field>
                            <name>POSR13</name>
                            <description>Pmn Output Set</description>
                            <lsb>13</lsb>
                            <msb>13</msb>
                            <access>write-only</access>
                            <enumeratedValues>
                                <enumeratedValue>
                                    <name>0</name>
                                    <description>No effect on output</description>
                                    <value>#0</value>
                                </enumeratedValue>
                                <enumeratedValue>
                                    <name>1</name>
                                    <description>High output</description>
                                    <value>#1</value>
                                </enumeratedValue>
                            </enumeratedValues>
                        </field>
                        <field>
                            <name>POSR14</name>
                            <description>Pmn Output Set</description>
                            <lsb>14</lsb>
                            <msb>14</msb>
                            <access>write-only</access>
                            <enumeratedValues>
                                <enumeratedValue>
                                    <name>0</name>
                                    <description>No effect on output</description>
                                    <value>#0</value>
                                </enumeratedValue>
                                <enumeratedValue>
                                    <name>1</name>
                                    <description>High output</description>
                                    <value>#1</value>
                                </enumeratedValue>
                            </enumeratedValues>
                        </field>
                        <field>
                            <name>POSR15</name>
                            <description>Pmn Output Set</description>
                            <lsb>15</lsb>
                            <msb>15</msb>
                            <access>write-only</access>
                            <enumeratedValues>
                                <enumeratedValue>
                                    <name>0</name>
                                    <description>No effect on output</description>
                                    <value>#0</value>
                                </enumeratedValue>
                                <enumeratedValue>
                                    <name>1</name>
                                    <description>High output</description>
                                    <value>#1</value>
                                </enumeratedValue>
                            </enumeratedValues>
                        </field>
                    </fields>
                </register>
                <register>
                    <name>PCNTR4</name>
                    <description>Port Control Register 4</description>
                    <addressOffset>0x00C</addressOffset>
                    <size>32</size>
                    <access>read-write</access>
                    <resetValue>0x00000000</resetValue>
                    <resetMask>0xffffffff</resetMask>
                    <fields>
                        <field>
                            <name>EOSR00</name>
                            <description>Pmn Event Output Set</description>
                            <lsb>0</lsb>
                            <msb>0</msb>
                            <access>read-write</access>
                            <enumeratedValues>
                                <enumeratedValue>
                                    <name>0</name>
                                    <description>No effect on output</description>
                                    <value>#0</value>
                                </enumeratedValue>
                                <enumeratedValue>
                                    <name>1</name>
                                    <description>High output</description>
                                    <value>#1</value>
                                </enumeratedValue>
                            </enumeratedValues>
                        </field>
                        <field>
                            <name>EOSR01</name>
                            <description>Pmn Event Output Set</description>
                            <lsb>1</lsb>
                            <msb>1</msb>
                            <access>read-write</access>
                            <enumeratedValues>
                                <enumeratedValue>
                                    <name>0</name>
                                    <description>No effect on output</description>
                                    <value>#0</value>
                                </enumeratedValue>
                                <enumeratedValue>
                                    <name>1</name>
                                    <description>High output</description>
                                    <value>#1</value>
                                </enumeratedValue>
                            </enumeratedValues>
                        </field>
                        <field>
                            <name>EOSR02</name>
                            <description>Pmn Event Output Set</description>
                            <lsb>2</lsb>
                            <msb>2</msb>
                            <access>read-write</access>
                            <enumeratedValues>
                                <enumeratedValue>
                                    <name>0</name>
                                    <description>No effect on output</description>
                                    <value>#0</value>
                                </enumeratedValue>
                                <enumeratedValue>
                                    <name>1</name>
                                    <description>High output</description>
                                    <value>#1</value>
                                </enumeratedValue>
                            </enumeratedValues>
                        </field>
                        <field>
                            <name>EOSR03</name>
                            <description>Pmn Event Output Set</description>
                            <lsb>3</lsb>
                            <msb>3</msb>
                            <access>read-write</access>
                            <enumeratedValues>
                                <enumeratedValue>
                                    <name>0</name>
                                    <description>No effect on output</description>
                                    <value>#0</value>
                                </enumeratedValue>
                                <enumeratedValue>
                                    <name>1</name>
                                    <description>High output</description>
                                    <value>#1</value>
                                </enumeratedValue>
                            </enumeratedValues>
                        </field>
                        <field>
                            <name>EOSR04</name>
                            <description>Pmn Event Output Set</description>
                            <lsb>4</lsb>
                            <msb>4</msb>
                            <access>read-write</access>
                            <enumeratedValues>
                                <enumeratedValue>
                                    <name>0</name>
                                    <description>No effect on output</description>
                                    <value>#0</value>
                                </enumeratedValue>
                                <enumeratedValue>
                                    <name>1</name>
                                    <description>High output</description>
                                    <value>#1</value>
                                </enumeratedValue>
                            </enumeratedValues>
                        </field>
                        <field>
                            <name>EOSR05</name>
                            <description>Pmn Event Output Set</description>
                            <lsb>5</lsb>
                            <msb>5</msb>
                            <access>read-write</access>
                            <enumeratedValues>
                                <enumeratedValue>
                                    <name>0</name>
                                    <description>No effect on output</description>
                                    <value>#0</value>
                                </enumeratedValue>
                                <enumeratedValue>
                                    <name>1</name>
                                    <description>High output</description>
                                    <value>#1</value>
                                </enumeratedValue>
                            </enumeratedValues>
                        </field>
                        <field>
                            <name>EOSR06</name>
                            <description>Pmn Event Output Set</description>
                            <lsb>6</lsb>
                            <msb>6</msb>
                            <access>read-write</access>
                            <enumeratedValues>
                                <enumeratedValue>
                                    <name>0</name>
                                    <description>No effect on output</description>
                                    <value>#0</value>
                                </enumeratedValue>
                                <enumeratedValue>
                                    <name>1</name>
                                    <description>High output</description>
                                    <value>#1</value>
                                </enumeratedValue>
                            </enumeratedValues>
                        </field>
                        <field>
                            <name>EOSR07</name>
                            <description>Pmn Event Output Set</description>
                            <lsb>7</lsb>
                            <msb>7</msb>
                            <access>read-write</access>
                            <enumeratedValues>
                                <enumeratedValue>
                                    <name>0</name>
                                    <description>No effect on output</description>
                                    <value>#0</value>
                                </enumeratedValue>
                                <enumeratedValue>
                                    <name>1</name>
                                    <description>High output</description>
                                    <value>#1</value>
                                </enumeratedValue>
                            </enumeratedValues>
                        </field>
                        <field>
                            <name>EOSR08</name>
                            <description>Pmn Event Output Set</description>
                            <lsb>8</lsb>
                            <msb>8</msb>
                            <access>read-write</access>
                            <enumeratedValues>
                                <enumeratedValue>
                                    <name>0</name>
                                    <description>No effect on output</description>
                                    <value>#0</value>
                                </enumeratedValue>
                                <enumeratedValue>
                                    <name>1</name>
                                    <description>High output</description>
                                    <value>#1</value>
                                </enumeratedValue>
                            </enumeratedValues>
                        </field>
                        <field>
                            <name>EOSR09</name>
                            <description>Pmn Event Output Set</description>
                            <lsb>9</lsb>
                            <msb>9</msb>
                            <access>read-write</access>
                            <enumeratedValues>
                                <enumeratedValue>
                                    <name>0</name>
                                    <description>No effect on output</description>
                                    <value>#0</value>
                                </enumeratedValue>
                                <enumeratedValue>
                                    <name>1</name>
                                    <description>High output</description>
                                    <value>#1</value>
                                </enumeratedValue>
                            </enumeratedValues>
                        </field>
                        <field>
                            <name>EOSR10</name>
                            <description>Pmn Event Output Set</description>
                            <lsb>10</lsb>
                            <msb>10</msb>
                            <access>read-write</access>
                            <enumeratedValues>
                                <enumeratedValue>
                                    <name>0</name>
                                    <description>No effect on output</description>
                                    <value>#0</value>
                                </enumeratedValue>
                                <enumeratedValue>
                                    <name>1</name>
                                    <description>High output</description>
                                    <value>#1</value>
                                </enumeratedValue>
                            </enumeratedValues>
                        </field>
                        <field>
                            <name>EOSR11</name>
                            <description>Pmn Event Output Set</description>
                            <lsb>11</lsb>
                            <msb>11</msb>
                            <access>read-write</access>
                            <enumeratedValues>
                                <enumeratedValue>
                                    <name>0</name>
                                    <description>No effect on output</description>
                                    <value>#0</value>
                                </enumeratedValue>
                                <enumeratedValue>
                                    <name>1</name>
                                    <description>High output</description>
                                    <value>#1</value>
                                </enumeratedValue>
                            </enumeratedValues>
                        </field>
                        <field>
                            <name>EOSR12</name>
                            <description>Pmn Event Output Set</description>
                            <lsb>12</lsb>
                            <msb>12</msb>
                            <access>read-write</access>
                            <enumeratedValues>
                                <enumeratedValue>
                                    <name>0</name>
                                    <description>No effect on output</description>
                                    <value>#0</value>
                                </enumeratedValue>
                                <enumeratedValue>
                                    <name>1</name>
                                    <description>High output</description>
                                    <value>#1</value>
                                </enumeratedValue>
                            </enumeratedValues>
                        </field>
                        <field>
                            <name>EOSR13</name>
                            <description>Pmn Event Output Set</description>
                            <lsb>13</lsb>
                            <msb>13</msb>
                            <access>read-write</access>
                            <enumeratedValues>
                                <enumeratedValue>
                                    <name>0</name>
                                    <description>No effect on output</description>
                                    <value>#0</value>
                                </enumeratedValue>
                                <enumeratedValue>
                                    <name>1</name>
                                    <description>High output</description>
                                    <value>#1</value>
                                </enumeratedValue>
                            </enumeratedValues>
                        </field>
                        <field>
                            <name>EOSR14</name>
                            <description>Pmn Event Output Set</description>
                            <lsb>14</lsb>
                            <msb>14</msb>
                            <access>read-write</access>
                            <enumeratedValues>
                                <enumeratedValue>
                                    <name>0</name>
                                    <description>No effect on output</description>
                                    <value>#0</value>
                                </enumeratedValue>
                                <enumeratedValue>
                                    <name>1</name>
                                    <description>High output</description>
                                    <value>#1</value>
                                </enumeratedValue>
                            </enumeratedValues>
                        </field>
                        <field>
                            <name>EOSR15</name>
                            <description>Pmn Event Output Set</description>
                            <lsb>15</lsb>
                            <msb>15</msb>
                            <access>read-write</access>
                            <enumeratedValues>
                                <enumeratedValue>
                                    <name>0</name>
                                    <description>No effect on output</description>
                                    <value>#0</value>
                                </enumeratedValue>
                                <enumeratedValue>
                                    <name>1</name>
                                    <description>High output</description>
                                    <value>#1</value>
                                </enumeratedValue>
                            </enumeratedValues>
                        </field>
                        <field>
                            <name>EORR00</name>
                            <description>Pmn Event Output Reset</description>
                            <lsb>16</lsb>
                            <msb>16</msb>
                            <access>read-write</access>
                            <enumeratedValues>
                                <enumeratedValue>
                                    <name>0</name>
                                    <description>No effect on output</description>
                                    <value>#0</value>
                                </enumeratedValue>
                                <enumeratedValue>
                                    <name>1</name>
                                    <description>Low output</description>
                                    <value>#1</value>
                                </enumeratedValue>
                            </enumeratedValues>
                        </field>
                        <field>
                            <name>EORR01</name>
                            <description>Pmn Event Output Reset</description>
                            <lsb>17</lsb>
                            <msb>17</msb>
                            <access>read-write</access>
                            <enumeratedValues>
                                <enumeratedValue>
                                    <name>0</name>
                                    <description>No effect on output</description>
                                    <value>#0</value>
                                </enumeratedValue>
                                <enumeratedValue>
                                    <name>1</name>
                                    <description>Low output</description>
                                    <value>#1</value>
                                </enumeratedValue>
                            </enumeratedValues>
                        </field>
                        <field>
                            <name>EORR02</name>
                            <description>Pmn Event Output Reset</description>
                            <lsb>18</lsb>
                            <msb>18</msb>
                            <access>read-write</access>
                            <enumeratedValues>
                                <enumeratedValue>
                                    <name>0</name>
                                    <description>No effect on output</description>
                                    <value>#0</value>
                                </enumeratedValue>
                                <enumeratedValue>
                                    <name>1</name>
                                    <description>Low output</description>
                                    <value>#1</value>
                                </enumeratedValue>
                            </enumeratedValues>
                        </field>
                        <field>
                            <name>EORR03</name>
                            <description>Pmn Event Output Reset</description>
                            <lsb>19</lsb>
                            <msb>19</msb>
                            <access>read-write</access>
                            <enumeratedValues>
                                <enumeratedValue>
                                    <name>0</name>
                                    <description>No effect on output</description>
                                    <value>#0</value>
                                </enumeratedValue>
                                <enumeratedValue>
                                    <name>1</name>
                                    <description>Low output</description>
                                    <value>#1</value>
                                </enumeratedValue>
                            </enumeratedValues>
                        </field>
                        <field>
                            <name>EORR04</name>
                            <description>Pmn Event Output Reset</description>
                            <lsb>20</lsb>
                            <msb>20</msb>
                            <access>read-write</access>
                            <enumeratedValues>
                                <enumeratedValue>
                                    <name>0</name>
                                    <description>No effect on output</description>
                                    <value>#0</value>
                                </enumeratedValue>
                                <enumeratedValue>
                                    <name>1</name>
                                    <description>Low output</description>
                                    <value>#1</value>
                                </enumeratedValue>
                            </enumeratedValues>
                        </field>
                        <field>
                            <name>EORR05</name>
                            <description>Pmn Event Output Reset</description>
                            <lsb>21</lsb>
                            <msb>21</msb>
                            <access>read-write</access>
                            <enumeratedValues>
                                <enumeratedValue>
                                    <name>0</name>
                                    <description>No effect on output</description>
                                    <value>#0</value>
                                </enumeratedValue>
                                <enumeratedValue>
                                    <name>1</name>
                                    <description>Low output</description>
                                    <value>#1</value>
                                </enumeratedValue>
                            </enumeratedValues>
                        </field>
                        <field>
                            <name>EORR06</name>
                            <description>Pmn Event Output Reset</description>
                            <lsb>22</lsb>
                            <msb>22</msb>
                            <access>read-write</access>
                            <enumeratedValues>
                                <enumeratedValue>
                                    <name>0</name>
                                    <description>No effect on output</description>
                                    <value>#0</value>
                                </enumeratedValue>
                                <enumeratedValue>
                                    <name>1</name>
                                    <description>Low output</description>
                                    <value>#1</value>
                                </enumeratedValue>
                            </enumeratedValues>
                        </field>
                        <field>
                            <name>EORR07</name>
                            <description>Pmn Event Output Reset</description>
                            <lsb>23</lsb>
                            <msb>23</msb>
                            <access>read-write</access>
                            <enumeratedValues>
                                <enumeratedValue>
                                    <name>0</name>
                                    <description>No effect on output</description>
                                    <value>#0</value>
                                </enumeratedValue>
                                <enumeratedValue>
                                    <name>1</name>
                                    <description>Low output</description>
                                    <value>#1</value>
                                </enumeratedValue>
                            </enumeratedValues>
                        </field>
                        <field>
                            <name>EORR08</name>
                            <description>Pmn Event Output Reset</description>
                            <lsb>24</lsb>
                            <msb>24</msb>
                            <access>read-write</access>
                            <enumeratedValues>
                                <enumeratedValue>
                                    <name>0</name>
                                    <description>No effect on output</description>
                                    <value>#0</value>
                                </enumeratedValue>
                                <enumeratedValue>
                                    <name>1</name>
                                    <description>Low output</description>
                                    <value>#1</value>
                                </enumeratedValue>
                            </enumeratedValues>
                        </field>
                        <field>
                            <name>EORR09</name>
                            <description>Pmn Event Output Reset</description>
                            <lsb>25</lsb>
                            <msb>25</msb>
                            <access>read-write</access>
                            <enumeratedValues>
                                <enumeratedValue>
                                    <name>0</name>
                                    <description>No effect on output</description>
                                    <value>#0</value>
                                </enumeratedValue>
                                <enumeratedValue>
                                    <name>1</name>
                                    <description>Low output</description>
                                    <value>#1</value>
                                </enumeratedValue>
                            </enumeratedValues>
                        </field>
                        <field>
                            <name>EORR10</name>
                            <description>Pmn Event Output Reset</description>
                            <lsb>26</lsb>
                            <msb>26</msb>
                            <access>read-write</access>
                            <enumeratedValues>
                                <enumeratedValue>
                                    <name>0</name>
                                    <description>No effect on output</description>
                                    <value>#0</value>
                                </enumeratedValue>
                                <enumeratedValue>
                                    <name>1</name>
                                    <description>Low output</description>
                                    <value>#1</value>
                                </enumeratedValue>
                            </enumeratedValues>
                        </field>
                        <field>
                            <name>EORR11</name>
                            <description>Pmn Event Output Reset</description>
                            <lsb>27</lsb>
                            <msb>27</msb>
                            <access>read-write</access>
                            <enumeratedValues>
                                <enumeratedValue>
                                    <name>0</name>
                                    <description>No effect on output</description>
                                    <value>#0</value>
                                </enumeratedValue>
                                <enumeratedValue>
                                    <name>1</name>
                                    <description>Low output</description>
                                    <value>#1</value>
                                </enumeratedValue>
                            </enumeratedValues>
                        </field>
                        <field>
                            <name>EORR12</name>
                            <description>Pmn Event Output Reset</description>
                            <lsb>28</lsb>
                            <msb>28</msb>
                            <access>read-write</access>
                            <enumeratedValues>
                                <enumeratedValue>
                                    <name>0</name>
                                    <description>No effect on output</description>
                                    <value>#0</value>
                                </enumeratedValue>
                                <enumeratedValue>
                                    <name>1</name>
                                    <description>Low output</description>
                                    <value>#1</value>
                                </enumeratedValue>
                            </enumeratedValues>
                        </field>
                        <field>
                            <name>EORR13</name>
                            <description>Pmn Event Output Reset</description>
                            <lsb>29</lsb>
                            <msb>29</msb>
                            <access>read-write</access>
                            <enumeratedValues>
                                <enumeratedValue>
                                    <name>0</name>
                                    <description>No effect on output</description>
                                    <value>#0</value>
                                </enumeratedValue>
                                <enumeratedValue>
                                    <name>1</name>
                                    <description>Low output</description>
                                    <value>#1</value>
                                </enumeratedValue>
                            </enumeratedValues>
                        </field>
                        <field>
                            <name>EORR14</name>
                            <description>Pmn Event Output Reset</description>
                            <lsb>30</lsb>
                            <msb>30</msb>
                            <access>read-write</access>
                            <enumeratedValues>
                                <enumeratedValue>
                                    <name>0</name>
                                    <description>No effect on output</description>
                                    <value>#0</value>
                                </enumeratedValue>
                                <enumeratedValue>
                                    <name>1</name>
                                    <description>Low output</description>
                                    <value>#1</value>
                                </enumeratedValue>
                            </enumeratedValues>
                        </field>
                        <field>
                            <name>EORR15</name>
                            <description>Pmn Event Output Reset</description>
                            <lsb>31</lsb>
                            <msb>31</msb>
                            <access>read-write</access>
                            <enumeratedValues>
                                <enumeratedValue>
                                    <name>0</name>
                                    <description>No effect on output</description>
                                    <value>#0</value>
                                </enumeratedValue>
                                <enumeratedValue>
                                    <name>1</name>
                                    <description>Low output</description>
                                    <value>#1</value>
                                </enumeratedValue>
                            </enumeratedValues>
                        </field>
                    </fields>
                </register>
                <register>
                    <name>EOSR</name>
                    <description>Port Control Register 4</description>
                    <alternateRegister>PCNTR4</alternateRegister>
                    <addressOffset>0x00C</addressOffset>
                    <size>16</size>
                    <access>read-write</access>
                    <resetValue>0x0000</resetValue>
                    <resetMask>0xffff</resetMask>
                    <fields>
                        <field>
                            <name>EORR00</name>
                            <description>Pmn Event Output Reset</description>
                            <lsb>0</lsb>
                            <msb>0</msb>
                            <access>read-write</access>
                            <enumeratedValues>
                                <enumeratedValue>
                                    <name>0</name>
                                    <description>No effect on output</description>
                                    <value>#0</value>
                                </enumeratedValue>
                                <enumeratedValue>
                                    <name>1</name>
                                    <description>Low output</description>
                                    <value>#1</value>
                                </enumeratedValue>
                            </enumeratedValues>
                        </field>
                        <field>
                            <name>EORR01</name>
                            <description>Pmn Event Output Reset</description>
                            <lsb>1</lsb>
                            <msb>1</msb>
                            <access>read-write</access>
                            <enumeratedValues>
                                <enumeratedValue>
                                    <name>0</name>
                                    <description>No effect on output</description>
                                    <value>#0</value>
                                </enumeratedValue>
                                <enumeratedValue>
                                    <name>1</name>
                                    <description>Low output</description>
                                    <value>#1</value>
                                </enumeratedValue>
                            </enumeratedValues>
                        </field>
                        <field>
                            <name>EORR02</name>
                            <description>Pmn Event Output Reset</description>
                            <lsb>2</lsb>
                            <msb>2</msb>
                            <access>read-write</access>
                            <enumeratedValues>
                                <enumeratedValue>
                                    <name>0</name>
                                    <description>No effect on output</description>
                                    <value>#0</value>
                                </enumeratedValue>
                                <enumeratedValue>
                                    <name>1</name>
                                    <description>Low output</description>
                                    <value>#1</value>
                                </enumeratedValue>
                            </enumeratedValues>
                        </field>
                        <field>
                            <name>EORR03</name>
                            <description>Pmn Event Output Reset</description>
                            <lsb>3</lsb>
                            <msb>3</msb>
                            <access>read-write</access>
                            <enumeratedValues>
                                <enumeratedValue>
                                    <name>0</name>
                                    <description>No effect on output</description>
                                    <value>#0</value>
                                </enumeratedValue>
                                <enumeratedValue>
                                    <name>1</name>
                                    <description>Low output</description>
                                    <value>#1</value>
                                </enumeratedValue>
                            </enumeratedValues>
                        </field>
                        <field>
                            <name>EORR04</name>
                            <description>Pmn Event Output Reset</description>
                            <lsb>4</lsb>
                            <msb>4</msb>
                            <access>read-write</access>
                            <enumeratedValues>
                                <enumeratedValue>
                                    <name>0</name>
                                    <description>No effect on output</description>
                                    <value>#0</value>
                                </enumeratedValue>
                                <enumeratedValue>
                                    <name>1</name>
                                    <description>Low output</description>
                                    <value>#1</value>
                                </enumeratedValue>
                            </enumeratedValues>
                        </field>
                        <field>
                            <name>EORR05</name>
                            <description>Pmn Event Output Reset</description>
                            <lsb>5</lsb>
                            <msb>5</msb>
                            <access>read-write</access>
                            <enumeratedValues>
                                <enumeratedValue>
                                    <name>0</name>
                                    <description>No effect on output</description>
                                    <value>#0</value>
                                </enumeratedValue>
                                <enumeratedValue>
                                    <name>1</name>
                                    <description>Low output</description>
                                    <value>#1</value>
                                </enumeratedValue>
                            </enumeratedValues>
                        </field>
                        <field>
                            <name>EORR06</name>
                            <description>Pmn Event Output Reset</description>
                            <lsb>6</lsb>
                            <msb>6</msb>
                            <access>read-write</access>
                            <enumeratedValues>
                                <enumeratedValue>
                                    <name>0</name>
                                    <description>No effect on output</description>
                                    <value>#0</value>
                                </enumeratedValue>
                                <enumeratedValue>
                                    <name>1</name>
                                    <description>Low output</description>
                                    <value>#1</value>
                                </enumeratedValue>
                            </enumeratedValues>
                        </field>
                        <field>
                            <name>EORR07</name>
                            <description>Pmn Event Output Reset</description>
                            <lsb>7</lsb>
                            <msb>7</msb>
                            <access>read-write</access>
                            <enumeratedValues>
                                <enumeratedValue>
                                    <name>0</name>
                                    <description>No effect on output</description>
                                    <value>#0</value>
                                </enumeratedValue>
                                <enumeratedValue>
                                    <name>1</name>
                                    <description>Low output</description>
                                    <value>#1</value>
                                </enumeratedValue>
                            </enumeratedValues>
                        </field>
                        <field>
                            <name>EORR08</name>
                            <description>Pmn Event Output Reset</description>
                            <lsb>8</lsb>
                            <msb>8</msb>
                            <access>read-write</access>
                            <enumeratedValues>
                                <enumeratedValue>
                                    <name>0</name>
                                    <description>No effect on output</description>
                                    <value>#0</value>
                                </enumeratedValue>
                                <enumeratedValue>
                                    <name>1</name>
                                    <description>Low output</description>
                                    <value>#1</value>
                                </enumeratedValue>
                            </enumeratedValues>
                        </field>
                        <field>
                            <name>EORR09</name>
                            <description>Pmn Event Output Reset</description>
                            <lsb>9</lsb>
                            <msb>9</msb>
                            <access>read-write</access>
                            <enumeratedValues>
                                <enumeratedValue>
                                    <name>0</name>
                                    <description>No effect on output</description>
                                    <value>#0</value>
                                </enumeratedValue>
                                <enumeratedValue>
                                    <name>1</name>
                                    <description>Low output</description>
                                    <value>#1</value>
                                </enumeratedValue>
                            </enumeratedValues>
                        </field>
                        <field>
                            <name>EORR10</name>
                            <description>Pmn Event Output Reset</description>
                            <lsb>10</lsb>
                            <msb>10</msb>
                            <access>read-write</access>
                            <enumeratedValues>
                                <enumeratedValue>
                                    <name>0</name>
                                    <description>No effect on output</description>
                                    <value>#0</value>
                                </enumeratedValue>
                                <enumeratedValue>
                                    <name>1</name>
                                    <description>Low output</description>
                                    <value>#1</value>
                                </enumeratedValue>
                            </enumeratedValues>
                        </field>
                        <field>
                            <name>EORR11</name>
                            <description>Pmn Event Output Reset</description>
                            <lsb>11</lsb>
                            <msb>11</msb>
                            <access>read-write</access>
                            <enumeratedValues>
                                <enumeratedValue>
                                    <name>0</name>
                                    <description>No effect on output</description>
                                    <value>#0</value>
                                </enumeratedValue>
                                <enumeratedValue>
                                    <name>1</name>
                                    <description>Low output</description>
                                    <value>#1</value>
                                </enumeratedValue>
                            </enumeratedValues>
                        </field>
                        <field>
                            <name>EORR12</name>
                            <description>Pmn Event Output Reset</description>
                            <lsb>12</lsb>
                            <msb>12</msb>
                            <access>read-write</access>
                            <enumeratedValues>
                                <enumeratedValue>
                                    <name>0</name>
                                    <description>No effect on output</description>
                                    <value>#0</value>
                                </enumeratedValue>
                                <enumeratedValue>
                                    <name>1</name>
                                    <description>Low output</description>
                                    <value>#1</value>
                                </enumeratedValue>
                            </enumeratedValues>
                        </field>
                        <field>
                            <name>EORR13</name>
                            <description>Pmn Event Output Reset</description>
                            <lsb>13</lsb>
                            <msb>13</msb>
                            <access>read-write</access>
                            <enumeratedValues>
                                <enumeratedValue>
                                    <name>0</name>
                                    <description>No effect on output</description>
                                    <value>#0</value>
                                </enumeratedValue>
                                <enumeratedValue>
                                    <name>1</name>
                                    <description>Low output</description>
                                    <value>#1</value>
                                </enumeratedValue>
                            </enumeratedValues>
                        </field>
                        <field>
                            <name>EORR14</name>
                            <description>Pmn Event Output Reset</description>
                            <lsb>14</lsb>
                            <msb>14</msb>
                            <access>read-write</access>
                            <enumeratedValues>
                                <enumeratedValue>
                                    <name>0</name>
                                    <description>No effect on output</description>
                                    <value>#0</value>
                                </enumeratedValue>
                                <enumeratedValue>
                                    <name>1</name>
                                    <description>Low output</description>
                                    <value>#1</value>
                                </enumeratedValue>
                            </enumeratedValues>
                        </field>
                        <field>
                            <name>EORR15</name>
                            <description>Pmn Event Output Reset</description>
                            <lsb>15</lsb>
                            <msb>15</msb>
                            <access>read-write</access>
                            <enumeratedValues>
                                <enumeratedValue>
                                    <name>0</name>
                                    <description>No effect on output</description>
                                    <value>#0</value>
                                </enumeratedValue>
                                <enumeratedValue>
                                    <name>1</name>
                                    <description>Low output</description>
                                    <value>#1</value>
                                </enumeratedValue>
                            </enumeratedValues>
                        </field>
                    </fields>
                </register>
                <register>
                    <name>EORR</name>
                    <description>Port Control Register 4</description>
                    <alternateRegister>PCNTR4</alternateRegister>
                    <addressOffset>0x00E</addressOffset>
                    <size>16</size>
                    <access>read-write</access>
                    <resetValue>0x0000</resetValue>
                    <resetMask>0xffff</resetMask>
                    <fields>
                        <field>
                            <name>EOSR00</name>
                            <description>Pmn Event Output Set</description>
                            <lsb>0</lsb>
                            <msb>0</msb>
                            <access>read-write</access>
                            <enumeratedValues>
                                <enumeratedValue>
                                    <name>0</name>
                                    <description>No effect on output</description>
                                    <value>#0</value>
                                </enumeratedValue>
                                <enumeratedValue>
                                    <name>1</name>
                                    <description>High output</description>
                                    <value>#1</value>
                                </enumeratedValue>
                            </enumeratedValues>
                        </field>
                        <field>
                            <name>EOSR01</name>
                            <description>Pmn Event Output Set</description>
                            <lsb>1</lsb>
                            <msb>1</msb>
                            <access>read-write</access>
                            <enumeratedValues>
                                <enumeratedValue>
                                    <name>0</name>
                                    <description>No effect on output</description>
                                    <value>#0</value>
                                </enumeratedValue>
                                <enumeratedValue>
                                    <name>1</name>
                                    <description>High output</description>
                                    <value>#1</value>
                                </enumeratedValue>
                            </enumeratedValues>
                        </field>
                        <field>
                            <name>EOSR02</name>
                            <description>Pmn Event Output Set</description>
                            <lsb>2</lsb>
                            <msb>2</msb>
                            <access>read-write</access>
                            <enumeratedValues>
                                <enumeratedValue>
                                    <name>0</name>
                                    <description>No effect on output</description>
                                    <value>#0</value>
                                </enumeratedValue>
                                <enumeratedValue>
                                    <name>1</name>
                                    <description>High output</description>
                                    <value>#1</value>
                                </enumeratedValue>
                            </enumeratedValues>
                        </field>
                        <field>
                            <name>EOSR03</name>
                            <description>Pmn Event Output Set</description>
                            <lsb>3</lsb>
                            <msb>3</msb>
                            <access>read-write</access>
                            <enumeratedValues>
                                <enumeratedValue>
                                    <name>0</name>
                                    <description>No effect on output</description>
                                    <value>#0</value>
                                </enumeratedValue>
                                <enumeratedValue>
                                    <name>1</name>
                                    <description>High output</description>
                                    <value>#1</value>
                                </enumeratedValue>
                            </enumeratedValues>
                        </field>
                        <field>
                            <name>EOSR04</name>
                            <description>Pmn Event Output Set</description>
                            <lsb>4</lsb>
                            <msb>4</msb>
                            <access>read-write</access>
                            <enumeratedValues>
                                <enumeratedValue>
                                    <name>0</name>
                                    <description>No effect on output</description>
                                    <value>#0</value>
                                </enumeratedValue>
                                <enumeratedValue>
                                    <name>1</name>
                                    <description>High output</description>
                                    <value>#1</value>
                                </enumeratedValue>
                            </enumeratedValues>
                        </field>
                        <field>
                            <name>EOSR05</name>
                            <description>Pmn Event Output Set</description>
                            <lsb>5</lsb>
                            <msb>5</msb>
                            <access>read-write</access>
                            <enumeratedValues>
                                <enumeratedValue>
                                    <name>0</name>
                                    <description>No effect on output</description>
                                    <value>#0</value>
                                </enumeratedValue>
                                <enumeratedValue>
                                    <name>1</name>
                                    <description>High output</description>
                                    <value>#1</value>
                                </enumeratedValue>
                            </enumeratedValues>
                        </field>
                        <field>
                            <name>EOSR06</name>
                            <description>Pmn Event Output Set</description>
                            <lsb>6</lsb>
                            <msb>6</msb>
                            <access>read-write</access>
                            <enumeratedValues>
                                <enumeratedValue>
                                    <name>0</name>
                                    <description>No effect on output</description>
                                    <value>#0</value>
                                </enumeratedValue>
                                <enumeratedValue>
                                    <name>1</name>
                                    <description>High output</description>
                                    <value>#1</value>
                                </enumeratedValue>
                            </enumeratedValues>
                        </field>
                        <field>
                            <name>EOSR07</name>
                            <description>Pmn Event Output Set</description>
                            <lsb>7</lsb>
                            <msb>7</msb>
                            <access>read-write</access>
                            <enumeratedValues>
                                <enumeratedValue>
                                    <name>0</name>
                                    <description>No effect on output</description>
                                    <value>#0</value>
                                </enumeratedValue>
                                <enumeratedValue>
                                    <name>1</name>
                                    <description>High output</description>
                                    <value>#1</value>
                                </enumeratedValue>
                            </enumeratedValues>
                        </field>
                        <field>
                            <name>EOSR08</name>
                            <description>Pmn Event Output Set</description>
                            <lsb>8</lsb>
                            <msb>8</msb>
                            <access>read-write</access>
                            <enumeratedValues>
                                <enumeratedValue>
                                    <name>0</name>
                                    <description>No effect on output</description>
                                    <value>#0</value>
                                </enumeratedValue>
                                <enumeratedValue>
                                    <name>1</name>
                                    <description>High output</description>
                                    <value>#1</value>
                                </enumeratedValue>
                            </enumeratedValues>
                        </field>
                        <field>
                            <name>EOSR09</name>
                            <description>Pmn Event Output Set</description>
                            <lsb>9</lsb>
                            <msb>9</msb>
                            <access>read-write</access>
                            <enumeratedValues>
                                <enumeratedValue>
                                    <name>0</name>
                                    <description>No effect on output</description>
                                    <value>#0</value>
                                </enumeratedValue>
                                <enumeratedValue>
                                    <name>1</name>
                                    <description>High output</description>
                                    <value>#1</value>
                                </enumeratedValue>
                            </enumeratedValues>
                        </field>
                        <field>
                            <name>EOSR10</name>
                            <description>Pmn Event Output Set</description>
                            <lsb>10</lsb>
                            <msb>10</msb>
                            <access>read-write</access>
                            <enumeratedValues>
                                <enumeratedValue>
                                    <name>0</name>
                                    <description>No effect on output</description>
                                    <value>#0</value>
                                </enumeratedValue>
                                <enumeratedValue>
                                    <name>1</name>
                                    <description>High output</description>
                                    <value>#1</value>
                                </enumeratedValue>
                            </enumeratedValues>
                        </field>
                        <field>
                            <name>EOSR11</name>
                            <description>Pmn Event Output Set</description>
                            <lsb>11</lsb>
                            <msb>11</msb>
                            <access>read-write</access>
                            <enumeratedValues>
                                <enumeratedValue>
                                    <name>0</name>
                                    <description>No effect on output</description>
                                    <value>#0</value>
                                </enumeratedValue>
                                <enumeratedValue>
                                    <name>1</name>
                                    <description>High output</description>
                                    <value>#1</value>
                                </enumeratedValue>
                            </enumeratedValues>
                        </field>
                        <field>
                            <name>EOSR12</name>
                            <description>Pmn Event Output Set</description>
                            <lsb>12</lsb>
                            <msb>12</msb>
                            <access>read-write</access>
                            <enumeratedValues>
                                <enumeratedValue>
                                    <name>0</name>
                                    <description>No effect on output</description>
                                    <value>#0</value>
                                </enumeratedValue>
                                <enumeratedValue>
                                    <name>1</name>
                                    <description>High output</description>
                                    <value>#1</value>
                                </enumeratedValue>
                            </enumeratedValues>
                        </field>
                        <field>
                            <name>EOSR13</name>
                            <description>Pmn Event Output Set</description>
                            <lsb>13</lsb>
                            <msb>13</msb>
                            <access>read-write</access>
                            <enumeratedValues>
                                <enumeratedValue>
                                    <name>0</name>
                                    <description>No effect on output</description>
                                    <value>#0</value>
                                </enumeratedValue>
                                <enumeratedValue>
                                    <name>1</name>
                                    <description>High output</description>
                                    <value>#1</value>
                                </enumeratedValue>
                            </enumeratedValues>
                        </field>
                        <field>
                            <name>EOSR14</name>
                            <description>Pmn Event Output Set</description>
                            <lsb>14</lsb>
                            <msb>14</msb>
                            <access>read-write</access>
                            <enumeratedValues>
                                <enumeratedValue>
                                    <name>0</name>
                                    <description>No effect on output</description>
                                    <value>#0</value>
                                </enumeratedValue>
                                <enumeratedValue>
                                    <name>1</name>
                                    <description>High output</description>
                                    <value>#1</value>
                                </enumeratedValue>
                            </enumeratedValues>
                        </field>
                        <field>
                            <name>EOSR15</name>
                            <description>Pmn Event Output Set</description>
                            <lsb>15</lsb>
                            <msb>15</msb>
                            <access>read-write</access>
                            <enumeratedValues>
                                <enumeratedValue>
                                    <name>0</name>
                                    <description>No effect on output</description>
                                    <value>#0</value>
                                </enumeratedValue>
                                <enumeratedValue>
                                    <name>1</name>
                                    <description>High output</description>
                                    <value>#1</value>
                                </enumeratedValue>
                            </enumeratedValues>
                        </field>
                    </fields>
                </register>
            </registers>
        </peripheral>
        <peripheral derivedFrom="PORT1_NS">
            <name>PORT2_NS</name>
            <description>Pmn Pin FunctionPort 2 Control RegistersPmn Pin Function Control Register</description>
            <baseAddress>0x50400040</baseAddress>
        </peripheral>
        <peripheral derivedFrom="PORT1_NS">
            <name>PORT3_NS</name>
            <description>Pmn Pin FunctionPort 3 Control RegistersPmn Pin Function Control Register</description>
            <baseAddress>0x50400060</baseAddress>
        </peripheral>
        <peripheral derivedFrom="PORT1_NS">
            <name>PORT4_NS</name>
            <description>Pmn Pin FunctionPort 4 Control RegistersPmn Pin Function Control Register</description>
            <baseAddress>0x50400080</baseAddress>
        </peripheral>
        <peripheral derivedFrom="PORT0_NS">
            <name>PORT5_NS</name>
            <description>Pmn Pin FunctionPort 5 Control RegistersPmn Pin Function Control Register</description>
            <baseAddress>0x504000A0</baseAddress>
        </peripheral>
        <peripheral derivedFrom="PORT0_NS">
            <name>PORT6_NS</name>
            <description>Pmn Pin FunctionPort 6 Control RegistersPmn Pin Function Control Register</description>
            <baseAddress>0x504000C0</baseAddress>
        </peripheral>
        <peripheral derivedFrom="PORT0_NS">
            <name>PORT7_NS</name>
            <description>Pmn Pin FunctionPort 7 Control RegistersPmn Pin Function Control Register</description>
            <baseAddress>0x504000E0</baseAddress>
        </peripheral>
        <peripheral derivedFrom="PORT0_NS">
            <name>PORT8_NS</name>
            <description>Pmn Pin FunctionPort 8 Control RegistersPmn Pin Function Control Register</description>
            <baseAddress>0x50400100</baseAddress>
        </peripheral>
        <peripheral derivedFrom="PORT0_NS">
            <name>PORT9_NS</name>
            <description>Pmn Pin FunctionPort 9 Control RegistersPmn Pin Function Control Register</description>
            <baseAddress>0x50400120</baseAddress>
        </peripheral>
        <peripheral>
            <name>PORTA_NS</name>
            <description>Pmn Pin FunctionPort A Control RegistersPmn Pin Function Control Register</description>
            <baseAddress>0x50400140</baseAddress>
            <addressBlock>
                <offset>0x00</offset>
                <size>8</size>
                <usage>registers</usage>
            </addressBlock>
            <addressBlock>
                <offset>0x08</offset>
                <size>4</size>
                <usage>registers</usage>
            </addressBlock>
            <registers>
                <register>
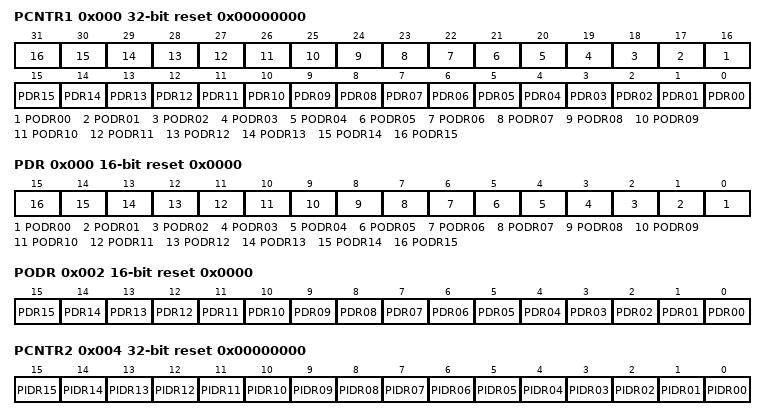
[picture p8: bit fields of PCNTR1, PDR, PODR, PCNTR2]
                    <name>PCNTR1</name>
                    <description>Port Control Register 1</description>
                    <addressOffset>0x000</addressOffset>
                    <size>32</size>
                    <access>read-write</access>
                    <resetValue>0x00000000</resetValue>
                    <resetMask>0xffffffff</resetMask>
                    <fields>
                        <field>
                            <name>PDR00</name>
                            <description>Pmn Direction</description>
                            <lsb>0</lsb>
                            <msb>0</msb>
                            <access>read-write</access>
                            <enumeratedValues>
                                <enumeratedValue>
                                    <name>0</name>
                                    <description>Input (functions as an input pin)</description>
                                    <value>#0</value>
                                </enumeratedValue>
                                <enumeratedValue>
                                    <name>1</name>
                                    <description>Output (functions as an output pin)</description>
                                    <value>#1</value>
                                </enumeratedValue>
                            </enumeratedValues>
                        </field>
                        <field>
                            <name>PDR01</name>
                            <description>Pmn Direction</description>
                            <lsb>1</lsb>
                            <msb>1</msb>
                            <access>read-write</access>
                            <enumeratedValues>
                                <enumeratedValue>
                                    <name>0</name>
                                    <description>Input (functions as an input pin)</description>
                                    <value>#0</value>
                                </enumeratedValue>
                                <enumeratedValue>
                                    <name>1</name>
                                    <description>Output (functions as an output pin)</description>
                                    <value>#1</value>
                                </enumeratedValue>
                            </enumeratedValues>
                        </field>
                        <field>
                            <name>PDR02</name>
                            <description>Pmn Direction</description>
                            <lsb>2</lsb>
                            <msb>2</msb>
                            <access>read-write</access>
                            <enumeratedValues>
                                <enumeratedValue>
                                    <name>0</name>
                                    <description>Input (functions as an input pin)</description>
                                    <value>#0</value>
                                </enumeratedValue>
                                <enumeratedValue>
                                    <name>1</name>
                                    <description>Output (functions as an output pin)</description>
                                    <value>#1</value>
                                </enumeratedValue>
                            </enumeratedValues>
                        </field>
                        <field>
                            <name>PDR03</name>
                            <description>Pmn Direction</description>
                            <lsb>3</lsb>
                            <msb>3</msb>
                            <access>read-write</access>
                            <enumeratedValues>
                                <enumeratedValue>
                                    <name>0</name>
                                    <description>Input (functions as an input pin)</description>
                                    <value>#0</value>
                                </enumeratedValue>
                                <enumeratedValue>
                                    <name>1</name>
                                    <description>Output (functions as an output pin)</description>
                                    <value>#1</value>
                                </enumeratedValue>
                            </enumeratedValues>
                        </field>
                        <field>
                            <name>PDR04</name>
                            <description>Pmn Direction</description>
                            <lsb>4</lsb>
                            <msb>4</msb>
                            <access>read-write</access>
                            <enumeratedValues>
                                <enumeratedValue>
                                    <name>0</name>
                                    <description>Input (functions as an input pin)</description>
                                    <value>#0</value>
                                </enumeratedValue>
                                <enumeratedValue>
                                    <name>1</name>
                                    <description>Output (functions as an output pin)</description>
                                    <value>#1</value>
                                </enumeratedValue>
                            </enumeratedValues>
                        </field>
                        <field>
                            <name>PDR05</name>
                            <description>Pmn Direction</description>
                            <lsb>5</lsb>
                            <msb>5</msb>
                            <access>read-write</access>
                            <enumeratedValues>
                                <enumeratedValue>
                                    <name>0</name>
                                    <description>Input (functions as an input pin)</description>
                                    <value>#0</value>
                                </enumeratedValue>
                                <enumeratedValue>
                                    <name>1</name>
                                    <description>Output (functions as an output pin)</description>
                                    <value>#1</value>
                                </enumeratedValue>
                            </enumeratedValues>
                        </field>
                        <field>
                            <name>PDR06</name>
                            <description>Pmn Direction</description>
                            <lsb>6</lsb>
                            <msb>6</msb>
                            <access>read-write</access>
                            <enumeratedValues>
                                <enumeratedValue>
                                    <name>0</name>
                                    <description>Input (functions as an input pin)</description>
                                    <value>#0</value>
                                </enumeratedValue>
                                <enumeratedValue>
                                    <name>1</name>
                                    <description>Output (functions as an output pin)</description>
                                    <value>#1</value>
                                </enumeratedValue>
                            </enumeratedValues>
                        </field>
                        <field>
                            <name>PDR07</name>
                            <description>Pmn Direction</description>
                            <lsb>7</lsb>
                            <msb>7</msb>
                            <access>read-write</access>
                            <enumeratedValues>
                                <enumeratedValue>
                                    <name>0</name>
                                    <description>Input (functions as an input pin)</description>
                                    <value>#0</value>
                                </enumeratedValue>
                                <enumeratedValue>
                                    <name>1</name>
                                    <description>Output (functions as an output pin)</description>
                                    <value>#1</value>
                                </enumeratedValue>
                            </enumeratedValues>
                        </field>
                        <field>
                            <name>PDR08</name>
                            <description>Pmn Direction</description>
                            <lsb>8</lsb>
                            <msb>8</msb>
                            <access>read-write</access>
                            <enumeratedValues>
                                <enumeratedValue>
                                    <name>0</name>
                                    <description>Input (functions as an input pin)</description>
                                    <value>#0</value>
                                </enumeratedValue>
                                <enumeratedValue>
                                    <name>1</name>
                                    <description>Output (functions as an output pin)</description>
                                    <value>#1</value>
                                </enumeratedValue>
                            </enumeratedValues>
                        </field>
                        <field>
                            <name>PDR09</name>
                            <description>Pmn Direction</description>
                            <lsb>9</lsb>
                            <msb>9</msb>
                            <access>read-write</access>
                            <enumeratedValues>
                                <enumeratedValue>
                                    <name>0</name>
                                    <description>Input (functions as an input pin)</description>
                                    <value>#0</value>
                                </enumeratedValue>
                                <enumeratedValue>
                                    <name>1</name>
                                    <description>Output (functions as an output pin)</description>
                                    <value>#1</value>
                                </enumeratedValue>
                            </enumeratedValues>
                        </field>
                        <field>
                            <name>PDR10</name>
                            <description>Pmn Direction</description>
                            <lsb>10</lsb>
                            <msb>10</msb>
                            <access>read-write</access>
                            <enumeratedValues>
                                <enumeratedValue>
                                    <name>0</name>
                                    <description>Input (functions as an input pin)</description>
                                    <value>#0</value>
                                </enumeratedValue>
                                <enumeratedValue>
                                    <name>1</name>
                                    <description>Output (functions as an output pin)</description>
                                    <value>#1</value>
                                </enumeratedValue>
                            </enumeratedValues>
                        </field>
                        <field>
                            <name>PDR11</name>
                            <description>Pmn Direction</description>
                            <lsb>11</lsb>
                            <msb>11</msb>
                            <access>read-write</access>
                            <enumeratedValues>
                                <enumeratedValue>
                                    <name>0</name>
                                    <description>Input (functions as an input pin)</description>
                                    <value>#0</value>
                                </enumeratedValue>
                                <enumeratedValue>
                                    <name>1</name>
                                    <description>Output (functions as an output pin)</description>
                                    <value>#1</value>
                                </enumeratedValue>
                            </enumeratedValues>
                        </field>
                        <field>
                            <name>PDR12</name>
                            <description>Pmn Direction</description>
                            <lsb>12</lsb>
                            <msb>12</msb>
                            <access>read-write</access>
                            <enumeratedValues>
                                <enumeratedValue>
                                    <name>0</name>
                                    <description>Input (functions as an input pin)</description>
                                    <value>#0</value>
                                </enumeratedValue>
                                <enumeratedValue>
                                    <name>1</name>
                                    <description>Output (functions as an output pin)</description>
                                    <value>#1</value>
                                </enumeratedValue>
                            </enumeratedValues>
                        </field>
                        <field>
                            <name>PDR13</name>
                            <description>Pmn Direction</description>
                            <lsb>13</lsb>
                            <msb>13</msb>
                            <access>read-write</access>
                            <enumeratedValues>
                                <enumeratedValue>
                                    <name>0</name>
                                    <description>Input (functions as an input pin)</description>
                                    <value>#0</value>
                                </enumeratedValue>
                                <enumeratedValue>
                                    <name>1</name>
                                    <description>Output (functions as an output pin)</description>
                                    <value>#1</value>
                                </enumeratedValue>
                            </enumeratedValues>
                        </field>
                        <field>
                            <name>PDR14</name>
                            <description>Pmn Direction</description>
                            <lsb>14</lsb>
                            <msb>14</msb>
                            <access>read-write</access>
                            <enumeratedValues>
                                <enumeratedValue>
                                    <name>0</name>
                                    <description>Input (functions as an input pin)</description>
                                    <value>#0</value>
                                </enumeratedValue>
                                <enumeratedValue>
                                    <name>1</name>
                                    <description>Output (functions as an output pin)</description>
                                    <value>#1</value>
                                </enumeratedValue>
                            </enumeratedValues>
                        </field>
                        <field>
                            <name>PDR15</name>
                            <description>Pmn Direction</description>
                            <lsb>15</lsb>
                            <msb>15</msb>
                            <access>read-write</access>
                            <enumeratedValues>
                                <enumeratedValue>
                                    <name>0</name>
                                    <description>Input (functions as an input pin)</description>
                                    <value>#0</value>
                                </enumeratedValue>
                                <enumeratedValue>
                                    <name>1</name>
                                    <description>Output (functions as an output pin)</description>
                                    <value>#1</value>
                                </enumeratedValue>
                            </enumeratedValues>
                        </field>
                        <field>
                            <name>PODR00</name>
                            <description>Pmn Output Data</description>
                            <lsb>16</lsb>
                            <msb>16</msb>
                            <access>read-write</access>
                            <enumeratedValues>
                                <enumeratedValue>
                                    <name>0</name>
                                    <description>Low output</description>
                                    <value>#0</value>
                                </enumeratedValue>
                                <enumeratedValue>
                                    <name>1</name>
                                    <description>High output</description>
                                    <value>#1</value>
                                </enumeratedValue>
                            </enumeratedValues>
                        </field>
                        <field>
                            <name>PODR01</name>
                            <description>Pmn Output Data</description>
                            <lsb>17</lsb>
                            <msb>17</msb>
                            <access>read-write</access>
                            <enumeratedValues>
                                <enumeratedValue>
                                    <name>0</name>
                                    <description>Low output</description>
                                    <value>#0</value>
                                </enumeratedValue>
                                <enumeratedValue>
                                    <name>1</name>
                                    <description>High output</description>
                                    <value>#1</value>
                                </enumeratedValue>
                            </enumeratedValues>
                        </field>
                        <field>
                            <name>PODR02</name>
                            <description>Pmn Output Data</description>
                            <lsb>18</lsb>
                            <msb>18</msb>
                            <access>read-write</access>
                            <enumeratedValues>
                                <enumeratedValue>
                                    <name>0</name>
                                    <description>Low output</description>
                                    <value>#0</value>
                                </enumeratedValue>
                                <enumeratedValue>
                                    <name>1</name>
                                    <description>High output</description>
                                    <value>#1</value>
                                </enumeratedValue>
                            </enumeratedValues>
                        </field>
                        <field>
                            <name>PODR03</name>
                            <description>Pmn Output Data</description>
                            <lsb>19</lsb>
                            <msb>19</msb>
                            <access>read-write</access>
                            <enumeratedValues>
                                <enumeratedValue>
                                    <name>0</name>
                                    <description>Low output</description>
                                    <value>#0</value>
                                </enumeratedValue>
                                <enumeratedValue>
                                    <name>1</name>
                                    <description>High output</description>
                                    <value>#1</value>
                                </enumeratedValue>
                            </enumeratedValues>
                        </field>
                        <field>
                            <name>PODR04</name>
                            <description>Pmn Output Data</description>
                            <lsb>20</lsb>
                            <msb>20</msb>
                            <access>read-write</access>
                            <enumeratedValues>
                                <enumeratedValue>
                                    <name>0</name>
                                    <description>Low output</description>
                                    <value>#0</value>
                                </enumeratedValue>
                                <enumeratedValue>
                                    <name>1</name>
                                    <description>High output</description>
                                    <value>#1</value>
                                </enumeratedValue>
                            </enumeratedValues>
                        </field>
                        <field>
                            <name>PODR05</name>
                            <description>Pmn Output Data</description>
                            <lsb>21</lsb>
                            <msb>21</msb>
                            <access>read-write</access>
                            <enumeratedValues>
                                <enumeratedValue>
                                    <name>0</name>
                                    <description>Low output</description>
                                    <value>#0</value>
                                </enumeratedValue>
                                <enumeratedValue>
                                    <name>1</name>
                                    <description>High output</description>
                                    <value>#1</value>
                                </enumeratedValue>
                            </enumeratedValues>
                        </field>
                        <field>
                            <name>PODR06</name>
                            <description>Pmn Output Data</description>
                            <lsb>22</lsb>
                            <msb>22</msb>
                            <access>read-write</access>
                            <enumeratedValues>
                                <enumeratedValue>
                                    <name>0</name>
                                    <description>Low output</description>
                                    <value>#0</value>
                                </enumeratedValue>
                                <enumeratedValue>
                                    <name>1</name>
                                    <description>High output</description>
                                    <value>#1</value>
                                </enumeratedValue>
                            </enumeratedValues>
                        </field>
                        <field>
                            <name>PODR07</name>
                            <description>Pmn Output Data</description>
                            <lsb>23</lsb>
                            <msb>23</msb>
                            <access>read-write</access>
                            <enumeratedValues>
                                <enumeratedValue>
                                    <name>0</name>
                                    <description>Low output</description>
                                    <value>#0</value>
                                </enumeratedValue>
                                <enumeratedValue>
                                    <name>1</name>
                                    <description>High output</description>
                                    <value>#1</value>
                                </enumeratedValue>
                            </enumeratedValues>
                        </field>
                        <field>
                            <name>PODR08</name>
                            <description>Pmn Output Data</description>
                            <lsb>24</lsb>
                            <msb>24</msb>
                            <access>read-write</access>
                            <enumeratedValues>
                                <enumeratedValue>
                                    <name>0</name>
                                    <description>Low output</description>
                                    <value>#0</value>
                                </enumeratedValue>
                                <enumeratedValue>
                                    <name>1</name>
                                    <description>High output</description>
                                    <value>#1</value>
                                </enumeratedValue>
                            </enumeratedValues>
                        </field>
                        <field>
                            <name>PODR09</name>
                            <description>Pmn Output Data</description>
                            <lsb>25</lsb>
                            <msb>25</msb>
                            <access>read-write</access>
                            <enumeratedValues>
                                <enumeratedValue>
                                    <name>0</name>
                                    <description>Low output</description>
                                    <value>#0</value>
                                </enumeratedValue>
                                <enumeratedValue>
                                    <name>1</name>
                                    <description>High output</description>
                                    <value>#1</value>
                                </enumeratedValue>
                            </enumeratedValues>
                        </field>
                        <field>
                            <name>PODR10</name>
                            <description>Pmn Output Data</description>
                            <lsb>26</lsb>
                            <msb>26</msb>
                            <access>read-write</access>
                            <enumeratedValues>
                                <enumeratedValue>
                                    <name>0</name>
                                    <description>Low output</description>
                                    <value>#0</value>
                                </enumeratedValue>
                                <enumeratedValue>
                                    <name>1</name>
                                    <description>High output</description>
                                    <value>#1</value>
                                </enumeratedValue>
                            </enumeratedValues>
                        </field>
                        <field>
                            <name>PODR11</name>
                            <description>Pmn Output Data</description>
                            <lsb>27</lsb>
                            <msb>27</msb>
                            <access>read-write</access>
                            <enumeratedValues>
                                <enumeratedValue>
                                    <name>0</name>
                                    <description>Low output</description>
                                    <value>#0</value>
                                </enumeratedValue>
                                <enumeratedValue>
                                    <name>1</name>
                                    <description>High output</description>
                                    <value>#1</value>
                                </enumeratedValue>
                            </enumeratedValues>
                        </field>
                        <field>
                            <name>PODR12</name>
                            <description>Pmn Output Data</description>
                            <lsb>28</lsb>
                            <msb>28</msb>
                            <access>read-write</access>
                            <enumeratedValues>
                                <enumeratedValue>
                                    <name>0</name>
                                    <description>Low output</description>
                                    <value>#0</value>
                                </enumeratedValue>
                                <enumeratedValue>
                                    <name>1</name>
                                    <description>High output</description>
                                    <value>#1</value>
                                </enumeratedValue>
                            </enumeratedValues>
                        </field>
                        <field>
                            <name>PODR13</name>
                            <description>Pmn Output Data</description>
                            <lsb>29</lsb>
                            <msb>29</msb>
                            <access>read-write</access>
                            <enumeratedValues>
                                <enumeratedValue>
                                    <name>0</name>
                                    <description>Low output</description>
                                    <value>#0</value>
                                </enumeratedValue>
                                <enumeratedValue>
                                    <name>1</name>
                                    <description>High output</description>
                                    <value>#1</value>
                                </enumeratedValue>
                            </enumeratedValues>
                        </field>
                        <field>
                            <name>PODR14</name>
                            <description>Pmn Output Data</description>
                            <lsb>30</lsb>
                            <msb>30</msb>
                            <access>read-write</access>
                            <enumeratedValues>
                                <enumeratedValue>
                                    <name>0</name>
                                    <description>Low output</description>
                                    <value>#0</value>
                                </enumeratedValue>
                                <enumeratedValue>
                                    <name>1</name>
                                    <description>High output</description>
                                    <value>#1</value>
                                </enumeratedValue>
                            </enumeratedValues>
                        </field>
                        <field>
                            <name>PODR15</name>
                            <description>Pmn Output Data</description>
                            <lsb>31</lsb>
                            <msb>31</msb>
                            <access>read-write</access>
                            <enumeratedValues>
                                <enumeratedValue>
                                    <name>0</name>
                                    <description>Low output</description>
                                    <value>#0</value>
                                </enumeratedValue>
                                <enumeratedValue>
                                    <name>1</name>
                                    <description>High output</description>
                                    <value>#1</value>
                                </enumeratedValue>
                            </enumeratedValues>
                        </field>
                    </fields>
                </register>
                <register>
                    <name>PDR</name>
                    <description>Port Control Register 1</description>
                    <alternateRegister>PCNTR1</alternateRegister>
                    <addressOffset>0x000</addressOffset>
                    <size>16</size>
                    <access>read-write</access>
                    <resetValue>0x0000</resetValue>
                    <resetMask>0xffff</resetMask>
                    <fields>
                        <field>
                            <name>PODR00</name>
                            <description>Pmn Output Data</description>
                            <lsb>0</lsb>
                            <msb>0</msb>
                            <access>read-write</access>
                            <enumeratedValues>
                                <enumeratedValue>
                                    <name>0</name>
                                    <description>Low output</description>
                                    <value>#0</value>
                                </enumeratedValue>
                                <enumeratedValue>
                                    <name>1</name>
                                    <description>High output</description>
                                    <value>#1</value>
                                </enumeratedValue>
                            </enumeratedValues>
                        </field>
                        <field>
                            <name>PODR01</name>
                            <description>Pmn Output Data</description>
                            <lsb>1</lsb>
                            <msb>1</msb>
                            <access>read-write</access>
                            <enumeratedValues>
                                <enumeratedValue>
                                    <name>0</name>
                                    <description>Low output</description>
                                    <value>#0</value>
                                </enumeratedValue>
                                <enumeratedValue>
                                    <name>1</name>
                                    <description>High output</description>
                                    <value>#1</value>
                                </enumeratedValue>
                            </enumeratedValues>
                        </field>
                        <field>
                            <name>PODR02</name>
                            <description>Pmn Output Data</description>
                            <lsb>2</lsb>
                            <msb>2</msb>
                            <access>read-write</access>
                            <enumeratedValues>
                                <enumeratedValue>
                                    <name>0</name>
                                    <description>Low output</description>
                                    <value>#0</value>
                                </enumeratedValue>
                                <enumeratedValue>
                                    <name>1</name>
                                    <description>High output</description>
                                    <value>#1</value>
                                </enumeratedValue>
                            </enumeratedValues>
                        </field>
                        <field>
                            <name>PODR03</name>
                            <description>Pmn Output Data</description>
                            <lsb>3</lsb>
                            <msb>3</msb>
                            <access>read-write</access>
                            <enumeratedValues>
                                <enumeratedValue>
                                    <name>0</name>
                                    <description>Low output</description>
                                    <value>#0</value>
                                </enumeratedValue>
                                <enumeratedValue>
                                    <name>1</name>
                                    <description>High output</description>
                                    <value>#1</value>
                                </enumeratedValue>
                            </enumeratedValues>
                        </field>
                        <field>
                            <name>PODR04</name>
                            <description>Pmn Output Data</description>
                            <lsb>4</lsb>
                            <msb>4</msb>
                            <access>read-write</access>
                            <enumeratedValues>
                                <enumeratedValue>
                                    <name>0</name>
                                    <description>Low output</description>
                                    <value>#0</value>
                                </enumeratedValue>
                                <enumeratedValue>
                                    <name>1</name>
                                    <description>High output</description>
                                    <value>#1</value>
                                </enumeratedValue>
                            </enumeratedValues>
                        </field>
                        <field>
                            <name>PODR05</name>
                            <description>Pmn Output Data</description>
                            <lsb>5</lsb>
                            <msb>5</msb>
                            <access>read-write</access>
                            <enumeratedValues>
                                <enumeratedValue>
                                    <name>0</name>
                                    <description>Low output</description>
                                    <value>#0</value>
                                </enumeratedValue>
                                <enumeratedValue>
                                    <name>1</name>
                                    <description>High output</description>
                                    <value>#1</value>
                                </enumeratedValue>
                            </enumeratedValues>
                        </field>
                        <field>
                            <name>PODR06</name>
                            <description>Pmn Output Data</description>
                            <lsb>6</lsb>
                            <msb>6</msb>
                            <access>read-write</access>
                            <enumeratedValues>
                                <enumeratedValue>
                                    <name>0</name>
                                    <description>Low output</description>
                                    <value>#0</value>
                                </enumeratedValue>
                                <enumeratedValue>
                                    <name>1</name>
                                    <description>High output</description>
                                    <value>#1</value>
                                </enumeratedValue>
                            </enumeratedValues>
                        </field>
                        <field>
                            <name>PODR07</name>
                            <description>Pmn Output Data</description>
                            <lsb>7</lsb>
                            <msb>7</msb>
                            <access>read-write</access>
                            <enumeratedValues>
                                <enumeratedValue>
                                    <name>0</name>
                                    <description>Low output</description>
                                    <value>#0</value>
                                </enumeratedValue>
                                <enumeratedValue>
                                    <name>1</name>
                                    <description>High output</description>
                                    <value>#1</value>
                                </enumeratedValue>
                            </enumeratedValues>
                        </field>
                        <field>
                            <name>PODR08</name>
                            <description>Pmn Output Data</description>
                            <lsb>8</lsb>
                            <msb>8</msb>
                            <access>read-write</access>
                            <enumeratedValues>
                                <enumeratedValue>
                                    <name>0</name>
                                    <description>Low output</description>
                                    <value>#0</value>
                                </enumeratedValue>
                                <enumeratedValue>
                                    <name>1</name>
                                    <description>High output</description>
                                    <value>#1</value>
                                </enumeratedValue>
                            </enumeratedValues>
                        </field>
                        <field>
                            <name>PODR09</name>
                            <description>Pmn Output Data</description>
                            <lsb>9</lsb>
                            <msb>9</msb>
                            <access>read-write</access>
                            <enumeratedValues>
                                <enumeratedValue>
                                    <name>0</name>
                                    <description>Low output</description>
                                    <value>#0</value>
                                </enumeratedValue>
                                <enumeratedValue>
                                    <name>1</name>
                                    <description>High output</description>
                                    <value>#1</value>
                                </enumeratedValue>
                            </enumeratedValues>
                        </field>
                        <field>
                            <name>PODR10</name>
                            <description>Pmn Output Data</description>
                            <lsb>10</lsb>
                            <msb>10</msb>
                            <access>read-write</access>
                            <enumeratedValues>
                                <enumeratedValue>
                                    <name>0</name>
                                    <description>Low output</description>
                                    <value>#0</value>
                                </enumeratedValue>
                                <enumeratedValue>
                                    <name>1</name>
                                    <description>High output</description>
                                    <value>#1</value>
                                </enumeratedValue>
                            </enumeratedValues>
                        </field>
                        <field>
                            <name>PODR11</name>
                            <description>Pmn Output Data</description>
                            <lsb>11</lsb>
                            <msb>11</msb>
                            <access>read-write</access>
                            <enumeratedValues>
                                <enumeratedValue>
                                    <name>0</name>
                                    <description>Low output</description>
                                    <value>#0</value>
                                </enumeratedValue>
                                <enumeratedValue>
                                    <name>1</name>
                                    <description>High output</description>
                                    <value>#1</value>
                                </enumeratedValue>
                            </enumeratedValues>
                        </field>
                        <field>
                            <name>PODR12</name>
                            <description>Pmn Output Data</description>
                            <lsb>12</lsb>
                            <msb>12</msb>
                            <access>read-write</access>
                            <enumeratedValues>
                                <enumeratedValue>
                                    <name>0</name>
                                    <description>Low output</description>
                                    <value>#0</value>
                                </enumeratedValue>
                                <enumeratedValue>
                                    <name>1</name>
                                    <description>High output</description>
                                    <value>#1</value>
                                </enumeratedValue>
                            </enumeratedValues>
                        </field>
                        <field>
                            <name>PODR13</name>
                            <description>Pmn Output Data</description>
                            <lsb>13</lsb>
                            <msb>13</msb>
                            <access>read-write</access>
                            <enumeratedValues>
                                <enumeratedValue>
                                    <name>0</name>
                                    <description>Low output</description>
                                    <value>#0</value>
                                </enumeratedValue>
                                <enumeratedValue>
                                    <name>1</name>
                                    <description>High output</description>
                                    <value>#1</value>
                                </enumeratedValue>
                            </enumeratedValues>
                        </field>
                        <field>
                            <name>PODR14</name>
                            <description>Pmn Output Data</description>
                            <lsb>14</lsb>
                            <msb>14</msb>
                            <access>read-write</access>
                            <enumeratedValues>
                                <enumeratedValue>
                                    <name>0</name>
                                    <description>Low output</description>
                                    <value>#0</value>
                                </enumeratedValue>
                                <enumeratedValue>
                                    <name>1</name>
                                    <description>High output</description>
                                    <value>#1</value>
                                </enumeratedValue>
                            </enumeratedValues>
                        </field>
                        <field>
                            <name>PODR15</name>
                            <description>Pmn Output Data</description>
                            <lsb>15</lsb>
                            <msb>15</msb>
                            <access>read-write</access>
                            <enumeratedValues>
                                <enumeratedValue>
                                    <name>0</name>
                                    <description>Low output</description>
                                    <value>#0</value>
                                </enumeratedValue>
                                <enumeratedValue>
                                    <name>1</name>
                                    <description>High output</description>
                                    <value>#1</value>
                                </enumeratedValue>
                            </enumeratedValues>
                        </field>
                    </fields>
                </register>
                <register>
                    <name>PODR</name>
                    <description>Port Control Register 1</description>
                    <alternateRegister>PCNTR1</alternateRegister>
                    <addressOffset>0x002</addressOffset>
                    <size>16</size>
                    <access>read-write</access>
                    <resetValue>0x0000</resetValue>
                    <resetMask>0xffff</resetMask>
                    <fields>
                        <field>
                            <name>PDR00</name>
                            <description>Pmn Direction</description>
                            <lsb>0</lsb>
                            <msb>0</msb>
                            <access>read-write</access>
                            <enumeratedValues>
                                <enumeratedValue>
                                    <name>0</name>
                                    <description>Input (functions as an input pin)</description>
                                    <value>#0</value>
                                </enumeratedValue>
                                <enumeratedValue>
                                    <name>1</name>
                                    <description>Output (functions as an output pin)</description>
                                    <value>#1</value>
                                </enumeratedValue>
                            </enumeratedValues>
                        </field>
                        <field>
                            <name>PDR01</name>
                            <description>Pmn Direction</description>
                            <lsb>1</lsb>
                            <msb>1</msb>
                            <access>read-write</access>
                            <enumeratedValues>
                                <enumeratedValue>
                                    <name>0</name>
                                    <description>Input (functions as an input pin)</description>
                                    <value>#0</value>
                                </enumeratedValue>
                                <enumeratedValue>
                                    <name>1</name>
                                    <description>Output (functions as an output pin)</description>
                                    <value>#1</value>
                                </enumeratedValue>
                            </enumeratedValues>
                        </field>
                        <field>
                            <name>PDR02</name>
                            <description>Pmn Direction</description>
                            <lsb>2</lsb>
                            <msb>2</msb>
                            <access>read-write</access>
                            <enumeratedValues>
                                <enumeratedValue>
                                    <name>0</name>
                                    <description>Input (functions as an input pin)</description>
                                    <value>#0</value>
                                </enumeratedValue>
                                <enumeratedValue>
                                    <name>1</name>
                                    <description>Output (functions as an output pin)</description>
                                    <value>#1</value>
                                </enumeratedValue>
                            </enumeratedValues>
                        </field>
                        <field>
                            <name>PDR03</name>
                            <description>Pmn Direction</description>
                            <lsb>3</lsb>
                            <msb>3</msb>
                            <access>read-write</access>
                            <enumeratedValues>
                                <enumeratedValue>
                                    <name>0</name>
                                    <description>Input (functions as an input pin)</description>
                                    <value>#0</value>
                                </enumeratedValue>
                                <enumeratedValue>
                                    <name>1</name>
                                    <description>Output (functions as an output pin)</description>
                                    <value>#1</value>
                                </enumeratedValue>
                            </enumeratedValues>
                        </field>
                        <field>
                            <name>PDR04</name>
                            <description>Pmn Direction</description>
                            <lsb>4</lsb>
                            <msb>4</msb>
                            <access>read-write</access>
                            <enumeratedValues>
                                <enumeratedValue>
                                    <name>0</name>
                                    <description>Input (functions as an input pin)</description>
                                    <value>#0</value>
                                </enumeratedValue>
                                <enumeratedValue>
                                    <name>1</name>
                                    <description>Output (functions as an output pin)</description>
                                    <value>#1</value>
                                </enumeratedValue>
                            </enumeratedValues>
                        </field>
                        <field>
                            <name>PDR05</name>
                            <description>Pmn Direction</description>
                            <lsb>5</lsb>
                            <msb>5</msb>
                            <access>read-write</access>
                            <enumeratedValues>
                                <enumeratedValue>
                                    <name>0</name>
                                    <description>Input (functions as an input pin)</description>
                                    <value>#0</value>
                                </enumeratedValue>
                                <enumeratedValue>
                                    <name>1</name>
                                    <description>Output (functions as an output pin)</description>
                                    <value>#1</value>
                                </enumeratedValue>
                            </enumeratedValues>
                        </field>
                        <field>
                            <name>PDR06</name>
                            <description>Pmn Direction</description>
                            <lsb>6</lsb>
                            <msb>6</msb>
                            <access>read-write</access>
                            <enumeratedValues>
                                <enumeratedValue>
                                    <name>0</name>
                                    <description>Input (functions as an input pin)</description>
                                    <value>#0</value>
                                </enumeratedValue>
                                <enumeratedValue>
                                    <name>1</name>
                                    <description>Output (functions as an output pin)</description>
                                    <value>#1</value>
                                </enumeratedValue>
                            </enumeratedValues>
                        </field>
                        <field>
                            <name>PDR07</name>
                            <description>Pmn Direction</description>
                            <lsb>7</lsb>
                            <msb>7</msb>
                            <access>read-write</access>
                            <enumeratedValues>
                                <enumeratedValue>
                                    <name>0</name>
                                    <description>Input (functions as an input pin)</description>
                                    <value>#0</value>
                                </enumeratedValue>
                                <enumeratedValue>
                                    <name>1</name>
                                    <description>Output (functions as an output pin)</description>
                                    <value>#1</value>
                                </enumeratedValue>
                            </enumeratedValues>
                        </field>
                        <field>
                            <name>PDR08</name>
                            <description>Pmn Direction</description>
                            <lsb>8</lsb>
                            <msb>8</msb>
                            <access>read-write</access>
                            <enumeratedValues>
                                <enumeratedValue>
                                    <name>0</name>
                                    <description>Input (functions as an input pin)</description>
                                    <value>#0</value>
                                </enumeratedValue>
                                <enumeratedValue>
                                    <name>1</name>
                                    <description>Output (functions as an output pin)</description>
                                    <value>#1</value>
                                </enumeratedValue>
                            </enumeratedValues>
                        </field>
                        <field>
                            <name>PDR09</name>
                            <description>Pmn Direction</description>
                            <lsb>9</lsb>
                            <msb>9</msb>
                            <access>read-write</access>
                            <enumeratedValues>
                                <enumeratedValue>
                                    <name>0</name>
                                    <description>Input (functions as an input pin)</description>
                                    <value>#0</value>
                                </enumeratedValue>
                                <enumeratedValue>
                                    <name>1</name>
                                    <description>Output (functions as an output pin)</description>
                                    <value>#1</value>
                                </enumeratedValue>
                            </enumeratedValues>
                        </field>
                        <field>
                            <name>PDR10</name>
                            <description>Pmn Direction</description>
                            <lsb>10</lsb>
                            <msb>10</msb>
                            <access>read-write</access>
                            <enumeratedValues>
                                <enumeratedValue>
                                    <name>0</name>
                                    <description>Input (functions as an input pin)</description>
                                    <value>#0</value>
                                </enumeratedValue>
                                <enumeratedValue>
                                    <name>1</name>
                                    <description>Output (functions as an output pin)</description>
                                    <value>#1</value>
                                </enumeratedValue>
                            </enumeratedValues>
                        </field>
                        <field>
                            <name>PDR11</name>
                            <description>Pmn Direction</description>
                            <lsb>11</lsb>
                            <msb>11</msb>
                            <access>read-write</access>
                            <enumeratedValues>
                                <enumeratedValue>
                                    <name>0</name>
                                    <description>Input (functions as an input pin)</description>
                                    <value>#0</value>
                                </enumeratedValue>
                                <enumeratedValue>
                                    <name>1</name>
                                    <description>Output (functions as an output pin)</description>
                                    <value>#1</value>
                                </enumeratedValue>
                            </enumeratedValues>
                        </field>
                        <field>
                            <name>PDR12</name>
                            <description>Pmn Direction</description>
                            <lsb>12</lsb>
                            <msb>12</msb>
                            <access>read-write</access>
                            <enumeratedValues>
                                <enumeratedValue>
                                    <name>0</name>
                                    <description>Input (functions as an input pin)</description>
                                    <value>#0</value>
                                </enumeratedValue>
                                <enumeratedValue>
                                    <name>1</name>
                                    <description>Output (functions as an output pin)</description>
                                    <value>#1</value>
                                </enumeratedValue>
                            </enumeratedValues>
                        </field>
                        <field>
                            <name>PDR13</name>
                            <description>Pmn Direction</description>
                            <lsb>13</lsb>
                            <msb>13</msb>
                            <access>read-write</access>
                            <enumeratedValues>
                                <enumeratedValue>
                                    <name>0</name>
                                    <description>Input (functions as an input pin)</description>
                                    <value>#0</value>
                                </enumeratedValue>
                                <enumeratedValue>
                                    <name>1</name>
                                    <description>Output (functions as an output pin)</description>
                                    <value>#1</value>
                                </enumeratedValue>
                            </enumeratedValues>
                        </field>
                        <field>
                            <name>PDR14</name>
                            <description>Pmn Direction</description>
                            <lsb>14</lsb>
                            <msb>14</msb>
                            <access>read-write</access>
                            <enumeratedValues>
                                <enumeratedValue>
                                    <name>0</name>
                                    <description>Input (functions as an input pin)</description>
                                    <value>#0</value>
                                </enumeratedValue>
                                <enumeratedValue>
                                    <name>1</name>
                                    <description>Output (functions as an output pin)</description>
                                    <value>#1</value>
                                </enumeratedValue>
                            </enumeratedValues>
                        </field>
                        <field>
                            <name>PDR15</name>
                            <description>Pmn Direction</description>
                            <lsb>15</lsb>
                            <msb>15</msb>
                            <access>read-write</access>
                            <enumeratedValues>
                                <enumeratedValue>
                                    <name>0</name>
                                    <description>Input (functions as an input pin)</description>
                                    <value>#0</value>
                                </enumeratedValue>
                                <enumeratedValue>
                                    <name>1</name>
                                    <description>Output (functions as an output pin)</description>
                                    <value>#1</value>
                                </enumeratedValue>
                            </enumeratedValues>
                        </field>
                    </fields>
                </register>
                <register>
                    <name>PCNTR2</name>
                    <description>Port Control Register 2</description>
                    <addressOffset>0x004</addressOffset>
                    <size>32</size>
                    <access>read-only</access>
                    <resetValue>0x00000000</resetValue>
                    <resetMask>0xffff0000</resetMask>
                    <fields>
                        <field>
                            <name>PIDR00</name>
                            <description>Pmn State</description>
                            <lsb>0</lsb>
                            <msb>0</msb>
                            <access>read-only</access>
                            <enumeratedValues>
                                <enumeratedValue>
                                    <name>0</name>
                                    <description>Low level</description>
                                    <value>#0</value>
                                </enumeratedValue>
                                <enumeratedValue>
                                    <name>1</name>
                                    <description>High level</description>
                                    <value>#1</value>
                                </enumeratedValue>
                            </enumeratedValues>
                        </field>
                        <field>
                            <name>PIDR01</name>
                            <description>Pmn State</description>
                            <lsb>1</lsb>
                            <msb>1</msb>
                            <access>read-only</access>
                            <enumeratedValues>
                                <enumeratedValue>
                                    <name>0</name>
                                    <description>Low level</description>
                                    <value>#0</value>
                                </enumeratedValue>
                                <enumeratedValue>
                                    <name>1</name>
                                    <description>High level</description>
                                    <value>#1</value>
                                </enumeratedValue>
                            </enumeratedValues>
                        </field>
                        <field>
                            <name>PIDR02</name>
                            <description>Pmn State</description>
                            <lsb>2</lsb>
                            <msb>2</msb>
                            <access>read-only</access>
                            <enumeratedValues>
                                <enumeratedValue>
                                    <name>0</name>
                                    <description>Low level</description>
                                    <value>#0</value>
                                </enumeratedValue>
                                <enumeratedValue>
                                    <name>1</name>
                                    <description>High level</description>
                                    <value>#1</value>
                                </enumeratedValue>
                            </enumeratedValues>
                        </field>
                        <field>
                            <name>PIDR03</name>
                            <description>Pmn State</description>
                            <lsb>3</lsb>
                            <msb>3</msb>
                            <access>read-only</access>
                            <enumeratedValues>
                                <enumeratedValue>
                                    <name>0</name>
                                    <description>Low level</description>
                                    <value>#0</value>
                                </enumeratedValue>
                                <enumeratedValue>
                                    <name>1</name>
                                    <description>High level</description>
                                    <value>#1</value>
                                </enumeratedValue>
                            </enumeratedValues>
                        </field>
                        <field>
                            <name>PIDR04</name>
                            <description>Pmn State</description>
                            <lsb>4</lsb>
                            <msb>4</msb>
                            <access>read-only</access>
                            <enumeratedValues>
                                <enumeratedValue>
                                    <name>0</name>
                                    <description>Low level</description>
                                    <value>#0</value>
                                </enumeratedValue>
                                <enumeratedValue>
                                    <name>1</name>
                                    <description>High level</description>
                                    <value>#1</value>
                                </enumeratedValue>
                            </enumeratedValues>
                        </field>
                        <field>
                            <name>PIDR05</name>
                            <description>Pmn State</description>
                            <lsb>5</lsb>
                            <msb>5</msb>
                            <access>read-only</access>
                            <enumeratedValues>
                                <enumeratedValue>
                                    <name>0</name>
                                    <description>Low level</description>
                                    <value>#0</value>
                                </enumeratedValue>
                                <enumeratedValue>
                                    <name>1</name>
                                    <description>High level</description>
                                    <value>#1</value>
                                </enumeratedValue>
                            </enumeratedValues>
                        </field>
                        <field>
                            <name>PIDR06</name>
                            <description>Pmn State</description>
                            <lsb>6</lsb>
                            <msb>6</msb>
                            <access>read-only</access>
                            <enumeratedValues>
                                <enumeratedValue>
                                    <name>0</name>
                                    <description>Low level</description>
                                    <value>#0</value>
                                </enumeratedValue>
                                <enumeratedValue>
                                    <name>1</name>
                                    <description>High level</description>
                                    <value>#1</value>
                                </enumeratedValue>
                            </enumeratedValues>
                        </field>
                        <field>
                            <name>PIDR07</name>
                            <description>Pmn State</description>
                            <lsb>7</lsb>
                            <msb>7</msb>
                            <access>read-only</access>
                            <enumeratedValues>
                                <enumeratedValue>
                                    <name>0</name>
                                    <description>Low level</description>
                                    <value>#0</value>
                                </enumeratedValue>
                                <enumeratedValue>
                                    <name>1</name>
                                    <description>High level</description>
                                    <value>#1</value>
                                </enumeratedValue>
                            </enumeratedValues>
                        </field>
                        <field>
                            <name>PIDR08</name>
                            <description>Pmn State</description>
                            <lsb>8</lsb>
                            <msb>8</msb>
                            <access>read-only</access>
                            <enumeratedValues>
                                <enumeratedValue>
                                    <name>0</name>
                                    <description>Low level</description>
                                    <value>#0</value>
                                </enumeratedValue>
                                <enumeratedValue>
                                    <name>1</name>
                                    <description>High level</description>
                                    <value>#1</value>
                                </enumeratedValue>
                            </enumeratedValues>
                        </field>
                        <field>
                            <name>PIDR09</name>
                            <description>Pmn State</description>
                            <lsb>9</lsb>
                            <msb>9</msb>
                            <access>read-only</access>
                            <enumeratedValues>
                                <enumeratedValue>
                                    <name>0</name>
                                    <description>Low level</description>
                                    <value>#0</value>
                                </enumeratedValue>
                                <enumeratedValue>
                                    <name>1</name>
                                    <description>High level</description>
                                    <value>#1</value>
                                </enumeratedValue>
                            </enumeratedValues>
                        </field>
                        <field>
                            <name>PIDR10</name>
                            <description>Pmn State</description>
                            <lsb>10</lsb>
                            <msb>10</msb>
                            <access>read-only</access>
                            <enumeratedValues>
                                <enumeratedValue>
                                    <name>0</name>
                                    <description>Low level</description>
                                    <value>#0</value>
                                </enumeratedValue>
                                <enumeratedValue>
                                    <name>1</name>
                                    <description>High level</description>
                                    <value>#1</value>
                                </enumeratedValue>
                            </enumeratedValues>
                        </field>
                        <field>
                            <name>PIDR11</name>
                            <description>Pmn State</description>
                            <lsb>11</lsb>
                            <msb>11</msb>
                            <access>read-only</access>
                            <enumeratedValues>
                                <enumeratedValue>
                                    <name>0</name>
                                    <description>Low level</description>
                                    <value>#0</value>
                                </enumeratedValue>
                                <enumeratedValue>
                                    <name>1</name>
                                    <description>High level</description>
                                    <value>#1</value>
                                </enumeratedValue>
                            </enumeratedValues>
                        </field>
                        <field>
                            <name>PIDR12</name>
                            <description>Pmn State</description>
                            <lsb>12</lsb>
                            <msb>12</msb>
                            <access>read-only</access>
                            <enumeratedValues>
                                <enumeratedValue>
                                    <name>0</name>
                                    <description>Low level</description>
                                    <value>#0</value>
                                </enumeratedValue>
                                <enumeratedValue>
                                    <name>1</name>
                                    <description>High level</description>
                                    <value>#1</value>
                                </enumeratedValue>
                            </enumeratedValues>
                        </field>
                        <field>
                            <name>PIDR13</name>
                            <description>Pmn State</description>
                            <lsb>13</lsb>
                            <msb>13</msb>
                            <access>read-only</access>
                            <enumeratedValues>
                                <enumeratedValue>
                                    <name>0</name>
                                    <description>Low level</description>
                                    <value>#0</value>
                                </enumeratedValue>
                                <enumeratedValue>
                                    <name>1</name>
                                    <description>High level</description>
                                    <value>#1</value>
                                </enumeratedValue>
                            </enumeratedValues>
                        </field>
                        <field>
                            <name>PIDR14</name>
                            <description>Pmn State</description>
                            <lsb>14</lsb>
                            <msb>14</msb>
                            <access>read-only</access>
                            <enumeratedValues>
                                <enumeratedValue>
                                    <name>0</name>
                                    <description>Low level</description>
                                    <value>#0</value>
                                </enumeratedValue>
                                <enumeratedValue>
                                    <name>1</name>
                                    <description>High level</description>
                                    <value>#1</value>
                                </enumeratedValue>
                            </enumeratedValues>
                        </field>
                        <field>
                            <name>PIDR15</name>
                            <description>Pmn State</description>
                            <lsb>15</lsb>
                            <msb>15</msb>
                            <access>read-only</access>
                            <enumeratedValues>
                                <enumeratedValue>
                                    <name>0</name>
                                    <description>Low level</description>
                                    <value>#0</value>
                                </enumeratedValue>
                                <enumeratedValue>
                                    <name>1</name>
                                    <description>High level</description>
                                    <value>#1</value>
                                </enumeratedValue>
                            </enumeratedValues>
                        </field>
                    </fields>
                </register>
                <register>
                    <name>PIDR</name>
                    <description>Port Control Register 2</description>
                    <alternateRegister>PCNTR2</alternateRegister>
                    <addressOffset>0x004</addressOffset>
                    <size>16</size>
                    <access>read-only</access>
                    <resetValue>0x0000</resetValue>
                    <resetMask>0xffff</resetMask>
                </register>
                <register>
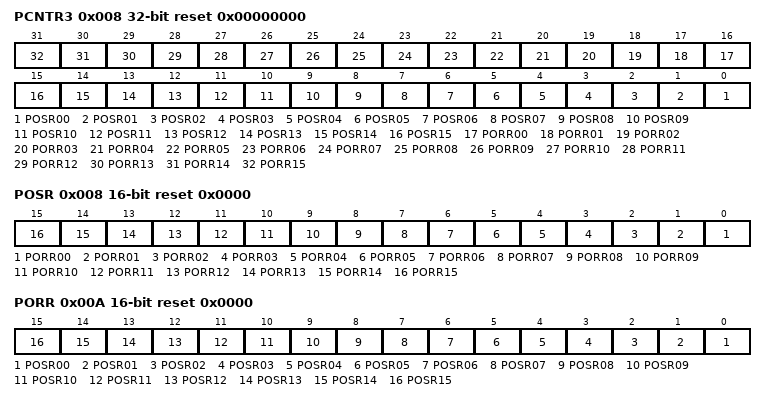
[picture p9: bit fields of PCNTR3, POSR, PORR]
                    <name>PCNTR3</name>
                    <description>Port Control Register 3</description>
                    <addressOffset>0x008</addressOffset>
                    <size>32</size>
                    <access>write-only</access>
                    <resetValue>0x00000000</resetValue>
                    <resetMask>0xffffffff</resetMask>
                    <fields>
                        <field>
                            <name>POSR00</name>
                            <description>Pmn Output Set</description>
                            <lsb>0</lsb>
                            <msb>0</msb>
                            <access>write-only</access>
                            <enumeratedValues>
                                <enumeratedValue>
                                    <name>0</name>
                                    <description>No effect on output</description>
                                    <value>#0</value>
                                </enumeratedValue>
                                <enumeratedValue>
                                    <name>1</name>
                                    <description>High output</description>
                                    <value>#1</value>
                                </enumeratedValue>
                            </enumeratedValues>
                        </field>
                        <field>
                            <name>POSR01</name>
                            <description>Pmn Output Set</description>
                            <lsb>1</lsb>
                            <msb>1</msb>
                            <access>write-only</access>
                            <enumeratedValues>
                                <enumeratedValue>
                                    <name>0</name>
                                    <description>No effect on output</description>
                                    <value>#0</value>
                                </enumeratedValue>
                                <enumeratedValue>
                                    <name>1</name>
                                    <description>High output</description>
                                    <value>#1</value>
                                </enumeratedValue>
                            </enumeratedValues>
                        </field>
                        <field>
                            <name>POSR02</name>
                            <description>Pmn Output Set</description>
                            <lsb>2</lsb>
                            <msb>2</msb>
                            <access>write-only</access>
                            <enumeratedValues>
                                <enumeratedValue>
                                    <name>0</name>
                                    <description>No effect on output</description>
                                    <value>#0</value>
                                </enumeratedValue>
                                <enumeratedValue>
                                    <name>1</name>
                                    <description>High output</description>
                                    <value>#1</value>
                                </enumeratedValue>
                            </enumeratedValues>
                        </field>
                        <field>
                            <name>POSR03</name>
                            <description>Pmn Output Set</description>
                            <lsb>3</lsb>
                            <msb>3</msb>
                            <access>write-only</access>
                            <enumeratedValues>
                                <enumeratedValue>
                                    <name>0</name>
                                    <description>No effect on output</description>
                                    <value>#0</value>
                                </enumeratedValue>
                                <enumeratedValue>
                                    <name>1</name>
                                    <description>High output</description>
                                    <value>#1</value>
                                </enumeratedValue>
                            </enumeratedValues>
                        </field>
                        <field>
                            <name>POSR04</name>
                            <description>Pmn Output Set</description>
                            <lsb>4</lsb>
                            <msb>4</msb>
                            <access>write-only</access>
                            <enumeratedValues>
                                <enumeratedValue>
                                    <name>0</name>
                                    <description>No effect on output</description>
                                    <value>#0</value>
                                </enumeratedValue>
                                <enumeratedValue>
                                    <name>1</name>
                                    <description>High output</description>
                                    <value>#1</value>
                                </enumeratedValue>
                            </enumeratedValues>
                        </field>
                        <field>
                            <name>POSR05</name>
                            <description>Pmn Output Set</description>
                            <lsb>5</lsb>
                            <msb>5</msb>
                            <access>write-only</access>
                            <enumeratedValues>
                                <enumeratedValue>
                                    <name>0</name>
                                    <description>No effect on output</description>
                                    <value>#0</value>
                                </enumeratedValue>
                                <enumeratedValue>
                                    <name>1</name>
                                    <description>High output</description>
                                    <value>#1</value>
                                </enumeratedValue>
                            </enumeratedValues>
                        </field>
                        <field>
                            <name>POSR06</name>
                            <description>Pmn Output Set</description>
                            <lsb>6</lsb>
                            <msb>6</msb>
                            <access>write-only</access>
                            <enumeratedValues>
                                <enumeratedValue>
                                    <name>0</name>
                                    <description>No effect on output</description>
                                    <value>#0</value>
                                </enumeratedValue>
                                <enumeratedValue>
                                    <name>1</name>
                                    <description>High output</description>
                                    <value>#1</value>
                                </enumeratedValue>
                            </enumeratedValues>
                        </field>
                        <field>
                            <name>POSR07</name>
                            <description>Pmn Output Set</description>
                            <lsb>7</lsb>
                            <msb>7</msb>
                            <access>write-only</access>
                            <enumeratedValues>
                                <enumeratedValue>
                                    <name>0</name>
                                    <description>No effect on output</description>
                                    <value>#0</value>
                                </enumeratedValue>
                                <enumeratedValue>
                                    <name>1</name>
                                    <description>High output</description>
                                    <value>#1</value>
                                </enumeratedValue>
                            </enumeratedValues>
                        </field>
                        <field>
                            <name>POSR08</name>
                            <description>Pmn Output Set</description>
                            <lsb>8</lsb>
                            <msb>8</msb>
                            <access>write-only</access>
                            <enumeratedValues>
                                <enumeratedValue>
                                    <name>0</name>
                                    <description>No effect on output</description>
                                    <value>#0</value>
                                </enumeratedValue>
                                <enumeratedValue>
                                    <name>1</name>
                                    <description>High output</description>
                                    <value>#1</value>
                                </enumeratedValue>
                            </enumeratedValues>
                        </field>
                        <field>
                            <name>POSR09</name>
                            <description>Pmn Output Set</description>
                            <lsb>9</lsb>
                            <msb>9</msb>
                            <access>write-only</access>
                            <enumeratedValues>
                                <enumeratedValue>
                                    <name>0</name>
                                    <description>No effect on output</description>
                                    <value>#0</value>
                                </enumeratedValue>
                                <enumeratedValue>
                                    <name>1</name>
                                    <description>High output</description>
                                    <value>#1</value>
                                </enumeratedValue>
                            </enumeratedValues>
                        </field>
                        <field>
                            <name>POSR10</name>
                            <description>Pmn Output Set</description>
                            <lsb>10</lsb>
                            <msb>10</msb>
                            <access>write-only</access>
                            <enumeratedValues>
                                <enumeratedValue>
                                    <name>0</name>
                                    <description>No effect on output</description>
                                    <value>#0</value>
                                </enumeratedValue>
                                <enumeratedValue>
                                    <name>1</name>
                                    <description>High output</description>
                                    <value>#1</value>
                                </enumeratedValue>
                            </enumeratedValues>
                        </field>
                        <field>
                            <name>POSR11</name>
                            <description>Pmn Output Set</description>
                            <lsb>11</lsb>
                            <msb>11</msb>
                            <access>write-only</access>
                            <enumeratedValues>
                                <enumeratedValue>
                                    <name>0</name>
                                    <description>No effect on output</description>
                                    <value>#0</value>
                                </enumeratedValue>
                                <enumeratedValue>
                                    <name>1</name>
                                    <description>High output</description>
                                    <value>#1</value>
                                </enumeratedValue>
                            </enumeratedValues>
                        </field>
                        <field>
                            <name>POSR12</name>
                            <description>Pmn Output Set</description>
                            <lsb>12</lsb>
                            <msb>12</msb>
                            <access>write-only</access>
                            <enumeratedValues>
                                <enumeratedValue>
                                    <name>0</name>
                                    <description>No effect on output</description>
                                    <value>#0</value>
                                </enumeratedValue>
                                <enumeratedValue>
                                    <name>1</name>
                                    <description>High output</description>
                                    <value>#1</value>
                                </enumeratedValue>
                            </enumeratedValues>
                        </field>
                        <field>
                            <name>POSR13</name>
                            <description>Pmn Output Set</description>
                            <lsb>13</lsb>
                            <msb>13</msb>
                            <access>write-only</access>
                            <enumeratedValues>
                                <enumeratedValue>
                                    <name>0</name>
                                    <description>No effect on output</description>
                                    <value>#0</value>
                                </enumeratedValue>
                                <enumeratedValue>
                                    <name>1</name>
                                    <description>High output</description>
                                    <value>#1</value>
                                </enumeratedValue>
                            </enumeratedValues>
                        </field>
                        <field>
                            <name>POSR14</name>
                            <description>Pmn Output Set</description>
                            <lsb>14</lsb>
                            <msb>14</msb>
                            <access>write-only</access>
                            <enumeratedValues>
                                <enumeratedValue>
                                    <name>0</name>
                                    <description>No effect on output</description>
                                    <value>#0</value>
                                </enumeratedValue>
                                <enumeratedValue>
                                    <name>1</name>
                                    <description>High output</description>
                                    <value>#1</value>
                                </enumeratedValue>
                            </enumeratedValues>
                        </field>
                        <field>
                            <name>POSR15</name>
                            <description>Pmn Output Set</description>
                            <lsb>15</lsb>
                            <msb>15</msb>
                            <access>write-only</access>
                            <enumeratedValues>
                                <enumeratedValue>
                                    <name>0</name>
                                    <description>No effect on output</description>
                                    <value>#0</value>
                                </enumeratedValue>
                                <enumeratedValue>
                                    <name>1</name>
                                    <description>High output</description>
                                    <value>#1</value>
                                </enumeratedValue>
                            </enumeratedValues>
                        </field>
                        <field>
                            <name>PORR00</name>
                            <description>Pmn Output Reset</description>
                            <lsb>16</lsb>
                            <msb>16</msb>
                            <access>write-only</access>
                            <enumeratedValues>
                                <enumeratedValue>
                                    <name>0</name>
                                    <description>No effect on output</description>
                                    <value>#0</value>
                                </enumeratedValue>
                                <enumeratedValue>
                                    <name>1</name>
                                    <description>Low output</description>
                                    <value>#1</value>
                                </enumeratedValue>
                            </enumeratedValues>
                        </field>
                        <field>
                            <name>PORR01</name>
                            <description>Pmn Output Reset</description>
                            <lsb>17</lsb>
                            <msb>17</msb>
                            <access>write-only</access>
                            <enumeratedValues>
                                <enumeratedValue>
                                    <name>0</name>
                                    <description>No effect on output</description>
                                    <value>#0</value>
                                </enumeratedValue>
                                <enumeratedValue>
                                    <name>1</name>
                                    <description>Low output</description>
                                    <value>#1</value>
                                </enumeratedValue>
                            </enumeratedValues>
                        </field>
                        <field>
                            <name>PORR02</name>
                            <description>Pmn Output Reset</description>
                            <lsb>18</lsb>
                            <msb>18</msb>
                            <access>write-only</access>
                            <enumeratedValues>
                                <enumeratedValue>
                                    <name>0</name>
                                    <description>No effect on output</description>
                                    <value>#0</value>
                                </enumeratedValue>
                                <enumeratedValue>
                                    <name>1</name>
                                    <description>Low output</description>
                                    <value>#1</value>
                                </enumeratedValue>
                            </enumeratedValues>
                        </field>
                        <field>
                            <name>PORR03</name>
                            <description>Pmn Output Reset</description>
                            <lsb>19</lsb>
                            <msb>19</msb>
                            <access>write-only</access>
                            <enumeratedValues>
                                <enumeratedValue>
                                    <name>0</name>
                                    <description>No effect on output</description>
                                    <value>#0</value>
                                </enumeratedValue>
                                <enumeratedValue>
                                    <name>1</name>
                                    <description>Low output</description>
                                    <value>#1</value>
                                </enumeratedValue>
                            </enumeratedValues>
                        </field>
                        <field>
                            <name>PORR04</name>
                            <description>Pmn Output Reset</description>
                            <lsb>20</lsb>
                            <msb>20</msb>
                            <access>write-only</access>
                            <enumeratedValues>
                                <enumeratedValue>
                                    <name>0</name>
                                    <description>No effect on output</description>
                                    <value>#0</value>
                                </enumeratedValue>
                                <enumeratedValue>
                                    <name>1</name>
                                    <description>Low output</description>
                                    <value>#1</value>
                                </enumeratedValue>
                            </enumeratedValues>
                        </field>
                        <field>
                            <name>PORR05</name>
                            <description>Pmn Output Reset</description>
                            <lsb>21</lsb>
                            <msb>21</msb>
                            <access>write-only</access>
                            <enumeratedValues>
                                <enumeratedValue>
                                    <name>0</name>
                                    <description>No effect on output</description>
                                    <value>#0</value>
                                </enumeratedValue>
                                <enumeratedValue>
                                    <name>1</name>
                                    <description>Low output</description>
                                    <value>#1</value>
                                </enumeratedValue>
                            </enumeratedValues>
                        </field>
                        <field>
                            <name>PORR06</name>
                            <description>Pmn Output Reset</description>
                            <lsb>22</lsb>
                            <msb>22</msb>
                            <access>write-only</access>
                            <enumeratedValues>
                                <enumeratedValue>
                                    <name>0</name>
                                    <description>No effect on output</description>
                                    <value>#0</value>
                                </enumeratedValue>
                                <enumeratedValue>
                                    <name>1</name>
                                    <description>Low output</description>
                                    <value>#1</value>
                                </enumeratedValue>
                            </enumeratedValues>
                        </field>
                        <field>
                            <name>PORR07</name>
                            <description>Pmn Output Reset</description>
                            <lsb>23</lsb>
                            <msb>23</msb>
                            <access>write-only</access>
                            <enumeratedValues>
                                <enumeratedValue>
                                    <name>0</name>
                                    <description>No effect on output</description>
                                    <value>#0</value>
                                </enumeratedValue>
                                <enumeratedValue>
                                    <name>1</name>
                                    <description>Low output</description>
                                    <value>#1</value>
                                </enumeratedValue>
                            </enumeratedValues>
                        </field>
                        <field>
                            <name>PORR08</name>
                            <description>Pmn Output Reset</description>
                            <lsb>24</lsb>
                            <msb>24</msb>
                            <access>write-only</access>
                            <enumeratedValues>
                                <enumeratedValue>
                                    <name>0</name>
                                    <description>No effect on output</description>
                                    <value>#0</value>
                                </enumeratedValue>
                                <enumeratedValue>
                                    <name>1</name>
                                    <description>Low output</description>
                                    <value>#1</value>
                                </enumeratedValue>
                            </enumeratedValues>
                        </field>
                        <field>
                            <name>PORR09</name>
                            <description>Pmn Output Reset</description>
                            <lsb>25</lsb>
                            <msb>25</msb>
                            <access>write-only</access>
                            <enumeratedValues>
                                <enumeratedValue>
                                    <name>0</name>
                                    <description>No effect on output</description>
                                    <value>#0</value>
                                </enumeratedValue>
                                <enumeratedValue>
                                    <name>1</name>
                                    <description>Low output</description>
                                    <value>#1</value>
                                </enumeratedValue>
                            </enumeratedValues>
                        </field>
                        <field>
                            <name>PORR10</name>
                            <description>Pmn Output Reset</description>
                            <lsb>26</lsb>
                            <msb>26</msb>
                            <access>write-only</access>
                            <enumeratedValues>
                                <enumeratedValue>
                                    <name>0</name>
                                    <description>No effect on output</description>
                                    <value>#0</value>
                                </enumeratedValue>
                                <enumeratedValue>
                                    <name>1</name>
                                    <description>Low output</description>
                                    <value>#1</value>
                                </enumeratedValue>
                            </enumeratedValues>
                        </field>
                        <field>
                            <name>PORR11</name>
                            <description>Pmn Output Reset</description>
                            <lsb>27</lsb>
                            <msb>27</msb>
                            <access>write-only</access>
                            <enumeratedValues>
                                <enumeratedValue>
                                    <name>0</name>
                                    <description>No effect on output</description>
                                    <value>#0</value>
                                </enumeratedValue>
                                <enumeratedValue>
                                    <name>1</name>
                                    <description>Low output</description>
                                    <value>#1</value>
                                </enumeratedValue>
                            </enumeratedValues>
                        </field>
                        <field>
                            <name>PORR12</name>
                            <description>Pmn Output Reset</description>
                            <lsb>28</lsb>
                            <msb>28</msb>
                            <access>write-only</access>
                            <enumeratedValues>
                                <enumeratedValue>
                                    <name>0</name>
                                    <description>No effect on output</description>
                                    <value>#0</value>
                                </enumeratedValue>
                                <enumeratedValue>
                                    <name>1</name>
                                    <description>Low output</description>
                                    <value>#1</value>
                                </enumeratedValue>
                            </enumeratedValues>
                        </field>
                        <field>
                            <name>PORR13</name>
                            <description>Pmn Output Reset</description>
                            <lsb>29</lsb>
                            <msb>29</msb>
                            <access>write-only</access>
                            <enumeratedValues>
                                <enumeratedValue>
                                    <name>0</name>
                                    <description>No effect on output</description>
                                    <value>#0</value>
                                </enumeratedValue>
                                <enumeratedValue>
                                    <name>1</name>
                                    <description>Low output</description>
                                    <value>#1</value>
                                </enumeratedValue>
                            </enumeratedValues>
                        </field>
                        <field>
                            <name>PORR14</name>
                            <description>Pmn Output Reset</description>
                            <lsb>30</lsb>
                            <msb>30</msb>
                            <access>write-only</access>
                            <enumeratedValues>
                                <enumeratedValue>
                                    <name>0</name>
                                    <description>No effect on output</description>
                                    <value>#0</value>
                                </enumeratedValue>
                                <enumeratedValue>
                                    <name>1</name>
                                    <description>Low output</description>
                                    <value>#1</value>
                                </enumeratedValue>
                            </enumeratedValues>
                        </field>
                        <field>
                            <name>PORR15</name>
                            <description>Pmn Output Reset</description>
                            <lsb>31</lsb>
                            <msb>31</msb>
                            <access>write-only</access>
                            <enumeratedValues>
                                <enumeratedValue>
                                    <name>0</name>
                                    <description>No effect on output</description>
                                    <value>#0</value>
                                </enumeratedValue>
                                <enumeratedValue>
                                    <name>1</name>
                                    <description>Low output</description>
                                    <value>#1</value>
                                </enumeratedValue>
                            </enumeratedValues>
                        </field>
                    </fields>
                </register>
                <register>
                    <name>POSR</name>
                    <description>Port Control Register 3</description>
                    <alternateRegister>PCNTR3</alternateRegister>
                    <addressOffset>0x008</addressOffset>
                    <size>16</size>
                    <access>write-only</access>
                    <resetValue>0x0000</resetValue>
                    <resetMask>0xffff</resetMask>
                    <fields>
                        <field>
                            <name>PORR00</name>
                            <description>Pmn Output Reset</description>
                            <lsb>0</lsb>
                            <msb>0</msb>
                            <access>write-only</access>
                            <enumeratedValues>
                                <enumeratedValue>
                                    <name>0</name>
                                    <description>No effect on output</description>
                                    <value>#0</value>
                                </enumeratedValue>
                                <enumeratedValue>
                                    <name>1</name>
                                    <description>Low output</description>
                                    <value>#1</value>
                                </enumeratedValue>
                            </enumeratedValues>
                        </field>
                        <field>
                            <name>PORR01</name>
                            <description>Pmn Output Reset</description>
                            <lsb>1</lsb>
                            <msb>1</msb>
                            <access>write-only</access>
                            <enumeratedValues>
                                <enumeratedValue>
                                    <name>0</name>
                                    <description>No effect on output</description>
                                    <value>#0</value>
                                </enumeratedValue>
                                <enumeratedValue>
                                    <name>1</name>
                                    <description>Low output</description>
                                    <value>#1</value>
                                </enumeratedValue>
                            </enumeratedValues>
                        </field>
                        <field>
                            <name>PORR02</name>
                            <description>Pmn Output Reset</description>
                            <lsb>2</lsb>
                            <msb>2</msb>
                            <access>write-only</access>
                            <enumeratedValues>
                                <enumeratedValue>
                                    <name>0</name>
                                    <description>No effect on output</description>
                                    <value>#0</value>
                                </enumeratedValue>
                                <enumeratedValue>
                                    <name>1</name>
                                    <description>Low output</description>
                                    <value>#1</value>
                                </enumeratedValue>
                            </enumeratedValues>
                        </field>
                        <field>
                            <name>PORR03</name>
                            <description>Pmn Output Reset</description>
                            <lsb>3</lsb>
                            <msb>3</msb>
                            <access>write-only</access>
                            <enumeratedValues>
                                <enumeratedValue>
                                    <name>0</name>
                                    <description>No effect on output</description>
                                    <value>#0</value>
                                </enumeratedValue>
                                <enumeratedValue>
                                    <name>1</name>
                                    <description>Low output</description>
                                    <value>#1</value>
                                </enumeratedValue>
                            </enumeratedValues>
                        </field>
                        <field>
                            <name>PORR04</name>
                            <description>Pmn Output Reset</description>
                            <lsb>4</lsb>
                            <msb>4</msb>
                            <access>write-only</access>
                            <enumeratedValues>
                                <enumeratedValue>
                                    <name>0</name>
                                    <description>No effect on output</description>
                                    <value>#0</value>
                                </enumeratedValue>
                                <enumeratedValue>
                                    <name>1</name>
                                    <description>Low output</description>
                                    <value>#1</value>
                                </enumeratedValue>
                            </enumeratedValues>
                        </field>
                        <field>
                            <name>PORR05</name>
                            <description>Pmn Output Reset</description>
                            <lsb>5</lsb>
                            <msb>5</msb>
                            <access>write-only</access>
                            <enumeratedValues>
                                <enumeratedValue>
                                    <name>0</name>
                                    <description>No effect on output</description>
                                    <value>#0</value>
                                </enumeratedValue>
                                <enumeratedValue>
                                    <name>1</name>
                                    <description>Low output</description>
                                    <value>#1</value>
                                </enumeratedValue>
                            </enumeratedValues>
                        </field>
                        <field>
                            <name>PORR06</name>
                            <description>Pmn Output Reset</description>
                            <lsb>6</lsb>
                            <msb>6</msb>
                            <access>write-only</access>
                            <enumeratedValues>
                                <enumeratedValue>
                                    <name>0</name>
                                    <description>No effect on output</description>
                                    <value>#0</value>
                                </enumeratedValue>
                                <enumeratedValue>
                                    <name>1</name>
                                    <description>Low output</description>
                                    <value>#1</value>
                                </enumeratedValue>
                            </enumeratedValues>
                        </field>
                        <field>
                            <name>PORR07</name>
                            <description>Pmn Output Reset</description>
                            <lsb>7</lsb>
                            <msb>7</msb>
                            <access>write-only</access>
                            <enumeratedValues>
                                <enumeratedValue>
                                    <name>0</name>
                                    <description>No effect on output</description>
                                    <value>#0</value>
                                </enumeratedValue>
                                <enumeratedValue>
                                    <name>1</name>
                                    <description>Low output</description>
                                    <value>#1</value>
                                </enumeratedValue>
                            </enumeratedValues>
                        </field>
                        <field>
                            <name>PORR08</name>
                            <description>Pmn Output Reset</description>
                            <lsb>8</lsb>
                            <msb>8</msb>
                            <access>write-only</access>
                            <enumeratedValues>
                                <enumeratedValue>
                                    <name>0</name>
                                    <description>No effect on output</description>
                                    <value>#0</value>
                                </enumeratedValue>
                                <enumeratedValue>
                                    <name>1</name>
                                    <description>Low output</description>
                                    <value>#1</value>
                                </enumeratedValue>
                            </enumeratedValues>
                        </field>
                        <field>
                            <name>PORR09</name>
                            <description>Pmn Output Reset</description>
                            <lsb>9</lsb>
                            <msb>9</msb>
                            <access>write-only</access>
                            <enumeratedValues>
                                <enumeratedValue>
                                    <name>0</name>
                                    <description>No effect on output</description>
                                    <value>#0</value>
                                </enumeratedValue>
                                <enumeratedValue>
                                    <name>1</name>
                                    <description>Low output</description>
                                    <value>#1</value>
                                </enumeratedValue>
                            </enumeratedValues>
                        </field>
                        <field>
                            <name>PORR10</name>
                            <description>Pmn Output Reset</description>
                            <lsb>10</lsb>
                            <msb>10</msb>
                            <access>write-only</access>
                            <enumeratedValues>
                                <enumeratedValue>
                                    <name>0</name>
                                    <description>No effect on output</description>
                                    <value>#0</value>
                                </enumeratedValue>
                                <enumeratedValue>
                                    <name>1</name>
                                    <description>Low output</description>
                                    <value>#1</value>
                                </enumeratedValue>
                            </enumeratedValues>
                        </field>
                        <field>
                            <name>PORR11</name>
                            <description>Pmn Output Reset</description>
                            <lsb>11</lsb>
                            <msb>11</msb>
                            <access>write-only</access>
                            <enumeratedValues>
                                <enumeratedValue>
                                    <name>0</name>
                                    <description>No effect on output</description>
                                    <value>#0</value>
                                </enumeratedValue>
                                <enumeratedValue>
                                    <name>1</name>
                                    <description>Low output</description>
                                    <value>#1</value>
                                </enumeratedValue>
                            </enumeratedValues>
                        </field>
                        <field>
                            <name>PORR12</name>
                            <description>Pmn Output Reset</description>
                            <lsb>12</lsb>
                            <msb>12</msb>
                            <access>write-only</access>
                            <enumeratedValues>
                                <enumeratedValue>
                                    <name>0</name>
                                    <description>No effect on output</description>
                                    <value>#0</value>
                                </enumeratedValue>
                                <enumeratedValue>
                                    <name>1</name>
                                    <description>Low output</description>
                                    <value>#1</value>
                                </enumeratedValue>
                            </enumeratedValues>
                        </field>
                        <field>
                            <name>PORR13</name>
                            <description>Pmn Output Reset</description>
                            <lsb>13</lsb>
                            <msb>13</msb>
                            <access>write-only</access>
                            <enumeratedValues>
                                <enumeratedValue>
                                    <name>0</name>
                                    <description>No effect on output</description>
                                    <value>#0</value>
                                </enumeratedValue>
                                <enumeratedValue>
                                    <name>1</name>
                                    <description>Low output</description>
                                    <value>#1</value>
                                </enumeratedValue>
                            </enumeratedValues>
                        </field>
                        <field>
                            <name>PORR14</name>
                            <description>Pmn Output Reset</description>
                            <lsb>14</lsb>
                            <msb>14</msb>
                            <access>write-only</access>
                            <enumeratedValues>
                                <enumeratedValue>
                                    <name>0</name>
                                    <description>No effect on output</description>
                                    <value>#0</value>
                                </enumeratedValue>
                                <enumeratedValue>
                                    <name>1</name>
                                    <description>Low output</description>
                                    <value>#1</value>
                                </enumeratedValue>
                            </enumeratedValues>
                        </field>
                        <field>
                            <name>PORR15</name>
                            <description>Pmn Output Reset</description>
                            <lsb>15</lsb>
                            <msb>15</msb>
                            <access>write-only</access>
                            <enumeratedValues>
                                <enumeratedValue>
                                    <name>0</name>
                                    <description>No effect on output</description>
                                    <value>#0</value>
                                </enumeratedValue>
                                <enumeratedValue>
                                    <name>1</name>
                                    <description>Low output</description>
                                    <value>#1</value>
                                </enumeratedValue>
                            </enumeratedValues>
                        </field>
                    </fields>
                </register>
                <register>
                    <name>PORR</name>
                    <description>Port Control Register 3</description>
                    <alternateRegister>PCNTR3</alternateRegister>
                    <addressOffset>0x00A</addressOffset>
                    <size>16</size>
                    <access>write-only</access>
                    <resetValue>0x0000</resetValue>
                    <resetMask>0xffff</resetMask>
                    <fields>
                        <field>
                            <name>POSR00</name>
                            <description>Pmn Output Set</description>
                            <lsb>0</lsb>
                            <msb>0</msb>
                            <access>write-only</access>
                            <enumeratedValues>
                                <enumeratedValue>
                                    <name>0</name>
                                    <description>No effect on output</description>
                                    <value>#0</value>
                                </enumeratedValue>
                                <enumeratedValue>
                                    <name>1</name>
                                    <description>High output</description>
                                    <value>#1</value>
                                </enumeratedValue>
                            </enumeratedValues>
                        </field>
                        <field>
                            <name>POSR01</name>
                            <description>Pmn Output Set</description>
                            <lsb>1</lsb>
                            <msb>1</msb>
                            <access>write-only</access>
                            <enumeratedValues>
                                <enumeratedValue>
                                    <name>0</name>
                                    <description>No effect on output</description>
                                    <value>#0</value>
                                </enumeratedValue>
                                <enumeratedValue>
                                    <name>1</name>
                                    <description>High output</description>
                                    <value>#1</value>
                                </enumeratedValue>
                            </enumeratedValues>
                        </field>
                        <field>
                            <name>POSR02</name>
                            <description>Pmn Output Set</description>
                            <lsb>2</lsb>
                            <msb>2</msb>
                            <access>write-only</access>
                            <enumeratedValues>
                                <enumeratedValue>
                                    <name>0</name>
                                    <description>No effect on output</description>
                                    <value>#0</value>
                                </enumeratedValue>
                                <enumeratedValue>
                                    <name>1</name>
                                    <description>High output</description>
                                    <value>#1</value>
                                </enumeratedValue>
                            </enumeratedValues>
                        </field>
                        <field>
                            <name>POSR03</name>
                            <description>Pmn Output Set</description>
                            <lsb>3</lsb>
                            <msb>3</msb>
                            <access>write-only</access>
                            <enumeratedValues>
                                <enumeratedValue>
                                    <name>0</name>
                                    <description>No effect on output</description>
                                    <value>#0</value>
                                </enumeratedValue>
                                <enumeratedValue>
                                    <name>1</name>
                                    <description>High output</description>
                                    <value>#1</value>
                                </enumeratedValue>
                            </enumeratedValues>
                        </field>
                        <field>
                            <name>POSR04</name>
                            <description>Pmn Output Set</description>
                            <lsb>4</lsb>
                            <msb>4</msb>
                            <access>write-only</access>
                            <enumeratedValues>
                                <enumeratedValue>
                                    <name>0</name>
                                    <description>No effect on output</description>
                                    <value>#0</value>
                                </enumeratedValue>
                                <enumeratedValue>
                                    <name>1</name>
                                    <description>High output</description>
                                    <value>#1</value>
                                </enumeratedValue>
                            </enumeratedValues>
                        </field>
                        <field>
                            <name>POSR05</name>
                            <description>Pmn Output Set</description>
                            <lsb>5</lsb>
                            <msb>5</msb>
                            <access>write-only</access>
                            <enumeratedValues>
                                <enumeratedValue>
                                    <name>0</name>
                                    <description>No effect on output</description>
                                    <value>#0</value>
                                </enumeratedValue>
                                <enumeratedValue>
                                    <name>1</name>
                                    <description>High output</description>
                                    <value>#1</value>
                                </enumeratedValue>
                            </enumeratedValues>
                        </field>
                        <field>
                            <name>POSR06</name>
                            <description>Pmn Output Set</description>
                            <lsb>6</lsb>
                            <msb>6</msb>
                            <access>write-only</access>
                            <enumeratedValues>
                                <enumeratedValue>
                                    <name>0</name>
                                    <description>No effect on output</description>
                                    <value>#0</value>
                                </enumeratedValue>
                                <enumeratedValue>
                                    <name>1</name>
                                    <description>High output</description>
                                    <value>#1</value>
                                </enumeratedValue>
                            </enumeratedValues>
                        </field>
                        <field>
                            <name>POSR07</name>
                            <description>Pmn Output Set</description>
                            <lsb>7</lsb>
                            <msb>7</msb>
                            <access>write-only</access>
                            <enumeratedValues>
                                <enumeratedValue>
                                    <name>0</name>
                                    <description>No effect on output</description>
                                    <value>#0</value>
                                </enumeratedValue>
                                <enumeratedValue>
                                    <name>1</name>
                                    <description>High output</description>
                                    <value>#1</value>
                                </enumeratedValue>
                            </enumeratedValues>
                        </field>
                        <field>
                            <name>POSR08</name>
                            <description>Pmn Output Set</description>
                            <lsb>8</lsb>
                            <msb>8</msb>
                            <access>write-only</access>
                            <enumeratedValues>
                                <enumeratedValue>
                                    <name>0</name>
                                    <description>No effect on output</description>
                                    <value>#0</value>
                                </enumeratedValue>
                                <enumeratedValue>
                                    <name>1</name>
                                    <description>High output</description>
                                    <value>#1</value>
                                </enumeratedValue>
                            </enumeratedValues>
                        </field>
                        <field>
                            <name>POSR09</name>
                            <description>Pmn Output Set</description>
                            <lsb>9</lsb>
                            <msb>9</msb>
                            <access>write-only</access>
                            <enumeratedValues>
                                <enumeratedValue>
                                    <name>0</name>
                                    <description>No effect on output</description>
                                    <value>#0</value>
                                </enumeratedValue>
                                <enumeratedValue>
                                    <name>1</name>
                                    <description>High output</description>
                                    <value>#1</value>
                                </enumeratedValue>
                            </enumeratedValues>
                        </field>
                        <field>
                            <name>POSR10</name>
                            <description>Pmn Output Set</description>
                            <lsb>10</lsb>
                            <msb>10</msb>
                            <access>write-only</access>
                            <enumeratedValues>
                                <enumeratedValue>
                                    <name>0</name>
                                    <description>No effect on output</description>
                                    <value>#0</value>
                                </enumeratedValue>
                                <enumeratedValue>
                                    <name>1</name>
                                    <description>High output</description>
                                    <value>#1</value>
                                </enumeratedValue>
                            </enumeratedValues>
                        </field>
                        <field>
                            <name>POSR11</name>
                            <description>Pmn Output Set</description>
                            <lsb>11</lsb>
                            <msb>11</msb>
                            <access>write-only</access>
                            <enumeratedValues>
                                <enumeratedValue>
                                    <name>0</name>
                                    <description>No effect on output</description>
                                    <value>#0</value>
                                </enumeratedValue>
                                <enumeratedValue>
                                    <name>1</name>
                                    <description>High output</description>
                                    <value>#1</value>
                                </enumeratedValue>
                            </enumeratedValues>
                        </field>
                        <field>
                            <name>POSR12</name>
                            <description>Pmn Output Set</description>
                            <lsb>12</lsb>
                            <msb>12</msb>
                            <access>write-only</access>
                            <enumeratedValues>
                                <enumeratedValue>
                                    <name>0</name>
                                    <description>No effect on output</description>
                                    <value>#0</value>
                                </enumeratedValue>
                                <enumeratedValue>
                                    <name>1</name>
                                    <description>High output</description>
                                    <value>#1</value>
                                </enumeratedValue>
                            </enumeratedValues>
                        </field>
                        <field>
                            <name>POSR13</name>
                            <description>Pmn Output Set</description>
                            <lsb>13</lsb>
                            <msb>13</msb>
                            <access>write-only</access>
                            <enumeratedValues>
                                <enumeratedValue>
                                    <name>0</name>
                                    <description>No effect on output</description>
                                    <value>#0</value>
                                </enumeratedValue>
                                <enumeratedValue>
                                    <name>1</name>
                                    <description>High output</description>
                                    <value>#1</value>
                                </enumeratedValue>
                            </enumeratedValues>
                        </field>
                        <field>
                            <name>POSR14</name>
                            <description>Pmn Output Set</description>
                            <lsb>14</lsb>
                            <msb>14</msb>
                            <access>write-only</access>
                            <enumeratedValues>
                                <enumeratedValue>
                                    <name>0</name>
                                    <description>No effect on output</description>
                                    <value>#0</value>
                                </enumeratedValue>
                                <enumeratedValue>
                                    <name>1</name>
                                    <description>High output</description>
                                    <value>#1</value>
                                </enumeratedValue>
                            </enumeratedValues>
                        </field>
                        <field>
                            <name>POSR15</name>
                            <description>Pmn Output Set</description>
                            <lsb>15</lsb>
                            <msb>15</msb>
                            <access>write-only</access>
                            <enumeratedValues>
                                <enumeratedValue>
                                    <name>0</name>
                                    <description>No effect on output</description>
                                    <value>#0</value>
                                </enumeratedValue>
                                <enumeratedValue>
                                    <name>1</name>
                                    <description>High output</description>
                                    <value>#1</value>
                                </enumeratedValue>
                            </enumeratedValues>
                        </field>
                    </fields>
                </register>
            </registers>
        </peripheral>
        <peripheral>
            <name>PORTB_NS</name>
            <description>Pmn Pin FunctionPort B Control RegistersPmn Pin Function Control Register</description>
            <baseAddress>0x50400160</baseAddress>
            <addressBlock>
                <offset>0x00</offset>
                <size>8</size>
                <usage>registers</usage>
            </addressBlock>
            <addressBlock>
                <offset>0x08</offset>
                <size>4</size>
                <usage>registers</usage>
            </addressBlock>
            <registers>
                <register>
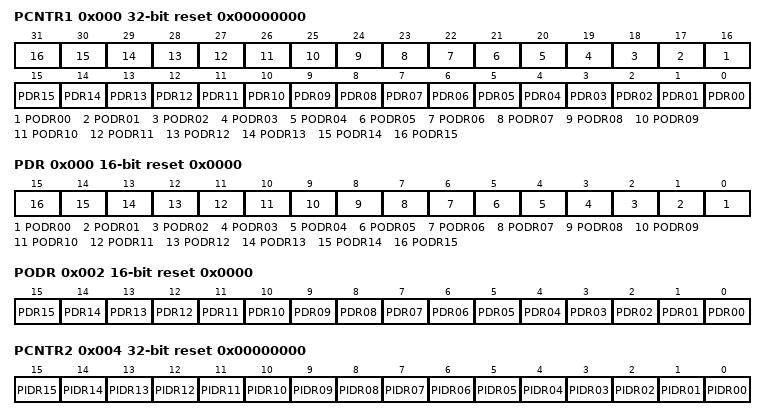
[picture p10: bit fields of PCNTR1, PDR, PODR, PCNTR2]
                    <name>PCNTR1</name>
                    <description>Port Control Register 1</description>
                    <addressOffset>0x000</addressOffset>
                    <size>32</size>
                    <access>read-write</access>
                    <resetValue>0x00000000</resetValue>
                    <resetMask>0xffffffff</resetMask>
                    <fields>
                        <field>
                            <name>PDR00</name>
                            <description>Pmn Direction</description>
                            <lsb>0</lsb>
                            <msb>0</msb>
                            <access>read-write</access>
                            <enumeratedValues>
                                <enumeratedValue>
                                    <name>0</name>
                                    <description>Input (functions as an input pin)</description>
                                    <value>#0</value>
                                </enumeratedValue>
                                <enumeratedValue>
                                    <name>1</name>
                                    <description>Output (functions as an output pin)</description>
                                    <value>#1</value>
                                </enumeratedValue>
                            </enumeratedValues>
                        </field>
                        <field>
                            <name>PDR01</name>
                            <description>Pmn Direction</description>
                            <lsb>1</lsb>
                            <msb>1</msb>
                            <access>read-write</access>
                            <enumeratedValues>
                                <enumeratedValue>
                                    <name>0</name>
                                    <description>Input (functions as an input pin)</description>
                                    <value>#0</value>
                                </enumeratedValue>
                                <enumeratedValue>
                                    <name>1</name>
                                    <description>Output (functions as an output pin)</description>
                                    <value>#1</value>
                                </enumeratedValue>
                            </enumeratedValues>
                        </field>
                        <field>
                            <name>PDR02</name>
                            <description>Pmn Direction</description>
                            <lsb>2</lsb>
                            <msb>2</msb>
                            <access>read-write</access>
                            <enumeratedValues>
                                <enumeratedValue>
                                    <name>0</name>
                                    <description>Input (functions as an input pin)</description>
                                    <value>#0</value>
                                </enumeratedValue>
                                <enumeratedValue>
                                    <name>1</name>
                                    <description>Output (functions as an output pin)</description>
                                    <value>#1</value>
                                </enumeratedValue>
                            </enumeratedValues>
                        </field>
                        <field>
                            <name>PDR03</name>
                            <description>Pmn Direction</description>
                            <lsb>3</lsb>
                            <msb>3</msb>
                            <access>read-write</access>
                            <enumeratedValues>
                                <enumeratedValue>
                                    <name>0</name>
                                    <description>Input (functions as an input pin)</description>
                                    <value>#0</value>
                                </enumeratedValue>
                                <enumeratedValue>
                                    <name>1</name>
                                    <description>Output (functions as an output pin)</description>
                                    <value>#1</value>
                                </enumeratedValue>
                            </enumeratedValues>
                        </field>
                        <field>
                            <name>PDR04</name>
                            <description>Pmn Direction</description>
                            <lsb>4</lsb>
                            <msb>4</msb>
                            <access>read-write</access>
                            <enumeratedValues>
                                <enumeratedValue>
                                    <name>0</name>
                                    <description>Input (functions as an input pin)</description>
                                    <value>#0</value>
                                </enumeratedValue>
                                <enumeratedValue>
                                    <name>1</name>
                                    <description>Output (functions as an output pin)</description>
                                    <value>#1</value>
                                </enumeratedValue>
                            </enumeratedValues>
                        </field>
                        <field>
                            <name>PDR05</name>
                            <description>Pmn Direction</description>
                            <lsb>5</lsb>
                            <msb>5</msb>
                            <access>read-write</access>
                            <enumeratedValues>
                                <enumeratedValue>
                                    <name>0</name>
                                    <description>Input (functions as an input pin)</description>
                                    <value>#0</value>
                                </enumeratedValue>
                                <enumeratedValue>
                                    <name>1</name>
                                    <description>Output (functions as an output pin)</description>
                                    <value>#1</value>
                                </enumeratedValue>
                            </enumeratedValues>
                        </field>
                        <field>
                            <name>PDR06</name>
                            <description>Pmn Direction</description>
                            <lsb>6</lsb>
                            <msb>6</msb>
                            <access>read-write</access>
                            <enumeratedValues>
                                <enumeratedValue>
                                    <name>0</name>
                                    <description>Input (functions as an input pin)</description>
                                    <value>#0</value>
                                </enumeratedValue>
                                <enumeratedValue>
                                    <name>1</name>
                                    <description>Output (functions as an output pin)</description>
                                    <value>#1</value>
                                </enumeratedValue>
                            </enumeratedValues>
                        </field>
                        <field>
                            <name>PDR07</name>
                            <description>Pmn Direction</description>
                            <lsb>7</lsb>
                            <msb>7</msb>
                            <access>read-write</access>
                            <enumeratedValues>
                                <enumeratedValue>
                                    <name>0</name>
                                    <description>Input (functions as an input pin)</description>
                                    <value>#0</value>
                                </enumeratedValue>
                                <enumeratedValue>
                                    <name>1</name>
                                    <description>Output (functions as an output pin)</description>
                                    <value>#1</value>
                                </enumeratedValue>
                            </enumeratedValues>
                        </field>
                        <field>
                            <name>PDR08</name>
                            <description>Pmn Direction</description>
                            <lsb>8</lsb>
                            <msb>8</msb>
                            <access>read-write</access>
                            <enumeratedValues>
                                <enumeratedValue>
                                    <name>0</name>
                                    <description>Input (functions as an input pin)</description>
                                    <value>#0</value>
                                </enumeratedValue>
                                <enumeratedValue>
                                    <name>1</name>
                                    <description>Output (functions as an output pin)</description>
                                    <value>#1</value>
                                </enumeratedValue>
                            </enumeratedValues>
                        </field>
                        <field>
                            <name>PDR09</name>
                            <description>Pmn Direction</description>
                            <lsb>9</lsb>
                            <msb>9</msb>
                            <access>read-write</access>
                            <enumeratedValues>
                                <enumeratedValue>
                                    <name>0</name>
                                    <description>Input (functions as an input pin)</description>
                                    <value>#0</value>
                                </enumeratedValue>
                                <enumeratedValue>
                                    <name>1</name>
                                    <description>Output (functions as an output pin)</description>
                                    <value>#1</value>
                                </enumeratedValue>
                            </enumeratedValues>
                        </field>
                        <field>
                            <name>PDR10</name>
                            <description>Pmn Direction</description>
                            <lsb>10</lsb>
                            <msb>10</msb>
                            <access>read-write</access>
                            <enumeratedValues>
                                <enumeratedValue>
                                    <name>0</name>
                                    <description>Input (functions as an input pin)</description>
                                    <value>#0</value>
                                </enumeratedValue>
                                <enumeratedValue>
                                    <name>1</name>
                                    <description>Output (functions as an output pin)</description>
                                    <value>#1</value>
                                </enumeratedValue>
                            </enumeratedValues>
                        </field>
                        <field>
                            <name>PDR11</name>
                            <description>Pmn Direction</description>
                            <lsb>11</lsb>
                            <msb>11</msb>
                            <access>read-write</access>
                            <enumeratedValues>
                                <enumeratedValue>
                                    <name>0</name>
                                    <description>Input (functions as an input pin)</description>
                                    <value>#0</value>
                                </enumeratedValue>
                                <enumeratedValue>
                                    <name>1</name>
                                    <description>Output (functions as an output pin)</description>
                                    <value>#1</value>
                                </enumeratedValue>
                            </enumeratedValues>
                        </field>
                        <field>
                            <name>PDR12</name>
                            <description>Pmn Direction</description>
                            <lsb>12</lsb>
                            <msb>12</msb>
                            <access>read-write</access>
                            <enumeratedValues>
                                <enumeratedValue>
                                    <name>0</name>
                                    <description>Input (functions as an input pin)</description>
                                    <value>#0</value>
                                </enumeratedValue>
                                <enumeratedValue>
                                    <name>1</name>
                                    <description>Output (functions as an output pin)</description>
                                    <value>#1</value>
                                </enumeratedValue>
                            </enumeratedValues>
                        </field>
                        <field>
                            <name>PDR13</name>
                            <description>Pmn Direction</description>
                            <lsb>13</lsb>
                            <msb>13</msb>
                            <access>read-write</access>
                            <enumeratedValues>
                                <enumeratedValue>
                                    <name>0</name>
                                    <description>Input (functions as an input pin)</description>
                                    <value>#0</value>
                                </enumeratedValue>
                                <enumeratedValue>
                                    <name>1</name>
                                    <description>Output (functions as an output pin)</description>
                                    <value>#1</value>
                                </enumeratedValue>
                            </enumeratedValues>
                        </field>
                        <field>
                            <name>PDR14</name>
                            <description>Pmn Direction</description>
                            <lsb>14</lsb>
                            <msb>14</msb>
                            <access>read-write</access>
                            <enumeratedValues>
                                <enumeratedValue>
                                    <name>0</name>
                                    <description>Input (functions as an input pin)</description>
                                    <value>#0</value>
                                </enumeratedValue>
                                <enumeratedValue>
                                    <name>1</name>
                                    <description>Output (functions as an output pin)</description>
                                    <value>#1</value>
                                </enumeratedValue>
                            </enumeratedValues>
                        </field>
                        <field>
                            <name>PDR15</name>
                            <description>Pmn Direction</description>
                            <lsb>15</lsb>
                            <msb>15</msb>
                            <access>read-write</access>
                            <enumeratedValues>
                                <enumeratedValue>
                                    <name>0</name>
                                    <description>Input (functions as an input pin)</description>
                                    <value>#0</value>
                                </enumeratedValue>
                                <enumeratedValue>
                                    <name>1</name>
                                    <description>Output (functions as an output pin)</description>
                                    <value>#1</value>
                                </enumeratedValue>
                            </enumeratedValues>
                        </field>
                        <field>
                            <name>PODR00</name>
                            <description>Pmn Output Data</description>
                            <lsb>16</lsb>
                            <msb>16</msb>
                            <access>read-write</access>
                            <enumeratedValues>
                                <enumeratedValue>
                                    <name>0</name>
                                    <description>Low output</description>
                                    <value>#0</value>
                                </enumeratedValue>
                                <enumeratedValue>
                                    <name>1</name>
                                    <description>High output</description>
                                    <value>#1</value>
                                </enumeratedValue>
                            </enumeratedValues>
                        </field>
                        <field>
                            <name>PODR01</name>
                            <description>Pmn Output Data</description>
                            <lsb>17</lsb>
                            <msb>17</msb>
                            <access>read-write</access>
                            <enumeratedValues>
                                <enumeratedValue>
                                    <name>0</name>
                                    <description>Low output</description>
                                    <value>#0</value>
                                </enumeratedValue>
                                <enumeratedValue>
                                    <name>1</name>
                                    <description>High output</description>
                                    <value>#1</value>
                                </enumeratedValue>
                            </enumeratedValues>
                        </field>
                        <field>
                            <name>PODR02</name>
                            <description>Pmn Output Data</description>
                            <lsb>18</lsb>
                            <msb>18</msb>
                            <access>read-write</access>
                            <enumeratedValues>
                                <enumeratedValue>
                                    <name>0</name>
                                    <description>Low output</description>
                                    <value>#0</value>
                                </enumeratedValue>
                                <enumeratedValue>
                                    <name>1</name>
                                    <description>High output</description>
                                    <value>#1</value>
                                </enumeratedValue>
                            </enumeratedValues>
                        </field>
                        <field>
                            <name>PODR03</name>
                            <description>Pmn Output Data</description>
                            <lsb>19</lsb>
                            <msb>19</msb>
                            <access>read-write</access>
                            <enumeratedValues>
                                <enumeratedValue>
                                    <name>0</name>
                                    <description>Low output</description>
                                    <value>#0</value>
                                </enumeratedValue>
                                <enumeratedValue>
                                    <name>1</name>
                                    <description>High output</description>
                                    <value>#1</value>
                                </enumeratedValue>
                            </enumeratedValues>
                        </field>
                        <field>
                            <name>PODR04</name>
                            <description>Pmn Output Data</description>
                            <lsb>20</lsb>
                            <msb>20</msb>
                            <access>read-write</access>
                            <enumeratedValues>
                                <enumeratedValue>
                                    <name>0</name>
                                    <description>Low output</description>
                                    <value>#0</value>
                                </enumeratedValue>
                                <enumeratedValue>
                                    <name>1</name>
                                    <description>High output</description>
                                    <value>#1</value>
                                </enumeratedValue>
                            </enumeratedValues>
                        </field>
                        <field>
                            <name>PODR05</name>
                            <description>Pmn Output Data</description>
                            <lsb>21</lsb>
                            <msb>21</msb>
                            <access>read-write</access>
                            <enumeratedValues>
                                <enumeratedValue>
                                    <name>0</name>
                                    <description>Low output</description>
                                    <value>#0</value>
                                </enumeratedValue>
                                <enumeratedValue>
                                    <name>1</name>
                                    <description>High output</description>
                                    <value>#1</value>
                                </enumeratedValue>
                            </enumeratedValues>
                        </field>
                        <field>
                            <name>PODR06</name>
                            <description>Pmn Output Data</description>
                            <lsb>22</lsb>
                            <msb>22</msb>
                            <access>read-write</access>
                            <enumeratedValues>
                                <enumeratedValue>
                                    <name>0</name>
                                    <description>Low output</description>
                                    <value>#0</value>
                                </enumeratedValue>
                                <enumeratedValue>
                                    <name>1</name>
                                    <description>High output</description>
                                    <value>#1</value>
                                </enumeratedValue>
                            </enumeratedValues>
                        </field>
                        <field>
                            <name>PODR07</name>
                            <description>Pmn Output Data</description>
                            <lsb>23</lsb>
                            <msb>23</msb>
                            <access>read-write</access>
                            <enumeratedValues>
                                <enumeratedValue>
                                    <name>0</name>
                                    <description>Low output</description>
                                    <value>#0</value>
                                </enumeratedValue>
                                <enumeratedValue>
                                    <name>1</name>
                                    <description>High output</description>
                                    <value>#1</value>
                                </enumeratedValue>
                            </enumeratedValues>
                        </field>
                        <field>
                            <name>PODR08</name>
                            <description>Pmn Output Data</description>
                            <lsb>24</lsb>
                            <msb>24</msb>
                            <access>read-write</access>
                            <enumeratedValues>
                                <enumeratedValue>
                                    <name>0</name>
                                    <description>Low output</description>
                                    <value>#0</value>
                                </enumeratedValue>
                                <enumeratedValue>
                                    <name>1</name>
                                    <description>High output</description>
                                    <value>#1</value>
                                </enumeratedValue>
                            </enumeratedValues>
                        </field>
                        <field>
                            <name>PODR09</name>
                            <description>Pmn Output Data</description>
                            <lsb>25</lsb>
                            <msb>25</msb>
                            <access>read-write</access>
                            <enumeratedValues>
                                <enumeratedValue>
                                    <name>0</name>
                                    <description>Low output</description>
                                    <value>#0</value>
                                </enumeratedValue>
                                <enumeratedValue>
                                    <name>1</name>
                                    <description>High output</description>
                                    <value>#1</value>
                                </enumeratedValue>
                            </enumeratedValues>
                        </field>
                        <field>
                            <name>PODR10</name>
                            <description>Pmn Output Data</description>
                            <lsb>26</lsb>
                            <msb>26</msb>
                            <access>read-write</access>
                            <enumeratedValues>
                                <enumeratedValue>
                                    <name>0</name>
                                    <description>Low output</description>
                                    <value>#0</value>
                                </enumeratedValue>
                                <enumeratedValue>
                                    <name>1</name>
                                    <description>High output</description>
                                    <value>#1</value>
                                </enumeratedValue>
                            </enumeratedValues>
                        </field>
                        <field>
                            <name>PODR11</name>
                            <description>Pmn Output Data</description>
                            <lsb>27</lsb>
                            <msb>27</msb>
                            <access>read-write</access>
                            <enumeratedValues>
                                <enumeratedValue>
                                    <name>0</name>
                                    <description>Low output</description>
                                    <value>#0</value>
                                </enumeratedValue>
                                <enumeratedValue>
                                    <name>1</name>
                                    <description>High output</description>
                                    <value>#1</value>
                                </enumeratedValue>
                            </enumeratedValues>
                        </field>
                        <field>
                            <name>PODR12</name>
                            <description>Pmn Output Data</description>
                            <lsb>28</lsb>
                            <msb>28</msb>
                            <access>read-write</access>
                            <enumeratedValues>
                                <enumeratedValue>
                                    <name>0</name>
                                    <description>Low output</description>
                                    <value>#0</value>
                                </enumeratedValue>
                                <enumeratedValue>
                                    <name>1</name>
                                    <description>High output</description>
                                    <value>#1</value>
                                </enumeratedValue>
                            </enumeratedValues>
                        </field>
                        <field>
                            <name>PODR13</name>
                            <description>Pmn Output Data</description>
                            <lsb>29</lsb>
                            <msb>29</msb>
                            <access>read-write</access>
                            <enumeratedValues>
                                <enumeratedValue>
                                    <name>0</name>
                                    <description>Low output</description>
                                    <value>#0</value>
                                </enumeratedValue>
                                <enumeratedValue>
                                    <name>1</name>
                                    <description>High output</description>
                                    <value>#1</value>
                                </enumeratedValue>
                            </enumeratedValues>
                        </field>
                        <field>
                            <name>PODR14</name>
                            <description>Pmn Output Data</description>
                            <lsb>30</lsb>
                            <msb>30</msb>
                            <access>read-write</access>
                            <enumeratedValues>
                                <enumeratedValue>
                                    <name>0</name>
                                    <description>Low output</description>
                                    <value>#0</value>
                                </enumeratedValue>
                                <enumeratedValue>
                                    <name>1</name>
                                    <description>High output</description>
                                    <value>#1</value>
                                </enumeratedValue>
                            </enumeratedValues>
                        </field>
                        <field>
                            <name>PODR15</name>
                            <description>Pmn Output Data</description>
                            <lsb>31</lsb>
                            <msb>31</msb>
                            <access>read-write</access>
                            <enumeratedValues>
                                <enumeratedValue>
                                    <name>0</name>
                                    <description>Low output</description>
                                    <value>#0</value>
                                </enumeratedValue>
                                <enumeratedValue>
                                    <name>1</name>
                                    <description>High output</description>
                                    <value>#1</value>
                                </enumeratedValue>
                            </enumeratedValues>
                        </field>
                    </fields>
                </register>
                <register>
                    <name>PDR</name>
                    <description>Port Control Register 1</description>
                    <alternateRegister>PCNTR1</alternateRegister>
                    <addressOffset>0x000</addressOffset>
                    <size>16</size>
                    <access>read-write</access>
                    <resetValue>0x0000</resetValue>
                    <resetMask>0xffff</resetMask>
                    <fields>
                        <field>
                            <name>PODR00</name>
                            <description>Pmn Output Data</description>
                            <lsb>0</lsb>
                            <msb>0</msb>
                            <access>read-write</access>
                            <enumeratedValues>
                                <enumeratedValue>
                                    <name>0</name>
                                    <description>Low output</description>
                                    <value>#0</value>
                                </enumeratedValue>
                                <enumeratedValue>
                                    <name>1</name>
                                    <description>High output</description>
                                    <value>#1</value>
                                </enumeratedValue>
                            </enumeratedValues>
                        </field>
                        <field>
                            <name>PODR01</name>
                            <description>Pmn Output Data</description>
                            <lsb>1</lsb>
                            <msb>1</msb>
                            <access>read-write</access>
                            <enumeratedValues>
                                <enumeratedValue>
                                    <name>0</name>
                                    <description>Low output</description>
                                    <value>#0</value>
                                </enumeratedValue>
                                <enumeratedValue>
                                    <name>1</name>
                                    <description>High output</description>
                                    <value>#1</value>
                                </enumeratedValue>
                            </enumeratedValues>
                        </field>
                        <field>
                            <name>PODR02</name>
                            <description>Pmn Output Data</description>
                            <lsb>2</lsb>
                            <msb>2</msb>
                            <access>read-write</access>
                            <enumeratedValues>
                                <enumeratedValue>
                                    <name>0</name>
                                    <description>Low output</description>
                                    <value>#0</value>
                                </enumeratedValue>
                                <enumeratedValue>
                                    <name>1</name>
                                    <description>High output</description>
                                    <value>#1</value>
                                </enumeratedValue>
                            </enumeratedValues>
                        </field>
                        <field>
                            <name>PODR03</name>
                            <description>Pmn Output Data</description>
                            <lsb>3</lsb>
                            <msb>3</msb>
                            <access>read-write</access>
                            <enumeratedValues>
                                <enumeratedValue>
                                    <name>0</name>
                                    <description>Low output</description>
                                    <value>#0</value>
                                </enumeratedValue>
                                <enumeratedValue>
                                    <name>1</name>
                                    <description>High output</description>
                                    <value>#1</value>
                                </enumeratedValue>
                            </enumeratedValues>
                        </field>
                        <field>
                            <name>PODR04</name>
                            <description>Pmn Output Data</description>
                            <lsb>4</lsb>
                            <msb>4</msb>
                            <access>read-write</access>
                            <enumeratedValues>
                                <enumeratedValue>
                                    <name>0</name>
                                    <description>Low output</description>
                                    <value>#0</value>
                                </enumeratedValue>
                                <enumeratedValue>
                                    <name>1</name>
                                    <description>High output</description>
                                    <value>#1</value>
                                </enumeratedValue>
                            </enumeratedValues>
                        </field>
                        <field>
                            <name>PODR05</name>
                            <description>Pmn Output Data</description>
                            <lsb>5</lsb>
                            <msb>5</msb>
                            <access>read-write</access>
                            <enumeratedValues>
                                <enumeratedValue>
                                    <name>0</name>
                                    <description>Low output</description>
                                    <value>#0</value>
                                </enumeratedValue>
                                <enumeratedValue>
                                    <name>1</name>
                                    <description>High output</description>
                                    <value>#1</value>
                                </enumeratedValue>
                            </enumeratedValues>
                        </field>
                        <field>
                            <name>PODR06</name>
                            <description>Pmn Output Data</description>
                            <lsb>6</lsb>
                            <msb>6</msb>
                            <access>read-write</access>
                            <enumeratedValues>
                                <enumeratedValue>
                                    <name>0</name>
                                    <description>Low output</description>
                                    <value>#0</value>
                                </enumeratedValue>
                                <enumeratedValue>
                                    <name>1</name>
                                    <description>High output</description>
                                    <value>#1</value>
                                </enumeratedValue>
                            </enumeratedValues>
                        </field>
                        <field>
                            <name>PODR07</name>
                            <description>Pmn Output Data</description>
                            <lsb>7</lsb>
                            <msb>7</msb>
                            <access>read-write</access>
                            <enumeratedValues>
                                <enumeratedValue>
                                    <name>0</name>
                                    <description>Low output</description>
                                    <value>#0</value>
                                </enumeratedValue>
                                <enumeratedValue>
                                    <name>1</name>
                                    <description>High output</description>
                                    <value>#1</value>
                                </enumeratedValue>
                            </enumeratedValues>
                        </field>
                        <field>
                            <name>PODR08</name>
                            <description>Pmn Output Data</description>
                            <lsb>8</lsb>
                            <msb>8</msb>
                            <access>read-write</access>
                            <enumeratedValues>
                                <enumeratedValue>
                                    <name>0</name>
                                    <description>Low output</description>
                                    <value>#0</value>
                                </enumeratedValue>
                                <enumeratedValue>
                                    <name>1</name>
                                    <description>High output</description>
                                    <value>#1</value>
                                </enumeratedValue>
                            </enumeratedValues>
                        </field>
                        <field>
                            <name>PODR09</name>
                            <description>Pmn Output Data</description>
                            <lsb>9</lsb>
                            <msb>9</msb>
                            <access>read-write</access>
                            <enumeratedValues>
                                <enumeratedValue>
                                    <name>0</name>
                                    <description>Low output</description>
                                    <value>#0</value>
                                </enumeratedValue>
                                <enumeratedValue>
                                    <name>1</name>
                                    <description>High output</description>
                                    <value>#1</value>
                                </enumeratedValue>
                            </enumeratedValues>
                        </field>
                        <field>
                            <name>PODR10</name>
                            <description>Pmn Output Data</description>
                            <lsb>10</lsb>
                            <msb>10</msb>
                            <access>read-write</access>
                            <enumeratedValues>
                                <enumeratedValue>
                                    <name>0</name>
                                    <description>Low output</description>
                                    <value>#0</value>
                                </enumeratedValue>
                                <enumeratedValue>
                                    <name>1</name>
                                    <description>High output</description>
                                    <value>#1</value>
                                </enumeratedValue>
                            </enumeratedValues>
                        </field>
                        <field>
                            <name>PODR11</name>
                            <description>Pmn Output Data</description>
                            <lsb>11</lsb>
                            <msb>11</msb>
                            <access>read-write</access>
                            <enumeratedValues>
                                <enumeratedValue>
                                    <name>0</name>
                                    <description>Low output</description>
                                    <value>#0</value>
                                </enumeratedValue>
                                <enumeratedValue>
                                    <name>1</name>
                                    <description>High output</description>
                                    <value>#1</value>
                                </enumeratedValue>
                            </enumeratedValues>
                        </field>
                        <field>
                            <name>PODR12</name>
                            <description>Pmn Output Data</description>
                            <lsb>12</lsb>
                            <msb>12</msb>
                            <access>read-write</access>
                            <enumeratedValues>
                                <enumeratedValue>
                                    <name>0</name>
                                    <description>Low output</description>
                                    <value>#0</value>
                                </enumeratedValue>
                                <enumeratedValue>
                                    <name>1</name>
                                    <description>High output</description>
                                    <value>#1</value>
                                </enumeratedValue>
                            </enumeratedValues>
                        </field>
                        <field>
                            <name>PODR13</name>
                            <description>Pmn Output Data</description>
                            <lsb>13</lsb>
                            <msb>13</msb>
                            <access>read-write</access>
                            <enumeratedValues>
                                <enumeratedValue>
                                    <name>0</name>
                                    <description>Low output</description>
                                    <value>#0</value>
                                </enumeratedValue>
                                <enumeratedValue>
                                    <name>1</name>
                                    <description>High output</description>
                                    <value>#1</value>
                                </enumeratedValue>
                            </enumeratedValues>
                        </field>
                        <field>
                            <name>PODR14</name>
                            <description>Pmn Output Data</description>
                            <lsb>14</lsb>
                            <msb>14</msb>
                            <access>read-write</access>
                            <enumeratedValues>
                                <enumeratedValue>
                                    <name>0</name>
                                    <description>Low output</description>
                                    <value>#0</value>
                                </enumeratedValue>
                                <enumeratedValue>
                                    <name>1</name>
                                    <description>High output</description>
                                    <value>#1</value>
                                </enumeratedValue>
                            </enumeratedValues>
                        </field>
                        <field>
                            <name>PODR15</name>
                            <description>Pmn Output Data</description>
                            <lsb>15</lsb>
                            <msb>15</msb>
                            <access>read-write</access>
                            <enumeratedValues>
                                <enumeratedValue>
                                    <name>0</name>
                                    <description>Low output</description>
                                    <value>#0</value>
                                </enumeratedValue>
                                <enumeratedValue>
                                    <name>1</name>
                                    <description>High output</description>
                                    <value>#1</value>
                                </enumeratedValue>
                            </enumeratedValues>
                        </field>
                    </fields>
                </register>
                <register>
                    <name>PODR</name>
                    <description>Port Control Register 1</description>
                    <alternateRegister>PCNTR1</alternateRegister>
                    <addressOffset>0x002</addressOffset>
                    <size>16</size>
                    <access>read-write</access>
                    <resetValue>0x0000</resetValue>
                    <resetMask>0xffff</resetMask>
                    <fields>
                        <field>
                            <name>PDR00</name>
                            <description>Pmn Direction</description>
                            <lsb>0</lsb>
                            <msb>0</msb>
                            <access>read-write</access>
                            <enumeratedValues>
                                <enumeratedValue>
                                    <name>0</name>
                                    <description>Input (functions as an input pin)</description>
                                    <value>#0</value>
                                </enumeratedValue>
                                <enumeratedValue>
                                    <name>1</name>
                                    <description>Output (functions as an output pin)</description>
                                    <value>#1</value>
                                </enumeratedValue>
                            </enumeratedValues>
                        </field>
                        <field>
                            <name>PDR01</name>
                            <description>Pmn Direction</description>
                            <lsb>1</lsb>
                            <msb>1</msb>
                            <access>read-write</access>
                            <enumeratedValues>
                                <enumeratedValue>
                                    <name>0</name>
                                    <description>Input (functions as an input pin)</description>
                                    <value>#0</value>
                                </enumeratedValue>
                                <enumeratedValue>
                                    <name>1</name>
                                    <description>Output (functions as an output pin)</description>
                                    <value>#1</value>
                                </enumeratedValue>
                            </enumeratedValues>
                        </field>
                        <field>
                            <name>PDR02</name>
                            <description>Pmn Direction</description>
                            <lsb>2</lsb>
                            <msb>2</msb>
                            <access>read-write</access>
                            <enumeratedValues>
                                <enumeratedValue>
                                    <name>0</name>
                                    <description>Input (functions as an input pin)</description>
                                    <value>#0</value>
                                </enumeratedValue>
                                <enumeratedValue>
                                    <name>1</name>
                                    <description>Output (functions as an output pin)</description>
                                    <value>#1</value>
                                </enumeratedValue>
                            </enumeratedValues>
                        </field>
                        <field>
                            <name>PDR03</name>
                            <description>Pmn Direction</description>
                            <lsb>3</lsb>
                            <msb>3</msb>
                            <access>read-write</access>
                            <enumeratedValues>
                                <enumeratedValue>
                                    <name>0</name>
                                    <description>Input (functions as an input pin)</description>
                                    <value>#0</value>
                                </enumeratedValue>
                                <enumeratedValue>
                                    <name>1</name>
                                    <description>Output (functions as an output pin)</description>
                                    <value>#1</value>
                                </enumeratedValue>
                            </enumeratedValues>
                        </field>
                        <field>
                            <name>PDR04</name>
                            <description>Pmn Direction</description>
                            <lsb>4</lsb>
                            <msb>4</msb>
                            <access>read-write</access>
                            <enumeratedValues>
                                <enumeratedValue>
                                    <name>0</name>
                                    <description>Input (functions as an input pin)</description>
                                    <value>#0</value>
                                </enumeratedValue>
                                <enumeratedValue>
                                    <name>1</name>
                                    <description>Output (functions as an output pin)</description>
                                    <value>#1</value>
                                </enumeratedValue>
                            </enumeratedValues>
                        </field>
                        <field>
                            <name>PDR05</name>
                            <description>Pmn Direction</description>
                            <lsb>5</lsb>
                            <msb>5</msb>
                            <access>read-write</access>
                            <enumeratedValues>
                                <enumeratedValue>
                                    <name>0</name>
                                    <description>Input (functions as an input pin)</description>
                                    <value>#0</value>
                                </enumeratedValue>
                                <enumeratedValue>
                                    <name>1</name>
                                    <description>Output (functions as an output pin)</description>
                                    <value>#1</value>
                                </enumeratedValue>
                            </enumeratedValues>
                        </field>
                        <field>
                            <name>PDR06</name>
                            <description>Pmn Direction</description>
                            <lsb>6</lsb>
                            <msb>6</msb>
                            <access>read-write</access>
                            <enumeratedValues>
                                <enumeratedValue>
                                    <name>0</name>
                                    <description>Input (functions as an input pin)</description>
                                    <value>#0</value>
                                </enumeratedValue>
                                <enumeratedValue>
                                    <name>1</name>
                                    <description>Output (functions as an output pin)</description>
                                    <value>#1</value>
                                </enumeratedValue>
                            </enumeratedValues>
                        </field>
                        <field>
                            <name>PDR07</name>
                            <description>Pmn Direction</description>
                            <lsb>7</lsb>
                            <msb>7</msb>
                            <access>read-write</access>
                            <enumeratedValues>
                                <enumeratedValue>
                                    <name>0</name>
                                    <description>Input (functions as an input pin)</description>
                                    <value>#0</value>
                                </enumeratedValue>
                                <enumeratedValue>
                                    <name>1</name>
                                    <description>Output (functions as an output pin)</description>
                                    <value>#1</value>
                                </enumeratedValue>
                            </enumeratedValues>
                        </field>
                        <field>
                            <name>PDR08</name>
                            <description>Pmn Direction</description>
                            <lsb>8</lsb>
                            <msb>8</msb>
                            <access>read-write</access>
                            <enumeratedValues>
                                <enumeratedValue>
                                    <name>0</name>
                                    <description>Input (functions as an input pin)</description>
                                    <value>#0</value>
                                </enumeratedValue>
                                <enumeratedValue>
                                    <name>1</name>
                                    <description>Output (functions as an output pin)</description>
                                    <value>#1</value>
                                </enumeratedValue>
                            </enumeratedValues>
                        </field>
                        <field>
                            <name>PDR09</name>
                            <description>Pmn Direction</description>
                            <lsb>9</lsb>
                            <msb>9</msb>
                            <access>read-write</access>
                            <enumeratedValues>
                                <enumeratedValue>
                                    <name>0</name>
                                    <description>Input (functions as an input pin)</description>
                                    <value>#0</value>
                                </enumeratedValue>
                                <enumeratedValue>
                                    <name>1</name>
                                    <description>Output (functions as an output pin)</description>
                                    <value>#1</value>
                                </enumeratedValue>
                            </enumeratedValues>
                        </field>
                        <field>
                            <name>PDR10</name>
                            <description>Pmn Direction</description>
                            <lsb>10</lsb>
                            <msb>10</msb>
                            <access>read-write</access>
                            <enumeratedValues>
                                <enumeratedValue>
                                    <name>0</name>
                                    <description>Input (functions as an input pin)</description>
                                    <value>#0</value>
                                </enumeratedValue>
                                <enumeratedValue>
                                    <name>1</name>
                                    <description>Output (functions as an output pin)</description>
                                    <value>#1</value>
                                </enumeratedValue>
                            </enumeratedValues>
                        </field>
                        <field>
                            <name>PDR11</name>
                            <description>Pmn Direction</description>
                            <lsb>11</lsb>
                            <msb>11</msb>
                            <access>read-write</access>
                            <enumeratedValues>
                                <enumeratedValue>
                                    <name>0</name>
                                    <description>Input (functions as an input pin)</description>
                                    <value>#0</value>
                                </enumeratedValue>
                                <enumeratedValue>
                                    <name>1</name>
                                    <description>Output (functions as an output pin)</description>
                                    <value>#1</value>
                                </enumeratedValue>
                            </enumeratedValues>
                        </field>
                        <field>
                            <name>PDR12</name>
                            <description>Pmn Direction</description>
                            <lsb>12</lsb>
                            <msb>12</msb>
                            <access>read-write</access>
                            <enumeratedValues>
                                <enumeratedValue>
                                    <name>0</name>
                                    <description>Input (functions as an input pin)</description>
                                    <value>#0</value>
                                </enumeratedValue>
                                <enumeratedValue>
                                    <name>1</name>
                                    <description>Output (functions as an output pin)</description>
                                    <value>#1</value>
                                </enumeratedValue>
                            </enumeratedValues>
                        </field>
                        <field>
                            <name>PDR13</name>
                            <description>Pmn Direction</description>
                            <lsb>13</lsb>
                            <msb>13</msb>
                            <access>read-write</access>
                            <enumeratedValues>
                                <enumeratedValue>
                                    <name>0</name>
                                    <description>Input (functions as an input pin)</description>
                                    <value>#0</value>
                                </enumeratedValue>
                                <enumeratedValue>
                                    <name>1</name>
                                    <description>Output (functions as an output pin)</description>
                                    <value>#1</value>
                                </enumeratedValue>
                            </enumeratedValues>
                        </field>
                        <field>
                            <name>PDR14</name>
                            <description>Pmn Direction</description>
                            <lsb>14</lsb>
                            <msb>14</msb>
                            <access>read-write</access>
                            <enumeratedValues>
                                <enumeratedValue>
                                    <name>0</name>
                                    <description>Input (functions as an input pin)</description>
                                    <value>#0</value>
                                </enumeratedValue>
                                <enumeratedValue>
                                    <name>1</name>
                                    <description>Output (functions as an output pin)</description>
                                    <value>#1</value>
                                </enumeratedValue>
                            </enumeratedValues>
                        </field>
                        <field>
                            <name>PDR15</name>
                            <description>Pmn Direction</description>
                            <lsb>15</lsb>
                            <msb>15</msb>
                            <access>read-write</access>
                            <enumeratedValues>
                                <enumeratedValue>
                                    <name>0</name>
                                    <description>Input (functions as an input pin)</description>
                                    <value>#0</value>
                                </enumeratedValue>
                                <enumeratedValue>
                                    <name>1</name>
                                    <description>Output (functions as an output pin)</description>
                                    <value>#1</value>
                                </enumeratedValue>
                            </enumeratedValues>
                        </field>
                    </fields>
                </register>
                <register>
                    <name>PCNTR2</name>
                    <description>Port Control Register 2</description>
                    <addressOffset>0x004</addressOffset>
                    <size>32</size>
                    <access>read-only</access>
                    <resetValue>0x00000000</resetValue>
                    <resetMask>0xffff0000</resetMask>
                    <fields>
                        <field>
                            <name>PIDR00</name>
                            <description>Pmn State</description>
                            <lsb>0</lsb>
                            <msb>0</msb>
                            <access>read-only</access>
                            <enumeratedValues>
                                <enumeratedValue>
                                    <name>0</name>
                                    <description>Low level</description>
                                    <value>#0</value>
                                </enumeratedValue>
                                <enumeratedValue>
                                    <name>1</name>
                                    <description>High level</description>
                                    <value>#1</value>
                                </enumeratedValue>
                            </enumeratedValues>
                        </field>
                        <field>
                            <name>PIDR01</name>
                            <description>Pmn State</description>
                            <lsb>1</lsb>
                            <msb>1</msb>
                            <access>read-only</access>
                            <enumeratedValues>
                                <enumeratedValue>
                                    <name>0</name>
                                    <description>Low level</description>
                                    <value>#0</value>
                                </enumeratedValue>
                                <enumeratedValue>
                                    <name>1</name>
                                    <description>High level</description>
                                    <value>#1</value>
                                </enumeratedValue>
                            </enumeratedValues>
                        </field>
                        <field>
                            <name>PIDR02</name>
                            <description>Pmn State</description>
                            <lsb>2</lsb>
                            <msb>2</msb>
                            <access>read-only</access>
                            <enumeratedValues>
                                <enumeratedValue>
                                    <name>0</name>
                                    <description>Low level</description>
                                    <value>#0</value>
                                </enumeratedValue>
                                <enumeratedValue>
                                    <name>1</name>
                                    <description>High level</description>
                                    <value>#1</value>
                                </enumeratedValue>
                            </enumeratedValues>
                        </field>
                        <field>
                            <name>PIDR03</name>
                            <description>Pmn State</description>
                            <lsb>3</lsb>
                            <msb>3</msb>
                            <access>read-only</access>
                            <enumeratedValues>
                                <enumeratedValue>
                                    <name>0</name>
                                    <description>Low level</description>
                                    <value>#0</value>
                                </enumeratedValue>
                                <enumeratedValue>
                                    <name>1</name>
                                    <description>High level</description>
                                    <value>#1</value>
                                </enumeratedValue>
                            </enumeratedValues>
                        </field>
                        <field>
                            <name>PIDR04</name>
                            <description>Pmn State</description>
                            <lsb>4</lsb>
                            <msb>4</msb>
                            <access>read-only</access>
                            <enumeratedValues>
                                <enumeratedValue>
                                    <name>0</name>
                                    <description>Low level</description>
                                    <value>#0</value>
                                </enumeratedValue>
                                <enumeratedValue>
                                    <name>1</name>
                                    <description>High level</description>
                                    <value>#1</value>
                                </enumeratedValue>
                            </enumeratedValues>
                        </field>
                        <field>
                            <name>PIDR05</name>
                            <description>Pmn State</description>
                            <lsb>5</lsb>
                            <msb>5</msb>
                            <access>read-only</access>
                            <enumeratedValues>
                                <enumeratedValue>
                                    <name>0</name>
                                    <description>Low level</description>
                                    <value>#0</value>
                                </enumeratedValue>
                                <enumeratedValue>
                                    <name>1</name>
                                    <description>High level</description>
                                    <value>#1</value>
                                </enumeratedValue>
                            </enumeratedValues>
                        </field>
                        <field>
                            <name>PIDR06</name>
                            <description>Pmn State</description>
                            <lsb>6</lsb>
                            <msb>6</msb>
                            <access>read-only</access>
                            <enumeratedValues>
                                <enumeratedValue>
                                    <name>0</name>
                                    <description>Low level</description>
                                    <value>#0</value>
                                </enumeratedValue>
                                <enumeratedValue>
                                    <name>1</name>
                                    <description>High level</description>
                                    <value>#1</value>
                                </enumeratedValue>
                            </enumeratedValues>
                        </field>
                        <field>
                            <name>PIDR07</name>
                            <description>Pmn State</description>
                            <lsb>7</lsb>
                            <msb>7</msb>
                            <access>read-only</access>
                            <enumeratedValues>
                                <enumeratedValue>
                                    <name>0</name>
                                    <description>Low level</description>
                                    <value>#0</value>
                                </enumeratedValue>
                                <enumeratedValue>
                                    <name>1</name>
                                    <description>High level</description>
                                    <value>#1</value>
                                </enumeratedValue>
                            </enumeratedValues>
                        </field>
                        <field>
                            <name>PIDR08</name>
                            <description>Pmn State</description>
                            <lsb>8</lsb>
                            <msb>8</msb>
                            <access>read-only</access>
                            <enumeratedValues>
                                <enumeratedValue>
                                    <name>0</name>
                                    <description>Low level</description>
                                    <value>#0</value>
                                </enumeratedValue>
                                <enumeratedValue>
                                    <name>1</name>
                                    <description>High level</description>
                                    <value>#1</value>
                                </enumeratedValue>
                            </enumeratedValues>
                        </field>
                        <field>
                            <name>PIDR09</name>
                            <description>Pmn State</description>
                            <lsb>9</lsb>
                            <msb>9</msb>
                            <access>read-only</access>
                            <enumeratedValues>
                                <enumeratedValue>
                                    <name>0</name>
                                    <description>Low level</description>
                                    <value>#0</value>
                                </enumeratedValue>
                                <enumeratedValue>
                                    <name>1</name>
                                    <description>High level</description>
                                    <value>#1</value>
                                </enumeratedValue>
                            </enumeratedValues>
                        </field>
                        <field>
                            <name>PIDR10</name>
                            <description>Pmn State</description>
                            <lsb>10</lsb>
                            <msb>10</msb>
                            <access>read-only</access>
                            <enumeratedValues>
                                <enumeratedValue>
                                    <name>0</name>
                                    <description>Low level</description>
                                    <value>#0</value>
                                </enumeratedValue>
                                <enumeratedValue>
                                    <name>1</name>
                                    <description>High level</description>
                                    <value>#1</value>
                                </enumeratedValue>
                            </enumeratedValues>
                        </field>
                        <field>
                            <name>PIDR11</name>
                            <description>Pmn State</description>
                            <lsb>11</lsb>
                            <msb>11</msb>
                            <access>read-only</access>
                            <enumeratedValues>
                                <enumeratedValue>
                                    <name>0</name>
                                    <description>Low level</description>
                                    <value>#0</value>
                                </enumeratedValue>
                                <enumeratedValue>
                                    <name>1</name>
                                    <description>High level</description>
                                    <value>#1</value>
                                </enumeratedValue>
                            </enumeratedValues>
                        </field>
                        <field>
                            <name>PIDR12</name>
                            <description>Pmn State</description>
                            <lsb>12</lsb>
                            <msb>12</msb>
                            <access>read-only</access>
                            <enumeratedValues>
                                <enumeratedValue>
                                    <name>0</name>
                                    <description>Low level</description>
                                    <value>#0</value>
                                </enumeratedValue>
                                <enumeratedValue>
                                    <name>1</name>
                                    <description>High level</description>
                                    <value>#1</value>
                                </enumeratedValue>
                            </enumeratedValues>
                        </field>
                        <field>
                            <name>PIDR13</name>
                            <description>Pmn State</description>
                            <lsb>13</lsb>
                            <msb>13</msb>
                            <access>read-only</access>
                            <enumeratedValues>
                                <enumeratedValue>
                                    <name>0</name>
                                    <description>Low level</description>
                                    <value>#0</value>
                                </enumeratedValue>
                                <enumeratedValue>
                                    <name>1</name>
                                    <description>High level</description>
                                    <value>#1</value>
                                </enumeratedValue>
                            </enumeratedValues>
                        </field>
                        <field>
                            <name>PIDR14</name>
                            <description>Pmn State</description>
                            <lsb>14</lsb>
                            <msb>14</msb>
                            <access>read-only</access>
                            <enumeratedValues>
                                <enumeratedValue>
                                    <name>0</name>
                                    <description>Low level</description>
                                    <value>#0</value>
                                </enumeratedValue>
                                <enumeratedValue>
                                    <name>1</name>
                                    <description>High level</description>
                                    <value>#1</value>
                                </enumeratedValue>
                            </enumeratedValues>
                        </field>
                        <field>
                            <name>PIDR15</name>
                            <description>Pmn State</description>
                            <lsb>15</lsb>
                            <msb>15</msb>
                            <access>read-only</access>
                            <enumeratedValues>
                                <enumeratedValue>
                                    <name>0</name>
                                    <description>Low level</description>
                                    <value>#0</value>
                                </enumeratedValue>
                                <enumeratedValue>
                                    <name>1</name>
                                    <description>High level</description>
                                    <value>#1</value>
                                </enumeratedValue>
                            </enumeratedValues>
                        </field>
                    </fields>
                </register>
                <register>
                    <name>PIDR</name>
                    <description>Port Control Register 2</description>
                    <alternateRegister>PCNTR2</alternateRegister>
                    <addressOffset>0x004</addressOffset>
                    <size>16</size>
                    <access>read-only</access>
                    <resetValue>0x0000</resetValue>
                    <resetMask>0xffff</resetMask>
                </register>
                <register>
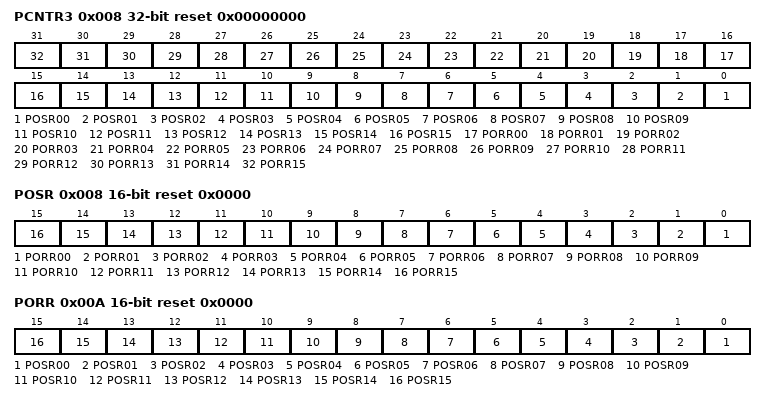
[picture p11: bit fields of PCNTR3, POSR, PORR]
                    <name>PCNTR3</name>
                    <description>Port Control Register 3</description>
                    <addressOffset>0x008</addressOffset>
                    <size>32</size>
                    <access>write-only</access>
                    <resetValue>0x00000000</resetValue>
                    <resetMask>0xffffffff</resetMask>
                    <fields>
                        <field>
                            <name>POSR00</name>
                            <description>Pmn Output Set</description>
                            <lsb>0</lsb>
                            <msb>0</msb>
                            <access>write-only</access>
                            <enumeratedValues>
                                <enumeratedValue>
                                    <name>0</name>
                                    <description>No effect on output</description>
                                    <value>#0</value>
                                </enumeratedValue>
                                <enumeratedValue>
                                    <name>1</name>
                                    <description>High output</description>
                                    <value>#1</value>
                                </enumeratedValue>
                            </enumeratedValues>
                        </field>
                        <field>
                            <name>POSR01</name>
                            <description>Pmn Output Set</description>
                            <lsb>1</lsb>
                            <msb>1</msb>
                            <access>write-only</access>
                            <enumeratedValues>
                                <enumeratedValue>
                                    <name>0</name>
                                    <description>No effect on output</description>
                                    <value>#0</value>
                                </enumeratedValue>
                                <enumeratedValue>
                                    <name>1</name>
                                    <description>High output</description>
                                    <value>#1</value>
                                </enumeratedValue>
                            </enumeratedValues>
                        </field>
                        <field>
                            <name>POSR02</name>
                            <description>Pmn Output Set</description>
                            <lsb>2</lsb>
                            <msb>2</msb>
                            <access>write-only</access>
                            <enumeratedValues>
                                <enumeratedValue>
                                    <name>0</name>
                                    <description>No effect on output</description>
                                    <value>#0</value>
                                </enumeratedValue>
                                <enumeratedValue>
                                    <name>1</name>
                                    <description>High output</description>
                                    <value>#1</value>
                                </enumeratedValue>
                            </enumeratedValues>
                        </field>
                        <field>
                            <name>POSR03</name>
                            <description>Pmn Output Set</description>
                            <lsb>3</lsb>
                            <msb>3</msb>
                            <access>write-only</access>
                            <enumeratedValues>
                                <enumeratedValue>
                                    <name>0</name>
                                    <description>No effect on output</description>
                                    <value>#0</value>
                                </enumeratedValue>
                                <enumeratedValue>
                                    <name>1</name>
                                    <description>High output</description>
                                    <value>#1</value>
                                </enumeratedValue>
                            </enumeratedValues>
                        </field>
                        <field>
                            <name>POSR04</name>
                            <description>Pmn Output Set</description>
                            <lsb>4</lsb>
                            <msb>4</msb>
                            <access>write-only</access>
                            <enumeratedValues>
                                <enumeratedValue>
                                    <name>0</name>
                                    <description>No effect on output</description>
                                    <value>#0</value>
                                </enumeratedValue>
                                <enumeratedValue>
                                    <name>1</name>
                                    <description>High output</description>
                                    <value>#1</value>
                                </enumeratedValue>
                            </enumeratedValues>
                        </field>
                        <field>
                            <name>POSR05</name>
                            <description>Pmn Output Set</description>
                            <lsb>5</lsb>
                            <msb>5</msb>
                            <access>write-only</access>
                            <enumeratedValues>
                                <enumeratedValue>
                                    <name>0</name>
                                    <description>No effect on output</description>
                                    <value>#0</value>
                                </enumeratedValue>
                                <enumeratedValue>
                                    <name>1</name>
                                    <description>High output</description>
                                    <value>#1</value>
                                </enumeratedValue>
                            </enumeratedValues>
                        </field>
                        <field>
                            <name>POSR06</name>
                            <description>Pmn Output Set</description>
                            <lsb>6</lsb>
                            <msb>6</msb>
                            <access>write-only</access>
                            <enumeratedValues>
                                <enumeratedValue>
                                    <name>0</name>
                                    <description>No effect on output</description>
                                    <value>#0</value>
                                </enumeratedValue>
                                <enumeratedValue>
                                    <name>1</name>
                                    <description>High output</description>
                                    <value>#1</value>
                                </enumeratedValue>
                            </enumeratedValues>
                        </field>
                        <field>
                            <name>POSR07</name>
                            <description>Pmn Output Set</description>
                            <lsb>7</lsb>
                            <msb>7</msb>
                            <access>write-only</access>
                            <enumeratedValues>
                                <enumeratedValue>
                                    <name>0</name>
                                    <description>No effect on output</description>
                                    <value>#0</value>
                                </enumeratedValue>
                                <enumeratedValue>
                                    <name>1</name>
                                    <description>High output</description>
                                    <value>#1</value>
                                </enumeratedValue>
                            </enumeratedValues>
                        </field>
                        <field>
                            <name>POSR08</name>
                            <description>Pmn Output Set</description>
                            <lsb>8</lsb>
                            <msb>8</msb>
                            <access>write-only</access>
                            <enumeratedValues>
                                <enumeratedValue>
                                    <name>0</name>
                                    <description>No effect on output</description>
                                    <value>#0</value>
                                </enumeratedValue>
                                <enumeratedValue>
                                    <name>1</name>
                                    <description>High output</description>
                                    <value>#1</value>
                                </enumeratedValue>
                            </enumeratedValues>
                        </field>
                        <field>
                            <name>POSR09</name>
                            <description>Pmn Output Set</description>
                            <lsb>9</lsb>
                            <msb>9</msb>
                            <access>write-only</access>
                            <enumeratedValues>
                                <enumeratedValue>
                                    <name>0</name>
                                    <description>No effect on output</description>
                                    <value>#0</value>
                                </enumeratedValue>
                                <enumeratedValue>
                                    <name>1</name>
                                    <description>High output</description>
                                    <value>#1</value>
                                </enumeratedValue>
                            </enumeratedValues>
                        </field>
                        <field>
                            <name>POSR10</name>
                            <description>Pmn Output Set</description>
                            <lsb>10</lsb>
                            <msb>10</msb>
                            <access>write-only</access>
                            <enumeratedValues>
                                <enumeratedValue>
                                    <name>0</name>
                                    <description>No effect on output</description>
                                    <value>#0</value>
                                </enumeratedValue>
                                <enumeratedValue>
                                    <name>1</name>
                                    <description>High output</description>
                                    <value>#1</value>
                                </enumeratedValue>
                            </enumeratedValues>
                        </field>
                        <field>
                            <name>POSR11</name>
                            <description>Pmn Output Set</description>
                            <lsb>11</lsb>
                            <msb>11</msb>
                            <access>write-only</access>
                            <enumeratedValues>
                                <enumeratedValue>
                                    <name>0</name>
                                    <description>No effect on output</description>
                                    <value>#0</value>
                                </enumeratedValue>
                                <enumeratedValue>
                                    <name>1</name>
                                    <description>High output</description>
                                    <value>#1</value>
                                </enumeratedValue>
                            </enumeratedValues>
                        </field>
                        <field>
                            <name>POSR12</name>
                            <description>Pmn Output Set</description>
                            <lsb>12</lsb>
                            <msb>12</msb>
                            <access>write-only</access>
                            <enumeratedValues>
                                <enumeratedValue>
                                    <name>0</name>
                                    <description>No effect on output</description>
                                    <value>#0</value>
                                </enumeratedValue>
                                <enumeratedValue>
                                    <name>1</name>
                                    <description>High output</description>
                                    <value>#1</value>
                                </enumeratedValue>
                            </enumeratedValues>
                        </field>
                        <field>
                            <name>POSR13</name>
                            <description>Pmn Output Set</description>
                            <lsb>13</lsb>
                            <msb>13</msb>
                            <access>write-only</access>
                            <enumeratedValues>
                                <enumeratedValue>
                                    <name>0</name>
                                    <description>No effect on output</description>
                                    <value>#0</value>
                                </enumeratedValue>
                                <enumeratedValue>
                                    <name>1</name>
                                    <description>High output</description>
                                    <value>#1</value>
                                </enumeratedValue>
                            </enumeratedValues>
                        </field>
                        <field>
                            <name>POSR14</name>
                            <description>Pmn Output Set</description>
                            <lsb>14</lsb>
                            <msb>14</msb>
                            <access>write-only</access>
                            <enumeratedValues>
                                <enumeratedValue>
                                    <name>0</name>
                                    <description>No effect on output</description>
                                    <value>#0</value>
                                </enumeratedValue>
                                <enumeratedValue>
                                    <name>1</name>
                                    <description>High output</description>
                                    <value>#1</value>
                                </enumeratedValue>
                            </enumeratedValues>
                        </field>
                        <field>
                            <name>POSR15</name>
                            <description>Pmn Output Set</description>
                            <lsb>15</lsb>
                            <msb>15</msb>
                            <access>write-only</access>
                            <enumeratedValues>
                                <enumeratedValue>
                                    <name>0</name>
                                    <description>No effect on output</description>
                                    <value>#0</value>
                                </enumeratedValue>
                                <enumeratedValue>
                                    <name>1</name>
                                    <description>High output</description>
                                    <value>#1</value>
                                </enumeratedValue>
                            </enumeratedValues>
                        </field>
                        <field>
                            <name>PORR00</name>
                            <description>Pmn Output Reset</description>
                            <lsb>16</lsb>
                            <msb>16</msb>
                            <access>write-only</access>
                            <enumeratedValues>
                                <enumeratedValue>
                                    <name>0</name>
                                    <description>No effect on output</description>
                                    <value>#0</value>
                                </enumeratedValue>
                                <enumeratedValue>
                                    <name>1</name>
                                    <description>Low output</description>
                                    <value>#1</value>
                                </enumeratedValue>
                            </enumeratedValues>
                        </field>
                        <field>
                            <name>PORR01</name>
                            <description>Pmn Output Reset</description>
                            <lsb>17</lsb>
                            <msb>17</msb>
                            <access>write-only</access>
                            <enumeratedValues>
                                <enumeratedValue>
                                    <name>0</name>
                                    <description>No effect on output</description>
                                    <value>#0</value>
                                </enumeratedValue>
                                <enumeratedValue>
                                    <name>1</name>
                                    <description>Low output</description>
                                    <value>#1</value>
                                </enumeratedValue>
                            </enumeratedValues>
                        </field>
                        <field>
                            <name>PORR02</name>
                            <description>Pmn Output Reset</description>
                            <lsb>18</lsb>
                            <msb>18</msb>
                            <access>write-only</access>
                            <enumeratedValues>
                                <enumeratedValue>
                                    <name>0</name>
                                    <description>No effect on output</description>
                                    <value>#0</value>
                                </enumeratedValue>
                                <enumeratedValue>
                                    <name>1</name>
                                    <description>Low output</description>
                                    <value>#1</value>
                                </enumeratedValue>
                            </enumeratedValues>
                        </field>
                        <field>
                            <name>PORR03</name>
                            <description>Pmn Output Reset</description>
                            <lsb>19</lsb>
                            <msb>19</msb>
                            <access>write-only</access>
                            <enumeratedValues>
                                <enumeratedValue>
                                    <name>0</name>
                                    <description>No effect on output</description>
                                    <value>#0</value>
                                </enumeratedValue>
                                <enumeratedValue>
                                    <name>1</name>
                                    <description>Low output</description>
                                    <value>#1</value>
                                </enumeratedValue>
                            </enumeratedValues>
                        </field>
                        <field>
                            <name>PORR04</name>
                            <description>Pmn Output Reset</description>
                            <lsb>20</lsb>
                            <msb>20</msb>
                            <access>write-only</access>
                            <enumeratedValues>
                                <enumeratedValue>
                                    <name>0</name>
                                    <description>No effect on output</description>
                                    <value>#0</value>
                                </enumeratedValue>
                                <enumeratedValue>
                                    <name>1</name>
                                    <description>Low output</description>
                                    <value>#1</value>
                                </enumeratedValue>
                            </enumeratedValues>
                        </field>
                        <field>
                            <name>PORR05</name>
                            <description>Pmn Output Reset</description>
                            <lsb>21</lsb>
                            <msb>21</msb>
                            <access>write-only</access>
                            <enumeratedValues>
                                <enumeratedValue>
                                    <name>0</name>
                                    <description>No effect on output</description>
                                    <value>#0</value>
                                </enumeratedValue>
                                <enumeratedValue>
                                    <name>1</name>
                                    <description>Low output</description>
                                    <value>#1</value>
                                </enumeratedValue>
                            </enumeratedValues>
                        </field>
                        <field>
                            <name>PORR06</name>
                            <description>Pmn Output Reset</description>
                            <lsb>22</lsb>
                            <msb>22</msb>
                            <access>write-only</access>
                            <enumeratedValues>
                                <enumeratedValue>
                                    <name>0</name>
                                    <description>No effect on output</description>
                                    <value>#0</value>
                                </enumeratedValue>
                                <enumeratedValue>
                                    <name>1</name>
                                    <description>Low output</description>
                                    <value>#1</value>
                                </enumeratedValue>
                            </enumeratedValues>
                        </field>
                        <field>
                            <name>PORR07</name>
                            <description>Pmn Output Reset</description>
                            <lsb>23</lsb>
                            <msb>23</msb>
                            <access>write-only</access>
                            <enumeratedValues>
                                <enumeratedValue>
                                    <name>0</name>
                                    <description>No effect on output</description>
                                    <value>#0</value>
                                </enumeratedValue>
                                <enumeratedValue>
                                    <name>1</name>
                                    <description>Low output</description>
                                    <value>#1</value>
                                </enumeratedValue>
                            </enumeratedValues>
                        </field>
                        <field>
                            <name>PORR08</name>
                            <description>Pmn Output Reset</description>
                            <lsb>24</lsb>
                            <msb>24</msb>
                            <access>write-only</access>
                            <enumeratedValues>
                                <enumeratedValue>
                                    <name>0</name>
                                    <description>No effect on output</description>
                                    <value>#0</value>
                                </enumeratedValue>
                                <enumeratedValue>
                                    <name>1</name>
                                    <description>Low output</description>
                                    <value>#1</value>
                                </enumeratedValue>
                            </enumeratedValues>
                        </field>
                        <field>
                            <name>PORR09</name>
                            <description>Pmn Output Reset</description>
                            <lsb>25</lsb>
                            <msb>25</msb>
                            <access>write-only</access>
                            <enumeratedValues>
                                <enumeratedValue>
                                    <name>0</name>
                                    <description>No effect on output</description>
                                    <value>#0</value>
                                </enumeratedValue>
                                <enumeratedValue>
                                    <name>1</name>
                                    <description>Low output</description>
                                    <value>#1</value>
                                </enumeratedValue>
                            </enumeratedValues>
                        </field>
                        <field>
                            <name>PORR10</name>
                            <description>Pmn Output Reset</description>
                            <lsb>26</lsb>
                            <msb>26</msb>
                            <access>write-only</access>
                            <enumeratedValues>
                                <enumeratedValue>
                                    <name>0</name>
                                    <description>No effect on output</description>
                                    <value>#0</value>
                                </enumeratedValue>
                                <enumeratedValue>
                                    <name>1</name>
                                    <description>Low output</description>
                                    <value>#1</value>
                                </enumeratedValue>
                            </enumeratedValues>
                        </field>
                        <field>
                            <name>PORR11</name>
                            <description>Pmn Output Reset</description>
                            <lsb>27</lsb>
                            <msb>27</msb>
                            <access>write-only</access>
                            <enumeratedValues>
                                <enumeratedValue>
                                    <name>0</name>
                                    <description>No effect on output</description>
                                    <value>#0</value>
                                </enumeratedValue>
                                <enumeratedValue>
                                    <name>1</name>
                                    <description>Low output</description>
                                    <value>#1</value>
                                </enumeratedValue>
                            </enumeratedValues>
                        </field>
                        <field>
                            <name>PORR12</name>
                            <description>Pmn Output Reset</description>
                            <lsb>28</lsb>
                            <msb>28</msb>
                            <access>write-only</access>
                            <enumeratedValues>
                                <enumeratedValue>
                                    <name>0</name>
                                    <description>No effect on output</description>
                                    <value>#0</value>
                                </enumeratedValue>
                                <enumeratedValue>
                                    <name>1</name>
                                    <description>Low output</description>
                                    <value>#1</value>
                                </enumeratedValue>
                            </enumeratedValues>
                        </field>
                        <field>
                            <name>PORR13</name>
                            <description>Pmn Output Reset</description>
                            <lsb>29</lsb>
                            <msb>29</msb>
                            <access>write-only</access>
                            <enumeratedValues>
                                <enumeratedValue>
                                    <name>0</name>
                                    <description>No effect on output</description>
                                    <value>#0</value>
                                </enumeratedValue>
                                <enumeratedValue>
                                    <name>1</name>
                                    <description>Low output</description>
                                    <value>#1</value>
                                </enumeratedValue>
                            </enumeratedValues>
                        </field>
                        <field>
                            <name>PORR14</name>
                            <description>Pmn Output Reset</description>
                            <lsb>30</lsb>
                            <msb>30</msb>
                            <access>write-only</access>
                            <enumeratedValues>
                                <enumeratedValue>
                                    <name>0</name>
                                    <description>No effect on output</description>
                                    <value>#0</value>
                                </enumeratedValue>
                                <enumeratedValue>
                                    <name>1</name>
                                    <description>Low output</description>
                                    <value>#1</value>
                                </enumeratedValue>
                            </enumeratedValues>
                        </field>
                        <field>
                            <name>PORR15</name>
                            <description>Pmn Output Reset</description>
                            <lsb>31</lsb>
                            <msb>31</msb>
                            <access>write-only</access>
                            <enumeratedValues>
                                <enumeratedValue>
                                    <name>0</name>
                                    <description>No effect on output</description>
                                    <value>#0</value>
                                </enumeratedValue>
                                <enumeratedValue>
                                    <name>1</name>
                                    <description>Low output</description>
                                    <value>#1</value>
                                </enumeratedValue>
                            </enumeratedValues>
                        </field>
                    </fields>
                </register>
                <register>
                    <name>POSR</name>
                    <description>Port Control Register 3</description>
                    <alternateRegister>PCNTR3</alternateRegister>
                    <addressOffset>0x008</addressOffset>
                    <size>16</size>
                    <access>write-only</access>
                    <resetValue>0x0000</resetValue>
                    <resetMask>0xffff</resetMask>
                    <fields>
                        <field>
                            <name>PORR00</name>
                            <description>Pmn Output Reset</description>
                            <lsb>0</lsb>
                            <msb>0</msb>
                            <access>write-only</access>
                            <enumeratedValues>
                                <enumeratedValue>
                                    <name>0</name>
                                    <description>No effect on output</description>
                                    <value>#0</value>
                                </enumeratedValue>
                                <enumeratedValue>
                                    <name>1</name>
                                    <description>Low output</description>
                                    <value>#1</value>
                                </enumeratedValue>
                            </enumeratedValues>
                        </field>
                        <field>
                            <name>PORR01</name>
                            <description>Pmn Output Reset</description>
                            <lsb>1</lsb>
                            <msb>1</msb>
                            <access>write-only</access>
                            <enumeratedValues>
                                <enumeratedValue>
                                    <name>0</name>
                                    <description>No effect on output</description>
                                    <value>#0</value>
                                </enumeratedValue>
                                <enumeratedValue>
                                    <name>1</name>
                                    <description>Low output</description>
                                    <value>#1</value>
                                </enumeratedValue>
                            </enumeratedValues>
                        </field>
                        <field>
                            <name>PORR02</name>
                            <description>Pmn Output Reset</description>
                            <lsb>2</lsb>
                            <msb>2</msb>
                            <access>write-only</access>
                            <enumeratedValues>
                                <enumeratedValue>
                                    <name>0</name>
                                    <description>No effect on output</description>
                                    <value>#0</value>
                                </enumeratedValue>
                                <enumeratedValue>
                                    <name>1</name>
                                    <description>Low output</description>
                                    <value>#1</value>
                                </enumeratedValue>
                            </enumeratedValues>
                        </field>
                        <field>
                            <name>PORR03</name>
                            <description>Pmn Output Reset</description>
                            <lsb>3</lsb>
                            <msb>3</msb>
                            <access>write-only</access>
                            <enumeratedValues>
                                <enumeratedValue>
                                    <name>0</name>
                                    <description>No effect on output</description>
                                    <value>#0</value>
                                </enumeratedValue>
                                <enumeratedValue>
                                    <name>1</name>
                                    <description>Low output</description>
                                    <value>#1</value>
                                </enumeratedValue>
                            </enumeratedValues>
                        </field>
                        <field>
                            <name>PORR04</name>
                            <description>Pmn Output Reset</description>
                            <lsb>4</lsb>
                            <msb>4</msb>
                            <access>write-only</access>
                            <enumeratedValues>
                                <enumeratedValue>
                                    <name>0</name>
                                    <description>No effect on output</description>
                                    <value>#0</value>
                                </enumeratedValue>
                                <enumeratedValue>
                                    <name>1</name>
                                    <description>Low output</description>
                                    <value>#1</value>
                                </enumeratedValue>
                            </enumeratedValues>
                        </field>
                        <field>
                            <name>PORR05</name>
                            <description>Pmn Output Reset</description>
                            <lsb>5</lsb>
                            <msb>5</msb>
                            <access>write-only</access>
                            <enumeratedValues>
                                <enumeratedValue>
                                    <name>0</name>
                                    <description>No effect on output</description>
                                    <value>#0</value>
                                </enumeratedValue>
                                <enumeratedValue>
                                    <name>1</name>
                                    <description>Low output</description>
                                    <value>#1</value>
                                </enumeratedValue>
                            </enumeratedValues>
                        </field>
                        <field>
                            <name>PORR06</name>
                            <description>Pmn Output Reset</description>
                            <lsb>6</lsb>
                            <msb>6</msb>
                            <access>write-only</access>
                            <enumeratedValues>
                                <enumeratedValue>
                                    <name>0</name>
                                    <description>No effect on output</description>
                                    <value>#0</value>
                                </enumeratedValue>
                                <enumeratedValue>
                                    <name>1</name>
                                    <description>Low output</description>
                                    <value>#1</value>
                                </enumeratedValue>
                            </enumeratedValues>
                        </field>
                        <field>
                            <name>PORR07</name>
                            <description>Pmn Output Reset</description>
                            <lsb>7</lsb>
                            <msb>7</msb>
                            <access>write-only</access>
                            <enumeratedValues>
                                <enumeratedValue>
                                    <name>0</name>
                                    <description>No effect on output</description>
                                    <value>#0</value>
                                </enumeratedValue>
                                <enumeratedValue>
                                    <name>1</name>
                                    <description>Low output</description>
                                    <value>#1</value>
                                </enumeratedValue>
                            </enumeratedValues>
                        </field>
                        <field>
                            <name>PORR08</name>
                            <description>Pmn Output Reset</description>
                            <lsb>8</lsb>
                            <msb>8</msb>
                            <access>write-only</access>
                            <enumeratedValues>
                                <enumeratedValue>
                                    <name>0</name>
                                    <description>No effect on output</description>
                                    <value>#0</value>
                                </enumeratedValue>
                                <enumeratedValue>
                                    <name>1</name>
                                    <description>Low output</description>
                                    <value>#1</value>
                                </enumeratedValue>
                            </enumeratedValues>
                        </field>
                        <field>
                            <name>PORR09</name>
                            <description>Pmn Output Reset</description>
                            <lsb>9</lsb>
                            <msb>9</msb>
                            <access>write-only</access>
                            <enumeratedValues>
                                <enumeratedValue>
                                    <name>0</name>
                                    <description>No effect on output</description>
                                    <value>#0</value>
                                </enumeratedValue>
                                <enumeratedValue>
                                    <name>1</name>
                                    <description>Low output</description>
                                    <value>#1</value>
                                </enumeratedValue>
                            </enumeratedValues>
                        </field>
                        <field>
                            <name>PORR10</name>
                            <description>Pmn Output Reset</description>
                            <lsb>10</lsb>
                            <msb>10</msb>
                            <access>write-only</access>
                            <enumeratedValues>
                                <enumeratedValue>
                                    <name>0</name>
                                    <description>No effect on output</description>
                                    <value>#0</value>
                                </enumeratedValue>
                                <enumeratedValue>
                                    <name>1</name>
                                    <description>Low output</description>
                                    <value>#1</value>
                                </enumeratedValue>
                            </enumeratedValues>
                        </field>
                        <field>
                            <name>PORR11</name>
                            <description>Pmn Output Reset</description>
                            <lsb>11</lsb>
                            <msb>11</msb>
                            <access>write-only</access>
                            <enumeratedValues>
                                <enumeratedValue>
                                    <name>0</name>
                                    <description>No effect on output</description>
                                    <value>#0</value>
                                </enumeratedValue>
                                <enumeratedValue>
                                    <name>1</name>
                                    <description>Low output</description>
                                    <value>#1</value>
                                </enumeratedValue>
                            </enumeratedValues>
                        </field>
                        <field>
                            <name>PORR12</name>
                            <description>Pmn Output Reset</description>
                            <lsb>12</lsb>
                            <msb>12</msb>
                            <access>write-only</access>
                            <enumeratedValues>
                                <enumeratedValue>
                                    <name>0</name>
                                    <description>No effect on output</description>
                                    <value>#0</value>
                                </enumeratedValue>
                                <enumeratedValue>
                                    <name>1</name>
                                    <description>Low output</description>
                                    <value>#1</value>
                                </enumeratedValue>
                            </enumeratedValues>
                        </field>
                        <field>
                            <name>PORR13</name>
                            <description>Pmn Output Reset</description>
                            <lsb>13</lsb>
                            <msb>13</msb>
                            <access>write-only</access>
                            <enumeratedValues>
                                <enumeratedValue>
                                    <name>0</name>
                                    <description>No effect on output</description>
                                    <value>#0</value>
                                </enumeratedValue>
                                <enumeratedValue>
                                    <name>1</name>
                                    <description>Low output</description>
                                    <value>#1</value>
                                </enumeratedValue>
                            </enumeratedValues>
                        </field>
                        <field>
                            <name>PORR14</name>
                            <description>Pmn Output Reset</description>
                            <lsb>14</lsb>
                            <msb>14</msb>
                            <access>write-only</access>
                            <enumeratedValues>
                                <enumeratedValue>
                                    <name>0</name>
                                    <description>No effect on output</description>
                                    <value>#0</value>
                                </enumeratedValue>
                                <enumeratedValue>
                                    <name>1</name>
                                    <description>Low output</description>
                                    <value>#1</value>
                                </enumeratedValue>
                            </enumeratedValues>
                        </field>
                        <field>
                            <name>PORR15</name>
                            <description>Pmn Output Reset</description>
                            <lsb>15</lsb>
                            <msb>15</msb>
                            <access>write-only</access>
                            <enumeratedValues>
                                <enumeratedValue>
                                    <name>0</name>
                                    <description>No effect on output</description>
                                    <value>#0</value>
                                </enumeratedValue>
                                <enumeratedValue>
                                    <name>1</name>
                                    <description>Low output</description>
                                    <value>#1</value>
                                </enumeratedValue>
                            </enumeratedValues>
                        </field>
                    </fields>
                </register>
                <register>
                    <name>PORR</name>
                    <description>Port Control Register 3</description>
                    <alternateRegister>PCNTR3</alternateRegister>
                    <addressOffset>0x00A</addressOffset>
                    <size>16</size>
                    <access>write-only</access>
                    <resetValue>0x0000</resetValue>
                    <resetMask>0xffff</resetMask>
                    <fields>
                        <field>
                            <name>POSR00</name>
                            <description>Pmn Output Set</description>
                            <lsb>0</lsb>
                            <msb>0</msb>
                            <access>write-only</access>
                            <enumeratedValues>
                                <enumeratedValue>
                                    <name>0</name>
                                    <description>No effect on output</description>
                                    <value>#0</value>
                                </enumeratedValue>
                                <enumeratedValue>
                                    <name>1</name>
                                    <description>High output</description>
                                    <value>#1</value>
                                </enumeratedValue>
                            </enumeratedValues>
                        </field>
                        <field>
                            <name>POSR01</name>
                            <description>Pmn Output Set</description>
                            <lsb>1</lsb>
                            <msb>1</msb>
                            <access>write-only</access>
                            <enumeratedValues>
                                <enumeratedValue>
                                    <name>0</name>
                                    <description>No effect on output</description>
                                    <value>#0</value>
                                </enumeratedValue>
                                <enumeratedValue>
                                    <name>1</name>
                                    <description>High output</description>
                                    <value>#1</value>
                                </enumeratedValue>
                            </enumeratedValues>
                        </field>
                        <field>
                            <name>POSR02</name>
                            <description>Pmn Output Set</description>
                            <lsb>2</lsb>
                            <msb>2</msb>
                            <access>write-only</access>
                            <enumeratedValues>
                                <enumeratedValue>
                                    <name>0</name>
                                    <description>No effect on output</description>
                                    <value>#0</value>
                                </enumeratedValue>
                                <enumeratedValue>
                                    <name>1</name>
                                    <description>High output</description>
                                    <value>#1</value>
                                </enumeratedValue>
                            </enumeratedValues>
                        </field>
                        <field>
                            <name>POSR03</name>
                            <description>Pmn Output Set</description>
                            <lsb>3</lsb>
                            <msb>3</msb>
                            <access>write-only</access>
                            <enumeratedValues>
                                <enumeratedValue>
                                    <name>0</name>
                                    <description>No effect on output</description>
                                    <value>#0</value>
                                </enumeratedValue>
                                <enumeratedValue>
                                    <name>1</name>
                                    <description>High output</description>
                                    <value>#1</value>
                                </enumeratedValue>
                            </enumeratedValues>
                        </field>
                        <field>
                            <name>POSR04</name>
                            <description>Pmn Output Set</description>
                            <lsb>4</lsb>
                            <msb>4</msb>
                            <access>write-only</access>
                            <enumeratedValues>
                                <enumeratedValue>
                                    <name>0</name>
                                    <description>No effect on output</description>
                                    <value>#0</value>
                                </enumeratedValue>
                                <enumeratedValue>
                                    <name>1</name>
                                    <description>High output</description>
                                    <value>#1</value>
                                </enumeratedValue>
                            </enumeratedValues>
                        </field>
                        <field>
                            <name>POSR05</name>
                            <description>Pmn Output Set</description>
                            <lsb>5</lsb>
                            <msb>5</msb>
                            <access>write-only</access>
                            <enumeratedValues>
                                <enumeratedValue>
                                    <name>0</name>
                                    <description>No effect on output</description>
                                    <value>#0</value>
                                </enumeratedValue>
                                <enumeratedValue>
                                    <name>1</name>
                                    <description>High output</description>
                                    <value>#1</value>
                                </enumeratedValue>
                            </enumeratedValues>
                        </field>
                        <field>
                            <name>POSR06</name>
                            <description>Pmn Output Set</description>
                            <lsb>6</lsb>
                            <msb>6</msb>
                            <access>write-only</access>
                            <enumeratedValues>
                                <enumeratedValue>
                                    <name>0</name>
                                    <description>No effect on output</description>
                                    <value>#0</value>
                                </enumeratedValue>
                                <enumeratedValue>
                                    <name>1</name>
                                    <description>High output</description>
                                    <value>#1</value>
                                </enumeratedValue>
                            </enumeratedValues>
                        </field>
                        <field>
                            <name>POSR07</name>
                            <description>Pmn Output Set</description>
                            <lsb>7</lsb>
                            <msb>7</msb>
                            <access>write-only</access>
                            <enumeratedValues>
                                <enumeratedValue>
                                    <name>0</name>
                                    <description>No effect on output</description>
                                    <value>#0</value>
                                </enumeratedValue>
                                <enumeratedValue>
                                    <name>1</name>
                                    <description>High output</description>
                                    <value>#1</value>
                                </enumeratedValue>
                            </enumeratedValues>
                        </field>
                        <field>
                            <name>POSR08</name>
                            <description>Pmn Output Set</description>
                            <lsb>8</lsb>
                            <msb>8</msb>
                            <access>write-only</access>
                            <enumeratedValues>
                                <enumeratedValue>
                                    <name>0</name>
                                    <description>No effect on output</description>
                                    <value>#0</value>
                                </enumeratedValue>
                                <enumeratedValue>
                                    <name>1</name>
                                    <description>High output</description>
                                    <value>#1</value>
                                </enumeratedValue>
                            </enumeratedValues>
                        </field>
                        <field>
                            <name>POSR09</name>
                            <description>Pmn Output Set</description>
                            <lsb>9</lsb>
                            <msb>9</msb>
                            <access>write-only</access>
                            <enumeratedValues>
                                <enumeratedValue>
                                    <name>0</name>
                                    <description>No effect on output</description>
                                    <value>#0</value>
                                </enumeratedValue>
                                <enumeratedValue>
                                    <name>1</name>
                                    <description>High output</description>
                                    <value>#1</value>
                                </enumeratedValue>
                            </enumeratedValues>
                        </field>
                        <field>
                            <name>POSR10</name>
                            <description>Pmn Output Set</description>
                            <lsb>10</lsb>
                            <msb>10</msb>
                            <access>write-only</access>
                            <enumeratedValues>
                                <enumeratedValue>
                                    <name>0</name>
                                    <description>No effect on output</description>
                                    <value>#0</value>
                                </enumeratedValue>
                                <enumeratedValue>
                                    <name>1</name>
                                    <description>High output</description>
                                    <value>#1</value>
                                </enumeratedValue>
                            </enumeratedValues>
                        </field>
                        <field>
                            <name>POSR11</name>
                            <description>Pmn Output Set</description>
                            <lsb>11</lsb>
                            <msb>11</msb>
                            <access>write-only</access>
                            <enumeratedValues>
                                <enumeratedValue>
                                    <name>0</name>
                                    <description>No effect on output</description>
                                    <value>#0</value>
                                </enumeratedValue>
                                <enumeratedValue>
                                    <name>1</name>
                                    <description>High output</description>
                                    <value>#1</value>
                                </enumeratedValue>
                            </enumeratedValues>
                        </field>
                        <field>
                            <name>POSR12</name>
                            <description>Pmn Output Set</description>
                            <lsb>12</lsb>
                            <msb>12</msb>
                            <access>write-only</access>
                            <enumeratedValues>
                                <enumeratedValue>
                                    <name>0</name>
                                    <description>No effect on output</description>
                                    <value>#0</value>
                                </enumeratedValue>
                                <enumeratedValue>
                                    <name>1</name>
                                    <description>High output</description>
                                    <value>#1</value>
                                </enumeratedValue>
                            </enumeratedValues>
                        </field>
                        <field>
                            <name>POSR13</name>
                            <description>Pmn Output Set</description>
                            <lsb>13</lsb>
                            <msb>13</msb>
                            <access>write-only</access>
                            <enumeratedValues>
                                <enumeratedValue>
                                    <name>0</name>
                                    <description>No effect on output</description>
                                    <value>#0</value>
                                </enumeratedValue>
                                <enumeratedValue>
                                    <name>1</name>
                                    <description>High output</description>
                                    <value>#1</value>
                                </enumeratedValue>
                            </enumeratedValues>
                        </field>
                        <field>
                            <name>POSR14</name>
                            <description>Pmn Output Set</description>
                            <lsb>14</lsb>
                            <msb>14</msb>
                            <access>write-only</access>
                            <enumeratedValues>
                                <enumeratedValue>
                                    <name>0</name>
                                    <description>No effect on output</description>
                                    <value>#0</value>
                                </enumeratedValue>
                                <enumeratedValue>
                                    <name>1</name>
                                    <description>High output</description>
                                    <value>#1</value>
                                </enumeratedValue>
                            </enumeratedValues>
                        </field>
                        <field>
                            <name>POSR15</name>
                            <description>Pmn Output Set</description>
                            <lsb>15</lsb>
                            <msb>15</msb>
                            <access>write-only</access>
                            <enumeratedValues>
                                <enumeratedValue>
                                    <name>0</name>
                                    <description>No effect on output</description>
                                    <value>#0</value>
                                </enumeratedValue>
                                <enumeratedValue>
                                    <name>1</name>
                                    <description>High output</description>
                                    <value>#1</value>
                                </enumeratedValue>
                            </enumeratedValues>
                        </field>
                    </fields>
                </register>
            </registers>
        </peripheral>
        <peripheral>
            <name>PFS_NS</name>
            <description>Control Register</description>
            <baseAddress>0x50400800</baseAddress>
            <addressBlock>
                <offset>0x00</offset>
                <size>48</size>
                <usage>registers</usage>
            </addressBlock>
            <addressBlock>
                <offset>0x38</offset>
                <size>40</size>
                <usage>registers</usage>
            </addressBlock>
            <addressBlock>
                <offset>0x70</offset>
                <size>20</size>
                <usage>registers</usage>
            </addressBlock>
            <addressBlock>
                <offset>0x84</offset>
                <size>4</size>
                <usage>registers</usage>
            </addressBlock>
            <addressBlock>
                <offset>0x88</offset>
                <size>28</size>
                <usage>registers</usage>
            </addressBlock>
            <addressBlock>
                <offset>0xA4</offset>
                <size>4</size>
                <usage>registers</usage>
            </addressBlock>
            <addressBlock>
                <offset>0xA8</offset>
                <size>4</size>
                <usage>registers</usage>
            </addressBlock>
            <addressBlock>
                <offset>0xAC</offset>
                <size>4</size>
                <usage>registers</usage>
            </addressBlock>
            <addressBlock>
                <offset>0xB0</offset>
                <size>8</size>
                <usage>registers</usage>
            </addressBlock>
            <addressBlock>
                <offset>0xC0</offset>
                <size>544</size>
                <usage>registers</usage>
            </addressBlock>
            <addressBlock>
                <offset>0x500</offset>
                <size>1</size>
                <usage>registers</usage>
            </addressBlock>
            <addressBlock>
                <offset>0x50C</offset>
                <size>1</size>
                <usage>registers</usage>
            </addressBlock>
            <addressBlock>
                <offset>0x530</offset>
                <size>48</size>
                <usage>registers</usage>
            </addressBlock>
            <registers>
                <register>
                    <dim>10</dim>
                    <dimIncrement>0x004</dimIncrement>
                    <dimIndex>0-9</dimIndex>
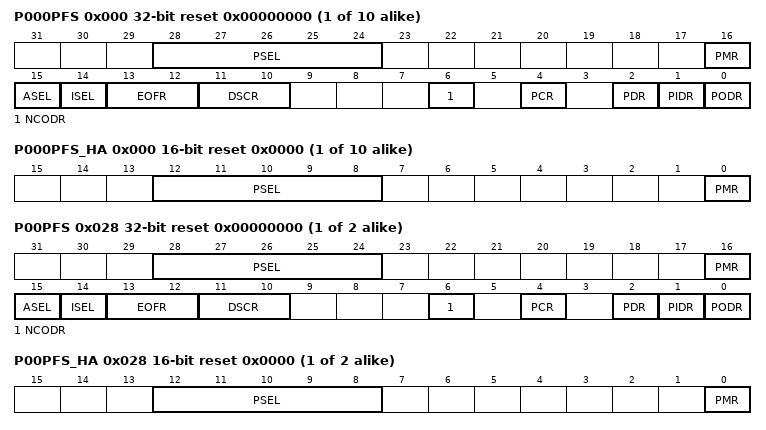
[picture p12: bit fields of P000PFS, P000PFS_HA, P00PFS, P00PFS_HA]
                    <name>P00%sPFS</name>
                    <description>Port 00%s Pin Function Select Register</description>
                    <addressOffset>0x000</addressOffset>
                    <size>32</size>
                    <access>read-write</access>
                    <resetValue>0x00000000</resetValue>
                    <resetMask>0xffffffff</resetMask>
                    <fields>
                        <field>
                            <name>PODR</name>
                            <description>Port Output Data</description>
                            <lsb>0</lsb>
                            <msb>0</msb>
                            <access>read-write</access>
                            <enumeratedValues>
                                <enumeratedValue>
                                    <name>0</name>
                                    <description>Low output</description>
                                    <value>#0</value>
                                </enumeratedValue>
                                <enumeratedValue>
                                    <name>1</name>
                                    <description>High output</description>
                                    <value>#1</value>
                                </enumeratedValue>
                            </enumeratedValues>
                        </field>
                        <field>
                            <name>PIDR</name>
                            <description>Pmn State</description>
                            <lsb>1</lsb>
                            <msb>1</msb>
                            <access>read-only</access>
                            <enumeratedValues>
                                <enumeratedValue>
                                    <name>0</name>
                                    <description>Low level</description>
                                    <value>#0</value>
                                </enumeratedValue>
                                <enumeratedValue>
                                    <name>1</name>
                                    <description>High level</description>
                                    <value>#1</value>
                                </enumeratedValue>
                            </enumeratedValues>
                        </field>
                        <field>
                            <name>PDR</name>
                            <description>Port Direction</description>
                            <lsb>2</lsb>
                            <msb>2</msb>
                            <access>read-write</access>
                            <enumeratedValues>
                                <enumeratedValue>
                                    <name>0</name>
                                    <description>Input (functions as an input pin)</description>
                                    <value>#0</value>
                                </enumeratedValue>
                                <enumeratedValue>
                                    <name>1</name>
                                    <description>Output (functions as an output pin)</description>
                                    <value>#1</value>
                                </enumeratedValue>
                            </enumeratedValues>
                        </field>
                        <field>
                            <name>PCR</name>
                            <description>Pull-up Control</description>
                            <lsb>4</lsb>
                            <msb>4</msb>
                            <access>read-write</access>
                            <enumeratedValues>
                                <enumeratedValue>
                                    <name>0</name>
                                    <description>Disable input pull-up</description>
                                    <value>#0</value>
                                </enumeratedValue>
                                <enumeratedValue>
                                    <name>1</name>
                                    <description>Enable input pull-up</description>
                                    <value>#1</value>
                                </enumeratedValue>
                            </enumeratedValues>
                        </field>
                        <field>
                            <name>NCODR</name>
                            <description>N-Channel Open-Drain Control</description>
                            <lsb>6</lsb>
                            <msb>6</msb>
                            <access>read-write</access>
                            <enumeratedValues>
                                <enumeratedValue>
                                    <name>0</name>
                                    <description>CMOS output</description>
                                    <value>#0</value>
                                </enumeratedValue>
                                <enumeratedValue>
                                    <name>1</name>
                                    <description>NMOS open-drain output</description>
                                    <value>#1</value>
                                </enumeratedValue>
                            </enumeratedValues>
                        </field>
                        <field>
                            <name>DSCR</name>
                            <description>Port Drive Capability</description>
                            <lsb>10</lsb>
                            <msb>11</msb>
                            <access>read-write</access>
                            <enumeratedValues>
                                <enumeratedValue>
                                    <name>00</name>
                                    <description>Low drive</description>
                                    <value>#00</value>
                                </enumeratedValue>
                                <enumeratedValue>
                                    <name>01</name>
                                    <description>Middle drive</description>
                                    <value>#01</value>
                                </enumeratedValue>
                                <enumeratedValue>
                                    <name>10</name>
                                    <description>High-speed high-drive</description>
                                    <value>#10</value>
                                </enumeratedValue>
                                <enumeratedValue>
                                    <name>11</name>
                                    <description>High drive</description>
                                    <value>#11</value>
                                </enumeratedValue>
                            </enumeratedValues>
                        </field>
                        <field>
                            <name>EOFR</name>
                            <description>Event on Falling/Event on Rising</description>
                            <lsb>12</lsb>
                            <msb>13</msb>
                            <access>read-write</access>
                            <enumeratedValues>
                                <enumeratedValue>
                                    <name>00</name>
                                    <description>Don't care</description>
                                    <value>#00</value>
                                </enumeratedValue>
                                <enumeratedValue>
                                    <name>01</name>
                                    <description>Detect rising edge</description>
                                    <value>#01</value>
                                </enumeratedValue>
                                <enumeratedValue>
                                    <name>10</name>
                                    <description>Detect falling edge</description>
                                    <value>#10</value>
                                </enumeratedValue>
                                <enumeratedValue>
                                    <name>11</name>
                                    <description>Detect both edges</description>
                                    <value>#11</value>
                                </enumeratedValue>
                            </enumeratedValues>
                        </field>
                        <field>
                            <name>ISEL</name>
                            <description>IRQ Input Enable</description>
                            <lsb>14</lsb>
                            <msb>14</msb>
                            <access>read-write</access>
                            <enumeratedValues>
                                <enumeratedValue>
                                    <name>0</name>
                                    <description>Not used as an IRQn input pin</description>
                                    <value>#0</value>
                                </enumeratedValue>
                                <enumeratedValue>
                                    <name>1</name>
                                    <description>Used as an IRQn input pin</description>
                                    <value>#1</value>
                                </enumeratedValue>
                            </enumeratedValues>
                        </field>
                        <field>
                            <name>ASEL</name>
                            <description>Analog Input Enable</description>
                            <lsb>15</lsb>
                            <msb>15</msb>
                            <access>read-write</access>
                            <enumeratedValues>
                                <enumeratedValue>
                                    <name>0</name>
                                    <description>Not used as an analog pin</description>
                                    <value>#0</value>
                                </enumeratedValue>
                                <enumeratedValue>
                                    <name>1</name>
                                    <description>Used as an analog pin</description>
                                    <value>#1</value>
                                </enumeratedValue>
                            </enumeratedValues>
                        </field>
                        <field>
                            <name>PMR</name>
                            <description>Port Mode Control</description>
                            <lsb>16</lsb>
                            <msb>16</msb>
                            <access>read-write</access>
                            <enumeratedValues>
                                <enumeratedValue>
                                    <name>0</name>
                                    <description>Used as a general I/O pin</description>
                                    <value>#0</value>
                                </enumeratedValue>
                                <enumeratedValue>
                                    <name>1</name>
                                    <description>Used as an I/O port for peripheral functions</description>
                                    <value>#1</value>
                                </enumeratedValue>
                            </enumeratedValues>
                        </field>
                        <field>
                            <name>PSEL</name>
                            <description>Peripheral Select</description>
                            <lsb>24</lsb>
                            <msb>28</msb>
                            <access>read-write</access>
                        </field>
                    </fields>
                </register>
                <register>
                    <dim>10</dim>
                    <dimIncrement>0x004</dimIncrement>
                    <dimIndex>0-9</dimIndex>
                    <name>P00%sPFS_HA</name>
                    <description>Port 00%s Pin Function Select Register</description>
                    <alternateRegister>P00%sPFS</alternateRegister>
                    <addressOffset>0x000</addressOffset>
                    <size>16</size>
                    <access>read-write</access>
                    <resetValue>0x0000</resetValue>
                    <resetMask>0xffff</resetMask>
                    <fields>
                        <field>
                            <name>PMR</name>
                            <description>Port Mode Control</description>
                            <lsb>0</lsb>
                            <msb>0</msb>
                            <access>read-write</access>
                            <enumeratedValues>
                                <enumeratedValue>
                                    <name>0</name>
                                    <description>Used as a general I/O pin</description>
                                    <value>#0</value>
                                </enumeratedValue>
                                <enumeratedValue>
                                    <name>1</name>
                                    <description>Used as an I/O port for peripheral functions</description>
                                    <value>#1</value>
                                </enumeratedValue>
                            </enumeratedValues>
                        </field>
                        <field>
                            <name>PSEL</name>
                            <description>Peripheral Select</description>
                            <lsb>8</lsb>
                            <msb>12</msb>
                            <access>read-write</access>
                        </field>
                    </fields>
                </register>
                <register>
                    <dim>10</dim>
                    <dimIncrement>0x004</dimIncrement>
                    <dimIndex>0-9</dimIndex>
                    <name>P00%sPFS_BY</name>
                    <description>Port 00%s Pin Function Select Register</description>
                    <alternateRegister>P00%sPFS</alternateRegister>
                    <addressOffset>0x000</addressOffset>
                    <size>8</size>
                    <access>read-write</access>
                    <resetValue>0x00</resetValue>
                    <resetMask>0xff</resetMask>
                    <fields>
                        <field>
                            <name>PSEL</name>
                            <description>Peripheral Select</description>
                            <lsb>0</lsb>
                            <msb>4</msb>
                            <access>read-write</access>
                        </field>
                    </fields>
                </register>
                <register>
                    <dim>2</dim>
                    <dimIncrement>0x004</dimIncrement>
                    <dimIndex>10-11</dimIndex>
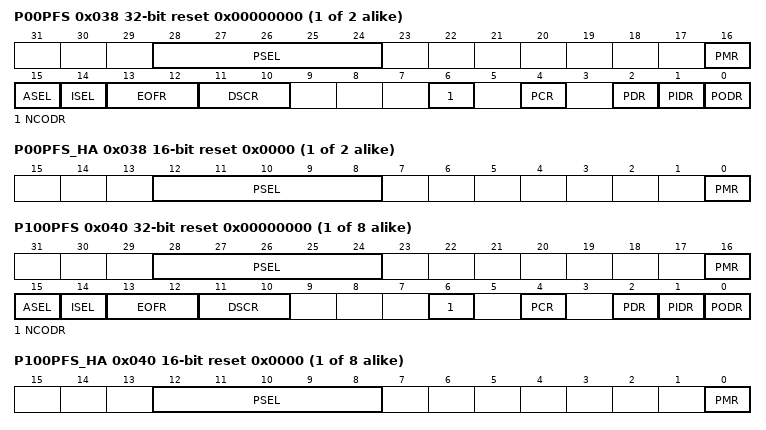
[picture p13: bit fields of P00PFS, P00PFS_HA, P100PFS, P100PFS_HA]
                    <name>P0%sPFS</name>
                    <description>Port 0%s Pin Function Select Register</description>
                    <addressOffset>0x028</addressOffset>
                    <size>32</size>
                    <access>read-write</access>
                    <resetValue>0x00000000</resetValue>
                    <resetMask>0xffffffff</resetMask>
                    <fields>
                        <field>
                            <name>PODR</name>
                            <description>Port Output Data</description>
                            <lsb>0</lsb>
                            <msb>0</msb>
                            <access>read-write</access>
                            <enumeratedValues>
                                <enumeratedValue>
                                    <name>0</name>
                                    <description>Low output</description>
                                    <value>#0</value>
                                </enumeratedValue>
                                <enumeratedValue>
                                    <name>1</name>
                                    <description>High output</description>
                                    <value>#1</value>
                                </enumeratedValue>
                            </enumeratedValues>
                        </field>
                        <field>
                            <name>PIDR</name>
                            <description>Pmn State</description>
                            <lsb>1</lsb>
                            <msb>1</msb>
                            <access>read-only</access>
                            <enumeratedValues>
                                <enumeratedValue>
                                    <name>0</name>
                                    <description>Low level</description>
                                    <value>#0</value>
                                </enumeratedValue>
                                <enumeratedValue>
                                    <name>1</name>
                                    <description>High level</description>
                                    <value>#1</value>
                                </enumeratedValue>
                            </enumeratedValues>
                        </field>
                        <field>
                            <name>PDR</name>
                            <description>Port Direction</description>
                            <lsb>2</lsb>
                            <msb>2</msb>
                            <access>read-write</access>
                            <enumeratedValues>
                                <enumeratedValue>
                                    <name>0</name>
                                    <description>Input (functions as an input pin)</description>
                                    <value>#0</value>
                                </enumeratedValue>
                                <enumeratedValue>
                                    <name>1</name>
                                    <description>Output (functions as an output pin)</description>
                                    <value>#1</value>
                                </enumeratedValue>
                            </enumeratedValues>
                        </field>
                        <field>
                            <name>PCR</name>
                            <description>Pull-up Control</description>
                            <lsb>4</lsb>
                            <msb>4</msb>
                            <access>read-write</access>
                            <enumeratedValues>
                                <enumeratedValue>
                                    <name>0</name>
                                    <description>Disable input pull-up</description>
                                    <value>#0</value>
                                </enumeratedValue>
                                <enumeratedValue>
                                    <name>1</name>
                                    <description>Enable input pull-up</description>
                                    <value>#1</value>
                                </enumeratedValue>
                            </enumeratedValues>
                        </field>
                        <field>
                            <name>NCODR</name>
                            <description>N-Channel Open-Drain Control</description>
                            <lsb>6</lsb>
                            <msb>6</msb>
                            <access>read-write</access>
                            <enumeratedValues>
                                <enumeratedValue>
                                    <name>0</name>
                                    <description>CMOS output</description>
                                    <value>#0</value>
                                </enumeratedValue>
                                <enumeratedValue>
                                    <name>1</name>
                                    <description>NMOS open-drain output</description>
                                    <value>#1</value>
                                </enumeratedValue>
                            </enumeratedValues>
                        </field>
                        <field>
                            <name>DSCR</name>
                            <description>Port Drive Capability</description>
                            <lsb>10</lsb>
                            <msb>11</msb>
                            <access>read-write</access>
                            <enumeratedValues>
                                <enumeratedValue>
                                    <name>00</name>
                                    <description>Low drive</description>
                                    <value>#00</value>
                                </enumeratedValue>
                                <enumeratedValue>
                                    <name>01</name>
                                    <description>Middle drive</description>
                                    <value>#01</value>
                                </enumeratedValue>
                                <enumeratedValue>
                                    <name>10</name>
                                    <description>High-speed high-drive</description>
                                    <value>#10</value>
                                </enumeratedValue>
                                <enumeratedValue>
                                    <name>11</name>
                                    <description>High drive</description>
                                    <value>#11</value>
                                </enumeratedValue>
                            </enumeratedValues>
                        </field>
                        <field>
                            <name>EOFR</name>
                            <description>Event on Falling/Event on Rising</description>
                            <lsb>12</lsb>
                            <msb>13</msb>
                            <access>read-write</access>
                            <enumeratedValues>
                                <enumeratedValue>
                                    <name>00</name>
                                    <description>Don't care</description>
                                    <value>#00</value>
                                </enumeratedValue>
                                <enumeratedValue>
                                    <name>01</name>
                                    <description>Detect rising edge</description>
                                    <value>#01</value>
                                </enumeratedValue>
                                <enumeratedValue>
                                    <name>10</name>
                                    <description>Detect falling edge</description>
                                    <value>#10</value>
                                </enumeratedValue>
                                <enumeratedValue>
                                    <name>11</name>
                                    <description>Detect both edges</description>
                                    <value>#11</value>
                                </enumeratedValue>
                            </enumeratedValues>
                        </field>
                        <field>
                            <name>ISEL</name>
                            <description>IRQ Input Enable</description>
                            <lsb>14</lsb>
                            <msb>14</msb>
                            <access>read-write</access>
                            <enumeratedValues>
                                <enumeratedValue>
                                    <name>0</name>
                                    <description>Not used as an IRQn input pin</description>
                                    <value>#0</value>
                                </enumeratedValue>
                                <enumeratedValue>
                                    <name>1</name>
                                    <description>Used as an IRQn input pin</description>
                                    <value>#1</value>
                                </enumeratedValue>
                            </enumeratedValues>
                        </field>
                        <field>
                            <name>ASEL</name>
                            <description>Analog Input Enable</description>
                            <lsb>15</lsb>
                            <msb>15</msb>
                            <access>read-write</access>
                            <enumeratedValues>
                                <enumeratedValue>
                                    <name>0</name>
                                    <description>Not used as an analog pin</description>
                                    <value>#0</value>
                                </enumeratedValue>
                                <enumeratedValue>
                                    <name>1</name>
                                    <description>Used as an analog pin</description>
                                    <value>#1</value>
                                </enumeratedValue>
                            </enumeratedValues>
                        </field>
                        <field>
                            <name>PMR</name>
                            <description>Port Mode Control</description>
                            <lsb>16</lsb>
                            <msb>16</msb>
                            <access>read-write</access>
                            <enumeratedValues>
                                <enumeratedValue>
                                    <name>0</name>
                                    <description>Used as a general I/O pin</description>
                                    <value>#0</value>
                                </enumeratedValue>
                                <enumeratedValue>
                                    <name>1</name>
                                    <description>Used as an I/O port for peripheral functions</description>
                                    <value>#1</value>
                                </enumeratedValue>
                            </enumeratedValues>
                        </field>
                        <field>
                            <name>PSEL</name>
                            <description>Peripheral Select</description>
                            <lsb>24</lsb>
                            <msb>28</msb>
                            <access>read-write</access>
                        </field>
                    </fields>
                </register>
                <register>
                    <dim>2</dim>
                    <dimIncrement>0x004</dimIncrement>
                    <dimIndex>10-11</dimIndex>
                    <name>P0%sPFS_HA</name>
                    <description>Port 0%s Pin Function Select Register</description>
                    <alternateRegister>P0%sPFS</alternateRegister>
                    <addressOffset>0x028</addressOffset>
                    <size>16</size>
                    <access>read-write</access>
                    <resetValue>0x0000</resetValue>
                    <resetMask>0xffff</resetMask>
                    <fields>
                        <field>
                            <name>PMR</name>
                            <description>Port Mode Control</description>
                            <lsb>0</lsb>
                            <msb>0</msb>
                            <access>read-write</access>
                            <enumeratedValues>
                                <enumeratedValue>
                                    <name>0</name>
                                    <description>Used as a general I/O pin</description>
                                    <value>#0</value>
                                </enumeratedValue>
                                <enumeratedValue>
                                    <name>1</name>
                                    <description>Used as an I/O port for peripheral functions</description>
                                    <value>#1</value>
                                </enumeratedValue>
                            </enumeratedValues>
                        </field>
                        <field>
                            <name>PSEL</name>
                            <description>Peripheral Select</description>
                            <lsb>8</lsb>
                            <msb>12</msb>
                            <access>read-write</access>
                        </field>
                    </fields>
                </register>
                <register>
                    <dim>2</dim>
                    <dimIncrement>0x004</dimIncrement>
                    <dimIndex>10-11</dimIndex>
                    <name>P0%sPFS_BY</name>
                    <description>Port 0%s Pin Function Select Register</description>
                    <alternateRegister>P0%sPFS</alternateRegister>
                    <addressOffset>0x028</addressOffset>
                    <size>8</size>
                    <access>read-write</access>
                    <resetValue>0x00</resetValue>
                    <resetMask>0xff</resetMask>
                    <fields>
                        <field>
                            <name>PSEL</name>
                            <description>Peripheral Select</description>
                            <lsb>0</lsb>
                            <msb>4</msb>
                            <access>read-write</access>
                        </field>
                    </fields>
                </register>
                <register>
                    <dim>2</dim>
                    <dimIncrement>0x004</dimIncrement>
                    <dimIndex>14-15</dimIndex>
                    <name>P0%sPFS</name>
                    <description>Port 0%s Pin Function Select Register</description>
                    <addressOffset>0x038</addressOffset>
                    <size>32</size>
                    <access>read-write</access>
                    <resetValue>0x00000000</resetValue>
                    <resetMask>0xffffffff</resetMask>
                    <fields>
                        <field>
                            <name>PODR</name>
                            <description>Port Output Data</description>
                            <lsb>0</lsb>
                            <msb>0</msb>
                            <access>read-write</access>
                            <enumeratedValues>
                                <enumeratedValue>
                                    <name>0</name>
                                    <description>Low output</description>
                                    <value>#0</value>
                                </enumeratedValue>
                                <enumeratedValue>
                                    <name>1</name>
                                    <description>High output</description>
                                    <value>#1</value>
                                </enumeratedValue>
                            </enumeratedValues>
                        </field>
                        <field>
                            <name>PIDR</name>
                            <description>Pmn State</description>
                            <lsb>1</lsb>
                            <msb>1</msb>
                            <access>read-only</access>
                            <enumeratedValues>
                                <enumeratedValue>
                                    <name>0</name>
                                    <description>Low level</description>
                                    <value>#0</value>
                                </enumeratedValue>
                                <enumeratedValue>
                                    <name>1</name>
                                    <description>High level</description>
                                    <value>#1</value>
                                </enumeratedValue>
                            </enumeratedValues>
                        </field>
                        <field>
                            <name>PDR</name>
                            <description>Port Direction</description>
                            <lsb>2</lsb>
                            <msb>2</msb>
                            <access>read-write</access>
                            <enumeratedValues>
                                <enumeratedValue>
                                    <name>0</name>
                                    <description>Input (functions as an input pin)</description>
                                    <value>#0</value>
                                </enumeratedValue>
                                <enumeratedValue>
                                    <name>1</name>
                                    <description>Output (functions as an output pin)</description>
                                    <value>#1</value>
                                </enumeratedValue>
                            </enumeratedValues>
                        </field>
                        <field>
                            <name>PCR</name>
                            <description>Pull-up Control</description>
                            <lsb>4</lsb>
                            <msb>4</msb>
                            <access>read-write</access>
                            <enumeratedValues>
                                <enumeratedValue>
                                    <name>0</name>
                                    <description>Disable input pull-up</description>
                                    <value>#0</value>
                                </enumeratedValue>
                                <enumeratedValue>
                                    <name>1</name>
                                    <description>Enable input pull-up</description>
                                    <value>#1</value>
                                </enumeratedValue>
                            </enumeratedValues>
                        </field>
                        <field>
                            <name>NCODR</name>
                            <description>N-Channel Open-Drain Control</description>
                            <lsb>6</lsb>
                            <msb>6</msb>
                            <access>read-write</access>
                            <enumeratedValues>
                                <enumeratedValue>
                                    <name>0</name>
                                    <description>CMOS output</description>
                                    <value>#0</value>
                                </enumeratedValue>
                                <enumeratedValue>
                                    <name>1</name>
                                    <description>NMOS open-drain output</description>
                                    <value>#1</value>
                                </enumeratedValue>
                            </enumeratedValues>
                        </field>
                        <field>
                            <name>DSCR</name>
                            <description>Port Drive Capability</description>
                            <lsb>10</lsb>
                            <msb>11</msb>
                            <access>read-write</access>
                            <enumeratedValues>
                                <enumeratedValue>
                                    <name>00</name>
                                    <description>Low drive</description>
                                    <value>#00</value>
                                </enumeratedValue>
                                <enumeratedValue>
                                    <name>01</name>
                                    <description>Middle drive</description>
                                    <value>#01</value>
                                </enumeratedValue>
                                <enumeratedValue>
                                    <name>10</name>
                                    <description>High-speed high-drive</description>
                                    <value>#10</value>
                                </enumeratedValue>
                                <enumeratedValue>
                                    <name>11</name>
                                    <description>High drive</description>
                                    <value>#11</value>
                                </enumeratedValue>
                            </enumeratedValues>
                        </field>
                        <field>
                            <name>EOFR</name>
                            <description>Event on Falling/Event on Rising</description>
                            <lsb>12</lsb>
                            <msb>13</msb>
                            <access>read-write</access>
                            <enumeratedValues>
                                <enumeratedValue>
                                    <name>00</name>
                                    <description>Don't care</description>
                                    <value>#00</value>
                                </enumeratedValue>
                                <enumeratedValue>
                                    <name>01</name>
                                    <description>Detect rising edge</description>
                                    <value>#01</value>
                                </enumeratedValue>
                                <enumeratedValue>
                                    <name>10</name>
                                    <description>Detect falling edge</description>
                                    <value>#10</value>
                                </enumeratedValue>
                                <enumeratedValue>
                                    <name>11</name>
                                    <description>Detect both edges</description>
                                    <value>#11</value>
                                </enumeratedValue>
                            </enumeratedValues>
                        </field>
                        <field>
                            <name>ISEL</name>
                            <description>IRQ Input Enable</description>
                            <lsb>14</lsb>
                            <msb>14</msb>
                            <access>read-write</access>
                            <enumeratedValues>
                                <enumeratedValue>
                                    <name>0</name>
                                    <description>Not used as an IRQn input pin</description>
                                    <value>#0</value>
                                </enumeratedValue>
                                <enumeratedValue>
                                    <name>1</name>
                                    <description>Used as an IRQn input pin</description>
                                    <value>#1</value>
                                </enumeratedValue>
                            </enumeratedValues>
                        </field>
                        <field>
                            <name>ASEL</name>
                            <description>Analog Input Enable</description>
                            <lsb>15</lsb>
                            <msb>15</msb>
                            <access>read-write</access>
                            <enumeratedValues>
                                <enumeratedValue>
                                    <name>0</name>
                                    <description>Not used as an analog pin</description>
                                    <value>#0</value>
                                </enumeratedValue>
                                <enumeratedValue>
                                    <name>1</name>
                                    <description>Used as an analog pin</description>
                                    <value>#1</value>
                                </enumeratedValue>
                            </enumeratedValues>
                        </field>
                        <field>
                            <name>PMR</name>
                            <description>Port Mode Control</description>
                            <lsb>16</lsb>
                            <msb>16</msb>
                            <access>read-write</access>
                            <enumeratedValues>
                                <enumeratedValue>
                                    <name>0</name>
                                    <description>Used as a general I/O pin</description>
                                    <value>#0</value>
                                </enumeratedValue>
                                <enumeratedValue>
                                    <name>1</name>
                                    <description>Used as an I/O port for peripheral functions</description>
                                    <value>#1</value>
                                </enumeratedValue>
                            </enumeratedValues>
                        </field>
                        <field>
                            <name>PSEL</name>
                            <description>Peripheral Select</description>
                            <lsb>24</lsb>
                            <msb>28</msb>
                            <access>read-write</access>
                        </field>
                    </fields>
                </register>
                <register>
                    <dim>2</dim>
                    <dimIncrement>0x004</dimIncrement>
                    <dimIndex>14-15</dimIndex>
                    <name>P0%sPFS_HA</name>
                    <description>Port 0%s Pin Function Select Register</description>
                    <alternateRegister>P0%sPFS</alternateRegister>
                    <addressOffset>0x038</addressOffset>
                    <size>16</size>
                    <access>read-write</access>
                    <resetValue>0x0000</resetValue>
                    <resetMask>0xffff</resetMask>
                    <fields>
                        <field>
                            <name>PMR</name>
                            <description>Port Mode Control</description>
                            <lsb>0</lsb>
                            <msb>0</msb>
                            <access>read-write</access>
                            <enumeratedValues>
                                <enumeratedValue>
                                    <name>0</name>
                                    <description>Used as a general I/O pin</description>
                                    <value>#0</value>
                                </enumeratedValue>
                                <enumeratedValue>
                                    <name>1</name>
                                    <description>Used as an I/O port for peripheral functions</description>
                                    <value>#1</value>
                                </enumeratedValue>
                            </enumeratedValues>
                        </field>
                        <field>
                            <name>PSEL</name>
                            <description>Peripheral Select</description>
                            <lsb>8</lsb>
                            <msb>12</msb>
                            <access>read-write</access>
                        </field>
                    </fields>
                </register>
                <register>
                    <dim>2</dim>
                    <dimIncrement>0x004</dimIncrement>
                    <dimIndex>14-15</dimIndex>
                    <name>P0%sPFS_BY</name>
                    <description>Port 0%s Pin Function Select Register</description>
                    <alternateRegister>P0%sPFS</alternateRegister>
                    <addressOffset>0x038</addressOffset>
                    <size>8</size>
                    <access>read-write</access>
                    <resetValue>0x00</resetValue>
                    <resetMask>0xff</resetMask>
                    <fields>
                        <field>
                            <name>PSEL</name>
                            <description>Peripheral Select</description>
                            <lsb>0</lsb>
                            <msb>4</msb>
                            <access>read-write</access>
                        </field>
                    </fields>
                </register>
                <register>
                    <dim>8</dim>
                    <dimIncrement>0x004</dimIncrement>
                    <dimIndex>0-7</dimIndex>
                    <name>P10%sPFS</name>
                    <description>Port 10%s Pin Function Select Register</description>
                    <addressOffset>0x040</addressOffset>
                    <size>32</size>
                    <access>read-write</access>
                    <resetValue>0x00000000</resetValue>
                    <resetMask>0xffffffff</resetMask>
                    <fields>
                        <field>
                            <name>PODR</name>
                            <description>Port Output Data</description>
                            <lsb>0</lsb>
                            <msb>0</msb>
                            <access>read-write</access>
                            <enumeratedValues>
                                <enumeratedValue>
                                    <name>0</name>
                                    <description>Low output</description>
                                    <value>#0</value>
                                </enumeratedValue>
                                <enumeratedValue>
                                    <name>1</name>
                                    <description>High output</description>
                                    <value>#1</value>
                                </enumeratedValue>
                            </enumeratedValues>
                        </field>
                        <field>
                            <name>PIDR</name>
                            <description>Pmn State</description>
                            <lsb>1</lsb>
                            <msb>1</msb>
                            <access>read-only</access>
                            <enumeratedValues>
                                <enumeratedValue>
                                    <name>0</name>
                                    <description>Low level</description>
                                    <value>#0</value>
                                </enumeratedValue>
                                <enumeratedValue>
                                    <name>1</name>
                                    <description>High level</description>
                                    <value>#1</value>
                                </enumeratedValue>
                            </enumeratedValues>
                        </field>
                        <field>
                            <name>PDR</name>
                            <description>Port Direction</description>
                            <lsb>2</lsb>
                            <msb>2</msb>
                            <access>read-write</access>
                            <enumeratedValues>
                                <enumeratedValue>
                                    <name>0</name>
                                    <description>Input (functions as an input pin)</description>
                                    <value>#0</value>
                                </enumeratedValue>
                                <enumeratedValue>
                                    <name>1</name>
                                    <description>Output (functions as an output pin)</description>
                                    <value>#1</value>
                                </enumeratedValue>
                            </enumeratedValues>
                        </field>
                        <field>
                            <name>PCR</name>
                            <description>Pull-up Control</description>
                            <lsb>4</lsb>
                            <msb>4</msb>
                            <access>read-write</access>
                            <enumeratedValues>
                                <enumeratedValue>
                                    <name>0</name>
                                    <description>Disable input pull-up</description>
                                    <value>#0</value>
                                </enumeratedValue>
                                <enumeratedValue>
                                    <name>1</name>
                                    <description>Enable input pull-up</description>
                                    <value>#1</value>
                                </enumeratedValue>
                            </enumeratedValues>
                        </field>
                        <field>
                            <name>NCODR</name>
                            <description>N-Channel Open-Drain Control</description>
                            <lsb>6</lsb>
                            <msb>6</msb>
                            <access>read-write</access>
                            <enumeratedValues>
                                <enumeratedValue>
                                    <name>0</name>
                                    <description>CMOS output</description>
                                    <value>#0</value>
                                </enumeratedValue>
                                <enumeratedValue>
                                    <name>1</name>
                                    <description>NMOS open-drain output</description>
                                    <value>#1</value>
                                </enumeratedValue>
                            </enumeratedValues>
                        </field>
                        <field>
                            <name>DSCR</name>
                            <description>Port Drive Capability</description>
                            <lsb>10</lsb>
                            <msb>11</msb>
                            <access>read-write</access>
                            <enumeratedValues>
                                <enumeratedValue>
                                    <name>00</name>
                                    <description>Low drive</description>
                                    <value>#00</value>
                                </enumeratedValue>
                                <enumeratedValue>
                                    <name>01</name>
                                    <description>Middle drive</description>
                                    <value>#01</value>
                                </enumeratedValue>
                                <enumeratedValue>
                                    <name>10</name>
                                    <description>High-speed high-drive</description>
                                    <value>#10</value>
                                </enumeratedValue>
                                <enumeratedValue>
                                    <name>11</name>
                                    <description>High drive</description>
                                    <value>#11</value>
                                </enumeratedValue>
                            </enumeratedValues>
                        </field>
                        <field>
                            <name>EOFR</name>
                            <description>Event on Falling/Event on Rising</description>
                            <lsb>12</lsb>
                            <msb>13</msb>
                            <access>read-write</access>
                            <enumeratedValues>
                                <enumeratedValue>
                                    <name>00</name>
                                    <description>Don't care</description>
                                    <value>#00</value>
                                </enumeratedValue>
                                <enumeratedValue>
                                    <name>01</name>
                                    <description>Detect rising edge</description>
                                    <value>#01</value>
                                </enumeratedValue>
                                <enumeratedValue>
                                    <name>10</name>
                                    <description>Detect falling edge</description>
                                    <value>#10</value>
                                </enumeratedValue>
                                <enumeratedValue>
                                    <name>11</name>
                                    <description>Detect both edges</description>
                                    <value>#11</value>
                                </enumeratedValue>
                            </enumeratedValues>
                        </field>
                        <field>
                            <name>ISEL</name>
                            <description>IRQ Input Enable</description>
                            <lsb>14</lsb>
                            <msb>14</msb>
                            <access>read-write</access>
                            <enumeratedValues>
                                <enumeratedValue>
                                    <name>0</name>
                                    <description>Not used as an IRQn input pin</description>
                                    <value>#0</value>
                                </enumeratedValue>
                                <enumeratedValue>
                                    <name>1</name>
                                    <description>Used as an IRQn input pin</description>
                                    <value>#1</value>
                                </enumeratedValue>
                            </enumeratedValues>
                        </field>
                        <field>
                            <name>ASEL</name>
                            <description>Analog Input Enable</description>
                            <lsb>15</lsb>
                            <msb>15</msb>
                            <access>read-write</access>
                            <enumeratedValues>
                                <enumeratedValue>
                                    <name>0</name>
                                    <description>Not used as an analog pin</description>
                                    <value>#0</value>
                                </enumeratedValue>
                                <enumeratedValue>
                                    <name>1</name>
                                    <description>Used as an analog pin</description>
                                    <value>#1</value>
                                </enumeratedValue>
                            </enumeratedValues>
                        </field>
                        <field>
                            <name>PMR</name>
                            <description>Port Mode Control</description>
                            <lsb>16</lsb>
                            <msb>16</msb>
                            <access>read-write</access>
                            <enumeratedValues>
                                <enumeratedValue>
                                    <name>0</name>
                                    <description>Used as a general I/O pin</description>
                                    <value>#0</value>
                                </enumeratedValue>
                                <enumeratedValue>
                                    <name>1</name>
                                    <description>Used as an I/O port for peripheral functions</description>
                                    <value>#1</value>
                                </enumeratedValue>
                            </enumeratedValues>
                        </field>
                        <field>
                            <name>PSEL</name>
                            <description>Peripheral Select</description>
                            <lsb>24</lsb>
                            <msb>28</msb>
                            <access>read-write</access>
                        </field>
                    </fields>
                </register>
                <register>
                    <dim>8</dim>
                    <dimIncrement>0x004</dimIncrement>
                    <dimIndex>0-7</dimIndex>
                    <name>P10%sPFS_HA</name>
                    <description>Port 10%s Pin Function Select Register</description>
                    <alternateRegister>P10%sPFS</alternateRegister>
                    <addressOffset>0x040</addressOffset>
                    <size>16</size>
                    <access>read-write</access>
                    <resetValue>0x0000</resetValue>
                    <resetMask>0xffff</resetMask>
                    <fields>
                        <field>
                            <name>PMR</name>
                            <description>Port Mode Control</description>
                            <lsb>0</lsb>
                            <msb>0</msb>
                            <access>read-write</access>
                            <enumeratedValues>
                                <enumeratedValue>
                                    <name>0</name>
                                    <description>Used as a general I/O pin</description>
                                    <value>#0</value>
                                </enumeratedValue>
                                <enumeratedValue>
                                    <name>1</name>
                                    <description>Used as an I/O port for peripheral functions</description>
                                    <value>#1</value>
                                </enumeratedValue>
                            </enumeratedValues>
                        </field>
                        <field>
                            <name>PSEL</name>
                            <description>Peripheral Select</description>
                            <lsb>8</lsb>
                            <msb>12</msb>
                            <access>read-write</access>
                        </field>
                    </fields>
                </register>
                <register>
                    <dim>8</dim>
                    <dimIncrement>0x004</dimIncrement>
                    <dimIndex>0-7</dimIndex>
                    <name>P10%sPFS_BY</name>
                    <description>Port 10%s Pin Function Select Register</description>
                    <alternateRegister>P10%sPFS</alternateRegister>
                    <addressOffset>0x040</addressOffset>
                    <size>8</size>
                    <access>read-write</access>
                    <resetValue>0x00</resetValue>
                    <resetMask>0xff</resetMask>
                    <fields>
                        <field>
                            <name>PSEL</name>
                            <description>Peripheral Select</description>
                            <lsb>0</lsb>
                            <msb>4</msb>
                            <access>read-write</access>
                        </field>
                    </fields>
                </register>
                <register>
                    <dim>4</dim>
                    <dimIncrement>0x004</dimIncrement>
                    <dimIndex>12-15</dimIndex>
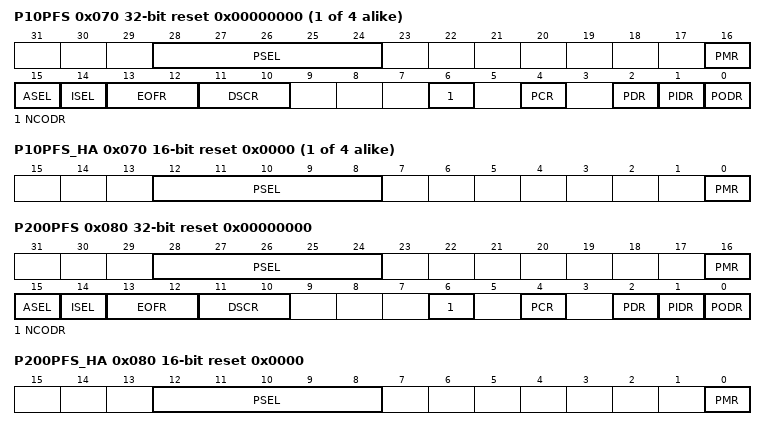
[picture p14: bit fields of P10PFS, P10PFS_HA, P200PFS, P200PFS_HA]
                    <name>P1%sPFS</name>
                    <description>Port 1%s Pin Function Select Register</description>
                    <addressOffset>0x070</addressOffset>
                    <size>32</size>
                    <access>read-write</access>
                    <resetValue>0x00000000</resetValue>
                    <resetMask>0xffffffff</resetMask>
                    <fields>
                        <field>
                            <name>PODR</name>
                            <description>Port Output Data</description>
                            <lsb>0</lsb>
                            <msb>0</msb>
                            <access>read-write</access>
                            <enumeratedValues>
                                <enumeratedValue>
                                    <name>0</name>
                                    <description>Low output</description>
                                    <value>#0</value>
                                </enumeratedValue>
                                <enumeratedValue>
                                    <name>1</name>
                                    <description>High output</description>
                                    <value>#1</value>
                                </enumeratedValue>
                            </enumeratedValues>
                        </field>
                        <field>
                            <name>PIDR</name>
                            <description>Pmn State</description>
                            <lsb>1</lsb>
                            <msb>1</msb>
                            <access>read-only</access>
                            <enumeratedValues>
                                <enumeratedValue>
                                    <name>0</name>
                                    <description>Low level</description>
                                    <value>#0</value>
                                </enumeratedValue>
                                <enumeratedValue>
                                    <name>1</name>
                                    <description>High level</description>
                                    <value>#1</value>
                                </enumeratedValue>
                            </enumeratedValues>
                        </field>
                        <field>
                            <name>PDR</name>
                            <description>Port Direction</description>
                            <lsb>2</lsb>
                            <msb>2</msb>
                            <access>read-write</access>
                            <enumeratedValues>
                                <enumeratedValue>
                                    <name>0</name>
                                    <description>Input (functions as an input pin)</description>
                                    <value>#0</value>
                                </enumeratedValue>
                                <enumeratedValue>
                                    <name>1</name>
                                    <description>Output (functions as an output pin)</description>
                                    <value>#1</value>
                                </enumeratedValue>
                            </enumeratedValues>
                        </field>
                        <field>
                            <name>PCR</name>
                            <description>Pull-up Control</description>
                            <lsb>4</lsb>
                            <msb>4</msb>
                            <access>read-write</access>
                            <enumeratedValues>
                                <enumeratedValue>
                                    <name>0</name>
                                    <description>Disable input pull-up</description>
                                    <value>#0</value>
                                </enumeratedValue>
                                <enumeratedValue>
                                    <name>1</name>
                                    <description>Enable input pull-up</description>
                                    <value>#1</value>
                                </enumeratedValue>
                            </enumeratedValues>
                        </field>
                        <field>
                            <name>NCODR</name>
                            <description>N-Channel Open-Drain Control</description>
                            <lsb>6</lsb>
                            <msb>6</msb>
                            <access>read-write</access>
                            <enumeratedValues>
                                <enumeratedValue>
                                    <name>0</name>
                                    <description>CMOS output</description>
                                    <value>#0</value>
                                </enumeratedValue>
                                <enumeratedValue>
                                    <name>1</name>
                                    <description>NMOS open-drain output</description>
                                    <value>#1</value>
                                </enumeratedValue>
                            </enumeratedValues>
                        </field>
                        <field>
                            <name>DSCR</name>
                            <description>Port Drive Capability</description>
                            <lsb>10</lsb>
                            <msb>11</msb>
                            <access>read-write</access>
                            <enumeratedValues>
                                <enumeratedValue>
                                    <name>00</name>
                                    <description>Low drive</description>
                                    <value>#00</value>
                                </enumeratedValue>
                                <enumeratedValue>
                                    <name>01</name>
                                    <description>Middle drive</description>
                                    <value>#01</value>
                                </enumeratedValue>
                                <enumeratedValue>
                                    <name>10</name>
                                    <description>High-speed high-drive</description>
                                    <value>#10</value>
                                </enumeratedValue>
                                <enumeratedValue>
                                    <name>11</name>
                                    <description>High drive</description>
                                    <value>#11</value>
                                </enumeratedValue>
                            </enumeratedValues>
                        </field>
                        <field>
                            <name>EOFR</name>
                            <description>Event on Falling/Event on Rising</description>
                            <lsb>12</lsb>
                            <msb>13</msb>
                            <access>read-write</access>
                            <enumeratedValues>
                                <enumeratedValue>
                                    <name>00</name>
                                    <description>Don't care</description>
                                    <value>#00</value>
                                </enumeratedValue>
                                <enumeratedValue>
                                    <name>01</name>
                                    <description>Detect rising edge</description>
                                    <value>#01</value>
                                </enumeratedValue>
                                <enumeratedValue>
                                    <name>10</name>
                                    <description>Detect falling edge</description>
                                    <value>#10</value>
                                </enumeratedValue>
                                <enumeratedValue>
                                    <name>11</name>
                                    <description>Detect both edges</description>
                                    <value>#11</value>
                                </enumeratedValue>
                            </enumeratedValues>
                        </field>
                        <field>
                            <name>ISEL</name>
                            <description>IRQ Input Enable</description>
                            <lsb>14</lsb>
                            <msb>14</msb>
                            <access>read-write</access>
                            <enumeratedValues>
                                <enumeratedValue>
                                    <name>0</name>
                                    <description>Not used as an IRQn input pin</description>
                                    <value>#0</value>
                                </enumeratedValue>
                                <enumeratedValue>
                                    <name>1</name>
                                    <description>Used as an IRQn input pin</description>
                                    <value>#1</value>
                                </enumeratedValue>
                            </enumeratedValues>
                        </field>
                        <field>
                            <name>ASEL</name>
                            <description>Analog Input Enable</description>
                            <lsb>15</lsb>
                            <msb>15</msb>
                            <access>read-write</access>
                            <enumeratedValues>
                                <enumeratedValue>
                                    <name>0</name>
                                    <description>Not used as an analog pin</description>
                                    <value>#0</value>
                                </enumeratedValue>
                                <enumeratedValue>
                                    <name>1</name>
                                    <description>Used as an analog pin</description>
                                    <value>#1</value>
                                </enumeratedValue>
                            </enumeratedValues>
                        </field>
                        <field>
                            <name>PMR</name>
                            <description>Port Mode Control</description>
                            <lsb>16</lsb>
                            <msb>16</msb>
                            <access>read-write</access>
                            <enumeratedValues>
                                <enumeratedValue>
                                    <name>0</name>
                                    <description>Used as a general I/O pin</description>
                                    <value>#0</value>
                                </enumeratedValue>
                                <enumeratedValue>
                                    <name>1</name>
                                    <description>Used as an I/O port for peripheral functions</description>
                                    <value>#1</value>
                                </enumeratedValue>
                            </enumeratedValues>
                        </field>
                        <field>
                            <name>PSEL</name>
                            <description>Peripheral Select</description>
                            <lsb>24</lsb>
                            <msb>28</msb>
                            <access>read-write</access>
                        </field>
                    </fields>
                </register>
                <register>
                    <dim>4</dim>
                    <dimIncrement>0x004</dimIncrement>
                    <dimIndex>12-15</dimIndex>
                    <name>P1%sPFS_HA</name>
                    <description>Port 1%s Pin Function Select Register</description>
                    <alternateRegister>P1%sPFS</alternateRegister>
                    <addressOffset>0x070</addressOffset>
                    <size>16</size>
                    <access>read-write</access>
                    <resetValue>0x0000</resetValue>
                    <resetMask>0xffff</resetMask>
                    <fields>
                        <field>
                            <name>PMR</name>
                            <description>Port Mode Control</description>
                            <lsb>0</lsb>
                            <msb>0</msb>
                            <access>read-write</access>
                            <enumeratedValues>
                                <enumeratedValue>
                                    <name>0</name>
                                    <description>Used as a general I/O pin</description>
                                    <value>#0</value>
                                </enumeratedValue>
                                <enumeratedValue>
                                    <name>1</name>
                                    <description>Used as an I/O port for peripheral functions</description>
                                    <value>#1</value>
                                </enumeratedValue>
                            </enumeratedValues>
                        </field>
                        <field>
                            <name>PSEL</name>
                            <description>Peripheral Select</description>
                            <lsb>8</lsb>
                            <msb>12</msb>
                            <access>read-write</access>
                        </field>
                    </fields>
                </register>
                <register>
                    <dim>4</dim>
                    <dimIncrement>0x004</dimIncrement>
                    <dimIndex>12-15</dimIndex>
                    <name>P1%sPFS_BY</name>
                    <description>Port 1%s Pin Function Select Register</description>
                    <alternateRegister>P1%sPFS</alternateRegister>
                    <addressOffset>0x070</addressOffset>
                    <size>8</size>
                    <access>read-write</access>
                    <resetValue>0x00</resetValue>
                    <resetMask>0xff</resetMask>
                    <fields>
                        <field>
                            <name>PSEL</name>
                            <description>Peripheral Select</description>
                            <lsb>0</lsb>
                            <msb>4</msb>
                            <access>read-write</access>
                        </field>
                    </fields>
                </register>
                <register>
                    <name>P200PFS</name>
                    <description>Port 200 Pin Function Select Register</description>
                    <addressOffset>0x080</addressOffset>
                    <size>32</size>
                    <access>read-write</access>
                    <resetValue>0x00000000</resetValue>
                    <resetMask>0xffffffff</resetMask>
                    <fields>
                        <field>
                            <name>PODR</name>
                            <description>Port Output Data</description>
                            <lsb>0</lsb>
                            <msb>0</msb>
                            <access>read-write</access>
                            <enumeratedValues>
                                <enumeratedValue>
                                    <name>0</name>
                                    <description>Low output</description>
                                    <value>#0</value>
                                </enumeratedValue>
                                <enumeratedValue>
                                    <name>1</name>
                                    <description>High output</description>
                                    <value>#1</value>
                                </enumeratedValue>
                            </enumeratedValues>
                        </field>
                        <field>
                            <name>PIDR</name>
                            <description>Pmn State</description>
                            <lsb>1</lsb>
                            <msb>1</msb>
                            <access>read-only</access>
                            <enumeratedValues>
                                <enumeratedValue>
                                    <name>0</name>
                                    <description>Low level</description>
                                    <value>#0</value>
                                </enumeratedValue>
                                <enumeratedValue>
                                    <name>1</name>
                                    <description>High level</description>
                                    <value>#1</value>
                                </enumeratedValue>
                            </enumeratedValues>
                        </field>
                        <field>
                            <name>PDR</name>
                            <description>Port Direction</description>
                            <lsb>2</lsb>
                            <msb>2</msb>
                            <access>read-write</access>
                            <enumeratedValues>
                                <enumeratedValue>
                                    <name>0</name>
                                    <description>Input (functions as an input pin)</description>
                                    <value>#0</value>
                                </enumeratedValue>
                                <enumeratedValue>
                                    <name>1</name>
                                    <description>Output (functions as an output pin)</description>
                                    <value>#1</value>
                                </enumeratedValue>
                            </enumeratedValues>
                        </field>
                        <field>
                            <name>PCR</name>
                            <description>Pull-up Control</description>
                            <lsb>4</lsb>
                            <msb>4</msb>
                            <access>read-write</access>
                            <enumeratedValues>
                                <enumeratedValue>
                                    <name>0</name>
                                    <description>Disable input pull-up</description>
                                    <value>#0</value>
                                </enumeratedValue>
                                <enumeratedValue>
                                    <name>1</name>
                                    <description>Enable input pull-up</description>
                                    <value>#1</value>
                                </enumeratedValue>
                            </enumeratedValues>
                        </field>
                        <field>
                            <name>NCODR</name>
                            <description>N-Channel Open-Drain Control</description>
                            <lsb>6</lsb>
                            <msb>6</msb>
                            <access>read-write</access>
                            <enumeratedValues>
                                <enumeratedValue>
                                    <name>0</name>
                                    <description>CMOS output</description>
                                    <value>#0</value>
                                </enumeratedValue>
                                <enumeratedValue>
                                    <name>1</name>
                                    <description>NMOS open-drain output</description>
                                    <value>#1</value>
                                </enumeratedValue>
                            </enumeratedValues>
                        </field>
                        <field>
                            <name>DSCR</name>
                            <description>Port Drive Capability</description>
                            <lsb>10</lsb>
                            <msb>11</msb>
                            <access>read-write</access>
                            <enumeratedValues>
                                <enumeratedValue>
                                    <name>00</name>
                                    <description>Low drive</description>
                                    <value>#00</value>
                                </enumeratedValue>
                                <enumeratedValue>
                                    <name>01</name>
                                    <description>Middle drive</description>
                                    <value>#01</value>
                                </enumeratedValue>
                                <enumeratedValue>
                                    <name>10</name>
                                    <description>High-speed high-drive</description>
                                    <value>#10</value>
                                </enumeratedValue>
                                <enumeratedValue>
                                    <name>11</name>
                                    <description>High drive</description>
                                    <value>#11</value>
                                </enumeratedValue>
                            </enumeratedValues>
                        </field>
                        <field>
                            <name>EOFR</name>
                            <description>Event on Falling/Event on Rising</description>
                            <lsb>12</lsb>
                            <msb>13</msb>
                            <access>read-write</access>
                            <enumeratedValues>
                                <enumeratedValue>
                                    <name>00</name>
                                    <description>Don't care</description>
                                    <value>#00</value>
                                </enumeratedValue>
                                <enumeratedValue>
                                    <name>01</name>
                                    <description>Detect rising edge</description>
                                    <value>#01</value>
                                </enumeratedValue>
                                <enumeratedValue>
                                    <name>10</name>
                                    <description>Detect falling edge</description>
                                    <value>#10</value>
                                </enumeratedValue>
                                <enumeratedValue>
                                    <name>11</name>
                                    <description>Detect both edges</description>
                                    <value>#11</value>
                                </enumeratedValue>
                            </enumeratedValues>
                        </field>
                        <field>
                            <name>ISEL</name>
                            <description>IRQ Input Enable</description>
                            <lsb>14</lsb>
                            <msb>14</msb>
                            <access>read-write</access>
                            <enumeratedValues>
                                <enumeratedValue>
                                    <name>0</name>
                                    <description>Not used as an IRQn input pin</description>
                                    <value>#0</value>
                                </enumeratedValue>
                                <enumeratedValue>
                                    <name>1</name>
                                    <description>Used as an IRQn input pin</description>
                                    <value>#1</value>
                                </enumeratedValue>
                            </enumeratedValues>
                        </field>
                        <field>
                            <name>ASEL</name>
                            <description>Analog Input Enable</description>
                            <lsb>15</lsb>
                            <msb>15</msb>
                            <access>read-write</access>
                            <enumeratedValues>
                                <enumeratedValue>
                                    <name>0</name>
                                    <description>Not used as an analog pin</description>
                                    <value>#0</value>
                                </enumeratedValue>
                                <enumeratedValue>
                                    <name>1</name>
                                    <description>Used as an analog pin</description>
                                    <value>#1</value>
                                </enumeratedValue>
                            </enumeratedValues>
                        </field>
                        <field>
                            <name>PMR</name>
                            <description>Port Mode Control</description>
                            <lsb>16</lsb>
                            <msb>16</msb>
                            <access>read-write</access>
                            <enumeratedValues>
                                <enumeratedValue>
                                    <name>0</name>
                                    <description>Used as a general I/O pin</description>
                                    <value>#0</value>
                                </enumeratedValue>
                                <enumeratedValue>
                                    <name>1</name>
                                    <description>Used as an I/O port for peripheral functions</description>
                                    <value>#1</value>
                                </enumeratedValue>
                            </enumeratedValues>
                        </field>
                        <field>
                            <name>PSEL</name>
                            <description>Peripheral Select</description>
                            <lsb>24</lsb>
                            <msb>28</msb>
                            <access>read-write</access>
                        </field>
                    </fields>
                </register>
                <register>
                    <name>P200PFS_HA</name>
                    <description>Port 200 Pin Function Select Register</description>
                    <alternateRegister>P200PFS</alternateRegister>
                    <addressOffset>0x080</addressOffset>
                    <size>16</size>
                    <access>read-write</access>
                    <resetValue>0x0000</resetValue>
                    <resetMask>0xffff</resetMask>
                    <fields>
                        <field>
                            <name>PMR</name>
                            <description>Port Mode Control</description>
                            <lsb>0</lsb>
                            <msb>0</msb>
                            <access>read-write</access>
                            <enumeratedValues>
                                <enumeratedValue>
                                    <name>0</name>
                                    <description>Used as a general I/O pin</description>
                                    <value>#0</value>
                                </enumeratedValue>
                                <enumeratedValue>
                                    <name>1</name>
                                    <description>Used as an I/O port for peripheral functions</description>
                                    <value>#1</value>
                                </enumeratedValue>
                            </enumeratedValues>
                        </field>
                        <field>
                            <name>PSEL</name>
                            <description>Peripheral Select</description>
                            <lsb>8</lsb>
                            <msb>12</msb>
                            <access>read-write</access>
                        </field>
                    </fields>
                </register>
                <register>
                    <name>P200PFS_BY</name>
                    <description>Port 200 Pin Function Select Register</description>
                    <alternateRegister>P200PFS</alternateRegister>
                    <addressOffset>0x080</addressOffset>
                    <size>8</size>
                    <access>read-write</access>
                    <resetValue>0x00</resetValue>
                    <resetMask>0xff</resetMask>
                    <fields>
                        <field>
                            <name>PSEL</name>
                            <description>Peripheral Select</description>
                            <lsb>0</lsb>
                            <msb>4</msb>
                            <access>read-write</access>
                        </field>
                    </fields>
                </register>
                <register>
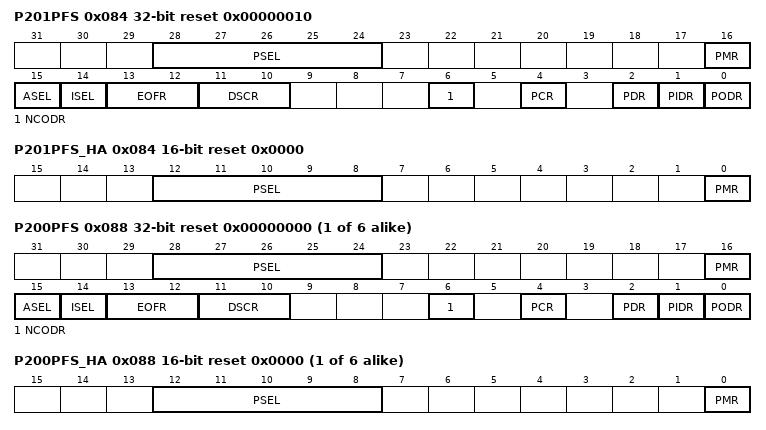
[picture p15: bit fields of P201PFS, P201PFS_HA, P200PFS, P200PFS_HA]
                    <name>P201PFS</name>
                    <description>Port 201 Pin Function Select Register</description>
                    <addressOffset>0x084</addressOffset>
                    <size>32</size>
                    <access>read-write</access>
                    <resetValue>0x00000010</resetValue>
                    <resetMask>0xffffffff</resetMask>
                    <fields>
                        <field>
                            <name>PODR</name>
                            <description>Port Output Data</description>
                            <lsb>0</lsb>
                            <msb>0</msb>
                            <access>read-write</access>
                            <enumeratedValues>
                                <enumeratedValue>
                                    <name>0</name>
                                    <description>Low output</description>
                                    <value>#0</value>
                                </enumeratedValue>
                                <enumeratedValue>
                                    <name>1</name>
                                    <description>High output</description>
                                    <value>#1</value>
                                </enumeratedValue>
                            </enumeratedValues>
                        </field>
                        <field>
                            <name>PIDR</name>
                            <description>Pmn State</description>
                            <lsb>1</lsb>
                            <msb>1</msb>
                            <access>read-only</access>
                            <enumeratedValues>
                                <enumeratedValue>
                                    <name>0</name>
                                    <description>Low level</description>
                                    <value>#0</value>
                                </enumeratedValue>
                                <enumeratedValue>
                                    <name>1</name>
                                    <description>High level</description>
                                    <value>#1</value>
                                </enumeratedValue>
                            </enumeratedValues>
                        </field>
                        <field>
                            <name>PDR</name>
                            <description>Port Direction</description>
                            <lsb>2</lsb>
                            <msb>2</msb>
                            <access>read-write</access>
                            <enumeratedValues>
                                <enumeratedValue>
                                    <name>0</name>
                                    <description>Input (functions as an input pin)</description>
                                    <value>#0</value>
                                </enumeratedValue>
                                <enumeratedValue>
                                    <name>1</name>
                                    <description>Output (functions as an output pin)</description>
                                    <value>#1</value>
                                </enumeratedValue>
                            </enumeratedValues>
                        </field>
                        <field>
                            <name>PCR</name>
                            <description>Pull-up Control</description>
                            <lsb>4</lsb>
                            <msb>4</msb>
                            <access>read-write</access>
                            <enumeratedValues>
                                <enumeratedValue>
                                    <name>0</name>
                                    <description>Disable input pull-up</description>
                                    <value>#0</value>
                                </enumeratedValue>
                                <enumeratedValue>
                                    <name>1</name>
                                    <description>Enable input pull-up</description>
                                    <value>#1</value>
                                </enumeratedValue>
                            </enumeratedValues>
                        </field>
                        <field>
                            <name>NCODR</name>
                            <description>N-Channel Open-Drain Control</description>
                            <lsb>6</lsb>
                            <msb>6</msb>
                            <access>read-write</access>
                            <enumeratedValues>
                                <enumeratedValue>
                                    <name>0</name>
                                    <description>CMOS output</description>
                                    <value>#0</value>
                                </enumeratedValue>
                                <enumeratedValue>
                                    <name>1</name>
                                    <description>NMOS open-drain output</description>
                                    <value>#1</value>
                                </enumeratedValue>
                            </enumeratedValues>
                        </field>
                        <field>
                            <name>DSCR</name>
                            <description>Port Drive Capability</description>
                            <lsb>10</lsb>
                            <msb>11</msb>
                            <access>read-write</access>
                            <enumeratedValues>
                                <enumeratedValue>
                                    <name>00</name>
                                    <description>Low drive</description>
                                    <value>#00</value>
                                </enumeratedValue>
                                <enumeratedValue>
                                    <name>01</name>
                                    <description>Middle drive</description>
                                    <value>#01</value>
                                </enumeratedValue>
                                <enumeratedValue>
                                    <name>10</name>
                                    <description>High-speed high-drive</description>
                                    <value>#10</value>
                                </enumeratedValue>
                                <enumeratedValue>
                                    <name>11</name>
                                    <description>High drive</description>
                                    <value>#11</value>
                                </enumeratedValue>
                            </enumeratedValues>
                        </field>
                        <field>
                            <name>EOFR</name>
                            <description>Event on Falling/Event on Rising</description>
                            <lsb>12</lsb>
                            <msb>13</msb>
                            <access>read-write</access>
                            <enumeratedValues>
                                <enumeratedValue>
                                    <name>00</name>
                                    <description>Don't care</description>
                                    <value>#00</value>
                                </enumeratedValue>
                                <enumeratedValue>
                                    <name>01</name>
                                    <description>Detect rising edge</description>
                                    <value>#01</value>
                                </enumeratedValue>
                                <enumeratedValue>
                                    <name>10</name>
                                    <description>Detect falling edge</description>
                                    <value>#10</value>
                                </enumeratedValue>
                                <enumeratedValue>
                                    <name>11</name>
                                    <description>Detect both edges</description>
                                    <value>#11</value>
                                </enumeratedValue>
                            </enumeratedValues>
                        </field>
                        <field>
                            <name>ISEL</name>
                            <description>IRQ Input Enable</description>
                            <lsb>14</lsb>
                            <msb>14</msb>
                            <access>read-write</access>
                            <enumeratedValues>
                                <enumeratedValue>
                                    <name>0</name>
                                    <description>Not used as an IRQn input pin</description>
                                    <value>#0</value>
                                </enumeratedValue>
                                <enumeratedValue>
                                    <name>1</name>
                                    <description>Used as an IRQn input pin</description>
                                    <value>#1</value>
                                </enumeratedValue>
                            </enumeratedValues>
                        </field>
                        <field>
                            <name>ASEL</name>
                            <description>Analog Input Enable</description>
                            <lsb>15</lsb>
                            <msb>15</msb>
                            <access>read-write</access>
                            <enumeratedValues>
                                <enumeratedValue>
                                    <name>0</name>
                                    <description>Not used as an analog pin</description>
                                    <value>#0</value>
                                </enumeratedValue>
                                <enumeratedValue>
                                    <name>1</name>
                                    <description>Used as an analog pin</description>
                                    <value>#1</value>
                                </enumeratedValue>
                            </enumeratedValues>
                        </field>
                        <field>
                            <name>PMR</name>
                            <description>Port Mode Control</description>
                            <lsb>16</lsb>
                            <msb>16</msb>
                            <access>read-write</access>
                            <enumeratedValues>
                                <enumeratedValue>
                                    <name>0</name>
                                    <description>Used as a general I/O pin</description>
                                    <value>#0</value>
                                </enumeratedValue>
                                <enumeratedValue>
                                    <name>1</name>
                                    <description>Used as an I/O port for peripheral functions</description>
                                    <value>#1</value>
                                </enumeratedValue>
                            </enumeratedValues>
                        </field>
                        <field>
                            <name>PSEL</name>
                            <description>Peripheral Select</description>
                            <lsb>24</lsb>
                            <msb>28</msb>
                            <access>read-write</access>
                        </field>
                    </fields>
                </register>
                <register>
                    <name>P201PFS_HA</name>
                    <description>Port 201 Pin Function Select Register</description>
                    <alternateRegister>P201PFS</alternateRegister>
                    <addressOffset>0x084</addressOffset>
                    <size>16</size>
                    <access>read-write</access>
                    <resetValue>0x0000</resetValue>
                    <resetMask>0xffff</resetMask>
                    <fields>
                        <field>
                            <name>PMR</name>
                            <description>Port Mode Control</description>
                            <lsb>0</lsb>
                            <msb>0</msb>
                            <access>read-write</access>
                            <enumeratedValues>
                                <enumeratedValue>
                                    <name>0</name>
                                    <description>Used as a general I/O pin</description>
                                    <value>#0</value>
                                </enumeratedValue>
                                <enumeratedValue>
                                    <name>1</name>
                                    <description>Used as an I/O port for peripheral functions</description>
                                    <value>#1</value>
                                </enumeratedValue>
                            </enumeratedValues>
                        </field>
                        <field>
                            <name>PSEL</name>
                            <description>Peripheral Select</description>
                            <lsb>8</lsb>
                            <msb>12</msb>
                            <access>read-write</access>
                        </field>
                    </fields>
                </register>
                <register>
                    <name>P201PFS_BY</name>
                    <description>Port 201 Pin Function Select Register</description>
                    <alternateRegister>P201PFS</alternateRegister>
                    <addressOffset>0x084</addressOffset>
                    <size>8</size>
                    <access>read-write</access>
                    <resetValue>0x00</resetValue>
                    <resetMask>0xff</resetMask>
                    <fields>
                        <field>
                            <name>PSEL</name>
                            <description>Peripheral Select</description>
                            <lsb>0</lsb>
                            <msb>4</msb>
                            <access>read-write</access>
                        </field>
                    </fields>
                </register>
                <register>
                    <dim>6</dim>
                    <dimIncrement>0x004</dimIncrement>
                    <dimIndex>2-7</dimIndex>
                    <name>P20%sPFS</name>
                    <description>Port 20%s Pin Function Select Register</description>
                    <addressOffset>0x088</addressOffset>
                    <size>32</size>
                    <access>read-write</access>
                    <resetValue>0x00000000</resetValue>
                    <resetMask>0xffffffff</resetMask>
                    <fields>
                        <field>
                            <name>PODR</name>
                            <description>Port Output Data</description>
                            <lsb>0</lsb>
                            <msb>0</msb>
                            <access>read-write</access>
                            <enumeratedValues>
                                <enumeratedValue>
                                    <name>0</name>
                                    <description>Low output</description>
                                    <value>#0</value>
                                </enumeratedValue>
                                <enumeratedValue>
                                    <name>1</name>
                                    <description>High output</description>
                                    <value>#1</value>
                                </enumeratedValue>
                            </enumeratedValues>
                        </field>
                        <field>
                            <name>PIDR</name>
                            <description>Pmn State</description>
                            <lsb>1</lsb>
                            <msb>1</msb>
                            <access>read-only</access>
                            <enumeratedValues>
                                <enumeratedValue>
                                    <name>0</name>
                                    <description>Low level</description>
                                    <value>#0</value>
                                </enumeratedValue>
                                <enumeratedValue>
                                    <name>1</name>
                                    <description>High level</description>
                                    <value>#1</value>
                                </enumeratedValue>
                            </enumeratedValues>
                        </field>
                        <field>
                            <name>PDR</name>
                            <description>Port Direction</description>
                            <lsb>2</lsb>
                            <msb>2</msb>
                            <access>read-write</access>
                            <enumeratedValues>
                                <enumeratedValue>
                                    <name>0</name>
                                    <description>Input (functions as an input pin)</description>
                                    <value>#0</value>
                                </enumeratedValue>
                                <enumeratedValue>
                                    <name>1</name>
                                    <description>Output (functions as an output pin)</description>
                                    <value>#1</value>
                                </enumeratedValue>
                            </enumeratedValues>
                        </field>
                        <field>
                            <name>PCR</name>
                            <description>Pull-up Control</description>
                            <lsb>4</lsb>
                            <msb>4</msb>
                            <access>read-write</access>
                            <enumeratedValues>
                                <enumeratedValue>
                                    <name>0</name>
                                    <description>Disable input pull-up</description>
                                    <value>#0</value>
                                </enumeratedValue>
                                <enumeratedValue>
                                    <name>1</name>
                                    <description>Enable input pull-up</description>
                                    <value>#1</value>
                                </enumeratedValue>
                            </enumeratedValues>
                        </field>
                        <field>
                            <name>NCODR</name>
                            <description>N-Channel Open-Drain Control</description>
                            <lsb>6</lsb>
                            <msb>6</msb>
                            <access>read-write</access>
                            <enumeratedValues>
                                <enumeratedValue>
                                    <name>0</name>
                                    <description>CMOS output</description>
                                    <value>#0</value>
                                </enumeratedValue>
                                <enumeratedValue>
                                    <name>1</name>
                                    <description>NMOS open-drain output</description>
                                    <value>#1</value>
                                </enumeratedValue>
                            </enumeratedValues>
                        </field>
                        <field>
                            <name>DSCR</name>
                            <description>Port Drive Capability</description>
                            <lsb>10</lsb>
                            <msb>11</msb>
                            <access>read-write</access>
                            <enumeratedValues>
                                <enumeratedValue>
                                    <name>00</name>
                                    <description>Low drive</description>
                                    <value>#00</value>
                                </enumeratedValue>
                                <enumeratedValue>
                                    <name>01</name>
                                    <description>Middle drive</description>
                                    <value>#01</value>
                                </enumeratedValue>
                                <enumeratedValue>
                                    <name>10</name>
                                    <description>High-speed high-drive</description>
                                    <value>#10</value>
                                </enumeratedValue>
                                <enumeratedValue>
                                    <name>11</name>
                                    <description>High drive</description>
                                    <value>#11</value>
                                </enumeratedValue>
                            </enumeratedValues>
                        </field>
                        <field>
                            <name>EOFR</name>
                            <description>Event on Falling/Event on Rising</description>
                            <lsb>12</lsb>
                            <msb>13</msb>
                            <access>read-write</access>
                            <enumeratedValues>
                                <enumeratedValue>
                                    <name>00</name>
                                    <description>Don't care</description>
                                    <value>#00</value>
                                </enumeratedValue>
                                <enumeratedValue>
                                    <name>01</name>
                                    <description>Detect rising edge</description>
                                    <value>#01</value>
                                </enumeratedValue>
                                <enumeratedValue>
                                    <name>10</name>
                                    <description>Detect falling edge</description>
                                    <value>#10</value>
                                </enumeratedValue>
                                <enumeratedValue>
                                    <name>11</name>
                                    <description>Detect both edges</description>
                                    <value>#11</value>
                                </enumeratedValue>
                            </enumeratedValues>
                        </field>
                        <field>
                            <name>ISEL</name>
                            <description>IRQ Input Enable</description>
                            <lsb>14</lsb>
                            <msb>14</msb>
                            <access>read-write</access>
                            <enumeratedValues>
                                <enumeratedValue>
                                    <name>0</name>
                                    <description>Not used as an IRQn input pin</description>
                                    <value>#0</value>
                                </enumeratedValue>
                                <enumeratedValue>
                                    <name>1</name>
                                    <description>Used as an IRQn input pin</description>
                                    <value>#1</value>
                                </enumeratedValue>
                            </enumeratedValues>
                        </field>
                        <field>
                            <name>ASEL</name>
                            <description>Analog Input Enable</description>
                            <lsb>15</lsb>
                            <msb>15</msb>
                            <access>read-write</access>
                            <enumeratedValues>
                                <enumeratedValue>
                                    <name>0</name>
                                    <description>Not used as an analog pin</description>
                                    <value>#0</value>
                                </enumeratedValue>
                                <enumeratedValue>
                                    <name>1</name>
                                    <description>Used as an analog pin</description>
                                    <value>#1</value>
                                </enumeratedValue>
                            </enumeratedValues>
                        </field>
                        <field>
                            <name>PMR</name>
                            <description>Port Mode Control</description>
                            <lsb>16</lsb>
                            <msb>16</msb>
                            <access>read-write</access>
                            <enumeratedValues>
                                <enumeratedValue>
                                    <name>0</name>
                                    <description>Used as a general I/O pin</description>
                                    <value>#0</value>
                                </enumeratedValue>
                                <enumeratedValue>
                                    <name>1</name>
                                    <description>Used as an I/O port for peripheral functions</description>
                                    <value>#1</value>
                                </enumeratedValue>
                            </enumeratedValues>
                        </field>
                        <field>
                            <name>PSEL</name>
                            <description>Peripheral Select</description>
                            <lsb>24</lsb>
                            <msb>28</msb>
                            <access>read-write</access>
                        </field>
                    </fields>
                </register>
                <register>
                    <dim>6</dim>
                    <dimIncrement>0x004</dimIncrement>
                    <dimIndex>2-7</dimIndex>
                    <name>P20%sPFS_HA</name>
                    <description>Port 20%s Pin Function Select Register</description>
                    <alternateRegister>P20%sPFS</alternateRegister>
                    <addressOffset>0x088</addressOffset>
                    <size>16</size>
                    <access>read-write</access>
                    <resetValue>0x0000</resetValue>
                    <resetMask>0xffff</resetMask>
                    <fields>
                        <field>
                            <name>PMR</name>
                            <description>Port Mode Control</description>
                            <lsb>0</lsb>
                            <msb>0</msb>
                            <access>read-write</access>
                            <enumeratedValues>
                                <enumeratedValue>
                                    <name>0</name>
                                    <description>Used as a general I/O pin</description>
                                    <value>#0</value>
                                </enumeratedValue>
                                <enumeratedValue>
                                    <name>1</name>
                                    <description>Used as an I/O port for peripheral functions</description>
                                    <value>#1</value>
                                </enumeratedValue>
                            </enumeratedValues>
                        </field>
                        <field>
                            <name>PSEL</name>
                            <description>Peripheral Select</description>
                            <lsb>8</lsb>
                            <msb>12</msb>
                            <access>read-write</access>
                        </field>
                    </fields>
                </register>
                <register>
                    <dim>6</dim>
                    <dimIncrement>0x004</dimIncrement>
                    <dimIndex>2-7</dimIndex>
                    <name>P20%sPFS_BY</name>
                    <description>Port 20%s Pin Function Select Register</description>
                    <alternateRegister>P20%sPFS</alternateRegister>
                    <addressOffset>0x088</addressOffset>
                    <size>8</size>
                    <access>read-write</access>
                    <resetValue>0x00</resetValue>
                    <resetMask>0xff</resetMask>
                    <fields>
                        <field>
                            <name>PSEL</name>
                            <description>Peripheral Select</description>
                            <lsb>0</lsb>
                            <msb>4</msb>
                            <access>read-write</access>
                        </field>
                    </fields>
                </register>
                <register>
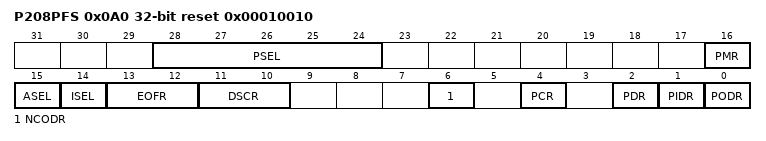
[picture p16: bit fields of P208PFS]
                    <name>P208PFS</name>
                    <description>Port 208 Pin Function Select Register</description>
                    <addressOffset>0x0A0</addressOffset>
                    <size>32</size>
                    <access>read-write</access>
                    <resetValue>0x00010010</resetValue>
                    <resetMask>0xffffffff</resetMask>
                    <fields>
                        <field>
                            <name>PODR</name>
                            <description>Port Output Data</description>
                            <lsb>0</lsb>
                            <msb>0</msb>
                            <access>read-write</access>
                            <enumeratedValues>
                                <enumeratedValue>
                                    <name>0</name>
                                    <description>Low output</description>
                                    <value>#0</value>
                                </enumeratedValue>
                                <enumeratedValue>
                                    <name>1</name>
                                    <description>High output</description>
                                    <value>#1</value>
                                </enumeratedValue>
                            </enumeratedValues>
                        </field>
                        <field>
                            <name>PIDR</name>
                            <description>Pmn State</description>
                            <lsb>1</lsb>
                            <msb>1</msb>
                            <access>read-only</access>
                            <enumeratedValues>
                                <enumeratedValue>
                                    <name>0</name>
                                    <description>Low level</description>
                                    <value>#0</value>
                                </enumeratedValue>
                                <enumeratedValue>
                                    <name>1</name>
                                    <description>High level</description>
                                    <value>#1</value>
                                </enumeratedValue>
                            </enumeratedValues>
                        </field>
                        <field>
                            <name>PDR</name>
                            <description>Port Direction</description>
                            <lsb>2</lsb>
                            <msb>2</msb>
                            <access>read-write</access>
                            <enumeratedValues>
                                <enumeratedValue>
                                    <name>0</name>
                                    <description>Input (functions as an input pin)</description>
                                    <value>#0</value>
                                </enumeratedValue>
                                <enumeratedValue>
                                    <name>1</name>
                                    <description>Output (functions as an output pin)</description>
                                    <value>#1</value>
                                </enumeratedValue>
                            </enumeratedValues>
                        </field>
                        <field>
                            <name>PCR</name>
                            <description>Pull-up Control</description>
                            <lsb>4</lsb>
                            <msb>4</msb>
                            <access>read-write</access>
                            <enumeratedValues>
                                <enumeratedValue>
                                    <name>0</name>
                                    <description>Disable input pull-up</description>
                                    <value>#0</value>
                                </enumeratedValue>
                                <enumeratedValue>
                                    <name>1</name>
                                    <description>Enable input pull-up</description>
                                    <value>#1</value>
                                </enumeratedValue>
                            </enumeratedValues>
                        </field>
                        <field>
                            <name>NCODR</name>
                            <description>N-Channel Open-Drain Control</description>
                            <lsb>6</lsb>
                            <msb>6</msb>
                            <access>read-write</access>
                            <enumeratedValues>
                                <enumeratedValue>
                                    <name>0</name>
                                    <description>CMOS output</description>
                                    <value>#0</value>
                                </enumeratedValue>
                                <enumeratedValue>
                                    <name>1</name>
                                    <description>NMOS open-drain output</description>
                                    <value>#1</value>
                                </enumeratedValue>
                            </enumeratedValues>
                        </field>
                        <field>
                            <name>DSCR</name>
                            <description>Port Drive Capability</description>
                            <lsb>10</lsb>
                            <msb>11</msb>
                            <access>read-write</access>
                            <enumeratedValues>
                                <enumeratedValue>
                                    <name>00</name>
                                    <description>Low drive</description>
                                    <value>#00</value>
                                </enumeratedValue>
                                <enumeratedValue>
                                    <name>01</name>
                                    <description>Middle drive</description>
                                    <value>#01</value>
                                </enumeratedValue>
                                <enumeratedValue>
                                    <name>10</name>
                                    <description>High-speed high-drive</description>
                                    <value>#10</value>
                                </enumeratedValue>
                                <enumeratedValue>
                                    <name>11</name>
                                    <description>High drive</description>
                                    <value>#11</value>
                                </enumeratedValue>
                            </enumeratedValues>
                        </field>
                        <field>
                            <name>EOFR</name>
                            <description>Event on Falling/Event on Rising</description>
                            <lsb>12</lsb>
                            <msb>13</msb>
                            <access>read-write</access>
                            <enumeratedValues>
                                <enumeratedValue>
                                    <name>00</name>
                                    <description>Don't care</description>
                                    <value>#00</value>
                                </enumeratedValue>
                                <enumeratedValue>
                                    <name>01</name>
                                    <description>Detect rising edge</description>
                                    <value>#01</value>
                                </enumeratedValue>
                                <enumeratedValue>
                                    <name>10</name>
                                    <description>Detect falling edge</description>
                                    <value>#10</value>
                                </enumeratedValue>
                                <enumeratedValue>
                                    <name>11</name>
                                    <description>Detect both edges</description>
                                    <value>#11</value>
                                </enumeratedValue>
                            </enumeratedValues>
                        </field>
                        <field>
                            <name>ISEL</name>
                            <description>IRQ Input Enable</description>
                            <lsb>14</lsb>
                            <msb>14</msb>
                            <access>read-write</access>
                            <enumeratedValues>
                                <enumeratedValue>
                                    <name>0</name>
                                    <description>Not used as an IRQn input pin</description>
                                    <value>#0</value>
                                </enumeratedValue>
                                <enumeratedValue>
                                    <name>1</name>
                                    <description>Used as an IRQn input pin</description>
                                    <value>#1</value>
                                </enumeratedValue>
                            </enumeratedValues>
                        </field>
                        <field>
                            <name>ASEL</name>
                            <description>Analog Input Enable</description>
                            <lsb>15</lsb>
                            <msb>15</msb>
                            <access>read-write</access>
                            <enumeratedValues>
                                <enumeratedValue>
                                    <name>0</name>
                                    <description>Not used as an analog pin</description>
                                    <value>#0</value>
                                </enumeratedValue>
                                <enumeratedValue>
                                    <name>1</name>
                                    <description>Used as an analog pin</description>
                                    <value>#1</value>
                                </enumeratedValue>
                            </enumeratedValues>
                        </field>
                        <field>
                            <name>PMR</name>
                            <description>Port Mode Control</description>
                            <lsb>16</lsb>
                            <msb>16</msb>
                            <access>read-write</access>
                            <enumeratedValues>
                                <enumeratedValue>
                                    <name>0</name>
                                    <description>Used as a general I/O pin</description>
                                    <value>#0</value>
                                </enumeratedValue>
                                <enumeratedValue>
                                    <name>1</name>
                                    <description>Used as an I/O port for peripheral functions</description>
                                    <value>#1</value>
                                </enumeratedValue>
                            </enumeratedValues>
                        </field>
                        <field>
                            <name>PSEL</name>
                            <description>Peripheral Select</description>
                            <lsb>24</lsb>
                            <msb>28</msb>
                            <access>read-write</access>
                        </field>
                    </fields>
                </register>
                <register>
                    <name>P208PFS_HA</name>
                    <description>Port 208 Pin Function Select Register</description>
                    <alternateRegister>P208PFS</alternateRegister>
                    <addressOffset>0x0A0</addressOffset>
                    <size>16</size>
                    <access>read-write</access>
                    <resetValue>0x0001</resetValue>
                    <resetMask>0xffff</resetMask>
                    <fields>
                        <field>
                            <name>PMR</name>
                            <description>Port Mode Control</description>
                            <lsb>0</lsb>
                            <msb>0</msb>
                            <access>read-write</access>
                            <enumeratedValues>
                                <enumeratedValue>
                                    <name>0</name>
                                    <description>Used as a general I/O pin</description>
                                    <value>#0</value>
                                </enumeratedValue>
                                <enumeratedValue>
                                    <name>1</name>
                                    <description>Used as an I/O port for peripheral functions</description>
                                    <value>#1</value>
                                </enumeratedValue>
                            </enumeratedValues>
                        </field>
                        <field>
                            <name>PSEL</name>
                            <description>Peripheral Select</description>
                            <lsb>8</lsb>
                            <msb>12</msb>
                            <access>read-write</access>
                        </field>
                    </fields>
                </register>
                <register>
                    <name>P208PFS_BY</name>
                    <description>Port 208 Pin Function Select Register</description>
                    <alternateRegister>P208PFS</alternateRegister>
                    <addressOffset>0x0A0</addressOffset>
                    <size>8</size>
                    <access>read-write</access>
                    <resetValue>0x00</resetValue>
                    <resetMask>0xff</resetMask>
                    <fields>
                        <field>
                            <name>PSEL</name>
                            <description>Peripheral Select</description>
                            <lsb>0</lsb>
                            <msb>4</msb>
                            <access>read-write</access>
                        </field>
                    </fields>
                </register>
                <register>
                    <name>P209PFS</name>
                    <description>Port 209 Pin Function Select Register</description>
                    <addressOffset>0x0A4</addressOffset>
                    <size>32</size>
                    <access>read-write</access>
                    <resetValue>0x00010400</resetValue>
                    <resetMask>0xffffffff</resetMask>
                    <fields>
                        <field>
                            <name>PODR</name>
                            <description>Port Output Data</description>
                            <lsb>0</lsb>
                            <msb>0</msb>
                            <access>read-write</access>
                            <enumeratedValues>
                                <enumeratedValue>
                                    <name>0</name>
                                    <description>Low output</description>
                                    <value>#0</value>
                                </enumeratedValue>
                                <enumeratedValue>
                                    <name>1</name>
                                    <description>High output</description>
                                    <value>#1</value>
                                </enumeratedValue>
                            </enumeratedValues>
                        </field>
                        <field>
                            <name>PIDR</name>
                            <description>Pmn State</description>
                            <lsb>1</lsb>
                            <msb>1</msb>
                            <access>read-only</access>
                            <enumeratedValues>
                                <enumeratedValue>
                                    <name>0</name>
                                    <description>Low level</description>
                                    <value>#0</value>
                                </enumeratedValue>
                                <enumeratedValue>
                                    <name>1</name>
                                    <description>High level</description>
                                    <value>#1</value>
                                </enumeratedValue>
                            </enumeratedValues>
                        </field>
                        <field>
                            <name>PDR</name>
                            <description>Port Direction</description>
                            <lsb>2</lsb>
                            <msb>2</msb>
                            <access>read-write</access>
                            <enumeratedValues>
                                <enumeratedValue>
                                    <name>0</name>
                                    <description>Input (functions as an input pin)</description>
                                    <value>#0</value>
                                </enumeratedValue>
                                <enumeratedValue>
                                    <name>1</name>
                                    <description>Output (functions as an output pin)</description>
                                    <value>#1</value>
                                </enumeratedValue>
                            </enumeratedValues>
                        </field>
                        <field>
                            <name>PCR</name>
                            <description>Pull-up Control</description>
                            <lsb>4</lsb>
                            <msb>4</msb>
                            <access>read-write</access>
                            <enumeratedValues>
                                <enumeratedValue>
                                    <name>0</name>
                                    <description>Disable input pull-up</description>
                                    <value>#0</value>
                                </enumeratedValue>
                                <enumeratedValue>
                                    <name>1</name>
                                    <description>Enable input pull-up</description>
                                    <value>#1</value>
                                </enumeratedValue>
                            </enumeratedValues>
                        </field>
                        <field>
                            <name>NCODR</name>
                            <description>N-Channel Open-Drain Control</description>
                            <lsb>6</lsb>
                            <msb>6</msb>
                            <access>read-write</access>
                            <enumeratedValues>
                                <enumeratedValue>
                                    <name>0</name>
                                    <description>CMOS output</description>
                                    <value>#0</value>
                                </enumeratedValue>
                                <enumeratedValue>
                                    <name>1</name>
                                    <description>NMOS open-drain output</description>
                                    <value>#1</value>
                                </enumeratedValue>
                            </enumeratedValues>
                        </field>
                        <field>
                            <name>DSCR</name>
                            <description>Port Drive Capability</description>
                            <lsb>10</lsb>
                            <msb>11</msb>
                            <access>read-write</access>
                            <enumeratedValues>
                                <enumeratedValue>
                                    <name>00</name>
                                    <description>Low drive</description>
                                    <value>#00</value>
                                </enumeratedValue>
                                <enumeratedValue>
                                    <name>01</name>
                                    <description>Middle drive</description>
                                    <value>#01</value>
                                </enumeratedValue>
                                <enumeratedValue>
                                    <name>10</name>
                                    <description>High-speed high-drive</description>
                                    <value>#10</value>
                                </enumeratedValue>
                                <enumeratedValue>
                                    <name>11</name>
                                    <description>High drive</description>
                                    <value>#11</value>
                                </enumeratedValue>
                            </enumeratedValues>
                        </field>
                        <field>
                            <name>EOFR</name>
                            <description>Event on Falling/Event on Rising</description>
                            <lsb>12</lsb>
                            <msb>13</msb>
                            <access>read-write</access>
                            <enumeratedValues>
                                <enumeratedValue>
                                    <name>00</name>
                                    <description>Don't care</description>
                                    <value>#00</value>
                                </enumeratedValue>
                                <enumeratedValue>
                                    <name>01</name>
                                    <description>Detect rising edge</description>
                                    <value>#01</value>
                                </enumeratedValue>
                                <enumeratedValue>
                                    <name>10</name>
                                    <description>Detect falling edge</description>
                                    <value>#10</value>
                                </enumeratedValue>
                                <enumeratedValue>
                                    <name>11</name>
                                    <description>Detect both edges</description>
                                    <value>#11</value>
                                </enumeratedValue>
                            </enumeratedValues>
                        </field>
                        <field>
                            <name>ISEL</name>
                            <description>IRQ Input Enable</description>
                            <lsb>14</lsb>
                            <msb>14</msb>
                            <access>read-write</access>
                            <enumeratedValues>
                                <enumeratedValue>
                                    <name>0</name>
                                    <description>Not used as an IRQn input pin</description>
                                    <value>#0</value>
                                </enumeratedValue>
                                <enumeratedValue>
                                    <name>1</name>
                                    <description>Used as an IRQn input pin</description>
                                    <value>#1</value>
                                </enumeratedValue>
                            </enumeratedValues>
                        </field>
                        <field>
                            <name>ASEL</name>
                            <description>Analog Input Enable</description>
                            <lsb>15</lsb>
                            <msb>15</msb>
                            <access>read-write</access>
                            <enumeratedValues>
                                <enumeratedValue>
                                    <name>0</name>
                                    <description>Not used as an analog pin</description>
                                    <value>#0</value>
                                </enumeratedValue>
                                <enumeratedValue>
                                    <name>1</name>
                                    <description>Used as an analog pin</description>
                                    <value>#1</value>
                                </enumeratedValue>
                            </enumeratedValues>
                        </field>
                        <field>
                            <name>PMR</name>
                            <description>Port Mode Control</description>
                            <lsb>16</lsb>
                            <msb>16</msb>
                            <access>read-write</access>
                            <enumeratedValues>
                                <enumeratedValue>
                                    <name>0</name>
                                    <description>Used as a general I/O pin</description>
                                    <value>#0</value>
                                </enumeratedValue>
                                <enumeratedValue>
                                    <name>1</name>
                                    <description>Used as an I/O port for peripheral functions</description>
                                    <value>#1</value>
                                </enumeratedValue>
                            </enumeratedValues>
                        </field>
                        <field>
                            <name>PSEL</name>
                            <description>Peripheral Select</description>
                            <lsb>24</lsb>
                            <msb>28</msb>
                            <access>read-write</access>
                        </field>
                    </fields>
                </register>
                <register>
                    <name>P209PFS_HA</name>
                    <description>Port 209 Pin Function Select Register</description>
                    <alternateRegister>P209PFS</alternateRegister>
                    <addressOffset>0x0A4</addressOffset>
                    <size>16</size>
                    <access>read-write</access>
                    <resetValue>0x0001</resetValue>
                    <resetMask>0xffff</resetMask>
                    <fields>
                        <field>
                            <name>PMR</name>
                            <description>Port Mode Control</description>
                            <lsb>0</lsb>
                            <msb>0</msb>
                            <access>read-write</access>
                            <enumeratedValues>
                                <enumeratedValue>
                                    <name>0</name>
                                    <description>Used as a general I/O pin</description>
                                    <value>#0</value>
                                </enumeratedValue>
                                <enumeratedValue>
                                    <name>1</name>
                                    <description>Used as an I/O port for peripheral functions</description>
                                    <value>#1</value>
                                </enumeratedValue>
                            </enumeratedValues>
                        </field>
                        <field>
                            <name>PSEL</name>
                            <description>Peripheral Select</description>
                            <lsb>8</lsb>
                            <msb>12</msb>
                            <access>read-write</access>
                        </field>
                    </fields>
                </register>
                <register>
                    <name>P209PFS_BY</name>
                    <description>Port 209 Pin Function Select Register</description>
                    <alternateRegister>P209PFS</alternateRegister>
                    <addressOffset>0x0A4</addressOffset>
                    <size>8</size>
                    <access>read-write</access>
                    <resetValue>0x00</resetValue>
                    <resetMask>0xff</resetMask>
                    <fields>
                        <field>
                            <name>PSEL</name>
                            <description>Peripheral Select</description>
                            <lsb>0</lsb>
                            <msb>4</msb>
                            <access>read-write</access>
                        </field>
                    </fields>
                </register>
                <register>
                    <name>P210PFS</name>
                    <description>Port 210 Pin Function Select Register</description>
                    <addressOffset>0x0A8</addressOffset>
                    <size>32</size>
                    <access>read-write</access>
                    <resetValue>0x00010410</resetValue>
                    <resetMask>0xffffffff</resetMask>
                    <fields>
                        <field>
                            <name>PODR</name>
                            <description>Port Output Data</description>
                            <lsb>0</lsb>
                            <msb>0</msb>
                            <access>read-write</access>
                            <enumeratedValues>
                                <enumeratedValue>
                                    <name>0</name>
                                    <description>Low output</description>
                                    <value>#0</value>
                                </enumeratedValue>
                                <enumeratedValue>
                                    <name>1</name>
                                    <description>High output</description>
                                    <value>#1</value>
                                </enumeratedValue>
                            </enumeratedValues>
                        </field>
                        <field>
                            <name>PIDR</name>
                            <description>Pmn State</description>
                            <lsb>1</lsb>
                            <msb>1</msb>
                            <access>read-only</access>
                            <enumeratedValues>
                                <enumeratedValue>
                                    <name>0</name>
                                    <description>Low level</description>
                                    <value>#0</value>
                                </enumeratedValue>
                                <enumeratedValue>
                                    <name>1</name>
                                    <description>High level</description>
                                    <value>#1</value>
                                </enumeratedValue>
                            </enumeratedValues>
                        </field>
                        <field>
                            <name>PDR</name>
                            <description>Port Direction</description>
                            <lsb>2</lsb>
                            <msb>2</msb>
                            <access>read-write</access>
                            <enumeratedValues>
                                <enumeratedValue>
                                    <name>0</name>
                                    <description>Input (functions as an input pin)</description>
                                    <value>#0</value>
                                </enumeratedValue>
                                <enumeratedValue>
                                    <name>1</name>
                                    <description>Output (functions as an output pin)</description>
                                    <value>#1</value>
                                </enumeratedValue>
                            </enumeratedValues>
                        </field>
                        <field>
                            <name>PCR</name>
                            <description>Pull-up Control</description>
                            <lsb>4</lsb>
                            <msb>4</msb>
                            <access>read-write</access>
                            <enumeratedValues>
                                <enumeratedValue>
                                    <name>0</name>
                                    <description>Disable input pull-up</description>
                                    <value>#0</value>
                                </enumeratedValue>
                                <enumeratedValue>
                                    <name>1</name>
                                    <description>Enable input pull-up</description>
                                    <value>#1</value>
                                </enumeratedValue>
                            </enumeratedValues>
                        </field>
                        <field>
                            <name>NCODR</name>
                            <description>N-Channel Open-Drain Control</description>
                            <lsb>6</lsb>
                            <msb>6</msb>
                            <access>read-write</access>
                            <enumeratedValues>
                                <enumeratedValue>
                                    <name>0</name>
                                    <description>CMOS output</description>
                                    <value>#0</value>
                                </enumeratedValue>
                                <enumeratedValue>
                                    <name>1</name>
                                    <description>NMOS open-drain output</description>
                                    <value>#1</value>
                                </enumeratedValue>
                            </enumeratedValues>
                        </field>
                        <field>
                            <name>DSCR</name>
                            <description>Port Drive Capability</description>
                            <lsb>10</lsb>
                            <msb>11</msb>
                            <access>read-write</access>
                            <enumeratedValues>
                                <enumeratedValue>
                                    <name>00</name>
                                    <description>Low drive</description>
                                    <value>#00</value>
                                </enumeratedValue>
                                <enumeratedValue>
                                    <name>01</name>
                                    <description>Middle drive</description>
                                    <value>#01</value>
                                </enumeratedValue>
                                <enumeratedValue>
                                    <name>10</name>
                                    <description>High-speed high-drive</description>
                                    <value>#10</value>
                                </enumeratedValue>
                                <enumeratedValue>
                                    <name>11</name>
                                    <description>High drive</description>
                                    <value>#11</value>
                                </enumeratedValue>
                            </enumeratedValues>
                        </field>
                        <field>
                            <name>EOFR</name>
                            <description>Event on Falling/Event on Rising</description>
                            <lsb>12</lsb>
                            <msb>13</msb>
                            <access>read-write</access>
                            <enumeratedValues>
                                <enumeratedValue>
                                    <name>00</name>
                                    <description>Don't care</description>
                                    <value>#00</value>
                                </enumeratedValue>
                                <enumeratedValue>
                                    <name>01</name>
                                    <description>Detect rising edge</description>
                                    <value>#01</value>
                                </enumeratedValue>
                                <enumeratedValue>
                                    <name>10</name>
                                    <description>Detect falling edge</description>
                                    <value>#10</value>
                                </enumeratedValue>
                                <enumeratedValue>
                                    <name>11</name>
                                    <description>Detect both edges</description>
                                    <value>#11</value>
                                </enumeratedValue>
                            </enumeratedValues>
                        </field>
                        <field>
                            <name>ISEL</name>
                            <description>IRQ Input Enable</description>
                            <lsb>14</lsb>
                            <msb>14</msb>
                            <access>read-write</access>
                            <enumeratedValues>
                                <enumeratedValue>
                                    <name>0</name>
                                    <description>Not used as an IRQn input pin</description>
                                    <value>#0</value>
                                </enumeratedValue>
                                <enumeratedValue>
                                    <name>1</name>
                                    <description>Used as an IRQn input pin</description>
                                    <value>#1</value>
                                </enumeratedValue>
                            </enumeratedValues>
                        </field>
                        <field>
                            <name>ASEL</name>
                            <description>Analog Input Enable</description>
                            <lsb>15</lsb>
                            <msb>15</msb>
                            <access>read-write</access>
                            <enumeratedValues>
                                <enumeratedValue>
                                    <name>0</name>
                                    <description>Not used as an analog pin</description>
                                    <value>#0</value>
                                </enumeratedValue>
                                <enumeratedValue>
                                    <name>1</name>
                                    <description>Used as an analog pin</description>
                                    <value>#1</value>
                                </enumeratedValue>
                            </enumeratedValues>
                        </field>
                        <field>
                            <name>PMR</name>
                            <description>Port Mode Control</description>
                            <lsb>16</lsb>
                            <msb>16</msb>
                            <access>read-write</access>
                            <enumeratedValues>
                                <enumeratedValue>
                                    <name>0</name>
                                    <description>Used as a general I/O pin</description>
                                    <value>#0</value>
                                </enumeratedValue>
                                <enumeratedValue>
                                    <name>1</name>
                                    <description>Used as an I/O port for peripheral functions</description>
                                    <value>#1</value>
                                </enumeratedValue>
                            </enumeratedValues>
                        </field>
                        <field>
                            <name>PSEL</name>
                            <description>Peripheral Select</description>
                            <lsb>24</lsb>
                            <msb>28</msb>
                            <access>read-write</access>
                        </field>
                    </fields>
                </register>
                <register>
                    <name>P210PFS_HA</name>
                    <description>Port 210 Pin Function Select Register</description>
                    <alternateRegister>P210PFS</alternateRegister>
                    <addressOffset>0x0A8</addressOffset>
                    <size>16</size>
                    <access>read-write</access>
                    <resetValue>0x0001</resetValue>
                    <resetMask>0xffff</resetMask>
                    <fields>
                        <field>
                            <name>PMR</name>
                            <description>Port Mode Control</description>
                            <lsb>0</lsb>
                            <msb>0</msb>
                            <access>read-write</access>
                            <enumeratedValues>
                                <enumeratedValue>
                                    <name>0</name>
                                    <description>Used as a general I/O pin</description>
                                    <value>#0</value>
                                </enumeratedValue>
                                <enumeratedValue>
                                    <name>1</name>
                                    <description>Used as an I/O port for peripheral functions</description>
                                    <value>#1</value>
                                </enumeratedValue>
                            </enumeratedValues>
                        </field>
                        <field>
                            <name>PSEL</name>
                            <description>Peripheral Select</description>
                            <lsb>8</lsb>
                            <msb>12</msb>
                            <access>read-write</access>
                        </field>
                    </fields>
                </register>
                <register>
                    <name>P210PFS_BY</name>
                    <description>Port 210 Pin Function Select Register</description>
                    <alternateRegister>P210PFS</alternateRegister>
                    <addressOffset>0x0A8</addressOffset>
                    <size>8</size>
                    <access>read-write</access>
                    <resetValue>0x00</resetValue>
                    <resetMask>0xff</resetMask>
                    <fields>
                        <field>
                            <name>PSEL</name>
                            <description>Peripheral Select</description>
                            <lsb>0</lsb>
                            <msb>4</msb>
                            <access>read-write</access>
                        </field>
                    </fields>
                </register>
                <register>
                    <name>P211PFS</name>
                    <description>Port 211 Pin Function Select Register</description>
                    <addressOffset>0x0AC</addressOffset>
                    <size>32</size>
                    <access>read-write</access>
                    <resetValue>0x00010010</resetValue>
                    <resetMask>0xffffffff</resetMask>
                    <fields>
                        <field>
                            <name>PODR</name>
                            <description>Port Output Data</description>
                            <lsb>0</lsb>
                            <msb>0</msb>
                            <access>read-write</access>
                            <enumeratedValues>
                                <enumeratedValue>
                                    <name>0</name>
                                    <description>Low output</description>
                                    <value>#0</value>
                                </enumeratedValue>
                                <enumeratedValue>
                                    <name>1</name>
                                    <description>High output</description>
                                    <value>#1</value>
                                </enumeratedValue>
                            </enumeratedValues>
                        </field>
                        <field>
                            <name>PIDR</name>
                            <description>Pmn State</description>
                            <lsb>1</lsb>
                            <msb>1</msb>
                            <access>read-only</access>
                            <enumeratedValues>
                                <enumeratedValue>
                                    <name>0</name>
                                    <description>Low level</description>
                                    <value>#0</value>
                                </enumeratedValue>
                                <enumeratedValue>
                                    <name>1</name>
                                    <description>High level</description>
                                    <value>#1</value>
                                </enumeratedValue>
                            </enumeratedValues>
                        </field>
                        <field>
                            <name>PDR</name>
                            <description>Port Direction</description>
                            <lsb>2</lsb>
                            <msb>2</msb>
                            <access>read-write</access>
                            <enumeratedValues>
                                <enumeratedValue>
                                    <name>0</name>
                                    <description>Input (functions as an input pin)</description>
                                    <value>#0</value>
                                </enumeratedValue>
                                <enumeratedValue>
                                    <name>1</name>
                                    <description>Output (functions as an output pin)</description>
                                    <value>#1</value>
                                </enumeratedValue>
                            </enumeratedValues>
                        </field>
                        <field>
                            <name>PCR</name>
                            <description>Pull-up Control</description>
                            <lsb>4</lsb>
                            <msb>4</msb>
                            <access>read-write</access>
                            <enumeratedValues>
                                <enumeratedValue>
                                    <name>0</name>
                                    <description>Disable input pull-up</description>
                                    <value>#0</value>
                                </enumeratedValue>
                                <enumeratedValue>
                                    <name>1</name>
                                    <description>Enable input pull-up</description>
                                    <value>#1</value>
                                </enumeratedValue>
                            </enumeratedValues>
                        </field>
                        <field>
                            <name>NCODR</name>
                            <description>N-Channel Open-Drain Control</description>
                            <lsb>6</lsb>
                            <msb>6</msb>
                            <access>read-write</access>
                            <enumeratedValues>
                                <enumeratedValue>
                                    <name>0</name>
                                    <description>CMOS output</description>
                                    <value>#0</value>
                                </enumeratedValue>
                                <enumeratedValue>
                                    <name>1</name>
                                    <description>NMOS open-drain output</description>
                                    <value>#1</value>
                                </enumeratedValue>
                            </enumeratedValues>
                        </field>
                        <field>
                            <name>DSCR</name>
                            <description>Port Drive Capability</description>
                            <lsb>10</lsb>
                            <msb>11</msb>
                            <access>read-write</access>
                            <enumeratedValues>
                                <enumeratedValue>
                                    <name>00</name>
                                    <description>Low drive</description>
                                    <value>#00</value>
                                </enumeratedValue>
                                <enumeratedValue>
                                    <name>01</name>
                                    <description>Middle drive</description>
                                    <value>#01</value>
                                </enumeratedValue>
                                <enumeratedValue>
                                    <name>10</name>
                                    <description>High-speed high-drive</description>
                                    <value>#10</value>
                                </enumeratedValue>
                                <enumeratedValue>
                                    <name>11</name>
                                    <description>High drive</description>
                                    <value>#11</value>
                                </enumeratedValue>
                            </enumeratedValues>
                        </field>
                        <field>
                            <name>EOFR</name>
                            <description>Event on Falling/Event on Rising</description>
                            <lsb>12</lsb>
                            <msb>13</msb>
                            <access>read-write</access>
                            <enumeratedValues>
                                <enumeratedValue>
                                    <name>00</name>
                                    <description>Don't care</description>
                                    <value>#00</value>
                                </enumeratedValue>
                                <enumeratedValue>
                                    <name>01</name>
                                    <description>Detect rising edge</description>
                                    <value>#01</value>
                                </enumeratedValue>
                                <enumeratedValue>
                                    <name>10</name>
                                    <description>Detect falling edge</description>
                                    <value>#10</value>
                                </enumeratedValue>
                                <enumeratedValue>
                                    <name>11</name>
                                    <description>Detect both edges</description>
                                    <value>#11</value>
                                </enumeratedValue>
                            </enumeratedValues>
                        </field>
                        <field>
                            <name>ISEL</name>
                            <description>IRQ Input Enable</description>
                            <lsb>14</lsb>
                            <msb>14</msb>
                            <access>read-write</access>
                            <enumeratedValues>
                                <enumeratedValue>
                                    <name>0</name>
                                    <description>Not used as an IRQn input pin</description>
                                    <value>#0</value>
                                </enumeratedValue>
                                <enumeratedValue>
                                    <name>1</name>
                                    <description>Used as an IRQn input pin</description>
                                    <value>#1</value>
                                </enumeratedValue>
                            </enumeratedValues>
                        </field>
                        <field>
                            <name>ASEL</name>
                            <description>Analog Input Enable</description>
                            <lsb>15</lsb>
                            <msb>15</msb>
                            <access>read-write</access>
                            <enumeratedValues>
                                <enumeratedValue>
                                    <name>0</name>
                                    <description>Not used as an analog pin</description>
                                    <value>#0</value>
                                </enumeratedValue>
                                <enumeratedValue>
                                    <name>1</name>
                                    <description>Used as an analog pin</description>
                                    <value>#1</value>
                                </enumeratedValue>
                            </enumeratedValues>
                        </field>
                        <field>
                            <name>PMR</name>
                            <description>Port Mode Control</description>
                            <lsb>16</lsb>
                            <msb>16</msb>
                            <access>read-write</access>
                            <enumeratedValues>
                                <enumeratedValue>
                                    <name>0</name>
                                    <description>Used as a general I/O pin</description>
                                    <value>#0</value>
                                </enumeratedValue>
                                <enumeratedValue>
                                    <name>1</name>
                                    <description>Used as an I/O port for peripheral functions</description>
                                    <value>#1</value>
                                </enumeratedValue>
                            </enumeratedValues>
                        </field>
                        <field>
                            <name>PSEL</name>
                            <description>Peripheral Select</description>
                            <lsb>24</lsb>
                            <msb>28</msb>
                            <access>read-write</access>
                        </field>
                    </fields>
                </register>
                <register>
                    <name>P211PFS_HA</name>
                    <description>Port 211 Pin Function Select Register</description>
                    <alternateRegister>P211PFS</alternateRegister>
                    <addressOffset>0x0AC</addressOffset>
                    <size>16</size>
                    <access>read-write</access>
                    <resetValue>0x0001</resetValue>
                    <resetMask>0xffff</resetMask>
                    <fields>
                        <field>
                            <name>PMR</name>
                            <description>Port Mode Control</description>
                            <lsb>0</lsb>
                            <msb>0</msb>
                            <access>read-write</access>
                            <enumeratedValues>
                                <enumeratedValue>
                                    <name>0</name>
                                    <description>Used as a general I/O pin</description>
                                    <value>#0</value>
                                </enumeratedValue>
                                <enumeratedValue>
                                    <name>1</name>
                                    <description>Used as an I/O port for peripheral functions</description>
                                    <value>#1</value>
                                </enumeratedValue>
                            </enumeratedValues>
                        </field>
                        <field>
                            <name>PSEL</name>
                            <description>Peripheral Select</description>
                            <lsb>8</lsb>
                            <msb>12</msb>
                            <access>read-write</access>
                        </field>
                    </fields>
                </register>
                <register>
                    <name>P211PFS_BY</name>
                    <description>Port 211 Pin Function Select Register</description>
                    <alternateRegister>P211PFS</alternateRegister>
                    <addressOffset>0x0AC</addressOffset>
                    <size>8</size>
                    <access>read-write</access>
                    <resetValue>0x00</resetValue>
                    <resetMask>0xff</resetMask>
                    <fields>
                        <field>
                            <name>PSEL</name>
                            <description>Peripheral Select</description>
                            <lsb>0</lsb>
                            <msb>4</msb>
                            <access>read-write</access>
                        </field>
                    </fields>
                </register>
                <register>
                    <dim>2</dim>
                    <dimIncrement>0x004</dimIncrement>
                    <dimIndex>12-13</dimIndex>
                    <name>P2%sPFS</name>
                    <description>Port 2%s Pin Function Select Register</description>
                    <addressOffset>0x0B0</addressOffset>
                    <size>32</size>
                    <access>read-write</access>
                    <resetValue>0x00000000</resetValue>
                    <resetMask>0xfffffffd</resetMask>
                    <fields>
                        <field>
                            <name>PODR</name>
                            <description>Port Output Data</description>
                            <lsb>0</lsb>
                            <msb>0</msb>
                            <access>read-write</access>
                            <enumeratedValues>
                                <enumeratedValue>
                                    <name>0</name>
                                    <description>Low output</description>
                                    <value>#0</value>
                                </enumeratedValue>
                                <enumeratedValue>
                                    <name>1</name>
                                    <description>High output</description>
                                    <value>#1</value>
                                </enumeratedValue>
                            </enumeratedValues>
                        </field>
                        <field>
                            <name>PIDR</name>
                            <description>Pmn State</description>
                            <lsb>1</lsb>
                            <msb>1</msb>
                            <access>read-only</access>
                            <enumeratedValues>
                                <enumeratedValue>
                                    <name>0</name>
                                    <description>Low level</description>
                                    <value>#0</value>
                                </enumeratedValue>
                                <enumeratedValue>
                                    <name>1</name>
                                    <description>High level</description>
                                    <value>#1</value>
                                </enumeratedValue>
                            </enumeratedValues>
                        </field>
                        <field>
                            <name>PDR</name>
                            <description>Port Direction</description>
                            <lsb>2</lsb>
                            <msb>2</msb>
                            <access>read-write</access>
                            <enumeratedValues>
                                <enumeratedValue>
                                    <name>0</name>
                                    <description>Input (functions as an input pin)</description>
                                    <value>#0</value>
                                </enumeratedValue>
                                <enumeratedValue>
                                    <name>1</name>
                                    <description>Output (functions as an output pin)</description>
                                    <value>#1</value>
                                </enumeratedValue>
                            </enumeratedValues>
                        </field>
                        <field>
                            <name>PCR</name>
                            <description>Pull-up Control</description>
                            <lsb>4</lsb>
                            <msb>4</msb>
                            <access>read-write</access>
                            <enumeratedValues>
                                <enumeratedValue>
                                    <name>0</name>
                                    <description>Disable input pull-up</description>
                                    <value>#0</value>
                                </enumeratedValue>
                                <enumeratedValue>
                                    <name>1</name>
                                    <description>Enable input pull-up</description>
                                    <value>#1</value>
                                </enumeratedValue>
                            </enumeratedValues>
                        </field>
                        <field>
                            <name>NCODR</name>
                            <description>N-Channel Open-Drain Control</description>
                            <lsb>6</lsb>
                            <msb>6</msb>
                            <access>read-write</access>
                            <enumeratedValues>
                                <enumeratedValue>
                                    <name>0</name>
                                    <description>CMOS output</description>
                                    <value>#0</value>
                                </enumeratedValue>
                                <enumeratedValue>
                                    <name>1</name>
                                    <description>NMOS open-drain output</description>
                                    <value>#1</value>
                                </enumeratedValue>
                            </enumeratedValues>
                        </field>
                        <field>
                            <name>DSCR</name>
                            <description>Port Drive Capability</description>
                            <lsb>10</lsb>
                            <msb>11</msb>
                            <access>read-write</access>
                            <enumeratedValues>
                                <enumeratedValue>
                                    <name>00</name>
                                    <description>Low drive</description>
                                    <value>#00</value>
                                </enumeratedValue>
                                <enumeratedValue>
                                    <name>01</name>
                                    <description>Middle drive</description>
                                    <value>#01</value>
                                </enumeratedValue>
                                <enumeratedValue>
                                    <name>10</name>
                                    <description>High-speed high-drive</description>
                                    <value>#10</value>
                                </enumeratedValue>
                                <enumeratedValue>
                                    <name>11</name>
                                    <description>High drive</description>
                                    <value>#11</value>
                                </enumeratedValue>
                            </enumeratedValues>
                        </field>
                        <field>
                            <name>EOFR</name>
                            <description>Event on Falling/Event on Rising</description>
                            <lsb>12</lsb>
                            <msb>13</msb>
                            <access>read-write</access>
                            <enumeratedValues>
                                <enumeratedValue>
                                    <name>00</name>
                                    <description>Don't care</description>
                                    <value>#00</value>
                                </enumeratedValue>
                                <enumeratedValue>
                                    <name>01</name>
                                    <description>Detect rising edge</description>
                                    <value>#01</value>
                                </enumeratedValue>
                                <enumeratedValue>
                                    <name>10</name>
                                    <description>Detect falling edge</description>
                                    <value>#10</value>
                                </enumeratedValue>
                                <enumeratedValue>
                                    <name>11</name>
                                    <description>Detect both edges</description>
                                    <value>#11</value>
                                </enumeratedValue>
                            </enumeratedValues>
                        </field>
                        <field>
                            <name>ISEL</name>
                            <description>IRQ Input Enable</description>
                            <lsb>14</lsb>
                            <msb>14</msb>
                            <access>read-write</access>
                            <enumeratedValues>
                                <enumeratedValue>
                                    <name>0</name>
                                    <description>Not used as an IRQn input pin</description>
                                    <value>#0</value>
                                </enumeratedValue>
                                <enumeratedValue>
                                    <name>1</name>
                                    <description>Used as an IRQn input pin</description>
                                    <value>#1</value>
                                </enumeratedValue>
                            </enumeratedValues>
                        </field>
                        <field>
                            <name>ASEL</name>
                            <description>Analog Input Enable</description>
                            <lsb>15</lsb>
                            <msb>15</msb>
                            <access>read-write</access>
                            <enumeratedValues>
                                <enumeratedValue>
                                    <name>0</name>
                                    <description>Not used as an analog pin</description>
                                    <value>#0</value>
                                </enumeratedValue>
                                <enumeratedValue>
                                    <name>1</name>
                                    <description>Used as an analog pin</description>
                                    <value>#1</value>
                                </enumeratedValue>
                            </enumeratedValues>
                        </field>
                        <field>
                            <name>PMR</name>
                            <description>Port Mode Control</description>
                            <lsb>16</lsb>
                            <msb>16</msb>
                            <access>read-write</access>
                            <enumeratedValues>
                                <enumeratedValue>
                                    <name>0</name>
                                    <description>Used as a general I/O pin</description>
                                    <value>#0</value>
                                </enumeratedValue>
                                <enumeratedValue>
                                    <name>1</name>
                                    <description>Used as an I/O port for peripheral functions</description>
                                    <value>#1</value>
                                </enumeratedValue>
                            </enumeratedValues>
                        </field>
                        <field>
                            <name>PSEL</name>
                            <description>Peripheral Select</description>
                            <lsb>24</lsb>
                            <msb>28</msb>
                            <access>read-write</access>
                        </field>
                    </fields>
                </register>
                <register>
                    <dim>2</dim>
                    <dimIncrement>0x004</dimIncrement>
                    <dimIndex>12-13</dimIndex>
                    <name>P2%sPFS_HA</name>
                    <description>Port 2%s Pin Function Select Register</description>
                    <alternateRegister>P2%sPFS</alternateRegister>
                    <addressOffset>0x0B0</addressOffset>
                    <size>16</size>
                    <access>read-write</access>
                    <resetValue>0x0000</resetValue>
                    <resetMask>0xffff</resetMask>
                    <fields>
                        <field>
                            <name>PMR</name>
                            <description>Port Mode Control</description>
                            <lsb>0</lsb>
                            <msb>0</msb>
                            <access>read-write</access>
                            <enumeratedValues>
                                <enumeratedValue>
                                    <name>0</name>
                                    <description>Used as a general I/O pin</description>
                                    <value>#0</value>
                                </enumeratedValue>
                                <enumeratedValue>
                                    <name>1</name>
                                    <description>Used as an I/O port for peripheral functions</description>
                                    <value>#1</value>
                                </enumeratedValue>
                            </enumeratedValues>
                        </field>
                        <field>
                            <name>PSEL</name>
                            <description>Peripheral Select</description>
                            <lsb>8</lsb>
                            <msb>12</msb>
                            <access>read-write</access>
                        </field>
                    </fields>
                </register>
                <register>
                    <dim>2</dim>
                    <dimIncrement>0x004</dimIncrement>
                    <dimIndex>12-13</dimIndex>
                    <name>P2%sPFS_BY</name>
                    <description>Port 2%s Pin Function Select Register</description>
                    <alternateRegister>P2%sPFS</alternateRegister>
                    <addressOffset>0x0B0</addressOffset>
                    <size>8</size>
                    <access>read-write</access>
                    <resetValue>0x00</resetValue>
                    <resetMask>0xff</resetMask>
                    <fields>
                        <field>
                            <name>PSEL</name>
                            <description>Peripheral Select</description>
                            <lsb>0</lsb>
                            <msb>4</msb>
                            <access>read-write</access>
                        </field>
                    </fields>
                </register>
                <register>
                    <dim>10</dim>
                    <dimIncrement>0x004</dimIncrement>
                    <dimIndex>0-9</dimIndex>
                    <name>P30%sPFS</name>
                    <description>Port 30%s Pin Function Select Register</description>
                    <addressOffset>0x0C0</addressOffset>
                    <size>32</size>
                    <access>read-write</access>
                    <resetValue>0x00000000</resetValue>
                    <resetMask>0xffffffff</resetMask>
                    <fields>
                        <field>
                            <name>PODR</name>
                            <description>Port Output Data</description>
                            <lsb>0</lsb>
                            <msb>0</msb>
                            <access>read-write</access>
                            <enumeratedValues>
                                <enumeratedValue>
                                    <name>0</name>
                                    <description>Low output</description>
                                    <value>#0</value>
                                </enumeratedValue>
                                <enumeratedValue>
                                    <name>1</name>
                                    <description>High output</description>
                                    <value>#1</value>
                                </enumeratedValue>
                            </enumeratedValues>
                        </field>
                        <field>
                            <name>PIDR</name>
                            <description>Pmn State</description>
                            <lsb>1</lsb>
                            <msb>1</msb>
                            <access>read-only</access>
                            <enumeratedValues>
                                <enumeratedValue>
                                    <name>0</name>
                                    <description>Low level</description>
                                    <value>#0</value>
                                </enumeratedValue>
                                <enumeratedValue>
                                    <name>1</name>
                                    <description>High level</description>
                                    <value>#1</value>
                                </enumeratedValue>
                            </enumeratedValues>
                        </field>
                        <field>
                            <name>PDR</name>
                            <description>Port Direction</description>
                            <lsb>2</lsb>
                            <msb>2</msb>
                            <access>read-write</access>
                            <enumeratedValues>
                                <enumeratedValue>
                                    <name>0</name>
                                    <description>Input (functions as an input pin)</description>
                                    <value>#0</value>
                                </enumeratedValue>
                                <enumeratedValue>
                                    <name>1</name>
                                    <description>Output (functions as an output pin)</description>
                                    <value>#1</value>
                                </enumeratedValue>
                            </enumeratedValues>
                        </field>
                        <field>
                            <name>PCR</name>
                            <description>Pull-up Control</description>
                            <lsb>4</lsb>
                            <msb>4</msb>
                            <access>read-write</access>
                            <enumeratedValues>
                                <enumeratedValue>
                                    <name>0</name>
                                    <description>Disable input pull-up</description>
                                    <value>#0</value>
                                </enumeratedValue>
                                <enumeratedValue>
                                    <name>1</name>
                                    <description>Enable input pull-up</description>
                                    <value>#1</value>
                                </enumeratedValue>
                            </enumeratedValues>
                        </field>
                        <field>
                            <name>NCODR</name>
                            <description>N-Channel Open-Drain Control</description>
                            <lsb>6</lsb>
                            <msb>6</msb>
                            <access>read-write</access>
                            <enumeratedValues>
                                <enumeratedValue>
                                    <name>0</name>
                                    <description>CMOS output</description>
                                    <value>#0</value>
                                </enumeratedValue>
                                <enumeratedValue>
                                    <name>1</name>
                                    <description>NMOS open-drain output</description>
                                    <value>#1</value>
                                </enumeratedValue>
                            </enumeratedValues>
                        </field>
                        <field>
                            <name>DSCR</name>
                            <description>Port Drive Capability</description>
                            <lsb>10</lsb>
                            <msb>11</msb>
                            <access>read-write</access>
                            <enumeratedValues>
                                <enumeratedValue>
                                    <name>00</name>
                                    <description>Low drive</description>
                                    <value>#00</value>
                                </enumeratedValue>
                                <enumeratedValue>
                                    <name>01</name>
                                    <description>Middle drive</description>
                                    <value>#01</value>
                                </enumeratedValue>
                                <enumeratedValue>
                                    <name>10</name>
                                    <description>High-speed high-drive</description>
                                    <value>#10</value>
                                </enumeratedValue>
                                <enumeratedValue>
                                    <name>11</name>
                                    <description>High drive</description>
                                    <value>#11</value>
                                </enumeratedValue>
                            </enumeratedValues>
                        </field>
                        <field>
                            <name>EOFR</name>
                            <description>Event on Falling/Event on Rising</description>
                            <lsb>12</lsb>
                            <msb>13</msb>
                            <access>read-write</access>
                            <enumeratedValues>
                                <enumeratedValue>
                                    <name>00</name>
                                    <description>Don't care</description>
                                    <value>#00</value>
                                </enumeratedValue>
                                <enumeratedValue>
                                    <name>01</name>
                                    <description>Detect rising edge</description>
                                    <value>#01</value>
                                </enumeratedValue>
                                <enumeratedValue>
                                    <name>10</name>
                                    <description>Detect falling edge</description>
                                    <value>#10</value>
                                </enumeratedValue>
                                <enumeratedValue>
                                    <name>11</name>
                                    <description>Detect both edges</description>
                                    <value>#11</value>
                                </enumeratedValue>
                            </enumeratedValues>
                        </field>
                        <field>
                            <name>ISEL</name>
                            <description>IRQ Input Enable</description>
                            <lsb>14</lsb>
                            <msb>14</msb>
                            <access>read-write</access>
                            <enumeratedValues>
                                <enumeratedValue>
                                    <name>0</name>
                                    <description>Not used as an IRQn input pin</description>
                                    <value>#0</value>
                                </enumeratedValue>
                                <enumeratedValue>
                                    <name>1</name>
                                    <description>Used as an IRQn input pin</description>
                                    <value>#1</value>
                                </enumeratedValue>
                            </enumeratedValues>
                        </field>
                        <field>
                            <name>ASEL</name>
                            <description>Analog Input Enable</description>
                            <lsb>15</lsb>
                            <msb>15</msb>
                            <access>read-write</access>
                            <enumeratedValues>
                                <enumeratedValue>
                                    <name>0</name>
                                    <description>Not used as an analog pin</description>
                                    <value>#0</value>
                                </enumeratedValue>
                                <enumeratedValue>
                                    <name>1</name>
                                    <description>Used as an analog pin</description>
                                    <value>#1</value>
                                </enumeratedValue>
                            </enumeratedValues>
                        </field>
                        <field>
                            <name>PMR</name>
                            <description>Port Mode Control</description>
                            <lsb>16</lsb>
                            <msb>16</msb>
                            <access>read-write</access>
                            <enumeratedValues>
                                <enumeratedValue>
                                    <name>0</name>
                                    <description>Used as a general I/O pin</description>
                                    <value>#0</value>
                                </enumeratedValue>
                                <enumeratedValue>
                                    <name>1</name>
                                    <description>Used as an I/O port for peripheral functions</description>
                                    <value>#1</value>
                                </enumeratedValue>
                            </enumeratedValues>
                        </field>
                        <field>
                            <name>PSEL</name>
                            <description>Peripheral Select</description>
                            <lsb>24</lsb>
                            <msb>28</msb>
                            <access>read-write</access>
                        </field>
                    </fields>
                </register>
                <register>
                    <dim>10</dim>
                    <dimIncrement>0x004</dimIncrement>
                    <dimIndex>0-9</dimIndex>
                    <name>P30%sPFS_HA</name>
                    <description>Port 30%s Pin Function Select Register</description>
                    <alternateRegister>P30%sPFS</alternateRegister>
                    <addressOffset>0x0C0</addressOffset>
                    <size>16</size>
                    <access>read-write</access>
                    <resetValue>0x0000</resetValue>
                    <resetMask>0xffff</resetMask>
                    <fields>
                        <field>
                            <name>PMR</name>
                            <description>Port Mode Control</description>
                            <lsb>0</lsb>
                            <msb>0</msb>
                            <access>read-write</access>
                            <enumeratedValues>
                                <enumeratedValue>
                                    <name>0</name>
                                    <description>Used as a general I/O pin</description>
                                    <value>#0</value>
                                </enumeratedValue>
                                <enumeratedValue>
                                    <name>1</name>
                                    <description>Used as an I/O port for peripheral functions</description>
                                    <value>#1</value>
                                </enumeratedValue>
                            </enumeratedValues>
                        </field>
                        <field>
                            <name>PSEL</name>
                            <description>Peripheral Select</description>
                            <lsb>8</lsb>
                            <msb>12</msb>
                            <access>read-write</access>
                        </field>
                    </fields>
                </register>
                <register>
                    <dim>10</dim>
                    <dimIncrement>0x004</dimIncrement>
                    <dimIndex>0-9</dimIndex>
                    <name>P30%sPFS_BY</name>
                    <description>Port 30%s Pin Function Select Register</description>
                    <alternateRegister>P30%sPFS</alternateRegister>
                    <addressOffset>0x0C0</addressOffset>
                    <size>8</size>
                    <access>read-write</access>
                    <resetValue>0x00</resetValue>
                    <resetMask>0xff</resetMask>
                    <fields>
                        <field>
                            <name>PSEL</name>
                            <description>Peripheral Select</description>
                            <lsb>0</lsb>
                            <msb>4</msb>
                            <access>read-write</access>
                        </field>
                    </fields>
                </register>
                <register>
                    <dim>6</dim>
                    <dimIncrement>0x004</dimIncrement>
                    <dimIndex>10-15</dimIndex>
                    <name>P3%sPFS</name>
                    <description>Port 3%s Pin Function Select Register</description>
                    <addressOffset>0x0E8</addressOffset>
                    <size>32</size>
                    <access>read-write</access>
                    <resetValue>0x00000000</resetValue>
                    <resetMask>0xffffffff</resetMask>
                    <fields>
                        <field>
                            <name>PODR</name>
                            <description>Port Output Data</description>
                            <lsb>0</lsb>
                            <msb>0</msb>
                            <access>read-write</access>
                            <enumeratedValues>
                                <enumeratedValue>
                                    <name>0</name>
                                    <description>Low output</description>
                                    <value>#0</value>
                                </enumeratedValue>
                                <enumeratedValue>
                                    <name>1</name>
                                    <description>High output</description>
                                    <value>#1</value>
                                </enumeratedValue>
                            </enumeratedValues>
                        </field>
                        <field>
                            <name>PIDR</name>
                            <description>Pmn State</description>
                            <lsb>1</lsb>
                            <msb>1</msb>
                            <access>read-only</access>
                            <enumeratedValues>
                                <enumeratedValue>
                                    <name>0</name>
                                    <description>Low level</description>
                                    <value>#0</value>
                                </enumeratedValue>
                                <enumeratedValue>
                                    <name>1</name>
                                    <description>High level</description>
                                    <value>#1</value>
                                </enumeratedValue>
                            </enumeratedValues>
                        </field>
                        <field>
                            <name>PDR</name>
                            <description>Port Direction</description>
                            <lsb>2</lsb>
                            <msb>2</msb>
                            <access>read-write</access>
                            <enumeratedValues>
                                <enumeratedValue>
                                    <name>0</name>
                                    <description>Input (functions as an input pin)</description>
                                    <value>#0</value>
                                </enumeratedValue>
                                <enumeratedValue>
                                    <name>1</name>
                                    <description>Output (functions as an output pin)</description>
                                    <value>#1</value>
                                </enumeratedValue>
                            </enumeratedValues>
                        </field>
                        <field>
                            <name>PCR</name>
                            <description>Pull-up Control</description>
                            <lsb>4</lsb>
                            <msb>4</msb>
                            <access>read-write</access>
                            <enumeratedValues>
                                <enumeratedValue>
                                    <name>0</name>
                                    <description>Disable input pull-up</description>
                                    <value>#0</value>
                                </enumeratedValue>
                                <enumeratedValue>
                                    <name>1</name>
                                    <description>Enable input pull-up</description>
                                    <value>#1</value>
                                </enumeratedValue>
                            </enumeratedValues>
                        </field>
                        <field>
                            <name>NCODR</name>
                            <description>N-Channel Open-Drain Control</description>
                            <lsb>6</lsb>
                            <msb>6</msb>
                            <access>read-write</access>
                            <enumeratedValues>
                                <enumeratedValue>
                                    <name>0</name>
                                    <description>CMOS output</description>
                                    <value>#0</value>
                                </enumeratedValue>
                                <enumeratedValue>
                                    <name>1</name>
                                    <description>NMOS open-drain output</description>
                                    <value>#1</value>
                                </enumeratedValue>
                            </enumeratedValues>
                        </field>
                        <field>
                            <name>DSCR</name>
                            <description>Port Drive Capability</description>
                            <lsb>10</lsb>
                            <msb>11</msb>
                            <access>read-write</access>
                            <enumeratedValues>
                                <enumeratedValue>
                                    <name>00</name>
                                    <description>Low drive</description>
                                    <value>#00</value>
                                </enumeratedValue>
                                <enumeratedValue>
                                    <name>01</name>
                                    <description>Middle drive</description>
                                    <value>#01</value>
                                </enumeratedValue>
                                <enumeratedValue>
                                    <name>10</name>
                                    <description>High-speed high-drive</description>
                                    <value>#10</value>
                                </enumeratedValue>
                                <enumeratedValue>
                                    <name>11</name>
                                    <description>High drive</description>
                                    <value>#11</value>
                                </enumeratedValue>
                            </enumeratedValues>
                        </field>
                        <field>
                            <name>EOFR</name>
                            <description>Event on Falling/Event on Rising</description>
                            <lsb>12</lsb>
                            <msb>13</msb>
                            <access>read-write</access>
                            <enumeratedValues>
                                <enumeratedValue>
                                    <name>00</name>
                                    <description>Don't care</description>
                                    <value>#00</value>
                                </enumeratedValue>
                                <enumeratedValue>
                                    <name>01</name>
                                    <description>Detect rising edge</description>
                                    <value>#01</value>
                                </enumeratedValue>
                                <enumeratedValue>
                                    <name>10</name>
                                    <description>Detect falling edge</description>
                                    <value>#10</value>
                                </enumeratedValue>
                                <enumeratedValue>
                                    <name>11</name>
                                    <description>Detect both edges</description>
                                    <value>#11</value>
                                </enumeratedValue>
                            </enumeratedValues>
                        </field>
                        <field>
                            <name>ISEL</name>
                            <description>IRQ Input Enable</description>
                            <lsb>14</lsb>
                            <msb>14</msb>
                            <access>read-write</access>
                            <enumeratedValues>
                                <enumeratedValue>
                                    <name>0</name>
                                    <description>Not used as an IRQn input pin</description>
                                    <value>#0</value>
                                </enumeratedValue>
                                <enumeratedValue>
                                    <name>1</name>
                                    <description>Used as an IRQn input pin</description>
                                    <value>#1</value>
                                </enumeratedValue>
                            </enumeratedValues>
                        </field>
                        <field>
                            <name>ASEL</name>
                            <description>Analog Input Enable</description>
                            <lsb>15</lsb>
                            <msb>15</msb>
                            <access>read-write</access>
                            <enumeratedValues>
                                <enumeratedValue>
                                    <name>0</name>
                                    <description>Not used as an analog pin</description>
                                    <value>#0</value>
                                </enumeratedValue>
                                <enumeratedValue>
                                    <name>1</name>
                                    <description>Used as an analog pin</description>
                                    <value>#1</value>
                                </enumeratedValue>
                            </enumeratedValues>
                        </field>
                        <field>
                            <name>PMR</name>
                            <description>Port Mode Control</description>
                            <lsb>16</lsb>
                            <msb>16</msb>
                            <access>read-write</access>
                            <enumeratedValues>
                                <enumeratedValue>
                                    <name>0</name>
                                    <description>Used as a general I/O pin</description>
                                    <value>#0</value>
                                </enumeratedValue>
                                <enumeratedValue>
                                    <name>1</name>
                                    <description>Used as an I/O port for peripheral functions</description>
                                    <value>#1</value>
                                </enumeratedValue>
                            </enumeratedValues>
                        </field>
                        <field>
                            <name>PSEL</name>
                            <description>Peripheral Select</description>
                            <lsb>24</lsb>
                            <msb>28</msb>
                            <access>read-write</access>
                        </field>
                    </fields>
                </register>
                <register>
                    <dim>6</dim>
                    <dimIncrement>0x004</dimIncrement>
                    <dimIndex>10-15</dimIndex>
                    <name>P3%sPFS_HA</name>
                    <description>Port 3%s Pin Function Select Register</description>
                    <alternateRegister>P3%sPFS</alternateRegister>
                    <addressOffset>0x0E8</addressOffset>
                    <size>16</size>
                    <access>read-write</access>
                    <resetValue>0x0000</resetValue>
                    <resetMask>0xffff</resetMask>
                    <fields>
                        <field>
                            <name>PMR</name>
                            <description>Port Mode Control</description>
                            <lsb>0</lsb>
                            <msb>0</msb>
                            <access>read-write</access>
                            <enumeratedValues>
                                <enumeratedValue>
                                    <name>0</name>
                                    <description>Used as a general I/O pin</description>
                                    <value>#0</value>
                                </enumeratedValue>
                                <enumeratedValue>
                                    <name>1</name>
                                    <description>Used as an I/O port for peripheral functions</description>
                                    <value>#1</value>
                                </enumeratedValue>
                            </enumeratedValues>
                        </field>
                        <field>
                            <name>PSEL</name>
                            <description>Peripheral Select</description>
                            <lsb>8</lsb>
                            <msb>12</msb>
                            <access>read-write</access>
                        </field>
                    </fields>
                </register>
                <register>
                    <dim>6</dim>
                    <dimIncrement>0x004</dimIncrement>
                    <dimIndex>10-15</dimIndex>
                    <name>P3%sPFS_BY</name>
                    <description>Port 3%s Pin Function Select Register</description>
                    <alternateRegister>P3%sPFS</alternateRegister>
                    <addressOffset>0x0E8</addressOffset>
                    <size>8</size>
                    <access>read-write</access>
                    <resetValue>0x00</resetValue>
                    <resetMask>0xff</resetMask>
                    <fields>
                        <field>
                            <name>PSEL</name>
                            <description>Peripheral Select</description>
                            <lsb>0</lsb>
                            <msb>4</msb>
                            <access>read-write</access>
                        </field>
                    </fields>
                </register>
                <register>
                    <dim>10</dim>
                    <dimIncrement>0x004</dimIncrement>
                    <dimIndex>0-9</dimIndex>
                    <name>P40%sPFS</name>
                    <description>Port 40%s Pin Function Select Register</description>
                    <addressOffset>0x100</addressOffset>
                    <size>32</size>
                    <access>read-write</access>
                    <resetValue>0x00000000</resetValue>
                    <resetMask>0xffffffff</resetMask>
                    <fields>
                        <field>
                            <name>PODR</name>
                            <description>Port Output Data</description>
                            <lsb>0</lsb>
                            <msb>0</msb>
                            <access>read-write</access>
                            <enumeratedValues>
                                <enumeratedValue>
                                    <name>0</name>
                                    <description>Low output</description>
                                    <value>#0</value>
                                </enumeratedValue>
                                <enumeratedValue>
                                    <name>1</name>
                                    <description>High output</description>
                                    <value>#1</value>
                                </enumeratedValue>
                            </enumeratedValues>
                        </field>
                        <field>
                            <name>PIDR</name>
                            <description>Pmn State</description>
                            <lsb>1</lsb>
                            <msb>1</msb>
                            <access>read-only</access>
                            <enumeratedValues>
                                <enumeratedValue>
                                    <name>0</name>
                                    <description>Low level</description>
                                    <value>#0</value>
                                </enumeratedValue>
                                <enumeratedValue>
                                    <name>1</name>
                                    <description>High level</description>
                                    <value>#1</value>
                                </enumeratedValue>
                            </enumeratedValues>
                        </field>
                        <field>
                            <name>PDR</name>
                            <description>Port Direction</description>
                            <lsb>2</lsb>
                            <msb>2</msb>
                            <access>read-write</access>
                            <enumeratedValues>
                                <enumeratedValue>
                                    <name>0</name>
                                    <description>Input (functions as an input pin)</description>
                                    <value>#0</value>
                                </enumeratedValue>
                                <enumeratedValue>
                                    <name>1</name>
                                    <description>Output (functions as an output pin)</description>
                                    <value>#1</value>
                                </enumeratedValue>
                            </enumeratedValues>
                        </field>
                        <field>
                            <name>PCR</name>
                            <description>Pull-up Control</description>
                            <lsb>4</lsb>
                            <msb>4</msb>
                            <access>read-write</access>
                            <enumeratedValues>
                                <enumeratedValue>
                                    <name>0</name>
                                    <description>Disable input pull-up</description>
                                    <value>#0</value>
                                </enumeratedValue>
                                <enumeratedValue>
                                    <name>1</name>
                                    <description>Enable input pull-up</description>
                                    <value>#1</value>
                                </enumeratedValue>
                            </enumeratedValues>
                        </field>
                        <field>
                            <name>NCODR</name>
                            <description>N-Channel Open-Drain Control</description>
                            <lsb>6</lsb>
                            <msb>6</msb>
                            <access>read-write</access>
                            <enumeratedValues>
                                <enumeratedValue>
                                    <name>0</name>
                                    <description>CMOS output</description>
                                    <value>#0</value>
                                </enumeratedValue>
                                <enumeratedValue>
                                    <name>1</name>
                                    <description>NMOS open-drain output</description>
                                    <value>#1</value>
                                </enumeratedValue>
                            </enumeratedValues>
                        </field>
                        <field>
                            <name>DSCR</name>
                            <description>Port Drive Capability</description>
                            <lsb>10</lsb>
                            <msb>11</msb>
                            <access>read-write</access>
                            <enumeratedValues>
                                <enumeratedValue>
                                    <name>00</name>
                                    <description>Low drive</description>
                                    <value>#00</value>
                                </enumeratedValue>
                                <enumeratedValue>
                                    <name>01</name>
                                    <description>Middle drive</description>
                                    <value>#01</value>
                                </enumeratedValue>
                                <enumeratedValue>
                                    <name>10</name>
                                    <description>High-speed high-drive</description>
                                    <value>#10</value>
                                </enumeratedValue>
                                <enumeratedValue>
                                    <name>11</name>
                                    <description>High drive</description>
                                    <value>#11</value>
                                </enumeratedValue>
                            </enumeratedValues>
                        </field>
                        <field>
                            <name>EOFR</name>
                            <description>Event on Falling/Event on Rising</description>
                            <lsb>12</lsb>
                            <msb>13</msb>
                            <access>read-write</access>
                            <enumeratedValues>
                                <enumeratedValue>
                                    <name>00</name>
                                    <description>Don't care</description>
                                    <value>#00</value>
                                </enumeratedValue>
                                <enumeratedValue>
                                    <name>01</name>
                                    <description>Detect rising edge</description>
                                    <value>#01</value>
                                </enumeratedValue>
                                <enumeratedValue>
                                    <name>10</name>
                                    <description>Detect falling edge</description>
                                    <value>#10</value>
                                </enumeratedValue>
                                <enumeratedValue>
                                    <name>11</name>
                                    <description>Detect both edges</description>
                                    <value>#11</value>
                                </enumeratedValue>
                            </enumeratedValues>
                        </field>
                        <field>
                            <name>ISEL</name>
                            <description>IRQ Input Enable</description>
                            <lsb>14</lsb>
                            <msb>14</msb>
                            <access>read-write</access>
                            <enumeratedValues>
                                <enumeratedValue>
                                    <name>0</name>
                                    <description>Not used as an IRQn input pin</description>
                                    <value>#0</value>
                                </enumeratedValue>
                                <enumeratedValue>
                                    <name>1</name>
                                    <description>Used as an IRQn input pin</description>
                                    <value>#1</value>
                                </enumeratedValue>
                            </enumeratedValues>
                        </field>
                        <field>
                            <name>ASEL</name>
                            <description>Analog Input Enable</description>
                            <lsb>15</lsb>
                            <msb>15</msb>
                            <access>read-write</access>
                            <enumeratedValues>
                                <enumeratedValue>
                                    <name>0</name>
                                    <description>Not used as an analog pin</description>
                                    <value>#0</value>
                                </enumeratedValue>
                                <enumeratedValue>
                                    <name>1</name>
                                    <description>Used as an analog pin</description>
                                    <value>#1</value>
                                </enumeratedValue>
                            </enumeratedValues>
                        </field>
                        <field>
                            <name>PMR</name>
                            <description>Port Mode Control</description>
                            <lsb>16</lsb>
                            <msb>16</msb>
                            <access>read-write</access>
                            <enumeratedValues>
                                <enumeratedValue>
                                    <name>0</name>
                                    <description>Used as a general I/O pin</description>
                                    <value>#0</value>
                                </enumeratedValue>
                                <enumeratedValue>
                                    <name>1</name>
                                    <description>Used as an I/O port for peripheral functions</description>
                                    <value>#1</value>
                                </enumeratedValue>
                            </enumeratedValues>
                        </field>
                        <field>
                            <name>PSEL</name>
                            <description>Peripheral Select</description>
                            <lsb>24</lsb>
                            <msb>28</msb>
                            <access>read-write</access>
                        </field>
                    </fields>
                </register>
                <register>
                    <dim>10</dim>
                    <dimIncrement>0x004</dimIncrement>
                    <dimIndex>0-9</dimIndex>
                    <name>P40%sPFS_HA</name>
                    <description>Port 40%s Pin Function Select Register</description>
                    <alternateRegister>P40%sPFS</alternateRegister>
                    <addressOffset>0x100</addressOffset>
                    <size>16</size>
                    <access>read-write</access>
                    <resetValue>0x0000</resetValue>
                    <resetMask>0xffff</resetMask>
                    <fields>
                        <field>
                            <name>PMR</name>
                            <description>Port Mode Control</description>
                            <lsb>0</lsb>
                            <msb>0</msb>
                            <access>read-write</access>
                            <enumeratedValues>
                                <enumeratedValue>
                                    <name>0</name>
                                    <description>Used as a general I/O pin</description>
                                    <value>#0</value>
                                </enumeratedValue>
                                <enumeratedValue>
                                    <name>1</name>
                                    <description>Used as an I/O port for peripheral functions</description>
                                    <value>#1</value>
                                </enumeratedValue>
                            </enumeratedValues>
                        </field>
                        <field>
                            <name>PSEL</name>
                            <description>Peripheral Select</description>
                            <lsb>8</lsb>
                            <msb>12</msb>
                            <access>read-write</access>
                        </field>
                    </fields>
                </register>
                <register>
                    <dim>10</dim>
                    <dimIncrement>0x004</dimIncrement>
                    <dimIndex>0-9</dimIndex>
                    <name>P40%sPFS_BY</name>
                    <description>Port 40%s Pin Function Select Register</description>
                    <alternateRegister>P40%sPFS</alternateRegister>
                    <addressOffset>0x100</addressOffset>
                    <size>8</size>
                    <access>read-write</access>
                    <resetValue>0x00</resetValue>
                    <resetMask>0xff</resetMask>
                    <fields>
                        <field>
                            <name>PSEL</name>
                            <description>Peripheral Select</description>
                            <lsb>0</lsb>
                            <msb>4</msb>
                            <access>read-write</access>
                        </field>
                    </fields>
                </register>
                <register>
                    <dim>6</dim>
                    <dimIncrement>0x004</dimIncrement>
                    <dimIndex>10-15</dimIndex>
                    <name>P4%sPFS</name>
                    <description>Port 4%s Pin Function Select Register</description>
                    <addressOffset>0x128</addressOffset>
                    <size>32</size>
                    <access>read-write</access>
                    <resetValue>0x00000000</resetValue>
                    <resetMask>0xffffffff</resetMask>
                    <fields>
                        <field>
                            <name>PODR</name>
                            <description>Port Output Data</description>
                            <lsb>0</lsb>
                            <msb>0</msb>
                            <access>read-write</access>
                            <enumeratedValues>
                                <enumeratedValue>
                                    <name>0</name>
                                    <description>Low output</description>
                                    <value>#0</value>
                                </enumeratedValue>
                                <enumeratedValue>
                                    <name>1</name>
                                    <description>High output</description>
                                    <value>#1</value>
                                </enumeratedValue>
                            </enumeratedValues>
                        </field>
                        <field>
                            <name>PIDR</name>
                            <description>Pmn State</description>
                            <lsb>1</lsb>
                            <msb>1</msb>
                            <access>read-only</access>
                            <enumeratedValues>
                                <enumeratedValue>
                                    <name>0</name>
                                    <description>Low level</description>
                                    <value>#0</value>
                                </enumeratedValue>
                                <enumeratedValue>
                                    <name>1</name>
                                    <description>High level</description>
                                    <value>#1</value>
                                </enumeratedValue>
                            </enumeratedValues>
                        </field>
                        <field>
                            <name>PDR</name>
                            <description>Port Direction</description>
                            <lsb>2</lsb>
                            <msb>2</msb>
                            <access>read-write</access>
                            <enumeratedValues>
                                <enumeratedValue>
                                    <name>0</name>
                                    <description>Input (functions as an input pin)</description>
                                    <value>#0</value>
                                </enumeratedValue>
                                <enumeratedValue>
                                    <name>1</name>
                                    <description>Output (functions as an output pin)</description>
                                    <value>#1</value>
                                </enumeratedValue>
                            </enumeratedValues>
                        </field>
                        <field>
                            <name>PCR</name>
                            <description>Pull-up Control</description>
                            <lsb>4</lsb>
                            <msb>4</msb>
                            <access>read-write</access>
                            <enumeratedValues>
                                <enumeratedValue>
                                    <name>0</name>
                                    <description>Disable input pull-up</description>
                                    <value>#0</value>
                                </enumeratedValue>
                                <enumeratedValue>
                                    <name>1</name>
                                    <description>Enable input pull-up</description>
                                    <value>#1</value>
                                </enumeratedValue>
                            </enumeratedValues>
                        </field>
                        <field>
                            <name>NCODR</name>
                            <description>N-Channel Open-Drain Control</description>
                            <lsb>6</lsb>
                            <msb>6</msb>
                            <access>read-write</access>
                            <enumeratedValues>
                                <enumeratedValue>
                                    <name>0</name>
                                    <description>CMOS output</description>
                                    <value>#0</value>
                                </enumeratedValue>
                                <enumeratedValue>
                                    <name>1</name>
                                    <description>NMOS open-drain output</description>
                                    <value>#1</value>
                                </enumeratedValue>
                            </enumeratedValues>
                        </field>
                        <field>
                            <name>DSCR</name>
                            <description>Port Drive Capability</description>
                            <lsb>10</lsb>
                            <msb>11</msb>
                            <access>read-write</access>
                            <enumeratedValues>
                                <enumeratedValue>
                                    <name>00</name>
                                    <description>Low drive</description>
                                    <value>#00</value>
                                </enumeratedValue>
                                <enumeratedValue>
                                    <name>01</name>
                                    <description>Middle drive</description>
                                    <value>#01</value>
                                </enumeratedValue>
                                <enumeratedValue>
                                    <name>10</name>
                                    <description>High-speed high-drive</description>
                                    <value>#10</value>
                                </enumeratedValue>
                                <enumeratedValue>
                                    <name>11</name>
                                    <description>High drive</description>
                                    <value>#11</value>
                                </enumeratedValue>
                            </enumeratedValues>
                        </field>
                        <field>
                            <name>EOFR</name>
                            <description>Event on Falling/Event on Rising</description>
                            <lsb>12</lsb>
                            <msb>13</msb>
                            <access>read-write</access>
                            <enumeratedValues>
                                <enumeratedValue>
                                    <name>00</name>
                                    <description>Don't care</description>
                                    <value>#00</value>
                                </enumeratedValue>
                                <enumeratedValue>
                                    <name>01</name>
                                    <description>Detect rising edge</description>
                                    <value>#01</value>
                                </enumeratedValue>
                                <enumeratedValue>
                                    <name>10</name>
                                    <description>Detect falling edge</description>
                                    <value>#10</value>
                                </enumeratedValue>
                                <enumeratedValue>
                                    <name>11</name>
                                    <description>Detect both edges</description>
                                    <value>#11</value>
                                </enumeratedValue>
                            </enumeratedValues>
                        </field>
                        <field>
                            <name>ISEL</name>
                            <description>IRQ Input Enable</description>
                            <lsb>14</lsb>
                            <msb>14</msb>
                            <access>read-write</access>
                            <enumeratedValues>
                                <enumeratedValue>
                                    <name>0</name>
                                    <description>Not used as an IRQn input pin</description>
                                    <value>#0</value>
                                </enumeratedValue>
                                <enumeratedValue>
                                    <name>1</name>
                                    <description>Used as an IRQn input pin</description>
                                    <value>#1</value>
                                </enumeratedValue>
                            </enumeratedValues>
                        </field>
                        <field>
                            <name>ASEL</name>
                            <description>Analog Input Enable</description>
                            <lsb>15</lsb>
                            <msb>15</msb>
                            <access>read-write</access>
                            <enumeratedValues>
                                <enumeratedValue>
                                    <name>0</name>
                                    <description>Not used as an analog pin</description>
                                    <value>#0</value>
                                </enumeratedValue>
                                <enumeratedValue>
                                    <name>1</name>
                                    <description>Used as an analog pin</description>
                                    <value>#1</value>
                                </enumeratedValue>
                            </enumeratedValues>
                        </field>
                        <field>
                            <name>PMR</name>
                            <description>Port Mode Control</description>
                            <lsb>16</lsb>
                            <msb>16</msb>
                            <access>read-write</access>
                            <enumeratedValues>
                                <enumeratedValue>
                                    <name>0</name>
                                    <description>Used as a general I/O pin</description>
                                    <value>#0</value>
                                </enumeratedValue>
                                <enumeratedValue>
                                    <name>1</name>
                                    <description>Used as an I/O port for peripheral functions</description>
                                    <value>#1</value>
                                </enumeratedValue>
                            </enumeratedValues>
                        </field>
                        <field>
                            <name>PSEL</name>
                            <description>Peripheral Select</description>
                            <lsb>24</lsb>
                            <msb>28</msb>
                            <access>read-write</access>
                        </field>
                    </fields>
                </register>
                <register>
                    <dim>6</dim>
                    <dimIncrement>0x004</dimIncrement>
                    <dimIndex>10-15</dimIndex>
                    <name>P4%sPFS_HA</name>
                    <description>Port 4%s Pin Function Select Register</description>
                    <alternateRegister>P4%sPFS</alternateRegister>
                    <addressOffset>0x128</addressOffset>
                    <size>16</size>
                    <access>read-write</access>
                    <resetValue>0x0000</resetValue>
                    <resetMask>0xffff</resetMask>
                    <fields>
                        <field>
                            <name>PMR</name>
                            <description>Port Mode Control</description>
                            <lsb>0</lsb>
                            <msb>0</msb>
                            <access>read-write</access>
                            <enumeratedValues>
                                <enumeratedValue>
                                    <name>0</name>
                                    <description>Used as a general I/O pin</description>
                                    <value>#0</value>
                                </enumeratedValue>
                                <enumeratedValue>
                                    <name>1</name>
                                    <description>Used as an I/O port for peripheral functions</description>
                                    <value>#1</value>
                                </enumeratedValue>
                            </enumeratedValues>
                        </field>
                        <field>
                            <name>PSEL</name>
                            <description>Peripheral Select</description>
                            <lsb>8</lsb>
                            <msb>12</msb>
                            <access>read-write</access>
                        </field>
                    </fields>
                </register>
                <register>
                    <dim>6</dim>
                    <dimIncrement>0x004</dimIncrement>
                    <dimIndex>10-15</dimIndex>
                    <name>P4%sPFS_BY</name>
                    <description>Port 4%s Pin Function Select Register</description>
                    <alternateRegister>P4%sPFS</alternateRegister>
                    <addressOffset>0x128</addressOffset>
                    <size>8</size>
                    <access>read-write</access>
                    <resetValue>0x00</resetValue>
                    <resetMask>0xff</resetMask>
                    <fields>
                        <field>
                            <name>PSEL</name>
                            <description>Peripheral Select</description>
                            <lsb>0</lsb>
                            <msb>4</msb>
                            <access>read-write</access>
                        </field>
                    </fields>
                </register>
                <register>
                    <dim>10</dim>
                    <dimIncrement>0x004</dimIncrement>
                    <dimIndex>0-9</dimIndex>
                    <name>P50%sPFS</name>
                    <description>Port 50%s Pin Function Select Register</description>
                    <addressOffset>0x140</addressOffset>
                    <size>32</size>
                    <access>read-write</access>
                    <resetValue>0x00000000</resetValue>
                    <resetMask>0xffffffff</resetMask>
                    <fields>
                        <field>
                            <name>PODR</name>
                            <description>Port Output Data</description>
                            <lsb>0</lsb>
                            <msb>0</msb>
                            <access>read-write</access>
                            <enumeratedValues>
                                <enumeratedValue>
                                    <name>0</name>
                                    <description>Low output</description>
                                    <value>#0</value>
                                </enumeratedValue>
                                <enumeratedValue>
                                    <name>1</name>
                                    <description>High output</description>
                                    <value>#1</value>
                                </enumeratedValue>
                            </enumeratedValues>
                        </field>
                        <field>
                            <name>PIDR</name>
                            <description>Pmn State</description>
                            <lsb>1</lsb>
                            <msb>1</msb>
                            <access>read-only</access>
                            <enumeratedValues>
                                <enumeratedValue>
                                    <name>0</name>
                                    <description>Low level</description>
                                    <value>#0</value>
                                </enumeratedValue>
                                <enumeratedValue>
                                    <name>1</name>
                                    <description>High level</description>
                                    <value>#1</value>
                                </enumeratedValue>
                            </enumeratedValues>
                        </field>
                        <field>
                            <name>PDR</name>
                            <description>Port Direction</description>
                            <lsb>2</lsb>
                            <msb>2</msb>
                            <access>read-write</access>
                            <enumeratedValues>
                                <enumeratedValue>
                                    <name>0</name>
                                    <description>Input (functions as an input pin)</description>
                                    <value>#0</value>
                                </enumeratedValue>
                                <enumeratedValue>
                                    <name>1</name>
                                    <description>Output (functions as an output pin)</description>
                                    <value>#1</value>
                                </enumeratedValue>
                            </enumeratedValues>
                        </field>
                        <field>
                            <name>PCR</name>
                            <description>Pull-up Control</description>
                            <lsb>4</lsb>
                            <msb>4</msb>
                            <access>read-write</access>
                            <enumeratedValues>
                                <enumeratedValue>
                                    <name>0</name>
                                    <description>Disable input pull-up</description>
                                    <value>#0</value>
                                </enumeratedValue>
                                <enumeratedValue>
                                    <name>1</name>
                                    <description>Enable input pull-up</description>
                                    <value>#1</value>
                                </enumeratedValue>
                            </enumeratedValues>
                        </field>
                        <field>
                            <name>NCODR</name>
                            <description>N-Channel Open-Drain Control</description>
                            <lsb>6</lsb>
                            <msb>6</msb>
                            <access>read-write</access>
                            <enumeratedValues>
                                <enumeratedValue>
                                    <name>0</name>
                                    <description>CMOS output</description>
                                    <value>#0</value>
                                </enumeratedValue>
                                <enumeratedValue>
                                    <name>1</name>
                                    <description>NMOS open-drain output</description>
                                    <value>#1</value>
                                </enumeratedValue>
                            </enumeratedValues>
                        </field>
                        <field>
                            <name>DSCR</name>
                            <description>Port Drive Capability</description>
                            <lsb>10</lsb>
                            <msb>11</msb>
                            <access>read-write</access>
                            <enumeratedValues>
                                <enumeratedValue>
                                    <name>00</name>
                                    <description>Low drive</description>
                                    <value>#00</value>
                                </enumeratedValue>
                                <enumeratedValue>
                                    <name>01</name>
                                    <description>Middle drive</description>
                                    <value>#01</value>
                                </enumeratedValue>
                                <enumeratedValue>
                                    <name>10</name>
                                    <description>High-speed high-drive</description>
                                    <value>#10</value>
                                </enumeratedValue>
                                <enumeratedValue>
                                    <name>11</name>
                                    <description>High drive</description>
                                    <value>#11</value>
                                </enumeratedValue>
                            </enumeratedValues>
                        </field>
                        <field>
                            <name>EOFR</name>
                            <description>Event on Falling/Event on Rising</description>
                            <lsb>12</lsb>
                            <msb>13</msb>
                            <access>read-write</access>
                            <enumeratedValues>
                                <enumeratedValue>
                                    <name>00</name>
                                    <description>Don't care</description>
                                    <value>#00</value>
                                </enumeratedValue>
                                <enumeratedValue>
                                    <name>01</name>
                                    <description>Detect rising edge</description>
                                    <value>#01</value>
                                </enumeratedValue>
                                <enumeratedValue>
                                    <name>10</name>
                                    <description>Detect falling edge</description>
                                    <value>#10</value>
                                </enumeratedValue>
                                <enumeratedValue>
                                    <name>11</name>
                                    <description>Detect both edges</description>
                                    <value>#11</value>
                                </enumeratedValue>
                            </enumeratedValues>
                        </field>
                        <field>
                            <name>ISEL</name>
                            <description>IRQ Input Enable</description>
                            <lsb>14</lsb>
                            <msb>14</msb>
                            <access>read-write</access>
                            <enumeratedValues>
                                <enumeratedValue>
                                    <name>0</name>
                                    <description>Not used as an IRQn input pin</description>
                                    <value>#0</value>
                                </enumeratedValue>
                                <enumeratedValue>
                                    <name>1</name>
                                    <description>Used as an IRQn input pin</description>
                                    <value>#1</value>
                                </enumeratedValue>
                            </enumeratedValues>
                        </field>
                        <field>
                            <name>ASEL</name>
                            <description>Analog Input Enable</description>
                            <lsb>15</lsb>
                            <msb>15</msb>
                            <access>read-write</access>
                            <enumeratedValues>
                                <enumeratedValue>
                                    <name>0</name>
                                    <description>Not used as an analog pin</description>
                                    <value>#0</value>
                                </enumeratedValue>
                                <enumeratedValue>
                                    <name>1</name>
                                    <description>Used as an analog pin</description>
                                    <value>#1</value>
                                </enumeratedValue>
                            </enumeratedValues>
                        </field>
                        <field>
                            <name>PMR</name>
                            <description>Port Mode Control</description>
                            <lsb>16</lsb>
                            <msb>16</msb>
                            <access>read-write</access>
                            <enumeratedValues>
                                <enumeratedValue>
                                    <name>0</name>
                                    <description>Used as a general I/O pin</description>
                                    <value>#0</value>
                                </enumeratedValue>
                                <enumeratedValue>
                                    <name>1</name>
                                    <description>Used as an I/O port for peripheral functions</description>
                                    <value>#1</value>
                                </enumeratedValue>
                            </enumeratedValues>
                        </field>
                        <field>
                            <name>PSEL</name>
                            <description>Peripheral Select</description>
                            <lsb>24</lsb>
                            <msb>28</msb>
                            <access>read-write</access>
                        </field>
                    </fields>
                </register>
                <register>
                    <dim>10</dim>
                    <dimIncrement>0x004</dimIncrement>
                    <dimIndex>0-9</dimIndex>
                    <name>P50%sPFS_HA</name>
                    <description>Port 50%s Pin Function Select Register</description>
                    <alternateRegister>P50%sPFS</alternateRegister>
                    <addressOffset>0x140</addressOffset>
                    <size>16</size>
                    <access>read-write</access>
                    <resetValue>0x0000</resetValue>
                    <resetMask>0xffff</resetMask>
                    <fields>
                        <field>
                            <name>PMR</name>
                            <description>Port Mode Control</description>
                            <lsb>0</lsb>
                            <msb>0</msb>
                            <access>read-write</access>
                            <enumeratedValues>
                                <enumeratedValue>
                                    <name>0</name>
                                    <description>Used as a general I/O pin</description>
                                    <value>#0</value>
                                </enumeratedValue>
                                <enumeratedValue>
                                    <name>1</name>
                                    <description>Used as an I/O port for peripheral functions</description>
                                    <value>#1</value>
                                </enumeratedValue>
                            </enumeratedValues>
                        </field>
                        <field>
                            <name>PSEL</name>
                            <description>Peripheral Select</description>
                            <lsb>8</lsb>
                            <msb>12</msb>
                            <access>read-write</access>
                        </field>
                    </fields>
                </register>
                <register>
                    <dim>10</dim>
                    <dimIncrement>0x004</dimIncrement>
                    <dimIndex>0-9</dimIndex>
                    <name>P50%sPFS_BY</name>
                    <description>Port 50%s Pin Function Select Register</description>
                    <alternateRegister>P50%sPFS</alternateRegister>
                    <addressOffset>0x140</addressOffset>
                    <size>8</size>
                    <access>read-write</access>
                    <resetValue>0x00</resetValue>
                    <resetMask>0xff</resetMask>
                    <fields>
                        <field>
                            <name>PSEL</name>
                            <description>Peripheral Select</description>
                            <lsb>0</lsb>
                            <msb>4</msb>
                            <access>read-write</access>
                        </field>
                    </fields>
                </register>
                <register>
                    <dim>6</dim>
                    <dimIncrement>0x004</dimIncrement>
                    <dimIndex>10-15</dimIndex>
                    <name>P5%sPFS</name>
                    <description>Port 5%s Pin Function Select Register</description>
                    <addressOffset>0x168</addressOffset>
                    <size>32</size>
                    <access>read-write</access>
                    <resetValue>0x00000000</resetValue>
                    <resetMask>0xffffffff</resetMask>
                    <fields>
                        <field>
                            <name>PODR</name>
                            <description>Port Output Data</description>
                            <lsb>0</lsb>
                            <msb>0</msb>
                            <access>read-write</access>
                            <enumeratedValues>
                                <enumeratedValue>
                                    <name>0</name>
                                    <description>Low output</description>
                                    <value>#0</value>
                                </enumeratedValue>
                                <enumeratedValue>
                                    <name>1</name>
                                    <description>High output</description>
                                    <value>#1</value>
                                </enumeratedValue>
                            </enumeratedValues>
                        </field>
                        <field>
                            <name>PIDR</name>
                            <description>Pmn State</description>
                            <lsb>1</lsb>
                            <msb>1</msb>
                            <access>read-only</access>
                            <enumeratedValues>
                                <enumeratedValue>
                                    <name>0</name>
                                    <description>Low level</description>
                                    <value>#0</value>
                                </enumeratedValue>
                                <enumeratedValue>
                                    <name>1</name>
                                    <description>High level</description>
                                    <value>#1</value>
                                </enumeratedValue>
                            </enumeratedValues>
                        </field>
                        <field>
                            <name>PDR</name>
                            <description>Port Direction</description>
                            <lsb>2</lsb>
                            <msb>2</msb>
                            <access>read-write</access>
                            <enumeratedValues>
                                <enumeratedValue>
                                    <name>0</name>
                                    <description>Input (functions as an input pin)</description>
                                    <value>#0</value>
                                </enumeratedValue>
                                <enumeratedValue>
                                    <name>1</name>
                                    <description>Output (functions as an output pin)</description>
                                    <value>#1</value>
                                </enumeratedValue>
                            </enumeratedValues>
                        </field>
                        <field>
                            <name>PCR</name>
                            <description>Pull-up Control</description>
                            <lsb>4</lsb>
                            <msb>4</msb>
                            <access>read-write</access>
                            <enumeratedValues>
                                <enumeratedValue>
                                    <name>0</name>
                                    <description>Disable input pull-up</description>
                                    <value>#0</value>
                                </enumeratedValue>
                                <enumeratedValue>
                                    <name>1</name>
                                    <description>Enable input pull-up</description>
                                    <value>#1</value>
                                </enumeratedValue>
                            </enumeratedValues>
                        </field>
                        <field>
                            <name>NCODR</name>
                            <description>N-Channel Open-Drain Control</description>
                            <lsb>6</lsb>
                            <msb>6</msb>
                            <access>read-write</access>
                            <enumeratedValues>
                                <enumeratedValue>
                                    <name>0</name>
                                    <description>CMOS output</description>
                                    <value>#0</value>
                                </enumeratedValue>
                                <enumeratedValue>
                                    <name>1</name>
                                    <description>NMOS open-drain output</description>
                                    <value>#1</value>
                                </enumeratedValue>
                            </enumeratedValues>
                        </field>
                        <field>
                            <name>DSCR</name>
                            <description>Port Drive Capability</description>
                            <lsb>10</lsb>
                            <msb>11</msb>
                            <access>read-write</access>
                            <enumeratedValues>
                                <enumeratedValue>
                                    <name>00</name>
                                    <description>Low drive</description>
                                    <value>#00</value>
                                </enumeratedValue>
                                <enumeratedValue>
                                    <name>01</name>
                                    <description>Middle drive</description>
                                    <value>#01</value>
                                </enumeratedValue>
                                <enumeratedValue>
                                    <name>10</name>
                                    <description>High-speed high-drive</description>
                                    <value>#10</value>
                                </enumeratedValue>
                                <enumeratedValue>
                                    <name>11</name>
                                    <description>High drive</description>
                                    <value>#11</value>
                                </enumeratedValue>
                            </enumeratedValues>
                        </field>
                        <field>
                            <name>EOFR</name>
                            <description>Event on Falling/Event on Rising</description>
                            <lsb>12</lsb>
                            <msb>13</msb>
                            <access>read-write</access>
                            <enumeratedValues>
                                <enumeratedValue>
                                    <name>00</name>
                                    <description>Don't care</description>
                                    <value>#00</value>
                                </enumeratedValue>
                                <enumeratedValue>
                                    <name>01</name>
                                    <description>Detect rising edge</description>
                                    <value>#01</value>
                                </enumeratedValue>
                                <enumeratedValue>
                                    <name>10</name>
                                    <description>Detect falling edge</description>
                                    <value>#10</value>
                                </enumeratedValue>
                                <enumeratedValue>
                                    <name>11</name>
                                    <description>Detect both edges</description>
                                    <value>#11</value>
                                </enumeratedValue>
                            </enumeratedValues>
                        </field>
                        <field>
                            <name>ISEL</name>
                            <description>IRQ Input Enable</description>
                            <lsb>14</lsb>
                            <msb>14</msb>
                            <access>read-write</access>
                            <enumeratedValues>
                                <enumeratedValue>
                                    <name>0</name>
                                    <description>Not used as an IRQn input pin</description>
                                    <value>#0</value>
                                </enumeratedValue>
                                <enumeratedValue>
                                    <name>1</name>
                                    <description>Used as an IRQn input pin</description>
                                    <value>#1</value>
                                </enumeratedValue>
                            </enumeratedValues>
                        </field>
                        <field>
                            <name>ASEL</name>
                            <description>Analog Input Enable</description>
                            <lsb>15</lsb>
                            <msb>15</msb>
                            <access>read-write</access>
                            <enumeratedValues>
                                <enumeratedValue>
                                    <name>0</name>
                                    <description>Not used as an analog pin</description>
                                    <value>#0</value>
                                </enumeratedValue>
                                <enumeratedValue>
                                    <name>1</name>
                                    <description>Used as an analog pin</description>
                                    <value>#1</value>
                                </enumeratedValue>
                            </enumeratedValues>
                        </field>
                        <field>
                            <name>PMR</name>
                            <description>Port Mode Control</description>
                            <lsb>16</lsb>
                            <msb>16</msb>
                            <access>read-write</access>
                            <enumeratedValues>
                                <enumeratedValue>
                                    <name>0</name>
                                    <description>Used as a general I/O pin</description>
                                    <value>#0</value>
                                </enumeratedValue>
                                <enumeratedValue>
                                    <name>1</name>
                                    <description>Used as an I/O port for peripheral functions</description>
                                    <value>#1</value>
                                </enumeratedValue>
                            </enumeratedValues>
                        </field>
                        <field>
                            <name>PSEL</name>
                            <description>Peripheral Select</description>
                            <lsb>24</lsb>
                            <msb>28</msb>
                            <access>read-write</access>
                        </field>
                    </fields>
                </register>
                <register>
                    <dim>6</dim>
                    <dimIncrement>0x004</dimIncrement>
                    <dimIndex>10-15</dimIndex>
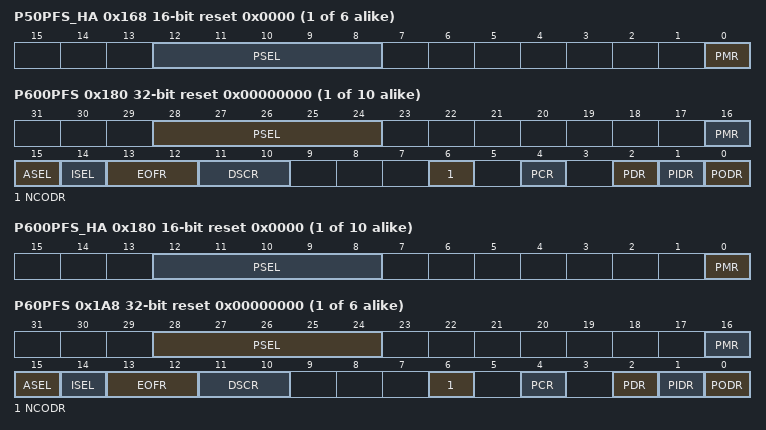
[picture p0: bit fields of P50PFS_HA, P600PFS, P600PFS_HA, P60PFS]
                    <name>P5%sPFS_HA</name>
                    <description>Port 5%s Pin Function Select Register</description>
                    <alternateRegister>P5%sPFS</alternateRegister>
                    <addressOffset>0x168</addressOffset>
                    <size>16</size>
                    <access>read-write</access>
                    <resetValue>0x0000</resetValue>
                    <resetMask>0xffff</resetMask>
                    <fields>
                        <field>
                            <name>PMR</name>
                            <description>Port Mode Control</description>
                            <lsb>0</lsb>
                            <msb>0</msb>
                            <access>read-write</access>
                            <enumeratedValues>
                                <enumeratedValue>
                                    <name>0</name>
                                    <description>Used as a general I/O pin</description>
                                    <value>#0</value>
                                </enumeratedValue>
                                <enumeratedValue>
                                    <name>1</name>
                                    <description>Used as an I/O port for peripheral functions</description>
                                    <value>#1</value>
                                </enumeratedValue>
                            </enumeratedValues>
                        </field>
                        <field>
                            <name>PSEL</name>
                            <description>Peripheral Select</description>
                            <lsb>8</lsb>
                            <msb>12</msb>
                            <access>read-write</access>
                        </field>
                    </fields>
                </register>
                <register>
                    <dim>6</dim>
                    <dimIncrement>0x004</dimIncrement>
                    <dimIndex>10-15</dimIndex>
                    <name>P5%sPFS_BY</name>
                    <description>Port 5%s Pin Function Select Register</description>
                    <alternateRegister>P5%sPFS</alternateRegister>
                    <addressOffset>0x168</addressOffset>
                    <size>8</size>
                    <access>read-write</access>
                    <resetValue>0x00</resetValue>
                    <resetMask>0xff</resetMask>
                    <fields>
                        <field>
                            <name>PSEL</name>
                            <description>Peripheral Select</description>
                            <lsb>0</lsb>
                            <msb>4</msb>
                            <access>read-write</access>
                        </field>
                    </fields>
                </register>
                <register>
                    <dim>10</dim>
                    <dimIncrement>0x004</dimIncrement>
                    <dimIndex>0-9</dimIndex>
                    <name>P60%sPFS</name>
                    <description>Port 60%s Pin Function Select Register</description>
                    <addressOffset>0x180</addressOffset>
                    <size>32</size>
                    <access>read-write</access>
                    <resetValue>0x00000000</resetValue>
                    <resetMask>0xffffffff</resetMask>
                    <fields>
                        <field>
                            <name>PODR</name>
                            <description>Port Output Data</description>
                            <lsb>0</lsb>
                            <msb>0</msb>
                            <access>read-write</access>
                            <enumeratedValues>
                                <enumeratedValue>
                                    <name>0</name>
                                    <description>Low output</description>
                                    <value>#0</value>
                                </enumeratedValue>
                                <enumeratedValue>
                                    <name>1</name>
                                    <description>High output</description>
                                    <value>#1</value>
                                </enumeratedValue>
                            </enumeratedValues>
                        </field>
                        <field>
                            <name>PIDR</name>
                            <description>Pmn State</description>
                            <lsb>1</lsb>
                            <msb>1</msb>
                            <access>read-only</access>
                            <enumeratedValues>
                                <enumeratedValue>
                                    <name>0</name>
                                    <description>Low level</description>
                                    <value>#0</value>
                                </enumeratedValue>
                                <enumeratedValue>
                                    <name>1</name>
                                    <description>High level</description>
                                    <value>#1</value>
                                </enumeratedValue>
                            </enumeratedValues>
                        </field>
                        <field>
                            <name>PDR</name>
                            <description>Port Direction</description>
                            <lsb>2</lsb>
                            <msb>2</msb>
                            <access>read-write</access>
                            <enumeratedValues>
                                <enumeratedValue>
                                    <name>0</name>
                                    <description>Input (functions as an input pin)</description>
                                    <value>#0</value>
                                </enumeratedValue>
                                <enumeratedValue>
                                    <name>1</name>
                                    <description>Output (functions as an output pin)</description>
                                    <value>#1</value>
                                </enumeratedValue>
                            </enumeratedValues>
                        </field>
                        <field>
                            <name>PCR</name>
                            <description>Pull-up Control</description>
                            <lsb>4</lsb>
                            <msb>4</msb>
                            <access>read-write</access>
                            <enumeratedValues>
                                <enumeratedValue>
                                    <name>0</name>
                                    <description>Disable input pull-up</description>
                                    <value>#0</value>
                                </enumeratedValue>
                                <enumeratedValue>
                                    <name>1</name>
                                    <description>Enable input pull-up</description>
                                    <value>#1</value>
                                </enumeratedValue>
                            </enumeratedValues>
                        </field>
                        <field>
                            <name>NCODR</name>
                            <description>N-Channel Open-Drain Control</description>
                            <lsb>6</lsb>
                            <msb>6</msb>
                            <access>read-write</access>
                            <enumeratedValues>
                                <enumeratedValue>
                                    <name>0</name>
                                    <description>CMOS output</description>
                                    <value>#0</value>
                                </enumeratedValue>
                                <enumeratedValue>
                                    <name>1</name>
                                    <description>NMOS open-drain output</description>
                                    <value>#1</value>
                                </enumeratedValue>
                            </enumeratedValues>
                        </field>
                        <field>
                            <name>DSCR</name>
                            <description>Port Drive Capability</description>
                            <lsb>10</lsb>
                            <msb>11</msb>
                            <access>read-write</access>
                            <enumeratedValues>
                                <enumeratedValue>
                                    <name>00</name>
                                    <description>Low drive</description>
                                    <value>#00</value>
                                </enumeratedValue>
                                <enumeratedValue>
                                    <name>01</name>
                                    <description>Middle drive</description>
                                    <value>#01</value>
                                </enumeratedValue>
                                <enumeratedValue>
                                    <name>10</name>
                                    <description>High-speed high-drive</description>
                                    <value>#10</value>
                                </enumeratedValue>
                                <enumeratedValue>
                                    <name>11</name>
                                    <description>High drive</description>
                                    <value>#11</value>
                                </enumeratedValue>
                            </enumeratedValues>
                        </field>
                        <field>
                            <name>EOFR</name>
                            <description>Event on Falling/Event on Rising</description>
                            <lsb>12</lsb>
                            <msb>13</msb>
                            <access>read-write</access>
                            <enumeratedValues>
                                <enumeratedValue>
                                    <name>00</name>
                                    <description>Don't care</description>
                                    <value>#00</value>
                                </enumeratedValue>
                                <enumeratedValue>
                                    <name>01</name>
                                    <description>Detect rising edge</description>
                                    <value>#01</value>
                                </enumeratedValue>
                                <enumeratedValue>
                                    <name>10</name>
                                    <description>Detect falling edge</description>
                                    <value>#10</value>
                                </enumeratedValue>
                                <enumeratedValue>
                                    <name>11</name>
                                    <description>Detect both edges</description>
                                    <value>#11</value>
                                </enumeratedValue>
                            </enumeratedValues>
                        </field>
                        <field>
                            <name>ISEL</name>
                            <description>IRQ Input Enable</description>
                            <lsb>14</lsb>
                            <msb>14</msb>
                            <access>read-write</access>
                            <enumeratedValues>
                                <enumeratedValue>
                                    <name>0</name>
                                    <description>Not used as an IRQn input pin</description>
                                    <value>#0</value>
                                </enumeratedValue>
                                <enumeratedValue>
                                    <name>1</name>
                                    <description>Used as an IRQn input pin</description>
                                    <value>#1</value>
                                </enumeratedValue>
                            </enumeratedValues>
                        </field>
                        <field>
                            <name>ASEL</name>
                            <description>Analog Input Enable</description>
                            <lsb>15</lsb>
                            <msb>15</msb>
                            <access>read-write</access>
                            <enumeratedValues>
                                <enumeratedValue>
                                    <name>0</name>
                                    <description>Not used as an analog pin</description>
                                    <value>#0</value>
                                </enumeratedValue>
                                <enumeratedValue>
                                    <name>1</name>
                                    <description>Used as an analog pin</description>
                                    <value>#1</value>
                                </enumeratedValue>
                            </enumeratedValues>
                        </field>
                        <field>
                            <name>PMR</name>
                            <description>Port Mode Control</description>
                            <lsb>16</lsb>
                            <msb>16</msb>
                            <access>read-write</access>
                            <enumeratedValues>
                                <enumeratedValue>
                                    <name>0</name>
                                    <description>Used as a general I/O pin</description>
                                    <value>#0</value>
                                </enumeratedValue>
                                <enumeratedValue>
                                    <name>1</name>
                                    <description>Used as an I/O port for peripheral functions</description>
                                    <value>#1</value>
                                </enumeratedValue>
                            </enumeratedValues>
                        </field>
                        <field>
                            <name>PSEL</name>
                            <description>Peripheral Select</description>
                            <lsb>24</lsb>
                            <msb>28</msb>
                            <access>read-write</access>
                        </field>
                    </fields>
                </register>
                <register>
                    <dim>10</dim>
                    <dimIncrement>0x004</dimIncrement>
                    <dimIndex>0-9</dimIndex>
                    <name>P60%sPFS_HA</name>
                    <description>Port 60%s Pin Function Select Register</description>
                    <alternateRegister>P60%sPFS</alternateRegister>
                    <addressOffset>0x180</addressOffset>
                    <size>16</size>
                    <access>read-write</access>
                    <resetValue>0x0000</resetValue>
                    <resetMask>0xffff</resetMask>
                    <fields>
                        <field>
                            <name>PMR</name>
                            <description>Port Mode Control</description>
                            <lsb>0</lsb>
                            <msb>0</msb>
                            <access>read-write</access>
                            <enumeratedValues>
                                <enumeratedValue>
                                    <name>0</name>
                                    <description>Used as a general I/O pin</description>
                                    <value>#0</value>
                                </enumeratedValue>
                                <enumeratedValue>
                                    <name>1</name>
                                    <description>Used as an I/O port for peripheral functions</description>
                                    <value>#1</value>
                                </enumeratedValue>
                            </enumeratedValues>
                        </field>
                        <field>
                            <name>PSEL</name>
                            <description>Peripheral Select</description>
                            <lsb>8</lsb>
                            <msb>12</msb>
                            <access>read-write</access>
                        </field>
                    </fields>
                </register>
                <register>
                    <dim>10</dim>
                    <dimIncrement>0x004</dimIncrement>
                    <dimIndex>0-9</dimIndex>
                    <name>P60%sPFS_BY</name>
                    <description>Port 60%s Pin Function Select Register</description>
                    <alternateRegister>P60%sPFS</alternateRegister>
                    <addressOffset>0x180</addressOffset>
                    <size>8</size>
                    <access>read-write</access>
                    <resetValue>0x00</resetValue>
                    <resetMask>0xff</resetMask>
                    <fields>
                        <field>
                            <name>PSEL</name>
                            <description>Peripheral Select</description>
                            <lsb>0</lsb>
                            <msb>4</msb>
                            <access>read-write</access>
                        </field>
                    </fields>
                </register>
                <register>
                    <dim>6</dim>
                    <dimIncrement>0x004</dimIncrement>
                    <dimIndex>10-15</dimIndex>
                    <name>P6%sPFS</name>
                    <description>Port 6%s Pin Function Select Register</description>
                    <addressOffset>0x1A8</addressOffset>
                    <size>32</size>
                    <access>read-write</access>
                    <resetValue>0x00000000</resetValue>
                    <resetMask>0xffffffff</resetMask>
                    <fields>
                        <field>
                            <name>PODR</name>
                            <description>Port Output Data</description>
                            <lsb>0</lsb>
                            <msb>0</msb>
                            <access>read-write</access>
                            <enumeratedValues>
                                <enumeratedValue>
                                    <name>0</name>
                                    <description>Low output</description>
                                    <value>#0</value>
                                </enumeratedValue>
                                <enumeratedValue>
                                    <name>1</name>
                                    <description>High output</description>
                                    <value>#1</value>
                                </enumeratedValue>
                            </enumeratedValues>
                        </field>
                        <field>
                            <name>PIDR</name>
                            <description>Pmn State</description>
                            <lsb>1</lsb>
                            <msb>1</msb>
                            <access>read-only</access>
                            <enumeratedValues>
                                <enumeratedValue>
                                    <name>0</name>
                                    <description>Low level</description>
                                    <value>#0</value>
                                </enumeratedValue>
                                <enumeratedValue>
                                    <name>1</name>
                                    <description>High level</description>
                                    <value>#1</value>
                                </enumeratedValue>
                            </enumeratedValues>
                        </field>
                        <field>
                            <name>PDR</name>
                            <description>Port Direction</description>
                            <lsb>2</lsb>
                            <msb>2</msb>
                            <access>read-write</access>
                            <enumeratedValues>
                                <enumeratedValue>
                                    <name>0</name>
                                    <description>Input (functions as an input pin)</description>
                                    <value>#0</value>
                                </enumeratedValue>
                                <enumeratedValue>
                                    <name>1</name>
                                    <description>Output (functions as an output pin)</description>
                                    <value>#1</value>
                                </enumeratedValue>
                            </enumeratedValues>
                        </field>
                        <field>
                            <name>PCR</name>
                            <description>Pull-up Control</description>
                            <lsb>4</lsb>
                            <msb>4</msb>
                            <access>read-write</access>
                            <enumeratedValues>
                                <enumeratedValue>
                                    <name>0</name>
                                    <description>Disable input pull-up</description>
                                    <value>#0</value>
                                </enumeratedValue>
                                <enumeratedValue>
                                    <name>1</name>
                                    <description>Enable input pull-up</description>
                                    <value>#1</value>
                                </enumeratedValue>
                            </enumeratedValues>
                        </field>
                        <field>
                            <name>NCODR</name>
                            <description>N-Channel Open-Drain Control</description>
                            <lsb>6</lsb>
                            <msb>6</msb>
                            <access>read-write</access>
                            <enumeratedValues>
                                <enumeratedValue>
                                    <name>0</name>
                                    <description>CMOS output</description>
                                    <value>#0</value>
                                </enumeratedValue>
                                <enumeratedValue>
                                    <name>1</name>
                                    <description>NMOS open-drain output</description>
                                    <value>#1</value>
                                </enumeratedValue>
                            </enumeratedValues>
                        </field>
                        <field>
                            <name>DSCR</name>
                            <description>Port Drive Capability</description>
                            <lsb>10</lsb>
                            <msb>11</msb>
                            <access>read-write</access>
                            <enumeratedValues>
                                <enumeratedValue>
                                    <name>00</name>
                                    <description>Low drive</description>
                                    <value>#00</value>
                                </enumeratedValue>
                                <enumeratedValue>
                                    <name>01</name>
                                    <description>Middle drive</description>
                                    <value>#01</value>
                                </enumeratedValue>
                                <enumeratedValue>
                                    <name>10</name>
                                    <description>High-speed high-drive</description>
                                    <value>#10</value>
                                </enumeratedValue>
                                <enumeratedValue>
                                    <name>11</name>
                                    <description>High drive</description>
                                    <value>#11</value>
                                </enumeratedValue>
                            </enumeratedValues>
                        </field>
                        <field>
                            <name>EOFR</name>
                            <description>Event on Falling/Event on Rising</description>
                            <lsb>12</lsb>
                            <msb>13</msb>
                            <access>read-write</access>
                            <enumeratedValues>
                                <enumeratedValue>
                                    <name>00</name>
                                    <description>Don't care</description>
                                    <value>#00</value>
                                </enumeratedValue>
                                <enumeratedValue>
                                    <name>01</name>
                                    <description>Detect rising edge</description>
                                    <value>#01</value>
                                </enumeratedValue>
                                <enumeratedValue>
                                    <name>10</name>
                                    <description>Detect falling edge</description>
                                    <value>#10</value>
                                </enumeratedValue>
                                <enumeratedValue>
                                    <name>11</name>
                                    <description>Detect both edges</description>
                                    <value>#11</value>
                                </enumeratedValue>
                            </enumeratedValues>
                        </field>
                        <field>
                            <name>ISEL</name>
                            <description>IRQ Input Enable</description>
                            <lsb>14</lsb>
                            <msb>14</msb>
                            <access>read-write</access>
                            <enumeratedValues>
                                <enumeratedValue>
                                    <name>0</name>
                                    <description>Not used as an IRQn input pin</description>
                                    <value>#0</value>
                                </enumeratedValue>
                                <enumeratedValue>
                                    <name>1</name>
                                    <description>Used as an IRQn input pin</description>
                                    <value>#1</value>
                                </enumeratedValue>
                            </enumeratedValues>
                        </field>
                        <field>
                            <name>ASEL</name>
                            <description>Analog Input Enable</description>
                            <lsb>15</lsb>
                            <msb>15</msb>
                            <access>read-write</access>
                            <enumeratedValues>
                                <enumeratedValue>
                                    <name>0</name>
                                    <description>Not used as an analog pin</description>
                                    <value>#0</value>
                                </enumeratedValue>
                                <enumeratedValue>
                                    <name>1</name>
                                    <description>Used as an analog pin</description>
                                    <value>#1</value>
                                </enumeratedValue>
                            </enumeratedValues>
                        </field>
                        <field>
                            <name>PMR</name>
                            <description>Port Mode Control</description>
                            <lsb>16</lsb>
                            <msb>16</msb>
                            <access>read-write</access>
                            <enumeratedValues>
                                <enumeratedValue>
                                    <name>0</name>
                                    <description>Used as a general I/O pin</description>
                                    <value>#0</value>
                                </enumeratedValue>
                                <enumeratedValue>
                                    <name>1</name>
                                    <description>Used as an I/O port for peripheral functions</description>
                                    <value>#1</value>
                                </enumeratedValue>
                            </enumeratedValues>
                        </field>
                        <field>
                            <name>PSEL</name>
                            <description>Peripheral Select</description>
                            <lsb>24</lsb>
                            <msb>28</msb>
                            <access>read-write</access>
                        </field>
                    </fields>
                </register>
                <register>
                    <dim>6</dim>
                    <dimIncrement>0x004</dimIncrement>
                    <dimIndex>10-15</dimIndex>
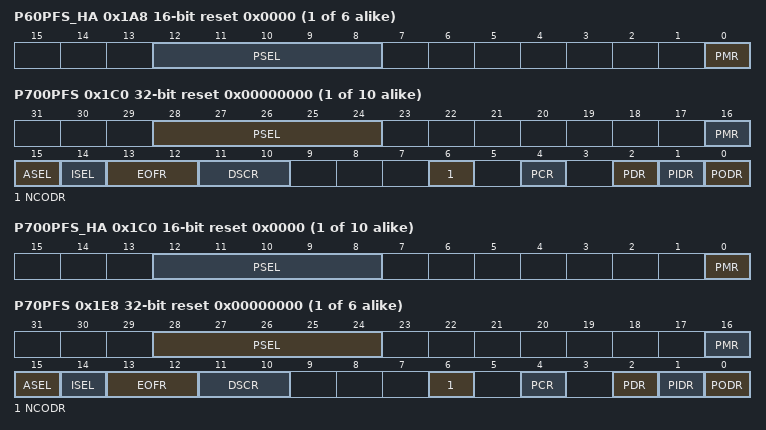
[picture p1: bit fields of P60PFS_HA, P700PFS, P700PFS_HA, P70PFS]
                    <name>P6%sPFS_HA</name>
                    <description>Port 6%s Pin Function Select Register</description>
                    <alternateRegister>P6%sPFS</alternateRegister>
                    <addressOffset>0x1A8</addressOffset>
                    <size>16</size>
                    <access>read-write</access>
                    <resetValue>0x0000</resetValue>
                    <resetMask>0xffff</resetMask>
                    <fields>
                        <field>
                            <name>PMR</name>
                            <description>Port Mode Control</description>
                            <lsb>0</lsb>
                            <msb>0</msb>
                            <access>read-write</access>
                            <enumeratedValues>
                                <enumeratedValue>
                                    <name>0</name>
                                    <description>Used as a general I/O pin</description>
                                    <value>#0</value>
                                </enumeratedValue>
                                <enumeratedValue>
                                    <name>1</name>
                                    <description>Used as an I/O port for peripheral functions</description>
                                    <value>#1</value>
                                </enumeratedValue>
                            </enumeratedValues>
                        </field>
                        <field>
                            <name>PSEL</name>
                            <description>Peripheral Select</description>
                            <lsb>8</lsb>
                            <msb>12</msb>
                            <access>read-write</access>
                        </field>
                    </fields>
                </register>
                <register>
                    <dim>6</dim>
                    <dimIncrement>0x004</dimIncrement>
                    <dimIndex>10-15</dimIndex>
                    <name>P6%sPFS_BY</name>
                    <description>Port 6%s Pin Function Select Register</description>
                    <alternateRegister>P6%sPFS</alternateRegister>
                    <addressOffset>0x1A8</addressOffset>
                    <size>8</size>
                    <access>read-write</access>
                    <resetValue>0x00</resetValue>
                    <resetMask>0xff</resetMask>
                    <fields>
                        <field>
                            <name>PSEL</name>
                            <description>Peripheral Select</description>
                            <lsb>0</lsb>
                            <msb>4</msb>
                            <access>read-write</access>
                        </field>
                    </fields>
                </register>
                <register>
                    <dim>10</dim>
                    <dimIncrement>0x004</dimIncrement>
                    <dimIndex>0-9</dimIndex>
                    <name>P70%sPFS</name>
                    <description>Port 70%s Pin Function Select Register</description>
                    <addressOffset>0x1C0</addressOffset>
                    <size>32</size>
                    <access>read-write</access>
                    <resetValue>0x00000000</resetValue>
                    <resetMask>0xffffffff</resetMask>
                    <fields>
                        <field>
                            <name>PODR</name>
                            <description>Port Output Data</description>
                            <lsb>0</lsb>
                            <msb>0</msb>
                            <access>read-write</access>
                            <enumeratedValues>
                                <enumeratedValue>
                                    <name>0</name>
                                    <description>Low output</description>
                                    <value>#0</value>
                                </enumeratedValue>
                                <enumeratedValue>
                                    <name>1</name>
                                    <description>High output</description>
                                    <value>#1</value>
                                </enumeratedValue>
                            </enumeratedValues>
                        </field>
                        <field>
                            <name>PIDR</name>
                            <description>Pmn State</description>
                            <lsb>1</lsb>
                            <msb>1</msb>
                            <access>read-only</access>
                            <enumeratedValues>
                                <enumeratedValue>
                                    <name>0</name>
                                    <description>Low level</description>
                                    <value>#0</value>
                                </enumeratedValue>
                                <enumeratedValue>
                                    <name>1</name>
                                    <description>High level</description>
                                    <value>#1</value>
                                </enumeratedValue>
                            </enumeratedValues>
                        </field>
                        <field>
                            <name>PDR</name>
                            <description>Port Direction</description>
                            <lsb>2</lsb>
                            <msb>2</msb>
                            <access>read-write</access>
                            <enumeratedValues>
                                <enumeratedValue>
                                    <name>0</name>
                                    <description>Input (functions as an input pin)</description>
                                    <value>#0</value>
                                </enumeratedValue>
                                <enumeratedValue>
                                    <name>1</name>
                                    <description>Output (functions as an output pin)</description>
                                    <value>#1</value>
                                </enumeratedValue>
                            </enumeratedValues>
                        </field>
                        <field>
                            <name>PCR</name>
                            <description>Pull-up Control</description>
                            <lsb>4</lsb>
                            <msb>4</msb>
                            <access>read-write</access>
                            <enumeratedValues>
                                <enumeratedValue>
                                    <name>0</name>
                                    <description>Disable input pull-up</description>
                                    <value>#0</value>
                                </enumeratedValue>
                                <enumeratedValue>
                                    <name>1</name>
                                    <description>Enable input pull-up</description>
                                    <value>#1</value>
                                </enumeratedValue>
                            </enumeratedValues>
                        </field>
                        <field>
                            <name>NCODR</name>
                            <description>N-Channel Open-Drain Control</description>
                            <lsb>6</lsb>
                            <msb>6</msb>
                            <access>read-write</access>
                            <enumeratedValues>
                                <enumeratedValue>
                                    <name>0</name>
                                    <description>CMOS output</description>
                                    <value>#0</value>
                                </enumeratedValue>
                                <enumeratedValue>
                                    <name>1</name>
                                    <description>NMOS open-drain output</description>
                                    <value>#1</value>
                                </enumeratedValue>
                            </enumeratedValues>
                        </field>
                        <field>
                            <name>DSCR</name>
                            <description>Port Drive Capability</description>
                            <lsb>10</lsb>
                            <msb>11</msb>
                            <access>read-write</access>
                            <enumeratedValues>
                                <enumeratedValue>
                                    <name>00</name>
                                    <description>Low drive</description>
                                    <value>#00</value>
                                </enumeratedValue>
                                <enumeratedValue>
                                    <name>01</name>
                                    <description>Middle drive</description>
                                    <value>#01</value>
                                </enumeratedValue>
                                <enumeratedValue>
                                    <name>10</name>
                                    <description>High-speed high-drive</description>
                                    <value>#10</value>
                                </enumeratedValue>
                                <enumeratedValue>
                                    <name>11</name>
                                    <description>High drive</description>
                                    <value>#11</value>
                                </enumeratedValue>
                            </enumeratedValues>
                        </field>
                        <field>
                            <name>EOFR</name>
                            <description>Event on Falling/Event on Rising</description>
                            <lsb>12</lsb>
                            <msb>13</msb>
                            <access>read-write</access>
                            <enumeratedValues>
                                <enumeratedValue>
                                    <name>00</name>
                                    <description>Don't care</description>
                                    <value>#00</value>
                                </enumeratedValue>
                                <enumeratedValue>
                                    <name>01</name>
                                    <description>Detect rising edge</description>
                                    <value>#01</value>
                                </enumeratedValue>
                                <enumeratedValue>
                                    <name>10</name>
                                    <description>Detect falling edge</description>
                                    <value>#10</value>
                                </enumeratedValue>
                                <enumeratedValue>
                                    <name>11</name>
                                    <description>Detect both edges</description>
                                    <value>#11</value>
                                </enumeratedValue>
                            </enumeratedValues>
                        </field>
                        <field>
                            <name>ISEL</name>
                            <description>IRQ Input Enable</description>
                            <lsb>14</lsb>
                            <msb>14</msb>
                            <access>read-write</access>
                            <enumeratedValues>
                                <enumeratedValue>
                                    <name>0</name>
                                    <description>Not used as an IRQn input pin</description>
                                    <value>#0</value>
                                </enumeratedValue>
                                <enumeratedValue>
                                    <name>1</name>
                                    <description>Used as an IRQn input pin</description>
                                    <value>#1</value>
                                </enumeratedValue>
                            </enumeratedValues>
                        </field>
                        <field>
                            <name>ASEL</name>
                            <description>Analog Input Enable</description>
                            <lsb>15</lsb>
                            <msb>15</msb>
                            <access>read-write</access>
                            <enumeratedValues>
                                <enumeratedValue>
                                    <name>0</name>
                                    <description>Not used as an analog pin</description>
                                    <value>#0</value>
                                </enumeratedValue>
                                <enumeratedValue>
                                    <name>1</name>
                                    <description>Used as an analog pin</description>
                                    <value>#1</value>
                                </enumeratedValue>
                            </enumeratedValues>
                        </field>
                        <field>
                            <name>PMR</name>
                            <description>Port Mode Control</description>
                            <lsb>16</lsb>
                            <msb>16</msb>
                            <access>read-write</access>
                            <enumeratedValues>
                                <enumeratedValue>
                                    <name>0</name>
                                    <description>Used as a general I/O pin</description>
                                    <value>#0</value>
                                </enumeratedValue>
                                <enumeratedValue>
                                    <name>1</name>
                                    <description>Used as an I/O port for peripheral functions</description>
                                    <value>#1</value>
                                </enumeratedValue>
                            </enumeratedValues>
                        </field>
                        <field>
                            <name>PSEL</name>
                            <description>Peripheral Select</description>
                            <lsb>24</lsb>
                            <msb>28</msb>
                            <access>read-write</access>
                        </field>
                    </fields>
                </register>
                <register>
                    <dim>10</dim>
                    <dimIncrement>0x004</dimIncrement>
                    <dimIndex>0-9</dimIndex>
                    <name>P70%sPFS_HA</name>
                    <description>Port 70%s Pin Function Select Register</description>
                    <alternateRegister>P70%sPFS</alternateRegister>
                    <addressOffset>0x1C0</addressOffset>
                    <size>16</size>
                    <access>read-write</access>
                    <resetValue>0x0000</resetValue>
                    <resetMask>0xffff</resetMask>
                    <fields>
                        <field>
                            <name>PMR</name>
                            <description>Port Mode Control</description>
                            <lsb>0</lsb>
                            <msb>0</msb>
                            <access>read-write</access>
                            <enumeratedValues>
                                <enumeratedValue>
                                    <name>0</name>
                                    <description>Used as a general I/O pin</description>
                                    <value>#0</value>
                                </enumeratedValue>
                                <enumeratedValue>
                                    <name>1</name>
                                    <description>Used as an I/O port for peripheral functions</description>
                                    <value>#1</value>
                                </enumeratedValue>
                            </enumeratedValues>
                        </field>
                        <field>
                            <name>PSEL</name>
                            <description>Peripheral Select</description>
                            <lsb>8</lsb>
                            <msb>12</msb>
                            <access>read-write</access>
                        </field>
                    </fields>
                </register>
                <register>
                    <dim>10</dim>
                    <dimIncrement>0x004</dimIncrement>
                    <dimIndex>0-9</dimIndex>
                    <name>P70%sPFS_BY</name>
                    <description>Port 70%s Pin Function Select Register</description>
                    <alternateRegister>P70%sPFS</alternateRegister>
                    <addressOffset>0x1C0</addressOffset>
                    <size>8</size>
                    <access>read-write</access>
                    <resetValue>0x00</resetValue>
                    <resetMask>0xff</resetMask>
                    <fields>
                        <field>
                            <name>PSEL</name>
                            <description>Peripheral Select</description>
                            <lsb>0</lsb>
                            <msb>4</msb>
                            <access>read-write</access>
                        </field>
                    </fields>
                </register>
                <register>
                    <dim>6</dim>
                    <dimIncrement>0x004</dimIncrement>
                    <dimIndex>10-15</dimIndex>
                    <name>P7%sPFS</name>
                    <description>Port 7%s Pin Function Select Register</description>
                    <addressOffset>0x1E8</addressOffset>
                    <size>32</size>
                    <access>read-write</access>
                    <resetValue>0x00000000</resetValue>
                    <resetMask>0xffffffff</resetMask>
                    <fields>
                        <field>
                            <name>PODR</name>
                            <description>Port Output Data</description>
                            <lsb>0</lsb>
                            <msb>0</msb>
                            <access>read-write</access>
                            <enumeratedValues>
                                <enumeratedValue>
                                    <name>0</name>
                                    <description>Low output</description>
                                    <value>#0</value>
                                </enumeratedValue>
                                <enumeratedValue>
                                    <name>1</name>
                                    <description>High output</description>
                                    <value>#1</value>
                                </enumeratedValue>
                            </enumeratedValues>
                        </field>
                        <field>
                            <name>PIDR</name>
                            <description>Pmn State</description>
                            <lsb>1</lsb>
                            <msb>1</msb>
                            <access>read-only</access>
                            <enumeratedValues>
                                <enumeratedValue>
                                    <name>0</name>
                                    <description>Low level</description>
                                    <value>#0</value>
                                </enumeratedValue>
                                <enumeratedValue>
                                    <name>1</name>
                                    <description>High level</description>
                                    <value>#1</value>
                                </enumeratedValue>
                            </enumeratedValues>
                        </field>
                        <field>
                            <name>PDR</name>
                            <description>Port Direction</description>
                            <lsb>2</lsb>
                            <msb>2</msb>
                            <access>read-write</access>
                            <enumeratedValues>
                                <enumeratedValue>
                                    <name>0</name>
                                    <description>Input (functions as an input pin)</description>
                                    <value>#0</value>
                                </enumeratedValue>
                                <enumeratedValue>
                                    <name>1</name>
                                    <description>Output (functions as an output pin)</description>
                                    <value>#1</value>
                                </enumeratedValue>
                            </enumeratedValues>
                        </field>
                        <field>
                            <name>PCR</name>
                            <description>Pull-up Control</description>
                            <lsb>4</lsb>
                            <msb>4</msb>
                            <access>read-write</access>
                            <enumeratedValues>
                                <enumeratedValue>
                                    <name>0</name>
                                    <description>Disable input pull-up</description>
                                    <value>#0</value>
                                </enumeratedValue>
                                <enumeratedValue>
                                    <name>1</name>
                                    <description>Enable input pull-up</description>
                                    <value>#1</value>
                                </enumeratedValue>
                            </enumeratedValues>
                        </field>
                        <field>
                            <name>NCODR</name>
                            <description>N-Channel Open-Drain Control</description>
                            <lsb>6</lsb>
                            <msb>6</msb>
                            <access>read-write</access>
                            <enumeratedValues>
                                <enumeratedValue>
                                    <name>0</name>
                                    <description>CMOS output</description>
                                    <value>#0</value>
                                </enumeratedValue>
                                <enumeratedValue>
                                    <name>1</name>
                                    <description>NMOS open-drain output</description>
                                    <value>#1</value>
                                </enumeratedValue>
                            </enumeratedValues>
                        </field>
                        <field>
                            <name>DSCR</name>
                            <description>Port Drive Capability</description>
                            <lsb>10</lsb>
                            <msb>11</msb>
                            <access>read-write</access>
                            <enumeratedValues>
                                <enumeratedValue>
                                    <name>00</name>
                                    <description>Low drive</description>
                                    <value>#00</value>
                                </enumeratedValue>
                                <enumeratedValue>
                                    <name>01</name>
                                    <description>Middle drive</description>
                                    <value>#01</value>
                                </enumeratedValue>
                                <enumeratedValue>
                                    <name>10</name>
                                    <description>High-speed high-drive</description>
                                    <value>#10</value>
                                </enumeratedValue>
                                <enumeratedValue>
                                    <name>11</name>
                                    <description>High drive</description>
                                    <value>#11</value>
                                </enumeratedValue>
                            </enumeratedValues>
                        </field>
                        <field>
                            <name>EOFR</name>
                            <description>Event on Falling/Event on Rising</description>
                            <lsb>12</lsb>
                            <msb>13</msb>
                            <access>read-write</access>
                            <enumeratedValues>
                                <enumeratedValue>
                                    <name>00</name>
                                    <description>Don't care</description>
                                    <value>#00</value>
                                </enumeratedValue>
                                <enumeratedValue>
                                    <name>01</name>
                                    <description>Detect rising edge</description>
                                    <value>#01</value>
                                </enumeratedValue>
                                <enumeratedValue>
                                    <name>10</name>
                                    <description>Detect falling edge</description>
                                    <value>#10</value>
                                </enumeratedValue>
                                <enumeratedValue>
                                    <name>11</name>
                                    <description>Detect both edges</description>
                                    <value>#11</value>
                                </enumeratedValue>
                            </enumeratedValues>
                        </field>
                        <field>
                            <name>ISEL</name>
                            <description>IRQ Input Enable</description>
                            <lsb>14</lsb>
                            <msb>14</msb>
                            <access>read-write</access>
                            <enumeratedValues>
                                <enumeratedValue>
                                    <name>0</name>
                                    <description>Not used as an IRQn input pin</description>
                                    <value>#0</value>
                                </enumeratedValue>
                                <enumeratedValue>
                                    <name>1</name>
                                    <description>Used as an IRQn input pin</description>
                                    <value>#1</value>
                                </enumeratedValue>
                            </enumeratedValues>
                        </field>
                        <field>
                            <name>ASEL</name>
                            <description>Analog Input Enable</description>
                            <lsb>15</lsb>
                            <msb>15</msb>
                            <access>read-write</access>
                            <enumeratedValues>
                                <enumeratedValue>
                                    <name>0</name>
                                    <description>Not used as an analog pin</description>
                                    <value>#0</value>
                                </enumeratedValue>
                                <enumeratedValue>
                                    <name>1</name>
                                    <description>Used as an analog pin</description>
                                    <value>#1</value>
                                </enumeratedValue>
                            </enumeratedValues>
                        </field>
                        <field>
                            <name>PMR</name>
                            <description>Port Mode Control</description>
                            <lsb>16</lsb>
                            <msb>16</msb>
                            <access>read-write</access>
                            <enumeratedValues>
                                <enumeratedValue>
                                    <name>0</name>
                                    <description>Used as a general I/O pin</description>
                                    <value>#0</value>
                                </enumeratedValue>
                                <enumeratedValue>
                                    <name>1</name>
                                    <description>Used as an I/O port for peripheral functions</description>
                                    <value>#1</value>
                                </enumeratedValue>
                            </enumeratedValues>
                        </field>
                        <field>
                            <name>PSEL</name>
                            <description>Peripheral Select</description>
                            <lsb>24</lsb>
                            <msb>28</msb>
                            <access>read-write</access>
                        </field>
                    </fields>
                </register>
                <register>
                    <dim>6</dim>
                    <dimIncrement>0x004</dimIncrement>
                    <dimIndex>10-15</dimIndex>
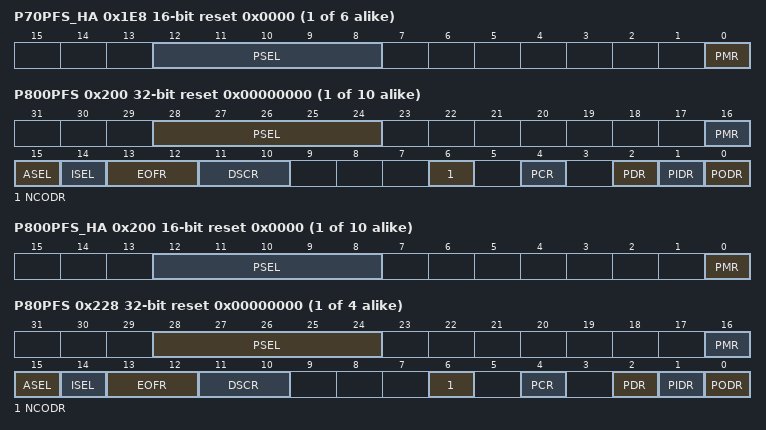
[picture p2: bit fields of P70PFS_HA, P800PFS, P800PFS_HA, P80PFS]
                    <name>P7%sPFS_HA</name>
                    <description>Port 7%s Pin Function Select Register</description>
                    <alternateRegister>P7%sPFS</alternateRegister>
                    <addressOffset>0x1E8</addressOffset>
                    <size>16</size>
                    <access>read-write</access>
                    <resetValue>0x0000</resetValue>
                    <resetMask>0xffff</resetMask>
                    <fields>
                        <field>
                            <name>PMR</name>
                            <description>Port Mode Control</description>
                            <lsb>0</lsb>
                            <msb>0</msb>
                            <access>read-write</access>
                            <enumeratedValues>
                                <enumeratedValue>
                                    <name>0</name>
                                    <description>Used as a general I/O pin</description>
                                    <value>#0</value>
                                </enumeratedValue>
                                <enumeratedValue>
                                    <name>1</name>
                                    <description>Used as an I/O port for peripheral functions</description>
                                    <value>#1</value>
                                </enumeratedValue>
                            </enumeratedValues>
                        </field>
                        <field>
                            <name>PSEL</name>
                            <description>Peripheral Select</description>
                            <lsb>8</lsb>
                            <msb>12</msb>
                            <access>read-write</access>
                        </field>
                    </fields>
                </register>
                <register>
                    <dim>6</dim>
                    <dimIncrement>0x004</dimIncrement>
                    <dimIndex>10-15</dimIndex>
                    <name>P7%sPFS_BY</name>
                    <description>Port 7%s Pin Function Select Register</description>
                    <alternateRegister>P7%sPFS</alternateRegister>
                    <addressOffset>0x1E8</addressOffset>
                    <size>8</size>
                    <access>read-write</access>
                    <resetValue>0x00</resetValue>
                    <resetMask>0xff</resetMask>
                    <fields>
                        <field>
                            <name>PSEL</name>
                            <description>Peripheral Select</description>
                            <lsb>0</lsb>
                            <msb>4</msb>
                            <access>read-write</access>
                        </field>
                    </fields>
                </register>
                <register>
                    <dim>10</dim>
                    <dimIncrement>0x004</dimIncrement>
                    <dimIndex>0-9</dimIndex>
                    <name>P80%sPFS</name>
                    <description>Port 80%s Pin Function Select Register</description>
                    <addressOffset>0x200</addressOffset>
                    <size>32</size>
                    <access>read-write</access>
                    <resetValue>0x00000000</resetValue>
                    <resetMask>0xffffffff</resetMask>
                    <fields>
                        <field>
                            <name>PODR</name>
                            <description>Port Output Data</description>
                            <lsb>0</lsb>
                            <msb>0</msb>
                            <access>read-write</access>
                            <enumeratedValues>
                                <enumeratedValue>
                                    <name>0</name>
                                    <description>Low output</description>
                                    <value>#0</value>
                                </enumeratedValue>
                                <enumeratedValue>
                                    <name>1</name>
                                    <description>High output</description>
                                    <value>#1</value>
                                </enumeratedValue>
                            </enumeratedValues>
                        </field>
                        <field>
                            <name>PIDR</name>
                            <description>Pmn State</description>
                            <lsb>1</lsb>
                            <msb>1</msb>
                            <access>read-only</access>
                            <enumeratedValues>
                                <enumeratedValue>
                                    <name>0</name>
                                    <description>Low level</description>
                                    <value>#0</value>
                                </enumeratedValue>
                                <enumeratedValue>
                                    <name>1</name>
                                    <description>High level</description>
                                    <value>#1</value>
                                </enumeratedValue>
                            </enumeratedValues>
                        </field>
                        <field>
                            <name>PDR</name>
                            <description>Port Direction</description>
                            <lsb>2</lsb>
                            <msb>2</msb>
                            <access>read-write</access>
                            <enumeratedValues>
                                <enumeratedValue>
                                    <name>0</name>
                                    <description>Input (functions as an input pin)</description>
                                    <value>#0</value>
                                </enumeratedValue>
                                <enumeratedValue>
                                    <name>1</name>
                                    <description>Output (functions as an output pin)</description>
                                    <value>#1</value>
                                </enumeratedValue>
                            </enumeratedValues>
                        </field>
                        <field>
                            <name>PCR</name>
                            <description>Pull-up Control</description>
                            <lsb>4</lsb>
                            <msb>4</msb>
                            <access>read-write</access>
                            <enumeratedValues>
                                <enumeratedValue>
                                    <name>0</name>
                                    <description>Disable input pull-up</description>
                                    <value>#0</value>
                                </enumeratedValue>
                                <enumeratedValue>
                                    <name>1</name>
                                    <description>Enable input pull-up</description>
                                    <value>#1</value>
                                </enumeratedValue>
                            </enumeratedValues>
                        </field>
                        <field>
                            <name>NCODR</name>
                            <description>N-Channel Open-Drain Control</description>
                            <lsb>6</lsb>
                            <msb>6</msb>
                            <access>read-write</access>
                            <enumeratedValues>
                                <enumeratedValue>
                                    <name>0</name>
                                    <description>CMOS output</description>
                                    <value>#0</value>
                                </enumeratedValue>
                                <enumeratedValue>
                                    <name>1</name>
                                    <description>NMOS open-drain output</description>
                                    <value>#1</value>
                                </enumeratedValue>
                            </enumeratedValues>
                        </field>
                        <field>
                            <name>DSCR</name>
                            <description>Port Drive Capability</description>
                            <lsb>10</lsb>
                            <msb>11</msb>
                            <access>read-write</access>
                            <enumeratedValues>
                                <enumeratedValue>
                                    <name>00</name>
                                    <description>Low drive</description>
                                    <value>#00</value>
                                </enumeratedValue>
                                <enumeratedValue>
                                    <name>01</name>
                                    <description>Middle drive</description>
                                    <value>#01</value>
                                </enumeratedValue>
                                <enumeratedValue>
                                    <name>10</name>
                                    <description>High-speed high-drive</description>
                                    <value>#10</value>
                                </enumeratedValue>
                                <enumeratedValue>
                                    <name>11</name>
                                    <description>High drive</description>
                                    <value>#11</value>
                                </enumeratedValue>
                            </enumeratedValues>
                        </field>
                        <field>
                            <name>EOFR</name>
                            <description>Event on Falling/Event on Rising</description>
                            <lsb>12</lsb>
                            <msb>13</msb>
                            <access>read-write</access>
                            <enumeratedValues>
                                <enumeratedValue>
                                    <name>00</name>
                                    <description>Don't care</description>
                                    <value>#00</value>
                                </enumeratedValue>
                                <enumeratedValue>
                                    <name>01</name>
                                    <description>Detect rising edge</description>
                                    <value>#01</value>
                                </enumeratedValue>
                                <enumeratedValue>
                                    <name>10</name>
                                    <description>Detect falling edge</description>
                                    <value>#10</value>
                                </enumeratedValue>
                                <enumeratedValue>
                                    <name>11</name>
                                    <description>Detect both edges</description>
                                    <value>#11</value>
                                </enumeratedValue>
                            </enumeratedValues>
                        </field>
                        <field>
                            <name>ISEL</name>
                            <description>IRQ Input Enable</description>
                            <lsb>14</lsb>
                            <msb>14</msb>
                            <access>read-write</access>
                            <enumeratedValues>
                                <enumeratedValue>
                                    <name>0</name>
                                    <description>Not used as an IRQn input pin</description>
                                    <value>#0</value>
                                </enumeratedValue>
                                <enumeratedValue>
                                    <name>1</name>
                                    <description>Used as an IRQn input pin</description>
                                    <value>#1</value>
                                </enumeratedValue>
                            </enumeratedValues>
                        </field>
                        <field>
                            <name>ASEL</name>
                            <description>Analog Input Enable</description>
                            <lsb>15</lsb>
                            <msb>15</msb>
                            <access>read-write</access>
                            <enumeratedValues>
                                <enumeratedValue>
                                    <name>0</name>
                                    <description>Not used as an analog pin</description>
                                    <value>#0</value>
                                </enumeratedValue>
                                <enumeratedValue>
                                    <name>1</name>
                                    <description>Used as an analog pin</description>
                                    <value>#1</value>
                                </enumeratedValue>
                            </enumeratedValues>
                        </field>
                        <field>
                            <name>PMR</name>
                            <description>Port Mode Control</description>
                            <lsb>16</lsb>
                            <msb>16</msb>
                            <access>read-write</access>
                            <enumeratedValues>
                                <enumeratedValue>
                                    <name>0</name>
                                    <description>Used as a general I/O pin</description>
                                    <value>#0</value>
                                </enumeratedValue>
                                <enumeratedValue>
                                    <name>1</name>
                                    <description>Used as an I/O port for peripheral functions</description>
                                    <value>#1</value>
                                </enumeratedValue>
                            </enumeratedValues>
                        </field>
                        <field>
                            <name>PSEL</name>
                            <description>Peripheral Select</description>
                            <lsb>24</lsb>
                            <msb>28</msb>
                            <access>read-write</access>
                        </field>
                    </fields>
                </register>
                <register>
                    <dim>10</dim>
                    <dimIncrement>0x004</dimIncrement>
                    <dimIndex>0-9</dimIndex>
                    <name>P80%sPFS_HA</name>
                    <description>Port 80%s Pin Function Select Register</description>
                    <alternateRegister>P80%sPFS</alternateRegister>
                    <addressOffset>0x200</addressOffset>
                    <size>16</size>
                    <access>read-write</access>
                    <resetValue>0x0000</resetValue>
                    <resetMask>0xffff</resetMask>
                    <fields>
                        <field>
                            <name>PMR</name>
                            <description>Port Mode Control</description>
                            <lsb>0</lsb>
                            <msb>0</msb>
                            <access>read-write</access>
                            <enumeratedValues>
                                <enumeratedValue>
                                    <name>0</name>
                                    <description>Used as a general I/O pin</description>
                                    <value>#0</value>
                                </enumeratedValue>
                                <enumeratedValue>
                                    <name>1</name>
                                    <description>Used as an I/O port for peripheral functions</description>
                                    <value>#1</value>
                                </enumeratedValue>
                            </enumeratedValues>
                        </field>
                        <field>
                            <name>PSEL</name>
                            <description>Peripheral Select</description>
                            <lsb>8</lsb>
                            <msb>12</msb>
                            <access>read-write</access>
                        </field>
                    </fields>
                </register>
                <register>
                    <dim>10</dim>
                    <dimIncrement>0x004</dimIncrement>
                    <dimIndex>0-9</dimIndex>
                    <name>P80%sPFS_BY</name>
                    <description>Port 80%s Pin Function Select Register</description>
                    <alternateRegister>P80%sPFS</alternateRegister>
                    <addressOffset>0x200</addressOffset>
                    <size>8</size>
                    <access>read-write</access>
                    <resetValue>0x00</resetValue>
                    <resetMask>0xff</resetMask>
                    <fields>
                        <field>
                            <name>PSEL</name>
                            <description>Peripheral Select</description>
                            <lsb>0</lsb>
                            <msb>4</msb>
                            <access>read-write</access>
                        </field>
                    </fields>
                </register>
                <register>
                    <dim>4</dim>
                    <dimIncrement>0x004</dimIncrement>
                    <dimIndex>10-13</dimIndex>
                    <name>P8%sPFS</name>
                    <description>Port 8%s Pin Function Select Register</description>
                    <addressOffset>0x228</addressOffset>
                    <size>32</size>
                    <access>read-write</access>
                    <resetValue>0x00000000</resetValue>
                    <resetMask>0xffffffff</resetMask>
                    <fields>
                        <field>
                            <name>PODR</name>
                            <description>Port Output Data</description>
                            <lsb>0</lsb>
                            <msb>0</msb>
                            <access>read-write</access>
                            <enumeratedValues>
                                <enumeratedValue>
                                    <name>0</name>
                                    <description>Low output</description>
                                    <value>#0</value>
                                </enumeratedValue>
                                <enumeratedValue>
                                    <name>1</name>
                                    <description>High output</description>
                                    <value>#1</value>
                                </enumeratedValue>
                            </enumeratedValues>
                        </field>
                        <field>
                            <name>PIDR</name>
                            <description>Pmn State</description>
                            <lsb>1</lsb>
                            <msb>1</msb>
                            <access>read-only</access>
                            <enumeratedValues>
                                <enumeratedValue>
                                    <name>0</name>
                                    <description>Low level</description>
                                    <value>#0</value>
                                </enumeratedValue>
                                <enumeratedValue>
                                    <name>1</name>
                                    <description>High level</description>
                                    <value>#1</value>
                                </enumeratedValue>
                            </enumeratedValues>
                        </field>
                        <field>
                            <name>PDR</name>
                            <description>Port Direction</description>
                            <lsb>2</lsb>
                            <msb>2</msb>
                            <access>read-write</access>
                            <enumeratedValues>
                                <enumeratedValue>
                                    <name>0</name>
                                    <description>Input (functions as an input pin)</description>
                                    <value>#0</value>
                                </enumeratedValue>
                                <enumeratedValue>
                                    <name>1</name>
                                    <description>Output (functions as an output pin)</description>
                                    <value>#1</value>
                                </enumeratedValue>
                            </enumeratedValues>
                        </field>
                        <field>
                            <name>PCR</name>
                            <description>Pull-up Control</description>
                            <lsb>4</lsb>
                            <msb>4</msb>
                            <access>read-write</access>
                            <enumeratedValues>
                                <enumeratedValue>
                                    <name>0</name>
                                    <description>Disable input pull-up</description>
                                    <value>#0</value>
                                </enumeratedValue>
                                <enumeratedValue>
                                    <name>1</name>
                                    <description>Enable input pull-up</description>
                                    <value>#1</value>
                                </enumeratedValue>
                            </enumeratedValues>
                        </field>
                        <field>
                            <name>NCODR</name>
                            <description>N-Channel Open-Drain Control</description>
                            <lsb>6</lsb>
                            <msb>6</msb>
                            <access>read-write</access>
                            <enumeratedValues>
                                <enumeratedValue>
                                    <name>0</name>
                                    <description>CMOS output</description>
                                    <value>#0</value>
                                </enumeratedValue>
                                <enumeratedValue>
                                    <name>1</name>
                                    <description>NMOS open-drain output</description>
                                    <value>#1</value>
                                </enumeratedValue>
                            </enumeratedValues>
                        </field>
                        <field>
                            <name>DSCR</name>
                            <description>Port Drive Capability</description>
                            <lsb>10</lsb>
                            <msb>11</msb>
                            <access>read-write</access>
                            <enumeratedValues>
                                <enumeratedValue>
                                    <name>00</name>
                                    <description>Low drive</description>
                                    <value>#00</value>
                                </enumeratedValue>
                                <enumeratedValue>
                                    <name>01</name>
                                    <description>Middle drive</description>
                                    <value>#01</value>
                                </enumeratedValue>
                                <enumeratedValue>
                                    <name>10</name>
                                    <description>High-speed high-drive</description>
                                    <value>#10</value>
                                </enumeratedValue>
                                <enumeratedValue>
                                    <name>11</name>
                                    <description>High drive</description>
                                    <value>#11</value>
                                </enumeratedValue>
                            </enumeratedValues>
                        </field>
                        <field>
                            <name>EOFR</name>
                            <description>Event on Falling/Event on Rising</description>
                            <lsb>12</lsb>
                            <msb>13</msb>
                            <access>read-write</access>
                            <enumeratedValues>
                                <enumeratedValue>
                                    <name>00</name>
                                    <description>Don't care</description>
                                    <value>#00</value>
                                </enumeratedValue>
                                <enumeratedValue>
                                    <name>01</name>
                                    <description>Detect rising edge</description>
                                    <value>#01</value>
                                </enumeratedValue>
                                <enumeratedValue>
                                    <name>10</name>
                                    <description>Detect falling edge</description>
                                    <value>#10</value>
                                </enumeratedValue>
                                <enumeratedValue>
                                    <name>11</name>
                                    <description>Detect both edges</description>
                                    <value>#11</value>
                                </enumeratedValue>
                            </enumeratedValues>
                        </field>
                        <field>
                            <name>ISEL</name>
                            <description>IRQ Input Enable</description>
                            <lsb>14</lsb>
                            <msb>14</msb>
                            <access>read-write</access>
                            <enumeratedValues>
                                <enumeratedValue>
                                    <name>0</name>
                                    <description>Not used as an IRQn input pin</description>
                                    <value>#0</value>
                                </enumeratedValue>
                                <enumeratedValue>
                                    <name>1</name>
                                    <description>Used as an IRQn input pin</description>
                                    <value>#1</value>
                                </enumeratedValue>
                            </enumeratedValues>
                        </field>
                        <field>
                            <name>ASEL</name>
                            <description>Analog Input Enable</description>
                            <lsb>15</lsb>
                            <msb>15</msb>
                            <access>read-write</access>
                            <enumeratedValues>
                                <enumeratedValue>
                                    <name>0</name>
                                    <description>Not used as an analog pin</description>
                                    <value>#0</value>
                                </enumeratedValue>
                                <enumeratedValue>
                                    <name>1</name>
                                    <description>Used as an analog pin</description>
                                    <value>#1</value>
                                </enumeratedValue>
                            </enumeratedValues>
                        </field>
                        <field>
                            <name>PMR</name>
                            <description>Port Mode Control</description>
                            <lsb>16</lsb>
                            <msb>16</msb>
                            <access>read-write</access>
                            <enumeratedValues>
                                <enumeratedValue>
                                    <name>0</name>
                                    <description>Used as a general I/O pin</description>
                                    <value>#0</value>
                                </enumeratedValue>
                                <enumeratedValue>
                                    <name>1</name>
                                    <description>Used as an I/O port for peripheral functions</description>
                                    <value>#1</value>
                                </enumeratedValue>
                            </enumeratedValues>
                        </field>
                        <field>
                            <name>PSEL</name>
                            <description>Peripheral Select</description>
                            <lsb>24</lsb>
                            <msb>28</msb>
                            <access>read-write</access>
                        </field>
                    </fields>
                </register>
                <register>
                    <dim>4</dim>
                    <dimIncrement>0x004</dimIncrement>
                    <dimIndex>10-13</dimIndex>
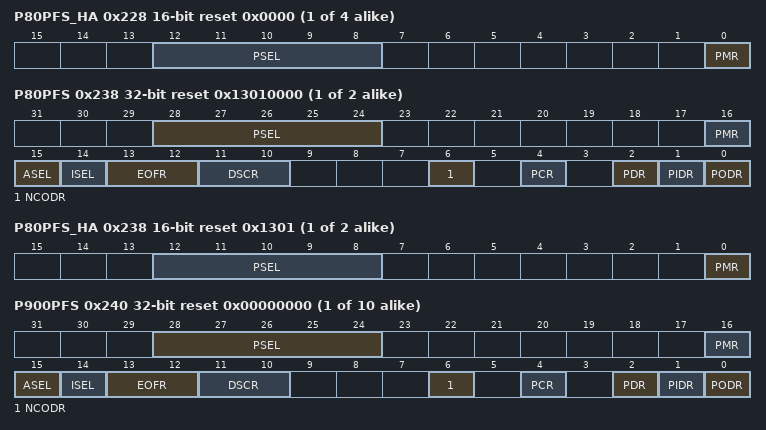
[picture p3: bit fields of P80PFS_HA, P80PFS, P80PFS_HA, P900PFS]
                    <name>P8%sPFS_HA</name>
                    <description>Port 8%s Pin Function Select Register</description>
                    <alternateRegister>P8%sPFS</alternateRegister>
                    <addressOffset>0x228</addressOffset>
                    <size>16</size>
                    <access>read-write</access>
                    <resetValue>0x0000</resetValue>
                    <resetMask>0xffff</resetMask>
                    <fields>
                        <field>
                            <name>PMR</name>
                            <description>Port Mode Control</description>
                            <lsb>0</lsb>
                            <msb>0</msb>
                            <access>read-write</access>
                            <enumeratedValues>
                                <enumeratedValue>
                                    <name>0</name>
                                    <description>Used as a general I/O pin</description>
                                    <value>#0</value>
                                </enumeratedValue>
                                <enumeratedValue>
                                    <name>1</name>
                                    <description>Used as an I/O port for peripheral functions</description>
                                    <value>#1</value>
                                </enumeratedValue>
                            </enumeratedValues>
                        </field>
                        <field>
                            <name>PSEL</name>
                            <description>Peripheral Select</description>
                            <lsb>8</lsb>
                            <msb>12</msb>
                            <access>read-write</access>
                        </field>
                    </fields>
                </register>
                <register>
                    <dim>4</dim>
                    <dimIncrement>0x004</dimIncrement>
                    <dimIndex>10-13</dimIndex>
                    <name>P8%sPFS_BY</name>
                    <description>Port 8%s Pin Function Select Register</description>
                    <alternateRegister>P8%sPFS</alternateRegister>
                    <addressOffset>0x228</addressOffset>
                    <size>8</size>
                    <access>read-write</access>
                    <resetValue>0x00</resetValue>
                    <resetMask>0xff</resetMask>
                    <fields>
                        <field>
                            <name>PSEL</name>
                            <description>Peripheral Select</description>
                            <lsb>0</lsb>
                            <msb>4</msb>
                            <access>read-write</access>
                        </field>
                    </fields>
                </register>
                <register>
                    <dim>2</dim>
                    <dimIncrement>0x004</dimIncrement>
                    <dimIndex>14-15</dimIndex>
                    <name>P8%sPFS</name>
                    <description>Port 8%s Pin Function Select Register</description>
                    <addressOffset>0x238</addressOffset>
                    <size>32</size>
                    <access>read-write</access>
                    <resetValue>0x13010000</resetValue>
                    <resetMask>0xffffffff</resetMask>
                    <fields>
                        <field>
                            <name>PODR</name>
                            <description>Port Output Data</description>
                            <lsb>0</lsb>
                            <msb>0</msb>
                            <access>read-write</access>
                            <enumeratedValues>
                                <enumeratedValue>
                                    <name>0</name>
                                    <description>Low output</description>
                                    <value>#0</value>
                                </enumeratedValue>
                                <enumeratedValue>
                                    <name>1</name>
                                    <description>High output</description>
                                    <value>#1</value>
                                </enumeratedValue>
                            </enumeratedValues>
                        </field>
                        <field>
                            <name>PIDR</name>
                            <description>Pmn State</description>
                            <lsb>1</lsb>
                            <msb>1</msb>
                            <access>read-only</access>
                            <enumeratedValues>
                                <enumeratedValue>
                                    <name>0</name>
                                    <description>Low level</description>
                                    <value>#0</value>
                                </enumeratedValue>
                                <enumeratedValue>
                                    <name>1</name>
                                    <description>High level</description>
                                    <value>#1</value>
                                </enumeratedValue>
                            </enumeratedValues>
                        </field>
                        <field>
                            <name>PDR</name>
                            <description>Port Direction</description>
                            <lsb>2</lsb>
                            <msb>2</msb>
                            <access>read-write</access>
                            <enumeratedValues>
                                <enumeratedValue>
                                    <name>0</name>
                                    <description>Input (functions as an input pin)</description>
                                    <value>#0</value>
                                </enumeratedValue>
                                <enumeratedValue>
                                    <name>1</name>
                                    <description>Output (functions as an output pin)</description>
                                    <value>#1</value>
                                </enumeratedValue>
                            </enumeratedValues>
                        </field>
                        <field>
                            <name>PCR</name>
                            <description>Pull-up Control</description>
                            <lsb>4</lsb>
                            <msb>4</msb>
                            <access>read-write</access>
                            <enumeratedValues>
                                <enumeratedValue>
                                    <name>0</name>
                                    <description>Disable input pull-up</description>
                                    <value>#0</value>
                                </enumeratedValue>
                                <enumeratedValue>
                                    <name>1</name>
                                    <description>Enable input pull-up</description>
                                    <value>#1</value>
                                </enumeratedValue>
                            </enumeratedValues>
                        </field>
                        <field>
                            <name>NCODR</name>
                            <description>N-Channel Open-Drain Control</description>
                            <lsb>6</lsb>
                            <msb>6</msb>
                            <access>read-write</access>
                            <enumeratedValues>
                                <enumeratedValue>
                                    <name>0</name>
                                    <description>CMOS output</description>
                                    <value>#0</value>
                                </enumeratedValue>
                                <enumeratedValue>
                                    <name>1</name>
                                    <description>NMOS open-drain output</description>
                                    <value>#1</value>
                                </enumeratedValue>
                            </enumeratedValues>
                        </field>
                        <field>
                            <name>DSCR</name>
                            <description>Port Drive Capability</description>
                            <lsb>10</lsb>
                            <msb>11</msb>
                            <access>read-write</access>
                            <enumeratedValues>
                                <enumeratedValue>
                                    <name>00</name>
                                    <description>Low drive</description>
                                    <value>#00</value>
                                </enumeratedValue>
                                <enumeratedValue>
                                    <name>01</name>
                                    <description>Middle drive</description>
                                    <value>#01</value>
                                </enumeratedValue>
                                <enumeratedValue>
                                    <name>10</name>
                                    <description>High-speed high-drive</description>
                                    <value>#10</value>
                                </enumeratedValue>
                                <enumeratedValue>
                                    <name>11</name>
                                    <description>High drive</description>
                                    <value>#11</value>
                                </enumeratedValue>
                            </enumeratedValues>
                        </field>
                        <field>
                            <name>EOFR</name>
                            <description>Event on Falling/Event on Rising</description>
                            <lsb>12</lsb>
                            <msb>13</msb>
                            <access>read-write</access>
                            <enumeratedValues>
                                <enumeratedValue>
                                    <name>00</name>
                                    <description>Don't care</description>
                                    <value>#00</value>
                                </enumeratedValue>
                                <enumeratedValue>
                                    <name>01</name>
                                    <description>Detect rising edge</description>
                                    <value>#01</value>
                                </enumeratedValue>
                                <enumeratedValue>
                                    <name>10</name>
                                    <description>Detect falling edge</description>
                                    <value>#10</value>
                                </enumeratedValue>
                                <enumeratedValue>
                                    <name>11</name>
                                    <description>Detect both edges</description>
                                    <value>#11</value>
                                </enumeratedValue>
                            </enumeratedValues>
                        </field>
                        <field>
                            <name>ISEL</name>
                            <description>IRQ Input Enable</description>
                            <lsb>14</lsb>
                            <msb>14</msb>
                            <access>read-write</access>
                            <enumeratedValues>
                                <enumeratedValue>
                                    <name>0</name>
                                    <description>Not used as an IRQn input pin</description>
                                    <value>#0</value>
                                </enumeratedValue>
                                <enumeratedValue>
                                    <name>1</name>
                                    <description>Used as an IRQn input pin</description>
                                    <value>#1</value>
                                </enumeratedValue>
                            </enumeratedValues>
                        </field>
                        <field>
                            <name>ASEL</name>
                            <description>Analog Input Enable</description>
                            <lsb>15</lsb>
                            <msb>15</msb>
                            <access>read-write</access>
                            <enumeratedValues>
                                <enumeratedValue>
                                    <name>0</name>
                                    <description>Not used as an analog pin</description>
                                    <value>#0</value>
                                </enumeratedValue>
                                <enumeratedValue>
                                    <name>1</name>
                                    <description>Used as an analog pin</description>
                                    <value>#1</value>
                                </enumeratedValue>
                            </enumeratedValues>
                        </field>
                        <field>
                            <name>PMR</name>
                            <description>Port Mode Control</description>
                            <lsb>16</lsb>
                            <msb>16</msb>
                            <access>read-write</access>
                            <enumeratedValues>
                                <enumeratedValue>
                                    <name>0</name>
                                    <description>Used as a general I/O pin</description>
                                    <value>#0</value>
                                </enumeratedValue>
                                <enumeratedValue>
                                    <name>1</name>
                                    <description>Used as an I/O port for peripheral functions</description>
                                    <value>#1</value>
                                </enumeratedValue>
                            </enumeratedValues>
                        </field>
                        <field>
                            <name>PSEL</name>
                            <description>Peripheral Select</description>
                            <lsb>24</lsb>
                            <msb>28</msb>
                            <access>read-write</access>
                        </field>
                    </fields>
                </register>
                <register>
                    <dim>2</dim>
                    <dimIncrement>0x004</dimIncrement>
                    <dimIndex>14-15</dimIndex>
                    <name>P8%sPFS_HA</name>
                    <description>Port 8%s Pin Function Select Register</description>
                    <alternateRegister>P8%sPFS</alternateRegister>
                    <addressOffset>0x238</addressOffset>
                    <size>16</size>
                    <access>read-write</access>
                    <resetValue>0x1301</resetValue>
                    <resetMask>0xffff</resetMask>
                    <fields>
                        <field>
                            <name>PMR</name>
                            <description>Port Mode Control</description>
                            <lsb>0</lsb>
                            <msb>0</msb>
                            <access>read-write</access>
                            <enumeratedValues>
                                <enumeratedValue>
                                    <name>0</name>
                                    <description>Used as a general I/O pin</description>
                                    <value>#0</value>
                                </enumeratedValue>
                                <enumeratedValue>
                                    <name>1</name>
                                    <description>Used as an I/O port for peripheral functions</description>
                                    <value>#1</value>
                                </enumeratedValue>
                            </enumeratedValues>
                        </field>
                        <field>
                            <name>PSEL</name>
                            <description>Peripheral Select</description>
                            <lsb>8</lsb>
                            <msb>12</msb>
                            <access>read-write</access>
                        </field>
                    </fields>
                </register>
                <register>
                    <dim>2</dim>
                    <dimIncrement>0x004</dimIncrement>
                    <dimIndex>14-15</dimIndex>
                    <name>P8%sPFS_BY</name>
                    <description>Port 8%s Pin Function Select Register</description>
                    <alternateRegister>P8%sPFS</alternateRegister>
                    <addressOffset>0x238</addressOffset>
                    <size>8</size>
                    <access>read-write</access>
                    <resetValue>0x13</resetValue>
                    <resetMask>0xff</resetMask>
                    <fields>
                        <field>
                            <name>PSEL</name>
                            <description>Peripheral Select</description>
                            <lsb>0</lsb>
                            <msb>4</msb>
                            <access>read-write</access>
                        </field>
                    </fields>
                </register>
                <register>
                    <dim>10</dim>
                    <dimIncrement>0x004</dimIncrement>
                    <dimIndex>0-9</dimIndex>
                    <name>P90%sPFS</name>
                    <description>Port 90%s Pin Function Select Register</description>
                    <addressOffset>0x240</addressOffset>
                    <size>32</size>
                    <access>read-write</access>
                    <resetValue>0x00000000</resetValue>
                    <resetMask>0xffffffff</resetMask>
                    <fields>
                        <field>
                            <name>PODR</name>
                            <description>Port Output Data</description>
                            <lsb>0</lsb>
                            <msb>0</msb>
                            <access>read-write</access>
                            <enumeratedValues>
                                <enumeratedValue>
                                    <name>0</name>
                                    <description>Low output</description>
                                    <value>#0</value>
                                </enumeratedValue>
                                <enumeratedValue>
                                    <name>1</name>
                                    <description>High output</description>
                                    <value>#1</value>
                                </enumeratedValue>
                            </enumeratedValues>
                        </field>
                        <field>
                            <name>PIDR</name>
                            <description>Pmn State</description>
                            <lsb>1</lsb>
                            <msb>1</msb>
                            <access>read-only</access>
                            <enumeratedValues>
                                <enumeratedValue>
                                    <name>0</name>
                                    <description>Low level</description>
                                    <value>#0</value>
                                </enumeratedValue>
                                <enumeratedValue>
                                    <name>1</name>
                                    <description>High level</description>
                                    <value>#1</value>
                                </enumeratedValue>
                            </enumeratedValues>
                        </field>
                        <field>
                            <name>PDR</name>
                            <description>Port Direction</description>
                            <lsb>2</lsb>
                            <msb>2</msb>
                            <access>read-write</access>
                            <enumeratedValues>
                                <enumeratedValue>
                                    <name>0</name>
                                    <description>Input (functions as an input pin)</description>
                                    <value>#0</value>
                                </enumeratedValue>
                                <enumeratedValue>
                                    <name>1</name>
                                    <description>Output (functions as an output pin)</description>
                                    <value>#1</value>
                                </enumeratedValue>
                            </enumeratedValues>
                        </field>
                        <field>
                            <name>PCR</name>
                            <description>Pull-up Control</description>
                            <lsb>4</lsb>
                            <msb>4</msb>
                            <access>read-write</access>
                            <enumeratedValues>
                                <enumeratedValue>
                                    <name>0</name>
                                    <description>Disable input pull-up</description>
                                    <value>#0</value>
                                </enumeratedValue>
                                <enumeratedValue>
                                    <name>1</name>
                                    <description>Enable input pull-up</description>
                                    <value>#1</value>
                                </enumeratedValue>
                            </enumeratedValues>
                        </field>
                        <field>
                            <name>NCODR</name>
                            <description>N-Channel Open-Drain Control</description>
                            <lsb>6</lsb>
                            <msb>6</msb>
                            <access>read-write</access>
                            <enumeratedValues>
                                <enumeratedValue>
                                    <name>0</name>
                                    <description>CMOS output</description>
                                    <value>#0</value>
                                </enumeratedValue>
                                <enumeratedValue>
                                    <name>1</name>
                                    <description>NMOS open-drain output</description>
                                    <value>#1</value>
                                </enumeratedValue>
                            </enumeratedValues>
                        </field>
                        <field>
                            <name>DSCR</name>
                            <description>Port Drive Capability</description>
                            <lsb>10</lsb>
                            <msb>11</msb>
                            <access>read-write</access>
                            <enumeratedValues>
                                <enumeratedValue>
                                    <name>00</name>
                                    <description>Low drive</description>
                                    <value>#00</value>
                                </enumeratedValue>
                                <enumeratedValue>
                                    <name>01</name>
                                    <description>Middle drive</description>
                                    <value>#01</value>
                                </enumeratedValue>
                                <enumeratedValue>
                                    <name>10</name>
                                    <description>High-speed high-drive</description>
                                    <value>#10</value>
                                </enumeratedValue>
                                <enumeratedValue>
                                    <name>11</name>
                                    <description>High drive</description>
                                    <value>#11</value>
                                </enumeratedValue>
                            </enumeratedValues>
                        </field>
                        <field>
                            <name>EOFR</name>
                            <description>Event on Falling/Event on Rising</description>
                            <lsb>12</lsb>
                            <msb>13</msb>
                            <access>read-write</access>
                            <enumeratedValues>
                                <enumeratedValue>
                                    <name>00</name>
                                    <description>Don't care</description>
                                    <value>#00</value>
                                </enumeratedValue>
                                <enumeratedValue>
                                    <name>01</name>
                                    <description>Detect rising edge</description>
                                    <value>#01</value>
                                </enumeratedValue>
                                <enumeratedValue>
                                    <name>10</name>
                                    <description>Detect falling edge</description>
                                    <value>#10</value>
                                </enumeratedValue>
                                <enumeratedValue>
                                    <name>11</name>
                                    <description>Detect both edges</description>
                                    <value>#11</value>
                                </enumeratedValue>
                            </enumeratedValues>
                        </field>
                        <field>
                            <name>ISEL</name>
                            <description>IRQ Input Enable</description>
                            <lsb>14</lsb>
                            <msb>14</msb>
                            <access>read-write</access>
                            <enumeratedValues>
                                <enumeratedValue>
                                    <name>0</name>
                                    <description>Not used as an IRQn input pin</description>
                                    <value>#0</value>
                                </enumeratedValue>
                                <enumeratedValue>
                                    <name>1</name>
                                    <description>Used as an IRQn input pin</description>
                                    <value>#1</value>
                                </enumeratedValue>
                            </enumeratedValues>
                        </field>
                        <field>
                            <name>ASEL</name>
                            <description>Analog Input Enable</description>
                            <lsb>15</lsb>
                            <msb>15</msb>
                            <access>read-write</access>
                            <enumeratedValues>
                                <enumeratedValue>
                                    <name>0</name>
                                    <description>Not used as an analog pin</description>
                                    <value>#0</value>
                                </enumeratedValue>
                                <enumeratedValue>
                                    <name>1</name>
                                    <description>Used as an analog pin</description>
                                    <value>#1</value>
                                </enumeratedValue>
                            </enumeratedValues>
                        </field>
                        <field>
                            <name>PMR</name>
                            <description>Port Mode Control</description>
                            <lsb>16</lsb>
                            <msb>16</msb>
                            <access>read-write</access>
                            <enumeratedValues>
                                <enumeratedValue>
                                    <name>0</name>
                                    <description>Used as a general I/O pin</description>
                                    <value>#0</value>
                                </enumeratedValue>
                                <enumeratedValue>
                                    <name>1</name>
                                    <description>Used as an I/O port for peripheral functions</description>
                                    <value>#1</value>
                                </enumeratedValue>
                            </enumeratedValues>
                        </field>
                        <field>
                            <name>PSEL</name>
                            <description>Peripheral Select</description>
                            <lsb>24</lsb>
                            <msb>28</msb>
                            <access>read-write</access>
                        </field>
                    </fields>
                </register>
                <register>
                    <dim>10</dim>
                    <dimIncrement>0x004</dimIncrement>
                    <dimIndex>0-9</dimIndex>
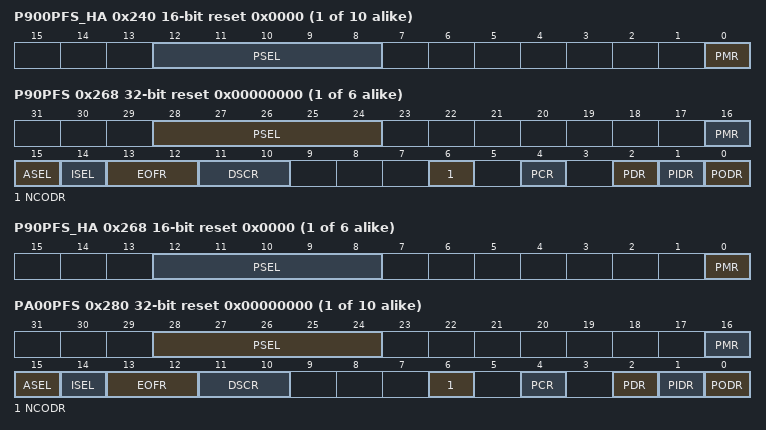
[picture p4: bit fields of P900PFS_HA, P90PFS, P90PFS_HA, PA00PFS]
                    <name>P90%sPFS_HA</name>
                    <description>Port 90%s Pin Function Select Register</description>
                    <alternateRegister>P90%sPFS</alternateRegister>
                    <addressOffset>0x240</addressOffset>
                    <size>16</size>
                    <access>read-write</access>
                    <resetValue>0x0000</resetValue>
                    <resetMask>0xffff</resetMask>
                    <fields>
                        <field>
                            <name>PMR</name>
                            <description>Port Mode Control</description>
                            <lsb>0</lsb>
                            <msb>0</msb>
                            <access>read-write</access>
                            <enumeratedValues>
                                <enumeratedValue>
                                    <name>0</name>
                                    <description>Used as a general I/O pin</description>
                                    <value>#0</value>
                                </enumeratedValue>
                                <enumeratedValue>
                                    <name>1</name>
                                    <description>Used as an I/O port for peripheral functions</description>
                                    <value>#1</value>
                                </enumeratedValue>
                            </enumeratedValues>
                        </field>
                        <field>
                            <name>PSEL</name>
                            <description>Peripheral Select</description>
                            <lsb>8</lsb>
                            <msb>12</msb>
                            <access>read-write</access>
                        </field>
                    </fields>
                </register>
                <register>
                    <dim>10</dim>
                    <dimIncrement>0x004</dimIncrement>
                    <dimIndex>0-9</dimIndex>
                    <name>P90%sPFS_BY</name>
                    <description>Port 90%s Pin Function Select Register</description>
                    <alternateRegister>P90%sPFS</alternateRegister>
                    <addressOffset>0x240</addressOffset>
                    <size>8</size>
                    <access>read-write</access>
                    <resetValue>0x00</resetValue>
                    <resetMask>0xff</resetMask>
                    <fields>
                        <field>
                            <name>PSEL</name>
                            <description>Peripheral Select</description>
                            <lsb>0</lsb>
                            <msb>4</msb>
                            <access>read-write</access>
                        </field>
                    </fields>
                </register>
                <register>
                    <dim>6</dim>
                    <dimIncrement>0x004</dimIncrement>
                    <dimIndex>10-15</dimIndex>
                    <name>P9%sPFS</name>
                    <description>Port 9%s Pin Function Select Register</description>
                    <addressOffset>0x268</addressOffset>
                    <size>32</size>
                    <access>read-write</access>
                    <resetValue>0x00000000</resetValue>
                    <resetMask>0xffffffff</resetMask>
                    <fields>
                        <field>
                            <name>PODR</name>
                            <description>Port Output Data</description>
                            <lsb>0</lsb>
                            <msb>0</msb>
                            <access>read-write</access>
                            <enumeratedValues>
                                <enumeratedValue>
                                    <name>0</name>
                                    <description>Low output</description>
                                    <value>#0</value>
                                </enumeratedValue>
                                <enumeratedValue>
                                    <name>1</name>
                                    <description>High output</description>
                                    <value>#1</value>
                                </enumeratedValue>
                            </enumeratedValues>
                        </field>
                        <field>
                            <name>PIDR</name>
                            <description>Pmn State</description>
                            <lsb>1</lsb>
                            <msb>1</msb>
                            <access>read-only</access>
                            <enumeratedValues>
                                <enumeratedValue>
                                    <name>0</name>
                                    <description>Low level</description>
                                    <value>#0</value>
                                </enumeratedValue>
                                <enumeratedValue>
                                    <name>1</name>
                                    <description>High level</description>
                                    <value>#1</value>
                                </enumeratedValue>
                            </enumeratedValues>
                        </field>
                        <field>
                            <name>PDR</name>
                            <description>Port Direction</description>
                            <lsb>2</lsb>
                            <msb>2</msb>
                            <access>read-write</access>
                            <enumeratedValues>
                                <enumeratedValue>
                                    <name>0</name>
                                    <description>Input (functions as an input pin)</description>
                                    <value>#0</value>
                                </enumeratedValue>
                                <enumeratedValue>
                                    <name>1</name>
                                    <description>Output (functions as an output pin)</description>
                                    <value>#1</value>
                                </enumeratedValue>
                            </enumeratedValues>
                        </field>
                        <field>
                            <name>PCR</name>
                            <description>Pull-up Control</description>
                            <lsb>4</lsb>
                            <msb>4</msb>
                            <access>read-write</access>
                            <enumeratedValues>
                                <enumeratedValue>
                                    <name>0</name>
                                    <description>Disable input pull-up</description>
                                    <value>#0</value>
                                </enumeratedValue>
                                <enumeratedValue>
                                    <name>1</name>
                                    <description>Enable input pull-up</description>
                                    <value>#1</value>
                                </enumeratedValue>
                            </enumeratedValues>
                        </field>
                        <field>
                            <name>NCODR</name>
                            <description>N-Channel Open-Drain Control</description>
                            <lsb>6</lsb>
                            <msb>6</msb>
                            <access>read-write</access>
                            <enumeratedValues>
                                <enumeratedValue>
                                    <name>0</name>
                                    <description>CMOS output</description>
                                    <value>#0</value>
                                </enumeratedValue>
                                <enumeratedValue>
                                    <name>1</name>
                                    <description>NMOS open-drain output</description>
                                    <value>#1</value>
                                </enumeratedValue>
                            </enumeratedValues>
                        </field>
                        <field>
                            <name>DSCR</name>
                            <description>Port Drive Capability</description>
                            <lsb>10</lsb>
                            <msb>11</msb>
                            <access>read-write</access>
                            <enumeratedValues>
                                <enumeratedValue>
                                    <name>00</name>
                                    <description>Low drive</description>
                                    <value>#00</value>
                                </enumeratedValue>
                                <enumeratedValue>
                                    <name>01</name>
                                    <description>Middle drive</description>
                                    <value>#01</value>
                                </enumeratedValue>
                                <enumeratedValue>
                                    <name>10</name>
                                    <description>High-speed high-drive</description>
                                    <value>#10</value>
                                </enumeratedValue>
                                <enumeratedValue>
                                    <name>11</name>
                                    <description>High drive</description>
                                    <value>#11</value>
                                </enumeratedValue>
                            </enumeratedValues>
                        </field>
                        <field>
                            <name>EOFR</name>
                            <description>Event on Falling/Event on Rising</description>
                            <lsb>12</lsb>
                            <msb>13</msb>
                            <access>read-write</access>
                            <enumeratedValues>
                                <enumeratedValue>
                                    <name>00</name>
                                    <description>Don't care</description>
                                    <value>#00</value>
                                </enumeratedValue>
                                <enumeratedValue>
                                    <name>01</name>
                                    <description>Detect rising edge</description>
                                    <value>#01</value>
                                </enumeratedValue>
                                <enumeratedValue>
                                    <name>10</name>
                                    <description>Detect falling edge</description>
                                    <value>#10</value>
                                </enumeratedValue>
                                <enumeratedValue>
                                    <name>11</name>
                                    <description>Detect both edges</description>
                                    <value>#11</value>
                                </enumeratedValue>
                            </enumeratedValues>
                        </field>
                        <field>
                            <name>ISEL</name>
                            <description>IRQ Input Enable</description>
                            <lsb>14</lsb>
                            <msb>14</msb>
                            <access>read-write</access>
                            <enumeratedValues>
                                <enumeratedValue>
                                    <name>0</name>
                                    <description>Not used as an IRQn input pin</description>
                                    <value>#0</value>
                                </enumeratedValue>
                                <enumeratedValue>
                                    <name>1</name>
                                    <description>Used as an IRQn input pin</description>
                                    <value>#1</value>
                                </enumeratedValue>
                            </enumeratedValues>
                        </field>
                        <field>
                            <name>ASEL</name>
                            <description>Analog Input Enable</description>
                            <lsb>15</lsb>
                            <msb>15</msb>
                            <access>read-write</access>
                            <enumeratedValues>
                                <enumeratedValue>
                                    <name>0</name>
                                    <description>Not used as an analog pin</description>
                                    <value>#0</value>
                                </enumeratedValue>
                                <enumeratedValue>
                                    <name>1</name>
                                    <description>Used as an analog pin</description>
                                    <value>#1</value>
                                </enumeratedValue>
                            </enumeratedValues>
                        </field>
                        <field>
                            <name>PMR</name>
                            <description>Port Mode Control</description>
                            <lsb>16</lsb>
                            <msb>16</msb>
                            <access>read-write</access>
                            <enumeratedValues>
                                <enumeratedValue>
                                    <name>0</name>
                                    <description>Used as a general I/O pin</description>
                                    <value>#0</value>
                                </enumeratedValue>
                                <enumeratedValue>
                                    <name>1</name>
                                    <description>Used as an I/O port for peripheral functions</description>
                                    <value>#1</value>
                                </enumeratedValue>
                            </enumeratedValues>
                        </field>
                        <field>
                            <name>PSEL</name>
                            <description>Peripheral Select</description>
                            <lsb>24</lsb>
                            <msb>28</msb>
                            <access>read-write</access>
                        </field>
                    </fields>
                </register>
                <register>
                    <dim>6</dim>
                    <dimIncrement>0x004</dimIncrement>
                    <dimIndex>10-15</dimIndex>
                    <name>P9%sPFS_HA</name>
                    <description>Port 9%s Pin Function Select Register</description>
                    <alternateRegister>P9%sPFS</alternateRegister>
                    <addressOffset>0x268</addressOffset>
                    <size>16</size>
                    <access>read-write</access>
                    <resetValue>0x0000</resetValue>
                    <resetMask>0xffff</resetMask>
                    <fields>
                        <field>
                            <name>PMR</name>
                            <description>Port Mode Control</description>
                            <lsb>0</lsb>
                            <msb>0</msb>
                            <access>read-write</access>
                            <enumeratedValues>
                                <enumeratedValue>
                                    <name>0</name>
                                    <description>Used as a general I/O pin</description>
                                    <value>#0</value>
                                </enumeratedValue>
                                <enumeratedValue>
                                    <name>1</name>
                                    <description>Used as an I/O port for peripheral functions</description>
                                    <value>#1</value>
                                </enumeratedValue>
                            </enumeratedValues>
                        </field>
                        <field>
                            <name>PSEL</name>
                            <description>Peripheral Select</description>
                            <lsb>8</lsb>
                            <msb>12</msb>
                            <access>read-write</access>
                        </field>
                    </fields>
                </register>
                <register>
                    <dim>6</dim>
                    <dimIncrement>0x004</dimIncrement>
                    <dimIndex>10-15</dimIndex>
                    <name>P9%sPFS_BY</name>
                    <description>Port 9%s Pin Function Select Register</description>
                    <alternateRegister>P9%sPFS</alternateRegister>
                    <addressOffset>0x268</addressOffset>
                    <size>8</size>
                    <access>read-write</access>
                    <resetValue>0x00</resetValue>
                    <resetMask>0xff</resetMask>
                    <fields>
                        <field>
                            <name>PSEL</name>
                            <description>Peripheral Select</description>
                            <lsb>0</lsb>
                            <msb>4</msb>
                            <access>read-write</access>
                        </field>
                    </fields>
                </register>
                <register>
                    <dim>10</dim>
                    <dimIncrement>0x004</dimIncrement>
                    <dimIndex>0-9</dimIndex>
                    <name>PA0%sPFS</name>
                    <description>Port A0%s Pin Function Select Register</description>
                    <addressOffset>0x280</addressOffset>
                    <size>32</size>
                    <access>read-write</access>
                    <resetValue>0x00000000</resetValue>
                    <resetMask>0xffffffff</resetMask>
                    <fields>
                        <field>
                            <name>PODR</name>
                            <description>Port Output Data</description>
                            <lsb>0</lsb>
                            <msb>0</msb>
                            <access>read-write</access>
                            <enumeratedValues>
                                <enumeratedValue>
                                    <name>0</name>
                                    <description>Low output</description>
                                    <value>#0</value>
                                </enumeratedValue>
                                <enumeratedValue>
                                    <name>1</name>
                                    <description>High output</description>
                                    <value>#1</value>
                                </enumeratedValue>
                            </enumeratedValues>
                        </field>
                        <field>
                            <name>PIDR</name>
                            <description>Pmn State</description>
                            <lsb>1</lsb>
                            <msb>1</msb>
                            <access>read-only</access>
                            <enumeratedValues>
                                <enumeratedValue>
                                    <name>0</name>
                                    <description>Low level</description>
                                    <value>#0</value>
                                </enumeratedValue>
                                <enumeratedValue>
                                    <name>1</name>
                                    <description>High level</description>
                                    <value>#1</value>
                                </enumeratedValue>
                            </enumeratedValues>
                        </field>
                        <field>
                            <name>PDR</name>
                            <description>Port Direction</description>
                            <lsb>2</lsb>
                            <msb>2</msb>
                            <access>read-write</access>
                            <enumeratedValues>
                                <enumeratedValue>
                                    <name>0</name>
                                    <description>Input (functions as an input pin)</description>
                                    <value>#0</value>
                                </enumeratedValue>
                                <enumeratedValue>
                                    <name>1</name>
                                    <description>Output (functions as an output pin)</description>
                                    <value>#1</value>
                                </enumeratedValue>
                            </enumeratedValues>
                        </field>
                        <field>
                            <name>PCR</name>
                            <description>Pull-up Control</description>
                            <lsb>4</lsb>
                            <msb>4</msb>
                            <access>read-write</access>
                            <enumeratedValues>
                                <enumeratedValue>
                                    <name>0</name>
                                    <description>Disable input pull-up</description>
                                    <value>#0</value>
                                </enumeratedValue>
                                <enumeratedValue>
                                    <name>1</name>
                                    <description>Enable input pull-up</description>
                                    <value>#1</value>
                                </enumeratedValue>
                            </enumeratedValues>
                        </field>
                        <field>
                            <name>NCODR</name>
                            <description>N-Channel Open-Drain Control</description>
                            <lsb>6</lsb>
                            <msb>6</msb>
                            <access>read-write</access>
                            <enumeratedValues>
                                <enumeratedValue>
                                    <name>0</name>
                                    <description>CMOS output</description>
                                    <value>#0</value>
                                </enumeratedValue>
                                <enumeratedValue>
                                    <name>1</name>
                                    <description>NMOS open-drain output</description>
                                    <value>#1</value>
                                </enumeratedValue>
                            </enumeratedValues>
                        </field>
                        <field>
                            <name>DSCR</name>
                            <description>Port Drive Capability</description>
                            <lsb>10</lsb>
                            <msb>11</msb>
                            <access>read-write</access>
                            <enumeratedValues>
                                <enumeratedValue>
                                    <name>00</name>
                                    <description>Low drive</description>
                                    <value>#00</value>
                                </enumeratedValue>
                                <enumeratedValue>
                                    <name>01</name>
                                    <description>Middle drive</description>
                                    <value>#01</value>
                                </enumeratedValue>
                                <enumeratedValue>
                                    <name>10</name>
                                    <description>High-speed high-drive</description>
                                    <value>#10</value>
                                </enumeratedValue>
                                <enumeratedValue>
                                    <name>11</name>
                                    <description>High drive</description>
                                    <value>#11</value>
                                </enumeratedValue>
                            </enumeratedValues>
                        </field>
                        <field>
                            <name>EOFR</name>
                            <description>Event on Falling/Event on Rising</description>
                            <lsb>12</lsb>
                            <msb>13</msb>
                            <access>read-write</access>
                            <enumeratedValues>
                                <enumeratedValue>
                                    <name>00</name>
                                    <description>Don't care</description>
                                    <value>#00</value>
                                </enumeratedValue>
                                <enumeratedValue>
                                    <name>01</name>
                                    <description>Detect rising edge</description>
                                    <value>#01</value>
                                </enumeratedValue>
                                <enumeratedValue>
                                    <name>10</name>
                                    <description>Detect falling edge</description>
                                    <value>#10</value>
                                </enumeratedValue>
                                <enumeratedValue>
                                    <name>11</name>
                                    <description>Detect both edges</description>
                                    <value>#11</value>
                                </enumeratedValue>
                            </enumeratedValues>
                        </field>
                        <field>
                            <name>ISEL</name>
                            <description>IRQ Input Enable</description>
                            <lsb>14</lsb>
                            <msb>14</msb>
                            <access>read-write</access>
                            <enumeratedValues>
                                <enumeratedValue>
                                    <name>0</name>
                                    <description>Not used as an IRQn input pin</description>
                                    <value>#0</value>
                                </enumeratedValue>
                                <enumeratedValue>
                                    <name>1</name>
                                    <description>Used as an IRQn input pin</description>
                                    <value>#1</value>
                                </enumeratedValue>
                            </enumeratedValues>
                        </field>
                        <field>
                            <name>ASEL</name>
                            <description>Analog Input Enable</description>
                            <lsb>15</lsb>
                            <msb>15</msb>
                            <access>read-write</access>
                            <enumeratedValues>
                                <enumeratedValue>
                                    <name>0</name>
                                    <description>Not used as an analog pin</description>
                                    <value>#0</value>
                                </enumeratedValue>
                                <enumeratedValue>
                                    <name>1</name>
                                    <description>Used as an analog pin</description>
                                    <value>#1</value>
                                </enumeratedValue>
                            </enumeratedValues>
                        </field>
                        <field>
                            <name>PMR</name>
                            <description>Port Mode Control</description>
                            <lsb>16</lsb>
                            <msb>16</msb>
                            <access>read-write</access>
                            <enumeratedValues>
                                <enumeratedValue>
                                    <name>0</name>
                                    <description>Used as a general I/O pin</description>
                                    <value>#0</value>
                                </enumeratedValue>
                                <enumeratedValue>
                                    <name>1</name>
                                    <description>Used as an I/O port for peripheral functions</description>
                                    <value>#1</value>
                                </enumeratedValue>
                            </enumeratedValues>
                        </field>
                        <field>
                            <name>PSEL</name>
                            <description>Peripheral Select</description>
                            <lsb>24</lsb>
                            <msb>28</msb>
                            <access>read-write</access>
                        </field>
                    </fields>
                </register>
                <register>
                    <dim>10</dim>
                    <dimIncrement>0x004</dimIncrement>
                    <dimIndex>0-9</dimIndex>
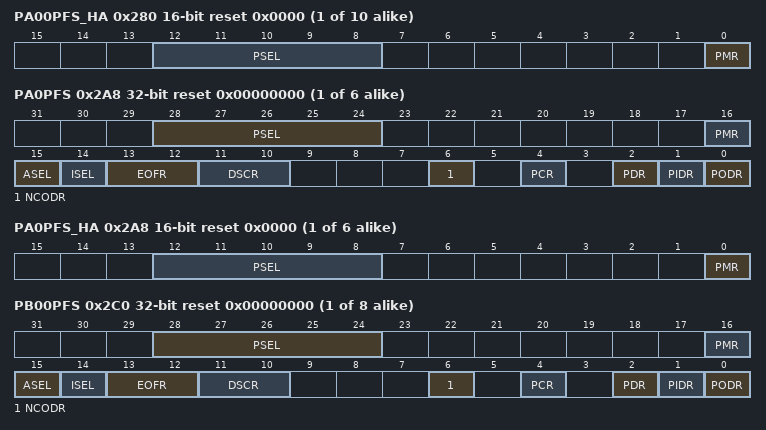
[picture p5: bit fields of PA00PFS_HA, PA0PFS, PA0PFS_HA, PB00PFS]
                    <name>PA0%sPFS_HA</name>
                    <description>Port A0%s Pin Function Select Register</description>
                    <alternateRegister>PA0%sPFS</alternateRegister>
                    <addressOffset>0x280</addressOffset>
                    <size>16</size>
                    <access>read-write</access>
                    <resetValue>0x0000</resetValue>
                    <resetMask>0xffff</resetMask>
                    <fields>
                        <field>
                            <name>PMR</name>
                            <description>Port Mode Control</description>
                            <lsb>0</lsb>
                            <msb>0</msb>
                            <access>read-write</access>
                            <enumeratedValues>
                                <enumeratedValue>
                                    <name>0</name>
                                    <description>Used as a general I/O pin</description>
                                    <value>#0</value>
                                </enumeratedValue>
                                <enumeratedValue>
                                    <name>1</name>
                                    <description>Used as an I/O port for peripheral functions</description>
                                    <value>#1</value>
                                </enumeratedValue>
                            </enumeratedValues>
                        </field>
                        <field>
                            <name>PSEL</name>
                            <description>Peripheral Select</description>
                            <lsb>8</lsb>
                            <msb>12</msb>
                            <access>read-write</access>
                        </field>
                    </fields>
                </register>
                <register>
                    <dim>10</dim>
                    <dimIncrement>0x004</dimIncrement>
                    <dimIndex>0-9</dimIndex>
                    <name>PA0%sPFS_BY</name>
                    <description>Port A0%s Pin Function Select Register</description>
                    <alternateRegister>PA0%sPFS</alternateRegister>
                    <addressOffset>0x280</addressOffset>
                    <size>8</size>
                    <access>read-write</access>
                    <resetValue>0x00</resetValue>
                    <resetMask>0xff</resetMask>
                    <fields>
                        <field>
                            <name>PSEL</name>
                            <description>Peripheral Select</description>
                            <lsb>0</lsb>
                            <msb>4</msb>
                            <access>read-write</access>
                        </field>
                    </fields>
                </register>
                <register>
                    <dim>6</dim>
                    <dimIncrement>0x004</dimIncrement>
                    <dimIndex>10-15</dimIndex>
                    <name>PA%sPFS</name>
                    <description>Port An Pin Function Select Register</description>
                    <addressOffset>0x2A8</addressOffset>
                    <size>32</size>
                    <access>read-write</access>
                    <resetValue>0x00000000</resetValue>
                    <resetMask>0xffffffff</resetMask>
                    <fields>
                        <field>
                            <name>PODR</name>
                            <description>Port Output Data</description>
                            <lsb>0</lsb>
                            <msb>0</msb>
                            <access>read-write</access>
                            <enumeratedValues>
                                <enumeratedValue>
                                    <name>0</name>
                                    <description>Low output</description>
                                    <value>#0</value>
                                </enumeratedValue>
                                <enumeratedValue>
                                    <name>1</name>
                                    <description>High output</description>
                                    <value>#1</value>
                                </enumeratedValue>
                            </enumeratedValues>
                        </field>
                        <field>
                            <name>PIDR</name>
                            <description>Pmn State</description>
                            <lsb>1</lsb>
                            <msb>1</msb>
                            <access>read-only</access>
                            <enumeratedValues>
                                <enumeratedValue>
                                    <name>0</name>
                                    <description>Low level</description>
                                    <value>#0</value>
                                </enumeratedValue>
                                <enumeratedValue>
                                    <name>1</name>
                                    <description>High level</description>
                                    <value>#1</value>
                                </enumeratedValue>
                            </enumeratedValues>
                        </field>
                        <field>
                            <name>PDR</name>
                            <description>Port Direction</description>
                            <lsb>2</lsb>
                            <msb>2</msb>
                            <access>read-write</access>
                            <enumeratedValues>
                                <enumeratedValue>
                                    <name>0</name>
                                    <description>Input (functions as an input pin)</description>
                                    <value>#0</value>
                                </enumeratedValue>
                                <enumeratedValue>
                                    <name>1</name>
                                    <description>Output (functions as an output pin)</description>
                                    <value>#1</value>
                                </enumeratedValue>
                            </enumeratedValues>
                        </field>
                        <field>
                            <name>PCR</name>
                            <description>Pull-up Control</description>
                            <lsb>4</lsb>
                            <msb>4</msb>
                            <access>read-write</access>
                            <enumeratedValues>
                                <enumeratedValue>
                                    <name>0</name>
                                    <description>Disable input pull-up</description>
                                    <value>#0</value>
                                </enumeratedValue>
                                <enumeratedValue>
                                    <name>1</name>
                                    <description>Enable input pull-up</description>
                                    <value>#1</value>
                                </enumeratedValue>
                            </enumeratedValues>
                        </field>
                        <field>
                            <name>NCODR</name>
                            <description>N-Channel Open-Drain Control</description>
                            <lsb>6</lsb>
                            <msb>6</msb>
                            <access>read-write</access>
                            <enumeratedValues>
                                <enumeratedValue>
                                    <name>0</name>
                                    <description>CMOS output</description>
                                    <value>#0</value>
                                </enumeratedValue>
                                <enumeratedValue>
                                    <name>1</name>
                                    <description>NMOS open-drain output</description>
                                    <value>#1</value>
                                </enumeratedValue>
                            </enumeratedValues>
                        </field>
                        <field>
                            <name>DSCR</name>
                            <description>Port Drive Capability</description>
                            <lsb>10</lsb>
                            <msb>11</msb>
                            <access>read-write</access>
                            <enumeratedValues>
                                <enumeratedValue>
                                    <name>00</name>
                                    <description>Low drive</description>
                                    <value>#00</value>
                                </enumeratedValue>
                                <enumeratedValue>
                                    <name>01</name>
                                    <description>Middle drive</description>
                                    <value>#01</value>
                                </enumeratedValue>
                                <enumeratedValue>
                                    <name>10</name>
                                    <description>High-speed high-drive</description>
                                    <value>#10</value>
                                </enumeratedValue>
                                <enumeratedValue>
                                    <name>11</name>
                                    <description>High drive</description>
                                    <value>#11</value>
                                </enumeratedValue>
                            </enumeratedValues>
                        </field>
                        <field>
                            <name>EOFR</name>
                            <description>Event on Falling/Event on Rising</description>
                            <lsb>12</lsb>
                            <msb>13</msb>
                            <access>read-write</access>
                            <enumeratedValues>
                                <enumeratedValue>
                                    <name>00</name>
                                    <description>Don't care</description>
                                    <value>#00</value>
                                </enumeratedValue>
                                <enumeratedValue>
                                    <name>01</name>
                                    <description>Detect rising edge</description>
                                    <value>#01</value>
                                </enumeratedValue>
                                <enumeratedValue>
                                    <name>10</name>
                                    <description>Detect falling edge</description>
                                    <value>#10</value>
                                </enumeratedValue>
                                <enumeratedValue>
                                    <name>11</name>
                                    <description>Detect both edges</description>
                                    <value>#11</value>
                                </enumeratedValue>
                            </enumeratedValues>
                        </field>
                        <field>
                            <name>ISEL</name>
                            <description>IRQ Input Enable</description>
                            <lsb>14</lsb>
                            <msb>14</msb>
                            <access>read-write</access>
                            <enumeratedValues>
                                <enumeratedValue>
                                    <name>0</name>
                                    <description>Not used as an IRQn input pin</description>
                                    <value>#0</value>
                                </enumeratedValue>
                                <enumeratedValue>
                                    <name>1</name>
                                    <description>Used as an IRQn input pin</description>
                                    <value>#1</value>
                                </enumeratedValue>
                            </enumeratedValues>
                        </field>
                        <field>
                            <name>ASEL</name>
                            <description>Analog Input Enable</description>
                            <lsb>15</lsb>
                            <msb>15</msb>
                            <access>read-write</access>
                            <enumeratedValues>
                                <enumeratedValue>
                                    <name>0</name>
                                    <description>Not used as an analog pin</description>
                                    <value>#0</value>
                                </enumeratedValue>
                                <enumeratedValue>
                                    <name>1</name>
                                    <description>Used as an analog pin</description>
                                    <value>#1</value>
                                </enumeratedValue>
                            </enumeratedValues>
                        </field>
                        <field>
                            <name>PMR</name>
                            <description>Port Mode Control</description>
                            <lsb>16</lsb>
                            <msb>16</msb>
                            <access>read-write</access>
                            <enumeratedValues>
                                <enumeratedValue>
                                    <name>0</name>
                                    <description>Used as a general I/O pin</description>
                                    <value>#0</value>
                                </enumeratedValue>
                                <enumeratedValue>
                                    <name>1</name>
                                    <description>Used as an I/O port for peripheral functions</description>
                                    <value>#1</value>
                                </enumeratedValue>
                            </enumeratedValues>
                        </field>
                        <field>
                            <name>PSEL</name>
                            <description>Peripheral Select</description>
                            <lsb>24</lsb>
                            <msb>28</msb>
                            <access>read-write</access>
                        </field>
                    </fields>
                </register>
                <register>
                    <dim>6</dim>
                    <dimIncrement>0x004</dimIncrement>
                    <dimIndex>10-15</dimIndex>
                    <name>PA%sPFS_HA</name>
                    <description>Port An Pin Function Select Register</description>
                    <alternateRegister>PA%sPFS</alternateRegister>
                    <addressOffset>0x2A8</addressOffset>
                    <size>16</size>
                    <access>read-write</access>
                    <resetValue>0x0000</resetValue>
                    <resetMask>0xffff</resetMask>
                    <fields>
                        <field>
                            <name>PMR</name>
                            <description>Port Mode Control</description>
                            <lsb>0</lsb>
                            <msb>0</msb>
                            <access>read-write</access>
                            <enumeratedValues>
                                <enumeratedValue>
                                    <name>0</name>
                                    <description>Used as a general I/O pin</description>
                                    <value>#0</value>
                                </enumeratedValue>
                                <enumeratedValue>
                                    <name>1</name>
                                    <description>Used as an I/O port for peripheral functions</description>
                                    <value>#1</value>
                                </enumeratedValue>
                            </enumeratedValues>
                        </field>
                        <field>
                            <name>PSEL</name>
                            <description>Peripheral Select</description>
                            <lsb>8</lsb>
                            <msb>12</msb>
                            <access>read-write</access>
                        </field>
                    </fields>
                </register>
                <register>
                    <dim>6</dim>
                    <dimIncrement>0x004</dimIncrement>
                    <dimIndex>10-15</dimIndex>
                    <name>PA%sPFS_BY</name>
                    <description>Port An Pin Function Select Register</description>
                    <alternateRegister>PA%sPFS</alternateRegister>
                    <addressOffset>0x2A8</addressOffset>
                    <size>8</size>
                    <access>read-write</access>
                    <resetValue>0x00</resetValue>
                    <resetMask>0xff</resetMask>
                    <fields>
                        <field>
                            <name>PSEL</name>
                            <description>Peripheral Select</description>
                            <lsb>0</lsb>
                            <msb>4</msb>
                            <access>read-write</access>
                        </field>
                    </fields>
                </register>
                <register>
                    <dim>8</dim>
                    <dimIncrement>0x004</dimIncrement>
                    <dimIndex>0-7</dimIndex>
                    <name>PB0%sPFS</name>
                    <description>Port B0%s Pin Function Select Register</description>
                    <addressOffset>0x2C0</addressOffset>
                    <size>32</size>
                    <access>read-write</access>
                    <resetValue>0x00000000</resetValue>
                    <resetMask>0xffffffff</resetMask>
                    <fields>
                        <field>
                            <name>PODR</name>
                            <description>Port Output Data</description>
                            <lsb>0</lsb>
                            <msb>0</msb>
                            <access>read-write</access>
                            <enumeratedValues>
                                <enumeratedValue>
                                    <name>0</name>
                                    <description>Low output</description>
                                    <value>#0</value>
                                </enumeratedValue>
                                <enumeratedValue>
                                    <name>1</name>
                                    <description>High output</description>
                                    <value>#1</value>
                                </enumeratedValue>
                            </enumeratedValues>
                        </field>
                        <field>
                            <name>PIDR</name>
                            <description>Pmn State</description>
                            <lsb>1</lsb>
                            <msb>1</msb>
                            <access>read-only</access>
                            <enumeratedValues>
                                <enumeratedValue>
                                    <name>0</name>
                                    <description>Low level</description>
                                    <value>#0</value>
                                </enumeratedValue>
                                <enumeratedValue>
                                    <name>1</name>
                                    <description>High level</description>
                                    <value>#1</value>
                                </enumeratedValue>
                            </enumeratedValues>
                        </field>
                        <field>
                            <name>PDR</name>
                            <description>Port Direction</description>
                            <lsb>2</lsb>
                            <msb>2</msb>
                            <access>read-write</access>
                            <enumeratedValues>
                                <enumeratedValue>
                                    <name>0</name>
                                    <description>Input (functions as an input pin)</description>
                                    <value>#0</value>
                                </enumeratedValue>
                                <enumeratedValue>
                                    <name>1</name>
                                    <description>Output (functions as an output pin)</description>
                                    <value>#1</value>
                                </enumeratedValue>
                            </enumeratedValues>
                        </field>
                        <field>
                            <name>PCR</name>
                            <description>Pull-up Control</description>
                            <lsb>4</lsb>
                            <msb>4</msb>
                            <access>read-write</access>
                            <enumeratedValues>
                                <enumeratedValue>
                                    <name>0</name>
                                    <description>Disable input pull-up</description>
                                    <value>#0</value>
                                </enumeratedValue>
                                <enumeratedValue>
                                    <name>1</name>
                                    <description>Enable input pull-up</description>
                                    <value>#1</value>
                                </enumeratedValue>
                            </enumeratedValues>
                        </field>
                        <field>
                            <name>NCODR</name>
                            <description>N-Channel Open-Drain Control</description>
                            <lsb>6</lsb>
                            <msb>6</msb>
                            <access>read-write</access>
                            <enumeratedValues>
                                <enumeratedValue>
                                    <name>0</name>
                                    <description>CMOS output</description>
                                    <value>#0</value>
                                </enumeratedValue>
                                <enumeratedValue>
                                    <name>1</name>
                                    <description>NMOS open-drain output</description>
                                    <value>#1</value>
                                </enumeratedValue>
                            </enumeratedValues>
                        </field>
                        <field>
                            <name>DSCR</name>
                            <description>Port Drive Capability</description>
                            <lsb>10</lsb>
                            <msb>11</msb>
                            <access>read-write</access>
                            <enumeratedValues>
                                <enumeratedValue>
                                    <name>00</name>
                                    <description>Low drive</description>
                                    <value>#00</value>
                                </enumeratedValue>
                                <enumeratedValue>
                                    <name>01</name>
                                    <description>Middle drive</description>
                                    <value>#01</value>
                                </enumeratedValue>
                                <enumeratedValue>
                                    <name>10</name>
                                    <description>High-speed high-drive</description>
                                    <value>#10</value>
                                </enumeratedValue>
                                <enumeratedValue>
                                    <name>11</name>
                                    <description>High drive</description>
                                    <value>#11</value>
                                </enumeratedValue>
                            </enumeratedValues>
                        </field>
                        <field>
                            <name>EOFR</name>
                            <description>Event on Falling/Event on Rising</description>
                            <lsb>12</lsb>
                            <msb>13</msb>
                            <access>read-write</access>
                            <enumeratedValues>
                                <enumeratedValue>
                                    <name>00</name>
                                    <description>Don't care</description>
                                    <value>#00</value>
                                </enumeratedValue>
                                <enumeratedValue>
                                    <name>01</name>
                                    <description>Detect rising edge</description>
                                    <value>#01</value>
                                </enumeratedValue>
                                <enumeratedValue>
                                    <name>10</name>
                                    <description>Detect falling edge</description>
                                    <value>#10</value>
                                </enumeratedValue>
                                <enumeratedValue>
                                    <name>11</name>
                                    <description>Detect both edges</description>
                                    <value>#11</value>
                                </enumeratedValue>
                            </enumeratedValues>
                        </field>
                        <field>
                            <name>ISEL</name>
                            <description>IRQ Input Enable</description>
                            <lsb>14</lsb>
                            <msb>14</msb>
                            <access>read-write</access>
                            <enumeratedValues>
                                <enumeratedValue>
                                    <name>0</name>
                                    <description>Not used as an IRQn input pin</description>
                                    <value>#0</value>
                                </enumeratedValue>
                                <enumeratedValue>
                                    <name>1</name>
                                    <description>Used as an IRQn input pin</description>
                                    <value>#1</value>
                                </enumeratedValue>
                            </enumeratedValues>
                        </field>
                        <field>
                            <name>ASEL</name>
                            <description>Analog Input Enable</description>
                            <lsb>15</lsb>
                            <msb>15</msb>
                            <access>read-write</access>
                            <enumeratedValues>
                                <enumeratedValue>
                                    <name>0</name>
                                    <description>Not used as an analog pin</description>
                                    <value>#0</value>
                                </enumeratedValue>
                                <enumeratedValue>
                                    <name>1</name>
                                    <description>Used as an analog pin</description>
                                    <value>#1</value>
                                </enumeratedValue>
                            </enumeratedValues>
                        </field>
                        <field>
                            <name>PMR</name>
                            <description>Port Mode Control</description>
                            <lsb>16</lsb>
                            <msb>16</msb>
                            <access>read-write</access>
                            <enumeratedValues>
                                <enumeratedValue>
                                    <name>0</name>
                                    <description>Used as a general I/O pin</description>
                                    <value>#0</value>
                                </enumeratedValue>
                                <enumeratedValue>
                                    <name>1</name>
                                    <description>Used as an I/O port for peripheral functions</description>
                                    <value>#1</value>
                                </enumeratedValue>
                            </enumeratedValues>
                        </field>
                        <field>
                            <name>PSEL</name>
                            <description>Peripheral Select</description>
                            <lsb>24</lsb>
                            <msb>28</msb>
                            <access>read-write</access>
                        </field>
                    </fields>
                </register>
                <register>
                    <dim>8</dim>
                    <dimIncrement>0x004</dimIncrement>
                    <dimIndex>0-7</dimIndex>
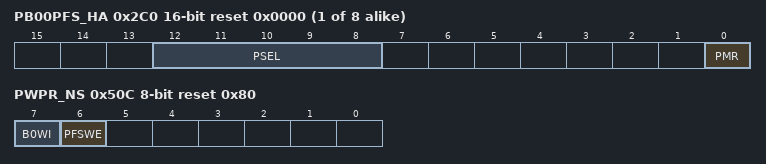
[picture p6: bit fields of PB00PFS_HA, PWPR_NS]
                    <name>PB0%sPFS_HA</name>
                    <description>Port B0%s Pin Function Select Register</description>
                    <alternateRegister>PB0%sPFS</alternateRegister>
                    <addressOffset>0x2C0</addressOffset>
                    <size>16</size>
                    <access>read-write</access>
                    <resetValue>0x0000</resetValue>
                    <resetMask>0xffff</resetMask>
                    <fields>
                        <field>
                            <name>PMR</name>
                            <description>Port Mode Control</description>
                            <lsb>0</lsb>
                            <msb>0</msb>
                            <access>read-write</access>
                            <enumeratedValues>
                                <enumeratedValue>
                                    <name>0</name>
                                    <description>Used as a general I/O pin</description>
                                    <value>#0</value>
                                </enumeratedValue>
                                <enumeratedValue>
                                    <name>1</name>
                                    <description>Used as an I/O port for peripheral functions</description>
                                    <value>#1</value>
                                </enumeratedValue>
                            </enumeratedValues>
                        </field>
                        <field>
                            <name>PSEL</name>
                            <description>Peripheral Select</description>
                            <lsb>8</lsb>
                            <msb>12</msb>
                            <access>read-write</access>
                        </field>
                    </fields>
                </register>
                <register>
                    <dim>8</dim>
                    <dimIncrement>0x004</dimIncrement>
                    <dimIndex>0-7</dimIndex>
                    <name>PB0%sPFS_BY</name>
                    <description>Port B0%s Pin Function Select Register</description>
                    <alternateRegister>PB0%sPFS</alternateRegister>
                    <addressOffset>0x2C0</addressOffset>
                    <size>8</size>
                    <access>read-write</access>
                    <resetValue>0x00</resetValue>
                    <resetMask>0xff</resetMask>
                    <fields>
                        <field>
                            <name>PSEL</name>
                            <description>Peripheral Select</description>
                            <lsb>0</lsb>
                            <msb>4</msb>
                            <access>read-write</access>
                        </field>
                    </fields>
                </register>
                <register>
                    <name>PFENET</name>
                    <description>Ethernet Control Register</description>
                    <addressOffset>0x500</addressOffset>
                    <size>8</size>
                    <access>read-write</access>
                    <resetValue>0x00</resetValue>
                    <resetMask>0xff</resetMask>
                    <fields>
                        <field>
                            <name>PHYMODE0</name>
                            <description>Ethernet Mode Setting ch0</description>
                            <lsb>4</lsb>
                            <msb>4</msb>
                            <access>read-write</access>
                            <enumeratedValues>
                                <enumeratedValue>
                                    <name>0</name>
                                    <description>RMII mode (ETHERC channel 0)</description>
                                    <value>#0</value>
                                </enumeratedValue>
                                <enumeratedValue>
                                    <name>1</name>
                                    <description>MII mode (ETHERC channel 0)</description>
                                    <value>#1</value>
                                </enumeratedValue>
                            </enumeratedValues>
                        </field>
                    </fields>
                </register>
                <register>
                    <name>PWPR_NS</name>
                    <description>Write-Protect Register for Non-secure</description>
                    <addressOffset>0x50C</addressOffset>
                    <size>8</size>
                    <access>read-write</access>
                    <resetValue>0x80</resetValue>
                    <resetMask>0xff</resetMask>
                    <fields>
                        <field>
                            <name>PFSWE</name>
                            <description>PmnPFS Register Write Enable</description>
                            <lsb>6</lsb>
                            <msb>6</msb>
                            <access>read-write</access>
                            <enumeratedValues>
                                <enumeratedValue>
                                    <name>0</name>
                                    <description>Writing to the PmnPFS register is disabled</description>
                                    <value>#0</value>
                                </enumeratedValue>
                                <enumeratedValue>
                                    <name>1</name>
                                    <description>Writing to the PmnPFS register is enabled</description>
                                    <value>#1</value>
                                </enumeratedValue>
                            </enumeratedValues>
                        </field>
                        <field>
                            <name>B0WI</name>
                            <description>PFSWE Bit Write Disable</description>
                            <lsb>7</lsb>
                            <msb>7</msb>
                            <access>read-write</access>
                            <enumeratedValues>
                                <enumeratedValue>
                                    <name>0</name>
                                    <description>Writing to the PFSWE bit is enabled</description>
                                    <value>#0</value>
                                </enumeratedValue>
                                <enumeratedValue>
                                    <name>1</name>
                                    <description>Writing to the PFSWE bit is disabled</description>
                                    <value>#1</value>
                                </enumeratedValue>
                            </enumeratedValues>
                        </field>
                    </fields>
                </register>
                <register>
                    <dim>10</dim>
                    <dimIncrement>0x004</dimIncrement>
                    <dimIndex>0-9</dimIndex>
                    <name>P%sSAR</name>
                    <description>Port Security Attribution register</description>
                    <addressOffset>0x530</addressOffset>
                    <size>16</size>
                    <access>read-write</access>
                    <resetValue>0x0000</resetValue>
                    <resetMask>0xffff</resetMask>
                    <fields>
                        <field>
                            <name>PMNSA</name>
                            <description>Pmn Security Attribution</description>
                            <lsb>0</lsb>
                            <msb>15</msb>
                            <access>read-write</access>
                            <enumeratedValues>
                                <enumeratedValue>
                                    <name>0</name>
                                    <description>Secure</description>
                                    <value>#0</value>
                                </enumeratedValue>
                                <enumeratedValue>
                                    <name>1</name>
                                    <description>Non Secure</description>
                                    <value>#1</value>
                                </enumeratedValue>
                            </enumeratedValues>
                        </field>
                    </fields>
                </register>
                <register>
                    <dim>2</dim>
                    <dimIncrement>0x004</dimIncrement>
                    <dimIndex>A-B</dimIndex>
                    <name>P%sSAR</name>
                    <description>Port Security Attribution register</description>
                    <addressOffset>0x558</addressOffset>
                    <size>16</size>
                    <access>read-write</access>
                    <resetValue>0x0000</resetValue>
                    <resetMask>0xffff</resetMask>
                    <fields>
                        <field>
                            <name>PMNSA</name>
                            <description>Pmn Security Attribution</description>
                            <lsb>0</lsb>
                            <msb>15</msb>
                            <access>read-write</access>
                            <enumeratedValues>
                                <enumeratedValue>
                                    <name>0</name>
                                    <description>Secure</description>
                                    <value>#0</value>
                                </enumeratedValue>
                                <enumeratedValue>
                                    <name>1</name>
                                    <description>Non Secure</description>
                                    <value>#1</value>
                                </enumeratedValue>
                            </enumeratedValues>
                        </field>
                    </fields>
                </register>
            </registers>
        </peripheral>
    </peripherals>
</device>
